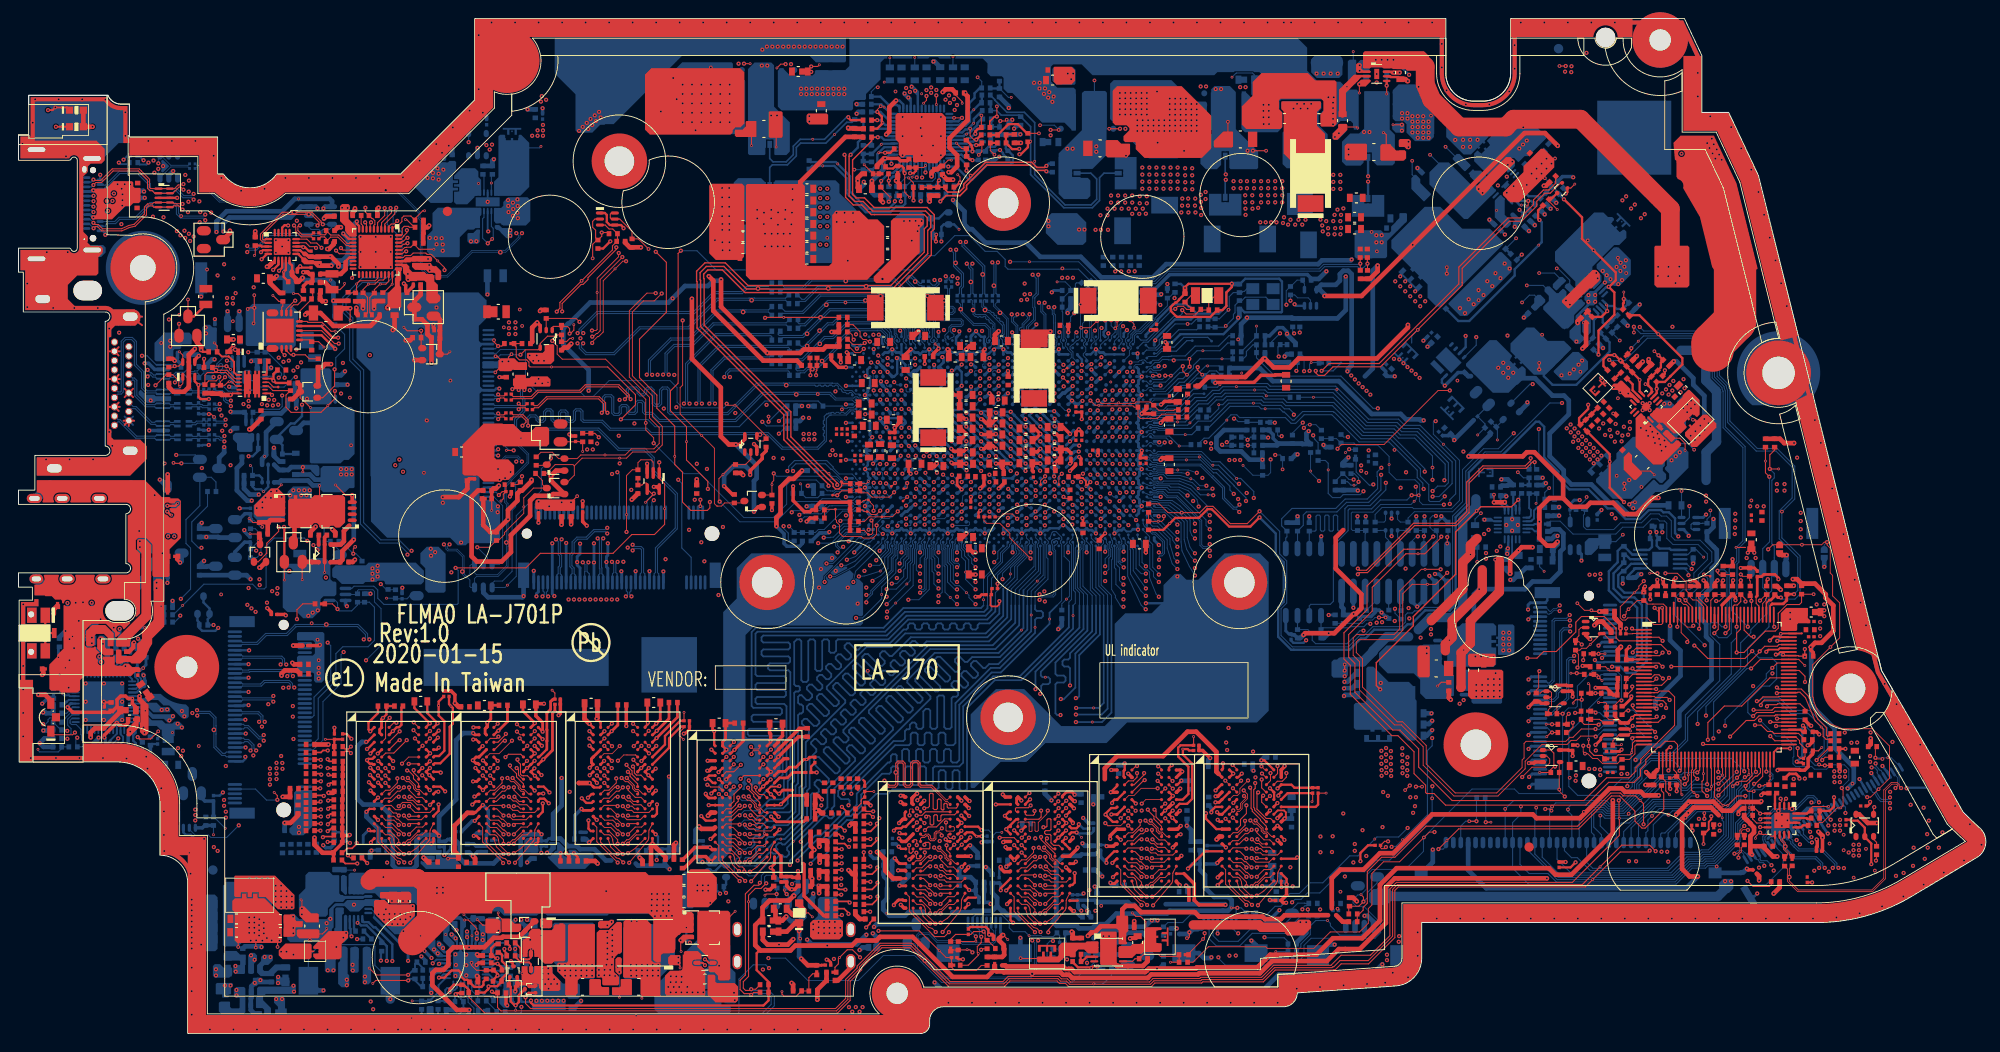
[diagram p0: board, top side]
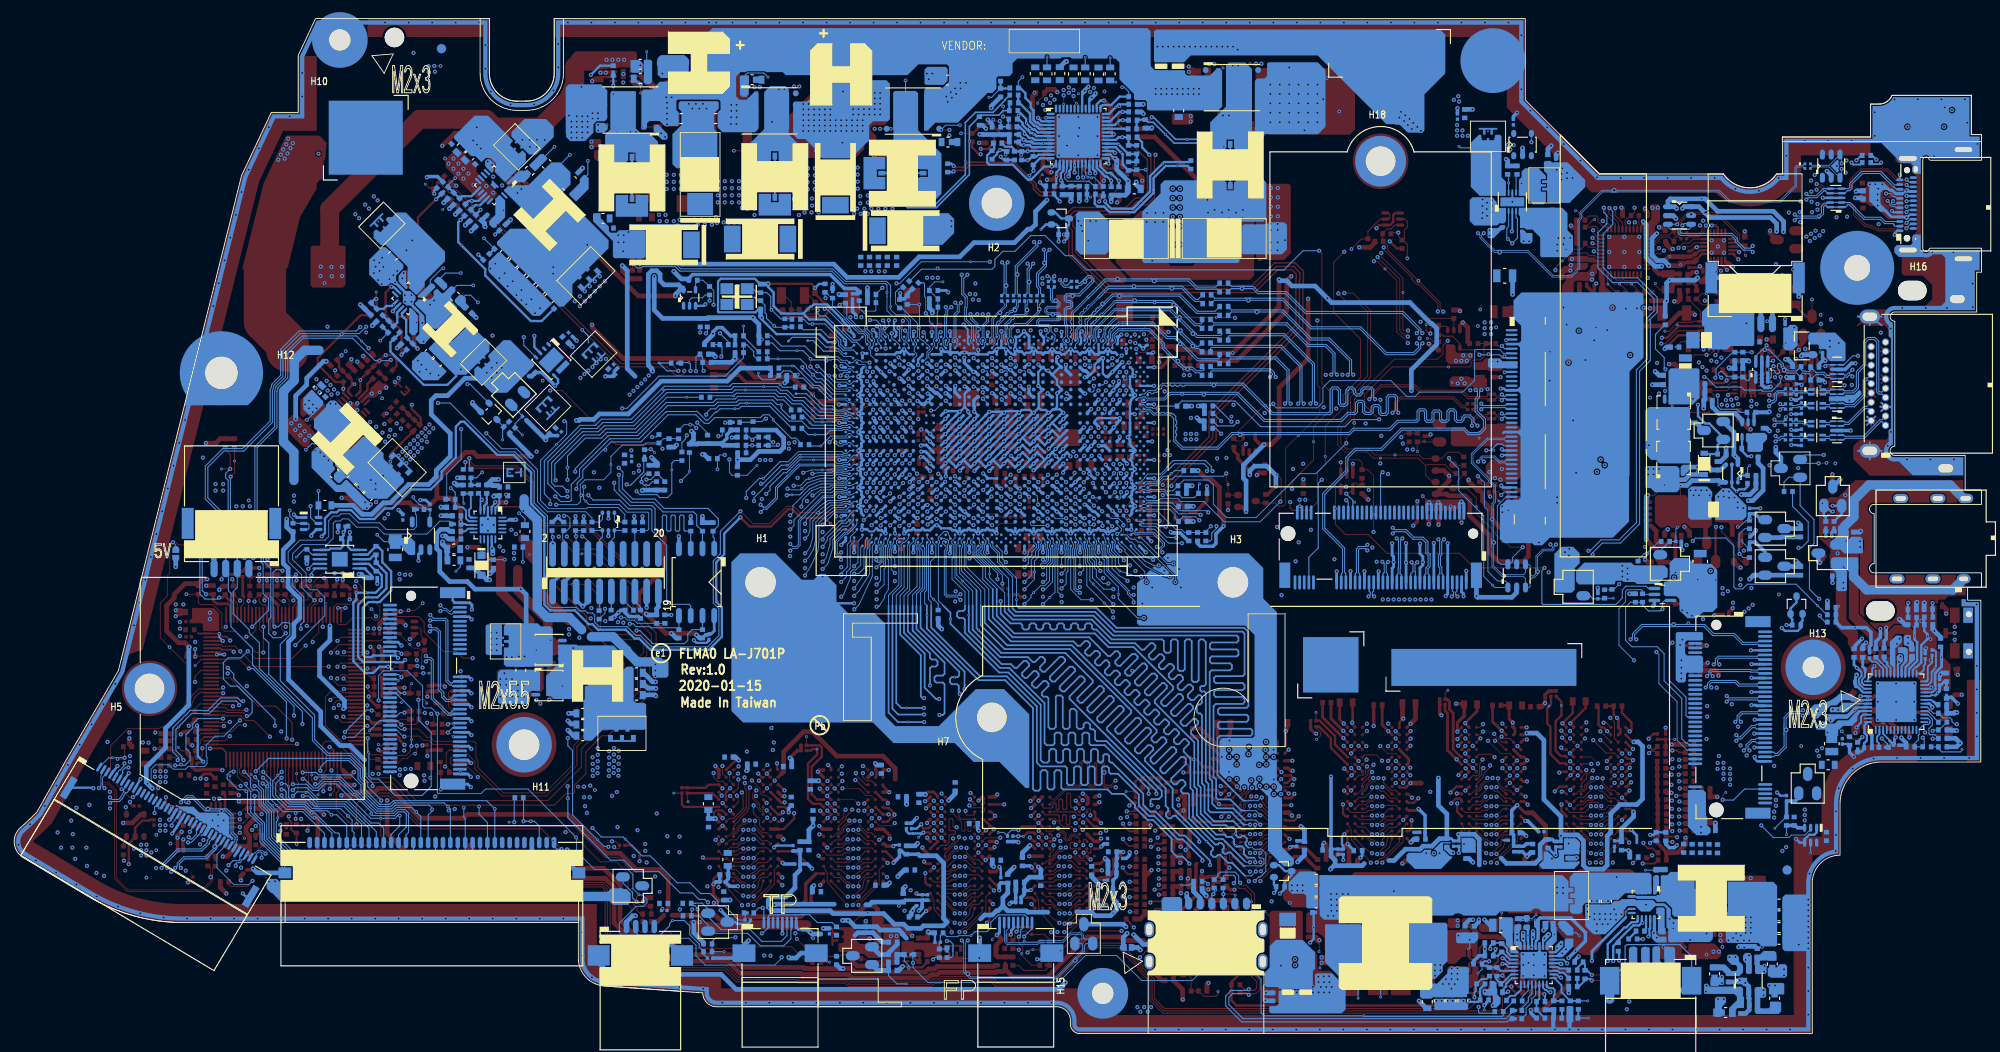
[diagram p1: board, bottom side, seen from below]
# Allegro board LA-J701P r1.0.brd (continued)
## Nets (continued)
GND: C1.2 C3.2 C4.2 C7.2 C68.2 C69.2 C70.1 C71.2 C72.2 C73.2 C74.2 C75.2 C76.2 C77.2 C78.2 C79.2 C80.2 C84.2 C204.2 C229.2 C230.2 C231.2 C232.2 C233.2 C234.2 C235.2 C236.2 C237.2 C238.2 C239.2 C240.2 C241.2 C242.2 C243.2 C249.2 C255.2 C256.2 C257.2 C258.1 C259.2 C260.2 C261.2 C265.2 C266.2 C267.1 C268.2 C269.2 C316.2 C317.1 C318.1 CA1.2 CA2.2 CA3.2 CA4.2 CA5.2 CA12.2 CA13.2 CA15.1 CA21.2 CA22.2 CA28.2 CA30.2 CA31.2 CA32.2 CA33.2 CA50.2 CA51.2 CA52.2 CC17.1 CC18.1 CC19.1 CC20.1 CC22.2 CC23.1 CC24.1 CC26.2 CC27.2 CC28.2 CC29.1 CC30.2 CC31.2 CC32.2 CC33.2 CC35.2 CC36.2 CC37.2 CC38.2 CC39.2 CC40.2 CC43.2 CC44.2 CC45.2 CC46.2 CC47.2 CC48.2 CC49.2 CC50.2 CC51.2 CC52.2 CC53.2 CC54.2 CC55.2 CC56.2 CC57.2 CC58.2 CC59.2 CC60.2 CC61.2 CC62.2 CC63.2 CC64.2 CC65.2 CC66.2 CC67.2 CC68.2 CC69.2 CC70.2 CC71.2 CC72.2 CC73.2 CC74.2 CC75.2 CC76.2 CC77.2 CC78.2 CC79.2 CC80.2 CC81.2 CC82.2 CC105.2 CC114.2 CC115.2 CC116.2 CC117.2 CC118.2 CC119.2 CD1.2 CD2.2 CD4.1 CD5.1 CD6.1 CD7.1 CD8.2 CD9.2 CD10.2 CD11.2 CD12.2 CD13.2 CD14.2 CD15.2 CD16.2 CD17.2 CD18.2 CD19.2 CD20.2 CD21.2 CD22.2 CD23.2 CD24.2 CD25.2 CD26.2 CD27.2 CD28.2 CD29.2 CD30.2 CD31.2 CD32.2 CD42.2 CD43.2 CD44.2 CD45.2 CD46.2 CD47.2 CD48.2 CD49.2 CD50.2 CD51.2 CD52.2 CD53.2 CD55.1 CD56.1 CD57.1 CD58.1 CD59.2 CD60.2 CD61.2 CD62.2 CD63.2 CD64.2 CD65.2 CD66.2 CD67.2 CD68.2 CD69.2 CD70.2 CD71.2 CD72.2 CD73.2 CD74.2 CD75.2 CD76.2 CD77.2 CD78.2 CD79.2 CD80.2 CD81.2 CD82.2 CD83.2 CD84.2 CD85.2 CD95.2 CD96.2 CD97.2 CD98.2 CD99.2 CD100.2 CD101.2 CD102.2 CD103.2 CD104.2 CD105.2 CD106.2 CD107.2 CD108.2 CD109.2 CD110.2 CD111.2 CD112.2 CD113.2 CD114.2 CF1.1 CF2.2 CF3.2 CF4.2 CF5.2 CF6.2 CF7.2 CF8.2 CF9.2 CF10.2 CF11.2 CF12.2 CF13.2 CFP1.2 CFP2.2 CFP3.2 CFP4.2 CH5.2 CH6.2 CH11.2 CH12.2 CH13.2 CH14.2 CHDT1.2 CHDT2.2 CHDT3.2 CKBL1.2 CKBL2.1 CKBL3.2 CLRP1.2 CSD1.2 CSD2.2 CSD3.2 CSD4.2 CSD5.2 CSD6.2 CSD7.2 CSD8.2 CSD10.2 CSD12.2 CT34.2 CT37.2 CT38.2 CT46.2 CT47.2 CT48.2 CT50.2 CT51.2 CT52.2 CT53.2 CT54.1 CT55.2 CT56.1 CT57.2 CT58.2 CT59.2 CT68.2 CT69.2 CT70.2 CT72.2 CT73.2 CT74.2 CT75.1 CT76.2 CT77.2 CT78.2 CTP1.2 CTP2.2 CTP3.2 CTP4.2 CTP5.2 CTP7.2 CTS5.2 CUS1.2 CUS2.2 CUS3.2 CUS4.2 CWL1.2 CWL2.2 CWL9.2 CWL61.2 D6.2 D33.1 DA2.2 DA3.1 DA4.1 DFP1.1 DH1.3 DH2.3 DH3.3 DT1.2 DT6.1 DT7.3 DT7.8 DT8.3 DT8.8 DT15.2 DT16.2 DTP1.1 H1.1(TP-1) H2.1(TP-1) H3.1(TP-1) H5.1(TP-1) H7.1(TP-1) H10.1(TP-1) H11.1(TP-1) H12.1(TP-1) H13.1(TP-1) H15.1(TP-1) H16.1(TP-1) H18.1(TP-1) JBATT1.7 JBATT1.8 JBATT1.9 JBATT1.10 JBATT1.11 JBATT1.12 JDCIN1.1 JDCIN1.2 JDCIN1.5 JDCIN1.6 JEDP1.4 JEDP1.14 JEDP1.23 JEDP1.27 JEDP1.28 JEDP1.38 JEDP1.39 JEDP1.40 JEDP1.41 JEDP1.42 JEDP1.43 JEDP1.44 JEDP1.45 JFAN2.4 JFAN2.5 JFAN2.6 JFP1.4 JFP1.9 JFP1.10 JHDMI1.2 JHDMI1.5 JHDMI1.8 JHDMI1.11 JHDMI1.17 JHDMI1.20 JHDMI1.21 JHDMI1.22 JHDMI1.23 JHDT1.3 JHDT1.5 JHDT1.7 JHDT1.17 JIO1.4 JIO1.7 JIO1.10 JIO1.28 JIO1.41 JIO1.42 JKB2.35 JKB2.36 JKBL1.1 JKBL1.5 JKBL1.6 JP1.2 JP2.2 JSPK1.5 JSPK1.6 JSSD1.1 JSSD1.3 JSSD1.9 JSSD1.15 JSSD1.21 JSSD1.27 JSSD1.33 JSSD1.39 JSSD1.45 JSSD1.51 JSSD1.57 JSSD1.63 JSSD1.65 JSSD1.67 JSSD1.68 JSSD1.69 JSSD2.1 JSSD2.3 JSSD2.9 JSSD2.15 JSSD2.21 JSSD2.27 JSSD2.33 JSSD2.39 JSSD2.45 JSSD2.51 JSSD2.57 JSSD2.63 JSSD2.65 JSSD2.67 JSSD2.68 JSSD2.69 JTP1.5 JTP1.9 JTP1.10 JUSBC2.1 JUSBC2.2 JUSBC2.3 JUSBC2.4 JUSBC2.5 JUSBC2.6 JUSBC2.A1 JUSBC2.A12 JUSBC2.B1 JUSBC2.B12 JWLAN1.1 JWLAN1.7 JWLAN1.18 JWLAN1.25 JWLAN1.31 JWLAN1.37 JWLAN1.43 JWLAN1.49 JWLAN1.55 JWLAN1.61 JWLAN1.67 JWLAN1.68 JWLAN1.69 L2.1 PC10.2 PC11.2 PC251.1 PC253.2 PC255.2 PC256.2 PC257.2 PC302.2 PC303.2 PC304.2 PC305.2 PC306.2 PC307.2 PC308.2 PC309.2 PC310.2 PC311.2 PC312.2 PC502.2 PC503.2 PC504.2 PC505.2 PC506.2 PC507.2 PC508.2 PC509.2 PC510.2 PC511.2 PC512.2 PC513.2 PC514.2 PC515.2 PC516.2 PC517.2 PC518.2 PC520.2 PC521.2 PC522.2 PC601.2 PC603.2 PC604.2 PC605.2 PC606.2 PC607.2 PC608.2 PC609.2 PC610.2 PC611.2 PC612.2 PC614.2 PC615.2 PC622.2 PC623.2 PC715.2 PC716.2 PC718.2 PC724.2 PC726.2 PC802.1 PC803.2 PC804.2 PC809.2 PC810.2 PC811.2 PC812.2 PC813.1 PC814.2 PC815.2 PC816.2 PC817.2 PC818.2 PC819.2 PC820.2 PC821.2 PC822.2 PC826.2 PC827.2 PC828.2 PC831.2 PC832.2 PC834.2 PC838.2 PC839.2 PC840.2 PC843.2 PC844.2 PC845.1 PC847.2 PC848.2 PC849.2 PC851.2 PC852.2 PC853.2 PC854.2 PC855.2 PC1807.2 PC1808.2 PC9001.2 PC9002.2 PC9003.2 PC9004.2 PC9005.2 PC9006.2 PC9007.2 PC9008.2 PC9009.2 PC9010.2 PC9011.2 PC9012.2 PC9013.2 PC9014.2 PC9015.2 PC9016.2 PC9017.2 PC9018.2 PC9019.2 PC9020.2 PC9021.2 PC9029.2 PC9030.2 PC9031.2 PC9032.2 PC9033.2 PC9034.2 PC9035.2 PC9036.2 PC9037.2 PC9038.2 PC9039.2 PC9040.2 PC9041.2 PC9042.2 PC9043.2 PC9044.2 PC9045.2 PC9046.2 PC9047.2 PC9048.2 PC9049.2 PC9050.2 PC9051.2 PC9052.2 PC9053.2 PC9056.2 PC9057.2 PC9058.2 PC9059.2 PC9060.2 PC9061.2 PC9062.2 PC9063.2 PC9064.2 PC9065.2 PC9066.2 PC9067.2 PC9068.2 PC9069.2 PC9070.2 PC9071.2 PC9081.2 PC9082.2 PC9094.2 PC9095.2 PC9096.2 PC9097.2 PC9098.2 PC9099.2 PC9100.2 PC9102.2 PC9103.2 PC9104.2 PC9105.2 PC9106.2 PC9107.2 PC9108.2 PC9109.2 PC9110.2 PC9111.2 PC9112.2 PC9115.2 PC9116.2 PC9117.2 PC9118.2 PC9119.2 PCB1.2 PCB2.2 PCB3.2 PCB4.2 PCB5.2 PCB6.2 PCB8.2 PCB9.2 PCB10.2 PCB12.2 PCB13.2 PCB14.2 PCB15.2 PCB16.2 PCB17.2 PCB18.2 PCB20.2 PCB21.2 PCB22.2 PCB24.2 PCB25.2 PCB26.2 PCB27.2 PCB28.2 PCB29.2 PCB30.2 PCB31.2 PCB32.2 PCB33.2 PCB34.2 PCB35.2 PCD1.2 PCD2.2 PCD3.2 PCD4.2 PCD6.2 PCM1.2 PCM2.2 PCM3.2 PCM4.2 PCM5.2 PCM6.2 PCM7.2 PCM8.2 PCM9.2 PCM10.1 PCM11.2 PCM12.2 PCM13.2 PCM15.2 PCM16.2 PCM17.2 PCM18.2 PCM19.2 PDM1.2 PQ801.3 PQ801.4 PQ801.5 PQ802.3 PQ802.4 PQ802.5 PQ804.3 PQ804.4 PQ804.5 PQ805.3 PQ805.4 PQ805.5 PQB1.3 PQB1.4 PQB1.5 PQB2.3 PQB2.4 PQB2.5 PQB3.3 PQB4.3 PQD3.1 PQD3.4 PQM2.1 PQM2.2 PQM2.3 PQS2.3 PR9.2 PR254.2 PR506.2 PR511.2 PR512.2 PR605.2 PR607.2 PR609.2 PR621.1 PR720.2 PR801.1 PR827.2 PR829.2 PR834.1 PR836.1 PR858.1 PR1809.2 PR1811.2 PR1816.1 PR1817.1 PRB7.2 PRB17.2 PRB20.2 PRB22.2 PRB24.2 PRB28.2 PRB33.2 PRD3.2 PRD4.2 PRD5.2 PRD7.2 PRD8.2 PRD9.2 PRM9.2 PRM14.1 PRS4.2 PRS5.2 PRS6.2 PU251.11 PU301.6 PU301.14 PU301.17 PU501.7 PU501.8 PU501.18 PU501.21 PU601.7 PU601.8 PU601.18 PU601.21 PU801.53 PU802.6 PU802.9 PU1802.6 PU1802.14 PU1802.17 PUB1.27 PUB1.33 PUM1.1 PUM1.3 PUM1.14 PUM1.21 Q146.3 Q202.1 Q202.4 QA4.1 QA4.4 QC2.1 QC2.4 QH1.4 QT1.3 QT2.3 QT4.3 R7.1 R8.2 R59.2 R68.1 R69.1 R70.1 R4006.1 RA26.1 RA28.1 RA30.2 RA31.1 RA32.1 RC6.2 RC8.2 RC9.2 RC10.2 RC16.2 RC18.2 RC30.1 RC50.1 RC53.1 RC54.1 RC65.2 RC66.2 RC70.1 RC71.1 RC72.2 RC83.1 RC115.1 RC119.2 RC120.2 RC123.2 RC561.2 RC569.1 RC601.1 RC615.2 RD31.1 RD33.2 RD34.2 RD35.1 RD36.1 RD37.1 RD38.2 RD39.2 RD40.1 RD41.1 RD47.1 RD48.1 RD49.1 RD50.1 RD51.1 RD52.2 RD53.2 RD54.2 RD55.2 RD70.1 RFP5.2 RH16.2 RHDT7.1 RHDT8.1 RHDT9.1 RKBL5.1 RSD3.2 RSD7.2 RT23.2 RT24.2 RT25.2 RT28.2 RT29.2 RT30.2 RT38.2 RT41.2 RT58.1 RT59.1 RT60.2 RT63.2 RT66.1 RT86.2 RT89.2 RT91.2 RT92.2 RTS8.2 RUS6.2 RUS7.2 RUS8.2 RWL12.1 RWL17.2 SW1.1 SW1.2 SW1.5 U2.3 U5.2 U7.14 U7.17 U9.2 U10.11 U10.15 U19.5 U20.2 UA1.49 UC1.A3 UC1.A5 UC1.A7 UC1.A10 UC1.A12 UC1.A14 UC1.A16 UC1.A19 UC1.A21 UC1.A23 UC1.A26 UC1.A30 UC1.AA5 UC1.AA13 UC1.AA15 UC1.AA17 UC1.AA19 UC1.AA23 UC1.AA26 UC1.AA28 UC1.AA32 UC1.AB2 UC1.AB4 UC1.AB14 UC1.AB16 UC1.AB18 UC1.AB20 UC1.AC5 UC1.AC8 UC1.AC11 UC1.AC13 UC1.AC15 UC1.AC17 UC1.AC19 UC1.AC22 UC1.AC25 UC1.AD1 UC1.AD5 UC1.AD14 UC1.AD16 UC1.AD18 UC1.AD20 UC1.AE5 UC1.AE11 UC1.AE13 UC1.AE15 UC1.AE17 UC1.AE19 UC1.AF1 UC1.AF3 UC1.AF5 UC1.AF14 UC1.AF16 UC1.AF18 UC1.AF20 UC1.AG5 UC1.AG8 UC1.AG11 UC1.AG13 UC1.AG15 UC1.AG17 UC1.AG19 UC1.AH14 UC1.AH16 UC1.AH18 UC1.AH20 UC1.AJ1 UC1.AJ3 UC1.AJ5 UC1.AJ13 UC1.AJ15 UC1.AJ17 UC1.AJ19 UC1.AK5 UC1.AK8 UC1.AK11 UC1.AK14 UC1.AK16 UC1.AK18 UC1.AK20 UC1.AL1 UC1.AL5 UC1.AL7 UC1.AL10 UC1.AL16 UC1.AM5 UC1.AM8 UC1.AM11 UC1.AM15 UC1.AM20 UC1.AN1 UC1.AN5 UC1.AN7 UC1.AN10 UC1.AN22 UC1.AN23 UC1.AN26 UC1.AP5 UC1.AP8 UC1.AP13 UC1.AP15 UC1.AP18 UC1.AP20 UC1.AP25 UC1.AR1 UC1.AR5 UC1.AR7 UC1.AR12 UC1.AR14 UC1.AR16 UC1.AR19 UC1.AR21 UC1.AR26 UC1.AR28 UC1.AT23 UC1.AU5 UC1.AU8 UC1.AU11 UC1.AU13 UC1.AU15 UC1.AU18 UC1.AU20 UC1.AU22 UC1.AU25 UC1.AU28 UC1.AV1 UC1.AV5 UC1.AV7 UC1.AV10 UC1.AV12 UC1.AV14 UC1.AV16 UC1.AV19 UC1.AV21 UC1.AV23 UC1.AV26 UC1.AV28 UC1.AV32 UC1.AW5 UC1.AW28 UC1.AY6 UC1.AY7 UC1.AY8 UC1.AY10 UC1.AY11 UC1.AY12 UC1.AY13 UC1.AY14 UC1.AY15 UC1.AY16 UC1.AY18 UC1.AY19 UC1.AY20 UC1.AY21 UC1.AY22 UC1.AY23 UC1.AY25 UC1.AY26 UC1.AY27 UC1.BB1 UC1.BB32 UC1.BD3 UC1.BD7 UC1.BD10 UC1.BD12 UC1.BD14 UC1.BD16 UC1.BD19 UC1.BD21 UC1.BD23 UC1.BD26 UC1.BD30 UC1.C3 UC1.C10 UC1.C32 UC1.E7 UC1.E8 UC1.E10 UC1.E11 UC1.E12 UC1.E13 UC1.E14 UC1.E15 UC1.E16 UC1.E18 UC1.E19 UC1.E20 UC1.E21 UC1.E22 UC1.E23 UC1.E25 UC1.E26 UC1.E27 UC1.F5 UC1.F19 UC1.F21 UC1.F23 UC1.F28 UC1.G1 UC1.G3 UC1.G5 UC1.G16 UC1.G26 UC1.G28 UC1.G32 UC1.H5 UC1.H13 UC1.H18 UC1.H20 UC1.H22 UC1.H25 UC1.H28 UC1.J19 UC1.K1 UC1.K3 UC1.K5 UC1.K16 UC1.K21 UC1.K26 UC1.K28 UC1.K32 UC1.L5 UC1.L13 UC1.L15 UC1.L18 UC1.L20 UC1.L25 UC1.L28 UC1.M1 UC1.M3 UC1.M5 UC1.M21 UC1.M23 UC1.M26 UC1.M28 UC1.M32 UC1.N5 UC1.N8 UC1.N11 UC1.N13 UC1.N15 UC1.N17 UC1.N22 UC1.N25 UC1.N28 UC1.P1 UC1.P5 UC1.P14 UC1.P16 UC1.P18 UC1.P20 UC1.P23 UC1.P26 UC1.P28 UC1.P32 UC1.R5 UC1.R11 UC1.R13 UC1.R15 UC1.R17 UC1.R19 UC1.R22 UC1.R25 UC1.R28 UC1.T1 UC1.T3 UC1.T5 UC1.T14 UC1.T16 UC1.T18 UC1.T20 UC1.T23 UC1.T26 UC1.T28 UC1.T32 UC1.U13 UC1.U15 UC1.U17 UC1.U19 UC1.V2 UC1.V4 UC1.V5 UC1.V8 UC1.V11 UC1.V14 UC1.V16 UC1.V18 UC1.V20 UC1.V22 UC1.V25 UC1.V28 UC1.W5 UC1.W13 UC1.W15 UC1.W17 UC1.W19 UC1.W23 UC1.W26 UC1.W28 UC1.W32 UC1.Y1 UC1.Y3 UC1.Y5 UC1.Y11 UC1.Y14 UC1.Y16 UC1.Y18 UC1.Y20 UC1.Y22 UC1.Y25 UC1.Y28 UC2.4 UC6.3 UC7.3 UC8.3 UC22.3 UC23.3 UD1.A2 UD1.A8 UD1.B2 UD1.C9 UD1.D2 UD1.D8 UD1.E1 UD1.E3 UD1.E8 UD1.F1 UD1.G8 UD1.H1 UD1.H9 UD1.K1 UD1.K9 UD1.N1 UD1.N9 UD1.T1 UD2.A2 UD2.A8 UD2.B2 UD2.C9 UD2.D2 UD2.D8 UD2.E1 UD2.E3 UD2.E8 UD2.F1 UD2.G8 UD2.H1 UD2.H9 UD2.K1 UD2.K9 UD2.N1 UD2.N9 UD2.T1 UD3.A2 UD3.A8 UD3.B2 UD3.C9 UD3.D2 UD3.D8 UD3.E1 UD3.E3 UD3.E8 UD3.F1 UD3.G8 UD3.H1 UD3.H9 UD3.K1 UD3.K9 UD3.N1 UD3.N9 UD3.T1 UD4.A2 UD4.A8 UD4.B2 UD4.C9 UD4.D2 UD4.D8 UD4.E1 UD4.E3 UD4.E8 UD4.F1 UD4.G8 UD4.H1 UD4.H9 UD4.K1 UD4.K9 UD4.N1 UD4.N9 UD4.T1 UD5.A2 UD5.A8 UD5.B2 UD5.C9 UD5.D2 UD5.D8 UD5.E1 UD5.E3 UD5.E8 UD5.F1 UD5.G8 UD5.H1 UD5.H9 UD5.K1 UD5.K9 UD5.N1 UD5.N9 UD5.T1 UD6.A2 UD6.A8 UD6.B2 UD6.C9 UD6.D2 UD6.D8 UD6.E1 UD6.E3 UD6.E8 UD6.F1 UD6.G8 UD6.H1 UD6.H9 UD6.K1 UD6.K9 UD6.N1 UD6.N9 UD6.T1 UD7.A2 UD7.A8 UD7.B2 UD7.C9 UD7.D2 UD7.D8 UD7.E1 UD7.E3 UD7.E8 UD7.F1 UD7.G8 UD7.H1 UD7.H9 UD7.K1 UD7.K9 UD7.N1 UD7.N9 UD7.T1 UD8.A2 UD8.A8 UD8.B2 UD8.C9 UD8.D2 UD8.D8 UD8.E1 UD8.E3 UD8.E8 UD8.F1 UD8.G8 UD8.H1 UD8.H9 UD8.K1 UD8.K9 UD8.N1 UD8.N9 UD8.T1 UEC1.11 UEC1.24 UEC1.35 UEC1.94 UEC1.113 UH1.2 USD1.3 USD2.3 UT1.41 UT2.8 UT2.13 UT2.18 UT2.21 UT4.1 UT4.5 UT4.14 UT6.4 UT6.6 UT6.8 UWL1.2 UWL22.3
GNDA: CA6.2 CA7.1 CA8.1 CA9.1 CA10.1 CA14.1 CA16.2 CA17.2 CA18.1 CA19.1 CA20.2 CA24.2 CA35.1 JP3.5 RA17.1 RA18.1 RA24.2 RA26.2 RA28.2 RA31.2 RA32.2 UA1.22 UA1.37
PVCC_CPU: PC815.1 PR811.1 PU801.50
VBUS_DSCHG: QT1.2 RT59.2 UT1.8 UT4.11 UT6.7
VCC_5V: PC508.1 PU501.16 PU501.17
VCC_CPU: PC814.1 PR812.1 PR835.2 PR837.2 PR859.1 PR1818.1 PR1819.1 PU801.28
VDD_DDR: PCM5.1 PRM5.1 PRM6.2 PUM1.11
VDDA: PCB16.1 PRB6.1 PRB23.1 PRB25.1 PRB27.1 PUB1.7
VDDIO_AUDIO: CC68.1 CC69.1 RC604.2 RC605.1 UC1.AP9
VDDIO_MEM_S3_SENSE_H: PRM13.2 T15.1(TP-1) UC1.J21
VDDIO_MEM_S3_SENSE_L: PRM14.2 RC595.2 T2412.1(TP-1)
VIN_CHG: PCB1.1 PCB2.1 PDB1.2 PQB1.2 PRB1.4
VIN_MUX: PCB3.1 PCB4.1 PCB5.1 PCB6.1 PDD1.1 PQD5.4 PQD12.1 PQD12.2 PQD12.3 PQS4.4 PQS12.1 PQS12.2 PQS12.3 PRB1.1
VSS_SENSE_A: RC594.1 RC595.1 UC1.J22
VSS_SENSE_B: RC597.1 UC1.AJ12
32K_X1: CC30.1 RC86.2 UC1.AY1 YC2.1
32K_X2: CC31.1 RC86.1 UC1.AY4 YC2.2
48M_X1: RC76.2 UC1.BB3
48M_X1_R: CC28.1 RC75.1 RC76.1 YC1.1
48M_X2: RC74.2 UC1.BA5
48M_X2_R: CC27.1 RC74.1 RC75.2 YC1.3
+APU_CORE: CF12.1 PC802.2 PC9001.1 PC9002.1 PC9003.1 PC9004.1 PC9005.1 PC9006.1 PC9007.1 PC9008.1 PC9009.1 PC9010.1 PC9021.1 PC9029.1 PC9030.1 PC9031.1 PC9032.1 PC9033.1 PC9034.1 PC9035.1 PC9036.1 PC9037.1 PC9038.1 PC9046.1 PC9047.1 PC9048.1 PC9049.1 PC9050.1 PC9051.1 PC9052.1 PC9056.1 PC9057.1 PC9058.1 PC9059.1 PC9060.1 PC9061.1 PC9062.1 PC9063.1 PC9081.1 PC9094.1 PC9095.1 PC9096.1 PC9097.1 PC9098.1 PC9105.1 PC9106.1 PC9107.1 PC9108.1 PC9109.1 PC9110.1 PC9111.1 PC9112.1 PC9115.1 PC9117.1 PC9118.1 PL804.4 PL805.4 PL806.4 PR802.2 UC1.AA7 UC1.AA10 UC1.AA14 UC1.AA16 UC1.AA18 UC1.AB13 UC1.AB15 UC1.AB17 UC1.AB19 UC1.AC14 UC1.AC16 UC1.AC18 UC1.AD7 UC1.AD10 UC1.AD13 UC1.AD15 UC1.AD17 UC1.AD19 UC1.AE8 UC1.AE14 UC1.AE16 UC1.AE18 UC1.AF7 UC1.AF10 UC1.AF13 UC1.AF15 UC1.AF17 UC1.AF19 UC1.AG14 UC1.AG16 UC1.AG18 UC1.AH13 UC1.AH15 UC1.AH17 UC1.AH19 UC1.AJ7 UC1.AJ10 UC1.AJ14 UC1.AJ16 UC1.AJ18 UC1.AK13 UC1.AK15 UC1.AK17 UC1.AK19 UC1.G7 UC1.G10 UC1.G12 UC1.G14 UC1.H8 UC1.H11 UC1.H15 UC1.K6 UC1.K12 UC1.K14 UC1.L8 UC1.M7 UC1.M10 UC1.N14 UC1.P7 UC1.P10 UC1.P13 UC1.P15 UC1.R8 UC1.R14 UC1.R16 UC1.T7 UC1.T10 UC1.T13 UC1.T15 UC1.T17 UC1.U14 UC1.U16 UC1.V13 UC1.V15 UC1.V17 UC1.W7 UC1.W10 UC1.W14 UC1.W16 UC1.Y8 UC1.Y13 UC1.Y15 UC1.Y17
+APU_CORE_SOC: CF11.1 PC838.1 PC9011.1 PC9012.1 PC9013.1 PC9014.1 PC9015.1 PC9016.1 PC9017.1 PC9018.1 PC9019.1 PC9020.1 PC9039.1 PC9040.1 PC9041.1 PC9042.1 PC9043.1 PC9044.1 PC9045.1 PC9053.1 PC9064.1 PC9065.1 PC9066.1 PC9067.1 PC9068.1 PC9069.1 PC9070.1 PC9071.1 PC9082.1 PC9099.1 PC9100.1 PC9116.1 PL803.4 PR833.1 UC1.N16 UC1.N18 UC1.N20 UC1.P17 UC1.P19 UC1.R18 UC1.R20 UC1.T19 UC1.U18 UC1.U20 UC1.V19 UC1.W18 UC1.W20 UC1.Y19
+CHGRTC: PD2.2 PR8.1 PR9.1
+EC_VCCA: C67.1 L1.2 PR13.1 UEC1.67
+FLT1: RT39.1 UT2.9
+IOVDD_CODEC: CA21.1 CA28.1 RA34.2 UA1.18
+LCDVDD: R2.1 U5.1
+LCDVDD_CONN: C3.1 JEDP1.8 JEDP1.9 R2.2
+LDO_3V3_5457V: CT47.1 CT48.1 CT58.1 RT22.1 RT26.2 RT39.2 RT72.2 RT73.2 RT74.2 RT85.1 UT1.33 UT2.10
+LEDVDD: C7.1 JEDP1.1 JEDP1.2 R9.2
+RTC_APU: CC105.1 CLRP1.1 RC106.2 RC107.1 UC1.AJ11
+RTCBATT: CC82.1 PD2.1 PR10.1 RC626.2
+RTCBATT_APU: CC81.1 RC107.2 RC626.1
+RTCBATT_R: JBATT1.6 PR10.2
+USBC0_VBUS: CT54.2 CT55.1 CT56.2 CT57.1 CT69.1 CT75.2 DT6.2 DT6.3 DT15.1 JUSBC2.A4 JUSBC2.A9 JUSBC2.B4 JUSBC2.B9 PFS1.1 R4021.2 RT40.1 RT69.1 UT4.8 UT6.13
AC_IN_TYPE: PRB33.1 PRB34.2 PUB1.15 UEC1.87
AC_OFF: PQD3.5 PRD8.1 UEC1.21
AC_PRESENT: UC1.BA8 UEC1.18
ACN: PCB7.2 PCB9.1 PRB3.2 PUB1.2
ACP: PCB7.1 PCB8.1 PRB2.2 PUB1.3
ADDR_CFG: RT22.2 RT23.1 UT1.26
ADP_I: PCB25.1 PRB20.1 PUB1.8 UEC1.65
ADPIN: JDCIN1.3 JDCIN1.4 PCD1.1 PFD1.1
APU_ALERT#: RC31.2 UC1.C22
APU_BT_OFF#: JWLAN1.46 UC1.AM2
APU_CORE_SEN_H: PC801.2 PC807.1 PR802.1 PR805.1 PU801.11 T14.1(TP-1) UC1.K22
APU_CORESOC_SEN_H: PC830.2 PC833.1 PR832.2 PR833.2 PU801.32 T13.1(TP-1) UC1.J23
APU_DBREQ#: CHDT2.1 JHDT1.16 RHDT5.1 UC1.AT2
APU_DP1_CTRL_CLK: CH12.1 QH2.4 RH24.2 UC1.J20
APU_DP1_CTRL_DAT: CH11.1 QH2.1 RH23.2 UC1.K20
APU_DP1_HPD: QH1.1 RH13.2 UC1.L21
APU_DP1_N0: CH10.1 UC1.H23
APU_DP1_N1: CH8.1 UC1.G22
APU_DP1_N2: CH4.1 UC1.H21
APU_DP1_N3: CH2.1 UC1.G20
APU_DP1_P0: CH9.1 UC1.G23
APU_DP1_P1: CH7.1 UC1.F22
APU_DP1_P2: CH3.1 UC1.G21
APU_DP1_P3: CH1.1 UC1.F20
APU_FCH_PWRGD_R: RC55.2 RC64.2 UC1.AW2 UC7.4
APU_FP_RST_R: RFP10.1 UC1.AW11
APU_PCIE0_RST#: RC34.2 UC1.AP6
APU_PCIE1_RST#: RC35.2 UC1.AT13
APU_PCIE_RST#: JIO1.25 RC73.2 RSD8.2 RSD9.2 RWL18.2 UC8.4 USD1.2 USD2.2 UWL22.2
APU_PCIE_RST#_R: CC20.2 RC34.1 RC35.1 RC72.1 RC73.1 UC8.1 UC8.2
APU_PCIE_WAKE#: RC48.2 UC1.AW12
APU_PWRGD: CC18.2 PU801.19 RC25.2 RC30.2 RHDT11.2 U20.3 UC1.AW4
APU_PWRGD_BUF: JHDT1.10 RHDT11.1 U20.4
APU_RST#: CC19.2 RC24.2 RC111.1 RC603.2 RHDT10.2 U20.1 UC1.AW3 UC22.4
APU_RST#_BUF: JHDT1.12 RHDT10.1 U20.6
APU_RST#_EC: RC111.2 UC22.2 UEC1.127
APU_RST#_R: RC603.1 UT1.34
APU_SPI_CLK: RC84.2 RC97.1 UC1.BC10
APU_SPI_CLK_R: RC59.1 RC65.1 RC84.1 UC2.6
APU_SPI_CS1#: RC95.1 UC1.BD11 UC2.1
APU_SPI_HOLD#: RC96.1 UC1.BC8 UC2.7
APU_SPI_MISO: RC93.1 UC1.BA10 UC2.2
APU_SPI_MOSI: RC92.1 UC1.BB8 UC2.5
APU_SPI_WP#: RC94.1 UC1.BA9 UC2.3
APU_SVC: PC854.1 PU801.20 UC1.D25
APU_SVD: PC855.1 PU801.21 UC1.C25
APU_SVT: PR815.2 PU801.22
APU_SVT_R: PC853.1 PR815.1 UC1.A25
APU_TCK: JHDT1.2 RHDT2.1 UC1.AR2
APU_TDI: CHDT1.1 JHDT1.6 RHDT4.1 UC1.AP3
APU_TDO: JHDT1.8 UC1.AU1
APU_TEST4: T1.1(TP-1) UC1.BB6
APU_TEST5: T2.1(TP-1) UC1.BD5
APU_TEST14: RC11.1 T4.1(TP-1) UC1.G25
APU_TEST15: RC12.1 T5.1(TP-1) UC1.K25
APU_TEST16: RC13.1 T6.1(TP-1) UC1.F25
APU_TEST17: RC14.1 T7.1(TP-1) UC1.F26
APU_TEST31: RC15.1 RC16.1 T8.1(TP-1) UC1.H26
APU_TEST41: T9.1(TP-1) UC1.AK9
APU_TEST470: T10.1(TP-1) UC1.AK21
APU_TEST471: T11.1(TP-1) UC1.AG21
APU_TMS: JHDT1.4 RHDT3.1 UC1.AU3
APU_TRST#: CHDT3.1 RHDT1.1 RHDT6.1 UC1.AR4
APU_TRST#_R: JHDT1.9 RHDT6.2
APU_VDDP_S5_SEN_H: PQ601.3 T12.1(TP-1) UC1.AK7
APU_VDDP_S5_SEN_L: PR621.2 RC597.2 T2413.1(TP-1)
APU_VSS_SEN_L: PC801.1 PC833.2 PR801.2 PU801.14 RC594.2 T16.1(TP-1)
APU_WL_OFF#: JWLAN1.48 UC1.AL4
AUX_RESET#: RC601.2 UC1.AP7 USD1.1 USD2.1
BATGONE: PRB22.1 PRB23.2 PUB1.18
BATT+: PC11.1 PCB35.1 PL3.2 PL4.2 PRB9.4
BATT_CHG_LED#: RS3.1 UEC1.90
BATT_CHG_LED#_R2: LED2.1 RS3.2
BATT_LOW_LED#: RS4.1 UEC1.93
BATT_LOW_LED#_R2: LED3.1 RS4.2
BEEP#: RA27.1 UEC1.23
BGATE: PQB13.4 PUB1.21
BKOFF#: R5.1 U2.1 UEC1.105
BST1_CHG: PRB4.2 PUB1.30
BST1_CHG_R: PCB11.2 PRB4.1
BST1_CPU: PR839.1 PU801.46
BST1_CPU_R: PC841.1 PR839.2
BST1_NB: PR804.1 PU801.42
BST1_NB1_R: PC805.1 PR804.2
BST2_CHG: PRB11.2 PUB1.25
BST2_CHG_R: PCB19.2 PRB11.1
BST2_CPU: PR820.1 PU801.2
BST2_CPU_R: PC824.1 PR820.2
BST3_CPU: PR860.1 PU802.4
BST3_CPU_R: PC846.1 PR860.2
BST_1.8V: PR713.1 PU1802.1
BST_1.8V_R: PC717.1 PR713.2
BST_3V: PR301.1 PU301.1
BST_3V_R: PC301.1 PR301.2
BST_5V: PR501.1 PU501.1
BST_5V_R: PC501.1 PR501.2
BST_DDR: PRM11.2 PUM1.18
BST_DDR_R: PCM14.1 PRM11.1
BST_VDDP: PR603.1 PU601.1
CAM_EN#: R201.1 R4007.2 UEC1.71
CAM_EN#_R: C204.1 Q201.2 R201.2
CAPS_LED#: R265.2 UEC1.91
CAPS_LED#_R: C229.1 JKB2.2 R265.1
CHR_USB20_N1: RUS10.1 U7.11
CHR_USB20_N1_R: JIO1.2 RUS10.2
CHR_USB20_P1: RUS9.1 U7.10
CHR_USB20_P1_R: JIO1.3 RUS9.2
CLK_PCIE_SD: JIO1.31 UC1.AF2
CLK_PCIE_SD#: JIO1.32 UC1.AF4
CLK_PCIE_SSD1: JSSD1.55 UC1.AH2
CLK_PCIE_SSD1#: JSSD1.53 UC1.AH4
CLK_PCIE_SSD2: JSSD2.55 UC1.AJ2
CLK_PCIE_SSD2#: JSSD2.53 UC1.AJ4
CLK_PCIE_WLAN: JWLAN1.39 UC1.AF8
CLK_PCIE_WLAN#: JWLAN1.41 UC1.AF9
CLKREQ_SD#: JIO1.33 RC91.1 UC1.AT14
CLKREQ_SSD1#: JSSD1.52 RC89.1 UC1.AN11
CLKREQ_SSD2#: JSSD2.52 RC574.1 UC1.AN13
CLKREQ_WLAN#: RC90.1 RWL2.1 UC1.AN15
CLKREQ_WLAN#_R: JWLAN1.45 RWL2.2
CLKRUN#: UC1.BD13 UEC1.38
CMPIN_25710: PCB12.1 PRB5.2 PRB7.1 PUB1.14
COMP_CPU: PC808.2 PR806.2 PU801.13
COMPA_CPU: PC829.1 PR831.1 PU801.30
CS_DDR: PRM5.2 PUM1.13
DDR_A_ACT#: RD23.2 UC1.AD22 UD1.L3 UD2.L3 UD3.L3 UD4.L3
DDR_A_ALERT#: RD1.2 UC1.AE24 UD1.P9 UD2.P9 UD3.P9 UD4.P9
DDR_A_BA0: RD24.2 UC1.AL22 UD1.N2 UD2.N2 UD3.N2 UD4.N2
DDR_A_BA1: RD25.2 UC1.AK27 UD1.N8 UD2.N8 UD3.N8 UD4.N8
DDR_A_BG0: RD26.2 UC1.AE27 UD1.M2 UD2.M2 UD3.M2 UD4.M2
DDR_A_BG1: RD30.2 UC1.AE26
DDR_A_BG1_R: RD27.2 RD30.1 RD31.2 UD1.M9 UD2.M9 UD3.M9 UD4.M9
DDR_A_CAS#: RD18.2 UC1.AL27 UD1.M8 UD2.M8 UD3.M8 UD4.M8
DDR_A_CKE0: RD22.2 UC1.AD24 UD1.K2 UD2.K2 UD3.K2 UD4.K2
DDR_A_CLK0: RD28.2 UC1.AJ25 UD1.K7 UD2.K7 UD3.K7 UD4.K7
DDR_A_CLK0#: RD29.2 UC1.AJ24 UD1.K8 UD2.K8 UD3.K8 UD4.K8
DDR_A_CS0#: RD21.2 UC1.AL25 UD1.L7 UD2.L7 UD3.L7 UD4.L7
DDR_A_DM0: UC1.L27 UD1.E7
DDR_A_DM1: UC1.N23 UD1.E2
DDR_A_DM2: UC1.R27 UD2.E7
DDR_A_DM3: UC1.Y24 UD2.E2
DDR_A_DM4: UC1.AP27 UD3.E7
DDR_A_DM5: UC1.AW23 UD3.E2
DDR_A_DM6: UC1.AT21 UD4.E7
DDR_A_DM7: UC1.AV18 UD4.E2
DDR_A_DQ0: UC1.K27 UD1.J3
DDR_A_DQ1: UC1.H27 UD1.G2
DDR_A_DQ2: UC1.M27 UD1.J7
DDR_A_DQ3: UC1.N27 UD1.H8
DDR_A_DQ4: UC1.L26 UD1.H3
DDR_A_DQ5: UC1.G27 UD1.H2
DDR_A_DQ6: UC1.N26 UD1.H7
DDR_A_DQ7: UC1.N24 UD1.F7
DDR_A_DQ8: UC1.N21 UD1.C2
DDR_A_DQ9: UC1.L24 UD1.C3
DDR_A_DQ10: UC1.T21 UD1.D7
DDR_A_DQ11: UC1.R23 UD1.B8
DDR_A_DQ12: UC1.M22 UD1.A3
DDR_A_DQ13: UC1.T22 UD1.D3
DDR_A_DQ14: UC1.R21 UD1.C7
DDR_A_DQ15: UC1.L23 UD1.C8
DDR_A_DQ16: UC1.P24 UD2.G2
DDR_A_DQ17: UC1.P27 UD2.J3
DDR_A_DQ18: UC1.T25 UD2.J7
DDR_A_DQ19: UC1.T27 UD2.F7
DDR_A_DQ20: UC1.P25 UD2.H2
DDR_A_DQ21: UC1.R26 UD2.H3
DDR_A_DQ22: UC1.V27 UD2.H7
DDR_A_DQ23: UC1.V23 UD2.H8
DDR_A_DQ24: UC1.W22 UD2.C2
DDR_A_DQ25: UC1.V21 UD2.A3
DDR_A_DQ26: UC1.AA24 UD2.C7
DDR_A_DQ27: UC1.AC23 UD2.D7
DDR_A_DQ28: UC1.Y23 UD2.D3
DDR_A_DQ29: UC1.AC24 UD2.C8
DDR_A_DQ30: UC1.W21 UD2.C3
DDR_A_DQ31: UC1.AA22 UD2.B8
DDR_A_DQ32: UC1.AP26 UD3.G2
DDR_A_DQ33: UC1.AN27 UD3.H3
DDR_A_DQ34: UC1.AR27 UD3.J7
DDR_A_DQ35: UC1.AU26 UD3.H8
DDR_A_DQ36: UC1.AN24 UD3.J3
DDR_A_DQ37: UC1.AR25 UD3.H7
DDR_A_DQ38: UC1.AN25 UD3.H2
DDR_A_DQ39: UC1.AU27 UD3.F7
DDR_A_DQ40: UC1.AV27 UD3.C2
DDR_A_DQ41: UC1.AW26 UD3.D3
DDR_A_DQ42: UC1.AV20 UD3.B8
DDR_A_DQ43: UC1.AW20 UD3.C8
DDR_A_DQ44: UC1.AV25 UD3.A3
DDR_A_DQ45: UC1.AW25 UD3.C3
DDR_A_DQ46: UC1.AW21 UD3.D7
DDR_A_DQ47: UC1.AU21 UD3.C7
DDR_A_DQ48: UC1.AR22 UD4.G2
DDR_A_DQ49: UC1.AT22 UD4.H3
DDR_A_DQ50: UC1.AN18 UD4.H8
DDR_A_DQ51: UC1.AN19 UD4.F7
DDR_A_DQ52: UC1.AP21 UD4.J3
DDR_A_DQ53: UC1.AN20 UD4.H2
DDR_A_DQ54: UC1.AP19 UD4.J7
DDR_A_DQ55: UC1.AU23 UD4.H7
DDR_A_DQ56: UC1.AU19 UD4.A3
DDR_A_DQ57: UC1.AW19 UD4.C2
DDR_A_DQ58: UC1.AW16 UD4.C8
DDR_A_DQ59: UC1.AU16 UD4.D7
DDR_A_DQ60: UC1.AW18 UD4.C3
DDR_A_DQ61: UC1.AT19 UD4.D3
DDR_A_DQ62: UC1.AT16 UD4.B8
DDR_A_DQ63: UC1.AP16 UD4.C7
DDR_A_DQS0: UC1.M25 UD1.G3
DDR_A_DQS0#: UC1.M24 UD1.F3
DDR_A_DQS1: UC1.P22 UD1.B7
DDR_A_DQS1#: UC1.P21 UD1.A7
DDR_A_DQS2: UC1.T24 UD2.G3
DDR_A_DQS2#: UC1.R24 UD2.F3
DDR_A_DQS3: UC1.AA21 UD2.B7
DDR_A_DQS3#: UC1.Y21 UD2.A7
DDR_A_DQS4: UC1.AP23 UD3.G3
DDR_A_DQS4#: UC1.AP24 UD3.F3
DDR_A_DQS5: UC1.AW22 UD3.B7
DDR_A_DQS5#: UC1.AV22 UD3.A7
DDR_A_DQS6: UC1.AT20 UD4.G3
DDR_A_DQS6#: UC1.AR20 UD4.F3
DDR_A_DQS7: UC1.AR18 UD4.B7
DDR_A_DQS7#: UC1.AT18 UD4.A7
DDR_A_EVENT#: RC2.2 UC1.AK23
DDR_A_MA0: RD3.2 UC1.AK26 UD1.P3 UD2.P3 UD3.P3 UD4.P3
DDR_A_MA1: RD4.2 UC1.AG24 UD1.P7 UD2.P7 UD3.P7 UD4.P7
DDR_A_MA2: RD5.2 UC1.AG23 UD1.R3 UD2.R3 UD3.R3 UD4.R3
DDR_A_MA3: RD6.2 UC1.AG26 UD1.N7 UD2.N7 UD3.N7 UD4.N7
DDR_A_MA4: RD7.2 UC1.AG27 UD1.N3 UD2.N3 UD3.N3 UD4.N3
DDR_A_MA5: RD8.2 UC1.AF21 UD1.P8 UD2.P8 UD3.P8 UD4.P8
DDR_A_MA6: RD9.2 UC1.AF22 UD1.P2 UD2.P2 UD3.P2 UD4.P2
DDR_A_MA7: RD10.2 UC1.AF25 UD1.R8 UD2.R8 UD3.R8 UD4.R8
DDR_A_MA8: RD11.2 UC1.AF24 UD1.R2 UD2.R2 UD3.R2 UD4.R2
DDR_A_MA9: RD12.2 UC1.AE21 UD1.R7 UD2.R7 UD3.R7 UD4.R7
DDR_A_MA10: RD13.2 UC1.AL21 UD1.M3 UD2.M3 UD3.M3 UD4.M3
DDR_A_MA11: RD14.2 UC1.AF27 UD1.T2 UD2.T2 UD3.T2 UD4.T2
DDR_A_MA12: RD15.2 UC1.AE23 UD1.M7 UD2.M7 UD3.M7 UD4.M7
DDR_A_MA13: RD16.2 UC1.AM23 UD1.T8 UD2.T8 UD3.T8 UD4.T8
DDR_A_ODT0: RD20.2 UC1.AM24 UD1.K3 UD2.K3 UD3.K3 UD4.K3
DDR_A_PAR: RD2.2 UC1.AK24 UD1.T3 UD2.T3 UD3.T3 UD4.T3
DDR_A_RAS#: RD19.2 UC1.AL24 UD1.L8 UD2.L8 UD3.L8 UD4.L8
DDR_A_RST#: UC1.AD27 UD1.P1 UD2.P1 UD3.P1 UD4.P1
DDR_A_WE#: RD17.2 UC1.AM21 UD1.L2 UD2.L2 UD3.L2 UD4.L2
DDR_B_ACT#: RD77.2 UC1.AD30 UD5.L3 UD6.L3 UD7.L3 UD8.L3
DDR_B_ALERT#: RD42.2 UC1.AE30 UD5.P9 UD6.P9 UD7.P9 UD8.P9
DDR_B_BA0: RD78.2 UC1.AN31 UD5.N2 UD6.N2 UD7.N2 UD8.N2
DDR_B_BA1: RD79.2 UC1.AM32 UD5.N8 UD6.N8 UD7.N8 UD8.N8
DDR_B_BG0: RD80.2 UC1.AD29 UD5.M2 UD6.M2 UD7.M2 UD8.M2
DDR_B_BG1: RD82.2 UC1.AD31
DDR_B_BG1_R: RD70.2 RD81.2 RD82.1 UD5.M9 UD6.M9 UD7.M9 UD8.M9
DDR_B_CAS#: RD72.2 UC1.AP29 UD5.M8 UD6.M8 UD7.M8 UD8.M8
DDR_B_CKE0: RD76.2 UC1.AC31 UD5.K2 UD6.K2 UD7.K2 UD8.K2
DDR_B_CLK0: RD44.2 UC1.AJ31 UD5.K7 UD6.K7 UD7.K7 UD8.K7
DDR_B_CLK0#: RD45.2 UC1.AK30 UD5.K8 UD6.K8 UD7.K8 UD8.K8
DDR_B_CS0#: RD75.2 UC1.AN30 UD5.L7 UD6.L7 UD7.L7 UD8.L7
DDR_B_DM0: UC1.C30 UD5.E7
DDR_B_DM1: UC1.H32 UD5.E2
DDR_B_DM2: UC1.M29 UD6.E7
DDR_B_DM3: UC1.T29 UD6.E2
DDR_B_DM4: UC1.AU30 UD7.E7
DDR_B_DM5: UC1.BD28 UD7.E2
DDR_B_DM6: UC1.BB23 UD8.E7
DDR_B_DM7: UC1.BD20 UD8.E2
DDR_B_DQ0: UC1.C27 UD5.G2
DDR_B_DQ1: UC1.E32 UD5.F7
DDR_B_DQ2: UC1.D27 UD5.H3
DDR_B_DQ3: UC1.F31 UD5.H7
DDR_B_DQ4: UC1.F30 UD5.H2
DDR_B_DQ5: UC1.F29 UD5.H8
DDR_B_DQ6: UC1.B27 UD5.J3
DDR_B_DQ7: UC1.A28 UD5.J7
DDR_B_DQ8: UC1.H31 UD5.A3
DDR_B_DQ9: UC1.K30 UD5.B8
DDR_B_DQ10: UC1.H30 UD5.C3
DDR_B_DQ11: UC1.K29 UD5.C7
DDR_B_DQ12: UC1.H29 UD5.C2
DDR_B_DQ13: UC1.K31 UD5.C8
DDR_B_DQ14: UC1.G30 UD5.D3
DDR_B_DQ15: UC1.L30 UD5.D7
DDR_B_DQ16: UC1.N32 UD6.G2
DDR_B_DQ17: UC1.N29 UD6.F7
DDR_B_DQ18: UC1.L29 UD6.H3
DDR_B_DQ19: UC1.P30 UD6.H7
DDR_B_DQ20: UC1.L32 UD6.H2
DDR_B_DQ21: UC1.N31 UD6.H8
DDR_B_DQ22: UC1.L31 UD6.J3
DDR_B_DQ23: UC1.M30 UD6.J7
DDR_B_DQ24: UC1.P29 UD6.A3
DDR_B_DQ25: UC1.U31 UD6.B8
DDR_B_DQ26: UC1.P31 UD6.C3
DDR_B_DQ27: UC1.R32 UD6.C7
DDR_B_DQ28: UC1.R30 UD6.C2
DDR_B_DQ29: UC1.V30 UD6.C8
DDR_B_DQ30: UC1.U29 UD6.D3
DDR_B_DQ31: UC1.V32 UD6.D7
DDR_B_DQ32: UC1.AT31 UD7.G2
DDR_B_DQ33: UC1.AV30 UD7.F7
DDR_B_DQ34: UC1.AR30 UD7.H3
DDR_B_DQ35: UC1.AT29 UD7.H7
DDR_B_DQ36: UC1.AW29 UD7.H2
DDR_B_DQ37: UC1.AW31 UD7.H8
DDR_B_DQ38: UC1.AW30 UD7.J3
DDR_B_DQ39: UC1.AU32 UD7.J7
DDR_B_DQ40: UC1.BA28 UD7.A3
DDR_B_DQ41: UC1.BC27 UD7.B8
DDR_B_DQ42: UC1.BB30 UD7.C3
DDR_B_DQ43: UC1.BB26 UD7.C7
DDR_B_DQ44: UC1.AY29 UD7.C2
DDR_B_DQ45: UC1.BC25 UD7.C8
DDR_B_DQ46: UC1.AY32 UD7.D3
DDR_B_DQ47: UC1.BA25 UD7.D7
DDR_B_DQ48: UC1.BA24 UD8.G2
DDR_B_DQ49: UC1.BD22 UD8.F7
DDR_B_DQ50: UC1.BD25 UD8.H3
DDR_B_DQ51: UC1.BC22 UD8.H7
DDR_B_DQ52: UC1.BB25 UD8.H2
DDR_B_DQ53: UC1.BA22 UD8.H8
DDR_B_DQ54: UC1.BC24 UD8.J3
DDR_B_DQ55: UC1.BB22 UD8.J7
DDR_B_DQ56: UC1.BB21 UD8.A3
DDR_B_DQ57: UC1.BC21 UD8.B8
DDR_B_DQ58: UC1.BA18 UD8.C3
DDR_B_DQ59: UC1.BB19 UD8.C7
DDR_B_DQ60: UC1.BA21 UD8.C2
DDR_B_DQ61: UC1.BC18 UD8.C8
DDR_B_DQ62: UC1.BB18 UD8.D3
DDR_B_DQ63: UC1.BB20 UD8.D7
DDR_B_DQS0: UC1.E29 UD5.G3
DDR_B_DQS0#: UC1.D28 UD5.F3
DDR_B_DQS1: UC1.J31 UD5.B7
DDR_B_DQS1#: UC1.J29 UD5.A7
DDR_B_DQS2: UC1.N30 UD6.G3
DDR_B_DQS2#: UC1.M31 UD6.F3
DDR_B_DQS3: UC1.T30 UD6.B7
DDR_B_DQS3#: UC1.T31 UD6.A7
DDR_B_DQS4: UC1.AU29 UD7.G3
DDR_B_DQS4#: UC1.AU31 UD7.F3
DDR_B_DQS5: UC1.BA27 UD7.B7
DDR_B_DQS5#: UC1.BB27 UD7.A7
DDR_B_DQS6: UC1.BC23 UD8.G3
DDR_B_DQS6#: UC1.BA23 UD8.F3
DDR_B_DQS7: UC1.BC20 UD8.B7
DDR_B_DQS7#: UC1.BA20 UD8.A7
DDR_B_EVENT#: RC1.2 UC1.AL30
DDR_B_MA0: RD56.2 UC1.AM29 UD5.P3 UD6.P3 UD7.P3 UD8.P3
DDR_B_MA1: RD57.2 UC1.AH31 UD5.P7 UD6.P7 UD7.P7 UD8.P7
DDR_B_MA2: RD58.2 UC1.AJ30 UD5.R3 UD6.R3 UD7.R3 UD8.R3
DDR_B_MA3: RD59.2 UC1.AH29 UD5.N7 UD6.N7 UD7.N7 UD8.N7
DDR_B_MA4: RD60.2 UC1.AG32 UD5.N3 UD6.N3 UD7.N3 UD8.N3
DDR_B_MA5: RD61.2 UC1.AG30 UD5.P8 UD6.P8 UD7.P8 UD8.P8
DDR_B_MA6: RD62.2 UC1.AG31 UD5.P2 UD6.P2 UD7.P2 UD8.P2
DDR_B_MA7: RD63.2 UC1.AF30 UD5.R8 UD6.R8 UD7.R8 UD8.R8
DDR_B_MA8: RD64.2 UC1.AG29 UD5.R2 UD6.R2 UD7.R2 UD8.R2
DDR_B_MA9: RD65.2 UC1.AF29 UD5.R7 UD6.R7 UD7.R7 UD8.R7
DDR_B_MA10: RD66.2 UC1.AM30 UD5.M3 UD6.M3 UD7.M3 UD8.M3
DDR_B_MA11: RD67.2 UC1.AF31 UD5.T2 UD6.T2 UD7.T2 UD8.T2
DDR_B_MA12: RD68.2 UC1.AE32 UD5.M7 UD6.M7 UD7.M7 UD8.M7
DDR_B_MA13: RD69.2 UC1.AP30 UD5.T8 UD6.T8 UD7.T8 UD8.T8
DDR_B_ODT0: RD74.2 UC1.AP32 UD5.K3 UD6.K3 UD7.K3 UD8.K3
DDR_B_PAR: RD43.2 UC1.AM31 UD5.T3 UD6.T3 UD7.T3 UD8.T3
DDR_B_RAS#: RD73.2 UC1.AN29 UD5.L8 UD6.L8 UD7.L8 UD8.L8
DDR_B_RST#: UC1.AC32 UD5.P1 UD6.P1 UD7.P1 UD8.P1
DDR_B_WE#: RD71.2 UC1.AP31 UD5.L2 UD6.L2 UD7.L2 UD8.L2
DEVSLP0: JSSD2.38 RC620.1 UC1.AK10
DEVSLP1: JSSD1.38 RC621.1 UC1.BC6
DISPOFF#: JEDP1.7 R5.2 R7.2 U2.4
DMIC_CLK0_APU: Q206.3 R4024.1 RC606.2 UC1.AG6
DMIC_DAT0_APU: Q207.3 R4025.1 RC607.2 UC1.AG7
DP_STEREOSYNC: RC17.1 RC18.1 UC1.B23
DVDT_1113: CT78.1 UT6.10
EC_CLEAR_CMOS#: RC106.1 UEC1.15
EC_FAN_PWM1: CF4.1 JFAN2.3 UEC1.26
EC_FAN_SPEED1: CF3.1 JFAN2.2 R64.1 UEC1.28
EC_FP_RST_R: RFP9.2 UEC1.74
EC_LOW_BATT#: RC611.2 UC1.AV6 UEC1.128
EC_MUTE#: R56.1 RA8.1 UEC1.89
EC_ON: PR509.1 UEC1.112
EC_PCIE_WAKE#: R57.1 RC617.1 RWL14.2 UEC1.108
EC_PD_INT: R4023.1 UEC1.76 UT1.5
EC_RSMRST#: C261.1 CC23.2 RC36.2 UC1.AR8 UEC1.100
EC_RST#: C70.2 R60.1 UEC1.37
EC_RX: RWL7.2 UEC1.31
EC_RX_R: JWLAN1.32 RWL7.1
EC_SCI#: UC1.AP4 UEC1.20
EC_SMB_CK1: C318.2 PR12.2 PRB12.1 R63.2 UEC1.77 UT1.3
EC_SMB_CK2: R273.2 UC1.B22 UEC1.79 UTS1.10
EC_SMB_DA1: C317.2 PR11.2 PRB10.1 R62.2 UEC1.78 UT1.4
EC_SMB_DA2: R274.2 UC1.D22 UEC1.80 UTS1.9
EC_SMCA: JBATT1.3 PR12.1
EC_SMDA: JBATT1.4 PR11.1
EC_THERMTRIP#: RC21.1 UEC1.36
EC_TX: RWL6.2 UEC1.30
EC_TX_R: JWLAN1.30 RWL6.1 RWL12.2
ECAGND: C67.2 L2.2 PH1.2 UEC1.69
EDP_AUXN: C8.1 UC1.B12
EDP_AUXN_C: C8.2 JEDP1.20
EDP_AUXP: C9.1 UC1.D12
EDP_AUXP_C: C9.2 JEDP1.19
EDP_HPD: R6.1 R8.1 RC10.1 UC1.C12
EDP_HPD_R: JEDP1.5 R6.2
EDP_TXN0: C11.1 UC1.B11
EDP_TXN0_C: C11.2 JEDP1.17
EDP_TXN1: C12.1 UC1.A11
EDP_TXN1_C: C12.2 JEDP1.15
EDP_TXP0: C10.1 UC1.D11
EDP_TXP0_C: C10.2 JEDP1.18
EDP_TXP1: C13.1 UC1.C11
EDP_TXP1_C: C13.2 JEDP1.16
EN_0.675VSP: PCM2.1 PRM4.2 PUM1.7
EN_1.8V: PC9102.1 PR1807.2 PR1811.1 PU1802.9
EN_5VALW: PR508.1 UEC1.64
EN_DDR: PCM13.1 PRM3.2 PUM1.8
ENBKL: QC1.1 R4006.2 RC5.1 U2.2 UEC1.97
ENBKL_R: QC1.3 RC6.1 UC1.A22
ENLDO_3V5V: PC520.1 PR504.2 PR506.1 PU301.8 PU501.11
ENVDD: RC8.1 U5.4 UC1.D23
ESPI_ALERT#: RC616.2 UC1.BC11
EXT_MIC_RING2: RA11.1 RA13.2 UA1.30
EXT_MIC_SLEEVE: RA10.1 RA14.2 UA1.31
FB_1.8V: PR716.2 PR1808.1 PR1809.1 PU1802.11
FB_CPU: PC807.2 PC808.1 PR805.2 PR806.1 PU801.12
FB_DDR: PRM2.1 PRM9.1 PUM1.6
FB_VDDP: PR606.1 PR609.1 PR611.2 PU601.14
FBA_CPU: PC829.2 PC830.1 PR831.2 PR832.1 PU801.31
FN_LED#: R266.1 UEC1.1
FN_LED#_R: JKB2.32 R266.2
FP_DELINK: CFP4.1 JFP1.5 RFP4.1 RFP8.2 RFP12.2
FP_GPIO_AL0: CFP3.1 RFP3.1 RFP6.1 UEC1.73
FP_GPIO_AL0_R: JFP1.6 RFP6.2
FP_GPIO_SCL: RFP11.1 RFP12.1 UEC1.83
FP_GPIO_SCL_R: JFP1.8 RFP11.2
FP_LED#: JIO1.16 UEC1.85
FP_RST: CFP2.1 JFP1.7 RFP5.1 RFP9.1 RFP10.2
GPIO_RESERVE: RC614.1 RC615.1 UC1.BB12
H_PROCHOT#: C232.1 CC17.2 R4002.2 RC28.2 RC602.1 UC1.B25
HDA_BIT_CLK: RC54.2 RC67.2 UC1.AN6
HDA_BIT_CLK_R: CA31.1 RA4.1 RC67.1 UA1.14
HDA_RST#: RC50.2 UC1.AM6
HDA_SDIN0: CA33.1 RA2.1 RC53.2 UC1.AL6
HDA_SDIN0_R: RA2.2 UA1.16
HDA_SDOUT: RC68.2 RC71.2 UC1.AK6
HDA_SDOUT_R: CA32.1 RC68.1 UA1.17
HDA_SPKR: RA29.1 UC1.AR11
HDA_SYNC: RC69.2 RC70.2 UC1.AN8
HDA_SYNC_R: CA30.1 RC69.1 UA1.15
HDMI_CLKN: CH2.2 LH1.1 RH9.1
HDMI_CLKP: CH1.2 LH1.4 RH8.1
HDMI_CTRL_CLK: CH14.1 DH1.1 DH1.9 JHDMI1.15 QH2.3 RH25.2
HDMI_CTRL_DAT: CH13.1 DH1.2 DH1.8 JHDMI1.16 QH2.6 RH26.2
HDMI_HPD: DH1.4 DH1.7 JHDMI1.19 QH1.6 RH16.1
HDMI_L_CLKN: DH3.2 DH3.8 JHDMI1.12 LH1.2
HDMI_L_CLKP: DH3.1 DH3.9 JHDMI1.10 LH1.3
HDMI_L_TX_N0: DH3.5 DH3.6 JHDMI1.9 LH2.2
HDMI_L_TX_N1: DH2.1 DH2.9 JHDMI1.6 LH3.2
HDMI_L_TX_N2: DH2.4 DH2.7 JHDMI1.3 LH4.2
HDMI_L_TX_P0: DH3.4 DH3.7 JHDMI1.7 LH2.3
HDMI_L_TX_P1: DH2.2 DH2.8 JHDMI1.4 LH3.3
HDMI_L_TX_P2: DH2.5 DH2.6 JHDMI1.1 LH4.3
HDMI_TX_N0: CH4.2 LH2.1 RH11.1
HDMI_TX_N1: CH8.2 LH3.1 RH7.1
HDMI_TX_N2: CH10.2 LH4.1 RH5.1
HDMI_TX_P0: CH3.2 LH2.4 RH10.1
HDMI_TX_P1: CH7.2 LH3.4 RH6.1
HDMI_TX_P2: CH9.2 LH4.4 RH4.1
HG1_CHG: PQB1.1 PUB1.31
HG2_CHG: PQB2.1 PUB1.24
HGNDA: CA17.1 DA3.3 JP3.2 RA13.1 RA24.1
HGNDB: CA16.1 CA35.2 DA3.2 JP3.1 RA14.1
HIZ_CHG: PQB3.1 PRB24.1 PRB25.2 PRB30.2 PUB1.6
HP_OUTL: RA15.1 RA17.2 UA1.27
HP_OUTR: RA16.1 RA18.2 UA1.26
HPOUT_L: CA18.2 RA15.2 RA22.1
HPOUT_L1: DA4.2 JP3.4 RA22.2
HPOUT_R: CA19.2 RA16.2 RA23.1
HPOUT_R1: DA4.3 JP3.3 RA23.2
I2C_0_SCL: CTP2.1 DTP1.3 JTP1.7 RC56.2 RC585.2 RC624.2
I2C_0_SCL_R: RC585.1 UC1.AP14
I2C_0_SDA: CTP3.1 DTP1.2 JTP1.6 RC57.2 RC586.2 RC625.2
I2C_0_SDA_R: RC586.1 UC1.AN14
IBIAS_CPU: PR827.1 PU801.29
IDEAL_1: PDD1.2 PQD4.2 PQS3.2 PRD9.1
ILMT_1.8V: PR719.2 PR720.1 PU1802.10
ILMT_VDDP: PR604.2 PR605.1 PU601.13
IMON_1113: CT77.1 RT91.1 UT6.9
IMON_CPU: PR816.2 PU801.15
IMONA_CPU: PR818.2 PU801.17
INVTPWM: JEDP1.6 RC4.1 UC6.4
INVTPWM_R: RC9.1 UC1.C23 UC6.2
ISEN1N_CPU: PR842.1 PU801.7
ISEN1N_CPU_R: PC842.2 PC844.1 PL805.3 PR842.2
ISEN1P_CPU: PC842.1 PR841.2 PU801.8
ISEN1P_CPU_R: PL805.2 PR841.1
ISEN2N_CPU: PR830.1 PU801.6
ISEN2N_CPU_R: PC825.2 PC832.1 PL804.3 PR830.2
ISEN2P_CPU: PC825.1 PR826.2 PU801.5
ISEN2P_CPU_R: PL804.2 PR826.1
ISEN3N_CPU: PR843.2 PR857.1
ISEN3N_CPU_IC: PR843.1 PR844.1 PU801.10
ISEN3N_CPU_R: PC850.2 PC851.1 PL806.3 PR857.2
ISEN3P_CPU: PC850.1 PR845.2 PR856.2
ISEN3P_CPU_IC: PR845.1 PR846.1 PU801.9
ISEN3P_CPU_R: PL806.2 PR856.1
ISENA1N_CPU: PR810.1 PU801.35
ISENA1N_CPU-1: PC806.2 PC812.1 PL803.3 PR810.2
ISENA1P_CPU: PC806.1 PR809.2 PU801.36
ISENA1P_CPU_R: PL803.2 PR809.1
KB_BL_PWM: RKBL1.2 RKBL2.1 UEC1.25
KB_RST#: C256.1 RC85.2 UC1.AT15 UEC1.2
KBL_ID: RKBL3.1 RKBL4.2 UC1.AW8
KBL_ID_R: JKBL1.2 RKBL4.1 RKBL5.2
KSI0: JKB2.15 UEC1.55
KSI1: JKB2.26 UEC1.56
KSI2: JKB2.19 UEC1.57
KSI3: JKB2.18 UEC1.58
KSI4: JKB2.22 UEC1.59
KSI5: JKB2.21 UEC1.60
KSI6: JKB2.24 UEC1.61
KSI7: JKB2.25 UEC1.62
KSO0: JKB2.20 UEC1.39
KSO1: JKB2.16 UEC1.40
KSO2: JKB2.14 UEC1.41
KSO3: JKB2.9 UEC1.42
KSO4: JKB2.13 UEC1.43
KSO5: JKB2.17 UEC1.44
KSO6: JKB2.10 UEC1.45
KSO7: JKB2.12 UEC1.46
KSO8: JKB2.11 UEC1.47
KSO9: JKB2.23 UEC1.48
KSO10: JKB2.4 UEC1.49
KSO11: JKB2.5 UEC1.50
KSO12: JKB2.8 UEC1.51
KSO13: JKB2.7 UEC1.52
KSO14: JKB2.6 UEC1.53
KSO15: JKB2.3 UEC1.54
LDO2: CA14.2 UA1.21
LDO3: CA15.2 UA1.19
LDO_1.8V: PC724.1 PU1802.13
LDO_VDDP: PC612.1 PR604.1 PU601.16 PU601.17
LG1_CHG: PQB1.6 PUB1.29
LG1_CPU: PQ804.6 PU801.49
LG1_NB: PQ801.6 PU801.45
LG2_CHG: PQB2.6 PUB1.26
LG2_CPU: PQ802.6 PU801.51
LG3_CPU: PQ805.6 PU802.7
LG_DDR: PQM2.4 PUM1.15
LID_SW#: C267.2 JIO1.1 R55.1 R4026.1 UEC1.115
LOC_PWR_MON: RT37.2 RT38.1 UT1.28
LPC_AD0: RC77.1 UEC1.10
LPC_AD0_R: RC77.2 UC1.BA16
LPC_AD1: RC78.1 UEC1.8
LPC_AD1_R: RC78.2 UC1.BA15
LPC_AD2: RC79.1 UEC1.7
LPC_AD2_R: RC79.2 UC1.BC13
LPC_AD3: RC80.1 UEC1.5
LPC_AD3_R: RC80.2 UC1.BB14
LPC_CLK0: RC81.2 UC1.BB15
LPC_CLK0_EC: R58.1 RC81.1 UEC1.12
LPC_FRAME#: UC1.BA13 UEC1.4
LPC_RST#: RC82.2 UC1.BC12
LPC_RST#_R: C259.1 CC29.2 RC82.1 RC83.2 UEC1.13
LPCPD#: T17.1(TP-1) UC1.BB13
LX1_CHG: PCB11.1 PLB1.1 PQB1.7 PRB14.1 PUB1.32
LX1_CPU: PC841.2 PL805.1 PQ804.7 PR840.1 PU801.48
LX1_NB: PC805.2 PL803.1 PQ801.7 PR808.1 PU801.44
LX2_CHG: PCB19.1 PLB1.2 PQB2.7 PRB15.1 PUB1.23
LX2_CPU: PC824.2 PL804.1 PQ802.7 PR824.1 PU801.52
LX3_CPU: PC846.2 PL806.1 PQ805.7 PR855.1 PU802.2
LX_1.8V: PC717.2 PL1802.1 PR1810.1 PU1802.5 PU1802.15 PU1802.16
LX_3V: PC301.2 PL301.1 PL301.2 PR302.1 PU301.5 PU301.15 PU301.16
LX_5V: PC501.2 PL501.1 PL501.2 PR502.1 PU501.6 PU501.19 PU501.20
LX_DDR: PCM14.2 PLM1.3 PLM1.4 PQM1.1 PQM1.2 PQM1.3 PQM2.5 PRM1.1 PUM1.16
LX_VDDP: PC602.2 PL602.1 PR602.1 PU601.6 PU601.19 PU601.20
M_BATA: JBATT1.1 JBATT1.2 PF2.1
M_VMB: PC10.1 PF2.2 PL3.1 PL4.1
MIC_LED#: R267.1 UEC1.34
MIC_LED#_R: JKB2.34 R267.2
MODEL_ID0: RC112.1 RC115.2 UC1.AV15
MODEL_ID1: RC568.1 RC569.2 UC1.AU14
NOVO#: D33.3 R65.2 SW1.3 SW1.4 UEC1.68
OBRAM_ID0: RC120.1 RC121.2 UC1.AP2
OBRAM_ID1: RC119.1 RC122.2 UC1.AN3
OBRAM_ID2: RC123.1 RC124.2 UC1.AN12
OBRAM_ID3: RC560.2 RC561.1 UC1.AP12
ON/OFF#: C265.1 JIO1.11 JP1.1 JP2.1 R66.2 UEC1.114
PBTN_OUT#: RC47.2 UC1.AT12 UEC1.122
PC_BEEP: CA25.2 UA1.34
PCIE_ARX_DTX_N0: JSSD1.5 UC1.F11
PCIE_ARX_DTX_N1: JSSD1.17 UC1.H10
PCIE_ARX_DTX_N2: JSSD1.29 UC1.F8
PCIE_ARX_DTX_N3: JSSD1.43 UC1.F7
PCIE_ARX_DTX_N5: JIO1.30 UC1.L6
PCIE_ARX_DTX_N7: JWLAN1.35 UC1.H7
PCIE_ARX_DTX_N8: JSSD2.43 UC1.L10
PCIE_ARX_DTX_N9: JSSD2.29 UC1.J11
PCIE_ARX_DTX_N10: JSSD2.17 UC1.H12
PCIE_ARX_DTX_N11: JSSD2.5 UC1.K13
PCIE_ARX_DTX_P0: JSSD1.7 UC1.G11
PCIE_ARX_DTX_P1: JSSD1.19 UC1.J10
PCIE_ARX_DTX_P2: JSSD1.31 UC1.G8
PCIE_ARX_DTX_P3: JSSD1.41 UC1.G6
PCIE_ARX_DTX_P5: JIO1.29 UC1.L7
PCIE_ARX_DTX_P7: JWLAN1.33 UC1.H6
PCIE_ARX_DTX_P8: JSSD2.41 UC1.L9
PCIE_ARX_DTX_P9: JSSD2.31 UC1.K11
PCIE_ARX_DTX_P10: JSSD2.19 UC1.J12
PCIE_ARX_DTX_P11: JSSD2.7 UC1.J13
PCIE_ATX_C_DRX_N0: CC2.2 JSSD1.11
PCIE_ATX_C_DRX_N1: CC4.2 JSSD1.23
PCIE_ATX_C_DRX_N2: CC6.2 JSSD1.35
PCIE_ATX_C_DRX_N3: CC8.2 JSSD1.47
PCIE_ATX_C_DRX_N5: CC12.2 JIO1.27
PCIE_ATX_C_DRX_N7: CC10.2 JWLAN1.29
PCIE_ATX_C_DRX_N8: CC110.2 JSSD2.47
PCIE_ATX_C_DRX_N9: CC107.2 JSSD2.35
PCIE_ATX_C_DRX_N10: CC112.2 JSSD2.23
PCIE_ATX_C_DRX_N11: CC111.2 JSSD2.11
PCIE_ATX_C_DRX_P0: CC1.2 JSSD1.13
PCIE_ATX_C_DRX_P1: CC3.2 JSSD1.25
PCIE_ATX_C_DRX_P2: CC5.2 JSSD1.37
PCIE_ATX_C_DRX_P3: CC7.2 JSSD1.49
PCIE_ATX_C_DRX_P5: CC11.2 JIO1.26
PCIE_ATX_C_DRX_P7: CC9.2 JWLAN1.27
PCIE_ATX_C_DRX_P8: CC109.2 JSSD2.49
PCIE_ATX_C_DRX_P9: CC106.2 JSSD2.37
PCIE_ATX_C_DRX_P10: CC113.2 JSSD2.25
PCIE_ATX_C_DRX_P11: CC108.2 JSSD2.13
PCIE_ATX_DRX_N0: CC2.1 UC1.L1
PCIE_ATX_DRX_N1: CC4.1 UC1.L2
PCIE_ATX_DRX_N2: CC6.1 UC1.M2
PCIE_ATX_DRX_N3: CC8.1 UC1.N1
PCIE_ATX_DRX_N5: CC12.1 UC1.R3
PCIE_ATX_DRX_N7: CC10.1 UC1.N4
PCIE_ATX_DRX_N8: CC110.1 UC1.K4
PCIE_ATX_DRX_N9: CC107.1 UC1.J2
PCIE_ATX_DRX_N10: CC112.1 UC1.H1
PCIE_ATX_DRX_N11: CC111.1 UC1.H2
PCIE_ATX_DRX_P0: CC1.1 UC1.L3
PCIE_ATX_DRX_P1: CC3.1 UC1.L4
PCIE_ATX_DRX_P2: CC5.1 UC1.M4
PCIE_ATX_DRX_P3: CC7.1 UC1.N3
PCIE_ATX_DRX_P5: CC11.1 UC1.R1
PCIE_ATX_DRX_P7: CC9.1 UC1.N2
PCIE_ATX_DRX_P8: CC109.1 UC1.K2
PCIE_ATX_DRX_P9: CC106.1 UC1.J4
PCIE_ATX_DRX_P10: CC113.1 UC1.H3
PCIE_ATX_DRX_P11: CC108.1 UC1.H4
PCIE_DET1: JSSD1.61 RC45.2 UC1.BA6
PCIE_DET2: JSSD2.61 RC593.2 UC1.BB7
PCIE_WAKE#_SOC: RC617.2 UC1.AE6
PCIE_WAKE#_WL: JWLAN1.47 RWL14.1
PD_GPIO10: RT72.1 UT1.1
PD_GPIO11: RT73.1 UT1.40
PD_GPIO15: RT74.1 UT1.36
PD_PWR_EN: CT73.1 QT4.2 UEC1.66
PDB: RA8.2 UA1.2
PLT_RST_SSD1#: JSSD1.50 RSD3.1 RSD8.1 RSD16.1 USD1.4
PLT_RST_SSD2#: JSSD2.50 RSD7.1 RSD9.1 RSD16.2 USD2.4
PLUG_IN: JP3.6 RA33.2
PLUG_IN_R: RA33.1 RT75.2 UA1.48
PM_SLP_S3#: RC598.1 RFP8.1 UC23.4 UEC1.6
PM_SLP_S3#_R: RC598.2 UC1.AT11 UC23.1
PM_SLP_S5#: PR251.1 UC1.AV11 UEC1.123
PTM_EN#: PQB4.2 PRB30.1 PRB31.2 UEC1.107
PWM3_CPU: PR847.1 PU802.5
PWM3_CPU_IC: PR847.2 PU801.3
PWR_LED#: JIO1.21 RS5.1 UEC1.92
PWR_LED#_R: D33.2 LED4.1 RS5.2
PWR_SW_DVDT: CT70.1 UT4.9
PWR_SW_FRS: RT58.2 RT89.1 UT1.7 UT4.10 UT6.3
PWR_SW_ILIM: RT67.1 UT4.3 UT6.11
PWR_SW_ILIM_R: QT2.1 RT66.2 RT67.2
REGN: PCB18.1 PRB6.2 PRB16.1 PRB34.1 PUB1.28
REMOTE1+: CTS1.1 CTS3.1 QTS1.1 QTS1.2 UTS1.2
REMOTE2+: CTS2.1 CTS4.1 QTS2.1 QTS2.2 UTS1.4
REMOTE3+: CTS6.1 CTS7.1 QTS3.1 QTS3.2 UTS1.5
REMOTE3-: CTS6.2 CTS7.2 QTS3.3 RTS8.1 UTS1.6
REMOTE-: CTS1.2 CTS2.2 CTS3.2 CTS4.2 QTS1.3 QTS2.3 UTS1.3
RTC_CLK: RC87.1 UC1.AW10
RTC_CLK_R: RC87.2 RWL8.2
S0A3_GPIO: RC610.2 UC1.AW13 UC23.2
S0I3_EC#: QA4.2 R4010.1 RA51.1 RA57.1 RTP16.1 RWL15.1 UEC1.119
S0I3_EC#_1V8VDD: CA52.1 QA3.2 RA57.2
S0I3_EC#_3VDD: CA50.1 QA1.2 RA51.2
S0I3_EC#_5VDDA: QA4.3 RA55.1 RA61.1
S0I3_EC#_5VDDA_R: CA51.1 QA2.2 RA55.2
S0I3_EC#_5VEN2: QA4.5 QA4.6 RA54.1
S0I3_TP_EN#: RTP5.2 RTP6.1 RTP16.2
S0I3_WLAN_EN#: CWL9.1 RWL15.2 UWL1.4
SCL_CHG: PRB12.2 PUB1.13
SDA_CHG: PRB10.2 PUB1.12
SELF HEALING: T24.1(TP-1) UEC1.117
SERIRQ: UC1.BC15 UEC1.3
SET1_CPU: PR835.1 PR1813.2 PU801.25
SET2_CPU: PR836.2 PR837.1 PU801.26
SMU_ZVDDP: RC22.1 UC1.P3
SNB_APU: PC826.1 PR824.2
SNB_APU2: PC843.1 PR840.2
SNB_APU3: PC849.1 PR855.2
SNB_APU_NB: PC811.1 PR808.2
SNB_VDDP: PC603.1 PR602.2
SNUB_1.8V: PC9103.1 PR1810.2
SNUB_CHG1: PCB20.1 PRB14.2
SNUB_CHG2: PCB21.1 PRB15.2
SOC_DMIC_CLK0: D6.1 Q206.1 R358.1 R4014.2 R4024.2
SOC_DMIC_CLK0_R: C249.1 JEDP1.36 R358.2
SOC_DMIC_DAT0: D6.6 JEDP1.37 Q207.1 R4015.2 R4025.2
SPK_L1-: RA5.1 UA1.43
SPK_L1-_CONN: CA3.1 DA2.1 JSPK1.1 RA5.2
SPK_L2+: RA6.1 UA1.42
SPK_L2+_CONN: CA2.1 DA2.3 JSPK1.2 RA6.2
SPK_R1-: RA1.1 UA1.44
SPK_R1-_CONN: CA5.1 DA2.6 JSPK1.3 RA1.2
SPK_R2+: RA3.1 UA1.45
SPK_R2+_CONN: CA4.1 DA2.4 JSPK1.4 RA3.2
SRN: PRB19.2 PUB1.19
SRP: PRB18.2 PUB1.20
SSD1_PWR_EN#: R4011.1 RS4030.2 RSD12.1 UEC1.120
SSD1_PWR_EN#_R: CSD10.1 Q208.2 RSD12.2
SSD2_PWR_EN#: R4012.1 RS4031.2 RSD13.1 UEC1.126
SSD2_PWR_EN#_R: CSD12.1 Q209.2 RSD13.2
SUSCLK_R: JWLAN1.42 RWL8.1
SUSP#: PRM4.1 R68.2 U10.3 U10.5 UEC1.116
SYS_PWRGD_EC: C260.1 RC64.1 UC7.2 UEC1.32
SYS_RESET#: CC24.2 RC60.1 RC66.1 UC1.AL2
SYSON: C266.1 PR256.1 PRM3.1 R69.2 UEC1.95
TCP_IMON: T2403.1(TP-1) UT4.4
THERMTRIP#: RC21.2 RC29.2 UC1.AN9
TON_DDR: PRM10.2 PUM1.9
TONSET_CPU: PR807.1 PU801.4
TP_DISABLE#: CTP7.1 RTP3.1 UEC1.70
TP_DISABLE#_R: JTP1.1 RTP3.2
TP_INT#: CTP5.1 JTP1.2 RTP2.2 UC1.AU4 UEC1.88
TS_DISABLE#: JEDP1.26 UEC1.75
TYPEC_PWR_ILIM#: QT2.2 R4022.1 RT85.2 UEC1.106
TYPEC_VIN: PQS3.1 PQS11.5 PQS12.5
UART_0_ARXD_DTXD: RWL4.2 UC1.BA17
UART_0_ARXD_R_DTXD: JWLAN1.22 RWL4.1
UART_0_ATXD_DRXD: RWL5.2 UC1.BC16
UART_0_ATXD_R_DRXD: JWLAN1.24 RWL5.1
UG1_CPU: PR838.1 PU801.47
UG1_CPU_R: PQ804.1 PR838.2
UG1_NB: PR803.1 PU801.43
UG1_NB_R: PQ801.1 PR803.2
UG2_CPU: PR817.1 PU801.1
UG2_CPU_R: PQ802.1 PR817.2
UG3_CPU: PR853.1 PU802.3
UG3_CPU_R: PQ805.1 PR853.2
UG_DDR: PQM1.4 PUM1.17
USB3_ARX_DTX_N1: JIO1.8 UC1.AD9
USB3_ARX_DTX_N2: JIO1.38 UC1.AD11
USB3_ARX_DTX_P1: JIO1.9 UC1.AD8
USB3_ARX_DTX_P2: JIO1.37 UC1.AD12
USB3_ATX_DRX_N1: JIO1.5 UC1.AE3
USB3_ATX_DRX_N2: JIO1.35 UC1.AD4
USB3_ATX_DRX_P1: JIO1.6 UC1.AE1
USB3_ATX_DRX_P2: JIO1.34 UC1.AD2
USB20_N0: LT1.1 UC1.AC7
USB20_N0_R: DT1.4 JUSBC2.A7 JUSBC2.B7 LT1.2
USB20_N1: U7.2 UC1.AA9
USB20_N2: JEDP1.30 UC1.Y9
USB20_N3: D6.3 JEDP1.24 UC1.Y6
USB20_N5: RUS12.1 UC1.AA12
USB20_N5_R: JIO1.39 RUS12.2
USB20_N6: DFP1.2 JFP1.2 UC1.W9
USB20_N7: JWLAN1.5 UC1.W12
USB20_P0: LT1.4 UC1.AC6
USB20_P0_R: DT1.3 JUSBC2.A6 JUSBC2.B6 LT1.3
USB20_P1: U7.3 UC1.AA8
USB20_P2: JEDP1.29 UC1.Y10
USB20_P3: D6.4 JEDP1.25 UC1.Y7
USB20_P5: RUS11.1 UC1.AA11
USB20_P5_R: JIO1.40 RUS11.2
USB20_P6: DFP1.3 JFP1.3 UC1.W8
USB20_P7: JWLAN1.3 UC1.W11
USB_CHG_CTL1: U7.6 UEC1.14
USB_CHG_CTL2: RUS4.2 U7.7
USB_CHG_CTL3: U7.8 UEC1.16
USB_CHG_EN: RUS8.1 U7.5 UEC1.17
USB_CHG_ILIM_SEL: RUS2.2 U7.4
USB_CHG_STATUS#: RUS1.2 U7.9 UEC1.19
USB_EN#: R54.1 U9.4 UEC1.72
USB_OC0#: RC98.2 RUS3.2 UC1.AE9
USB_OC0#_R: RUS3.1 U7.13
USB_OC1#: RC99.2 RUS13.1 UC1.AE10
USBC0_ARX_C_DTX_N1: CT44.2 DT7.4 DT7.7 JUSBC2.B10
USBC0_ARX_C_DTX_N2: CT49.2 DT8.4 DT8.7 JUSBC2.A10
USBC0_ARX_C_DTX_P1: CT43.2 DT7.5 DT7.6 JUSBC2.B11
USBC0_ARX_C_DTX_P2: CT45.2 DT8.5 DT8.6 JUSBC2.A11
USBC0_ARX_DTX_N1: CT44.1 UC1.AA4
USBC0_ARX_DTX_N2: CT49.1 UC1.AC3
USBC0_ARX_DTX_P1: CT43.1 UC1.AA2
USBC0_ARX_DTX_P2: CT45.1 UC1.AC1
USBC0_ATX_C_DRX_N1: C251.2 DT8.2 DT8.9 JUSBC2.A3
USBC0_ATX_C_DRX_N2: C253.2 DT7.2 DT7.9 JUSBC2.B3
USBC0_ATX_C_DRX_P1: C250.2 DT8.1 DT8.10 JUSBC2.A2
USBC0_ATX_C_DRX_P2: C252.2 DT7.1 DT7.10 JUSBC2.B2
USBC0_ATX_DRX_N1: C251.1 UC1.AA3
USBC0_ATX_DRX_N2: C253.1 UC1.AC4
USBC0_ATX_DRX_P1: C250.1 UC1.AA1
USBC0_ATX_DRX_P2: C252.1 UC1.AC2
USBC0_AUXN: CT36.1 UC1.M19
USBC0_AUXP: CT35.1 UC1.L19
USBC0_C_AUXN: CT36.2 RT26.1 UT1.13
USBC0_C_AUXP: CT35.2 RT25.1 UT1.14
USBC0_CC1: CT37.1 UT1.10 UT2.12
USBC0_CC1_CONN: DT16.6 JUSBC2.A5 UT2.4 UT2.7
USBC0_CC2: CT38.1 UT1.12 UT2.11
USBC0_CC2_CONN: DT16.1 JUSBC2.B5 UT2.5 UT2.6
USBC0_CHG_EN: PQS2.2 RT63.1 UT1.6
USBC0_PD_HPD: QC2.2 RC628.1 RT29.1 UT1.2
USBC0_PD_HPD_3VEN: QC2.5 QC2.6 RC62.2
USBC0_PD_HPD_R: QC2.3 RC63.2 RC628.2 UC1.M20
USBC0_PWR_SW_EN: RT60.1 RT86.1 UT1.35 UT4.12 UT6.2
USBC0_SBU1: UT1.16 UT2.15
USBC0_SBU1_CONN: DT16.4 JUSBC2.A8 UT2.1
USBC0_SBU2: UT1.15 UT2.14
USBC0_SBU2_CONN: DT16.3 JUSBC2.B8 UT2.2
USBC_I2C_SCL: RC608.2 RC618.2 UC1.AL9 UT1.38
USBC_I2C_SDA: RC609.2 RC619.2 UC1.AL8 UT1.37
VBCAP: RT27.1 RT28.1 UT1.17
VCIN0_PH1: PH1.1 PR13.2 UEC1.109
VCIN1_AC_IN: C255.1 PRB16.2 PRB17.1 PUB1.4 R59.1 UEC1.110
VCIN1_BATT_TEMP: C257.1 PR15.2 UEC1.63
VCOUT0_MAIN_PWR_ON: PR510.1 UEC1.104
VCOUT1_PROCHOT#: PR871.1 PRB13.1 R4002.1 UEC1.103
VLIM_1113: RT92.1 UT6.12
VMON: RT40.2 RT41.1 UT1.29
VR_ALERT#: RC602.2 UT1.39
VR_ON: PC831.1 PR623.2 PR829.1 PU801.37 UEC1.121
VREF_CPU: PC827.1 PC828.1 PC852.1 PH801.2 PH802.2 PR823.1 PR825.1 PR858.2 PR859.2 PU801.16
VSYS: PRB32.1 PUB1.22
VTTREF_DDR: PCM17.1 PUM1.4
WL_AUX_RST#: R4020.1 UEC1.29 UWL22.1
WL_RST#: RWL9.1 RWL17.1 RWL18.1 UWL22.4
WL_RST#_R: JWLAN1.44 RWL9.2
N15548662: CD3.2 CD4.2 RD28.1 RD29.1
N16048190: RD36.2 UD2.F9
N16049074: RD35.2 UD1.F9
N16073528: RD41.2 UD4.F9
N16074384: RD40.2 UD3.F9
N17006388: RD33.1 UD1.E9
N17008855: RD34.1 UD2.E9
N17009545: RD38.1 UD3.E9
N17010231: RD39.1 UD4.E9
N19393161: JBATT1.5 PR14.1 PR15.1
N27078948: PQS3.3 PQS4.1
N27353874: PQD4.3 PQD5.1
N27353888: PCD5.2 PQD11.4 PRD1.2 PRD2.1
N27353896: PQD5.2 PQD5.5 PRD4.1
N27353908: PQD5.6 PRD3.1
N27353922: PQD5.3 PQD12.4 PRD5.1
N27354104: PQD3.6 PRD2.2
N27403760: PCD6.1 PQD3.2 PQD3.3 PRD6.2 PRD7.1
N27479461: PCM10.2 PDM1.1 PRM8.2 PUM1.12
N27480057: PCM11.1 PRM1.2
N27490318: PCB22.1 PCB23.1 PRB9.2 PRB18.1
N27490324: PCB23.2 PCB24.1 PRB9.3 PRB19.1
N27490344: PCB33.1 PQB3.2 PQB4.1 PRB29.2
N27490379: PCB29.1 PRB21.1 PUB1.17
N27490385: PCB28.1 PRB21.2
N27490452: PRB27.2 PRB28.1 PUB1.5
N27490578: PRB1.2 PRB2.1
N27490582: PRB1.3 PRB3.1
N27490635: PCB15.1 PRB8.2 PUB1.1
N27490661: PCB31.1 PRB26.1 PUB1.16
N27490673: PDB1.1 PRB8.1
N27490690: PCB30.1 PRB26.2
N27490706: PRB13.2 PUB1.11
N27490755: PCB32.1 PUB1.9
N27906658: JHDT1.11 RHDT7.2
N27906903: JHDT1.13 RHDT8.2
N27907005: JHDT1.15 RHDT9.2
N28818999: CC33.1 RC97.2
N29844725: PCS1.2 PQS11.4 PRS1.2 PRS2.1
N29844737: PQS4.2 PQS4.5 PRS5.1
N29844751: PQS4.6 PRS4.1
N29844777: PQS4.3 PQS12.4 PRS6.1
N29873767: PQS2.1 PRS2.2
N31043585: CA11.1 UA1.24
N31043589: CA11.2 UA1.23
N31043653: CA10.2 UA1.25
N31044849: CA8.2 UA1.39
N31046441: CA7.2 UA1.38
N31049061: CA9.2 UA1.32
N31049415: RA11.2 UA1.28
N31049464: RA10.2 UA1.29
N31053534: RA9.1 UA1.33
N31139311: CA1.1 RA4.2
N31622588: C268.1 R58.2
N34251283: CA25.1 RA27.2 RA29.2 RA30.1
N35328155: RUS6.1 U7.15
N35328157: RUS7.1 U7.16
N36734976: RTS7.2 UTS1.7
N39287841: RUS13.2 U9.3
N42640404: CT52.1 CT53.1 R4021.1 UT1.31
N42664977: RT30.1 UT1.30
N42673166: CT34.1 RT27.2
N42673554: RT24.1 UT1.9
N42773810: PC614.1 PR601.2 PR607.1 PU601.11
N42773848: PR606.2 PR610.2 PR622.1
N42773858: PQ601.2 PR623.1
N42773860: PQ601.1 PR622.2
N42774290: PC602.1 PR603.2
N42797203: PRM2.2 PRM12.1 PRM13.1
N42800393: PR871.2 PU801.27
N43014642: CT59.1 UT2.3
N43474151: CT72.1 QT3.2 QT4.1 RT70.2
N43483631: QT1.1 RT69.2
N44399175: CD54.2 CD55.2 RD44.1 RD45.1
N44399199: RD49.2 UD6.F9
N44399302: RD48.2 UD5.F9
N44399416: RD51.2 UD8.F9
N44399501: RD50.2 UD7.F9
N44399645: RD52.1 UD5.E9
N44399648: RD53.1 UD6.E9
N44399650: RD54.1 UD7.E9
N44399652: RD55.1 UD8.E9
N44553852: Q202.6 R75.2
N44762708: CT71.1 UT4.6
N44786728: T2414.1(TP-1) UC1.AK12
N44865206: CTP4.1 QTP1.2 RTP6.2
N45286880: PC719.2 PR716.1
N45361715: PC613.2 PR611.1
N45414865: CT76.1 UT6.5
N45426925: PR834.2 PR1813.1
N45427212: PC9119.1 PR807.2 PR1814.2
N45427762: PC813.2 PR1815.2 PU801.18
N45430627: PR1816.2 PR1819.2 PU801.24
N45430802: PR1817.2 PR1818.2 PU801.23
N45669999: PR819.1 PU801.40
N45670005: PH801.1 PR821.1
N45670038: PR828.1 PU801.39
N45670148: PH802.1 PR822.2
N45670259: PR816.1 PR821.2 PR825.2
N45670267: PR818.1 PR822.1 PR823.2
N45890946: RWL19.1 UWL1.1
N46092148: RC627.1 UC1.AN21
N46346846: QH1.3 RH4.2 RH5.2 RH6.2 RH7.2 RH8.2 RH9.2 RH10.2 RH11.2
N111027203: CKBL3.1 QKBL1.2 RKBL2.2
N115820979: C75.1 U10.12
N115820982: C76.1 U10.10

Pads without a net: D6 5; DT1 1 5 6; DT16 5; FD1 1; FD2 1; FD3 1; FD4 1; JEDP1 3 10 11 12 13 21 22; JHDMI1 13 14; JHDT1 14 18 20; JKB2 27 28 29 30 33; JSSD1 6 8 10 20 22 24 26 28 30 32 34 36 40 42 44 46 48 54 56 58 59 60; JSSD2 6 8 10 20 22 24 26 28 30 32 34 36 40 42 44 46 48 54 56 58 59 60; JTP1 3 4; JWLAN1 6 8 9 10 11 12 13 14 15 16 17 19 20 21 23 26 28 34 36 38 40 50 51 52 53 54 56 57 58 59 60 62 63 65; LED4 3; PU251 5; PU301 12; PU501 10; PU601 9 10 12; PU801 38; PU1802 8; PUB1 10; PUM1 10; U5 3; UA1 1 4 5 6 7 8 9 10 11 12 13 35 36 47; UC1 A8 A13 A15 A18 A20 AA6 AA20 AA25 AA27 AA29 AA30 AA31 AB29 AB31 AC9 AC10 AC12 AC26 AC27 AC29 AC30 AD3 AD6 AD25 AE7 AE12 AF6 AF11 AF12 AG1 AG2 AG3 AG4 AG9 AG10 AG12 AJ6 AJ8 AJ9 AJ21 AJ22 AJ27 AJ29 AK1 AK3 AK32 AL3 AL13 AL14 AL15 AL29 AL31 AM1 AM3 AM4 AM7 AM9 AM10 AM13 AM14 AM26 AM27 AN2 AN4 AN16 AP1 AP10 AR3 AR6 AR13 AR15 AR29 AR31 AT4 AT10 AU2 AU6 AU7 AU10 AU12 AV3 AV8 AV13 AW7 AW14 AW15 B6 B8 B9 B10 B13 B15 B16 B17 B18 B20 B21 B24 BA11 BA12 BB10 BB11 BB16 BC9 BC17 BD8 BD15 BD18 C1 C6 C7 C8 C13 C14 C15 C16 C18 C19 C20 C21 C26 D5 D6 D8 D9 D10 D13 D15 D16 D17 D18 D20 D21 D24 E1 E4 E6 F2 F3 F4 F10 F12 F13 F14 F15 F16 F18 G13 G15 G18 G19 H14 H16 H19 J14 J15 J16 J18 K7 K8 K15 K18 K19 L12 L14 L16 M6 M8 M9 M11 M12 M13 M14 N6 N7 N9 N10 N12 N19 P2 P4 P6 P8 P9 P11 P12 R6 R7 R9 R10 R12 T2 T4 T6 T8 T9 T11 T12 U2 U4 V1 V3 V6 V7 V9 V10 V12 V24 V26 V29 V31 W1 W2 W3 W4 W6 W24 W25 W27 W29 W30 W31 Y12 Y26 Y27 Y30 Y32; UC6 1; UC7 1; UC22 1; UD1 T7; UD2 T7; UD3 T7; UD4 T7; UD5 T7; UD6 T7; UD7 T7; UD8 T7; UEC1 27 81 82 84 86 102 118; UT1 18 19 20 21 22 23 24 25 27; UT2 16 17 19 20; UT4 2 13; UT6 14; UTS1 8 11; UWL1 3; YC1 2 4

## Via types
v1: diameter 0.406, hole 0.203, TOP to BOTTOM, 252 vias
v2: diameter 0.457, hole 0.203, TOP to BOTTOM, 4643 vias
v3: diameter 0.305, hole 0.152, TOP to BOTTOM, 353 vias
v4: diameter 0.508, hole 0.254, TOP to BOTTOM, 50 vias

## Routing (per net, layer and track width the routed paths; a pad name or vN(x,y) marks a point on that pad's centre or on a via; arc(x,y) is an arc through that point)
0.75VS_PWR_EN: length 71.8
  TOP w0.117: v2(174.49,76.38) v1(174.49,75.76)
  TOP w0.178: 189.35,46.36 189.2,46.21 UEC1.98
  TOP w0.305: v2(191.79,47.48) R70.2 191,46.82 190.62,46.44 189.42,46.44 189.35,46.36
  IN1 w0.102: v2(174.49,76.38) 174.13,76.03 171.57,76.03 167.3,80.29 161.74,80.29 157.46,76.01 v2(157.46,75.27)
  BOTTOM w0.117: v2(157.46,75.27) 157.46,74.4 U19.4 ; v2(174.49,76.38) 175.23,75.65 181.61,75.65 183.48,73.78 183.48,71.02 184.45,70.05 184.5,69.78 184.61,69.5 184.61,66.04 187.71,62.95 189.84,62.95 191.58,61.21 191.58,57.88 190.19,56.48 190.19,53.46 192.19,51.45 192.19,47.88 v2(191.79,47.48)
1.8VALW_PG: length 23.1
  TOP w0.254: v2(166.93,90.16) 168.89,88.21 168.89,85.9 v1(170.13,84.65) 172.52,82.26 172.52,81.4 171.83,80.71 v2(171.76,80.71) 172.38,80.09 172.38,77.68 170.67,75.96 v2(170.67,73.37)
  BOTTOM w0.254: PU1802.7 171.48,80.66 171.53,80.66 171.55,80.68 171.72,80.68 v2(171.76,80.71) ; v2(166.93,90.16) 166.27,90.82 PR601.1 ; PR1812.2 v2(170.67,73.37)
1.8VALW_PWR_EN#: length 4.4
  BOTTOM w0.117: v1(182.75,56.53) 182.75,55.95 182.39,55.59 R74.2 181.88,55.15 181.85,55.12 Q202.2 180.78,55.12 180.66,55.01 180.66,54.59 180.78,54.47 Q202.3
1.8VS_PWR_EN#: length 65.1
  TOP w0.178: 189.12,46.84 188.8,46.52 UEC1.99
  TOP w0.305: 189.12,46.84 189.27,46.84 189.72,47.29 R67.2 190.03,47.12 190.36,47.12 v2(190.36,47.12)
  IN1 w0.102: v2(163.55,70.19) 163.74,70.38 168.25,70.38 173.32,75.44 174.21,75.44 v2(175.12,76.36)
  BOTTOM w0.117: v2(190.36,47.12) 190.54,46.94 191.88,46.94 192.45,47.51 192.45,51.59 190.47,53.57 190.47,56.37 191.86,57.76 191.86,61.32 189.96,63.23 187.82,63.23 184.85,66.2 184.85,69.54 184.73,69.85 184.67,70.17 183.72,71.12 183.72,73.88 183.72,73.88 183.72,73.93 181.73,75.93 175.56,75.93 v2(175.12,76.36) ; v2(163.55,70.19) 163.27,70.19 Q146.2
1.8VS_PWR_EN_GATE: length 3.4
  BOTTOM w0.117: R2752.1 160.36,66.29 Q146.1 ; R2752.1 159.74,65.43 v3(159.74,64.15) ; R2752.1 R185.1
1.8VS_PWR_EN_R_GATE: length 4.4
  BOTTOM w0.117: v3(157.62,64.69) R185.2 158.4,65.89 C316.1 157.59,66.73 Q5.2
2.5V_EN: length 8.3
  TOP w0.117: PU251.6 120.32,7.8 120.61,8.08 PC255.1 121.07,8.08 121.55,8.56 123.12,8.56 123.34,8.34 125.19,8.34 125.34,8.49 PR251.2 125.37,8.49 PR256.2 v3(124.43,7.7)
2.5V_FB: length 2.5
  TOP w0.254: PR252.2 114.72,8.51 114.72,7.83 PR254.1 114.88,7.78 115.4,8.3 PU251.4
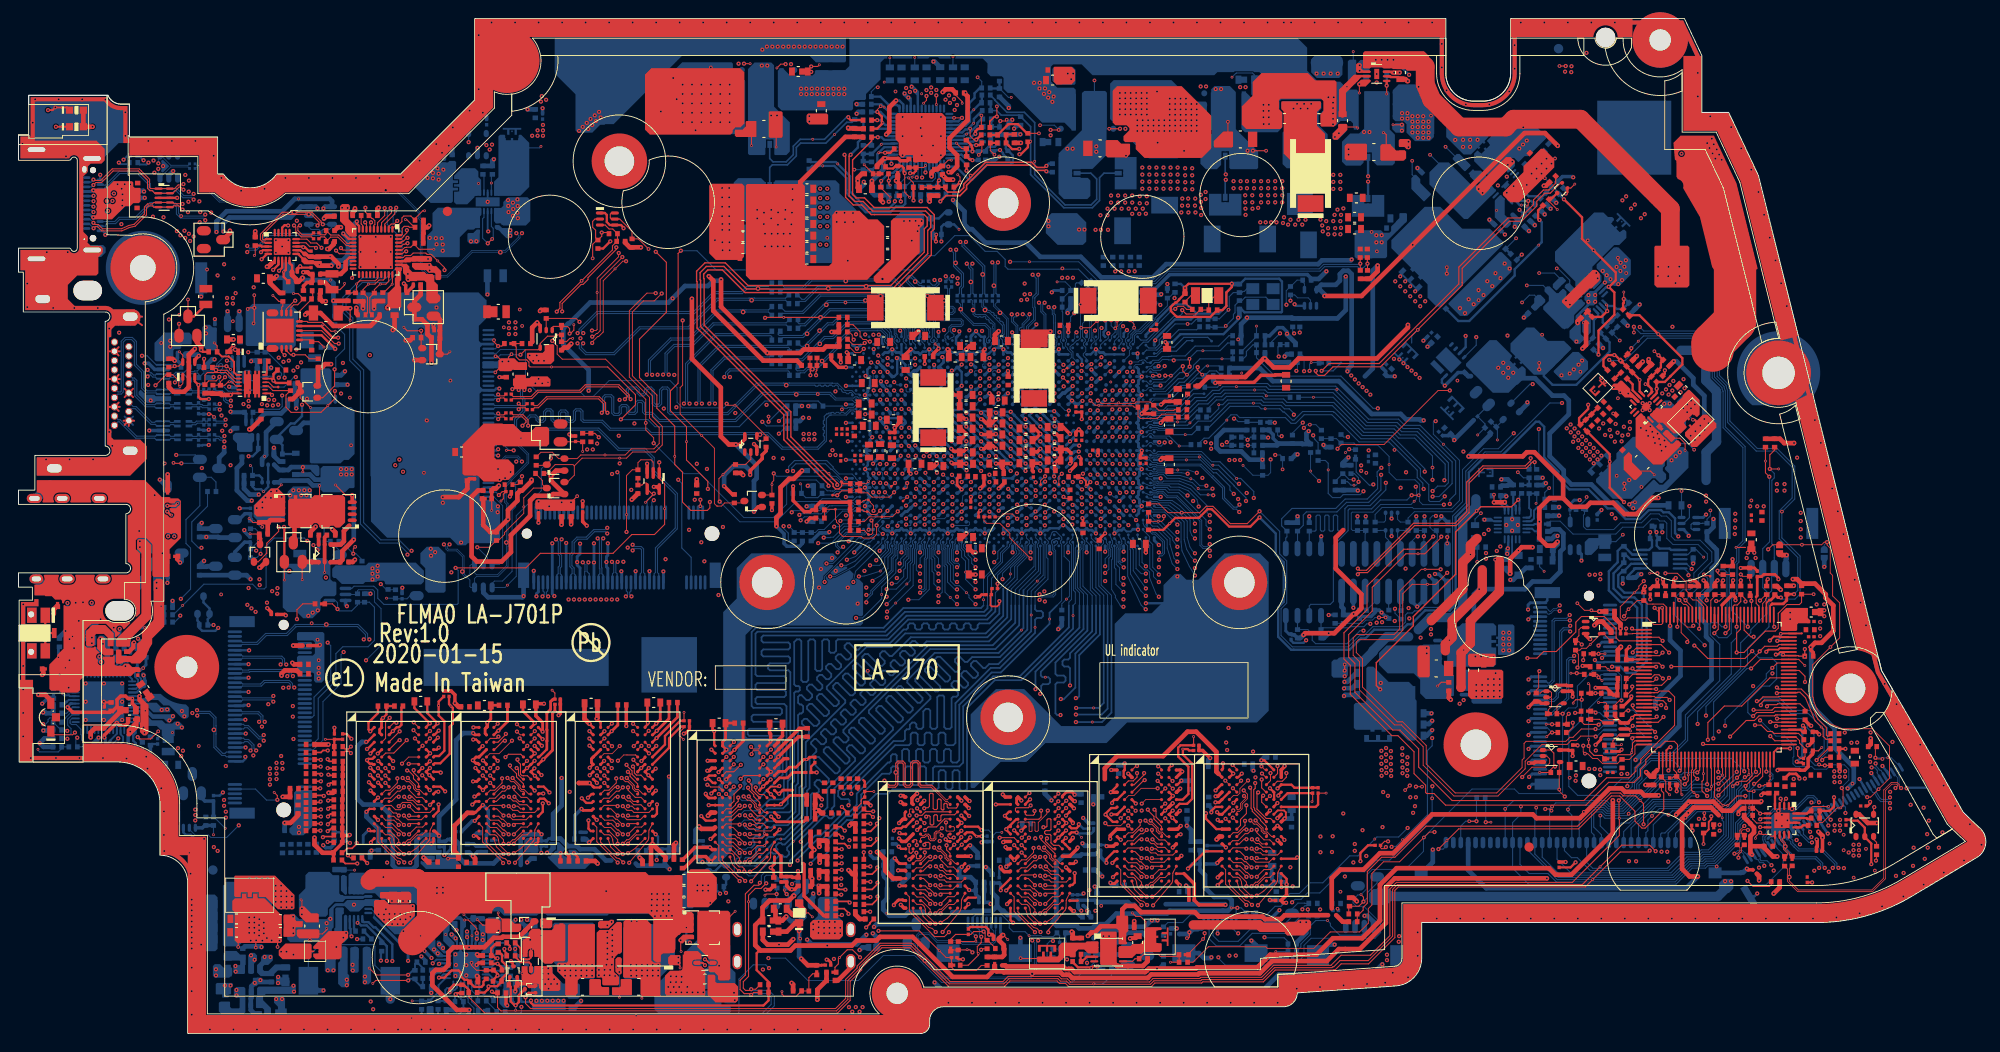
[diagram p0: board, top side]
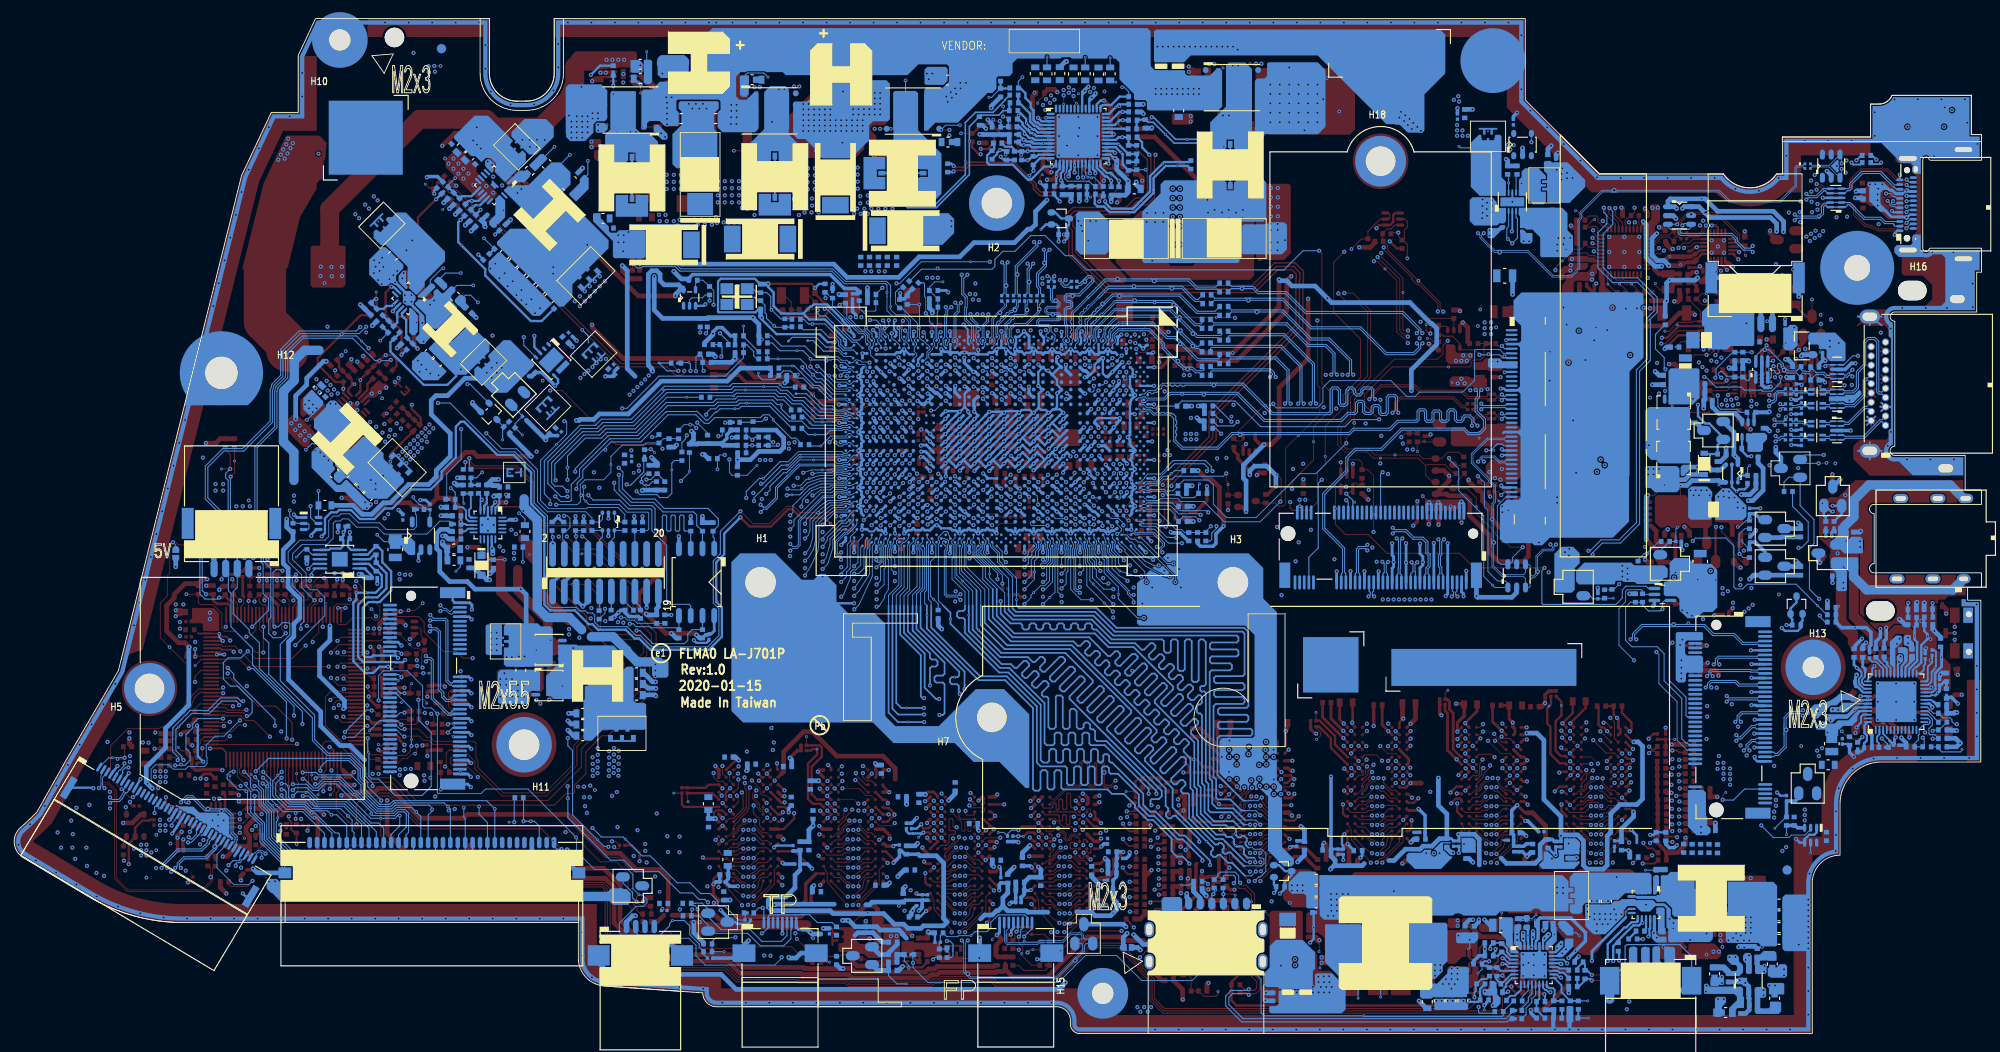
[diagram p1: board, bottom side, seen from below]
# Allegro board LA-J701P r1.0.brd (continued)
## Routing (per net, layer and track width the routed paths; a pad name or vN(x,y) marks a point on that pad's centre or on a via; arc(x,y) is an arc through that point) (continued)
2.5V_VIN: length 2.7
  TOP w0.117: v3(120.31,13.04) 120.69,12.65 121.2,12.65 121.77,12.08 121.77,11.19
3V/5VALW_PG: length 264.2
  TOP w0.117: UEC1.101 188,46.19 187.7,46.49 187.7,47.2
  TOP w0.254: PR1807.1 175.08,77.63 v1(177.12,75.59) 179.72,72.99 179.72,72.32 178.45,71.05 178.45,71.04 177.83,70.42 176.93,70.42 176.93,69.7 v2(176.95,69.68) 176.95,69.2 PU301.7
  TOP w0.305: v2(190.1,49.09) 190.1,49.23 189.72,49.61 188.51,49.61 188.28,49.38 C258.2 187.81,47.31 187.7,47.2
  IN2 w0.127: v2(180.48,57) 185.74,57 189.6,53.14 189.6,51.11 190.26,50.45 190.26,49.25 v2(190.1,49.09) 190.1,48.84 189.61,48.35 189.61,46.04 190.57,45.08 190.57,43.83 191.46,42.93 193.36,42.93 194.01,42.28 194.01,41.59 193.46,41.04 192.19,41.04 191.2,40.05 190.86,39.71 190.86,36.32 191.2,35.98 191.2,32.67 190.3,31.77 190.3,28.75 190.43,28.63 190.43,27.92 189.92,27.42 189.92,24.63 189.31,24.02 189.31,22.3 187.92,20.91 182.14,20.91 178.76,17.53 172.96,17.53 169.97,20.53 164.65,20.53 162.39,18.27 151.73,18.27 148.5,15.04 148.5,13.33 145.26,10.09 141.29,10.09 140.45,9.25 138.68,9.25 137.62,8.2 136.65,8.2 135.58,7.13 133.57,7.13 132.21,5.77 114.52,5.77 114.1,6.19 114.1,6.56 112.89,7.78 111.47,7.78 111.47,7.77 110.91,7.77 110.84,7.7 108.63,7.7 107.69,6.76 100.99,6.76 100.33,7.43 98.08,7.43 96.91,8.59 92.93,8.59 89.49,5.15 88.75,5.15 86.56,2.96 75.11,2.96 75.06,3.02 54.85,3.02 54.11,3.76 51.9,3.76 51.76,3.9 50.75,3.9 49.55,5.11 45.25,5.11 42.51,7.85 v2(42.08,7.85)
  IN3 w0.127: v2(180.48,57) 180.48,58.8 183.47,61.79 183.47,68.52 180.46,71.53 178.81,71.53 v2(176.95,69.68)
  BOTTOM w0.117: PU501.9 38.1,13.47 38.42,13.15 38.42,12.54
  BOTTOM w0.127: v2(180.48,57) 180.48,55.76 179.85,55.12 Q202.5
  BOTTOM w0.305: v2(42.08,7.85) 42.08,8.88 38.42,12.54
3V_FB: length 2.5
  TOP w0.254: PU301.10 174.35,69.53 174.35,70.17 PC313.1
3V_FB_1: length 1
  TOP w0.254: PR304.1 173.05,71.43 PC313.2
3V_SN: length 2.4
  TOP w0.117: v3(176.68,60.39) 176.28,60.79 174.42,60.79
5V_3V_EN: length 256.2
  TOP w0.254: PR509.2 171.2,72.13 171.2,72.87 171.66,73.32 v2(172.37,73.32) 172.47,73.32 PR510.2 173.69,72.1 PR512.1 173.69,72.09 PC522.1 175.11,70.67 v1(175.11,70.63) 175.11,69.4 PU301.9
  IN2 w0.152: v2(172.37,73.32) 172.37,73.96 173.9,75.49 178.6,75.49 181.65,72.45 181.65,70.9 192.17,60.38 192.17,59.16 194.57,56.76 194.57,51.71 197.65,48.62 197.65,42.69 193.65,38.69 192.94,38.69 192.47,38.23 192.47,37.75 193.84,36.38 193.84,35.68 195.6,33.93 195.6,32.12 193.23,29.75 193.23,28.69 194.24,27.68 194.24,26.23 192.57,24.56 192.57,22.77 189.86,20.05 189.81,20.05 189.08,19.32 186.78,19.32 185.76,18.31 181.82,18.31 179.37,15.85 171.11,15.85 169.43,17.53 164.42,17.53 162.4,15.51 151.26,15.51 150.27,14.52 150.27,13.04 145.01,7.78 139.09,7.78 138.18,6.86 137.2,6.86 136.13,5.8 134.12,5.8 132.76,4.44 113.75,4.44 111.99,6.2 109.43,6.2 108.66,5.43 99.65,5.43 99.13,5.95 97.59,5.95 96.38,7.16 93.47,7.16 90.01,3.69 89.17,3.69 86.94,1.45 48.82,1.45 48.02,2.25 39.98,2.25 39.14,3.09 v2(39.14,7.88)
  BOTTOM w0.254: PR503.1 39.14,8.81 v2(39.14,7.88)
5V_EN: length 260.4
  TOP w0.254: PR507.2 169.9,66.95 PC521.1 169.32,66.34 PR511.1 169.27,66.34 PR508.2 168.57,65.92 168.57,66.52 169.55,67.49 v2(169.55,67.95)
  IN2 w0.152: v2(169.55,67.95) 169.55,69.31 169.69,69.45 169.69,70.74 170.68,71.73 171.85,71.73 173.19,73.08 173.19,73.82 174.23,74.86 178.34,74.86 181.02,72.18 181.02,70.63 191.53,60.12 191.53,58.9 193.46,56.97 193.46,51.2 197.02,47.64 197.02,43.06 193.28,39.32 192.67,39.32 191.81,38.46 191.81,37.52 193.1,36.23 193.1,35.18 194.3,33.98 194.3,32.86 194.05,32.61 194.05,31.32 192.7,29.98 192.7,28.47 193.44,27.73 193.44,27.34 191.94,25.84 191.94,22.89 190.62,21.57 190.43,21.57 188.82,19.96 182.57,19.96 182.46,19.84 182.44,19.84 179.09,16.49 171.9,16.49 171.59,16.79 171.59,16.8 169.14,19.26 164.89,19.26 162.01,16.38 151.21,16.38 149.47,14.64 149.47,13 144.79,8.31 138.87,8.31 137.96,7.4 136.98,7.4 135.91,6.33 133.9,6.33 132.54,4.97 114.11,4.97 113.56,5.52 113.15,5.94 113.15,6.17 112.48,6.84 109,6.84 108.12,5.96 99.87,5.96 99.27,6.56 97.74,6.56 96.6,7.69 93.25,7.69 89.78,4.22 88.95,4.22 86.74,2.01 50.38,2.01 49.36,3.03 43.32,3.03 39.78,6.57 v2(39.78,7.85)
  BOTTOM w0.254: v2(39.78,7.85) 39.78,9.44 39.41,9.81 PR503.2 39.23,10.06 37.62,11.68 36.99,11.68 36.69,11.98 PU501.12
5V_FB: length 1.4
  BOTTOM w0.254: PU501.13 36.24,11.3 36.4,11.13 PC519.1
5V_FB_1: length 1.2
  BOTTOM w0.254: PC519.2 37.32,11.02 PR505.1
5V_SN: length 1.9
  TOP w0.117: v3(33.3,11.35) 33.3,11.22 32.83,10.76 PR502.2
+0.6V_DDRA_VREFCA: length 82.5
  TOP w0.254: UD1.M1 95.24,16.76 ; v2(126.32,17.82) 128.18,19.69 UD4.M1 ; v2(117.52,18.45) 117.52,18.85 118.34,19.68 UD3.M1 ; UD2.M1 106.1,15.71 v2(106.1,15.49)
  TOP w0.508: 95.24,16.76 94.47,16.76 93.64,17.58 93.64,18.78 92.8,19.61 v2(92.73,19.61)
  BOTTOM w0.254: 100.83,13.01 100.83,13.09 100.85,13.11
  BOTTOM w0.381: 93.81,15.72 CD36.1 93.44,16.93 CD2.1 RD37.2 93.44,18.84 CD6.2 93.41,18.99 RD32.1 92.75,19.64 v2(92.73,19.61) ; CD7.2 126.81,18.32 v2(126.32,17.82) ; CD7.2 CD8.1 127.7,19.73 CD40.1 ; CD7.2 127.61,17.67 ; v2(117.52,18.45) 116.88,19.08 CD38.1 116.72,19.79 116.3,19.37 CD9.1 114.84,19.37 ; v2(106.1,15.49) 106.1,16.1 CD34.1 CD1.1
  BOTTOM w0.508: 105.71,13.77 105.71,14.66 105.17,15.19 CD1.1 ; 105.71,13.77 106.21,13.26 106.39,13.26 106.85,12.81 107.69,12.81 108.12,12.38 ; 105.71,13.77 105.2,13.26 103.18,13.26 103.03,13.11 100.85,13.11 ; 93.81,15.72 93.81,14.57 93.41,14.18 93.41,13.39 v3(93.8,13.01) 94.07,12.73 95.75,12.73 96.16,13.14 97.68,13.14 97.7,13.16 ; 127.61,17.67 128.16,17.12 128.16,15.75 129.15,14.76 130.68,14.76 131.04,14.4 131.04,13.72 131,13.69 131,13.64 130.63,13.26 130.11,13.26 130.1,13.27 124.36,13.27 124.04,12.96 118.58,12.96 117.44,11.82 116.42,11.82 115.97,11.36 114.57,11.36 114.29,11.64 112.13,11.64 111.73,12.04 112.11,12.43 112.11,18.42 112.89,19.21 114.67,19.21 114.84,19.37
+0.6V_DDRB_VREFCA: length 90.7
  TOP w0.127: RD46.1 46.45,18.94 v1(46.4,18.89)
  TOP w0.254: v2(37.58,23.96) 37.9,24.28 UD5.M1
  TOP w0.305: v2(60.81,24.28) 60.98,24.11 61.91,24.11 UD7.M1 ; 49.13,23.85 49.17,23.89 49.36,23.89 UD6.M1 v2(50.15,24.69)
  TOP w0.508: UD8.M1 75.09,22.12 73.77,22.12 v2(73.51,22.37) ; 49.13,23.85 48.49,23.85 47.1,22.46 47.1,19.7 47.52,19.28 RD46.1
  IN2 w0.508: 50.15,18.55 51.27,18.55 52.06,17.76 53.79,17.76 54.32,18.29 54.32,22.36 55.03,23.07 58.54,23.07 59.75,24.28 v2(60.81,24.28) 60.82,24.27 60.82,22.76 63.36,20.22 63.36,18.17 63.74,17.79 66.74,17.79 68.52,19.56 71.03,19.56 73.51,22.04 v2(73.51,22.37) ; 50.15,18.55 50.03,18.42 43.45,18.42 42.87,17.84 39.28,17.84 38.83,18.29 38.83,21.98 37.76,23.04 37.76,23.78 v2(37.58,23.96) ; 50.15,18.55 v2(50.15,24.69)
  BOTTOM w0.305: CD91.1 38.97,20.82 CD59.1
  BOTTOM w0.381: CD93.1 73.22,20.82 CD62.1 ; RD47.2 48.51,20.51 49.16,20.51 49.43,20.24 CD58.2 CD57.2 CD94.1 50.54,21.49 CD61.1 50.74,24.1 v2(50.15,24.69) ; v2(60.81,24.28) 60.1,23.57 CD92.1 60.1,21.05 CD60.1
  BOTTOM w0.508: CD62.1 73.13,21.99 v2(73.51,22.37) ; v2(37.58,23.96) 37.58,23.42 38.89,22.12 CD59.1
+0.6VS: length 126.5
  TOP w0.127: v2(143.25,39.22) v1(143.25,39.88)
  TOP w0.254: 90.67,26.35 90.63,26.38 CD39.2
  TOP w0.305: RD61.1 RD62.1
  TOP w0.381: v2(35.78,21.47) 35.7,21.39 35.02,21.39 ; RD61.1 RD65.1 35.02,21.39 ; 35.02,21.39 35.02,20.71 RD64.1 34.97,20.55 34.03,19.61 RD69.1 RD67.1 ; RD71.1 RD77.1 RD75.1 35.02,27.89 RD81.1 CD84.1 35.02,26.16 35.02,25.3 RD66.1 RD59.1 RD60.1 RD62.1
  TOP w0.508: RD25.1 RD26.1 ; RD25.1 RD8.1 RD7.1 ; RD25.1 90.08,17.23 v2(89.65,17.66) ; RD12.1 RD4.1 86.58,17.51 CD30.1 v2(86.48,16.79) ; RD2.1 RD11.1 ; RD24.1 RD13.1 86.62,19.12 CD31.1 v2(86.54,18.46) ; RD69.1 32.83,19.54 31.97,20.4 v2(31.97,21.16) ; v2(89.75,22.48) 89.94,22.67 RD20.1 RD22.1 ; RD6.1 RD15.1 87.23,20.85 CD28.1 86.48,20.25 86.5,20.22 v2(86.5,20.17) ; v2(86.48,15.17) CD29.1 RD16.1 RD9.1 ; RD5.1 90.39,12.86 90.87,12.38 RD14.1
  IN1 w0.254: v2(89.75,22.48) 89.53,22.71 88.05,22.71 ; v2(89.65,17.66) 89.25,17.25 89.14,17.25 89.12,17.23 88.31,17.23 88.23,17.15
  IN1 w0.381: v2(89.75,20.88) 89.68,20.88 89.3,20.5 88.21,20.5
  IN2 w0.762: v2(35.78,21.47) 35.4,21.47 34.66,20.73 34.66,19.03 36.87,16.82 43.12,16.82 43.66,17.36 49.85,17.36 50.21,17 67.12,17 68.01,17.89 69.05,17.89 69.22,18.05 69.23,18.05 69.95,18.78 71.47,18.78 73.24,17 75.75,17 78.6,14.15 84.07,14.15 84.5,14.58 84.5,15.27 85.18,15.96 86.27,15.96 86.35,16.03
  BOTTOM w0.254: CD81.1 RD43.1 35.42,21.47 v2(35.78,21.47)
  BOTTOM w1.016: 151.2,43.64 152.52,44.96 154.93,44.96 156,46.03 156,55.49 157.42,56.92 157.42,57.79 ; 150.16,42.88 147.81,42.88 146.32,41.39 146.32,41.28 145.2,40.16 142.89,40.16
  vias: v2(86.71,24.65) v2(143.25,38.61)
+0.6VSP: length 3.1
  TOP w0.117: v2(159.38,57.41) v1(159.38,58.23)
  TOP w0.508: v2(160.54,57.43) 160.52,57.41 v2(159.38,57.41)
  BOTTOM w0.203: v2(160.54,57.43) 160.62,57.36 160.62,57.23 160.93,56.92 PUM1.2
+0.75VALW: length 3.2
  BOTTOM w0.3: UC1.AM12 114.48,68 114.84,68.37 v2(114.92,68.37) ; v2(113.83,69.16) 113.73,69.16 UC1.AL11 ; v2(113.8,68.4) 113.8,68.37 113.42,68 UC1.AL12
  BOTTOM w0.381: UC1.AM12 114.21,68 113.81,68.4 v2(113.8,68.4) 113.77,68.4 UC1.AL11
  vias: v1(131.74,75.01) v2(148.71,81.3) v2(149.25,81.83) v2(149.25,80.76) v2(149.79,81.3) v2(149.79,80.22) v2(150.33,80.76) v2(150.33,79.68) v2(150.87,80.22) v2(150.87,79.14) v2(151.4,79.68) v2(151.4,78.6) v2(151.94,79.14)
+0.75VALW_0.75VS: length 1.7
  BOTTOM w0.127: 150.48,74.63 150.48,75.38 v1(151.14,76.05)
+0.75VALWP: length 0.7
  TOP w0.127: v2(154.28,82.12) v1(154.28,82.82)
+0.75VS: length 2.9
  TOP w0.305: RC22.2 v2(97.88,72.37)
  BOTTOM w0.254: v2(96.97,64.5) 97.37,64.1 UC1.M16
  BOTTOM w0.35: UC1.M18 96.87,63.51 v2(96.87,63.56) ; UC1.M15 97.37,65.1 v2(96.96,65.51)
  vias: v2(87.66,62.52) v2(87.92,63.05) v2(88.25,62.52) v2(95.37,64.5) v2(96.17,64.5) v2(128.21,63.91) v2(128.82,63.78) v2(128.82,63.2) v2(130.79,61.98) v2(131.37,61.98) v2(131.96,61.98) v2(148.57,72.91) v2(149.15,72.85) v2(149.6,72.45) v2(150.03,72.03) v2(150.47,71.65) v2(150.92,71.27) v2(151.34,70.86) v3(87.74,64.03)
+1.2V: length 242.8
  TOP w0.254: UD5.G1 38.15,28.56 v2(37.99,28.72) ; UD6.J1 49.79,26.68 v2(50.17,26.31) 50.54,26.68 UD6.J2 ; UD7.D9 68.49,30.68 v2(68.89,31.08) ; v2(73.75,23.49) 74.23,23.01 75.09,23.01 75.16,23.08 UD8.L1 ; UD5.G9 45.52,28.28 v2(45.61,28.2) ; CC46.1 38.83,34.63 37.81,33.61 37.81,32.85 v2(38,32.66) 38.42,33.08 UD5.A1 ; CD3.1 91.41,27.23 91.25,27.39 ; v2(37.64,30.75) 37.7,30.75 UD5.C1 ; UD7.C1 62.06,31.48 v2(61.66,31.88) ; UD5.A9 v2(45.27,33.52) 44.16,34.63 CC37.1 ; UD5.L1 38.43,25.09 v2(38.83,25.49) ; v2(49.35,28.69) 49.74,28.3 UD6.G1 ; v2(46.09,26.17) 45.57,26.68 UD5.J9 ; UD6.D1 v2(50.13,31.07) ; v2(74.83,25.94) 75.18,26.28 UD8.G1 ; UD5.D9 45.18,30.68 v2(45.4,30.9) ; v2(57.35,26.05) 56.73,26.68 UD6.J9 ; UD8.B9 82.08,30.71 82.09,30.71 ; UD6.T9 56.15,20.73 v2(55.9,20.48) ; UD7.B9 68.51,32.28 v2(68.94,32.71) ; UD6.C1 49.72,31.48 49.43,31.77 v2(49.11,31.77) ; v2(63.25,29.46) 62.89,29.09 62.88,29.09 UD7.F2 ; v2(129.3,26.27) 129.92,26.89 UD4.C1 ; UD5.T9 44.83,20.77 v2(44.59,20.53) ; UD4.D9 136.08,25.78 v2(136.08,25.71) ; UD1.C1 95.72,23.85 95.72,23.27 UD1.D1 ; v2(101.84,21.91) 101.49,21.56 UD1.F8 ; v2(100.14,20.99) 100.35,20.78 100.61,20.78 UD1.G7 ; v2(45.39,32.73) 44.94,32.28 UD5.B9 ; v2(61.68,27.07) 62.06,26.68 UD7.J1 62.17,26.59 62.78,26.59 UD7.J2 ; UD8.A1 75.15,31.19 v2(75.15,32.69) ; UD4.J1 129.39,22.09 128.26,23.22 v2(128.26,23.81) ; v2(56.49,27.93) 56.15,28.28 UD6.G9 ; UD6.J8 55.35,26.66 v2(55.75,26.26) ; v2(49.13,33.08) UD6.A1 ; v2(82.36,24.79) 82.25,24.68 UD8.J9 UD8.J8 ; UD5.G7 43.23,28.31 v2(43.61,28.69) ; UD2.D1 106.91,23.16 v2(106.54,23.53) 106.98,23.96 UD2.C1 ; UD6.D9 56.15,30.69 v2(55.75,31.08) ; v2(44.45,24.71) 44.82,25.08 UD5.L9 ; v2(60.84,25.42) 61.33,24.92 61.92,24.92 62.07,25.08 UD7.L1 ; UD4.T9 136.4,15.86 v2(136.43,15.83) ; UD6.B3 51.79,32.72 v2(51.83,32.72) ; UD7.A1 62.06,33.08 v2(61.66,33.48) ; UD8.F2 76.05,27.1 v2(75.65,27.5) ; v2(109.26,25.3) 108.75,24.79 UD2.B3 ; v2(44.44,29.43) 44.09,29.08 UD5.F8 ; UD8.J2 UD8.J1 v2(74.55,24.68) ; v2(81.29,23.44) 81.65,23.08 UD8.L9 ; v2(82.16,25.91) 82.05,25.91 81.68,26.28 UD8.G9 ; UD5.F2 38.95,29.36 v2(38.86,29.45) ; v2(113.15,21.94) 112.76,21.56 UD2.F8 112.36,21.17 v2(112.33,21.17) 111.95,20.79 UD2.G7 ; UD3.C1 118.67,26.76 v2(117.98,26.08) ; v2(55.74,29.47) 55.36,29.08 UD6.F8 54.96,28.69 v2(54.93,28.69) 54.55,28.31 UD6.G7 ; UD7.T9 v2(68.48,20.48) ; UD5.B3 40.03,32.28 v2(40.43,32.68) 40.85,33.1 41.11,33.1 41.36,33.36 41.36,35.23 CD68.1 ; v2(61.57,23.03) 61.57,22.13 61.82,21.88 UD7.R1 ; UD3.R1 118.6,17.28 v2(118.22,16.9) ; UD8.B3 76.95,30.28 v2(77.33,30.66) ; UD3.G7 123.47,23.71 v2(123.85,24.09) 124.23,24.48 UD3.F8 ; UD7.G9 v2(68.83,28.63) ; CD63.1 60.39,19.08 v2(59.99,19.49) ; UD7.G1 62.06,28.28 v2(61.7,27.92) ; v2(57.28,24.88) 56.78,25.38 56.33,25.38 56.15,25.2 UD6.L9 ; UD4.A1 129.99,28.54 130.1,28.64 v2(130.1,29.2) ; v2(81.24,27.46) 80.86,27.08 UD8.F8 80.82,27.08 v2(80.43,26.69) 80.05,26.31 UD8.G7 ; UD5.R1 37.98,21.88 v2(37.84,22.01) ; v2(68.89,33.5) 68.48,33.08 UD7.A9 ; RD42.1 v2(37.66,18.42) ; UD7.J8 v2(68.1,26.26) 68.48,26.63 UD7.J9 ; v2(132.13,28.09) 131.74,27.69 UD4.B3 ; v2(61.68,31.11) 62.08,30.71 UD7.D1 ; v2(56.61,32.63) 56.16,33.08 UD6.A9 ; UD7.G7 66.88,28.31 v2(67.26,28.69) 67.64,29.08 UD7.F8 ; CD67.1 v2(58.54,19.49) ; v2(44.42,26.31) 44.05,26.68 UD5.J8 ; v2(118.05,23.68) UD3.G1 UD3.F2 ; CD54.1 35.44,32.38 v2(35.96,31.86) ; UD6.B9 v2(56.61,31.81) ; v2(102.62,13.99) 102.62,13.94 UD1.T9 ; v2(102.8,21.19) 102.37,20.76 UD1.G9 ; UD6.F2 50.54,29.14 v2(50.17,29.51) ; UD6.L1 49.36,25.08 v2(49.02,24.74) ; 82.05,29.08 UD8.D9 ; UD2.F2 v2(107.55,21.96) ; v2(101.84,23.55) UD1.D9 ; v2(38.01,30.26) UD5.D1 ; UD4.F8 135.6,24.52 v2(135.98,24.91) ; v2(38.84,27.11) 39.23,26.72 UD5.J2 ; UD7.B3 v2(64.07,32.67) ; UD7.L9 v2(68.13,24.73) ; UD4.F2 UD4.G1
  TOP w0.305: UD5.J1 38.33,26.68 v2(37.85,27.15) ; CD66.1 78.27,31.6 v2(77.33,30.66) ; v2(130.42,20.11) 130.04,20.49 UD4.L1 ; v2(82.16,25.91) 82.56,26.31 83.61,26.31 ; CD69.1 81.58,17.59 v2(81.25,17.93) 81.65,18.33 UD8.T9 ; 56.41,33.8 56.61,33.6 v2(56.61,32.63) ; v2(68.94,32.71) 70.26,34.03 CD70.1 ; CC35.1 74.97,32.86 v2(75.15,32.69) ; v2(129.47,23.92) 129.7,23.69 UD4.G1 ; v2(51.83,32.72) 52.82,33.71 CD71.1 ; UD1.R1 95.81,14.38 95.58,14.38 95.52,14.45 95.08,14.45 95.01,14.38 94.98,14.38 94.55,13.95 v2(94.55,13.87) ; v2(68.89,33.5) 69.32,33.93 CC40.1 ; v2(64.07,32.67) 64.74,33.34 CD80.1 ; CD74.1 84.81,22.88 81.85,22.88 UD8.L9 ; CD72.1 83.3,25.74 v2(82.36,24.79) ; v2(135.17,24.1) 135.17,24.07 UD4.G7
  TOP w0.33: UD4.J8 135.96,22.46 v2(135.99,22.46) 136.03,22.46 UD4.J9
  TOP w0.356: UD3.A9 125.53,28.48 v2(125.7,28.31) UD3.B9 ; v2(118.02,28.48) UD3.A1
  TOP w0.381: UD1.L1 95.76,17.63 v2(95.01,17.63) ; v2(74.4,28.4) 74.62,28.4 74.9,28.68 UD8.D1 ; UD4.J2 UD4.J1 ; UD4.D1 129.54,25.63 v2(129.3,25.63) ; v2(56.76,35.64) 55.96,35.64 CC52.1 55.88,34.33 56.41,33.8 ; UD3.G9 125.07,23.7 v2(125.44,24.08) ; UD2.L1 107.08,17.49 106.47,17.49 106.15,17.81 106.15,17.87 106.08,17.94 v2(106.08,18.01) ; UD3.T9 125.07,16.4 v2(125.44,16.03) ; UD3.J2 UD3.J1 118.61,22.08 117.92,21.39 v2(117.92,21.04) ; UD2.J1 107.15,19.16 v2(107.57,18.74) 107.95,19.12 UD2.J2 ; v2(117.53,20.25) 118.28,20.25 118.5,20.48 UD3.L1 ; CC39.1 82.53,32.17 82.08,31.72 82.08,31.51 UD8.A9 ; 82.09,30.71 84.37,32.99 CD64.1 ; UD1.D1 95.53,23.16 v2(95.11,22.74) ; UD1.F2 UD1.G1 95.41,20.76 v2(95.1,21.07) ; UD3.D9 125.09,26.08 v2(125.49,26.47) ; UD2.J8 UD2.J9 114.35,19.96 114.35,20.05 114.4,20.1 v2(114.4,20.1) ; 84.75,18.37 84.85,18.27 84.85,14.87 86.99,12.73 RD1.1 ; UD2.G9 113.88,21.09 v2(113.88,21.16) ; UD1.J2 96.29,18.81 v2(96.23,18.81) ; v2(124.68,20.1) 125.06,20.48 UD3.L9 ; v2(95.28,25.71) 95.57,25.71 95.72,25.56 UD1.A1 ; v2(102.73,25.13) 102.67,25.13 UD1.A9 ; v2(114.01,13.24) 113.87,13.24 UD2.T9 ; v2(113.89,22.74) 113.89,22.82 UD2.D9 ; v2(106.31,25.84) 106.59,25.56 UD2.A1 ; v2(114.01,24.34) 113.59,24.76 UD2.B9 ; v2(114.11,25.1) 114.01,25.1 UD2.A9 ; UD4.L9 136.39,20.49 v2(136,20.89) ; 82.05,29.08 82.67,29.7 83.1,29.7 ; v2(117.98,26.08) UD3.D1 ; UD4.G9 v2(135.98,23.27) ; UD2.L9 v2(113.14,17.96) ; CD78.1 71.75,18.79 73.07,20.12 v2(74.69,20.12) 74.92,19.88 UD8.R1 ; v2(124.67,24.88) 124.67,24.88 UD3.F8 ; UD3.B3 120.27,27.68 v2(119.87,28.08) ; v2(125.54,22.43) 125.18,22.08 UD3.J9 UD3.J8 ; v2(102.6,17.97) 102.6,17.92 UD1.L9 ; v2(106.78,13.98) UD2.R1 ; v2(136.76,28.91) 136.76,28.85 UD4.A9 UD4.B9 ; v2(106.36,20.68) 106.39,20.71 106.47,20.71 106.47,20.76 UD2.G1 ; UD4.R1 129.96,17.29 v2(129.53,16.86) ; UD1.J8 UD1.J9 v2(102.85,19.16) ; UD1.B9 102.26,24.76 v2(102.65,24.36) ; v2(74.43,29.48) UD8.C1 ; v2(97.84,25.16) UD1.B3
  TOP w0.508: CD76.1 69.88,19.08 v2(68.48,20.48) 68.33,20.33 CD77.1 ; CC36.1 61.14,34 v2(61.66,33.48) ; CD72.1 85.13,25.72 CD73.1 ; 60.52,27.08 60.53,27.07 v2(61.68,27.07)
  IN3 w0.381: v2(74.43,29.48) 74.97,29.48 75.48,29.99 75.48,30.75 76.05,31.32 76.66,31.32 v2(77.33,30.66)
  BOTTOM w0.254: CC49.1 44.67,20.45 v2(44.59,20.53) ; UC1.AJ28 UC1.AK28 112.37,54.6 112.71,54.93 v2(112.84,54.93) 113.04,54.93 UC1.AL28 ; UC1.AC21 UC1.AD21 107.37,60.07 v2(107.84,60.53) ; 39.67,19.64 39.65,19.66 CD91.2 ; v2(74.69,20.12) 74.57,20.24 CD93.2 ; v2(130.42,20.11) 130.21,20.31 CD40.2 ; v2(106.08,18.01) 105.93,17.86 CD34.2 ; v2(117.53,20.25) 117.41,20.38 CD38.2 ; CD14.1 114.64,12.6 v2(114.01,13.24) ; 94.83,16.54 94.81,16.57 CD36.2 ; CD94.2 51.64,20.88 ; CC50.1 55.69,20.27 v2(55.9,20.48)
  BOTTOM w0.3: v2(112.87,56.4) 112.48,56.8 UC1.AK25 ; v2(106.87,55.73) 107.11,55.73 UC1.AD26 ; UC1.AJ32 111.37,51.97 v2(111.45,51.9) ; UC1.AP28 v2(116.37,54.05) 116.31,54.05 115.96,54.4 115.57,54.4 UC1.AN28 115.18,54.4 114.57,54.4 UC1.AM28 114.18,54.4 113.57,54.4 UC1.AL28 ; UC1.AG20 v2(110.35,60.83) ; v2(108.37,54.05) 108.44,54.05 108.79,54.4 109.18,54.4 UC1.AF28 109.57,54.4 109.95,54.4 110.3,54.05 v2(110.37,54.05) ; v2(108.37,54.05) UC1.AE28 ; v2(108.37,54.05) 108.31,54.05 107.96,54.4 107.57,54.4 UC1.AD28 107.18,54.4 106.78,54.4 106.43,54.05 v2(106.37,54.05) UC1.AC28 ; UC1.AF23 108.97,58.81 v2(108.86,58.81) ; v2(110.37,54.05) UC1.AG28 ; v2(110.37,54.05) 110.45,54.05 110.8,54.4 111.18,54.4 UC1.AJ28 ; UC1.AL23 112.97,58.81 v2(112.82,58.81) ; v2(109.32,52) 109.32,52.65 UC1.AF32 ; v2(113.87,55.7) 113.67,55.7 UC1.AL26 ; v2(115.37,52) UC1.AN32 ; v2(110.89,59.64) 110.81,59.57 110.74,59.57 UC1.AG22 ; v2(117.37,52.08) UC1.AR32 ; UC1.AM25 114.04,57.13 v2(113.86,57.13) ; v2(108.77,60.8) UC1.AE20 ; v2(110.87,55.73) 111.1,55.73 UC1.AJ26 ; v2(107.37,52) UC1.AD32 ; UC1.AE25 107.94,56.37 v2(107.86,56.37) ; UC1.AJ23 111.77,58.8 v2(111.87,58.8) ; v2(111.94,59.63) UC1.AK22 ; v2(108.84,59.66) UC1.AE22 ; UC1.AC20 v2(107.18,60.8) ; v2(106.9,58.86) 107.36,58.4 UC1.AD23 ; v2(113.37,52) UC1.AL32 ; v2(114.87,58.8) 114.77,58.8 UC1.AM22 ; v2(109.85,56.42) 109.99,56.42 UC1.AG25
  BOTTOM w0.305: UC1.AF26 109.43,56 v2(109.85,56.42) ; CC51.1 67.81,19.81 v2(68.48,20.48) ; v2(111.87,60.22) 111.87,60.91 UC1.AJ20 ; 37.23,20.6 37.23,21.4 v2(37.84,22.01)
  BOTTOM w0.381: CD92.2 61.33,21.75 ; v2(102.6,17.97) 102.74,18.12 CD17.1
  BOTTOM w0.508: v2(112.31,43.71) 112.69,44.09 RC1.1
  vias: v1(91.74,39.2) v2(59.41,46.91) v2(59.54,26.12) v2(60,46.91) v2(60.58,46.91) v2(61.17,46.91) v2(61.75,46.91) v2(62.34,46.91) v2(62.92,46.91) v2(63.5,46.91) v2(64.09,46.91) v2(64.67,46.91) v2(147.21,30.55) v2(147.21,29.85) v2(147.21,29.15) v2(147.23,28.47) v2(147.23,27.86) v2(147.72,30.85) v2(147.72,30.16) v2(147.72,29.46) v2(147.74,28.77) v2(147.74,28.16) v2(148.24,30.52) v2(148.24,29.82) v2(148.24,29.13) v2(148.26,28.44) v2(148.26,27.83) v2(149.47,30.83) v2(149.47,30.13) v2(149.47,29.43) v2(149.5,28.75) v2(149.5,28.14) v2(150.03,29.85) v2(150,29.14) v2(150,28.45) v2(150,27.84)
+1.2VP: length 55.3
  TOP w0.152: v2(161.99,57.69) 161.99,57.66 161.26,56.93 157.95,56.93 v1(157.51,56.48) 155.24,54.21 155.24,49.64 150.66,45.06 150.66,44.07 146.66,40.07 146.66,37.61 v2(147.08,37.19)
  IN1 w0.508: v2(147.15,37.89) 147.15,41.72 147.84,42.42 148.99,42.42 151.71,45.14 151.71,46.37 151.45,46.63 151.45,49.54 155.36,53.45 155.36,54.49 156.4,55.53 v2(158.35,55.53)
  BOTTOM w0.152: PRM12.2 162.13,58.15 162.13,57.83 v2(161.99,57.69)
  BOTTOM w0.203: v2(161.99,57.69) 162.13,57.55 PUM1.5
+1.8V_AUDIO: length 43.4
  IN1 w0.508: v2(19.79,55.19) 18.52,53.91 18.52,43.83 15.41,40.72 15.41,36.93 14.06,35.59 14.06,34.06 14.33,33.79 14.33,31.97 13.78,31.43 12.11,31.43 10.62,32.91 6.84,32.91 6.43,33.32 4.9,33.32 2.58,35.64 v2(2.56,35.64)
  BOTTOM w0.381: RA25.1 3.25,36.34 v2(2.56,35.64)
  BOTTOM w0.508: v2(19.79,55.19) 19.54,54.93 RA60.1 19.55,54.56 QA3.1
+1.8VALW: length 421.3
  TOP w0.508: Q206.2 58.07,60.84 v2(57.51,60.28) 57.51,59.75 Q207.2 57.75,58.3 57.57,58.12 55.79,58.12 55.26,57.59 55.26,55.94 53.19,53.87 53.19,52.02 52.18,51.01 49.51,51.01 48.94,51.58 48.94,58.01 49.62,58.69 R360.1 ; RC604.1 127.54,69.98 128.5,70.95 132.5,70.95 134.48,72.93 v2(134.64,72.93) 135.58,71.99 137.3,71.99 138.27,72.95 146.73,72.95 150.08,76.31 v2(150.08,76.59) ; RC606.1 RC607.1 87.23,74.25 86.91,73.93 RC619.1 RC618.1 84.83,73.93 84.45,73.55 v1(80.88,73.55) 75.89,78.54 v2(75.89,81.49) ; RA34.1 11.16,34.94 9.19,32.97 8.23,32.97 7.79,32.53 v2(7.79,32.01) ; 143.09,54.41 142.28,53.6 142.28,50.25 145.05,47.48 145.05,45.95 144.44,45.34 v2(144.21,45.34) 142.13,43.26 v2(141.52,43.26) 138.98,43.26 v2(138.8,43.08)
  IN1 w0.508: v2(159.83,71.95) 157.96,73.82 155.71,73.82 152.94,76.59 v2(150.08,76.59) 148.85,76.59 144.65,80.79 143.79,80.79 143.47,80.79 142.01,82.25 141.88,82.38 v2(141.27,82.38) 141.27,83.01 138.73,85.54 126.67,85.54 126.03,84.9 105.69,84.9 103.34,82.56 99.15,82.56 98.09,81.49 v2(75.89,81.49) ; v2(37.95,73.32) 38.37,73.74 47.21,73.74 53.25,79.79 60.94,79.79 61.49,79.24 70.44,79.24 v2(70.65,79.46)
  IN2 w0.508: 20.3,53.66 v2(20.29,53.66) ; 20.3,53.66 20.43,53.79 20.43,57.95 19.07,59.31 19.07,61.55 19.57,62.06 22.78,62.06 24.1,63.38 25.32,63.38 29.12,67.18 29.12,68.15 33.15,72.18 33.15,72.81 33.66,73.32 v2(37.95,73.32) ; 20.3,53.66 20.28,53.64 19.5,53.64 18.39,52.54 18.39,43.15 21.63,39.91 21.63,36.11 20.62,35.09 20.62,33.55 19.53,32.47 16.14,32.47 14.29,34.32 12.54,34.32 10.96,32.75 8.2,32.75 7.79,32.34 v2(7.79,32.01)
  IN3 w0.508: v2(61.59,69.47) 61.59,69.04 60.95,68.41 60.95,63.72 v2(57.51,60.28) ; v2(148.31,53.75) 148.05,53.49 148.05,49.99 149.37,48.67 152.49,48.67 153,49.18 v2(153,49.66)
  BOTTOM w0.3: UC1.AL19 113.57,62.4 UC1.AM18
  BOTTOM w0.305: RHDT4.2 v2(151.87,55.9) ; U20.5 v2(148.31,53.75) ; UC1.AM18 114.07,62.9 v2(114.52,62.9) ; v2(153.69,55.91) 153.69,55.71 153.25,55.28 RHDT3.2 ; CC32.1 137.23,43.17 136.88,43.52 UC2.8 ; RHDT5.2 v2(144.63,55.9)
  BOTTOM w0.381: v2(153.69,55.91) 154.32,55.28 RHDT2.2 ; JHDT1.1 154.35,48.72 153.43,49.64 153.03,49.64 v2(153,49.66) ; 139.63,81.55 139.63,81.62 139.22,82.02 124.34,82.02 122.85,80.54 121.61,80.54 121.23,80.16 RC25.1 121.39,79.95 CC22.1 ; CC32.1 137.53,43.1 137.77,43.1 137.78,43.08 137.81,43.08 RC96.2 ; RC94.2 v2(139.42,55.9)
  BOTTOM w0.508: 161.81,70.36 162.27,70.82 163.81,70.82 165.69,68.94 166.95,68.94 167.45,68.43 167.45,66.91 165.4,64.85 165.4,62.39 166.91,60.87 166.91,60.17 167.73,59.34 169.89,59.34 171.87,57.36 172.63,57.36 173.88,56.11 174.93,56.11 175.89,57.08 R75.1 ; JHDT1.19 142.92,46.11 143.11,45.92 RHDT1.2 144.11,45.24 v2(144.21,45.34) ; RC24.1 139.63,81.55 140.44,81.55 v2(141.27,82.38) ; RC36.1 135.03,72.54 v2(134.64,72.93) RC59.2 ; v2(75.89,81.49) 75.76,81.36 75.04,81.36 74.48,80.79 71.99,80.79 v2(70.65,79.46) 70.2,79 61.74,79 59.45,76.71 59.35,76.71 58.84,76.21 58.84,74.47 61.59,71.72 v2(61.59,69.47) ; RA60.2 v2(20.29,53.66) 21.57,53.66 21.63,53.6 QA3.3 ; RC92.2 141,42.74 v2(141.52,43.26) ; RC95.2 RC93.2 v2(138.15,55.9) ; RC96.2 138.46,42.74 v2(138.8,43.08)
  vias: v2(160.37,72.49) v2(160.37,71.41) v2(160.91,71.95) v2(160.91,70.87) v2(161.45,71.41)
+1.8VALW_1.8VS:
  vias: v1(155.43,70.57)
+1.8VALWP: length 12.6
  TOP w0.127: v2(164.25,71.77) v1(164.25,72.47)
  BOTTOM w0.254: PR1808.2 170.88,75.68 PC719.1 171.86,74.7 171.86,73.7 168.27,70.11 165.7,70.11 164.76,71.05 164.76,71.39 164.82,71.46
+1.8VDD_CODEC: length 4.2
  BOTTOM w0.203: UA1.20 5.55,36.46 5.46,36.55 4.97,36.55
  BOTTOM w0.305: RA25.2 CA6.1 4.01,38.04 4.38,37.67 CA24.1 4.52,37 v3(4.74,36.78) 4.97,36.55
+1.8VS: length 153.6
  TOP w0.381: RC14.2 RC12.2 89.82,55.62 89.9,55.7 89.9,56.24 89.82,56.33 RC11.2 RC13.2 86.6,57.42 86.13,56.95 RC15.2 85.69,56.6 85.49,56.39 84.88,56.39 83.67,57.6 v2(83.67,59.14) ; QC1.2 79.87,56.9 79.44,56.47 v2(79.44,56.39) ; v2(77.49,63.66) 77.89,63.66 78.45,64.21 UC6.5 ; C1.1 113.68,61.71 v2(113.57,61.6) ; v2(114.57,62.31) 114.76,62.12 CC74.1
  TOP w0.508: v2(77.49,63.66) 76.74,63.66 75.86,64.53 75.86,69.8 72.74,72.93 v2(72.74,79.41) ; RC122.1 RC121.1 145.98,81.56 146.81,82.4 v2(146.81,82.99) ; PR1815.1 99.8,92.79 100.31,92.28 v2(100.94,92.28)
  IN1 w0.508: v2(79.44,56.39) 82.19,59.14 v2(83.67,59.14) ; v2(100.94,92.28) v2(100.94,90.08)
  IN2 w0.508: v2(100.94,90.08) 100.08,89.22 92.74,89.22 89.65,86.14 85.72,86.14 84.04,84.46 80.25,84.46 76.11,80.32 73.65,80.32 v2(72.74,79.41) ; v2(144,83.65) 144.36,84.01 145.8,84.01 v2(146.81,82.99)
  BOTTOM w0.3: UC1.AL20 v2(113.57,61.6) UC1.AM19 114.29,62.31 v2(114.57,62.31)
  BOTTOM w0.381: RC17.2 83.66,59.12 v2(83.67,59.14)
  BOTTOM w0.508: v2(100.94,90.08) 102.18,88.84 102.18,87.44 102.69,86.93 103,86.93 104.45,85.48 108.83,85.48 110.37,83.94 114.74,83.94 116.95,81.73 122.54,81.73 123.97,83.15 140.39,83.15 140.8,83.56 143.91,83.56 v2(144,83.65) ; v2(146.81,82.99) 146.28,82.47 146.28,71.87 145.43,71.02 ; v2(77.49,63.66) 79.73,61.42 79.73,60.01 79.44,59.72 v2(79.44,56.39)
  vias: v2(143.96,71.12) v2(144.35,70.69) v2(144.76,70.26) v2(145.19,69.86) v2(145.61,69.46) v2(146.02,69.05) v3(142.41,69.61)
+2.5V: length 224.1
  TOP w0.254: v2(61.66,32.68) 62.06,32.28 UD7.B1 ; UD2.B1 v2(105.57,24.76) ; 114.39,14.36 UD2.R9 ; v2(37.55,31.51) 37.66,31.51 UD5.B1 ; 82.36,19.17 UD8.R9 ; UD7.R9 v2(68.83,21.53) ; UD8.B1 74.85,30.68 v2(74.84,30.68) ; v2(136.97,16.13) 136.97,16.71 UD4.R9 ; 103.42,14.69 102.57,14.69 UD1.R9 ; UD3.R9 125.9,17.28 ; UD6.R9 v2(56.49,21.53)
  TOP w0.305: v2(49.11,32.47) 49.29,32.28 UD6.B1 ; UD5.R9 44.96,21.88 45.43,21.42 v2(45.43,21.37) ; 129.62,28.06 UD4.B1
  TOP w0.381: v2(136.97,16.13) 136.97,14.98 CD48.1 136.63,14.13 v2(136.92,14.13) ; UD1.B1 95.61,24.76 95.37,25 v2(95.27,25) ; 82.36,19.17 CD104.1 CD105.1 83.52,16.96 83.61,16.87 CD106.1 84.22,17.53 v2(84.19,17.56) ; v2(130.37,13.9) 127.51,13.9 CD49.1 127,16.17 125.9,17.28
  TOP w0.508: 117.34,27.49 117.34,28.66 118.66,29.98 123.63,29.98 126.27,32.62 127.21,32.62 129.39,30.43 129.39,28.29 129.62,28.06
  IN1 w0.508: v2(70.32,17.76) 71.44,16.64 76.37,16.64 77.42,15.59 78.92,15.59 79.57,14.94 80.94,14.94 81.3,15.3 81.3,15.74 83.11,17.56 v2(84.19,17.56) 85.03,16.72 85.03,14.05 86.25,12.83 87.44,12.83 88.05,13.44 88.05,15.25 v2(88.87,16.06)
  IN2 w0.381: v2(70.26,27.77) 73.17,30.68 v2(74.84,30.68)
  IN2 w0.508: v2(88.87,16.06) 88.94,16.13 89.12,16.13 90.39,17.41 90.39,21.09 91.05,21.75 92.95,21.75 95.27,24.06 v2(95.27,25) 95.38,25 95.86,25.47 95.86,25.54 96.61,26.29 96.82,26.5 97.31,26.5 98.7,25.1 100.98,25.1 101.61,25.74 104.59,25.74 v2(105.57,24.76) ; v2(58.66,27.62) 58.66,29.69 61.66,32.68 v2(61.66,32.68) ; v2(130.37,13.9) 130.37,13.09 131.4,12.06 132.32,12.06 132.36,12.02 135.76,12.02 136.92,13.18 v2(136.92,14.13)
  BOTTOM w0.254: v2(68.83,21.53) 69.08,21.28 69.08,20.43 68.94,20.29 CD101.1
  BOTTOM w0.305: v2(56.49,21.53) 56.46,21.49 CD99.1 CD100.1 57.27,21.06 CD98.1 ; CD103.1 70.16,19.93 CD102.1 CD101.1
  BOTTOM w0.381: CD96.1 46.36,20.97 46.14,20.76 CD95.1 CD97.1 v2(45.43,21.37) ; v2(114.8,13.26) 114.74,13.33 114.69,13.33 114.51,13.51 114.51,13.56 114.43,13.63 CD52.1 114.43,14.38 CD46.1 ; v2(104.99,14) 104.82,14.18 104.35,14.18 CD43.1 CD42.1 104.32,15.44 CD44.1 ; CD46.1 116.27,14.41 CD47.1 ; CD46.1 CD45.1 ; CD103.1 v2(70.26,27.77) ; v2(136.97,16.13) 136.72,16.39 CD51.1 136.29,16.4 CD53.1
  BOTTOM w0.508: CD96.1 47.1,20.97 47.67,20.4 47.67,18.93 48.21,18.38 51.31,18.38 51.88,18.95 ; 69.82,18.14 69.94,18.14 v2(70.32,17.76) ; 69.82,18.14 69.82,18.71 70.26,19.16 CD103.1 ; 69.82,18.14 66.89,18.14 66.67,18.37 ; 64.02,18.7 63.44,18.7 62.22,19.92 60.65,19.92 60.32,20.25 59.35,20.25 58.54,21.06 CD98.1 57.75,23.73 58.66,24.64 v2(58.66,27.62) ; 54.25,18.22 54.25,21.01 54.76,21.53 v2(56.49,21.53) ; CD47.1 119.83,14.2 120.11,13.92 120.51,13.92 ; v2(37.55,31.51) 37.09,31.51 36.62,31.04 36.62,25.35 37.23,24.74 39.06,24.74 40.05,23.75 40.05,21.72 40.43,21.34 40.43,18.19 40.85,17.77 42.6,17.77 42.99,18.17 42.99,20.83 43.63,21.47 45.32,21.47 v2(45.43,21.37) 45.43,23.46 47.27,25.3 47.27,31.7 48.03,32.47 v2(49.11,32.47) ; CD50.1 CD44.1 ; 123.92,13.98 130.29,13.98 v2(130.37,13.9)
  vias: v1(116.95,13.8)
+2.5VP: length 2.9
  TOP w0.117: PJ252.1 108.29,8.1 v1(108.25,8.15)
+3V_AUDIO: length 35.7
  IN2 w0.508: v2(20.04,51.08) 19.03,50.07 19.03,43.41 22.27,40.18 22.27,35.85 21.25,34.83 21.25,33.29 19.79,31.83 15.88,31.83 14.02,33.69 12.8,33.69 12.07,32.95 v2(12.07,32.63)
  BOTTOM w0.381: RT75.1 11.84,32.25 11.92,32.33 11.92,32.4 12.11,32.59 12.11,32.63 v2(12.07,32.63)
  BOTTOM w0.508: QA1.1 20.36,50.5 20.31,50.45 RA58.1 19.54,50.57 v2(20.04,51.08)
+3V_CMOS:
  vias: v2(51.8,61.01) v2(51.96,59.85) v2(52.56,60.03) v2(53.15,60.69) v3(54.27,64.34)
+3V_DMIC: length 4.4
  TOP w0.127: v3(51.11,56.54) R359.2
  TOP w0.381: R359.2 R360.2
  TOP w0.508: v2(51.88,59.21) 51.58,58.91 51.32,58.91 R360.2
  BOTTOM w0.254: v2(51.88,59.21) 51.68,59.01 JEDP1.35
+3V_FP: length 6.7
  TOP w0.127: v3(106.86,10.15) 106.37,10.64 v2(106.35,10.64)
  TOP w0.508: v2(106.35,10.64) 106.28,10.64 105.9,10.25 CFP1.1 105.9,10.08 106.43,9.54 RFP4.2 106.47,9.15 106.47,8.49 106.25,8.27 RFP2.2 RFP3.2
  BOTTOM w0.305: v2(106.35,10.64) 106.07,10.92 JFP1.1
+3V_SD_R: length 2.3
  TOP w0.381: CF7.1 194.86,19.77 v2(194.86,21.16)
  TOP w0.508: v2(194.86,21.16) 194.86,21.35 v2(194.42,21.8)
  vias: v1(167.55,27.64) v2(168.23,27.89) v2(168.19,27.31) v2(200,29.99) v2(200,29.36)
+3VALW: length 297.7
  TOP w0.356: v2(167.87,29.99) CC114.1 167.47,30.59 167.41,30.64 UC23.5 ; UC8.5 167.41,36.99 167.42,37 CC26.1 167.87,36.87 v2(167.87,36.4)
  TOP w0.381: R4012.2 175.56,48.14 175.68,48.27 v2(175.68,48.32) ; v2(193.59,41.76) 193.59,41.45 193.86,41.18 R56.2 ; CF8.1 v2(167.11,18.53) ; R57.2 v2(186.03,48.98) ; v2(28.87,45.19) 28.77,45.29 CF9.1 ; v2(179.01,49.23) 178.79,49.01 R4011.2 R4010.2 ; CF10.1 v2(60.94,57.53) ; v2(182.01,48.98) 182.35,48.63 R55.2
  TOP w0.508: v2(168.93,74.03) 169.32,74.42 PR719.1 ; RC55.1 172.03,43.56 171.07,44.52 UC7.5 170.62,44.52 v2(170.22,44.13) ; R359.1 50.19,54.96 50.96,54.2 R4015.1 51.63,54.34 v1(52.87,55.58) 52.87,56.57 53.89,57.59 53.89,58.36 R4014.1 54.38,58.68 55.41,59.71 55.41,59.83 v2(55.42,59.83) ; v2(191.66,49.1) 192.12,49.1 192.6,48.62 R4022.2 192.83,48.62 194.05,48.62 195.22,47.45 195.22,47.07 196.03,46.26 196.03,43.5 194.75,42.23 194.05,42.23 v2(193.59,41.76) ; RC608.1 84.59,72.23 84.09,72.73 80.43,72.73 75.05,78.11 75.05,81.36 v2(74.57,81.84) ; v2(190.35,47.96) 189.96,48.35 R67.1
  TOP w1.016: 126.89,11.74 134,11.74 134.27,11.47 137.37,11.47
  IN1 w0.508: v2(195.43,21.61) 195.81,21.23 197.78,21.23 198.42,21.86 198.42,25.66 v2(197.58,26.5) ; v2(160.84,75.43) 160.06,74.66 155.77,74.66 153.2,77.22 149.12,77.22 144.91,81.43 143.75,81.43 v2(143.37,81.81) 139,86.17 126.4,86.17 125.77,85.54 105.43,85.54 103.97,84.08 99.72,84.08 97.77,82.12 74.84,82.12 v2(74.57,81.84) ; v2(186.03,48.98) 187.19,48.98 188.71,50.5 190.26,50.5 v2(191.66,49.1) ; v2(31.86,52.79) 31.35,52.28 29.7,52.28 29.18,52.8 25.42,52.8 24.91,52.29 24.91,49.25 v2(25.06,49.1)
  IN2 w0.508: v2(55.42,59.83) 55.41,59.83 v2(55.41,59.84) ; v2(55.41,59.84) 56.98,61.4 59.7,61.4 v2(61.42,63.12) ; v2(191.66,49.1) 191.61,49.1 190.47,47.96 v2(190.35,47.96) ; v2(123.42,79.9) 122.91,79.9 122.14,79.13 113.16,79.13 112.18,80.11 v2(111.61,80.11)
  IN3 w0.457: v2(132.7,77.37) 131.77,78.3
  IN3 w0.508: 131.77,78.3 126.45,78.3 125.84,78.91 125.84,79.58 125.26,80.16 123.68,80.16 v2(123.42,79.9)
  BOTTOM w0.254: v2(168.93,74.03) PR1812.1 170.05,75.15 PC726.1 170.16,75.29 170.16,77.11 170.62,77.56 170.62,77.82 PU1802.12
  BOTTOM w0.3: UC1.AM16 v2(113.57,64) UC1.AL17
  BOTTOM w0.305: v2(111.61,80.11) 111.81,80.31 RC60.2 ; JIO1.22 194.99,22.24 v2(195.43,21.61)
  BOTTOM w0.381: 136.13,63.76 136.08,63.76 135.53,64.32 135.53,64.72 135.09,65.16 RC48.1
  BOTTOM w0.508: v2(84.75,66.55) 84.4,66.2 RC620.2 RC45.1 ; RC593.1 132.05,75.41 RC621.2 132.06,76.66 132.63,77.23 132.63,77.3 v2(132.7,77.37) 137.55,77.37 RC98.1 RC99.1 142.46,77.28 143.37,78.19 v2(143.37,81.81) ; RC611.1 123.37,79.85 v2(123.42,79.9) ; v2(197.58,26.5) 197.59,26.5 198.24,27.15 198.24,28.78 196.16,30.87 196.16,32.97 193.64,35.49 193.64,41.71 v2(193.59,41.76) ; 116.12,10.29 116.55,10.72 116.55,10.8 116.93,11.18 118.96,11.18 119.32,11.54 121.66,11.54 122.34,12.22 v2(122.42,12.22) v2(123.03,12.22) ; v2(139.09,12.03) 139.09,10.87 138.04,9.82 RKBL3.2 ; 161.4,88.48 PC615.1 161.67,87.53 161.67,87.24 v2(161.62,87.19) ; v2(139.36,65.11) 139.12,64.87 139.12,64.15 RC610.1 138.67,63.71 138.62,63.76 RC47.1 136.13,63.76 135.94,63.57 RC625.1 ; RC624.1 RC48.1 ; RTP8.2 117.12,9.64 118.06,8.7 RTP5.1 119.02,8.54 QTP1.3 ; RA58.2 QA1.3 24.63,49.54 v2(25.06,49.1)
  vias: v1(86.34,69.11) v1(164.57,75.52) v2(38.23,50.27) v2(38.23,49.69) v2(38.23,49.08) v2(38.79,50.55) v2(38.79,49.97) v2(38.79,49.38) v2(52.87,90.07) v2(52.9,89.44) v2(52.92,88.78) v2(53.41,89.79) v2(53.43,89.11) v2(53.41,88.37) v2(53.89,90.15) v2(53.92,89.44) v2(53.89,88.7) v2(53.94,88.12) v2(62.03,63.12) v2(62.5,63.76) v2(138.46,12.03) v2(167.23,65.41) v2(167.65,65.82) v2(167.67,64.97) v2(167.92,63.95) v2(168.07,64.53) v2(168.08,65.39) v2(168.49,64.95) v2(168.49,64.12) v2(168.49,63.29) v2(168.9,64.53) v2(168.9,63.7) v2(168.9,62.87) v2(169.32,64.12) v2(169.32,63.29) v2(169.32,62.46) v2(169.73,63.7) v2(169.73,62.87) v2(169.73,62.04) v2(170.15,63.29) v2(170.15,62.46) v2(170.15,61.63) v2(170.37,30.59) v2(170.56,62.87) v2(170.56,62.04) v2(170.98,62.46) v2(172.1,56.14) v2(172.49,55.68)
+3VALW_3VS: length 2.1
  BOTTOM w0.117: v3(56.44,95.88) 56.27,95.72 54.37,95.72
+3VALW_EC: length 67.1
  TOP w0.127: L1.1 194.42,30.55 v3(194.78,30.92)
  TOP w0.203: UEC1.33 177.2,28.66 177,28.46 ; v2(176.93,35.11) 176.8,35.23 UEC1.22 ; UEC1.9 174.35,40.43 ; UEC1.125 v2(178.4,44.05)
  TOP w0.305: C233.1 v2(176.25,46.92) ; R60.2 v2(179.11,26.18)
  TOP w0.356: 174.35,40.43 174.32,40.4 C69.1 173.66,41.43 174.01,41.78 v2(174.01,41.79)
  TOP w0.381: L1.1 193.79,30.52 193.79,30.21 193.31,29.72 193.31,28.84 192.93,28.46 192.43,28.46 192.37,28.53 190.08,28.53 v2(190.01,28.45) ; R3999.2 177.66,48.6 177.66,49.03 v2(177.61,49.08)
  TOP w0.508: 177,28.46 176.64,28.1 C68.1 176.28,27.78 v2(175.81,28.25)
  IN1 w0.381: v2(190.01,28.45) 189.75,28.45 188.03,30.18 184.62,30.18 184.31,29.86 181.08,29.86 177.74,33.2 175.81,33.2
  IN1 w0.508: v2(179.11,26.18) 179.11,26.95 178.71,27.36 177.09,27.36 176.2,28.25 v2(175.81,28.25) 175.81,33.99 v2(176.93,35.11) 176.93,35.15 175.48,36.6 175.48,40.95 174.64,41.79 v2(174.01,41.79)
  IN3 w0.508: v2(176.25,46.92) 176.25,47.19 177.54,48.47
  BOTTOM w0.508: v2(176.93,35.11) 176.83,35.21 176.83,35.96 179.52,38.65 179.52,41.38 178.4,42.5 v2(178.4,44.05)
  vias: v2(191.37,45.48) v2(191.37,44.79)
+3VALWP: length 29
  TOP w0.117: v2(173.46,59.43) v1(173.46,58.82)
  TOP w0.254: v2(173.88,69.17) 174.2,68.85 174.39,68.85 PU301.11
  IN1 w0.178: v2(172.32,69.82) 172.18,69.68 172.17,69.68 169.18,66.68 169.18,64.9 171.67,62.41 171.67,61.22 v2(173.46,59.43)
  IN1 w0.508: v2(173.88,69.17) 173.84,69.21 172.37,69.21 169.65,66.49 169.65,65.1 172.14,62.61 172.14,61.66 v2(173.98,59.82)
  vias: v1(172.63,60.28) v1(175.3,59.07)
+3VDD_CODEC: length 7
  TOP w0.381: v2(9.27,31.99) 9.27,32.25 v3(10.63,33.6) 10.63,33.58 10.88,33.33 11.57,33.33 11.84,33.6 RA21.2
  BOTTOM w0.203: 9.93,31.65 9.93,31.7 10.62,32.4 UA1.3
  BOTTOM w0.305: v2(9.27,31.99) 9.39,31.87 9.39,31.27 CA22.1 9.5,31.22 9.93,31.65
+3VL: length 245.3
  TOP w0.203: 184,46.29 UEC1.111
  TOP w0.254: v2(177.83,71.68) 177.82,71.66 177.82,71.3 PR303.1 ; 80.09,9.04 79.73,8.68 79.73,6.85 81.02,5.57 R63.1 R62.1 81.02,3.57 80.47,3.03 55.66,3.03 55.35,3.33 v2(55.35,3.56)
  TOP w0.305: v2(184.13,48.98) 184.01,48.86 184.01,48.47 R66.1
  TOP w0.381: R65.1 193.77,31.55 193.77,31.5 193.41,31.15 v2(193.26,31.15) ; v2(185.46,46.82) 185.46,47.12 C234.1 184,46.29 ; R4023.2 192.98,33.84 193.56,33.25 v2(193.64,33.25)
  TOP w0.508: RUS4.1 186.4,23.34 186.65,23.08 186.69,23.08 187.07,22.7 187.07,22.66 187.46,22.27 187.46,21.73 187.07,21.34 187.07,20.21 ; 105.44,6.93 104.63,6.11 100.9,6.11 96.57,10.44 93.06,10.44 92.66,10.05 90.55,10.05 90.01,9.5 v1(87.35,9.5) 83.91,9.5 83.38,8.97 80.15,8.97 79.58,9.54 79.58,11.7 80.09,12.21 PR8.2 80.37,13.61 81.13,14.37 83.21,14.37 83.72,14.88 83.75,14.88 v2(83.76,14.89) ; 105.44,6.93 RFP2.1 ; 105.44,6.93 105.65,6.71 106.34,6.71 106.44,6.61 112.56,6.61 112.82,6.34 113.2,6.34 113.48,6.34 113.82,6 121.98,6 122.36,6.38 127.41,6.38 127.54,6.51 134.09,6.51 135.41,7.83 141.32,7.83 142.61,9.12 143.33,9.12 144.87,9.12 147.69,11.95 147.69,15.81 148.66,16.77 149.02,16.77 v2(165.09,16.77) ; v2(200.07,31.9) 200.07,31.27 R4026.2 ; 187.07,20.21 187.1,20.24 RUS1.1 188.56,20.08 189.51,19.13 v2(189.97,19.13) ; 187.07,20.21 187.07,19.49 v3(187.24,19.32)
  IN1 w0.254: v2(194.22,46.37) 194.11,46.49 ; v2(195.05,45.74) 194.62,45.74 193.89,45.01 193.89,42.8 194.43,42.27 194.43,41.23 193.49,40.29 193.49,34.5 194.5,33.48 194.5,33.12 193.26,31.88 v2(193.26,31.15) 195.55,31.15 196.4,30.29 198.27,30.29 199.88,31.9 v2(200.07,31.9)
  IN2 w0.254: v2(193.26,31.15) 193.26,32.83 193.64,33.22 v2(193.64,33.25)
  IN2 w0.508: v2(165.09,16.77) 168.98,16.77 170.65,15.09 180.74,15.09 182.81,17.16 188.45,17.16 188.64,16.97 189.84,16.97 190.35,17.48 190.35,18.75 v2(189.97,19.13)
  IN3 w0.508: v2(193.26,31.15) 193.26,31.02 192.29,30.05 191.76,30.05 191.14,29.43 191.14,26.82 191.81,26.14 191.81,22.94 191.68,22.81 191.68,22.78 190.73,21.82 190.69,21.82 189.97,21.1 v2(189.97,19.13)
  BOTTOM w0.254: v2(55.35,3.56) 55.21,3.42 54.39,3.42 54.18,3.62 PRB29.1 54.16,4.82 PRB31.1
  BOTTOM w0.305: JIO1.36 188.7,19.2
  BOTTOM w0.508: PR14.2 84.19,15.37 83.76,14.94 v2(83.76,14.89)
  BOTTOM w1.016: 182.29,59.77 182.29,62.82 183.42,63.95 183.42,69.3 183.36,69.45 183.35,69.47 182.25,70.57 182.25,72.73 181.14,73.84 179.57,73.84
  vias: v2(170.97,70.86) v2(171.38,70.43) v2(182.27,58.13) v2(182.29,57.49) v2(195.05,46.37) v2(195.05,45.1)
+3VLP:
  vias: v1(172.76,68.66)
+3VS: length 390.4
  TOP w0.305: R64.2 173.36,35.37 174.21,36.23 v2(174.21,36.43)
  TOP w0.381: RC5.2 77.12,58.26 v2(76.22,59.16) ; v2(79.04,60.38) 79.04,60.84 80.33,62.13 80.33,62.54 80.75,62.96 RC4.2
  TOP w0.508: RC63.1 65.52,85.48 66.03,84.97 RC62.1 v2(67.22,84.97) ; v2(19.04,74) 18.39,73.35 QH1.5 QH1.2 18.39,69.87 17.89,69.36 16.74,69.36 16.23,69.87 RH13.1 ; v2(189.59,15.13) 190.24,15.78 RC91.2 ; v2(81.87,54.83) 81.87,55.75 82.31,56.19 82.31,59.03 83.23,59.95 83.73,59.95 v2(84.62,60.84) ; v2(141.08,79.71) 145.08,79.71 v1(150.6,85.23) 162.68,97.31 164.89,97.31 v2(166.26,95.94) ; v2(172.21,25.2) 172.21,21.63 167.74,17.16 166.03,17.16 165.33,17.86 148.85,17.86 147.06,16.07 147.06,12.21 145.14,10.29 141.98,10.29 140.2,8.51 135.2,8.51 133.82,7.14 127.28,7.14 127.15,7.02 v2(122.98,7.02) 122.1,7.02 121.87,6.79 121.84,6.79 121.69,6.64 114.08,6.64 113.74,6.98 113.46,6.98 113.09,6.98 112.82,7.24 106.7,7.24 106.59,7.36 106.25,7.36
  IN1 w0.508: v2(19.8,61.12) 19.8,62.49 18.99,63.3 18.99,68.42 20.48,69.91 v2(22.75,69.91) ; v2(172.21,25.2) 172.21,25.75 172.28,25.81 ; 172.28,25.81 172.39,25.93 175.24,25.93 176.07,25.1 181.02,25.1 181.19,24.92 184.01,24.92 184.32,25.23 184.32,28.15 185.12,28.95 186.67,28.95 187.04,28.58 187.04,28.02 187.47,27.59 188.08,27.59 188.29,27.37 188.29,27.37 188.41,27.26 191.49,27.26 v2(191.75,27.51) ; 172.28,25.81 172.28,28.11 173.85,29.69 173.85,29.88 175.17,31.2 175.17,35.77 174.51,36.43 v2(174.21,36.43) ; v2(84.62,60.84) 84.06,61.4 80.05,61.4 v2(79.04,60.38)
  IN2 w0.508: v2(202.42,31.51) 206.39,27.54 206.39,23.91 205.02,22.53 205.02,22.21 197.89,15.08 190.52,15.08 190.47,15.13 v2(189.59,15.13) ; v2(19.04,74) 18.77,73.73 18.77,72.11 20.98,69.91 v2(22.75,69.91) 25.23,69.91 v2(27.28,71.96) ; v2(67.22,84.97) 65.88,86.31 63.61,86.31 62.65,85.36 59.94,85.36 ; v2(84.62,67.82) 84.55,67.82 83.99,67.26 83.99,62.64 84.62,62.01 v2(84.62,60.84)
  IN3 w0.508: v2(151.78,66.26) 151.67,66.38 149.7,66.38 144.38,71.69 144.24,71.69 144.21,71.73 143.7,71.73 143.67,71.69 143.66,71.69 v2(143.54,71.57) ; v2(174.21,36.43) 174.45,36.43 174.95,36.94 174.95,39.71 174.59,40.07 173.82,40.07 170.93,42.96 170.53,42.96 169.52,43.96 169.52,45.38 170.86,46.72 170.86,47.99 172.51,49.64 v2(175.28,49.64) 176.71,51.07 180.61,51.07 180.88,50.81 v2(180.89,50.81) ; v2(76.22,59.16) 74.97,60.41 74.11,60.41 73.94,60.58 73.88,60.58 73.87,60.58 71.59,60.58 70.96,61.22 70.96,61.88 69.88,62.96 66.68,62.96 65.5,64.14 65.5,65.11 65.19,65.41 64.41,65.41 63.69,64.7 63.69,63.25 61.38,60.94
  BOTTOM w0.254: UTS1.1 174.66,50.26 173.87,49.47 CTS5.1
  BOTTOM w0.3: UC1.AM17 113.57,63.2 UC1.AL18
  BOTTOM w0.305: UC1.AM17 114.5,63.6 v2(114.57,63.53)
  BOTTOM w0.381: RC616.1 130.72,71.81 130.72,71.23 RC614.2 ; RC28.1 84.67,52.96 84.37,52.66 83,52.66 82.69,52.96 82.69,54.01 v2(81.87,54.83) ; v2(22.75,69.91) 22.97,69.91 23.06,69.81 23.42,69.81 23.73,70.12 QH2.2 QH2.5 ; RC56.1 134.65,64.46 134.7,64.41 v2(134.98,64.41)
  BOTTOM w0.508: v2(76.22,59.16) 76.22,60.33 77.21,61.32 78.53,61.32 79.04,60.81 v2(79.04,60.38) ; PR828.2 90.55,100.43 v2(90.53,100.45) ; RTS7.1 v2(180.89,50.81) ; v2(143.65,62.26) 143.04,61.65 RC568.2 RC112.2 ; RC616.1 134.07,71.91 135.48,70.51 142.62,70.51 146.16,66.96 149.29,66.96 149.88,66.38 151.36,66.38 151.47,66.26 v2(151.78,66.26) ; v2(27.28,71.96) 27.23,71.91 26.7,71.91 RH23.1 26.64,72.71 RH24.1 ; v2(141.08,79.71) 141.08,79.88 140.57,80.39 UC22.5 140.73,80.92 142.28,80.92 142.73,81.37 142.73,82.07 143.1,82.44 143.63,82.44 144,82.07 144,72.23 143.62,71.85 143.62,71.65 v2(143.54,71.57) ; CTS5.1 174.44,49.26 174.46,49.28 174.67,49.28 175.02,49.64 v2(175.28,49.64) ; RC90.2 134.36,61.27 134.36,62.01 v2(134.37,62.02) ; RC29.1 130.21,65.22 129.39,64.4 129.39,63.33 129.81,62.91 132.08,62.91 132.97,62.02 v2(134.37,62.02) ; RC57.1 134.36,62.03 v2(134.37,62.02) ; v2(84.62,60.84) RC31.1 ; RC85.1 137.52,62.13 137.98,62.59 v2(138.15,62.59) ; RTP7.1 123.26,7.02 v2(122.98,7.02) ; RC89.2 RC574.2 v2(84.62,67.82)
  vias: v1(43.79,60.6) v1(148.63,63.07) v2(40.69,61.42) v2(41.14,62.03) v2(41.53,60.71) v2(55.21,73.28) v2(55.48,97.03) v2(55.59,72.7) v2(55.97,73.28) v2(56.07,97.61) v2(56.07,97.03) v2(56.18,72.7) v2(56.65,98.19) v2(56.65,97.61) v2(56.65,97.03) v2(56.76,72.7) v2(145.84,63.02) v2(197.98,31.43) v2(198.61,31.45)
+3VS_SSD1: length 1.3
  TOP w0.381: CSD2.1 32.49,41.93 v2(32.55,41.99)
  vias: v1(31.66,44.34) v1(32.3,42.56) v1(32.43,40.34) v2(30.29,22.33) v2(30.29,21.7) v2(31.3,45.14) v2(31.78,45.48) v2(32.33,45.74) v2(32.43,39.53) v2(32.43,38.94) v2(32.43,38.36)
+3VS_SSD2: length 9.7
  TOP w0.127: v2(59.68,57.41) v1(60.35,58.08) ; v2(73.65,57.69) v1(73.65,56.99)
  TOP w0.381: USD2.5 68.96,59.09 v2(68.62,59.09)
  BOTTOM w0.305: JSSD2.2 55.91,57.22 v2(56.18,57.49) 56.41,57.26 JSSD2.4 ; JSSD2.16 59.41,57.13 v2(59.68,57.41) 59.91,57.18 JSSD2.18 ; JSSD2.14 58.91,57.17 v2(58.66,57.41) 58.41,57.15 JSSD2.12
  vias: v1(57.32,56.98) v2(27.4,47.81) v2(27.97,48.14) v2(27.94,47.53) v2(44.53,52.38) v2(44.56,51.64) v2(45,52.02) v2(73.04,57.69)
+3VS_TP: length 8.5
  TOP w0.127: v1(126.22,10.31) 126.34,10.31 126.47,10.43 v2(126.47,10.94)
  BOTTOM w0.305: 127.38,11.26 127.81,11.26 128.03,11.48 JTP1.8
  BOTTOM w0.508: 121.68,10.6 121.38,10.9 119.75,10.9 118.72,9.87 RTP8.1 ; 125.39,10.75 125.39,10.76 126.29,10.76 v2(126.47,10.94) 126.53,10.94 126.86,11.26 127.38,11.26
+3VS_WLAN: length 5.4
  TOP w0.102: v1(168.38,46.5) 169.14,45.74 v1(169.9,45.74)
  TOP w0.127: v2(170.76,45.62) 170.02,45.62 v1(169.9,45.74)
  TOP w0.305: UWL22.5 171.22,32.26 170.92,31.96 170.92,31.77 v2(170.35,31.2)
  TOP w0.508: v2(170.76,45.62) 170.77,45.61 CWL1.1
  vias: v2(169.65,28.59) v2(169.7,49.58) v2(170.25,28.59) v2(170.28,49.58) v2(170.87,49.68) v2(170.86,49.09) v2(170.83,28.53) v2(170.86,27.93)
+5V_AUDIO: length 22.9
  IN1 w1.016: 24.3,9.67 23.59,10.38 23.59,20.73 21.34,22.98 21.34,25.04 16.87,29.51
  vias: v2(17.22,30.84) v2(17.57,29.99) v2(17.76,30.56) v2(25.11,8.45) v2(25.49,7.97) v3(16.62,32.53)
+5V_DISPLAY: length 10.7
  IN2 w0.508: v2(16.39,74.23) 16.41,74.25 17.38,74.25 18.14,75.01 20.36,75.01 21.17,74.2 v2(21.17,72.87) 21.09,72.78 21.09,70.97 v2(21.06,70.95)
  BOTTOM w0.508: v2(21.06,70.95) 21,70.88 RH25.1 ; v2(21.17,72.87) 20.91,72.87 20.4,72.36 RH26.1
  vias: v1(15.41,74.63) v2(16.39,74.87)
+5V_IN_PWR: length 5.9
  TOP w0.254: v2(42.05,82.09) 41.68,82.47 41.68,82.83 41.45,83.06 41.42,83.06 41.4,83.07 UT1.32
  TOP w0.508: RT37.1 36.49,77.83 v2(36.49,78.44)
  IN1 w0.508: v2(36.49,78.44) 36.49,79.48 36.03,79.94 v2(36.03,81.67)
  vias: v2(34.96,89.24) v2(35.55,89.23) v2(42.07,81.47)
+5VALW: length 454.7
  TOP w0.381: CF6.1 187.76,17.27
  TOP w0.457: R54.2 196.71,28.91 v2(196.71,28.34)
  TOP w0.508: v2(44.61,72.51) RT70.1 44.56,75.2 44.17,75.58 44.17,76.6 43.58,77.2 42.75,77.2 QT3.1 42.75,79.16 43.44,79.85 RT35.1 ; 166.84,57.87 165.37,57.87 164.28,56.77 v1(164.28,55.33) 164.28,53.55 165.1,52.73 165.82,52.73 v2(166.23,53.14) ; 166.84,57.87 166.84,59.72 163.74,62.82 162.92,62.82 162.47,62.38 v2(156.63,62.38) ; 166.84,57.87 167.78,56.93 169.36,56.93 169.79,57.36 172.25,57.36 173.47,56.14 174.77,56.14 176.52,57.89 v2(177.13,57.89) ; v2(100.47,93.09) 100.75,93.09 101.39,93.72 101.39,94.92 100.57,95.74 100.57,96.76 102.52,98.71 102.52,101.29 PR811.2 ; U9.5 198.81,23.69 199.75,22.75 v2(200.73,22.75) ; RKBL1.1 143.03,12.08 142.33,12.78 ; 119.54,12.2 119.23,12.51 119.23,13.42 119.61,13.8 120.56,13.8 121.25,13.11 127.07,13.11 127.55,12.63 134.37,12.63 134.64,12.36 136.35,12.36 136.77,12.78 141.44,12.78 ; 141.85,13.52 141.85,16.79 142.78,17.72 145.29,17.72 147.06,19.49 148.49,19.49 152.68,23.68 163.57,23.68 163.97,23.27 168.65,23.27 171.87,26.49 173.16,26.49 173.52,26.12 175.24,26.12 175.63,25.74 v2(177.16,25.74) ; v2(188.01,16.55) 188.01,17.02 187.76,17.27 ; 118.81,11.59 116.91,11.59 116.25,10.93 115.89,10.93 v2(115.51,10.55) ; v2(188.24,25.1) 188.17,25.02 185.96,25.02 185.02,24.08 184.06,24.08 183.09,25.05 180.45,25.05 v2(179.05,23.65)
  IN1 w0.508: v2(177.16,25.74) 176.49,26.4 176.49,26.98 175.99,27.49 175.56,27.49 175.17,27.87 175.17,29.07 v2(174.67,29.57) ; v2(45.83,85.27) 45.9,85.27 47.01,86.39 49.83,86.39 50.18,86.04 51.15,86.04 52.62,84.56 61.85,84.56 63.53,86.24 78.38,86.24 78.86,85.76 83.73,85.76 84.29,86.31 89.87,86.31 91.3,87.75 v2(91.3,92.04) ; v2(183.07,55.61) 182.59,55.12 180.2,55.12 177.44,57.89 v2(177.13,57.89)
  IN2 w0.508: 112.08,11.82 112.1,11.82 113.52,10.39 115.36,10.39 v2(115.51,10.55) ; 109.21,11.71 108.45,10.95 107.94,10.95 106.82,9.84 103.21,9.84 103.06,9.99 99.11,9.99 97.48,11.63 93.22,11.63 92.57,12.27 91.33,12.27 90.82,11.77 90.82,11.16 91.3,10.67 v2(91.58,10.67) ; v2(85.18,10.14) 84.5,9.45 76.88,9.45 69.97,16.36 68.47,16.36 67.76,15.65 47.44,15.65 46.12,14.33 44.75,14.33 43.6,15.47 36.29,15.47 32.48,19.28 25.54,19.28 24.93,18.67 v2(24.93,16.79)
  IN3 w0.508: 98.58,4.46 96.03,7.02 93.8,7.02 90.44,3.66 v2(90.44,2.85) ; v2(177.16,25.74) 177.16,25.12 178.63,23.65 v2(179.05,23.65) ; v2(156.32,75.39) 156.32,74.44 161.33,69.42 163.24,69.42 165.59,67.07 167.49,67.07 172.38,62.18 174.16,62.18 177.13,59.21 v2(177.13,57.89) ; v2(100.47,93.09) 100.04,92.66 100.04,92.1 100.03,92.09 100.03,91.94 99.12,91.04 92.31,91.04 v2(91.3,92.04)
  BOTTOM w0.254: U19.3 155.69,73.56 156.32,74.19 v2(156.32,75.39)
  BOTTOM w0.508: v2(98.95,5.52) 99.69,4.78 134.53,4.78 136.14,6.39 146.23,6.39 v2(147.31,7.47) ; v2(156.63,62.38) 158.98,64.72 R2752.2 ; PRM8.1 165.75,51.19 165.75,52.34 PRM6.1 166.23,52.88 v2(166.23,53.14) ; PR812.2 91.3,91.75 v2(91.3,92.04) ; v2(91.58,10.67) 90.54,9.63 85.69,9.63 v2(85.18,10.14) ; v2(183.07,55.61) 183.07,54.74 182.57,54.23 R74.1 182.39,53.32 183.13,52.58 183.44,52.27 183.44,50.8 182.91,50.27 182.91,48.24 181.65,46.98 181.65,44.91 182.29,44.27 182.29,42.9 182.87,42.32 182.87,38.26 179.39,34.78 179.39,33.23 177.28,31.12 176.22,31.12 174.67,29.58 v2(174.67,29.57)
  vias: v1(142.47,13.48) v1(198.1,27.01) v2(19.09,24.2) v2(19.09,23.61) v2(19.09,23.03) v2(25.72,16.79) v2(26.29,68.03) v2(26.31,16.79) v2(26.46,68.66) v2(26.86,67.89) v2(26.89,16.79) v2(27.03,68.5) v2(27.47,67.88) v2(27.61,68.47) v2(27.78,15.98) v2(27.78,15.4) v2(27.78,14.81) v2(27.78,14.23) v2(28.05,67.96) v2(28.11,73.04) v2(28.36,15.98) v2(28.36,15.4) v2(28.36,14.81) v2(28.36,14.23) v2(28.36,13.64) v2(28.62,72.6) v2(28.95,15.4) v2(28.95,14.81) v2(28.95,14.23) v2(28.95,13.64) v2(29.19,72.73) v2(29.53,14.81) v2(29.53,14.23) v2(29.53,13.64) v2(29.7,71.65) v2(30.14,72.03) v2(30.52,72.54) v2(44.42,85.98) v2(45.08,85.96) v2(45.15,85.3) v2(45.71,85.96) v2(45.83,84.6) v2(89.7,2.85) v2(90.06,2.36) v2(90.85,2.36) v2(91.18,2.85) v2(147.82,8.51) v2(147.82,7.93) v2(149.13,10.52) v2(149.09,9.91) v2(196.13,28.34) v2(196.13,27.75) v2(196.15,27.17) v2(196.71,27.75) v2(196.74,27.17) v2(197.3,28.34) v2(197.3,27.75)
+5VALW_5VS:
  vias: v3(49.69,91.88)
+5VALW_USB1:
  vias: v1(198.23,16.85) v1(199.56,19.96) v1(200.51,17.61) v2(192.07,20.91) v2(192.42,20.45) v2(197.69,19.56) v2(198.21,20.4) v2(198.21,19.82) v2(198.21,19.23) v2(198.8,20.4) v2(198.8,19.82) v2(198.8,19.23)
+5VALW_USB2:
  vias: v1(195.62,20.53) v1(197.15,21.48) v1(197.15,19.81) v2(196.17,22.51) v2(196.17,21.93) v2(196.75,23.09) v2(196.75,22.51) v2(196.75,21.93)
+5VALWP: length 23
  TOP w0.117: 23.73,9.99 v1(23.73,9.35)
  TOP w0.127: v1(27.98,9.35) 27.98,9.84 v2(28.18,10.04) ; v2(25.66,10.06) 25.63,10.03 v1(25.63,9.29)
  IN3 w0.254: v2(36.57,10.2) 35.56,9.2 34.64,9.2 33.84,10 31.82,10 31.49,9.67 28.77,9.67 28.41,10.04 v2(28.18,10.04)
  IN3 w0.508: v2(28.21,10.65) 28.52,10.65 28.99,10.18 31.28,10.18 31.61,10.51 34.05,10.51 34.81,9.75 35.33,9.75 35.97,10.38 v2(35.97,10.5)
  BOTTOM w0.254: PU501.14 35.79,11.39 35.87,11.31 35.87,10.6 v2(35.97,10.5) ; PR505.2 37.19,10.2 v2(36.57,10.2)
  vias: v2(24.92,12.55) v2(24.92,11.99) v2(24.92,11.43) v2(24.92,10.87) v2(25.08,10.04) v2(25.47,12.55) v2(25.47,11.99) v2(25.47,11.43) v2(25.47,10.87) v2(26.01,12.35) v2(25.99,11.71) v2(25.99,11.15) v2(25.99,10.59) v2(26.34,10.03) v2(26.5,11.99) v2(26.5,11.38) v2(26.5,10.82) v2(26.83,10.32) v2(27.34,10.06)
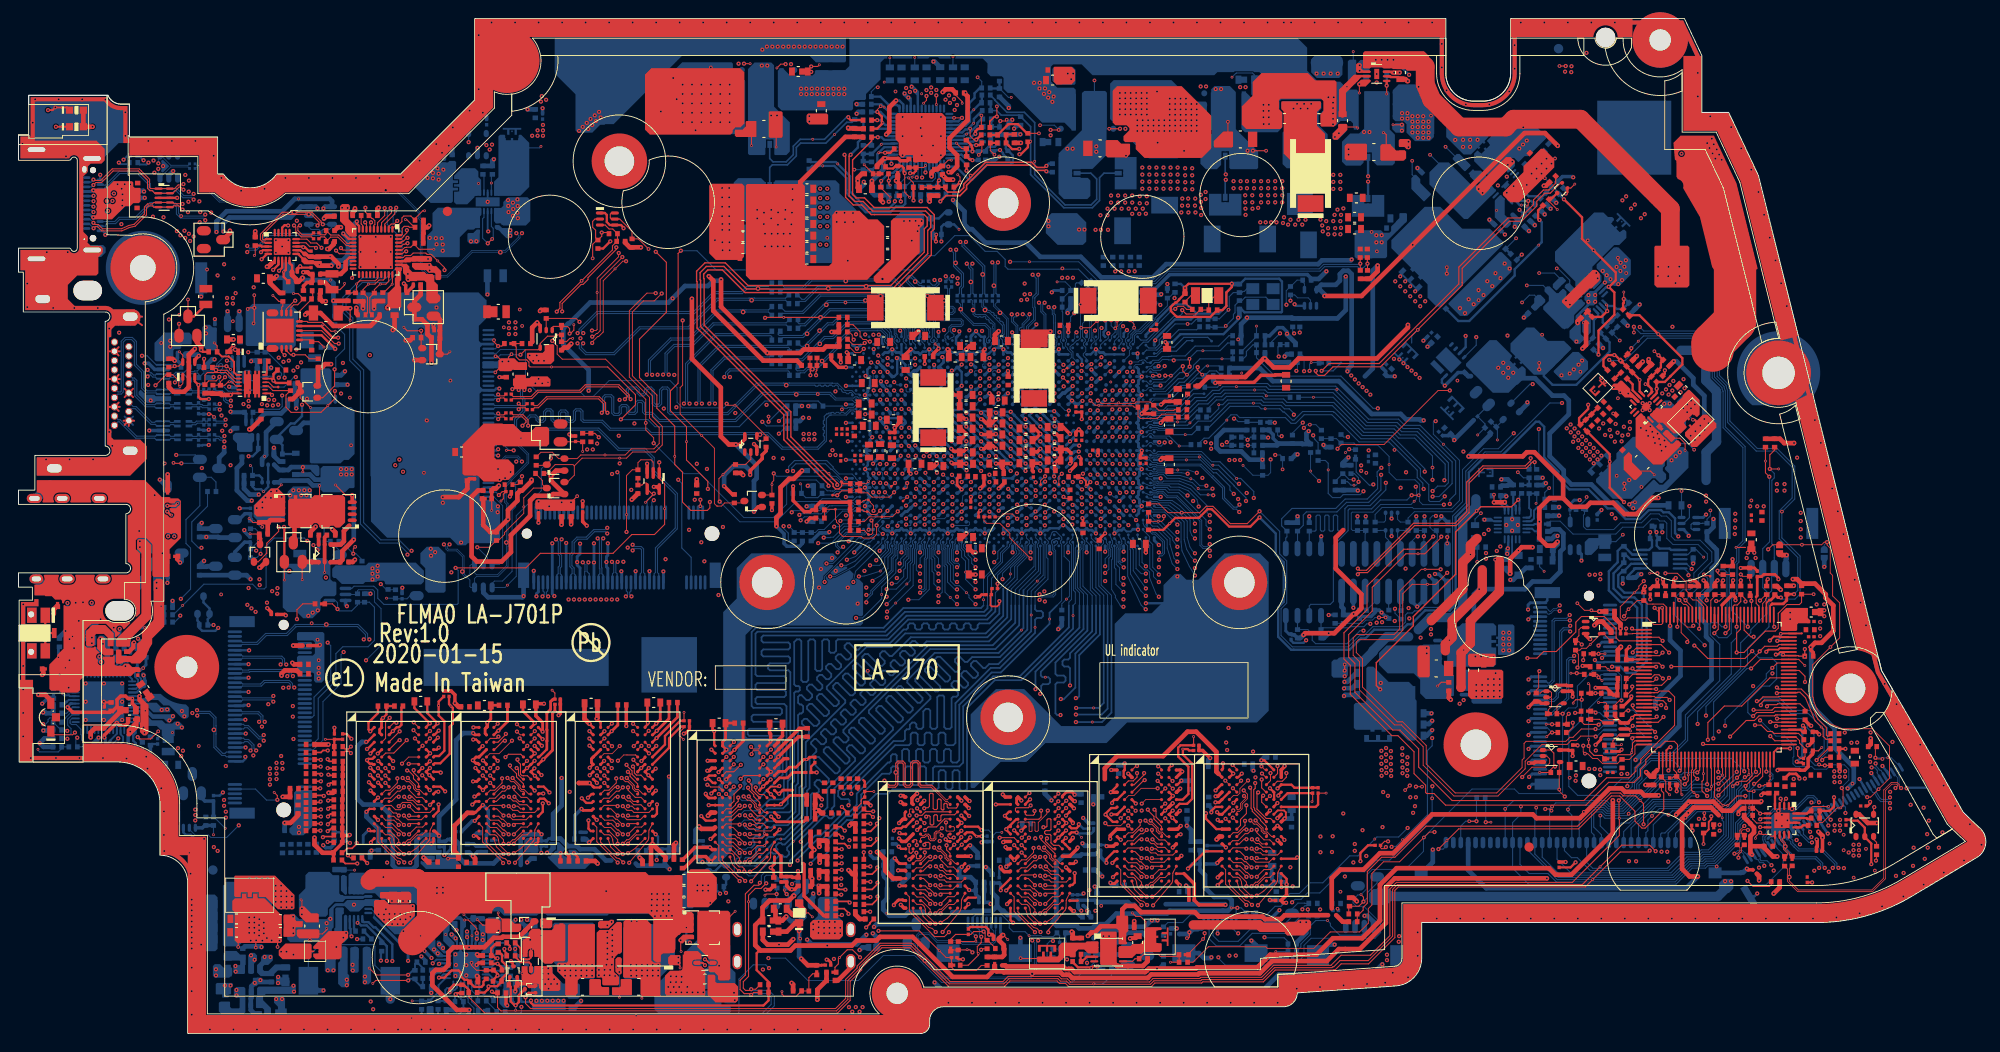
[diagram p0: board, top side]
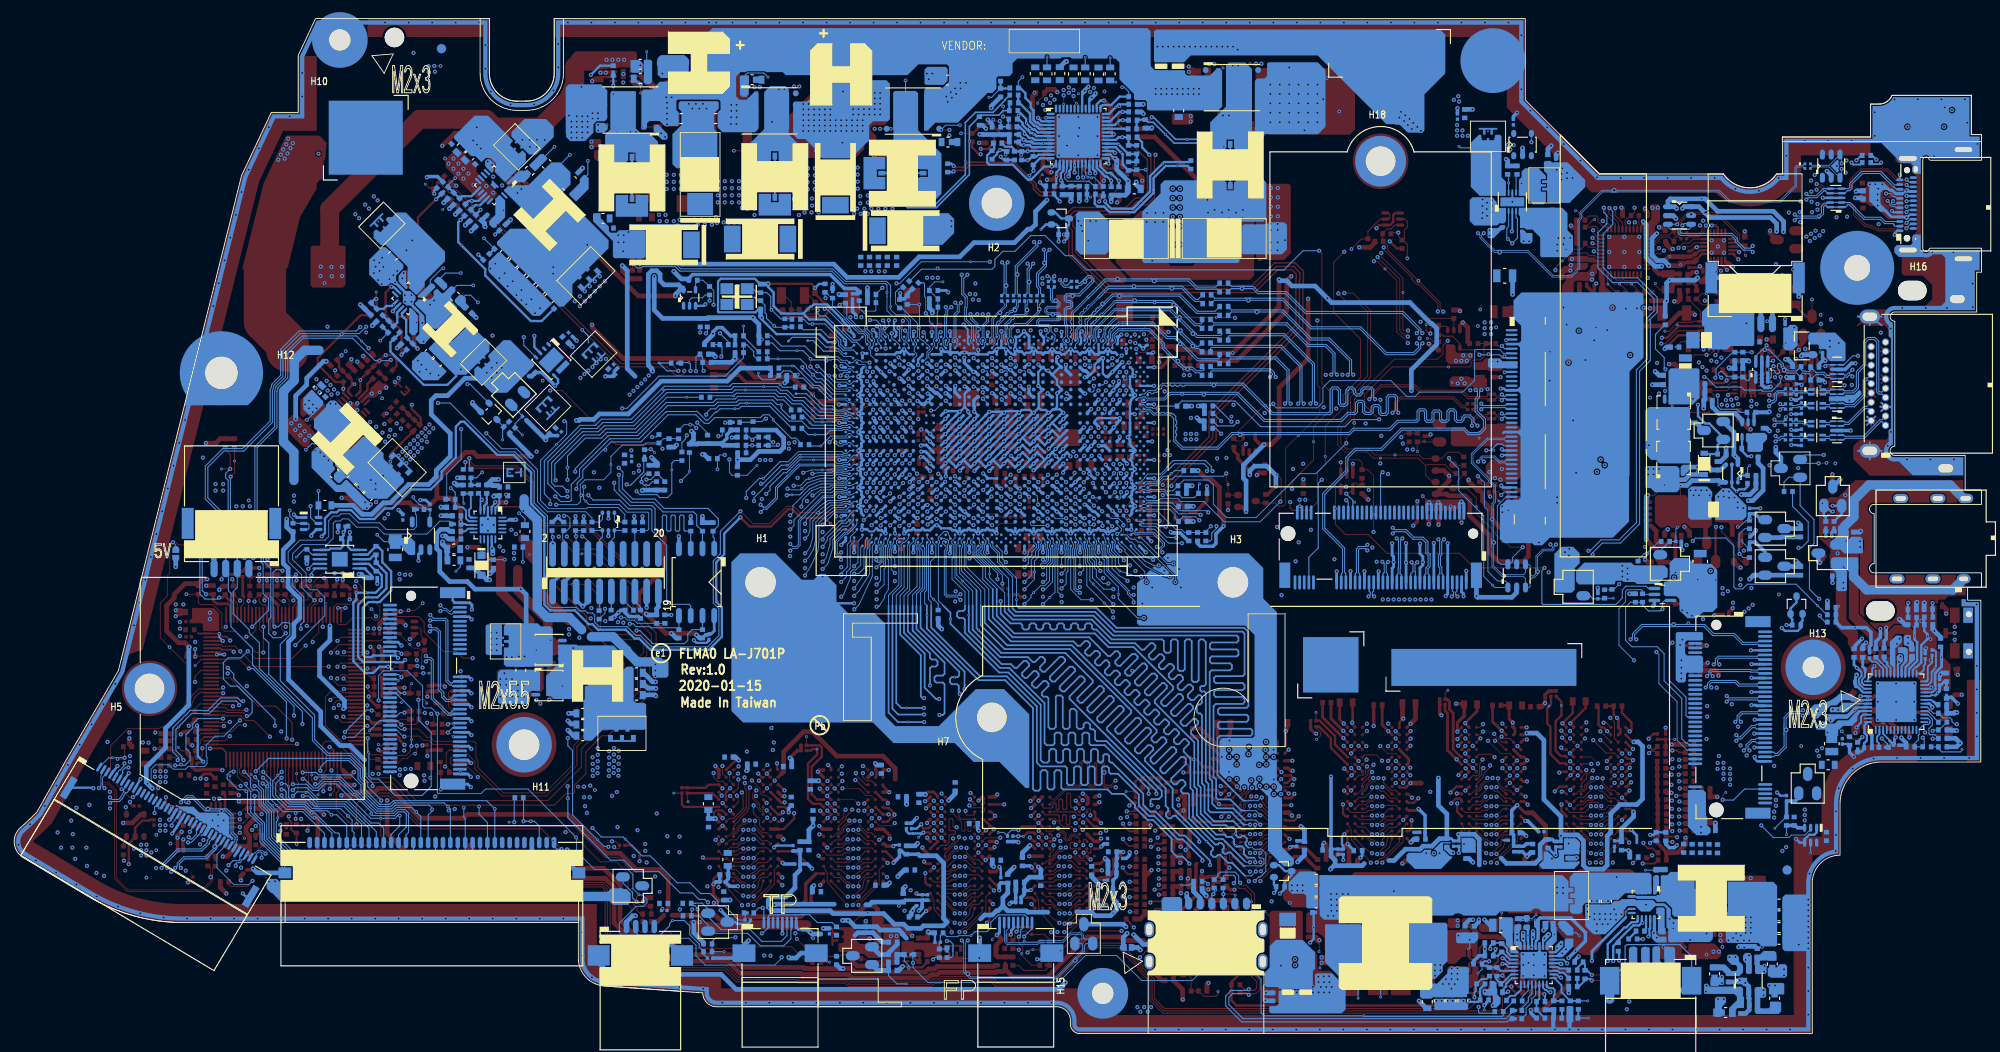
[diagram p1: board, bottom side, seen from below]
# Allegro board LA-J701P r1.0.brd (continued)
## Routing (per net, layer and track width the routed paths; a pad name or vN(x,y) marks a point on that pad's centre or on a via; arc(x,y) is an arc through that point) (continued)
+5VDDA_CODEC: length 8.4
  IN1 w0.381: v2(10.93,43.73) 10.93,42.66 13.47,40.12 13.47,40.1 13.48,40.09 13.48,38.77 13.5,38.74 v2(13.5,38.71)
  BOTTOM w0.381: RA9.2 11.41,42.34 10.93,42.83 v2(10.93,43.73)
+5VL: length 398.7
  TOP w0.508: LED4.2 3.49,36 2.88,36.61 v2(2.14,36.61) ; v2(7.99,98) LED3.2 LED2.2
  IN1 w0.508: v2(178.65,76.38) 177.41,77.63 173.57,77.63 170.09,81.11 161.92,81.11 158.05,77.24 154.15,77.24 153.53,77.86 149.38,77.86 145.17,82.06 144.08,82.06 139.33,86.81 126.14,86.81 125.52,86.19 104.12,86.19 102.76,87.55 102.76,91.09 104.92,93.25 104.92,96.63 103.63,97.92 101.79,97.92 99.99,99.73 94.61,99.73 93.08,101.25 90.14,101.25 89.48,100.59 79.85,100.59 75.84,96.58 72.14,96.58 61.17,85.6 52.75,85.6 51.66,86.69 v2(50.73,86.69) ; 14.7,30.71 14.96,30.98 14.96,34.05 14.7,34.32 14.7,35.32 15.21,35.83 19.47,35.83 21.4,37.76 21.4,40.44 19.15,42.69 19.15,53.65 20.49,54.99 20.49,56.01 17.26,59.24 17.26,60.76 15.48,62.54 15.48,72.37 17.06,73.94 17.06,75.65 16.25,76.46 v2(16.25,77.17) ; v2(192.12,62.24) 192.12,59.67 193.49,58.3 193.49,51.04 196.94,47.59 196.94,41.34 194.63,39.03 194.63,35.46 195.89,34.21 195.89,33.69 197.04,32.53 v2(197.27,32.53) ; 14.58,30.79 4.56,30.79 3.37,31.98 2.12,31.98 1.62,32.49 1.62,36.09 v2(2.14,36.61)
  IN1 w1.016: 14.7,30.13 14.7,30.06 20.2,24.56 20.2,22.5 21.58,21.12
  IN2 w0.508: 23.87,88.85 23.87,86.59 19.29,82.02 19.29,80.85 17.8,79.35 17.8,78.72 v2(16.25,77.17) ; 23.87,88.85 24.64,89.63 27.67,89.63 28.92,90.88 45.59,90.88 48.96,87.51 49.92,87.51 v2(50.73,86.69) ; 23.87,88.85 23.09,89.63 22.47,89.63 21.2,90.9 20.29,90.9 19.78,91.41 19.78,92.49 16.91,95.35 10.64,95.35 v2(7.99,98) ; v2(195.75,23.11) 195.75,23.47 198.19,25.91 198.19,26.79 197.91,27.07 197.91,28.61 196.47,30.04 196.47,31.81 197.2,32.53 v2(197.27,32.53) ; v2(192.12,62.24) 183.02,71.33 183.02,72.95 179.59,76.38 v2(178.65,76.38)
  IN2 w1.016: 28.44,7.09 25.05,7.09 21.17,10.97 21.17,18.92
  BOTTOM w0.203: v2(50.73,86.69) 50.68,86.75 U10.4
  BOTTOM w0.305: JIO1.20 195.59,23.19 195.62,23.14 v2(195.75,23.11)
  vias: v1(29.7,8.53) v2(21.1,20.15) v2(21.51,19.73) v2(28.36,8.84) v2(28.95,8.84)
+5VLP:
  vias: v1(34.33,9.35) v2(35.08,10.36) v2(35.39,10.86)
+5VS: length 281.6
  TOP w0.508: v2(93.73,97.17) 94.06,97.5 94.06,100.11 v2(94.78,100.83)
  TOP w2.032: 151.62,104.84 151.95,104.51 151.95,102.63 152.64,100.95 155.62,97.97 160.65,97.97 161.48,98.81 168.72,98.81 178.43,89.11 178.43,84.46
  IN1 w0.508: v2(146.61,105.24) 146.61,104.67 145.36,103.41 144.19,103.41 143.2,104.4 105.68,104.4 104.36,103.08 104.36,98.09 105.41,97.03 107.69,97.03 107.84,97.19 v2(108.21,97.19) ; v2(200.05,32.54) 198.18,32.54 197.51,31.86 196.41,31.86 195.25,33.01 195.25,33.41 195.25,33.85 194,35.11 194,39.29 196.31,41.6 196.31,47.33 194.58,49.05 193.69,49.05 192.45,50.3 192.45,51.85 190.76,53.54 v2(190.76,58.68) v2(189.93,58.68)
  IN2 w0.508: v2(108.21,97.19) 107.84,97.19 107.64,96.98 105.52,96.98 103.98,95.45 103.98,93.96 103.74,93.72 102.8,93.72 102.21,94.31 95.11,94.31 94.61,94.82 94.61,95.53 93.73,96.41 v2(93.73,97.17) ; v2(184.98,16.45) 185.9,15.53 186.11,15.74 188.87,15.74 189.02,15.89 190.61,15.89 190.78,15.72 196.68,15.72 205.17,24.21 205.17,27.86 200.49,32.54 v2(200.05,32.54)
  IN2 w1.016: 47.79,91.75 47.72,91.67 47.72,90.23 49.52,88.42 50.84,88.42 51.96,87.31 51.96,84.28 50.11,82.43 49.9,82.43 47.12,79.65 44.71,79.65 43.56,78.5 41.71,78.5 40.12,80.09 27.54,80.09 26.11,81.51 23.1,81.51 20.11,78.52 20.11,77.49
  BOTTOM w0.254: PU801.33 93.92,96.99 v2(93.73,97.17) 93.94,97.39 PU801.34 ; v2(94.78,100.83) 95.15,100.83 95.57,100.42 PU801.41
  BOTTOM w0.508: PR844.2 PR846.2 105.03,97.16 107.81,97.16 107.84,97.19 v2(108.21,97.19)
  BOTTOM w1.016: 184.32,15.58 183.56,14.81 148.16,14.81 147.79,15.18 146.94,15.18 QKBL1.3
  vias: v1(178.98,81.11) v1(183.43,18.05) v1(190.48,56.41) v2(20.22,76.31) v2(20.25,75.67) v2(44.18,92.47) v2(44.77,93.01) v2(44.77,92.43) v2(45.26,93.51) v2(45.38,92.92) v2(45.38,92.28) v2(45.89,93.36) v2(147.25,105.24) v2(147.88,105.24) v2(148.52,105.24) v2(177.11,82.86) v2(177.08,81.87) v2(178.22,82.86) v2(178.2,81.84) v2(179.39,82.89) v2(179.42,81.87) v2(184.34,16.46) v2(189.93,59.38) v2(190.76,59.38)
+5VS_FAN: length 1
  TOP w0.127: 186.54,52.53 v3(185.53,52.53)
  vias: v2(186.67,51.39) v2(186.8,51.96) v2(187.49,51.96) v2(187.64,51.39)
+5VS_KB: length 41.4
  TOP w0.508: v2(181.4,16.97) 180.51,16.97 179.7,17.79 179.7,23.18 v1(180.36,23.85) 180.93,24.42 182.82,24.42 183.65,23.59
  BOTTOM w0.508: JKB2.31 156.59,17.66 158.54,15.7 180.13,15.7 v2(181.4,16.97)
  vias: v2(183.75,22.56) v2(183.75,21.93)
+5VS_KBL:
  vias: v1(142.79,15.32)
+5VS_PVDD: length 3
  BOTTOM w0.203: UA1.46 12.81,34.46 13.01,34.25 13.01,33.62 13.2,33.43 13.2,33.38 v2(13.5,33.08) ; UA1.41 v2(13.07,36.46)
  vias: v2(13.61,32.49) v3(13.69,34.88)
+12.6V_BATT+: length 1.7
  TOP w0.117: 75.98,12.62 76.82,12.62 v3(77.41,13.21)
+12.6VB: length 35.4
  TOP w0.508: PR504.1 v2(178.8,72.66)
  TOP w1.905: 43.48,16.46 43.12,16.82 38.24,16.82 37.89,16.46
  TOP w3.175: 42.58,10.04 44.22,11.68
  TOP w4.572: 182.99,73.81 182.99,74.57 185.41,76.99 185.41,82.81 183.34,91.15 183.32,91.23
  BOTTOM w0.508: v2(178.8,72.66) 179.08,72.66 180.9,70.83 180.9,70.11 182.1,68.92 v2(182.1,66.41)
  vias: v1(36.62,11.96) v1(46.65,70.57) v1(63.48,15.39) v2(45.2,15.75) v2(45.2,15.17) v2(45.84,15.78) v2(45.84,15.2) v2(60.54,97.55) v2(60.95,97.99) v2(61.38,98.42) v2(61.54,97.76) v2(61.79,98.85) v2(61.97,98.19) v2(62.25,99.23) v2(62.37,98.62) v2(62.7,99.61) v2(62.88,99) v2(68.41,15.08) v2(68.41,14.47) v2(68.38,13.86) v2(68.38,13.26) v2(68.75,12.68) v2(68.96,13.86) v2(68.96,13.25) v2(68.99,15.08) v2(68.99,14.47) v2(69.37,12.7) v2(69.65,15.08) v2(69.65,14.47) v2(69.62,13.86) v2(69.62,13.25) v2(69.98,12.7) v2(70.26,15.08) v2(70.26,14.47) v2(70.23,13.86) v2(70.23,13.25) v2(70.59,12.72) v2(80.34,106.33) v2(80.84,106.66) v2(81.42,106.66) v2(82.01,106.66) v2(82.59,106.66) v2(83.18,106.66) v2(83.76,106.66) v2(84.34,106.66) v2(84.93,106.66) v2(85.51,106.66) v2(86.1,106.66) v2(86.68,106.66) v2(87.27,106.66) v2(87.85,106.66) v2(88.43,106.66) v2(89.02,106.66) v2(155.18,96.58) v2(156.04,96.59) v2(156.04,95.83) v2(156.8,96.59) v2(156.8,95.83) v2(157.6,96.59) v2(160.38,43.31) v2(160.38,42.68) v2(160.38,42.04) v2(160.38,41.41) v2(161.01,43.31) v2(161.01,42.68) v2(161.01,42.04) v2(161.01,41.41) v2(173.24,90.05) v2(173.65,90.48) v2(174.18,89.16) v2(174.59,89.59) v2(175.25,88.12) v2(175.66,88.55) v2(179.63,95.09) v2(180.62,64.61) v2(181.13,65.09) v2(181.08,64.15) v2(181.66,65.7) v2(181.59,64.64) v2(182.12,65.25) v2(182.4,96.23) v2(182.55,65.96) v2(182.65,95.7) v2(182.91,96.72) v2(182.99,95.12) v2(183.11,96.11) v2(183.29,94.56) v2(183.44,95.55) v2(183.7,94.99) v2(183.98,94.43)
+12.6VB_1.8V:
  vias: v1(169.51,85.72)
+12.6VB_3V: length 1.1
  BOTTOM w0.127: v2(180.24,67.16) 180.24,66.96 v1(180.87,66.33)
  vias: v2(179.83,67.57) v2(180.24,67.99) v2(180.66,68.4) v2(180.66,67.57) v2(181.07,67.99)
+12.6VB_5V:
  vias: v1(39.41,16.91) v2(40.34,14.32) v2(40.95,14.32) v2(41.53,14.32) v2(42.12,14.32)
+12.6VB_CPU:
  vias: v2(84.52,102.11) v2(84.52,101.53) v2(85.11,102.11) v2(85.11,101.53) v2(85.69,102.11) v2(85.69,101.53) v2(86.27,102.11) v2(86.27,101.53) v2(86.86,102.11) v2(86.86,101.53) v2(87.44,102.11) v2(87.44,101.53) v2(88.03,102.11) v2(88.03,101.53) v2(88.61,102.11) v2(88.61,101.53) v2(89.2,102.11) v2(89.2,101.53) v2(109.69,102.75) v2(110.3,102.75) v2(110.28,102.14) v2(110.76,101.55) v2(110.87,102.15) v2(111.22,101.15) v2(111.33,101.75) v2(111.67,100.69) v2(111.81,101.26) v2(134.47,100.37) v2(134.47,99.71) v2(134.47,99.03) v2(134.5,98.29) v2(135.06,100.37) v2(135.06,99.71) v2(135.06,99.03) v2(135.08,98.29) v2(141.48,101.19) v2(142.07,101.19) v2(141.99,100.6) v2(141.99,100.02) v2(141.99,99.43) v2(141.99,98.85) v2(141.99,98.27) v3(93.51,102.82)
+12.6VB_DDR: length 20.2
  BOTTOM w0.508: 157.2,43.83 157.2,47.45 v1(157.78,48.02) 162.73,48.02 163.55,48.85 165.46,48.85 166.54,49.93 166.54,52.09 166.87,52.42 166.87,54.04 166.43,54.48 165.67,54.48 165.46,54.27 PRM10.1
  vias: v2(157.37,40.75) v2(157.98,40.75) v2(158.74,40.67) v2(159.33,40.67)
+12.6VB_VDDP:
  vias: v1(162.54,97.94) v2(162.11,95.65) v2(162.51,96.08) v2(162.92,96.51)
+19V_ADPIN:
  vias: v3(32.87,76.6)
+19V_VIN: length 130.4
  TOP w0.508: v2(48.68,2.55) 47.36,2.55 44.7,5.2 44.7,6.52 45.06,6.88 45.9,6.88 46.43,7.41 46.43,8.78 46.97,9.31 v1(48.67,9.31) 50.31,9.31 51.34,10.34 52.21,10.34 52.32,10.46 54.08,10.46 54.21,10.58 54.21,10.58 54.69,11.06 54.69,11.07 54.74,11.12 54.74,11.14 PDB1.3
  IN1 w0.508: v2(48.68,2.55) 48.09,3.14 42.55,3.14 42.03,2.62 v2(38.31,2.62)
  IN2 w0.254: 21.76,22.05 22.01,21.8 22.01,12.27 25.44,8.84 26.71,8.84 27.28,9.42 32.24,9.42 34.97,12.15 36.62,12.15 37.63,11.13 37.63,7.32 36.74,6.43 36.74,3.57 37.7,2.62 v2(38.31,2.62)
  IN2 w0.508: 21.76,22.05 20.79,23.03 20.79,31.05 22.36,32.63 22.36,34.35 23.47,35.46 23.47,48.92 25.51,50.96 26.25,50.96 26.76,51.47 26.76,53.06 25,54.82 25,57.4 v2(25.19,57.59) 25.19,59.29 31.35,65.45 31.35,68.41 v2(31.16,68.6)
  BOTTOM w0.381: PRB5.1 48.14,1.67 48.68,2.22 v2(48.68,2.55)
  BOTTOM w0.508: PRD6.1 24.13,61.64 23.59,61.09 23.59,58.7 24.71,57.59 v2(25.19,57.59)
+19V_VIN_P1: length 2.4
  BOTTOM w0.508: PQD4.1 30.81,66 32.05,66
  vias: v1(35.92,63.58)
+20V_TBT_VBUS_L: length 0.9
  TOP w0.127: v3(28.39,59.3) 27.89,58.8 v2(27.89,58.64)
  vias: v2(25.73,56.79) v2(26.35,57.43) v2(26.34,56.84) v2(26.68,57.93) v2(27.27,57.89) v2(27.28,58.57) v2(27.83,58.03) v2(28.43,58)
+VCC_IO2: length 1.3
  TOP w0.203: UEC1.124 178.8,46.56 178.79,46.56
GND: length 2241.4
  TOP w0.127: v2(167.12,104.56) v1(166.45,104.56) ; v2(173.05,83.3) 172.76,83.6 v1(172.76,83.84) ; v2(174,57.18) 174.23,57.42 v1(174.6,57.42)
  TOP w0.203: JHDMI1.11 10.94,70.73 ; JHDMI1.11 10.82,71.19 ; JHDMI1.11 9.79,70.73 ; JHDMI1.11 10.82,70.27 ; UD4.G8 136.02,24.11 136.69,24.11 136.9,23.91 136.9,23.37 v2(136.76,23.23) ; JHDMI1.17 10.82,74.19 ; JHDMI1.17 10.94,73.73 ; JHDMI1.17 9.79,73.73 ; JHDMI1.17 10.82,73.27 ; 9.79,67.73 JHDMI1.5 ; JHDMI1.5 10.82,68.19 ; JHDMI1.5 10.94,67.73 ; JHDMI1.5 10.82,67.27 ; JHDMI1.2 12.49,66.23 ; JHDMI1.2 11.92,65.66 ; JHDMI1.2 11.34,66.23 ; JHDMI1.2 11.46,65.77 ; v2(22.9,69.02) 22.97,69.02 23.13,69.18 UT4.14 ; v2(27.54,70.57) 27.32,70.78 UT4.5 ; v2(189.17,42.47) 189.6,42.91 190.16,42.91 190.23,42.83 UEC1.94 ; v2(178.44,30.95) 178.33,30.95 178,30.62 UEC1.35 ; UD8.G8 81.25,26.68 82.04,26.68 82.1,26.75 v2(82.18,26.75) ; v2(176.89,39.63) 176.88,39.63 UEC1.11 ; v2(27.38,69.01) 27.21,69.18 UT4.1 ; JHDMI1.8 12.37,68.77 ; JHDMI1.8 11.46,68.77 ; JHDMI1.8 12.37,69.69 ; JHDMI1.8 11.46,69.69 ; v2(174.3,34.12) 174.3,34.13 174.6,34.43 UEC1.24 ; UEC1.113 183.2,43.98 v2(183.18,43.96) ; 13.35,76.55 JHDMI1.22 13.35,77.48
  TOP w0.254: RD41.1 RD39.2 137.82,26.56 137.49,26.89 UD4.C9 v2(135.99,26.49) ; UD7.B2 62.9,32.28 v2(63.29,32.67) ; v2(102.78,20.34) 102.62,20.34 UD1.H9 ; CD68.2 CC46.2 39.74,34.48 v2(39.37,34.1) ; v2(180.83,21.93) 180.83,22.05 180.72,22.15 C229.2 ; v2(102.68,23.51) UD1.C9 ; v2(197.34,30.77) C318.1 C317.1 ; QC2.1 63.34,88.68 63.54,88.47 63.54,87.71 63.87,87.38 QC2.4 65.08,87.38 65.35,87.11 v2(65.35,87.03) ; v2(49.28,22.98) 49.74,23.44 UD6.N1 ; CA28.2 9.3,35.78 ; 9.3,35.78 v2(9.22,35.86) ; 9.3,35.78 9.31,35.77 9.31,35.35 CA21.2 ; CC30.2 125.35,79.32 125.35,79.28 125.07,79 124.95,79 124.46,78.51 124.46,78.1 125.11,77.45 128.74,77.45 CC31.2 130.04,78.19 130.47,78.62 130.47,80.09 131.06,80.68 v2(131.06,81.03) 131.06,81.03 126.38,81.03 126,80.65 v2(126,80.57) ; UD4.B2 130.81,27.69 v2(131.21,28.09) 130.81,28.49 UD4.A2 ; UD3.K9 125.31,21.52 125.31,21.53 v2(125.53,21.53) ; UD8.D8 80.87,28.68 v2(81.27,28.28) 80.87,27.88 UD8.E8 ; UT6.6 32.74,75.46 v2(34.2,74) ; v2(56.68,25.94) 56.2,25.94 UD6.K9 ; UD6.N9 56.63,23.96 v2(56.63,24.86) ; v2(17.14,90.32) DT7.8 DT7.3 ; UD1.E3 97.08,22 v2(97.07,22) ; v2(68.1,30.28) 67.7,30.68 UD7.D8 ; v2(107.43,11.97) 107.15,12.25 UD2.T1 ; UD1.D8 101.47,23.16 v2(101.86,22.76) 101.46,22.36 UD1.E8 ; v2(95.16,21.67) 95.28,21.56 UD1.F1 ; UD4.F1 129.28,24.49 128.85,24.06 v2(128.85,23.91) ; UD2.E3 108.75,22.36 v2(108.32,21.92) ; v2(37.97,27.94) UD5.H1 ; UD3.D2 UD3.E1 118.38,25.28 118.12,25.02 v2(118.12,24.91) ; UD6.D8 55.36,30.68 v2(55.77,30.27) 55.38,29.88 UD6.E8 ; v2(49.18,21.35) 49.47,21.35 UD6.T1 ; UD7.A2 62.87,33.08 62.87,33.61 v2(62.46,34.03) ; v2(144.95,18.62) 144.95,19.51 145.77,20.34 CTP5.2 ; UD4.N9 137.98,18.89 v2(138.12,19.03) ; CT70.2 19.92,73.68 v2(19.73,73.87) ; UD5.E8 44.05,29.88 v2(44.46,30.29) 44.06,30.68 UD5.D8 ; UD8.A8 81.24,31.47 v2(81.24,31.65) ; UD8.F1 75,27.08 74.58,27.5 v2(74.23,27.5) 74.61,27.88 UD8.E1 ; UD4.E3 v2(131.22,24.92) ; UD5.N9 44.83,23.51 45.38,24.05 v2(45.38,24.76) ; v2(38.81,30.26) UD5.D2 ; UD7.F1 62.06,29.08 v2(61.7,28.72) ; UD8.C9 v2(82.06,29.89) ; v2(63.92,85.62) 63.15,84.84 RT29.2 ; CD48.2 135.22,14.38 v2(135.17,14.43) ; PC845.1 149.05,103.37 148.23,103.37 148.15,103.45 PU802.6 ; UD7.N9 68.69,23.48 68.96,23.75 68.96,24.75 v2(68.96,24.76) ; UD3.H1 118.19,22.88 v2(117.42,23.65) 117.42,23.75 118.02,24.36 118.55,24.36 UD3.F1 ; CC37.2 42.76,35.18 v2(44.42,33.52) 44.03,33.13 UD5.A8 ; v2(124.69,25.68) 124.29,26.08 UD3.D8 ; v2(101.83,21.23) 101.83,21.16 UD1.G8 ; UD2.D2 107.78,23.16 107.15,22.53 UD2.E1 106.97,22.36 v2(106.69,22.08) 106.69,22.02 UD2.F1 ; v2(47.22,4.25) 47.34,4.36 PRB33.2 ; v2(76.44,27.47) 76.85,27.88 76.85,27.88 UD8.E3 ; UD7.A8 67.68,33.14 67.98,33.44 v2(67.98,33.6) ; UD5.C9 44.83,31.51 v2(45.3,31.98) ; UD4.K9 136.74,20.95 v2(136.74,20.92) ; UD3.A8 124.27,28.7 v2(124.57,29.01) ; v2(82.21,22.04) 82.21,22.04 UD8.N9 ; UD2.K1 107.02,18.23 106.89,18.23 v2(106.7,18.03) ; v2(94.56,21.93) 94.81,22.18 95.36,22.18 95.53,22.36 UD1.E1 UD1.D2 ; UD7.C9 68.48,31.48 v2(68.92,31.93) ; v2(28.14,82.44) 28.48,82.77 UT2.8 ; v2(200,25.04) 200,24.85 199.75,24.59 CUS4.2 ; CF5.2 v2(193.74,16.32) ; UD5.E1 38.23,29.69 37.78,29.69 v2(37.64,29.55) 37.64,29.46 37.94,29.16 38.18,29.16 38.26,29.08 UD5.F1 ; v2(119.49,29.18) 119.49,28.5 UD3.A2 119.37,28.38 119.37,27.77 UD3.B2 ; UD7.T1 61.66,20.66 v2(61.63,20.66) ; UD5.K9 45.08,26.13 v2(45.34,26.13) ; RD31.1 103.7,56.32 v2(103.87,56.5) ; UD5.T1 38.07,20.72 38.07,20.65 v2(38.06,20.64) ; v2(67.28,29.45) 67.68,29.84 UD7.E8 ; SW1.5 v2(2.9,43.28) ; v2(106.68,15.46) 107.15,15.92 UD2.N1 ; v2(168.19,18.5) 167.64,17.95 CF8.2 ; v2(125.61,27.32) 125.17,26.88 UD3.C9 ; v2(104.85,10.69) 104.75,10.78 104.75,11.26 104.5,11.51 102.81,11.51 CFP4.2 ; v2(44.44,28.69) UD5.G8 v2(44.39,27.92) UD5.H9 ; UD2.N9 113.65,16.05 113.83,16.05 114.08,16.31 v2(114.08,17.33) ; v2(20.04,72.92) 20.03,72.9 RT58.1 ; v2(135.18,26.51) UD4.D8 135.63,26.06 135.63,25.32 UD4.E8 ; UT6.8 32.69,76.46 33.95,75.2 v2(34.52,75.2) ; v2(129.53,23.09) 129.74,22.89 UD4.H1 ; v2(196.1,25.53) 196.1,24.54 195.63,24.06 RUS7.2 RUS6.2 ; v2(30.42,82.92) 30.56,82.78 CT38.2 ; UD6.E3 v2(51.76,29.46) ; UD8.D2 76.05,28.68 75.79,28.42 v2(75.62,28.25) ; v2(120.68,24.86) 120.27,25.28 UD3.E3 ; UD2.C9 v2(113.14,23.55) ; UD3.N1 118.6,18.88 v2(118.16,18.43) ; PR254.2 113.86,7.75 113.88,7.73 113.88,7.7 114.44,7.15 115.95,7.15 116.06,7.25 v2(116.54,7.25) ; SW1.2 v2(2.89,42.56) ; v2(29.12,87.33) 29.1,87.35 28.73,87.35 28.48,87.1 UT2.18 ; v2(62.47,27.08) 62.47,27.12 62.27,27.32 62.12,27.48 UD7.H1 ; CF13.2 197.81,23.11 197.91,23.01 198.67,23.01 199.43,22.25 U9.2 199.43,21.23 200.13,20.53 v2(200.13,18.31) ; UD5.E3 v2(40.47,29.44) ; C261.2 188.83,48.98 v2(188.95,49.1) ; v2(61.51,25.48) 61.91,25.88 62.08,25.88 UD7.K1 ; DT15.2 22.73,73.89 v2(23.22,74.38) ; v2(86.21,28.21) RD51.1 85.61,28.86 86.02,29.27 RD55.2 ; UD8.A2 76.07,31.08 v2(76.47,30.68) 76.07,30.28 UD8.B2 ; v2(68.08,28.69) 67.68,28.28 UD7.G8 67.68,28.28 v2(68.04,27.91) 68.48,27.48 UD7.H9 ; RT66.1 27.79,70.31 v2(27.54,70.57) 27.54,71.28 CT74.2 ; UD6.H9 v2(55.78,27.85) UD6.G8 55.35,28.28 v2(55.72,28.66) ; CT37.2 31.36,84.56 30.94,84.98 v2(30.76,84.98) 30.69,85.06 UT2.13 ; U7.14 191.33,22.78 v2(191.08,23.03) ; v2(113.13,21.14) UD2.G8 112.75,20.76 113.08,20.43 UD2.H9 ; UD8.H9 81.65,25.48 v2(81.27,25.86) 80.85,26.28 UD8.G8 ; v2(95.08,20.2) 95.32,19.96 UD1.H1 ; UD3.H9 125.07,22.88 v2(124.63,23.31) 124.27,23.68 UD3.G8 124.27,23.68 v2(124.67,24.09) ; UD2.D8 112.77,23.16 v2(113.18,22.75) 112.78,22.36 UD2.E8 ; v2(101.88,18) UD1.K9 ; CFP3.2 101.55,8.02 v2(102.02,8.02) ; UD4.A8 134.56,29.53 v2(134.25,29.53) ; v2(49.24,25.61) 49.37,25.61 49.64,25.88 UD6.K1 ; v2(74.79,18.56) 75.25,19.03 UD8.T1 ; v2(129.53,16.02) UD4.T1 ; SW1.1 v2(2.89,43.95) ; v2(64.09,29.46) 63.68,29.88 UD7.E3 ; UD4.D2 UD4.E1 ; UD1.N9 v2(102.68,15.51)
  TOP w0.305: v2(67.98,33.6) 67.92,33.65 CC40.2 ; v2(38.83,23.08) UD5.N1 ; v2(173.16,30.68) 172.96,30.49 C269.2 ; C256.2 v2(173.04,43.77) ; v2(114.08,25.82) 113.8,26.1 113.19,26.1 112.75,25.66 UD2.A8 ; UD2.A2 107.81,25.42 107.81,24.9 UD2.B2 ; v2(121.32,63) 121.32,62.67 121.16,62.5 CC71.2 CC72.2 ; UD6.B2 50.4,32.42 50.4,32.94 UD6.A2 ; v2(62.46,23.08) 62.08,23.47 UD7.N1 ; v2(95.16,15.98) 95.18,15.96 UD1.N1 ; UD8.N1 74.8,21.03 v2(74.74,21.03) ; v2(101.87,58.8) 101.39,59.29 101.39,60 PC9069.2 ; v2(102.87,58) 102.86,57.99 CC44.2 ; v2(185.21,48.99) 185.14,48.93 C234.2 ; v2(68.84,26.25) 68.72,26.13 68.72,26.13 UD7.K9 ; RWL17.2 172.46,34.23 173.13,33.56 UWL22.3 173.78,33.56 174.3,34.08 v2(174.3,34.12) ; v2(49.1,27.25) 49.51,27.25 UD6.H1 ; v2(82.11,23.42) UD8.K9 ; v2(114.21,18.57) 114,18.36 UD2.K9 ; RD70.1 104.03,47.43 103.8,47.2 ; CC52.2 54.49,34.84 v2(55.78,33.55) 55.78,33.51 UD6.A8 ; UD8.H1 75.22,25.45 74.57,25.45 74.23,25.78 v2(74.23,25.91) ; UD1.K1 95.23,18.36 95.22,18.37 95.15,18.37 94.85,18.67 94.85,18.74 v2(94.66,18.93) ; v2(68.92,31.93) 71.17,34.18 CD70.2 ; v2(124.69,25.68) 124.29,25.28 UD3.E8 ; PC9017.2 96.14,60.72 v2(96.37,60.5) ; UD3.T1 118.39,16.2 118.03,16.2 v2(117.95,16.29) ; UD3.K1 119.01,20.93 v2(119.07,20.93) ; UD3.N9 125.28,18.88 v2(125.61,19.21) ; v2(178.41,26.43) 178.35,26.5 C70.1 ; CD55.1 v2(34.12,33.05) ; CC66.2 CC67.2 v2(114.85,66.4) ; v2(38.02,26.26) 38.4,25.88 UD5.K1 ; CC45.2 114.98,55.64 v2(114.91,55.71) ; v2(39.37,34.1) 39.21,33.95 39.21,33.1 UD5.A2 39.01,32.86 39.01,32.5 UD5.B2 ; CD66.2 CC35.2 76.37,31.83 76.05,31.51 UD8.A2 ; v2(56.53,31.1) UD6.C9 ; v2(129.29,24.98) 129.69,24.98 UD4.E1 ; C258.1 187.81,50.02 187.51,50.32 C232.2 ; CC47.2 116.73,53.42 v2(117.36,54.06) ; CC82.2 87.74,7.68 87.43,7.98 v2(87.29,7.98) ; UD6.F1 49.62,29.2 49.4,29.2 v2(49.07,29.53) 49.42,29.88 UD6.E1 UD6.D2 ; CUS3.2 190.81,27.6 191.27,28.06 192,28.06 192.37,27.69 v2(192.37,27.55) ; v2(50.63,33.61) 51.01,33.99 CC38.2 51.04,35.48 CD71.2 ; UD7.F1 61.89,29.27 61.89,29.69 UD7.E1 UD7.D2 ; v2(71.86,32.4) 71.99,32.4 72.47,32.89 RD50.1 RD54.2
  TOP w0.356: CC26.2 167.26,37.58 167.2,37.65 166.13,37.65 v2(165.97,37.48) ; CC114.2 168.37,31.17 v2(168.41,31.13) ; v2(163.11,35.26) 163.73,35.88 RC72.2 164.27,35.88 164.46,35.69 UC8.3
  TOP w0.381: v2(104.85,10.69) 104.86,10.7 104.91,10.7 104.91,10.7 105.15,10.7 105.31,10.54 CFP1.2 ; v2(108.33,25.18) UD2.A2 ; PC9005.2 109.71,64.13 v2(110.37,64.8) 109.79,65.39 PC9006.2 ; RD38.2 RD40.1 127.91,30.59 v2(128.72,29.77) ; v2(103.97,66.4) 104.11,66.4 104.57,65.94 PC9029.2 ; v2(85.13,55.34) 85.5,55.71 RC16.2 ; v2(102.37,66.4) 102.2,66.4 102.03,66.57 PC9048.2 ; v2(105.57,66.4) 105.11,65.94 PC9029.2 ; C265.2 183.24,48.7 v2(183.52,48.98) ; v2(74.79,18.56) 74.23,19.12 73.14,19.12 71.9,17.87 CD78.2 ; UD4.N1 129.94,18.89 v2(129.49,18.44) ; v2(129.26,70.31) 129.33,70.38 133.46,70.38 134.21,71.14 135.71,71.14 135.77,71.19 CC73.2 ; PC9009.2 104.22,73.79 v2(104.37,73.95) ; v2(113.57,60.8) 114.18,61.4 CC74.2 ; v2(122.3,76.02) 122.35,76.07 CC65.2 ; CC68.2 125.16,68.32 CC69.2 123.79,68.32 123.45,67.98 v2(123.41,67.98) ; CD104.2 CD105.2 82.97,15.96 83.35,15.58 v2(83.53,15.58) 83.84,15.58 CD106.2 ; v2(52.78,3.05) 52.66,3.17 PRB20.2 ; C268.2 169.68,39.73 v2(168.95,39.73) ; v2(123.88,74.72) 124.06,74.54 CC64.2 ; C257.2 188.46,25.98 v2(188.24,25.76) ; PC9109.2 101.71,64.13 v2(102.37,64.8) 101.82,65.35 PC9047.2 ; v2(185.78,23.7) 185.78,23.96 186.16,24.34 RUS8.2 ; C231.2 48.68,59.95 C230.2 ; v2(111.93,63.2) 111.99,63.14 PC9033.2 ; PC9029.2 104.89,67.12 PC9030.2 ; CD4.1 91.72,24.96 v2(92.04,24.64) ; v2(59.5,64.75) 59.68,64.57 C204.2 ; PC9004.2 110.05,62.88 v2(110.37,63.2) ; v2(50.63,33.61) 50.63,33.17 UD6.A2 ; C255.2 R59.2 v2(185.14,51.26) ; C233.2 176.55,48.35 C84.2 v2(177.02,49.04) ; v2(116.57,62.5) 116.61,62.54 CC79.2 ; U2.3 56.35,76.51 v2(56.02,76.84) ; CSD6.2 v2(56.16,55.21) ; v2(59.15,19.49) 59.45,19.18 CD67.2 ; PC9108.2 95.83,73.4 v2(96.37,73.95) ; QH1.4 19.04,72.8 v2(19.47,73.23) ; v2(49.48,7.41) 49.71,7.64 PRB28.2 ; CF12.2 87.79,72.8 88.59,72 v2(89.37,72) ; PQB3.3 53.87,5.26 PCB33.2 ; v2(58.33,34.4) 58.53,34.59 RD49.1 RD53.2 ; PC9033.2 113.27,63.14 C1.2 ; PC9033.2 112.59,61.96 PC9105.2 112.23,61.93 v2(111.92,61.61) 111.92,60.94 PC9056.2 ; v2(53.65,4.54) 53.65,4.55 53.69,4.59 53.69,5.07 PCB33.2 ; v2(102.37,61.6) 102.35,61.57 PC9018.2 100.9,61.57 v2(100.78,61.7) ; UC6.3 79.75,63.4 v2(79.44,63.71) ; v2(105.57,64.8) 105.52,64.74 PC9002.2 104.03,64.74 v2(103.97,64.8) ; v2(194.22,20.97) 194.29,20.91 194.29,20.21 194.21,20.13 CF7.2 ; v2(186.03,50.31) 186.05,50.32 C232.2 ; v2(126.12,15.98) 126.42,15.69 CD49.2 ; v2(123.37,66) 123.81,66.44 CC75.2 ; v2(30.42,82.92) 30.12,82.62 CT58.2 ; v2(85.97,19.84) 85.63,19.5 CD31.2 ; v2(169.77,42.62) 169.69,42.62 169.28,43.04 UC7.3 ; CF6.2 186.82,17.69 v2(186.69,17.81) ; v2(163.15,29.23) 163.69,29.23 163.81,29.34 UC23.3 ; v2(67.9,61.58) 67.91,61.57 USD2.3 ; v2(86.78,25.3) 86.35,25.74 CD72.2 ; v2(95.3,13.91) 95.65,13.56 UD1.T1 ; v2(61.38,54.88) 60.94,55.33 CF10.2 ; v2(100.75,63.2) 101.03,62.92 101.57,62.92 PC9019.2 101.79,62.92 102.1,62.92 v2(102.37,63.2) ; v2(100.87,69.2) 101.06,69.01 PC9050.2 PC9049.2 ; UD1.B2 96.5,24.89 96.5,25.43 UD1.A2 97,25.93 v2(97.07,25.93) ; RD52.2 RD48.1 46.74,37.01 47.14,36.61 v2(47.14,35.71) ; PC9068.2 104.28,59.31 v2(103.87,58.9) ; PC9013.2 v2(105.58,61.6) ; PC9013.2 v2(107.17,61.6) ; PC9013.2 106.25,61.08 106.42,60.91 PC9064.2 ; R68.1 C267.1 181.46,48.57 181.08,48.95 v2(180.56,48.95) ; v2(17.45,50.89) 17.09,51.26 RA31.1 ; CC77.2 114.85,64.98 v2(114.53,65.3) 114.21,64.98 CC76.2 ; CD80.2 v2(65.65,33.23) ; UD2.H1 106.81,19.96 v2(106.62,20.15) ; UD4.H9 136.41,22.89 v2(136.76,23.23) ; L2.1 194.22,32.61 v2(194.5,32.33) ; v2(89.46,73.62) 89.61,73.47 PC9008.2 ; v2(104.87,69.2) 105.13,68.94 PC9031.2 ; v2(26.87,45.98) 27.31,45.54 CF9.2 ; PC9057.2 106.9,71.58 v2(106.87,71.6) ; v2(113.39,75.79) 113.4,75.81 PC9058.2 ; PCB33.2 54,5.38 54.91,5.38 55.2,5.09 55.74,5.09 PQB4.3 ; v2(44.81,76.62) 44.81,76.31 44.9,76.22 CT72.2 ; RC561.2 121.34,66.99 v2(121.32,67) 121.83,67.51 RC123.2 ; v2(103.97,63.2) 104.31,63.2 104.64,63.53 PC9001.2 105.24,63.53 v2(105.57,63.2) ; CD69.2 81.18,15.55 v2(80.69,15.55) ; v2(170.35,37.37) 171.5,37.37 171.89,36.99 RWL12.1 172.09,36.77 172.27,36.59 CC29.1 RC83.1 172.7,37.88 172.75,37.93 C259.2 ; CC43.2 109.51,60.84 PC9110.2 110.34,61.63 v2(110.37,61.6) ; v2(51.95,70.93) C3.2 ; CC39.2 81.13,32.47 81.24,32.36 v2(81.24,31.65) ; v2(53.07,58.03) 53.07,58.13 53.23,58.29 C249.2 ; PC9052.2 95.19,66.05 v2(94.63,65.49) 94.66,65.46 CC57.2 CC55.2 ; CD64.2 84.24,32.07 v2(82.06,29.89) ; UD1.A8 101.46,25.56 v2(101.85,25.16) ; v2(113.57,64.8) 112.82,65.55 PC9035.2 ; v2(41.62,81.06) 41.82,80.85 41.82,80.23 CT52.2 42.65,80.78 CT51.2 ; 103.8,47.2 v2(103.37,47.2) ; v2(105.87,58.9) 106.49,59.52 PC9070.2 ; CT34.2 31.16,81.17 30.78,80.79 CT78.2 ; v2(81.39,56.57) RC6.2 ; PC9034.2 112.12,64.79 v2(111.92,64.79)
  TOP w0.457: v2(16.87,72.71) 16.65,72.93 RH16.2 ; CC117.2 102.67,49.6 v2(103.37,49.6) ; v2(30.76,82.27) 31.24,82.27 31.45,82.06 RT28.2 31.76,81.27 CT34.2 ; v2(120.06,10.27) 120.16,10.27 120.21,10.32 120.68,10.32 PC253.2 ; v2(86.17,24.11) 86.05,23.98 CD74.2 ; v2(121.77,52) 121.77,52 CC116.2 ; PC9046.2 102.74,74.31 v2(102.37,73.95) ; CC118.2 103.1,52 v2(103.37,52) ; v2(85.97,19.84) 85.56,20.25 CD28.2
  TOP w0.508: v2(100.37,73.95) 100.49,73.84 PC9106.2 ; v2(126,80.57) CC30.2 ; v2(27.88,81.86) 27.63,81.62 CT75.1 27.16,81.11 28.22,80.04 RT92.2 ; PRS6.2 36.08,50.96 v2(36.34,51.21) ; PC256.2 PC257.2 113.87,10.9 v2(113.77,11) ; C68.2 v2(175.75,26.87) ; RT23.2 RT38.2 v2(37.21,78.38) ; v2(168.42,76.8) 168.42,76.99 PR720.2 ; CD79.2 44.22,18.53 v2(43.76,19) ; v2(49.09,19.16) 49.32,18.93 CD75.2 ; v2(73.26,59.9) CSD8.2 ; CD84.2 33.95,26.01 v2(33.49,26.01) ; PQS2.3 26.11,50.35 v2(26.02,50.35) ; RT30.2 38.48,79.16 RT41.2 38.41,79.09 v2(38.41,78.35) ; v2(98.4,89.93) 98.42,89.95 PC852.2 99.29,90.56 PR858.1 ; v2(33.19,79.14) 32.82,79.14 CT77.2 32.57,79.96 32.63,80.03 RT91.2 ; CD113.2 CD28.2 ; v2(56.33,78.08) 56.44,78.2 R4006.1 ; PC831.2 90.35,97.79 PC838.2 89.68,97.82 v2(89.61,97.88) ; RT59.1 20.95,69.21 RT86.2 21.8,69.16 RT60.2 21.94,69.02 v2(22.9,69.02) ; CD63.2 62.27,18.65 v2(62.55,18.37) ; v2(154.7,36.07) 154.5,36.28 PCM11.2 ; PR834.1 91.1,92.92 90.66,92.47 v2(90.66,92.16) 90.66,91.41 PC814.2 ; RT24.2 36.1,88.75 36.34,89 v2(36.34,89.18) ; CT53.2 40.62,76.22 v2(40.43,76.03) ; CD83.2 CD85.2 v2(28.54,25.58) ; v2(129.42,20.97) 129.73,21.29 UD4.K1 ; PU251.11 117.75,8.18 118.64,7.3 118.77,7.3 118.77,7.29 119.83,7.29 119.83,7.3 121.45,7.3 121.96,7.8 PC255.2 ; v2(33,88.09) 33.21,88.31 34.09,88.31 CT46.2 ; v2(33.35,84.79) 33.53,84.79 34.04,85.3 34.04,85.49 RT25.2 ; CD76.2 70.79,20.39 v2(71.01,20.6) ; R7.1 58.93,74.14 59.29,74.14 v2(59.71,74.55) ; C231.2 48.48,58.88 47.57,57.97 v2(45.84,57.97) ; v2(74.47,23.54) 74.81,23.88 UD8.K1 ; PC845.1 149.81,103.14 150.02,102.94 v2(150.07,102.94) ; CD29.2 85.72,16.05 v2(85.72,16.74) 85.56,16.9 CD30.2 ; v2(176.09,72.88) 176.09,72.6 PR506.2 176.36,72.29 PC520.2 ; CSD2.2 v2(29.67,41.93) ; RA28.1 2.68,38.89 v2(2.56,38.77) ; CC119.2 101.98,53.65 v2(102.37,54.05) ; RA26.1 3.81,45.85 v2(3.81,45.37) ; v2(49.53,6.22) 49.62,6.13 PRB22.2 ; 174.34,72.75 174.44,72.85 174.44,72.85 v2(174.81,73.22) ; CD32.2 86.71,23.83 86.43,24.11 v2(86.17,24.11) 86.05,24.24 CD73.2 86.06,24.81 CD72.2 ; v2(67.1,19) 67.42,18.69 CD77.2 ; v2(56.02,76.84) 55.49,76.31 55.49,74.76 R8.2 ; CF3.2 CF4.2 190.25,64.28 190.73,63.81 191.77,63.81 v2(191.79,63.82) ; DT6.1 22.84,86.53 v2(22.84,86.76) ; CD82.2 30.19,23.58 29.38,22.76 v2(28.74,22.76) ; PRS5.2 34.22,54.17 v2(33.89,54.5) ; CC70.2 123.56,62.18 v2(123.37,62) ; v2(33.76,72.34) 33.13,72.34 32.79,72.01 RT89.2 32.36,70.1 QT2.3 ; v2(49.53,8.55) 49.66,8.43 PRB17.2 ; v2(164.76,91.62) 165,91.62 PR621.1 ; CT69.2 v2(23.22,75.01) ; CT68.2 25.11,65.33 24.97,65.33 v2(24.93,65.3) ; PR836.1 93.13,90.07 v2(93.37,89.83) ; CC81.2 83.67,5.3 v2(83.51,5.47) ; v2(87.82,75.82) RC601.1 RC70.1 ; v2(66.25,57.7) RSD7.2 ; v2(38.89,89.25) 38.76,89.12 RT63.2 ; QT1.3 19.27,74.71 19.73,74.25 v2(19.73,73.87) ; v2(173.04,43.77) 173.04,44.29 172.58,44.74 172.58,44.76 172.39,44.95 CWL1.2 ; CD114.2 v2(33.47,31.23) ; PC9014.2 98.9,61.32 v2(99.17,61.6) ; PRS4.2 31.52,54.22 v2(32.08,54.78) ; CKBL3.2 144.17,14.67 v2(144.55,14.29) ; C69.2 172.75,41.45 173.07,41.76 173.07,41.79 v2(173.09,41.79) ; v2(84.26,12.85) 83.61,12.85 PR9.2 ; v2(190.99,51.71) 190.48,51.71 190.33,51.86 JP1.2 ; PC9111.2 96.69,75.4 v2(97.2,75.9) ; v2(47.14,35.71) 47.53,35.31 CD65.2 ; CT59.2 v2(25.57,86.7) ; CC105.2 88.51,5.73 89.89,7.11 JBATT1.11 ; CT73.2 42.29,74.92 v2(41.84,74.92) ; PC9112.2 105.48,75.51 v2(105.87,75.91) ; v2(59.69,55.03) CSD7.2 ; CSD3.2 29.75,39.9 v2(29.58,40.06) ; PR1816.1 94.97,92.35 v2(94.8,92.17) 95.15,91.82 PC853.2 ; CSD1.2 30.06,39.22 30,39.22 29.98,39.24 28.76,39.24 28.41,38.89 v2(28.41,38.69) ; PC522.2 174.95,72.12 v2(175.44,72.61) ; v2(108.27,96.26) PC851.2 ; CC36.2 62.54,34.11 v2(62.46,34.03) ; R70.1 v2(191.76,48.39) ; v2(78.27,60.36) 78.05,60.58 RC9.2 ; QT4.3 42.79,72.77 v2(42.78,72.79) ; PC251.1 v2(120.51,12.15) ; RA32.1 v2(16.11,60.42) ; v2(58.65,55) CSD5.2
  GND1 w0.203: JBATT1.10 78.34,7.77 ; JBATT1.10 77.64,8.77 ; JBATT1.10 76.94,7.77 ; JBATT1.10 76.94,8.77 ; JBATT1.10 78.34,6.76 ; JBATT1.10 78.34,8.77 ; JBATT1.10 77.64,6.76 ; JBATT1.10 76.94,6.76 ; JHDMI1.23 3.9,79.38 ; JHDMI1.23 1.33,80.31 ; JHDMI1.23 2.62,80.31 ; JHDMI1.23 1.33,78.45 ; JHDMI1.23 3.9,80.31 ; JHDMI1.23 1.33,79.38 ; JHDMI1.23 2.62,78.45 ; JHDMI1.23 3.9,78.45 ; JHDMI1.21 5.15,61.08 ; JHDMI1.21 2.58,62.01 ; JHDMI1.21 3.87,62.01 ; JHDMI1.21 5.15,62.01 ; JHDMI1.21 2.58,61.08 ; JHDMI1.8 12.37,68.77 ; JHDMI1.8 11.46,69.69 ; JHDMI1.8 11.46,68.77 ; JHDMI1.8 12.37,69.69 ; H7.1 108.38,35.65 ; H7.1 105.41,32.68 ; H7.1 106.9,36.2 ; H7.1 108.93,34.17 ; H7.1 106.9,32.13 ; H7.1 108.38,32.68 ; H7.1 105.41,35.65 ; H7.1 104.86,34.17 ; 10.78,63.91 JHDMI1.20 ; JHDMI1.20 10.78,62.98 ; JHDMI1.20 10.78,62.05 ; JHDMI1.20 13.35,63.91 ; JHDMI1.20 13.35,62.98 ; JHDMI1.20 13.35,62.05 ; JHDMI1.20 12.07,63.91 ; JHDMI1.20 12.07,62.05 ; 17,40.75 H13.1 ; H13.1 19.35,40.75 ; H13.1 19.76,39.58 ; H13.1 18.18,41.17 ; H13.1 17,38.41 ; H13.1 18.18,37.99 ; H13.1 19.35,38.41 ; H13.1 16.59,39.58 ; H12.1 191.71,73 ; H12.1 191.71,69.8 ; H12.1 187.93,71.4 ; H12.1 188.52,73 ; H12.1 190.12,73.58 ; H12.1 188.52,69.8 ; H12.1 190.12,69.22 ; H12.1 192.3,71.4 ; JUSBC2.6 1.95,96.15 ; JUSBC2.6 0.61,94.91 ; JUSBC2.6 0.61,96.15 ; JUSBC2.6 3.28,94.91 ; JUSBC2.6 3.28,96.15 ; JUSBC2.6 0.61,95.53 ; JUSBC2.6 3.28,95.53 ; JUSBC2.6 1.95,94.91 ; JHDMI1.11 10.82,70.27 ; JHDMI1.11 9.91,71.19 ; JHDMI1.11 10.94,70.73 ; JHDMI1.11 9.91,70.27 ; JHDMI1.11 10.82,71.19 ; JHDMI1.11 9.79,70.73 ; JUSBC2.1 3.28,83.11 ; JUSBC2.1 1.95,83.11 ; JUSBC2.1 3.28,83.73 ; JUSBC2.1 3.28,84.35 ; JUSBC2.1 1.95,84.35 ; JUSBC2.1 0.61,84.35 ; JUSBC2.1 0.61,83.11 ; JUSBC2.1 0.61,83.73 ; 9.79,67.73 JHDMI1.5 ; JHDMI1.5 10.82,68.19 ; JHDMI1.5 9.91,68.19 ; JHDMI1.5 9.91,67.27 ; JHDMI1.5 10.94,67.73 ; JHDMI1.5 10.82,67.27 ; H18.1 66.39,92.79 ; H18.1 64.91,96.31 ; H18.1 63.42,92.79 ; H18.1 64.91,92.25 ; H18.1 63.42,95.77 ; H18.1 66.39,95.77 ; H18.1 62.87,94.28 ; H18.1 66.94,94.28 ; JBATT1.11 90.59,7.77 ; JBATT1.11 89.89,8.77 ; JBATT1.11 89.89,6.76 ; JBATT1.11 89.19,7.77 ; JBATT1.11 90.59,6.76 ; JBATT1.11 89.19,8.77 ; JBATT1.11 89.19,6.76 ; JUSBC2.3 9.28,85.3 ; JUSBC2.3 6.61,84.06 ; JUSBC2.3 9.28,84.06 ; JUSBC2.3 9.28,84.68 ; JUSBC2.3 7.95,84.06 ; JHDMI1.2 12.49,66.23 ; JHDMI1.2 12.37,66.69 ; JHDMI1.2 11.92,65.66 ; JHDMI1.2 11.34,66.23 ; JHDMI1.2 11.46,65.77 ; JHDMI1.2 11.46,66.69 ; JHDMI1.2 12.37,65.77 ; H15.1 94.92,5.93 ; H15.1 96.09,5.51 ; H15.1 93.74,5.51 ; H15.1 94.92,2.75 ; H15.1 96.5,4.34 ; H15.1 93.33,4.34 ; H15.1 96.09,3.17 ; H15.1 93.74,3.17 ; 13.43,80.92 H16.1 ; H16.1 13.43,84.58 ; H16.1 11.6,82.75 ; H16.1 14.77,81.41 ; H16.1 15.25,82.75 ; H16.1 12.08,84.09 ; H16.1 14.77,84.09 ; H16.1 12.08,81.41 ; H10.1 178.5,106.21 ; H10.1 176.15,108.55 ; H10.1 175.74,107.38 ; H10.1 178.91,107.38 ; H10.1 178.5,108.55 ; H10.1 177.33,108.97 ; H10.1 176.15,106.21 ; H10.1 177.33,105.79 ; H1.1 131.88,50.84 ; H1.1 133.96,48.76 ; H1.1 131.88,46.68 ; H1.1 130.36,47.24 ; H1.1 133.4,47.24 ; H1.1 129.8,48.76 ; H1.1 133.4,50.28 ; H1.1 130.36,50.28 ; JHDMI1.22 13.35,76.55 ; JHDMI1.22 10.78,78.41 ; JHDMI1.22 12.07,76.55 ; JHDMI1.22 12.07,78.41 ; JHDMI1.22 13.35,77.48 ; JHDMI1.22 10.78,76.55 ; JHDMI1.22 13.35,78.41 ; JHDMI1.22 10.78,77.48 ; 76.94,10.24 JBATT1.9 ; JBATT1.9 76.94,11.24 ; JBATT1.9 77.64,12.24 ; JBATT1.9 78.34,12.24 ; JBATT1.9 78.34,10.24 ; JBATT1.9 76.94,12.24 ; JBATT1.9 77.64,10.24 ; JBATT1.9 78.34,11.24 ; 6.61,95.2 JUSBC2.4 ; JUSBC2.4 9.28,93.96 ; JUSBC2.4 7.95,95.2 ; JUSBC2.4 9.28,95.2 ; JUSBC2.4 9.28,94.58 ; 197.89,35.27 H5.1 ; H5.1 197.89,39.33 ; H5.1 199.92,37.3 ; H5.1 199.37,35.81 ; H5.1 195.85,37.3 ; H5.1 196.4,38.79 ; H5.1 199.37,38.79 ; H5.1 196.4,35.81 ; H11.1 158.95,29.69 ; H11.1 159.51,31.21 ; H11.1 157.43,29.13 ; H11.1 155.9,29.69 ; H11.1 155.34,31.21 ; H11.1 155.9,32.73 ; H11.1 157.43,33.29 ; H11.1 158.95,32.73 ; 80.86,46.68 H3.1 ; H3.1 82.38,50.28 ; H3.1 80.86,50.84 ; H3.1 79.34,50.28 ; H3.1 79.34,47.24 ; H3.1 82.94,48.76 ; H3.1 82.38,47.24 ; H3.1 78.78,48.76 ; H2.1 108.45,89.75 ; H2.1 104.84,88.23 ; H2.1 104.28,89.75 ; H2.1 106.37,91.83 ; H2.1 107.89,88.23 ; H2.1 106.37,87.67 ; H2.1 107.89,91.27 ; H2.1 104.84,91.27 ; JBATT1.12 89.89,12.24 ; JBATT1.12 89.19,11.24 ; JBATT1.12 89.19,10.24 ; JBATT1.12 89.19,12.24 ; JBATT1.12 90.59,12.24 ; JBATT1.12 90.59,10.24 ; JBATT1.12 90.59,11.24 ; JBATT1.12 89.89,10.24 ; 9.91,74.19 JHDMI1.17 ; JHDMI1.17 9.91,73.27 ; JHDMI1.17 10.82,74.19 ; JHDMI1.17 10.94,73.73 ; JHDMI1.17 10.82,73.27 ; JHDMI1.17 9.79,73.73
  VCC w0.203: H16.1 14.77,84.09 ; H16.1 12.08,81.41 ; H16.1 15.25,82.75 ; H16.1 12.08,84.09 ; H16.1 14.77,81.41 ; H16.1 13.43,84.58 ; H16.1 13.43,80.92 ; H16.1 11.6,82.75 ; JHDMI1.11 10.82,71.19 ; JHDMI1.11 9.91,70.27 ; JHDMI1.11 9.79,70.73 ; JHDMI1.11 10.94,70.73 ; JHDMI1.11 9.91,71.19 ; JHDMI1.11 10.82,70.27 ; JUSBC2.6 3.28,96.15 ; JUSBC2.6 3.28,94.91 ; JUSBC2.6 3.28,95.53 ; JUSBC2.6 0.61,94.91 ; JUSBC2.6 1.95,96.15 ; JUSBC2.6 1.95,94.91 ; JUSBC2.6 0.61,95.53 ; JUSBC2.6 0.61,96.15 ; JHDMI1.23 3.9,79.38 ; JHDMI1.23 3.9,80.31 ; JHDMI1.23 2.62,78.45 ; JHDMI1.23 1.33,79.38 ; JHDMI1.23 2.62,80.31 ; JHDMI1.23 1.33,78.45 ; JHDMI1.23 3.9,78.45 ; JHDMI1.23 1.33,80.31 ; JHDMI1.17 10.94,73.73 ; JHDMI1.17 9.91,74.19 ; JHDMI1.17 9.91,73.27 ; JHDMI1.17 9.79,73.73 ; JHDMI1.17 10.82,73.27 ; JHDMI1.17 10.82,74.19 ; JBATT1.12 90.59,11.24 ; JBATT1.12 89.19,11.24 ; JBATT1.12 89.89,12.24 ; JBATT1.12 89.19,12.24 ; JBATT1.12 89.89,10.24 ; JBATT1.12 90.59,10.24 ; JBATT1.12 90.59,12.24 ; 0.61,84.35 JUSBC2.1 ; JUSBC2.1 0.61,83.73 ; JUSBC2.1 3.28,83.11 ; JUSBC2.1 1.95,84.35 ; JUSBC2.1 0.61,83.11 ; JUSBC2.1 1.95,83.11 ; JUSBC2.1 3.28,83.73 ; JUSBC2.1 3.28,84.35 ; 104.86,34.17 H7.1 ; H7.1 108.38,32.68 ; H7.1 105.41,35.65 ; H7.1 105.41,32.68 ; H7.1 108.38,35.65 ; H7.1 106.9,32.13 ; H7.1 106.9,36.2 ; H7.1 108.93,34.17 ; H3.1 80.86,50.84 ; H3.1 79.34,47.24 ; H3.1 80.86,46.68 ; H3.1 82.94,48.76 ; H3.1 79.34,50.28 ; H3.1 82.38,50.28 ; H3.1 78.78,48.76 ; H3.1 82.38,47.24 ; JHDMI1.22 13.35,76.55 ; JHDMI1.22 12.07,78.41 ; JHDMI1.22 12.07,76.55 ; JHDMI1.22 10.78,77.48 ; JHDMI1.22 13.35,77.48 ; JHDMI1.22 10.78,78.41 ; JHDMI1.22 13.35,78.41 ; JHDMI1.22 10.78,76.55 ; JHDMI1.2 12.37,66.69 ; JHDMI1.2 11.46,66.69 ; JHDMI1.2 12.37,65.77 ; JHDMI1.2 12.49,66.23 ; JHDMI1.2 11.92,65.66 ; JHDMI1.2 11.34,66.23 ; JHDMI1.2 11.46,65.77 ; 10.78,62.05 JHDMI1.20 ; JHDMI1.20 12.07,63.91 ; JHDMI1.20 13.35,62.98 ; JHDMI1.20 12.07,62.05 ; JHDMI1.20 13.35,62.05 ; JHDMI1.20 10.78,63.91 ; JHDMI1.20 10.78,62.98 ; JHDMI1.20 13.35,63.91 ; 130.36,47.24 H1.1 ; H1.1 133.4,47.24 ; H1.1 131.88,46.68 ; H1.1 130.36,50.28 ; H1.1 131.88,50.84 ; H1.1 133.96,48.76 ; H1.1 129.8,48.76 ; H1.1 133.4,50.28 ; JUSBC2.2 7.39,86.54 ; JUSBC2.2 6.84,86.54 ; JUSBC2.2 7.12,86.54 ; 7.95,84.06 JUSBC2.3 ; JUSBC2.3 6.61,84.06 ; JUSBC2.3 9.28,85.3 ; JUSBC2.3 9.28,84.06 ; JUSBC2.3 9.28,84.68 ; 2.58,61.08 JHDMI1.21 ; JHDMI1.21 5.15,61.08 ; JHDMI1.21 3.87,62.01 ; JHDMI1.21 5.15,62.01 ; JHDMI1.21 2.58,62.01 ; JHDMI1.8 12.37,69.69 ; JHDMI1.8 11.46,68.77 ; JHDMI1.8 12.37,68.77 ; JHDMI1.8 11.46,69.69 ; JUSBC2.4 7.95,95.2 ; JUSBC2.4 9.28,95.2 ; JUSBC2.4 6.61,95.2 ; JUSBC2.4 9.28,94.58 ; JUSBC2.4 9.28,93.96 ; 9.79,67.73 JHDMI1.5 ; JHDMI1.5 10.82,68.19 ; JHDMI1.5 10.94,67.73 ; JHDMI1.5 10.82,67.27 ; JHDMI1.5 9.91,68.19 ; JHDMI1.5 9.91,67.27 ; 7.12,92.72 JUSBC2.5 ; JUSBC2.5 7.39,92.72 ; JUSBC2.5 6.84,92.72
  IN2 w0.203: 12.07,62.05 JHDMI1.20 ; JHDMI1.20 10.78,63.91 ; JHDMI1.20 13.35,63.91 ; JHDMI1.20 10.78,62.05 ; JHDMI1.20 13.35,62.05 ; JHDMI1.20 12.07,63.91 ; JHDMI1.20 10.78,62.98 ; JHDMI1.20 13.35,62.98 ; 10.78,78.41 JHDMI1.22 ; JHDMI1.22 10.78,77.48 ; JHDMI1.22 13.35,77.48 ; JHDMI1.22 12.07,78.41 ; JHDMI1.22 13.35,76.55 ; JHDMI1.22 10.78,76.55 ; JHDMI1.22 13.35,78.41 ; JHDMI1.22 12.07,76.55
  IN3 w0.254: 75.3,11.41 75.3,7.12 76.55,5.87 v2(76.55,0.43) ; H2.1 109.33,89.75 v2(111.26,87.83) 111.43,87.83 113.5,85.76 118.33,85.76 119.51,86.94 139.88,86.94 140.95,85.87 146.26,85.87 v2(146.66,86.28)
  IN3 w0.508: 75.3,11.41 70.98,15.73 65.32,15.73 64.79,16.26 47.87,16.26 41.16,9.56 41.16,6.33 40.16,5.33 v2(40.16,3.71)
  GND2 w0.203: 155.9,29.69 H11.1 ; H11.1 159.51,31.21 ; H11.1 155.34,31.21 ; H11.1 157.43,33.29 ; H11.1 158.95,32.73 ; H11.1 155.9,32.73 ; H11.1 157.43,29.13 ; H11.1 158.95,29.69 ; 0.61,83.11 JUSBC2.1 ; JUSBC2.1 1.95,84.35 ; JUSBC2.1 3.28,83.11 ; JUSBC2.1 1.95,83.11 ; JUSBC2.1 3.28,83.73 ; JUSBC2.1 3.28,84.35 ; JUSBC2.1 0.61,83.73 ; JUSBC2.1 0.61,84.35 ; H2.1 106.37,91.83 ; H2.1 107.89,91.27 ; H2.1 108.45,89.75 ; H2.1 104.84,91.27 ; H2.1 104.84,88.23 ; H2.1 107.89,88.23 ; H2.1 106.37,87.67 ; H2.1 104.28,89.75 ; JHDMI1.21 3.87,62.01 ; JHDMI1.21 2.58,62.01 ; JHDMI1.21 5.15,62.01 ; JHDMI1.21 2.58,61.08 ; JHDMI1.21 5.15,61.08 ; 9.79,70.73 JHDMI1.11 ; JHDMI1.11 10.82,70.27 ; JHDMI1.11 10.82,71.19 ; JHDMI1.11 9.91,71.19 ; JHDMI1.11 9.91,70.27 ; JHDMI1.11 10.94,70.73 ; H13.1 19.35,38.41 ; H13.1 19.76,39.58 ; H13.1 16.59,39.58 ; H13.1 18.18,37.99 ; H13.1 18.18,41.17 ; H13.1 17,38.41 ; H13.1 19.35,40.75 ; H13.1 17,40.75 ; 11.46,69.69 JHDMI1.8 ; JHDMI1.8 12.37,68.77 ; JHDMI1.8 12.37,69.69 ; JHDMI1.8 11.46,68.77 ; H12.1 191.71,69.8 ; H12.1 188.52,69.8 ; H12.1 188.52,73 ; H12.1 187.93,71.4 ; H12.1 191.71,73 ; H12.1 190.12,69.22 ; H12.1 190.12,73.58 ; H12.1 192.3,71.4 ; JHDMI1.23 3.9,78.45 ; JHDMI1.23 1.33,78.45 ; JHDMI1.23 1.33,79.38 ; JHDMI1.23 2.62,80.31 ; JHDMI1.23 1.33,80.31 ; JHDMI1.23 3.9,80.31 ; JHDMI1.23 3.9,79.38 ; JHDMI1.23 2.62,78.45 ; 130.36,50.28 H1.1 ; H1.1 133.4,47.24 ; H1.1 133.96,48.76 ; H1.1 131.88,46.68 ; H1.1 129.8,48.76 ; H1.1 131.88,50.84 ; H1.1 133.4,50.28 ; H1.1 130.36,47.24 ; JHDMI1.20 13.35,62.05 ; JHDMI1.20 12.07,62.05 ; JHDMI1.20 13.35,62.98 ; JHDMI1.20 10.78,62.05 ; JHDMI1.20 10.78,62.98 ; JHDMI1.20 12.07,63.91 ; JHDMI1.20 10.78,63.91 ; JHDMI1.20 13.35,63.91 ; 9.91,73.27 JHDMI1.17 ; JHDMI1.17 10.82,73.27 ; JHDMI1.17 10.82,74.19 ; JHDMI1.17 9.79,73.73 ; JHDMI1.17 9.91,74.19 ; JHDMI1.17 10.94,73.73 ; JUSBC2.4 9.28,93.96 ; JUSBC2.4 7.95,95.2 ; JUSBC2.4 9.28,95.2 ; JUSBC2.4 9.28,94.58 ; JUSBC2.4 6.61,95.2 ; H15.1 96.09,3.17 ; H15.1 96.09,5.51 ; H15.1 93.33,4.34 ; H15.1 94.92,2.75 ; H15.1 94.92,5.93 ; H15.1 96.5,4.34 ; H15.1 93.74,3.17 ; H15.1 93.74,5.51 ; 0.61,94.91 JUSBC2.6 ; JUSBC2.6 3.28,95.53 ; JUSBC2.6 3.28,96.15 ; JUSBC2.6 0.61,95.53 ; JUSBC2.6 1.95,94.91 ; JUSBC2.6 1.95,96.15 ; JUSBC2.6 3.28,94.91 ; JUSBC2.6 0.61,96.15 ; 195.85,37.3 H5.1 ; H5.1 199.37,38.79 ; H5.1 197.89,35.27 ; H5.1 199.92,37.3 ; H5.1 196.4,38.79 ; H5.1 196.4,35.81 ; H5.1 197.89,39.33 ; H5.1 199.37,35.81 ; 76.94,6.76 JBATT1.10 ; JBATT1.10 78.34,6.76 ; JBATT1.10 76.94,8.77 ; JBATT1.10 77.64,8.77 ; JBATT1.10 77.64,6.76 ; JBATT1.10 76.94,7.77 ; JBATT1.10 78.34,8.77 ; JBATT1.10 78.34,7.77 ; 11.34,66.23 JHDMI1.2 ; JHDMI1.2 11.92,65.66 ; JHDMI1.2 11.46,65.77 ; JHDMI1.2 12.37,65.77 ; JHDMI1.2 11.46,66.69 ; JHDMI1.2 12.49,66.23 ; JHDMI1.2 12.37,66.69 ; H10.1 177.33,108.97 ; H10.1 177.33,105.79 ; H10.1 176.15,106.21 ; H10.1 178.5,108.55 ; H10.1 178.5,106.21 ; H10.1 176.15,108.55 ; H10.1 178.91,107.38 ; H10.1 175.74,107.38 ; H7.1 108.38,32.68 ; H7.1 105.41,35.65 ; H7.1 106.9,36.2 ; H7.1 106.9,32.13 ; H7.1 108.93,34.17 ; H7.1 104.86,34.17 ; H7.1 105.41,32.68 ; H7.1 108.38,35.65 ; 89.19,8.77 JBATT1.11 ; JBATT1.11 90.59,7.77 ; JBATT1.11 89.89,8.77 ; JBATT1.11 89.19,7.77 ; JBATT1.11 89.19,6.76 ; JBATT1.11 90.59,6.76 ; JBATT1.11 89.89,6.76 ; 89.89,10.24 JBATT1.12 ; JBATT1.12 89.89,12.24 ; JBATT1.12 90.59,12.24 ; JBATT1.12 90.59,10.24 ; JBATT1.12 89.19,12.24 ; JBATT1.12 90.59,11.24 ; JBATT1.12 89.19,11.24 ; JBATT1.12 89.19,10.24 ; 76.94,10.24 JBATT1.9 ; JBATT1.9 78.34,11.24 ; JBATT1.9 77.64,10.24 ; JBATT1.9 76.94,12.24 ; JBATT1.9 76.94,11.24 ; JBATT1.9 78.34,10.24 ; JBATT1.9 78.34,12.24 ; JBATT1.9 77.64,12.24 ; 80.86,46.68 H3.1 ; H3.1 78.78,48.76 ; H3.1 82.38,47.24 ; H3.1 82.94,48.76 ; H3.1 79.34,50.28 ; H3.1 80.86,50.84 ; H3.1 82.38,50.28 ; H3.1 79.34,47.24 ; H16.1 14.77,84.09 ; H16.1 13.43,80.92 ; H16.1 12.08,84.09 ; H16.1 15.25,82.75 ; H16.1 14.77,81.41 ; H16.1 12.08,81.41 ; H16.1 11.6,82.75 ; H16.1 13.43,84.58 ; 9.91,67.27 JHDMI1.5 ; JHDMI1.5 10.82,67.27 ; JHDMI1.5 9.79,67.73 ; JHDMI1.5 10.82,68.19 ; JHDMI1.5 9.91,68.19 ; JHDMI1.5 10.94,67.73 ; 12.07,76.55 JHDMI1.22 ; JHDMI1.22 13.35,78.41 ; JHDMI1.22 13.35,77.48 ; JHDMI1.22 10.78,78.41 ; JHDMI1.22 12.07,78.41 ; JHDMI1.22 10.78,77.48 ; JHDMI1.22 13.35,76.55 ; JHDMI1.22 10.78,76.55 ; 159.59,48.62 157.93,50.27 ; H18.1 66.39,95.77 ; H18.1 66.39,92.79 ; H18.1 63.42,95.77 ; H18.1 62.87,94.28 ; H18.1 66.94,94.28 ; H18.1 64.91,96.31 ; H18.1 64.91,92.25 ; H18.1 63.42,92.79 ; JUSBC2.3 9.28,85.3 ; JUSBC2.3 6.61,84.06 ; JUSBC2.3 7.95,84.06 ; JUSBC2.3 9.28,84.68 ; JUSBC2.3 9.28,84.06
  BOTTOM w0.102: v2(105.88,75.91) UC1.AB2
  BOTTOM w0.127: JSPK1.5 31.31,8.34 32.58,9.61 38.32,9.61 38.5,9.43 38.5,7.36 JSPK1.6
  BOTTOM w0.2: UC1.AW28 120.13,54.26 119.68,54.26 119.37,54.57 UC1.AV28
  BOTTOM w0.203: JHDMI1.5 10.82,67.27 ; JHDMI1.5 10.82,68.19 ; JHDMI1.5 10.94,67.73 ; JHDMI1.5 9.79,67.73 ; JHDMI1.22 13.35,77.48 ; JHDMI1.22 12.07,76.55 ; JHDMI1.22 10.78,77.48 ; JHDMI1.22 10.78,76.55 ; 12.07,62.05 JHDMI1.20 ; JHDMI1.20 13.35,62.98 ; JHDMI1.20 12.07,63.91 ; JHDMI1.20 10.78,62.98 ; v2(109.95,76.64) 109.95,76.55 109.5,76.11 109.5,75.43 UC1.AF1 109.5,75.17 109.5,74.63 UC1.AF3 ; v2(47.22,4.25) 47.15,4.17 PCB12.2 ; JHDMI1.2 12.49,66.23 ; JHDMI1.2 12.37,66.69 ; JHDMI1.2 11.46,66.69 ; JHDMI1.2 12.37,65.77 ; v2(95.23,75.96) 95.37,75.82 UC1.K1 ; PUM1.1 160.53,56.79 160.09,57.23 PCM18.2 ; U10.11 v2(50.68,89.88)
  BOTTOM w0.25: UC1.A5 89.59,73.5 v2(89.46,73.62) ; UC1.K5 UC1.K3 ; v2(89.59,64) 89.59,64 UC1.A16 ; v2(103.43,75.91) 103.43,75.84 103.97,75.3 UC1.Y1 104.28,75.21 104.28,74.59 UC1.Y3 ; v2(89.37,70) UC1.A10 ; v2(91.45,61) 91.45,61.14 91.73,61.42 91.73,61.76 UC1.E19 ; v2(91.45,61) 91.45,60.87 91.75,60.56 91.75,60.22 UC1.E21 ; v2(91.45,61) UC1.E20 ; UC1.A19 v2(89.37,62) ; UC1.A14 v2(89.37,66) ; v2(89.36,57.99) 89.36,57.95 89.41,58 UC1.A23 ; UC1.A12 v2(89.37,68) ; UC1.A21 v2(89.37,60) ; UC1.A7 v2(89.37,72)
  BOTTOM w0.254: v2(121.77,46.5) 124.06,46.5 ; v2(131.06,81.03) 131.06,80.68 130.47,80.09 130.47,78.63 129.64,77.81 127.27,77.81 ; v2(123.36,70.03) 123.33,70 UC1.BD10 ; UC1.AB16 UC1.AC17 ; CTP7.2 132.97,12.1 133.23,11.84 134.42,11.84 134.61,12.03 DTP1.1 ; UC1.AB18 UC1.AC19 UC1.AB20 v2(105.57,61.6) ; UC1.AM5 114.37,73.33 114.87,72.84 v2(114.87,72.27) ; PQD3.1 25.87,63.26 PRD7.2 25.9,63 25.29,62.39 v2(24.85,62.39) ; CA52.2 v2(23.89,56.76) ; v2(103.97,64.8) UC1.W15 UC1.V14 ; v2(24.5,29.9) 24.5,29.68 24.23,29.41 JSSD1.57 ; UC1.BD19 v2(123.37,62) ; v2(98.37,73.95) 98.49,73.95 99.04,73.4 UC1.P5 ; v2(98.37,73.95) UC1.N5 ; v2(98.37,73.95) 98.27,73.95 98.02,73.7 97.68,73.7 UC1.M5 ; v2(103.97,63.2) UC1.W17 UC1.V18 ; UC1.A26 v2(89.37,56) ; JEDP1.28 51.76,62.51 v2(51.81,62.46) ; v2(198.86,27.5) 199.45,26.51 JIO1.10 ; UC1.W13 v2(103.97,66.4) ; CFP2.2 113.05,10.84 RFP5.2 ; v2(102.02,8.02) 101.08,8.02 JFP1.9 ; v2(187.81,15.13) 187.5,14.82 JIO1.42 ; UC1.AJ19 111.58,61.95 v2(111.92,61.61) ; UC1.AJ19 UC1.AH18 ; UC1.AJ19 UC1.AH20 ; 127.27,77.81 126.63,77.17 124.91,77.17 122.79,75.05 v2(122.79,74.92) ; 127.27,77.81 126.53,78.54 126.4,78.54 126.15,78.8 124.68,78.8 123.1,77.21 123.09,77.21 123.04,77.16 123.04,77.05 122.3,76.31 v2(122.3,76.02) ; UC1.Y5 104.58,73.4 104.83,73.51 105.25,73.92 v2(105.37,73.92) 105.56,74.1 UC1.AB4 ; JIO1.28 v2(191.08,23.03) ; v2(104.85,10.69) 104.85,10.76 104.82,10.8 104.82,11.13 104.56,11.38 JFP1.4 ; v2(108.37,73.88) UC1.AE5 ; UC1.AE5 108.6,73.4 108.7,73.5 109.27,73.5 UC1.AF5 109.58,73.6 v2(109.86,73.6) ; UC1.AE5 UC1.AD5 ; UC1.E10 UC1.E8 91.57,71 v2(91.49,71.07) 91.68,71.27 91.68,71.76 91.92,72 UC1.E7 ; v2(139.08,42.5) 138.8,42.22 137.71,42.22 137.46,42.47 CC32.2 ; v2(111.45,75.88) 111.37,75.8 UC1.AJ1 ; v2(100.75,63.2) 100.37,63.58 UC1.R17 UC1.P16 ; JUSBC2.A12 8.82,92.8 v2(8.82,92.8) ; UC1.AD18 UC1.AE19 UC1.AD20 v2(107.18,61.6) ; 99.17,64.8 UC1.P16 ; UC1.P16 UC1.R15 ; CA51.2 21.73,25.71 v2(22.08,26.05) ; v2(123.88,74.72) 124.64,74.72 125.5,75.58 130.15,75.58 131.74,77.17 v2(131.74,77.36) ; 51.67,64.89 51.55,65.01 JEDP1.23 ; UC1.AA15 UC1.Y14 ; UC1.G1 93.29,75.21 93.29,74.59 UC1.G3 ; UC1.T18 UC1.U17 ; v2(100.78,61.7) 101.18,61.3 UC1.T20 ; CD102.2 CD101.2 v2(68.94,18.75) ; PR801.1 106.87,94.51 106.34,95.05 106.34,95.17 v2(106.02,95.48) 105.65,95.48 105.63,95.46 105.43,95.46 PC802.1 ; v2(91.46,66.93) 91.52,67 UC1.E13 ; PU1802.6 170.71,80.53 v2(171.35,81.17) ; UC1.AN5 115.83,73.4 v2(116.37,73.95) ; UC1.AJ3 UC1.AJ5 ; UC1.P14 v2(99.17,66.4) ; UC1.AH14 UC1.AJ15 111.58,65.13 v2(111.92,64.79) ; UC1.AF16 UC1.AG17 ; UC1.BD14 v2(123.37,66) ; UC1.AH16 UC1.AJ17 ; UC1.AV5 UC1.AU5 UC1.AR5 ; UC1.E12 UC1.E13 ; UC1.E13 UC1.E14 ; UC1.AR28 117.37,54.07 v2(117.36,54.06) ; UC1.AV1 119.37,75.68 v2(119.73,76.03) ; UC1.P18 v2(99.21,63.16) ; UC1.L15 96.58,65.09 v2(96.21,65.46) ; UC1.AB2 UC1.AB4 ; UC1.AB4 106.22,74.1 v2(106.37,73.95) ; v2(9.38,86.31) 9.38,86.49 9.11,86.75 JUSBC2.A1 ; UC1.M23 97.37,58.45 v2(96.95,58.88) ; CC27.2 132.07,78.3 132.43,77.95 136.4,77.95 136.47,78.02 136.47,81.27 136.17,81.58 132.5,81.58 131.92,80.99 CC28.2 ; UC1.BD23 v2(123.37,58) ; UC1.AN1 115.37,75.78 v2(115.31,75.85) ; JSSD1.27 v2(24.84,36.91) ; v2(154.07,70.01) 153.75,70.33 153.75,70.69 U19.5 ; JSSD1.51 v2(24.52,30.91) ; UC1.AF18 UC1.AG19 UC1.AF20 ; v2(115.04,15.14) 114.9,14.99 CD46.2 CD45.2 ; RTS8.2 177.49,54.25 v2(177.56,54.17) ; v2(51.93,69.7) 51.59,69.7 51.4,69.51 JEDP1.14 ; CC19.1 125.56,81.02 v2(126,80.57) ; UC1.AR1 117.21,75.46 117.21,75.82 117.47,76.08 117.47,76.98 v2(117.37,77.07) ; UC1.W5 103.2,73.58 102.8,73.58 102.43,73.95 v2(102.37,73.95) ; v2(14.28,68.42) 14.46,68.6 DH3.3 ; UC22.3 138.01,78.65 137.84,78.82 v2(137.83,78.82) ; UC1.BD21 v2(123.37,60) ; v2(100.78,66.4) UC1.T14 UC1.U15 ; UC1.Y16 UC1.AA17 ; v2(56.47,19.53) 56.43,19.56 56.43,20.21 CD99.2 CD100.2 ; v2(97.2,75.9) 97.37,75.72 UC1.M1 97.26,75.19 97.26,74.61 UC1.M3 ; v2(17.14,90.32) DT7.8 DT7.3 ; v2(91.82,54.45) 91.82,54.95 UC1.E27 ; v2(108.8,67.21) 108.39,66.8 UC1.AE13 ; UC1.W19 v2(103.97,61.6) ; JIO1.4 v2(201.34,28.91) ; UC1.AJ13 111.58,66.78 v2(111.92,66.44) 112.35,66 UC1.AK14 ; JSSD1.9 v2(24.91,41.41) ; JSSD1.39 v2(24.5,33.91) ; UC1.AD14 UC1.AE15 ; CA13.2 14.38,31.29 CA12.2 ; JWLAN1.1 164.88,46.55 165.14,46.8 JWLAN1.68 ; v2(203.94,26.5) 204.01,26.56 JIO1.41 ; UC1.T16 v2(100.78,64.8) ; UC1.AF14 UC1.AG15 ; v2(98.89,68.56) 98.61,68.56 UC1.N11 98.77,69.19 v2(98.82,69.19) ; QA4.1 17.81,21.74 18.06,21.48 18.61,21.48 19.11,20.98 QA4.4 19.64,20.63 v2(20.04,21.04) ; UC1.P1 v2(99.37,75.84) ; UC1.AA19 UC1.Y20 ; UC1.A10 UC1.C10 ; UC1.AD16 UC1.AE17 ; v2(51.81,63.15) 51.67,63.01 JEDP1.27 ; JIO1.7 v2(200.13,28.15) ; UC1.AC15 UC1.AB14 ; JSSD1.45 v2(24.54,32.41)
  BOTTOM w0.279: v2(123.14,72.13) 123.01,72 UC1.BD7 ; v2(170.67,41.93) 171.04,42.3 JWLAN1.18 ; JWLAN1.7 163.37,45.05 v2(163.08,44.76) ; UC1.T3 101.27,74.6 101.27,75.2 UC1.T1 101.64,75.57 101.64,75.87 v2(101.62,75.88) ; v2(113.39,75.79) 113.39,75.77 113.37,75.75 UC1.AL1
  BOTTOM w0.3: UC1.V22 102.27,59.2 v2(101.87,58.8) 101.48,58.4 UC1.T23 ; v2(114.91,55.71) 115.08,55.71 UC1.AN26 ; UC1.AF16 v2(108.77,64.8) UC1.AE15 ; UC1.Y20 v2(103.97,61.6) ; v2(104.37,54.05) 104.45,54.05 104.8,54.4 105.18,54.4 UC1.AA28 ; v2(104.37,54.05) UC1.Y28 ; v2(104.37,54.05) 104.29,54.05 103.94,54.4 103.57,54.4 UC1.W28 103.17,54.4 102.8,54.4 102.45,54.05 v2(102.37,54.05) ; UC1.G5 93.57,73.6 93.95,73.6 94.3,73.95 v2(94.37,73.95) ; v2(97.87,56.43) 98,56.43 UC1.N25 ; v2(121.32,69) 121.32,68.94 120.97,68.59 120.97,68.2 UC1.AY12 120.97,67.8 120.97,67.42 121.32,67.07 v2(121.32,67) ; v2(121.32,69) 121.32,69.07 120.97,69.42 120.97,69.8 UC1.AY10 120.97,70.2 120.97,70.57 121.32,70.92 v2(121.32,71) ; v2(121.32,69) UC1.AY11 ; UC1.V5 v2(102.37,73.95) 102.3,73.95 101.95,73.6 101.57,73.6 UC1.T5 101.17,73.6 100.81,73.6 100.46,73.95 v2(100.37,73.95) ; UC1.AY18 v2(121.32,63) ; v2(121.32,63) 121.32,62.92 120.97,62.57 120.97,62.2 UC1.AY19 120.97,61.8 120.97,61.43 121.32,61.08 v2(121.32,61) ; v2(121.32,63) 121.32,63.05 120.97,63.4 120.97,63.8 UC1.AY16 120.97,64.2 120.97,64.58 121.32,64.93 v2(121.32,65) ; v2(123.16,55.9) 123.14,55.9 123.04,56 UC1.BD26 ; v2(115.87,70) 115.48,69.6 UC1.AN10 ; UC1.V25 102.27,56.8 v2(101.87,56.4) 101.78,56.4 UC1.T26 ; UC1.AF18 v2(108.77,63.2) UC1.AE17 ; UC1.AY13 v2(121.32,67) ; v2(121.32,67) 121.32,66.93 120.97,66.58 120.97,66.2 UC1.AY14 120.97,65.8 120.97,65.43 121.32,65.08 v2(121.32,65) ; v2(95.29,62.44) 95.29,62.32 UC1.J19 ; UC1.K32 v2(95.37,52) ; v2(121.32,59) 121.32,59.08 120.97,59.43 120.97,59.8 UC1.AY21 121.07,60.3 121.07,60.69 121.32,60.94 v2(121.32,61) ; v2(121.32,59) 121.32,58.93 120.97,58.58 120.97,58.2 UC1.AY23 121.07,57.7 121.07,57.33 121.32,57.08 v2(121.32,57) ; v2(121.32,59) UC1.AY22 ; UC1.BD12 123.39,68 v2(123.41,67.98) ; v2(91.43,59) 91.43,58.94 91.78,58.59 91.78,58.2 UC1.E23 91.78,57.8 91.78,57.42 91.43,57.07 v2(91.43,57) ; v2(91.43,59) UC1.E22 ; v2(91.43,59) 91.43,59.08 91.78,59.43 91.78,59.8 UC1.E21 ; v2(107.18,66.4) UC1.AC13 ; v2(117.88,57.5) UC1.AT23 ; UC1.AY6 v2(120.88,73.5) UC1.AW5 ; v2(98.37,54.05) 98.46,54.05 98.81,54.4 99.17,54.4 UC1.P28 99.57,54.4 99.95,54.4 100.3,54.05 v2(100.37,54.05) ; v2(98.37,54.05) UC1.N28 ; v2(98.37,54.05) 98.32,54.05 97.97,54.4 97.57,54.4 UC1.M28 97.17,54.4 96.8,54.4 96.45,54.05 v2(96.37,54.05) ; v2(102.37,54.05) UC1.V28 ; v2(102.37,54.05) 102.31,54.05 101.96,54.4 101.57,54.4 UC1.T28 101.07,54.3 100.69,54.3 100.44,54.05 v2(100.37,54.05) ; v2(119.03,60.5) 118.97,60.5 118.58,60.9 UC1.AU20 ; v2(115.87,58) 115.48,58.4 UC1.AN23 ; v2(91.43,69) 91.43,69.06 91.75,69.39 91.75,69.59 91.97,69.82 UC1.E10 ; v2(91.43,69) 91.43,68.92 91.8,68.54 91.97,68.13 UC1.E12 ; v2(91.43,69) UC1.E11 ; UC1.L20 96.37,60.8 v2(96.37,60.5) ; UC1.V18 v2(102.37,63.2) UC1.U17 ; UC1.AA5 v2(105.37,73.92) ; UC1.AA23 105.07,58.1 104.97,58.1 v2(104.87,58) ; UC1.G32 93.37,52.53 v2(93.01,52.17) ; v2(121.77,52) UC1.BB32 ; v2(107.18,64.8) UC1.AC15 ; v2(116.96,56.39) 116.78,56.39 UC1.AP25 ; v2(121.32,57) 121.32,56.93 121.01,56.61 121.01,56.23 UC1.AY26 ; v2(121.32,57) UC1.AY25 ; UC1.AU18 118.97,62.6 v2(118.97,62.5) ; v2(91.43,57) 91.43,56.93 91.78,56.58 91.78,56.2 UC1.E26 ; v2(91.43,57) UC1.E25 ; v2(118.98,58.44) 118.58,58.84 UC1.AU22 ; UC1.W23 103.27,58.4 v2(102.87,58) ; UC1.AG13 v2(110.37,66.4) UC1.AH14 ; UC1.AH20 v2(110.37,61.6) UC1.AG19 ; v2(96.37,54.05) 96.29,54.05 95.94,54.4 95.57,54.4 UC1.K28 95.15,54.37 94.77,54.37 94.45,54.05 v2(94.37,54.05) UC1.H28 ; v2(96.37,54.05) UC1.L28 ; v2(96.37,73.95) 96.46,73.95 96.81,73.6 97.17,73.6 UC1.M5 ; v2(96.37,73.95) 96.3,73.95 95.75,73.4 UC1.K5 95.18,73.6 94.8,73.6 94.45,73.95 v2(94.37,73.95) ; v2(96.37,73.95) UC1.L5 ; v2(119.37,52.08) UC1.AV32 ; v2(104.37,73.95) 104.4,73.92 104.4,73.43 UC1.Y5 ; v2(104.37,73.95) 104.29,73.95 104.04,73.7 103.67,73.7 UC1.W5 ; v2(104.37,73.95) UC1.Y3 ; v2(92.37,73.97) UC1.F5 ; v2(111.92,61.61) 112.33,61.2 UC1.AK20 ; v2(121.32,71) UC1.AY8 ; v2(121.32,71) 121.32,71.05 120.97,71.4 120.97,71.8 UC1.AY7 ; v2(103.97,64.8) UC1.Y16 ; UC1.AB16 v2(105.57,64.8) UC1.AA15 ; UC1.AF14 v2(108.77,66.4) UC1.AE13 ; UC1.AA26 104.97,56.4 v2(104.87,56.4) ; UC1.V14 v2(102.37,66.4) 102.28,66.4 101.97,66.7 UC1.U13 ; UC1.F23 92.31,58.37 v2(92.31,58.5) ; UC1.AD1 107.37,75.73 v2(107.33,75.77) ; v2(111.93,63.2) 111.97,63.2 UC1.AK18 ; v2(117.39,61.61) 117.36,61.61 UC1.AR19 ; UC1.L25 96.74,57.17 v2(96.88,57.17) ; v2(105.57,61.6) UC1.AA19 ; UC1.AY15 v2(121.32,65) ; UC1.BB1 121.77,75.5 122.19,75.92 122.2,75.92 v2(122.3,76.02) ; UC1.AP18 116.57,62.6 v2(116.57,62.5) ; v2(116.91,55.63) 116.98,55.71 117.08,55.71 UC1.AR26 ; v2(119.7,61.5) 119.7,61.67 UC1.AV19 ; v2(114.87,69.2) 114.48,68.8 UC1.AM11 ; UC1.N15 99.17,64.8 ; UC1.Y25 104.07,56.5 v2(103.87,56.5) ; UC1.AV21 119.67,59.7 v2(119.67,59.5) ; UC1.AR5 117.18,73.6 116.8,73.6 116.45,73.95 v2(116.37,73.95) UC1.AP5 ; UC1.AR16 116.98,64.1 v2(117.37,64.5) ; v2(93.7,59.45) 93.77,59.45 94.18,59.05 UC1.H22 ; UC1.AC25 106.17,56.8 v2(105.87,56.5) ; UC1.AH18 v2(110.37,63.2) UC1.AG17 ; v2(111.92,64.79) 111.99,64.79 UC1.AK16 ; UC1.C32 v2(90.27,52) ; v2(100.37,54.05) UC1.R28 ; v2(100.78,64.8) UC1.R15 ; UC1.AA17 v2(105.57,63.2) UC1.AB18 ; UC1.BD30 122.67,53.3 v2(123.18,52.8) ; v2(103.87,58.9) 104.07,58.9 UC1.Y22 ; UC1.AV16 119.37,64.07 119.65,64.35 119.65,64.48 v2(119.67,64.5) ; UC1.AH16 v2(110.37,64.8) UC1.AG15 ; UC1.G26 v2(93.86,56.49) UC1.H25 ; UC1.Y14 v2(103.97,66.4) ; v2(107.18,61.6) UC1.AC19 ; UC1.P26 99.78,56.4 v2(99.87,56.4) 100.27,56.8 UC1.R25 ; v2(100.78,61.7) 100.48,62 UC1.R19 ; UC1.U19 v2(102.37,61.6) UC1.V20 ; UC1.BD16 123.12,64 v2(123.22,63.9) ; v2(101.37,52) UC1.T32 ; UC1.AV23 v2(118.92,57.54) ; UC1.AC17 v2(107.18,63.2) ; v2(94.37,73.95) UC1.H5 ; UC1.E19 91.78,62.2 91.78,62.58 91.43,62.93 91.43,63 ; UC1.A3 90.18,74.4 v2(90.56,74.02) 90.95,74.4 UC1.C3 ; UC1.R5 v2(100.37,73.95) ; v2(100.37,73.95) 100.3,73.95 99.94,73.59 99.56,73.59 UC1.P5 ; UC1.N22 98.27,59.2 v2(97.87,59.6) ; UC1.AG5 110.57,73.6 111.18,73.6 UC1.AJ5 111.65,73.68 112.04,73.68 112.33,73.97 v2(112.37,73.97) UC1.AK5 UC1.AL5 ; UC1.AA13 105.18,66.73 105.5,66.4 v2(105.57,66.4) UC1.AB14 ; v2(97.37,52) UC1.M32 ; UC1.N17 v2(99.21,63.16) ; v2(113.57,60.8) UC1.AM20 ; UC1.AP20 116.18,60.9 116.56,60.51 v2(116.56,60.41) 116.67,60.41 116.98,60.1 UC1.AR21 ; UC1.F21 92.65,60 92.35,60.3 v2(92.35,60.53) ; v2(103.97,63.2) UC1.Y18 ; UC1.AL16 v2(113.57,64.8) UC1.AM15 ; UC1.P20 v2(99.17,61.6) ; UC1.AF20 v2(108.77,61.6) UC1.AE19 ; UC1.A30 v2(89.67,53.2) ; v2(105.87,58.9) 106.07,58.9 UC1.AC22 ; v2(91.82,54.45) 92.32,54.45 UC1.F28 ; v2(122.79,74.92) 122.67,74.81 UC1.BD3 ; UC1.U15 v2(102.37,64.8) UC1.V16 ; UC1.N13 v2(99.17,66.4) ; UC1.AU25 v2(118.88,56.5) UC1.AV26 ; UC1.AU28 v2(118.37,54.05) 118.45,54.05 118.8,54.4 119.18,54.4 UC1.AV28 ; v2(96.87,55.7) 97.07,55.7 UC1.M26 ; UC1.AY20 v2(121.32,61) ; UC1.R13 v2(100.78,66.4) ; v2(105.37,52) UC1.AA32 ; UC1.H20 94.59,61.42 v2(94.59,61.49) ; UC1.AW28 120.88,54.5 v2(120.92,54.45) 120.92,54.95 UC1.AY27 ; UC1.E16 91.98,63.67 91.98,63.62 91.43,63.07 91.43,63 ; UC1.F19 92.37,61.7 92.37,61.66 v2(92.3,61.58) ; 91.43,63 UC1.E18 ; v2(103.37,52) UC1.W32 ; UC1.AC5 v2(106.37,73.95) 106.44,73.95 106.79,73.6 107.18,73.6 UC1.AD5 ; UC1.P32 v2(99.37,52)
  BOTTOM w0.305: CHDT3.2 141.53,45.24 v2(141.52,45.23) ; v2(103.43,75.91) 102.98,75.46 102.98,75.46 102.88,75.36 UC1.V2 UC1.V4 102.53,74.1 v2(102.37,73.95) ; CD97.2 CD95.2 v2(46,19.28) 46.05,19.28 CD96.2 ; JSSD1.33 24.28,35.41 24.35,35.49 v2(24.84,35.49) ; v2(97.87,59.6) 97.47,60 UC1.M21 ; v2(65.12,49.95) 65.12,49.9 65.16,49.86 JSSD2.39 ; UC1.W26 v2(103.87,56.5) ; JSSD2.3 56.16,47.74 55.95,47.53 v2(55.95,47.25) ; CC51.2 66.89,19.21 v2(67.1,19) ; UC1.G1 93.2,75.3 92.97,75.53 v2(92.93,75.53) ; JWLAN1.37 163.4,35.55 v2(163.11,35.26) ; v2(180.41,53.78) 180.41,53.9 179.84,54.47 Q202.4 ; v2(38.12,19.77) 38.17,19.82 CD59.2 ; JWLAN1.31 163.4,37.05 v2(163.11,36.76) ; UC1.E14 UC1.E15 91.97,64.69 v2(92.22,64.45) 91.97,64.2 UC1.E16 ; JWLAN1.61 163.5,29.55 163.17,29.23 v2(163.15,29.23) ; v2(57.88,47.27) 57.88,47.3 57.66,47.52 JSSD2.9 v2(57.66,52.98) ; JSSD2.33 63.66,50.28 63.5,50.44 v2(63.5,50.96) 63.5,51.54 63.66,51.69 v2(63.66,52.98) ; JSSD2.27 v2(62.16,50.91) v2(62.16,52.98) ; JTP1.5 v2(129.53,10.81) ; JSSD2.1 v2(55.66,50) ; v2(107.18,66.4) UC1.AD14 ; UC1.G16 93.07,64.3 v2(93.07,64.5) ; v2(163.11,33.75) 163.41,34.05 JWLAN1.43 ; JWLAN1.55 163.41,31.05 v2(163.11,30.75) ; JSSD1.15 v2(24.84,39.91) ; v2(109.86,73.6) 110.17,73.6 UC1.AG5 ; CD44.2 102.74,15.45 v2(102.68,15.51) ; v2(24.84,38.46) 24.8,38.41 JSSD1.21 ; UC1.K26 95.79,56.42 95.99,56.42 UC1.L25 ; JWLAN1.69 163.5,26.95 v2(163.17,26.62) ; v2(163.06,45.83) 163.06,46.32 163.29,46.55 JWLAN1.1 ; JSSD2.57 v2(69.66,49.94) ; v2(163.11,32.25) 163.41,32.55 JWLAN1.49 ; v2(94.37,54.05) 94.31,54.05 94.02,54.34 93.76,54.34 93.39,54.55 UC1.G28 ; CHDT2.2 v2(145.52,55.9) ; UC1.K16 95.78,63.9 v2(96.17,63.5) ; v2(59.16,53.02) JSSD2.15 ; CWL9.2 168.04,57.65 v2(168.63,57.65) ; v2(111.93,63.2) 111.58,63.55 UC1.AJ17 ; v2(96.37,60.5) 95.88,60 UC1.K21 ; UWL1.2 168.56,52.09 168.84,51.81 168.84,51.11 v2(168.82,51.11) ; v2(163.11,38.26) 163.4,38.55 JWLAN1.25 ; v2(107.18,63.2) UC1.AD18 ; JWLAN1.67 163.5,28.05 v2(163.17,27.73) ; CHDT1.2 v2(150.98,55.9) ; v2(71.01,20.6) 71.17,20.44 CD103.2 ; v2(182.29,56.09) 181.97,55.77 Q202.1 ; v2(107.18,64.8) UC1.AD16 ; JSSD2.21 60.66,50.31 60.34,50.63 v2(60.34,50.95) 60.34,51.53 60.66,51.85 v2(60.66,52.94) ; U20.2 v2(148.31,55.65) ; JSSD2.45 v2(66.66,49.97) ; JSSD2.51 v2(68.16,49.97)
  BOTTOM w0.35: UC1.H13 94.18,67.1 v2(93.78,67.5) ; UC1.AC11 106.77,69.2 v2(106.87,69.2) ; UC1.V8 102.48,71.2 v2(102.87,71.6) ; v2(118.97,69.5) 118.97,69.35 118.62,69 UC1.AU11 ; UC1.AP13 116.52,67.34 v2(116.58,67.34) ; UC1.AK8 111.97,71.61 v2(111.88,71.61) ; v2(114.77,70.85) 114.73,70.85 UC1.AM8 ; v2(95.36,63.52) 94.69,63.52 UC1.H18 ; UC1.AR12 116.98,68.1 v2(117.37,68.5) ; UC1.AU13 118.58,67.08 v2(118.95,67.45) ; UC1.R11 100.47,68.8 v2(100.87,69.2) ; UC1.V11 102.47,68.8 102.89,69.21 v2(102.89,69.91) ; UC1.AV7 v2(118.88,71.5) UC1.AU8 ; UC1.Y11 104.48,68.8 v2(104.87,69.2) ; v2(115.89,71.76) 115.89,71.73 115.92,71.71 115.92,71.66 UC1.AP8 ; v2(119.67,70.51) 119.67,70.3 UC1.AV10 ; v2(116.57,65.5) 116.18,65.1 UC1.AP15 ; v2(96.17,63.5) 96.58,63.1 UC1.L18 ; UC1.AC8 106.48,71.2 v2(106.87,71.6) ; v2(113.88,72.42) 113.81,72.42 113.39,72 UC1.AL7 ; UC1.AG11 110.9,69.32 110.9,69.95 v2(110.85,70) ; v2(113.87,69.97) 113.5,69.6 UC1.AL10 ; UC1.AG8 v2(110.85,71.67) ; v2(117.87,72.42) 117.45,72 UC1.AR7 ; UC1.AN7 115.67,72.3 115.85,72.3 v2(115.89,72.34) ; UC1.R22 100.27,59.2 v2(99.87,58.8) 99.48,58.4 UC1.P23 ; v2(117.37,66.5) 116.98,66.1 UC1.AR14 ; v2(108.8,67.21) 108.8,67.77 108.84,67.81 108.84,68.41 108.45,68.8 UC1.AE11 ; v2(96.17,67.5) 96.58,67.1 UC1.L13 ; v2(119.68,68.5) 119.68,68.3 UC1.AV12 ; v2(98.9,72.27) 98.9,71.72 UC1.N8
  BOTTOM w0.356: PRD8.2 24.57,66.98 PQD3.4
  BOTTOM w0.381: 156.21,71.44 155.5,71.44 v2(154.07,70.01) ; CD23.2 137.52,23.23 CD107.2 ; DH2.3 v2(14.13,65.17) ; CD5.1 94.79,20.49 v2(95.08,20.2) ; DTP1.1 135.46,12.59 v2(136.2,13.33) ; C241.2 154.48,64.62 C240.2 ; v2(126.2,22.46) 126.22,22.47 CD110.2 ; CD81.2 34.1,20.46 33.72,20.08 33.18,20.08 v2(32.91,20.35) ; PRB24.2 54.87,7.82 54.28,8.4 PCB8.2 v2(53.65,9.14) PCB9.2 ; UC1.AL10 113,69.22 112.8,69.22 UC1.AK11 ; RC65.2 CC33.2 135.13,75.41 136.02,76.29 136.56,76.29 137.02,75.82 v2(137.02,75.63) ; CH6.2 v2(21.21,77.21) ; CD111.2 108.42,22.03 v2(108.32,21.92) ; CA31.2 8.31,31.16 CA22.2 ; CH5.2 17.17,73.02 v2(16.87,72.71) 17.17,72.71 17.55,72.33 CH13.2 ; 15.6,71.77 14.71,71.77 14.05,72.43 v2(13.62,72.43) ; v2(140.72,53.74) 140.69,53.71 UC2.4 ; RC54.1 116.8,79.38 ; 116.8,79.38 v2(116.8,80.02) ; 116.8,79.38 116.78,79.39 116.35,79.39 RC50.1 116.03,79.93 RC53.1 ; v2(49.28,22.98) 49.01,22.98 CD56.1 ; CD109.2 128.85,24.36 v2(128.85,23.91) ; C237.2 v2(151.75,74.88) ; v2(35.47,46.18) 35.33,46.33 USD1.3 ; JHDT1.17 v2(144.19,46.01) ; RHDT7.1 147.81,45.06 147.67,45.06 v2(147.23,45.5) 146.98,45.75 RHDT8.1 146.52,45.5 146.09,45.06 145.06,45.06 RHDT9.1 ; RD36.1 RD34.2 115.57,22.73 v2(115,23.3) ; JHDT1.5 151.81,46.86 v2(151.08,46.13) 150.54,46.68 JHDT1.7 ; CC22.2 121.95,78.02 121.58,77.65 v2(121.58,77.42) ; v2(49.18,21.35) 49.52,21.7 CD61.2 ; v2(13.79,29.91) 14.25,30.37 CA12.2 ; v2(152.39,49.46) 153.08,48.77 JHDT1.3 ; RD33.2 RD35.1 104.12,20.74 v2(104.03,20.66) ; v2(50.16,99.52) 50.56,99.12 C4.2 ; RKBL5.1 134.22,8.15 JTP1.10 ; C243.2 147.67,71.57 C242.2 147.83,71.02 148.58,71.02 148.58,71.05 148.63,71.05 v2(148.66,71.02) ; CD57.1 CD58.1 49.58,19.65 v2(49.09,19.16) ; v2(129.49,18.44) 129.37,18.32 CD7.1 ; v2(87.57,54.2) 87.48,54.11 87.19,54.11 87.19,54.11 86.76,54.11 86.76,54.11 86.55,54.11 85.68,53.23 CC17.1 ; v2(134.33,15.92) 135.22,15.92 CD51.2 135.37,16.71 CD53.2 135.37,18.06 CD108.2 ; PCB22.2 43.95,7.9 v2(43.52,8.33) ; CD50.2 CD44.2 103.39,15.05 CD42.2 CD43.2 ; CSD12.2 41.43,48.15 v2(41.46,48.18) ; CWL61.2 170.53,56.13 v2(170.98,56.58) ; CTS5.2 v2(173.28,48.62) ; CSD10.2 32.43,52.37 v2(32.3,52.25) ; UC1.AN22 115.42,59.2 v2(115.81,58.81) ; CA50.2 24.98,53.69 24.39,54.28 v2(24.39,54.41) ; CH14.2 17.15,70.63 v2(16.89,70.38) ; CD52.2 115.05,13.82 115.43,13.44 v2(115.43,13.26) ; C74.2 v2(56.61,100.01) ; v2(92.02,19.59) 92.02,19.28 92.37,18.93 CD6.1
  BOTTOM w0.4: UC1.AV14 119.56,66.18 119.56,66.38 v2(119.67,66.5) ; v2(118.97,65.5) 118.58,65.1 UC1.AU15
  BOTTOM w0.457: v2(46.07,0.43) 46.25,0.61 PCB30.2 ; v2(54.3,12.3) 54.3,12.07 PCB1.2 ; v2(8.65,31.98) 8.65,31.92 8.13,31.4 CA31.2 ; v2(53.69,12.3) 53.09,11.7 PCB15.2 ; PC832.2 107.92,98.18 v2(107.53,97.8) ; v2(107.34,98.76) 106.87,98.29 PC844.2 ; v2(54.92,12.29) 55.32,12.29 55.78,11.83 PCB2.2 ; PRD8.2 23.03,67.14 22.97,67.2 v2(22.9,67.2) ; PCB28.2 v2(44.5,0.43) ; DT1.2 16.23,92.76 16.69,93.21 v2(16.7,93.21)
  BOTTOM w0.508: CA15.1 3.76,35.18 3.74,35.16 CA32.2 2.96,34.61 2.87,34.7 v2(2.66,34.7) ; v2(126.2,22.46) 126.66,22 CD18.2 CD8.2 ; 155.08,64.19 155.08,64.39 C240.2 ; 155.08,64.19 v2(155.08,64.14) ; 155.08,64.19 C316.2 ; RC569.1 RC115.1 144.62,58.73 v2(144.67,58.68) ; CA3.2 25.47,2.16 25.09,2.55 CA2.2 25.09,3.79 25.14,3.84 DA2.2 25.14,5.09 v2(25.52,5.47) 25.82,5.77 v2(26.13,5.77) ; C236.2 v2(152.2,74.23) ; v2(90.53,99.41) 90.72,99.6 PR829.2 ; v2(106.97,100.03) 106.97,100.22 PC9119.2 ; v2(164.98,59.48) 164.9,59.48 164.7,59.28 PRM9.2 ; v2(168.28,74.78) 168.29,74.78 168.29,74.79 PC724.2 ; DA4.1 16.01,59.12 v2(15.26,59.86) ; v2(125.61,27.32) 125.63,27.31 CD27.2 ; v2(85.26,59.2) RC8.2 RC18.2 ; v2(131.74,77.36) 131.88,77.5 CC27.2 ; RA30.2 v2(16.64,46.75) ; v2(151.11,93.54) 151.11,93.54 PC603.2 ; v2(160.18,59.89) 160.86,59.89 PCM17.2 160.93,59.29 160.85,59.21 160.23,59.21 PCM19.2 ; v2(173.82,76.5) 173.82,76.51 PR1809.2 ; RSD3.2 v2(38.01,47.53) ; v2(51.35,94.49) 51.18,94.33 C75.2 C76.2 ; PCD6.2 23.22,65.42 v2(22.9,65.11) ; v2(73.88,18.54) 73.13,19.29 CD62.2 ; DA3.1 17.62,51.06 v2(17.45,50.89) ; U5.2 v2(49.57,95.71) ; D33.1 21.67,62.25 22.22,62.79 v2(22.22,63.38) ; PC812.2 89.64,97.86 v2(89.61,97.88) ; PC11.2 77.3,3.52 v2(77.37,3.6) ; JFAN2.4 190.91,51.25 190.99,51.33 v2(190.99,51.71) ; PC854.2 85.8,55.34 v2(85.13,55.34) ; PCM18.2 160.61,58.12 160.67,58.06 v2(160.7,58.06) ; PCM1.2 144.5,38.98 143.53,38 v2(143.22,38) ; CD16.2 135.18,14.42 v2(135.17,14.43) ; v2(148.44,6.56) 148.44,6.7 149.36,7.62 JKBL1.5 ; RFP5.2 113.64,10.88 v2(113.77,11) ; PCM6.2 144.58,36.59 143.3,36.59 v2(143.18,36.48) ; v2(166.09,89.78) 166.09,89.8 165.67,90.23 ; PCM5.2 165.6,53.45 165.93,53.78 v2(166.23,53.78) ; JKBL1.1 146.36,12.06 145.71,12.72 v2(145.39,12.72) ; CD2.2 RD37.1 94.35,18.62 v2(94.66,18.93) ; PRB7.2 46.26,2.56 PCB31.2 46.21,1.71 PCB30.2 ; DFP1.1 92.7,11.81 v2(92.41,11.52) ; v2(152.7,33.8) 152.35,33.45 151.83,33.45 PCM8.2 ; CD25.2 133.32,28.48 v2(133.39,28.4) ; RC615.2 129.05,70.53 v2(129.26,70.31) ; PC815.2 98.96,105.03 98.86,105.03 98.85,105.05 v2(98.83,105.05) ; v2(166.41,56.9) 166.38,56.87 PCM2.2 ; DT16.2 33.81,88.41 33.8,88.4 33.31,88.4 v2(33,88.09) ; v2(175.11,78.78) 174.65,78.32 PR1811.2 174.61,78.28 173.99,77.66 ; v2(44.81,76.62) 44.81,76.03 45.67,75.16 JEDP1.42 ; v2(45.74,95.18) 45.95,94.98 C80.2 ; JFP1.10 v2(108.22,10.34) ; CD14.2 115.61,12.83 115.61,13.09 v2(115.43,13.26) ; CC50.2 55.34,18.9 v2(54.94,18.5) ; v2(61.63,20.66) 61.29,21.01 CD60.2 ; CT56.1 13.48,91.08 v2(13.55,91) ; v2(117.06,16.97) 116.36,17.67 CD19.2 ; v2(38.12,19.77) 37.99,19.63 CC48.2 ; C239.2 156.6,71.05 156.21,71.44 ; v2(25.95,58.25) 25,58.25 24.36,58.88 PRD4.2 PRD3.2 ; PCD2.2 34.01,74.19 v2(34.2,74) ; v2(27.59,63.3) PRD9.2 27.59,62.42 28.19,61.82 PRD5.2 ; v2(102.78,20.34) 103.6,19.53 CD17.2 ; PCD3.2 v2(35.54,70.12) ; v2(19.73,79.64) JDCIN1.5 ; v2(114.08,25.82) 114.13,25.86 CD26.2 ; v2(116.09,24.77) 116.12,24.8 CD11.2 ; v2(85.31,67.81) RC10.2 ; v2(133.18,10.04) 133.68,9.54 JTP1.10 ; CC23.1 137.01,73.42 v2(136.76,73.17) ; CD50.2 102.84,16.9 CD13.2 101.62,17.74 v2(101.88,18) ; v2(23.85,78.06) 23.83,78.04 JDCIN1.2 ; v2(2.68,32.75) 3.19,32.75 3.25,32.81 CA33.2 ; v2(35.26,71.57) 34.83,71.14 PCD4.2 ; v2(117.95,16.29) 118.2,16.03 CD112.2 ; PCB3.2 59.97,2.74 v2(60.76,3.52) ; v2(186.69,17.81) 186.3,17.42 186.1,17.42 186.04,17.36 JKB2.36 ; JDCIN1.1 22.58,78.06 v2(22.58,78.06) ; CD21.2 110.86,25.91 v2(111.57,25.2) ; PCM16.2 v2(152.62,34.6) ; v2(113.33,77.87) 113.33,78.08 113.64,78.4 RC66.2 CC24.1 ; v2(128.72,29.77) 128.51,29.57 CD24.2 ; v2(143.18,37.3) 143.2,37.32 144.03,37.32 144.49,37.78 PCM15.2 ; v2(116.54,7.25) 116.96,6.83 CTP4.2 ; v2(158.88,87.95) 159.4,87.43 PC612.2 ; C7.2 v2(50.65,79.88) ; CA4.2 24.46,9.42 26.17,9.42 v2(26.24,9.34) ; RD47.1 48.68,19.56 v2(49.09,19.16) ; PCM13.2 165.79,55.95 165.8,55.96 v2(166.41,55.96) ; PCB24.2 v2(44.58,4.39) ; CD23.2 136.77,23.22 v2(136.76,23.23) ; v2(114.92,20.55) 115.19,20.29 CD9.2 ; CA30.2 2.8,31.9 2.29,31.39 v2(2.3,31.37) 2.7,30.98 CA1.2 ; JSSD2.68 v2(54.56,47.27) 54.43,47.15 50.71,47.15 50.21,47.66 D6.2 ; v2(19.47,73.23) 19.34,73.36 UH1.2 ; v2(45.84,57.36) 45.86,57.36 45.86,57.36 JEDP1.44 ; JP2.2 v2(195.05,50.44) ; PC726.2 v2(171.15,74.08) ; PR605.2 164.84,88.54 v2(164.85,88.54) ; RC30.1 CC18.1 v2(120.34,80.6) ; CC28.2 131.1,80.99 v2(131.06,81.03) ; v2(106.7,18.03) 106.85,18.18 CD10.2 ; PCM3.2 152.09,32.19 v2(152.7,32.79) ; CLRP1.2 92.7,10.41 v2(92.28,10.83) ; v2(77.28,4.4) 77.26,4.4 77.24,4.39 PC10.2 ; PRM14.1 v2(164.63,60.06) ; v2(104.49,17.99) 105.17,17.3 CD1.2 ; v2(43.76,19) 43.81,18.95 CC49.2 ; CD12.2 134.59,29.88 v2(134.25,29.53) ; JTP1.9 127.52,8.69 128.05,8.16 128.77,8.16 v2(128.85,8.23) ; PR607.2 165.48,89.15 v2(165.48,89.15) ; CH11.2 CH12.2 25.18,72.72 v2(25.12,72.66) ; v2(119.49,29.18) 119.32,29.01 CD20.2 ; v2(27.88,81.86) 28.06,81.67 JDCIN1.6 ; CC20.1 141.19,63.38 v2(140.96,63.61) ; CD15.2 126.28,15.83 v2(126.12,15.98) ; PC9103.2 v2(162.6,77.37) ; v2(44.1,66.26) JEDP1.43 ; v2(161.14,49.03) 161.45,49.03 161.95,49.53 PDM1.2 162.82,50.32 PCM10.1 ; v2(163.78,87.37) 163.77,87.37 163.31,87.82 PR609.2 ; RC71.1 137.94,74.63 137.02,75.54 v2(137.02,75.63) ; Q146.3 162.98,68.06 v2(162.98,68.22) ; PC615.2 163.14,86.73 v2(163.15,86.73) ; CD47.2 116.48,15.65 v2(116.24,15.88) ; CTP1.2 v2(125.11,11.36) ; v2(46.48,95.95) 46.84,95.59 C79.2 ; C73.2 v2(54.98,99.88) ; CD22.2 96.12,16.94 v2(95.16,15.98) ; v2(142.15,9.61) 141.53,9.61 JKBL1.6 ; PC828.2 PC827.2 98.32,90.02 v2(98.4,89.93) ; CT54.1 12.88,90.19 13.01,90.32 v2(13.63,90.32) ; v2(85.13,56.98) PC855.2 ; v2(152.77,19.87) 152.77,18.51 151.61,17.36 JKB2.35 ; JSPK1.5 32.36,4.65 v2(32.93,4.65) ; CD98.2 57.75,20.02 57.27,19.54 v2(57.09,19.54) ; CSD4.2 v2(28.74,22.76)
  BOTTOM w1.016: JSPK1.6 v2(40.16,3.71) ; 119.49,34.18 117.61,32.31 111.08,32.31 108.66,29.89 104.88,29.89
  vias: v1(15.79,61.61) v1(17.38,77.68) v1(17.57,88.35) v1(19.47,31.07) v1(19.73,9.61) v1(21.89,47.45) v1(31.47,10.11) v1(41.57,11.07) v1(69.38,99.65) v1(70.72,103.27) v1(71.1,100.98) v1(73.13,97.62) v1(74.78,104.41) v1(75.23,85.74) v1(87.35,86) v1(88.94,67.46) v1(89.32,79.01) v1(96.49,85.69) v1(97.45,97.87) v1(98.78,95.97) v1(113.71,103.14) v1(122.98,101.81) v1(123.04,96.28) v1(125.9,95.4) v1(145.58,60.6) v1(146.16,86.63) v1(146.73,84.54) v1(151.24,102.32) v1(152.57,99.21) v1(157.71,79.27) v1(159.55,38.94) v1(162.92,91.71) v1(165.97,94.57) v1(168.7,71.52) v1(172.25,67.01) v1(173.02,69.3) v1(173.65,82.19) v1(175.75,70.19) v1(187.18,57.61) v2(0.43,96.15) v2(0.51,46.38) v2(0.5,39.73) v2(0.5,37.19) v2(0.5,34.65) v2(0.5,32.11) v2(0.95,81.05) v2(0.95,78.51) v2(1.32,29.77) v2(1.53,98.44) v2(1.79,100.97) v2(2.97,62.05) v2(3.06,84.45) v2(3.74,78.41) v2(4.04,29.77) v2(4.33,100.97) v2(5.13,94.81) v2(5.32,84.45) v2(5.51,62.05) v2(6.02,78.41) v2(6.58,29.77) v2(6.87,100.97) v2(7.26,37.83) v2(7.26,35.86) v2(7.26,33.89) v2(8.05,62.05) v2(8.56,78.41) v2(9.12,29.77) v2(9.22,37.83) v2(9.22,33.89) v2(9.39,100.95) v2(9.8,76.19) v2(9.8,65.01) v2(10.13,63.51) v2(10.87,75.74) v2(11.11,87.48) v2(11.19,37.83) v2(11.19,35.86) v2(11.19,33.89) v2(11.54,99.56) v2(11.54,97.02) v2(11.66,29.72) v2(13.93,28.63) v2(14.02,96.47) v2(14,70.09) v2(14.52,88.28) v2(14.59,94.35) v2(14.67,93.04) v2(15.42,26.51) v2(15.62,93.75) v2(15.66,88.22) v2(15.71,24) v2(15.71,21.46) v2(15.74,19.72) v2(16.56,96.47) v2(18.01,92.79) v2(18.36,89.9) v2(18.3,88.78) v2(18.41,92.18) v2(18.38,90.99) v2(18.58,17.27) v2(18.77,34.64) v2(18.71,14.47) v2(18.71,13.89) v2(18.71,13.3) v2(18.71,12.72) v2(18.71,12.11) v2(18.71,11.52) v2(18.71,10.94) v2(18.71,10.36) v2(18.71,9.77) v2(18.71,9.19) v2(18.71,7.12) v2(18.71,4.58) v2(18.71,2.04) v2(19.1,96.47) v2(19.54,89.93) v2(19.63,88.78) v2(19.58,87.69) v2(20.67,0.43) v2(20.81,88.73) v2(21.07,94.87) v2(21.5,81.93) v2(21.91,92.47) v2(21.92,66.79) v2(22,65.14) v2(22.2,83.14) v2(22.2,25.24) v2(22.2,24.61) v2(22.39,28.91) v2(22.39,23.97) v2(22.39,23.34) v2(22.9,61.42) v2(23.21,0.43) v2(24.04,91.09) v2(24.72,46.33) v2(25.16,45.95) v2(25.37,30.05) v2(25.61,45.57) v2(25.75,0.43) v2(26.03,31.15) v2(26.29,33.17) v2(26.57,91.29) v2(26.98,35.59) v2(27.8,85.73) v2(27.8,84.38) v2(28.36,29.99) v2(28.29,0.43) v2(28.48,85.06) v2(28.59,37.37) v2(28.83,92.47) v2(29.15,85.73) v2(29.15,84.38) v2(29.63,35.39) v2(29.63,34.24) v2(29.66,12.63) v2(29.7,31.83) v2(29.68,11.41) v2(29.68,10.83) v2(30.06,87.84) v2(30.01,73.93) v2(30.83,0.43) v2(31.37,92.47) v2(33.28,11.93) v2(33.37,0.43) v2(33.68,12.39) v2(33.91,92.47) v2(35.91,0.43) v2(36.24,13.92) v2(36.45,92.47) v2(36.96,86.1) v2(36.96,84.47) v2(36.96,82.85) v2(38.45,0.43) v2(38.59,86.1) v2(38.59,84.47) v2(38.59,82.85) v2(38.89,12.87) v2(38.99,92.47) v2(39.48,12.87) v2(39.48,12.29) v2(39.68,13.43) v2(39.82,18.47) v2(40.06,12.92) v2(40.06,12.34) v2(40.21,86.1) v2(40.21,84.47) v2(40.21,82.85) v2(40.35,11.83) v2(40.64,12.92) v2(40.64,12.34) v2(40.95,11.82) v2(40.99,0.43) v2(41.23,12.92) v2(41.23,12.34) v2(41.53,92.54) v2(41.54,11.82) v2(41.81,12.93) v2(41.81,12.34) v2(42.32,12.62) v2(42.55,13.18) v2(42.58,13.76) v2(43.32,94.34) v2(43.53,0.43) v2(44.36,83.06) v2(44.4,82.46) v2(45.12,96.13) v2(45.15,78.47) v2(46.75,49.84) v2(46.91,97.93) v2(47.2,8.55) v2(47.25,7.41) v2(47.2,6.22) v2(47.3,11.17) v2(47.81,53.07) v2(48.37,8.53) v2(48.37,7.38) v2(48.37,6.29) v2(48.61,0.43) v2(48.73,99.74) v2(48.87,85.62) v2(49.46,85.63) v2(49.71,107.9) v2(49.71,102.06) v2(51.1,109.27) v2(51.15,0.43) v2(51.76,56.34) v2(51.78,56.98) v2(53.11,86.81) v2(53.11,86.23) v2(53.34,69.64) v2(53.64,109.27) v2(53.69,0.43) v2(55.22,69.53) v2(55.95,3.53) v2(56.18,109.27) v2(56.23,0.43) v2(56.54,3.53) v2(57.12,3.54) v2(57.7,3.54) v2(58.29,3.54) v2(58.72,109.27) v2(58.77,0.43) v2(58.87,3.54) v2(60.7,75.14) v2(61.26,109.27) v2(61.31,0.43) v2(62.69,6.88) v2(62.69,6.29) v2(63.27,6.29) v2(63.3,6.88) v2(63.5,7.43) v2(63.61,10.94) v2(63.61,10.36) v2(63.61,9.77) v2(63.61,9.19) v2(63.61,8.6) v2(63.61,8.02) v2(63.8,109.27) v2(63.86,6.29) v2(63.85,0.43) v2(63.91,6.88) v2(64.11,60.47) v2(64.14,11.22) v2(64.14,10.64) v2(64.14,10.05) v2(64.14,9.47) v2(64.14,8.88) v2(64.14,8.27) v2(64.09,7.43) v2(64.44,6.22) v2(64.93,68.48) v2(64.94,61.61) v2(65.33,50.98) v2(65.8,52.52) v2(66.34,109.27) v2(66.39,0.43) v2(68.88,109.27) v2(68.93,0.43) v2(69.03,71.2) v2(69.7,67.54) v2(69.89,51.26) v2(70.83,71.18) v2(71.06,67.68) v2(71.42,109.27) v2(71.47,0.43) v2(71.73,102.56) v2(71.73,101.54) v2(71.73,100.53) v2(71.73,99.51) v2(71.73,98.49) v2(72.43,54.44) v2(72.75,102.56) v2(72.75,101.54) v2(72.75,100.53) v2(72.75,99.51) v2(72.75,98.49) v2(73.33,16.02) v2(73.33,15.44) v2(73.77,102.56) v2(73.77,101.54) v2(73.77,100.53) v2(73.77,99.51) v2(73.77,98.49) v2(73.75,53.09) v2(73.96,109.27) v2(73.91,16.02) v2(73.91,15.44) v2(74.01,0.43) v2(74.08,51.03) v2(74.49,16.02) v2(74.49,15.44) v2(74.78,102.56) v2(74.78,101.54) v2(74.78,100.53) v2(74.78,99.51) v2(74.78,98.49) v2(75.61,47.39) v2(75.8,102.56) v2(75.8,101.54) v2(75.8,100.53) v2(75.8,99.51) v2(75.8,98.49) v2(76,91.38) v2(76,90.37) v2(76,89.35) v2(76,88.33) v2(76.03,87.5) v2(76.01,86.85) v2(76.03,85.51) v2(76.05,84.65) v2(76.09,54.74) v2(76.5,109.27) v2(76.76,91.38) v2(76.76,90.37) v2(76.76,89.35) v2(76.76,88.33) v2(76.78,86.85) v2(76.81,102.56) v2(76.81,101.54) v2(76.81,100.53) v2(76.81,99.51) v2(76.81,98.49) v2(76.79,87.5) v2(76.79,85.51) v2(76.81,84.65) v2(77.42,67.06) v2(79.04,109.27) v2(79.09,0.43) v2(80.8,67.94) v2(81.58,109.27) v2(81.63,0.43) v2(84.12,109.27) v2(84.17,0.43) v2(85.42,99.15) v2(85.42,98.57) v2(85.84,11.82) v2(85.84,11.23) v2(86.47,48.2) v2(86.43,12.06) v2(86.43,11.47) v2(86.4,10.86) v2(86.66,109.27) v2(86.59,91.31) v2(86.59,90.29) v2(86.59,89.27) v2(86.59,88.26) v2(86.59,87.24) v2(86.6,85.27) v2(86.67,50.2) v2(86.71,0.43) v2(87.01,12.06) v2(87.01,11.42) v2(87.01,10.84) v2(87.27,85.25) v2(87.35,91.31) v2(87.35,90.29) v2(87.35,89.27) v2(87.35,88.26) v2(87.35,87.24) v2(87.6,12.06) v2(87.6,11.42) v2(87.6,10.84) v2(87.87,51.4) v2(88.24,69.4) v2(88.27,50) v2(88.18,12.06) v2(88.18,11.42) v2(88.18,10.84) v2(88.76,11.42) v2(88.76,10.84) v2(89.2,109.27) v2(89.25,0.43) v2(89.57,48.2) v2(90.64,46.46) v2(91.37,50) v2(91.46,75.54) v2(91.57,48.2) v2(91.74,109.27) v2(92.34,75.52) v2(92.98,23.27) v2(93.78,47.2) v2(93.79,44.96) v2(94.28,109.27) v2(94.87,49.23) v2(95.5,99.06) v2(95.5,96.99) v2(95.5,94.92) v2(95.65,87.81) v2(96.27,87.83) v2(96.82,109.27) v2(96.9,87.83) v2(97.12,86.72) v2(97.25,87.31) v2(97.37,48.9) v2(97.57,99.06) v2(97.57,96.99) v2(97.57,94.92) v2(97.55,87.81) v2(99.36,109.27) v2(99.37,48.9) v2(99.36,46.63) v2(99.51,20.81) v2(99.64,99.06) v2(99.64,96.99) v2(99.64,94.92) v2(100.45,3.32) v2(101.37,49.6) v2(101.37,47.2) v2(101.9,109.27) v2(102.99,3.32) v2(104.44,109.27) v2(105.53,3.32) v2(106.98,109.27) v2(108.07,3.32) v2(109.52,109.27) v2(109.82,21.09) v2(110.61,3.32) v2(110.81,47.78) v2(110.86,46.69) v2(111.26,87.24) v2(112.06,109.27) v2(113.15,3.32) v2(113.34,103.75) v2(113.92,103.75) v2(114.56,86.89) v2(114.6,109.27) v2(115.14,86.89) v2(115.67,15.49) v2(115.69,3.32) v2(116.32,13.26) v2(117.14,109.27) v2(117.19,10.52) v2(117.37,48.9) v2(117.8,10.52) v2(118.23,3.32) v2(118.47,82.37) v2(118.96,101.66) v2(118.96,101.07) v2(118.96,100.49) v2(118.96,99.9) v2(118.96,99.32) v2(119.1,82.37) v2(119.37,49.23) v2(119.35,46.92) v2(119.55,101.66) v2(119.55,101.07) v2(119.55,100.49) v2(119.55,99.9) v2(119.55,99.32) v2(119.68,109.27) v2(119.93,82.38) v2(120.13,101.66) v2(120.13,101.07) v2(120.13,100.49) v2(120.13,99.9) v2(120.13,99.32) v2(120.56,82.38) v2(120.72,101.66) v2(120.72,101.07) v2(120.72,100.49) v2(120.72,99.9) v2(120.72,99.32) v2(120.77,3.32) v2(120.84,98.71) v2(120.84,98.13) v2(120.84,97.54) v2(121,77.42) v2(121.3,101.66) v2(121.3,101.07) v2(121.3,100.49) v2(121.3,99.9) v2(121.3,99.32) v2(121.32,24.1) v2(121.43,98.71) v2(121.43,98.13) v2(121.43,97.54) v2(121.77,48.9) v2(121.89,101.66) v2(121.89,101.07) v2(121.89,100.49) v2(121.89,99.9) v2(121.89,99.32) v2(122.01,98.71) v2(122.01,98.13) v2(122.01,97.54) v2(122.22,109.27) v2(122.6,98.71) v2(122.6,98.13) v2(122.6,97.54) v2(123.18,50.4) v2(123.18,98.71) v2(123.18,98.13) v2(123.18,97.54) v2(123.31,3.32) v2(123.77,98.71) v2(123.77,98.13) v2(123.77,97.54) v2(124.35,101.05) v2(124.35,100.46) v2(124.35,99.88) v2(124.35,99.29) v2(124.35,98.71) v2(124.35,98.13) v2(124.35,97.54) v2(124.76,109.27) v2(124.93,101.05) v2(124.93,100.46) v2(124.93,99.88) v2(124.93,99.29) v2(124.93,98.71) v2(124.93,98.13) v2(124.93,97.54) v2(125.18,54.2) v2(125.18,51.8) v2(125.18,49.4) v2(125.52,101.05) v2(125.52,100.46) v2(125.52,99.88) v2(125.52,99.29) v2(125.52,98.71) v2(125.52,98.13) v2(125.52,97.54) v2(125.85,3.32) v2(126.1,101.05) v2(126.1,100.46) v2(126.1,99.88) v2(126.1,99.29) v2(126.1,98.71) v2(126.1,98.13) v2(126.1,97.54) v2(126.69,100.46) v2(126.69,99.88) v2(126.69,99.29) v2(126.69,98.71) v2(126.69,98.13) v2(126.69,97.54) v2(126.88,57.55) v2(127.07,54.3) v2(127.07,50.3) v2(127.27,100.46) v2(127.27,99.88) v2(127.27,99.29) v2(127.27,98.71) v2(127.27,98.13) v2(127.27,97.54) v2(127.3,109.27) v2(127.88,60.05) v2(128.39,3.32) v2(128.67,55.3) v2(128.67,53.7) v2(128.69,51.59) v2(129.84,109.27) v2(130.93,3.32) v2(131.74,57.76) v2(132.38,109.27) v2(132.66,58.42) v2(133.35,30.47) v2(133.47,3.32) v2(133.61,27.68) v2(134.13,87.67) v2(134.71,87.67) v2(134.92,109.27) v2(135.3,87.67) v2(135.88,87.67) v2(136.01,3.32) v2(136.68,109.27) v2(137.46,109.27) v2(137.72,99.97) v2(138.07,4.84) v2(138.1,100.48) v2(138.48,99.97) v2(138.87,100.48) v2(139.25,99.97) v2(139.63,100.48) v2(140,109.27) v2(140.21,103.75) v2(140.6,13.41) v2(140.58,5.02) v2(140.97,103.75) v2(141.74,103.75) v2(142.54,109.27) v2(142.5,103.75) v2(143.12,5.2) v2(145.02,61.4) v2(145.02,60.81) v2(145.08,109.27) v2(145.66,5.36) v2(146.66,85.51) v2(146.71,103.7) v2(146.71,102.79) v2(147.25,86.28) v2(147.25,85.51) v2(147.62,109.27) v2(147.62,5.49) v2(149.44,99.47) v2(149.44,98.89) v2(150.03,99.47) v2(150.03,98.89) v2(150.16,109.27) v2(150.14,96.39) v2(150.14,95.8) v2(150.09,6.07) v2(150.56,99.14) v2(150.56,98.56) v2(150.56,97.97) v2(150.56,97.39) v2(151.15,99.14) v2(151.15,98.56) v2(151.15,97.97) v2(151.15,97.39) v2(151.15,96.8) v2(151.13,10.93) v2(151.13,8.39) v2(151.73,99.14) v2(151.73,98.56) v2(151.73,97.97) v2(151.73,97.39) v2(151.73,96.8) v2(152.31,98.56) v2(152.31,97.97) v2(152.31,97.39) v2(152.31,96.8) v2(152.7,109.27) v2(153.19,12.42) v2(153.74,106.95) v2(153.74,104.41) v2(154.25,101.93) v2(155.7,78.39) v2(155.73,12.42) v2(156.24,77.85) v2(156.34,100.42) v2(156.64,79.36) v2(157.18,78.82) v2(157.46,37.67) v2(157.46,37.04) v2(157.46,36.4) v2(157.71,80.35) v2(158.09,37.67) v2(158.09,37.04) v2(158.09,36.4) v2(158.25,79.81) v2(158.27,12.42) v2(158.65,81.31) v2(158.73,38.31) v2(158.73,37.67) v2(158.73,37.04) v2(158.73,36.4) v2(158.88,100.41) v2(159.19,80.77) v2(159.36,38.31) v2(159.36,37.67) v2(159.36,37.04) v2(159.36,36.4) v2(159.54,82.17) v2(159.79,91.66) v2(160,38.31) v2(160,37.67) v2(160,37.04) v2(160,36.4) v2(160.08,81.64) v2(160.53,83.22) v2(160.76,92.6) v2(160.76,90.87) v2(160.71,54.96) v2(160.87,52.43) v2(160.8,51.85) v2(160.81,12.42) v2(161.02,101.81) v2(161.07,82.68) v2(161.33,55.58) v2(161.33,54.34) v2(161.5,91.59) v2(161.61,106.82) v2(161.61,104.28) v2(161.95,54.96) v2(162.27,109.27) v2(163.35,12.42) v2(163.43,92.94) v2(163.97,93.48) v2(163.97,92.4) v2(164.51,94.02) v2(164.51,92.94) v2(164.81,109.27) v2(165.05,94.55) v2(165.05,93.48) v2(165.59,94.02) v2(165.89,12.42) v2(166.67,71.14) v2(167.05,103.95) v2(167.35,109.27) v2(167.55,71.33) v2(167.75,104.54) v2(167.72,103.9) v2(168,71.77) v2(168.43,12.42) v2(168.51,72.28) v2(168.89,72.73) v2(169.37,105.99) v2(169.58,79.81) v2(169.58,79.09) v2(169.89,109.27) v2(170.3,79.81) v2(170.3,79.09) v2(170.73,65.39) v2(170.97,12.42) v2(171.12,82.42) v2(171.17,65.93) v2(171.38,64.69) v2(171.56,81.96) v2(171.96,81.53) v2(171.88,65.23) v2(172.03,64.55) v2(172.43,109.27) v2(172.43,63.96) v2(172.52,65.88) v2(172.62,82.85) v2(172.72,64.94) v2(172.8,80.99) v2(173.03,82.42) v2(173.16,64) v2(173.14,28.06) v2(173.21,81.43) v2(173.24,64.62) v2(173.46,82.87) v2(173.41,65.58) v2(173.51,12.42) v2(173.63,83.57) v2(173.87,64.71) v2(173.78,28.06) v2(174.06,66.1) v2(174.06,65.36) v2(174.41,56.77) v2(175.44,68.12) v2(175.44,67.37) v2(176.05,12.42) v2(176.19,68.12) v2(176.19,67.37) v2(177.55,69.18) v2(177.96,69.61) v2(178.24,69.05) v2(178.34,70.1) v2(178.55,61.96) v2(178.64,69.49) v2(178.59,12.42) v2(178.74,70.53) v2(179.01,62.39) v2(179.44,62.82) v2(179.53,69.31) v2(179.85,70.72) v2(179.96,69.74) v2(181.13,12.42) v2(181.39,103.82) v2(181.39,101.28) v2(182.74,99.12) v2(183.67,12.42) v2(185,97.96) v2(185.44,56.16) v2(185.44,55.45) v2(185.41,54.67) v2(185.39,53.98) v2(186.08,95.66) v2(186.21,12.42) v2(187.05,56.98) v2(187.16,93.37) v2(187.81,56.98) v2(187.94,90.95) v2(188,17.93) v2(188.55,88.48) v2(188.51,56.98) v2(188.75,12.42) v2(189.17,86.02) v2(189.59,17.61) v2(189.78,83.55) v2(189.88,23.03) v2(190.39,81.09) v2(190.48,23.63) v2(190.48,22.43) v2(191,78.62) v2(191.29,12.42) v2(192.51,56.28) v2(192.51,55.39) v2(192.51,54.5) v2(192.51,53.61) v2(192.95,27.55) v2(193.83,12.42) v2(193.97,17.59) v2(194.04,66.3) v2(194.61,44.47) v2(194.61,43.77) v2(194.61,42.94) v2(194.68,63.83) v2(195.29,61.37) v2(195.55,17.48) v2(195.91,58.9) v2(196.37,12.54) v2(196.52,56.44) v2(197.13,53.97) v2(197.17,17.87) v2(197.74,51.51) v2(198.35,49.04) v2(198.87,12.98) v2(198.97,46.58) v2(199.56,44.11) v2(201.29,13.74) v2(201.58,37.79) v2(202.16,26.12) v2(202.15,24.33) v2(202.86,35.6) v2(202.8,17.04) v2(203.62,17.35) v2(203.6,14.81) v2(204.14,33.4) v2(204.38,24.72) v2(204.64,18.12) v2(204.7,20.08) v2(205.42,31.21) v2(205.78,24.4) v2(205.78,16.1) v2(205.91,18.88) v2(206.16,21.54) v2(206.23,20.08) v2(206.35,23) v2(206.7,29.02) v2(207.43,20.08) v2(207.81,21.73) v2(207.94,26.8) v2(207.97,17.4) v2(209.19,24.59) v2(210.15,18.7) v2(210.79,22.61) v2(212.03,20.4)
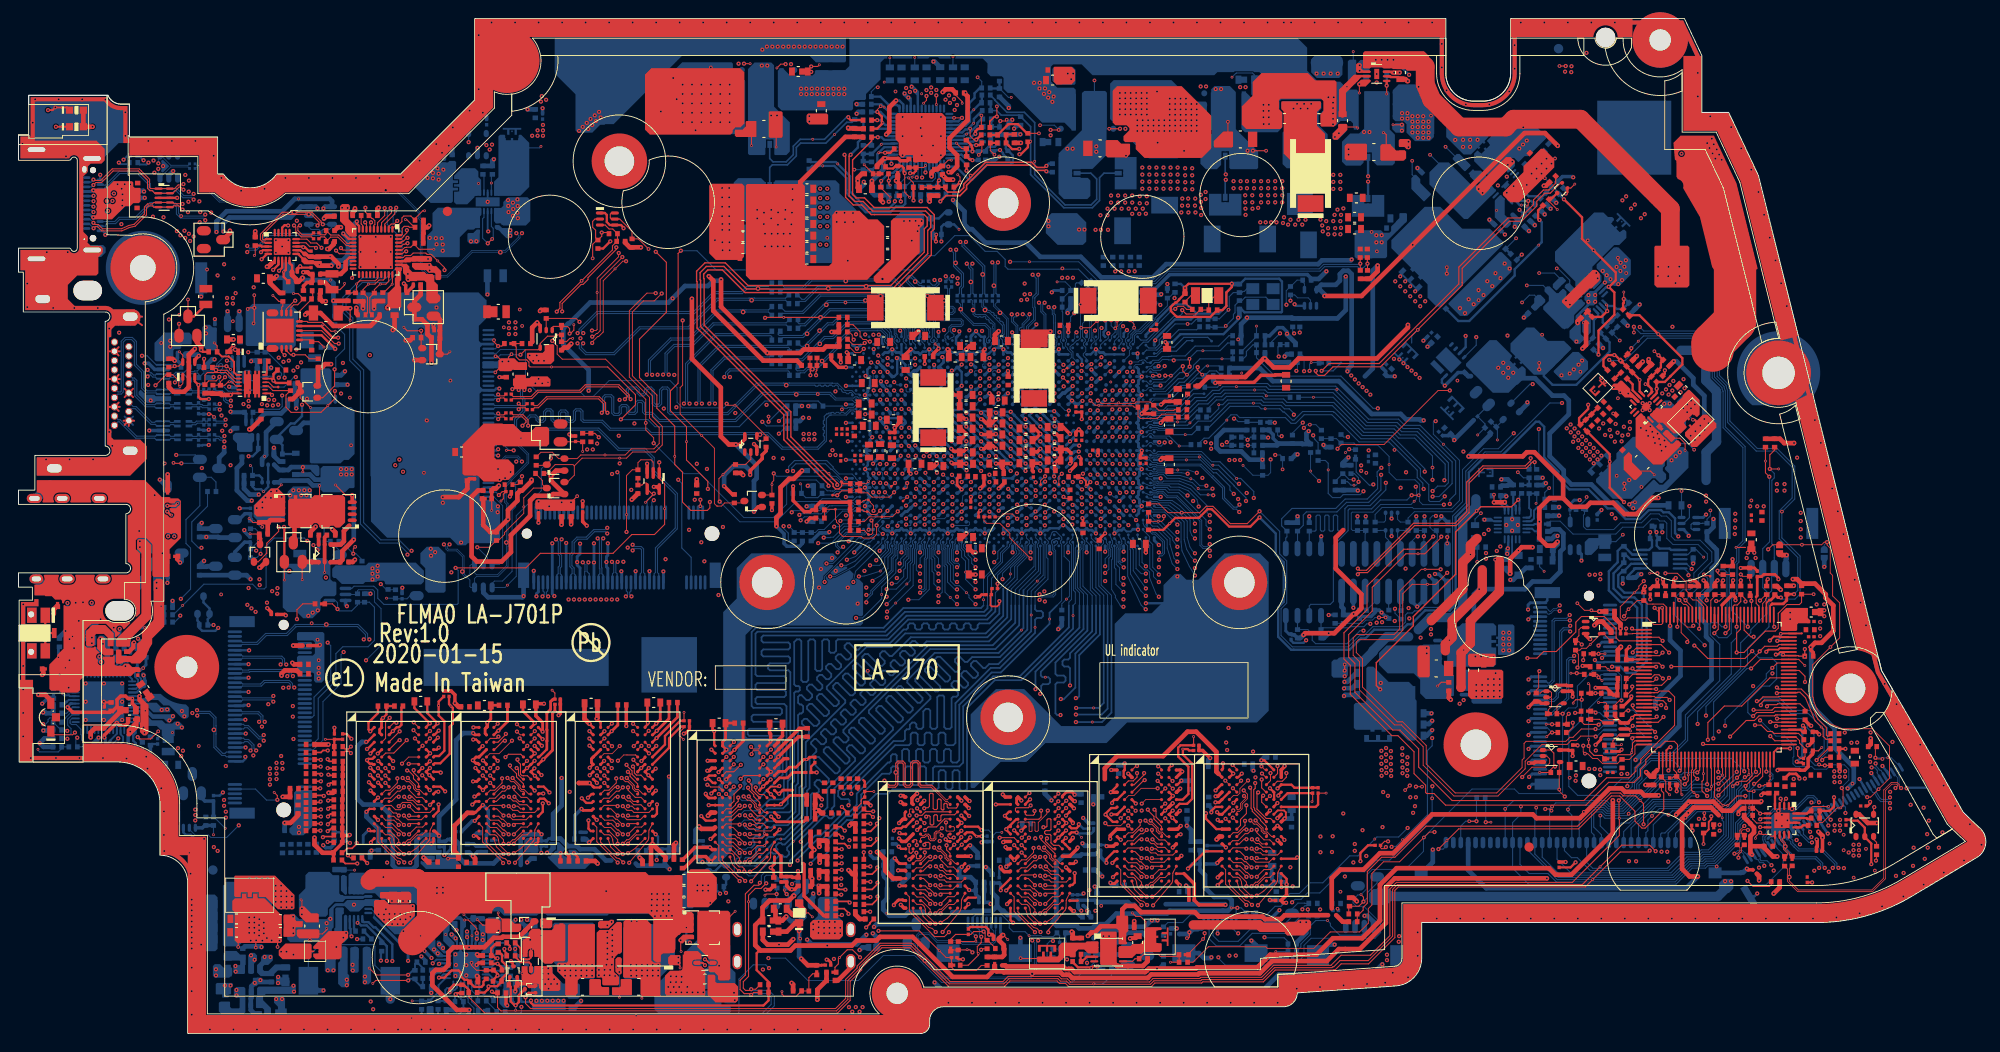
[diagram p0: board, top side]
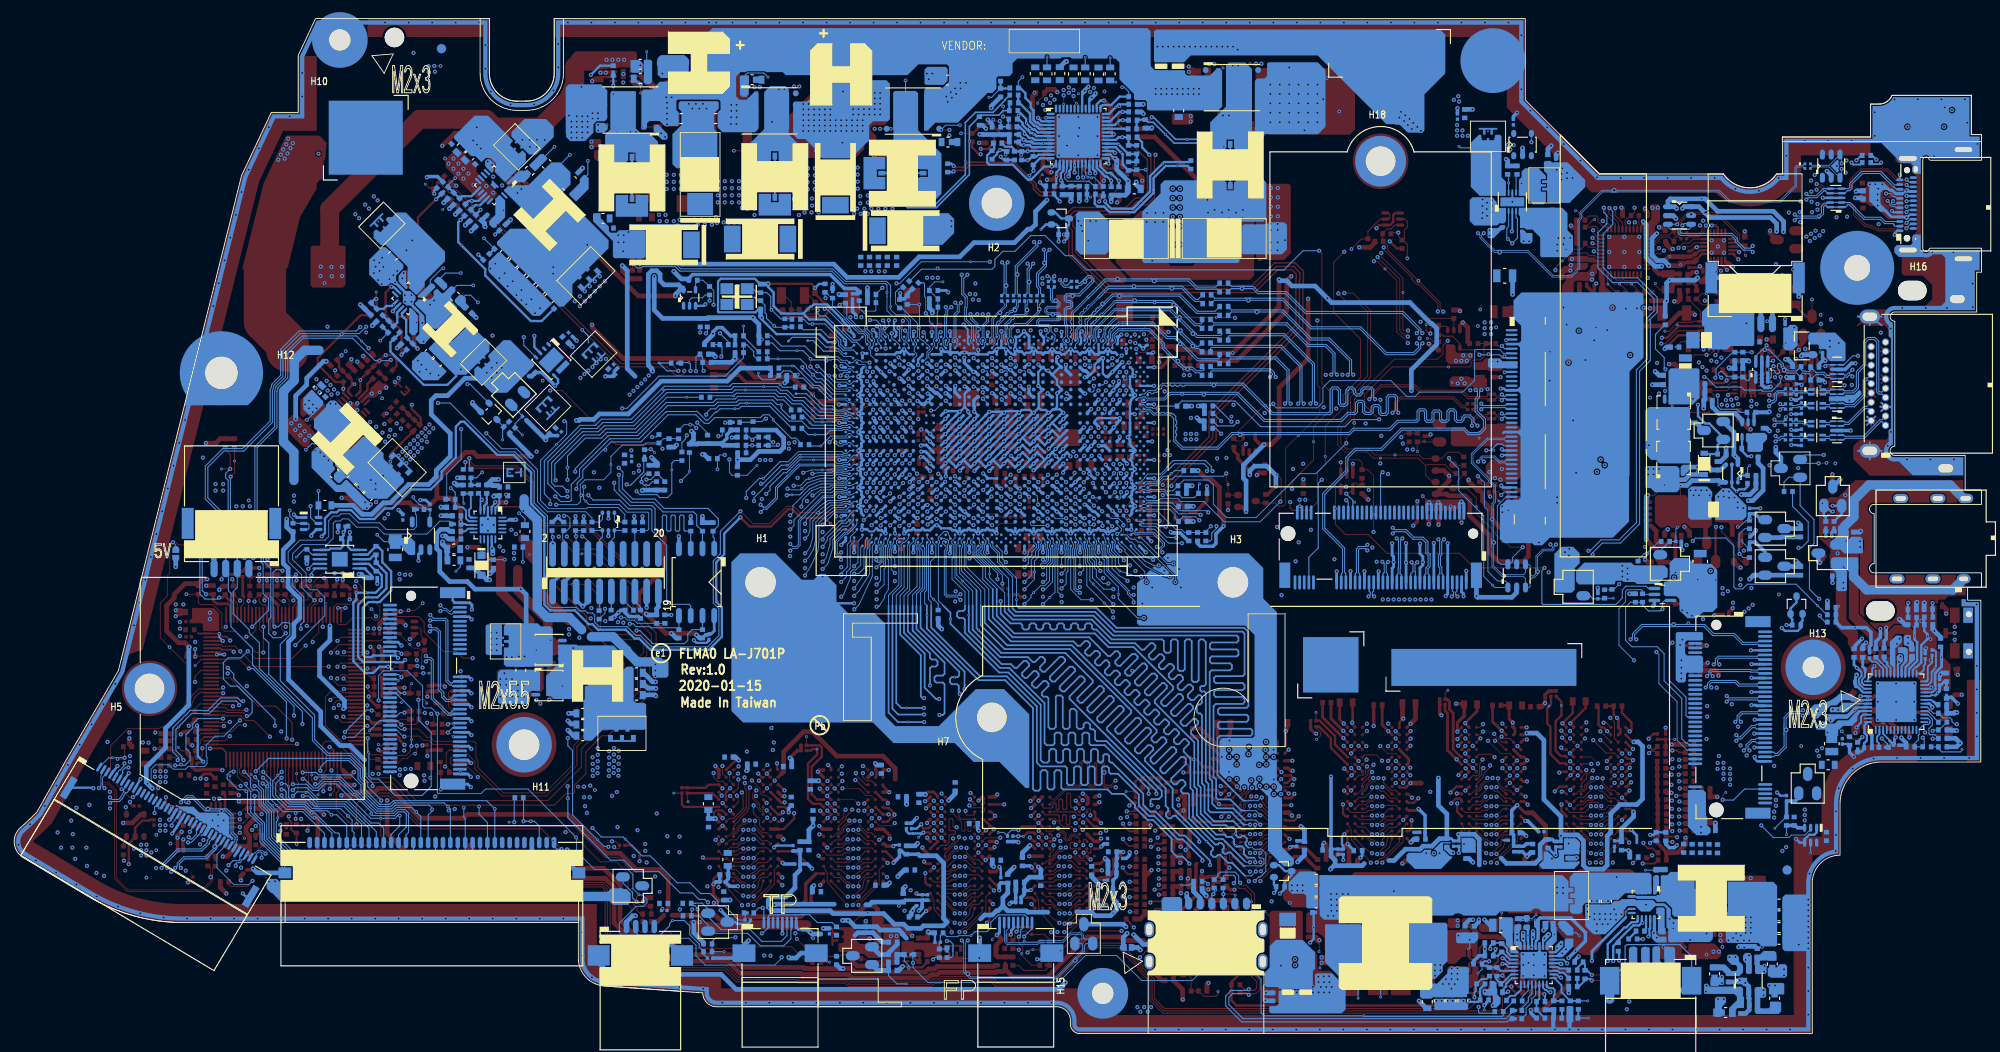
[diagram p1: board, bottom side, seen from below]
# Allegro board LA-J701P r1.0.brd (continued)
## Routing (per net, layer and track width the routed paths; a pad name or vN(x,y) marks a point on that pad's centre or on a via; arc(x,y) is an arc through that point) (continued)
GNDA: length 23.6
  TOP w0.457: v2(12.47,42.26) 12.4,42.18 12.4,41.72 11.94,41.27 CA17.2
  TOP w0.508: v2(14.71,58.18) 15.18,57.71 RA32.2
  VCC w0.203: 4.24,48.46 JP3.5 ; JP3.5 6.25,48.46 ; JP3.5 6.25,49.13 ; JP3.5 5.25,48.46 ; JP3.5 4.24,49.13
  BOTTOM w0.203: v2(11.55,39.71) 11.8,39.45 11.8,38.77 12.27,38.29 UA1.37 ; UA1.22 5.54,37.26 v2(5.41,37.38)
  BOTTOM w0.381: CA35.1 16.11,48.73 v2(16.08,48.7) ; CA10.1 6.07,41.57 v2(6,41.65) ; CA9.1 10.52,42.41 10.29,42.64 v2(10.29,43.86) ; v2(12.47,42.26) 12.83,41.9 CA7.1 ; v2(4.44,38.8) 4.44,38.75 4.52,38.66 CA24.2 ; CA8.1 13.64,41.7 13.64,41.93 v2(12.91,42.66)
  BOTTOM w0.508: v2(13.03,54.31) 13.15,54.2 RA24.2 ; v2(6.18,46.55) 6.2,46.53 CA19.1 ; CA6.2 4.28,38.96 v2(4.44,38.8) ; CA14.1 4.42,42.84 v2(5.08,43.5) 5.26,43.68 RA18.1 ; v2(6.96,46.6) 7.04,46.53 CA18.1 ; RA17.1 8.23,44.16 8.84,44.77 v2(8.87,44.77)
  vias: v1(5.5,42.63) v1(5.5,40.34) v1(6.52,44.6) v2(15.55,51.9)
PVCC_CPU: length 3.1
  TOP w0.117: v3(101.94,100.54) 101.94,100.71 101.24,101.41 PR811.1
  TOP w0.508: PR811.1 100.85,102.05 100.13,102.05 v2(99.83,101.75)
VBUS_DSCHG: length 70.4
  TOP w0.117: QT1.2 v2(17.34,76.7) ; UT1.8 37.59,87.53 v2(37.44,87.67) ; UT4.11 23.45,70.38 22.4,71.44 20.41,71.44 20.13,71.16 RT59.2 20.54,70.53 21.34,70.53 21.7,70.88 v2(21.7,70.97) ; v2(34.59,74.57) 34.14,74.57 32.74,75.96 UT6.7
  IN1 w0.102: v2(25.4,80.65) 33.56,80.65 ; 33.56,80.65 34.46,79.75 34.46,78.76 33.89,78.19 33.89,74.95 34.27,74.57 v2(34.59,74.57) ; 33.56,80.65 35.72,82.81 35.72,86.3 37.09,87.67 v2(37.44,87.67)
  IN2 w0.127: v2(29.95,70.95) 29.95,71.04 31.11,72.2 31.11,73.92 25.4,79.62 v2(25.4,80.65)
  IN3 w0.127: v2(25.4,80.65) 22.19,80.65 18.24,76.7 v2(17.34,76.7)
  BOTTOM w0.117: v2(29.95,70.95) 29.76,70.95 28.68,69.87 25.94,69.87 25.61,69.54 v3(25,69.54) 23.8,69.54 23.68,69.42 22.65,69.42 21.7,70.38 v2(21.7,70.97)
VCC_CPU: length 17.8
  TOP w0.381: v2(93.6,94.58) 95.02,94.58 95.27,94.33 96,94.33 PR1818.1
  TOP w0.508: v2(93.6,94.58) 93.48,94.58 92.74,93.84 PR1819.1 ; v2(92.18,92.14) PC814.1
  IN3 w0.508: v2(94.01,89.91) 94.01,89.81 94.05,89.76 94.05,89.7 94.45,89.3 96.8,89.3 v2(97.46,89.96)
  BOTTOM w0.254: v2(93.6,94.58) 93.68,94.58 94.08,94.99 PU801.28
  BOTTOM w0.508: v2(93.6,94.58) 93.41,94.39 v3(93.41,93.99) 93.41,93.37 v2(92.18,92.14) 92.18,91.31 PR812.1 92.22,90.86 92.47,90.61 PR837.2 PR835.2 94,90.29 94.01,90.29 v2(94.01,89.91) ; PR859.1 97.44,89.98 v2(97.46,89.96)
VDD_DDR: length 5.3
  TOP w0.508: v2(161.1,49.7) 161.13,49.72 161.13,51.31 v3(162.01,52.2) 162.37,52.56 v2(163.54,52.56)
  BOTTOM w0.508: PRM5.1 160.73,50.07 v2(161.1,49.7)
VDDA: length 8.1
  TOP w0.117: v1(48.94,7.64) 48.94,7.37 49.48,6.83 PRB23.1
  TOP w0.254: PRB23.1 51.29,6.83 PRB27.1 51.33,6.85 51.74,6.44 v2(51.74,6.26) 51.26,5.78 PRB6.1
  BOTTOM w0.203: v2(51.74,6.26) 52.31,6.26 PRB25.1 52.42,6.15 52.42,5.88 PCB16.1 51.82,5.38 50.81,6.38 PUB1.7
VDDIO_AUDIO: length 0.7
  BOTTOM w0.381: UC1.AP9 116.77,70.8 v2(116.88,70.8)
  vias: v3(117.98,70.42)
VDDIO_MEM_S3_SENSE_H: length 97.1
  TOP w0.102: v2(94.67,59.5) 94.4,59.23 94.36,59.23 T15.1
  TOP w0.127: v2(163.34,62.18) 163.34,61.93 162.75,61.35 158.18,61.35 156.43,59.6 156.43,56.4 155.18,55.15 150.69,55.15 145.61,50.07 144.85,50.07 v2(144.67,50.25)
  IN1 w0.127: v2(144.67,50.25) 144.49,50.07 143.81,50.07 143.5,50.37 143.5,54.13 137.02,60.61 135.02,60.61 134.59,61.04 134.09,61.04 133.84,61.3 132.52,61.3 132.5,61.27 128.84,61.27 128.62,61.49 126.1,61.49 125.45,60.84 125.45,56.92 122.18,53.65 97.62,53.65 97.41,53.85 97.41,59.8 97.21,60 95.5,60 94.99,59.5 v2(94.67,59.5)
  BOTTOM w0.102: v2(94.67,59.5) 94.97,59.8 UC1.J21
  BOTTOM w0.127: PRM13.2 163.34,61.15 v2(163.34,62.18)
VDDIO_MEM_S3_SENSE_L: length 100.8
  TOP w0.102: RC595.2 88.93,58.66 88.69,58.43
  TOP w0.127: T2412.1 88.42,58.18 v2(88.43,58.17) 88.69,58.43 ; v2(144.67,49.64) 144.85,49.81 145.71,49.81 150.79,54.89 155.29,54.89 156.68,56.29 156.68,59.49 158.28,61.09 162.86,61.09 163.52,61.75 v2(163.77,61.75)
  IN1 w0.127: v2(144.67,49.64) 144.49,49.81 143.7,49.81 143.25,50.27 143.25,54.03 136.92,60.36 134.91,60.36 134.48,60.79 133.98,60.79 133.73,61.04 128.74,61.04 128.53,61.26 126.19,61.26 125.68,60.75 125.68,56.82 122.28,53.42 92.19,53.42 90.91,54.7 90.91,56.56 90.06,57.41 89.2,57.41 v2(88.43,58.17)
  BOTTOM w0.127: PRM14.2 163.77,61.19 v2(163.77,61.75)
VIN_CHG: length 1.1
  BOTTOM w0.117: v2(55.27,10.12) 55.27,9.27 v3(55.41,9.13)
  vias: v2(56.49,10.58)
VIN_MUX: length 12.5
  TOP w0.508: PQS4.4 34.8,52.84 35.14,53.19 35.14,54.31 35.73,54.89
  BOTTOM w0.508: 33.2,59.1 33.06,59.24 31.79,59.24 31.27,59.76 28.36,59.76 28.17,59.57 PQD5.4 ; PDD1.1 31.48,60.41 32.03,59.86 32.79,59.86
  vias: v1(57.26,4.84) v2(27.16,28.64) v2(27.16,28.06) v2(27.16,27.48) v2(27.16,26.89) v2(27.87,29.25) v2(27.87,28.67) v2(27.87,28.09) v2(27.87,27.5) v2(28.49,29.24) v2(28.52,28.61) v2(34.83,61) v2(34.83,60.42) v2(35.41,61) v2(35.41,60.42) v2(36,61) v2(36,60.42) v2(56.59,7.04) v2(56.61,6.46) v2(56.59,5.86) v2(56.89,5.34) v2(57.22,7.04) v2(57.23,6.46) v2(57.24,5.87) v2(57.52,5.35) v2(57.85,5.87) v2(58.18,5.35)
VSS_SENSE_A: length 6.9
  TOP w0.102: v2(94.57,58.5) 94.04,57.97 92.21,57.97 91.74,58.44 90.98,58.44 RC595.1 RC594.1 91.56,59.43 v3(91.8,59.66)
  BOTTOM w0.102: v2(94.57,58.5) 94.97,58.9 UC1.J22
VSS_SENSE_B: length 34.7
  IN1 w0.102: v2(111.87,68.4) 112.46,68.99 112.46,70.19 112.67,70.39 115,70.39 115.18,70.57 115.18,71.07 115.46,71.35 116.09,71.35 116.4,71.66 117.24,71.66 117.57,71.99 118.46,71.99 119.37,72.9 120.35,72.9 120.85,72.4 121.68,72.4 121.91,72.62 123.85,72.62 124.18,72.29 124.18,72.17 125.3,71.05 134.97,71.05 135.97,72.05 139.03,72.05 139.45,71.63 v2(139.45,71.62)
  BOTTOM w0.102: UC1.AJ12 111.48,68 v2(111.87,68.4)
  BOTTOM w0.117: v2(139.45,71.62) 139.45,72.34 v3(139.63,72.52) 140.56,72.52 RC597.1
32K_X1: length 10.6
  TOP w0.117: YC2.1 126.66,79.76 126,79.1 CC30.1 126,79 126.39,78.61 126.44,78.61 RC86.2 126.17,78.26 125.83,78.6 125.23,78.6 v2(124.95,78.31)
  BOTTOM w0.117: v2(124.95,78.31) 124.74,78.31 124.58,78.15 124.57,78.15 122.98,76.57 122.98,76.05 121.86,74.94 121.24,74.94 UC1.AY1
32K_X2: length 12.2
  TOP w0.117: v2(125.7,78.18) 126.12,77.76 127.18,77.76 127.68,78.26 RC86.1 127.78,78.19 CC31.1 128.57,79.05 129.28,79.76 YC2.2
  BOTTOM w0.117: UC1.AY4 121.49,74.72 122,74.72 124.19,76.91 124.21,76.91 124.85,77.55 125.44,77.55 125.7,77.81 v2(125.7,78.18)
48M_X1: length 7.5
  BOTTOM w0.117: RC76.2 127.22,77.2 126.71,76.69 v1(126.28,76.69) 124.93,76.69 123.22,74.97 123.22,74.47 122.84,74.08 122.09,74.08 UC1.BB3
48M_X1_R: length 7
  BOTTOM w0.117: YC1.1 132.69,80.5 132.4,80.2 132.25,80.2 132.21,80.17 132.21,80.17 132.13,80.08 CC28.1 131.22,80.08 130.78,79.64 130.78,78.29 v1(130.7,78.21) 130.69,78.21 129.72,77.25 RC75.1 128.54,77.25 RC76.1
48M_X2: length 7.6
  BOTTOM w0.117: RC74.2 127.26,76.06 125.32,76.06 124.5,75.24 123.87,75.24 123.45,74.82 123.45,74.36 122.95,73.87 121.84,73.87 UC1.BA5
48M_X2_R: length 9.5
  BOTTOM w0.117: YC1.3 134.74,79.58 132.51,79.58 132.47,79.54 132.47,79.54 132.15,79.22 CC27.1 131.76,79.09 131.76,79.06 131.4,78.71 131.4,77.9 131.23,77.73 131.23,77.31 v1(130.4,76.48) 130.26,76.33 RC75.2 128.85,76.33 128.79,76.38 RC74.1
+APU_CORE: length 133.3
  TOP w0.381: v2(88.81,72.54) 88.81,73.12 CF12.1
  IN3 w0.254: v2(120.3,88.59) 118.65,88.59 118,87.94 113.83,87.94 111.3,90.47 111.3,91.6 108.76,94.14 106.57,94.14 v2(105.95,94.76)
  BOTTOM w0.254: UC1.AH13 UC1.AJ14 ; v2(93.78,69.5) 93.78,69.6 UC1.G10 ; UC1.AD17 UC1.AE18 ; UC1.AH17 UC1.AJ18 ; UC1.R14 UC1.P13 99.29,67.08 v2(99.17,67.08) 99.54,67.46 100.12,67.46 ; UC1.R14 100.78,65.6 v2(100.78,65.51) 101.09,65.2 UC1.T15 UC1.U16 UC1.T17 101.18,63.62 v2(100.78,64.01) 100.39,64.4 UC1.R16 ; UC1.R14 UC1.P15 99.58,65.22 v2(99.16,65.63) ; 109.83,67.71 109.83,69.14 UC1.AF10 ; 109.83,67.71 109.45,67.33 v2(109.45,67.2) 109.4,67.15 109.4,67.03 UC1.AF13 UC1.AG14 ; 109.83,67.71 110.34,67.2 v2(110.37,67.2) 110.44,67.26 v2(111.87,67.26) ; UC1.P10 99.37,69.63 99.86,70.12 99.86,70.69 UC1.R8 99.57,72 UC1.P7 ; UC1.W16 UC1.V15 ; UC1.W16 v2(103.97,64) ; UC1.W16 UC1.V17 ; 101.83,67.63 101.59,67.39 101.08,67.39 v2(100.78,67.09) ; 101.83,67.63 v2(102.38,67.09) ; 101.83,67.63 101.83,69.14 UC1.T10 ; v2(94.87,73) 94.91,72.96 94.91,71.33 94.58,71 UC1.H8 ; v2(99.83,69.21) 99.86,69.17 99.86,67.71 100.12,67.46 ; UC1.AF17 UC1.AG18 ; v2(101.87,70) 101.87,71.5 UC1.T7 101.02,71.64 v2(100.82,71.64) ; v2(103.97,65.6) UC1.W14 UC1.V13 ; UC1.AD15 UC1.AE16 ; UC1.AF15 UC1.AG16 ; UC1.AB13 UC1.AC14 ; v2(100.78,67.09) 100.89,67.09 UC1.T13 UC1.U14 ; v2(100.78,67.09) 100.68,67.09 100.31,67.46 100.12,67.46 ; v2(104.88,71.7) 105.01,71.7 105.31,72 UC1.AA7 ; UC1.AA16 UC1.Y15 ; v2(107.18,67.2) 105.69,67.2 v2(105.58,67.09) 105.4,67.26 104.14,67.26 v2(103.97,67.09) 103.66,67.39 102.79,67.39 102.49,67.09 ; UC1.AH15 UC1.AJ16 111.58,64.3 v2(111.92,63.96) ; UC1.L8 96.25,71.2 95.8,71.65 95.8,72.28 UC1.K6 ; v2(93.74,65.51) 93.37,65.88 UC1.G14 ; UC1.AA18 UC1.Y17 ; UC1.K14 95.78,66.21 95.48,66.5 93.08,66.5 v2(93.07,66.5) ; UC1.Y13 UC1.AA14 ; v2(105.95,94.76) 105.6,94.42 PC802.2 PR802.2 ; UC1.AC16 UC1.AB15 ; UC1.AC18 UC1.AB17 ; UC1.AD13 UC1.AE14
  BOTTOM w0.3: v2(111.92,62.38) 112,62.38 UC1.AK19 ; v2(99.16,65.63) 99.16,65.64 98.8,66 UC1.N14 ; v2(107.18,64) UC1.AC16 ; UC1.AB15 v2(105.57,65.6) UC1.AA14 ; UC1.U16 v2(102.37,64) UC1.V17 ; UC1.AK15 111.95,65.63 v2(111.92,65.63) ; UC1.AA16 v2(105.57,64) UC1.AB17 ; UC1.AA18 v2(105.57,62.4) UC1.AB19 ; UC1.AD7 107.57,72 v2(107.87,72.3) ; UC1.AB13 105.69,67.09 v2(105.58,67.09) ; v2(105.87,70) 105.48,69.6 UC1.AA10 ; UC1.AF15 v2(108.77,65.6) UC1.AE14 ; UC1.AC14 v2(107.18,65.6) ; UC1.P7 99.91,72.54 99.91,72.98 v2(99.79,73.11) ; v2(111.87,67.26) 111.91,67.26 UC1.AK13 ; v2(103.87,70) 103.48,69.6 UC1.W10 ; UC1.AE16 v2(108.77,64) UC1.AF17 ; UC1.AG16 v2(110.37,64) UC1.AH17 ; v2(103.97,67.09) 104.09,67.09 UC1.Y13 ; UC1.AA7 105.57,72 v2(105.87,72.3) ; UC1.V13 102.49,67.09 v2(102.38,67.09) ; UC1.T7 101.57,72 v2(101.87,72.3) ; v2(110.37,67.2) UC1.AH13 ; UC1.AK17 112.01,63.96 v2(111.92,63.96) ; UC1.AG18 v2(110.37,62.4) UC1.AH19 ; v2(107.18,62.4) UC1.AC18 ; UC1.W7 103.06,72.32 v2(102.89,72.32) ; UC1.AD10 107.62,69.84 107.88,69.84 v2(107.89,69.86) ; UC1.Y17 v2(103.97,64) ; UC1.T10 101.48,69.6 v2(101.87,70) ; UC1.U14 v2(102.37,65.6) UC1.V15 ; UC1.AH15 v2(110.37,65.6) UC1.AG14 ; UC1.R8 v2(100.82,71.64) ; UC1.AF19 v2(108.77,62.4) UC1.AE18 ; v2(104.88,71.7) UC1.Y8 ; UC1.Y15 v2(103.97,65.6)
  BOTTOM w0.305: v2(107.18,64) UC1.AD17 ; v2(107.18,67.2) UC1.AD13 ; v2(111.92,65.63) 111.58,65.97 UC1.AJ14 ; UC1.AD19 v2(107.18,62.4) ; v2(111.92,62.38) 111.58,62.72 UC1.AJ18 ; v2(107.18,65.6) UC1.AD15
  BOTTOM w0.35: UC1.K12 95.78,68.1 v2(95.37,68.5) ; v2(93.07,68.5) 93.07,68.3 UC1.G12 ; UC1.H15 93.74,65.43 v2(93.74,65.51) ; v2(95.37,65.46) 95.37,65.59 UC1.K14 ; UC1.AJ10 111.48,69.6 v2(111.87,69.99) ; UC1.M10 96.94,69.17 v2(96.82,69.17) ; UC1.AE8 108.67,71.5 v2(108.87,71.5) UC1.AF7 109.87,72.5 v2(109.87,73.03) ; v2(111.87,72.3) 111.67,72.3 UC1.AJ7 ; v2(96.87,70.92) 96.65,70.92 UC1.L8 ; v2(93.07,66.5) 93.07,66.3 UC1.G14 ; v2(109.85,69.93) 109.72,69.93 109.39,69.6 UC1.AF10 ; UC1.G10 93.16,70.22 v2(93.16,70.49) ; v2(92.82,72.56) 92.84,72.54 92.84,72.53 UC1.G7 v2(93.87,71.5) UC1.H8 ; UC1.H11 94.18,69.1 v2(93.78,69.5) ; v2(94.87,73) 95.07,73 UC1.K6 ; UC1.P10 99.77,69.21 v2(99.83,69.21)
  BOTTOM w0.381: UC1.M7 97.01,71.63 96.76,71.63 96.37,71.24 UC1.L8
  vias: v1(112.75,82.7) v2(99.97,76.03) v2(101.06,76.03) v2(101.44,81.63) v2(101.44,81.04) v2(102.71,76) v2(104.08,75.93) v2(108.31,79.27) v2(108.68,81.06) v2(108.68,79.89) v2(108.94,79.33) v2(109.26,79.92) v2(112.73,81.68) v2(113.31,81.68) v2(113.9,81.68) v2(116.34,86.86) v2(116.87,88.44) v2(116.92,86.86) v2(117.63,89.15) v2(117.63,88.44) v2(117.68,86.86) v2(118.01,90.57) v2(118.01,89.81) v2(118.39,89.15) v2(118.77,90.57) v2(118.77,89.81) v2(119.15,89.15) v2(119.54,90.57) v2(119.54,89.81) v2(119.92,89.15) v2(120.3,90.57) v2(120.3,89.81) v2(120.68,89.15) v2(121.06,88.59) v2(121.11,90.49) v2(121.11,89.73) v2(121.39,93.59) v2(121.39,92.83) v2(121.39,92.07) v2(121.39,91.31) v2(121.44,89.15) v2(121.77,88.6) v2(121.87,90.49) v2(121.87,89.73) v2(122.15,93.59) v2(122.15,92.83) v2(122.15,92.07) v2(122.15,91.31) v2(122.91,93.59) v2(122.91,92.83) v2(122.91,92.07) v2(122.91,91.31) v2(123.68,93.59) v2(123.68,92.83) v2(123.68,92.07) v2(123.68,91.31) v2(124.44,93.59) v2(124.44,92.83) v2(124.44,92.07) v2(124.44,91.31) v2(125.2,93.59) v2(125.2,92.83) v2(125.2,92.07) v2(125.2,91.31) v2(125.61,88.74) v2(125.71,90.24) v2(125.68,89.48) v2(126.01,93.52) v2(126.01,92.75) v2(126.03,92) v2(126.03,91.24) v2(126.34,90.24) v2(126.32,89.48) v2(126.37,88.74) v2(126.77,93.52) v2(126.77,92.75) v2(126.79,92) v2(126.79,91.24) v2(127.11,90.24) v2(127.08,89.48) v2(127.13,88.74) v2(127.71,90.65) v2(127.71,89.88) v2(127.74,89.22) v2(127.74,88.46) v2(128.22,90.95) v2(128.22,90.19) v2(131.25,92.12) v2(131.25,91.36) v2(132.01,92.12) v2(132.01,91.36) v2(132.5,90.59) v2(132.5,89.83) v2(132.53,89.15) v2(132.54,88.47) v2(132.69,92.12) v2(132.69,91.36) v2(133.26,90.59) v2(133.26,89.83) v2(133.29,89.15) v2(133.46,92.12) v2(133.46,91.36) v2(133.9,89.24) v2(134.22,92.12) v2(134.22,91.36) v2(134.22,90.59) v2(134.22,89.83) v2(134.98,92.12) v2(134.98,91.36) v2(134.98,90.59) v2(134.98,89.83) v2(135.74,92.12) v2(135.74,91.36) v2(135.74,90.59) v2(135.74,89.83) v2(136.5,92.12) v2(136.5,91.36) v2(136.5,90.59) v2(136.5,89.83) v2(136.58,87.6) v2(136.69,88.22) v2(137.14,87.42) v2(137.39,87.95) v2(137.9,87.42) v2(138.26,87.95) v2(138.66,87.42) v2(139.02,87.95) v2(139.73,92.8) v2(139.73,92.04) v2(139.73,91.28) v2(140.49,92.8) v2(140.49,92.04) v2(140.49,91.28) v2(140.63,87.97) v2(140.82,87.33) v2(140.88,86.7) v2(141.25,92.8) v2(141.25,92.04) v2(141.25,91.28) v2(141.25,87.8) v2(141.46,87.04) v2(141.47,86.38) v2(142.01,92.8) v2(142.01,92.04) v2(142.01,91.28) v2(142.01,87.8) v2(142.15,88.47) v2(142.15,86.38) v2(142.22,87.04) v2(142.47,89.05) v2(142.78,92.8) v2(142.78,92.04) v2(142.78,91.28) v2(142.85,88.47) v2(142.78,87.8) v2(142.85,87.08) v2(142.79,86.38) v2(143.11,89.17)
+APU_CORE_SOC: length 26.6
  TOP w0.508: PC9041.1 84.45,92.03 89.32,96.91 PC838.1 91.19,96.91 PR833.1
  VCC w0.102: 100.73,56.03 101.08,56.03
  BOTTOM w0.254: UC1.P19 99.58,62.01 v2(99.97,62.4) 100.36,62.8 UC1.R18 v2(100.01,63.17) UC1.P17 99.17,64 ; UC1.P19 v2(99.17,62.4) ; UC1.P19 UC1.R20 ; UC1.N18 98.4,62.43 v2(98.4,62.39) ; UC1.U18 UC1.T19 ; UC1.T19 UC1.U20 ; UC1.T19 v2(100.78,62.4) ; v2(99.2,60.61) 99.2,60.74 98.78,61.16 UC1.N20 ; v2(103.97,60.8) UC1.W20 UC1.V19 UC1.W18 v2(103.97,62.4) ; v2(104.83,62.43) 104.4,62 UC1.Y19
  BOTTOM w0.3: UC1.V19 v2(102.37,62.4) UC1.U18 ; v2(103.97,62.4) UC1.Y19 ; v2(102.4,60.86) 102.31,60.86 UC1.U20 ; v2(99.17,62.4) UC1.N18 ; UC1.N16 99.17,64 ; v2(100.78,62.4) UC1.R18
  vias: v1(89.58,83.52) v2(79.78,89.02) v2(79.8,88.09) v2(80.52,88.71) v2(80.51,87.48) v2(80.64,86.44) v2(80.64,85.07) v2(81.31,89.02) v2(81.3,88.09) v2(81.35,86.44) v2(81.35,85.07) v2(82.05,88.74) v2(82.03,87.41) v2(82.01,86.44) v2(82.01,85.07) v2(82.64,86.44) v2(82.64,85.07) v2(82.83,89.02) v2(82.79,88.02) v2(83.33,86.44) v2(83.33,85.07) v2(83.54,88.71) v2(83.48,87.46) v2(83.61,91.27) v2(83.61,90.1) v2(84.8,64.8) v2(84.8,64.22) v2(85.39,66.53) v2(85.39,64.8) v2(85.39,64.22) v2(85.97,64.8) v2(85.97,64.22) v2(88.36,88.7) v2(88.38,87.71) v2(89.22,88.7) v2(89.27,87.69) v2(90.14,88.68) v2(90.19,87.71) v2(97.78,62.4) v2(98.1,62.9)
+CHGRTC: length 7.8
  TOP w0.117: v3(85.74,12.61) 85.32,13.04 v2(84.88,13.04)
  TOP w0.508: v2(82.92,12.63) 82.5,12.21 PR8.1 81.77,13.29 PR9.1 ; v2(84.88,13.04) 84.88,13.34 84.32,13.9 PD2.2
  BOTTOM w0.508: v2(82.92,12.63) 83.41,12.15 84.37,12.15 84.45,12.22 84.5,12.22 84.88,12.6 v2(84.88,13.04)
+EC_VCCA: length 137.1
  TOP w0.102: 124.88,56.29 124.17,56.29 123.22,57.24 PR13.1
  TOP w0.117: v2(192.18,30.84) 192.18,30.02 192.46,29.74 C67.1 192.97,29.91 L1.2 192.97,30.8 192.38,31.39 192.38,31.64 191.99,32.03 UEC1.67 ; v2(134.05,56.44) 132.71,55.11 130.89,55.11 129.02,56.98 128.29,56.98 127.6,56.29 v1(125.64,56.29) 124.88,56.29
  IN1 w0.102: v2(192.18,30.84) 191.89,31.13 191.89,36.05 191.53,36.4 191.53,43.32 189.64,45.22 182.71,45.22 181.22,46.71 181.22,47.08 179.85,48.45 179.85,50.18 177.97,52.06 177.97,54.65 174.74,57.88 172.31,57.88 169.01,61.18 169.01,61.9 167.81,63.1 167.81,63.48 166.7,64.59 166.7,68.13 v2(166.72,68.15)
  BOTTOM w0.117: v2(134.05,56.44) 136.22,54.27 136.22,51.83 136.99,51.07 136.99,46.53 136.38,45.92 136.38,43.01 137.6,41.79 143.65,41.79 144.87,43.01 145.33,43.01 146.3,43.97 149.32,43.97 149.8,44.46 149.8,45.22 150.03,45.45 150.56,45.45 150.79,45.67 151.43,45.67 151.8,46.05 154.47,46.05 154.91,46.49 154.91,55.92 156.33,57.34 156.33,60.77 158.41,62.85 160.12,62.85 165.41,68.15 v2(166.72,68.15)
+FLT1: length 2.6
  TOP w0.254: UT2.9 28.88,82.54 v3(28.65,82.32) 28.64,82.3 28.64,81.78 29.14,81.29 RT39.1
+IOVDD_CODEC: length 11
  TOP w0.381: RA34.2 12.68,35.28 12.3,35.66 v3(12.3,36.21) 11.82,36.21 11.57,36.46 11.03,36.46 10.65,36.08 10.65,35.32 10.19,34.87 CA28.1 9.85,34.71 CA21.1 5.85,34.71 5.38,35.18 5.38,35.18 v2(5.3,35.26)
  BOTTOM w0.203: UA1.18 5.74,35.66
  BOTTOM w0.305: v2(5.3,35.26) 5.3,35.33 5.63,35.66 5.74,35.66
+LCDVDD:
  vias: v2(50.54,96.02) v2(50.89,95.53) v2(51.15,96.07) v2(55.83,70.26) v2(56.18,70.76) v2(56.43,100.72) v2(56.52,101.31) v2(56.57,70.26) v2(56.99,100.91) v3(57.19,70.38)
+LCDVDD_CONN: length 2.5
  TOP w0.127: v2(52.26,72.62) 52.26,72.64 51.71,73.2 v1(51.53,73.2) ; 51.92,71.9 51.5,71.48 v1(51.5,71.46) ; v2(52.92,72.65) 52.92,73.09 v1(53.25,73.42)
+LDO_3V3_5457V: length 47.9
  TOP w0.254: UT2.10 29.28,83.27 29.55,83 29.55,82.33 CT58.1 ; UT1.33 41.83,83.47 41.98,83.62 CT47.1
  TOP w0.508: v2(34.01,79.19) RT22.1 ; v2(44.35,87.32) 44.17,87.14 RT73.2 ; RT26.2 34.5,87.14 v2(34.83,87.14) ; RT73.2 RT72.2 ; RT73.2 43.74,86.48 43.72,86.45 RT74.2 ; v2(30.67,81.67) 30.67,81.67 30.27,81.26 RT39.2 29.99,81.32 29.99,81.53 29.54,81.98 29.54,82.28 29.53,82.29 CT58.1
  IN2 w0.508: v2(44.24,83.71) 44.24,83.77 43.48,84.52 43.48,86.4 44.35,87.28 v2(44.35,87.32) 44.58,87.55 44.58,89.4 43.95,90.04 34.52,90.04 34.14,89.65 34.14,87.83 v2(34.83,87.14) 34.74,87.14 34.17,86.57 31.46,86.57 29.77,84.88 29.77,82.17 30.28,81.67 v2(30.67,81.67)
  BOTTOM w0.508: RT85.1 34.16,79.04 v2(34.01,79.19) 34.01,81.11 v3(33.7,81.43) 30.92,81.43 v2(30.67,81.67)
+LEDVDD:
  vias: v1(52.42,76.32) v1(54.14,78.25) v1(54.4,76.47) v2(52.98,76.87) v2(52.98,76.23) v2(52.98,75.6) v2(53.67,76.87) v2(53.67,76.23) v2(53.67,75.6)
+RTC_APU: length 153.1
  TOP w0.508: v2(86.27,3.66) 86.29,3.68 RC107.1 86.29,4.74 CC105.1 RC106.2
  IN2 w0.381: v2(111.9,69.19) 112.89,68.2 112.89,66.78 113.81,65.87 114.7,65.87 115.08,65.49 115.08,64.09 115.92,63.25 120.82,63.25 121.09,63.52 121.56,63.52 121.86,63.22 121.86,61.57 122.27,61.17 127.53,61.17 129.66,59.04 131.11,59.04
  IN2 w0.508: v2(86.27,3.66) 86.27,7.98 87.32,9.02 v2(90.86,9.02) 91.66,9.02 92.44,9.81 97.57,9.81 98.74,8.63 102.27,8.63 102.92,7.98 107,7.98 107.94,8.92 110.35,8.92 110.41,8.98 112.42,8.98 112.61,9.17 115.55,9.17 116.29,8.44 117.19,8.44 118.06,7.56 121.87,7.56 122.37,8.06 123.49,8.06 123.97,7.57 128.54,7.57 128.55,7.56 129.9,7.56 129.91,7.57 130.98,7.57 131.49,8.08 v2(131.49,8.43) ; 134.51,57.61 134.51,57.56 135.55,56.52 135.55,55.96 140.91,50.6 140.91,44.98 141.27,44.62 142.18,44.62 143.36,43.44 143.36,41.48 144.07,40.77 144.07,34.95 146.82,32.2 148.31,32.2 148.86,31.65 148.86,28.71 148.87,28.69 148.87,28.09 148.89,28.07 148.89,25.79 147.34,24.24 v2(147.34,22.31)
  IN3 w0.508: v2(147.34,22.31) 147.34,21.93 146.5,21.09 146.5,18.73 145.49,17.72 142.12,17.72 138.07,13.67 138.07,13.57 136.2,11.7 131.75,11.7 131.13,11.08 131.13,9.34 131.49,8.98 v2(131.49,8.43)
  BOTTOM w0.381: v2(111.9,69.19) 111.77,69.19 UC1.AJ11
  BOTTOM w0.508: v2(90.86,9.02) 91.14,9.3 CLRP1.1
+RTCBATT: length 10.7
  TOP w0.127: v2(84.32,11.08) 84.32,10.36 v1(84.43,10.24)
  TOP w0.305: RC626.2 86.73,7.37 86.76,7.4 CC82.1
  TOP w0.508: v2(84.32,11.08) PD2.1 83.93,11.97 82.98,11.01 PR10.1 ; RC626.2 85.26,7.37 v2(84.55,8.08)
  BOTTOM w0.508: v2(84.55,8.08) 84.32,8.31 v2(84.32,11.08)
+RTCBATT_APU: length 6
  TOP w0.117: v3(82.46,4.53) 82.46,4.26 82.71,4.02 84,4.02 CC81.1 85.36,4.6 RC107.2 85.37,6.04 85.79,6.46 RC626.1
+RTCBATT_R: length 12
  TOP w0.508: v2(83.68,10.19) 83.1,9.61 v1(82.15,9.61) 80.91,9.61 80.4,10.11 PR10.2
  IN3 w0.508: v2(83.68,10.19) 84.29,10.19 84.93,10.83 84.93,11.44 85.18,11.69 85.18,12.12 85.84,12.78 v2(85.84,15.12)
  BOTTOM w0.508: JBATT1.6 85.64,14.51 85.84,14.71 v2(85.84,15.12)
+USBC0_VBUS: length 10.2
  TOP w0.508: v2(30.97,77.68) 31.16,77.87 R4021.2 32.62,77.87 34.01,76.47 38.01,76.47 39,77.46 RT40.1
  BOTTOM w0.254: JUSBC2.B9 7.72,88.51 8.02,88.2 v2(8.09,88.2)
  vias: v1(20.36,82.57) v1(23.16,76.98) v1(23.22,81.62) v2(8.1,91.12) v2(10.7,91.79) v2(11.14,91.31) v2(11.23,90.7) v2(11.23,90.06) v2(11.2,89.48) v2(11.47,91.79) v2(12.06,91.78) v2(17.11,86.72) v2(17.49,86.26) v2(17.93,86.77) v2(18.01,85.98) v2(18.41,86.43) v2(18.53,85.65) v2(18.91,86.14) v2(22.53,79.5) v2(22.52,78.89) v2(23.16,79.49) v2(23.16,78.89) v2(23.45,80.02) v2(24.3,68.03) v2(24.86,68.37) v2(24.86,67.77) v2(29.35,58.17) v2(29.68,58.7) v2(30.28,58.71) v2(30.52,58.17) v2(30.87,58.71) v2(31.11,58.17) v2(31.45,58.71)
AC_IN_TYPE: length 177
  TOP w0.117: v2(189.44,39.52) 189.96,40.03 UEC1.87 ; v2(176.19,19.77) 176.04,19.61 173.02,19.61 v3(170.03,16.62) 169.24,15.84 149.04,15.84 148.67,15.47 148.67,10.36 145.83,7.52 142.87,7.52 142.22,6.88 142.09,6.88 142.08,6.86 135.75,6.86 134.47,5.58 127.92,5.58 127.8,5.45 122.75,5.45 122.37,5.08 113.44,5.08 113.1,5.42 112.44,5.42 112.17,5.68 107.09,5.68 106.52,5.11 100.45,5.11 96.29,9.27 93.26,9.27 91.08,7.09 91.08,6.88 89.83,5.63 89.83,3.58 88.44,2.19 50.38,2.19 48.63,3.94 PRB34.2
  TOP w0.254: v2(46.56,4.46) 46.56,4.82 47.02,5.28 PRB33.1 48.09,5.28 48.63,4.73 PRB34.2
  IN2 w0.127: v2(184.34,33.26) 183.26,33.26 178.76,28.76 178.76,28.05 177.77,27.06 177.77,26.32 178.1,25.99 178.1,25.38 177.44,24.72 177.44,21.77 177.31,21.65 177.31,21.65 176.19,20.53 v2(176.19,19.77)
  BOTTOM w0.117: v2(184.34,33.26) 184.34,33.93 188.79,38.38 188.79,38.87 v2(189.44,39.52)
  BOTTOM w0.203: v2(46.56,4.46) 46.74,4.46 46.97,4.69 47.09,4.69 47.37,4.96 PUB1.15
AC_OFF: length 209.4
  TOP w0.117: UEC1.21 176.86,35.63 176.98,35.51 177.41,35.51 v2(177.44,35.49) ; v2(177.03,49.74) v3(176.19,49.74)
  IN2 w0.127: v2(28.48,68.95) 28.48,69.12 28.61,69.25 29.59,69.25 32.12,71.78 32.12,73.4 34.5,75.77 40.07,75.77 41.6,74.25 47.41,74.25 49.67,71.99 52.38,71.99 53.17,71.2 58.22,71.2 59.89,72.87 62.61,72.87 63.6,73.86 73.53,73.86 81.6,81.93 97.65,81.93 98.96,80.62 107.04,80.62 109.11,82.7 116.5,82.7 118.3,80.89 118.3,80.43 118.55,80.18 120.53,80.18 122.91,82.57 136.4,82.57 138.41,80.56 139.06,80.56 140.73,78.89 144.58,78.89 149.16,74.31 150.15,74.31 153.29,71.18 155.57,71.18 157.79,68.95 157.79,67.8 161.54,64.04 163.8,64.04 170.5,57.34 170.5,55.45 175.38,50.58 176.19,50.58 v2(177.03,49.74)
  IN3 w0.127: v2(177.03,49.74) 176.39,49.1 176.39,48.32 173.84,45.76 173.14,45.76 172,44.62 172,43.46 172.81,42.65 173.75,42.65 174.4,42 177.06,42 177.24,41.82 177.31,41.76 178.29,41.76 178.71,41.34 178.71,40.97 179.14,40.54 179.14,38.31 177.44,36.61 v2(177.44,35.49)
  BOTTOM w0.117: PQD3.5 25.22,67.03 PRD8.1 26.08,67.14 26.4,67.46 28.18,67.46 28.48,67.76 v2(28.48,68.95)
AC_PRESENT: length 118
  TOP w0.117: UEC1.18 176.64,36.83 176.64,36.84 176.72,36.84 176.72,36.84 177.05,36.84 177.23,37.01 178.25,37.01 178.88,36.38 178.88,33.3 175.23,29.65 175.23,29.26 174.7,28.74 174.7,28.36 173.99,27.65 171.55,27.65 169.09,25.18 154.85,25.18 151.24,28.79 151.24,30.76 149.21,32.8 148.44,32.8 144.35,36.88 144.35,39.99 143.68,40.67 143.68,43.11 146.22,45.66 146.22,48.23 146.38,48.38 146.39,48.38 149.86,51.85 v3(151.17,51.85) 151.91,51.85 153.69,53.62 v2(153.69,53.7)
  IN2 w0.102: v2(123.8,72.13) 124.59,72.13 124.92,71.8 124.92,71.59 128.02,68.49 139.42,68.49 142.42,65.49 142.42,64.2 143.2,63.43 143.2,61.78 144.99,59.99 146.49,59.99 147.62,58.86 147.62,58.43 150.09,55.95 150.09,55.53 150.16,55.47 150.16,53.87 151.17,52.85 153.2,52.85 153.69,53.33 v2(153.69,53.7)
  BOTTOM w0.102: v2(123.8,72.13) 123.35,71.67 122.56,71.67 122.38,71.85 122.18,71.85 121.83,71.5 UC1.BA8
ACN: length 4.7
  TOP w0.203: PRB3.2 53.06,9.47 v2(53.06,9.14)
  BOTTOM w0.203: PUB1.2 50.84,8.38 51.27,8.81 51.27,9.18 PCB7.2 51.88,9.8 PRB3.2 53.06,9.47 v2(53.06,9.14)
ACP: length 4.5
  TOP w0.203: PRB2.2 52.73,8.65 52.48,8.91 v2(52.48,9.14)
  BOTTOM w0.203: v2(52.48,9.14) 52.48,8.93 52.73,8.68 PRB2.2 52.24,8.4 PCB7.1 51.76,8.82 50.92,7.98 PUB1.3
ADDR_CFG: length 4.8
  TOP w0.117: UT1.26 38.79,81.61 38.52,81.35 36.86,81.35 v3(36.52,81) 36.52,80.17 RT23.1 35.65,80.05 RT22.2
ADP_I: length 169.5
  TOP w0.117: v2(176.84,19.71) 176.19,20.35 173.17,20.35 v3(170.83,18.02) 168.9,16.09 148.94,16.09 148.42,15.57 148.42,10.51 145.79,7.88 142.74,7.88 142.08,7.22 141.98,7.22 141.88,7.12 135.66,7.12 134.37,5.82 127.82,5.82 127.69,5.7 122.64,5.7 122.27,5.32 113.54,5.32 113.2,5.66 112.54,5.66 112.27,5.93 106.99,5.93 106.43,5.36 100.54,5.36 96.39,9.52 93.16,9.52 90.84,7.19 90.84,6.98 89.59,5.73 89.59,3.68 88.35,2.44 52.11,2.44 51.74,2.81 PRB20.1 ; v2(181.96,31.3) 182.02,31.23 UEC1.65
  TOP w0.254: v2(51.13,4.53) 51.27,4.39 PRB20.1
  IN2 w0.127: v2(176.84,19.71) 178.02,20.89 178.02,24.26 179.67,25.91 179.67,26.52 179.51,26.69 179.51,27.84 180.1,28.44 180.1,29.44 v2(181.96,31.3)
  BOTTOM w0.203: PUB1.8 50.75,5.98 51.38,5.35 51.38,5.05 51.74,4.69 PCB25.1 51.67,4.39 51.27,4.39 v2(51.13,4.53)
ADPIN: length 3.8
  TOP w0.117: v1(24.76,78.3) 24.88,78.43 v2(25.47,78.43) ; v2(25.47,78.43) v1(25.47,79.8) ; v2(25.47,78.43) 25.47,76.83 v1(25.39,76.75)
APU_ALERT#: length 5.5
  BOTTOM w0.102: RC31.2 87.18,60.84 87.48,60.53 v3(87.54,60.53) 87.86,60.22 88.35,60.22 89.15,59.42 90.13,59.42 90.41,59.14 90.74,59.14 UC1.C22
APU_BT_OFF#: length 116.6
  TOP w0.102: v2(170.34,32.91) 170.33,32.91 168.81,32.91 167.91,32.01 167.57,32.01 167.14,31.58 162.85,31.58 162.63,31.36 162.63,29.78 162.41,29.56 162.41,28.75 159.66,26 155.19,26 152.06,29.13 152.06,31.13 149.5,33.69 148.94,33.69 145.17,37.45 145.17,40.5 144.5,41.17 144.5,42.31 144.76,42.56 148.49,42.56 149.52,43.59 149.52,47.53 150.54,48.54 v3(152.19,48.54) 153.08,48.54 v2(154.32,49.79)
  IN2 w0.102: v2(154.32,49.79) 154.19,49.92 154.19,52.3 154.74,52.84 154.75,52.84 155.39,53.48 155.39,53.97 154.9,54.46 154.42,54.46 154.34,54.55 152.35,54.55 151.63,55.28 151.63,55.56 151.46,55.73 151.46,55.99 151.15,56.3 151.01,56.3 148.67,58.64 148.67,62.9 140.5,71.07 130.26,71.07 129.79,71.55 129.6,71.55 128.06,73.08 126.28,73.08 125.36,74 123.75,74 123.55,73.8 122.4,73.8 122.01,74.18 119.86,74.18 119.68,74 119.43,74 v2(119.35,73.92)
  IN3 w0.102: v2(119.35,73.92) 118.12,75.14 114.98,75.14 114.33,75.78 v2(114.28,75.78)
  BOTTOM w0.089: UC1.AM2 114.09,75.11 114.09,75.58 114.23,75.72 114.23,75.73 v2(114.28,75.78)
  BOTTOM w0.102: JWLAN1.46 171.21,33.3 170.76,32.85 170.4,32.85 v2(170.34,32.91)
APU_CORE_SEN_H: length 110.4
  TOP w0.102: T14.1 95.91,58.88 95.99,58.96 v2(95.99,59.49)
  TOP w0.152: v2(89.22,94.98) 89.34,94.86 89.34,90.37 90.16,89.55 91.07,89.55 92.11,88.51 92.44,88.51 97.82,88.51 98.16,88.18 98.16,87.28 97.83,86.96 97.83,84.45 94.22,80.84 78.79,80.84 76.35,83.29 74.14,83.29 73.24,82.39 73.24,81.3 73.3,81.25 73.3,76.24 82.67,66.87 82.67,64.17 87.49,59.34 v2(87.49,59.19)
  TOP w0.254: v2(103.04,95.33) 103.04,95.69 102.96,95.77 102.96,95.96 102.86,96.06 102.86,96.07 PC807.1
  IN1 w0.102: v2(95.99,59.49) 95.99,58.74 95.87,58.62 95.34,58.62 94.76,58.04 92.07,58.04 91.51,58.6 90.92,58.6 90.26,59.26 89,59.26 88.59,59.67 88.23,59.67 87.94,59.38 87.74,59.38
  IN1 w0.127: 87.74,59.38 87.54,59.19 v2(87.49,59.19)
  IN1 w0.178: v2(103.04,95.33) 102.94,95.33 100,98.27 92.66,98.27 91.01,96.61 90.86,96.61 v2(89.22,94.98)
  BOTTOM w0.102: UC1.K22 95.78,59.28 v2(95.99,59.49)
  BOTTOM w0.254: PU801.11 102.98,95.39 v2(103.04,95.33) PR805.1 PR802.1 104.51,95.38 104.51,95.59 104.77,95.84 105.45,95.84 PC801.2
APU_CORESOC_SEN_H: length 92.7
  TOP w0.102: v2(95.99,57.99) T13.1
  TOP w0.152: v2(88.43,59.29) 88.43,59.48 83.43,64.48 83.43,67.19 74.06,76.56 74.06,81.56 74.01,81.61 74.01,82.08 74.46,82.52 76.03,82.52 78.48,80.08 94.53,80.08 98.59,84.14 98.59,86.64 98.92,86.96 98.92,88.49 98.14,89.27 92.42,89.27 91.39,90.31 90.48,90.31 90.1,90.69 90.1,94.42 92.14,96.46 PR833.2 92.15,96.87 v2(92.82,96.87)
  IN1 w0.102: v2(88.43,59.29) 88.69,59.29 88.91,59.06 90.18,59.06 90.84,58.4 91.42,58.4 91.98,57.84 94.84,57.84 95.42,58.42 95.88,58.42 95.99,58.31 v2(95.99,57.99)
  BOTTOM w0.102: v2(95.99,57.99) 95.9,57.9 UC1.J23
  BOTTOM w0.254: PC833.1 92.13,96.87 ; 92.13,96.87 92.13,96.87 PC830.2 92.12,95.99 PR832.2 ; 92.13,96.87 v2(92.82,96.87) 93.22,96.87 93.5,96.59 PU801.32
APU_DBREQ#: length 61
  IN3 w0.102: v2(118.02,77.09) 118.02,76.88 119.49,75.42 122.67,75.42 122.75,75.34 124.37,75.34 124.74,74.97 126.16,74.97 126.35,74.78 129.45,74.78 129.89,74.34 135.06,74.34 135.48,73.92 136.96,73.92 137.21,73.67 140.89,73.67 141.98,72.58 141.98,70.67 151.32,61.32 151.32,59.49 v2(150.93,59.1)
  BOTTOM w0.102: v2(118.02,77.09) 118.02,76.48 118.46,76.05 118.46,75.8 118.08,75.42 118.08,75.1 UC1.AT2 ; v2(150.93,59.1) 151.02,59.01 151.02,58.02 150.99,57.99 150.99,57.76 v3(150.75,57.53) 150.41,57.18 147.13,57.18 146.3,56.35 144.06,56.35 143.96,56.24 143.96,54.51 144.11,54.36 RHDT5.1 CHDT2.1 145.52,54.06 145.46,53.99 JHDT1.16
APU_DP1_CTRL_CLK: length 90.4
  IN1 w0.102: v2(81.56,62.21) 81.77,62.41 81.77,62.69 82.07,63 85.46,63 87.4,61.05 90.43,61.05 91.13,60.36 91.82,60.36 92.05,60.13 94.3,60.13 v2(94.67,60.5)
  IN3 w0.127: v2(28.74,70.88) 28.42,71.21 28.42,71.39 28.73,71.7 29.07,71.7 34.42,77.04 37.73,77.04 37.73,77.04 49.83,77.04 51.82,79.04 60.6,79.04 67.05,72.59 67.05,70.78 68.71,69.12 69.16,69.12 70.28,68.01 70.28,67.55 73.61,64.22 80.39,64.22 81.86,62.75 81.86,62.51 v2(81.56,62.21) ; v2(22.51,72.72) 23.89,72.72 v2(24.81,73.63)
  BOTTOM w0.11: v2(94.67,60.5) 94.97,60.8 UC1.J20
  BOTTOM w0.117: v2(22.51,72.72) 22.59,72.64 QH2.4 ; v2(28.74,70.88) 28.68,70.95 28.68,71.83 26.88,73.63 RH24.2 26.63,73.63 CH12.1 v2(24.81,73.63)
APU_DP1_CTRL_DAT: length 90.4
  IN1 w0.102: v2(95.48,60.5) 95.06,60.09 94.55,60.09 94.36,59.9 91.99,59.9 91.74,60.15 91.04,60.15 90.34,60.85 87.74,60.85 87.72,60.86 87.33,60.86 85.38,62.81 82.15,62.81 82.03,62.68 82.03,62.54 82.13,62.44 82.27,62.44 v2(82.56,62.15)
  IN3 w0.127: v2(28.11,70.88) 28.2,70.97 28.2,71.48 28.64,71.92 28.98,71.92 34.32,77.27 37.63,77.27 37.63,77.27 49.73,77.27 51.73,79.27 60.69,79.27 67.27,72.69 67.27,70.88 68.8,69.35 69.26,69.35 70.5,68.11 70.5,67.65 73.71,64.44 80.49,64.44 82.08,62.84 82.08,62.11 82.21,61.98 82.39,61.98 v2(82.56,62.15)
  BOTTOM w0.102: UC1.K20 95.78,60.8 v2(95.48,60.5)
  BOTTOM w0.117: v2(28.11,70.88) 28.13,70.88 28.42,71.17 28.42,71.34 28.2,71.55 28.03,71.55 27.52,71.04 27.06,71.04 26.96,70.94 RH23.2 CH11.1 25.74,70.94 25.36,70.56 25.21,70.56 25.09,70.68 25.09,71.54 24.96,71.67 24.53,71.67 24.38,71.51 QH2.1
APU_DP1_HPD: length 108.3
  TOP w0.102: 17.63,70.12 17.74,70.23 QH1.1
  TOP w0.117: v2(14.8,70.06) 15.95,71.21 RH13.2 16.64,71.21 17.31,70.55 17.31,70.04 v3(17.43,69.92) 17.63,70.12
  IN1 w0.102: v2(74.36,61.02) 75.51,59.87 84.4,59.87 84.62,59.64 86.27,59.64 87.37,58.55 89.37,58.55 90.54,57.38 95.6,57.38 95.7,57.49 96.23,57.49 96.41,57.66 96.41,59.19 96.8,59.58 v2(96.97,59.58)
  IN3 w0.117: v2(74.36,61.02) 74.35,61.02 72.86,61.02 66.85,67.04 64.91,67.04 63.14,68.81 63.14,69.88 61.79,71.23 59.84,71.23 56.19,74.88 42.71,74.88 34.01,66.19 29.29,66.19 26.53,63.43 23.46,63.43 22.93,62.9 17.28,62.9 14.74,65.44 14.74,70 v2(14.8,70.06)
  BOTTOM w0.102: v2(96.97,59.58) 96.97,59.61 UC1.L21
APU_DP1_N0: length 97.5
  IN3 w0.127: v2(93.59,58.5) 93.55,58.5 92.92,59.12 92.21,59.12 91.7,59.63 90.7,59.63 90.67,59.59 89.17,59.59 88.8,59.96 87.05,59.96 83.2,63.81 82.3,63.81 80.96,65.15 77.49,65.15 75.91,66.73 75.91,68.45 72.94,71.43 72.33,71.43 70.51,73.25 67.64,73.25 60.83,80.06 51.6,80.06 49.46,77.93 37.36,77.93 37.36,77.92 33.62,77.92 32.05,76.35 30.07,76.35 26.33,72.6 26.33,70.69 27.19,69.83 28.81,69.83 28.93,69.71 28.93,67.77 25.54,64.38 22.44,64.38 v2(22.24,64.57)
  BOTTOM w0.102: v2(93.59,58.5) 94.09,58 UC1.H23
  BOTTOM w0.117: v2(22.24,64.57) 22.02,64.35 21.86,64.35 21.67,64.54 21.34,64.54 CH10.1
APU_DP1_N1: length 92
  IN3 w0.127: v2(93.07,59.52) 92.83,59.76 92.83,59.85 92.53,60.14 92.15,60.14 91.85,60.44 90.78,60.44 90.5,60.72 87.62,60.72 83.59,64.75 83.59,64.86 83.21,65.24 83.1,65.24 82.91,65.43 82.91,66.49 82.36,67.04 78.62,67.04 73.47,72.19 72.64,72.19 70.06,74.77 67.37,74.77 60.84,81.3 48.81,81.3 46.62,79.11 34.56,79.11 34.13,78.68 33.31,78.68 31.73,77.11 29.76,77.11 25.57,72.92 25.57,67.46 24.27,66.16 22.56,66.16 v2(22.37,66.35)
  BOTTOM w0.102: v2(93.07,59.52) 93.37,59.21 UC1.G22
  BOTTOM w0.117: CH8.1 21.34,66.18 22.2,66.18 v2(22.37,66.35)
APU_DP1_N2: length 96.8
  IN3 w0.127: v2(22.94,68.4) 23.01,68.33 23.26,68.33 23.39,68.46 23.39,70.65 22.58,71.46 22.08,71.46 21.63,71.9 21.63,75.05 23.58,77.01 26.58,77.01 27.56,77.98 30.19,77.98 33.03,80.83 34.76,80.83 35.71,79.87 46.05,79.87 48.49,82.31 60.9,82.31 67.69,75.52 70.38,75.52 72.95,72.95 77.56,72.95 83.76,66.75 83.76,66.11 84.16,65.71 85.99,65.71 86.03,65.71 86.03,65.71 86.43,65.71 89.38,62.77 89.77,62.77 90.92,61.62 91.19,61.62 91.19,61.62 91.52,61.62 91.71,61.62 91.94,61.39 92.17,61.15 92.97,61.15 93.56,60.56 v2(93.7,60.56)
  BOTTOM w0.102: UC1.H21 94.18,60.03 93.7,60.5 v2(93.7,60.56)
  BOTTOM w0.117: v2(22.94,68.4) 22.52,68.4 22.38,68.54 22.38,69.13 22.04,69.47 21.36,69.47 CH4.1
APU_DP1_N3: length 97.4
  IN3 w0.127: v2(21.73,68.04) 21.91,67.86 22.03,67.86 22.19,68.03 22.19,68.74 20.2,70.73 20.2,72.48 20.46,72.74 20.46,75.15 23.21,77.9 23.21,78.34 24.84,79.98 29.59,79.98 31.32,81.71 35.21,81.71 36.3,80.63 45.73,80.63 48.18,83.07 61.21,83.07 68,76.28 70.69,76.28 73.27,73.71 78,73.71 84.47,67.24 86.16,67.24 87.91,65.49 87.91,65.47 88.91,64.47 88.91,64.11 89.6,63.43 90.04,63.43 91,62.47 91.61,62.47 91.78,62.64 93.25,62.64 93.72,62.18 93.72,61.6 v2(93.77,61.55)
  BOTTOM w0.102: UC1.G20 93.77,61.39 v2(93.77,61.55)
  BOTTOM w0.117: v2(21.73,68.04) 21.57,67.88 21.34,67.88 CH2.1
APU_DP1_P0: length 97.4
  IN3 w0.127: v2(92.94,58.5) 92.99,58.55 92.99,58.73 92.83,58.9 92.11,58.9 91.61,59.4 90.8,59.4 90.76,59.37 89.08,59.37 88.71,59.74 86.96,59.74 83.11,63.58 82.21,63.58 80.86,64.93 77.4,64.93 75.69,66.64 75.69,68.36 72.84,71.2 72.23,71.2 70.41,73.02 67.55,73.02 60.73,79.84 51.69,79.84 49.56,77.7 37.46,77.7 37.45,77.7 33.72,77.7 32.14,76.12 30.17,76.12 26.55,72.51 26.55,70.79 27.28,70.06 28.9,70.06 29.16,69.8 29.16,67.68 25.63,64.15 22.4,64.15 v2(22.24,63.99)
  BOTTOM w0.089: UC1.G23 93.37,57.83 93.29,57.74 93.12,57.74 93.03,57.83 93.03,58.41 v2(92.94,58.5)
  BOTTOM w0.117: CH9.1 21.34,64.32 21.58,64.32 21.77,64.13 22.1,64.13 v2(22.24,63.99)
APU_DP1_P1: length 92
  IN3 w0.127: v2(92.37,59.52) 92.47,59.52 92.6,59.64 92.6,59.75 92.44,59.91 92.06,59.91 91.76,60.21 90.68,60.21 90.4,60.5 87.53,60.5 83.37,64.66 83.37,64.77 83.12,65.02 83.01,65.02 82.69,65.34 82.69,66.39 82.27,66.81 78.53,66.81 73.37,71.96 72.55,71.96 69.97,74.54 67.28,74.54 60.74,81.07 48.9,81.07 46.72,78.89 34.65,78.89 34.22,78.46 33.4,78.46 31.82,76.88 29.85,76.88 25.79,72.82 25.79,67.36 24.36,65.93 22.56,65.93 v2(22.37,65.74)
  BOTTOM w0.102: UC1.F22 92.6,58.92 92.46,58.92 92.24,59.14 92.24,59.39 v2(92.37,59.52)
  BOTTOM w0.117: CH7.1 21.34,65.96 22.15,65.96 v2(22.37,65.74)
APU_DP1_P2: length 96.7
  IN3 w0.127: v2(22.94,67.8) 23.24,68.11 23.35,68.11 23.61,68.36 23.61,70.75 22.68,71.68 22.17,71.68 21.86,71.99 21.86,74.96 23.68,76.78 26.68,76.78 27.66,77.76 30.28,77.76 33.13,80.6 34.66,80.6 35.62,79.64 46.14,79.64 48.59,82.09 60.8,82.09 67.59,75.3 70.28,75.3 72.86,72.72 77.47,72.72 83.53,66.65 83.53,66.02 84.06,65.49 86.34,65.49 89.28,62.54 89.68,62.54 90.83,61.39 91.29,61.39 91.29,61.39 91.61,61.39 91.84,61.16 92.08,60.93 92.83,60.93 92.95,60.8 92.95,60.57 92.94,60.56 v2(92.94,60.53)
  BOTTOM w0.089: UC1.G21 93.35,60.03 93.35,60.4 93.34,60.41 93.34,60.58 93.23,60.69 93.12,60.69
  BOTTOM w0.117: v2(92.94,60.53) 92.94,60.57 93.06,60.69 93.12,60.69 ; CH3.1 21.32,69.25 21.94,69.25 22.16,69.04 22.16,68.44 22.43,68.18 22.57,68.18 v2(22.94,67.8)
APU_DP1_P3: length 97.5
  IN3 w0.127: v2(21.73,67.43) 21.94,67.64 22.12,67.64 22.42,67.93 22.42,68.83 20.43,70.82 20.43,72.38 20.69,72.65 20.69,75.06 23.44,77.81 23.44,78.25 24.94,79.75 29.68,79.75 31.42,81.49 35.12,81.49 36.2,80.4 45.83,80.4 48.27,82.85 61.12,82.85 67.91,76.06 70.6,76.06 73.18,73.48 77.91,73.48 84.38,67.01 86.07,67.01 87.69,65.4 87.69,65.38 88.69,64.38 88.69,64.02 89.5,63.2 89.95,63.2 90.9,62.25 91.71,62.25 91.87,62.41 93.16,62.41 93.49,62.08 93.49,61.83 93.21,61.55 v2(93.07,61.55)
  BOTTOM w0.11: v2(93.07,61.55) 92.78,61.55 92.67,61.44 UC1.F20
  BOTTOM w0.117: CH1.1 21.35,67.65 21.51,67.65 v2(21.73,67.43)
APU_FCH_PWRGD_R: length 81.9
  TOP w0.102: RC55.2 172,42.42 171.2,43.22 UC7.4 170.94,43.22 v3(169.77,42.05) 169.36,41.64 168.85,41.64 168.65,41.43 RC64.2 168.19,41.29 168.49,40.99 168.49,39.65 v2(168.39,39.55)
  IN3 w0.102: v2(122.18,77.41) 123.05,77.41 123.17,77.3 123.17,77.3 123.48,76.99 125.06,76.99 125.43,76.62 126.85,76.62 127.04,76.43 130.14,76.43 130.58,75.99 136.01,75.99 136.32,76.3 140.43,76.3 141.38,75.34 141.95,75.34 147.94,69.36 148.36,69.36 150.21,67.52 151.75,67.52 152.67,66.6 152.67,65.76 154.3,64.14 154.47,64.14 154.96,63.66 157.17,63.66 160.76,60.06 161.15,60.06 164.95,56.26 164.95,55.34 165.46,54.83 165.46,47.43 165.21,47.18 165.21,41.69 167.35,39.55 v2(168.39,39.55)
  BOTTOM w0.102: UC1.AW2 120.16,75.18 120.16,75.57 120.62,76.03 121,76.03 122.18,77.2 v2(122.18,77.41)
APU_FP_RST_R: length 124.4
  IN2 w0.102: 124.22,67.98 124.2,67.98 123.32,68.85 122.05,68.85 121.4,69.5 v2(120.37,69.5)
  IN2 w0.127: v2(152.7,31.93) 151.85,31.93 149.63,34.14 147.67,34.14 146.41,35.4 146.41,42.56 147.11,43.26 149.37,43.26 150.74,44.63 150.74,45.09 150.63,45.2 150.63,46.48 148.82,48.29 148.82,51.99 147.96,52.85 147.94,52.85 145.1,55.69 145.1,56.92 145.1,56.93 143.09,58.94 143.09,60.31 141.42,61.98 141.42,62.06 141.41,62.07 141.41,65.12 139.18,67.35 127.78,67.35 127.36,67.77 127.35,67.77 127.16,67.96 124.24,67.96 124.22,67.98
  IN3 w0.127: v2(113.25,8.01) 113.58,8.01 113.66,8.08 114.3,8.08 114.93,8.72 118.51,8.72 118.87,8.35 128.14,8.35 128.67,7.82 131.55,7.82 133.66,9.93 133.66,10.39 134.19,10.93 140.48,10.93 147.87,18.32 147.87,19.73 v2(148.32,20.17)
  BOTTOM w0.089: UC1.AW11 120.07,69.2 v2(120.37,69.5)
  BOTTOM w0.117: RFP10.1 113.05,8.21 v2(113.25,8.01) ; v2(148.32,20.17) 148.37,20.22 148.78,20.22 v3(149.5,20.93) 152.19,23.63 152.19,30.59 152.7,31.1 v2(152.7,31.93)
APU_PCIE0_RST#: length 31.7
  IN3 w0.102: v2(116.97,73.09) 117.81,73.09 118.91,71.99 122.57,71.99 122.95,71.61 130.43,71.61 131.83,71.17 132.6,71.07 133.54,71.07 134.64,69.98 136.13,69.98 141.64,64.47 v2(143.6,64.47)
  BOTTOM w0.102: v2(143.6,64.47) 143.12,64.47 RC34.2 ; v2(116.97,73.09) 116.57,72.7 UC1.AP6
APU_PCIE1_RST#: length 25.9
  IN2 w0.102: v2(118.15,67.45) 118.16,67.45 118.67,67.96 121.31,67.96 122.7,66.58 126.59,66.58 127.81,65.36 132.9,65.36 133.45,64.81 135.61,64.81 136.27,64.15 136.61,64.15 136.61,64.15 137.54,64.15 v2(138.84,65.45)
  BOTTOM w0.102: v2(138.84,65.45) 139.2,65.8 v1(139.49,65.8) 140.14,65.8 RC35.2 ; UC1.AT13 117.77,67.07 v2(118.15,67.45)
APU_PCIE_RST#: length 301.7
  TOP w0.102: RWL18.2 172.46,35.53 172.93,36 v2(173.14,36) ; v2(166.79,34.56) RC73.2 166.17,35.4 166.46,35.69 UC8.4 ; USD2.2 68.56,61.77 68.32,62.01 67.22,62.01 66.91,61.69 RSD9.2 66.3,60.93 65.68,60.3 v3(65.68,56.09) v2(65.68,54.21) ; v2(174.36,33.25) 174.36,33.23 174.04,32.91 UWL22.2
  IN1 w0.102: v2(65.68,54.21) 65.51,54.21 63.76,52.46 57.37,52.46 45.25,40.34 v2(37.54,40.34) ; v2(193.52,21.8) 193.53,21.8 193.53,22.05 192.97,22.61 192.97,25.24 193.53,25.8 193.53,27.67 193.03,28.17 190.69,28.17 190.39,27.87 188.66,27.87 186.96,29.57 184.88,29.57 184.55,29.24 177.64,29.24 176.88,30 v2(176.88,32.01)
  IN2 w0.102: v2(174.36,33.25) 174.36,33.23 174.31,33.18 173.42,33.18 173.14,33.46 v2(173.14,36) ; v2(129.61,8.23) 129.61,8.36 129.25,8.72 127.53,8.72 126.99,8.18 124.22,8.18 123.74,8.67 122.12,8.67 121.62,8.17 118.72,8.17 117.85,9.05 117.32,9.05 116.54,9.05 115.81,9.78 112.36,9.78 112.17,9.59 110.16,9.59 110.1,9.53 107.69,9.53 106.75,8.59 103.86,8.59 103.23,9.23 102.94,9.23 102.92,9.24 99,9.24 97.4,10.84 93.34,10.84 92.92,10.42 92.19,10.42 91.68,9.91 86.38,9.91 85.49,10.8 84.8,10.8 84.65,10.65 82.87,10.65 82.29,10.06 77.13,10.06 70.21,16.98 68.2,16.98 67.48,16.26 49.88,16.26 49.52,16.62 43.98,16.62 43.45,16.08 36.54,16.08 32.17,20.45 31.87,20.45 31.56,20.76 31.56,21.34 32.02,21.8 32.02,30.97 33.57,32.52 33.57,36.07 34.56,37.06 34.56,37.36 v2(37.54,40.34)
  BOTTOM w0.102: v2(173.14,36) 173.14,38.66 172.6,39.2 170.03,39.2 168.38,37.55 168.38,35.37 168.19,35.18 167.41,35.18 v2(166.79,34.56) 166.79,26.03 166.69,25.93 162.08,25.93 161.59,26.42 157,26.42 151.76,21.18 151.76,19.68 149.81,17.73 146.23,17.73 145.66,17.17 145.66,15.67 144.97,14.98 144.66,14.98 144.15,14.46 144.15,14.12 144.53,13.75 145.32,13.75 147.13,11.93 147.13,10.9 146.52,10.29 139.61,10.29 138.85,9.53 138.85,8.41 137.84,7.4 130.34,7.4 129.61,8.13 v2(129.61,8.23) ; v2(176.88,32.01) 175.76,32.01 174.51,33.25 v2(174.36,33.25) ; JIO1.25 v2(193.52,21.8) ; v2(37.54,40.34) 39.16,41.96 39.16,45.93 38.45,46.64 38.45,47.78 38.27,47.96 36.72,47.96 36.62,47.86 RSD8.2 36.54,47.45 USD1.2
APU_PCIE_RST#_R: length 54.8
  TOP w0.102: v2(164.28,39.17) 164.2,39.09 164.2,37.37 163.94,37.1 RC72.1 164.39,36.8 164.59,36.99 UC8.1 165.44,36.99 165.59,36.85 165.59,36.44 165.48,36.34 ; RC73.1 165.26,34.99 165.59,35.32 165.59,36.24 165.48,36.34 ; 165.48,36.34 UC8.2
  IN3 w0.102: v2(164.28,39.17) 164.53,39.42 164.53,41.07 164.35,41.25 164.35,52.98 164.19,53.14 164.19,54.82 164.09,54.92 164.09,55.02 161.59,57.52 161.59,58.32 160.96,58.95 155.59,58.95 153.97,57.32 v2(153.97,57.16)
  BOTTOM w0.102: v2(153.97,57.16) 151.68,57.16 151.32,57.51 151.32,57.86 151.35,57.88 151.35,59.34 150.85,59.84 148.84,59.84 148.05,60.64 v3(148.05,61.49) 148.05,62.36 146.83,63.58 144.49,63.58 144.25,63.82 RC34.1 142.83,63.82 142.36,64.29 CC20.2 RC35.1
APU_PCIE_WAKE#: length 19.4
  IN2 w0.102: v2(136.44,64.56) 135.78,65.22 133.61,65.22 133.07,65.77 127.98,65.77 126.76,66.99 122.6,66.99 121.36,68.22 120.68,68.22 v2(120.4,68.5)
  BOTTOM w0.102: v2(120.4,68.5) 120.37,68.5 120.07,68.2 UC1.AW12 ; RC48.2 136.01,64.66 136.11,64.56 v2(136.44,64.56)
APU_PWRGD: length 112.5
  IN1 w0.102: v2(117.2,81.07) 118.25,81.07 v2(118.72,80.6)
  IN2 w0.102: v2(161.51,64.88) 161.51,65.18 158.41,68.28 158.41,69.41 156.23,71.6 154.28,71.6 153.44,72.44 152.7,72.44 150.4,74.73 149.33,74.73 144.76,79.31 140.91,79.31 137.23,82.99 122.74,82.99 122.64,82.89 121.9,82.89 119.61,80.6 v2(118.72,80.6)
  IN3 w0.102: v2(107.1,83.41) 107.1,83.9 102.42,88.59 102.42,91.87 101.11,93.18 101.11,93.77 100.69,94.19 98.7,94.19 97.95,93.44 97.95,93.08 v2(97.97,93.06)
  BOTTOM w0.089: 120.9,78.08 119.51,78.08 119.42,78.17 RC30.2 119.42,79.65 ; 121.23,78.4 121.01,78.19
  BOTTOM w0.102: v2(107.1,83.41) v3(109.2,83.41) 114.52,83.41 116.86,81.07 v2(117.2,81.07) ; U20.3 148.96,55.57 149.25,55.28 RHDT11.2 150.09,55.71 150.78,56.39 154.9,56.39 155.97,57.47 155.97,60.94 158.23,63.2 159.83,63.2 v2(161.51,64.88) ; RC25.2 121.23,78.4 ; 119.42,79.65 CC18.2 119.42,79.9 v2(118.72,80.6) ; 121.01,78.19 120.44,77.62 120.44,76.21 119.84,75.61 119.84,75.3 119.56,75.02 119.56,74.77 119.71,74.62 119.71,74.31 119.88,74.15 UC1.AW4
  BOTTOM w0.254: v2(97.97,93.06) PU801.19
APU_PWRGD_BUF: length 3.8
  BOTTOM w0.117: JHDT1.10 149.27,53.36 148.96,53.66 U20.4 149.65,54.38 149.66,54.36 RHDT11.1
APU_RST#: length 71.5
  IN2 w0.102: v2(124.87,79.48) 125.57,79.48 126.43,78.62 131.88,78.62 132.47,78.02 136.53,78.02 136.96,78.45 v2(136.96,78.76) 137.18,78.76 138.88,77.06 143.28,77.06 148.24,72.1 148.24,72.1 148.66,71.68 149.18,71.68 153.08,67.78 v2(153.08,66.19)
  BOTTOM w0.089: 124.22,79.48 RC603.2
  BOTTOM w0.102: 124.22,79.48 124.85,80.1 CC19.2 124.92,79.53 v2(124.87,79.48) ; v2(153.08,66.19) 152.92,66.19 152.82,66.08 152.82,64.77 v3(153.91,63.69) 155.64,61.96 155.64,57.6 154.76,56.72 150.69,56.72 150.56,56.85 147.29,56.85 146.54,56.1 RHDT10.2 147.5,55.28 147.66,55.44 U20.1 ; v2(136.96,78.76) 136.93,78.78 136.93,80.28 RC111.1 137.42,80.74 138.1,81.43 RC24.2 138.71,81.22 138.9,81.03 UC22.4 ; UC1.AW3 120.55,74.68 120.55,75.41 120.79,75.65 121.24,75.65 122.76,77.17 122.76,77.31 124.1,78.65 RC603.2
APU_RST#_BUF: length 3.8
  BOTTOM w0.117: JHDT1.12 148,53.29 147.66,53.63 U20.6 147.11,54.38 147.09,54.36 RHDT10.1
APU_RST#_EC: length 67
  TOP w0.102: UEC1.127 177.6,44.34 177.46,44.2 176.65,44.2 175.93,44.92 173.83,44.92 173.59,44.68 173.25,44.68 173.02,44.92 173.02,46.12 v3(174.53,47.63) 175.02,48.13 175.02,48.34 175.56,48.87 v2(175.56,48.9)
  IN2 w0.102: v2(137.39,79.2) 137.41,79.22 138,79.22 139.71,77.51 143.4,77.51 148.4,72.51 148.41,72.51 148.83,72.09 149.39,72.09 151.61,69.87 152.04,69.87 156.72,65.18 158.87,65.18 160.83,63.22 163.46,63.22 168.22,58.46 168.22,57.37 169.49,56.1 169.49,55.28 174.77,49.99 174.77,49.21 175.07,48.9 v2(175.56,48.9)
  BOTTOM w0.102: UC22.2 139.55,79.27 139.31,79.51 138.17,79.51 137.85,79.82 RC111.2 137.39,79.35 137.4,79.35 137.4,79.21 v2(137.39,79.2)
APU_RST#_R: length 113.9
  TOP w0.117: UT1.34 41.55,83.87 41.76,84.08 42.36,84.08 42.63,84.35 44,84.35 44.13,84.21 44.57,84.21 v3(45.28,83.5) 46.02,82.77 v2(46.02,82.5)
  IN1 w0.102: v2(124.1,81.01) 123.93,81.17 118.73,81.17 118.38,81.52 116.22,81.52 115.72,81.02 113.01,81.02 112.93,81.1 112.56,81.1 112.32,81.34 110.45,81.34 110.24,81.13 109.43,81.13 109.29,81.26 109.09,81.46 108.3,81.46 105.64,78.81 61.31,78.81 60.76,79.35 53.43,79.35 45.25,71.18 37.96,71.18 37.13,72.01 37.13,73.99 45.64,82.5 v2(46.02,82.5)
  BOTTOM w0.117: v2(124.1,81.01) RC603.1
APU_SPI_CLK: length 11.3
  BOTTOM w0.089: 124.22,69.72 123.9,69.4 122.38,69.4 UC1.BC10
  BOTTOM w0.117: 124.22,69.72 125.27,70.77 125.78,70.77 126.91,71.91 126.91,72.22 127.61,72.92 v3(130,72.92) RC84.2 RC97.1
APU_SPI_CLK_R: length 52.9
  TOP w0.117: v2(150.49,58.17) v1(151.25,58.17)
  IN1 w0.102: v2(150.49,58.17) 150.49,63.84 146.83,67.49 v2(146.83,67.57)
  BOTTOM w0.117: v2(146.83,67.57) 146.32,67.57 142.84,71.05 135.7,71.05 133.72,73.03 RC59.1 RC65.1 133.72,74.43 133.34,74.43 132.63,73.72 132.63,73.26 132.29,72.92 RC84.1 ; 139.42,45.16 139.42,46.22 139.59,46.39 141.7,46.39 142.03,46.72 142.03,52.76 143.62,54.35 143.62,56.56 143.75,56.7 146.14,56.7 147.11,57.66 149.98,57.66 v2(150.49,58.17)
APU_SPI_CS1#: length 52.1
  TOP w0.117: v2(127.37,72.01) 127.37,71.7 v1(127.87,71.2)
  IN2 w0.117: v2(127.37,72.01) 127.37,71.3 128.84,69.83 139.98,69.83 146.51,63.3 146.51,62.83 146.64,62.71 147.04,62.71 147.18,62.57 147.18,62.32 147.07,62.2 146.45,62.2 146.31,62.06 146.31,61.85 146.43,61.74 147.07,61.74 147.18,61.62 147.18,61.17 v2(147.21,61.14)
  BOTTOM w0.089: 124.11,69.12 124.22,69.23
  BOTTOM w0.102: UC1.BD11 122.79,69.12 124.11,69.12
  BOTTOM w0.117: v2(127.37,72.01) 127.34,71.98 127.34,71.81 125.91,70.39 125.38,70.39 124.22,69.23 ; UC2.1 136.88,53.55 137.01,53.68 RC95.1 136.44,54.87 136.44,55.63 137.56,56.75 142.28,56.75 143.3,57.76 145.69,57.76 146.8,58.88 146.8,60.15 146.75,60.2 146.75,60.69 v2(147.21,61.14)
APU_SPI_HOLD#: length 62.4
  TOP w0.102: v2(123.23,71.1) v1(122.53,71.1)
  IN1 w0.102: v2(123.23,71.1) 124.65,69.68 125.56,69.68 126.25,68.98 139.5,68.98 142.04,66.44 145.89,66.44 148.42,63.91 148.42,58.44 149.01,57.84 149.01,49.02 148.77,48.78 148.77,47.66 145.28,44.16 v2(145.28,43.54)
  BOTTOM w0.102: UC1.BC8 122.31,71.47 122.86,71.47
  BOTTOM w0.117: UC2.7 RC96.1 139.27,43.66 139.74,43.19 139.74,42.5 140.11,42.13 143.5,42.13 144.91,43.54 v2(145.28,43.54) ; 122.86,71.47 v2(123.23,71.1)
APU_SPI_MISO: length 53
  TOP w0.117: v1(126.48,72.92) 126.48,72.09 v2(126.5,72.08)
  IN2 w0.117: v2(147.18,60.38) 145.69,61.88 145.69,62.33 145.57,62.45 144.32,62.45 144.2,62.57 144.2,62.79 144.32,62.91 145.24,62.91 145.36,63.03 145.36,63.23 145.22,63.38 144.32,63.38 144.2,63.49 144.2,63.7 144.32,63.82 144.84,63.82 144.95,63.93 144.95,64.17 144.84,64.29 144.34,64.29 144.2,64.43 144.2,65.02 139.81,69.41 128.63,69.41 126.49,71.55 126.49,72.07 v2(126.5,72.08)
  BOTTOM w0.089: 124.22,70.21 123.66,69.65 122.57,69.65 122.39,69.83 122.11,69.83 121.78,69.5 UC1.BA10
  BOTTOM w0.117: v2(147.18,60.38) 147.13,60.33 147.16,60.3 147.16,58.73 145.84,57.41 143.45,57.41 142.41,56.37 139.11,56.37 138.78,56.04 138.78,54.92 RC93.1 UC2.2 ; v2(126.5,72.08) 126.46,72.08 125.81,71.43 125.44,71.43 124.22,70.21
APU_SPI_MOSI: length 61.4
  TOP w0.102: v2(123.87,71.1) v1(124.48,71.1)
  IN1 w0.102: v2(146.02,44.28) 146.37,43.92 148.69,43.92 149.18,44.41 149.18,48.61 149.42,48.85 149.42,58.01 148.82,58.61 148.82,64.08 146.06,66.85 142.45,66.85 139.91,69.39 126.42,69.39 125.72,70.08 124.89,70.08 124.78,70.19 124.78,70.19 v2(123.87,71.1)
  BOTTOM w0.089: 123.55,70.68 123.87,71
  BOTTOM w0.102: UC1.BB8 122.21,71 122.53,70.68 123.55,70.68
  BOTTOM w0.117: UC2.5 RC92.1 140.88,43.85 143.7,43.85 143.83,43.97 145.33,43.97 145.63,44.28 v2(146.02,44.28) ; 123.87,71 v2(123.87,71.1)
APU_SPI_WP#: length 59.4
  TOP w0.117: v2(125.77,72.12) 125.77,71.59 126.15,71.2 v1(126.22,71.2)
  IN2 w0.117: v2(147.69,59.52) 147.83,59.66 147.83,62.58 140.16,70.25 129.92,70.25 129.45,70.73 129.26,70.73 128.97,71.01 127.52,72.46 126.25,72.46 125.9,72.12 v2(125.77,72.12)
  BOTTOM w0.089: 123.91,70.4 124.22,70.72
  BOTTOM w0.102: UC1.BA9 121.83,70.5 122.15,70.17 122.41,70.17 122.63,70.4 123.91,70.4
  BOTTOM w0.117: v2(125.77,72.12) 125.63,72.12 124.22,70.72 ; v2(147.69,59.52) 147.69,58.76 145.99,57.05 143.6,57.05 143.27,56.73 143.27,54.56 143.01,54.3 142.61,54.3 142.49,54.41 142.49,55.91 142.38,56.02 142.14,56.02 142.03,55.91 142.03,54.41 141.91,54.3 141.68,54.3 141.56,54.41 141.56,55.91 141.44,56.02 141.21,56.02 141.09,55.91 141.09,54.41 140.97,54.3 140.74,54.3 140.62,54.41 140.62,55.91 140.51,56.02 140.27,56.02 140.16,55.91 140.16,54.41 140.04,54.3 RC94.1 139.42,52.41
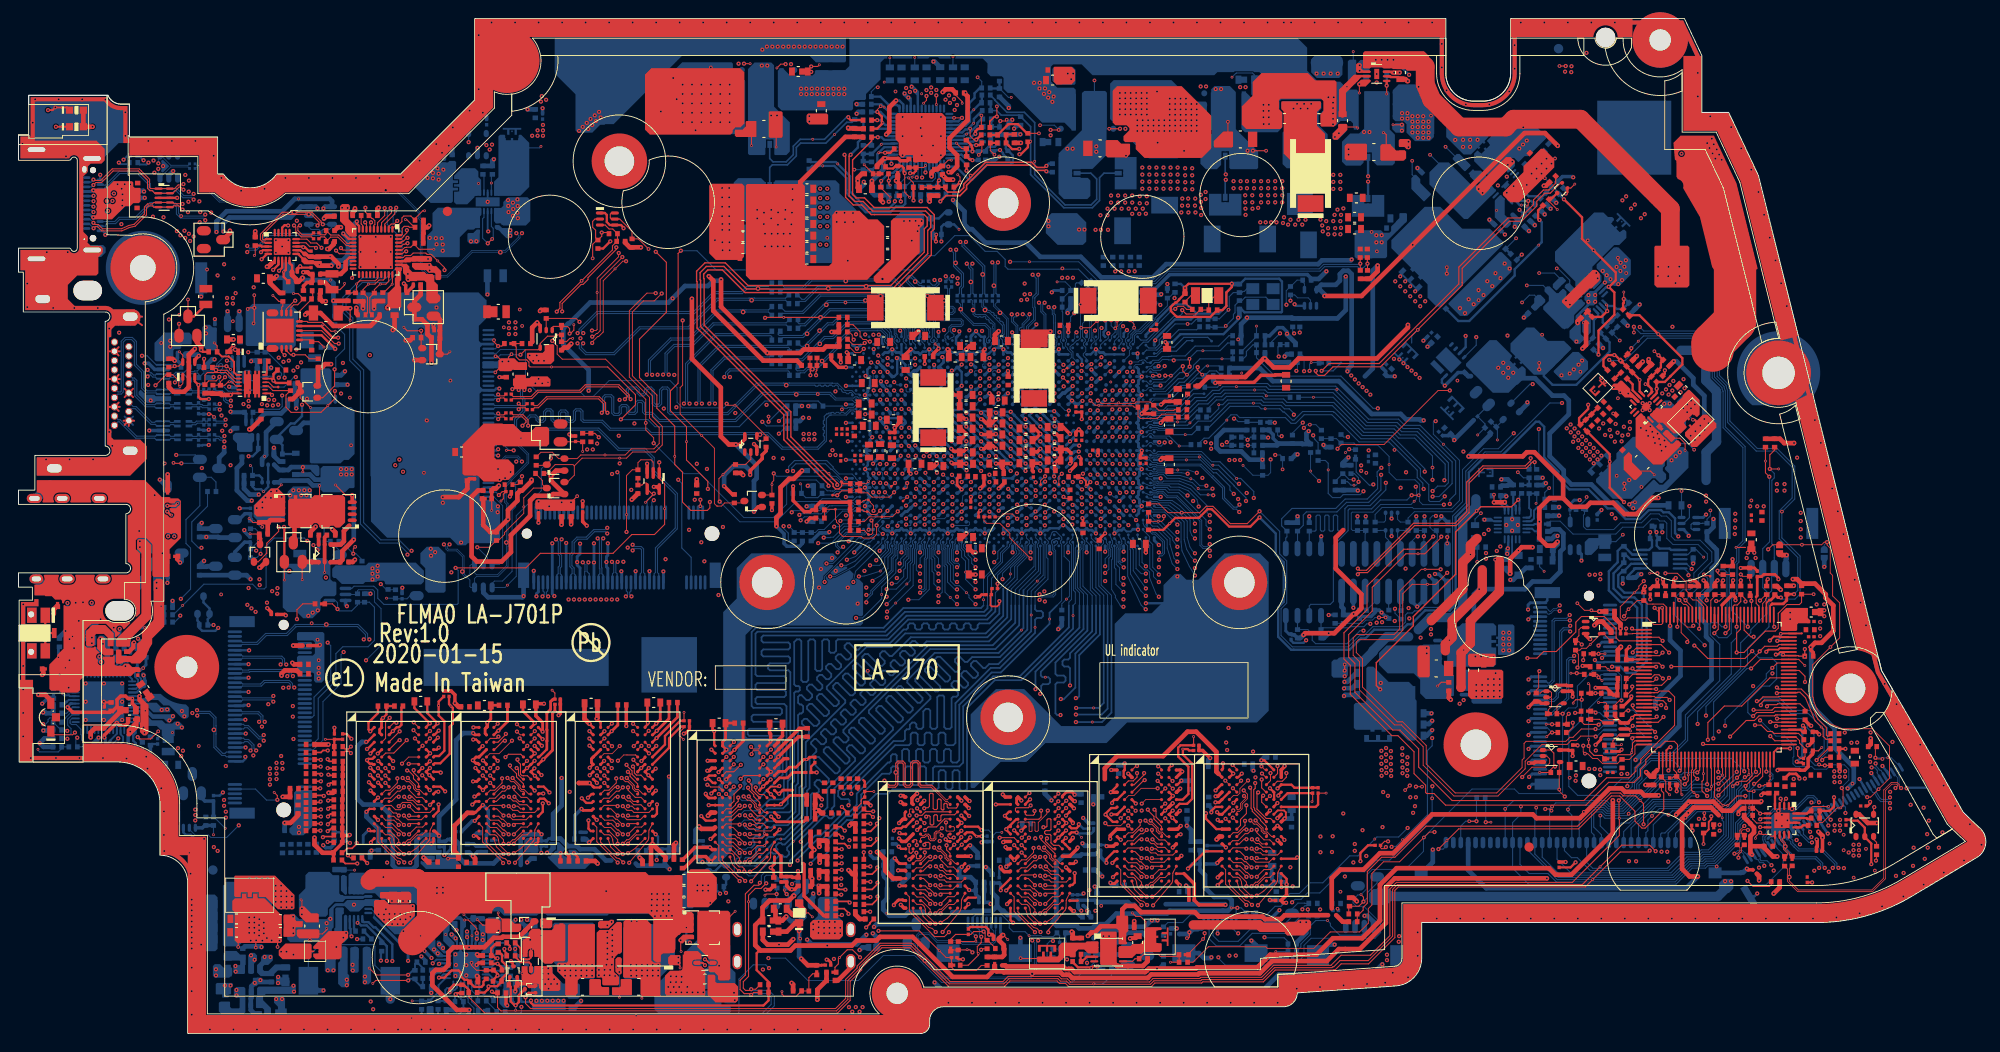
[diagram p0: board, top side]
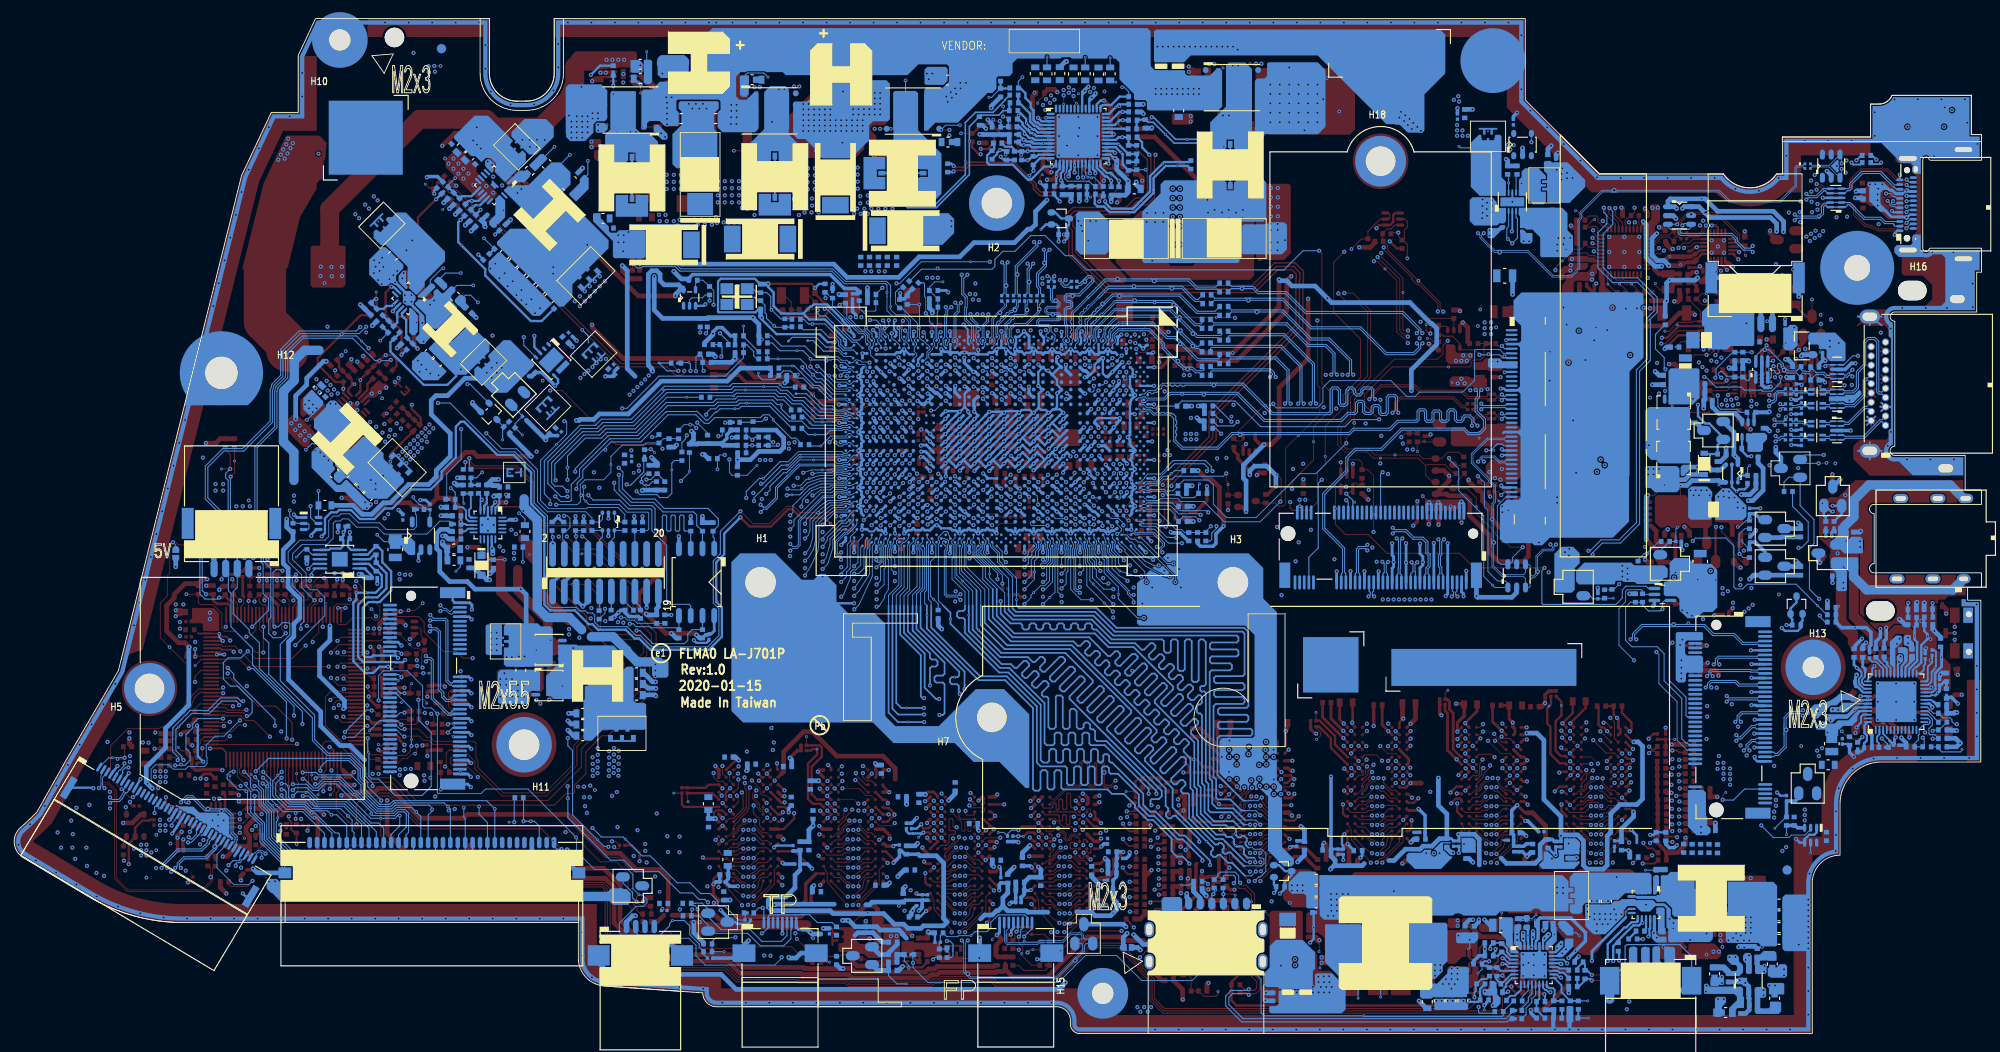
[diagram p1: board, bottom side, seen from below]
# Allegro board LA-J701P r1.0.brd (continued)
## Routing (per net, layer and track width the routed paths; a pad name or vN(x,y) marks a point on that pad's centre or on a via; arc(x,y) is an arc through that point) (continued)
APU_SVC: length 89.1
  TOP w0.102: v2(61.97,74.63) 61.97,74.73 62.55,75.32 62.65,75.32 63.16,75.82 63.16,81.36 v3(64.43,82.63) 65.27,83.47 v2(65.62,83.47)
  IN1 w0.102: v2(65.62,83.47) 65.7,83.55 65.92,83.55 66.53,82.94 72.99,82.94 73.19,82.73 89.69,82.73 96.27,89.31 96.27,91.18 v2(97.6,92.52)
  IN3 w0.102: v2(84.48,55.47) 83.52,55.47 82.9,56.09 82.9,56.4 80.96,58.34 78.39,58.34 74.15,62.58 73.11,62.58 72.93,62.58 65.41,70.1 65.41,70.44 65.41,71.36 62.14,74.63 v2(61.97,74.63)
  BOTTOM w0.102: v2(97.6,92.52) 97.57,92.56 PU801.20 ; UC1.D25 90.94,56.5 90.59,56.85 90.36,56.85 90.17,56.66 87.68,56.66 87.11,56.09 87.11,55.73 PC854.1 86.24,55.85 84.89,55.85 84.51,55.47 v2(84.48,55.47)
APU_SVD: length 87
  TOP w0.102: v2(65.22,83.92) 65.22,83.89 62.83,81.5 62.83,75.96 62.52,75.65 62.41,75.65 62.08,75.32 v2(61.97,75.32)
  IN1 w0.102: v2(65.22,83.92) 65.26,83.95 66.09,83.95 66.7,83.34 73.17,83.34 73.37,83.14 89.53,83.14 95.86,89.48 95.86,91.36 97.02,92.51 v2(97.02,92.53)
  IN3 w0.102: v2(83.52,56.33) 83.52,56.36 81.13,58.74 78.59,58.74 74.35,62.98 73.1,62.98 65.81,70.27 65.81,71.53 62.03,75.32 v2(61.97,75.32)
  BOTTOM w0.102: v2(97.02,92.53) 97.17,92.67 PU801.21 ; v2(83.52,56.33) 83.7,56.51 86.57,56.51 86.73,56.67 PC855.1 87.06,56.98 87.44,57.36 90.15,57.36 90.34,57.17 90.59,57.17 90.76,57 UC1.C25
APU_SVT: length 3.6
  BOTTOM w0.102: PR815.2 95.87,92.55 v3(96.53,92.55) 96.53,92.57 96.77,92.81 PU801.22
APU_SVT_R: length 82.7
  TOP w0.102: v2(95.3,89.92) 95.29,89.94 95.29,90.41 PC853.1 ; v2(61.94,75.98) 62.38,75.98 62.5,76.1 v3(62.5,80.09) 62.5,81.64 64.82,83.95 64.82,84.31 64.84,84.33 v2(64.84,84.36)
  IN1 w0.102: v2(64.84,84.36) 66.26,84.36 66.87,83.75 73.34,83.75 73.54,83.55 89.36,83.55 95.3,89.49 v2(95.3,89.92)
  IN3 w0.102: v2(61.94,75.98) 66.22,71.7 66.22,70.44 73.27,63.39 74.55,63.39 78.79,59.15 81.3,59.15 84.34,56.11 v2(84.34,56.05)
  BOTTOM w0.102: UC1.A25 90.03,57.04 87.88,57.04 87.87,57.03 87.58,57.03 86.72,56.16 86.39,56.16 86.37,56.18 84.47,56.18 v2(84.34,56.05) ; v2(95.3,89.92) 95.3,89.96 94.86,90.4 PR815.1
APU_TCK: length 56.9
  TOP w0.102: v2(154.32,53.65) v1(154.32,52.95)
  IN3 w0.102: v2(154.32,53.65) 153.6,52.93 151.11,52.93 150.74,53.29 150.74,55.35 150.08,56.01 150.08,59.42 150.51,59.85 150.51,60.97 148.9,62.58 148.9,62.59 141.43,70.06 138.76,70.06 136.85,71.97 136.17,71.97 134.62,73.52 129.57,73.52 129.12,73.97 126.02,73.97 125.83,74.16 122.9,74.16 122.87,74.14 122.46,74.14 122.3,74.29 121.58,75.01 119.32,75.01 117.87,76.46 117.19,76.46 v2(116.98,76.26)
  BOTTOM w0.102: UC1.AR2 116.88,76.15 v2(116.98,76.26) ; RHDT2.1 154.41,53.74 v2(154.32,53.65) 154.35,53.62 JHDT1.2
APU_TDI: length 58.7
  TOP w0.102: v2(116.51,77.03) 115.76,76.28 v1(114.79,76.28)
  IN3 w0.102: v2(116.51,77.03) 116.82,77.03 117.19,76.66 117.96,76.66 119.41,75.21 121.67,75.21 122.44,74.45 123.02,74.45 123.68,75.1 124.04,75.1 124.57,74.56 125.99,74.56 126.18,74.38 129.28,74.38 129.72,73.93 134.78,73.93 136.24,72.47 141.14,72.47 141.33,72.28 141.33,70.73 150.92,61.14 150.92,59.67 150.51,59.26 150.51,58.93 150.89,58.55 150.89,57.74 151.43,57.21 151.43,54.74 151.81,54.36 v2(151.81,53.74)
  BOTTOM w0.089: v2(116.51,77.03) 116.6,76.93 116.6,76.13 116.68,76.05 116.68,75.19 116.37,74.89 UC1.AP3
  BOTTOM w0.102: JHDT1.6 v2(151.81,53.74) 151.87,53.8 RHDT4.1 CHDT1.1
APU_TDO: length 55.9
  TOP w0.102: v1(118.47,76.22) 118.66,76.41 v2(118.66,77.07)
  IN3 w0.102: v2(118.66,77.07) 118.66,76.54 119.57,75.62 122.47,75.62 122.6,75.75 124.54,75.75 124.91,75.38 126.33,75.38 126.52,75.19 129.62,75.19 130.06,74.75 135.23,74.75 135.65,74.33 137.13,74.33 137.38,74.07 141.06,74.07 142.38,72.75 142.38,70.84 152.31,60.91 152.31,60.02 152.31,56.1 152.31,53.62 152.02,53.33 151.36,53.33 151.15,53.55 v2(151.15,53.73)
  BOTTOM w0.102: v2(118.66,77.07) 118.46,76.87 118.46,76.38 118.66,76.18 118.66,75.58 UC1.AU1 ; JHDT1.8 150.54,53.24 151.02,53.73 v2(151.15,53.73)
APU_TEST4: length 5.7
  BOTTOM w0.089: 124.22,73.74 124.17,73.74
  BOTTOM w0.102: 124.17,73.74 123.46,73.74 122.89,73.17 122.04,73.17 UC1.BB6
  BOTTOM w0.127: T1.1 126.2,74.88 125.06,73.74 124.22,73.74
APU_TEST5: length 7.1
  BOTTOM w0.102: UC1.BD5 122.94,73.5 123.46,74.02
  BOTTOM w0.127: T2.1 128.46,75.24 125.87,75.24 124.82,74.18 123.9,74.18 123.74,74.02 123.46,74.02
APU_TEST14: length 3.3
  TOP w0.102: v2(93.07,56.5) 92.66,56.09 92.12,56.09 91.8,56.41 T4.1 91.34,56.41 91.15,56.6 RC11.1
  BOTTOM w0.102: UC1.G25 93.37,56.8 v2(93.07,56.5)
APU_TEST15: length 5.3
  TOP w0.102: v2(94.97,56.43) 94.4,55.86 93.59,55.86 93.56,55.83 T5.1 91.86,55.83 91.35,55.33 RC12.1
  BOTTOM w0.102: UC1.K25 95.34,56.8 v2(94.97,56.43)
APU_TEST16: length 3.2
  TOP w0.102: RC13.1 91.09,57.42 91.28,57.61 91.43,57.61 91.49,57.68 T6.1 92.01,57.46 92.01,57.38 92.35,57.04 v2(92.35,56.49)
  BOTTOM w0.102: v2(92.35,56.49) 92.67,56.81 UC1.F25
APU_TEST17: length 4
  TOP w0.102: v2(92.13,55.45) 92.27,55.31 92.27,54.08 92.12,53.93 T7.1 91.35,54.37 RC14.1
  BOTTOM w0.102: UC1.F26 92.67,55.91 92.22,55.45 v2(92.13,55.45)
APU_TEST31: length 12.5
  TOP w0.102: v2(92.69,54.92) 92.69,53.94 92.29,53.55 91.23,53.55 91.05,53.73 89.04,53.73 88.69,54.08 88.69,54.95 88.35,55.28 88.35,55.47 88.24,55.58 T8.1 87.11,56.66 RC15.1 RC16.1
  BOTTOM w0.102: UC1.H26 94.03,55.65 93.21,55.65 92.69,55.14 v2(92.69,54.92)
APU_TEST41: length 1.4
  TOP w0.102: T9.1 113.25,70.46 v2(112.82,70.9)
  BOTTOM w0.102: UC1.AK9 112.48,70.4 112.82,70.74 v2(112.82,70.9)
APU_TEST470: length 2
  TOP w0.102: T10.1 112.37,60.18 v2(112.69,60.5)
  BOTTOM w0.102: UC1.AK21 112.37,60.28 112.59,60.5 v2(112.69,60.5)
APU_TEST471: length 1.7
  TOP w0.102: v2(110.89,60.23) 110.4,59.75 T11.1
  BOTTOM w0.089: UC1.AG21 110.66,60 v2(110.89,60.23)
APU_TMS: length 56
  TOP w0.102: v2(120.06,77.11) 120.5,76.66 v1(120.5,76.28)
  IN3 w0.102: v2(153.1,55.94) 153.05,55.99 153.05,56.27 153.48,56.7 153.48,60.31 142.79,71.01 142.79,72.92 142.66,73.04 141.23,74.48 137.55,74.48 137.29,74.73 135.82,74.73 135.4,75.15 130.23,75.15 129.79,75.59 126.69,75.59 126.5,75.78 125.08,75.78 124.71,76.15 123.13,76.15 122.82,76.46 120.7,76.46 v2(120.06,77.11)
  BOTTOM w0.102: v2(120.06,77.11) 119.41,77.11 118.86,76.56 118.86,75.32 118.37,74.83 UC1.AU3 ; JHDT1.4 153.08,53.24 153.25,53.42 153.25,54.01 153.14,54.12 RHDT3.1 152.8,54.36 152.47,54.69 152.47,55.68 152.75,55.96 153.08,55.96 v2(153.1,55.94)
APU_TRST#: length 64.1
  TOP w0.102: v2(146.96,44.96) v1(147.67,44.96)
  IN1 w0.102: v2(148.68,45.9) 148.5,45.9 147.56,44.96 v2(146.96,44.96)
  IN3 w0.102: 124.22,73.32 122.7,73.32 121.42,74.61 119.15,74.61 118.09,75.67 v2(117.72,75.67)
  IN3 w0.117: 124.22,73.32 125.48,73.32 125.67,73.13 128.77,73.13 129.22,72.68 133.38,72.68 134.92,71.14 136.5,71.14 138.42,69.22 139.67,69.22 142.1,66.78 143.07,66.78 146.65,63.2 146.65,61.73 146.75,61.63 146.75,60.2 147.18,59.77 147.18,56.01 147.01,55.83 147.01,54.77 146.65,54.41 146.65,45.27 v2(146.96,44.96)
  BOTTOM w0.102: v2(146.96,44.96) 146.52,44.96 146.24,44.68 145.53,44.68 145.18,44.33 RHDT1.1 CHDT3.1 ; RHDT6.1 148.68,45.42 v2(148.68,45.9) ; UC1.AR4 116.88,74.42 117.39,74.94 117.49,74.94 117.72,75.16 v2(117.72,75.67)
APU_TRST#_R: length 2.1
  BOTTOM w0.102: RHDT6.2 149.32,46.13 149.27,46.18 JHDT1.9
APU_VDDP_S5_SEN_H: length 70.1
  TOP w0.102: T12.1 113.17,71.91 v2(112.87,71.61)
  TOP w0.127: PQ601.3 166.57,91.94 165.44,90.81 164.86,90.81 164,89.95 164,89.44 162.35,87.79 161.03,87.79 155.93,82.69 155.93,81.17 155.95,81.16 155.95,80.88 147.35,72.28 147.34,72.28 147.12,72.05 141.99,72.05 141.06,71.13 140.41,71.13 140.12,71.41 v2(140.12,71.62)
  IN1 w0.102: 124.22,72.59 124.17,72.59 123.93,72.83 121.81,72.83 121.58,72.6 120.94,72.6 120.43,73.1 119.28,73.1 118.98,72.8 117.67,72.8 117.47,72.6 117.47,72.19 117.14,71.86 116.73,71.86 116.37,72.22 116.37,72.65 116.25,72.78 115.59,72.78 115.31,72.5 115.31,71.51 115.03,71.23 114.6,71.23 114.57,71.2 113.27,71.2 v2(112.87,71.61)
  IN1 w0.127: 124.22,72.59 124.26,72.55 124.4,72.55 125.48,71.47 134.79,71.47 135.8,72.47 139.74,72.47 140.12,72.09 v2(140.12,71.62)
  BOTTOM w0.102: UC1.AK7 112.48,72 v2(112.87,71.61)
APU_VDDP_S5_SEN_L: length 39.6
  TOP w0.127: v2(140.76,71.62) 141.55,72.41 146.97,72.41 155.58,81.02 155.58,82.84 160.88,88.14 162.2,88.14 163.64,89.59 163.64,90.09 164.71,91.17 165.29,91.17 166.04,91.91 166.04,92.66
  BOTTOM w0.127: RC597.2 141.55,72.47 T2413.1 142,71.62 v2(140.76,71.62)
APU_VSS_SEN_L: length 106.8
  TOP w0.152: v2(89.88,94.98) 89.72,94.81 89.72,90.53 90.32,89.93 91.23,89.93 92.27,88.89 97.98,88.89 98.54,88.33 98.54,87.12 98.21,86.8 98.21,84.3 94.38,80.46 78.64,80.46 76.19,82.91 74.3,82.91 73.63,82.23 73.63,81.45 73.68,81.4 73.68,76.4 83.05,67.03 83.05,64.33 87.99,59.38 87.99,59.12 88.25,58.86 88.61,58.86 88.91,59.15 88.91,59.62
  TOP w0.178: RC594.2 89.1,59.43 T16.1
  IN1 w0.178: v2(100.43,93.7) 100.43,97.1 99.79,97.74 92.88,97.74 90.11,94.98 v2(89.88,94.98)
  BOTTOM w0.254: PC833.2 90.67,96.33 90.67,95.76 v2(89.88,94.98) ; PC801.1 106.65,96.12 106.65,95.64 PR801.2 106.9,95.41 107.41,94.9 107.41,94.13 107.18,93.91 104.64,93.91 103.02,92.29 102.66,92.29 101.25,93.7 v2(100.43,93.7) 100.22,93.7 99.97,93.95 PU801.14
APU_WL_OFF#: length 118.4
  TOP w0.102: v2(153.61,50.17) v3(151.93,50.17) 151.53,50.17 149.19,47.83 149.19,43.73 148.6,43.13 144.54,43.13 144.17,42.76 144.17,40.87 144.84,40.2 144.84,37.14 148.62,33.36 149.37,33.36 151.73,30.99 151.73,29 155.06,25.67 159.8,25.67 162.74,28.61 162.74,29.42 164.57,31.25 167.28,31.25 167.71,31.68 168.29,31.68 168.76,32.15 170.3,32.15 v2(170.36,32.09)
  IN2 w0.102: v2(118.38,74.03) 118.88,73.53 120.1,73.53 120.55,73.98 121.82,73.98 122.2,73.59 125.19,73.59 126.11,72.68 127.89,72.68 129.43,71.14 129.62,71.14 130.09,70.67 140.33,70.67 148.25,62.75 148.25,58.48 150.57,56.15 150.57,55.73 150.81,55.49 150.81,55.18 151.85,54.14 154.16,54.14 154.25,54.06 154.72,54.06 154.98,53.8 154.98,53.64 154.58,53.24 154.56,53.24 153.78,52.47 153.78,50.34 v2(153.61,50.17)
  IN3 w0.102: v2(118.38,74.03) 117.29,74.03 116.63,74.69 113.54,74.69 v2(112.43,75.8)
  BOTTOM w0.089: UC1.AL4 112.75,74.22 112.75,74.57 112.56,74.76 112.56,75.01 112.66,75.11 112.66,75.61 112.52,75.75 112.48,75.75 v2(112.43,75.8)
  BOTTOM w0.102: v2(170.36,32.09) 170.47,32.09 171.17,32.8 JWLAN1.48
AUX_RESET#: length 107.3
  TOP w0.102: v2(90.21,74.99) 90.06,75.14 90.06,75.49 89.73,75.82 RC601.2
  TOP w0.117: v2(69.21,61.73) USD2.1 69.21,60 69.79,59.42 v3(69.79,56.72) 69.79,55.02 68.7,53.93 66.25,53.93 64.21,51.9 56.37,51.9 54.79,50.32 v2(47.21,50.32)
  IN2 w0.102: v2(90.21,74.99) 88.84,74.99 88.75,74.89
  IN2 w0.127: v2(69.21,61.73) 69.21,61.86 72.67,65.32 77.44,65.32 86.49,74.38 88.23,74.38 88.75,74.89 ; v2(90.21,74.99) 90.44,74.99 90.86,75.41 90.86,75.84 90.99,75.96 93.69,75.96 94.84,77.11 106.07,77.11 106.96,76.22 107.48,76.22 108.18,75.52 109.55,75.52 111.74,73.34 115.76,73.34 116.8,72.3 v2(116.88,72.3)
  BOTTOM w0.102: v2(116.88,72.3) 116.57,72 UC1.AP7
  BOTTOM w0.117: v2(47.21,50.32) 47.49,50.04 47.49,46.49 47.37,46.37 39.48,46.37 38.8,47.05 38.8,47.94 38.42,48.32 38.37,48.32 38.34,48.34 36.24,48.34 36,48.1 USD1.1
BATGONE: length 8
  TOP w0.254: PRB23.2 50.22,5.61 50.22,5.25 50.01,5.03 49.24,5.03 PRB22.1 48.47,5.81 48.16,5.81 47.79,6.18 47.79,6.56 47.54,6.81 46.78,6.81 46,6.04 v2(45.42,6.04)
  BOTTOM w0.203: v2(45.42,6.04) 45.52,6.04 45.87,6.38 PUB1.18
BATT+:
  vias: v1(72.24,5.03) v2(70.18,5.03) v2(70.46,6.19) v2(70.44,5.56) v2(70.44,4.45) v2(70.78,5.03) v2(71.05,6.16) v2(71.02,5.56) v2(71.02,4.45) v2(71.36,5.03) v2(71.63,6.14) v2(71.61,5.56) v2(71.61,4.45) v2(72.22,4.45) v2(72.8,4.45) v2(73.38,4.45) v2(73.97,4.45)
BATT_CHG_LED#: length 214.5
  TOP w0.203: UEC1.90 190.3,41.23 190.03,40.96 v2(189.82,40.96)
  IN1 w0.203: v2(189.82,40.96) 190.64,41.78 190.64,42.73 189.93,43.44 189.37,43.44 188.4,44.42 182.99,44.42 182.72,44.15 182.72,44.14 181.87,43.29 180.76,43.29 180.38,43.67 180.38,43.99 177.99,46.38 177.99,47.05 176.55,48.49 176.55,50.04 170.96,55.63 170.96,55.66 169.54,57.08 169.54,58.02 167.28,60.28 167.28,60.92 166.08,62.11 166.08,62.77 158.39,70.46 156.25,70.46 153.89,72.83 152.8,72.83 150.2,75.42 148.55,75.42 144.22,79.75 143.88,79.75 143.04,79.75 141.51,81.28 140.85,81.28 137.88,84.24 131.19,84.24 130.26,83.32 123.7,83.32 123.42,83.6 117.9,83.6 117.51,83.2 108.31,83.2 105.38,80.27 105.08,80.27 74.27,80.27 72.57,81.97 52.75,81.97 50.61,84.1 45.62,84.1 43.76,85.97 43.76,88.13 40.66,91.23 28.59,91.23 27.16,89.79 22.38,89.79 16.87,95.31 14.09,95.31 13.5,94.72 v2(13.5,94.38)
  BOTTOM w0.203: v1(190.61,40.96) v2(189.82,40.96) ; v2(13.5,94.38) 12.98,94.9 RS3.1
BATT_CHG_LED#_R2: length 15.3
  TOP w0.203: LED2.1 5.21,100.09 v1(3.98,100.09) 3.68,99.8 v2(3.19,99.8)
  IN1 w0.203: v2(11.34,94.44) 10.61,95.18 10.61,97.18 10.39,97.4 10.39,97.83 8.65,99.57 7.34,99.57 7.22,99.46 4.95,99.46 4.61,99.8 v2(3.19,99.8)
  BOTTOM w0.203: RS3.2 11.8,94.9 v2(11.34,94.44)
BATT_LOW_LED#: length 211.2
  TOP w0.203: v2(189.97,42.44) 191.22,42.44 UEC1.93
  IN1 w0.203: v2(14.03,94.13) 14.03,94.6 14.3,94.87 16.68,94.87 22.19,89.36 27.3,89.36 28.76,90.82 40.49,90.82 43.35,87.97 43.35,85.8 45.45,83.7 50.44,83.7 52.58,81.56 72.4,81.56 74.11,79.85 105.53,79.85 108.48,82.8 117.67,82.8 118.07,83.19 123.25,83.19 123.53,82.91 130.43,82.91 131.36,83.84 137.71,83.84 140.68,80.87 141.34,80.87 142.87,79.34 144.05,79.34 148.38,75.01 150.02,75.01 152.61,72.42 153.71,72.42 156.07,70.06 158.21,70.06 165.68,62.59 165.68,61.94 166.87,60.75 166.87,60.1 169.13,57.84 169.13,56.89 176.14,49.87 176.14,48.33 177.59,46.88 177.59,46.21 179.98,43.82 179.98,43.49 180.71,42.75 184.61,42.75 184.81,42.95 186.3,42.95 186.87,42.39 187.89,42.39 188.43,42.93 189.47,42.93 v2(189.97,42.44)
  BOTTOM w0.203: v1(190.35,43.2) 190.35,42.82 v2(189.97,42.44) ; RS4.1 13.08,93.92 13.83,93.92 v2(14.03,94.13)
BATT_LOW_LED#_R2: length 13.2
  TOP w0.203: LED3.1 v2(4.04,98)
  IN1 w0.203: v2(4.04,98) 4.76,98.72 7.49,98.72 7.63,98.86 8.35,98.86 10.2,97.01 10.2,94.82 10.84,94.19 v2(10.84,94.13)
  BOTTOM w0.203: v2(10.84,94.13) 11,93.96 11.8,93.96 RS4.2
BEEP#: length 230.7
  TOP w0.117: v2(174.36,35.46) 174.36,35.21 174.74,34.83 UEC1.23
  IN2 w0.102: v2(149.29,58.98) 149.08,59.19 149.08,63.06 141.16,70.98 141.16,71.79 140.91,72.04 137.61,72.04 137.09,71.52 134.08,71.52 133.39,72.22 129.57,72.22 128.3,73.49 126.45,73.49 125.53,74.41 124.1,74.41 123.9,74.2 122.28,74.2 122.07,74.41 117.61,74.41 116.75,73.55 111.83,73.55 109.64,75.74 108.27,75.74 107.57,76.43 107.05,76.43 106.12,77.36 94.78,77.36 93.74,76.32 87.37,76.32 76.99,65.93 v2(66.53,65.93)
  IN3 w0.102: v2(174.36,35.46) 174.21,35.31 173.14,35.31 172.51,35.98 171.97,35.98 171.59,36.36 169.7,36.36 169.08,36.98 165.89,36.98 163.72,39.15 163.72,39.82 164.13,40.22 164.13,40.9 163.95,41.08 163.95,52.73 163.68,52.99 163.68,54.85 161.18,57.35 161.18,58.15 160.83,58.5 156.56,58.5 154.83,56.77 154.83,53.47 153.88,52.52 150.59,52.52 150.33,52.78 150.33,54.68 149.55,55.47 149.55,58.73 v2(149.29,58.98)
  IN3 w0.127: v2(17.47,45.17) 18.95,46.65 18.95,61.16 20.11,62.32 23.17,62.32 23.7,62.85 26.41,62.85 29.3,65.74 34.13,65.74 41.82,73.44 52.49,73.44 53.2,74.15 56.33,74.15 60.27,70.21 62.14,70.21 62.74,69.61 62.74,68.73 64.63,66.83 64.63,66.07 64.77,65.93 v2(66.53,65.93)
  BOTTOM w0.127: RA27.1 16.88,44.47 17.47,45.06 v2(17.47,45.17)
BGATE: length 36.4
  TOP w0.117: v2(71.53,10.08) 71.53,8.91 v3(71.57,8.86)
  IN3 w0.508: v2(71.53,10.08) 71.53,9.79 72.71,8.61 72.71,7.32 72.2,6.81 70.29,6.81 70.29,6.8 70.21,6.8 69.7,6.29 69.7,5.99 69.19,5.48 69.19,4.22 68.59,3.62 61.95,3.62 61.4,4.18 55.49,4.18 54.11,5.57 51.32,5.57 51.02,5.87 50.3,5.87 50,5.57 46.8,5.57 45.43,6.94 v2(45.43,7.52)
BKOFF#: length 159.2
  TOP w0.117: v2(187.42,42.88) 187.11,42.88 186.4,43.6 UEC1.105 ; v3(59.98,76.61) 59.98,76.01 59.61,75.65 v2(59.53,75.65) 59.53,76.18 59.28,76.42 R5.1 57.77,76.42 57.65,76.3 U2.1
  IN2 w0.127: v2(59.53,75.65) 60.06,76.18 61.09,76.18 61.37,76.46 74.06,76.46 80.88,83.28 101.78,83.28 102.59,84.09 137.92,84.09 141.1,80.9 145.55,80.9 149.66,76.79 149.66,76.41 149.91,76.17 152.31,76.17 154.52,73.97 156.41,73.97 159.71,70.67 159.71,70.06 163.63,66.13 164.47,66.13 165.04,65.56 165.04,64.6 172.41,57.23 172.41,56.85 174.06,55.2 174.06,53.96 176.02,52 177.32,52 179.9,49.42 179.9,48.68 181.23,47.35 183.43,47.35 183.99,46.79 183.99,45.4 184.83,44.56 184.83,43.9 185.84,42.88 v2(187.42,42.88)
BST1_CHG:
  vias: v3(48.98,10.57)
BST1_CHG_R: length 1.2
  BOTTOM w0.117: PRB4.1 48.54,12.41 v3(48.11,12.85)
BST1_CPU:
  vias: v3(97.55,101.57)
BST1_CPU_R: length 1.1
  BOTTOM w0.117: PR839.2 v3(96.81,105.49)
BST1_NB:
  vias: v1(94.73,101.81)
BST1_NB1_R: length 1
  BOTTOM w0.117: PR804.2 v3(94.12,105.45)
BST2_CHG:
  vias: v3(46.15,10.69)
BST2_CHG_R: length 1.1
  BOTTOM w0.117: PCB19.2 43.77,10.89 v3(43.43,10.55)
BST2_CPU:
  vias: v1(102.29,101.69)
BST2_CPU_R: length 1.1
  BOTTOM w0.117: PC824.1 v3(100.94,105.56)
BST3_CPU: length 1.9
  TOP w0.117: v2(144.83,102.61) v3(144.83,101.65)
  BOTTOM w0.254: v2(144.83,102.61) 144.97,102.75 145.12,102.75 PR860.1
BST3_CPU_R: length 1.4
  BOTTOM w0.117: PC846.1 v3(144.17,106.12)
BST_1.8V: length 2.7
  BOTTOM w0.117: v1(166.16,82.7) 166.28,82.7 167.55,81.43 167.55,80.82 PR713.1
BST_1.8V_R: length 2.9
  BOTTOM w0.117: 166.77,81.33 165.92,82.19 v1(164.25,82.19)
BST_3V_R: length 2.5
  TOP w0.117: PC301.1 179.46,64.34 180.02,63.77 v3(180.02,63.02)
BST_5V_R: length 1.2
  BOTTOM w0.117: PR501.2 v3(36.3,17.66)
BST_DDR: length 1.6
  BOTTOM w0.117: PRM11.2 157.33,55.6 v1(157.96,56.24)
BST_DDR_R: length 1.6
  BOTTOM w0.117: PCM14.1 v1(157.56,50.97)
CAM_EN#: length 204.9
  TOP w0.117: v2(189.21,33.67) 189.46,33.67 189.5,33.63 UEC1.71 ; R201.1 R4007.2 62.26,64.86 v2(62.68,64.45) ; v2(150.28,26.8) 149.79,26.31 v1(149.77,26.31)
  IN1 w0.102: v2(90.47,75.57) 90.87,75.16 92.12,75.16 92.15,75.14 92.19,75.14 92.8,74.53 94.4,74.53 94.81,74.12 95.32,74.12 95.98,73.46 98.44,73.46 101.01,70.9 101.01,70.33 102.77,68.56 103.28,68.56 103.69,68.15 104.76,68.15 105.25,67.67 107.03,67.67 107.05,67.7 108.19,67.7 108.44,67.95 113.88,67.95 114.34,68.41 114.34,69.44 115.38,70.48 115.38,70.99 115.54,71.15 116.37,71.15 116.55,71.33 117.14,71.33 117.52,70.95 117.52,70.41 117.77,70.16 118.61,70.16 119.32,70.87 119.32,71.79 119.45,71.91 121.12,71.91 122.24,70.8 122.24,70.39 123.36,69.27 125.24,69.27 125.57,68.94 125.72,68.94 126.09,68.57 139.34,68.57 141.88,66.03 145.72,66.03 148.01,63.75 148.01,60.42 147.29,59.7 147.29,46.79 144.87,44.37 144.87,43.37 145.98,42.27 145.98,35.45 150.89,30.54 150.89,27.59 150.28,26.98 v2(150.28,26.8)
  IN2 w0.102: 90.4,75.57 v2(90.47,75.57)
  IN2 w0.127: 90.4,75.57 89.07,75.57 88.31,74.81 86.57,74.81 77.36,65.6 71.76,65.6 69.54,63.38 63.75,63.38 v2(62.68,64.45)
  IN3 w0.127: v2(189.21,33.67) 189.14,33.74 188.63,33.74 184.09,29.2 184.09,23.7 181.73,21.34 179.95,21.34 177.07,24.22 174.61,24.22 174.17,23.78 170.09,23.78 167.68,21.37 162.96,21.37 161.66,20.07 156.1,20.07 153.33,22.84 149.88,22.84 149.19,23.53 149.19,25.94 149.32,26.07 149.32,26.24 149.88,26.8 v2(150.28,26.8)
CAM_EN#_R: length 3.5
  TOP w0.117: Q201.2 60.14,63.95 C204.1 60.52,63.99 60.56,63.95 R201.2 v3(60.94,62.91)
CAPS_LED#: length 26.3
  TOP w0.203: UEC1.91 190.23,41.63 190.08,41.48 189.02,41.48 v2(188.79,41.25) ; v1(182.01,20.48) R265.2 182.03,21.65 182.16,21.65 182.58,22.06 182.58,22.87 182.85,23.14 v2(182.85,23.47)
  IN3 w0.203: v2(182.85,23.47) 183.05,23.68 183.05,28.73 186.91,32.59 186.91,36.3 188.13,37.52 188.13,40.59 v2(188.79,41.25)
CAPS_LED#_R: length 0.6
  TOP w0.203: v2(182.1,23.2) v1(182.1,23.82)
  vias: v2(181.51,23.2)
CHR_USB20_N1: length 3
  TOP w0.089: RUS10.1 191.28,19.33 191.28,19.51 190.85,19.94 190.85,19.98 190.85,19.99 v4(190.85,20.21) 190.85,20.61 190.54,20.91 190.54,21.04 190.73,21.22 U7.11
CHR_USB20_N1_R: length 27.1
  TOP w0.089: RUS10.2 191.28,17.81 v4(191.28,16.91) 191.28,16.49 192.26,15.51 200.19,15.51 201.47,16.79 201.47,26.32 202.28,27.12 202.93,27.12 203.14,26.92 203.14,26.74 v2(203.35,26.53)
  BOTTOM w0.089: JIO1.2 203.14,27.83 203.14,26.74 v2(203.35,26.53)
CHR_USB20_P1: length 3
  TOP w0.089: RUS9.1 191.1,19.33 191.1,19.44 190.66,19.88 190.66,20.54 190.36,20.84 190.36,20.97 190.23,21.1 U7.10
CHR_USB20_P1_R: length 27
  TOP w0.089: RUS9.2 191.1,17.76 191.1,17.24 191.06,17.21 191.06,16.61 191.1,16.57 191.1,16.42 192.18,15.33 200.27,15.33 201.65,16.72 201.65,26.24 202.35,26.94 202.86,26.94 202.95,26.85 202.95,26.74 v2(202.74,26.53)
  BOTTOM w0.089: v2(202.74,26.53) 202.95,26.74 202.95,27.67 202.86,27.77 JIO1.3
CLK_PCIE_SD: length 157
  IN3 w0.127: v2(195.1,17.9) 194.96,18.04 194.96,18.35 195.2,18.59 199.06,18.59 199.47,18.99 199.47,24.56 198.92,25.1 198.92,26.84 197.94,27.82 197.94,28.82 196.05,30.72 196.05,33.05 193.62,35.49 193.62,38.99 196.76,42.14 196.76,47.45 189.91,54.31 186.49,54.31 185.6,53.42 181.91,53.42 180.46,54.87 178.07,54.87 177.51,55.43 174.48,55.43 173.12,56.78 172.12,56.78 162.17,66.73 161.07,66.73 158.91,68.89 157.63,68.89 155.97,70.55 155.97,71.66 150.22,77.41 148.71,77.41 144.76,81.36 143.11,81.36 142.66,81.81 141.14,81.81 138.41,84.54 120.97,84.54 119.45,83.01 110.08,83.01 109.72,82.65 109.72,82.19 v2(109.54,82.01)
  BOTTOM w0.089: 109.55,79.49 109.55,78.48 109.64,78.39
  BOTTOM w0.102: 109.64,78.39 109.64,77.19 108.88,76.42 UC1.AF2
  BOTTOM w0.117: v2(195.1,17.9) 194.89,18.12 194.89,18.41 194.19,19.1 191.84,19.1 190.9,20.04 190.83,20.14 190.69,20.38 190.74,20.57 JIO1.31 ; 109.55,79.49 109.55,79.62 109.93,79.99 109.93,81.62 v2(109.54,82.01)
CLK_PCIE_SD#: length 157
  IN3 w0.127: v2(110.15,82.01) 109.95,82.21 109.95,82.56 110.18,82.79 119.54,82.79 121.07,84.31 138.31,84.31 141.04,81.58 142.57,81.58 143.02,81.13 144.67,81.13 148.61,77.19 150.13,77.19 155.74,71.57 155.74,70.46 157.53,68.66 158.81,68.66 160.97,66.5 162.08,66.5 172.02,56.56 173.03,56.56 174.38,55.2 177.42,55.2 177.98,54.64 180.36,54.64 181.81,53.2 185.69,53.2 186.58,54.08 189.82,54.08 196.54,47.36 196.54,42.23 193.39,39.08 193.39,35.4 195.82,32.96 195.82,30.62 197.72,28.73 197.72,27.73 198.7,26.75 198.7,25.01 199.24,24.47 199.24,19.08 198.97,18.81 195.11,18.81 194.73,18.44 194.73,18.13 v2(194.49,17.9)
  BOTTOM w0.102: 109.78,79.43 109.78,78.52 109.83,78.47 109.83,77.11 109.08,76.35 109.08,75.13 109.2,75.01 109.2,74.76 108.88,74.43 UC1.AF4
  BOTTOM w0.117: v2(110.15,82.01) 110.15,79.9 109.78,79.53 109.78,79.43 ; v2(194.49,17.9) 194.66,18.07 194.66,18.31 194.1,18.88 191.75,18.88 190.73,19.9 190.64,20.02 190.49,20.28 190.45,20.34 190.26,20.39 JIO1.32
CLK_PCIE_SSD1: length 138.2
  IN1 w0.102: v2(19.31,34.36) 19.49,34.54 20.42,34.54 22.41,36.52 22.41,40.86 20.15,43.11 20.15,49.53 24.43,53.8 34.04,53.8 41.84,61.6 41.84,66.5 53.84,78.5 60.48,78.5 60.98,78.01 105.23,78.01 106.13,77.11 109.53,77.11 110.62,78.2 110.62,78.77 v2(110.84,78.99)
  BOTTOM w0.102: UC1.AH2 110.88,74.73 110.93,74.67 111.09,74.67 111.19,74.77 111.19,75.01 110.98,75.23 110.98,77.74 110.63,78.08 110.63,78.78 v2(110.84,78.99)
  BOTTOM w0.117: JSSD1.55 22.44,29.91 22.31,30.05 21.96,30.05 21.1,30.91 v4(21.1,32.82) 21.1,34.08 20.59,34.59 19.54,34.59 v2(19.31,34.36)
CLK_PCIE_SSD1#: length 138.2
  IN1 w0.102: v2(19.28,34.94) 19.5,34.73 20.35,34.73 22.22,36.6 22.22,40.78 19.96,43.03 19.96,49.61 24.35,53.99 33.96,53.99 41.65,61.68 41.65,66.58 53.76,78.69 60.56,78.69 61.06,78.2 105.31,78.2 106.21,77.3 109.43,77.3 110.43,78.29 110.43,78.78 v2(110.23,78.99)
  BOTTOM w0.102: v2(110.23,78.99) 110.43,78.78 110.43,78 110.77,77.66 110.77,75.23 110.57,75.03 110.57,74.77 110.67,74.68 110.67,74.31 UC1.AH4
  BOTTOM w0.117: JSSD1.53 22.44,30.41 22.31,30.28 22.06,30.28 21.33,31.01 21.33,32.36 21.34,32.38 21.34,33.25 21.33,33.26 21.33,34.17 20.68,34.82 19.41,34.82 v2(19.28,34.94)
CLK_PCIE_SSD2: length 105.3
  IN1 w0.102: v2(111.27,78.5) 111.43,78.34 111.43,78.2 110.4,77.17 110.4,76.56 110.11,76.26 109.79,76.26 109.38,76.66 105.12,76.66 105.11,76.65 104.83,76.65 104.37,77.11 96.43,77.11 96.05,77.49 87,77.49 86.14,76.62 64.65,76.62 56.86,68.84 54.78,68.84 54.43,69.19 54.43,69.34 v2(54.64,69.55)
  BOTTOM w0.089: 111.6,74.73 111.66,74.67 111.66,74.42 111.7,74.38 111.83,74.38 111.9,74.45 111.9,74.88 UC1.AJ2
  BOTTOM w0.102: v2(111.27,78.5) 111.34,78.5 111.66,78.19 111.66,77.74 111.79,77.61 111.79,76.79 111.81,76.76 111.81,75.3 111.5,74.99 111.5,74.83 111.6,74.73
  BOTTOM w0.117: v2(54.64,69.55) 54.44,69.36 54.44,68.84 54.7,68.59 54.7,67.21 53.8,66.31 53.8,65.44 54.18,65.05 54.26,65.05 54.36,64.95 55.35,64.95 55.83,65.43 62.68,65.43 64.86,63.25 67.67,63.25 68.67,62.25 68.67,60.84 70.35,59.16 70.37,59.16 71.16,58.37 71.16,54.54 69.02,52.4 69.02,49.82 69.16,49.68 JSSD2.55
CLK_PCIE_SSD2#: length 105.3
  IN1 w0.102: v2(54.03,69.55) 54.24,69.34 54.24,69.11 54.7,68.65 56.94,68.65 64.73,76.43 86.21,76.43 87.08,77.3 95.97,77.3 96.36,76.92 104.29,76.92 104.75,76.46 109.3,76.46 109.71,76.05 110.19,76.05 110.61,76.47 110.61,77.09 111.63,78.11 111.63,78.26 v2(111.88,78.5)
  BOTTOM w0.102: v2(111.88,78.5) 111.85,78.48 111.85,77.82 111.99,77.68 111.99,76.85 112,76.84 112,75.25 112.17,75.09 112.17,74.74 112.08,74.66 112.08,74.31 UC1.AJ4
  BOTTOM w0.117: JSSD2.53 68.66,49.68 68.79,49.82 68.79,52.49 70.94,54.63 70.94,58.26 68.45,60.75 68.45,62.15 67.57,63.03 64.77,63.03 62.59,65.21 55.92,65.21 55.44,64.72 54.27,64.72 54.16,64.83 54.09,64.83 53.58,65.34 53.58,66.41 54.47,67.3 54.47,68.49 54.22,68.75 54.22,69.36 v2(54.03,69.55)
CLK_PCIE_WLAN: length 99.6
  IN3 w0.102: v2(109.87,71.6) 110.13,71.34 110.64,71.34 110.69,71.29 111.03,71.29 111.27,71.53 111.27,75 110.77,75.5 110.77,75.73 110.76,75.74 110.76,75.84
  IN3 w0.127: 110.76,75.84 110.76,76.38 111.27,76.89 112.72,76.89 113.04,77.21 114.41,77.21 115.15,77.95 118.98,77.95 119.45,78.41 123.01,78.41 123.16,78.26 124.3,78.26 124.72,77.84 125.41,77.84 125.78,77.47 130.3,77.47 130.93,76.84 134.17,76.84 134.47,77.15 141.6,77.15 148.54,70.2 149.04,70.2 150.87,68.37 152.1,68.37 155.57,64.9 157.73,64.9 165.8,56.83 165.8,55.96 167.03,54.73 167.03,52.72 166.31,52 166.31,46.7 166.05,46.44 166.05,42.05 167.46,40.65 167.87,40.65 v2(168.03,40.81)
  BOTTOM w0.102: v2(109.87,71.6) 109.48,71.2 UC1.AF8
  BOTTOM w0.117: JWLAN1.39 164.99,35.05 165.42,34.61 165.56,34.61 167.23,36.28 167.23,40.37 167.5,40.64 167.86,40.64 v2(168.03,40.81)
CLK_PCIE_WLAN#: length 99.6
  IN3 w0.102: 110.99,75.84 110.99,75.82 110.98,75.81 110.98,75.58 111.47,75.09 111.47,71.45 111.11,71.09 110.61,71.09 110.56,71.14 110.09,71.14 109.87,70.93 v2(109.87,70.8)
  IN3 w0.127: v2(168.03,40.21) 167.83,40.42 167.36,40.42 165.83,41.95 165.83,46.54 166.08,46.79 166.08,52.09 166.81,52.82 166.81,54.64 165.58,55.87 165.58,56.74 157.64,64.68 155.47,64.68 152.01,68.14 150.78,68.14 148.94,69.98 148.44,69.98 141.5,76.92 134.56,76.92 134.26,76.61 130.84,76.61 130.2,77.24 125.68,77.24 125.31,77.61 124.63,77.61 124.21,78.03 123.06,78.03 122.91,78.19 119.54,78.19 119.07,77.72 115.25,77.72 114.51,76.98 113.14,76.98 112.82,76.66 111.37,76.66 110.99,76.28 110.99,75.84
  BOTTOM w0.102: UC1.AF9 109.48,70.4 v2(109.87,70.8)
  BOTTOM w0.117: JWLAN1.41 165.17,34.55 165.19,34.53 165.19,34.53 165.33,34.39 165.65,34.39 167.45,36.19 167.45,40.28 167.59,40.42 167.83,40.42 v2(168.03,40.21)
CLKREQ_SD#: length 122.4
  TOP w0.102: RC91.1 189.32,16.07 189.14,15.89 187.35,15.89 v2(186.76,16.49)
  IN2 w0.102: v2(118.18,66.5) 118.67,66.01 120.03,66.01 120.34,65.7 121.95,65.7 122.38,65.27 123.8,65.27 124.1,65.56 126.17,65.56 127.41,64.32 130.8,64.32 131.44,63.68 132.04,63.68 132.59,63.14 136,63.14 136.87,62.26 136.87,60.43 145.84,51.47 145.84,47.17 146.47,46.54 146.47,44.86 146.7,44.63 v2(146.7,44.4)
  IN3 w0.102: v2(146.7,44.4) 146.7,44.12 146.07,43.49 146.07,27.03 146.42,26.68 147.82,26.68 148.56,25.94 148.56,23.29 149.01,22.83 149.01,21.73 148.85,21.57 148.85,21.2 151.6,18.45 162.35,18.45 163.62,19.72 168.34,19.72 170.31,21.68 177.32,21.68 180.09,18.92 183.77,18.92 186.2,16.49 v2(186.76,16.49)
  BOTTOM w0.102: v2(118.18,66.5) 117.77,66.1 UC1.AT14 ; JIO1.33 189.96,20.03 190,19.97 190.61,19.36 190.61,17.93 188.76,16.08 187.16,16.08 v2(186.76,16.49)
CLKREQ_SSD1#: length 113
  IN1 w0.102: v2(82.13,66.2) 82.49,65.84 86.55,65.84 87.37,65.03 89.81,65.03 90.39,64.45 91.2,64.45 91.79,65.03 93.97,65.03 94.2,65.26 94.2,65.79 94.33,65.92 95.27,65.92 95.75,66.4 96.49,66.4 98.26,68.18 99.27,68.18 99.45,68.36 103.19,68.36 103.6,67.95 104.68,67.95 105.16,67.47 105.91,67.47 106.59,66.78 107.56,66.78 108.53,67.75 114.85,67.75 115.38,68.28 115.38,68.76 v2(115.82,69.2)
  IN2 w0.102: v2(35.12,41.23) 37.28,43.39 39.87,43.39 45.63,49.16 45.63,50.24 49.09,53.69 52.46,53.69 55.63,56.85 56.18,56.85 57.9,58.57 64.76,58.57 66.19,57.14 66.6,57.14 66.62,57.16 70.84,57.16 73.18,59.49 73.43,59.49 74.04,60.1 74.51,60.1 75.86,61.45 78.92,61.45 81.3,63.83 81.3,64.9 82.08,65.69 82.08,66.15 v2(82.13,66.2)
  BOTTOM w0.102: v2(115.82,69.2) 115.42,68.8 UC1.AN11 ; RC89.1 82.95,67.01 v2(82.13,66.2) ; v2(35.12,41.23) 34.84,40.95 34.84,37.83 32.88,35.87 32.88,31.7 31.84,30.66 JSSD1.52
CLKREQ_SSD2#: length 61
  TOP w0.117: v2(81.02,66.12) v1(81.02,66.68)
  IN1 w0.102: v2(81.02,66.12) 81.22,66.12 82.11,65.23 86.25,65.23 87.06,64.42 89.7,64.42 90.08,64.04 94.07,64.04 94.97,64.94 95.58,64.94 95.77,65.13 95.77,65.74 96.05,66.02 96.39,66.02 98.35,67.98 99.35,67.98 99.53,68.16 103.11,68.16 103.52,67.75 104.59,67.75 105.19,67.15 105.19,66.24 105.42,66.02 107.33,66.02 107.61,66.02 108.4,66.81 111.73,66.81 111.75,66.83 113.83,66.83 114.18,67.18 115.57,67.18 v2(115.76,67.37)
  IN2 w0.127: v2(68.62,57.64) 69.29,58.31 69.29,58.59 73.45,62.74 77.59,62.74 80.97,66.12 v2(81.02,66.12)
  BOTTOM w0.102: v2(115.76,67.37) 115.72,67.37 115.37,67.02 UC1.AN13
  BOTTOM w0.117: JSSD2.52 68.41,57.42 v2(68.62,57.64) ; RC574.1 82.72,67.82 v2(81.02,66.12)
CLKREQ_WLAN#: length 91.4
  TOP w0.102: v2(167.45,34.55) 167.19,34.28 RWL2.1
  IN2 w0.102: v2(167.45,34.55) 166.07,33.17 166.07,32.01 164.17,30.12 162.54,30.12 159.58,27.16 155.31,27.16 149.31,33.16 148.94,33.52 147.37,33.52 146.03,34.86 146.03,34.9 145.79,35.14 145.79,42.46 144.82,43.42 144.82,46.16 143.04,47.94 143.04,52.09 142.47,52.66 140.76,52.66 140.06,53.36 140.06,54.5 139.71,54.85 138.57,54.85 137.75,55.67 137.75,57.22 135.25,59.72 v2(135.25,62.04)
  IN2 w0.127: v2(115.67,65.5) 115.67,64.18 116.12,63.73 120.72,63.73 120.96,63.98 122.74,63.98 123.08,64.32 125.21,64.32 127.17,62.36 128.83,62.36 129.94,61.26 134.46,61.26 v2(135.25,62.04)
  BOTTOM w0.102: v2(115.67,65.5) 115.37,65.2 UC1.AN15 ; v3(132.27,61.4) 133.34,60.33 RC90.1 134.97,60.33 135.25,60.61 v2(135.25,62.04)
CLKREQ_WLAN#_R: length 2.6
  TOP w0.102: v3(165.01,33.42) v2(165.65,33.42) RWL2.2
  BOTTOM w0.102: v2(165.65,33.42) 165.52,33.55 JWLAN1.45
CLKRUN#: length 116.1
  TOP w0.117: v2(152.81,53.71) 151.44,52.34 150.06,52.34 149.65,52.34 146.19,48.88 146.17,48.88 145.66,48.37 145.66,45.8 143.17,43.31 143.17,40.47 143.86,39.79 143.86,36.68 148.34,32.19 149,32.19 150.74,30.45 150.74,28.09 151.99,26.84 151.99,26.05 152.11,25.93 152.89,25.93 154.15,24.68 169.29,24.68 171.76,27.15 174.5,27.15 175.2,27.85 175.2,28.53 175.77,29.1 175.77,29.61 177.1,30.94 177.22,30.94 177.86,31.58 178.86,31.58 179.2,31.24 UEC1.38
  IN1 w0.102: v2(152.81,53.71) 152.67,53.85 152.67,57.43 152.75,57.51 v2(152.75,58.03)
  BOTTOM w0.089: UC1.BD13 122.7,66.97 123.87,66.97 124.04,67.14 124.22,67.14
  BOTTOM w0.117: v2(152.75,58.03) 153.45,58.03 154.85,59.44 154.85,61.78 151.25,65.38 149.57,65.38 148.92,66.04 145.7,66.04 142.12,69.61 135.06,69.61 134.77,69.9 v3(131.55,69.9) 130.06,69.9 129.67,69.51 128.97,69.51 128.2,68.74 127.07,68.74 125.47,67.14 124.22,67.14
CMPIN_25710: length 4.2
  BOTTOM w0.203: PUB1.14 47.77,3.74 PCB12.1 PRB7.1 47.17,1.67 PRB5.2
COMP_CPU: length 4.2
  TOP w0.254: v2(102.4,93.25) PC808.2
  BOTTOM w0.117: v1(102.84,92.72) 102.4,93.16 v2(102.4,93.25)
  BOTTOM w0.254: v2(102.4,93.25) 102.43,93.27 PR806.2 PC808.2 101.7,94.59 PU801.13
COMPA_CPU: length 6
  BOTTOM w0.117: v1(90.29,93.36) PR831.1
  BOTTOM w0.254: PU801.30 93.52,95.79 92.76,95.04 92.76,93.92 PC829.1 91.32,93.29 PR831.1
CS_DDR: length 3.9
  BOTTOM w0.117: v1(159.5,51.21) PRM5.2
  BOTTOM w0.203: PRM5.2 161.13,51.21 161.33,51.41 PUM1.13
DDR_A_ACT#: length 138
  TOP w0.107: v2(109.79,18.06) 109.52,18.06 109.02,17.56 UD2.L3 ; v2(132.64,21) 132.37,21 131.86,20.49 UD4.L3 ; v2(98.48,18.06) 98.21,18.06 97.7,17.56 UD1.L3 ; v2(121.31,20.98) 121.04,20.98 120.53,20.48 UD3.L3
  TOP w0.188: RD23.2 88.83,22.34 v2(89.25,21.93)
  IN1 w0.102: v2(89.25,21.93) 89.68,21.49 90.69,21.49 91.79,20.4 92.97,20.4 93.64,19.73 93.64,18.58 94.2,18.01 95.39,18.01 95.56,17.85 97.92,17.85 98.14,18.06 v2(98.48,18.06) 98.93,17.61 100.22,17.61 100.32,17.71 100.32,18.15 100.42,18.25 100.63,18.25 100.73,18.15 100.73,16.99 100.83,16.89 101.06,16.89 101.16,16.99 101.16,17.17 101.26,17.27 101.41,17.27 101.51,17.17 101.51,16.99 101.61,16.89 101.79,16.89 101.9,16.99 101.9,17.15 102,17.25 108.45,17.25 109.1,17.9 109.63,17.9 v2(109.79,18.06) 110.22,17.63 111.34,17.63 111.45,17.73 111.45,18.29 111.55,18.39 111.78,18.39 111.88,18.29 111.88,17.96 111.98,17.86 112.18,17.86 112.28,17.96 112.28,18.29 112.39,18.39 112.84,18.39 113.43,18.98 114.95,18.98 116.63,20.66 118.69,20.66 118.79,20.55 119.52,20.55 120.01,21.04 121.25,21.04 v2(121.31,20.98) 121.69,20.6 122.71,20.6 123.09,20.97 123.34,20.97 123.44,20.87 123.44,20.68 123.54,20.58 123.75,20.58 123.85,20.68 123.85,20.87 123.95,20.97 125.02,20.97 125.45,20.54 128.2,20.54 128.3,20.64 128.3,21.16 128.41,21.27 128.61,21.27 128.71,21.16 128.71,20.64 128.81,20.54 129.7,20.54 130.15,21 130.49,21 130.59,21.1 130.59,21.27 130.69,21.37 130.9,21.37 131,21.27 131,21.1 131.1,21 v2(132.64,21)
  IN1 w0.16: v2(132.64,21) 133.18,20.45 139.64,20.45 139.87,20.68 142.15,20.68 143.02,21.54 144.73,21.54 145.16,21.11 145.66,21.11 146.09,21.54 146.09,24.11 140.23,29.98 132.11,29.98 131.95,30.14 131.95,30.68 131.77,30.87 131.47,30.87 131.31,30.71 131.31,30.14 131.15,29.98 130.22,29.98 129.94,30.26 129.94,30.94 v2(130.45,31.45)
  IN2 w0.102: v2(107.83,58.75) 108.18,58.4 108.98,58.4 109.26,58.12 109.26,57.64 110.28,56.62 110.28,54.72 110.76,54.24 110.76,53.58 111.17,53.17 111.47,53.17 114.88,49.76 115.41,49.76 116.96,48.21
  IN2 w0.198: v2(130.45,31.45) 129.88,31.45 129.69,31.65 129.69,32.62 118.07,44.24 118.07,45.13 117.61,45.58 117.61,47.56 116.96,48.21
  BOTTOM w0.102: UC1.AD22 v2(107.83,58.75)
DDR_A_ALERT#: length 147.4
  TOP w0.107: UD4.P9 136.05,17.44 136.01,17.32 135.99,16.57 135.98,16.45 135.91,16.28 135.82,16.17 v2(133.88,13.86) ; v2(111.23,10.94) 111.23,11.17 111.29,11.23 111.36,11.31 113.06,13.34 113.13,13.52 113.15,13.64 113.17,14.39 113.21,14.51 UD2.P9 ; v2(122.55,13.85) 124.49,16.16 124.58,16.26 124.65,16.44 124.67,16.56 124.69,17.31 124.72,17.43 UD3.P9 ; v2(99.82,10.97) 101.66,13.16 101.71,13.25 101.82,13.52 101.83,13.64 101.85,14.39 101.89,14.51 UD1.P9
  TOP w0.117: v2(88.94,12.81) 88.87,12.73 RD1.2
  IN1 w0.102: v2(88.94,12.81) 89.48,12.27 90.26,12.27 90.49,12.04 93,12.04 93.81,11.23 97.88,11.23 98.06,11.41 99.38,11.41 v2(99.82,10.97) 99.82,11.34 100.22,11.74 101.57,11.74 101.67,11.64 101.67,11.21 101.78,11.11 101.98,11.11 102.08,11.21 102.08,11.64 102.18,11.74 102.4,11.74 102.48,11.66 102.48,11.18 102.55,11.11 102.76,11.11 102.86,11.2 102.86,11.59 103.01,11.74 106.54,11.74 106.75,11.54 109.31,11.54 109.39,11.46 110.71,11.46 v2(111.23,10.94) 111.61,11.32 111.61,11.5 113.78,13.67 116.82,13.67 116.93,13.57 116.93,13.34 117.03,13.24 117.23,13.24 117.33,13.34 117.33,13.57 117.43,13.67 117.64,13.67 117.74,13.57 117.74,13.34 117.84,13.24 118.04,13.24 118.15,13.34 118.15,13.57 118.25,13.67 119.68,13.67 120.34,14.33 122.07,14.33 v2(122.55,13.85) 123.03,14.33 125.96,14.33 126.06,14.43 126.06,14.71 126.16,14.81 126.36,14.81 126.47,14.71 126.47,14.43 126.57,14.33 126.77,14.33 126.87,14.43 126.87,14.71 126.97,14.81 127.18,14.81 127.28,14.71 127.28,14.43 127.38,14.33 127.58,14.33 127.68,14.43 127.68,14.71 127.79,14.81 127.99,14.81 128.09,14.71 128.09,14.43 128.19,14.33 128.4,14.33 128.5,14.43 128.5,14.56 128.6,14.66 128.8,14.66 128.9,14.56 128.9,14.43 129.01,14.33 133.41,14.33 v2(133.88,13.86)
  IN2 w0.089: 131.29,17.29 134.21,17.29 135.14,16.36 135.14,15.13 v2(133.88,13.86)
  IN2 w0.102: v2(107.86,57.16) 107.43,56.72 107.43,53.85 107.94,53.35 107.94,53.29
  IN2 w0.127: 107.94,53.29 107.94,52.76 108.12,52.58 108.12,50.68 108.56,50.24 111.6,50.24 113.62,48.21 113.62,46.45 114.6,45.47 114.6,44.07 115.08,43.58 115.08,42.62 119.75,37.95 119.75,29.82 120.26,29.32 120.26,15.09 121.05,14.31 122.72,14.31 122.77,14.25 124.02,14.25 125.01,15.25 125.01,16.29 125.14,16.41 125.85,16.41 128.27,18.83 129.76,18.83 131.29,17.29
  BOTTOM w0.102: v2(107.86,57.16) 108.31,57.6 UC1.AE24
DDR_A_BA0: length 142.3
  TOP w0.107: v2(132.64,17.95) 132.12,18.46 131.22,18.46 UD4.N2 ; v2(121.31,17.94) 120.79,18.45 119.89,18.45 UD3.N2 ; v2(109.79,15.02) 109.28,15.53 108.38,15.53 UD2.N2 ; UD1.N2 97.06,15.53 97.96,15.53 v2(98.48,15.02)
  TOP w0.188: RD24.2 88.83,18.31 v2(88.92,18.39)
  IN1 w0.091: v2(109.79,15.02) 110.17,14.64 111.49,14.64
  IN1 w0.102: v2(88.92,18.39) 89.48,18.39 90.67,17.2 90.67,16.9 91.98,15.59 93.7,15.59 94.99,14.31 96.64,14.31 97.35,15.02 v2(98.48,15.02) 98.88,14.62 99.86,14.62 99.95,14.71 107.53,14.71 107.63,14.81 107.63,15.22 107.73,15.32 107.93,15.32 108.04,15.22 108.04,14.81 108.14,14.71 108.34,14.71 108.44,14.81 108.44,15.22 108.54,15.32 108.75,15.32 108.85,15.22 108.85,14.81 108.95,14.71 109.16,14.71 109.26,14.81 109.26,15.19 109.36,15.3 109.69,15.3 109.79,15.19 v2(109.79,15.02) ; 111.49,14.64 112.25,15.4 114.26,15.4 116.32,17.46 118.85,17.46 118.95,17.35 118.95,16.79 119.05,16.69 119.25,16.69 119.35,16.79 119.35,17.35 119.46,17.46 120.83,17.46 v2(121.31,17.94) 121.69,17.55 125.12,17.55 125.26,17.4 126.6,17.4 127.14,17.95 129.97,17.95 130.07,18.05 130.07,18.47 130.18,18.57 130.38,18.57 130.48,18.47 130.48,18.05 130.58,17.95 130.79,17.95 130.89,18.05 130.89,18.42 130.99,18.52 131.19,18.52 131.29,18.42 131.29,18.05 131.4,17.95 131.57,17.95 131.66,18.04 131.66,18.32 131.77,18.42 131.94,18.42 132.05,18.32 132.05,18.08 132.17,17.95 v2(132.64,17.95) 133.03,17.56 133.98,17.56 134.79,18.37
  IN1 w0.16: 134.79,18.37 134.95,18.53 138.16,18.53 138.32,18.37 138.32,18.02 138.48,17.86 138.8,17.86 138.96,18.02 138.96,18.37 139.12,18.53 139.44,18.53 139.6,18.37 139.6,18.02 139.76,17.86 140.08,17.86 140.24,18.02 140.24,18.37 140.4,18.53 140.72,18.53 140.88,18.37 140.88,18.02 141.04,17.86 141.36,17.86 141.52,18.02 141.52,18.37 141.68,18.53 142.72,18.53 143.93,19.74 v2(144.34,19.74)
  IN2 w0.102: 129.12,54.59 129.12,54.67 128.88,54.91 128.26,54.91 128.16,55.01 128.16,55.43 127.47,56.11 126.94,56.11 125.72,57.33 122.09,57.33 121.89,57.54 121.25,57.54 120.83,57.12 117.64,57.12 117.15,57.61 115.61,57.61 115.42,57.8 115.42,57.99 115.1,58.31 114.16,58.31 v2(112.87,59.6)
  IN2 w0.198: 129.12,54.59 131.3,52.42 133.02,52.42 135.58,49.87 135.58,44.43 140.17,39.83 140.17,34.65 144.15,30.68 144.15,27.25 144.24,27.15 144.24,23.28 143.72,22.75 143.72,20.27 144.25,19.74 v2(144.34,19.74)
  BOTTOM w0.102: UC1.AL22 112.97,59.6 v2(112.87,59.6)
DDR_A_BA1: length 140.8
  TOP w0.107: v2(99.03,16.03) 99.48,15.58 100.92,15.58 101.29,15.96 UD1.N8 ; UD4.N8 135.45,18.89 135.08,18.52 133.64,18.52 v2(133.19,18.96) ; v2(121.87,18.95) 122.32,18.5 123.75,18.5 124.12,18.88 UD3.N8 ; UD2.N8 112.61,15.96 112.23,15.58 110.8,15.58 v2(110.35,16.03)
  TOP w0.188: v2(92.75,17.94) 92.75,17.77 92.21,17.23 RD25.2
  IN2 w0.102: 124.53,51.91 124.53,52.38 123.94,52.96 123.94,53.47 123.49,53.93 122.04,53.93 121.58,53.47 119.12,53.47 118.84,53.19 116.07,53.19 114.98,54.29 114.42,54.29 114.34,54.36 113.52,54.36 113.25,54.63 113.25,55.46 113.11,55.6 v2(112.87,55.6)
  IN2 w0.198: v2(140.63,19.59) 140.63,15.62 140.41,15.4 139.23,15.4 139.03,15.6 139.03,15.88 139.23,16.07 139.77,16.07 139.97,16.27 139.97,19.84 140.17,20.03 140.48,20.03 140.68,20.24 140.68,20.46 140.48,20.66 140.02,20.66 139.82,20.85 139.82,23.14 140.22,23.55 140.22,29.59 136.77,33.04 136.49,33.04 136.04,32.59 135.76,32.59 135.56,32.78 135.56,33.06 135.99,33.49 135.99,33.8 135.72,34.08 135.41,34.08 134.92,33.59 134.64,33.59 134.45,33.79 134.45,34.36 135.22,35.13 135.22,36.88 124.91,47.19 124.91,48.06 124.53,48.44 124.53,51.91
  IN3 w0.102: v2(99.03,16.03) 99.03,16.29 98.91,16.41 96.71,16.41 96.43,16.13 95.72,16.13 95.47,16.39 94.3,16.39 v2(92.75,17.94)
  IN3 w0.127: v2(133.19,18.96) 132.8,18.57 132.49,18.57 131.99,19.07 129.04,19.07 128.31,18.34 124.97,18.34 124.84,18.22 124.84,17.76 124.72,17.63 124.46,17.63 124.34,17.76 124.34,18.22 124.21,18.34 123.96,18.34 123.83,18.22 123.83,17.76 123.7,17.63 123.45,17.63 123.32,17.76 123.32,18.22 123.19,18.34 122.47,18.34 v2(121.87,18.95) 121.46,18.55 120.89,18.55 120.49,18.14 118.91,18.14 117.24,16.46 116.08,16.46 115.95,16.59 115.95,16.97 115.8,17.12 115.57,17.12 115.45,17 115.45,16.59 115.32,16.46 114.88,16.46 113.88,15.47 110.91,15.47 v2(110.35,16.03) 109.97,15.65 109.95,15.65 109.95,15.65 109.63,15.65 109.63,15.65 109.31,15.65 109.01,15.96 102.11,15.96 101.98,15.83 101.98,15.36 101.86,15.23 101.6,15.23 101.48,15.36 101.48,15.83 101.35,15.96 101.1,15.96 100.97,15.83 100.97,15.36 100.84,15.23 100.59,15.23 100.46,15.36 100.46,15.83 100.33,15.96 100.12,15.96 99.72,15.56 99.51,15.56 v2(99.03,16.03)
  IN3 w0.16: v2(133.19,18.96) 133.19,18.9 133.52,18.57 135.32,18.57 135.58,18.83 137.3,18.83 138.06,19.59 v2(140.63,19.59)
  BOTTOM w0.102: UC1.AK27 112.67,55.6 v2(112.87,55.6)
DDR_A_BG0: length 135.6
  TOP w0.107: UD1.M2 97.01,17.13 98.39,17.13 v2(98.48,17.05) ; UD4.M2 131.17,20.07 132.55,20.07 v2(132.64,19.98) ; v2(121.31,19.97) 121.22,20.05 119.84,20.05 UD3.M2 ; UD2.M2 108.33,17.13 109.71,17.13 v2(109.79,17.05)
  TOP w0.188: RD26.2 v2(92.02,18.05)
  IN1 w0.102: v2(132.64,19.98) 132.31,19.65 125.16,19.65 125.06,19.55 125.06,19.16 124.98,19.08 124.73,19.08 124.65,19.16 124.65,19.46 124.59,19.52 124.4,19.52 124.3,19.42 124.3,19.07 124.2,18.97 123.99,18.97 123.89,19.07 123.89,19.42 123.79,19.52 123.59,19.52 123.49,19.42 123.49,19.07 123.38,18.97 123.18,18.97 123.08,19.07 123.08,19.42 122.98,19.52 121.75,19.52 v2(121.31,19.97) 120.83,19.49 116.86,19.49 113.78,16.41 112.34,16.41 112.23,16.52 112.23,16.87 112.13,16.97 111.93,16.97 111.83,16.87 111.83,16.52 111.73,16.41 110.43,16.41 v2(109.79,17.05) 109.54,16.79 107.86,16.79 107.76,16.69 107.76,16.31 107.66,16.21 107.46,16.21 107.36,16.31 107.36,16.69 107.26,16.79 107.05,16.79 106.95,16.69 106.95,16.31 106.85,16.21 106.65,16.21 106.54,16.31 106.54,16.69 106.44,16.79 106.24,16.79 106.14,16.69 106.14,16.31 106.04,16.21 100.02,16.21 99.82,16.41 99,16.41 98.48,16.94 v2(98.48,17.05) 98.03,17.05 97.35,16.36 94.71,16.36 94.02,17.05 93.69,17.05 93.39,17.35 92.55,17.35 92.02,17.89 v2(92.02,18.05)
  IN2 w0.102: 109.26,53.27 109.26,55.33 v2(108.88,55.71)
  IN2 w0.198: 109.26,53.27 111.06,51.47 112,51.47 115.26,48.21 115.26,47.78 116.1,46.94 116.1,44.58 116.51,44.17 116.51,43.28 121.23,38.56 121.23,38.03 121.42,37.84 122.32,37.84 122.52,37.64 122.52,37.24 122.32,37.04 121.42,37.04 121.23,36.84 121.23,36.45 121.42,36.25 123.16,36.25 123.36,36.05 123.36,35.7 123.16,35.5 121.42,35.5 121.23,35.3 121.23,34.86 121.54,34.55 123.14,34.55 123.33,34.35 123.33,34.07 123.14,33.87 121.42,33.87 121.23,33.67 121.23,33.39 121.42,33.2 123.16,33.2 123.36,33 123.36,32.6 123.16,32.4 121.42,32.4 121.23,32.21 121.23,31.85 121.42,31.65 123.04,31.65 123.24,31.46 123.24,31.18 122.98,30.92 121.91,30.92 121.68,30.68 121.68,30.4 121.88,30.21 126.23,30.21 126.64,29.8 126.64,26.35 127.25,25.74 127.25,22.38 127.07,22.2 126.6,22.2 126.43,22.04 126.43,21.76 126.57,21.62 128.14,21.62 128.34,21.42 128.34,21.16 128.18,21.01 125.14,21.01 124.93,20.81 124.93,20.52 125.13,20.33 127.66,20.33 127.79,20.45 128.73,20.45 128.85,20.33 129.68,20.33 130.01,20.66 130.55,20.66 131.22,19.98 v2(132.64,19.98)
  BOTTOM w0.102: v2(108.88,55.71) 108.78,55.71 UC1.AE27
DDR_A_BG1: length 3.4
  TOP w0.102: RD30.2 106.02,55.83 106.34,56.15 107.34,56.15 v2(107.86,55.63)
  BOTTOM w0.102: v2(107.86,55.63) 108.01,55.63 UC1.AE26
DDR_A_BG1_R: length 145.2
  TOP w0.102: RD30.1 RD31.2 104.28,55.42 104.56,55.14 106,55.14 107.08,54.06 107.08,53.57 v2(109.31,51.34)
  TOP w0.107: UD1.M9 101.85,16.37 100.23,16.37 100,16.6 99.46,16.6 v2(99.05,17.01) ; UD4.M9 136.01,19.3 134.39,19.3 134.16,19.53 133.65,19.53 v2(133.19,19.98) ; UD2.M9 113.17,16.37 111.54,16.37 111.32,16.6 110.8,16.6 v2(110.35,17.05) ; UD3.M9 124.68,19.29 123.06,19.29 122.84,19.52 122.32,19.52 v2(121.87,19.97)
  TOP w0.188: RD27.2 v2(91.3,19.59)
  IN1 w0.102: v2(133.19,19.98) 132.61,20.57 130.15,20.57 129.73,20.15 125.34,20.15 124.8,20.68 124.35,20.68 124.17,20.5 124.17,19.87 124.1,19.79 123.82,19.79 123.74,19.87 123.74,20.27 123.66,20.35 123.44,20.35 123.34,20.25 123.34,19.85 123.24,19.75 123.04,19.75 122.94,19.85 122.94,20.25 122.83,20.35 122.26,20.35 121.88,19.97 v2(121.87,19.97) 121.35,20.48 121.12,20.48 120.49,19.84 118.54,19.84 118.44,19.94 118.44,20.25 118.34,20.35 118.14,20.35 118.03,20.25 118.03,19.94 117.93,19.84 116.26,19.84 114.41,17.99 113.91,17.99 113.14,17.23 111.66,17.23 111.07,16.64 110.76,16.64 v2(110.35,17.05) 109.87,17.53 109.31,17.53 108.8,17.02 105.73,17.02 105.63,16.92 105.63,16.77 105.53,16.67 105.32,16.67 105.22,16.77 105.22,16.92 105.12,17.02 104.89,17.02 104.79,16.92 104.79,16.74 104.69,16.64 104.49,16.64 104.38,16.74 104.38,16.92 104.28,17.02 104.08,17.02 103.98,16.92 103.98,16.74 103.88,16.64 103.67,16.64 103.57,16.74 103.57,16.92 103.47,17.02 103.27,17.02 103.17,16.92 103.17,16.74 103.06,16.64 102.86,16.64 102.76,16.74 102.76,16.92 102.66,17.02 102.45,17.02 102.35,16.92 102.35,16.74 102.25,16.64 99.42,16.64 v2(99.05,17.01) 99.05,17.05 98.64,17.46 95.55,17.46 95.32,17.23 94.43,17.23 93.18,18.47 92.42,18.47 v2(91.3,19.59)
  IN2 w0.198: v2(133.19,19.98) 133.19,19.82 132.9,19.53 130.05,19.53 129.63,19.94 126.25,19.94 126.08,19.77 126.08,18.82 125.76,18.5 125.76,17.51 125.56,17.31 125.28,17.31 125.14,17.46 125.14,19.17 124.94,19.37 124.66,19.37 124.48,19.19 124.48,17.55 124.28,17.35 123.71,17.35 123.51,17.55 123.51,22.51 123.76,22.76 124.68,22.76 125.34,23.42 126.64,23.42 126.83,23.62 126.83,24.02 126.69,24.16 126,24.16 125.8,24.36 125.8,24.72 125.97,24.9 126.56,24.9 126.74,25.08 126.74,25.28 126.54,25.48 125.4,25.48 125.24,25.64 125.24,25.88 125.4,26.04 125.97,26.04 126.2,26.27 126.2,29.42 126.01,29.62 125.23,29.62 125.04,29.42 125.04,28.07 124.86,27.89 123.84,27.89 123.71,28.02 123.71,29.44 123.54,29.62 121.68,29.62 120.72,30.58 120.72,38.35 116.05,43.02 116.05,43.98 115.6,44.44 115.6,46.63 114.59,47.64 114.59,48.37 111.85,51.11 109.54,51.11 v2(109.31,51.34)
DDR_A_CAS#: length 143.2
  TOP w0.107: v2(110.38,18.06) 110.84,17.6 111.14,17.6 111.54,17.2 112.31,17.2 UD2.M8 ; UD1.M8 101,17.2 100.22,17.2 99.82,17.6 99.56,17.6 v2(99.09,18.07) ; v2(121.9,20.98) 122.35,20.52 122.65,20.52 123.06,20.12 123.83,20.12 UD3.M8 ; UD4.M8 135.16,20.13 134.39,20.13 133.98,20.53 133.68,20.53 v2(133.22,20.99)
  TOP w0.188: RD18.2 v2(92.02,21.02)
  IN2 w0.102: v2(113.83,55.01) 114.41,55.01 114.67,54.74 115.13,54.74 116.25,53.62 118.56,53.62 118.89,53.95 121.28,53.95 121.73,54.41 124.4,54.41 124.65,54.16 124.65,53.32 124.96,53.02 125.39,53.02 126.23,52.18 126.23,48.83
  IN2 w0.198: 126.23,48.83 126.23,47.29 130.43,43.09 130.71,43.09 131.31,43.7 131.69,43.7 131.97,43.42 131.97,43.14 131.32,42.49 131.32,42.21 131.6,41.93 131.88,41.93 132.53,42.57 132.81,42.57 133.09,42.29 133.09,42.01 132.44,41.36 132.44,41.08 136.52,37.01 136.52,34.72 141.31,29.92 141.31,23.11 141.29,23.09 141.29,15.82 141.44,15.67 141.73,15.67 141.88,15.81 v2(141.88,19.61)
  IN3 w0.102: v2(99.09,18.07) 98.63,17.61 98.23,17.61 97.63,17 96.22,17 95.18,18.04 94.75,18.04 93.61,19.18 93.61,19.51 92.79,20.33 92.6,20.33 92.02,20.91 v2(92.02,21.02)
  IN3 w0.127: v2(133.22,20.99) 132.83,21.39 130.39,21.39 129.54,20.54 129.11,20.54 128.22,21.43 127.59,21.43 127.46,21.3 127.46,20.67 127.33,20.54 126.86,20.54 126.74,20.67 126.74,21.24 126.61,21.37 126.31,21.37 126.18,21.24 126.18,20.67 126.05,20.54 122.34,20.54 v2(121.9,20.98) 121.49,20.58 120.96,20.58 119.87,19.49 117.74,19.49 117.61,19.36 117.61,19.33 117.48,19.21 117.23,19.21 117.1,19.33 117.1,19.36 116.97,19.49 116.72,19.49 116.59,19.36 116.59,19.11 116.47,18.98 116.21,18.98 116.08,19.11 116.08,19.36 115.96,19.49 115.7,19.49 115.58,19.36 115.58,19.11 115.45,18.98 112.74,18.98 111.35,17.59 110.85,17.59 v2(110.38,18.06) 109.98,17.66 109.28,17.66 109.18,17.56 105.67,17.56 105.54,17.68 105.54,17.89 105.42,18.01 105.16,18.01 105.03,17.89 105.03,17.71 104.91,17.58 104.11,17.58 103.98,17.71 103.98,17.86 103.85,17.99 103.62,17.99 103.5,17.86 103.5,17.46 103.34,17.3 100.92,17.3 100.79,17.43 100.79,17.95 100.66,18.08 100.41,18.08 100.28,17.95 100.28,17.43 100.16,17.3 99.94,17.3 99.79,17.46 99.7,17.46 v2(99.09,18.07)
  IN3 w0.16: v2(141.88,19.61) 142.49,19.61 142.75,19.88 142.75,20.07 142.58,20.24 137.78,20.24 137.24,19.7 135.21,19.7 134.41,20.5 133.67,20.5 133.22,20.95 v2(133.22,20.99)
  BOTTOM w0.102: UC1.AL27 113.54,55.3 v2(113.83,55.01)
DDR_A_CKE0: length 137.5
  TOP w0.107: v2(109.64,20.05) 109.64,19.56 108.85,18.77 108.36,18.77 UD2.K2 ; UD3.K2 119.88,21.69 120.37,21.69 121.15,22.48 v2(121.15,22.97) ; UD4.K2 131.21,21.7 131.7,21.7 132.48,22.49 v2(132.48,22.99) ; UD1.K2 96.95,18.67 97.44,18.67 97.9,19.13 v2(97.9,19.58)
  TOP w0.188: RD22.2 92.04,21.85 92.73,22.54 v2(92.73,22.67)
  IN1 w0.091: v2(97.9,19.58) 98.03,19.72 99.86,19.72
  IN1 w0.102: v2(92.73,22.67) 92.74,22.66 94.33,22.66 94.71,22.28 95.24,22.28 95.66,21.86 95.66,21.71 96.61,20.76 96.61,20.12 96.79,19.94 97.22,19.94 97.59,19.58 v2(97.9,19.58) ; 99.86,19.72 105.74,19.72 105.85,19.61 105.85,19.41 105.95,19.31 106.15,19.31 106.25,19.41 106.25,19.61 106.35,19.72 106.56,19.72 106.66,19.61 106.66,19.08 106.76,18.98 106.96,18.98 107.06,19.08 107.06,19.61 107.17,19.72 107.4,19.72 107.91,19.21 108.01,19.11 108.69,19.11 v2(109.64,20.05) 109.64,20.19 110.02,20.58 111.31,20.58 111.41,20.48 111.41,20.22 111.51,20.12 111.72,20.12 111.82,20.22 111.82,20.48 111.92,20.58 114.27,20.58 116.53,22.84 116.86,22.84 117.14,23.12 117.67,23.12 117.95,22.84 118.58,22.84 119.35,22.08 120.26,22.08 v2(121.15,22.97) 121.52,22.61 122.57,22.61 122.77,22.81 124.77,22.81 125.01,23.04 126.74,23.04 126.84,22.94 126.84,22.48 126.95,22.38 127.12,22.38 127.25,22.51 127.25,22.94 127.35,23.04 127.55,23.04 127.66,22.94 127.66,22.48 127.76,22.38 127.94,22.38 128.06,22.51 128.06,22.94 128.16,23.04 129,23.04 129.57,22.47 131.97,22.47 v2(132.48,22.99)
  IN1 w0.16: v2(130.7,33.03) 141.46,33.03 141.69,32.79 141.69,32.46 141.48,32.25 128.76,32.25 128.28,31.78 128.28,28.71 132.07,24.92 132.07,23.4 v2(132.48,22.99)
  IN2 w0.102: v2(106.94,58.03) 107.28,58.37 107.28,58.76 107.79,59.26 109.01,59.26 109.24,59.03 109.24,58.45 109.46,58.22 109.46,57.79 110.48,56.77 110.48,55.53 110.68,55.33 111.07,55.33 111.29,55.1 111.29,54.01 112,53.29 112.12,53.29
  IN2 w0.198: 112.12,53.29 112.64,53.29 112.98,52.95 113.46,52.95 114.29,52.12 114.29,51.49 115.21,50.58 115.97,50.58 117.21,49.33 117.59,49.33 118.61,48.31 118.61,46.03 119.35,45.3 119.35,44.94 121.87,42.42 121.9,42.42 127.03,37.29 127.03,36.69 v2(130.7,33.03)
  BOTTOM w0.102: v2(106.94,58.03) UC1.AD24
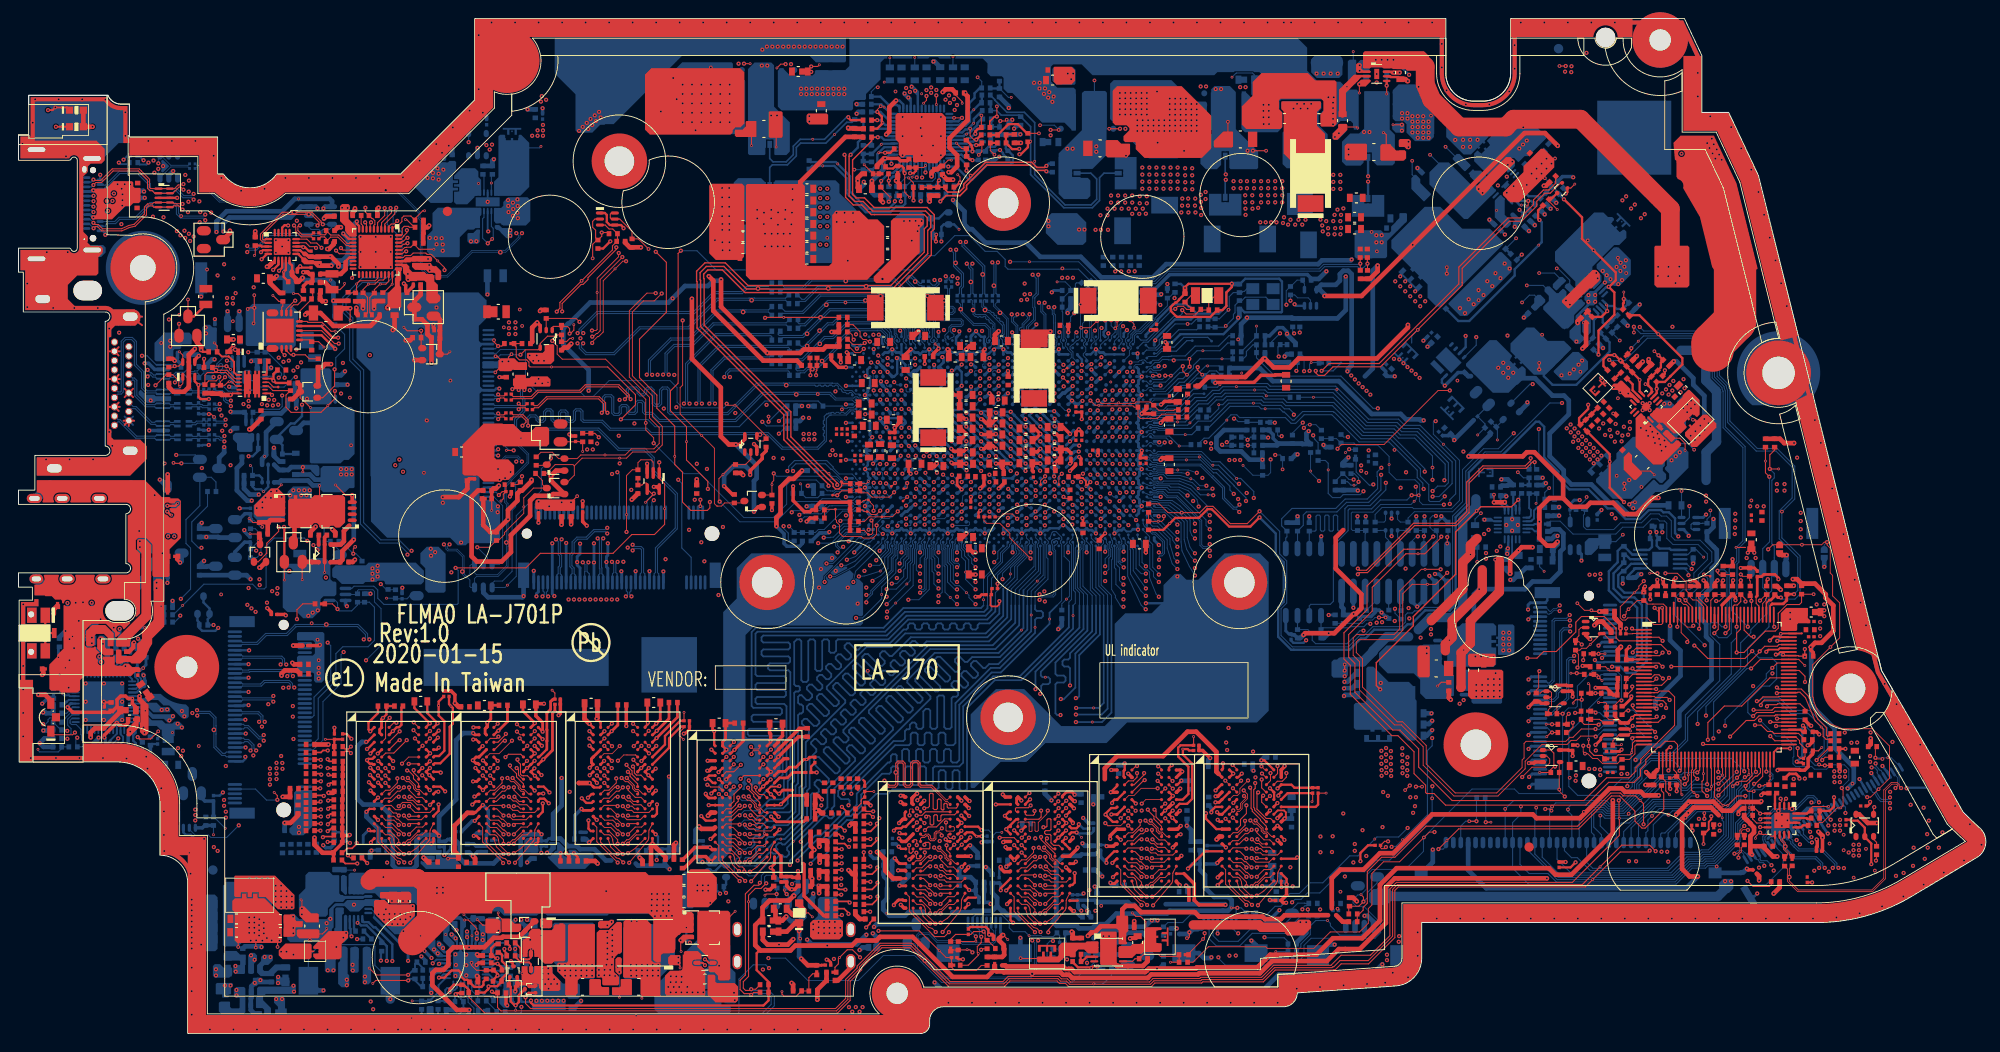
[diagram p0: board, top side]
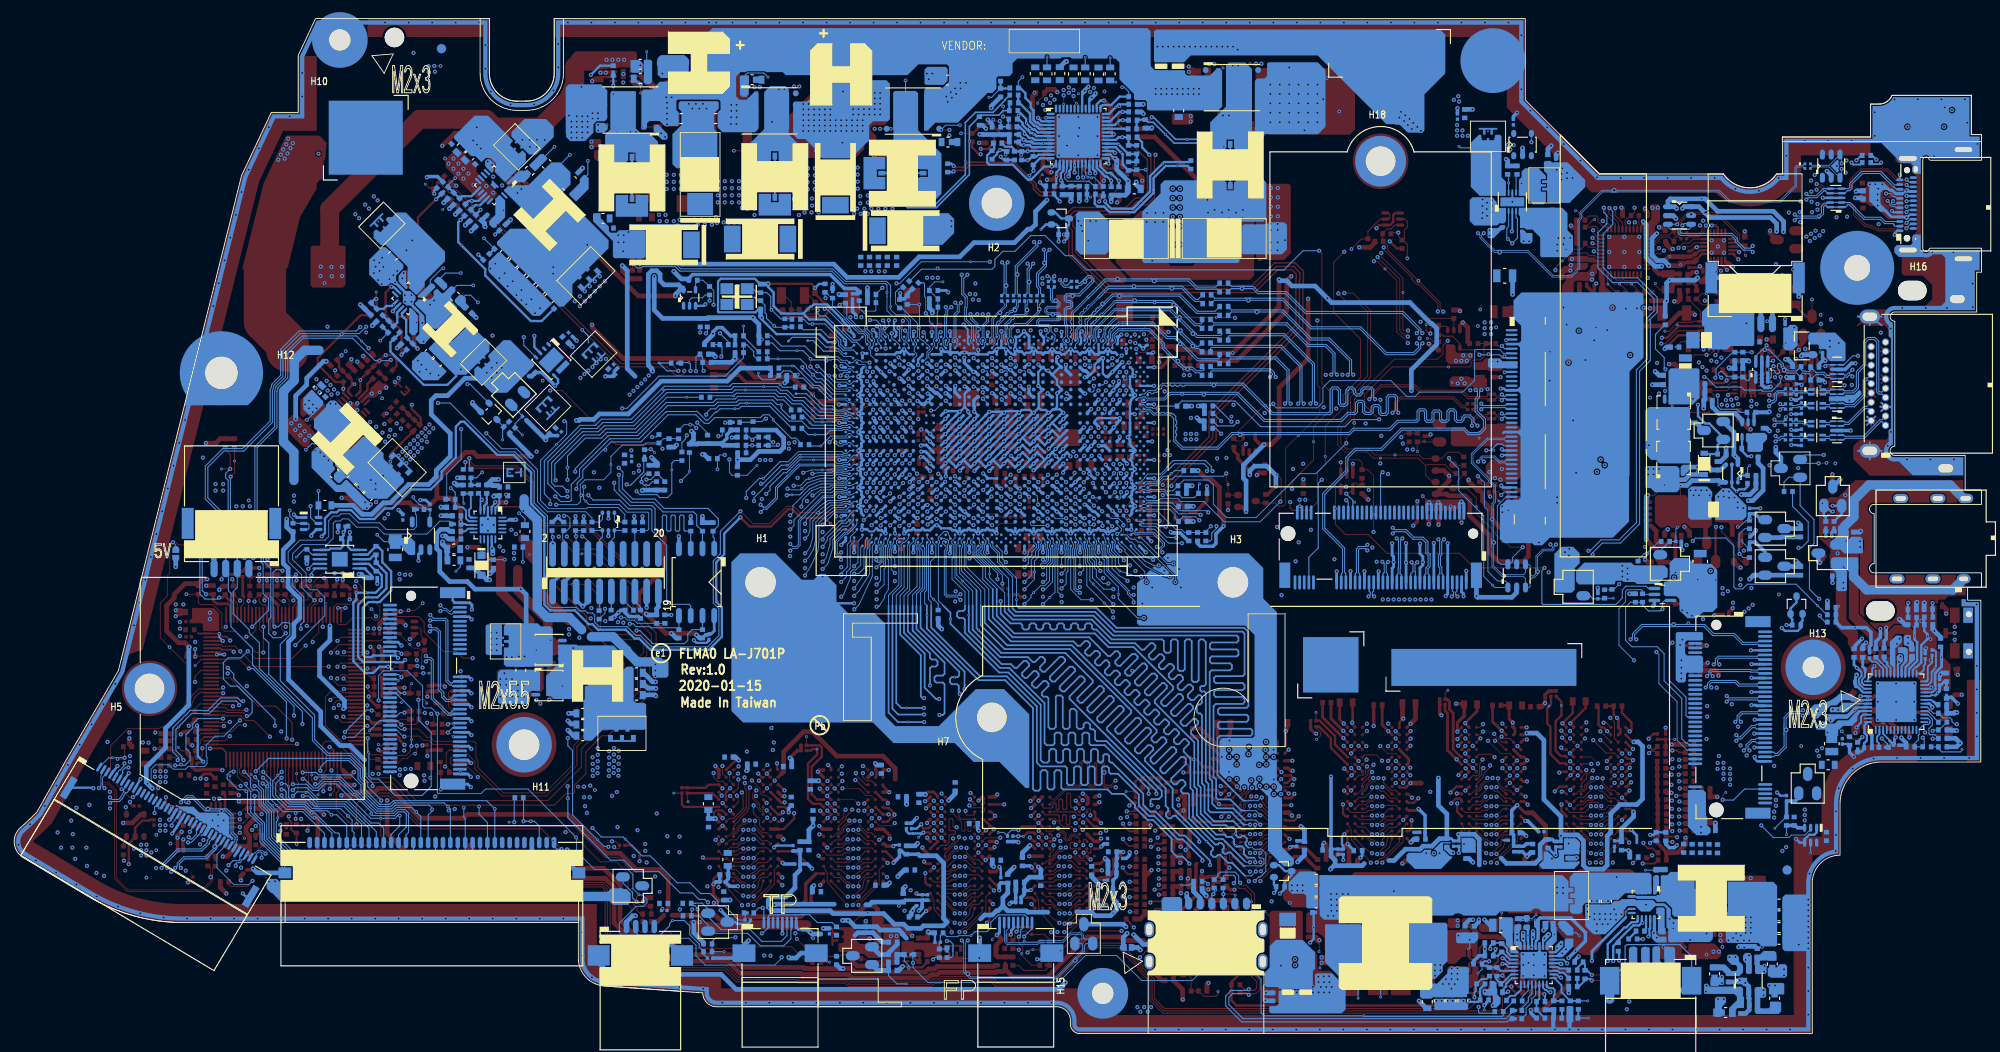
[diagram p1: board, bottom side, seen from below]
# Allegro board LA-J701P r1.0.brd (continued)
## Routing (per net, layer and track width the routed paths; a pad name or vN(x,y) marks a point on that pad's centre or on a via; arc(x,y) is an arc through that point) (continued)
DDR_A_CLK0: length 143
  TOP w0.102: v2(98.9,20.1) 99.31,19.69 99.59,19.69 100.07,19.21 100.07,18.95 100.37,18.65 100.62,18.65 100.72,18.55 100.72,18.44 UD1.K7 ; UD2.K7 112.04,18.44 112.04,18.55 111.94,18.65 111.68,18.65 111.39,18.95 111.39,19.21 110.91,19.69 110.62,19.69 v2(110.22,20.1) ; UD4.K7 134.88,21.38 134.88,21.49 134.78,21.59 134.53,21.59 134.23,21.88 134.23,22.15 133.75,22.63 133.47,22.63 v2(133.06,23.03) ; v2(121.73,23.02) 122.14,22.61 122.43,22.61 122.91,22.13 122.91,21.87 123.2,21.57 123.45,21.57 123.55,21.47 123.55,21.36 UD3.K7
  TOP w0.147: RD28.2 91.55,23.73 91.96,23.73 v2(92.29,23.4)
  IN1 w0.122: v2(92.29,23.4) 92.6,23.7 94.71,23.7 96.31,22.11 96.31,21.86 96.92,21.24 98.22,21.24 99.07,20.39 99.07,20.26 v2(98.9,20.1)
  IN2 w0.102: v2(110.89,56.33) 110.76,56.46 110.76,56.62 110.91,56.77 111.17,56.77 111.27,56.68 111.27,56 111.55,55.72 111.55,54.18 112.08,53.65 112.66,53.65 113.11,53.2 113.69,53.2 113.86,53.03 113.86,52.99 113.88,52.97
  IN2 w0.165: v2(133.06,23.03) 133.06,23.09 133.37,23.4 133.37,24.95 133.68,25.26 134.35,25.26 134.66,24.95 134.66,22.41 135.45,21.62 135.45,20.33 135.63,20.15 136.99,20.15 137.3,20.47 137.3,21.25 137.14,21.42 136.77,21.42 136.45,21.73 136.45,22.21 136.8,22.56 137.11,22.56 137.28,22.72 137.28,23.45 136.69,24.03 136.69,24.88 137.61,25.79 137.61,26.09 137.44,26.26 136.8,26.26 136.49,26.57 136.49,27.02 136.8,27.33 137.4,27.33 137.66,27.59 137.66,28.68 136.31,30.03 134.16,30.03 133.85,30.34 133.85,30.86 130.49,34.22 130.49,35.25 130.83,35.59 130.83,35.96 130.66,36.12 130.43,36.12 129.75,35.44 129.3,35.44 128.92,35.83 128.92,36.27 129.62,36.97 129.62,37.2 129.38,37.44 129.15,37.44 128.55,36.83 128.11,36.83 127.72,37.22 127.72,37.66 128.32,38.26 128.32,38.5 128.09,38.73 127.86,38.73 127.43,38.31 126.99,38.31 126.61,38.69 126.61,39.13 127.03,39.56 127.03,39.79 126.79,40.02 126.56,40.02 126.14,39.6 125.69,39.6 125.31,39.98 125.31,40.43 125.74,40.85 125.74,41.08 125.5,41.32 125.27,41.32 124.84,40.9 124.4,40.9 124.02,41.28 124.02,41.72 124.44,42.15 124.44,42.38 124.21,42.61 123.97,42.61 123.55,42.19 123.11,42.19 122.72,42.57 122.72,43.02 123.15,43.44 123.15,43.67 122.91,43.91 122.68,43.91 122.26,43.48 121.81,43.48 120.06,45.24 120.06,49.38 119.75,49.69 118.83,49.69 118.71,49.81 118.69,49.81 117.57,50.93 115.36,50.93 114.66,51.63 114.66,52.47 114.25,52.89 113.97,52.89 113.88,52.97
  IN3 w0.119: v2(133.06,23.03) 133.14,23.03 133.26,23.15 133.26,23.36 133.14,23.48 132.33,23.48 131.29,22.44 129.29,22.44 128.59,23.14 127.07,23.14 126.83,23.39 126.83,23.53 126.71,23.65 126.36,23.65 126.23,23.53 126.23,23.18 125.99,22.94 125.41,22.94 124.85,22.38 122.15,22.38 121.91,22.62 121.91,22.84 v2(121.73,23.02) 121.73,23.36 121.65,23.45 120.99,23.45 120.67,23.12 120.67,22.38 120.02,21.73 115.34,21.73 113.68,20.07 112.26,20.07 111.65,19.46 110.81,19.46 110.41,19.85 110.41,19.88 110.22,20.08 v2(110.22,20.1) 110.33,20.21 110.33,20.38 110.21,20.5 109.46,20.5 109.07,20.11 109.07,19.36 108.65,18.94 107.98,18.94 107.38,19.54 105.56,19.54 105.32,19.78 105.32,19.9 105.2,20.02 104.84,20.02 104.72,19.9 104.72,19.78 104.48,19.54 102.7,19.54 102.62,19.46 99.38,19.46 99.14,19.7 99.14,19.86 v2(98.9,20.1)
  BOTTOM w0.158: v2(110.89,56.33) 110.91,56.33 UC1.AJ25
DDR_A_CLK0#: length 142.9
  TOP w0.102: v2(110.78,20.1) 111.58,19.29 111.58,19.03 111.76,18.85 112.03,18.85 112.51,18.36 UD2.K8 ; UD1.K8 101.2,18.36 100.71,18.85 100.45,18.85 100.26,19.03 100.26,19.29 v2(99.46,20.1) ; UD3.K8 124.03,21.28 123.54,21.77 123.28,21.77 123.1,21.95 123.1,22.21 v2(122.29,23.02) ; v2(133.62,23.03) 134.42,22.23 134.42,21.96 134.61,21.78 134.87,21.78 135.36,21.29 UD4.K8
  TOP w0.147: v2(92.32,24.01) 91.57,24.01 RD29.2
  IN1 w0.122: v2(92.32,24.01) 92.41,23.91 94.8,23.91 96.52,22.2 96.52,21.94 97.01,21.45 98.31,21.45 99.28,20.48 99.28,20.28 v2(99.46,20.1)
  IN2 w0.102: v2(110.86,57.16) 111.04,56.98 111.26,56.98 111.47,56.76 111.47,56.09 111.75,55.81 111.75,54.27 112.17,53.85 112.74,53.85 113.19,53.41 113.77,53.41 114.01,53.17 114.04,53.17 114.06,53.15
  IN2 w0.165: 114.06,53.15 114.36,53.15 114.93,52.58 114.93,51.75 115.47,51.2 117.68,51.2 118.88,50 118.89,50 118.9,50 118.94,49.95 119.86,49.95 120.32,49.49 120.32,48.98 120.31,48.96 120.31,45.34 121.92,43.74 122.15,43.74 122.57,44.16 123.02,44.16 123.4,43.78 123.4,43.33 122.98,42.91 122.98,42.68 123.21,42.44 123.44,42.44 123.87,42.87 124.31,42.87 124.7,42.48 124.7,42.04 124.27,41.62 124.27,41.38 124.51,41.15 124.74,41.15 125.16,41.57 125.61,41.57 125.99,41.19 125.99,40.75 125.57,40.32 125.57,40.09 125.8,39.86 126.03,39.86 126.46,40.28 126.9,40.28 127.28,39.9 127.28,39.45 126.86,39.03 126.86,38.79 127.09,38.56 127.33,38.56 127.75,38.98 128.19,38.98 128.58,38.6 128.58,38.16 127.98,37.56 127.98,37.32 128.21,37.09 128.44,37.09 129.05,37.69 129.49,37.69 129.87,37.31 129.87,36.86 129.17,36.16 129.17,35.93 129.41,35.7 129.64,35.7 130.32,36.38 130.77,36.38 131.08,36.06 131.08,35.48 130.74,35.14 130.74,34.33 134.1,30.97 134.1,30.45 134.27,30.28 136.42,30.28 137.91,28.79 137.91,27.49 137.5,27.08 136.91,27.08 136.74,26.91 136.74,26.68 136.91,26.51 137.55,26.51 137.86,26.2 137.86,25.68 136.95,24.77 136.95,24.14 137.53,23.55 137.53,22.62 137.22,22.3 136.91,22.3 136.71,22.11 136.71,21.84 136.87,21.67 137.24,21.67 137.56,21.36 137.56,20.36 137.09,19.9 135.52,19.9 135.2,20.22 135.2,21.52 134.41,22.31 134.41,24.85 134.24,25.01 133.79,25.01 133.62,24.85 v2(133.62,23.03)
  IN3 w0.119: v2(133.62,23.03) 133.47,23.18 133.47,23.45 133.23,23.69 132.24,23.69 131.2,22.65 129.38,22.65 128.68,23.35 127.16,23.35 127.04,23.47 127.04,23.62 126.8,23.86 126.27,23.86 126.03,23.62 126.03,23.27 125.91,23.15 125.32,23.15 124.76,22.59 122.23,22.59 122.11,22.71 122.11,22.84 v2(122.29,23.02) 122.12,23.19 122.12,23.28 121.73,23.66 120.91,23.66 120.46,23.21 120.46,22.46 119.94,21.94 115.26,21.94 113.59,20.28 112.18,20.28 111.56,19.67 110.89,19.67 110.78,19.78 v2(110.78,20.1) 110.77,20.1 110.54,20.33 110.54,20.47 110.3,20.71 109.38,20.71 108.86,20.2 108.86,19.45 108.56,19.15 108.07,19.15 107.47,19.75 105.64,19.75 105.53,19.87 105.53,19.99 105.28,20.23 104.75,20.23 104.51,19.99 104.51,19.87 104.39,19.75 102.61,19.75 102.53,19.67 99.47,19.67 99.35,19.79 99.35,19.94 99.34,19.96 99.34,19.97 v2(99.46,20.1)
  BOTTOM w0.158: UC1.AJ24 110.93,57.16 v2(110.86,57.16)
DDR_A_CS0#: length 139.9
  TOP w0.107: v2(133.81,20.99) 134.32,20.49 UD4.L7 ; v2(122.49,20.98) 122.99,20.48 UD3.L7 ; UD2.L7 111.47,17.56 v2(110.97,18.06) ; v2(99.68,18.1) 100.23,17.56 UD1.L7
  TOP w0.188: v2(88.99,21.16) 88.62,21.54 RD21.2
  IN2 w0.102: v2(113.87,56.4) 113.87,56.36 114.26,55.98 114.26,55.51 114.81,54.96 115.22,54.96 115.74,54.44 118.53,54.44 118.79,54.18 120.08,54.18 120.74,54.84 124.45,54.84 124.7,54.59 125.49,54.59 125.75,54.34 125.75,53.02 126.53,52.23 126.53,49.03 126.74,48.83
  IN2 w0.198: v2(141.95,21.32) 141.95,23.02 141.97,23.04 141.97,29.97 137.35,34.59 137.35,37.27 137.16,37.47 136.8,37.47 136.52,37.75 136.52,38.03 137.23,38.74 137.23,39.02 136.95,39.3 136.67,39.3 135.96,38.59 135.68,38.59 135.42,38.84 135.42,39.12 136.06,39.76 136.06,40.04 135.78,40.32 135.5,40.32 134.86,39.68 134.58,39.68 134.3,39.97 134.3,40.25 134.93,40.88 134.93,41.16 134.65,41.44 134.37,41.44 133.74,40.81 133.46,40.81 133.18,41.09 133.18,41.37 133.81,42 133.81,42.28 131.86,44.23 130,44.23 126.74,47.5 126.74,48.83
  IN3 w0.102: v2(99.68,18.1) 99.35,18.44 98.33,18.44 98.07,18.18 98.07,17.71 97.57,17.21 96.59,17.21 95.23,18.57 95.23,18.94 94.72,19.45 94.25,19.45 93.26,20.44 93.26,21.24 92.95,21.56 90.4,21.56 90.29,21.44 89.53,21.44 89.25,21.16 v2(88.99,21.16)
  IN3 w0.127: v2(133.81,20.99) 133.34,21.47 133.16,21.47 132.99,21.65 128.74,21.65 128.62,21.77 128.62,22.2 128.45,22.37 128.1,22.37 127.98,22.26 127.98,21.8 127.89,21.71 127.61,21.71 127.5,21.82 127.5,22.29 127.42,22.37 127.14,22.37 127.04,22.27 127.04,21.8 126.89,21.65 126.23,21.65 125.38,20.8 122.67,20.8 v2(122.49,20.98) 122.09,21.38 121.11,21.38 119.55,19.82 118.9,19.82 118.77,19.94 118.77,20.17 118.64,20.3 118.39,20.3 118.26,20.17 118.26,19.94 118.13,19.82 116.51,19.82 116.38,19.94 116.38,20.2 116.25,20.33 116,20.33 115.87,20.2 115.87,19.94 115.75,19.82 115.33,19.82 114.82,19.31 112.22,19.31 v2(110.97,18.06) 110.56,18.47 109.64,18.47 109.2,18.03 107.42,18.03 107,18.45 106.66,18.45 106.53,18.57 106.53,18.75 106.41,18.88 106.15,18.88 106.03,18.75 106.03,18.57 105.9,18.45 105.62,18.45 105.49,18.57 105.49,18.76 105.37,18.89 105.11,18.89 104.99,18.76 104.99,18.57 104.86,18.45 103.57,18.45 103.21,18.08 103.21,17.68 103.08,17.56 101.54,17.56 101.41,17.68 101.41,18.17 101.29,18.29 99.87,18.29 v2(99.68,18.1)
  IN3 w0.16: v2(133.81,20.99) 134.58,20.99 135.12,20.45 136.87,20.45 137.13,20.71 143.26,20.71 143.42,20.87 143.42,22.65 143.26,22.81 143,22.81 142.89,22.7 142.89,21.48 142.73,21.32 v2(141.95,21.32)
  BOTTOM w0.102: UC1.AL25 113.48,56.8 v2(113.87,56.4)
DDR_A_DM0: length 54.7
  TOP w0.089: v2(100.18,22.81) 100.18,21.97 100.27,21.87 101.01,21.87 101.08,21.95 101.08,22.28 101.01,22.36 UD1.E7
  IN3 w0.102: 92.27,46.26 92.57,46.56 92.57,46.69 92.4,46.87 92.4,47.05 92.65,47.3 92.65,48.24 94.03,49.62 94.03,51.99 95.48,53.43 95.48,54.37 95.62,54.51 95.62,54.87 95.75,55 v2(95.87,55)
  IN3 w0.127: 92.27,46.26 92.24,46.23 92.24,44.97 93.26,43.95 93.26,34.55 93.13,34.42 92.96,34.42 92.83,34.55 92.83,40.81 92.7,40.94 92.52,40.94 92.4,40.81 92.4,34.32 100.14,26.57 100.14,22.85 v2(100.18,22.81)
  BOTTOM w0.102: v2(95.87,55) 95.98,54.89 96.31,54.89 96.37,54.96 UC1.L27
DDR_A_DM1: length 63.4
  TOP w0.089: 97.04,22.77 v2(97.04,22.81)
  TOP w0.117: UD1.E2 97.04,22.77
  IN3 w0.102: 87.21,47.78 87.24,47.81 87.24,48.16 87.17,48.23 86.99,48.23 86.62,48.6 86.3,48.6 86.22,48.67 86.22,48.87 86.35,49 86.61,49 86.72,49.1 86.72,49.25 86.5,49.46 86.5,49.61 86.7,49.81 86.84,49.81 87.11,49.55 87.25,49.55 87.4,49.69 87.4,49.83 87.12,50.11 87.12,50.25 87.26,50.4 87.41,50.4 87.68,50.12 87.83,50.12 87.97,50.27 87.97,50.41 87.77,50.61 87.77,50.75 88.13,51.11 88.28,51.11 88.47,50.91 88.62,50.91 88.76,51.06 88.76,51.2 88.59,51.38 88.59,51.54 88.72,51.68 88.86,51.68 89.05,51.49 89.19,51.49 89.34,51.63 89.34,51.78 89.13,51.99 89.13,52.13 89.26,52.26 89.43,52.26 89.62,52.06 89.77,52.06 89.91,52.21 89.91,52.35 89.79,52.47 89.79,52.62 90.33,53.16 90.33,53.3 89.75,53.88 89.75,54.02 89.9,54.17 90.05,54.17 90.71,53.51 90.85,53.51 90.97,53.62 90.97,53.81 90.35,54.42 90.35,54.6 90.48,54.73 90.62,54.73 90.92,54.43 91.07,54.43 91.21,54.57 91.21,54.72 90.91,55.01 90.91,55.16 91.84,56.09 94.15,56.09 94.39,56.33 94.39,56.8 94.62,57.03 95.28,57.03 95.74,57.49 96.08,57.49 96.43,57.84 96.43,58.25 96.56,58.38 97.1,58.38 97.39,58.66 97.39,58.95 97.64,59.2 98.47,59.2 v2(98.87,58.8)
  IN3 w0.127: v2(97.04,22.81) 97.44,23.21 97.44,23.72 97.21,23.95 96.32,23.95 95.96,24.3 95.3,24.3 94.85,24.75 94.85,25.89 94.25,26.49 94.25,27.62 93.86,28.01 93.04,28.01 86.1,34.96 86.1,45.52 86.52,45.95 87.01,45.95 87.14,46.07 87.14,46.25 87.01,46.38 86.63,46.38 86.5,46.51 86.5,46.69 86.63,46.82 86.95,46.82 87.07,46.94 87.07,47.12 86.95,47.25 86.63,47.25 86.5,47.38 86.5,47.6 86.63,47.73 87.16,47.73 87.21,47.78
  BOTTOM w0.108: UC1.N23 98.78,58.8 v2(98.87,58.8)
DDR_A_DM2: length 54.6
  TOP w0.089: v2(112.36,22.77) 111.95,22.36 UD2.E7
  IN3 w0.102: 102.94,46.26 102.94,52.53 102.85,52.62 102.85,54.11 102.28,54.69 102.28,57.45 102.18,57.55 101.77,57.55 101.67,57.65 101.67,58.09 101.56,58.2 101.39,58.2 101.29,58.1 101.29,55.75 101.19,55.64 v2(100.88,55.64)
  IN3 w0.127: 102.94,46.26 102.94,46.13 104.03,45.04 104.03,44.54 104.16,44.42 104.36,44.42 104.49,44.29 104.49,44.03 104.36,43.91 104.16,43.91 104.03,43.78 104.03,43.53 104.16,43.4 104.36,43.4 104.49,43.27 104.49,43.02 104.36,42.89 104.16,42.89 104.03,42.76 104.03,42.51 104.16,42.38 104.36,42.38 104.49,42.26 104.49,42 104.36,41.88 104.16,41.88 104.03,41.75 104.03,41.49 104.16,41.37 104.36,41.37 104.49,41.24 104.49,40.99 104.36,40.86 104.16,40.86 104.03,40.73 104.03,40.48 104.16,40.35 104.36,40.35 104.49,40.22 104.49,40.04 104.36,39.92 104.16,39.92 104.03,39.79 104.03,39.65 104.2,39.48 104.69,39.48 104.79,39.38 104.79,36.05 104.94,35.9 105.12,35.9 105.22,36 105.22,36.47 105.35,36.59 107.9,36.59 109.32,35.17 109.32,33.16 107.92,31.75 107.92,31.57 108.37,31.12 108.37,25.67 108.75,25.29 108.75,24.14 109.31,23.58 111.17,23.58 111.78,22.96 111.78,22.42 111.87,22.33 112.46,22.33 112.59,22.46 112.59,22.64 112.46,22.77 v2(112.36,22.77)
  BOTTOM w0.102: UC1.R27 100.72,55.64 v2(100.88,55.64)
DDR_A_DM3: length 55.3
  TOP w0.089: UD2.E2 107.95,22.76 108.04,22.85 109.07,22.85 109.16,22.76 109.16,21.9 109.24,21.82 109.41,21.82 109.48,21.89 109.48,22.76 109.57,22.85 109.73,22.85 109.8,22.79 109.8,21.94 109.88,21.85 110.06,21.85 110.15,21.94 110.15,22.81 111.08,23.74 111.08,23.99 v2(111.18,24.09)
  IN3 w0.102: v2(103.87,57.2) 103.49,57.2 103.32,57.03 103.32,56.29 103.42,56.19 103.65,56.19 103.99,55.84 103.99,53.75 104.1,53.65 105.01,53.65 105.11,53.55 105.11,53.37 105.01,53.27 104.36,53.27 104.28,53.19 104.28,52.99 104.38,52.89 105.55,52.89 105.63,52.81 105.63,52.58 105.55,52.51 104.92,52.51 104.82,52.41 104.82,47.58 105.54,46.86 ; 105.54,46.33 105.61,46.26
  IN3 w0.127: 105.61,46.26 106.39,45.48 106.39,40.8 107.64,39.55 109.06,39.55 109.35,39.27 109.53,39.27 109.82,39.55 110.01,39.55 110.19,39.37 110.19,39.19 109.9,38.9 109.9,38.72 110.07,38.55 110.25,38.55 110.59,38.89 110.77,38.89 110.95,38.7 110.95,38.52 110.61,38.19 110.61,38.01 110.75,37.87 110.93,37.87 111.25,38.19 111.43,38.19 111.61,38.01 111.61,37.83 111.33,37.55 111.33,37.29 112,36.61 112,30.58 111,29.57 111,24.92 111.12,24.8 111.83,24.8 111.92,24.71 111.92,24.49 111.79,24.36 111.31,24.36 111.18,24.24 v2(111.18,24.09) ; 105.54,46.86 105.54,46.33
  BOTTOM w0.102: UC1.Y24 104.27,57.6 v2(103.87,57.2)
DDR_A_DM4: length 54.6
  TOP w0.089: UD3.E7 121.76,25.28 v2(121.33,24.85)
  IN3 w0.102: v2(116.88,54.84) 116.98,54.74 116.98,53.75 116.75,53.52 116.46,53.52 116.36,53.42 116.36,52.84 116.26,52.74 116.05,52.74 115.95,52.84 115.95,53.46 115.81,53.6 115.64,53.6 115.46,53.42 115.46,52.84 115.26,52.63 115.1,52.63 114.72,53.02 113.99,53.02 113.86,52.89 113.86,52.33 113.99,52.2 114.37,52.2 114.47,52.1 114.47,51.57 114.7,51.34 115.76,51.34 115.92,51.49 116.17,51.49 116.25,51.41 116.25,50.88 116.12,50.75 114.9,50.75 114.84,50.69 114.84,50.51 115.05,50.3 116.02,50.3 116.22,50.09 116.22,49.87 116.04,49.69 115.38,49.69 115.21,49.51 115.21,49.26 115.31,49.15 116.2,49.15 116.3,49.05 116.3,48.77 116.09,48.57 115.51,48.57 115.43,48.49 115.43,48.19 115.56,48.06 115.92,48.06 115.99,47.99 115.99,47.55 115.92,47.48 115.41,47.48 115.28,47.35 115.28,47.17 115.46,47 115.74,47 115.86,46.87 115.86,46.37
  IN3 w0.127: 115.86,46.37 117.77,44.46 117.77,44.28 117.93,44.12 117.93,43.94 117.68,43.69 117.68,43.58 117.93,43.33 118.04,43.33 118.29,43.58 118.47,43.58 118.65,43.4 118.65,43.22 118.4,42.97 118.4,42.86 118.65,42.61 118.76,42.61 119.01,42.86 119.19,42.86 119.37,42.68 119.37,42.5 119.12,42.25 119.12,42.14 119.37,41.89 119.48,41.89 119.72,42.14 119.9,42.14 120.07,41.97 120.07,31.58 118.1,29.61 118.1,29.02 118.47,28.66 118.47,28.33 118.1,27.96 118.1,27.34 118.47,26.97 118.47,26.38 118.79,26.07 119.07,26.07 119.24,25.89 119.24,25.61 119.55,25.3 119.83,25.3 120.13,25.61 120.53,25.61 120.72,25.42 121.06,25.42 121.33,25.15 v2(121.33,24.85)
  BOTTOM w0.102: v2(116.88,54.84) 116.83,54.84 UC1.AP27
DDR_A_DM5: length 54.9
  TOP w0.089: UD3.E2 119.47,25.28 119.93,25.74 120.5,25.74 121.26,26.5 v2(123.04,26.5)
  IN3 w0.102: 123.61,46.77 123.61,47.02 123.7,47.11 123.7,47.43 123.6,47.53 123.41,47.53 123.33,47.6 123.33,47.88 123.41,47.96 123.61,47.96 123.7,48.05 123.7,48.33 123.61,48.42 123.02,48.42 122.94,48.49 122.65,48.49 122.52,48.62 122.52,48.77 122.77,49.03 122.77,49.89 122.88,49.99 123.59,49.99 123.71,50.12 123.71,50.68 123.59,50.81 122.9,50.81 122.77,50.93 122.77,51.49 122.9,51.62 123.56,51.62 123.69,51.75 123.69,52.25 123.54,52.41 122.85,52.41 122.77,52.48 122.77,52.96 122.99,53.18 123.75,53.18 123.82,53.24 123.82,53.93 123.74,54.01 123.37,54.01 123.1,54.27 123.1,54.49 123.18,54.56 123.71,54.56 123.82,54.67 123.82,54.84 123.69,54.97 122.06,54.97 121.96,55.07 121.96,56.62 121.81,56.77 121.64,56.77 121.48,56.62 121.48,56.24 121.38,56.14 120.97,56.14 120.89,56.22 120.89,56.77 120.47,57.19 v2(120.47,57.5)
  IN3 w0.127: v2(123.04,26.5) 122.9,26.5 122.55,26.85 122.55,29.09 124.4,30.94 126.09,30.94 127.04,31.89 127.04,32.8 129.51,35.27 129.51,35.8 129.63,35.92 130.1,35.92 130.45,36.27 130.45,38 130.09,38.36 129.8,38.36 129.67,38.23 129.46,38.23 129.3,38.39 129.3,38.58 129.43,38.7 129.43,38.99 128.95,39.47 128.95,40.18 123.61,45.52 123.61,46.77
  BOTTOM w0.102: UC1.AW23 120.07,57.8 120.37,57.5 v2(120.47,57.5)
DDR_A_DM6: length 99
  TOP w0.089: v2(135.18,25.67) UD4.E7
  IN3 w0.102: v2(118.18,59.5) 118.18,59.79 118.6,60.22 118.6,60.56 118.25,60.9 117.94,60.9 117.64,61.21 115.57,61.21 115.36,61.42
  IN3 w0.127: 115.36,61.42 115.36,61.99 115.03,62.32 115.03,63.73 114.67,64.09 114.67,64.67 114.93,64.93 114.93,65.77 115.26,66.1 115.26,66.78 115.41,66.93 116.98,66.93 117.08,67.04 117.08,67.38 117.18,67.48 117.38,67.48 117.48,67.38 117.48,67.04 117.58,66.93 120.62,66.93 121.2,67.52 122.28,67.52 122.38,67.62 122.38,68 122.48,68.1 122.69,68.1 122.79,68 122.79,67.62 122.89,67.52 123.43,67.52 123.51,67.59 125.47,67.59 126.77,66.3 128.91,66.3 129.09,66.47 129.09,66.6 129.21,66.73 129.47,66.73 129.59,66.6 129.59,66.47 129.74,66.32 129.95,66.32 130.1,66.47 130.1,67.12 130.25,67.26 130.46,67.26 130.61,67.12 130.61,66.13 130.84,65.91 131.79,65.91 132.17,65.52 132.17,63.15 132.63,62.69 133.01,62.69 133.34,63.02 133.82,63.02 133.95,62.9 133.95,62.5 133.82,62.37 133.52,62.37 133.34,62.2 133.34,61.64 133.51,61.47 134.16,61.47 134.48,61.15 134.48,60.97 134.57,60.88 134.88,60.88 135.03,61.03 135.03,61.35 135.18,61.5 135.39,61.5 135.54,61.35 135.54,61.03 135.69,60.88 135.9,60.88 136.05,61.03 136.05,62.06 136.18,62.18 136.38,62.18 136.56,62.01 136.56,61.03 136.71,60.88 136.93,60.88 137.05,60.99 137.05,61.19 137.19,61.33 137.56,61.33 137.68,61.2 137.68,60.76 137.81,60.64 138.07,60.64 138.55,61.12 138.8,61.12 138.96,60.95 138.96,60.69 138.47,60.2 138.47,60 138.67,59.8 138.85,59.8 139.4,60.34 139.58,60.34 139.89,60.03 139.89,59.65 140.28,59.26 140.65,59.26 141,58.92 141,58.04 140.87,57.91 140.53,57.91 140.4,57.79 140.4,57.53 140.53,57.41 140.87,57.41 141,57.28 141,56.85 140.85,56.7 140.53,56.7 140.41,56.57 140.41,56.32 140.53,56.19 140.85,56.19 141,56.04 141,54.37 140.85,54.22 140.4,54.22 140.25,54.07 140.25,53.67 140.1,53.52 139.89,53.52 139.74,53.67 139.74,54.07 139.6,54.22 139.02,54.22 138.88,54.08 138.88,53.88 139.72,53.04 139.72,51.88 139.92,51.68 139.92,51.41 139.72,51.21 139.72,50.09 139.92,49.88 139.92,49.62 139.72,49.41 139.72,48.29 139.97,48.04 139.97,47.87 139.72,47.62 139.72,43.9 139.94,43.67 139.94,42.17 140.95,41.17 140.95,29.14 137.46,25.65 136.67,25.65 136.33,25.3 135.37,25.3 135.18,25.5 v2(135.18,25.67)
  BOTTOM w0.108: UC1.AT21 118.18,59.6 v2(118.18,59.5)
DDR_A_DM7: length 54.7
  TOP w0.089: v2(132.81,27.35) 131.93,26.47 131.93,25.99 131.68,25.74 131.24,25.74 UD4.E2
  IN3 w0.102: v2(119.67,62.5) 120.08,62.91 120.76,62.91 121.1,62.58 122.16,62.58 122.42,62.31 122.82,62.31 122.94,62.19 122.94,61.79 123.29,61.45 123.79,61.45 123.89,61.55 123.89,61.96 123.99,62.06 124.68,62.06 124.81,61.93 124.81,61.65 124.9,61.55 125.09,61.55 125.19,61.65 125.19,61.83 125.26,61.9 125.39,61.9 126,61.3 126,61.09 125.64,60.74 125.64,60.61 126.25,60 126.25,58.98 126.33,58.91 126.61,58.91 128.74,56.78 128.74,56.64 128.29,56.2 128.29,50.52 128.44,50.38
  IN3 w0.127: v2(132.81,27.35) 132.52,27.64 132.52,28.42 136.25,32.15 136.25,39.15 133.5,41.9 133.5,45.16 133.11,45.55 130.55,45.55 128.85,47.25 128.85,49.97 128.44,50.38
  BOTTOM w0.102: UC1.AV18 119.37,62.8 v2(119.67,62.5)
DDR_A_DQ0: length 54.5
  TOP w0.127: UD1.J3 97.43,19.01 97.32,18.9 97.08,18.9 96.99,18.99 v2(96.99,19.54)
  IN3 w0.102: v2(94.94,54.87) 94.94,54.54 94.84,54.44 94.15,54.44 93.96,54.25 93.96,53.33 93.58,52.95 93.58,50.11 92.77,49.31 91.81,49.31 91.15,48.65 91.15,46.26
  IN3 w0.127: 91.15,46.26 91.15,46.06 91.41,45.8 91.41,44.23 91.63,44 91.63,34 99.19,26.45 99.19,22.81 98.95,22.57 98.95,21.52 98.31,20.88 97.68,20.88 97.43,20.63 97.43,19.28 97.55,19.16 97.86,19.16 97.95,19.07 97.95,18.84 97.83,18.73 97.55,18.73 97.43,18.6 97.43,17.51 97.32,17.41 97.02,17.41 96.89,17.54 96.89,17.84 96.79,17.94 96.25,17.94 96.12,18.07 96.12,18.25 96.21,18.34 96.79,18.34 96.92,18.47 96.92,18.9 96.63,19.19 95.56,19.19 95.44,19.32 95.44,19.91 95.55,20.02 95.72,20.02 96,19.74 96.78,19.74 v2(96.99,19.54)
  BOTTOM w0.127: v2(94.94,54.87) 94.96,54.9 94.96,55.24 95.05,55.33 95.35,55.33 UC1.K27
DDR_A_DQ1: length 54.6
  TOP w0.117: v2(97.03,20.36) 97.03,20.87 96.94,20.96 96.75,20.96 96.63,20.84 UD1.G2
  IN3 w0.102: v2(93.89,54.82) 93.75,54.68 93.75,53.5 92.61,52.35 92.61,51.79 92.7,51.69 93.13,51.69 93.26,51.57 93.26,51.36 93.11,51.21 93.11,51.01 93.34,50.78 93.34,50.17 93.21,50.04 93.03,50.04 92.93,50.14 92.93,50.65 92.83,50.75 92.6,50.75 92.5,50.65 92.5,50.04 92.7,49.84 92.7,49.61 92.6,49.51 92.27,49.51 92.19,49.59 92.19,50.14 92.14,50.2 91.94,50.2 91.84,50.09 91.84,49.79 90.95,48.9 90.95,48.47 90.85,48.37 90.13,48.37 90.03,48.27 90.03,48.12 90.13,48.02 90.85,48.02 90.95,47.92 90.95,47.47 90.85,47.37 90.7,47.37 90.47,47.6 89.45,47.6 89.35,47.5 89.35,47.35 89.45,47.25 90.34,47.25 90.41,47.18 90.41,46.82 90.31,46.72 89.45,46.72 89.34,46.61 89.34,46.42 89.45,46.31 90.16,46.31 90.21,46.26
  IN3 w0.127: v2(97.03,20.36) 97.03,20.62 97.53,21.11 98.16,21.11 98.62,21.57 98.62,22.78 98.81,22.97 98.81,26.29 91.25,33.85 91.25,43.84 91.02,44.07 91.02,45.29 90.85,45.47 90.21,45.47 90.14,45.4 89.57,45.4 89.48,45.48 89.48,45.7 89.61,45.83 90.19,45.83 90.3,45.94 90.3,46.17 90.21,46.26
  BOTTOM w0.102: v2(93.89,54.82) 93.89,54.82 UC1.H27
DDR_A_DQ2: length 54.5
  TOP w0.117: UD1.J7 100.62,19.18 100.62,19.47 100.24,19.85 v2(100.24,20.34)
  IN3 w0.102: v2(96.87,55) 96.82,54.94 96.82,53.8 95.76,52.74 95.76,51.69 95.65,51.59 95.04,51.59 94.96,51.52 94.96,51.29 95.06,51.19 95.65,51.19 95.76,51.08 95.76,50.69 95.55,50.48 95.55,50.32 95.76,50.11 95.76,49.94 95.52,49.71 95.52,49.56 95.76,49.33 95.76,49.09 95.65,48.99 95.18,48.99 95.08,48.89 95.08,48.7 95.19,48.58 95.65,48.58 95.76,48.48 95.76,48.29 95.65,48.19 94.44,48.19 94.31,48.05 94.31,47.91 94.41,47.81 95.24,47.81 95.34,47.71 95.34,47.53 95.24,47.43 94.3,47.43 94.2,47.33 94.2,47.15 94.3,47.05 94.81,47.05 94.91,46.95 94.91,46.79 94.8,46.69 94.23,46.69 94.15,46.62 94.15,46.44 94.29,46.31 94.44,46.31 94.49,46.26
  IN3 w0.127: 94.49,46.26 94.54,46.21 94.54,45.1 94.97,44.67 95.3,44.67 95.6,44.37 95.6,34.63 95.47,34.5 95.22,34.5 95.09,34.63 95.09,36.8 94.94,36.95 94.68,36.95 94.56,36.84 94.56,34.28 101.65,27.19 101.65,25.74 101.39,25.48 101.39,22.31 100.56,21.48 100.56,20.66 v2(100.24,20.34)
  BOTTOM w0.102: v2(96.87,55) 97.17,55.3 UC1.M27
DDR_A_DQ3: length 54.6
  TOP w0.117: UD1.H8 v2(101.89,20.41)
  IN3 w0.102: v2(97.87,55) 97.87,54.85 97.43,54.4 97.43,53.49 96.37,52.43 96.37,47.69 95.72,47.05 95.72,46.26
  IN3 w0.127: 95.72,46.26 95.72,45.87 96.8,44.79 97.48,44.79 97.61,44.66 97.61,34.44 97.52,34.35 97.32,34.35 97.2,34.47 97.2,38.01 97.07,38.13 96.87,38.13 96.74,38 96.74,34.43 103.48,27.69 103.48,25.67 103.62,25.53 103.62,23.34 103.5,23.21 103.45,23.21 103.32,23.09 103.32,22.83 103.45,22.71 103.5,22.71 103.62,22.58 103.62,22.33 103.5,22.2 102.84,22.2 102.71,22.07 102.71,21.82 102.84,21.69 103.5,21.69 103.62,21.56 103.62,20.13 103.5,20.01 103.28,20.01 103.19,20.1 103.19,20.66 103.06,20.78 102.53,20.78 102.35,20.6 102.35,20.07 102.24,19.96 101.99,19.96 101.87,20.07 101.87,20.39 v2(101.89,20.41)
  BOTTOM w0.102: v2(97.87,55) 98.17,55.3 UC1.N27
DDR_A_DQ4: length 54.6
  TOP w0.127: UD1.H3 98.35,19.96 98.44,20.05 98.44,20.53 98.32,20.66 97.96,20.66 97.85,20.55 v2(97.85,20.4)
  IN3 w0.102: v2(95.86,55.64) 95.41,55.2 95.41,54.62 95.23,54.44 95.23,54.31 95.09,54.17 95.09,54.02 95.27,53.84 95.27,53.7 95.12,53.56 94.98,53.56 94.8,53.74 94.65,53.74 94.51,53.59 94.51,53.45 94.78,53.18 94.78,53.04 94.64,52.89 94.49,52.89 94.22,53.16 94.08,53.16 93.97,53.06 93.97,52.91 94.25,52.63 94.25,52.49 93.83,52.07 93.83,49.73 93.69,49.58 93.54,49.58 93.51,49.61 93.36,49.61 93.22,49.47 93.22,49.33 93.25,49.29 93.25,49.15 93.11,49.01 92.97,49.01 92.93,49.04 92.79,49.04 92.65,48.9 92.65,48.75 92.68,48.72 92.68,48.57 92.48,48.38 92.34,48.38 92.19,48.52 92.04,48.52 91.95,48.43 91.95,48.28 92.14,48.09 92.14,47.81 92.24,47.71 92.29,47.71 92.4,47.6 92.4,47.4 92.29,47.3 92.24,47.3 92.14,47.2 92.14,46.51 91.94,46.31 91.89,46.31
  IN3 w0.127: 91.89,46.31 91.86,46.28 91.86,44.33 92.22,43.97 92.42,43.97 92.88,43.51 92.88,41.45 92.75,41.32 92.57,41.32 92.45,41.45 92.45,43.31 92.26,43.5 92.12,43.5 92.02,43.4 92.02,34.16 99.57,26.6 99.57,26.37 99.86,26.09 99.86,25.91 99.57,25.62 99.57,25.48 99.86,25.2 99.86,25.02 99.53,24.69 99.53,24.51 99.86,24.18 99.86,24 99.51,23.65 99.51,23.47 99.8,23.18 99.8,22.81 99.25,22.27 99.25,21.47 98.47,20.68 98.47,20.07 98.34,19.94 98,19.94 97.85,20.1 v2(97.85,20.4)
  BOTTOM w0.102: v2(95.86,55.64) 95.86,55.69 96.17,56 UC1.L26
DDR_A_DQ5: length 54.6
  TOP w0.127: UD1.H2 96.63,19.69 96.43,19.49 96.3,19.49 96.2,19.58 v2(96.2,20.35)
  IN3 w0.102: 89.07,46.26 89.07,48.23 89.43,48.59 89.43,48.74 89.28,48.89 89.28,49.03 89.42,49.17 89.56,49.17 89.72,49.02 89.86,49.02 90.03,49.2 90.03,49.34 89.9,49.48 89.9,49.63 90.04,49.77 90.18,49.77 90.32,49.63 90.47,49.63 90.61,49.77 90.61,49.92 90.47,50.06 90.47,50.2 90.61,50.34 90.76,50.34 90.9,50.2 91.04,50.2 91.18,50.35 91.18,50.49 91.05,50.63 91.05,50.78 91.19,50.92 91.33,50.92 91.47,50.78 91.62,50.78 91.76,50.92 91.76,51.07 91.62,51.21 91.62,51.35 91.76,51.49 91.91,51.49 92.05,51.35 92.19,51.35 92.4,51.57 92.4,52.44 93.36,53.39 v2(93.36,53.99)
  IN3 w0.127: 89.07,46.26 89.07,45.32 90,44.39 90,41.79 90.13,41.66 90.31,41.66 90.44,41.79 90.44,43.62 90.57,43.74 90.75,43.74 90.87,43.62 90.87,33.69 97.86,26.7 97.86,26.03 97.92,25.96 98.34,25.96 98.47,25.84 98.47,23.07 98.35,22.95 98.35,21.68 98.01,21.34 96.92,21.34 96.82,21.24 96.82,20.87 96.71,20.77 96.49,20.77 96.4,20.86 96.4,21.14 96.27,21.27 96.16,21.27 96.05,21.37 96.05,21.57 95.88,21.75 95.7,21.75 95.61,21.66 95.61,20.89 95.7,20.81 95.93,20.81 96.2,20.53 v2(96.2,20.35)
  BOTTOM w0.102: UC1.G27 93.37,55.06 92.9,54.59 92.9,54.34 93.25,53.99 v2(93.36,53.99)
DDR_A_DQ6: length 54.4
  TOP w0.117: v2(101.07,20.4) 101.07,20.39 UD1.H7
  IN3 w0.102: v2(97.87,55.62) 97.48,55.22 97.48,54.73 97.22,54.48 97.22,53.57 96.16,52.51 96.16,47.78 95.34,46.95 95.34,46.26
  IN3 w0.127: v2(101.07,20.4) 101.51,20.85 102.09,20.85 102.34,21.1 102.34,22.12 102.61,22.38 102.61,22.69 103.23,23.31 103.23,25.23 103.1,25.35 103.1,27.53 96.36,34.27 96.36,43.92 96.49,44.05 96.67,44.05 96.79,43.93 96.79,38.64 96.92,38.51 97.1,38.51 97.22,38.64 97.22,44.28 97.1,44.4 96.54,44.4 96.35,44.59 96.35,44.69 95.34,45.71 95.34,46.26
  BOTTOM w0.102: v2(97.87,55.62) 97.87,55.65 98.23,56 UC1.N26
DDR_A_DQ7: length 54.5
  TOP w0.127: UD1.F7 100.49,21.56 100.4,21.47 100.4,21.29 100.59,21.09 100.93,21.09 v2(101.02,21.17)
  IN3 w0.102: 94.96,46.26 95.14,46.44 95.14,47.04 95.96,47.86 95.96,52.6 97.02,53.65 97.02,54.56 97.26,54.8 97.26,55.92 97.36,56.02 98.08,56.02 98.26,56.21 98.26,56.88 98.37,56.98 98.37,57.83 98.47,57.93 v2(98.85,57.93)
  IN3 w0.127: v2(101.02,21.17) 101.29,21.17 101.41,21.3 101.41,22.03 101.69,22.31 102.02,22.31 102.26,22.55 102.26,24.14 102.14,24.26 101.72,24.26 101.62,24.36 101.62,24.57 101.72,24.67 102.14,24.67 102.26,24.8 102.26,25.48 102.39,25.61 102.61,25.61 102.75,25.75 102.75,25.93 102.66,26.01 102.13,26.01 102.03,26.12 102.03,26.3 102.15,26.43 102.58,26.43 102.72,26.57 102.72,27.06 102.67,27.11 102.49,27.11 102.31,26.94 102.15,26.94 102.03,27.07 102.03,27.24 102.35,27.56 102.35,27.74 102.2,27.89 102.02,27.89 101.84,27.72 101.66,27.72 101.5,27.88 101.5,28.06 101.67,28.22 101.67,28.4 101.49,28.58 101.31,28.58 101.14,28.42 100.96,28.42 100.75,28.63 100.75,28.81 100.9,28.97 100.9,29.15 100.72,29.33 100.54,29.33 100.39,29.17 100.21,29.17 100.03,29.35 100.03,29.53 100.18,29.68 100.18,29.86 100,30.04 99.82,30.04 99.67,29.89 99.49,29.89 99.31,30.07 99.31,30.25 99.46,30.4 99.46,30.58 99.28,30.76 99.1,30.76 98.95,30.61 98.77,30.61 98.59,30.79 98.59,30.97 98.74,31.12 98.74,31.3 98.56,31.48 98.38,31.48 98.23,31.33 98.05,31.33 97.87,31.51 97.87,31.69 98.02,31.84 98.02,32.02 97.84,32.2 97.66,32.2 97.51,32.05 97.33,32.05 97.15,32.23 97.15,32.41 97.3,32.56 97.3,32.74 97.13,32.92 96.95,32.92 96.79,32.77 96.61,32.77 96.43,32.95 96.43,33.13 96.59,33.28 96.59,33.46 96.41,33.64 96.23,33.64 96.07,33.49 95.89,33.49 95.49,33.89 95.49,34.07 95.56,34.13 95.88,34.13 95.98,34.23 95.98,44.53 94.96,45.55 94.96,46.26
  BOTTOM w0.102: v2(98.85,57.93) 98.7,57.93 UC1.N24
DDR_A_DQ8: length 63.2
  TOP w0.089: v2(96.25,23.57) 96.24,23.58 96.24,24.2 96.31,24.26 96.56,24.26 96.63,24.19 UD1.C2
  IN3 w0.102: 86.02,52.03 86.5,51.54 86.63,51.54 86.78,51.69 86.78,51.84 86.49,52.13 86.49,52.27 86.64,52.41 86.78,52.41 87.07,52.12 87.21,52.12 87.36,52.27 87.36,52.41 87.07,52.7 87.07,52.84 87.21,52.99 87.36,52.99 87.64,52.7 87.79,52.7 87.93,52.84 87.93,52.99 87.64,53.28 87.64,53.42 87.79,53.56 87.93,53.56 88.22,53.27 88.36,53.27 88.48,53.4 88.48,53.6 88.26,53.83 88.26,54.01 88.38,54.13 88.52,54.13 88.82,53.83 88.96,53.83 89.11,53.98 89.11,54.16 88.83,54.44 88.83,54.58 88.98,54.73 89.12,54.73 89.2,54.65 89.34,54.65 89.47,54.78 89.47,54.95 89.41,55.01 89.41,55.16 89.55,55.3 89.7,55.3 89.7,55.29 89.85,55.29 91.04,56.49 91.04,57.16 91.28,57.4 93.89,57.4 94.32,57.82 94.77,57.82 95.18,58.23 95.18,58.86 95.32,59 95.32,59.85 95.42,59.95 95.85,59.95 95.95,60.05 95.95,60.64 96.19,60.88 96.19,61.26 96.31,61.37 96.5,61.37 96.6,61.27 96.6,61.09 96.7,60.99 96.91,60.99 97.01,61.09 97.01,61.27 97.11,61.37 97.35,61.37 97.45,61.27 97.45,60.7 97.55,60.6 v2(97.96,60.6)
  IN3 w0.127: 86.02,52.03 85.86,52.03 85.65,51.82 85.65,51.66 85.92,51.39 85.92,51.16 85.79,51.03 85.6,51.03 85.32,51.31 85.14,51.31 85,51.17 85,50.8 85.12,50.68 85.12,50.44 85,50.32 85,33.92 93.06,25.86 94.34,25.86 94.47,25.74 94.47,25.49 94.38,25.4 93.99,25.4 93.87,25.28 93.87,25.05 94,24.92 94.34,24.92 94.47,24.8 94.47,24.45 95,23.92 95.71,23.92 96.06,23.57 v2(96.25,23.57)
  BOTTOM w0.102: v2(97.96,60.6) 97.96,60.42 UC1.N21
DDR_A_DQ9: length 63
  TOP w0.117: UD1.C3 v2(97.06,24.33)
  IN3 w0.102: 90.72,53.09 91.41,53.78 91.41,55.37 91.93,55.89 94.26,55.89 94.59,56.22 94.59,56.71 94.71,56.83 95.63,56.83 v2(95.86,57.05)
  IN3 w0.127: v2(97.06,24.33) 96.29,24.33 95.76,24.86 95.76,25.96 95.67,26.05 95.67,26.73 95.45,26.95 95.22,26.95 95.14,26.88 95.14,26.59 95,26.45 94.83,26.45 94.63,26.65 94.63,27.77 94.01,28.39 93.2,28.39 86.54,35.05 86.54,45.23 86.67,45.36 87,45.36 87.1,45.26 87.1,37.28 87.22,37.16 87.4,37.16 87.53,37.28 87.53,48.27 87.54,48.29 87.54,48.66 90.72,51.83 90.72,53.09
  BOTTOM w0.102: UC1.L24 96.37,57.57 v2(95.86,57.05)
DDR_A_DQ10: length 64.3
  TOP w0.117: v2(97.91,21.98) 98.26,22.33 99.16,22.33 100.03,23.2 100.6,23.2 UD1.D7
  IN3 w0.102: v2(100.83,60.38) 100.78,60.38 100.05,61.11 99.77,61.59 99.47,61.89 99.25,61.98 96.17,61.98 95.39,61.66 94.83,61.09 94.44,61.09 94.09,60.74 94.09,58.94 93.98,58.84 93.98,58.35 93.64,58.01 90.22,58.01 89.64,57.42
  IN3 w0.127: v2(97.91,21.98) 97.84,21.91 97.15,21.62 96.99,21.62 95.31,22.32 94.93,22.32 94.72,22.53 94.72,22.58 83.86,33.44 83.86,51.56 83.92,51.7 89.64,57.42
  BOTTOM w0.102: v2(100.83,60.38) 101.21,60 UC1.T21
DDR_A_DQ11: length 65
  TOP w0.117: v2(97.83,24.34) 97.9,24.4 98.24,24.4 98.39,24.55 98.39,25.84 98.51,25.96 98.7,25.96 98.8,25.86 98.8,24.32 98.91,24.2 99.14,24.2 99.25,24.31 99.25,25.22 99.37,25.34 99.54,25.34 99.65,25.22 99.65,24.28 99.77,24.16 99.88,24.16 99.96,24.24 99.96,24.79 100.05,24.88 100.21,24.88 100.32,24.77 100.32,24.48 100.43,24.36 101.28,24.36 101.44,24.52 UD1.B8
  IN3 w0.102: 88.67,48.07 88.67,48.77 91.55,51.66 91.55,51.8 91.41,51.95 91.41,52.1 91.54,52.23 91.68,52.23 91.91,52.01 92.05,52.01 92.17,52.13 92.17,52.27 91.67,52.78 91.67,52.97 91.78,53.08 91.92,53.08 92.27,52.73 92.41,52.73 92.54,52.86 92.54,53.01 92.21,53.34 92.21,53.49 92.33,53.61 92.47,53.61 92.81,53.27 92.95,53.27 93.08,53.4 93.08,53.55 92.77,53.86 92.77,54.08 93.29,54.59 93.29,55.1 93.46,55.28 94.94,55.28 95.69,56.03 96.05,56.03 96.58,56.56 96.84,56.56 97.26,56.98 97.26,57.55 97.45,57.74 97.45,58.15 97.72,58.42 99.13,58.42 99.23,58.32 99.23,57.49 99.33,57.38 99.51,57.38 99.61,57.49 99.61,58.32 99.71,58.42 99.88,58.42 99.96,58.34 99.96,57.64 100.03,57.57 100.23,57.57 100.3,57.63 100.3,58.37 100.4,58.48 100.89,58.48 100.99,58.37 100.99,58.12 v2(100.87,58)
  IN3 w0.127: v2(97.83,24.34) 98.25,24.76 98.25,25.51 98.12,25.63 97.58,25.63 97.45,25.76 97.45,26.57 90.49,33.53 90.49,41.08 90.29,41.28 89.75,41.28 89.62,41.41 89.62,44.23 88.67,45.18 88.67,48.07
  BOTTOM w0.102: UC1.R23 100.78,58 v2(100.87,58)
DDR_A_DQ12: length 63.3
  TOP w0.117: UD1.A3 v2(97.09,25.21)
  IN3 w0.102: 88.29,46.26 88.29,47.99 88.37,48.07 88.37,48.76 91.2,51.59 91.2,52.79 93.07,54.66 93.07,55.34 93.21,55.48 94.85,55.48 95.6,56.23 95.97,56.23 96.47,56.74 96.47,57.31 96.78,57.61 97.04,57.61 97.2,57.77 97.2,58.18 v2(97.83,58.82)
  IN3 w0.127: v2(97.09,25.21) 96.69,25.61 96.69,26.79 88.38,35.11 88.38,37.48 88.5,37.61 88.68,37.61 88.81,37.48 88.81,35.03 88.94,34.91 89.12,34.91 89.24,35.03 89.24,37.48 89.37,37.61 89.55,37.61 89.68,37.48 89.68,34.37 89.8,34.24 89.98,34.24 90.11,34.37 90.11,40.77 89.98,40.9 89.8,40.9 89.68,40.77 89.68,38.31 89.58,38.21 89.39,38.21 89.24,38.35 89.24,44.07 88.29,45.02 88.29,46.26
  BOTTOM w0.102: UC1.M22 97.76,58.82 v2(97.83,58.82)
DDR_A_DQ13: length 62.9
  TOP w0.117: UD1.D3 97.85,22.74 v2(97.86,22.74)
  IN3 w0.102: v2(100.88,59.59) 100.88,58.76 100.8,58.68 100.5,58.68 100.4,58.78 100.4,60.43 99.64,61.19 98.8,61.19 98.72,61.12 98.52,61.12 98.44,61.19 98.19,61.19 97.6,61.78 96.21,61.78 95.51,61.49 94.91,60.89 94.53,60.89 94.29,60.65 94.29,58.86 94.19,58.76 94.19,58.26 93.72,57.8 90.55,57.8 90.48,57.73
  IN3 w0.127: 90.48,57.73 84.24,51.49 84.24,33.6 94.68,23.16 95.41,23.16 96.16,22.41 97.53,22.41 v2(97.86,22.74)
  BOTTOM w0.102: UC1.T22 101.27,59.2 v2(100.88,59.59)
DDR_A_DQ14: length 63.1
  TOP w0.117: UD1.C7 97.96,23.96 97.58,23.58 97.02,23.58 v2(97.01,23.57)
  IN3 w0.102: 86.01,52.62 86.53,52.62 89.76,55.84 89.76,56.08 89.86,56.18 90,56.18 90.16,56.01 90.26,56.01 90.38,56.13 90.38,56.27 89.93,56.73 89.93,56.87 90.05,57 90.2,57 90.52,56.67 90.67,56.67 90.81,56.81 90.81,56.96 90.48,57.28 90.48,57.43 90.61,57.55 90.75,57.55 90.88,57.43 91.02,57.43 91.2,57.6 93.81,57.6 94.27,58.06 94.72,58.06 94.97,58.31 94.97,58.95 95.08,59.05 95.08,60.76 95.55,61.23 95.55,61.24 95.62,61.31 96.25,61.57 97.52,61.57 98.21,60.88 98.86,60.88 98.97,60.99 99.48,60.99 99.87,60.6 v2(99.87,60.4)
  IN3 w0.127: v2(97.01,23.57) 97,23.57 96.43,23.01 96.09,23.01 95.55,23.54 94.84,23.54 84.62,33.76 84.62,51.33 85.91,52.62 86.01,52.62
  BOTTOM w0.102: UC1.R21 v2(99.87,60.4)
DDR_A_DQ15: length 63.7
  TOP w0.117: v2(98.04,23.43) 98.18,23.57 98.35,23.57 98.47,23.45 98.47,22.65 98.58,22.54 98.75,22.54 98.87,22.65 98.87,23.52 98.98,23.64 99.17,23.64 99.26,23.55 99.26,23.07 99.34,22.98 99.53,22.98 99.64,23.09 99.64,23.52 99.75,23.64 101.12,23.64 UD1.C8
  IN3 w0.102: v2(96.82,57.99) 96.82,57.94 96.27,57.39 96.27,56.82 95.88,56.43 95.52,56.43 94.77,55.68 92.9,55.68 92.24,55.02 92.24,54.25 90.97,52.98 90.97,51.67 88.61,49.31
  IN3 w0.127: 88.61,49.31 88.05,48.75 88.05,48.24 87.91,48.1 87.91,44.29 88.04,44.17 88.59,44.17 88.86,43.89 88.86,38.29 88.74,38.17 88.56,38.17 88.43,38.29 88.43,43.69 88.3,43.82 88.12,43.82 87.99,43.7 87.99,34.95 96.14,26.8 96.14,25.96 96.43,25.67 96.43,25.16 96.82,24.78 97.2,24.78 97.45,24.53 97.45,24.02 v2(98.04,23.43)
  BOTTOM w0.102: v2(96.82,57.99) 96.78,57.99 UC1.L23
DDR_A_DQ16: length 54.6
  TOP w0.117: UD2.G2 107.95,20.76 107.54,21.16 v2(105.98,21.16)
  IN3 w0.102: v2(98.87,57.2) 98.47,56.79 98.47,56.12 98.28,55.93 98.28,54.55 98.11,54.39 97.73,54.39 97.63,54.28 97.63,54.13 97.7,54.06 97.91,54.06 97.98,53.98 97.98,53.8 97.93,53.75 97.7,53.75 97.63,53.68 97.63,53.4 96.57,52.34 96.57,47.43 96.54,47.4 96.54,46.26
  IN3 w0.127: 96.54,46.26 96.54,45.85 97.15,45.23 97.57,45.23 98.32,44.48 98.44,44.48 98.9,44.03 98.9,40.87 98.77,40.74 98.59,40.74 98.47,40.87 98.47,43.87 98.34,44 98.11,44 97.99,43.87 97.99,33.72 103.86,27.84 103.86,22.96 104.44,22.39 104.44,20.88 104.73,20.58 105.4,20.58 105.7,20.28 105.88,20.28 105.98,20.37 v2(105.98,21.16)
  BOTTOM w0.102: v2(98.87,57.2) 98.97,57.2 UC1.P24
DDR_A_DQ17: length 54.4
  TOP w0.102: v2(108.35,19.56) 108.58,19.33 108.58,19.33 UD2.J3
  IN3 w0.102: 98.16,47.43 98.09,47.51 97.95,47.51 97.85,47.61 97.85,47.75 97.91,47.81 98.09,47.81 98.16,47.88 98.16,48.01 98.06,48.11 97.93,48.11 97.83,48.21 97.83,48.41 97.93,48.51 98.09,48.51 98.19,48.61 98.19,48.82 98.09,48.92 97.98,48.92 97.88,49.02 97.88,49.22 97.98,49.33 98.16,49.33 98.26,49.43 98.26,49.63 98.16,49.73 97.83,49.73 97.73,49.83 97.73,50.04 97.83,50.14 98.06,50.14 98.16,50.24 98.16,50.44 98.06,50.55 97.85,50.55 97.75,50.65 97.75,50.79 97.85,50.89 98.06,50.89 98.16,50.99 98.16,51.14 98.06,51.24 97.08,51.24 96.98,51.34 96.98,51.49 97.08,51.59 98.06,51.59 98.16,51.69 98.16,52.08 97.7,52.54 97.7,52.68 97.82,52.8 97.97,52.8 98.42,52.35 98.56,52.35 98.67,52.46 98.67,52.64 98.3,53.01 98.3,53.15 98.41,53.26 98.55,53.26 98.82,52.99 98.94,52.99 99.05,53.1 99.05,53.24 98.87,53.42 98.87,53.54 99.09,53.76 99.09,54.53 99.22,54.65 99.22,54.89 99.11,55 v2(98.87,55)
  IN3 w0.127: v2(108.35,19.56) 108.08,19.56 107.95,19.68 107.95,20.57 107.29,21.23 107.13,21.23 106.65,21.7 106.29,21.7 105.53,22.46 105.21,22.46 104.65,23.02 104.65,28.13 98.77,34.02 98.77,38.03 98.9,38.16 99.08,38.16 99.2,38.03 99.2,37.19 99.33,37.06 99.53,37.06 99.66,37.19 99.66,44.34 98.67,45.33 98.67,45.74 98.41,46 97.6,46 97.48,46.12 97.48,46.38 97.6,46.5 97.81,46.5 97.93,46.63 97.93,46.74 97.83,46.84 97.68,46.84 97.6,46.92 97.6,47.05 97.75,47.2 98.03,47.2 98.16,47.32 98.16,47.43
  BOTTOM w0.102: v2(98.87,55) 99.17,55.3 UC1.P27
DDR_A_DQ18: length 54.6
  TOP w0.117: v2(110.45,21.24) 110.45,20.95 111.95,19.45 UD2.J7
  IN3 w0.102: 100.61,46.49 100.61,46.65 100.4,46.87 100.4,52.51 99.99,52.91 99.99,54.25 100.19,54.45 100.19,55.53 100.88,56.21 v2(100.88,56.41)
  IN3 w0.127: v2(110.45,21.24) 110.31,21.24 110.18,21.37 110.18,21.9 110.05,22.03 109.8,22.03 109.67,21.9 109.67,21.62 109.59,21.54 109.36,21.54 109.26,21.65 109.26,22.33 107.86,23.73 106.98,23.73 106.85,23.86 106.85,24.06 106.98,24.19 107.25,24.19 107.38,24.31 107.38,24.52 107.25,24.64 106.95,24.64 106.85,24.74 106.85,26.29 106.72,26.42 106.67,26.42 106.54,26.54 106.54,26.8 106.67,26.92 106.72,26.92 106.85,27.05 106.85,27.31 106.72,27.43 106.67,27.43 106.54,27.56 106.54,27.81 106.67,27.94 106.72,27.94 106.85,28.07 106.85,28.62 103.24,32.23 103.24,32.46 103.11,32.59 102.88,32.59 102.71,32.76 102.71,33 102.87,33.16 103.18,33.16 103.27,33.25 103.27,38.25 102.51,39.01 102.51,42.42 102.38,42.55 102.12,42.55 102,42.42 102,39.13 101.87,39 101.67,39 101.54,39.13 101.54,45.12 100.61,46.05 100.61,46.49
  BOTTOM w0.102: UC1.T25 100.98,56.41 v2(100.88,56.41)
DDR_A_DQ19: length 54.4
  TOP w0.117: UD2.F7 v2(112.33,21.94)
  IN3 w0.102: v2(101.87,55.65) 101.87,54.01 102.13,53.76 102.13,53.29 102.23,53.19 102.54,53.19 102.65,53.09 102.65,52.94 102.57,52.86 102.2,52.86 102.13,52.79 102.13,52.63 102.23,52.53 102.58,52.53 102.73,52.38 102.73,48.31 102.63,48.21 102.12,48.21 102.02,48.1 102.02,47.9 102.12,47.8 102.63,47.8 102.73,47.7 102.73,47.49 102.63,47.39 102.12,47.39 102.02,47.29 102.02,47.15 102.12,47.05 102.63,47.05 102.73,46.94 102.73,46.77 102.66,46.69 102.1,46.69 102,46.59 102,46.46 102.1,46.36 102.43,46.36 102.53,46.26
  IN3 w0.127: 102.53,46.26 102.56,46.23 102.56,45.97 103.65,44.88 103.65,39.48 104.41,38.72 104.41,32.68 104.6,32.49 104.78,32.49 104.86,32.57 105.04,32.57 105.22,32.39 105.22,32.21 105.14,32.13 105.14,31.95 105.32,31.77 105.5,31.77 105.67,31.94 105.9,31.94 106.06,31.79 106.06,31.61 105.86,31.41 105.86,31.23 106.04,31.05 106.22,31.05 106.89,31.72 107.07,31.72 107.23,31.55 107.23,31.34 106.58,30.69 106.58,30.51 106.75,30.33 106.93,30.33 107.68,31.09 107.86,31.09 107.99,30.96 107.99,30.67 107.3,29.97 107.3,29.79 107.42,29.66 107.55,29.66 107.76,29.88 107.86,29.88 107.99,29.75 107.99,25.63 108,25.62 107.86,25.48 107.86,25.04 108.44,24.47 108.44,24.15 109.34,23.25 110.94,23.25 111.47,22.71 111.47,21.26 111.48,21.25 111.48,20.92 111.47,20.91 111.47,20.45 111.6,20.33 111.78,20.33 111.91,20.45 111.91,21.76 112.08,21.94 v2(112.33,21.94)
  BOTTOM w0.102: UC1.T27 101.52,55.3 v2(101.87,55.65)
DDR_A_DQ20: length 54.4
  TOP w0.117: UD2.H2 107.77,20.14 v2(107.55,20.36)
  IN3 w0.102: v2(98.87,56.48) 99.17,56.48 99.32,56.33 99.32,56.18 99.23,56.09 98.72,56.09 98.48,55.85 98.48,54.68 98.77,54.39 98.77,53.85 98.42,53.5 98.01,53.5 96.77,52.26 96.77,50.66 96.97,50.46 96.97,50.25 96.77,50.06 96.77,49.85 96.97,49.65 96.97,49.44 96.77,49.25 96.77,49.04 96.97,48.84 96.97,48.63 96.77,48.43 96.77,48.22 96.97,48.03 96.97,47.82 96.77,47.62 96.77,47.41 96.97,47.21 96.97,47 96.77,46.81 96.77,46.68 96.84,46.61 97.02,46.61 97.1,46.54 97.1,46.36
  IN3 w0.127: v2(107.55,20.36) 107.55,20.67 107.39,20.82 107.21,20.82 107.13,20.73 107.13,20.5 107.06,20.43 106.88,20.43 106.77,20.53 106.77,21.28 106.56,21.48 106.2,21.48 105.63,22.06 105.32,22.06 105.15,21.88 105.15,21.6 105.58,21.16 105.58,20.92 105.45,20.8 104.9,20.8 104.77,20.92 104.77,22.59 104.27,23.09 104.27,27.98 98.39,33.86 98.39,40.24 98.52,40.36 98.7,40.36 98.82,40.24 98.82,38.66 98.95,38.54 99.15,38.54 99.28,38.66 99.28,44.18 97.85,45.62 97.38,45.62 97.1,45.9 97.1,46.36
  BOTTOM w0.102: UC1.P25 99.3,56.8 98.98,56.48 v2(98.87,56.48)
DDR_A_DQ21: length 55.2
  TOP w0.117: UD2.H3 108.57,20.13 v2(108.35,20.36)
  IN3 w0.102: 99,46.26 98.97,46.29 98.97,46.64 98.87,46.74 98.67,46.74 98.59,46.67 98.59,46.46 98.49,46.36 98.29,46.36 98.19,46.46 98.19,46.77 98.6,47.18 98.86,47.18 98.97,47.3 98.97,47.47 98.86,47.59 98.59,47.59 98.47,47.71 98.47,47.88 98.59,48 98.86,48 98.97,48.11 98.97,48.28 98.86,48.4 98.59,48.4 98.47,48.52 98.47,48.71 98.57,48.81 98.87,48.81 98.97,48.91 98.97,49.11 98.87,49.22 98.57,49.22 98.47,49.32 98.47,49.56 98.57,49.66 98.85,49.66 98.95,49.76 98.95,49.97 98.85,50.07 98.49,50.07 98.39,50.17 98.39,50.37 98.49,50.47 98.85,50.47 98.95,50.58 98.95,50.78 98.85,50.88 98.57,50.88 98.47,50.98 98.47,51.19 98.57,51.29 98.85,51.29 98.95,51.39 98.95,51.59 98.85,51.69 98.57,51.69 98.47,51.8 98.47,51.97 99.29,52.8 99.29,54.44 99.42,54.57 99.42,55.39 99.11,55.7 v2(98.87,55.7)
  IN3 w0.127: 99,46.26 99.05,46.21 99.05,45.49 100.04,44.5 100.04,34.35 99.95,34.26 99.7,34.26 99.61,34.35 99.61,36.56 99.48,36.68 99.28,36.68 99.15,36.56 99.15,34.2 105.03,28.31 105.03,23.13 105.35,22.81 105.65,22.81 106.01,22.46 106.96,22.46 107.09,22.33 107.09,21.57 107.22,21.44 107.79,21.44 107.89,21.34 107.89,20.94 108.35,20.48 v2(108.35,20.36)
  BOTTOM w0.102: v2(98.87,55.7) 98.93,55.64 100.02,55.64 UC1.R26
DDR_A_DQ22: length 54.7
  TOP w0.117: UD2.H7 111.74,19.96 110.93,20.77 110.93,20.93 v2(111.09,21.09)
  IN3 w0.102: 100.99,46.26 100.99,46.78 100.77,47 100.75,47 100.65,47.1 100.65,47.31 100.75,47.41 100.77,47.41 100.87,47.51 100.87,47.71 100.77,47.81 100.75,47.81 100.65,47.92 100.65,48.12 100.75,48.22 100.77,48.22 100.87,48.32 100.87,48.52 100.77,48.63 100.75,48.63 100.65,48.73 100.65,48.93 100.75,49.03 100.77,49.03 100.87,49.13 100.87,49.34 100.77,49.44 100.75,49.44 100.65,49.54 100.65,49.74 100.75,49.85 100.77,49.85 100.87,49.95 100.87,50.15 100.77,50.25 100.75,50.25 100.65,50.35 100.65,50.56 100.75,50.66 100.77,50.66 100.87,50.76 100.87,50.96 100.77,51.06 100.75,51.06 100.65,51.17 100.65,51.37 100.75,51.47 100.77,51.47 100.87,51.57 100.87,51.78 100.77,51.88 100.75,51.88 100.65,51.98 100.65,52.3 100.75,52.41 101.49,52.41 101.59,52.51 101.59,52.71 101.49,52.81 100.4,52.81 100.29,52.92 100.29,53.07 100.39,53.17 101.62,53.17 101.72,53.27 101.72,53.41 101.62,53.51 100.82,53.51 100.72,53.62 100.72,53.76 100.82,53.86 101.36,53.86 101.46,53.96 101.46,54.11 101.36,54.21 100.8,54.21 100.7,54.31 100.7,54.44 100.75,54.49 101.35,54.49 101.45,54.59 101.45,54.8 101.35,54.9 v2(100.87,54.9)
  IN3 w0.127: v2(111.09,21.09) 111.12,21.12 111.12,21.7 110.94,21.87 110.52,21.87 110.09,22.31 109.59,22.31 107.93,23.96 107.93,24.28 107.23,24.99 107.23,28.78 103.65,32.36 103.65,38.41 102.89,39.17 102.89,44.57 102.76,44.69 102.53,44.69 102.4,44.57 102.4,43.01 102.33,42.93 102.05,42.93 101.92,43.06 101.92,45.28 100.99,46.21 100.99,46.26
  BOTTOM w0.089: 102.27,54.9 102.61,54.9 102.73,55.02 102.73,55.22 102.66,55.3 UC1.V27
  BOTTOM w0.102: v2(100.87,54.9) 102.27,54.9
DDR_A_DQ23: length 55.3
  TOP w0.117: UD2.H8 112.37,20.34 111.95,20.34 111.95,20.34 111.8,20.34 111.62,20.51 111.52,20.61 111.52,21.42 111.42,21.52 110.97,21.52 110.84,21.65 110.84,21.82 110.94,21.93 111.4,21.93 111.52,22.04 111.52,23.12 111.44,23.21 111.21,23.21 111.09,23.09 111.09,22.41 110.97,22.29 v2(110.7,22.29)
  IN3 w0.102: v2(101.9,57.17) 101.6,57.17 101.49,57.07 101.49,55.3 101.67,55.12 101.67,53.93 101.92,53.68 101.92,52.84 101.79,52.71 101.79,52.36 101.9,52.26 102.4,52.26 102.51,52.16 102.51,51.95 102.4,51.85 101.9,51.85 101.79,51.75 101.79,51.55 101.9,51.44 102.4,51.44 102.51,51.34 102.51,51.14 102.36,51 101.9,51 101.79,50.89 101.79,50.73 101.9,50.63 102.4,50.63 102.51,50.53 102.51,50.33 102.4,50.23 101.9,50.23 101.79,50.12 101.79,49.92 101.9,49.82 102.4,49.82 102.51,49.72 102.51,49.51 102.4,49.41 101.9,49.41 101.79,49.31 101.79,49.11 101.9,49.01 102.4,49.01 102.51,48.9 102.51,48.7 102.4,48.6 101.9,48.6 101.79,48.5 101.79,46.26
  IN3 w0.127: v2(110.7,22.29) 110.78,22.21 111.05,22.21 111.17,22.34 111.17,22.66 110.91,22.92 110.71,22.92 110.48,22.69 110.3,22.69 110.07,22.92 109.92,22.92 109.69,22.69 109.51,22.69 108.15,24.05 108.15,24.37 107.55,24.97 107.55,25.93 107.61,25.99 107.61,28.94 104.03,32.52 104.03,38.56 103.27,39.33 103.27,44.72 101.79,46.2 101.79,46.26
  BOTTOM w0.102: UC1.V23 102,58.1 v2(101.9,57.17)
DDR_A_DQ24: length 54.7
  TOP w0.117: UD2.C2 107.8,23.96 107.69,24.07 107.69,24.32 107.77,24.4 109.08,24.4 v2(109.33,24.64)
  IN3 w0.102: 104.28,46.26 104.12,46.42 104.12,47.9 103.96,48.06 103.96,52.4 103.26,53.1 103.26,54.28 102.68,54.86 102.68,57.65 102.3,58.03 102.3,59.11 102.4,59.21 102.77,59.21 102.87,59.11 v2(102.87,58.8)
  IN3 w0.127: 104.28,46.26 104.37,46.17 104.37,45.84 105.25,44.96 105.25,39.99 105.55,39.69 105.55,37.52 105.72,37.35 105.98,37.35 106.11,37.48 106.11,38.92 106.23,39.05 106.49,39.05 106.62,38.92 106.62,37.48 106.74,37.35 107,37.35 107.12,37.48 107.12,38.16 107.25,38.28 107.5,38.28 107.63,38.16 107.63,37.48 107.76,37.35 108.22,37.35 110.08,35.49 110.08,32.03 109.96,31.91 109.21,31.91 109.08,31.78 109.08,31.56 109.21,31.43 109.81,31.43 109.96,31.28 109.96,31.05 109.83,30.92 109.26,30.92 109.13,30.79 109.13,30.54 109.26,30.41 109.63,30.41 109.76,30.28 109.76,30.03 109.63,29.91 109.26,29.91 109.13,29.78 109.13,29.52 109.26,29.4 109.63,29.4 109.76,29.27 109.76,29.02 109.63,28.89 109.26,28.89 109.13,28.76 109.13,28.51 109.26,28.38 109.62,28.38 109.74,28.25 109.74,28 109.62,27.87 109.26,27.87 109.13,27.75 109.13,27.49 109.26,27.37 109.62,27.37 109.74,27.24 109.74,26.98 109.62,26.86 109.26,26.86 109.13,26.73 109.13,26.57 109.26,26.45 109.63,26.45 109.76,26.32 109.76,24.71 109.63,24.58 109.39,24.58 v2(109.33,24.64)
  BOTTOM w0.102: v2(102.87,58.8) 103.27,59.2 UC1.W22
DDR_A_DQ25: length 54.5
  TOP w0.117: v2(109.2,25.99) 109.18,25.99 108.75,25.56 UD2.A3
  IN3 w0.102: v2(101.87,59.6) 101.87,59.93 101.95,60 102.38,60 102.48,60.1 102.48,60.28 102.38,60.38 101.74,60.38 101.64,60.48 101.64,60.94 101.74,61.04 101.87,61.04 101.97,61.14 101.97,61.34 101.87,61.45 101.74,61.45 101.64,61.55 101.64,61.75 101.74,61.85 101.87,61.85 101.97,61.95 101.97,62.16 101.87,62.26 101.74,62.26 101.64,62.36 101.64,62.56 101.74,62.67 101.87,62.67 101.97,62.77 101.97,62.97 101.87,63.07 101.74,63.07 101.64,63.17 101.64,63.32 101.74,63.42 101.9,63.42 102,63.52 102,63.72 101.9,63.82 101.74,63.82 101.64,63.93 101.64,64.65 101.54,64.75 101.39,64.75 101.26,64.62 101.26,58.79 102.48,57.57 102.48,54.77 103.05,54.2 103.05,53.02 103.76,52.32 103.76,47.9 103.9,47.76
  IN3 w0.127: v2(109.2,25.99) 108.84,25.99 108.75,26.08 108.75,31.28 108.49,31.54 108.49,31.78 109.7,33 109.7,35.33 108.06,36.97 105.3,36.97 105.17,37.1 105.17,39.53 104.87,39.84 104.87,44.76 103.9,45.73 103.9,47.76
  BOTTOM w0.102: v2(101.87,59.6) 102.27,60 UC1.V21
DDR_A_DQ26: length 54.5
  TOP w0.117: UD2.C7 v2(112.35,24.36)
  IN3 w0.102: v2(104.87,57.2) 105.15,57.2 105.26,57.1 105.26,54.34 106.54,53.05 106.54,51.69 106.65,51.59 107.53,51.59 107.64,51.49 107.64,51.29 107.53,51.19 106.65,51.19 106.54,51.08 106.54,50.88 106.65,50.78 107.9,50.78 108.01,50.67 108.01,50.53 107.91,50.42 106.59,50.42 106.47,50.3 106.47,50.14 106.57,50.04 108.12,50.04 108.25,49.92 108.25,49.74 108.14,49.64 106.75,49.64 106.65,49.54 106.65,49.33 106.75,49.23 107.81,49.23 107.94,49.1 107.94,48.29 106.96,47.31 106.96,47.16 107.07,47.05 107.21,47.05 107.74,47.58 107.89,47.58 108.01,47.46 108.01,47.32 107.56,46.86 107.56,46.64 107.94,46.26
  IN3 w0.127: v2(112.35,24.36) 112.75,24.76 112.75,26.62 113.83,27.7 113.83,31.28 114.99,32.44 114.99,32.58 114.72,32.85 114.72,33.03 115.03,33.33 115.03,33.52 114.8,33.75 114.8,34.05 115,34.26 115,36.95 114.93,37.02 114.17,37.02 114.04,37.15 114.04,37.33 114.24,37.53 114.88,37.53 115,37.66 115,37.93 114.88,38.05 114.29,38.05 113.66,38.69 113.66,38.98 111.51,41.13 108.4,41.13 107.94,41.58 107.94,46.26
  BOTTOM w0.102: v2(104.87,57.2) 105.27,57.6 UC1.AA24
DDR_A_DQ27: length 54.4
  TOP w0.117: v2(112.36,23.53) 112.32,23.53 111.95,23.16 UD2.D7
  IN3 w0.102: 109.1,46.54 109.1,50.49 108.55,51.03 108.55,53.19 107.94,53.8 107.94,54.34 108.37,54.77 108.37,57.64 108.17,57.84 107.51,57.84 107.28,57.61 106.26,57.61 v2(105.87,58)
  IN3 w0.127: v2(112.36,23.53) 112.16,23.32 111.73,23.32 111.52,23.53 111.52,23.83 111.65,23.96 113.8,23.96 113.91,23.84 113.91,23.22 114.04,23.09 114.32,23.09 114.39,23.17 114.39,24.01 114.85,24.47 114.85,26.24 115.04,26.43 115.04,30.82 117.1,32.88 117.1,39.08 113.58,42.6 113.58,43.64 112.59,44.63 110.25,44.63 110.16,44.73 110.16,45.12 110.03,45.24 109.78,45.24 109.65,45.12 109.65,44.23 109.78,44.1 110.07,44.1 110.2,43.97 110.2,43.79 110.07,43.67 109.21,43.67 109.1,43.78 109.1,46.54
  BOTTOM w0.102: UC1.AC23 106.27,58.4 v2(105.87,58)
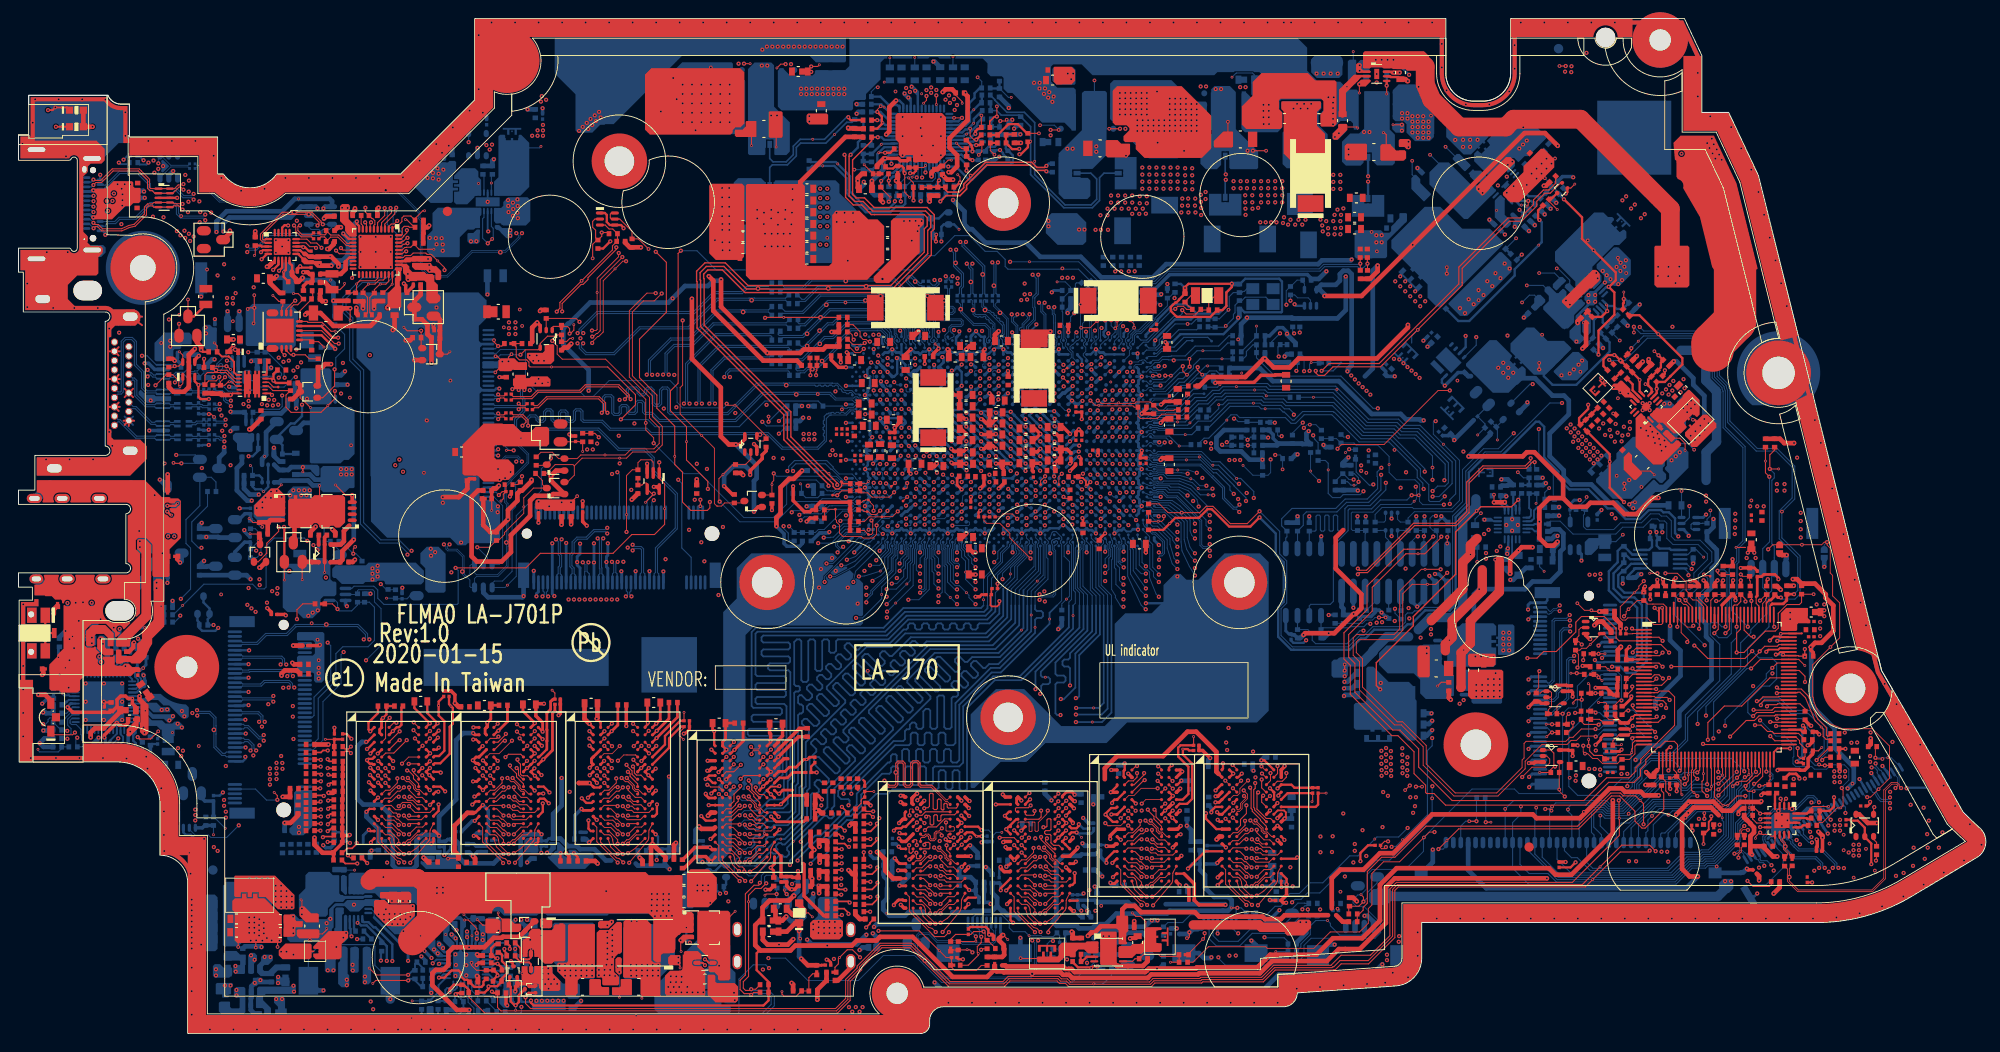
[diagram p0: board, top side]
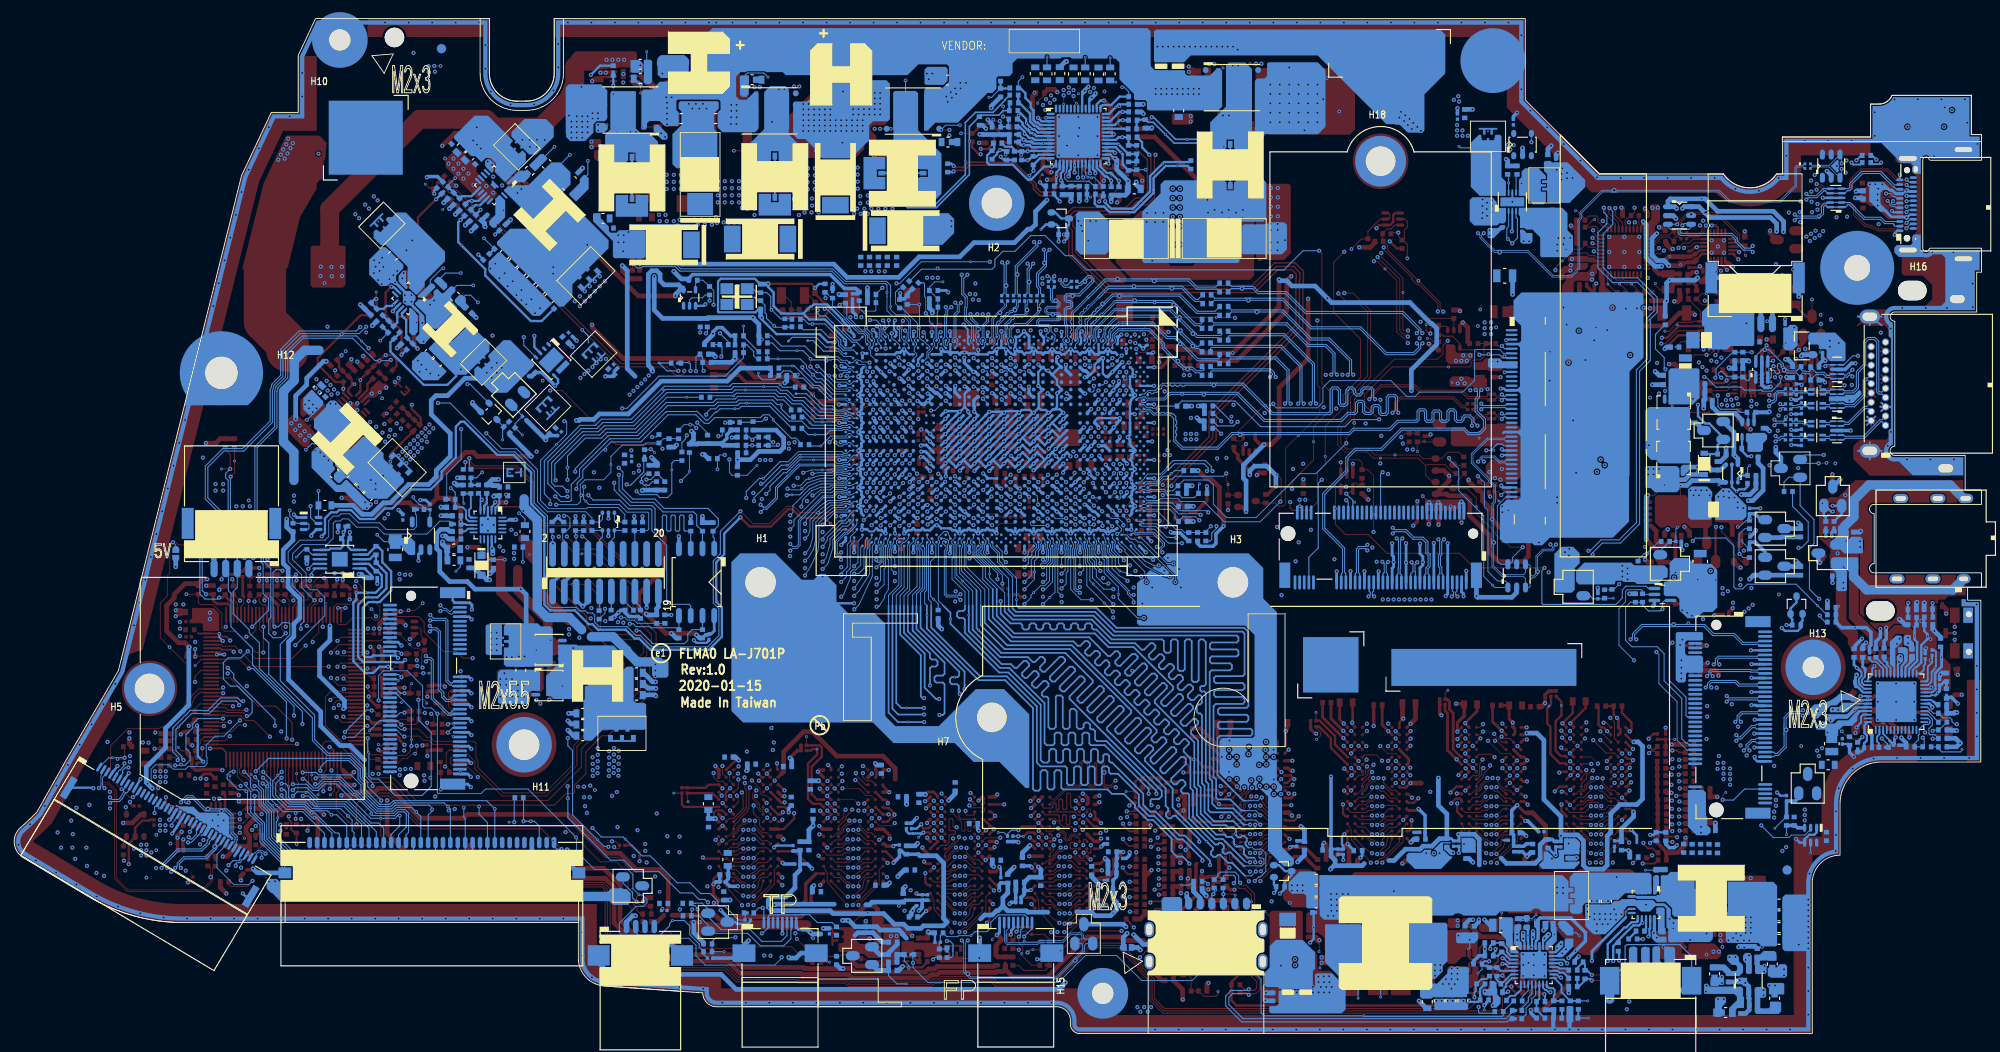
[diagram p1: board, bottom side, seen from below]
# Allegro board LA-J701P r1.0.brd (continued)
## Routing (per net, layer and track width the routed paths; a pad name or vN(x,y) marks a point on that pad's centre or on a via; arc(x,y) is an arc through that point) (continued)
DDR_A_DQ28: length 54.7
  TOP w0.117: UD2.D3 110.21,23.16 110.46,23.4 v2(110.46,24.08)
  IN3 w0.102: v2(103.87,58) 103.7,58 103.11,57.41 103.11,56.07 103.22,55.96 103.58,55.96 103.69,55.86 103.69,55.66 103.58,55.56 103.22,55.56 103.11,55.46 103.11,55.3 103.22,55.2 103.68,55.2 103.76,55.12 103.76,55.01 103.56,54.8 103.56,54.63 103.79,54.4 103.79,53.14 104.37,52.57 104.37,52.15 104.47,52.05 104.49,52.05 104.59,51.95 104.59,51.74 104.49,51.64 104.47,51.64 104.37,51.54 104.37,51.34 104.47,51.24 104.49,51.24 104.59,51.13 104.59,50.93 104.49,50.83 104.47,50.83 104.37,50.73 104.37,50.53 104.47,50.42 104.49,50.42 104.59,50.32 104.59,50.12 104.49,50.02 104.47,50.02 104.37,49.92 104.37,49.71 104.47,49.61 104.49,49.61 104.59,49.51 104.59,49.31 104.49,49.2 104.47,49.2 104.37,49.1 104.37,48.95 104.59,48.72 104.59,48.59 104.37,48.37 104.37,48.22 104.61,47.98 104.61,47.47 105.15,46.93 105.15,46.26
  IN3 w0.127: 105.15,46.26 105.15,46.16 106.01,45.29 106.01,40.31 106.52,39.81 106.84,39.81 107.48,39.17 108.6,39.17 108.73,39.05 108.73,38.81 108.4,38.49 108.4,38.31 108.58,38.13 108.76,38.13 109.27,38.63 109.45,38.63 109.67,38.41 109.67,38.18 110.1,37.75 110.33,37.75 111.34,36.74 111.34,36.56 111.22,36.43 111.1,36.43 110.89,36.22 110.89,36.06 110.97,35.98 111.5,35.98 111.62,35.85 111.62,35.6 111.5,35.47 110.97,35.47 110.85,35.35 110.85,35.09 110.97,34.97 111.5,34.97 111.62,34.84 111.62,34.58 111.5,34.46 110.97,34.46 110.85,34.33 110.85,34.08 110.97,33.95 111.5,33.95 111.62,33.82 111.62,33.57 111.5,33.44 110.97,33.44 110.85,33.31 110.85,33.06 110.97,32.93 111.5,32.93 111.62,32.81 111.62,32.55 111.5,32.43 110.97,32.43 110.85,32.3 110.85,32.04 110.97,31.92 111.5,31.92 111.62,31.79 111.62,31.54 111.5,31.41 110.97,31.41 110.85,31.28 110.85,31.09 110.99,30.95 111.46,30.95 111.55,30.86 111.55,30.66 111.42,30.54 110.65,30.54 110.52,30.41 110.52,29.77 110.61,29.68 110.61,29.18 110.52,29.1 110.52,28.75 110.61,28.66 110.61,28.17 110.52,28.08 110.52,27.74 110.61,27.65 110.61,27.15 110.52,27.06 110.52,26.72 110.61,26.63 110.61,26.14 110.52,26.05 110.52,25.7 110.68,25.54 110.68,25.2 110.52,25.03 110.52,24.15 v2(110.46,24.08)
  BOTTOM w0.102: v2(103.87,58) 103.73,58.14 103.73,58.43 103.84,58.53 104.25,58.53 UC1.Y23
DDR_A_DQ29: length 54.4
  TOP w0.117: UD2.C8 112.75,23.96 v2(113.16,24.37)
  IN3 w0.102: v2(105.87,57.2) 105.98,57.31 107,57.31 107.3,57.01 107.3,53.7 108.3,52.7 108.3,50.96 108.71,50.54 108.71,46.26
  IN3 w0.127: 108.71,46.26 108.71,42.12 108.84,41.99 109.06,41.99 109.19,42.12 109.19,43.13 109.31,43.26 109.54,43.26 109.67,43.14 109.67,42.1 109.78,41.99 110.04,41.99 110.17,42.12 110.17,43.16 110.27,43.26 110.56,43.26 110.68,43.39 110.68,44.13 110.81,44.25 111.75,44.25 111.88,44.13 111.88,43.26 111.78,43.16 111.52,43.16 111.45,43.08 111.45,42.86 111.57,42.73 112.31,42.73 112.44,42.86 112.44,43.11 112.51,43.19 112.64,43.19 112.87,43.41 113.05,43.41 113.17,43.29 113.17,43.11 113.07,43 113.07,42.47 112.94,42.35 112.54,42.35 112.41,42.22 112.41,41.97 112.54,41.84 112.92,41.84 116.72,38.04 116.72,33.04 114.61,30.93 114.61,26.85 114.48,26.73 113.96,26.73 113.83,26.6 113.83,26.33 113.92,26.24 114.37,26.24 114.54,26.07 114.54,24.92 114.34,24.72 113.29,24.72 113.16,24.59 v2(113.16,24.37)
  BOTTOM w0.102: v2(105.87,57.2) 106.27,57.6 UC1.AC24
DDR_A_DQ30: length 54.5
  TOP w0.117: UD2.C3 108.75,23.71 108.87,23.59 109.63,23.59 109.74,23.71 v2(109.74,24.06)
  IN3 w0.102: 104.77,46.26 104.77,46.8 104.41,47.16 104.41,47.89 104.16,48.14 104.16,52.48 103.46,53.19 103.46,54.37 102.91,54.92 102.91,57.5 103.37,57.95 103.37,59.79 103.47,59.9 103.8,59.9 103.9,60 103.9,60.2 103.8,60.3 103.47,60.3 103.37,60.4 103.37,64.68 103.27,64.78 103.12,64.78 103.02,64.68 103.02,64.11 102.87,63.96 102.87,63.74 103.06,63.55 103.06,63.34 102.87,63.15 102.87,62.93 103.06,62.74 103.06,62.52 102.87,62.33 102.87,62.12 103.06,61.93 103.06,61.71 102.87,61.52 102.87,61.3 103.06,61.11 103.06,60.9 102.87,60.71 102.87,60.44 103.04,60.28 103.04,59.76 v2(102.87,59.6)
  IN3 w0.127: 104.77,46.26 104.77,46 105.63,45.13 105.63,40.15 106,39.78 106,39.53 106.11,39.43 106.69,39.43 107.32,38.79 107.89,38.79 108.01,38.66 108.01,38.1 110.47,35.64 110.47,31.01 110.14,30.69 110.14,24.3 109.9,24.06 v2(109.74,24.06)
  BOTTOM w0.102: UC1.W21 103.27,60 v2(102.87,59.6)
DDR_A_DQ31: length 54.4
  TOP w0.117: v2(113.18,25.16) 112.77,24.76 UD2.B8
  IN3 w0.102: v2(104.87,58.8) 105.36,58.8 105.46,58.7 105.46,56.06 105.59,55.94 106.39,55.94 106.49,55.83 106.49,55.61 106.39,55.5 105.58,55.5 105.48,55.4 105.48,54.46 105.58,54.36 106.01,54.36 106.11,54.46 106.11,55 106.21,55.1 106.39,55.1 106.49,55 106.49,54.67 107,54.16 107,53.33 107.94,52.39 107.94,51.03 108.51,50.46 108.51,49.5 108.32,49.31 108.32,46.26
  IN3 w0.127: 108.32,46.26 108.32,41.79 108.5,41.61 110.5,41.61 110.61,41.71 110.61,41.84 110.73,41.97 111.03,41.97 111.12,41.88 111.12,41.74 111.24,41.61 111.65,41.61 112.02,41.24 112.2,41.24 112.4,41.45 112.56,41.45 112.7,41.32 112.7,41.14 112.49,40.92 112.49,40.77 112.64,40.62 112.82,40.62 113.08,40.89 113.26,40.89 113.44,40.71 113.44,40.53 113.31,40.39 113.31,40.16 113.49,39.98 113.67,39.98 113.8,40.11 113.98,40.11 114.16,39.93 114.16,39.76 114.03,39.62 114.03,39.44 114.21,39.26 114.39,39.26 114.52,39.4 114.7,39.4 114.88,39.22 114.88,39.04 114.75,38.9 114.75,38.72 115.66,37.81 115.66,37.07 115.54,36.94 115.51,36.94 115.38,36.82 115.38,36.56 115.51,36.44 116.2,36.44 116.32,36.31 116.32,36.05 116.2,35.93 115.51,35.93 115.38,35.8 115.38,35.55 115.51,35.42 116.2,35.42 116.32,35.29 116.32,35.04 116.2,34.91 115.51,34.91 115.38,34.78 115.38,34.56 115.54,34.4 116.2,34.4 116.32,34.28 116.32,34.02 116.2,33.9 115.79,33.9 115.66,33.77 115.66,33.51 115.92,33.26 115.92,32.78 114.23,31.09 114.23,27.55 113.18,26.5 v2(113.18,25.16)
  BOTTOM w0.102: v2(104.87,58.8) 105.27,59.2 UC1.AA22
DDR_A_DQ32: length 54.6
  TOP w0.089: UD3.G2 v2(119.05,23.26)
  IN3 w0.102: v2(115.87,56.39) 115.87,55.61 115.4,55.15 114.9,55.15 113.99,54.23 113.17,54.23 112.92,53.98 111.13,53.98 110.33,53.18 110.33,52.93 110.53,52.73 111.37,52.73 111.47,52.63 111.47,52.43 111.37,52.32 110.38,52.32 110.28,52.22 110.28,52.02 110.38,51.92 110.94,51.92 111.04,51.82 111.04,51.61 110.94,51.51 110.38,51.51 110.28,51.41 110.28,50.94 110.38,50.84 111.12,50.84 111.22,50.74 111.22,50.53 111.12,50.43 110.15,50.43 110.05,50.33 110.05,50.12 110.15,50.02 111.27,50.02 111.37,49.92 111.37,49.71 111.27,49.61 110.18,49.61 110.07,49.51 110.07,48.93 110.2,48.8 110.63,48.8 111.51,47.92 111.51,47.78 111,47.28 111,47.13 111.15,46.99 111.29,46.99 111.8,47.49 111.94,47.49 112.16,47.27 112.16,47.05 112,46.89 112,46.67 112.16,46.51
  IN3 w0.127: 112.16,46.51 112.56,46.11 112.56,45.9 112.69,45.78 113.25,45.78 115.28,43.74 115.28,42.75 118.24,39.79 118.24,32.41 116.18,30.35 116.18,25.38 116.7,24.85 116.7,24.26 116.88,24.08 118.18,24.08 119,23.26 v2(119.05,23.26)
  BOTTOM w0.102: UC1.AP26 115.98,56.39 v2(115.87,56.39)
DDR_A_DQ33: length 54.4
  TOP w0.117: UD3.H3 v2(119.86,23.28)
  IN3 w0.102: v2(115.85,54.92) 115.06,54.92 114.15,54.02 113.31,54.02 112.77,53.47 112.03,53.47 111.73,53.78 111.22,53.78 110.79,53.35 110.79,53.21 110.96,53.04 112.67,53.04 112.81,52.9 112.81,52.75 112.51,52.46 112.02,52.46 111.92,52.35 111.92,52.21 112.08,52.05 112.46,52.05 112.56,51.95 112.56,51.77 112.44,51.64 111.93,51.64 111.83,51.54 111.83,51.44 111.7,51.31 111.37,51.31 111.27,51.21 111.27,51.04 111.37,50.93 112.31,50.93 112.44,50.81 112.44,50.63 112.34,50.53 111.55,50.53 111.45,50.42 111.45,50.16 111.6,50.02 112.23,50.02 112.46,49.79 112.46,49.64 112.36,49.54 111.57,49.54 111.34,49.31 110.86,49.31 110.76,49.2 110.76,49.01 110.97,48.8 111.6,48.8 111.9,49.1 112.16,49.1 112.26,49 112.26,48.91 111.74,48.39 111.74,48.25 111.88,48.11 112.03,48.11 112.27,48.34 112.41,48.34 112.61,48.14 112.61,47.81 112.49,47.68 112.49,47.4 112.59,47.3 112.59,46.59 112.92,46.26
  IN3 w0.127: 112.92,46.26 113.02,46.16 113.63,46.16 115.79,44 115.79,43.01 118.62,40.17 118.62,32.25 116.69,30.32 116.69,25.4 117.21,24.88 117.21,24.53 117.34,24.4 118.98,24.4 119.86,23.52 v2(119.86,23.28)
  BOTTOM w0.102: UC1.AN27 115.47,55.3 v2(115.85,54.92)
DDR_A_DQ34: length 54.7
  TOP w0.117: v2(121.98,24.2) 121.98,24.13 122.65,23.46 122.65,23.2 123.47,22.37 UD3.J7
  IN3 w0.102: 116.27,46.64 116.27,46.87 116.39,46.98 117.34,46.98 117.44,47.08 117.44,47.29 117.34,47.39 116.59,47.39 116.32,47.66 116.32,47.76 116.45,47.88 117.59,47.88 117.67,47.96 117.67,48.09 117.47,48.29 116.63,48.29 116.53,48.39 116.53,48.85 116.63,48.95 116.92,48.95 117.03,49.07 117.03,49.26 116.93,49.36 116.63,49.36 116.53,49.46 116.53,49.76 116.61,49.85 116.93,49.85 117.03,49.95 117.03,50.15 116.93,50.25 116.61,50.25 116.5,50.35 116.5,50.56 116.61,50.66 116.99,50.66 117.1,50.76 117.1,50.96 116.99,51.06 116.61,51.06 116.5,51.17 116.5,51.37 116.61,51.47 117.04,51.47 117.17,51.59 117.17,51.75 117.03,51.88 115.87,51.88 115.61,51.62 114.88,51.62 114.8,51.69 114.8,52.28 114.9,52.38 116.19,52.38 116.26,52.46 117.64,52.46 117.79,52.6 117.79,52.95 117.69,53.06 117.08,53.06 116.98,53.16 116.98,53.41 117.08,53.51 117.69,53.51 117.79,53.62 117.79,54.84 v2(117.88,54.92)
  IN3 w0.127: v2(121.98,24.2) 121.83,24.2 121.71,24.33 121.71,25.15 121.48,25.38 121.48,25.86 121.35,25.99 120.18,25.99 119.96,25.76 119.75,25.76 119.62,25.89 119.62,26.24 119.47,26.4 118.96,26.4 118.79,26.57 118.79,27.18 118.43,27.54 118.43,27.87 118.79,28.22 118.79,28.88 118.51,29.16 118.51,29.42 120.5,31.42 120.5,42.08 119.6,42.98 119.6,43.15 119.01,43.74 118.84,43.74 118.28,44.3 118.28,44.63 117.29,45.62 117.29,45.9 117.39,46 117.39,46.31 117.24,46.46 116.45,46.46 116.27,46.64
  BOTTOM w0.102: UC1.AR27 117.5,55.3 v2(117.88,54.92)
DDR_A_DQ35: length 54.3
  TOP w0.117: v2(123.87,23.26) 123.89,23.26 UD3.H8
  IN3 w0.102: 118.8,46.38 118.94,46.51 119.5,46.51 119.76,46.77 119.76,52.45 119.15,53.06 118.86,53.06 118.79,52.99 118.79,52.51 118.74,52.46 118.48,52.46 118.35,52.58 118.35,53.42 118.46,53.52 118.69,53.52 118.79,53.62 118.79,54.31 118.49,54.6 118.49,55.31 v2(118.89,55.71)
  IN3 w0.127: v2(123.87,23.26) 123.5,23.26 123.33,23.42 123.33,25 123.14,25.19 122.76,25.19 122.14,25.81 122.14,26.43 121.92,26.65 120.59,26.65 119.42,27.82 119.42,28.53 119.99,29.1 119.99,29.83 121.4,31.24 121.4,32.76 121.56,32.91 122.32,32.91 122.39,32.99 122.39,33.33 122.3,33.42 121.56,33.42 121.4,33.57 121.4,34.21 121.53,34.33 122.28,34.33 122.47,34.52 122.47,34.85 122.33,35 121.53,35 121.4,35.12 121.4,35.9 121.5,36 122.32,36 122.42,36.1 122.42,36.4 122.32,36.5 121.5,36.5 121.4,36.61 121.4,37.44 121.53,37.57 122.27,37.57 122.39,37.7 122.39,37.98 122.29,38.08 121.53,38.08 121.4,38.21 121.4,38.46 121.53,38.59 122.27,38.59 122.39,38.71 122.39,38.94 122.24,39.1 121.53,39.1 121.4,39.22 121.4,39.48 121.53,39.6 122.06,39.6 122.14,39.68 122.14,39.91 121.94,40.11 121.73,40.11 121.48,40.37 121.48,40.49 121.61,40.62 122.37,40.62 122.47,40.72 122.47,40.98 122.32,41.13 121.43,41.13 121.33,41.23 121.33,41.48 121.48,41.64 121.85,41.64 121.98,41.76 121.98,42.02 121.85,42.14 121.73,42.14 119.14,44.73 119.14,45.1 118.8,45.43 118.8,46.38
  BOTTOM w0.102: UC1.AU26 118.67,55.71 v2(118.89,55.71)
DDR_A_DQ36: length 54.4
  TOP w0.117: UD3.J3 v2(119.86,22.48)
  IN3 w0.102: v2(115.87,57.2) 115.47,56.8 114.51,56.8 114.34,56.96 114.34,57.78 114.11,58.01 113.52,58.01 113.26,57.75 113.26,56.15 113.12,56.01 112.47,56.01 112.14,55.68 112.14,55.42 111.27,54.54 109.36,54.54 109.11,54.29 109.11,52.75 109.71,52.16 109.71,51.02 109.48,50.79 109.48,46.26
  IN3 w0.127: v2(119.86,22.48) 118.79,22.48 118.41,22.87 118.06,22.87 117.5,22.31 115.94,22.31 115.38,22.87 115.38,23.46 115.1,23.73 115.1,24.16 115.29,24.35 115.29,25.93 115.42,26.05 115.42,30.66 117.48,32.73 117.48,39.24 113.99,42.73 113.99,43.78 112.75,45.01 111.05,45.01 110.4,45.66 109.84,45.66 109.48,46.03 109.48,46.26
  BOTTOM w0.102: UC1.AN24 115.48,57.6 v2(115.87,57.2)
DDR_A_DQ37: length 54.7
  TOP w0.117: UD3.H7 123.39,22.88 122.87,23.39 122.87,24.03 v2(122.7,24.2)
  IN3 w0.102: v2(117.88,56.4) 117.99,56.4 118.28,56.11 118.28,54.76 117.99,54.47 117.99,52.33 118.1,52.22 118.92,52.22 118.99,52.15 118.99,51.95 118.87,51.82 117.74,51.82 117.61,51.69 117.61,51.44 117.69,51.36 118.87,51.36 118.99,51.24 118.99,51.04 118.91,50.95 118.1,50.95 117.99,50.85 117.99,50.68 118.13,50.55 118.92,50.55 118.99,50.47 118.99,50.27 118.87,50.14 117.89,50.14 117.79,50.04 117.79,49.84 117.89,49.74 118.91,49.74 119.03,49.61 119.03,49.41 118.96,49.33 118.1,49.33 117.99,49.23 117.99,49.16 118.23,48.92 118.85,48.92 118.98,48.8 118.98,48.59 118.9,48.52 118.1,48.52 117.99,48.41 117.99,48.3 118.18,48.11 118.88,48.11 118.98,48.01 118.98,47.81 118.88,47.7 117.94,47.7 117.84,47.6 117.84,47.4 117.94,47.3 118.87,47.3 118.97,47.19 118.97,46.97 118.89,46.89 118.02,46.89 117.9,46.77 117.9,46.67
  IN3 w0.127: v2(122.7,24.2) 122.93,24.42 122.93,24.67 121.86,25.74 121.86,26.09 121.68,26.27 120.16,26.27 120.06,26.37 120.06,26.7 119.82,26.94 119.64,26.94 119.46,26.76 119.31,26.76 119.17,26.9 119.17,28.96 119.08,29.05 119.08,29.46 120.95,31.32 120.95,42.35 118.76,44.53 118.76,44.94 118.25,45.45 118,45.45 117.9,45.55 117.9,45.83 118.02,45.96 118.3,45.96 118.42,46.08 118.42,46.37 118.32,46.47 118.02,46.47 117.9,46.59 117.9,46.67
  BOTTOM w0.102: UC1.AR25 117.47,56.8 v2(117.88,56.4)
DDR_A_DQ38: length 54.7
  TOP w0.089: UD3.H2 119.05,22.46 118,22.46
  TOP w0.117: v2(117.39,22.74) 117.67,22.46 118,22.46
  IN3 w0.102: 109.86,46.63 109.8,46.69 109.8,47.94 109.88,48.02 110.51,48.02 110.61,48.12 110.61,48.32 110.51,48.42 109.92,48.42 109.77,48.57 109.77,50.73 109.97,50.93 109.97,52.26 109.41,52.82 109.41,54.13 109.52,54.23 109.74,54.23 109.85,54.13 109.85,53.4 109.97,53.27 110.13,53.27 111.07,54.21 112.69,54.21 112.94,54.46 113.83,54.46 114.37,55 114.37,56.27 114.47,56.37 v2(114.9,56.37)
  IN3 w0.127: v2(117.39,22.74) 116.96,23.17 116.63,23.17 116.4,22.94 115.92,22.94 115.71,23.14 115.71,23.52 115.43,23.8 115.43,24.02 115.68,24.26 115.68,25.42 115.8,25.54 115.8,30.51 117.86,32.57 117.86,39.4 114.9,42.36 114.9,42.6 114.77,42.73 114.57,42.73 114.44,42.86 114.44,43.11 114.57,43.24 114.77,43.24 114.9,43.36 114.9,43.54 114.71,43.73 114.46,43.73 114.37,43.82 114.37,44.07 113.05,45.4 112.22,45.4 112.09,45.52 112.09,46.05 111.88,46.26 111.67,46.26 111.58,46.17 111.58,45.52 111.46,45.4 111.21,45.4 111.04,45.56 111.04,46.08 110.86,46.26 110.61,46.26 110.39,46.04 110,46.04 109.86,46.18 109.86,46.63
  BOTTOM w0.089: v2(114.9,56.37) 115.32,56.8 UC1.AN25
DDR_A_DQ39: length 54.5
  TOP w0.117: v2(123.87,24.85) 123.84,24.85 UD3.F7
  IN3 w0.102: v2(118.91,54.89) 119.17,54.64 119.17,53.42 119.96,52.63 119.96,50.14 120.18,49.92 120.18,46.72 119.9,46.44 119.9,46.27 119.9,46.26
  IN3 w0.127: 119.9,46.26 119.9,45.79 119.77,45.67 119.65,45.67 119.52,45.54 119.52,45.28 119.65,45.16 119.77,45.16 119.9,45.03 119.9,44.64 121.8,42.74 121.82,42.74 122.36,42.21 122.36,41.65 122.59,41.41 123.74,41.41 123.84,41.31 123.84,41 123.74,40.9 122.98,40.9 122.85,40.78 122.85,40.49 122.98,40.36 123.69,40.36 123.94,40.11 123.94,39.98 123.82,39.85 122.72,39.85 122.55,39.68 122.55,39.45 122.65,39.34 123.84,39.34 123.97,39.22 123.97,38.96 123.84,38.84 122.93,38.84 122.77,38.68 122.77,38.43 122.87,38.33 123.72,38.33 123.94,38.11 123.94,37.95 123.82,37.82 122.93,37.82 122.77,37.67 122.77,37.41 122.87,37.31 123.84,37.31 123.97,37.18 123.97,36.93 123.84,36.8 123.33,36.8 123.21,36.68 123.21,36.45 123.36,36.3 123.54,36.3 123.66,36.17 123.66,35.86 123.59,35.79 122.65,35.79 122.52,35.66 122.52,35.41 122.65,35.28 123.84,35.28 123.97,35.15 123.97,34.93 123.81,34.77 122.98,34.77 122.85,34.64 122.85,34.37 122.95,34.26 123.52,34.26 123.77,34.02 123.77,33.74 123.69,33.66 122.88,33.66 122.77,33.55 122.77,32.83 122.47,32.53 122.47,32.29 122.39,32.21 121.94,32.21 121.78,32.06 121.78,31.08 120.37,29.67 120.37,28.99 120.05,28.67 120.05,28.49 120.41,28.14 120.41,27.13 120.59,26.95 122.01,26.95 122.39,26.57 122.39,25.89 122.8,25.48 123.43,25.48 123.79,25.84 124.17,25.84 124.3,25.7 124.3,25.01 124.15,24.85 v2(123.87,24.85)
  BOTTOM w0.102: UC1.AU27 118.6,55.3 118.91,54.99 v2(118.91,54.89)
DDR_A_DQ40: length 54.6
  TOP w0.117: UD3.C2 119.47,26.88 119.89,27.3 120.42,27.3 120.82,27.7 v2(120.82,28.15)
  IN3 w0.102: v2(119.88,54.95) 119.88,53.76 120.52,53.12 120.52,50.38 120.87,50.03 120.87,47.55 121.53,46.89 121.96,46.89 122.3,46.55 122.3,46.26
  IN3 w0.127: 122.3,46.26 122.3,45.63 122.04,45.36 122.04,45.05 122.3,44.78 122.3,44.25 123.13,43.42 123.13,42.76 123.71,42.17 124.37,42.17 125.34,41.21 125.34,40.83 125.94,40.23 126.09,40.23 126.38,40.52 126.58,40.52 126.99,40.1 126.99,39.85 126.87,39.72 125.92,39.72 125.8,39.6 125.8,39.34 125.93,39.21 127.45,39.21 127.55,39.11 127.55,38.99 127.26,38.71 126.03,38.71 125.9,38.58 125.9,38.33 126.03,38.2 127.41,38.2 127.51,38.1 127.51,37.81 127.39,37.69 125.93,37.69 125.82,37.58 125.82,37.28 125.92,37.18 127.43,37.18 127.56,37.06 127.56,36.79 127.44,36.67 125.93,36.67 125.75,36.49 125.75,36.28 125.86,36.17 127.33,36.17 127.56,35.94 127.56,35.76 127.46,35.66 125.9,35.66 125.74,35.51 125.74,35.25 125.85,35.15 126.88,35.15 126.98,35.05 126.98,34.9 126.73,34.64 126.03,34.64 125.9,34.52 125.9,33.67 125.72,33.5 125.23,33.5 125.11,33.38 125.11,33.13 125.25,32.99 125.72,32.99 125.9,32.81 125.9,32.37 125.72,32.19 123.97,32.19 123.23,31.45 122.71,31.45 122.55,31.28 122.55,30.76 121.2,29.42 121.2,28.31 121.04,28.15 v2(120.82,28.15)
  BOTTOM w0.102: UC1.AV27 119.53,55.3 v2(119.88,54.95)
DDR_A_DQ41: length 54.6
  TOP w0.117: UD3.D3 121.58,27.39 v2(121.64,27.39)
  IN3 w0.102: v2(120.72,55.49) 120.51,55.28 120.51,54.18 120.63,54.07 121.2,54.07 121.31,54.17 121.31,55.63 121.41,55.73 121.61,55.73 121.71,55.63 121.71,54.15 121.83,54.03 122.11,54.03 122.22,54.13 122.22,54.62 122.34,54.74 122.57,54.74 122.65,54.67 122.65,54.16 122.75,54.06 123.03,54.06 123.1,53.98 123.1,53.68 122.57,53.14 122.29,53.14 122.16,53.01 122.16,52.8 122.26,52.7 122.44,52.7 122.55,52.6 122.55,52.39 122.44,52.29 122.26,52.29 122.16,52.19 122.16,51.99 122.26,51.89 122.44,51.89 122.55,51.78 122.55,51.58 122.44,51.48 122.03,51.48 121.9,51.35 121.9,51.15 121.98,51.07 122.44,51.07 122.55,50.97 122.55,50.77 122.44,50.67 122.26,50.67 122.16,50.57 122.16,50.36 122.26,50.26 122.44,50.26 122.55,50.16 122.55,49.96 122.44,49.85 122.26,49.85 122.16,49.75 122.16,49.55 122.26,49.45 122.44,49.45 122.55,49.35 122.55,49.14 122.44,49.04 122.26,49.04 122.16,48.94 122.16,48.2 122.28,48.07 122.43,48.07 122.63,48.27 122.77,48.27 123.13,47.91 123.13,47.69 122.71,47.28 122.71,47.09 123.23,46.57 123.23,46.26
  IN3 w0.127: 123.23,46.26 123.23,45.19 128.57,39.85 128.57,38.86 128.92,38.51 128.92,37.95 129.03,37.85 129.92,37.85 130.07,37.7 130.07,37.44 129.94,37.31 129.35,37.31 129.22,37.19 129.22,36.93 129.35,36.81 129.94,36.81 130.07,36.68 130.07,36.43 129.94,36.3 129.17,36.3 129.05,36.18 129.05,35.95 129.03,35.93 129.03,35.69 129.13,35.6 129.13,35.43 128.94,35.24 128.77,35.24 128.6,35.41 128.4,35.41 128.22,35.23 128.22,35.07 128.41,34.88 128.41,34.71 128.22,34.52 128.05,34.52 127.95,34.61 127.77,34.61 127.59,34.43 127.59,34.25 127.69,34.16 127.69,33.99 127.5,33.8 127.25,33.8 127.16,33.89 126.98,33.89 126.66,33.57 126.66,33.41 126.83,33.24 126.83,33.13 126.66,32.96 126.66,32.05 125.93,31.32 124.18,31.32 122.15,29.29 122.15,27.6 121.94,27.39 v2(121.64,27.39)
  BOTTOM w0.102: v2(120.72,55.49) 120.71,55.49 120.2,56 UC1.AW26
DDR_A_DQ42: length 54.4
  TOP w0.117: UD3.B8 v2(124.66,27.29)
  IN3 w0.102: v2(119.8,60.53) 119.8,60.37 120.09,60.09 121.29,60.09 122.14,59.24 123.99,59.24 124.32,58.91 124.32,57.04 125.9,55.46 125.9,53.09 126.03,52.96 126.03,48.83
  IN3 w0.127: v2(124.66,27.29) 125.09,26.85 125.65,26.85 125.88,26.62 125.88,25.79 125.42,25.33 125.42,24.95 125.66,24.71 128.17,24.71 128.57,25.1 128.57,27.84 129.14,28.42 129.14,30.25 129.9,31.01 129.9,31.68 130.22,32 132.13,32 133.88,33.75 133.88,37.84 131.22,40.51 131.22,41.14 126.03,46.33 126.03,48.83
  BOTTOM w0.102: v2(119.8,60.53) 119.64,60.53 119.37,60.8 UC1.AV20
DDR_A_DQ43: length 54.4
  TOP w0.117: UD3.C8 v2(124.68,26.46)
  IN3 w0.102: 126.41,48.98 126.36,49.03 126.36,55.4 124.68,57.08 124.68,59.26 124.35,59.59 122.27,59.59 121.36,60.5 v2(120.53,60.5)
  IN3 w0.127: 126.41,48.98 126.41,46.67 131.6,41.47 131.6,40.86 134.27,38.2 134.27,33.59 132.29,31.62 131.26,31.62 131.09,31.45 131.09,30.29 130.9,30.09 130.32,30.09 130.08,30.33 129.81,30.33 129.61,30.13 129.61,28.28 128.91,27.58 128.91,24.81 128.34,24.24 127.6,24.24 127.38,24.46 125.3,24.46 125.07,24.68 125.07,26.07 v2(124.68,26.46)
  BOTTOM w0.102: v2(120.53,60.5) 120.53,60.55 UC1.AW20
DDR_A_DQ44: length 54.4
  TOP w0.117: UD3.A3 120.7,28.91 v2(120.82,28.91)
  IN3 w0.102: v2(119.67,56.5) 119.42,56.25 119.42,53.65 120.31,52.76 120.31,50.29 120.54,50.07 120.54,46.61 120.62,46.53 121.26,46.53 121.36,46.43 121.36,46.26
  IN3 w0.127: 121.36,46.26 121.36,46.23 121.26,46.13 120.62,46.13 120.54,46.05 120.54,45.69 120.67,45.56 120.92,45.56 121.15,45.34 121.15,45.13 121.07,45.06 120.67,45.06 120.54,44.93 120.54,44.54 120.89,44.19 121.06,44.19 121.63,44.76 121.79,44.76 121.92,44.62 121.92,44.33 121.42,43.83 121.42,43.65 121.82,43.26 122,43.26 122.28,43.55 122.46,43.55 122.64,43.37 122.64,43.19 122.37,42.91 122.37,42.73 122.74,42.36 122.74,42.02 122.96,41.79 124.17,41.79 124.35,41.61 124.35,41.38 124.48,41.26 124.75,41.26 124.96,41.05 124.96,40.87 124.83,40.75 124.48,40.75 124.35,40.62 124.35,40.37 124.48,40.24 125.39,40.24 125.52,40.11 125.52,39.86 125.39,39.73 124.48,39.73 124.35,39.6 124.35,39.35 124.48,39.22 125.38,39.22 125.52,39.08 125.52,38.83 125.4,38.72 124.48,38.72 124.35,38.59 124.35,38.33 124.48,38.21 125.38,38.21 125.52,38.07 125.52,37.81 125.4,37.7 124.48,37.7 124.35,37.57 124.35,37.32 124.48,37.19 125.38,37.19 125.52,37.05 125.52,36.8 125.4,36.68 124.26,36.68 124.13,36.56 124.13,36.3 124.26,36.18 125.16,36.18 125.31,36.02 125.31,35.84 125.21,35.74 124.48,35.74 124.35,35.62 124.35,35.11 124.48,34.98 125.42,34.98 125.52,34.88 125.52,34.63 125.37,34.47 124.27,34.47 124.15,34.35 124.15,33.51 124.25,33.41 124.55,33.41 124.73,33.23 124.73,32.98 124.61,32.85 123.92,32.85 123.52,33.26 123.34,33.26 123.16,33.08 123.16,32.9 123.56,32.5 123.56,32.32 123.08,31.83 122.27,31.83 122.16,31.73 122.16,30.92 120.82,29.57 v2(120.82,28.91)
  BOTTOM w0.102: v2(119.67,56.5) 119.37,56.8 UC1.AV25
DDR_A_DQ45: length 54.5
  TOP w0.117: UD3.C3 120.5,26.88 121.58,27.96 v2(121.58,28.15)
  IN3 w0.102: 122.75,46.26 122.85,46.36 122.85,46.49 122.29,47.05 122.29,47.58 122.16,47.71 121.5,47.71 121.35,47.86 121.35,50.32 121.25,50.42 120.87,50.42 120.77,50.52 120.77,50.72 120.87,50.82 121.52,50.82 121.62,50.93 121.62,51.13 121.52,51.23 120.95,51.23 120.87,51.31 120.87,51.51 121,51.64 121.3,51.64 121.4,51.74 121.4,51.94 121.3,52.04 120.87,52.04 120.77,52.14 120.77,52.35 120.87,52.45 121.78,52.45 121.89,52.55 121.89,52.76 121.78,52.86 120.89,52.86 120.79,52.96 120.79,53.24 120.87,53.32 122.16,53.32 122.29,53.45 122.29,53.7 122.16,53.83 120.49,53.83 120.31,54.01 120.31,56.34 v2(120.47,56.5)
  IN3 w0.127: 122.75,46.26 122.69,46.2 122.69,45.66 122.85,45.5 122.85,44.94 122.69,44.78 122.69,44.49 122.83,44.35 123.08,44.35 123.21,44.48 123.4,44.48 123.97,43.92 123.97,43.61 123.51,43.15 123.51,42.92 123.7,42.73 123.81,42.73 124.34,43.26 124.62,43.26 125.21,42.67 125.21,42.45 125.01,42.25 125.01,42.08 125.19,41.9 125.38,41.9 125.6,42.12 125.77,42.12 126.05,41.83 126.05,41.67 125.77,41.39 125.77,41.21 125.95,41.03 126.13,41.03 126.38,41.28 126.6,41.28 127.45,40.44 127.45,39.77 127.53,39.68 128.07,39.68 128.19,39.55 128.19,39.35 127.94,39.1 127.94,38.53 128.07,38.4 128.41,38.4 128.54,38.27 128.54,38.02 128.41,37.89 128.07,37.89 127.94,37.76 127.94,37.51 128.07,37.38 128.67,37.38 128.84,37.22 128.84,36.96 128.75,36.88 128.06,36.88 127.94,36.75 127.94,36.49 128.06,36.37 128.54,36.37 128.67,36.24 128.67,36.05 128.48,35.86 128.07,35.86 127.94,35.73 127.94,35.49 127.73,35.28 127.46,35.28 127.36,35.17 127.36,34.74 126.88,34.26 126.4,34.26 126.28,34.14 126.28,32.21 125.88,31.81 124.13,31.81 121.82,29.5 121.82,28.39 v2(121.58,28.15)
  BOTTOM w0.102: v2(120.47,56.5) 120.37,56.5 120.07,56.8 UC1.AW25
DDR_A_DQ46: length 54.4
  TOP w0.117: UD3.D7 v2(123.87,26.49)
  IN3 w0.102: 125.64,48.83 125.64,55.14 125.14,55.64 125.14,55.94 124.1,56.98 124.1,58.7 123.92,58.88 122.11,58.88 121.5,59.5 v2(120.37,59.5)
  IN3 w0.127: v2(123.87,26.49) 123.61,26.75 123.61,27.01 124.31,27.71 126.01,27.71 126.38,27.34 126.38,25.18 126.56,25 128.06,25 128.22,25.16 128.22,26.05 128.27,26.1 128.27,28.03 128.77,28.53 128.77,28.86 128.3,29.33 128.3,29.95 129.52,31.17 129.52,31.84 130.06,32.38 131.97,32.38 133.5,33.91 133.5,37.54 130.84,40.2 130.84,40.84 125.64,46.03 125.64,48.83
  BOTTOM w0.102: v2(120.37,59.5) 120.07,59.8 UC1.AW21
DDR_A_DQ47: length 54.4
  TOP w0.117: UD3.C7 v2(123.05,27.3)
  IN3 w0.102: 124.79,48.83 124.79,55.85 123.76,56.89 123.76,58.31 123.61,58.45 121.28,58.45 120.78,58.95 119.53,58.95 v2(118.97,59.5)
  IN3 w0.127: 124.79,48.83 124.79,48.6 125.26,48.13 125.26,45.82 130.46,40.63 130.46,39.98 133.12,37.31 133.12,34.07 132.03,32.97 131.52,32.97 130.93,33.57 130.47,33.57 128.95,32.05 128.95,31.13 127.92,30.11 127.92,25.67 127.7,25.46 126.97,25.46 126.81,25.61 126.81,27.41 126.3,27.92 125.06,27.92 124.91,28.07 124.27,28.07 123.49,27.3 v2(123.05,27.3)
  BOTTOM w0.102: UC1.AU21 118.58,59.9 v2(118.97,59.5)
DDR_A_DQ48: length 98.3
  TOP w0.117: UD4.G2 v2(131.21,24.11)
  IN3 w0.102: 124.2,70.41 120.83,70.41 120.51,70.1 118.68,70.1 118.56,70.22 118.56,70.73 118.44,70.85 118.28,70.85 118.16,70.73 118.16,70.26 118.05,70.16 117.85,70.16 117.75,70.26 117.75,70.73 117.63,70.85 117.46,70.85 117.34,70.73 117.34,70.29 117.24,70.19 116.75,70.19 116.55,70.39 115.31,70.39 114.27,69.35 114.27,68.13 113.88,67.74 113.33,67.74 112.9,67.31 112.68,66.78 112.68,61.59 112.94,61.33 113.25,60.58 113.68,60.15 113.96,60.15 114.34,59.77 114.34,59.39 114.53,59.2 116.18,59.2 v2(116.48,59.5)
  IN3 w0.127: 124.2,70.41 128.5,70.41 129.23,69.69 129.68,69.69 130.02,70.03 130.38,70.03 135.35,67.97 137.03,66.3 137.34,65.53 138.11,64.77 138.35,64.77 143.26,59.86 143.26,44.85 143.64,44.47 143.64,34.84 143.14,34.34 143.14,28.11 138.42,23.38 137.14,22.85 136.53,22.85 136.5,22.88 134.67,22.88 133.34,24.21 131.32,24.21 v2(131.21,24.11)
  BOTTOM w0.102: UC1.AR22 v2(116.48,59.5)
DDR_A_DQ49: length 99.6
  TOP w0.117: v2(131.16,23.33) UD4.H3
  IN3 w0.102: 124.03,70.72 121.64,70.72 121.4,70.62 121.08,70.62 119.88,71.12 117.28,71.12 117.08,71.2 115.85,71.2 115.62,71.11 114.17,69.66 113.96,69.58 113.77,69.58 113.66,69.53 113.5,69.38 112.47,66.97 112.47,61.67 112.31,60.8 112.31,60.34 112.53,60.11 112.77,60.11 113.11,59.9 113.45,59.56 113.45,59.48 114.3,58.64 114.81,58.41 115.84,58.41 116.25,58.55 v2(117.32,59.45)
  IN3 w0.127: 124.03,70.72 124.19,70.78 129.56,70.78 135.57,68.3 137.35,66.51 137.67,65.75 138.15,65.26 138.61,65.07 143.65,60.03 143.65,45.04 144.02,44.67 144.02,34.69 143.52,34.19 143.52,27.95 138.64,23.07 137.14,22.27 136.97,22.19 136.39,22.07 135.86,22.07 134.52,22.7 133.33,23.89 132.99,24 132.25,24 v2(131.16,23.33)
  BOTTOM w0.102: v2(117.32,59.45) UC1.AT22
DDR_A_DQ50: length 98.7
  TOP w0.117: UD4.H8 135.25,23.24 134.78,23.24 133.77,24.25 133.77,25.93 v2(133.9,26.05)
  IN3 w0.102: 124.22,66.45 124.07,66.45 123.79,66.73 121.88,66.73 121.57,66.42 121.19,66.42 121.09,66.31 121.09,65.92 120.99,65.82 120.78,65.82 120.68,65.92 120.68,66.31 120.58,66.42 120.42,66.42 119.91,65.91 116.31,65.91 116.18,65.78 116.18,65.24 115.59,64.64 115.59,62.67 v2(115.75,62.5)
  IN3 w0.127: 124.22,66.45 124.27,66.45 124.54,66.72 125.24,66.72 125.39,66.57 125.39,66.44 125.52,66.31 125.64,66.31 126.55,65.41 126.77,65.41 126.9,65.28 126.9,65.09 127.03,64.96 127.24,64.96 127.51,65.23 127.96,65.23 128.13,65.06 128.31,65.06 128.76,65.5 128.96,65.5 129.15,65.31 129.15,65.18 128.5,64.53 128.5,64.35 128.63,64.22 128.81,64.22 129.7,65.11 129.7,65.4 129.83,65.52 130.05,65.52 130.29,65.28 130.29,64.51 129.96,64.18 129.45,64.18 129.25,63.98 129.25,63.48 129.92,62.82 129.92,62.07 130.55,61.44 131.98,61.44 132.15,61.27 132.15,60.53 132.83,59.85 133.31,59.85 133.52,60.05 133.85,60.05 134.03,59.87 134.36,59.87 134.53,60.05 134.85,60.05 134.98,59.92 134.98,59.33 135.18,59.13 135.36,59.13 135.49,59.25 135.49,59.92 135.61,60.05 137.11,60.05 138.13,59.03 139.43,59.03 139.62,58.84 139.62,58.6 139.49,58.48 138.06,58.48 137.89,58.31 137.89,58.1 138.02,57.97 139.49,57.97 139.62,57.84 139.62,57.59 139.49,57.46 137.04,57.46 136.84,57.26 136.84,57.09 136.94,56.99 138.86,56.99 138.94,56.92 138.94,56.74 138.65,56.44 137.4,56.44 137.33,56.37 137.33,55.95 137.84,55.44 137.84,55.24 137.2,54.6 136.63,54.6 136.08,54.06 136.08,53.28 136.76,52.6 136.94,52.6 137.07,52.74 137.24,52.74 137.43,52.55 137.43,52.38 137.3,52.24 137.3,52.06 137.48,51.88 137.66,51.88 137.87,52.09 138.07,52.09 138.25,51.91 138.25,51.76 138.02,51.52 138.02,51.35 138.2,51.17 138.38,51.17 138.57,51.36 138.77,51.36 138.95,51.18 138.95,50.81 138.85,50.7 138.42,50.7 138.29,50.58 138.29,50.22 138.42,50.09 138.83,50.09 138.95,49.97 138.95,44.4 138.75,44.2 138.56,44.2 138.24,43.88 138.24,42.7 139.97,40.98 139.97,29.24 137.48,26.75 136.57,26.75 136.31,27.01 135.04,27.01 134.09,26.05 v2(133.9,26.05)
  BOTTOM w0.102: UC1.AN18 115.37,62.88 v2(115.75,62.5)
DDR_A_DQ51: length 98.7
  TOP w0.117: UD4.F7 134.28,25 134.28,25.55 v2(134.44,25.7)
  IN3 w0.102: 124.22,66.93 124.05,66.93 123.95,67.04 123.95,67.19 123.84,67.29 123.64,67.29 123.54,67.19 123.54,67.04 123.44,66.93 123.23,66.93 123.13,67.04 123.13,67.19 123.03,67.29 122.83,67.29 122.73,67.19 122.73,67.04 122.63,66.93 122.42,66.93 122.32,67.04 122.32,67.19 122.22,67.29 122.02,67.29 121.91,67.19 121.91,66.99 121.86,66.93 121.8,66.93 121.48,66.62 120.17,66.62 120.06,66.5 120.06,66.34 119.82,66.11 115.73,66.11 115.29,65.68 115.29,62.38 115.77,61.89 v2(115.77,61.6)
  IN3 w0.127: 124.22,66.93 124.24,66.93 124.48,67.18 125.33,67.18 126.57,65.93 130.18,65.93 130.58,65.52 131.63,65.52 131.79,65.36 131.79,65.17 131.64,65.02 130.8,65.02 130.67,64.89 130.67,64.64 130.8,64.51 131.64,64.51 131.79,64.36 131.79,64.15 131.64,64 131.24,64 131.09,63.85 131.09,63.64 131.24,63.49 131.64,63.49 131.79,63.34 131.79,63.12 131.69,63.02 130.4,63.02 130.3,62.92 130.3,62.68 130.45,62.53 132.22,62.53 132.44,62.31 132.83,62.31 132.96,62.18 132.96,61.52 132.83,61.39 132.66,61.39 132.53,61.27 132.53,60.68 132.86,60.36 133.29,60.36 133.49,60.56 133.49,60.99 133.59,61.09 133.9,61.09 134,60.99 134,60.56 134.13,60.43 137.48,60.43 138.49,59.42 139.58,59.42 140,59 140,58.93 140.12,58.81 140.48,58.81 140.61,58.68 140.61,58.42 140.48,58.3 140.12,58.3 140,58.17 140,56.55 139.89,56.44 139.19,56.44 138.7,55.96 138.7,55.14 138.83,55.01 140,55.01 140.12,55.14 140.12,55.62 140.21,55.71 140.49,55.71 140.62,55.58 140.62,54.7 140.52,54.6 137.74,54.6 136.63,53.49 136.63,53.27 136.79,53.11 136.99,53.11 137.99,54.11 138.24,54.11 138.41,53.94 138.41,53.71 137.73,53.03 137.73,52.79 137.96,52.56 138.14,52.56 138.69,53.1 138.87,53.1 139.15,52.82 139.15,52.64 138.63,52.12 138.63,51.92 138.78,51.77 139.18,51.77 139.34,51.62 139.34,44.25 139.05,43.96 139.05,43.71 139.51,43.25 139.51,41.99 140.4,41.1 140.4,29.13 137.38,26.1 134.84,26.1 v2(134.44,25.7)
  BOTTOM w0.102: UC1.AN19 115.77,61.6 v2(115.77,61.6)
DDR_A_DQ52: length 98.8
  TOP w0.117: UD4.J3 131.99,22.49 131.99,23.13 132.63,23.77 v2(132.63,24.66)
  IN3 w0.102: v2(115.77,60.4) 115.49,60.11 114.47,60.11 113.96,60.63 113.96,61.04 113.8,61.21 113.35,61.21 112.88,61.68 112.88,66.18 114.47,67.77 114.47,68.53 114.75,68.81 115.21,68.81 115.41,69.02 115.41,69.45 115.54,69.58 116.3,69.58 116.6,69.88 120.84,69.88 121.1,69.63 123.61,69.63
  IN3 w0.127: v2(132.63,24.66) 133.25,24.66 134.48,23.42 135.53,23.42 135.8,23.7 138.2,23.7 142.76,28.27 142.76,39.51 142.91,39.66 143.1,39.66 143.25,39.8 143.25,40.01 143.1,40.16 142.91,40.16 142.76,40.31 142.76,40.52 142.91,40.67 143.1,40.67 143.25,40.82 143.25,41.03 143.1,41.18 142.91,41.18 142.76,41.33 142.76,41.54 142.91,41.69 143.1,41.69 143.25,41.84 143.25,42.05 143.1,42.2 142.91,42.2 142.76,42.34 142.76,42.52 143.15,42.91 143.15,44.4 142.88,44.67 142.88,59.7 138.19,64.39 137.93,64.39 136.61,65.7 136.41,65.7 136.07,65.36 135.58,65.36 134.49,66.45 134.49,66.68 135.16,67.35 135.16,67.54 134.99,67.71 134.8,67.71 134.08,66.99 133.9,66.99 133.73,67.15 133.73,67.36 134.16,67.78 134.16,67.96 134,68.12 133.77,68.12 133.58,67.92 133.37,67.92 133.2,68.09 133.2,68.37 133.06,68.51 130.36,69.63 130.16,69.63 129.79,69.26 129.15,69.26 128.43,69.98 123.97,69.98 123.61,69.63
  BOTTOM w0.108: v2(115.77,60.4) UC1.AP21
DDR_A_DQ53: length 98.7
  TOP w0.117: UD4.H2 130.7,22.89 v2(130.38,23.21)
  IN3 w0.102: v2(114.97,60.5) 114.38,60.5 114.16,60.71 114.16,61.56 113.14,62.59 113.14,65.85 115.4,68.12 115.4,68.6 115.61,68.81 116.08,68.81 117.03,68.81 117.22,69 120.78,69 121.17,68.62 121.6,68.62 122.23,69.25 123.89,69.25
  IN3 w0.127: 123.89,69.25 124.12,69.47 127.35,69.47 127.58,69.24 127.58,67.98 127.71,67.85 127.99,67.85 128.09,67.95 128.09,69.09 128.24,69.25 128.49,69.25 128.95,68.79 131.28,68.79 132.44,68.31 133.35,67.39 133.35,66.87 134.33,65.89 134.33,65.59 134.97,64.95 136.74,64.95 137.6,64.1 137.6,63.45 137.72,63.33 138.5,63.33 142.5,59.33 142.5,47.23 142.37,47.1 142.19,47.1 142.06,46.97 142.06,46.72 142.19,46.59 142.37,46.59 142.5,46.46 142.5,46.21 142.37,46.08 141.69,46.08 141.56,45.96 141.56,45.77 141.76,45.58 142.36,45.58 142.48,45.45 142.48,44.93 142.38,44.82 141.62,44.82 141.47,44.67 141.47,44.42 141.57,44.32 142.6,44.32 142.76,44.15 142.76,43.93 142.62,43.78 142.18,43.78 142.05,43.65 142.05,43.4 142.18,43.28 142.62,43.28 142.71,43.19 142.71,43.01 142.32,42.62 142.32,28.36 138.04,24.08 137.14,24.08 137.01,23.96 135.68,23.96 135.42,23.7 134.53,23.7 133.07,25.16 132.31,25.16 131.68,24.53 130.85,24.53 130.38,24.06 v2(130.38,23.21)
  BOTTOM w0.108: v2(114.97,60.5) 115.37,60.9 UC1.AN20
DDR_A_DQ54: length 99.3
  TOP w0.117: UD4.J7 134.8,22.39 134.16,23.02 134.16,23.13 133.26,24.02 133.26,24.21 133.14,24.34 133.14,26.47 v2(133.04,26.57)
  IN3 w0.102: v2(116.57,61.6) 116.4,61.6 116.18,61.82 116.18,62.86 116.28,62.96 116.55,62.96 116.65,63.06 116.65,63.43 116.55,63.54 116.04,63.54 115.92,63.66 115.92,64.68 116.35,65.12 117.13,65.12 117.23,65.22 117.23,65.6 117.33,65.7 117.54,65.7 117.64,65.6 117.64,65.22 117.74,65.12 119.96,65.12 120.06,65.22 120.06,65.77 120.28,65.99 120.39,65.99 120.47,65.92 120.47,65.22 120.53,65.16 120.65,65.16 120.83,65.34 120.83,65.5 120.92,65.58 121.22,65.58 121.32,65.69
  IN3 w0.127: v2(133.04,26.57) 133.34,26.27 133.56,26.27 133.74,26.45 133.79,26.45 133.9,26.56 134.27,26.56 134.94,27.23 136.41,27.23 136.43,27.22 137.41,27.22 139.58,29.39 139.58,29.46 139.59,29.47 139.59,40.8 137.86,42.52 137.86,43.57 137.61,43.82 137.04,43.82 136.91,43.95 136.91,44.18 137.02,44.29 138.11,44.29 138.57,44.75 138.57,45.48 138.45,45.61 137.94,45.61 137.77,45.77 137.77,45.95 137.94,46.12 138.45,46.12 138.57,46.25 138.57,46.51 138.45,46.63 137.85,46.63 137.75,46.74 137.75,47.04 137.86,47.14 138.45,47.14 138.57,47.27 138.57,47.52 138.45,47.65 137.88,47.65 137.75,47.77 137.75,48.03 137.88,48.16 138.45,48.16 138.57,48.28 138.57,48.54 138.45,48.67 137.9,48.67 137.75,48.82 137.75,49.07 137.85,49.17 138.45,49.17 138.57,49.3 138.57,49.61 138.47,49.71 137.86,49.71 137.75,49.82 137.75,50.22 137.91,50.38 137.91,50.91 135.24,53.58 135.24,53.76 136.25,54.76 136.25,54.99 136.34,55.09 137.12,55.09 137.27,55.24 137.27,55.42 137.1,55.59 136.57,55.59 136.47,55.7 136.47,56.01 136.55,56.1 136.84,56.1 136.95,56.21 136.95,56.48 136.82,56.61 136.37,56.61 136.25,56.74 136.25,57.2 137.74,58.7 137.74,58.88 137.62,59.01 137.44,59.01 136.3,57.86 136.01,57.86 135.83,58.04 135.83,58.22 136.83,59.22 136.83,59.4 136.65,59.58 136.47,59.58 135.34,58.45 135.16,58.45 134.14,59.47 132.55,59.47 131.77,60.25 131.77,60.93 131.64,61.05 130.36,61.05 127.67,63.75 127.67,63.93 128.17,64.43 128.17,64.61 127.98,64.79 127.61,64.79 127.21,64.39 127.03,64.39 125.73,65.69 125.23,65.69 125.1,65.82 125.1,66.31 124.95,66.46 124.7,66.46 124.57,66.34 124.57,65.83 124.45,65.7 124.03,65.7 123.9,65.83 123.9,66.27 123.73,66.44 123.12,66.44 122.95,66.27 122.95,65.83 122.83,65.7 122.67,65.7 122.56,65.81 122.56,66.38 122.43,66.5 122.24,66.5 122.11,66.38 122.11,65.67 122.03,65.59 121.83,65.59 121.73,65.69 121.73,66.1 121.63,66.2 121.42,66.2 121.32,66.1 121.32,65.69
  BOTTOM w0.102: v2(116.57,61.6) 116.18,62 UC1.AP19
DDR_A_DQ55: length 99
  TOP w0.117: UD4.H7 134.59,23.1 134.58,23.1 133.52,24.16 133.52,24.34 133.42,24.43 133.42,26.34 133.58,26.5 v2(133.58,27.07)
  IN3 w0.102: v2(117.9,58.37) 118.41,58.37 118.57,58.54 118.57,59.81 118.72,59.96 119.1,59.96 119.42,60.28 119.42,60.65 119.17,60.9 118.54,60.9 118.34,61.11 118.03,61.11 117.77,61.36 117.77,61.93 117.64,62.06 117.07,62.06 116.97,62.16 116.97,63.49 116.12,64.34 116.12,64.6 116.44,64.92 120.7,64.92 121.17,65.38 121.79,65.38 121.89,65.28 121.89,65.03 121.99,64.93 122.19,64.93 122.29,65.03 122.29,65.28 122.4,65.38 122.6,65.38 122.7,65.28 122.7,65.03 122.8,64.93 123.01,64.93 123.11,65.03 123.11,65.28 123.21,65.38 123.41,65.38 123.51,65.28 123.51,65.03 123.62,64.93 123.82,64.93 123.92,65.03 123.92,65.18 124.13,65.4
  IN3 w0.127: v2(133.58,27.07) 133.85,26.8 134.18,26.8 134.84,27.46 135.91,27.46 136.29,27.84 136.47,27.84 136.67,27.64 137.2,27.64 139.2,29.63 139.2,30.7 139.21,30.71 139.21,40.52 137.48,42.25 137.48,43.25 137.29,43.44 136.66,43.44 136.53,43.56 136.53,44.56 136.63,44.67 137.84,44.67 138.04,44.87 138.04,45.03 137.82,45.25 137.4,45.25 137.27,45.37 137.27,51.02 133.85,54.44 133.73,54.44 132.3,55.87 132.3,56.87 132.43,57 133.42,57 133.51,56.91 133.51,56.53 133.44,56.46 133.03,56.46 132.91,56.34 132.91,56.16 134.37,54.69 135.64,54.69 135.87,54.92 135.87,55.14 135.72,55.29 134.73,55.29 134.59,55.44 134.59,55.65 134.73,55.8 135.94,55.8 136.08,55.95 136.08,56.16 135.94,56.3 134.79,56.3 134.64,56.45 134.64,56.66 134.79,56.81 135.72,56.81 135.87,56.96 135.87,57.2 135.22,57.85 135.01,57.85 134.16,57 133.95,57 133.8,57.15 133.8,57.36 134.65,58.21 134.65,58.42 134.46,58.61 134.27,58.61 133.95,58.29 133.79,58.29 133.61,58.47 133.61,58.67 133.83,58.89 133.83,58.99 133.74,59.09 132.56,59.09 132.05,58.58 131.79,58.58 131.1,59.26 131.1,59.77 131,59.87 131,60.05 131.27,60.31 131.27,60.52 131.14,60.65 130.96,60.65 130.68,60.37 130.5,60.37 125.48,65.4 124.13,65.4
  BOTTOM w0.102: UC1.AU23 118.27,58 v2(117.9,58.37)
DDR_A_DQ56: length 54.5
  TOP w0.117: UD4.A3 131.59,28.57 v2(131.14,29.02)
  IN3 w0.102: v2(118.97,61.56) 119.31,61.9 120.65,61.9 120.76,61.79 122.02,61.79 122.38,61.44 122.38,61.3 121.95,60.87 121.95,60.73 122.09,60.58 122.24,60.58 122.56,60.9 122.91,60.9 123.13,60.69 123.77,60.69 124.04,60.41 124.17,60.41 124.5,60.74 124.65,60.74 125.29,60.1 125.29,57.99 127.54,55.75 127.54,53.24 127.37,53.07 127.02,53.07 126.91,52.97 126.91,52.77 127.02,52.67 127.37,52.67 127.51,52.53 127.51,49.24
  IN3 w0.127: 127.51,49.24 127.4,49.13 127.4,46.89 130.32,43.97 130.4,43.97 130.49,44.06 130.77,44.06 130.9,43.93 130.9,43.75 130.81,43.66 130.81,43.48 130.99,43.3 131.17,43.3 132.02,44.15 132.25,44.15 132.36,44.04 132.36,43.78 131.53,42.95 131.53,42.77 131.71,42.59 131.89,42.59 132.13,42.83 132.27,42.83 132.36,42.74 132.36,41.42 135.03,38.76 135.03,33.28 134.79,33.04 134.79,32.86 134.97,32.67 134.97,32.49 134.79,32.31 134.61,32.31 134.43,32.5 134.25,32.5 134.07,32.32 134.07,32.14 134.25,31.96 134.25,31.78 134.07,31.6 133.89,31.6 133.71,31.78 133.53,31.78 132.6,30.85 131.98,30.85 131.85,30.73 131.85,30.49 131.98,30.36 132.22,30.36 132.35,30.24 132.35,29.98 132.22,29.85 131.98,29.85 131.85,29.73 131.85,29.7 131.85,29.15 131.73,29.02 v2(131.14,29.02)
  BOTTOM w0.102: v2(118.97,61.56) 118.58,61.96 UC1.AU19
DDR_A_DQ57: length 54.5
  TOP w0.089: UD4.C2 v2(130.35,27.33)
  IN3 w0.127: v2(130.35,27.33) 130.35,24.86 130.14,24.64 129.91,24.64 129.68,24.87 129.68,27.74 130.52,28.58 130.52,29.55 130.69,29.71 131.06,29.71 131.47,30.13 131.47,31.11 131.6,31.23 132.44,31.23 134.65,33.44 134.65,38.5 131.98,41.17 131.98,41.77 126.94,46.81 126.94,48.95 126.68,49.21 126.68,55.45 126.86,55.64 126.86,55.94 126.64,56.16 126.48,56.16 126.32,56 126.14,56 125.96,56.18 125.96,56.36 126.12,56.53 126.12,56.73 125.95,56.9 125.77,56.9 125.62,56.75 125.44,56.75 125.26,56.93 125.26,57.11 125.41,57.26 125.41,57.44 125.04,57.82 125.04,59.87 124.59,60.32 124.41,60.32 124.32,60.23 124.32,60.05 124.2,59.92 123.94,59.92 123.81,60.05 123.81,60.27 123.69,60.39 123.21,60.39 122.74,59.92 122.37,59.92 121.72,60.57 121.72,61.31 121.53,61.5 v2(120.37,61.5)
  BOTTOM w0.102: v2(120.37,61.5) 120.07,61.8 UC1.AW19
DDR_A_DQ58: length 54.8
  TOP w0.117: v2(136.95,28.15) 136.95,27.7 136.5,27.26 135.96,27.26 UD4.C8
  IN3 w0.102: v2(120.37,64.5) 120.45,64.57 121.49,64.57 121.59,64.67 123.99,64.67 124.22,64.9
  IN3 w0.127: v2(136.95,28.15) 137.17,28.15 138.02,29 138.02,29.18 137.75,29.45 137.75,29.63 137.94,29.82 138.1,29.82 138.38,29.54 138.56,29.54 138.8,29.78 138.8,30.87 138.83,30.89 138.83,40.36 137.1,42.09 137.1,42.75 136.92,42.93 136.34,42.93 136.15,43.12 136.15,44.95 136.25,45.05 136.76,45.05 136.89,45.18 136.89,45.43 136.76,45.56 136.3,45.56 136.15,45.71 136.15,45.85 136.36,46.06 136.76,46.06 136.89,46.19 136.89,50.86 133.74,54.01 133.62,54.01 131.17,56.46 131.17,57.62 130.72,58.07 130.72,59.62 125.27,65.07 124.39,65.07 124.22,64.9
  BOTTOM w0.102: v2(120.37,64.5) 120.07,64.2 UC1.AW16
DDR_A_DQ59: length 54.7
  TOP w0.117: v2(134.28,27.45) 134.28,26.55 134.74,26.09 UD4.D7
  IN3 w0.102: 124.22,64.45 121.76,64.45 121.64,64.33 120.81,64.33 120.58,64.1 119.53,64.1 v2(118.97,64.5)
  IN3 w0.127: v2(134.28,27.45) 134.56,27.73 135.64,27.73 136.44,28.53 136.93,28.53 137.14,28.74 137.14,29.76 138.43,31.06 138.43,40.2 135.77,42.86 135.77,46.01 136.51,46.75 136.51,50.7 133.59,53.62 133.46,53.62 130.79,56.28 130.79,57.46 130.34,57.91 130.34,59.46 125.35,64.45 124.22,64.45
  BOTTOM w0.102: v2(118.97,64.5) 118.68,64.2 118.58,64.1 UC1.AU16
DDR_A_DQ60: length 54.4
  TOP w0.089: UD4.C3 131.63,26.89 v2(132.06,27.32)
  IN3 w0.102: 128.25,49.01 128.25,49.19 128.2,49.24 128.15,49.24 128.06,49.33 128.06,49.58 128.16,49.68 128.36,49.68 128.46,49.78 128.46,49.98 128.36,50.08 128.16,50.08 128.06,50.19 128.06,56.18 127.96,56.29 127.8,56.29 127.7,56.39 127.7,56.59 127.8,56.69 128.02,56.69 128.12,56.79 128.12,57.04 127.71,57.46 127.45,57.46 127.33,57.58 127.33,57.83 126.48,58.68 125.87,58.68 125.77,58.78 125.77,59.14 125.87,59.24 125.97,59.24 126.05,59.31 126.05,59.64 125.95,59.75 125.85,59.75 125.75,59.85 125.75,60.22 125.27,60.69 125.27,60.84 125.63,61.19 125.63,61.34 125.48,61.48 125.34,61.48 124.99,61.12 124.84,61.12 124.61,61.36 124.61,61.75 124.5,61.85 124.3,61.85 124.2,61.75 124.2,61.36 124.08,61.24 123.21,61.24 122.1,62.35 120.52,62.35 v2(120.37,62.5)
  IN3 w0.127: 128.25,49.01 128.25,47.16 130.42,44.99 132.97,44.99 133.12,44.84 133.12,41.74 135.79,39.07 135.79,32.23 133.61,30.05 133.29,30.05 133.11,29.88 133.11,29.56 132,28.44 131.95,28.44 131.7,28.19 131.7,27.93 131.44,27.67 131.44,26.85 131.71,26.57 131.97,26.57 132.25,26.85 132.25,27.13 v2(132.06,27.32)
  BOTTOM w0.102: UC1.AW18 120.07,62.8 v2(120.37,62.5)
DDR_A_DQ61: length 54.4
  TOP w0.117: v2(131.18,26.51) UD4.D3
  IN3 w0.102: 127.8,48.98 127.8,55.96 125.54,58.22 125.54,60.14 124.64,61.04 123.12,61.04 122.06,62.1 118.71,62.1 v2(118.18,61.56)
  IN3 w0.127: v2(131.18,26.51) 131.61,26.07 131.61,25.91 131.49,25.79 130.7,25.79 130.57,25.92 130.57,26.75 131.03,27.21 131.03,27.41 130.6,27.84 130.6,28.2 130.93,28.53 131.55,28.53 132.73,29.71 132.73,30.44 133.18,30.89 133.91,30.89 135.41,32.39 135.41,38.91 132.74,41.58 132.74,44.45 132.65,44.53 130.3,44.53 127.8,47.03 127.8,48.98
  BOTTOM w0.102: v2(118.18,61.56) 117.77,61.96 UC1.AT19
DDR_A_DQ62: length 54.5
  TOP w0.117: UD4.B8 136,28.09 v2(136,28.91)
  IN3 w0.102: v2(118.18,64.5) 118.8,63.87 120.64,63.87 120.89,64.13 122.29,64.13 122.92,63.5 124.07,63.5
  IN3 w0.127: 124.07,63.5 124.22,63.35 125.87,63.35 129.96,59.27 129.96,57.75 130.41,57.3 130.41,54.93 130.56,54.78 130.74,54.78 131.01,55.05 131.18,55.05 131.35,54.88 131.35,54.67 131.1,54.42 131.1,54.24 131.28,54.06 131.46,54.06 131.86,54.47 132.04,54.47 132.22,54.29 132.22,54.11 131.82,53.7 131.82,53.52 132.1,53.23 133.43,53.23 136.13,50.54 136.13,46.9 135.39,46.16 135.39,42.68 138.05,40.01 138.05,31.22 136,29.16 v2(136,28.91)
  BOTTOM w0.102: v2(118.18,64.5) 117.77,64.1 UC1.AT16
DDR_A_DQ63: length 54.5
  TOP w0.117: v2(135.23,28.15) 135.23,27.33 UD4.C7
  IN3 w0.102: v2(116.57,64.5) 116.57,64.37 117.42,63.53 120.7,63.53 121.02,63.85 121.95,63.85 122.1,63.7 122.32,63.7 122.82,63.2 123.68,63.2 123.86,63.02 125.61,63.02 129.05,59.57
  IN3 w0.127: v2(135.23,28.15) 135.23,28.21 135.55,28.53 135.55,29.25 137.67,31.38 137.67,39.85 135,42.52 135,46.32 135.74,47.06 135.74,50.36 133.25,52.85 131.65,52.85 130.03,54.47 130.03,57.06 129.57,57.52 129.57,59.06 129.05,59.57
  BOTTOM w0.102: UC1.AP16 116.18,64.1 v2(116.57,64.5)
DDR_A_DQS0: length 54.7
  TOP w0.102: UD1.G3 97.43,21.07 97.54,21.18 97.87,21.18 98.05,21.36 98.21,21.36 98.31,21.25 98.31,21.05 98.53,20.83 98.9,20.83 99.1,21.03 99.1,21.58 99.2,21.68 99.62,21.68 99.72,21.58 v2(99.72,21.4)
  IN3 w0.102: v2(97.9,57.27) 97.87,57.27 97.72,57.12 97.72,56.86 97.01,56.15 96.75,56.15 96.46,55.86 96.46,54.72 95.95,54.21 95.95,53.29 94.44,51.78 94.44,51.61 94.73,51.31 94.73,50.6 94.44,50.31 94.44,49.41 93.12,48.09 93.12,47.87 93.36,47.63 93.36,47.21 92.98,46.83 92.98,46.63 93.12,46.49 93.12,46.3 93.13,46.29 93.13,46.26
  IN3 w0.135: 93.13,46.26 93.13,45.01 93.75,44.39 93.93,44.21 94.77,44.21 95.06,43.92 95.06,43.16 94.8,42.89 94.21,42.89 93.98,42.66 93.98,42.43 94.12,42.3 94.9,42.3 95.16,42.03 95.16,41.44 94.9,41.18 94.19,41.18 93.92,40.91 93.92,40.56 94.05,40.42 94.87,40.42 95.13,40.16 95.13,39.72 94.79,39.39 94.05,39.39 93.92,39.25 93.92,38.85 94.05,38.71 94.9,38.71 95.16,38.45 95.16,37.91 94.9,37.64 94.1,37.64 93.92,37.46 93.92,34.02 101.01,26.93 101.01,22.37 100.34,21.7 100.02,21.7 v2(99.72,21.4)
  BOTTOM w0.102: UC1.M25 97.84,57.27 v2(97.9,57.27)
DDR_A_DQS0#: length 54.7
  TOP w0.102: UD1.F3 97.63,21.37 97.79,21.37 97.97,21.55 98.29,21.55 98.5,21.33 98.5,21.13 98.61,21.02 98.82,21.02 98.91,21.11 98.91,21.66 99.12,21.87 99.43,21.87 v2(99.74,22.18)
  IN3 w0.102: 92.91,46.26 92.91,46.29 92.92,46.3 92.92,46.4 92.78,46.54 92.78,46.91 93.16,47.29 93.16,47.55 92.92,47.78 92.92,48.18 94.24,49.5 94.24,50.39 94.53,50.69 94.53,51.23 94.24,51.52 94.24,51.86 95.75,53.37 95.75,54.29 96.26,54.8 96.26,55.94 96.67,56.36 96.92,56.36 97.51,56.95 97.51,57.49 97.9,57.87 v2(97.9,57.99)
  IN3 w0.135: 92.91,46.26 92.91,44.92 93.84,43.99 94.68,43.99 94.84,43.83 94.84,43.25 94.71,43.12 94.12,43.12 93.76,42.76 93.76,42.34 94.03,42.08 94.8,42.08 94.94,41.94 94.94,41.54 94.8,41.4 94.09,41.4 93.7,41.01 93.7,40.47 93.96,40.2 94.77,40.2 94.91,40.07 94.91,39.82 94.7,39.61 93.96,39.61 93.7,39.34 93.7,38.75 93.96,38.49 94.8,38.49 94.94,38.35 94.94,38 94.8,37.86 94.01,37.86 93.7,37.55 93.7,33.92 100.78,26.84 100.78,22.46 100.24,21.93 99.99,21.93 v2(99.74,22.18)
  BOTTOM w0.102: v2(97.9,57.99) 97.5,57.6 UC1.M24
DDR_A_DQS1: length 65.1
  TOP w0.089: UD1.B7 100.31,25.08 100.14,25.08 98.97,26.25 98.95,26.25 98.93,26.26
  TOP w0.119: 98.93,26.26 98.57,26.62 97.42,26.62 97.17,26.87 97.17,29.15 97.06,29.27 96.7,29.27 96.58,29.15 96.58,26.87 96.34,26.62 95.81,26.62 95.56,26.87 95.56,29.12 95.44,29.24 95.09,29.24 94.97,29.12 94.97,28.64 95,28.61 95,27.75 94.97,27.73 94.97,26.87 94.73,26.62 93.96,26.62 93.83,26.75 93.66,26.75 v2(93.51,26.6)
  IN3 w0.102: v2(99.87,59.6) 99.26,60.22 96.72,60.22 96.38,59.88 96.38,59.12 96.07,58.8 95.72,58.8 95.39,58.48 95.39,58.13 94.76,57.5 94.45,57.5 94.06,57.12 92.1,57.12 89.31,54.33 89.31,53.7 86.04,50.43 86.01,50.43
  IN3 w0.135: 86.01,50.43 85.86,50.27 85.86,50.27 85.44,49.85 85.44,34.4 93.23,26.6 v2(93.51,26.6)
  BOTTOM w0.102: UC1.P22 99.78,59.6 v2(99.87,59.6)
DDR_A_DQS1#: length 65
  TOP w0.089: UD1.A7 100.34,25.26 100.21,25.26 99.1,26.37 99.1,26.4 99.08,26.41
  TOP w0.119: 99.08,26.41 98.66,26.83 97.5,26.83 97.38,26.95 97.38,29.23 97.14,29.47 96.61,29.47 96.37,29.23 96.37,26.95 96.25,26.83 95.89,26.83 95.77,26.95 95.77,29.21 95.53,29.45 95,29.45 94.76,29.21 v4(94.76,28.22) 94.76,26.95 94.64,26.83 94.04,26.83 v2(93.54,27.34)
  IN3 w0.102: v2(98.87,59.6) 98.87,59.52 98.98,59.42 99.38,59.42 99.48,59.52 99.48,59.7 99.17,60.01 96.8,60.01 96.59,59.8 96.59,59.03 96.15,58.6 95.81,58.6 95.6,58.39 95.6,58.04 94.85,57.3 94.53,57.3 94.15,56.91 92.18,56.91 89.51,54.25 89.51,53.61 86.01,50.11
  IN3 w0.135: v2(93.54,27.34) 93.54,27.26 93.33,27.05 93.1,27.05 85.66,34.49 85.66,49.76 86.01,50.11
  BOTTOM w0.102: v2(98.87,59.6) 99.27,60 UC1.P21
DDR_A_DQS2: length 53.7
  TOP w0.102: UD2.G3 v2(109.15,21.16)
  IN3 w0.102: v2(100.87,57.2) 100.5,56.82 100.5,56.12 99.89,55.51 99.89,54.46 99.74,54.31 99.74,52.85 100.19,52.39 100.19,47.68 100,47.49 100,46.58 100.02,46.56 100.02,46.38 99.98,46.34 99.98,46.31 99.97,46.3
  IN3 w0.135: v2(109.15,21.16) 109.01,21.3 109.01,22.18 108.17,23.01 106.36,23.01 106.03,23.34 106.03,24.02 106.54,24.53 106.54,24.9 105.9,25.54 105.9,28.67 100.91,33.66 100.91,37.28 101.04,37.42 101.43,37.42 101.57,37.28 101.57,33.85 101.83,33.59 102.36,33.59 102.63,33.85 102.63,37.98 102.25,38.36 101.04,38.36 100.91,38.49 100.91,44.86 99.91,45.85 99.91,46.23 99.97,46.29 99.97,46.3
  BOTTOM w0.102: UC1.T24 101.27,57.6 v2(100.87,57.2)
DDR_A_DQS2#: length 53.8
  TOP w0.102: UD2.F3 108.37,21.18 v2(108.37,21.16)
  IN3 w0.102: 99.8,46.47 99.8,47.57 99.99,47.77 99.99,52.31 99.53,52.77 99.53,54.39 99.69,54.55 99.69,55.59 100.3,56.2 100.3,56.8 v2(99.88,57.22)
  IN3 w0.135: 99.8,46.47 99.76,46.43 99.76,46.41 99.69,46.34 99.69,45.76 100.68,44.76 100.68,38.4 100.95,38.14 102.16,38.14 102.4,37.89 102.4,33.95 102.27,33.81 101.92,33.81 101.79,33.95 101.79,37.38 101.52,37.64 100.95,37.64 100.68,37.38 100.68,33.57 105.67,28.58 105.67,25.45 106.32,24.81 106.32,24.62 105.81,24.11 105.81,23.25 106.26,22.79 108.08,22.79 108.78,22.09 108.78,21.58 v2(108.37,21.16)
  BOTTOM w0.102: UC1.R24 100.26,57.6 v2(99.88,57.22)
DDR_A_DQS3: length 53.5
  TOP w0.102: UD2.B7 111.98,24.76 v2(112.31,25.1)
  IN3 w0.102: v2(104.87,60.4) 104.78,60.4 104.29,59.91 104.29,56.07 104.8,55.56 104.8,54.16 105.99,52.98 105.99,50.42 105.89,50.32 105.27,50.32 105.05,50.1 105.05,49.76 105.48,49.32 105.48,49.19 105.05,48.76 105.05,47.83 105.35,47.52 105.7,47.52 106.86,48.68 107.01,48.68 107.26,48.44 107.26,48.29 106.34,47.37 106.34,47.07 107.03,46.38 107.03,46.26
  IN3 w0.135: v2(112.31,25.1) 112.22,25.1 111.64,25.68 111.64,27.63 111.91,27.89 112.76,27.89 112.97,28.11 112.97,28.34 112.84,28.47 111.9,28.47 111.64,28.74 111.64,29.31 111.9,29.57 112.54,29.57 112.67,29.71 112.67,31.93 112.94,32.19 113.53,32.19 113.66,32.33 113.66,32.6 113.53,32.73 112.94,32.73 112.67,33 112.67,33.49 112.94,33.76 113.14,33.76 113.27,33.89 113.27,36.49 112.28,37.48 112.28,38.2 112.66,38.57 112.66,38.76 112.46,38.96 112.27,38.96 112.13,38.81 111.75,38.81 111.34,39.21 111.34,39.59 111.48,39.72 111.48,39.91 111.29,40.11 111.1,40.11 110.96,39.97 110.59,39.97 110.36,40.19 108.09,40.19 107.03,41.25 107.03,46.26
  BOTTOM w0.102: UC1.AA21 105.32,60 104.92,60.4 v2(104.87,60.4)
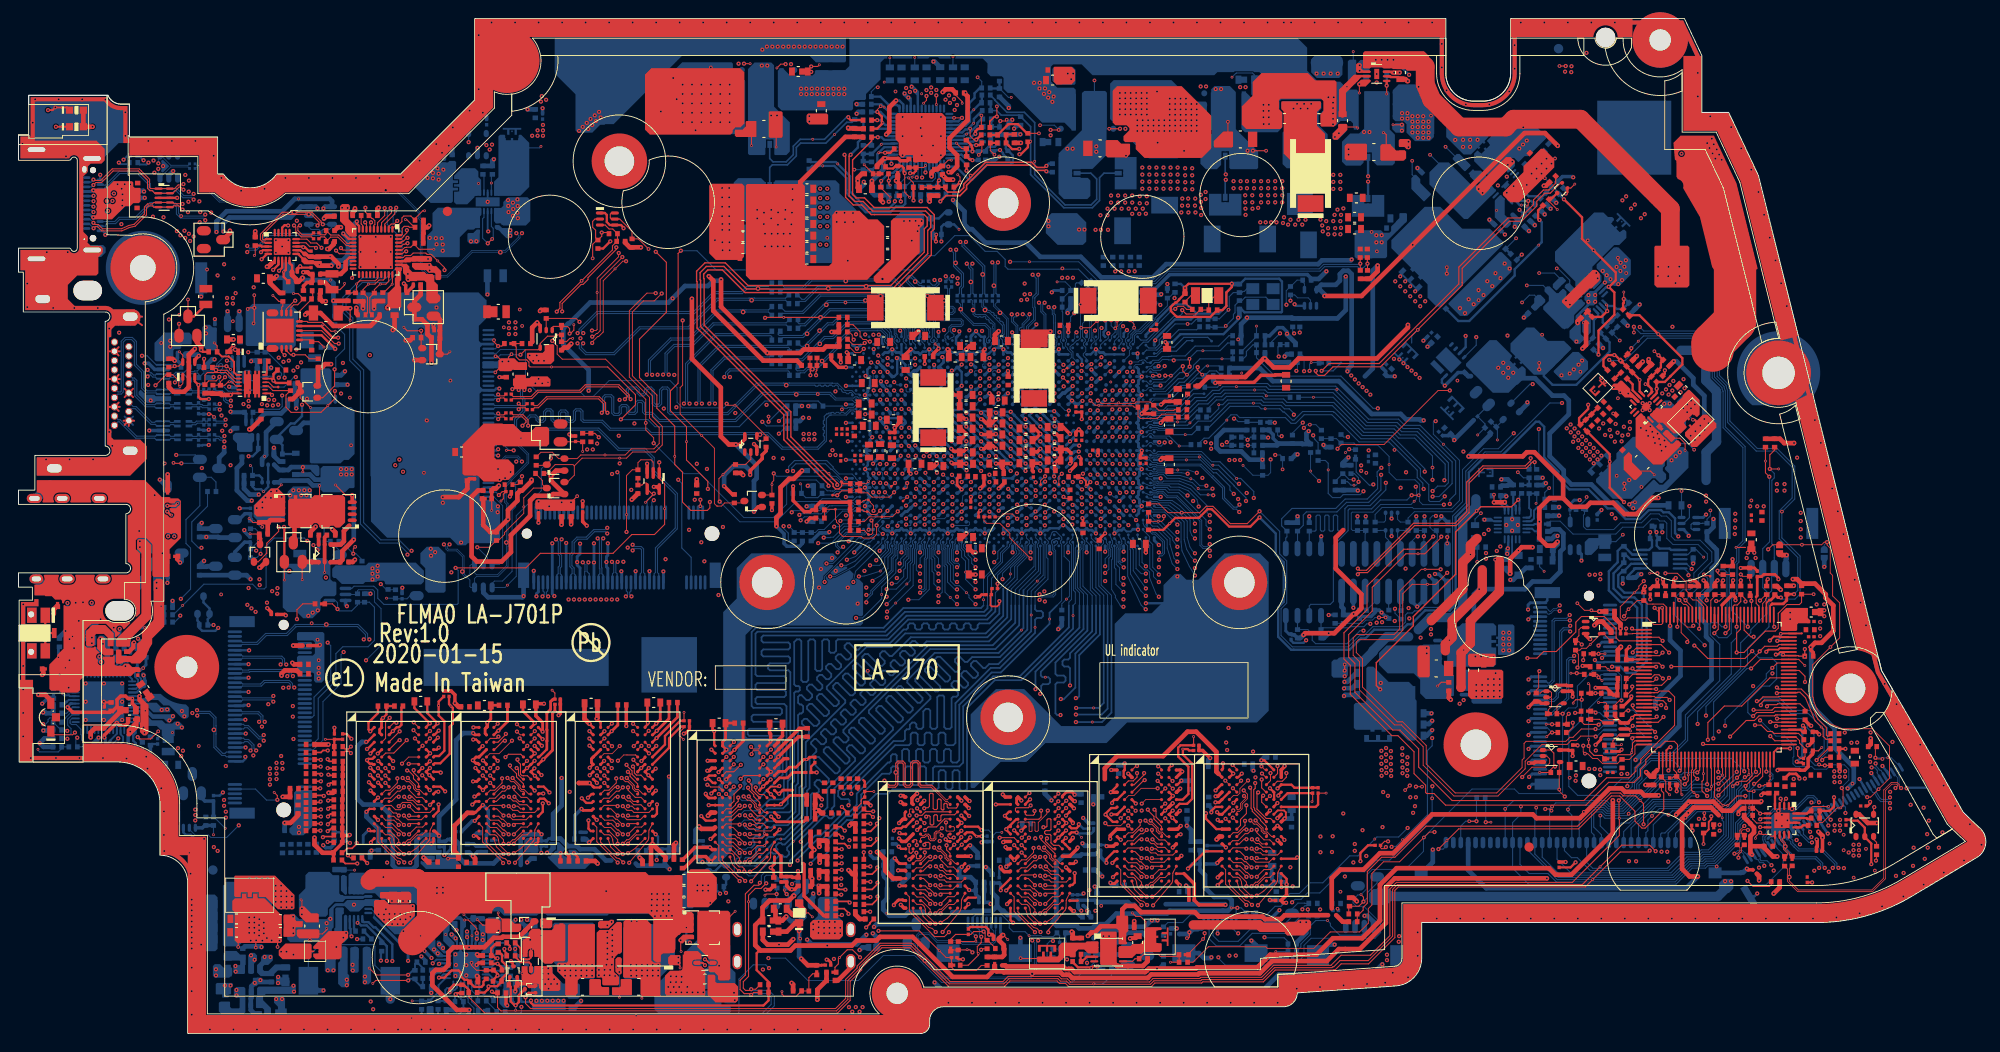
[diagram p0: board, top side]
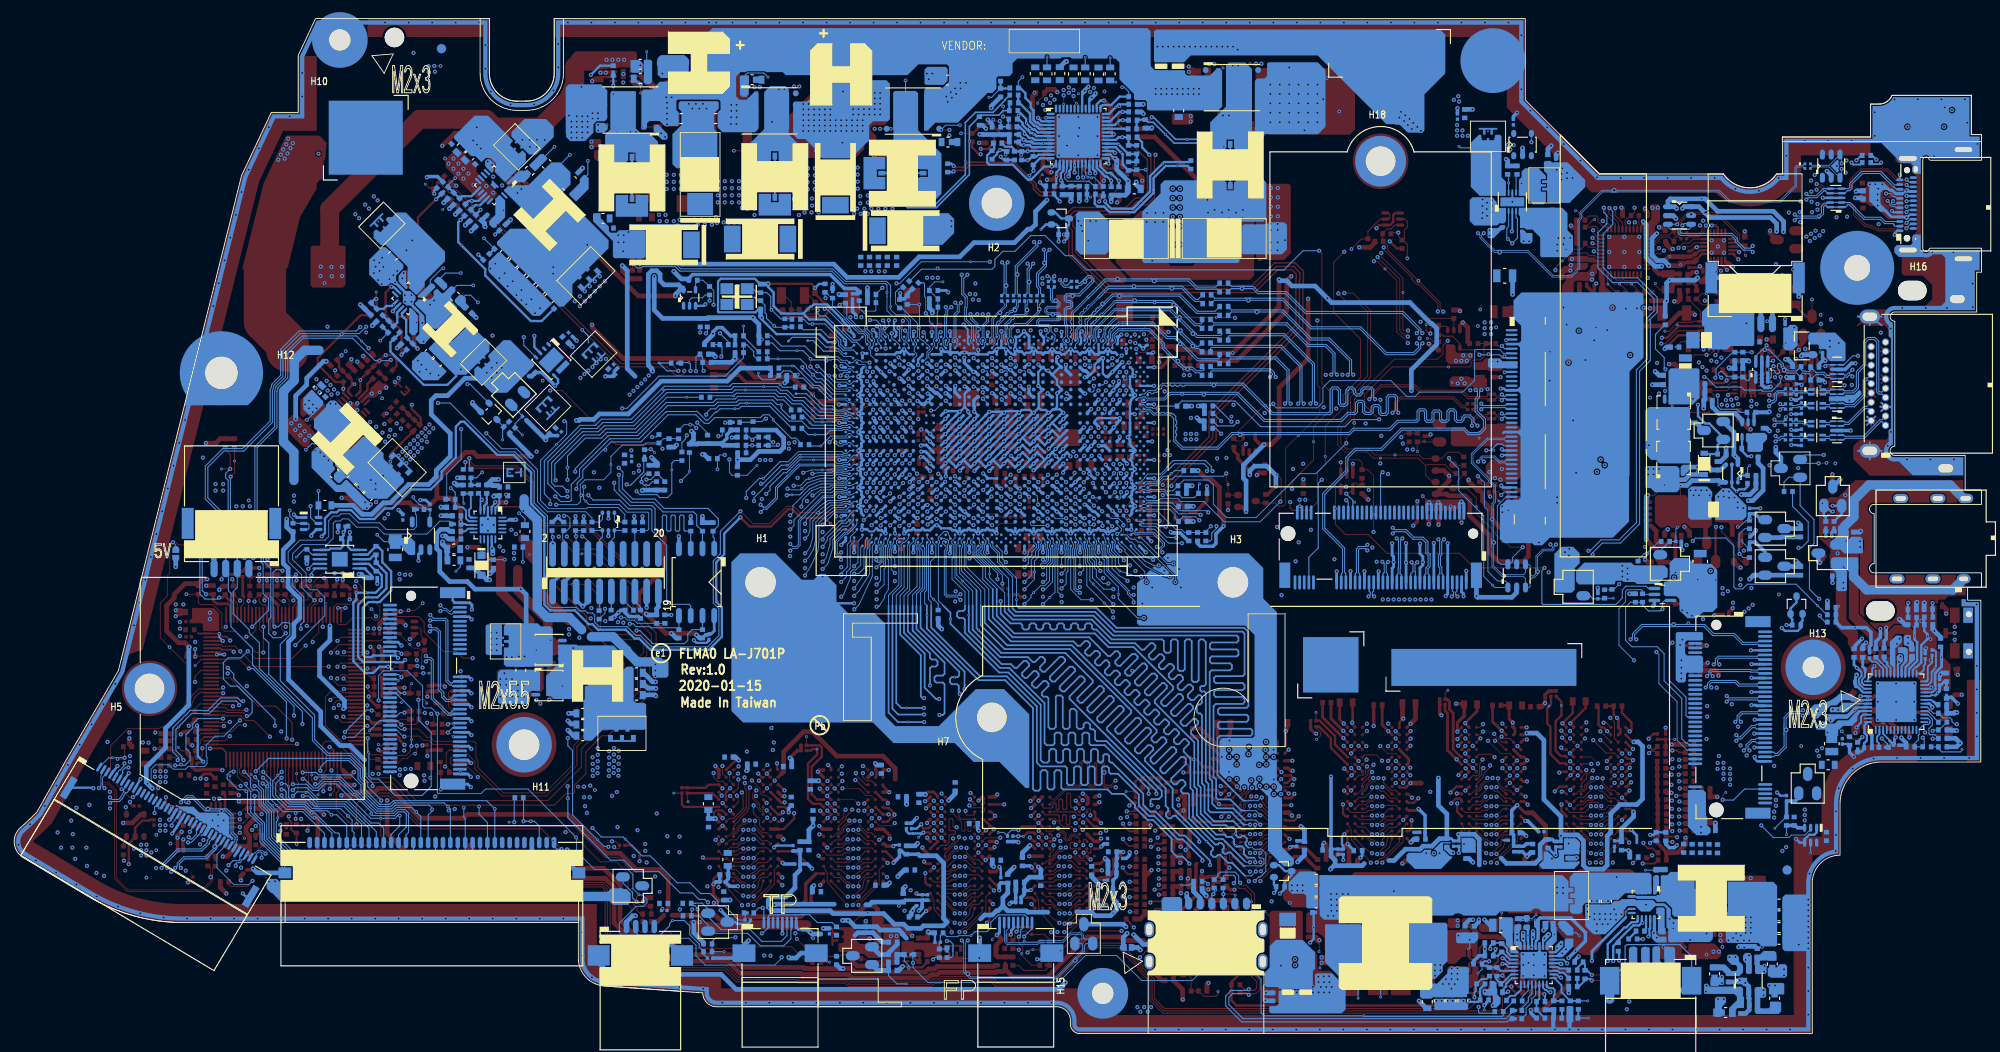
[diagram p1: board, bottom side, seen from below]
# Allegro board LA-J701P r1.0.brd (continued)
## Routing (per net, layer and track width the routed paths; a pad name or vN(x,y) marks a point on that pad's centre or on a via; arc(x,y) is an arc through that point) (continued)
DDR_A_DQS3#: length 53.6
  TOP w0.102: UD2.A7 v2(112.33,25.93)
  IN3 w0.102: 107.26,46.26 107.26,46.44 106.54,47.16 106.54,47.29 107.46,48.21 107.46,48.52 107.09,48.89 106.78,48.89 105.62,47.73 105.43,47.73 105.25,47.91 105.25,48.67 105.68,49.1 105.68,49.41 105.25,49.84 105.25,50.02 105.35,50.12 105.98,50.12 106.19,50.33 106.19,53.06 105.01,54.24 105.01,55.64 104.49,56.16 104.49,59.82 104.67,60 104.87,60 105,59.86 105,59.73 v2(104.87,59.6)
  IN3 w0.135: v2(112.33,25.93) 112.34,25.93 112.39,25.89 112.39,25.66 112.28,25.56 112.08,25.56 111.87,25.77 111.87,27.54 112,27.67 112.85,27.67 113.19,28.01 113.19,28.43 112.93,28.7 111.99,28.7 111.86,28.83 111.86,29.21 111.99,29.35 112.63,29.35 112.89,29.61 112.89,31.84 113.03,31.97 113.62,31.97 113.88,32.24 113.88,32.69 113.62,32.96 113.03,32.96 112.89,33.09 112.89,33.4 113.03,33.53 113.23,33.53 113.5,33.8 113.5,36.59 112.51,37.58 112.51,38.11 112.88,38.48 112.88,38.86 112.56,39.18 112.18,39.18 112.03,39.03 111.84,39.03 111.57,39.31 111.57,39.5 111.7,39.63 111.7,40.01 111.38,40.33 111.01,40.33 110.87,40.19 110.68,40.19 110.46,40.42 108.18,40.42 107.26,41.34 107.26,46.26
  BOTTOM w0.102: v2(104.87,59.6) 104.77,59.6 UC1.Y21
DDR_A_DQS4: length 53.4
  TOP w0.089: UD3.G3 120.26,23.68 v2(119.86,24.08)
  IN3 w0.102: 114.74,46.26 114.74,46.28 114.51,46.51 113.29,46.51 113.05,46.76 113.05,47.44 113.3,47.69 114.67,47.69 114.77,47.79 114.77,48.1 114.68,48.2 113,48.2 112.67,48.54 112.67,48.9 113.01,49.25 114.54,49.25 114.65,49.35 114.65,49.55 114.45,49.75 113.01,49.75 112.79,49.97 112.79,50.45 113.01,50.67 113.99,50.67 114.24,50.92 114.24,51.05 114.12,51.18 113.01,51.18 112.79,51.4 112.79,52.24 113.15,52.6 113.15,53.18 113.52,53.55 114.74,53.55 115.58,54.39 115.88,54.39 116.26,54.76 116.26,57.53 116.44,57.71 116.59,57.71 v2(116.88,58)
  IN3 w0.135: 114.74,46.26 116.73,44.27 116.73,43.31 119.26,40.78 119.26,31.99 117.17,29.89 117.17,25.83 117.61,25.39 118.44,25.39 119.27,24.56 120.02,24.56 120.14,24.44 120.14,24.35 v2(119.86,24.08)
  BOTTOM w0.102: v2(116.88,58) 116.48,58.4 UC1.AP23
DDR_A_DQS4#: length 53.3
  TOP w0.089: UD3.F3 120.27,24.48 v2(120.66,24.08)
  IN3 w0.102: v2(116.88,57.2) 116.88,57.44 116.81,57.51 116.53,57.51 116.46,57.44 116.46,54.68 115.97,54.18 115.66,54.18 114.82,53.35 113.61,53.35 113.35,53.09 113.35,52.52 112.99,52.16 112.99,51.48 113.1,51.38 114.2,51.38 114.44,51.14 114.44,50.83 114.08,50.47 113.1,50.47 112.99,50.36 112.99,50.06 113.1,49.96 114.53,49.96 114.85,49.64 114.85,49.26 114.63,49.04 113.1,49.04 112.87,48.82 112.87,48.62 113.09,48.4 114.77,48.4 114.98,48.19 114.98,47.71 114.76,47.49 113.38,47.49 113.25,47.35 113.25,46.84 113.38,46.72 114.59,46.72 114.9,46.41 114.91,46.41
  IN3 w0.135: 114.91,46.41 116.95,44.36 116.95,43.4 119.49,40.87 119.49,31.9 117.39,29.8 117.39,25.93 117.71,25.61 118.53,25.61 119.36,24.78 120.11,24.78 120.36,24.53 120.36,24.19 120.47,24.08 v2(120.66,24.08)
  BOTTOM w0.102: v2(116.88,57.2) 116.48,57.6 UC1.AP24
DDR_A_DQS5: length 53.2
  TOP w0.102: v2(123.1,28.08) 123.46,27.79 UD3.B7
  IN3 w0.102: v2(120.37,58.5) 120.25,58.5 120.15,58.4 120.15,58.17 120.22,58.1 122.27,58.1 122.48,57.89 122.48,57.53 122.58,57.43 122.94,57.43 123.16,57.22 123.16,56.73 122.94,56.52 122.58,56.52 122.48,56.42 122.48,55.7 122.67,55.52 123.9,55.52 124.28,55.15 124.28,48.17
  IN3 w0.135: v2(123.1,28.08) 123.28,28.26 123.9,28.26 124.19,28.55 124.19,29.51 124.42,29.74 125.18,29.74 125.31,29.61 125.31,28.96 125.58,28.69 125.99,28.69 126.43,28.25 126.99,28.25 127.28,28.54 127.28,29.74 126.81,30.21 126.81,30.73 127.11,31.03 127.65,31.03 127.91,31.29 127.91,32.45 128.32,32.86 128.86,32.86 129.46,33.47 129.46,34.01 130.01,34.55 130.2,34.55 130.54,34.21 131.19,34.21 131.56,33.84 131.99,33.84 132.48,34.33 132.48,35.31 132.27,35.51 131.59,35.51 131.47,35.64 131.47,36.13 131.6,36.26 132.24,36.26 132.48,36.51 132.48,37.04 132.14,37.38 131.45,37.38 131.32,37.52 131.32,38.21 129.82,39.71 129.82,40.37 124.47,45.71 124.47,47.97 124.28,48.17
  BOTTOM w0.102: UC1.AW22 120.07,58.8 v2(120.37,58.5)
DDR_A_DQS5#: length 53.2
  TOP w0.102: v2(123.1,28.88) 123.46,28.59 UD3.A7
  IN3 w0.102: 124.12,48.01 124.11,48.02 124.11,48.05 124.07,48.09 124.07,48.26 124.07,48.26 124.07,55.06 123.82,55.31 122.58,55.31 122.28,55.62 122.28,56.5 122.5,56.72 122.86,56.72 122.95,56.81 122.95,57.13 122.86,57.23 122.5,57.23 122.28,57.45 122.28,57.8 122.19,57.9 120.14,57.9 119.95,58.08 119.95,58.4 119.85,58.5 v2(119.67,58.5)
  IN3 w0.135: v2(123.1,28.88) 123.1,28.58 123.21,28.48 123.8,28.48 123.97,28.64 123.97,29.61 124.33,29.96 125.27,29.96 125.54,29.7 125.54,29.05 125.67,28.92 126.08,28.92 126.52,28.47 126.9,28.47 127.06,28.63 127.06,29.65 126.58,30.12 126.58,30.82 127.02,31.25 127.56,31.25 127.68,31.38 127.68,32.54 128.23,33.09 128.77,33.09 129.24,33.56 129.24,34.1 129.91,34.77 130.29,34.77 130.63,34.43 131.28,34.43 131.66,34.06 131.9,34.06 132.26,34.43 132.26,35.21 132.18,35.29 131.5,35.29 131.24,35.54 131.24,36.22 131.51,36.49 132.14,36.49 132.26,36.6 132.26,36.95 132.05,37.16 131.36,37.16 131.09,37.43 131.09,38.12 129.59,39.62 129.59,40.27 124.25,45.61 124.25,47.88 124.12,48.01
  BOTTOM w0.102: UC1.AV22 119.37,58.8 v2(119.67,58.5)
DDR_A_DQS6: length 98.7
  TOP w0.089: UD4.G3 131.59,23.91 131.68,24 131.88,24 132.17,24.29 132.17,24.8 132.76,25.38 132.76,25.86 v2(132.34,26.27)
  IN3 w0.102: 124.28,68.4 124.26,68.4 124.25,68.41 122.2,68.41 121.66,67.87 117.69,67.87 117.57,67.75 115.61,67.75 114.1,66.24 114.1,65.09 114.29,64.9 114.29,63.83 113.96,63.5 113.96,62.34 114.37,61.93 114.5,61.93 115.43,61 117.55,61 117.77,60.78 117.77,60.59 117.96,60.41 v2(118.19,60.41)
  IN3 w0.135: v2(132.34,26.27) 132.53,26.09 132.85,26.09 134.17,24.77 134.46,24.77 134.69,25 135.21,25 135.7,24.5 136.14,24.5 136.64,25.01 137.72,25.01 141.52,28.8 141.52,41.84 140.52,42.84 140.52,44.63 140.36,44.79 140.36,45.59 140.69,45.92 140.69,46.27 140.36,46.6 140.36,47.35 140.62,47.62 141.49,47.62 141.63,47.75 141.63,48.16 141.49,48.29 140.62,48.29 140.36,48.56 140.36,49.15 140.62,49.41 141.49,49.41 141.63,49.55 141.63,49.95 141.49,50.09 140.62,50.09 140.36,50.35 140.36,50.94 140.62,51.21 141.49,51.21 141.64,51.35 141.64,51.74 141.49,51.88 140.89,51.88 140.36,52.42 140.36,52.87 140.62,53.14 141.48,53.14 141.64,53.29 141.64,59.18 138.85,61.97 137.53,61.97 136.73,62.77 136.73,63.3 136.53,63.51 134.24,63.51 133.42,64.33 133.42,65.59 133.06,65.95 132.65,65.95 131.97,66.62 131.97,66.98 131.03,67.92 129.09,67.92 129,67.84 128.99,67.84 128.88,67.73 128.88,67.08 128.53,66.73 127.24,66.73 126.67,67.3 126.67,67.93 126.37,68.23 124.72,68.23 124.55,68.4 124.28,68.4
  BOTTOM w0.102: UC1.AT20 117.77,60.9 118.15,60.53 118.15,60.45 v2(118.19,60.41)
DDR_A_DQS6#: length 98.7
  TOP w0.089: v2(132.38,25.67) 132.49,25.67 132.58,25.58 132.58,25.46 131.99,24.87 131.99,24.36 131.81,24.18 131.68,24.18 131.59,24.27 UD4.F3
  IN3 w0.102: v2(117.39,60.41) 117.45,60.41 117.57,60.53 117.57,60.7 117.47,60.8 115.34,60.8 114.42,61.73 114.28,61.73 113.76,62.25 113.76,63.58 114.09,63.91 114.09,64.82 113.9,65.01 113.9,66.33 115.52,67.95 117.48,67.95 117.61,68.08 121.58,68.08 122.11,68.61 124.25,68.61 124.26,68.62 124.28,68.62
  IN3 w0.135: v2(132.38,25.67) 132.57,25.86 132.76,25.86 134.08,24.54 134.55,24.54 134.78,24.78 135.12,24.78 135.61,24.28 136.23,24.28 136.73,24.78 137.82,24.78 141.74,28.71 141.74,41.93 140.74,42.93 140.74,44.72 140.58,44.89 140.58,45.5 140.91,45.83 140.91,46.36 140.58,46.69 140.58,47.26 140.71,47.4 141.58,47.4 141.85,47.66 141.85,48.25 141.58,48.52 140.71,48.52 140.58,48.65 140.58,49.06 140.71,49.19 141.58,49.19 141.85,49.46 141.85,50.04 141.58,50.31 140.71,50.31 140.58,50.44 140.58,50.85 140.71,50.98 141.58,50.98 141.86,51.26 141.86,51.83 141.58,52.1 140.98,52.1 140.58,52.51 140.58,52.78 140.71,52.91 141.57,52.91 141.86,53.2 141.86,59.28 138.94,62.19 137.62,62.19 136.96,62.86 136.96,63.39 136.62,63.73 134.34,63.73 133.64,64.43 133.64,65.68 133.15,66.17 132.74,66.17 132.2,66.72 132.2,67.07 131.12,68.15 128.98,68.15 128.91,68.07 128.89,68.07 128.64,67.83 128.64,67.18 128.43,66.97 127.34,66.97 126.91,67.4 126.91,68.03 126.47,68.47 124.81,68.47 124.66,68.62 124.28,68.62
  BOTTOM w0.102: UC1.AR20 116.98,60.9 117.35,60.53 117.35,60.45 v2(117.39,60.41)
DDR_A_DQS7: length 53.4
  TOP w0.102: v2(134.32,28.1) 134.72,27.69 UD4.B7
  IN3 w0.102: v2(117.37,62.5) 117.55,62.68 117.55,63.02 117.86,63.33 120.82,63.33 121.13,63.63 121.63,63.63 122.11,63.15 122.43,63.15 122.74,62.83 123.51,62.83 123.75,62.59 125.47,62.59 126.89,61.17 126.89,59.37 128.95,57.31 128.96,57.31 129.07,57.2
  IN3 w0.135: v2(134.32,28.1) 134.45,28.26 134.69,28.26 135.01,28.59 135.01,29.7 137.03,31.72 137.03,39.59 134.37,42.25 134.37,46.62 135.09,47.35 135.09,50.11 132.98,52.22 130.04,52.22 129.39,52.86 129.39,56.88 129.07,57.2
  BOTTOM w0.102: v2(117.37,62.5) 116.98,62.9 UC1.AR18
DDR_A_DQS7#: length 53.3
  TOP w0.102: UD4.A7 134.64,28.49 v2(134.26,28.87)
  IN3 w0.102: v2(118.18,62.5) 117.96,62.29 117.85,62.29 117.76,62.38 117.76,62.93 117.95,63.12 120.91,63.12 121.21,63.43 121.54,63.43 122.03,62.95 122.34,62.95 122.66,62.63 123.42,62.63 123.66,62.39 125.38,62.39 126.69,61.08 126.69,59.28 128.94,57.03 128.94,57.01
  IN3 w0.135: v2(134.26,28.87) 134.28,28.55 134.37,28.48 134.59,28.48 134.79,28.68 134.79,29.79 136.81,31.81 136.81,39.49 134.14,42.16 134.14,46.72 134.87,47.44 134.87,50.01 132.89,51.99 129.94,51.99 129.17,52.77 129.17,56.79 128.94,57.01
  BOTTOM w0.102: UC1.AT18 117.77,62.9 v2(118.18,62.5)
DDR_A_EVENT#: length 1.4
  TOP w0.102: v2(112.87,58) 113.03,57.84 RC2.2
  BOTTOM w0.102: UC1.AK23 112.48,58.4 v2(112.87,58)
DDR_A_MA0: length 136.5
  TOP w0.107: v2(121.87,16.92) 121.39,17.4 121.28,17.4 120.6,18.08 UD3.P3 ; UD2.P3 109.09,15.16 109.77,14.48 109.87,14.48 v2(110.35,14) ; UD4.P3 131.93,18.09 132.61,17.41 132.72,17.41 v2(133.19,16.93) ; v2(99.03,14) 98.56,14.48 98.45,14.48 97.77,15.16 UD1.P3
  TOP w0.188: RD3.2 v2(92.02,14.75)
  IN1 w0.102: 134.79,17.56 134.56,17.33 133.59,17.33 v2(133.19,16.93) 132.73,17.4 128.97,17.4 128.87,17.3 128.87,16.87 128.77,16.77 128.59,16.77 128.49,16.87 128.49,17.43 128.39,17.53 128.19,17.53 128.09,17.43 128.09,16.9 127.96,16.77 127.76,16.77 127.65,16.87 127.65,17.3 127.55,17.4 127.3,17.4 127.19,17.3 127.19,17.1 127.14,17.05 123.08,17.05 122.82,17.3 122.25,17.3 v2(121.87,16.92) 121.41,17.38 121.15,17.38 119.62,15.85 116.91,15.85 116.83,15.93 116.83,16.62 116.68,16.77 116.04,16.77 114.39,15.12 112.41,15.12 111.65,14.36 111.34,14.36 111.29,14.41 110.76,14.41 v2(110.35,14) 110.35,14.13 110.02,14.46 109.59,14.46 109.52,14.38 103.8,14.38 103.68,14.25 103.68,13.92 103.57,13.82 103.3,13.82 103.2,13.92 103.2,14.28 103.1,14.38 102.27,14.38 102.17,14.28 102.17,14.1 102.07,14 101.86,14 101.76,14.1 101.76,14.28 101.66,14.38 101.46,14.38 101.36,14.28 101.36,14.1 101.25,14 101.05,14 100.95,14.1 100.95,14.28 100.85,14.38 100.64,14.38 100.54,14.28 100.54,14.1 100.44,14 100.24,14 100.14,14.1 100.14,14.28 100.03,14.38 99.42,14.38 v2(99.03,14) 98.6,14.43 97.68,14.43 96.54,13.29 94.5,13.29 93.64,14.15 92.61,14.15 v2(92.02,14.75)
  IN1 w0.16: 134.79,17.56 135.19,17.97 v2(137.38,17.97)
  IN2 w0.102: v2(111.87,56.42) 112,56.28 112,54.36 112.28,54.08 112.87,54.08 113.24,53.71 113.95,53.71 114.23,53.44 114.66,53.44 114.8,53.29
  IN2 w0.198: 114.8,53.29 115.89,52.2 116.7,52.2 116.88,52.02 116.88,51.77 117.01,51.64 120.49,51.64 120.69,51.44 120.69,51.11 121.05,50.75 121.05,45.7 121.58,45.17 122.91,45.17 123.04,45.04 123.04,44.8 123.18,44.66 123.39,44.66 124.02,45.29 124.3,45.29 124.58,45.01 124.58,44.73 124.15,44.29 124.15,44.01 124.43,43.73 124.71,43.73 125.15,44.17 125.42,44.17 125.71,43.89 125.71,43.61 125.27,43.17 125.27,42.89 125.55,42.61 125.83,42.61 126.27,43.05 126.55,43.05 126.83,42.77 126.83,42.49 126.39,42.05 126.39,41.77 126.67,41.49 126.95,41.49 127.39,41.92 127.67,41.92 127.95,41.64 127.95,41.36 127.51,40.93 127.51,40.65 131.77,36.38 131.77,34.28 135.03,31.02 136.54,31.02 138.62,28.94 138.62,25.02 138.25,24.65 138.25,20.13 137.29,19.17 135.33,19.17 135.04,18.88 135.04,17.81 135.28,17.57 135.56,17.57 135.68,17.68 135.68,18.46 135.83,18.61 136.11,18.61 136.31,18.41 136.31,17.79 136.47,17.64 136.68,17.64 136.87,17.83 136.87,18.47 136.98,18.58 138.05,18.58 138.19,18.43 138.19,18.1 138.05,17.96 137.84,17.96 137.84,17.97 v2(137.38,17.97)
  BOTTOM w0.102: UC1.AK26 112.28,56 v2(111.87,56.42)
DDR_A_MA1: length 138.3
  TOP w0.107: v2(110.91,15.02) 111.05,15.16 UD2.P7 ; UD1.P7 99.73,15.16 v2(99.59,15.02) ; v2(133.75,17.95) 133.89,18.09 UD4.P7 ; v2(122.42,17.94) 122.57,18.08 UD3.P7
  TOP w0.188: RD4.2 88.43,17.68 v2(88.92,17.68)
  IN2 w0.102: v2(110.89,58.02) 112.26,56.65 112.26,54.46 112.44,54.29 113,54.29 113.36,53.92 114.18,53.92 114.38,53.71 114.84,53.71 115.26,53.29
  IN2 w0.198: 115.26,53.29 115.92,52.63 121.05,52.63 121.28,52.41 121.28,51.85 121.63,51.49 121.92,51.49 122.36,51.06 122.36,47.77 122.52,47.6 122.52,46.25 122.72,46.06 123.21,46.06 123.41,46.25 123.41,46.59 123.54,46.72 123.84,46.72 124.02,46.54 124.02,46.21 124.17,46.06 124.62,46.06 128.92,41.76 128.92,41.48 128.3,40.86 128.3,40.58 128.58,40.3 128.86,40.3 129.48,40.92 129.76,40.92 130.04,40.64 130.04,40.36 129.42,39.74 129.42,39.46 129.7,39.18 129.98,39.18 130.6,39.8 130.88,39.8 131.1,39.57 131.1,39.29 130.49,38.67 130.49,38.39 130.77,38.11 131.05,38.11 131.66,38.73 131.95,38.73 132.26,38.42 132.26,38.14 131.63,37.51 131.63,37.23 132.01,36.86 132.29,36.86 132.84,37.41 133.12,37.41 133.32,37.21 133.32,36.77 132.27,35.72 132.27,35.4 132.47,35.2 132.75,35.2 133.23,35.68 133.51,35.68 133.71,35.49 133.71,35.04 132.85,34.19 132.85,33.91 135.24,31.52 136.87,31.52 139.16,29.23 139.16,23.88 138.75,23.47 138.75,17.33 138.09,16.67 137.68,16.67 137.48,16.87 137.48,16.97 137.32,17.14 136.91,17.14 136.71,16.94 136.71,16.56 136.51,16.36 136.12,16.36 135.92,16.56 135.92,16.94 135.72,17.14 135.11,17.14 134.3,17.95 v2(133.75,17.95)
  IN3 w0.102: v2(99.59,15.02) 99.59,15.03 99.1,15.52 94.45,15.52 93.01,16.97 89.5,16.97 88.92,17.56 v2(88.92,17.68)
  IN3 w0.127: v2(133.75,17.95) 133.36,18.34 130.36,18.34 130.03,18.01 127.65,18.01 127.11,17.47 127.11,17.28 126.98,17.15 125.9,17.15 125.78,17.28 125.78,17.99 125.65,18.12 125.39,18.12 125.27,17.99 125.27,17.28 125.14,17.15 123.21,17.15 v2(122.42,17.94) 122.03,18.33 121.14,18.33 120.91,18.1 120.91,18.1 117.5,14.69 117.21,14.69 117.08,14.81 117.08,15.27 116.96,15.4 116.34,15.4 116.22,15.27 116.22,14.81 116.09,14.69 114.77,14.69 114.42,15.04 110.94,15.04 v2(110.91,15.02) 110.91,15.02 110.53,15.4 108.18,15.4 107.9,15.68 107.65,15.68 107.52,15.55 107.52,15.14 107.4,15.02 104.99,15.02 104.86,15.14 104.86,15.58 104.73,15.7 104.48,15.7 104.35,15.58 104.35,15.14 104.23,15.02 103.97,15.02 103.85,15.14 103.85,15.58 103.72,15.7 103.46,15.7 103.34,15.58 103.34,15.14 103.21,15.02 v2(99.59,15.02)
  BOTTOM w0.102: UC1.AG24 110.47,57.6 v2(110.89,58.02)
DDR_A_MA2: length 135.2
  TOP w0.107: v2(121.31,15.9) 121.31,16.34 120.38,17.28 UD3.R3 ; v2(109.79,12.98) 109.79,13.42 108.86,14.36 UD2.R3 ; v2(98.48,12.98) 98.48,13.42 97.54,14.36 UD1.R3 ; UD4.R3 131.7,17.29 132.64,16.36 v2(132.64,15.92)
  TOP w0.188: RD5.2 v2(91.99,13.16)
  IN1 w0.102: v2(91.99,13.16) 93.23,13.16 94.17,12.22 97.22,12.22 97.98,12.98 v2(98.48,12.98) 98.86,13.37 99.86,13.37 99.94,13.44 101.72,13.44 101.97,13.19 107.78,13.19 107.88,13.29 107.88,13.75 107.98,13.85 108.18,13.85 108.28,13.75 108.28,13.14 108.39,13.04 108.59,13.04 108.69,13.14 108.69,13.75 108.79,13.85 109,13.85 109.1,13.75 109.1,13.06 109.2,12.96 109.77,12.96 v2(109.79,12.98) 110.17,13.37 111.27,13.37 111.32,13.42 111.95,13.42 112.87,14.33 117.79,14.33 117.89,14.43 117.89,15.09 117.99,15.19 118.22,15.19 118.32,15.09 118.32,14.58 118.42,14.48 118.63,14.48 118.73,14.58 118.73,15.09 118.83,15.19 120.6,15.19 v2(121.31,15.9) 121.71,15.5 127.5,15.5 127.6,15.6 127.6,16.13 127.7,16.23 127.9,16.23 128.01,16.13 128.01,15.6 128.11,15.5 128.31,15.5 128.41,15.6 128.41,16.13 128.51,16.23 128.72,16.23 128.82,16.13 128.82,15.6 128.92,15.5 129.71,15.5 130.13,15.92 130.61,15.92 130.71,16.02 130.71,16.03 130.81,16.13 131.01,16.13 131.11,16.03 131.11,16.02 131.22,15.92 v2(132.64,15.92)
  IN1 w0.16: v2(137.63,15.91) 140.99,15.91 141.15,15.75 141.15,15.49 141.04,15.37 133.11,15.37 132.64,15.85 v2(132.64,15.92)
  IN2 w0.102: v2(110.86,58.83) 111.4,58.3 111.4,57.92 112.46,56.85 112.46,54.65 112.59,54.53 113.06,54.53 113.47,54.12 114.3,54.12 114.38,54.03 114.9,54.03 115.99,52.94 118.99,52.94 119.24,53.19 121.73,53.19 122.04,53.5 123.04,53.5 123.64,52.9 123.64,52.81 123.66,52.79
  IN2 w0.198: v2(137.63,15.91) 137.73,15.8 138.01,15.8 139.31,17.1 139.31,23.37 139.67,23.73 139.67,29.43 137.07,32.02 135.44,32.02 133.71,33.76 133.71,34.33 134.45,35.07 134.45,36.94 123.89,47.5 123.89,52.56 123.66,52.79
  BOTTOM w0.102: UC1.AG23 110.81,58.83 v2(110.86,58.83)
DDR_A_MA3: length 137.5
  TOP w0.107: v2(133.75,18.96) 133.83,18.89 UD4.N7 ; v2(99.59,16.03) 99.67,15.96 100.63,15.96 UD1.N7 ; UD3.N7 122.5,18.88 v2(122.42,18.95) ; v2(110.91,16.03) 110.98,15.96 111.95,15.96 UD2.N7
  TOP w0.188: RD6.2 v2(88.92,19.93)
  IN1 w0.16: v2(130.55,30.64) 131.36,31.45 134,31.45 134.16,31.29 134.16,30.77 134.34,30.59 134.64,30.59 134.8,30.75 134.8,31.29 134.96,31.45 135.28,31.45 135.44,31.29 135.44,30.77 135.62,30.59 135.92,30.59 136.08,30.75 136.08,31.29 136.24,31.45 136.56,31.45 136.72,31.29 136.72,30.77 136.9,30.59 137.2,30.59 137.36,30.75 137.36,31.29 137.52,31.45 137.84,31.45 138,31.29 138,30.77 138.18,30.59 138.48,30.59 138.64,30.75 138.64,31.29 138.8,31.45 139.41,31.45 146.56,24.31 146.56,21.27 145.93,20.65 144.96,20.65 144.53,21.08 143.21,21.08 142.35,20.22 140.09,20.22 139.86,19.99 134.77,19.99 v2(133.75,18.96)
  IN2 w0.102: v2(109.87,55.75) 109.99,55.63 109.99,53.83 110.94,52.89 111.47,52.89 114.79,49.56 115.13,49.56 115.36,49.33
  IN2 w0.198: v2(130.55,30.64) 130.42,30.51 129.43,30.51 129.18,30.76 129.18,32.41 117.58,44.01 117.58,44.9 117.11,45.37 117.11,47.36 116.27,48.19 116.27,48.42 115.36,49.33
  IN3 w0.102: v2(88.92,19.93) 89.19,19.93 90.49,18.62 92.85,18.62 94.67,16.79 95.58,16.79 95.76,16.62 99.01,16.62 v2(99.59,16.03)
  IN3 w0.127: v2(133.75,18.96) 133.75,18.96 133.37,19.35 132.73,19.35 132.37,19.7 128.02,19.7 127.89,19.58 127.89,19.18 127.77,19.06 127.51,19.06 127.38,19.18 127.38,19.58 127.26,19.7 127,19.7 126.88,19.58 126.88,19 126.75,18.88 126.5,18.88 126.37,19 126.37,19.58 126.24,19.7 125.45,19.7 124.63,18.88 122.5,18.88 v2(122.42,18.95) 121.81,19.56 121.02,19.56 119.98,18.52 118.81,18.52 117.69,17.4 115.13,17.4 113.76,16.03 112.44,16.03 112.32,16.16 112.32,16.59 112.19,16.72 111.93,16.72 111.81,16.59 111.81,16.16 111.68,16.03 v2(110.91,16.03) 110.91,16.24 110.63,16.52 109.19,16.52 108.96,16.29 105.52,16.29 105.4,16.41 105.4,16.88 105.27,17.01 105.02,17.01 104.89,16.88 104.89,16.41 104.76,16.29 104.51,16.29 104.38,16.41 104.38,16.88 104.25,17.01 104,17.01 103.87,16.88 103.87,16.41 103.75,16.29 99.85,16.29 v2(99.59,16.03)
  BOTTOM w0.102: UC1.AG26 110.12,56 v2(109.87,55.75)
DDR_A_MA4: length 136.2
  TOP w0.107: UD1.N3 97.95,15.96 98.27,15.63 98.42,15.63 v2(99.03,15.02) ; v2(133.19,17.95) 132.58,18.57 132.43,18.57 132.11,18.89 UD4.N3 ; UD2.N3 109.26,15.96 109.59,15.63 109.73,15.63 v2(110.35,15.02) ; v2(121.87,17.94) 121.25,18.55 121.1,18.55 120.78,18.88 UD3.N3
  TOP w0.188: v2(92.78,16.29) 92.78,16.15 92.21,15.58 RD7.2
  IN1 w0.091: v2(121.87,17.94) 122.25,18.32 122.85,18.32
  IN1 w0.102: v2(92.78,16.29) 93.01,16.05 93.67,16.05 94.91,14.81 96.33,14.81 96.99,15.47 98.58,15.47 v2(99.03,15.02) 99.42,15.4 100.47,15.4 100.83,15.03 103.95,15.03 104.05,15.13 104.05,15.63 104.15,15.73 104.36,15.73 104.46,15.63 104.46,15.13 104.56,15.03 104.76,15.03 104.86,15.13 104.86,15.63 104.96,15.73 105.17,15.73 105.27,15.63 105.27,15.13 105.37,15.03 106.91,15.03 107.48,15.6 109.77,15.6 v2(110.35,15.02) 110.74,15.4 111.68,15.4 111.98,15.7 114.03,15.7 116.12,17.79 118.81,17.79 118.91,17.89 118.91,18.27 119.01,18.37 119.22,18.37 119.32,18.27 119.32,17.89 119.42,17.79 119.65,17.79 119.75,17.89 119.75,18.24 119.91,18.4 121.4,18.4 v2(121.87,17.94) ; 122.85,18.32 123.22,18.32 123.32,18.22 123.32,17.96 123.43,17.86 123.63,17.86 123.73,17.96 123.73,18.22 123.83,18.32 124.04,18.32 124.14,18.22 124.14,17.99 124.24,17.89 124.44,17.89 124.54,17.99 124.54,18.22 124.64,18.32 124.85,18.32 124.95,18.22 124.95,17.99 125.05,17.89 125.25,17.89 125.36,17.99 125.36,18.22 125.46,18.32 128.52,18.32 129.11,18.92 131.96,18.92 132.45,18.42 132.73,18.42 v2(133.19,17.95)
  IN2 w0.102: 113,52.43 112.57,52.43 111.6,53.4 111.29,53.4 111.01,53.68 111.01,54.77 v2(110.86,54.92)
  IN2 w0.198: v2(133.19,17.95) 133.19,18.22 133.39,18.42 134.05,18.42 134.43,18.8 134.43,21.21 134.15,21.49 132.4,21.49 131.82,22.07 130.59,22.07 130.39,22.27 130.39,22.64 130.62,22.87 131.62,22.87 131.84,23.09 131.84,25.35 131.64,25.56 130.93,25.56 130.73,25.36 130.73,23.82 130.54,23.62 130.14,23.62 129.94,23.82 129.94,24.26 129.79,24.41 128.59,24.41 128.39,24.61 128.39,25.81 128.74,26.17 128.74,27.13 129.4,27.78 129.68,27.78 129.87,27.59 129.87,26.61 130.06,26.42 130.51,26.42 130.85,26.77 130.85,27.86 129.35,29.36 129.35,29.78 129.55,29.98 130.04,29.98 130.58,29.44 131.07,29.44 131.28,29.64 131.28,30.53 131.48,30.73 131.87,30.73 132.07,30.53 132.07,28.68 132.27,28.48 132.88,28.48 133.57,29.17 133.57,29.57 132.9,30.24 132.9,30.84 131.55,32.19 130.39,32.19 130.19,32.39 130.19,32.73 130.12,32.89 126.21,36.8 126.21,37.4 125.79,37.82 125.19,37.82 124.78,38.23 124.78,38.83 124.06,39.55 123.46,39.55 123.05,39.96 123.05,40.55 122.71,40.9 122.11,40.9 121.58,41.43 121.58,41.97 120.99,42.56 120.46,42.56 119.9,43.12 119.9,43.68 119.44,44.13 118.88,44.13 118.57,44.44 118.57,45.37 118.11,45.83 118.11,47.97 117.61,48.47 117.49,48.47 117.49,48.47 117.2,48.47 116.31,49.36 116.31,49.68 115.89,50.09 115.03,50.09 113.91,51.21 113.91,52.08 113.56,52.43 113,52.43
  BOTTOM w0.102: v2(110.86,54.92) 110.75,54.92 UC1.AG27
DDR_A_MA5: length 144.6
  TOP w0.107: UD4.P8 135.22,17.71 134.53,17.71 133.75,16.94 v2(133.75,16.93) ; UD3.P8 123.89,17.7 123.2,17.7 122.42,16.93 v2(122.42,16.92) ; v2(99.59,14) 99.59,14.01 100.37,14.78 101.06,14.78 UD1.P8 ; v2(110.91,14) 110.91,14.01 111.68,14.78 112.38,14.78 UD2.P8
  TOP w0.188: RD8.2 v2(92.02,16.4)
  IN1 w0.16: v2(133.75,16.93) 134.84,16.93 135.29,17.38 142.23,17.38 143.98,19.13 145.52,19.13 v2(145.58,19.19)
  IN2 w0.102: v2(109.87,59.57) 109.87,59.77 110.84,60.74 112.16,60.74 112.34,60.91 112.84,60.91 113.35,60.41 113.91,60.41 114.62,61.12 117.86,61.12 117.98,61 120.63,61 122.24,59.39 127.09,59.39 128.74,57.74
  IN2 w0.198: 128.74,57.74 129.61,57.74 132.18,55.17 134.46,55.17 138.09,51.55 138.09,46.6 140.94,43.75 140.94,43 142.54,41.41 142.54,35.24 146.24,31.53 146.24,31.43 146.25,31.42 146.25,19.86 v2(145.58,19.19)
  IN3 w0.102: v2(92.02,16.4) 92.02,16.21 92.52,15.7 93.62,15.7 94.3,15.02 97.17,15.02 97.65,14.53 99.2,14.53 99.59,14.14 v2(99.59,14)
  IN3 w0.127: v2(133.75,16.93) 133.28,17.4 131.49,17.4 131.28,17.61 130.83,17.61 130.7,17.48 130.7,17.12 130.6,17.02 130.34,17.02 130.22,17.15 130.22,17.48 130.09,17.61 128.87,17.61 128.57,17.3 128.57,16.87 128.44,16.74 128.22,16.74 128.09,16.87 128.09,17.33 127.96,17.46 127.71,17.46 127.58,17.33 127.58,16.87 127.46,16.74 122.6,16.74 v2(122.42,16.92) 122.02,17.32 120.95,17.32 117.96,14.33 113.21,14.33 113.09,14.46 113.09,14.56 112.96,14.69 112.71,14.69 112.58,14.56 112.58,14.33 112.45,14.2 112.2,14.2 112.07,14.33 112.07,14.56 111.94,14.69 111.69,14.69 111.56,14.56 111.56,14.13 111.44,14 v2(110.91,14) 110.47,14.44 105.63,14.44 105.45,14.26 105.45,13.75 105.33,13.62 104.54,13.62 104.41,13.75 104.41,14.31 104.29,14.44 104.03,14.44 103.9,14.31 103.9,13.75 103.78,13.62 103.52,13.62 103.4,13.75 103.4,14.31 103.27,14.44 100.03,14.44 v2(99.59,14)
  BOTTOM w0.102: UC1.AF21 109.81,59.57 v2(109.87,59.57)
DDR_A_MA6: length 146
  TOP w0.107: UD3.P2 119.88,17.66 120.56,17.66 v2(121.31,16.92) ; UD2.P2 108.36,14.74 109.05,14.74 v2(109.79,14) ; v2(132.64,16.93) 131.89,17.68 131.21,17.68 UD4.P2 ; v2(98.48,14) 97.73,14.74 97.05,14.74 UD1.P2
  TOP w0.188: RD9.2 88.34,15 v2(88.87,15)
  IN1 w0.102: v2(88.87,15) 89.61,15 89.81,15.19 90.31,15.19 91.76,13.75 92.29,13.75 92.41,13.63 93.48,13.63 94.3,12.81 96.84,12.81 98.03,14 v2(98.48,14) 98.88,13.59 99.76,13.59 99.94,13.77 101.75,13.77 102.11,13.42 104.03,13.42 104.13,13.52 104.13,14.05 104.23,14.15 104.43,14.15 104.54,14.05 104.54,13.52 104.64,13.42 105.32,13.42 105.43,13.52 105.43,14.03 105.53,14.13 105.73,14.13 105.83,14.03 105.83,13.67 105.93,13.57 107.17,13.57 107.66,14.05 107.76,14.15 109.64,14.15 v2(109.79,14) 110.2,13.59 111.09,13.59 111.37,13.87 111.85,13.87 112.69,14.71 116.57,14.71 116.67,14.81 116.67,15.4 116.77,15.5 116.97,15.5 117.07,15.4 117.07,15.09 117.17,14.99 117.38,14.99 117.48,15.09 117.48,15.4 117.58,15.5 119.89,15.5 v2(121.31,16.92) 121.77,16.46 122.86,16.46 122.96,16.36 122.96,15.91 123.07,15.8 123.27,15.8 123.37,15.91 123.37,16.36 123.47,16.46 123.68,16.46 123.78,16.36 123.78,15.91 123.88,15.8 124.08,15.8 124.18,15.91 124.18,16.36 124.28,16.46 126.65,16.46 126.75,16.36 126.75,16.21 126.85,16.11 127.05,16.11 127.16,16.21 127.16,16.36 127.26,16.46 132.16,16.46 v2(132.64,16.93)
  IN1 w0.16: v2(132.64,16.93) 132.64,16.84 133.11,16.36 134.95,16.36 135.44,16.85 142.35,16.85 143.99,18.48 v2(144.19,18.48)
  IN2 w0.102: v2(109.87,58.7) 110.4,59.24 112.23,59.24 112.39,59.39 112.39,59.7 112.67,59.98 121.22,59.98 122.14,59.06 126.69,59.06 128.39,57.36 129.01,57.36 129.04,57.33 129.09,57.33
  IN2 w0.198: v2(144.19,18.48) 144.51,18.81 144.51,19.05 145.75,20.28 145.75,21.71 145.76,21.72 145.76,22.23 145.75,22.25 145.75,31.18 145.74,31.19 145.74,31.22 145.69,31.27 145.69,31.3 145.63,31.35 145.63,31.4 142.08,34.95 142.08,40.94 140.15,42.88 140.15,43.83 137.58,46.4 137.58,50.96 133.82,54.72 131.99,54.72 129.38,57.33 129.09,57.33
  BOTTOM w0.108: v2(109.87,58.7) UC1.AF22
DDR_A_MA7: length 140.8
  TOP w0.107: v2(122.42,15.9) 122.42,15.98 123.31,16.86 123.85,16.86 UD3.R8 ; v2(110.91,12.98) 110.91,13.06 111.8,13.94 112.34,13.94 UD2.R8 ; v2(133.75,15.92) 133.75,15.99 134.64,16.88 135.18,16.88 UD4.R8 ; v2(99.59,12.98) 99.59,13.06 100.48,13.94 101.02,13.94 UD1.R8
  TOP w0.188: v2(92.78,14.79) 92.78,14.52 92.21,13.95 RD10.2
  IN2 w0.089: 131.84,16.34 132.12,16.34 132.15,16.31 133.36,16.31 v2(133.75,15.92)
  IN2 w0.102: v2(108.83,57.16) 108.53,57.16 108.04,57.64 107.61,57.64 106.82,56.85 106.82,56.24 106.26,55.67 106.26,54.73 106.77,54.21 106.77,53.27 106.87,53.17
  IN2 w0.198: 131.84,16.34 130.72,16.34 129.7,17.37 129.42,17.37 128.35,16.3 128.35,16.02 128.64,15.73 128.64,15.4 128.08,14.84 127.8,14.84 127.39,15.24 127.11,15.24 126.83,14.96 126.83,14.68 127.24,14.28 127.24,13.99 126.96,13.71 126.68,13.71 126.27,14.12 125.99,14.12 125.71,13.84 125.71,13.56 126.12,13.15 126.12,12.87 125.84,12.59 125.56,12.59 125.15,13 124.87,13 124.63,12.76 124.63,12.32 124.37,12.07 123.77,12.07 123.62,12.22 123.62,12.55 123.26,12.91 122.02,12.91 121.82,12.71 121.82,12.09 121.63,11.89 121.23,11.89 121.03,12.09 121.03,12.38 120.6,12.81 119.14,12.81 118.94,13.01 118.94,15.37 118.64,15.67 118.64,22.26 118.51,22.4 118.51,23.93 117.57,24.87 117.57,31.48 118.43,32.34 118.43,37.43 113.78,42.08 113.78,43.04 113.27,43.54 113.27,44.84 112.31,45.8 112.31,48.01 111.2,49.12 108.68,49.12 106.87,50.93 106.87,53.17
  IN3 w0.102: v2(99.59,12.98) 99.59,13.26 99.23,13.62 97.45,13.62 96.55,14.52 93.05,14.52 v2(92.78,14.79)
  IN3 w0.127: v2(99.59,12.98) 99.97,13.37 100.23,13.37 100.36,13.49 100.36,13.9 100.49,14.03 100.74,14.03 100.87,13.9 100.87,13.49 101,13.37 101.25,13.37 101.38,13.49 101.38,13.9 101.5,14.03 101.76,14.03 101.88,13.9 101.88,13.49 102.14,13.24 107.07,13.24 107.58,13.75 109.36,13.75 109.51,13.59 110.3,13.59 v2(110.91,12.98) 111.9,13.98 112.23,13.98 112.36,13.85 112.36,13.39 112.48,13.26 112.74,13.26 112.86,13.39 112.86,13.85 112.99,13.98 118.2,13.98 120.53,16.3 122.02,16.3 v2(122.42,15.9) 122.97,16.45 123.19,16.45 123.32,16.32 123.32,15.83 123.44,15.7 123.7,15.7 123.82,15.83 123.82,16.32 123.95,16.45 124.2,16.45 124.33,16.32 124.33,15.83 124.46,15.7 124.71,15.7 124.84,15.83 124.84,16.32 124.97,16.45 130.25,16.45 130.32,16.52 133.15,16.52 v2(133.75,15.92)
  BOTTOM w0.102: UC1.AF25 109.16,56.8 108.83,57.13 v2(108.83,57.16)
DDR_A_MA8: length 149.6
  TOP w0.107: UD1.R2 97.03,13.96 97.53,13.96 97.67,13.9 97.81,13.76 97.94,13.44 97.94,13.32 98.04,12.88 99.03,11.88 v2(99.03,11.87) ; v2(110.35,11.87) 109.36,12.86 109.26,13.32 109.26,13.44 109.13,13.76 108.98,13.9 108.85,13.96 108.35,13.96 UD2.R2 ; UD3.R2 119.86,16.88 120.36,16.88 120.5,16.82 120.64,16.68 120.77,16.36 120.77,16.24 120.87,15.78 v2(121.87,14.79) ; UD4.R2 131.19,16.89 131.69,16.89 131.83,16.83 131.97,16.69 132.1,16.38 132.1,16.26 132.2,15.8 v2(133.19,14.8)
  TOP w0.188: v2(89.78,14.15) 89.65,14.28 RD11.2
  IN1 w0.102: v2(89.78,14.15) 91.35,12.58 93.08,12.58 93.97,11.69 97.55,11.69 98.21,12.35 98.55,12.35 v2(99.03,11.87) 99.03,11.98 99.45,12.39 105.59,12.39 105.69,12.49 105.69,12.71 105.8,12.81 106,12.81 106.1,12.71 106.1,12.49 106.2,12.39 106.41,12.39 106.51,12.49 106.51,12.86 106.61,12.96 106.81,12.96 106.91,12.86 106.91,12.49 107.02,12.39 107.22,12.39 107.32,12.49 107.32,12.86 107.42,12.96 107.63,12.96 107.73,12.86 107.73,12.49 107.83,12.39 109.88,12.39 110.35,11.92 v2(110.35,11.87) 110.5,12.02 110.5,12.12 110.75,12.37 111.6,12.37 113.17,13.95 118.94,13.95 119.07,14.08 119.07,14.86 119.14,14.94 119.37,14.94 119.47,14.84 119.47,14.58 119.57,14.48 119.78,14.48 119.88,14.58 119.88,14.84 119.98,14.94 120.72,14.94 120.97,15.19 121.53,15.19 121.87,14.86 v2(121.87,14.79) 122.27,15.19 123.4,15.19 123.5,15.09 123.5,14.69 123.61,14.58 123.81,14.58 123.91,14.69 123.91,15.04 124.01,15.14 124.19,15.14 124.32,15.02 124.32,14.69 124.42,14.58 124.62,14.58 124.72,14.69 124.72,15.04 124.82,15.14 125,15.14 125.13,15.02 125.13,14.69 125.23,14.58 125.43,14.58 125.54,14.69 125.54,14.94 125.64,15.04 129.81,15.04 130.15,15.39 132.67,15.39 133.19,14.86 v2(133.19,14.8)
  IN2 w0.102: 105.82,53.53 105.82,53.56 105.76,53.62 105.76,55.81 106.29,56.34 106.29,59.19 106.82,59.72 107.13,59.72 107.46,60.05 109.06,60.05 109.44,59.67 109.44,58.55 109.87,58.12 v2(109.87,58.1)
  IN2 w0.198: 105.82,53.53 105.82,50.74 108.35,48.21 110.99,48.21 111.29,47.91 111.29,44.48 111.61,44.16 111.61,43.76 112.77,42.6 112.77,41.67 116.91,37.53 116.91,32.95 116.51,32.55 116.51,24.4 116.27,24.16 116.27,16.87 116.9,16.24 116.9,15.62 116.6,15.32 116.6,14.35 116.9,14.05 116.9,13.22 119.12,11 120.34,11 120.5,10.84 125.29,10.84 125.96,11.51 126.34,11.51 127.45,12.62 127.74,12.62 127.86,12.5 128.13,12.5 128.42,12.79 128.42,13.06 128.3,13.18 128.3,13.45 129.72,14.86 131.64,14.86 132.02,15.25 132.93,15.25 133.19,14.99 v2(133.19,14.8)
  BOTTOM w0.102: UC1.AF24 v2(109.87,58.1)
DDR_A_MA9: length 142.2
  TOP w0.107: UD4.R7 134.77,17.29 133.83,16.36 133.63,16.36 v2(133.19,15.92) ; UD3.R7 123.44,17.28 122.51,16.34 122.31,16.34 v2(121.87,15.9) ; UD2.R7 111.92,14.36 110.99,13.42 110.79,13.42 v2(110.35,12.98) ; v2(99.03,12.98) 99.47,13.42 99.67,13.42 100.61,14.36 UD1.R7
  TOP w0.188: v2(88.87,16.74) 88.3,16.74 RD12.2
  IN2 w0.089: 131.59,15.52 132.8,15.52 v2(133.19,15.92)
  IN2 w0.102: v2(107.86,59.67) 107.59,59.39 106.8,59.39 106.52,59.11 106.52,56.24 105.96,55.68 105.96,53.93 106.34,53.55 106.34,53.29
  IN2 w0.198: 106.34,53.29 106.34,50.75 108.47,48.62 111.12,48.62 111.8,47.94 111.8,45.02 112.77,44.05 112.77,43.34 113.27,42.83 113.27,41.87 117.67,37.48 117.67,32.64 116.96,31.94 116.96,24.19 116.78,24.01 116.78,22.29 116.97,22.1 117.3,22.1 117.49,21.91 117.49,21.5 117.3,21.31 116.97,21.31 116.78,21.12 116.78,20.02 116.97,19.83 117.17,19.83 117.36,19.63 117.36,19.23 117.17,19.03 116.97,19.03 116.78,18.84 116.78,18.27 117.54,17.51 117.54,16.39 117.44,16.29 117.44,15.37 117.64,15.17 118.18,15.17 118.38,14.97 118.38,14.58 118.18,14.38 117.64,14.38 117.44,14.18 117.44,13.78 117.64,13.59 118.18,13.59 118.38,13.39 118.38,12.53 119.37,11.54 120.72,11.54 120.91,11.34 124.41,11.34 125.14,12.07 126.16,12.07 129.46,15.37 129.98,15.37 130.32,15.7 130.8,15.7 131.13,15.37 131.43,15.37 131.59,15.52
  IN3 w0.102: v2(88.87,16.74) 88.99,16.62 89.96,16.62 91.15,15.42 91.15,14.76 91.74,14.18 92.94,14.18 93.73,13.39 98.8,13.39 99.03,13.15 v2(99.03,12.98)
  IN3 w0.127: v2(133.19,15.92) 132.81,16.3 132.46,16.3 132.28,16.11 130.48,16.11 129.95,15.58 128.28,15.58 128.16,15.7 128.16,16.08 128.03,16.21 127.78,16.21 127.65,16.08 127.65,15.57 127.52,15.44 127.27,15.44 127.14,15.57 127.14,16.08 127.01,16.21 126.76,16.21 126.63,16.08 126.63,15.57 126.51,15.44 122.33,15.44 v2(121.87,15.9) 121.46,15.5 120.23,15.5 117.3,12.57 114.84,12.57 114.65,12.38 114.08,12.38 113.96,12.51 113.96,12.73 113.83,12.86 113.57,12.86 113.45,12.73 113.45,12.51 113.32,12.38 113.07,12.38 112.94,12.51 112.94,12.73 112.81,12.86 112.56,12.86 112.43,12.73 112.43,12.51 112.3,12.38 110.95,12.38 v2(110.35,12.98) 109.97,13.37 107.69,13.37 107.22,12.9 103.82,12.9 103.69,12.77 103.69,12.48 103.56,12.35 103.31,12.35 103.18,12.48 103.18,12.77 103.05,12.9 102.83,12.9 102.7,12.77 102.7,12.48 102.58,12.35 102.32,12.35 102.2,12.48 102.2,12.77 102.07,12.9 101.81,12.9 101.69,12.77 101.69,12.48 101.56,12.35 101.31,12.35 101.18,12.48 101.18,12.77 101.05,12.9 100.8,12.9 100.44,12.53 99.49,12.53 v2(99.03,12.98)
  BOTTOM w0.102: UC1.AE21 108.04,59.67 v2(107.86,59.67)
DDR_A_MA10: length 137.6
  TOP w0.107: UD2.M3 109.07,16.76 v2(109.79,16.03) ; v2(98.48,16.03) 97.75,16.76 UD1.M3 ; v2(132.64,18.96) 131.91,19.69 UD4.M3 ; UD3.M3 120.58,19.68 v2(121.31,18.95)
  TOP w0.188: RD13.2 88.88,19.12 v2(88.89,19.11)
  IN1 w0.091: v2(109.79,16.03) 110.17,15.65 111.35,15.65
  IN1 w0.102: v2(109.79,16.03) 109.72,15.96 103.74,15.96 103.64,15.85 103.64,15.55 103.54,15.45 103.33,15.45 103.23,15.55 103.23,15.85 103.13,15.96 102.25,15.96 102.15,15.85 102.15,15.46 102.05,15.36 101.84,15.36 101.74,15.46 101.74,15.85 101.64,15.96 101.44,15.96 101.33,15.85 101.33,15.46 101.23,15.36 101.03,15.36 100.93,15.46 100.93,15.85 100.83,15.96 100.3,15.96 99.97,15.63 98.88,15.63 v2(98.48,16.03) 96.66,16.03 95.98,15.35 95.06,15.35 93.89,16.52 93.56,16.52 93.19,16.89 92.36,16.89 90.14,19.11 v2(88.89,19.11) ; 111.35,15.65 111.79,16.09 113.89,16.09 117.03,19.23 119.07,19.23 119.17,19.13 119.17,18.74 119.27,18.64 119.48,18.64 119.58,18.74 119.58,19.13 119.68,19.23 121.03,19.23 v2(121.31,18.95) 121.71,18.55 122.75,18.55 122.94,18.74 125.91,18.74 126.42,19.25 126.65,19.25 126.75,19.15 126.75,18.65 126.86,18.55 127.06,18.55 127.16,18.65 127.16,19.15 127.26,19.25 127.46,19.25 127.57,19.15 127.57,18.65 127.67,18.55 127.87,18.55 127.97,18.65 127.97,19.15 128.07,19.25 132.35,19.25 v2(132.64,18.96) 133.03,18.57 134.13,18.57
  IN1 w0.16: 134.13,18.57 134.55,19 137.3,19 137.79,19.49 139.67,19.49 140.16,19 142.53,19 144.01,20.48 v2(144.34,20.48)
  IN2 w0.102: 125.89,57.62 123.22,57.62 122.84,57.99 117.45,57.99 117.03,58.41 115.57,58.41 115.36,58.63 115.36,58.88 115.04,59.2 114.27,59.2 v2(113.87,59.6)
  IN2 w0.127: 125.89,57.62 127.02,56.49 128.94,56.49 129.26,56.17 129.26,55.8
  IN2 w0.198: v2(144.34,20.48) 144.34,22.61 144.69,22.97 144.69,30.87 140.68,34.88 140.68,40.04 138.05,42.66 138.05,43.17 138.51,43.63 138.51,43.91 138.32,44.1 138.04,44.1 137.57,43.63 137.29,43.63 137.09,43.83 137.09,44.09 137.62,44.62 137.62,44.9 137.42,45.1 137.14,45.1 136.67,44.63 136.39,44.63 136.11,44.91 136.11,45.19 136.58,45.66 136.58,45.94 136.31,46.21 136.31,50.07 133.33,53.05 132.01,53.05 129.26,55.8
  BOTTOM w0.102: UC1.AL21 113.48,60 v2(113.87,59.6)
DDR_A_MA11: length 144.9
  TOP w0.107: UD4.T2 130.79,16.09 132.49,14.4 132.84,14.3 v2(133.24,13.9) ; UD2.T2 107.95,13.16 109.65,11.46 109.99,11.36 v2(110.39,10.97) ; UD3.T2 119.47,16.08 121.16,14.38 121.51,14.28 v2(121.91,13.89) ; v2(99.07,10.97) 98.68,11.36 98.33,11.46 96.63,13.16 UD1.T2
  TOP w0.188: RD14.2 91.96,11.96 91.96,11.87 v2(91.56,11.46)
  IN2 w0.198: v2(108.88,54.95) 108.83,54.89 108.83,51.08 109.26,50.65 111.83,50.65 114.09,48.39 114.09,46.64 115.08,45.65 115.08,44.25 115.55,43.77 115.55,42.81 120.27,38.09 120.27,30.3 122.37,28.2 122.37,26.68 122.17,26.48 120.89,26.48 120.69,26.28 120.69,25.89 120.89,25.69 121.65,25.69 121.89,25.46 121.89,24.9 122.08,24.71 122.36,24.71 122.52,24.87 122.52,25.87 122.7,26.05 122.95,26.05 123.13,25.87 123.13,15.07 123.33,14.86 123.8,14.86 123.99,15.06 123.99,16.72 124.22,16.95 126.03,16.95 128.49,19.41 129.63,19.41 130.22,18.83 130.73,18.83 130.88,18.68 130.88,18.16 131.08,17.96 131.4,17.96 131.54,18.1 131.54,18.7 131.66,18.83 131.97,18.83 132.17,18.63 132.17,17.73 132.37,17.53 134.31,17.53 135.6,16.24 135.6,15.53 135.75,15.37 136.05,15.37 136.19,15.23 136.19,14.94 135.99,14.74 135.73,14.74 135.6,14.61 135.6,14.2 134.64,13.24 133.59,13.24 133.24,13.6 v2(133.24,13.9)
  IN3 w0.102: v2(99.07,10.97) 98.57,10.97 97.66,11.88 93.45,11.88 93.4,11.93 92.03,11.93 v2(91.56,11.46)
  IN3 w0.127: v2(133.24,13.9) 132.29,12.96 129.78,12.96 129.4,13.35 125.15,13.35 125.02,13.47 125.02,13.85 124.89,13.98 124.64,13.98 124.51,13.85 124.51,13.47 124.38,13.35 124.13,13.35 124,13.47 124,13.9 123.88,14.03 123.62,14.03 123.49,13.9 123.49,13.47 123.37,13.35 122.45,13.35 v2(121.91,13.89) 120.97,12.96 120.64,12.96 120.01,12.32 120.01,11.99 119.78,11.77 119.42,11.77 118.63,10.98 114.48,10.98 113.92,10.42 113.92,10.04 113.79,9.91 113.54,9.91 113.41,10.04 113.41,10.42 113.29,10.55 110.81,10.55 v2(110.39,10.97) 109.95,11.41 109.32,11.41 109.19,11.28 109.19,10.75 109.06,10.62 108.81,10.62 108.68,10.75 108.68,11.28 108.55,11.41 107.89,11.41 107.61,11.13 105.93,11.13 105.81,11 105.81,10.86 105.68,10.74 105.43,10.74 105.3,10.86 105.3,11.03 105.2,11.13 104.67,11.13 104.4,11.4 103.25,11.4 102.4,10.55 99.5,10.55 v2(99.07,10.97)
  BOTTOM w0.102: v2(108.88,54.95) 109.02,54.95 UC1.AF27
DDR_A_MA12: length 138.5
  TOP w0.107: v2(110.91,17.05) 111.34,17.05 111.63,16.76 111.95,16.76 UD2.M7 ; UD1.M7 100.63,16.76 100.32,16.76 100.02,17.05 v2(99.62,17.05) ; UD3.M7 123.47,19.68 123.15,19.68 122.86,19.97 v2(122.42,19.97) ; v2(133.75,19.98) 134.19,19.98 134.48,19.69 UD4.M7
  TOP w0.188: v2(89.7,20.17) 89.58,20.17 89.22,20.53 88.46,20.53 RD15.2
  IN2 w0.102: v2(108.83,57.99) 108.83,57.74 109.46,57.1 109.46,55.53 109.64,55.35 109.64,53.8 110.94,52.51 111.47,52.51 111.98,52
  IN2 w0.198: v2(133.75,19.98) 133.75,20.1 133.45,20.4 132.42,20.4 132.22,20.6 132.22,21.27 132.02,21.47 131.68,21.47 131.49,21.27 131.49,20.95 131.24,20.71 130.96,20.71 130.7,20.97 130.7,21.27 130.5,21.47 128.7,21.47 127.75,22.41 127.75,25.99 127.14,26.6 127.14,27.01 127.34,27.2 127.9,27.2 128.1,27.4 128.1,27.8 127.9,28 127.66,28 127.46,28.19 127.46,28.5 127.61,28.66 128.76,28.66 128.9,28.8 128.9,29.18 128.72,29.36 127.64,29.36 127.49,29.51 127.49,29.88 127.66,30.05 128.13,30.05 128.37,30.29 128.37,30.57 128.17,30.76 124.12,30.76 123.88,31.01 123.88,31.29 124.21,31.61 128.48,31.61 128.68,31.81 128.68,32.2 128.47,32.41 124.06,32.41 123.86,32.6 123.86,33 124.06,33.2 126.89,33.2 127.08,33.4 127.08,33.79 126.89,33.99 124.06,33.99 123.86,34.19 123.86,34.59 124.06,34.78 125.3,34.78 125.5,34.98 125.5,35.38 125.3,35.58 124.06,35.58 123.86,35.77 123.86,36.26 123.02,37.1 123.02,37.86 117.13,43.75 117.13,44.64 116.6,45.17 116.6,47.15 115.76,47.99 115.76,48.21 111.98,52
  IN3 w0.102: v2(99.62,17.05) 99.62,17.06 99.27,17.42 98.31,17.42 97.7,16.81 96.02,16.81 95.62,17.2 94.84,17.2 92.99,19.06 90.82,19.06 v2(89.7,20.17)
  IN3 w0.127: v2(133.75,19.98) 133.26,20.48 132.6,20.48 131.99,21.09 130.7,21.09 129.76,20.15 125.39,20.15 124.83,19.59 124.11,19.59 123.99,19.72 123.99,20.2 123.86,20.32 123.61,20.32 123.48,20.2 123.48,19.72 123.35,19.59 123.08,19.59 122.95,19.72 122.95,20.15 122.83,20.27 122.55,20.27 122.42,20.15 v2(122.42,19.97) 122.04,20.36 121.14,20.36 120.91,20.13 120.91,20.13 119.71,18.93 117.46,18.93 116.39,17.86 115.54,17.86 115.42,17.99 115.42,18.5 115.29,18.62 115.04,18.62 114.91,18.5 114.91,17.99 114.78,17.86 113.73,17.86 112.92,17.05 v2(110.91,17.05) 110.91,17.18 110.66,17.43 109.45,17.43 109.3,17.28 103.83,17.28 103.6,17.05 102.91,17.05 102.79,16.92 102.79,16.63 102.66,16.5 102.41,16.5 102.28,16.63 102.28,16.92 102.15,17.05 101.9,17.05 101.77,16.92 101.77,16.63 101.64,16.5 101.39,16.5 101.26,16.63 101.26,16.92 101.14,17.05 100.88,17.05 100.75,16.92 100.75,16.63 100.63,16.5 100.37,16.5 100.25,16.63 100.25,16.92 100.12,17.05 v2(99.62,17.05)
  BOTTOM w0.102: v2(108.83,57.99) 108.42,58.4 UC1.AE23
DDR_A_MA13: length 143.4
  TOP w0.107: v2(122.45,14.79) 122.82,15.03 UD3.T8 ; UD2.T8 112.75,13.56 111.66,12.46 111,12.03 v2(110.91,11.97) ; v2(133.75,14.9) 133.84,14.96 134.5,15.4 UD4.T8 ; UD1.T8 100.34,12.46 99.68,12.03 v2(99.59,11.97)
  TOP w0.188: RD16.2 88.55,15.6 88.61,15.6 88.64,15.58 89.29,15.58 v2(89.32,15.55)
  IN1 w0.16: v2(133.75,14.9) 137.97,14.9 138.13,14.74 138.13,14.16 138.29,14 138.61,14 138.77,14.16 138.77,14.74 138.93,14.9 139.25,14.9 139.41,14.74 139.41,14.14 139.57,13.98 139.89,13.98 140.05,14.14 140.05,14.74 140.21,14.9 140.56,14.9 140.72,14.74 140.72,14.19 140.88,14.03 141.2,14.03 141.36,14.19 141.36,14.74 143.27,16.65 v2(143.27,16.97)
  IN2 w0.102: v2(114.85,57.93) 115.36,57.42 115.36,57.1 115.66,56.8 117.34,56.8 117.45,56.91 120.6,56.91 121.1,56.42 122.01,56.42 122.22,56.62 125.31,56.62 126.2,55.73 127.32,55.73 127.65,55.4 127.65,53.74 128.08,53.31 128.83,53.31 129.06,53.08 129.06,52.61 129.23,52.44
  IN2 w0.198: 129.23,52.44 129.33,52.33 129.33,50.45 128.63,49.75 128.63,47.74 130.63,45.74 132.21,45.74 132.22,45.75 133.16,45.75 139.4,39.52 139.4,34.69 143.7,30.39 143.7,23.54 143.22,23.06 143.22,17.48 143.27,17.43 v2(143.27,16.97)
  IN3 w0.102: v2(89.32,15.55) 89.78,15.55 91.63,13.7 92.8,13.7 93.61,12.88 97.53,12.88 98.03,12.38 99.18,12.38 99.59,11.97 v2(99.59,11.97)
  IN3 w0.127: v2(133.75,14.9) 133.24,15.41 132.08,15.41 131.68,15.81 131.19,15.81 130.47,15.09 126,15.09 125.88,14.96 125.88,14.74 125.75,14.61 125.5,14.61 125.37,14.74 125.37,14.96 125.24,15.09 124.99,15.09 124.86,14.96 124.86,14.74 124.73,14.61 124.48,14.61 124.35,14.74 124.35,14.96 124.23,15.09 123.97,15.09 123.85,14.96 123.85,14.74 123.72,14.61 123.46,14.61 123.34,14.74 123.34,14.96 123.21,15.09 122.75,15.09 v2(122.45,14.79) 121.96,15.28 120.72,15.28 120.33,14.89 120.33,14.71 120.48,14.56 120.48,14.38 120.3,14.2 120.12,14.2 119.92,14.4 119.74,14.4 119.56,14.22 119.56,14.04 119.76,13.84 119.76,13.66 119.58,13.48 119.41,13.48 119.34,13.54 119.16,13.54 117.97,12.35 115.33,12.35 114.95,11.97 v2(110.91,11.97) 110.48,12.39 109.49,12.39 109.24,12.64 108.5,12.64 108.37,12.77 108.37,12.98 108.25,13.11 107.99,13.11 107.87,12.98 107.87,12.77 107.74,12.64 106.29,12.64 106.16,12.52 106.16,12.2 106.04,12.08 105.81,12.08 105.69,12.2 105.69,12.53 105.56,12.65 105.3,12.65 105.18,12.53 105.18,12.2 105.05,12.08 104.8,12.08 104.67,12.2 104.67,12.53 104.54,12.65 104.29,12.65 104.16,12.53 104.16,12.2 104.03,12.08 99.7,12.08 v2(99.59,11.97)
  BOTTOM w0.102: v2(114.85,57.93) 114.38,58.4 UC1.AM23
DDR_A_ODT0: length 134
  TOP w0.107: v2(132.64,22.04) 132.34,22.04 UD4.K3 ; UD1.K3 98.18,19.11 v2(98.48,19.11) ; UD3.K3 121.02,22.03 v2(121.31,22.03) ; v2(109.79,19.11) 109.5,19.11 UD2.K3
  TOP w0.188: RD20.2 v2(92.02,22.67)
  IN1 w0.102: v2(92.02,22.67) 92.02,22.56 92.47,22.1 93.36,22.1 94.78,20.68 95.29,20.68 96.87,19.11 v2(98.48,19.11) 98.83,19.46 101.9,19.46 102.63,18.73 103.6,18.73 103.71,18.83 103.71,19.21 103.81,19.31 104.01,19.31 104.11,19.21 104.11,18.83 104.21,18.73 104.42,18.73 104.52,18.83 104.52,19.23 104.62,19.33 104.82,19.33 104.92,19.23 104.92,18.83 105.03,18.73 106.65,18.73 107.05,18.32 108.45,18.32 109.24,19.11 v2(109.79,19.11) 110.32,19.64 112.2,19.64 112.31,19.74 112.31,20.05 112.41,20.15 112.61,20.15 112.71,20.05 112.71,19.74 112.81,19.64 113.04,19.64 113.14,19.74 113.14,20.05 113.25,20.15 113.45,20.15 113.55,20.05 113.55,19.74 113.65,19.64 114.64,19.64 116.74,21.75 121.03,21.75 v2(121.31,22.03) 121.66,22.38 122.72,22.38 123.1,22 123.42,22 123.53,22.1 123.53,22.48 123.63,22.58 123.83,22.58 123.93,22.48 123.93,21.75 124.03,21.64 124.24,21.64 124.34,21.75 124.34,22.48 124.44,22.58 124.64,22.58 124.74,22.48 124.74,22.1 124.85,22 132.6,22 v2(132.64,22.04) 132.64,22.36 132.92,22.65 133.91,22.65 134.08,22.81
  IN1 w0.16: v2(143.09,23.78) 143.07,23.75 142.65,23.75 142.49,23.91 142.49,25.02 142.33,25.18 142.01,25.18 141.85,25.02 141.85,23.91 141.69,23.75 141.37,23.75 141.21,23.91 141.21,25.02 141.05,25.18 140.73,25.18 140.57,25.02 140.57,23.91 140.41,23.75 140.09,23.75 139.93,23.91 139.93,25.02 139.77,25.18 139.45,25.18 139.29,25.02 139.29,23.91 139.13,23.75 138.81,23.75 138.65,23.91 138.65,25.02 138.49,25.18 138.17,25.18 138.01,25.02 138.01,23.91 137.85,23.75 137.53,23.75 137.37,23.91 137.37,25.02 137.21,25.18 136.89,25.18 136.73,25.02 136.73,23.91 136.57,23.75 135.73,23.75 135.4,23.42 134.69,23.42 134.08,22.81
  IN2 w0.102: 128.07,48.83 128.07,49.1 127.93,49.23 127.93,52.41 127.42,52.91 126.97,52.91 126.48,53.4 126.48,55.05 125.19,56.34 122.55,56.34 122.22,56.01 119.37,56.01 119.27,56.11 118.56,56.11 118.46,56.01 115.57,56.01 115.29,56.29 115.29,56.79 114.88,57.2 v2(114.87,57.2)
  IN2 w0.198: 128.07,48.83 128.07,47.59 130.42,45.24 132.46,45.24 134.64,43.06 134.71,43.06 138.65,39.12 138.65,34.72 142.95,30.41 142.95,23.92 v2(143.09,23.78)
  BOTTOM w0.102: v2(114.87,57.2) 114.48,57.6 UC1.AM24
DDR_A_PAR: length 140.7
  TOP w0.107: v2(98.48,11.89) 97.72,12.64 UD1.T3 ; v2(109.79,11.89) 109.04,12.64 UD2.T3 ; v2(121.31,14.81) 120.56,15.56 UD3.T3 ; v2(132.64,14.82) 131.88,15.57 131.59,16.49 UD4.T3
  TOP w0.188: RD2.2 89.18,13.49 89.65,13.02 v2(89.65,12.93)
  IN2 w0.102: 127.61,48.83 127.61,52.19 127.3,52.51 126.85,52.51 126.05,53.31 126.05,54.92 125.31,55.66 124.37,55.66 123.82,55.1 120.36,55.1 120.13,55.33 117.34,55.33 117.26,55.25 116.73,55.25 116.65,55.33 115.23,55.33 115.18,55.28 114.8,55.28 114.48,55.6 114.48,57.12 113.99,57.61 112.37,57.61 v2(111.93,58.06)
  IN2 w0.198: v2(132.64,14.82) 132.19,14.37 132.19,13.67 133.12,12.74 134.85,12.74 137.01,14.89 141.85,14.89 142.59,15.63 142.59,22.84 142.5,22.92 142.5,30.15 137.86,34.79 137.86,39.1 132.22,44.73 130.21,44.73 127.61,47.33 127.61,48.83
  IN3 w0.102: v2(98.48,11.89) 98.11,11.89 97.63,12.38 95.95,12.38 95.95,12.38 93.4,12.38 93.15,12.63 91.1,12.63 90.45,13.28 90,13.28 v2(89.65,12.93)
  IN3 w0.127: v2(132.64,14.82) 132.18,14.37 130.03,14.37 129.9,14.24 129.9,13.98 129.78,13.85 129.52,13.85 129.39,13.98 129.39,14.24 129.27,14.37 128.97,14.37 128.84,14.5 128.84,14.53 128.72,14.66 128.46,14.66 128.34,14.53 128.34,14.5 128.21,14.37 127.95,14.37 127.83,14.5 127.83,14.75 127.7,14.87 127.45,14.87 127.32,14.75 127.32,14.5 127.19,14.37 126.94,14.37 126.81,14.5 126.81,14.75 126.68,14.87 126.43,14.87 126.3,14.75 126.3,14.56 126.13,14.38 121.73,14.38 v2(121.31,14.81) 119.56,13.06 119.19,13.06 117.87,11.74 115.54,11.74 115.2,11.4 114.28,11.4 114.15,11.53 114.15,11.63 114.03,11.75 113.77,11.75 113.64,11.63 113.64,11.53 113.52,11.4 113.26,11.4 113.14,11.53 113.14,11.63 113.01,11.75 112.76,11.75 112.63,11.63 112.63,11.53 112.5,11.4 112.25,11.4 112.12,11.53 112.12,11.63 111.99,11.75 111.74,11.75 111.61,11.63 111.61,11.53 111.49,11.4 110.28,11.4 v2(109.79,11.89) 109.71,11.97 107.97,11.97 107.49,11.49 107.13,11.49 106.78,11.83 102.63,11.83 102.53,11.73 102.53,11.23 102.44,11.13 102.21,11.13 102.11,11.24 102.11,11.7 101.98,11.83 101.8,11.83 101.67,11.7 101.67,11.16 101.55,11.03 101.29,11.03 101.17,11.16 101.17,11.7 101.04,11.83 100.13,11.83 99.76,11.46 98.99,11.46 98.78,11.54 98.48,11.85 v2(98.48,11.89)
  BOTTOM w0.102: UC1.AK24 112.37,57.61 v2(111.93,58.06)
DDR_A_RAS#: length 141.8
  TOP w0.107: v2(133.75,22.01) 133.75,21.72 134.54,20.93 135.16,20.93 UD4.L8 ; UD2.L8 112.31,18 111.7,18 110.91,18.78 v2(110.91,19.08) ; v2(99.59,19.08) 99.59,18.78 100.38,18 101,18 UD1.L8 ; UD3.L8 123.83,20.92 123.21,20.92 122.42,21.7 v2(122.42,22)
  TOP w0.188: RD19.2 92.1,20.26 92.73,20.88 v2(92.73,21.02)
  IN1 w0.102: v2(133.75,22.01) 133.34,21.6 127.96,21.6 127.86,21.49 127.86,21.04 127.76,20.93 127.55,20.93 127.45,21.04 127.45,21.49 127.35,21.6 127.15,21.6 127.04,21.49 127.04,21.04 126.94,20.93 126.74,20.93 126.64,21.04 126.64,21.49 126.54,21.6 126.31,21.6 125.84,21.12 125.36,21.12 125.13,21.36 123.07,21.36 v2(122.42,22) 121.92,21.49 116.98,21.49 114.75,19.26 112.88,19.26 112.77,19.16 112.77,18.9 112.67,18.79 112.47,18.79 112.37,18.9 112.37,19.16 112.27,19.26 112.02,19.26 111.92,19.16 111.92,18.83 111.82,18.73 111.61,18.73 111.51,18.83 111.51,19.16 111.41,19.26 111.09,19.26 v2(110.91,19.08) 110.3,18.47 109.06,18.47 108.19,17.61 105.66,17.61 105.55,17.71 105.55,18.04 105.45,18.14 105.25,18.14 105.15,18.04 105.15,17.68 105.05,17.58 103.65,17.58 103.55,17.68 103.55,17.99 103.45,18.09 103.24,18.09 103.14,17.99 103.14,17.68 103.04,17.58 101.72,17.58 100.22,19.08 v2(99.59,19.08) 98.98,18.47 98.18,18.47 97.82,18.1 95.91,18.1 95.54,18.48 94.47,18.48 94.12,18.83 94.12,19.9 93,21.02 v2(92.73,21.02)
  IN1 w0.16: v2(133.75,22.01) 134.22,22.01 134.72,21.51 137.04,21.51 137.2,21.67 137.2,22.39 137.36,22.55 137.63,22.55 137.76,22.42 137.76,21.31 137.9,21.17 138.28,21.17 138.4,21.28 138.4,22.61 138.54,22.75 138.9,22.75 139.06,22.59 139.06,21.35 139.22,21.19 139.58,21.19 139.74,21.35 139.74,22.59 139.9,22.75 144.38,22.75 144.54,22.59 144.54,22.21 144.35,22.03 140.81,22.03 140.63,21.85 v2(140.63,21.29)
  IN2 w0.102: v2(112.87,57.2) 113.45,56.62 113.45,54.72 113.59,54.58 114.51,54.58 114.57,54.51 115.05,54.51 116.17,53.4 118.74,53.4 119.07,53.73 121.45,53.73 121.89,54.16 124.17,54.16 124.4,53.93 124.4,52.81 125.01,52.2 125.44,52.2 125.82,51.82 125.82,48.93 125.72,48.83
  IN2 w0.198: 125.72,48.83 125.44,48.55 125.44,47.37 135.98,36.83 135.98,34.54 140.72,29.8 140.72,23.26 140.63,23.17 v2(140.63,21.29)
  BOTTOM w0.102: v2(112.87,57.2) 112.97,57.2 UC1.AL24
DDR_A_RST#: length 130.3
  TOP w0.107: v2(132.64,13.88) 130.39,16.13 130.39,17.7 UD4.P1 ; UD3.P1 119.06,17.68 119.06,16.12 v2(121.31,13.87) ; UD1.P1 96.23,14.76 96.23,13.2 98.72,10.71 ; 100.25,10.71 v2(100.5,10.95) ; v2(109.79,10.95) 107.54,13.2 107.54,14.76 UD2.P1
  TOP w0.117: 100.25,10.71 100.02,10.47 98.96,10.47 98.72,10.71
  IN1 w0.102: v2(132.64,13.88) 132.64,13.23 132.39,12.98 128.36,12.98 128.11,13.24 121.94,13.24 v2(121.31,13.87) 120.17,12.73 118.69,12.73 118.28,12.32 113.83,12.32 112,10.5 110.25,10.5 v2(109.79,10.95) 109.79,10.6 109.69,10.5 108.95,10.5 108.38,9.93 108.05,9.93 108.02,9.96 101.49,9.96 v2(100.5,10.95)
  IN2 w0.102: 107.41,53.29 107.41,53.37 107.15,53.62 107.15,54.67 v2(106.87,54.94)
  IN2 w0.127: 107.41,53.29 107.41,52.58 107.79,52.2 107.79,50.68 108.6,49.87 111.12,49.87 112.78,48.2 112.78,45.99 113.76,45.02 113.76,43.72 114.25,43.23 114.25,42.27 118.91,37.6 118.91,30.94 118.33,30.36 118.33,29.04 118.61,28.76 118.61,25.76 119.46,24.91 119.46,13.76 119.8,13.42 124.45,13.42 128.88,17.85 130.1,17.85 131.09,16.86 132.13,16.86 132.48,16.52 134.43,16.52 134.81,16.13 134.81,15.32 133.82,14.33 132.86,14.33 132.64,14.11 v2(132.64,13.88)
  BOTTOM w0.102: UC1.AD27 107.02,54.94 v2(106.87,54.94)
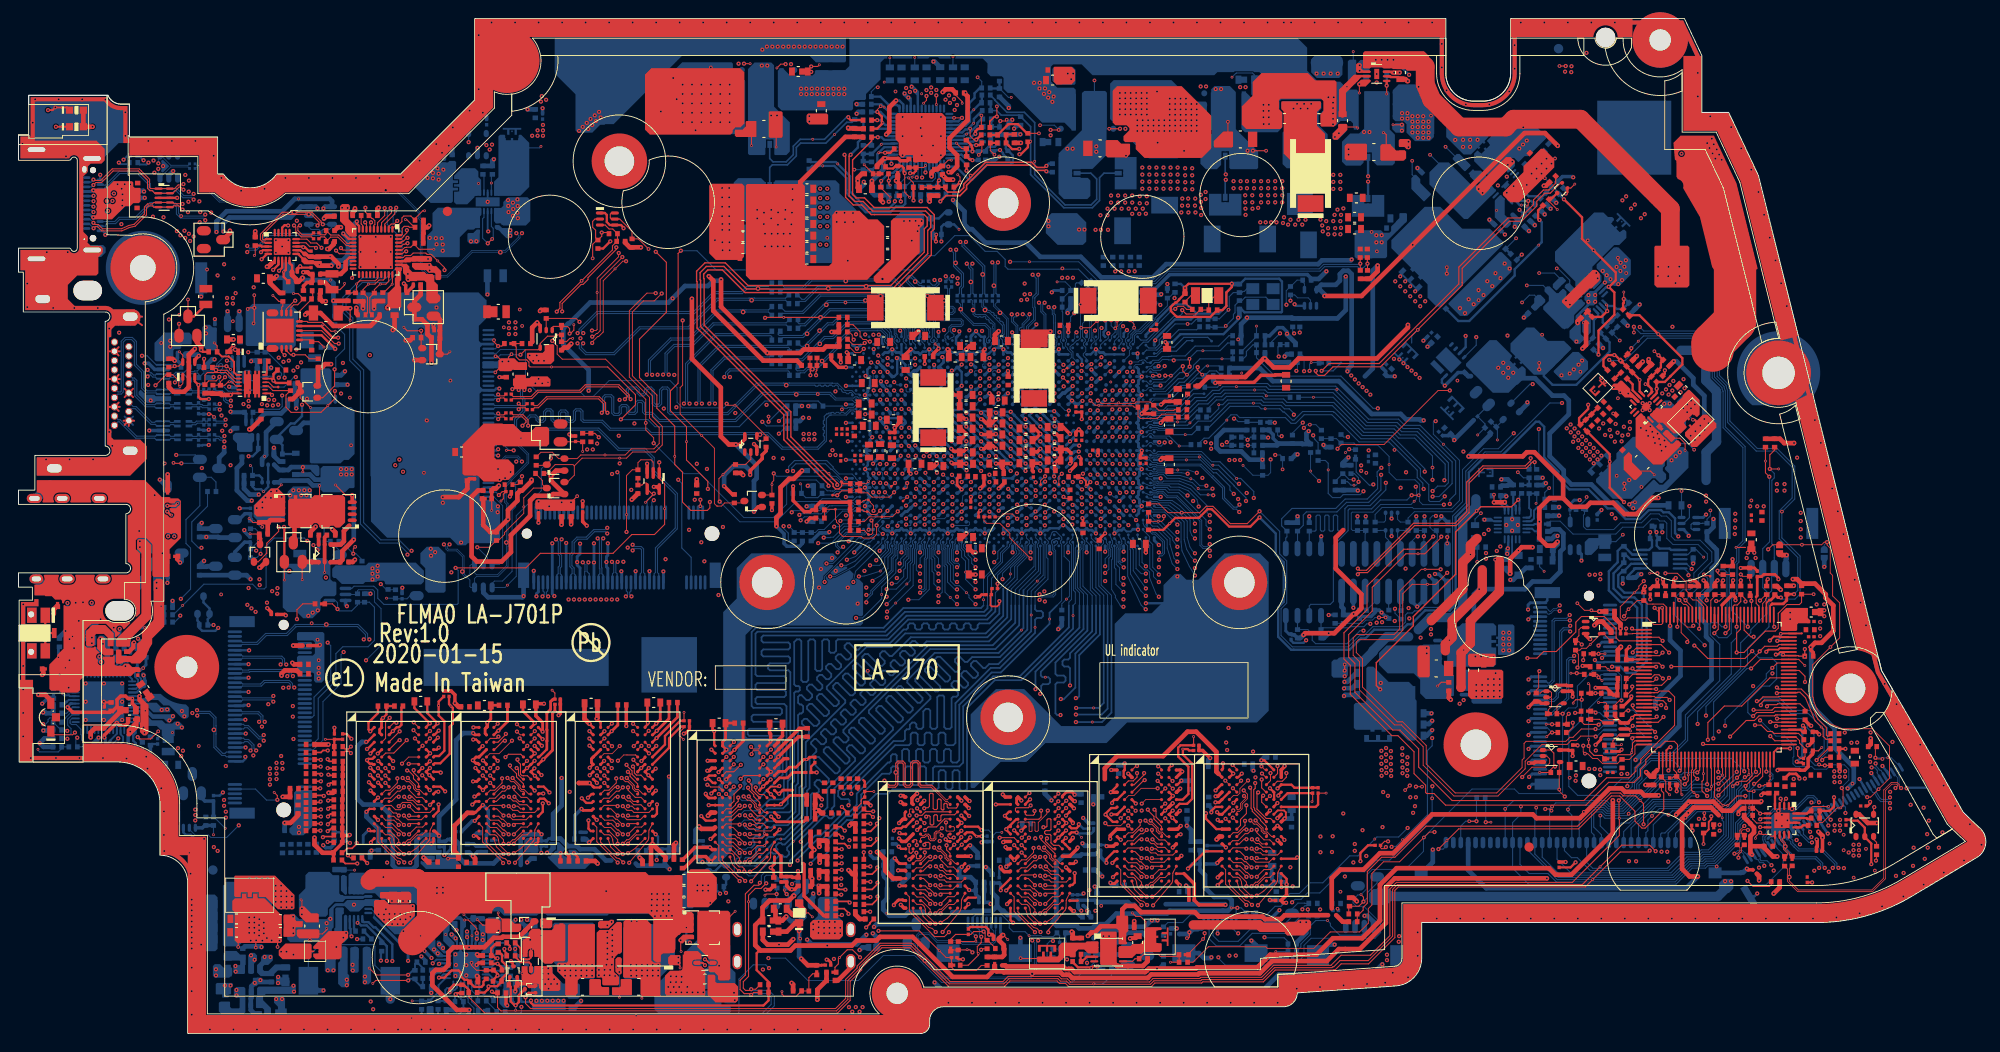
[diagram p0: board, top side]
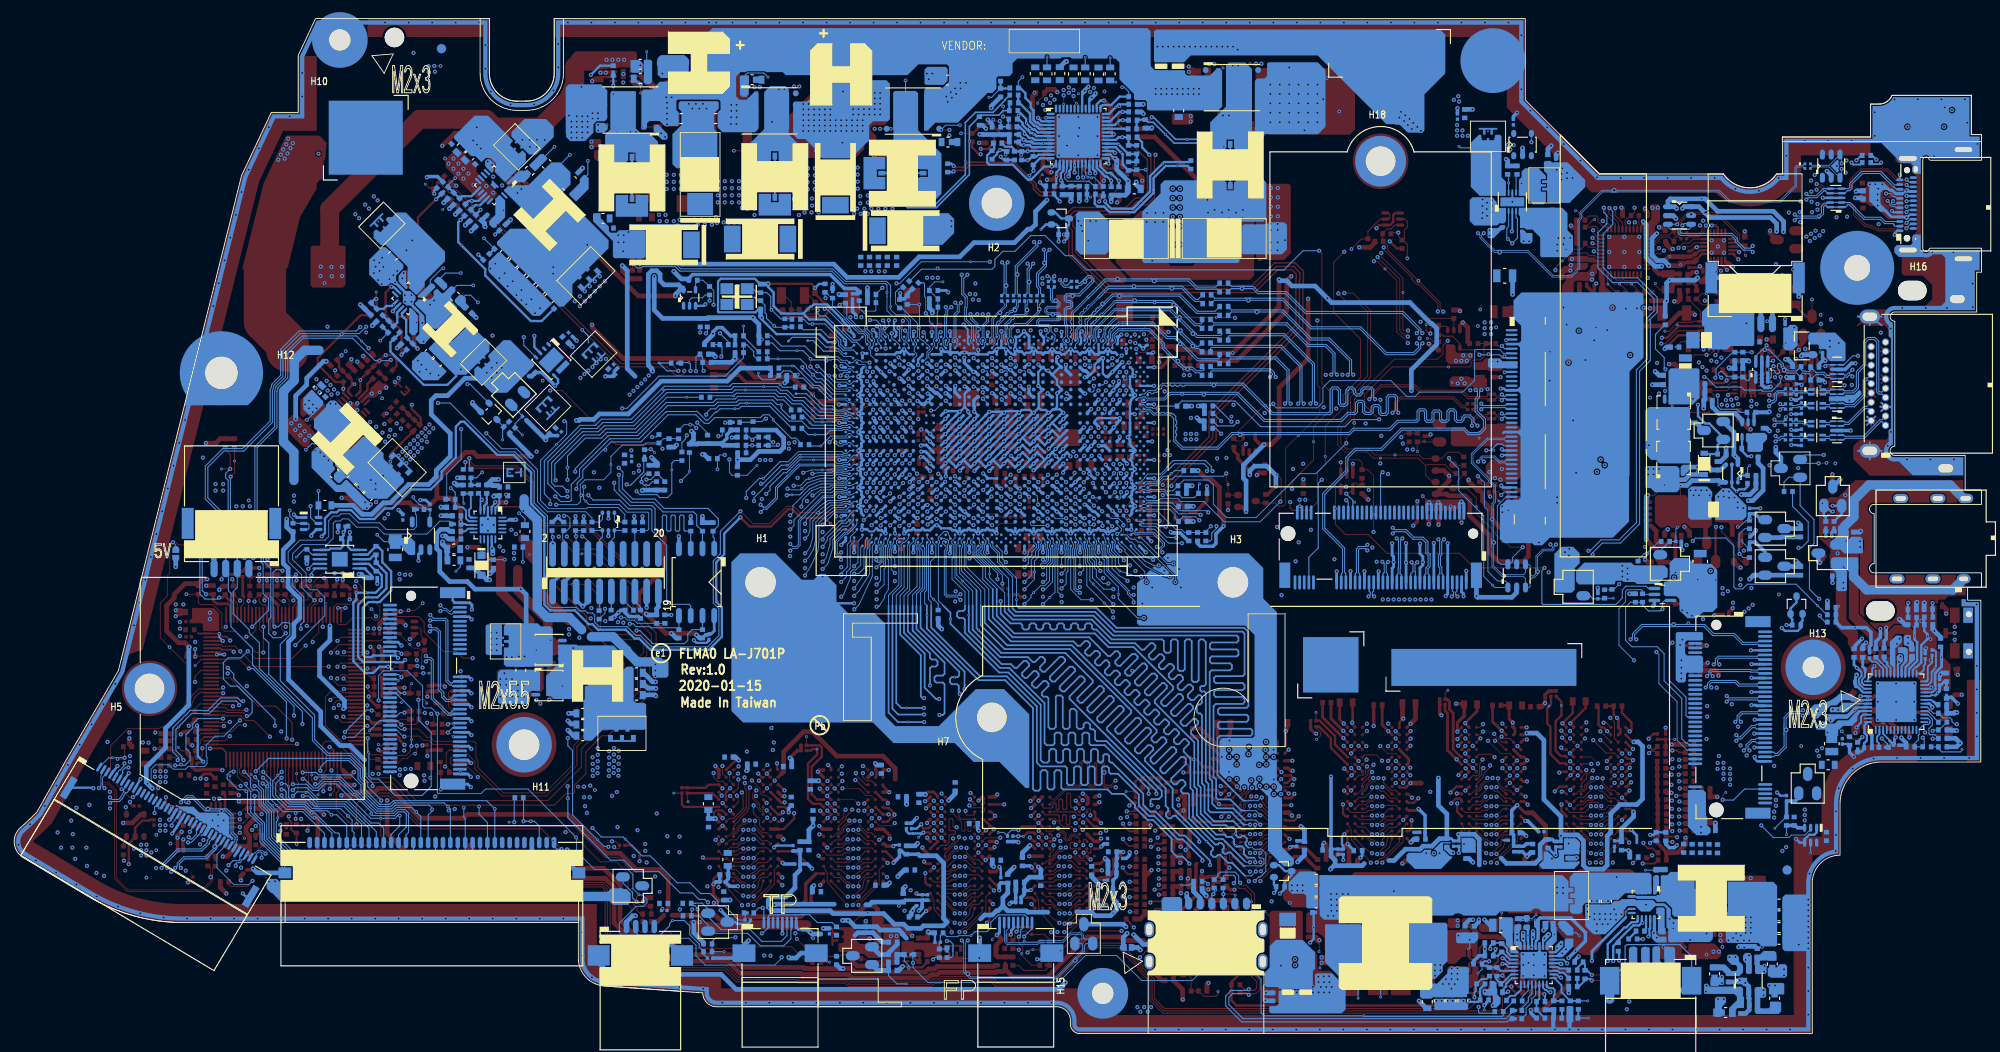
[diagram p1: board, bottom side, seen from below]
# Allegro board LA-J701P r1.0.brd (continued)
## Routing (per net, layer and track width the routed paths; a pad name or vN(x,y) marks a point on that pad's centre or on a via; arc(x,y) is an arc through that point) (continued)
DDR_A_WE#: length 145.2
  TOP w0.107: UD1.L2 96.98,17.91 97.57,17.91 98.34,18.67 98.62,18.67 v2(99.03,19.08) ; UD2.L2 108.3,17.91 108.89,17.91 109.65,18.67 109.94,18.67 v2(110.35,19.08) ; UD4.L2 131.14,20.84 131.73,20.84 132.5,21.6 132.78,21.6 v2(133.19,22.01) ; v2(121.87,22) 121.45,21.59 121.17,21.59 120.41,20.83 119.82,20.83 UD3.L2
  TOP w0.188: RD17.2 89.53,23.91 v2(88.94,24.49)
  IN1 w0.102: v2(88.94,24.49) 88.94,24.34 90.01,23.27 90.62,23.27 92.25,21.64 93.04,21.64 95.65,19.04 95.65,18.74 96.02,18.37 97.7,18.37 98.06,18.73 98.68,18.73 v2(99.03,19.08) ; 134.2,22.39 133.38,22.39 133.19,22.21 v2(133.19,22.01)
  IN1 w0.16: v2(145.18,21.98) 145.23,22.03 145.23,23.01 145.02,23.22 144.66,23.22 144.5,23.38 144.5,24.79 144.34,24.95 144.02,24.95 143.86,24.79 143.86,23.38 143.7,23.22 137.38,23.22 136.13,21.98 135.42,21.98 135.01,22.39 134.2,22.39
  IN2 w0.102: v2(114.77,59.6) 115.08,59.6 115.48,59.2 116.18,59.2 116.36,59.03 120.55,59.03 121.02,58.55 126.79,58.55 128.34,57 129.1,57 129.61,56.49
  IN2 w0.198: v2(145.18,21.98) 145.18,22.43 145.19,22.44 145.19,22.83 145.2,22.84 145.2,24.72 145.29,24.81 145.29,31 141.34,34.96 141.34,40.47 139.7,42.11 139.7,43.57 137.08,46.19 137.08,50.42 133.68,53.82 131.96,53.82 129.61,56.16 129.61,56.49
  IN3 w0.127: v2(133.19,22.01) 133.19,22.1 132.85,22.45 132.43,22.45 131.96,21.98 129.15,21.98 128.54,22.59 126.87,22.59 126.22,21.94 124.95,21.94 124.86,21.85 124.86,21.54 124.73,21.42 124.48,21.42 124.35,21.54 124.35,21.86 124.22,21.99 123.97,21.99 123.84,21.86 123.84,21.52 123.72,21.39 123.51,21.39 123.38,21.52 123.38,21.85 123.26,21.98 123,21.98 122.88,21.85 122.88,21.72 122.75,21.6 122.27,21.6 v2(121.87,22) 121.49,21.62 120.97,21.62 120.65,21.3 120.31,21.3 119.49,20.48 118.91,20.48 118.76,20.63 117.62,20.63 117.52,20.73 117.52,20.93 117.39,21.06 117.1,21.06 117.01,20.97 117.01,20.73 116.91,20.63 116.65,20.63 116.52,20.76 116.52,20.93 116.39,21.06 116.14,21.06 116.01,20.93 116.01,20.76 115.88,20.63 115.61,20.63 114.7,19.72 112.21,19.72 111.14,18.65 110.78,18.65 v2(110.35,19.08) 110,18.73 109.36,18.73 108.88,18.24 107.51,18.24 106.65,19.11 104.69,19.11 104.56,18.98 104.56,18.93 104.43,18.8 104.18,18.8 104.05,18.93 104.05,18.98 103.92,19.11 103.67,19.11 103.54,18.98 103.54,18.76 103.42,18.63 102.03,18.63 101.9,18.76 101.9,19 101.77,19.13 101.52,19.13 101.39,19 101.39,18.76 101.26,18.63 101.01,18.63 100.88,18.76 100.88,19 100.76,19.13 100.5,19.13 100.38,19 100.38,18.76 100.25,18.63 99.48,18.63 v2(99.03,19.08)
  BOTTOM w0.102: UC1.AM21 v2(114.77,59.6)
DDR_B_ACT#: length 130.9
  TOP w0.107: UD6.L3 51.61,25.08 52.12,25.59 v2(52.39,25.59) ; UD5.L3 40.3,25.08 40.8,25.59 v2(41.07,25.59) ; v2(77.89,23.59) 77.63,23.59 77.12,23.08 UD8.L3 ; v2(64.72,25.59) 64.45,25.59 63.94,25.08 UD7.L3
  TOP w0.188: RD77.2 33.55,28.66 33.53,28.68 v2(33.39,28.68)
  IN1 w0.102: v2(33.39,28.68) 33.42,28.66 33.68,28.66 35.42,26.91 36.1,26.91 37.41,25.6 38.01,25.6 38.5,25.1 39.27,25.1 39.75,25.59 v2(41.07,25.59)
  IN3 w0.099: v2(64.72,25.59) 64.72,25.57 65.18,25.2 66.72,25.2 ; 42.48,25.96 42.41,25.96 42.41,25.96 41.5,25.96 41.5,25.96 41.44,25.96 v2(41.07,25.59)
  IN3 w0.127: 66.72,25.2 70.43,25.2 73.59,23.1 74.92,23.1 76.13,23.59 v2(77.89,23.59) ; 42.48,25.96 43.03,25.41 46.97,25.41 47.09,25.28 47.09,25.15 47.22,25.02 47.48,25.02 47.6,25.15 47.6,25.44 47.73,25.57 47.98,25.57 48.11,25.44 48.11,24.74 48.24,24.62 48.49,24.62 48.62,24.74 48.62,25.28 48.75,25.41 48.89,25.41 49.13,25.16 51.52,25.16 51.95,25.59 v2(52.39,25.59) 52.81,25.16 53.78,25.16 53.96,25.35 53.96,25.91 54.09,26.04 54.34,26.04 54.47,25.91 54.47,25.53 54.66,25.34 57.89,25.34 58.21,25.02 61.64,25.02 62.2,25.59 v2(64.72,25.59)
  BOTTOM w0.102: 104.66,46.26 104.66,49.33 106.28,50.95 106.28,51.86 107.04,52.63 107.04,52.81 107.23,53 107.23,53.29 107.37,53.44 UC1.AD30 ; v2(77.89,23.59) 78.39,24.08 79.54,24.08
  BOTTOM w0.188: 79.54,24.08 79.92,24.08 81.13,25.29 82.49,25.29 82.67,25.48 82.67,27.44 82.95,27.72 82.95,35.37 82.71,35.62 79.79,35.62 79.6,35.8 79.6,36.18 79.79,36.37 82.71,36.37 82.9,36.56 82.9,36.93 82.71,37.12 79.79,37.12 79.6,37.31 79.6,37.68 79.79,37.87 82.71,37.87 82.9,38.06 82.9,38.44 82.71,38.62 79.79,38.62 79.6,38.81 79.6,43.22 79.82,43.43 93.61,43.43 95.75,45.57 104.29,45.57 104.66,45.95 104.66,46.26
DDR_B_ALERT#: length 135.5
  TOP w0.107: v2(65.96,18.45) 67.9,20.76 67.99,20.87 68.06,21.04 68.08,21.16 68.1,21.91 68.13,22.03 UD7.P9 ; v2(53.63,18.45) 55.57,20.76 55.66,20.87 55.73,21.04 55.74,21.16 55.76,21.91 55.8,22.03 UD6.P9 ; v2(79.14,16.45) 81.08,18.76 81.16,18.87 81.24,19.04 ; UD5.P9 44.49,22.03 44.45,21.91 44.43,21.16 44.41,21.04 44.34,20.87 44.25,20.76 v2(42.31,18.45)
  TOP w0.117: UD8.P9 81.31,20.03 81.26,19.86 81.24,19.04 ; v2(35.58,19.26) 35.86,18.98 RD42.2
  IN2 w0.089: v2(79.14,16.45) 78.7,16.02 77.64,16.02 75.23,18.43 75.23,26.5 74.92,26.8 74.92,29.11 75.43,29.62 75.43,31.73 75.47,31.77
  IN2 w0.102: 105.91,46.26 105.99,46.33 106.14,46.33 106.45,46.65 106.45,48.94 v2(106.29,49.1)
  IN2 w0.127: 75.47,31.77 77.21,33.51 86.53,33.51 88.45,35.43 96.92,35.43 105.83,44.34 105.83,46.18 105.91,46.26
  IN3 w0.127: v2(35.58,19.26) 36.15,19.26 36.47,18.94 41.83,18.94 v2(42.31,18.45) 44.22,18.45 44.34,18.58 44.34,19.18 44.47,19.31 44.73,19.31 44.85,19.18 44.85,18.58 44.98,18.45 45.34,18.45 45.47,18.58 45.47,18.75 45.6,18.88 45.85,18.88 45.98,18.75 45.98,18.58 46.11,18.45 46.36,18.45 46.61,18.7 49.6,18.7 50.26,19.36 51.63,19.36 52.06,18.93 53.15,18.93 v2(53.63,18.45) 54.13,18.95 55.77,18.95 56.12,18.6 62.18,18.6 62.31,18.73 62.31,19.23 62.43,19.36 62.69,19.36 62.81,19.23 62.81,18.73 62.94,18.6 63.54,18.6 63.88,18.94 65.47,18.94 v2(65.96,18.45) 66.27,18.14 69.49,18.14 69.61,18.27 70.6,18.27 70.73,18.14 72.91,18.14 73.51,17.54 76.74,17.54 77.21,17.07 78.52,17.07 v2(79.14,16.45)
  BOTTOM w0.102: v2(106.29,49.1) 106.29,49.74 108.3,51.75 108.3,52.33 108.07,52.55 108.07,52.85 108.25,53.02 108.25,53.37 UC1.AE30
DDR_B_BA0: length 129.1
  TOP w0.107: UD6.N2 50.97,23.05 51.87,23.05 v2(52.39,22.54) ; v2(41.07,22.54) 40.55,23.05 39.65,23.05 UD5.N2 ; v2(77.89,20.54) 77.38,21.05 76.48,21.05 UD8.N2 ; UD7.N2 63.3,23.05 64.2,23.05 v2(64.72,22.54)
  TOP w0.188: v2(32.63,25.08) 32.53,24.97 RD78.2
  IN2 w0.089: 79.89,19.79 79.76,19.92 78.51,19.92 v2(77.89,20.54)
  IN2 w0.198: 79.89,19.79 82.74,19.79 82.83,19.87 84.46,19.87 85.08,20.49 85.08,21.49 86.21,22.62 86.97,22.62 88.32,23.97 88.32,24.76 88.89,25.33 90.2,25.33 94.21,29.34 106.42,29.34 106.64,29.12 109.22,29.12 112.55,32.45 112.55,32.86 112.35,33.05 111.99,33.05 111.79,33.25 111.79,33.65 111.99,33.85 112.35,33.85 112.55,34.04 v2(112.55,34.42)
  IN3 w0.091: 66.08,22.15 65.1,22.15 v2(64.72,22.54) ; v2(41.07,22.54) 41.48,22.13 42.58,22.13
  IN3 w0.099: v2(52.39,22.54) 52.74,22.18 52.77,22.18 52.79,22.16 53.79,22.16 53.95,22.32
  IN3 w0.127: 42.58,22.13 42.67,22.22 45.74,22.22 45.86,22.34 45.86,22.62 45.99,22.75 46.24,22.75 46.37,22.62 46.37,22.34 46.5,22.22 46.75,22.22 46.88,22.34 46.88,22.69 47.01,22.81 47.26,22.81 47.39,22.69 47.39,22.34 47.51,22.22 47.77,22.22 47.89,22.34 47.89,22.69 48.02,22.81 48.28,22.81 48.4,22.69 48.4,22.34 48.53,22.22 49.66,22.22 49.98,22.54 v2(52.39,22.54) ; v2(64.72,22.54) 63.77,22.54 63.64,22.4 63.64,21.93 63.51,21.8 63.26,21.8 63.13,21.93 63.13,22.19 63,22.32 62.75,22.32 62.62,22.19 62.62,21.95 62.49,21.82 62.24,21.82 62.11,21.95 62.11,22.19 61.99,22.32 53.95,22.32 ; v2(32.63,25.08) 32.73,24.97 32.93,24.97 33.14,24.77 34.2,24.77 35.14,23.83 36.98,23.83 37.42,23.39 38.12,23.39 38.31,23.58 39.03,23.58 40.07,22.54 v2(41.07,22.54) ; v2(77.89,20.54) 72.58,20.54 70.72,22.41 66.34,22.41 66.08,22.15
  BOTTOM w0.102: 115.46,46.26 115.46,47.42 114.67,48.2 114.67,52.22 114.88,52.42 UC1.AN31
  BOTTOM w0.188: v2(112.55,34.42) 112.19,34.42 112,34.61 112,37.74 112.19,37.93 112.91,37.93 113.1,38.12 113.1,38.5 112.91,38.68 112.19,38.68 112,38.87 112,40.09 115.46,43.54 115.46,46.26
DDR_B_BA1: length 131.1
  TOP w0.107: UD7.N8 67.53,23.48 67.16,23.11 65.73,23.11 v2(65.28,23.55) ; UD5.N8 43.89,23.48 43.51,23.11 42.08,23.11 v2(41.63,23.55) ; UD8.N8 80.71,21.48 80.34,21.11 78.9,21.11 v2(78.45,21.55) ; v2(52.94,23.55) 53.39,23.11 54.83,23.11 55.2,23.48 UD6.N8
  TOP w0.188: v2(32.97,25.67) 32.91,25.74 RD79.2
  IN1 w0.102: v2(41.63,23.55) 42.1,23.08 46.1,23.08 46.2,22.98 46.2,22.62 46.3,22.52 46.5,22.52 46.61,22.62 46.61,23.12 46.71,23.22 46.91,23.22 47.01,23.12 47.01,22.62 47.11,22.52 51.13,22.52 51.6,22.99 51.6,23.33 52.21,23.94 52.79,23.94 52.94,23.79 v2(52.94,23.55) 53.42,23.08 53.52,23.08 54.13,22.47 54.34,22.47 54.44,22.57 54.44,22.85 54.54,22.95 54.74,22.95 54.84,22.85 54.84,22.57 54.95,22.47 60.57,22.47 60.89,22.16 63.02,22.16 64.04,23.18 64.9,23.18 v2(65.28,23.55) 65.67,23.16 70.52,23.16 72.14,21.54 75.86,21.54 77.27,21.94 78.07,21.94 v2(78.45,21.55)
  IN2 w0.089: 82.91,21.93 82.68,21.93 82.44,21.68 79.81,21.68 79.54,21.95 78.85,21.95 v2(78.45,21.55)
  IN2 w0.198: 82.91,21.93 83.35,21.93 85.21,23.78 85.21,24.51 86.65,25.95 87.38,25.95 91.4,29.97 100.75,29.97 100.95,30.17 100.95,30.44 101.15,30.64 101.57,30.64 101.77,30.44 101.77,30.04 101.97,29.85 102.37,29.85 102.56,30.04 102.56,30.34 102.76,30.54 103.16,30.54 103.36,30.34 103.36,30.04 103.55,29.85 103.95,29.85 104.15,30.04 104.15,30.44 104.35,30.64 104.74,30.64 104.94,30.44 104.94,30.04 105.14,29.85 105.54,29.85 105.73,30.04 105.73,30.44 105.93,30.64 106.33,30.64 106.53,30.44 106.53,30.04 106.72,29.85 107.12,29.85 107.32,30.04 107.32,30.44 107.52,30.64 107.91,30.64 108.11,30.44 108.11,30.17 108.31,29.97 108.61,29.97 108.83,30.19 109.38,30.19 110.21,31.03 110.21,31.58 111.18,32.54 111.18,35.63 110.99,35.82 110.99,36.94 110.58,37.34 109.98,37.34 v2(109.85,37.22)
  IN3 w0.089: 40.76,23.93 41.25,23.93 v2(41.63,23.55)
  IN3 w0.127: 40.76,23.93 38.34,23.93 37.75,24.53 36.45,24.53 36.13,24.85 35.19,24.85 34.43,25.61 33.04,25.61 v2(32.97,25.67)
  BOTTOM w0.102: UC1.AM32 114.15,52.48 114.15,48.09 114.6,47.64 114.6,46.26
  BOTTOM w0.188: v2(109.85,37.22) 109.85,37.67 109.85,37.67 109.85,39.11 114.6,43.86 114.6,46.26
DDR_B_BG0: length 135.5
  TOP w0.107: UD8.M2 76.43,22.66 77.81,22.66 v2(77.89,22.57) ; v2(64.72,24.57) 64.63,24.66 63.25,24.66 UD7.M2 ; UD6.M2 50.92,24.66 52.3,24.66 v2(52.39,24.57) ; v2(41.63,24.57) 41.24,24.19 40.73,24.19 40.26,24.66 39.61,24.66 UD5.M2
  TOP w0.188: RD80.2 v2(32.66,27.26)
  IN1 w0.102: v2(32.66,27.26) 33.67,27.26 34.15,26.78 34.15,26.47 34.61,26.01 35.62,26.01 37.04,24.59 37.87,24.59 38.48,23.98 39.18,23.98 39.39,24.19 41.24,24.19 v2(41.63,24.57)
  IN3 w0.099: 42.38,23.98 42.22,23.98 v2(41.63,24.57) ; v2(52.39,24.57) 53,23.96 53.88,23.96 53.95,23.89
  IN3 w0.127: 42.38,23.98 42.47,23.98 42.6,24.11 42.6,24.62 42.73,24.75 42.98,24.75 43.11,24.62 43.11,24.11 43.23,23.98 43.49,23.98 43.62,24.11 43.62,24.54 43.72,24.64 43.96,24.64 44.12,24.48 44.12,24.11 44.25,23.98 44.5,23.98 44.63,24.11 44.63,24.31 44.76,24.44 45.01,24.44 45.14,24.31 45.14,24.11 45.27,23.98 50.36,23.98 50.95,24.57 v2(52.39,24.57) ; 53.95,23.89 54.05,23.79 57.95,23.79 58.08,23.92 58.08,24.1 58.2,24.22 58.46,24.22 58.58,24.1 58.58,23.92 58.71,23.79 58.97,23.79 59.09,23.92 59.09,24.1 59.22,24.22 59.47,24.22 59.6,24.1 59.6,23.92 59.73,23.79 61.04,23.79 61.19,23.94 61.39,23.94 62.02,24.57 v2(64.72,24.57) 65.24,24.05 70.02,24.05 73.37,21.98 73.7,21.98 73.77,22.05 76.67,22.05 v2(77.89,22.57)
  BOTTOM w0.102: 105.1,46.26 105.1,49.18 107.81,51.9 107.81,52.14 107.67,52.28 107.67,52.82 107.55,52.95 107.55,53.23 107.88,53.56 UC1.AD29 ; 79.54,23.07 78.39,23.07 v2(77.89,22.57)
  BOTTOM w0.188: 105.1,46.26 105.1,45.79 104.46,45.16 95.93,45.16 93.78,43.01 80.45,43.01 80.26,42.82 80.26,42.45 80.45,42.26 83.16,42.26 83.35,42.07 83.35,41.7 83.16,41.51 80.45,41.51 80.26,41.32 80.26,40.95 80.45,40.76 83.16,40.76 83.35,40.57 83.35,40.19 83.16,40.01 81.16,40.01 80.97,39.82 80.97,39.44 81.16,39.25 83.16,39.25 83.37,39.04 83.37,27.55 83.09,27.27 83.09,24.84 82.59,24.34 80.81,24.34 79.54,23.07
DDR_B_BG1: length 6.1
  TOP w0.188: RD82.2 105.74,48.61 v2(105.76,48.62)
  BOTTOM w0.102: v2(105.76,48.62) 105.76,49.54 108.08,51.86 108.08,52.21 107.87,52.42 UC1.AD31
DDR_B_BG1_R: length 132.7
  TOP w0.089: v2(42.19,24.57) 42.19,24.53 42.6,24.12
  TOP w0.107: UD6.M9 55.76,23.89 54.14,23.89 53.91,24.12 53.4,24.12 v2(52.94,24.57) ; UD7.M9 68.09,23.89 66.47,23.89 66.25,24.12 65.73,24.12 v2(65.28,24.57) ; 42.6,24.12 42.82,23.89 44.44,23.89 UD5.M9 ; UD8.M9 81.27,21.89 79.65,21.89 79.42,22.12 78.9,22.12 v2(78.45,22.57)
  TOP w0.188: RD81.2 33.7,27.08 v2(33.49,26.88) ; RD82.1 105.08,48.01 RD70.2 104.98,47.33 104.98,46.3 105.11,46.16 105.71,46.16 105.95,46.4 v2(105.95,46.73)
  IN1 w0.102: v2(42.19,24.57) 42.18,24.57 41.57,23.96 39.56,23.96 39.34,23.73 38.4,23.73 37.79,24.34 36.92,24.34 36.21,25.05 36.03,25.05 35.37,25.71 34.38,25.71 33.9,26.19 33.9,26.47 v2(33.49,26.88)
  IN3 w0.091: v2(65.28,24.57) 65.66,24.96 66.32,24.96 ; 54.02,24.18 53.33,24.18 v2(52.94,24.57)
  IN3 w0.127: v2(52.94,24.57) 52.55,24.96 51.68,24.96 51.59,24.87 50.89,24.87 50.32,24.3 48.14,24.3 47.69,24.74 47.48,24.74 47.36,24.62 47.36,24.39 47.23,24.26 46.98,24.26 46.85,24.39 46.85,25.02 46.72,25.15 46.47,25.15 46.34,25.02 46.34,24.39 46.21,24.26 45.96,24.26 45.83,24.39 45.83,25.02 45.71,25.15 42.77,25.15 v2(42.19,24.57) ; 66.32,24.96 66.98,24.3 70.91,24.3 73.5,22.78 75.19,22.78 75.73,22.97 78.06,22.97 v2(78.45,22.57) ; v2(65.28,24.57) 65.27,24.57 64.85,24.99 61.96,24.99 61.67,24.69 58.06,24.69 57.55,24.18 56.08,24.18 55.95,24.31 55.95,24.8 55.83,24.92 55.57,24.92 55.45,24.8 55.45,24.31 55.32,24.18 54.02,24.18
  BOTTOM w0.102: v2(78.45,22.57) 78.45,22.26 78.63,22.08 79.54,22.08
  BOTTOM w0.188: 79.54,22.08 79.92,22.08 80.79,22.94 82.9,22.94 83.92,23.96 83.92,26.76 84.2,27.04 84.2,34.4 84.39,34.59 84.57,34.59 84.75,34.78 84.75,35.37 84.57,35.56 84.4,35.56 84.21,35.75 84.21,36.39 84.37,36.56 84.59,36.56 85.11,36.04 85.4,36.04 85.73,36.37 85.73,36.63 85.16,37.2 85.16,37.44 85.42,37.71 85.71,37.71 86.32,37.1 86.58,37.1 86.83,37.35 86.83,37.66 86.26,38.23 86.26,38.5 86.52,38.76 86.79,38.76 87.26,38.29 87.52,38.29 87.79,38.56 87.79,38.87 87.23,39.43 87.23,39.67 87.49,39.94 87.79,39.94 88.35,39.38 88.61,39.38 88.85,39.62 88.85,39.89 88.27,40.47 88.27,40.71 88.54,40.98 88.83,40.98 89.39,40.42 89.65,40.42 89.93,40.7 89.93,40.96 89.23,41.66 89.23,41.92 89.49,42.18 89.75,42.18 90.45,41.48 90.72,41.48 91.41,42.18 94.13,42.18 95.61,43.66 95.9,43.66 96.08,43.85 96.08,44.13 96.27,44.32 96.65,44.32 96.83,44.13 96.83,43.85 97.02,43.66 97.4,43.66 97.59,43.85 97.59,44.13 97.77,44.32 98.15,44.32 98.34,44.13 98.34,43.85 98.53,43.66 98.9,43.66 99.09,43.85 99.09,44.13 99.28,44.32 99.65,44.32 99.84,44.13 99.84,43.85 100.03,43.66 100.41,43.66 100.59,43.85 100.59,44.13 100.78,44.32 101.16,44.32 101.35,44.13 101.35,43.85 101.53,43.66 101.91,43.66 102.1,43.85 102.1,44.13 102.29,44.32 102.66,44.32 102.85,44.13 102.85,43.85 103.04,43.66 103.41,43.66 103.6,43.85 103.6,44.13 103.79,44.32 104.89,44.32 105.95,45.38 v2(105.95,46.73)
DDR_B_CAS#: length 133.5
  TOP w0.107: v2(78.48,23.58) 78.94,23.12 79.24,23.12 79.64,22.72 80.41,22.72 UD8.M8 ; UD5.M8 43.59,24.72 43.07,24.72 42.59,25.2 42.04,25.2 v2(41.66,25.58) ; v2(52.97,25.58) 53.43,25.12 53.73,25.12 54.14,24.72 54.91,24.72 UD6.M8 ; v2(65.31,25.58) 65.76,25.12 66.06,25.12 66.47,24.72 67.24,24.72 UD7.M8
  TOP w0.188: v2(32.71,27.97) 32.59,28.09 RD72.2
  IN1 w0.102: v2(32.71,27.97) 33.19,27.49 33.96,27.49 35.01,26.43 35.92,26.43 37.25,25.1 37.84,25.1 38.66,24.28 39.08,24.28 40,25.2 41.28,25.2 v2(41.66,25.58) 42.07,25.18 43.37,25.18 44.25,24.3 45.96,24.3 46.06,24.4 46.06,24.62 46.17,24.72 46.37,24.72 46.47,24.62 46.47,24.4 46.57,24.3 46.78,24.3 46.88,24.4 46.88,24.62 46.98,24.72 47.18,24.72 47.28,24.62 47.28,24.4 47.39,24.3 47.59,24.3 47.69,24.4 47.69,24.63 47.79,24.73 48,24.73 48.1,24.63 48.1,24.4 48.2,24.3 51.19,24.3 52.1,25.21 52.6,25.21 v2(52.97,25.58) 53.45,25.11 55.18,25.11 56.21,24.09 59.67,24.09 60.3,24.72 61.34,24.72 61.44,24.62 61.44,24.38 61.54,24.28 61.75,24.28 61.85,24.38 61.85,24.62 61.95,24.72 63.69,24.72 64.18,25.21 64.93,25.21 v2(65.31,25.58) 65.75,25.14 65.92,25.14 66.73,24.33 70.75,24.33 73.05,23.07 77.13,23.07 77.26,23.2 77.99,23.2 78.46,23.49 v2(78.48,23.58)
  IN2 w0.089: v2(78.48,23.58) 79.05,23.02 82.57,23.02 82.91,23.36
  IN2 w0.198: 82.91,23.36 84.06,24.52 84.06,24.79 86.23,26.96 86.97,26.96 90.99,30.98 99.51,30.98 106.38,37.85 110.79,37.85 111.49,37.15 111.49,36.4 113.42,34.47 v2(114.21,34.47)
  BOTTOM w0.102: UC1.AP29 115.88,53.54 116.31,53.1 116.44,53.1 116.69,52.85 116.69,48.36 117.64,47.42 117.64,46.26
  BOTTOM w0.188: 117.64,46.26 117.64,35.1 117.01,34.47 v2(114.21,34.47)
DDR_B_CKE0: length 135.6
  TOP w0.107: UD7.K2 63.29,26.29 63.78,26.29 64.57,27.08 v2(64.57,27.58) ; UD8.K2 76.46,24.29 ; UD5.K2 39.64,26.29 40.13,26.29 40.92,27.08 v2(40.92,27.58) ; UD6.K2 50.96,26.29 51.45,26.29 52.23,27.08 v2(52.23,27.58)
  TOP w0.117: v2(77.74,25.51) 77.74,25.1 77.45,24.81 77.45,24.72 77.02,24.29 76.46,24.29
  TOP w0.188: v2(33.4,30.59) 32.88,30.59 32.67,30.37 RD76.2
  IN1 w0.102: v2(40.92,27.58) 40.83,27.49 38.34,27.49 38.28,27.55 37.68,27.55 36.53,28.7 35.75,28.7 34.5,29.95 34.5,30.36 34.28,30.59 v2(33.4,30.59)
  IN3 w0.091: 53.76,27.22 52.59,27.22 v2(52.23,27.58)
  IN3 w0.099: v2(40.92,27.58) 41.26,27.23 42.33,27.23 42.38,27.28 ; v2(64.57,27.58) 64.91,27.23 65.85,27.23 65.88,27.26 66.06,27.26
  IN3 w0.127: v2(52.23,27.58) 51.33,26.67 50.57,26.67 50.31,26.93 49.57,26.93 49.27,26.62 48.43,26.62 48.26,26.79 48.26,27.3 48.14,27.42 47.85,27.42 47.73,27.3 47.73,26.73 47.6,26.6 47.35,26.6 47.22,26.73 47.22,27.3 47.09,27.42 42.52,27.42 42.38,27.28 ; 53.76,27.22 59.95,27.22 60.08,27.09 60.08,26.75 60.21,26.62 60.46,26.62 60.59,26.75 60.59,27.09 60.71,27.22 60.91,27.22 61.14,26.99 61.14,26.81 61.36,26.6 63.59,26.6 v2(64.57,27.58) ; v2(77.74,25.51) 77.69,25.46 74.12,25.46 72.32,27.26 66.06,27.26
  BOTTOM w0.102: UC1.AC31 106.79,53.01 106.79,52.66 106.07,51.95 106.07,51.05 104.24,49.21 v3(104.24,46.88) 104.24,46.26 ; v2(77.74,25.51) 77.81,25.51 78.15,25.16 79.54,25.16
  BOTTOM w0.188: 79.54,25.16 79.73,25.16 82.54,27.97 82.54,31.9 82.27,32.17 78.92,32.17 78.76,32.34 78.76,32.75 78.94,32.94 82.3,32.94 82.49,33.12 82.49,33.5 82.3,33.69 79.38,33.69 79.19,33.88 79.19,34.26 79.38,34.45 82.28,34.45 82.46,34.64 82.46,35.01 82.28,35.2 79.38,35.2 79.19,35.39 79.19,43.39 79.65,43.85 93.44,43.85 95.58,45.99 103.96,45.99 104.24,46.26
DDR_B_CLK0: length 132.4
  TOP w0.102: UD5.K7 43.32,25.97 43.32,26.08 43.22,26.18 42.96,26.18 42.67,26.47 42.67,26.74 42.19,27.22 41.9,27.22 v2(41.5,27.62) ; UD8.K7 80.14,23.97 80.14,24.08 80.04,24.18 79.78,24.18 79.49,24.47 79.49,24.74 79.01,25.22 78.72,25.22 v2(78.32,25.62) ; UD7.K7 66.96,25.97 66.96,26.08 66.86,26.18 66.61,26.18 66.32,26.47 66.32,26.74 65.84,27.22 65.55,27.22 v2(65.14,27.62) ; UD6.K7 54.63,25.97 54.63,26.08 54.53,26.18 54.28,26.18 53.98,26.47 53.98,26.74 53.5,27.22 53.22,27.22 v2(52.81,27.62)
  TOP w0.147: RD44.2 35.29,30.51 35.7,30.51 v2(35.9,30.31)
  IN1 w0.102: 36.39,30.64 36.4,30.64 36.41,30.65 36.47,30.65 36.59,30.77 36.59,30.78 37.02,31.22 37.02,31.66 37.24,31.88 37.86,31.88 39.7,30.04 40.39,30.04 40.84,29.59 40.84,28.76 41.7,27.9 41.7,27.72 41.6,27.62 v2(41.5,27.62)
  IN1 w0.122: v2(41.5,27.62) 41.69,27.43 41.69,27.25 41.95,26.99 46.41,26.99 46.52,26.88 46.52,26.88 46.76,26.64 47.56,26.64 47.92,27 48.39,27 48.75,26.64 49.44,26.64 49.56,26.76 50.37,26.76 50.69,26.45 51.58,26.45 51.85,26.72 51.85,27.73 52.17,28.05 52.89,28.05 52.98,27.96 52.98,27.78 v2(52.81,27.62) 53.45,26.98 60.66,26.98 61.16,26.48 63.63,26.48 64.01,26.86 64.01,27.56 64.47,28.01 65.01,28.01 65.17,27.86 65.17,27.64 v2(65.14,27.62) 65.77,26.99 67.91,26.99 73.82,25.29 76.52,25.29 76.64,25.32 76.72,25.37 77.71,25.96 78.23,25.96 78.35,25.84 78.35,25.65 v2(78.32,25.62) ; 36.39,30.64 36,30.64 35.9,30.54 v2(35.9,30.31)
  IN2 w0.089: 82.84,28.21 82.83,28.21 82.82,28.21 82.8,28.22 82.8,28.22 82.75,28.17 82.75,28.17 79.58,25 78.65,25 78.45,25.2 78.45,25.49 v2(78.32,25.62)
  IN2 w0.165: 82.84,28.21 82.95,28.32 82.95,31.63 83.08,31.76 83.76,31.76 83.92,31.6 83.92,30.55 84.23,30.23 84.94,30.23 85.25,30.55 85.25,31.6 85.42,31.76 87.42,31.76 89.34,33.68 97.65,33.68 106.44,42.47 110.81,42.47 111.13,42.79 111.13,43.49 110.81,43.81 107.98,43.81 107.79,44 107.79,44.48 107.95,44.65 110.16,44.65 110.47,44.96 110.47,45.41 109.55,46.32 108.81,46.32 108.48,46 108.25,46 108,46.24 108,46.81 108.69,47.49 109.02,47.49 109.42,47.1 110.06,47.1 v2(110.29,46.87)
  BOTTOM w0.102: UC1.AJ31 112.02,53.24 112.13,53.24 112.23,53.14 112.23,52.99 112.02,52.77 111.94,52.77 111.86,52.69 111.86,52.35 112.03,52.19 112.03,47.44 111.78,47.19 110.61,47.19 v2(110.29,46.87)
DDR_B_CLK0#: length 132.2
  TOP w0.102: v2(65.7,27.62) 66.51,26.82 66.51,26.55 66.69,26.37 66.95,26.37 67.44,25.88 UD7.K8 ; v2(42.06,27.62) 42.86,26.82 42.86,26.55 43.04,26.37 43.31,26.37 43.79,25.88 UD5.K8 ; v2(78.88,25.62) 79.68,24.82 79.68,24.55 79.86,24.37 80.13,24.37 80.62,23.88 UD8.K8 ; UD6.K8 55.11,25.88 54.62,26.37 54.36,26.37 54.17,26.55 54.17,26.82 v2(53.37,27.62)
  TOP w0.147: RD45.2 35.28,30.75 35.64,30.75 v2(35.9,31.01)
  IN1 w0.102: v2(42.06,27.62) 41.89,27.78 41.89,27.97 41.03,28.83 41.03,29.67 40.47,30.23 39.78,30.23 37.94,32.07 37.16,32.07 36.83,31.74 36.83,31.3 36.39,30.85
  IN1 w0.122: v2(78.88,25.62) 78.32,26.17 77.66,26.17 76.56,25.52 76.49,25.5 73.85,25.5 67.94,27.2 65.86,27.2 65.66,27.4 65.66,27.58 v2(65.7,27.62) 65.1,28.23 64.38,28.23 63.8,27.65 63.8,26.94 63.55,26.69 61.25,26.69 60.75,27.19 53.54,27.19 53.35,27.38 53.35,27.6 v2(53.37,27.62) 53.19,27.8 53.19,28.05 52.98,28.26 52.08,28.26 51.64,27.82 51.64,26.81 51.49,26.66 50.77,26.66 50.46,26.98 49.48,26.98 49.35,26.85 48.84,26.85 48.48,27.21 47.84,27.21 47.48,26.85 46.85,26.85 46.73,26.97 46.5,27.2 42.03,27.2 41.9,27.34 41.9,27.46 v2(42.06,27.62) ; 36.39,30.85 36.06,30.85 v2(35.9,31.01)
  IN2 w0.089: v2(78.88,25.62) 78.84,25.62 78.63,25.41 78.63,25.28 78.73,25.18 79.5,25.18 82.62,28.3 82.62,28.36
  IN2 w0.165: 82.62,28.36 82.69,28.43 82.69,31.73 82.97,32.02 83.86,32.02 84.17,31.7 84.17,30.65 84.34,30.49 84.83,30.49 85,30.65 85,31.7 85.31,32.02 87.32,32.02 89.24,33.93 97.54,33.93 106.34,42.73 110.71,42.73 110.87,42.89 110.87,43.39 110.71,43.55 107.87,43.55 107.53,43.89 107.53,44.59 107.85,44.9 110.05,44.9 110.22,45.07 110.22,45.3 109.45,46.07 108.91,46.07 108.58,45.74 108.14,45.74 107.75,46.13 107.75,46.26 107.74,46.27 107.74,46.92 108.58,47.76 109.13,47.76 109.53,47.36 110.17,47.36 110.17,47.36 v2(110.29,47.48)
  BOTTOM w0.102: v2(110.29,47.48) 110.39,47.38 111.7,47.38 111.84,47.52 111.84,52.11 111.67,52.28 111.67,52.8 111.57,53.03 111.57,53.16 111.62,53.28 111.7,53.35 112.02,53.5 UC1.AK30
DDR_B_CS0#: length 126.4
  TOP w0.107: v2(65.9,25.58) 66.4,25.08 UD7.L7 ; UD5.L7 43.01,25.08 42.51,25.58 v2(42.25,25.58) ; v2(53.56,25.58) 54.07,25.08 UD6.L7
  TOP w0.117: v2(79.07,23.58) 79.22,23.58 79.72,23.08 UD8.L7
  TOP w0.188: v2(33.47,27.97) 33.59,27.97 33.67,27.89 RD75.2
  IN1 w0.102: v2(79.07,23.58) 79.07,23.77 78.86,23.98 72.29,23.98 71.07,25.19 66.29,25.19 v2(65.9,25.58) 65.51,25.96 64.41,25.96 63.48,25.04 59.92,25.04 59.34,24.45 58.72,24.45 58.62,24.55 58.62,24.73 58.52,24.83 58.31,24.83 58.21,24.73 58.21,24.55 58.11,24.45 56.3,24.45 55.17,25.59 53.57,25.59 v2(53.56,25.58) 53.18,25.96 52.21,25.96 51.41,25.16 51.07,25.16 50.97,25.27 50.97,25.53 50.87,25.63 50.66,25.63 50.56,25.53 50.56,25.27 50.46,25.16 50.26,25.16 50.16,25.27 50.16,25.53 50.05,25.63 49.85,25.63 49.75,25.53 49.75,25.27 49.65,25.16 46.81,25.16 46.71,25.27 46.71,25.37 46.61,25.47 46.4,25.47 46.3,25.37 46.3,25.27 46.2,25.16 46,25.16 45.89,25.27 45.89,25.35 45.79,25.46 45.59,25.46 45.49,25.35 45.49,25.27 45.39,25.16 44.02,25.16 43.6,25.58 v2(42.25,25.58)
  IN2 w0.089: 82.91,24.07 82.72,23.88 80.84,23.88 80.54,23.58 v2(79.07,23.58)
  IN2 w0.198: v2(112.59,36.15) 112.59,36.18 111.99,36.77 111.99,39.36 111.57,39.78 110.77,39.78 110.64,39.65 110.64,38.63 110.44,38.44 110.05,38.44 109.85,38.63 109.85,39.81 109.65,40.01 109.25,40.01 109.06,39.81 109.06,38.63 108.86,38.44 108.46,38.44 108.26,38.63 108.26,39.81 108.06,40.01 107.83,40.01 99.3,31.48 90.78,31.48 86.76,27.46 86.02,27.46 83.51,24.95 83.51,24.67 82.91,24.07
  IN3 w0.127: v2(33.47,27.97) 33.58,28.09 35.52,28.09 37.77,25.84 38.42,25.84 38.63,26.05 39.27,26.05 39.46,25.86 40.09,25.86 40.8,25.15 41.82,25.15 v2(42.25,25.58)
  BOTTOM w0.102: 116.39,46.26 116.39,47.31 115.77,47.92 115.77,52.78 115.37,53.18 UC1.AN30
  BOTTOM w0.188: v2(112.59,36.15) 112.61,36.12 112.9,36.12 114.16,37.38 114.16,41.06 116.39,43.3 116.39,46.26
DDR_B_DM0: length 83.7
  TOP w0.089: UD5.E7 42.14,29.88 v2(41.43,29.16)
  IN2 w0.089: v2(41.43,29.16) 41.43,29.29 40.91,29.81 40.78,29.81
  IN2 w0.127: 40.78,29.81 38.69,31.9 38.69,32.5 37.68,33.52 37.68,35.49 51.5,49.31 52.22,49.31 52.34,49.44 52.34,49.92 52.47,50.04 52.72,50.04 52.85,49.92 52.85,49.44 52.98,49.31 53.23,49.31 53.36,49.44 53.36,49.92 53.49,50.04 53.74,50.04 53.87,49.92 53.87,49.44 53.99,49.31 54.25,49.31 54.37,49.44 54.37,49.92 54.5,50.04 54.76,50.04 54.88,49.92 54.88,49.44 55.01,49.31 56.18,49.31 57.25,50.38 57.56,50.38 57.69,50.51 57.69,50.91 57.81,51.03 58.07,51.03 58.19,50.91 58.19,50.51 58.32,50.38 58.57,50.38 58.7,50.51 58.7,50.91 58.83,51.03 59.08,51.03 59.21,50.91 59.21,50.51 59.34,50.38 62.42,50.38 62.58,50.53 62.58,50.93 62.7,51.06 62.96,51.06 63.08,50.93 63.08,50.53 63.24,50.38 65.57,50.38 65.95,50.77 72.66,50.77 72.79,50.64 72.79,49.46 72.91,49.33 73.17,49.33 73.3,49.46 73.3,50.64 73.42,50.77 73.68,50.77 73.8,50.64 73.8,50.24 73.93,50.11 74.16,50.11 74.31,50.26 74.31,50.64 74.44,50.77 74.79,50.77 78.11,54.09 83.45,54.09 85.32,52.22 85.32,52.22 86.21,51.33 86.75,51.33 v2(87.27,50.8)
  BOTTOM w0.102: UC1.C30 90.77,53.6 87.97,50.8 v2(87.27,50.8)
DDR_B_DM1: length 69.4
  TOP w0.117: UD5.E2 39.23,29.88 39.66,30.31 40.54,30.31 v2(41.93,31.7)
  IN2 w0.102: v2(92.24,48.91) 90.88,48.91 89.74,47.77 89.19,47.77 88.52,47.1
  IN2 w0.127: 88.52,47.1 87.74,46.32 83.26,46.32 82.29,45.34 78.8,45.34 78.67,45.47 78.67,45.78 78.55,45.9 78.29,45.9 78.17,45.78 78.17,45.47 78.04,45.34 77.79,45.34 77.66,45.47 77.66,45.78 77.53,45.9 77.28,45.9 77.15,45.78 77.15,45.47 77.02,45.34 52.1,45.34 42.12,35.36 42.12,31.9 v2(41.93,31.7)
  BOTTOM w0.102: v2(92.24,48.91) 92.27,49.01 93.16,49.5 93.91,50.26 93.91,51.47 94.37,51.93 UC1.H32
DDR_B_DM2: length 72
  TOP w0.117: UD6.E7 54.25,30.18 52.92,30.18 v2(52.6,29.86)
  IN2 w0.102: v2(97.39,50.5) 97.48,50.41 97.95,50.41 98.05,50.31 98.05,47.24 97.66,46.84 97.66,46.26
  IN2 w0.127: v2(52.6,29.86) 52.03,30.43 51.33,30.43 49.87,31.9 49.87,33.48 49.74,33.61 49.74,34.24 55.67,40.17 84.43,40.17 85.32,41.06 93.92,41.06 97.01,44.15 97.01,44.33 96.78,44.57 96.78,44.75 96.96,44.93 97.14,44.93 97.37,44.69 97.55,44.69 97.66,44.8 97.66,45.26 97.53,45.39 97.4,45.39 97.27,45.52 97.27,45.77 97.4,45.9 97.53,45.9 97.66,46.02 97.66,46.26
  BOTTOM w0.102: v2(97.39,50.5) 97.39,51.37 97.78,51.76 97.78,52.23 97.67,52.33 97.67,52.82 97.51,52.99 97.51,53.16 97.87,53.52 UC1.M29
DDR_B_DM3: length 68.7
  TOP w0.089: UD6.E2 50.91,30.24 51.9,30.24 v2(53.3,31.64)
  IN2 w0.102: 101.91,46.51 101.91,48.27 v2(101.37,48.8)
  IN2 w0.127: v2(53.3,31.64) 53.3,33.67 56.47,36.85 72.03,36.85 72.15,36.98 72.15,37.34 72.28,37.47 85.5,37.47 86.42,38.39 95.25,38.39 101.91,45.06 101.91,46.51
  BOTTOM w0.102: UC1.T29 100.88,53.54 100.57,53.24 100.57,53.02 100.67,52.77 100.67,52.62 100.57,52.4 100.57,51 100.97,50.6 100.97,49.06 101.23,48.8 v2(101.37,48.8)
DDR_B_DM4: length 88.8
  TOP w0.089: v2(64.75,29.48) 65.37,30.1 65.72,30.1
  TOP w0.117: UD7.E7 66.65,30.1 65.72,30.1
  IN1 w0.102: v2(119.35,48.52) 118.99,48.52 117.99,47.52 113,47.52 112.87,47.64 112.87,48.27 112.74,48.39 112.51,48.39 112.41,48.29 112.41,47.58 112.31,47.48 112.1,47.48 112,47.58 112,48.29 111.9,48.39 109.24,48.39 109.14,48.29 109.14,47.27 109.03,47.17 108.83,47.17 108.73,47.27 108.73,48.29 108.63,48.39 108.45,48.39 108.32,48.27 108.32,47.3 108.19,47.17 105.83,47.17 105.2,46.54 105.2,46.4 105.56,46.03 105.56,45.89 105.42,45.74 105.28,45.74 104.94,46.08 104.79,46.08 104.65,45.94 104.65,45.8 104.99,45.46 104.99,45.31 104.84,45.17 104.7,45.17 104.34,45.53 104.19,45.53 103.9,45.24 97.56,45.24 95.31,43 90.84,43 90.15,43 89.61,43.54 87.43,43.54 87.04,43.93 70.89,43.93 60.67,33.71 60.67,30.9 61.13,30.44 61.95,30.44 62.55,29.84 64.39,29.84 v2(64.75,29.48)
  BOTTOM w0.102: v2(119.35,48.52) 118.92,48.95 118.92,50.34 118.74,50.52 118.57,50.69 118.57,52.47 118.67,52.57 118.67,52.82 118.56,52.94 118.56,53.32 UC1.AU30
DDR_B_DM5: length 81.2
  TOP w0.089: UD7.E2 63.24,30.24 64.11,30.24 v2(64.94,31.07)
  IN1 w0.102: v2(64.94,31.07) 65.76,31.9 66.08,31.9 66.43,32.24 68.27,32.24 68.49,32.47 68.49,34.57 73.42,39.5 88.33,39.5 88.81,39.02 97.08,39.02 99.46,41.4 107.22,41.4 107.52,41.71 114.59,41.71 115.23,42.35 122.67,42.35 125.63,45.31 125.63,49 125.63,49.12 125.63,49.74 v2(125.18,50.2)
  BOTTOM w0.102: UC1.BD28 122.93,54.5 124.07,53.35 124.07,52.47 124.62,50.76 v2(125.18,50.2)
DDR_B_DM6: length 96.8
  TOP w0.117: UD8.E7 78.36,27.88 v2(78.01,27.53)
  IN1 w0.102: v2(78.01,27.53) 77.64,27.89 76.56,27.89 74.34,30.12 74.34,32.46 74.97,33.1 76.22,33.1 79.12,35.99 83.36,35.99 83.63,35.72 102.57,35.72 105.05,38.2 109.16,38.2 109.42,38.46 114.53,38.46 114.63,38.36 114.63,37.8 114.73,37.7 114.93,37.7 115.03,37.8 115.03,38.36 115.14,38.46 115.34,38.46 115.44,38.36 115.44,37.8 115.54,37.7 122.42,37.7 126.86,39.54 127.41,40.09 127.41,40.09 134.53,47.21 134.85,48.22 134.85,49.35 134.4,50.44 132.66,52.18 131.08,52.18 129.18,54.08 128.09,54.08 v2(127.07,55.1)
  BOTTOM w0.102: UC1.BB23 122,57.87 122.36,57.87 122.53,57.7 123.12,57.7 123.22,57.6 124.61,57.6 125.48,57 126.88,55.6 v2(127.07,55.1)
DDR_B_DM7: length 97.3
  TOP w0.117: v2(78.02,29.04) 77.27,28.29 76.46,28.29 UD8.E2
  IN1 w0.102: v2(127.27,60.6) 128.17,60.6 128.44,60.33 131.73,60.33 134.55,59.42 136.91,57.05 137.6,55.38 139.51,50.47 139.51,47.06 138.46,44.52 129.39,35.45 114.11,29.12 107.19,27.74 94.74,27.74 94.49,28 93.23,28 92.98,27.74 81.97,27.74 81.25,27.89 78.89,28.86 v2(78.02,29.04)
  BOTTOM w0.102: v2(127.27,60.6) 126.36,60.91 v3(125.22,60.91) 124.28,60.91 124.19,61 UC1.BD20
DDR_B_DQ0: length 84
  TOP w0.117: UD5.G2 v2(38.83,28.68)
  IN2 w0.127: v2(38.83,28.68) 38.41,29.1 37.49,29.1 36.66,29.93 36.66,31.77 35.9,32.53 35.9,35.87 51.49,51.46 55.22,51.46 57.84,54.08 62.21,54.08 63.32,55.2 63.92,55.2 64.14,54.98 66.2,54.98 66.32,54.86 66.32,54.18 66.45,54.06 66.7,54.06 66.83,54.18 66.83,54.86 66.96,54.98 67.21,54.98 67.34,54.86 67.34,54.18 67.47,54.06 67.72,54.06 67.85,54.18 67.85,54.86 67.97,54.98 68.23,54.98 68.35,54.86 68.35,54.18 68.48,54.06 68.74,54.06 68.86,54.18 68.86,54.86 68.99,54.98 69.24,54.98 69.37,54.86 69.37,54.18 69.5,54.06 69.75,54.06 69.88,54.18 69.88,54.86 70.01,54.98 73.45,54.98 74.23,55.76 77.43,55.76 79.49,57.82 85.66,57.82 86.21,57.26 86.21,54.36 v2(86.97,53.6)
  BOTTOM w0.102: UC1.C27 90.7,54.82 89.19,54.82 88.02,53.64 87.74,53.64
  BOTTOM w0.117: 87.74,53.64 87.7,53.6 v2(86.97,53.6)
DDR_B_DQ1: length 83.8
  TOP w0.117: v2(42.15,29.14) 43.17,29.14 UD5.F7
  IN2 w0.089: 41.54,29.81 42.15,29.2 v2(42.15,29.14)
  IN2 w0.102: v2(88.87,50.6) 87.83,50.6 87.52,50.28 87.23,50.28 86.63,50.88 86.02,50.88 86.01,50.89
  IN2 w0.127: 86.01,50.89 83.22,53.68 78.27,53.68 73.54,48.95 72.41,48.95 72.28,49.08 72.28,50.26 72.15,50.39 71.9,50.39 71.77,50.26 71.77,49.08 71.65,48.95 71.39,48.95 71.26,49.08 71.26,50.26 71.14,50.39 70.88,50.39 70.76,50.26 70.76,49.08 70.63,48.95 70.38,48.95 70.25,49.08 70.25,50.26 70.12,50.39 69.37,50.39 69.18,50.19 69.18,49.06 69.05,48.93 68.24,48.93 68.11,49.06 68.11,49.28 68.24,49.41 68.52,49.41 68.67,49.56 68.67,50.26 68.55,50.39 66.17,50.39 65.29,49.51 64.84,49.51 64.35,50 57.41,50 56.34,48.93 51.79,48.93 38.06,35.2 38.06,33.67 39.08,32.66 39.08,32.15 40.85,30.37 40.98,30.37 41.54,29.81
  BOTTOM w0.102: v2(88.87,50.6) 89.43,50.6 90.38,51.06 91.88,52.56 UC1.E32
DDR_B_DQ2: length 84.1
  TOP w0.117: UD5.H3 v2(39.63,27.88)
  IN2 w0.089: 37.7,27.55 38.21,27.55 38.25,27.51 39.26,27.51 v2(39.63,27.88)
  IN2 w0.127: v2(88.1,54.77) 88.1,56.49 86.01,58.58 82.59,58.58 82.46,58.7 82.46,59.14 82.33,59.26 82.08,59.26 81.95,59.14 81.95,58.7 81.83,58.58 81.57,58.58 81.44,58.7 81.44,59.14 81.32,59.26 81.06,59.26 80.94,59.14 80.94,58.7 80.81,58.58 79.17,58.58 77.11,56.52 73.91,56.52 73.14,55.75 64.45,55.75 64.17,56.03 63.07,56.03 62.52,55.47 58.15,55.47 54.91,52.23 51.17,52.23 35.14,36.19 35.14,31.85 34.85,31.56 34.85,29.03 36.33,27.55 37.7,27.55
  BOTTOM w0.102: UC1.D27 91.14,55.36 90.81,55.36 90.75,55.3 90.53,55.09 89.08,55.09 88.77,54.77 v2(88.1,54.77)
DDR_B_DQ3: length 84.1
  TOP w0.117: UD5.H7 43.23,27.65 42.69,28.2 v2(42.69,28.47)
  IN2 w0.127: v2(87.67,49.4) 86.82,49.4 82.92,53.3 78.43,53.3 73.68,48.55 67.79,48.55 67.66,48.68 67.66,49.43 67.54,49.56 67.28,49.56 67.16,49.43 67.16,48.68 67.03,48.55 66.77,48.55 66.65,48.68 66.65,49.43 66.52,49.56 66.27,49.56 66.14,49.43 66.14,48.68 66.01,48.55 65.76,48.55 65.63,48.68 65.63,49 65.5,49.13 65.25,49.13 65.12,49 65.12,48.68 65,48.55 64.77,48.55 64.64,48.68 64.64,49.17 64.51,49.3 64.26,49.3 64.13,49.17 64.13,48.68 64.01,48.55 63.75,48.55 63.63,48.68 63.63,49.47 63.48,49.62 63.24,49.62 63.12,49.49 63.12,48.68 62.99,48.55 62.7,48.55 62.58,48.68 62.58,49.46 62.45,49.59 62.17,49.59 62.04,49.46 62.04,49.15 61.92,49.03 61.66,49.03 61.54,49.15 61.54,49.49 61.41,49.62 57.57,49.62 56.5,48.55 52.08,48.55 38.44,34.91 38.44,33.83 39.52,32.75 39.52,32.15 40.92,30.75 41.17,30.75 42.69,29.24 v2(42.69,28.47)
  BOTTOM w0.102: UC1.F31 90.29,50.52 88.21,49.4 v2(87.67,49.4)
DDR_B_DQ4: length 84.4
  TOP w0.117: UD5.H2 v2(38.83,27.88)
  IN2 w0.089: 37.36,28.34 38.37,28.34 v2(38.83,27.88)
  IN2 w0.102: 87.27,53.9 87.49,53.68 88.56,53.68 89.47,52.76 v2(89.47,51.2)
  IN2 w0.127: 87.27,53.9 86.85,54.32 86.85,57.16 85.82,58.2 79.33,58.2 77.27,56.14 74.07,56.14 73.3,55.36 64.3,55.36 64.08,55.58 63.17,55.58 62.05,54.46 57.69,54.46 55.07,51.84 51.33,51.84 35.52,36.03 35.52,31.69 35.23,31.4 35.23,29.19 36.08,28.34 37.36,28.34
  BOTTOM w0.102: v2(89.47,51.2) 90.41,51.55 91.45,52.59 91.45,52.78 91.78,53.1 91.98,53.1 UC1.F30
DDR_B_DQ5: length 83.9
  TOP w0.117: UD5.H8 v2(43.61,27.9)
  IN2 w0.127: v2(43.61,27.9) 43.23,28.28 43.23,30.53 42.69,31.07 41.14,31.07 39.9,32.31 39.9,32.91 38.82,33.99 38.82,34.76 52.23,48.17 57.44,48.17 57.57,48.29 57.57,49.03 57.69,49.15 57.95,49.15 58.08,49.03 58.08,48.29 58.2,48.17 58.46,48.17 58.58,48.29 58.58,49.1 58.71,49.23 58.96,49.23 59.09,49.1 59.09,48.29 59.22,48.17 59.47,48.17 59.6,48.29 59.6,49.1 59.73,49.23 59.98,49.23 60.11,49.1 60.11,48.29 60.23,48.17 60.49,48.17 60.62,48.29 60.62,49.1 60.74,49.23 61,49.23 61.12,49.1 61.12,48.29 61.25,48.17 61.48,48.17 61.61,48.29 61.61,48.52 61.74,48.65 61.97,48.65 62.09,48.52 62.09,48.29 62.22,48.17 73.84,48.17 78.59,52.92 82.76,52.92 86.88,48.8 v2(87.08,48.8)
  BOTTOM w0.102: UC1.F29 92.34,53.9 91.86,53.42 91.42,53.42 91.1,53.1 90.78,53.1 87.08,49.4 v2(87.08,48.8)
DDR_B_DQ6: length 83.8
  TOP w0.117: UD5.J3 40.03,26.68 v2(39.63,27.08)
  IN2 w0.089: v2(39.63,27.08) 39.27,26.73 38.19,26.73
  IN2 w0.127: v2(88.78,55.4) 88.78,56.35 85.44,59.68 80.68,59.68 80.55,59.56 80.55,59.09 80.43,58.96 80.17,58.96 80.04,59.09 80.04,59.56 79.92,59.68 79.59,59.68 79.47,59.56 79.47,59.09 79.34,58.96 79.01,58.96 76.96,56.9 73.76,56.9 72.98,56.13 64.61,56.13 64.33,56.41 62.92,56.41 62.36,55.85 57.99,55.85 54.75,52.61 51.01,52.61 34.76,36.35 34.76,32.01 34.47,31.72 34.47,28.87 36.61,26.73 38.19,26.73
  BOTTOM w0.102: v2(88.78,55.4) 88.87,55.5 UC1.B27
DDR_B_DQ7: length 83.7
  TOP w0.117: UD5.J7 43.21,26.7 43.21,27 42.66,27.54 42.66,27.86 42.1,28.43 v2(41.98,28.43)
  IN2 w0.089: v2(41.98,28.43) 41.85,28.3 39.49,28.3 39.2,28.59 39.2,28.97 39.27,29.04 39.27,29.61 39.01,29.86 37.87,29.86 37.81,29.93 37.74,29.93 37.68,29.99
  IN2 w0.127: 37.68,29.99 37.04,30.63 37.04,32.02 36.47,32.59 36.47,35.91 51.65,51.08 55.38,51.08 56.63,52.33 63.94,52.33 64.23,52.62 64.23,53.23 64.35,53.36 64.63,53.36 64.76,53.23 64.76,52.52 64.89,52.39 65.22,52.39 65.35,52.52 65.35,53.52 65.48,53.66 72.67,53.66 74.39,55.38 77.59,55.38 79.65,57.43 85.44,57.43 85.77,57.1 85.77,54.06 86.37,53.45 v2(86.37,53)
  BOTTOM w0.102: 88.02,53.2 87.81,53 87.74,53
  BOTTOM w0.108: UC1.A28 89.31,54.5 88.02,53.2
  BOTTOM w0.117: 87.74,53 v2(86.37,53)
DDR_B_DQ8: length 69.3
  TOP w0.117: v2(40.81,33.59) 40.53,33.58 UD5.A3
  IN2 w0.102: 86.3,47.82 87.28,47.82 90.06,50.6 v2(91.97,50.6)
  IN2 w0.127: v2(40.81,33.59) 40.81,35.67 51.63,46.49 67,46.49 67.13,46.61 67.13,47.07 67.26,47.2 67.51,47.2 67.64,47.07 67.64,46.61 67.76,46.49 73.45,46.49 79.09,52.13 82.33,52.13 85.32,49.13 85.32,48.8 86.3,47.82
  BOTTOM w0.102: v2(91.97,50.6) 93.01,50.6 93.21,50.8 93.21,51.42 93.43,51.64 93.97,52.18 93.97,52.32 93.87,52.42 UC1.H31
DDR_B_DQ9: length 69.9
  TOP w0.117: UD5.B8 44.03,32.28 v2(44.44,32.69)
  IN2 w0.127: v2(44.44,32.69) 44.85,33.11 44.85,33.93 44.52,34.27 44.52,35.51 46.73,37.72 46.98,37.72 47.42,37.28 47.6,37.28 47.79,37.46 47.79,37.64 47.28,38.15 47.28,38.33 47.46,38.51 47.64,38.51 48.15,38 48.32,38 48.5,38.18 48.5,38.36 48,38.87 48,39.05 48.18,39.23 48.36,39.23 48.86,38.72 49.04,38.72 49.22,38.9 49.22,39.08 48.72,39.59 48.72,39.77 48.9,39.95 49.08,39.95 49.58,39.44 49.76,39.44 54.18,43.86 82.81,43.86 83.76,44.81 90.37,44.81 v2(90.47,44.91)
  BOTTOM w0.102: UC1.K30 95.37,53.18 95.07,52.88 95.07,52.3 94.97,52.2 94.97,51.38 94.76,51.17 94.76,49.79 93.24,48.26 v3(93.24,47.45) 93.24,46.98
  BOTTOM w0.117: v2(90.47,44.91) 91.16,44.91 93.24,46.98
DDR_B_DQ10: length 70
  TOP w0.117: UD5.C3 40.03,31.51 v2(41.17,32.66)
  IN2 w0.102: 86.01,47.6 87.7,47.6 89.49,49.4 v2(90.78,49.4)
  IN2 w0.127: v2(41.17,32.66) 41.36,32.85 41.36,35.68 51.79,46.1 73.61,46.1 79.25,51.74 82.17,51.74 84.88,49.04 84.88,48.7 85.98,47.6 86.01,47.6
  BOTTOM w0.102: UC1.H30 94.26,53.39 94.26,53.01 94.07,52.82 94.07,52.5 94.17,52.4 94.17,52.03 93.56,51.42 93.56,50.46 v3(93.08,49.98) 91.4,49.45 v2(90.78,49.4)
DDR_B_DQ11: length 69
  TOP w0.117: UD5.C7 v2(42.82,31.89)
  IN2 w0.102: v2(95.17,50.8) 94.77,50.8 92.28,48.32 92.28,46.51 92.04,46.26
  IN2 w0.127: 92.04,46.26 91.23,45.46 90.24,45.46 89.97,45.19 83.61,45.19 82.65,44.24 53.95,44.24 50.56,40.85 50.38,40.85 49.91,41.32 49.73,41.32 49.55,41.14 49.55,40.96 50.02,40.49 50.02,40.31 49.84,40.13 49.66,40.13 49.19,40.6 49.01,40.6 44.09,35.68 44.09,33.93 43.78,33.61 43.78,32.41 43.26,31.89 v2(42.82,31.89)
  BOTTOM w0.102: UC1.K29 95.87,53.52 95.57,53.22 95.57,52.92 95.67,52.82 95.67,52.33 95.78,52.23 95.78,51.78 95.26,51.27 95.26,50.89 v2(95.17,50.8)
DDR_B_DQ12: length 70.2
  TOP w0.117: v2(40.09,34.12) 39.65,33.67 39.65,31.9 39.23,31.48 UD5.C2
  IN2 w0.102: v2(92.65,51.15) 90.29,51.15 87.48,48.34 86.99,48.34 86.66,48.67 86.32,48.67 86.01,48.98
  IN2 w0.127: v2(40.09,34.12) 40.22,34.24 40.22,35.61 52.39,47.79 74.21,47.79 78.93,52.51 82.49,52.51 86.01,48.98
  BOTTOM w0.102: v2(92.65,51.15) 92.65,51.21 93.67,52.23 93.67,52.82 93.57,52.92 93.57,53.22 93.88,53.52 UC1.H29
DDR_B_DQ13: length 69.2
  TOP w0.117: v2(44.44,31.89) 44.03,31.48 UD5.C8
  IN2 w0.102: 92.69,46.36 92.69,47.11 92.79,47.21 92.79,48.23 94.56,50 v2(95.17,50)
  IN2 w0.127: v2(44.44,31.89) 44.86,31.48 45.69,31.48 45.93,31.72 45.93,34 45.81,34.13 45.2,34.13 45.07,34.26 45.07,34.51 45.2,34.64 45.81,34.64 45.93,34.76 45.93,35.02 45.81,35.15 45.2,35.15 45.07,35.27 45.07,35.53 45.2,35.65 45.81,35.65 45.93,35.78 45.93,36.17 46.65,36.89 47.75,36.89 54.34,43.48 82.97,43.48 83.92,44.43 89.11,44.43 89.17,44.37 90.69,44.37 92.69,46.36
  BOTTOM w0.102: v2(95.17,50) 95.17,50.13 95.61,50.57 95.61,51.22 95.97,51.58 95.97,52.32 95.87,52.42 UC1.K31
DDR_B_DQ14: length 69.4
  TOP w0.117: v2(41.17,31.7) 41.05,31.7 UD5.D3
  IN2 w0.102: 86.01,46.7 87.37,46.7 89.48,48.8 v2(90.17,48.8)
  IN2 w0.127: v2(41.17,31.7) 41.74,32.28 41.74,35.52 51.95,45.72 74.41,45.72 74.54,45.85 74.54,46.36 74.67,46.49 74.97,46.49 75.09,46.36 75.09,45.88 75.24,45.73 75.5,45.73 75.63,45.85 75.63,46.79 75.75,46.92 76.01,46.92 76.13,46.79 76.13,45.85 76.26,45.73 76.51,45.73 76.64,45.85 76.64,46.16 76.77,46.28 79.12,46.28 79.68,45.72 82.13,45.72 83.11,46.7 86.01,46.7
  BOTTOM w0.102: v2(90.17,48.8) 90.41,49.96 92.52,52.07 92.52,52.3 93.24,53.03 93.24,53.37 UC1.G30
DDR_B_DQ15: length 69.2
  TOP w0.117: v2(43.65,31.1) 43.23,30.68 UD5.D7
  IN2 w0.102: 93.25,46.38 93.25,48.05 93.82,48.62 v2(94.32,48.62)
  IN2 w0.127: v2(43.65,31.1) 44.44,31.1 45.1,30.43 45.86,30.43 46.31,30.89 46.31,36.01 46.81,36.51 47.9,36.51 54.5,43.1 83.13,43.1 83.99,43.96 90.82,43.96 93.25,46.38
  BOTTOM w0.102: v2(94.32,48.62) 94.87,48.62 95.61,49.37 95.61,50.12 95.81,50.32 95.81,51.02 96.17,51.38 96.17,52.4 96.07,52.5 96.07,52.82 96.37,53.12 UC1.L30
DDR_B_DQ16: length 71.8
  TOP w0.117: v2(50.14,28.68) 50.54,28.28 UD6.G2
  IN2 w0.127: v2(50.14,28.68) 49.74,28.28 48.95,28.28 47.84,29.39 47.84,29.65 47.97,29.77 48.5,29.77 48.63,29.9 48.63,30.15 48.5,30.28 47.97,30.28 47.84,30.41 47.84,34.28 55.13,41.57 83.88,41.57 84.75,42.44 91.46,42.44 92.72,43.7 94.2,43.7 95.13,44.63 95.13,46.75 95.25,46.88 v2(96.12,46.88)
  BOTTOM w0.102: UC1.N32 98.37,48 97.26,46.88 v2(96.12,46.88)
DDR_B_DQ17: length 71.9
  TOP w0.117: v2(54.92,29.46) 54.55,29.08 UD6.F7
  IN2 w0.127: v2(99.37,48.1) 98.98,47.71 98.98,46.88 98.82,46.72 98.82,46.22 98.95,46.09 99.46,46.09 99.58,45.97 99.58,45.71 99.46,45.58 98.95,45.58 98.82,45.46 98.82,45.2 98.95,45.08 99.26,45.08 99.39,44.95 99.39,44.7 99.26,44.57 98.95,44.57 98.82,44.44 98.82,44.19 94.55,39.92 85.79,39.92 84.9,39.03 56.31,39.03 51.36,34.08 51.36,31.93 52.06,31.23 52.51,31.23 52.86,30.88 54.23,30.88 54.92,30.19 v2(54.92,29.46)
  BOTTOM w0.102: UC1.N29 98.88,53.52 98.57,53.22 98.57,52.92 98.67,52.82 98.67,52.5 98.57,52.4 98.57,51.33 98.67,51.23 98.67,49.96 98.87,49.76 98.87,48.6 v2(99.37,48.1)
DDR_B_DQ18: length 73
  TOP w0.117: UD6.H3 51.17,27.66 51.17,27.66 v2(50.94,27.88)
  IN2 w0.127: v2(50.94,27.88) 50.87,27.88 50.38,27.39 49.87,27.39 49.62,27.64 48.56,27.64 47.08,29.12 47.08,34.6 54.81,42.33 83.57,42.33 84.43,43.2 91.14,43.2 92.41,44.46 93.89,44.46 94.36,44.94 94.36,45.82 93.79,46.4 v2(93.78,46.4)
  BOTTOM w0.102: UC1.L29 96.87,53.52 96.57,53.22 96.57,52.92 96.67,52.82 96.67,52.5 96.57,52.4 96.57,50.98 96.32,50.72 96.32,48.94 v3(95.96,48.58) v2(93.78,46.4)
DDR_B_DQ19: length 71.5
  TOP w0.117: UD6.H7 54.47,27.48 54.01,27.94 54.01,28.49 v2(53.81,28.68)
  IN2 w0.127: v2(99.37,50.5) 99.16,50.28 98.42,50.28 98.29,50.16 98.29,47.08 98.04,46.83 98.04,44.48 94.24,40.68 85.47,40.68 84.59,39.79 55.83,39.79 50.19,34.15 50.19,32.02 51.41,30.8 52.33,30.8 53.36,29.76 53.36,29.48 53.81,29.03 v2(53.81,28.68)
  BOTTOM w0.102: v2(99.37,50.5) 99.37,51.35 98.97,51.75 98.97,52.23 99.07,52.33 99.07,52.88 99.22,53.02 99.22,53.35 UC1.P30
DDR_B_DQ20: length 71.9
  TOP w0.117: v2(50.14,27.88) 50.36,27.66 UD6.H2
  IN2 w0.102: v2(93.78,48.03) 94.62,48.03 94.75,47.9 94.75,47.47 94.55,47.27 94.3,47.27 94.2,47.17 94.2,46.98 94.3,46.87 94.64,46.87 94.75,46.77 94.75,46.26
  IN2 w0.127: 94.75,46.26 94.75,44.78 94.04,44.08 92.56,44.08 91.3,42.82 84.59,42.82 83.72,41.95 54.97,41.95 47.46,34.44 47.46,29.23 48.73,27.96 50.07,27.96 v2(50.14,27.88)
  BOTTOM w0.102: UC1.L32 96.37,51.13 96.02,50.77 96.02,49.24 94.8,48.03 v2(93.78,48.03)
DDR_B_DQ21: length 71.5
  TOP w0.117: v2(53.89,29.61) 53.89,29.43 54.22,29.1 54.22,28.03 54.39,27.86 54.54,27.86 54.54,27.86 54.96,27.86 UD6.H8
  IN2 w0.127: v2(53.89,29.61) 54.1,29.81 54.1,30.43 53.97,30.56 52.87,30.56 52.42,31.01 51.74,31.01 51.02,31.73 51.02,34.44 55.99,39.41 84.74,39.41 85.63,40.3 94.4,40.3 98.42,44.32 98.42,46.77 98.64,47 98.64,49.22 98.77,49.34 99.25,49.34 99.37,49.47 v2(99.37,49.7)
  BOTTOM w0.102: UC1.N31 98.88,52.42 98.78,52.32 98.78,51.54 98.97,51.34 98.97,50.1 v2(99.37,49.7)
DDR_B_DQ22: length 72.8
  TOP w0.102: v2(50.94,27.08) 51.17,26.85 51.17,26.85 UD6.J3
  IN2 w0.127: v2(93.82,45.6) 93.77,45.55 92.95,45.55 90.98,43.58 84.27,43.58 83.41,42.72 54.65,42.72 48.06,36.12 46.97,36.12 46.7,35.85 46.7,28.72 48.6,26.82 49.68,26.82 49.95,27.08 v2(50.94,27.08)
  BOTTOM w0.102: 94.48,46.26 v3(94.75,46.53) 96.63,48.41 96.63,50.64 96.78,50.78 96.78,52.32 96.87,52.42 UC1.L31
  BOTTOM w0.117: 94.48,46.26 93.82,45.6 v2(93.82,45.6)
DDR_B_DQ23: length 72.4
  TOP w0.117: v2(53.08,28.97) 53.08,28.79 53.79,28.08 53.79,27.73 54.55,26.98 UD6.J7
  IN2 w0.089: 52.89,28.97 v2(53.08,28.97)
  IN2 w0.102: 97.27,46.34 97.27,46.9 97.77,47.39 97.77,49.31 v2(97.37,49.7)
  IN2 w0.127: 97.27,46.34 96.39,45.45 96.39,44.07 93.76,41.44 85.16,41.44 84.27,40.55 55.51,40.55 49.3,34.34 49.3,33.61 49.55,33.36 49.55,30.94 49.87,30.63 50.51,30.63 51.08,30.05 51.84,30.05 52.09,29.8 52.09,29.77 52.89,28.97
  BOTTOM w0.102: v2(97.37,49.7) 96.97,50.1 96.97,52.23 97.07,52.33 97.07,52.88 97.26,53.07 97.26,53.39 UC1.M30
DDR_B_DQ24: length 69.1
  TOP w0.117: UD6.A3 51.34,33.08 v2(51.76,33.5)
  IN2 w0.127: v2(99.37,47.3) 100.02,46.66 100.02,44.78 94.77,39.54 85.95,39.54 85.06,38.65 62.78,38.65 62.65,38.52 62.65,38.16 62.53,38.03 62.27,38.03 62.15,38.16 62.15,38.52 62.02,38.65 61.75,38.65 61.62,38.52 61.62,38.18 61.5,38.05 61.24,38.05 61.12,38.18 61.12,38.52 60.99,38.65 60.73,38.65 60.61,38.52 60.61,38.18 60.48,38.05 60.23,38.05 60.1,38.18 60.1,38.52 59.97,38.65 59.72,38.65 59.59,38.52 59.59,38.18 59.46,38.05 59.21,38.05 59.08,38.18 59.08,38.52 58.96,38.65 58.7,38.65 58.58,38.52 58.58,38.18 58.45,38.05 58.19,38.05 58.07,38.18 58.07,38.52 57.94,38.65 57.69,38.65 57.56,38.52 57.56,38.18 57.43,38.05 57.18,38.05 57.05,38.18 57.05,38.52 56.92,38.65 56.61,38.65 56.48,38.52 56.48,38.16 56.35,38.03 55.88,38.03 51.76,33.91 v2(51.76,33.5)
  BOTTOM w0.102: UC1.P29 99.88,53.56 99.57,53.26 99.57,53 99.67,52.82 99.67,52.33 99.78,52.23 99.78,47.7 v2(99.37,47.3)
DDR_B_DQ25: length 68.8
  TOP w0.117: v2(55.77,32.68) 55.37,32.28 UD6.B8
  IN2 w0.127: v2(103.37,48.8) 103.57,48.8 104.52,47.85 104.52,44.76 96.39,36.62 87.95,36.62 87.72,36.39 87.54,36.39 87.36,36.57 87.18,36.57 87,36.39 87,36.21 87.18,36.03 87.18,35.85 87,35.67 86.82,35.67 86.64,35.85 86.46,35.85 86.28,35.67 86.28,35.49 86.46,35.31 86.46,35.13 86.22,34.89 85.68,34.89 85.55,35.01 85.55,35.49 85.42,35.62 85.13,35.62 85.01,35.49 85.01,35.01 84.88,34.89 84.62,34.89 84.5,35.01 84.5,35.49 84.37,35.62 84.12,35.62 83.99,35.49 83.99,35.01 83.86,34.89 83.61,34.89 83.48,35.01 83.48,35.49 83.35,35.62 83.1,35.62 82.97,35.49 82.97,35.01 82.85,34.89 58.2,34.89 55.99,32.68 v2(55.77,32.68)
  BOTTOM w0.102: v2(103.37,48.8) 102.64,49.54 102.64,51.19 102.19,51.64 102.19,52.12 101.87,52.44 UC1.U31
DDR_B_DQ26: length 69.6
  TOP w0.117: v2(52.64,32.38) 52.64,32.33 51.79,31.48 UD6.C3
  IN2 w0.102: v2(101.37,46.4) 101.29,46.31
  IN2 w0.127: v2(52.64,32.38) 52.78,32.52 52.78,33.69 56.35,37.26 59.71,37.26 59.71,37.26 66.49,37.26 66.61,37.39 66.61,37.72 66.74,37.85 66.99,37.85 67.12,37.72 67.12,37.39 67.25,37.26 67.5,37.26 67.63,37.39 67.63,37.72 67.76,37.85 68.01,37.85 68.14,37.72 68.14,37.39 68.26,37.26 68.52,37.26 68.64,37.39 68.64,37.72 68.77,37.85 69.03,37.85 69.15,37.72 69.15,37.39 69.28,37.26 69.53,37.26 69.66,37.39 69.66,37.72 69.79,37.85 70.04,37.85 70.17,37.72 70.17,37.39 70.3,37.26 70.55,37.26 70.68,37.39 70.68,37.72 70.8,37.85 71.06,37.85 71.18,37.72 71.18,37.39 71.31,37.26 71.57,37.26 71.69,37.39 71.69,37.72 71.82,37.85 85.34,37.85 86.26,38.78 95.09,38.78 101.29,44.97 101.29,46.31
  BOTTOM w0.102: UC1.P31 99.87,52.42 99.97,52.32 99.97,50.54 100.07,50.44 100.07,47.7 v3(100.64,47.13) v2(101.37,46.4)
DDR_B_DQ27: length 69.4
  TOP w0.117: UD6.C7 v2(54.13,31.9)
  IN2 w0.127: v2(103.37,46.4) 103.37,44.69 96.07,37.38 86.81,37.38 85.86,36.43 82.27,36.43 82.14,36.3 82.14,35.78 82.01,35.65 81.76,35.65 81.63,35.78 81.63,36.3 81.5,36.43 81.25,36.43 81.12,36.3 81.12,35.78 81,35.65 80.74,35.65 80.61,35.78 80.61,36.3 80.49,36.43 80.23,36.43 80.11,36.3 80.11,35.78 79.98,35.65 79.73,35.65 79.6,35.78 79.6,36.3 79.47,36.43 79.22,36.43 79.09,36.3 79.09,35.78 78.96,35.65 57.71,35.65 57.27,35.21 56.3,35.21 54.95,33.86 54.95,32.72 v2(54.13,31.9)
  BOTTOM w0.102: v2(103.37,46.4) 102.67,47.11 102.67,47.37 v3(102.39,47.64) 101.64,48.4 101.17,48.4 100.67,48.9 100.67,50.59 100.37,50.89 UC1.R32
DDR_B_DQ28: length 69.1
  TOP w0.117: v2(51.84,32.09) 51.65,31.9 50.96,31.9 UD6.C2
  IN2 w0.127: v2(51.84,32.09) 51.84,32.19 52.35,32.7 52.35,33.8 56.19,37.64 59.27,37.64 59.27,37.65 62.98,37.65 63.11,37.77 63.11,38.13 63.23,38.26 63.49,38.26 63.61,38.13 63.61,37.77 63.74,37.65 64,37.65 64.12,37.77 64.12,38.13 64.25,38.26 64.5,38.26 64.63,38.13 64.63,37.77 64.76,37.65 65.01,37.65 65.14,37.77 65.14,38.13 65.27,38.26 65.52,38.26 65.65,38.13 65.65,37.77 65.77,37.65 66.03,37.65 66.15,37.77 66.15,38.13 66.28,38.26 85.21,38.26 86.11,39.16 94.93,39.16 100.4,44.62 100.4,47.02 v2(101.37,48)
  BOTTOM w0.102: UC1.R30 100.26,53.39 100.26,53.01 100.07,52.82 100.07,52.5 100.17,52.4 100.17,50.7 100.34,50.53 100.34,48.8 101.14,48 v2(101.37,48)
DDR_B_DQ29: length 68.9
  TOP w0.117: v2(55.75,31.89) 55.35,31.48 UD6.C8
  IN2 w0.127: v2(55.75,31.89) 56.08,32.21 56.74,32.21 57.53,33.01 57.71,33.01 58.05,32.67 58.23,32.67 58.4,32.83 58.4,33.01 57.72,33.69 57.72,33.87 57.9,34.05 58.08,34.05 58.81,33.32 58.99,33.32 59.18,33.52 59.18,33.7 58.79,34.09 58.79,34.27 59.03,34.51 86.38,34.51 88.11,36.24 96.54,36.24 104.93,44.63 104.93,49.34 103.88,50.4 v2(103.37,50.4)
  BOTTOM w0.102: v2(103.37,50.4) 102.96,50.81 102.96,51.33 102.57,51.71 102.57,52.06 102.07,52.56 102.07,52.82 102.37,53.12 UC1.V30
DDR_B_DQ30: length 69.9
  TOP w0.117: v2(52.54,31.64) 52.37,31.64 51.41,30.68 UD6.D3
  IN2 w0.127: v2(52.54,31.64) 52.98,31.2 54.25,31.2 55.33,32.28 55.33,33.67 56.09,34.43 57.15,34.43 57.99,35.27 82.19,35.27 82.94,36.02 85.99,36.02 86.97,37 96.23,37 104.02,44.79 104.02,47.36 v2(103.37,48)
  BOTTOM w0.102: UC1.U29 101.88,53.52 101.57,53.22 101.57,52.92 101.67,52.82 101.67,52.33 101.87,52.13 101.87,51.48 102.29,51.07 v3(102.29,49.87) 102.29,49.08 v2(103.37,48)
DDR_B_DQ31: length 68.7
  TOP w0.117: UD6.D7 54.55,30.68 v2(54.95,31.09)
  IN2 w0.089: v2(54.95,31.09) 55.35,30.69 56.84,30.69
  IN2 w0.127: 56.84,30.69 58.36,32.21 58.54,32.21 58.74,32.01 58.92,32.01 59.1,32.19 59.1,32.37 58.9,32.57 58.9,32.75 59.08,32.93 59.26,32.93 59.51,32.68 59.69,32.68 59.87,32.86 59.87,33.04 59.62,33.29 59.62,33.47 60.21,34.07 61.69,34.07 62.27,33.48 62.58,33.48 63.22,34.13 86.53,34.13 88.27,35.86 96.7,35.86 105.36,44.52 105.36,49.57 103.74,51.2 v2(103.37,51.2)
  BOTTOM w0.102: UC1.V32 102.96,52.11 102.96,51.77 103.37,51.36 v2(103.37,51.2)
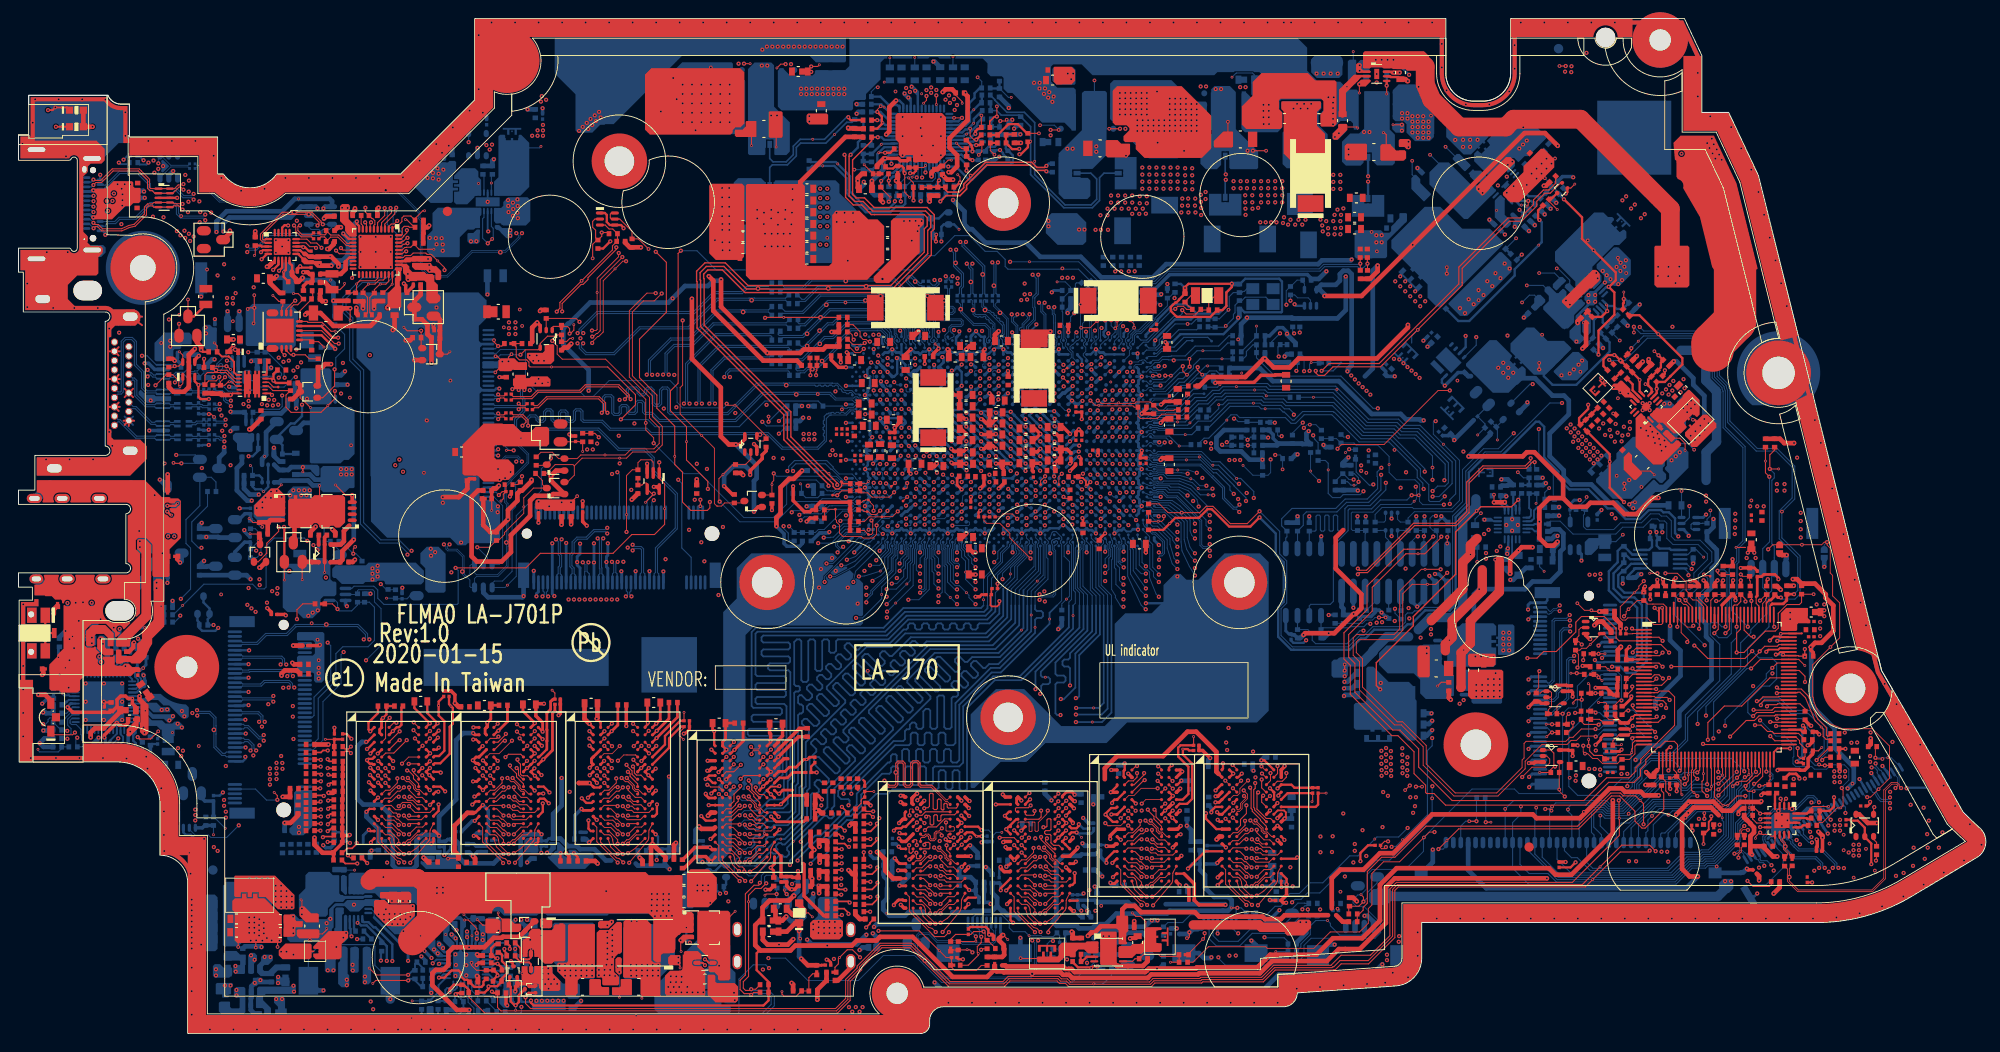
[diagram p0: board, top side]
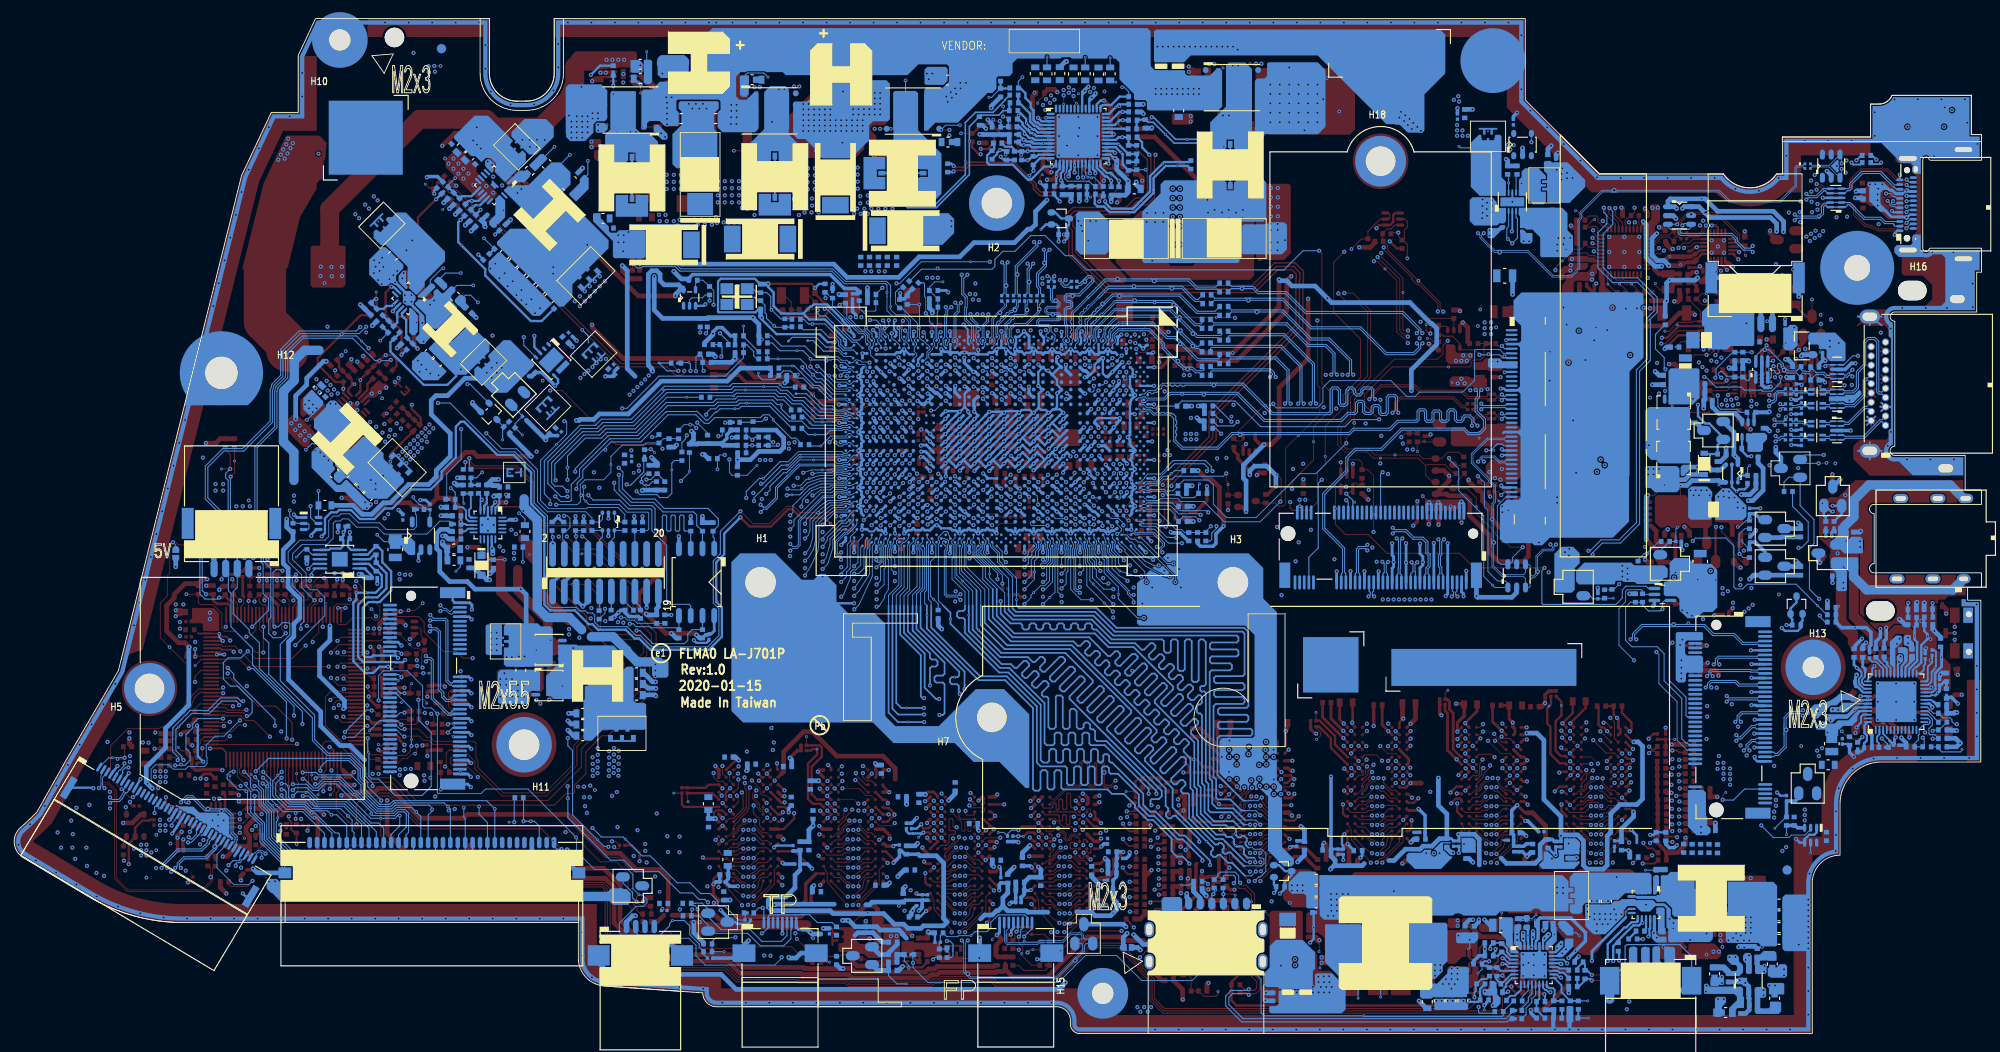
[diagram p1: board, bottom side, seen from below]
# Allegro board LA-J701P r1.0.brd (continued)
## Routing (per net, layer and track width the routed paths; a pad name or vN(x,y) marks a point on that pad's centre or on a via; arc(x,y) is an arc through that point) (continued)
DDR_B_DQ32: length 87.6
  TOP w0.117: UD7.G2 v2(62.47,28.68)
  IN1 w0.102: v2(62.47,28.68) 62.47,28.9 61.89,29.48 60.75,29.48 59.67,30.57 59.67,34.04 70.5,44.87 86.39,44.87 86.49,44.98 86.49,45.37 86.59,45.47 86.79,45.47 86.89,45.37 86.89,44.98 87,44.87 87.2,44.87 87.3,44.98 87.3,45.34 87.43,45.47 87.63,45.47 87.76,45.34 87.76,44.63 87.86,44.53 88.06,44.53 88.16,44.63 88.16,45.37 88.27,45.47 88.42,45.47 88.55,45.34 88.55,44.63 88.65,44.53 88.85,44.53 88.95,44.63 88.95,45.37 89.05,45.47 89.23,45.47 89.33,45.37 89.33,44.6 89.42,44.51 89.63,44.51 89.7,44.58 89.7,45.45 89.75,45.5 90.85,45.5 91,45.34 91,44.38 91.13,44.25 91.35,44.25 91.46,44.35 91.46,45.47 91.56,45.57 91.76,45.57 91.86,45.47 91.86,44.35 91.96,44.25 92.17,44.25 92.27,44.35 92.27,44.84 92.37,44.94 92.57,44.94 92.67,44.84 92.67,44.35 92.78,44.25 94.59,44.25 96.57,46.23 99.51,46.23 100.88,47.6 104.4,47.6 104.94,48.15 104.94,48.57 106.73,50.36 116.79,50.36 v2(117.37,49.78)
  BOTTOM w0.102: v2(117.37,49.78) 117.77,50.18 117.77,51.37 117.97,51.57 117.97,52.32 117.88,52.42 UC1.AT31
DDR_B_DQ33: length 87.9
  TOP w0.117: v2(66.42,29.59) 66.42,29.54 UD7.F7
  IN1 w0.102: v2(121.76,45.85) 121.01,45.1 119.18,45.1 118.74,45.55 107.01,45.55 105.41,43.94 98.15,43.94 95.98,41.78 89.61,41.78 89.31,42.08 80.38,42.08 80.28,42.18 80.28,42.6 80.18,42.7 79.97,42.7 79.87,42.6 79.87,42.18 79.77,42.08 79.57,42.08 79.46,42.18 79.46,42.6 79.36,42.7 79.16,42.7 79.06,42.6 79.06,42.18 78.96,42.08 78.75,42.08 78.65,42.18 78.65,42.6 78.55,42.7 78.35,42.7 78.24,42.6 78.24,42.18 78.14,42.08 77.94,42.08 77.84,42.18 77.84,42.6 77.74,42.7 77.53,42.7 77.43,42.6 77.43,42.18 77.33,42.08 77.13,42.08 77.03,42.18 77.03,42.6 76.92,42.7 76.72,42.7 76.62,42.6 76.62,42.18 76.52,42.08 76.31,42.08 76.21,42.18 76.21,42.6 76.11,42.7 75.91,42.7 75.81,42.6 75.81,42.18 75.7,42.08 75.5,42.08 75.4,42.18 75.4,42.6 75.3,42.7 71.43,42.7 63.22,34.5 63.22,33.67 62.72,33.17 62.72,31.07 63.11,30.68 65.59,30.68 66.42,29.85 v2(66.42,29.59)
  BOTTOM w0.102: UC1.AV30 119.54,53.34 119.54,52.98 119.81,52.71 119.81,49.43 121.25,46.32 121.31,46.26
  BOTTOM w0.117: v2(121.76,45.85) 121.72,45.85 121.31,46.26
DDR_B_DQ34: length 88
  TOP w0.117: UD7.H3 v2(63.27,27.88)
  IN1 w0.102: v2(117.37,50.5) 117.26,50.61 106.57,50.61 104.37,48.42 102.38,48.42 102.3,48.49 101.62,48.49 101.54,48.42 101.21,48.42 101.13,48.49 98.4,48.49 97.78,47.87 97.78,47.48 97.55,47.25 97.16,47.25 94.46,44.56 93.39,44.56 92.07,45.88 89.78,45.88 89.68,45.98 89.68,47.45 89.58,47.55 89.37,47.55 89.27,47.45 89.27,45.93 89.17,45.83 88.97,45.83 88.87,45.93 88.87,47.48 88.77,47.58 88.56,47.58 88.46,47.48 88.46,45.93 88.36,45.83 88.16,45.83 88.05,45.93 88.05,47.02 87.95,47.12 87.75,47.12 87.65,47.02 87.65,45.9 87.55,45.8 86.49,45.8 85.87,45.18 70.31,45.18 59.35,34.22 59.35,30.43 60.62,29.16 61.83,29.16 62.08,28.91 62.08,28.47 62.27,28.28 62.88,28.28 v2(63.27,27.88)
  BOTTOM w0.102: UC1.AR30 117.5,53.37 117.5,53.05 117.67,52.88 117.67,52.33 117.77,52.23 117.77,51.71 117.37,51.3 v2(117.37,50.5)
DDR_B_DQ35: length 88.7
  TOP w0.117: UD7.H7 66.8,27.48 66.27,28.01 66.27,28.38 65.68,28.97 v2(65.68,29.04)
  IN1 w0.102: v2(119.35,46.12) 119.22,46.25 118.75,46.25 118.65,46.35 118.65,46.87 118.55,46.97 118.34,46.97 118.24,46.87 118.24,46.35 118.14,46.25 117.94,46.25 117.84,46.35 117.84,46.87 117.74,46.97 117.53,46.97 117.43,46.87 117.43,46.35 117.33,46.25 117.13,46.25 117.02,46.35 117.02,46.87 116.92,46.97 116.72,46.97 116.62,46.87 116.62,46.35 116.52,46.25 116.31,46.25 116.21,46.35 116.21,46.87 116.11,46.97 115.91,46.97 115.8,46.87 115.8,46.35 115.7,46.25 106.81,46.25 105.12,44.55 97.74,44.55 95.57,42.39 89.9,42.39 89.53,42.75 86.96,42.75 86.84,42.88 86.84,43.19 86.71,43.32 86.53,43.32 86.43,43.22 86.43,42.8 86.33,42.7 86.12,42.7 86.02,42.8 86.02,43.22 85.92,43.32 85.72,43.32 85.61,43.22 85.61,42.8 85.51,42.7 85.31,42.7 85.21,42.8 85.21,43.22 85.11,43.32 71.15,43.32 61.95,34.13 61.95,33.8 62.14,33.61 62.14,30.94 62.79,30.29 64.82,30.29 65.47,29.65 65.47,29.24 v2(65.68,29.04)
  BOTTOM w0.102: UC1.AT29 118.11,53.29 118.18,53.22 118.18,52.92 118.07,52.82 118.07,52.56 118.18,52.46 118.18,51.3 118.07,51.2 118.07,47.99 118.5,47.3 118.47,47.14 119.01,46.26
  BOTTOM w0.117: 119.01,46.26 119.06,46.19 v2(119.35,46.12)
DDR_B_DQ36: length 88.9
  TOP w0.117: UD7.H2 v2(62.47,27.88)
  IN1 w0.102: v2(62.47,27.88) 62.35,27.88 61.89,28.34 61.01,28.34 59.05,30.31 59.05,34.34 70.19,45.48 85.74,45.48 92.86,52.61 119.38,52.61 120.18,51.81 120.18,49.69 v2(121.77,48.1)
  BOTTOM w0.102: v2(121.77,48.1) 120.41,50.03 120.41,52.32 120.29,52.43 120.29,53.14 119.88,53.56 UC1.AW29
DDR_B_DQ37: length 88
  TOP w0.117: v2(66.37,28.86) 66.37,28.8 66.52,28.65 66.52,28.16 66.75,27.92 67.23,27.92 UD7.H8
  IN1 w0.102: v2(66.37,28.86) 65.98,29.25 65.98,29.57 65.07,30.49 62.92,30.49 62.4,31.01 62.4,33.36 62.91,33.86 62.91,34.61 71.3,43.01 80.54,43.01 80.64,42.91 80.64,42.48 80.74,42.38 81,42.38 81.1,42.48 81.1,42.91 81.2,43.01 81.41,43.01 81.51,42.91 81.51,42.48 81.61,42.38 81.81,42.38 81.92,42.48 81.92,42.91 82.02,43.01 82.22,43.01 82.32,42.91 82.32,42.48 82.42,42.38 82.63,42.38 82.73,42.48 82.73,42.91 82.83,43.01 83.03,43.01 83.13,42.91 83.13,42.48 83.24,42.38 83.44,42.38 83.54,42.48 83.54,42.91 83.64,43.01 83.85,43.01 83.95,42.91 83.95,42.48 84.05,42.38 84.25,42.38 84.35,42.48 84.35,42.91 84.46,43.01 84.66,43.01 84.76,42.91 84.76,42.48 84.86,42.38 89.43,42.38 89.73,42.08 95.7,42.08 97.86,44.25 105.28,44.25 106.98,45.94 118.77,45.94 119.13,45.59 120.06,45.59 v2(121.77,47.3)
  BOTTOM w0.102: UC1.AW31 120.07,52.91 120.07,52.3 120.11,52.25 120.11,49.67 121.24,47.83 v2(121.77,47.3)
DDR_B_DQ38: length 87.8
  TOP w0.117: UD7.J3 v2(63.27,27.08)
  IN1 w0.102: v2(121.77,49.7) 120.39,51.09 120.39,51.89 119.46,52.81 92.64,52.81 85.61,45.79 70.06,45.79 58.74,34.47 58.74,30.03 61.31,27.46 62.89,27.46 v2(63.27,27.08)
  BOTTOM w0.102: v2(121.77,49.7) 121.27,49.7 120.71,50.26 120.71,52.38 120.54,52.54 120.54,53.33 UC1.AW30
DDR_B_DQ39: length 88.2
  TOP w0.117: UD7.J7 66.88,26.98 66.06,27.8 66.06,28.07 65.85,28.28 v2(65.83,28.28)
  IN1 w0.102: v2(65.83,28.28) 65.17,28.94 65.17,29.63 64.74,30.07 62.65,30.07 62,30.72 61.29,30.72 60.97,31.03 60.97,33.58 71.02,43.63 86.92,43.63 87.31,43.24 89.48,43.24 90.02,42.69 95.45,42.69 97.61,44.85 104.99,44.85 106.7,46.56 109.36,46.56 109.49,46.69 109.49,47.83 109.82,48.16 111.42,48.16 111.65,47.94 111.65,46.68 111.75,46.58 111.95,46.58 112.06,46.68 112.06,47.07 112.16,47.17 112.36,47.17 112.46,47.07 112.46,46.68 112.56,46.58 112.77,46.58 112.87,46.68 112.87,47.07 112.97,47.17 113.17,47.17 113.27,47.07 113.27,46.68 113.38,46.58 113.58,46.58 113.68,46.68 113.68,47.07 113.78,47.17 113.99,47.17 114.09,47.07 114.09,46.68 114.19,46.58 114.39,46.58 114.49,46.68 114.49,47.07 114.6,47.17 114.8,47.17 114.9,47.07 114.9,46.68 115,46.58 115.21,46.58 115.31,46.68 115.31,47.07 115.41,47.17 118.28,47.17 118.83,47.72 v2(119.35,47.72)
  BOTTOM w0.102: UC1.AU32 118.37,50.35 118.53,50.19 118.53,48.54 v2(119.35,47.72)
DDR_B_DQ40: length 80.5
  TOP w0.117: UD7.A3 63.68,33.08 v2(64.09,33.5)
  IN1 w0.102: v2(64.09,33.5) 64.09,34.43 68.71,39.05 68.86,39.05 69.23,38.68 69.37,38.68 69.52,38.82 69.52,38.97 69.15,39.34 69.15,39.49 69.29,39.63 69.43,39.63 69.81,39.26 69.95,39.26 70.09,39.4 70.09,39.54 69.72,39.92 69.72,40.06 69.86,40.2 70.01,40.2 70.38,39.83 70.52,39.83 70.67,39.97 70.67,40.12 70.3,40.49 70.3,40.64 70.44,40.78 70.58,40.78 70.96,40.41 71.1,40.41 71.24,40.55 71.24,40.69 70.87,41.07 70.87,41.21 71.04,41.38 71.16,41.38 71.53,41.01 71.78,41.01 72.19,41.42 89.03,41.42 89.44,41.02 96.25,41.02 98.51,43.28 105.85,43.28 107.42,44.85 118.5,44.85 118.92,44.43 121.69,44.43 122.77,45.51 122.77,49.19 v2(123.18,49.6)
  BOTTOM w0.102: UC1.BA28 121.47,54.4 122.18,53.7 122.18,53.19 122.51,52.86 122.51,50.38 123.18,49.73 v2(123.18,49.6)
DDR_B_DQ41: length 80.3
  TOP w0.117: UD7.B8 v2(68.07,32.7)
  IN1 w0.102: v2(68.07,32.7) 67.54,33.23 67.54,34.05 73.3,39.8 88.45,39.8 88.93,39.32 96.95,39.32 99.33,41.71 107.09,41.71 107.4,42.01 111.88,42.01 111.99,42.11 111.99,42.55 112.09,42.65 112.29,42.65 112.39,42.55 112.39,42.11 112.49,42.01 112.7,42.01 112.8,42.11 112.8,42.55 112.9,42.65 113.1,42.65 113.2,42.55 113.2,42.11 113.31,42.01 113.51,42.01 113.61,42.11 113.61,42.55 113.71,42.65 113.92,42.65 114.02,42.55 114.02,42.11 114.12,42.01 114.32,42.01 114.42,42.11 114.42,42.55 114.53,42.65 122.54,42.65 124.91,45.02 124.91,49.03 124.51,49.42 124.51,52.14 124.98,52.6 v2(125.18,52.6)
  BOTTOM w0.102: v2(125.18,52.6) 124.67,53.33 124.67,53.62 123.14,55.15 122.63,55.15 UC1.BC27
DDR_B_DQ42: length 80.7
  TOP w0.117: v2(64.11,31.05) UD7.C3
  IN1 w0.102: v2(123.18,48.8) 123.2,48.8 123.72,48.28 123.72,45.6 121.94,43.82 118.67,43.82 118.25,44.24 107.86,44.24 106.27,42.65 98.74,42.65 96.45,40.36 89.23,40.36 88.78,40.81 72.44,40.81 67.52,35.89 67.38,35.89 67.04,36.23 66.9,36.23 66.75,36.08 66.75,35.94 67.09,35.6 67.09,35.46 66.95,35.31 66.8,35.31 66.47,35.65 66.32,35.65 66.18,35.51 66.18,35.37 66.52,35.03 66.52,34.88 66.37,34.74 66.23,34.74 65.89,35.08 65.75,35.08 65.6,34.93 65.6,34.79 65.94,34.45 65.94,34.31 65.77,34.14 65.63,34.14 65.44,34.32 65.3,34.32 65.15,34.18 65.15,34.04 65.34,33.85 65.34,33.71 64.91,33.28 64.91,31.86 v2(64.11,31.05)
  BOTTOM w0.102: UC1.BB30 121.77,53.16 122.2,52.73 122.2,50.27 122.59,49.88 122.59,49.38 v2(123.18,48.8)
DDR_B_DQ43: length 80.5
  TOP w0.117: UD7.C7 v2(66.46,31.06)
  IN1 w0.102: v2(66.46,31.06) 67.23,31.83 68.24,31.83 68.71,32.3 69.22,32.3 69.64,32.72 69.64,35.28 73.55,39.19 88.2,39.19 88.7,38.7 97.19,38.7 99.59,41.1 107.43,41.1 107.73,41.4 114.72,41.4 115.36,42.04 122.79,42.04 123.97,43.22 125.96,45.21 125.96,50.21 v2(125.18,51)
  BOTTOM w0.102: UC1.BB26 121.88,55.44 122.48,54.84 123.02,54.84 124.37,53.48 124.37,52.88 124.82,51.35 v2(125.18,51)
DDR_B_DQ44: length 79.9
  TOP w0.117: v2(63.29,31.89) 62.88,31.48 UD7.C2
  IN1 w0.102: v2(63.29,31.89) 63.67,32.28 63.67,34.44 70.95,41.72 71.9,41.72 72.02,41.85 72.02,42.02 72.12,42.12 72.32,42.12 72.45,41.99 72.45,41.85 72.57,41.72 72.75,41.72 72.86,41.82 72.86,42.25 72.96,42.35 73.16,42.35 73.26,42.25 73.26,41.82 73.36,41.72 73.57,41.72 73.67,41.82 73.67,42.25 73.77,42.35 73.97,42.35 74.08,42.25 74.08,41.82 74.18,41.72 74.38,41.72 74.48,41.82 74.48,42.25 74.58,42.35 74.79,42.35 74.89,42.25 74.89,41.82 74.99,41.72 89.16,41.72 89.49,41.39 96.19,41.39 98.38,43.58 105.58,43.58 107.17,45.17 118.62,45.17 119.03,44.75 121.58,44.75 122.31,45.48 122.31,50.37 122.18,50.5 v2(121.77,50.5)
  BOTTOM w0.102: UC1.AY29 120.88,53.68 121.36,53.19 121.36,50.92 v2(121.77,50.5)
DDR_B_DQ45: length 81.2
  TOP w0.117: UD7.C8 v2(68.09,31.07)
  IN1 w0.102: v2(125.18,55) 126.6,53.58 126.6,49.32 126.63,49.28 126.63,45.02 123.04,41.43 115.61,41.43 114.97,40.79 108.09,40.79 107.78,40.49 99.84,40.49 97.41,38.06 88.47,38.06 87.95,38.58 74.76,38.58 70.4,34.22 70.4,31.9 69.13,30.63 68.53,30.63 v2(68.09,31.07)
  BOTTOM w0.102: v2(125.18,55) 123.82,56.36 122.42,56.36 UC1.BC25
DDR_B_DQ46: length 80.7
  TOP w0.117: v2(63.27,31.08) UD7.D3
  IN1 w0.102: v2(123.18,47.2) 123.22,47.15 123.22,46.45 123.22,46.45 123.22,45.53 121.82,44.13 118.79,44.13 118.38,44.54 107.62,44.54 106.05,42.98 98.64,42.98 96.35,40.69 89.33,40.69 88.91,41.11 72.31,41.11 69.38,38.17 69.23,38.17 68.87,38.54 68.72,38.54 68.58,38.39 68.58,38.25 68.94,37.89 68.94,37.74 68.8,37.6 68.66,37.6 68.29,37.96 68.15,37.96 68.01,37.82 68.01,37.68 68.37,37.31 68.37,37.17 68.23,37.02 68.08,37.02 67.72,37.39 67.57,37.39 67.43,37.24 67.43,37.1 67.79,36.74 67.79,36.59 67.65,36.45 67.51,36.45 67.14,36.81 67,36.81 64.56,34.37 64.56,31.93 64.28,31.65 64.08,31.65 63.5,31.08 v2(63.27,31.08)
  BOTTOM w0.102: UC1.AY32 121.06,52.52 121.06,50.63 121.59,50.1 121.94,50.1 122.18,49.87 122.18,49.25 122.88,47.49 v2(123.18,47.2)
DDR_B_DQ47: length 81
  TOP w0.117: UD7.D7 v2(67.28,31.09)
  IN1 w0.102: v2(67.28,31.09) 67.71,31.51 69.03,31.51 70.02,32.5 70.02,34.6 74.31,38.89 88.07,38.89 88.58,38.38 97.3,38.38 99.71,40.79 107.56,40.79 107.87,41.1 114.84,41.1 115.48,41.74 122.92,41.74 126.32,45.14 126.32,52.26 v2(125.18,53.4)
  BOTTOM w0.102: v2(125.18,53.4) 125.18,53.56 123.26,55.48 122.75,55.48 122.32,55.91 122.32,56.01 121.83,56.5 UC1.BA25
DDR_B_DQ48: length 97.1
  TOP w0.117: v2(74.4,26.88) 74.53,26.88 74.76,26.64 75.69,26.64 75.91,26.42 UD8.G2
  IN1 w0.102: v2(74.4,26.88) 74.15,26.88 73.02,28.01 73.02,33.84 73.29,34.11 73.29,34.26 73.04,34.51 73.04,34.65 73.18,34.79 73.33,34.79 73.58,34.54 73.72,34.54 73.9,34.73 73.9,34.91 73.27,35.54 73.27,35.72 73.41,35.87 73.56,35.87 74.23,35.19 74.37,35.19 74.52,35.34 74.52,35.48 73.84,36.15 73.84,36.3 73.99,36.44 74.13,36.44 74.8,35.77 74.95,35.77 75.09,35.91 75.09,36.06 74.42,36.73 74.42,36.87 74.56,37.02 74.71,37.02 75.38,36.34 75.52,36.34 75.67,36.49 75.67,36.63 74.99,37.3 74.99,37.45 75.13,37.59 75.31,37.59 75.95,36.95 76.13,36.95 76.79,37.62 87.55,37.62 88.07,37.09 91.04,37.09 97.5,37.09 97.81,37.09 98.52,37.8 102.89,37.8 104.56,39.47 108.26,39.47 108.62,39.83 118.57,39.83 118.68,39.73 118.68,39.07 118.78,38.97 118.98,38.97 119.08,39.07 119.08,39.4 119.18,39.5 119.39,39.5 119.49,39.4 119.49,39.07 119.59,38.97 121.95,38.97 127.8,44.83 127.8,51.17 v2(127.07,51.9)
  BOTTOM w0.102: v2(127.07,51.9) 126.78,52.19 126.52,52.61 126.24,53.61 126.24,55.38 125.36,56.26 124.24,57.1 123.03,57.1 122.83,57.3 122.51,57.3 122.38,57.17 122.15,57.17 121.82,57.5 UC1.BA24
DDR_B_DQ49: length 96.6
  TOP w0.117: v2(80.46,27.49) 80.46,27.49 UD8.F7
  IN1 w0.102: v2(126.27,58.15) 128.03,58.15 129.81,56.37 129.81,56.14 132.17,53.78 132.79,53.78 135.49,51.08 136.07,49.59 136.07,47.73 135.57,46.52 127.46,38.41 122.8,36.48 115.26,36.48 114.49,35.72 112.92,35.72 108.76,31.56 107.1,31.23 105.27,31.23 102,34.5 82.96,34.5 82.69,34.77 79.62,34.77 76.08,31.22 76.08,29.71 77.12,28.67 78.77,28.67 79.95,27.49 v2(80.46,27.49)
  BOTTOM w0.102: UC1.BD22 124.08,59 124.33,58.75 125.38,58.75 126.2,58.14 v2(126.27,58.15)
DDR_B_DQ50: length 96.6
  TOP w0.117: UD8.H3 76.84,25.48 v2(76.43,25.89)
  IN1 w0.102: v2(76.43,25.89) 76.22,25.89 75.8,26.31 75.35,26.31 75.16,26.5 73.96,26.5 72.71,27.74 72.71,35.6 75.04,37.92 87.67,37.92 88.2,37.4 90.91,37.4 97.69,37.4 98.39,38.11 101.81,38.11 101.91,38.21 101.91,39.71 102.01,39.81 102.19,39.81 102.32,39.68 102.32,38.21 102.42,38.11 102.61,38.11 102.76,38.26 102.76,39.65 102.88,39.77 103.11,39.77 103.22,39.67 103.22,39.05 103.32,38.94 103.59,38.94 103.69,39.05 103.69,39.67 103.79,39.77 108.06,39.77 108.42,40.13 119.77,40.13 119.87,40.03 119.87,39.38 119.98,39.27 120.18,39.27 120.28,39.38 120.28,40.03 120.38,40.13 120.58,40.13 120.69,40.03 120.69,39.38 120.79,39.27 120.99,39.27 121.09,39.38 121.09,40.03 121.19,40.13 121.4,40.13 121.5,40.03 121.5,39.38 121.6,39.27 121.8,39.27 121.91,39.38 121.91,40.03 122.01,40.13 122.68,40.13 127.49,44.94 127.49,50.69 v2(127.07,51.1)
  BOTTOM w0.102: UC1.BD25 122.82,56.85 124.02,56.85 125.33,55.86 125.91,55.28 125.91,53.38 126.18,52.34 126.66,51.51 v2(127.07,51.1)
DDR_B_DQ51: length 97.1
  TOP w0.117: UD8.H7 79.84,25.69 79.84,25.69 79.21,26.32 79.21,26.87 78.88,27.2 v2(78.88,27.36)
  IN1 w0.102: v2(128.67,56.01) 129.06,56.01 129.23,55.83 129.25,55.83 131.92,53.17 132.54,53.17 134.92,50.79 135.46,49.47 135.46,47.85 135.05,46.87 127.16,38.97 122.61,37.09 112.18,37.09 112.08,37.19 112.08,37.67 111.98,37.78 111.77,37.78 111.67,37.67 111.67,37.19 111.57,37.09 111.4,37.09 111.27,37.22 111.27,37.6 111.12,37.75 109.57,37.75 109.41,37.59 105.3,37.59 102.82,35.11 83.21,35.11 82.94,35.38 79.37,35.38 75.47,31.47 75.47,29.69 76.88,28.28 78.34,28.28 78.88,27.73 v2(78.88,27.36)
  BOTTOM w0.102: v2(128.67,56.01) 128.39,56.3 128.39,57.05 126.57,58.86 125.32,59.4 123.06,59.4 122.96,59.5 UC1.BC22
DDR_B_DQ52: length 97.2
  TOP w0.117: v2(75.65,25.88) 76.05,25.48 UD8.H2
  IN1 w0.102: v2(75.65,25.88) 75.46,25.88 75.03,26.31 73.64,26.31 72.41,27.54 72.41,35.72 74.91,38.23 87.8,38.23 88.32,37.7 90.78,37.7 97.56,37.7 98.27,38.41 100.58,38.41 100.68,38.51 100.68,39.1 100.78,39.2 100.98,39.2 101.09,39.1 101.09,38.51 101.19,38.41 101.39,38.41 101.49,38.51 101.49,40.03 101.59,40.13 107.96,40.13 108.27,40.44 115.51,40.44 115.61,40.54 115.61,40.93 115.76,41.08 115.96,41.08 116.06,40.98 116.06,40.54 116.16,40.44 116.36,40.44 116.46,40.54 116.46,40.98 116.56,41.08 116.77,41.08 116.87,40.98 116.87,40.54 116.97,40.44 117.17,40.44 117.28,40.54 117.28,40.98 117.38,41.08 117.58,41.08 117.68,40.98 117.68,40.54 117.78,40.44 117.99,40.44 118.09,40.54 118.09,40.98 118.19,41.08 118.39,41.08 118.5,40.98 118.5,40.54 118.6,40.44 118.8,40.44 118.9,40.54 118.9,40.98 119,41.08 119.21,41.08 119.31,40.98 119.31,40.54 119.41,40.44 119.61,40.44 119.71,40.54 119.71,40.98 119.82,41.08 120.09,41.08 120.19,40.98 120.19,40.57 120.29,40.47 120.49,40.47 120.59,40.57 120.59,40.98 120.69,41.08 120.91,41.08 121.01,40.98 121.01,40.54 121.12,40.44 121.32,40.44 121.42,40.54 121.42,40.98 121.52,41.08 121.71,41.08 121.81,40.98 121.81,40.54 121.91,40.44 122.12,40.44 122.22,40.54 122.22,40.98 122.32,41.08 123.19,41.08 127.07,44.96 v2(127.07,49.5)
  BOTTOM w0.102: UC1.BB25 121.96,56.91 122.3,56.91 122.62,56.6 123.85,56.6 125.34,55.42 125.57,55.18 125.57,53.12 125.67,52.16 126.46,50.51 v2(127.07,49.5)
DDR_B_DQ53: length 97.5
  TOP w0.117: UD8.H8 80.5,25.83 80.04,25.83 79.62,26.25 v2(79.62,26.59)
  IN1 w0.102: v2(127.47,56.95) 128.57,56.95 132.05,53.47 132.66,53.47 135.18,50.96 135.77,49.53 135.77,47.79 135.31,46.69 127.33,38.71 122.67,36.78 111.37,36.78 110.71,36.12 109.75,36.12 108.79,37.09 105.24,37.09 102.95,34.8 83.08,34.8 82.81,35.07 79.5,35.07 75.77,31.35 75.77,29.7 77,28.47 78.53,28.47 79.62,27.37 v2(79.62,26.59)
  BOTTOM w0.102: v2(127.47,56.95) 127.29,57.72 126.35,58.66 125.36,59.05 124.46,59.05 124.31,59.2 122.97,59.2 122.77,59.3 122.61,59.3 122.35,59.2 122.21,59.2 UC1.BA22
DDR_B_DQ54: length 96.6
  TOP w0.117: UD8.J3 77.28,25.11 77.28,25.86 77.96,26.53 v2(77.96,26.75)
  IN1 w0.089: 76.23,26.32 77.41,26.32 77.84,26.75 v2(77.96,26.75)
  IN1 w0.102: v2(127.07,53.5) 128.12,52.45 128.12,44.71 122.07,38.66 118.4,38.66 118.3,38.77 118.3,39.42 118.2,39.52 108.89,39.52 108.53,39.17 104.69,39.17 102.99,37.47 102.56,37.47 102.45,37.37 102.45,36.94 102.35,36.84 102.15,36.84 102.05,36.94 102.05,37.37 101.95,37.47 101.75,37.47 101.65,37.37 101.65,36.89 101.54,36.79 101.34,36.79 101.24,36.89 101.24,37.37 101.14,37.47 100.93,37.47 100.83,37.37 100.83,36.89 100.73,36.79 100.53,36.79 100.43,36.89 100.43,37.37 100.32,37.47 100.12,37.47 100.02,37.37 100.02,36.89 99.92,36.79 99.71,36.79 99.61,36.89 99.61,37.37 99.51,37.47 99.31,37.47 99.21,37.37 99.21,36.89 99.11,36.79 98.9,36.79 98.8,36.89 98.8,37.24 98.7,37.35 98.5,37.35 98.39,37.24 98.39,36.89 98.29,36.78 91.16,36.78 89.37,36.78 87.95,36.78 87.42,37.31 76.92,37.31 73.32,33.71 73.32,28.34 73.7,27.96 74.34,27.96 74.72,27.58 74.72,27.26 75.42,26.56 75.99,26.56 76.23,26.32
  BOTTOM w0.102: v2(127.07,53.5) 126.74,53.84 126.55,54.32 126.55,55.49 125.39,56.65 124.44,57.36 123.13,57.36 122.99,57.5 UC1.BC24
DDR_B_DQ55: length 96.9
  TOP w0.117: v2(78.8,26.57) 78.8,26.42 79.42,25.8 79.42,25.61 80.05,24.98 UD8.J7
  IN1 w0.089: 75.28,31.72 75.28,29.56
  IN1 w0.102: 75.28,29.56 76.75,28.09 78.08,28.09 78.46,27.7 78.46,26.91 v2(78.8,26.57) ; v2(128.67,54.5) 130.16,54.5 131.79,52.86 132.41,52.86 134.66,50.62 135.16,49.41 135.16,47.92 135.16,47.92 134.79,47.04 127.03,39.28 122.48,37.39 114.38,37.39 114.28,37.5 114.28,38.05 114.17,38.16 109.55,38.16 109.29,37.89 105.18,37.89 102.7,35.41 83.51,35.41 83.23,35.68 79.24,35.68 75.28,31.72
  BOTTOM w0.102: UC1.BB22 121.98,58.9 122.36,58.9 122.55,58.7 122.88,58.7 122.97,58.8 123.85,58.8 124.2,58.45 125.34,58.45 128.27,55.51 128.27,54.9 v2(128.67,54.5)
DDR_B_DQ56: length 96.6
  TOP w0.117: UD8.A3 76.85,31.08 v2(77.28,31.51)
  IN1 w0.102: v2(129.05,58.17) 129.05,57.76 130.12,56.69 130.12,56.34 132.32,54.13 132.99,54.13 135.8,51.27 136.43,49.66 136.43,47.66 135.88,46.32 127.66,38.11 113,32.04 107.13,30.87 105.12,30.87 103.91,32.09 94.01,32.09 93.9,32.19 93.9,32.49 93.8,32.59 93.6,32.59 93.5,32.49 93.5,32.19 93.4,32.09 93.19,32.09 93.09,32.19 93.09,32.49 92.99,32.59 92.79,32.59 92.69,32.49 92.69,32.19 92.58,32.09 92.42,32.09 92.32,32.19 92.32,32.52 92.22,32.62 92.02,32.62 91.92,32.52 91.92,32.19 91.81,32.09 91.61,32.09 91.51,32.19 91.51,32.52 91.41,32.62 91.2,32.62 91.1,32.52 91.1,32.19 91,32.09 90.8,32.09 90.7,32.19 90.7,32.52 90.59,32.62 90.39,32.62 90.29,32.52 90.29,32.19 90.19,32.09 90.01,32.09 89.91,32.19 89.91,32.52 89.81,32.62 89.6,32.62 89.5,32.52 89.5,32.19 89.4,32.09 89.2,32.09 89.1,32.19 89.1,32.52 89,32.62 88.79,32.62 88.69,32.52 88.69,32.19 88.59,32.09 88.39,32.09 88.28,32.19 88.28,32.52 88.18,32.62 87.98,32.62 87.88,32.52 87.88,32.19 87.78,32.09 87.57,32.09 87.47,32.19 87.47,32.52 87.37,32.62 84.33,32.62 82.54,34.41 79.97,34.41 77.28,31.72 v2(77.28,31.51)
  BOTTOM w0.102: UC1.BB21 121.94,59.94 122.3,59.94 122.54,59.7 123.04,59.7 123.14,59.6 123.58,59.6 123.68,59.71 125.4,59.71 126.68,59.2 127.51,58.37
  BOTTOM w0.117: 127.51,58.37 127.66,58.22 v3(128.5,58.22) 128.77,58.22 128.82,58.17 v2(129.05,58.17)
DDR_B_DQ57: length 96.3
  TOP w0.117: v2(81.27,30.68) 80.87,30.28 UD8.B8
  IN1 w0.089: 82.85,29.37 82.85,30.1 82.64,30.31 81.65,30.31 81.28,30.68 v2(81.27,30.68)
  IN1 w0.102: v2(128.31,59.2) 128.65,59.54 130.37,59.54 131.11,58.8 133.04,58.8 133.89,58.58 134.28,58.36 135.99,56.65 136.81,54.68 136.82,54.68 138.59,50.18 138.59,47.22 137.71,45.1 128.81,36.2 113.84,30 107.1,28.66 103.7,28.66 103.65,28.71 103.65,29.13 103.55,29.23 103.3,29.23 103.2,29.13 103.2,28.78 103.08,28.66 102.92,28.66 102.8,28.78 102.8,29.11 102.68,29.23 102.51,29.23 102.39,29.11 102.39,28.78 102.27,28.66 102.1,28.66 101.98,28.78 101.98,29.11 101.86,29.23 101.7,29.23 101.58,29.11 101.58,28.78 101.46,28.66 101.29,28.66 101.17,28.78 101.17,29.11 101.05,29.23 100.88,29.23 100.76,29.11 100.76,28.78 100.65,28.66 100.48,28.66 100.36,28.78 100.36,29.11 100.24,29.23 83.82,29.23 83.7,29.35 83.7,30.06 83.58,30.18 83.41,30.18 83.29,30.06 83.29,29.35 83.17,29.23 82.98,29.23 82.85,29.37
  BOTTOM w0.102: v2(128.31,59.2) 127.6,59.2 126.94,59.86 v3(126.63,59.95) 125.49,60.31 124.1,60.31 123.8,60.6 123.06,60.6 122.96,60.5 UC1.BC21
DDR_B_DQ58: length 97.6
  TOP w0.117: v2(77.26,29.89) 77.26,29.89 UD8.C3
  IN1 w0.089: 80.18,31.64 80.05,31.77
  IN1 w0.102: v2(132.59,57.55) 133.19,57.55 133.31,57.42 133.31,55.61 136.18,52.75 136.82,52.06 137.67,50 137.67,47.41 136.93,45.62 128.3,36.98 113.57,30.88 107.13,29.6 104.53,29.6 103.98,30.16 89.01,30.16 88.89,30.27 88.89,30.65 88.77,30.76 88.6,30.76 88.48,30.65 88.48,30.27 88.36,30.16 88.19,30.16 88.07,30.27 88.07,30.65 87.96,30.76 84.42,30.76 82.79,32.4 80.36,32.4 80.05,32.09 80.05,31.77 ; v2(77.26,29.89) 77.48,29.67 79.24,29.67 80.18,30.61 80.18,31.64
  BOTTOM w0.102: UC1.BA18 121.85,62.5 122.15,62.2 122.45,62.2 122.55,62.3 123.04,62.3 123.14,62.4 123.57,62.4 123.66,62.31 v3(127.55,62.31) 127.68,62.31 129.01,60.98 129.07,60.98
  BOTTOM w0.117: v2(132.59,57.55) 132.59,57.89 131.29,59.19 131.29,59.23 129.54,60.98 129.07,60.98
DDR_B_DQ59: length 97.4
  TOP w0.117: v2(80.46,29.89) 80.46,29.89 UD8.C7
  IN1 w0.102: v2(80.46,29.89) 80.75,30.18 80.75,30.97 80.9,31.12 83.2,31.12 84,30.32 84,29.72 84.2,29.53 84.42,29.53 84.54,29.65 84.54,30.04 84.66,30.16 84.83,30.16 84.95,30.04 84.95,29.65 85.07,29.53 85.24,29.53 85.36,29.65 85.36,30.04 85.47,30.16 85.64,30.16 85.76,30.04 85.76,29.65 85.88,29.53 86.05,29.53 86.17,29.65 86.17,30.04 86.29,30.16 86.46,30.16 86.57,30.04 86.57,29.65 86.69,29.53 86.86,29.53 86.98,29.65 86.98,30.04 87.1,30.16 87.27,30.16 87.39,30.04 87.39,29.65 87.51,29.53 103.74,29.53 104.3,28.96 107.07,28.96 113.75,30.29 128.64,36.46 137.45,45.27 138.28,47.28 138.28,50.12 136.56,54.51 135.74,56.48 134.12,58.09 133.71,58.26 133.15,58.26 132.88,57.99 132.35,57.99 132.02,58.32 v2(131.27,58.32)
  BOTTOM w0.102: UC1.BB19 122.2,62 122.5,61.7 122.99,61.7 123.06,61.63 123.63,61.63 124,61.99 v3(126.15,61.99) 127.68,61.99 129.07,60.61
  BOTTOM w0.117: v2(131.27,58.32) 130.85,58.74 130.85,59.15 129.4,60.6 129.07,60.6 129.07,60.61
DDR_B_DQ60: length 97.2
  TOP w0.117: v2(76.46,29.9) 76.05,29.48 UD8.C2
  IN1 w0.102: v2(76.46,29.9) 76.85,30.28 77.92,30.28 78.05,30.41 78.05,31.99 80.17,34.11 82.41,34.11 84.77,31.76 84.97,31.76 85.07,31.86 85.07,32.21 85.17,32.31 85.37,32.31 85.47,32.21 85.47,31.86 85.58,31.76 85.78,31.76 85.88,31.86 85.88,32.21 85.98,32.31 86.19,32.31 86.29,32.21 86.29,31.86 86.39,31.76 86.59,31.76 86.69,31.86 86.69,32.21 86.79,32.31 87,32.31 87.1,32.21 87.1,31.86 87.2,31.76 103.81,31.76 104.99,30.57 107.16,30.57 113.09,31.75 127.83,37.85 136.13,46.15 136.73,47.59 136.73,49.81 136.02,51.53 133.12,54.44 132.45,54.44 130.42,56.47 130.42,58.76 130.3,58.88 v2(128.97,58.88)
  BOTTOM w0.102: UC1.BA21 121.85,60.5 122.15,60.2 122.45,60.2 122.55,60.3 123.04,60.3 123.14,60.4 123.66,60.4 124.06,60.01 125.37,60.01 126.8,59.53 v3(127.42,58.91) 127.57,58.76 128.85,58.76 128.96,58.87
  BOTTOM w0.117: v2(128.97,58.88) 128.96,58.87
DDR_B_DQ61: length 97.3
  TOP w0.117: v2(81.27,29.9) 80.85,29.48 UD8.C8
  IN1 w0.102: v2(81.27,29.9) 81.64,29.52 82.3,29.52 82.9,28.92 94.77,28.92 94.86,28.83 94.86,28.49 94.99,28.35 95.22,28.35 95.34,28.47 95.34,28.8 95.46,28.92 95.63,28.92 95.75,28.8 95.75,28.47 95.87,28.35 96.03,28.35 96.15,28.47 96.15,28.8 96.27,28.92 96.44,28.92 96.56,28.8 96.56,28.47 96.68,28.35 96.85,28.35 96.97,28.47 96.97,28.8 97.08,28.92 97.25,28.92 97.37,28.8 97.37,28.47 97.49,28.35 97.66,28.35 97.78,28.47 97.78,28.8 97.9,28.92 98.07,28.92 98.18,28.8 98.18,28.47 98.3,28.35 98.53,28.35 98.65,28.47 98.65,28.8 98.77,28.92 98.94,28.92 99.06,28.8 99.06,28.47 99.18,28.35 99.41,28.35 99.53,28.47 99.53,28.8 99.64,28.92 99.81,28.92 99.93,28.8 99.93,28.47 100.05,28.35 107.13,28.35 113.92,29.71 128.99,35.95 137.97,44.93 138.89,47.16 138.89,50.37 136.28,56.82 134.48,58.62 133.91,58.95 132.75,59.27 132.61,59.41 v2(131.84,59.41)
  BOTTOM w0.102: 129.07,61.42 v3(129.01,61.42) 128.88,61.42 127.7,62.6 127.43,62.6 127.42,62.6 123.06,62.6 122.96,62.5 UC1.BC18
  BOTTOM w0.117: 129.07,61.42 129.62,61.42 131.64,59.41 v2(131.84,59.41)
DDR_B_DQ62: length 97.7
  TOP w0.117: v2(77.26,29.09) 77.26,29.09 UD8.D3
  IN1 w0.102: v2(133.43,57.88) 133.81,57.88 133.87,57.82 133.9,57.82 135.03,56.69 135.03,54.32 136.62,52.73 137.07,52.26 137.98,50.06 137.98,47.34 137.19,45.45 128.47,36.72 113.66,30.59 107.04,29.27 104.43,29.27 103.86,29.84 87.88,29.84 87.75,29.97 87.75,30.34 87.63,30.46 84.3,30.46 82.66,32.09 80.64,32.09 80.43,31.88 80.43,30.43 79.42,29.42 77.98,29.42 77.31,29.14 v2(77.26,29.09)
  BOTTOM w0.102: 129.07,61.79 128.89,61.79 127.79,62.9 123.07,62.9 122.88,62.7 122.55,62.7 122.25,63 UC1.BB18
  BOTTOM w0.117: v2(133.43,57.88) 133.43,58.58 132.02,59.99 v3(131.58,59.99) 129.78,61.79 129.07,61.79
DDR_B_DQ63: length 96.5
  TOP w0.117: UD8.D7 80.46,29.09 v2(80.46,29.09)
  IN1 w0.102: v2(80.46,29.09) 81.38,29.09 81.38,29.1 81.52,29.1 82,28.62 89.45,28.62 89.57,28.5 89.57,28.17 89.69,28.05 89.86,28.05 89.98,28.17 89.98,28.5 90.1,28.62 90.33,28.62 90.45,28.5 90.45,28.17 90.56,28.05 90.73,28.05 90.85,28.17 90.85,28.5 90.97,28.62 91.14,28.62 91.26,28.5 91.26,28.17 91.38,28.05 91.55,28.05 91.66,28.17 91.66,28.5 91.78,28.62 91.95,28.62 92.07,28.5 92.07,28.17 92.19,28.05 92.36,28.05 92.48,28.17 92.48,28.5 92.6,28.62 94.3,28.62 94.87,28.05 107.16,28.05 114.01,29.41 129.18,35.69 138.22,44.74 139.21,47.12 139.2,50.43 136.55,56.98 134.59,58.94 134.1,59.23 131.95,59.9 128.67,59.9 128.12,59.67 127.8,59.67 126.65,60.15 v2(126.28,60.51)
  BOTTOM w0.102: v2(126.28,60.51) 125.61,60.61 124.23,60.61 124.03,60.8 122.97,60.8 122.88,60.7 122.55,60.7 122.4,60.85 122.02,60.85 UC1.BB20
DDR_B_DQS0: length 83.9
  TOP w0.102: UD5.G3 v2(39.63,28.68)
  IN2 w0.089: v2(39.63,28.68) 39.95,29.01 39.95,29.11 39.7,29.36 39.7,29.95 39.68,29.98 39.68,30
  IN2 w0.135: 39.68,30 36.98,32.7 36.98,35.87 51.78,50.67 56.02,50.67 57.09,51.75 66.04,51.75 66.13,51.66 67.32,51.66 67.54,51.88 67.54,52.95 67.8,53.22 68.39,53.22 68.66,52.95 68.66,51.88 68.79,51.75 69.19,51.75 69.33,51.88 69.33,52.95 69.59,53.22 70.18,53.22 70.45,52.95 70.45,51.88 70.58,51.75 70.99,51.75 71.12,51.88 71.12,52.95 71.39,53.22 71.98,53.22 72.24,52.95 72.24,51.88 72.38,51.75 74.69,51.75 78.65,55.71 83.44,55.71 85.13,54.02 85.13,53.49 86.1,52.51 87.06,52.51 87.41,52.87 88.36,52.87 88.63,52.6 v2(89.08,52.6)
  BOTTOM w0.102: v2(89.08,52.6) 88.92,52.44 88.78,52.44 88.43,52.79 88.43,52.94 89.47,53.98 91.02,53.98 91.1,53.89 91.41,53.89 91.58,54.06 91.72,54.06 UC1.E29
DDR_B_DQS0#: length 83.7
  TOP w0.102: UD5.F3 40.07,29.08 v2(40.46,28.69)
  IN2 w0.089: 39.9,30 39.9,29.98 39.88,29.95 39.88,29.43 40.13,29.18 40.13,29.02 v2(40.46,28.69)
  IN2 w0.135: 39.9,30 39.9,30.09 37.2,32.79 37.2,35.78 51.88,50.45 56.11,50.45 57.19,51.52 65.95,51.52 66.03,51.44 67.41,51.44 67.76,51.79 67.76,52.86 67.89,52.99 68.3,52.99 68.43,52.86 68.43,51.79 68.7,51.52 69.29,51.52 69.55,51.79 69.55,52.86 69.69,52.99 70.09,52.99 70.22,52.86 70.22,51.79 70.49,51.52 71.08,51.52 71.35,51.79 71.35,52.86 71.48,52.99 71.88,52.99 72.02,52.86 72.02,51.79 72.28,51.52 74.78,51.52 78.75,55.48 83.35,55.48 84.91,53.92 84.91,53.37 86,52.28 87.16,52.28 87.51,52.63 88.27,52.63 88.47,52.42 v2(88.47,52)
  BOTTOM w0.102: v2(88.47,52) 88.63,52.16 88.63,52.32 88.24,52.71 88.24,53.02 89.39,54.17 91.09,54.17 91.18,54.09 91.33,54.09 91.44,54.19 91.44,54.33 UC1.D28
DDR_B_DQS1: length 69.3
  TOP w0.102: v2(42.66,32.78) 43.17,32.28 UD5.B7
  IN2 w0.135: v2(91.57,46.6) 91.31,46.87 89.83,46.87 89.49,46.53 89.49,45.94 89.12,45.58 83.45,45.58 82.49,44.62 53.7,44.62 53.39,44.31 53.02,44.31 52.6,44.73 52.42,44.73 52.15,44.47 52.15,44.28 52.6,43.84 52.6,43.47 52.18,43.05 51.8,43.05 51.36,43.49 51.17,43.49 50.89,43.2 50.89,43.01 51.33,42.57 51.33,42.2 50.91,41.78 50.53,41.78 50.09,42.22 49.9,42.22 43.39,35.71 43.39,35.42 42.83,34.86 42.83,34.59 43.39,34.02 43.39,33.36 43.13,33.1 42.8,33.1 42.66,32.96 v2(42.66,32.78)
  BOTTOM w0.102: v2(91.57,46.6) 91.57,46.83 92.25,47.51 92.25,47.78 94.46,49.99 94.46,51.34 94.78,51.65 94.78,52.32 94.87,52.42 UC1.J31
DDR_B_DQS1#: length 69.5
  TOP w0.102: UD5.A7 42.69,33.62 v2(42.69,33.63)
  IN2 w0.135: v2(91.57,47.4) 91.28,47.1 89.73,47.1 89.25,46.62 89.25,46.02 89.03,45.8 83.35,45.8 82.4,44.85 53.61,44.85 53.29,44.53 53.11,44.53 52.69,44.96 52.32,44.96 51.93,44.57 51.93,44.19 52.37,43.75 52.37,43.56 52.09,43.27 51.9,43.27 51.45,43.71 51.08,43.71 50.66,43.3 50.66,42.92 51.1,42.48 51.1,42.29 50.82,42 50.63,42 50.19,42.44 49.81,42.44 43.17,35.8 43.17,35.51 42.6,34.95 42.6,34.5 43.17,33.93 43.17,33.45 43.04,33.32 42.82,33.32 42.69,33.45 v2(42.69,33.63)
  BOTTOM w0.102: UC1.J29 94.57,53.18 94.57,52.92 94.68,52.81 94.68,52.5 94.58,52.4 94.58,51.73 94.27,51.42 94.27,50.07 92.06,47.86 92.06,47.59 91.87,47.4 v2(91.57,47.4)
DDR_B_DQS2: length 71.6
  TOP w0.089: UD6.G3 51.34,28.28 v2(51.75,28.68)
  IN2 w0.102: v2(97.39,47.64) 97.18,47.85 96.99,47.85 96.88,47.74 96.88,46.65 96.52,46.29 96.52,46.28 96.5,46.26
  IN2 w0.135: 96.5,46.26 95.9,45.66 95.9,45.4 95.9,44.76 95.9,44.12 94.53,42.75 94.25,42.75 94.12,42.63 94.12,42.36 93.86,42.1 93.37,42.1 93.11,42.36 93.11,42.66 92.98,42.79 92.7,42.79 92.56,42.65 92.56,42.19 92.19,41.83 85,41.83 84.11,40.94 55.35,40.94 48.63,34.22 48.63,31.1 49.39,30.34 50.34,30.34 51.46,29.23 51.46,28.97 v2(51.75,28.68)
  BOTTOM w0.102: v2(97.39,47.64) 97.5,47.76 97.78,47.76 98.03,48.01 98.03,51.26 98.17,51.4 98.17,52.4 98.07,52.5 98.07,52.78 UC1.N30
DDR_B_DQS2#: length 71.4
  TOP w0.089: UD6.F3 v2(50.94,28.68)
  IN2 w0.102: v2(97.39,48.25) 97.18,48.05 96.9,48.05 96.68,47.82 96.68,46.74 96.37,46.44 96.36,46.44 96.34,46.42
  IN2 w0.135: 96.34,46.42 95.67,45.75 95.67,45.08 95.67,44.76 95.67,44.21 94.43,42.98 94.15,42.98 93.89,42.72 93.89,42.45 93.77,42.32 93.46,42.32 93.33,42.45 93.33,42.75 93.07,43.01 92.6,43.01 92.34,42.74 92.34,42.29 92.1,42.05 84.91,42.05 84.02,41.16 55.26,41.16 48.41,34.31 48.41,31.01 49.3,30.12 50.25,30.12 51.23,29.14 51.23,28.81 51.11,28.68 v2(50.94,28.68)
  BOTTOM w0.102: UC1.M31 97.87,52.55 97.87,52.42 97.97,52.32 97.97,51.47 97.84,51.34 97.84,48.09 97.72,47.96 97.57,47.96 97.39,48.15 v2(97.39,48.25)
DDR_B_DQS3: length 68.7
  TOP w0.102: v2(53.84,32.63) 54.19,32.28 UD6.B7
  IN2 w0.102: 102.68,46.26 102.66,46.28 102.66,46.35 102.66,46.35 102.66,50.65 102.2,51.11 101.46,51.11 v2(101.37,51.2)
  IN2 w0.135: v2(53.84,32.63) 54.13,32.92 54.13,33.04 54.48,33.38 54.48,33.96 56.64,36.12 72.87,36.12 73.14,36.39 73.14,36.71 73.27,36.84 73.68,36.84 73.81,36.71 73.81,36.39 74.08,36.12 74.66,36.12 74.93,36.39 74.93,36.71 75.06,36.84 75.47,36.84 75.6,36.71 75.6,36.39 75.87,36.12 76.46,36.12 76.72,36.39 76.72,36.71 76.86,36.84 77.26,36.84 77.4,36.71 77.4,36.39 77.66,36.12 78.25,36.12 78.52,36.39 78.52,36.71 78.65,36.84 85.73,36.84 86.66,37.77 95.7,37.77 102.68,44.75 102.68,46.26
  BOTTOM w0.102: UC1.T30 101.32,53.5 101.17,53.36 101.17,52.93 101.07,52.82 101.07,52.34 100.97,52.24 100.97,51.21 101.12,51.06 101.23,51.06 101.31,51.14 v2(101.37,51.2)
DDR_B_DQS3#: length 68.5
  TOP w0.102: UD6.A7 54.19,33.08 v2(53.84,33.43)
  IN2 w0.102: 102.46,46.26 102.46,50.57 102.12,50.91 101.78,50.91 101.72,50.86 101.55,50.86 101.37,50.68 v2(101.37,50.4)
  IN2 w0.135: 102.46,46.26 102.46,44.85 95.6,37.99 86.56,37.99 85.64,37.06 78.56,37.06 78.29,36.8 78.29,36.48 78.16,36.35 77.75,36.35 77.62,36.48 77.62,36.8 77.35,37.06 76.77,37.06 76.5,36.8 76.5,36.48 76.37,36.35 75.96,36.35 75.83,36.48 75.83,36.8 75.56,37.06 74.97,37.06 74.71,36.8 74.71,36.48 74.57,36.35 74.17,36.35 74.03,36.48 74.03,36.8 73.77,37.06 73.18,37.06 72.91,36.8 72.91,36.48 72.78,36.35 56.54,36.35 54.25,34.05 54.25,33.48 54.12,33.34 53.93,33.34 v2(53.84,33.43)
  BOTTOM w0.102: UC1.T31 100.88,52.42 100.78,52.32 100.78,51.13 101.07,50.83 101.49,50.83 101.64,50.68 101.64,50.53 101.51,50.4 v2(101.37,50.4)
DDR_B_DQS4: length 88
  TOP w0.102: UD7.G3 v2(63.27,28.68)
  IN1 w0.122: v2(63.27,28.68) 63.14,28.68 62.4,29.42 62.27,29.42 61.85,29.84 60.91,29.84 60.09,30.66 60.09,33.94 70.66,44.51 87.28,44.51 87.67,44.13 89.9,44.13 90.45,43.57 94.86,43.57 95.53,44.24 95.54,44.24 97.16,45.86 103.67,45.86 105.59,47.78 107.42,47.78 107.54,47.9 107.54,49.51 107.79,49.76 108.26,49.76 108.51,49.51 108.51,49.19 108.63,49.07 109,49.07 109.12,49.19 109.12,49.51 109.37,49.76 109.98,49.76 110.23,49.51 110.23,49.3 110.35,49.17 110.72,49.17 110.84,49.3 110.84,49.54 111.09,49.79 111.65,49.79 111.9,49.54 111.9,49.3 112.02,49.17 112.39,49.17 112.51,49.3 112.51,49.56 112.76,49.81 113.31,49.81 113.56,49.56 113.56,48.41 113.69,48.29 114.05,48.29 114.17,48.41 114.17,49.59 114.42,49.84 114.98,49.84 115.23,49.59 115.23,48.43 115.35,48.31 117.53,48.31 117.92,48.7 117.92,50.76 118.24,51.08 119.26,51.08 v2(119.37,51.2)
  BOTTOM w0.102: v2(119.37,51.2) 119.37,51.04 119.26,50.92 119.08,50.92 118.97,51.03 118.97,51.05 118.96,51.06 118.96,52.28 119.08,52.39 119.08,52.85 119.18,52.95 119.18,53.18 UC1.AU29
DDR_B_DQS4#: length 87.8
  TOP w0.102: UD7.F3 v2(64.07,28.68)
  IN1 w0.122: v2(64.07,28.68) 63.7,29.06 63.06,29.06 62.49,29.63 62.36,29.63 61.93,30.05 61,30.05 60.3,30.75 60.3,33.86 70.74,44.3 87.19,44.3 87.58,43.91 89.81,43.91 90.37,43.36 94.95,43.36 95.62,44.03 95.63,44.03 97.24,45.65 103.78,45.65 105.69,47.56 107.51,47.56 107.76,47.81 107.76,49.42 107.88,49.54 108.17,49.54 108.29,49.42 108.29,49.1 108.54,48.85 109.1,48.85 109.35,49.1 109.35,49.42 109.47,49.54 109.89,49.54 110.01,49.42 110.01,49.2 110.26,48.95 110.81,48.95 111.06,49.2 111.06,49.45 111.18,49.57 111.55,49.57 111.67,49.45 111.67,49.2 111.93,48.95 112.48,48.95 112.73,49.2 112.73,49.47 112.85,49.59 113.22,49.59 113.34,49.47 113.34,48.31 113.59,48.06 114.14,48.06 114.4,48.31 114.4,49.5 114.52,49.62 114.88,49.62 115,49.5 115,48.34 115.25,48.09 117.62,48.09 118.14,48.61 118.14,50.67 118.33,50.86 119.13,50.86 119.37,50.61 v2(119.37,50.38)
  BOTTOM w0.102: UC1.AU31 118.88,52.46 118.77,52.36 118.77,50.98 118.78,50.97 118.78,50.95 119,50.73 119.02,50.73 v2(119.37,50.38)
DDR_B_DQS5: length 80.3
  TOP w0.102: v2(66.39,32.68) UD7.B7
  IN1 w0.122: v2(66.39,32.68) 66.53,32.82 66.88,32.82 67.13,33.07 67.13,34.16 73.17,40.19 88.58,40.19 89.08,39.69 96.8,39.69 99.18,42.07 106.72,42.07 107.73,43.08 108.29,43.08 108.41,42.96 108.41,42.69 108.65,42.45 109.19,42.45 109.44,42.69 109.44,43.46 109.57,43.59 109.92,43.59 110.05,43.46 110.05,42.69 110.3,42.45 110.84,42.45 111.08,42.69 111.08,42.96 111.2,43.08 122.23,43.08 124.5,45.35 124.5,48.64 123.98,49.17 123.98,51.59 123.72,51.85 123.3,51.85 123.18,51.97 v2(123.18,52)
  BOTTOM w0.102: v2(123.18,52) 123.33,51.85 123.49,51.85 123.6,51.96 123.6,53.12 122.73,53.98 122.46,53.98 121.67,54.77 121.67,54.77 121.59,54.85 121.47,55.13 UC1.BA27
DDR_B_DQS5#: length 80.2
  TOP w0.102: UD7.A7 v2(66.39,33.48)
  IN1 w0.122: v2(123.2,51.2) 123.14,51.26 123.14,51.49 123.28,51.62 123.63,51.62 123.75,51.5 123.75,49.08 124.29,48.54 124.29,45.43 122.15,43.29 111.12,43.29 110.87,43.04 110.87,42.78 110.75,42.66 110.38,42.66 110.26,42.78 110.26,43.55 110.01,43.8 109.48,43.8 109.23,43.55 109.23,42.78 109.11,42.66 108.74,42.66 108.62,42.78 108.62,43.04 108.37,43.29 107.64,43.29 106.64,42.28 99.09,42.28 96.71,39.9 89.17,39.9 88.67,40.4 73.08,40.4 66.92,34.24 66.92,33.16 66.8,33.03 66.52,33.03 66.39,33.17 v2(66.39,33.48)
  BOTTOM w0.102: UC1.BB27 121.88,54.83 122.54,54.17 122.81,54.17 123.79,53.2 123.79,51.88 123.53,51.62 123.27,51.62 123.2,51.55 123.2,51.2 v2(123.2,51.2)
DDR_B_DQS6: length 97.1
  TOP w0.119: UD8.G3 76.86,26.28 v2(77.26,26.68)
  IN1 w0.122: v2(128.67,52.9) 128.7,52.9 128.93,52.67 129.14,52.67 129.42,52.39 129.42,50.87 129.33,50.64 128.78,49.81 128.78,44.55 122.31,38.08 117.87,38.08 117.62,38.33 117.62,38.82 117.5,38.95 117.13,38.95 117.01,38.82 117.01,38.33 116.77,38.08 116.22,38.08 115.98,38.33 115.98,38.82 115.86,38.95 109.39,38.95 109.01,38.56 104.9,38.56 102.54,36.2 87.71,36.2 87.2,36.72 86.39,36.72 86.26,36.6 86.26,36.6 86.02,36.35 85.48,36.35 85.23,36.6 85.23,36.6 85.11,36.72 84.74,36.72 84.62,36.6 84.62,36.6 84.38,36.35 83.84,36.35 83.59,36.6 83.59,36.6 83.47,36.72 83.1,36.72 82.79,36.4 82.15,36.4 81.83,36.72 81.46,36.72 81.2,36.45 80.45,36.45 80.19,36.72 79.28,36.72 78.78,36.23 78.43,36.23 77.94,36.72 77.76,36.72 77.47,36.44 77.47,36.26 77.94,35.79 77.94,35.44 77.56,35.06 77.21,35.06 76.52,35.76 76.31,35.76 76.07,35.52 76.07,35.34 76.78,34.63 76.78,34.28 76.4,33.9 76.05,33.9 75.38,34.57 75.2,34.57 73.96,33.33 73.96,29.23 74.13,29.06 74.7,29.06 75.23,28.53 75.23,27.37 75.51,27.08 76.85,27.08 v2(77.26,26.68)
  BOTTOM w0.102: UC1.BC23 122.43,58.5 122.44,58.5 122.96,58.5 123.05,58.6 123.63,58.6 124.13,58.1 125.16,58.1 127.8,55.45 127.8,52.83 128.01,52.62 128.4,52.62 v2(128.67,52.9)
DDR_B_DQS6#: length 97.1
  TOP w0.119: UD8.F3 76.85,27.08 v2(76.45,26.68)
  IN1 w0.122: v2(128.67,52.19) 128.95,52.46 129.05,52.46 129.21,52.3 129.21,50.91 129.14,50.74 128.57,49.88 128.57,44.64 122.22,38.29 117.95,38.29 117.83,38.41 117.83,38.91 117.59,39.16 117.05,39.16 116.8,38.91 116.8,38.41 116.68,38.29 116.31,38.29 116.19,38.41 116.19,38.91 115.94,39.16 109.3,39.16 108.92,38.77 104.81,38.77 102.45,36.42 87.8,36.42 87.28,36.93 86.3,36.93 86.05,36.69 85.93,36.56 85.56,36.56 85.44,36.69 85.2,36.93 84.66,36.93 84.41,36.69 84.29,36.56 83.92,36.56 83.8,36.69 83.56,36.93 83.02,36.93 82.7,36.61 82.23,36.61 81.92,36.93 81.38,36.93 81.11,36.67 80.54,36.67 80.28,36.93 79.19,36.93 78.69,36.44 78.51,36.44 78.02,36.93 77.67,36.93 77.26,36.52 77.26,36.17 77.73,35.7 77.73,35.53 77.47,35.27 77.3,35.27 76.6,35.97 76.22,35.97 75.85,35.6 75.85,35.26 76.57,34.54 76.57,34.37 76.31,34.11 76.14,34.11 75.46,34.78 75.11,34.78 73.74,33.42 73.74,29.14 74.04,28.85 74.61,28.85 75.01,28.44 75.01,27.28 75.42,26.87 76.26,26.87 v2(76.45,26.68)
  BOTTOM w0.102: UC1.BA23 122.2,58.2 122.42,58.2 122.53,58.31 123.04,58.31 123.13,58.41 123.55,58.41 124.05,57.91 125.08,57.91 127.61,55.37 127.61,52.75 127.93,52.43 128.43,52.43 v2(128.67,52.19)
DDR_B_DQS7: length 97.7
  TOP w0.089: UD8.B7 80.05,30.41 79.9,30.56 79.37,30.56 79.18,30.38 v2(79.18,30.2)
  IN1 w0.122: v2(79.18,30.2) 79.44,30.5 79.64,30.52 79.88,30.76 79.88,31.41 79.69,31.61 79.69,32.29 80.16,32.76 82.94,32.76 84.57,31.13 90.14,31.13 90.26,31.01 90.26,30.81 90.51,30.56 91.05,30.56 91.3,30.81 91.3,31.01 91.42,31.13 91.78,31.13 91.91,31.01 91.91,30.81 92.15,30.56 92.69,30.56 92.94,30.81 92.94,31.01 93.06,31.13 93.42,31.13 93.55,31.01 93.55,30.81 93.79,30.56 94.33,30.56 94.58,30.81 94.58,31.01 94.7,31.13 95.07,31.13 95.19,31.01 95.19,30.81 95.43,30.56 95.97,30.56 96.22,30.81 96.22,31.01 96.34,31.13 96.75,31.13 96.87,31.01 96.87,30.78 97.12,30.54 97.66,30.54 97.9,30.78 97.9,31.01 98.02,31.13 103.52,31.13 104.68,29.96 107.1,29.96 113.34,31.21 128.13,37.33 136.62,45.83 137.31,47.48 137.31,49.93 136.51,51.86 133.35,55.02 132.7,55.02 132.32,55.41 132.32,55.57 132.9,56.16 132.9,56.46 132.92,56.47 132.92,56.48 132.92,56.48 132.92,56.65 132.65,56.91 132.13,56.91 v2(131.88,57.16)
  BOTTOM w0.102: UC1.BC20 122.29,61.49 122.89,61.49 122.97,61.41 123.81,61.41 123.94,61.54 127.73,61.54 129.02,60.25 129.04,60.25 129.07,60.23
  BOTTOM w0.119: v2(131.88,57.16) 131.65,56.93 131.64,56.93 131.6,56.88 131.29,56.88 130.27,57.91 130.27,59.03 129.07,60.23
DDR_B_DQS7#: length 98.1
  TOP w0.089: UD8.A7 80.05,30.87 79.93,30.74 79.36,30.74 v2(79.13,30.97)
  IN1 w0.122: v2(79.13,30.97) 79.38,30.72 79.55,30.72 79.67,30.84 79.67,31.32 79.48,31.52 79.48,32.37 80.08,32.97 83.03,32.97 84.66,31.34 90.23,31.34 90.48,31.1 90.48,30.89 90.6,30.77 90.96,30.77 91.09,30.89 91.09,31.1 91.33,31.34 91.87,31.34 92.12,31.1 92.12,30.89 92.24,30.77 92.6,30.77 92.73,30.89 92.73,31.1 92.97,31.34 93.51,31.34 93.76,31.1 93.76,30.89 93.88,30.77 94.25,30.77 94.37,30.89 94.37,31.1 94.61,31.34 95.15,31.34 95.4,31.1 95.4,30.89 95.52,30.77 95.89,30.77 96.01,30.89 96.01,31.1 96.25,31.34 96.84,31.34 97.08,31.1 97.08,30.87 97.2,30.75 97.57,30.75 97.69,30.87 97.69,31.1 97.94,31.34 103.6,31.34 104.77,30.18 107.07,30.18 113.28,31.41 128.01,37.51 136.44,45.94 137.1,47.52 137.1,49.89 136.33,51.74 133.26,54.81 132.61,54.81 132.11,55.32 132.11,55.65 132.69,56.24 132.69,56.56 132.56,56.69 132.18,56.69 v2(131.86,56.36)
  BOTTOM w0.102: UC1.BA20 121.82,61.5 122.15,61.17 122.4,61.17 122.53,61.3 122.82,61.3 122.89,61.22 123.89,61.22 124.01,61.35 127.66,61.35 128.9,60.1 128.9,60.1 128.92,60.08
  BOTTOM w0.119: v2(131.86,56.36) 131.55,56.67 131.21,56.67 130.06,57.82 130.06,58.94 128.92,60.08
DDR_B_EVENT#: length 8.5
  BOTTOM w0.102: UC1.AL30 113.26,53.39 113.26,53.04 112.94,52.72 112.94,51.58 113.52,51.01 113.52,47.26 v3(113.2,46.94) 112.69,46.44 112.69,46.26
  BOTTOM w0.117: RC1.2 112.69,46.26
DDR_B_MA0: length 133.4
  TOP w0.107: v2(65.28,21.52) 64.8,22 64.69,22 64.01,22.68 UD7.P3 ; v2(52.94,21.52) 52.47,22 52.36,22 51.68,22.68 UD6.P3 ; UD5.P3 40.37,22.68 41.04,22 41.15,22 v2(41.63,21.52) ; v2(78.45,19.52) 77.97,20 77.87,20 77.19,20.68 UD8.P3
  TOP w0.188: RD56.2 v2(32.66,23.45)
  IN2 w0.198: v2(84.15,18.69) 84.03,18.81 79.54,18.81 79.35,19 78.78,19 78.45,19.33 v2(78.45,19.52)
  IN3 w0.091: v2(52.94,21.52) 53.33,21.91
  IN3 w0.099: 53.33,21.91 54.04,21.91 ; 42.77,21.84 42.41,21.84 42.35,21.9 42.03,21.9 41.96,21.84 41.94,21.84 v2(41.63,21.52) ; 66.7,21.91 65.66,21.91 v2(65.28,21.52)
  IN3 w0.127: 42.77,21.84 49.79,21.84 50.04,22.09 50.27,22.09 50.39,21.97 50.39,21.47 50.52,21.34 50.77,21.34 50.9,21.47 50.9,21.97 51.03,22.09 51.28,22.09 51.41,21.97 51.41,21.49 51.54,21.37 51.79,21.37 51.92,21.49 51.92,21.97 52.04,22.09 52.37,22.09 v2(52.94,21.52) ; v2(78.45,19.52) 78.06,19.92 76.27,19.92 75.58,19.69 73.36,19.69 69.35,22.03 66.82,22.03 66.7,21.91 ; 54.04,21.91 54.06,21.92 56.75,21.92 57.18,21.5 59.81,21.5 59.98,21.67 59.98,21.82 60.11,21.95 60.36,21.95 60.49,21.82 60.49,21.62 60.62,21.5 60.87,21.5 61,21.62 61,21.82 61.13,21.95 61.38,21.95 61.51,21.82 61.51,21.62 61.63,21.5 63.77,21.5 64.19,21.92 64.88,21.92 v2(65.28,21.52) ; v2(41.63,21.52) 41.1,22.05 39.2,22.05 38.31,22.94 37.49,22.94 37.11,23.32 34.76,23.32 34.2,23.88 33.09,23.88 v2(32.66,23.45)
  BOTTOM w0.102: UC1.AM29 113.88,53.54 113.52,53.18 113.52,53.02 113.74,52.79 113.74,46.92 113.45,46.63 113.45,46.26
  BOTTOM w0.188: 113.45,46.26 113.45,43.9 108.16,38.6 105.28,38.6 102.04,35.36 102.04,29.28 101.63,28.87 98.97,28.87 98.78,28.68 98.78,27.04 98.59,26.85 98.22,26.85 98.03,27.04 98.03,28.68 97.84,28.87 97.47,28.87 97.28,28.68 97.28,27.04 97.09,26.85 96.71,26.85 96.53,27.04 96.53,28.68 96.34,28.87 95.96,28.87 95.77,28.68 95.77,27.04 95.59,26.85 95.21,26.85 95.02,27.04 95.02,28.68 94.83,28.87 94.44,28.87 94.25,28.68 94.25,28.26 94.06,28.07 93.28,28.07 91.02,25.82 91.02,24.61 89.91,23.5 89.33,23.5 86.81,20.98 86.26,20.98 84.15,18.87 v2(84.15,18.69)
DDR_B_MA1: length 130
  TOP w0.107: UD5.P7 42.33,22.68 v2(42.19,22.54) ; v2(65.84,22.54) 65.98,22.68 UD7.P7 ; UD8.P7 79.15,20.68 v2(79.01,20.54) ; UD6.P7 53.64,22.68 v2(53.5,22.54)
  TOP w0.188: RD57.2 v2(32.66,24.21)
  IN1 w0.102: v2(79.01,20.54) 79.01,20.54 78.62,20.92 77.23,20.92 75.94,20.54 72.51,20.54 70.51,22.54 v2(65.84,22.54) 65.44,22.93 64.55,22.93 64.32,22.7 63.29,21.67 60.8,21.67 60.44,22.03 54.81,22.03 54.71,21.92 54.71,21.6 54.61,21.49 54.41,21.49 54.31,21.6 54.31,21.92 54.2,22.03 54.02,22.03 v2(53.5,22.54) 53.1,22.94 52.23,22.94 52.22,22.93 51.91,22.93 51.22,22.24 45.88,22.24 45.78,22.34 45.78,22.66 45.68,22.76 45.48,22.76 45.37,22.66 45.37,22.34 45.27,22.24 45.07,22.24 44.97,22.34 44.97,22.66 44.87,22.76 44.66,22.76 44.56,22.66 44.56,22.34 44.46,22.24 44.26,22.24 44.15,22.34 44.15,22.66 44.05,22.76 43.85,22.76 43.75,22.66 43.75,22.45 43.58,22.28 42.45,22.28 v2(42.19,22.54) 41.78,22.94 40.47,22.94 40.16,22.62 38.69,22.62 38.38,22.94 36.47,22.94 35.96,23.45 34.82,23.45 34.41,23.86 33.02,23.86 v2(32.66,24.21)
  IN2 w0.089: v2(79.01,20.54) 79.01,20.67 79.14,20.8 79.67,20.8
  IN2 w0.198: 79.67,20.8 82.53,20.8 82.62,20.88 83.74,20.88 85.98,23.12 86.77,23.12 87.82,24.18 87.82,24.97 88.76,25.91 v2(89.12,25.91)
  BOTTOM w0.091: UC1.AH31 110.88,49.29
  BOTTOM w0.102: 110.88,49.29 109.39,47.81 109.39,46.26
  BOTTOM w0.188: 109.39,46.26 v3(109.39,45.23) 109.39,43.48 105.84,39.93 104.84,39.93 104.42,39.51 104.2,39.51 103.46,40.25 103.17,40.25 102.89,39.97 102.89,39.72 103.63,38.98 103.63,38.71 103.36,38.45 103.09,38.45 102.38,39.16 102.11,39.16 101.85,38.89 101.85,38.63 102.56,37.91 102.56,37.65 102.3,37.38 102.03,37.38 101.31,38.1 101.05,38.1 100.78,37.83 100.78,37.56 101.5,36.85 101.5,36.58 101.32,36.4 100.95,36.4 100.79,36.24 100.79,33.11 100.61,32.93 100.18,32.93 99.99,33.12 99.99,36.4 99.86,36.53 99.43,36.53 99.24,36.34 99.24,33.12 99.05,32.93 98.67,32.93 98.49,33.12 98.49,34.9 98.3,35.08 98,35.08 97.73,34.82 97.73,33.12 97.55,32.93 97.17,32.93 96.98,33.12 96.98,33.42 96.8,33.61 96.52,33.61 96.28,33.36 96.28,32.97 96.18,32.87 95.94,32.87 95.75,32.68 95.75,31.79 95.56,31.6 94.52,31.6 89.12,26.2 v2(89.12,25.91)
DDR_B_MA2: length 132.2
  TOP w0.107: v2(52.39,20.51) 52.39,20.95 51.45,21.88 UD6.R3 ; v2(41.07,20.51) 41.07,20.95 40.14,21.88 UD5.R3 ; UD8.R3 76.96,19.88 77.89,18.95 v2(77.89,18.51) ; UD7.R3 63.79,21.88 64.72,20.95 v2(64.72,20.51)
  TOP w0.188: RD58.2 v2(32.66,22.69)
  IN2 w0.089: v2(77.89,18.51) 78.31,18.09 79.34,18.09 79.59,18.34 81.61,18.34
  IN2 w0.198: 81.61,18.34 81.88,18.34 82.01,18.21 v2(83.33,18.21)
  IN3 w0.091: 42.54,20.88 41.45,20.88 v2(41.07,20.51)
  IN3 w0.127: 42.54,20.88 42.91,20.88 43.74,20.06 49.54,20.06 49.67,20.19 49.67,20.59 49.79,20.72 50.05,20.72 50.17,20.59 50.17,20.19 50.3,20.06 50.55,20.06 50.68,20.19 50.68,20.59 50.81,20.72 51.06,20.72 51.19,20.59 51.19,20.19 51.32,20.06 51.57,20.06 52.01,20.51 v2(52.39,20.51) 52.88,20.02 57.42,20.02 57.54,20.14 57.54,20.68 57.67,20.81 57.92,20.81 58.05,20.68 58.05,20.14 58.18,20.02 61.79,20.02 62.28,20.51 v2(64.72,20.51) 65.19,20.03 70.36,20.03 71.39,19 76.55,19 77.04,18.51 v2(77.89,18.51) ; v2(41.07,20.51) 40.03,21.54 37.3,21.54 36.6,22.24 34.88,22.24 34.11,23.02 32.99,23.02 v2(32.66,22.69)
  BOTTOM w0.102: 112.16,46.26 112.67,46.78 112.67,52.87 112.56,52.98 112.56,53.24 112.69,53.37 112.69,53.56 112.65,53.66 112.06,54.25 111.79,54.25 111.7,54.21 111.64,54.15 UC1.AJ30
  BOTTOM w0.188: v2(83.33,18.21) 83.33,18.68 86.04,21.39 86.63,21.39 89.22,23.98 89.81,23.98 90.54,24.72 90.54,25.92 93.91,29.29 94.07,29.29 94.22,29.44 94.22,29.99 94.41,30.18 94.73,30.18 94.86,30.05 94.86,29.47 95.05,29.29 95.25,29.29 95.44,29.47 95.44,30.55 95.63,30.74 96.01,30.74 96.19,30.55 96.19,29.47 96.38,29.29 96.76,29.29 96.95,29.47 96.95,30.55 97.13,30.74 97.51,30.74 97.7,30.55 97.7,29.47 97.89,29.29 98.26,29.29 98.45,29.47 98.45,30.55 98.64,30.74 99.01,30.74 99.2,30.55 99.2,29.47 99.39,29.29 99.77,29.29 99.95,29.47 99.95,30.55 100.14,30.74 100.52,30.74 100.71,30.55 100.71,29.47 100.89,29.29 101.36,29.29 101.62,29.55 101.62,35.53 105.11,39.02 106.11,39.02 111.37,44.28 v3(111.37,44.79) 111.37,45.47 112.16,46.26
DDR_B_MA3: length 133.1
  TOP w0.107: v2(53.5,23.55) 53.58,23.48 UD6.N7 ; v2(42.19,23.55) 42.26,23.48 UD5.N7 ; v2(65.84,23.55) 65.91,23.48 UD7.N7 ; UD8.N7 79.09,21.48 v2(79.01,21.55)
  TOP w0.188: v2(33.44,24.29) 33.64,24.49 RD59.2
  IN1 w0.102: v2(42.19,23.55) 47.27,23.55 47.37,23.45 47.37,22.95 47.47,22.85 47.67,22.85 47.77,22.95 47.77,23.45 47.88,23.55 48.08,23.55 48.18,23.45 48.18,22.97 48.28,22.87 48.49,22.87 48.59,22.97 48.59,23.45 48.69,23.55 51.41,23.55 52.04,24.19 52.97,24.19 53.28,23.88 53.28,23.78 v2(53.5,23.55) 53.68,23.38 54.1,23.38 54.2,23.48 54.2,23.78 54.3,23.88 54.5,23.88 54.6,23.78 54.6,23.48 54.7,23.38 55.66,23.38 55.95,23.09 60.66,23.09 61.14,22.61 62.89,22.61 64.24,23.95 64.55,23.95 64.56,23.96 65.43,23.96 v2(65.84,23.55) 65.93,23.65 70.54,23.65 72.27,21.93 75.38,21.93 76.94,22.18 78.38,22.18 v2(79.01,21.55)
  IN2 w0.089: 82.91,21.39 82.56,21.39 82.34,21.16 79.4,21.16 v2(79.01,21.55)
  IN2 w0.198: v2(89.96,25.91) 92.54,28.5 92.54,28.79 91.86,29.47 91.61,29.47 87.32,25.18 87.32,24.39 86.55,23.63 85.77,23.63 83.53,21.39 82.91,21.39
  IN3 w0.089: v2(42.19,23.55) 41.77,23.97 41.77,23.98 41.57,24.19 40.76,24.19
  IN3 w0.127: v2(33.44,24.29) 33.24,24.29 32.91,24.62 32.26,24.62 32.09,24.78 32.09,25.86 32.29,26.07 32.73,26.07 33.11,26.45 34.3,26.45 34.73,26.01 35.67,26.01 36.84,24.85 37.89,24.85 38.55,24.19 40.76,24.19
  BOTTOM w0.091: 110.87,53.55 111.23,53.19 111.23,53.01 111.07,52.84 111.07,51.43
  BOTTOM w0.102: 109.81,46.26 109.81,47.72 111.2,49.11 111.2,51.29 111.07,51.43 ; UC1.AH29 110.87,53.55
  BOTTOM w0.188: v2(89.96,25.91) 89.96,26.42 94.69,31.16 96.18,31.16 96.37,31.34 96.37,32.33 96.56,32.52 96.93,32.52 97.12,32.33 97.12,31.34 97.31,31.16 97.68,31.16 97.87,31.34 97.87,32.33 98.06,32.52 98.44,32.52 98.62,32.33 98.62,31.34 98.81,31.16 99.19,31.16 99.38,31.34 99.38,32.33 99.56,32.52 99.94,32.52 100.13,32.33 100.13,31.34 100.32,31.16 100.97,31.16 101.2,31.39 101.2,35.7 105.01,39.51 106.01,39.51 109.81,43.31 v3(109.81,43.9) 109.81,44.72 109.99,44.91 110.47,44.91 110.66,45.1 110.66,45.47 110.47,45.66 109.99,45.66 109.81,45.85 109.81,46.26
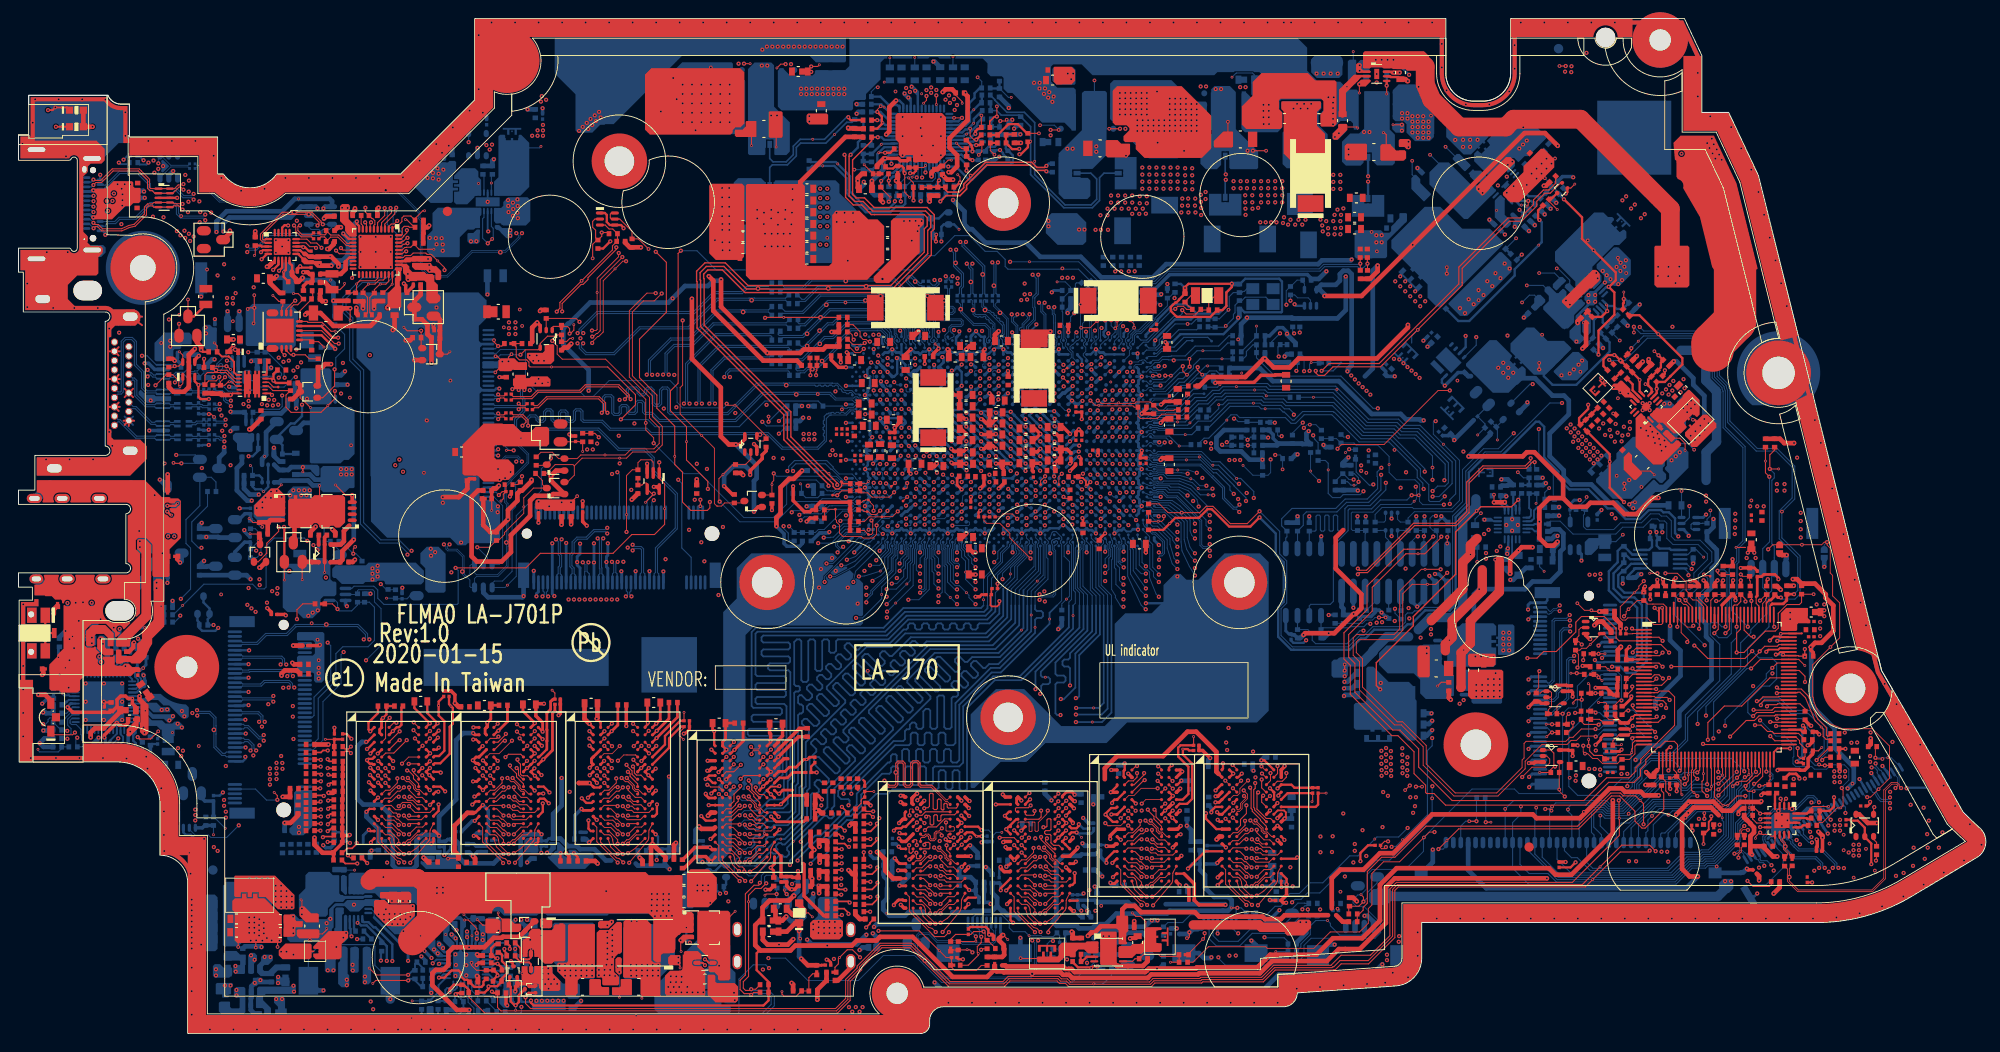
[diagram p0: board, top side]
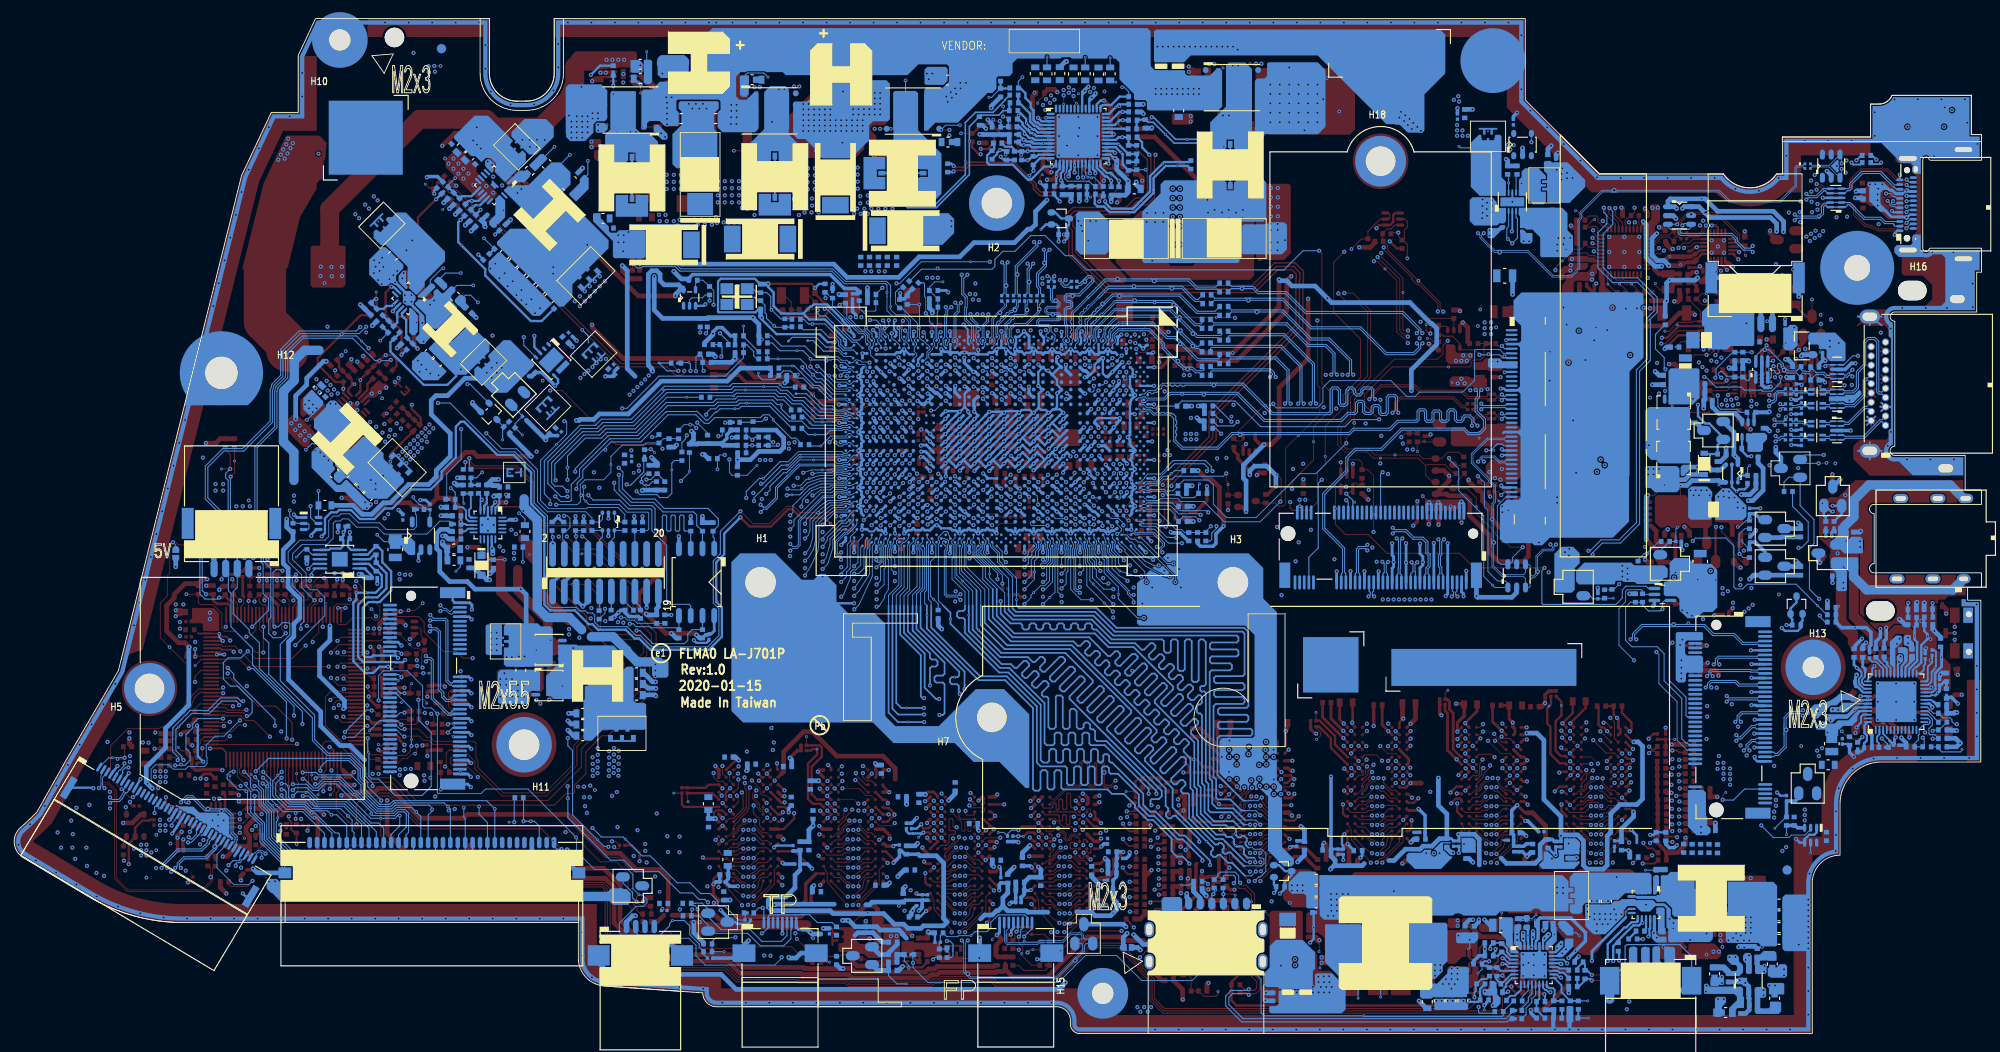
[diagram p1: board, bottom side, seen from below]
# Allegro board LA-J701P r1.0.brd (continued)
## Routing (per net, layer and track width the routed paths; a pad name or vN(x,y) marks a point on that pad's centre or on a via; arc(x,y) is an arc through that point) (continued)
DDR_B_MA4: length 132.4
  TOP w0.107: UD8.N3 77.37,21.48 77.69,21.16 77.83,21.16 v2(78.45,20.54) ; v2(65.28,22.54) 64.66,23.16 64.51,23.16 64.19,23.48 UD7.N3 ; UD6.N3 51.86,23.48 52.18,23.16 52.33,23.16 v2(52.94,22.54) ; UD5.N3 40.54,23.48 40.87,23.16 41.01,23.16 v2(41.63,22.54)
  TOP w0.188: v2(33.42,23.45) 33.7,23.73 RD60.2
  IN1 w0.102: v2(41.63,22.54) 41.08,21.99 38.6,21.99 38.03,22.56 36.92,22.56 36.66,22.3 35.14,22.3 34,23.45 v2(33.42,23.45)
  IN2 w0.089: v2(78.45,20.54) 78.45,20.48 78.78,20.15 82.49,20.15 82.72,20.38 82.91,20.38
  IN2 w0.198: 82.91,20.38 84.14,20.38 v2(84.5,20.73)
  IN3 w0.099: 53.97,22.79 53.81,22.95 53.37,22.95 53.34,22.92 53.32,22.92 v2(52.94,22.54) ; 42.56,22.91 42.35,22.91 42.35,22.92 42.03,22.92 42.03,22.92 42.01,22.92 v2(41.63,22.54) ; 66.31,22.92 65.75,22.92 65.56,22.82 v2(65.28,22.54)
  IN3 w0.127: v2(52.94,22.54) 52.51,22.97 49.93,22.97 49.49,22.54 49.14,22.54 48.48,23.2 45.6,23.2 45.47,23.07 45.47,22.66 45.35,22.54 45.09,22.54 44.96,22.66 44.96,23.07 44.84,23.2 44.58,23.2 44.46,23.07 44.46,22.69 44.33,22.56 44.08,22.56 43.95,22.69 43.95,23.07 43.82,23.2 43.25,23.2 42.97,22.91 42.56,22.91 ; 53.97,22.79 54.13,22.62 59.07,22.62 59.2,22.75 59.2,22.94 59.32,23.07 59.58,23.07 59.7,22.94 59.7,22.75 59.83,22.62 60.09,22.62 60.21,22.75 60.21,22.97 60.34,23.09 60.59,23.09 60.72,22.97 60.72,22.75 60.85,22.62 62.95,22.62 63.32,23 64.81,23 v2(65.28,22.54) ; v2(78.45,20.54) 78.07,20.92 76.04,21.42 74.39,21.42 73.52,21.27 72.28,21.27 70.62,22.92 66.31,22.92
  BOTTOM w0.102: UC1.AG32 110.37,49.73 108.55,47.91
  BOTTOM w0.188: 108.55,47.91 108.55,43.82 v3(108.33,43.6) 105.86,41.13 98.96,41.13 96,38.18 96,37.92 97.65,36.28 97.65,36.01 97.38,35.75 97.11,35.75 95.31,37.55 95.07,37.55 94.8,37.28 94.8,37 96.58,35.22 96.58,34.95 96.32,34.68 96.05,34.68 94.26,36.47 94,36.47 93.74,36.22 93.74,35.93 95.52,34.15 95.52,33.89 95.25,33.62 94.99,33.62 93.21,35.4 92.92,35.4 92.66,35.13 92.66,34.89 94.45,33.09 94.45,32.82 88.12,26.49 88.12,24.6 87.84,24.32 87.84,24.05 88.1,23.79 88.1,23.52 87.83,23.26 87.57,23.26 87.3,23.52 87.04,23.52 84.5,20.98 v2(84.5,20.73)
DDR_B_MA5: length 132.4
  TOP w0.107: v2(65.84,21.52) 65.84,21.53 66.61,22.31 67.3,22.31 UD7.P8 ; v2(79.01,19.52) 79.01,19.53 79.78,20.31 80.48,20.31 UD8.P8 ; v2(53.5,21.52) 53.5,21.53 54.28,22.31 54.97,22.31 UD6.P8 ; UD5.P8 43.66,22.31 42.96,22.31 42.19,21.53 v2(42.19,21.52)
  TOP w0.188: v2(33.4,21.87) 33.56,22.03 33.66,22.03 33.83,22.2 RD61.2
  IN1 w0.102: v2(79.01,19.52) 78.63,19.91 76.08,19.91 75.91,19.74 72.61,19.74 71.26,21.09 66.27,21.09 v2(65.84,21.52) 65.31,22.05 64.28,22.05 63.38,21.15 55.53,21.15 55.43,21.25 55.43,21.62 55.32,21.72 55.12,21.72 55.02,21.62 55.02,21.15 54.91,21.04 53.99,21.04 v2(53.5,21.52) 53.06,21.96 48.01,21.96 47.91,21.86 47.91,21.52 47.81,21.42 47.6,21.42 47.5,21.52 47.5,21.86 47.4,21.96 47.2,21.96 47.1,21.86 47.1,21.54 46.99,21.44 46.79,21.44 46.69,21.54 46.69,21.86 46.59,21.96 46.38,21.96 46.28,21.86 46.28,21.54 46.18,21.44 45.98,21.44 45.88,21.54 45.88,21.86 45.78,21.96 42.63,21.96 v2(42.19,21.52) 41.75,21.09 34.84,21.09 34.38,21.54 33.73,21.54 v2(33.4,21.87)
  IN2 w0.089: v2(79.01,19.52) 79.42,19.52 79.62,19.32
  IN2 w0.198: 79.62,19.32 84.62,19.32 89.65,24.35 v2(89.65,24.67)
  BOTTOM w0.091: UC1.AG30 110.53,53.34 110.53,52.99 110.68,52.84 110.68,49.54
  BOTTOM w0.102: 110.68,49.54 v3(110.04,48.89) 108.97,47.82 108.97,46.26
  BOTTOM w0.188: 108.97,46.26 108.97,43.65 106,40.68 103.01,40.68 102.49,40.16 102.23,40.16 101.69,40.7 101.42,40.7 101.15,40.44 101.15,40.17 101.69,39.63 101.69,39.37 101.43,39.1 101.16,39.1 99.55,40.71 99.25,40.71 98.99,40.45 98.99,40.21 100.63,38.57 100.63,38.3 100.36,38.04 100.1,38.04 98.49,39.64 98.18,39.64 97.91,39.37 97.91,39.16 99.57,37.51 99.57,37.24 99.3,36.97 99.03,36.97 97.41,38.6 97.14,38.6 96.87,38.34 96.87,38.07 98.5,36.44 98.5,36.18 88.54,26.21 88.54,25.66 88.87,25.33 89.63,25.33 89.76,25.2 89.76,24.78 v2(89.65,24.67)
DDR_B_MA6: length 132.9
  TOP w0.107: UD8.P2 76.46,20.27 77.15,20.27 v2(77.89,19.52) ; UD6.P2 50.96,22.27 51.64,22.27 v2(52.39,21.52) ; UD5.P2 39.64,22.27 40.33,22.27 v2(41.07,21.52) ; UD7.P2 63.29,22.27 63.97,22.27 v2(64.72,21.52)
  TOP w0.188: v2(33.42,22.61) 33.77,22.97 RD62.2
  IN1 w0.102: v2(41.07,21.52) 41.02,21.57 36.89,21.57 36.62,21.84 34.72,21.84 33.87,22.69 33.49,22.69 v2(33.42,22.61)
  IN3 w0.091: v2(41.07,21.52) 41.45,21.14 42.66,21.14
  IN3 w0.127: v2(77.89,19.52) 77.73,19.36 71.59,19.36 69.93,21.02 65.22,21.02 v2(64.72,21.52) 64.31,21.12 60.31,21.12 60.18,20.99 60.18,20.76 60.05,20.63 59.8,20.63 59.67,20.76 59.67,20.99 59.55,21.12 59.29,21.12 59.17,20.99 59.17,20.71 59.04,20.58 58.78,20.58 58.66,20.71 58.66,20.99 58.53,21.12 52.79,21.12 v2(52.39,21.52) 51.9,21.04 49.55,21.04 49.26,20.74 47.91,20.74 47.78,20.87 47.78,21.3 47.66,21.43 47.4,21.43 47.28,21.3 47.28,20.87 47.15,20.74 46.89,20.74 46.77,20.87 46.77,21.3 46.64,21.43 46.39,21.43 46.26,21.3 46.26,20.87 46.13,20.74 45.32,20.74 44.92,21.14 42.66,21.14
  BOTTOM w0.091: UC1.AG31 109.88,50.17
  BOTTOM w0.102: 109.88,50.17 107.66,47.96 107.66,46.26 ; 79.54,18.12 77.74,18.12 77.51,18.35 77.51,18.85 77.61,18.95 77.94,18.95 78.04,19.06 78.04,19.37 v2(77.89,19.52)
  BOTTOM w0.188: 79.54,18.12 79.67,18.12 81.13,19.57 81.39,19.57 81.52,19.44 81.78,19.44 81.98,19.63 81.98,19.9 81.84,20.04 81.84,20.31 82.1,20.57 82.37,20.57 82.51,20.43 82.77,20.43 85.59,23.25 85.59,25.81 85.73,25.96 86.26,25.96 86.45,26.14 86.45,26.41 85.99,26.86 85.99,27.13 86.26,27.39 86.52,27.39 86.98,26.94 87.24,26.94 87.52,27.21 87.52,27.54 85.94,29.11 85.94,29.65 86.18,29.88 86.44,29.88 88.21,28.12 88.43,28.12 88.69,28.39 88.69,28.7 86.98,30.41 86.98,30.68 87.24,30.95 87.51,30.95 89.27,29.18 89.48,29.18 89.75,29.45 89.75,29.77 88.04,31.48 88.04,31.74 88.31,32.01 88.57,32.01 89.12,31.46 89.38,31.46 89.65,31.73 89.65,31.99 89.1,32.54 89.1,32.81 98.26,41.96 105.23,41.96 107.66,44.39 107.66,46.26
DDR_B_MA7: length 136.3
  TOP w0.107: UD8.R8 80.44,19.47 79.91,19.47 79.01,18.57 v2(79.01,18.51) ; v2(42.19,20.51) 42.19,20.58 43.08,21.47 43.62,21.47 UD5.R8 ; UD6.R8 54.93,21.47 54.39,21.47 53.5,20.58 v2(53.5,20.51) ; UD7.R8 67.26,21.47 66.72,21.47 65.84,20.58 v2(65.84,20.51)
  TOP w0.188: RD63.2 v2(32.61,21.93)
  IN1 w0.102: v2(42.19,20.51) 42.65,20.97 43.31,20.97 43.41,21.07 43.41,21.51 43.51,21.61 43.71,21.61 43.81,21.51 43.81,21.07 43.92,20.97 44.12,20.97 44.22,21.07 44.22,21.49 44.32,21.6 44.52,21.6 44.63,21.49 44.63,21.07 44.73,20.97 45.24,20.97 45.55,20.66 49.32,20.66 49.8,21.14 52.87,21.14 v2(53.5,20.51) 53.94,20.07 54.86,20.07 54.96,20.18 54.96,20.33 55.07,20.43 55.27,20.43 55.37,20.33 55.37,20.18 55.47,20.07 56.03,20.07 56.61,20.66 59.91,20.66 60.68,19.88 61.85,19.88 62.87,20.91 65.43,20.91 v2(65.84,20.51) 66.69,20.51 67.13,20.07 70.96,20.07 71.77,19.26 77.21,19.26 77.33,19.13 78.63,19.13 79.01,18.75 v2(79.01,18.51)
  IN3 w0.091: 40.61,20.07 41.75,20.07 v2(42.19,20.51)
  IN3 w0.127: 40.61,20.07 40.1,20.07 39.01,21.16 36.92,21.16 36.21,21.87 35.47,21.87 35.06,21.47 33.21,21.47 32.76,21.93 v2(32.61,21.93)
  BOTTOM w0.091: 109.59,50.4 109.69,50.5 109.69,52.85 109.52,53.03 109.52,53.36
  BOTTOM w0.102: 109.59,50.4 107.23,48.04 107.23,46.26 ; UC1.AF30 109.52,53.36 ; v2(79.01,18.51) 79.43,18.51 79.54,18.62
  BOTTOM w0.188: 107.23,46.26 107.23,44.79 104.82,42.38 98.09,42.38 97.61,41.9 97.35,41.9 96.84,42.41 96.55,42.41 96.28,42.14 96.28,41.91 96.81,41.37 96.81,41.11 96.55,40.84 96.28,40.84 95.78,41.34 95.49,41.34 95.22,41.08 95.22,40.84 95.75,40.31 95.75,40.04 95.48,39.78 95.22,39.78 94.66,40.34 94.48,40.34 94.2,40.06 94.2,39.73 94.69,39.25 94.69,38.98 94.42,38.71 94.16,38.71 93.65,39.22 93.37,39.22 93.07,38.93 93.07,38.74 93.62,38.18 93.62,37.92 93.36,37.65 93.09,37.65 92.53,38.21 92.35,38.21 92,37.86 92,37.68 92.56,37.12 92.56,36.85 92.29,36.59 92.03,36.59 91.47,37.15 91.29,37.15 90.94,36.79 90.94,36.61 91.5,36.05 91.5,35.79 91.23,35.52 90.96,35.52 90.4,36.08 90.22,36.08 89.87,35.73 89.87,35.55 90.43,34.99 90.43,34.72 90.17,34.46 89.9,34.46 89.34,35.02 89.16,35.02 88.81,34.67 88.81,34.49 89.37,33.93 89.37,33.66 89.1,33.39 88.84,33.39 88.28,33.95 88.1,33.95 87.75,33.6 87.75,33.42 88.3,32.86 88.3,32.6 88.04,32.33 87.77,32.33 87.21,32.89 87.03,32.89 86.68,32.54 86.68,32.36 87.24,31.8 87.24,31.53 86.97,31.27 86.71,31.27 86.15,31.83 85.97,31.83 85.62,31.47 85.62,31.29 86.18,30.74 86.18,30.47 85.45,29.74 85.45,26.52 85.17,26.24 85.17,23.42 82.76,21.01 v3(82.34,21.01) 81.93,21.01 79.54,18.62
DDR_B_MA8: length 138.3
  TOP w0.107: UD5.R2 39.63,21.48 40.12,21.48 40.26,21.42 40.41,21.28 40.54,20.97 40.54,20.85 40.63,20.39 v2(41.63,19.39) ; v2(78.39,17.52) 78.39,17.81 78.2,18 77.84,18 77.46,18.39 77.36,18.85 77.36,18.97 77.23,19.28 77.08,19.42 76.95,19.48 76.45,19.48 UD8.R2 ; UD6.R2 50.94,21.48 51.44,21.48 51.58,21.42 51.72,21.28 51.85,20.97 51.85,20.85 51.95,20.39 v2(52.94,19.39) ; v2(65.28,19.39) 65.1,19.57 65.1,19.57 64.88,19.79 64.86,19.79 64.29,20.37 64.18,20.85 64.18,20.97 64.05,21.28 63.91,21.42 63.77,21.48 63.27,21.48 UD7.R2
  TOP w0.188: RD64.2 34,20.71 v2(33.39,20.71)
  IN1 w0.102: v2(33.39,20.71) 34.4,19.7 36.35,19.7 36.73,19.32 39.01,19.32 39.58,19.89 41.13,19.89 v2(41.63,19.39)
  IN3 w0.091: 53.65,19.07 53.74,19.16
  IN3 w0.099: v2(52.94,19.39) 53.02,19.39 53.24,19.17 53.25,19.17 53.35,19.07 53.65,19.07 ; 42.55,19.1 42.06,19.1 42.05,19.11 42.03,19.11 41.75,19.39 v2(41.63,19.39)
  IN3 w0.102: 66.14,19.11 65.99,19.11 65.99,19.11 65.68,19.11 65.68,19.11 65.61,19.11 65.56,19.16 65.56,19.16 65.33,19.39 v2(65.28,19.39)
  IN3 w0.127: 42.55,19.1 43.13,19.68 46.98,19.68 47.1,19.55 47.1,19.08 47.23,18.95 47.49,18.95 47.61,19.08 47.61,19.55 47.74,19.68 47.99,19.68 48.12,19.55 48.12,19.17 48.25,19.04 48.5,19.04 48.63,19.17 48.63,19.55 48.76,19.68 51.9,19.68 52.08,19.87 52.54,19.87 52.94,19.47 v2(52.94,19.39) ; v2(78.39,17.52) 78.39,17.54 77.91,18.01 73.65,18.01 73.14,18.52 71.11,18.52 70.23,19.4 66.43,19.4 66.14,19.11 ; v2(65.28,19.39) 65.28,19.43 64.9,19.81 64.47,19.81 64.46,19.79 63.95,19.79 63.87,19.87 63.87,19.92 63.75,20.05 63.49,20.05 63.37,19.92 63.37,19.77 63.24,19.64 62.98,19.64 62.86,19.77 62.86,19.92 62.73,20.05 62.48,20.05 62.35,19.92 62.35,19.77 62.22,19.64 61.38,19.64 60.8,19.06 56.3,19.06 55.95,19.41 53.99,19.41 53.74,19.16
  BOTTOM w0.091: UC1.AG29 109.88,53.57 110.21,53.23 110.21,53.03 110.07,52.89 110.07,52.56 110.18,52.46
  BOTTOM w0.102: 108.09,46.26 108.09,47.91 110.18,49.99 110.18,52.46 ; 79.54,17.04 78.87,17.04 v2(78.39,17.52)
  BOTTOM w0.188: 108.09,46.26 108.09,44.13 105.52,41.55 98.48,41.55 91.85,34.92 91.85,34.65 93.56,32.94 93.56,32.67 93.3,32.4 93.03,32.4 91.32,34.12 91.05,34.12 90.79,33.85 90.79,33.59 92.5,31.87 92.5,31.61 92.24,31.34 91.97,31.34 90.25,33.06 89.99,33.06 89.72,32.79 89.72,32.52 91.44,30.81 91.44,30.54 91.17,30.28 90.91,30.28 90.03,31.15 89.74,31.15 89.47,30.89 89.47,30.65 90.37,29.74 90.37,29.48 87.38,26.48 87.38,24.44 v3(83.68,20.75) 83.03,20.1 83.03,19.83 83.23,19.63 83.23,19.36 82.96,19.1 82.7,19.1 82.49,19.3 82.23,19.3 81.38,18.45 80.95,18.45 79.54,17.04
DDR_B_MA9: length 134.3
  TOP w0.107: v2(41.63,20.51) 42.07,20.95 42.27,20.95 43.2,21.88 UD5.R7 ; UD7.R7 66.85,21.88 65.92,20.95 65.72,20.95 v2(65.28,20.51) ; UD6.R7 54.52,21.88 53.58,20.95 53.38,20.95 v2(52.94,20.51) ; v2(78.45,18.51) 78.89,18.95 79.09,18.95 80.02,19.88 UD8.R7
  TOP w0.188: v2(32.88,21.21) 32.96,21.29 33.91,21.29 RD65.2
  IN1 w0.102: v2(32.88,21.21) 33.01,21.09 33.95,21.09 34.95,20.08 37.49,20.08 37.62,20.21 38.36,20.21 38.47,20.1 41.22,20.1 v2(41.63,20.51) 42.18,19.96 42.5,19.96 42.7,20.15 45.11,20.15 45.24,20.27 49.94,20.27 50.04,20.38 50.04,20.78 50.15,20.88 50.35,20.88 50.45,20.78 50.45,20.38 50.55,20.27 50.76,20.27 50.86,20.38 50.86,20.78 50.96,20.88 51.16,20.88 51.26,20.78 51.26,20.38 51.37,20.27 51.58,20.27 52.2,20.89 52.64,20.89 52.94,20.58 v2(52.94,20.51) 53.37,20.08 53.54,20.08 53.8,19.83 56.24,19.83 56.68,20.27 59.8,20.27 60.67,19.4 61.88,19.4 62.6,20.13 63.29,20.13 63.39,20.23 63.39,20.39 63.49,20.49 63.7,20.49 63.8,20.39 63.8,20.23 63.9,20.13 64.9,20.13 v2(65.28,20.51) 65.76,20.02 66.34,20.02 66.59,19.77 70.86,19.77 71.69,18.93 75.68,18.93 75.72,18.89 78.24,18.89 78.45,18.67 v2(78.45,18.51)
  BOTTOM w0.102: 106.8,48.01 107.88,49.09 107.88,50.44 108.93,51.49 108.93,52.71 109.19,52.96 109.19,53.24 108.88,53.55 UC1.AF29 ; v2(78.45,18.51) 78.45,18.9 78.55,19
  BOTTOM w0.188: 106.8,48.01 106.8,44.98 104.64,42.82 96.38,42.82 94.36,40.8 94.09,40.8 93.58,41.31 93.32,41.31 93.05,41.04 93.05,40.78 93.56,40.27 93.56,40 93.29,39.74 93.03,39.74 91.76,41.01 91.42,41.01 91.15,40.74 91.15,40.55 92.49,39.21 92.49,38.94 92.23,38.67 91.96,38.67 90.64,39.99 90.4,39.99 90.14,39.73 90.14,39.44 91.43,38.14 91.43,37.88 91.16,37.61 90.9,37.61 89.61,38.9 89.31,38.9 89.05,38.64 89.05,38.4 90.37,37.08 90.37,36.81 90.1,36.55 89.84,36.55 88.49,37.9 88.31,37.9 88,37.59 88,37.32 89.3,36.02 89.3,35.75 85.04,31.48 85.04,26.7 84.76,26.42 84.76,23.59 82.66,21.49 81.78,21.49 81.54,21.25 81.27,21.25 81.27,21.26 81.01,21.26 80.74,20.99 80.74,20.72 80.74,20.72 80.74,20.46 v3(80.58,20.3) 80.48,20.19 80.21,20.19 80.18,20.22 79.92,20.22 79.65,19.95 79.65,19.69 79.68,19.66 79.68,19.39 79.29,19 78.55,19
DDR_B_MA10: length 124.8
  TOP w0.107: v2(41.07,23.55) 40.79,23.83 40.48,23.83 UD5.M3 ; UD8.M3 77.17,22.28 v2(77.89,21.55) ; v2(52.39,23.55) 51.66,24.28 UD6.M3 ; UD7.M3 63.99,24.28 v2(64.72,23.55)
  TOP w0.188: RD66.2 33.52,25.25 v2(33.44,25.18)
  IN1 w0.102: v2(41.07,23.55) 40.99,23.47 38.34,23.47 38.19,23.32 36.66,23.32 36.15,23.83 35.33,23.83 34.19,24.97 33.65,24.97 v2(33.44,25.18)
  IN2 w0.089: 82.91,22.48 81.02,22.48 80.71,22.18 78.52,22.18 v2(77.89,21.55)
  IN2 w0.198: v2(110.35,36.71) 110.29,36.64 110.29,32.61 108.85,31.16 104.57,31.16 104.23,31.5 104.23,32.7 104.01,32.92 103.6,32.92 103.44,32.77 103.44,31.27 103.21,31.04 102.82,31.04 102.65,31.2 102.65,32.42 102.45,32.62 102.06,32.62 101.86,32.42 101.86,31.47 101.68,31.3 100.54,31.3 99.72,30.48 91.19,30.48 87.17,26.46 86.44,26.46 84.57,24.59 84.57,23.85 83.2,22.48 82.91,22.48
  IN3 w0.091: v2(64.72,23.55) 65.1,23.17 66.06,23.17 66.2,23.31 66.34,23.31 ; 41.46,23.17 v2(41.07,23.55) ; 54.02,23.17 52.77,23.17 v2(52.39,23.55)
  IN3 w0.099: 42.61,23.17 41.46,23.17
  IN3 w0.127: v2(52.39,23.55) 52.39,23.81 52.16,24.03 51.81,24.03 51.69,23.92 51.69,23.37 51.57,23.25 51.31,23.25 51.18,23.37 51.18,23.86 51.06,23.98 50.8,23.98 50.68,23.86 50.68,23.37 50.55,23.25 50.3,23.25 50.17,23.37 50.17,23.53 50.04,23.65 43.09,23.65 42.61,23.17 ; 66.34,23.31 70.73,23.31 72.39,21.65 73.83,21.65 73.88,21.7 77.33,21.7 v2(77.89,21.55) ; 54.02,23.17 54.27,23.42 61.26,23.42 61.45,23.61 62.1,23.61 62.23,23.74 62.23,23.98 62.35,24.11 62.61,24.11 62.73,23.98 62.73,23.74 62.86,23.61 63.12,23.61 63.24,23.74 63.24,24 63.37,24.12 63.62,24.12 63.75,24 63.75,23.74 63.94,23.55 v2(64.72,23.55)
  BOTTOM w0.102: UC1.AM30 114.37,53.12 114.67,52.82 114.67,52.5 114.37,52.2 114.37,48.18 115.04,47.52 115.04,46.26
  BOTTOM w0.188: v2(110.35,36.71) 110.47,36.82 110.47,37.57 110.66,37.75 111.23,37.75 111.42,37.94 111.42,38.32 111.23,38.51 v3(110.91,38.51) 110.61,38.51 110.42,38.69 110.42,39.1 115.04,43.72 115.04,46.26
DDR_B_MA11: length 136.1
  TOP w0.107: v2(41.67,18.49) 41.27,18.89 40.92,18.99 39.23,20.68 UD5.T2 ; UD7.T2 62.88,20.68 64.57,18.99 64.92,18.89 v2(65.32,18.49) ; UD8.T2 76.05,18.68 77.75,16.99 78.1,16.89 v2(78.49,16.49) ; UD6.T2 50.54,20.68 52.24,18.99 52.59,18.89 v2(52.99,18.49)
  TOP w0.188: RD67.2 34.94,18.73 35.3,18.37 v2(36.59,18.37)
  IN1 w0.102: v2(36.59,18.37) 36.92,18.04 41.22,18.04 v2(41.67,18.49) 42.15,18.01 50.53,18.01 50.63,18.12 50.63,18.43 50.73,18.53 50.94,18.53 51.04,18.43 51.04,18.12 51.14,18.01 51.34,18.01 51.45,18.12 51.45,18.8 51.55,18.9 51.75,18.9 51.85,18.8 51.85,18.12 51.95,18.01 52.68,18.01 52.99,18.32 v2(52.99,18.49) 53.49,17.99 63.65,17.99 63.75,18.09 63.75,18.72 63.85,18.82 64.06,18.82 64.16,18.72 64.16,18.09 64.26,17.99 64.81,17.99 v2(65.32,18.49) 65.87,17.94 69.26,17.94 69.61,18.29 70.63,18.29 71.85,17.07 78.2,17.07 78.49,16.78 v2(78.49,16.49)
  BOTTOM w0.102: 79.18,20.08 78.76,20.08 78.59,19.92 77.75,19.92 77.31,19.48 77.31,17.52 77.92,16.91 78.07,16.91 v2(78.49,16.49) ; UC1.AF31 108.73,52.95 108.73,51.62 107.6,50.49 107.6,49.3 106.37,48.06
  BOTTOM w0.188: 79.18,20.08 79.5,20.41 79.5,20.67 79.36,20.82 79.36,21.08 79.62,21.35 79.89,21.35 80.03,21.2 80.3,21.2 80.56,21.47 v3(80.56,21.61) 80.56,21.74 80.52,21.78 80.52,22.04 80.79,22.31 81.06,22.31 81.09,22.27 81.36,22.27 81.6,22.51 83.08,22.51 84.34,23.77 84.34,26.59 84.62,26.87 84.62,31.66 85.37,32.41 85.37,32.72 84.62,33.48 84.62,33.74 84.89,34.01 85.15,34.01 85.9,33.26 86.22,33.26 86.5,33.54 86.5,33.76 85.17,35.1 85.17,35.35 85.44,35.62 85.71,35.62 87.01,34.33 87.27,34.33 87.54,34.59 87.54,34.86 86.24,36.16 86.24,36.42 86.51,36.69 86.77,36.69 88.07,35.39 88.34,35.39 88.6,35.66 88.6,35.92 87.31,37.22 87.31,37.49 91.58,41.76 94.3,41.76 95.78,43.24 104.47,43.24 106.37,45.14 106.37,48.06
DDR_B_MA12: length 132.6
  TOP w0.107: UD6.M7 54.23,24.28 53.94,24.57 v2(53.5,24.57) ; UD7.M7 66.56,24.28 66.27,24.57 v2(65.84,24.57) ; v2(41.07,24.57) 41.47,24.97 42.36,24.97 43.05,24.28 UD5.M7 ; v2(79.01,22.57) 79.44,22.57 79.73,22.28 UD8.M7
  TOP w0.188: RD68.2 v2(32.59,26.5)
  IN1 w0.102: v2(79.01,22.57) 78.63,22.95 77.53,22.95 77.33,22.75 71.96,22.75 70.7,24.02 66.39,24.02 v2(65.84,24.57) 65.45,24.96 64.37,24.96 62.96,23.55 62.6,23.55 62.5,23.66 62.5,23.91 62.4,24.01 62.2,24.01 62.1,23.91 62.1,23.66 61.99,23.55 56.1,23.55 55.08,24.57 v2(53.5,24.57) 53.11,24.96 52.22,24.96 51.99,24.73 51.2,23.94 43.83,23.94 43.73,24.05 43.73,24.11 43.63,24.21 43.43,24.21 43.33,24.11 43.33,24.05 43.22,23.94 42.85,23.94 42.64,24.16 42.64,24.64 42.33,24.95 41.45,24.95 v2(41.07,24.57)
  IN3 w0.127: v2(32.59,26.5) 32.59,26.58 33.39,27.39 33.93,27.39 34.33,26.98 35.67,26.98 37.27,25.38 38.27,25.38 38.55,25.1 39.71,25.1 40.24,24.57 v2(41.07,24.57)
  BOTTOM w0.102: 105.51,46.26 105.51,47.64 107.14,49.27 v3(107.14,49.67) 107.14,50.32 108.53,51.7 108.53,52.55 UC1.AE32 ; 79.54,22.57 v2(79.01,22.57)
  BOTTOM w0.188: 105.51,46.26 105.51,45.61 104.64,44.74 96.1,44.74 93.96,42.6 88.5,42.6 88.32,42.41 88.32,41.37 88.1,41.15 87.73,41.15 87.56,41.32 87.56,42.41 87.38,42.6 87,42.6 86.81,42.41 86.81,39.38 86.62,39.19 86.25,39.19 86.06,39.38 86.06,42.41 85.87,42.6 85.5,42.6 85.31,42.41 85.31,38.19 85.12,38 84.74,38 84.56,38.18 84.56,42.41 84.37,42.6 84.08,42.6 83.79,42.31 83.79,37.73 83.97,37.55 84.27,37.55 84.39,37.42 84.39,37.11 84.24,36.96 83.94,36.96 83.79,36.81 83.79,27.26 83.51,26.98 83.51,24.14 83.28,23.91 81.04,23.91 79.72,22.59 79.72,22.57 79.54,22.57
DDR_B_MA13: length 128
  TOP w0.107: v2(65.84,19.49) 65.93,19.55 66.58,19.99 UD7.T8 ; UD5.T8 42.94,19.99 42.28,19.55 v2(42.19,19.49) ; v2(53.5,19.49) 53.59,19.55 54.25,19.99 UD6.T8 ; UD8.T8 80.85,19.08 79.76,17.99 79.1,17.55 v2(79.01,17.49)
  TOP w0.188: RD69.2 35.04,19.54 35.52,20.02 36.04,20.02 36.52,20.5 v2(36.52,20.59)
  IN1 w0.102: v2(79.01,17.49) 79.01,17.79 78.83,17.96 72.23,17.96 70.7,19.49 v2(65.84,19.49) 65.45,19.88 62.75,19.88 61.82,18.95 58.2,18.95 58.1,19.05 58.1,19.51 57.99,19.61 57.79,19.61 57.69,19.51 57.69,19.05 57.59,18.95 56.43,18.95 55.89,19.49 v2(53.5,19.49) 53.08,19.92 48.4,19.92 48.3,19.82 48.3,19.27 48.2,19.17 48,19.17 47.89,19.27 47.89,19.82 47.79,19.92 47.59,19.92 47.49,19.82 47.49,19.27 47.39,19.17 47.18,19.17 47.08,19.27 47.08,19.82 46.98,19.92 45.45,19.92 45.36,19.83 42.84,19.83 42.5,19.49 v2(42.19,19.49)
  IN2 w0.198: v2(79.01,17.49) 79.84,17.49 79.86,17.47 83.45,17.47 84.06,18.09 84.39,18.09 85.23,18.93 86.12,18.93 87.72,20.53 87.72,21.28 92.27,25.83 93.43,25.83 96.44,28.84 106.21,28.84 106.43,28.62 109.43,28.62 113.05,32.25 113.05,33.29 113.43,33.66 v2(114.21,33.66)
  IN3 w0.091: 40.68,19.82 41.86,19.82 v2(42.19,19.49)
  IN3 w0.127: 40.68,19.82 39.28,19.82 38.88,20.22 36.89,20.22 v2(36.52,20.59)
  BOTTOM w0.102: UC1.AP30 116.93,53.5 117.2,53.23 117.2,52.98 116.95,52.72 116.95,48.47 118.06,47.36 118.06,46.26
  BOTTOM w0.188: v2(114.21,33.66) v3(115.99,33.66) 117.03,33.66 118.06,34.68 118.06,46.26
DDR_B_ODT0: length 127.5
  TOP w0.107: v2(52.39,26.63) 52.09,26.63 UD6.K3 ; UD5.K3 40.78,26.63 v2(41.07,26.63) ; v2(64.72,26.63) 64.43,26.63 UD7.K3
  TOP w0.117: UD8.K3 77.05,23.88 77.8,24.63 v2(77.89,24.63)
  TOP w0.188: v2(32.66,29.57) 32.62,29.61 RD74.2
  IN1 w0.102: v2(32.66,29.57) 32.66,29.6 33.19,30.13 33.67,30.13 35.65,28.15 36.41,28.15 37.42,27.13 37.42,26.94 37.68,26.69 41.01,26.69 v2(41.07,26.63)
  IN2 w0.089: v2(77.89,24.63) 78.56,23.96 80.59,23.96 80.86,24.24 82.36,24.24 82.91,24.78
  IN2 w0.198: v2(114.24,35.18) 114.18,35.25 114.18,35.4 112.5,37.08 112.5,39.8 111.52,40.78 107.89,40.78 99.09,31.99 90.57,31.99 88.01,29.42 86.78,29.42 83.81,26.46 83.81,25.96 82.97,25.12 82.97,24.85 82.91,24.78
  IN3 w0.099: 42.56,27.06 42.51,27.01 41.16,27.01 41.07,26.91 v2(41.07,26.63) ; 66.36,27.01 65.09,27.01 v2(64.72,26.63) ; 53.84,26.94 53.83,26.93 53.69,26.93 53.62,27 52.76,27 v2(52.39,26.63)
  IN3 w0.127: 42.56,27.06 44.54,27.06 44.69,26.9 44.69,26.68 44.81,26.56 45.11,26.56 45.23,26.69 45.23,26.95 45.36,27.08 45.61,27.08 45.74,26.95 45.74,26.69 45.87,26.56 46.12,26.56 46.25,26.69 46.25,26.95 46.38,27.08 46.63,27.08 46.76,26.95 46.76,26.46 46.88,26.33 49.53,26.33 49.99,25.87 51.08,25.87 51.84,26.63 v2(52.39,26.63) ; v2(64.72,26.63) 64.42,26.33 60,26.33 59.39,26.94 59.07,26.94 58.94,26.82 58.94,26.26 58.82,26.13 58.56,26.13 58.44,26.26 58.44,26.82 58.31,26.94 53.84,26.94 ; 66.36,27.01 71.92,27.01 73.86,25.07 76.55,25.07 v2(77.89,24.63)
  BOTTOM w0.102: 117.22,46.26 117.22,47.37 116.37,48.21 UC1.AP32
  BOTTOM w0.188: v2(114.24,35.18) v3(116.12,35.18) 116.68,35.18 117.22,35.73 117.22,46.26
DDR_B_PAR: length 128.9
  TOP w0.107: UD5.T3 40.03,21.08 40.32,20.16 v2(41.07,19.41) ; UD7.T3 63.68,21.08 63.97,20.16 v2(64.72,19.41) ; v2(77.83,17.54) 77.11,18.26 76.85,19.08 UD8.T3 ; v2(52.39,19.41) 51.63,20.16 51.34,21.08 UD6.T3
  IN1 w0.102: v2(41.07,19.41) 41.08,19.41 41.51,18.98 42.31,18.98 42.87,18.42 49.24,18.42 49.37,18.55 49.37,18.88 49.47,18.98 49.67,18.98 49.78,18.88 49.78,18.55 49.9,18.42 50.11,18.42 50.18,18.5 50.18,19.31 50.28,19.41 50.49,19.41 50.59,19.31 50.59,19.03 50.69,18.93 50.89,18.93 51,19.03 51,19.31 51.1,19.41 v2(52.39,19.41) 52.86,18.94 55.08,18.94 55.59,18.42 61.73,18.42 62.67,19.36 62.87,19.36 62.97,19.26 62.97,18.83 63.07,18.73 63.27,18.73 63.38,18.83 63.38,19.26 63.53,19.41 v2(64.72,19.41) 64.72,19.17 64.95,18.94 66.3,18.94 66.46,18.78 66.46,18.5 66.62,18.34 69.16,18.34 69.49,18.67 70.86,18.67 71.99,17.54 v2(77.83,17.54)
  IN2 w0.089: v2(77.83,17.54) 78.5,16.87 79.42,16.87
  IN2 w0.198: 79.42,16.87 83.51,16.87 83.89,16.49 84.37,16.49 85.56,17.68 v2(85.56,18.34)
  IN3 w0.127: v2(35.8,20.59) 35.8,20.43 36.9,19.33 40.99,19.33 v2(41.07,19.41)
  BOTTOM w0.102: 113.91,46.26 114.15,46.5 114.15,47.71 113.95,47.91 113.95,53.03 UC1.AM31
  BOTTOM w0.117: RD43.2 35.2,20.78 35.61,20.78 v2(35.8,20.59)
  BOTTOM w0.188: 113.91,46.26 v3(113.91,45.17) 113.91,43.77 108.33,38.18 105.46,38.18 102.45,35.18 102.45,26.44 102.27,26.25 101.83,26.25 101.65,26.44 101.65,28.27 101.46,28.45 101.08,28.45 100.89,28.27 100.89,26.56 100.71,26.38 100.33,26.38 100.14,26.56 100.14,28.27 99.95,28.45 99.58,28.45 99.39,28.27 99.39,26.56 99.2,26.38 94.4,26.38 93.92,25.9 92.63,25.9 91.44,24.7 91.44,24.44 90.07,23.07 89.49,23.07 87.47,21.05 87.47,19.69 86.9,19.12 86.27,19.12 85.56,18.41 v2(85.56,18.34)
DDR_B_RAS#: length 131.4
  TOP w0.107: UD5.L8 43.59,25.52 42.98,25.52 42.19,26.31 v2(42.19,26.6) ; UD6.L8 54.91,25.52 54.29,25.52 53.5,26.31 v2(53.5,26.6) ; UD7.L8 67.24,25.52 66.62,25.52 65.84,26.31 v2(65.84,26.6) ; UD8.L8 80.41,23.52
  TOP w0.117: v2(79.01,24.6) 79.01,24.3 79.79,23.52 80.41,23.52
  TOP w0.188: RD73.2 v2(32.64,28.85)
  IN2 w0.089: v2(79.01,24.6) 80.37,24.6 81.12,25.35 81.42,25.35 81.68,25.61 81.68,26.12 81.88,26.32 82.58,26.32 82.91,26.65 82.91,27.2
  IN2 w0.198: 82.91,27.2 86.45,30.74 87.9,30.74 90.15,32.99 97.93,32.99 106.73,41.78 111.94,41.78 115.23,38.49 115.23,37.83 115.1,37.7 113.66,37.7 v2(113.58,37.62)
  IN3 w0.099: v2(42.19,26.6) 41.82,26.24 41.8,26.24 41.79,26.22 40.83,26.22
  IN3 w0.127: v2(79.01,24.6) 79.01,24.6 78.57,24.16 74.34,24.16 70.15,26.65 66.56,26.65 66.52,26.69 65.92,26.69 v2(65.84,26.6) 65.83,26.6 65.25,26.02 60.22,26.02 59.92,25.72 58.24,25.72 57.31,26.65 55.51,26.65 55.36,26.5 55.36,26.12 55.23,25.99 54.98,25.99 54.85,26.12 54.85,26.5 54.7,26.65 53.55,26.65 v2(53.5,26.6) 52.93,26.03 51.8,26.03 51.29,25.52 49.91,25.52 49.41,26.02 47.01,26.02 46.65,25.66 44.11,25.66 43.98,25.79 43.98,26.32 43.86,26.45 43.6,26.45 43.48,26.32 43.48,25.79 43.35,25.66 43.14,25.66 42.9,25.89 42.9,26.38 42.68,26.6 v2(42.19,26.6) ; 40.83,26.22 40.58,26.47 39.46,26.47 39.25,26.69 37.7,26.69 35.22,29.16 32.95,29.16 v2(32.64,28.85)
  BOTTOM w0.102: UC1.AN29 114.87,53.52 115.18,53.22 115.18,52.92 115.07,52.82 115.07,52.33 114.97,52.23 114.97,48.34 115.97,47.35 115.97,46.26
  BOTTOM w0.188: 115.97,46.26 115.97,43.47 113.58,41.08 113.58,40.6 113.39,40.41 112.95,40.41 112.77,40.23 112.77,39.85 112.95,39.66 113.39,39.66 113.58,39.48 v2(113.58,37.62)
DDR_B_RST#: length 122.7
  TOP w0.107: UD5.P1 38.82,22.29 38.82,20.72 v2(41.07,18.47) ; UD7.P1 62.47,22.29 62.47,20.72 v2(64.72,18.47) ; UD6.P1 50.14,22.29 50.14,20.7 52.34,18.49 v2(52.34,18.42) ; UD8.P1 75.65,20.29 75.65,18.72 v2(77.89,16.47)
  IN2 w0.089: v2(77.89,16.47) 77.69,16.47 76.04,18.13 76.04,26.12 75.1,27.06 75.1,28.94 75.76,29.6 75.76,30.76 76.76,31.77
  IN2 w0.102: 106.8,46.26 106.8,47.48 107.08,47.76 107.08,48.95 105.39,50.64 v2(105.39,50.95)
  IN2 w0.127: 76.76,31.77 77.66,32.67 87.03,32.67 88.95,34.59 97.27,34.59 106.69,44.01 106.69,45.94 106.8,46.06 106.8,46.26
  IN3 w0.127: v2(41.07,18.47) 41.96,17.58 51.5,17.58 v2(52.34,18.42) 52.85,17.91 52.95,17.91 53.15,17.71 63.95,17.71 v2(64.72,18.47) 65.89,17.3 72.1,17.3 72.76,16.64 75.81,16.64 76.29,16.16 77.58,16.16 v2(77.89,16.47)
  BOTTOM w0.108: UC1.AC32 105.78,52.11 105.78,51.34 v2(105.39,50.95)
DDR_B_WE#: length 130.9
  TOP w0.107: UD6.L2 50.89,25.43 51.48,25.43 52.25,26.19 52.53,26.19 v2(52.94,26.6) ; v2(65.28,26.6) 64.86,26.19 64.58,26.19 63.82,25.43 63.23,25.43 UD7.L2 ; UD8.L2 76.4,23.43 76.99,23.43 77.75,24.19 78.04,24.19 v2(78.45,24.6) ; v2(41.63,26.6) 41.22,26.19 40.93,26.19 40.17,25.43 39.58,25.43 UD5.L2
  TOP w0.188: v2(33.39,29.65) 33.39,29.58 33.55,29.42 RD71.2
  IN1 w0.102: v2(78.45,24.6) 78.09,24.24 73.18,24.24 70.94,25.65 66.65,25.65 66.14,26.16 65.72,26.16 v2(65.28,26.6) 64.9,26.23 64.56,26.23 64.55,26.23 64.06,26.23 63.69,25.86 60.68,25.86 60.34,25.52 58.82,25.52 58.72,25.62 58.72,25.99 58.62,26.09 58.41,26.09 58.31,25.99 58.31,25.62 58.21,25.52 55.87,25.52 55.16,26.23 53.31,26.23 v2(52.94,26.6) 52.57,26.23 51.97,26.23 51.64,25.9 49.56,25.9 49.39,26.07 48.98,26.07 48.87,25.95 48.87,25.56 48.77,25.46 48.56,25.46 48.46,25.56 48.46,25.95 48.36,26.05 48.16,26.05 48.06,25.95 48.06,25.56 47.95,25.46 47.75,25.46 47.65,25.56 47.65,26 47.59,26.07 47.36,26.07 47.03,25.74 44.09,25.74 43.65,26.18 42.05,26.18 v2(41.63,26.6) 41.13,26.1 39.57,26.1 39.37,25.9 38.25,25.9 38.21,25.86 37.81,25.86 36.19,27.48 35.55,27.48 33.39,29.64 v2(33.39,29.65)
  IN2 w0.089: v2(78.45,24.6) 78.84,24.21 80.59,24.21 81.75,25.38 82.46,25.38 82.91,25.82
  IN2 w0.198: v2(114.21,36.25) 114.15,36.31 114.04,36.31 113,37.36 113,40.01 111.73,41.28 107.68,41.28 98.88,32.49 90.36,32.49 88.11,30.24 86.66,30.24 83.31,26.88 83.31,26.22 82.91,25.82
  BOTTOM w0.102: 116.81,46.26 116.81,47.34 115.99,48.15 115.99,52.85 115.88,52.97 UC1.AP31
  BOTTOM w0.188: v2(114.21,36.25) 114.38,36.25 114.57,36.44 114.57,40.89 116.81,43.12 116.81,46.26
DEVSLP0: length 66.9
  IN2 w0.102: 87.74,70.5 88.73,71.49 89.86,71.49 91.79,73.42 92.43,73.42 93.07,74.06 93.07,74.42 95.05,76.41 104.53,76.41 109.72,71.22 110.2,71.22 110.75,70.67 112.08,70.67 112.8,69.94 v2(112.89,69.94)
  IN2 w0.127: 87.74,70.5 84.34,70.5 80.34,66.51 v2(80.34,66.11) 78.32,64.09 74.16,64.09 69.79,59.72 65.62,59.72 v2(64.68,60.66)
  BOTTOM w0.089: v2(112.89,69.94) 112.55,69.6 UC1.AK10
  BOTTOM w0.117: RC620.1 83.02,66.2 82.49,65.66 80.79,65.66 v2(80.34,66.11) ; v2(64.68,60.66) 64.91,60.44 JSSD2.38
DEVSLP1: length 129.8
  IN2 w0.127: v2(120.11,72.52) 120.02,72.52 119.97,72.57 118.91,72.57 118.35,72.01 117.64,72.01 116.96,71.33 115.73,71.33 115.52,71.13 115.52,70.8 115.12,70.39 112.77,70.39 112.05,71.11 110.72,71.11 110.34,71.49 110.34,71.84 109.77,72.41 108.88,72.41 107.93,73.36 107.93,73.93 106.28,75.58 106.28,76.22 105.83,76.66 95,76.66 93.14,74.8 92.6,74.8 91.93,74.12 91.93,73.87 91.1,73.04 86.52,73.04 78.17,64.7 73.94,64.7 69.37,60.13 66.16,60.13 65.17,61.12 63.29,61.12 63.12,60.95 58.85,60.95 52.21,54.31 48.2,54.31 47.12,53.23 47.12,52.6 45.01,50.5 45.01,49.51 40.28,44.78 37.06,44.78 34.52,42.25 v2(33.39,42.25)
  BOTTOM w0.089: v2(120.11,72.52) 120.17,72.57 120.95,72.57 121.1,72.73 121.28,72.73 121.35,72.8 121.61,72.8 121.68,72.73 121.69,72.73 121.91,72.5 UC1.BC6
  BOTTOM w0.102: 124.22,73.16 123.55,73.16 123.16,72.76 122.54,72.76 UC1.BC6
  BOTTOM w0.117: 124.22,73.16 124.25,73.18 124.48,73.18 124.53,73.23 126.03,73.23 127.09,74.3 129.63,74.3 130.75,75.42 RC621.1 ; JSSD1.38 31.71,34.17 31.92,34.37 31.92,36.35 33.72,38.16 33.72,41.92 v2(33.39,42.25)
DISPOFF#: length 11.3
  TOP w0.117: v3(59.86,75.12) 59.55,75.12 59.19,74.77 R7.2 R5.2 58.21,75.51 58.07,75.37 57.14,75.37 56.35,74.58 U2.4 56.12,73.89 54.75,73.89 v2(54.22,73.36)
  BOTTOM w0.117: JEDP1.7 51.71,73.01 52.05,73.35 54.21,73.35 v2(54.22,73.36)
DMIC_CLK0_APU: length 91.3
  TOP w0.102: v2(91.41,74.63) 91.25,74.48 90.11,74.48 RC606.2 ; R4024.1 55.93,62.32 56.43,62.82 57.66,62.82 58.34,62.14 Q206.3 60.34,62.14 60.73,62.53 v3(63.35,62.53) 65.53,62.53 66.19,63.19 68.63,63.19 69.21,63.76 69.21,65.48 68.16,66.52 68.16,68.76 65.98,70.94 65.98,78.12 67.88,80.02 v2(68.82,80.02)
  IN3 w0.102: v2(110.87,73.05) 110.76,73.05 110.46,73.35 110.46,73.88 108.96,75.37 103.54,75.37 102.78,74.61 102.78,73.8 102.3,73.32 102.3,71.95 101.28,70.92 97.72,70.92 97.34,70.54 96.67,70.54 96.03,71.18 94.26,71.18 94.15,71.08 92.92,71.08 92.28,70.44 91.48,70.44 91.1,70.82 91.1,71.27 91.45,71.61 91.45,72.63 91.68,72.87 91.68,74.35 v2(91.41,74.63) 91.37,74.6 90.32,74.6 90.11,74.39 89.12,74.39 88.92,74.59 87.67,74.59 84,78.26 75.43,78.26 73.12,80.57 69.38,80.57 v2(68.82,80.02)
  BOTTOM w0.102: UC1.AG6 110.52,72.7 v2(110.87,73.05)
DMIC_DAT0_APU: length 93.3
  TOP w0.102: v2(69.47,79.98) 68.67,79.18 67.5,79.18 66.31,77.98 66.31,71.07 68.49,68.9 68.49,66.66 69.54,65.61 69.54,63.61 68.77,62.84 66.34,62.84 65.68,62.18 v3(64.94,62.18) 60.87,62.18 60.04,61.35 ; RC607.2 89.7,74.25 90.36,73.59 90.9,73.59 v2(91.3,74) ; 60.04,61.35 60.04,60.34 59.29,59.6 Q207.3 ; 60.04,61.35 59.9,61.49 57.96,61.49 57.01,60.53 R4025.1
  IN3 w0.102: v2(69.47,79.98) 69.49,79.99 73.13,79.99 75.26,77.86 83.84,77.86 87.5,74.19 90.2,74.19 90.4,74.4 90.9,74.4 v2(91.3,74) 91.08,73.77 91.08,71.68 90.66,71.27 90.66,70.5 91.16,70 92.12,70 93,70.87 94.91,70.87 95.4,70.38 96.55,70.38 96.59,70.34 97.43,70.34 97.81,70.72 101.36,70.72 102.51,71.86 102.51,73.23 102.99,73.72 102.99,74.53 103.63,75.17 108.85,75.17 110.26,73.76 110.26,73.26 110.43,73.09 110.43,72.7 v2(110.86,72.27)
  BOTTOM w0.102: v2(110.86,72.27) 110.79,72.27 110.52,72 UC1.AG7
DP_STEREOSYNC: length 7.6
  BOTTOM w0.102: 88.13,58.43 88.31,58.6 89.75,58.6 89.86,58.49 90.47,58.49 UC1.B23
  BOTTOM w0.117: v3(84.46,59.41) 84.57,59.29 RC17.1 85.04,57.91 86.33,57.91 RC18.1 86.95,58.22 87.92,58.22 88.13,58.43
DVDT_1113: length 3.6
  TOP w0.117: v3(29.7,79.96) 30.2,79.96 30.78,79.39 CT78.1 30.15,78.76 29.72,78.76 29.43,78.46 UT6.10
EC_CLEAR_CMOS#: length 114.4
  TOP w0.117: RC106.1 88.19,7.16 88.56,7.52 88.56,8.09 v3(88.68,8.21) 89.52,9.05 90.08,9.05 v2(90.9,8.23) ; UEC1.15 176.6,38.03 v2(176.93,38.36)
  IN2 w0.127: v2(90.9,8.23) 91.5,8.23 91.96,8.7 92.62,9.35 97.23,9.35 98.39,8.19 101.07,8.19 101.73,7.52 107.31,7.52 108.25,8.46 110.52,8.46 110.6,8.54 111.15,8.54 111.15,8.54 112.61,8.54 112.8,8.73 113.87,8.73 114.47,8.13 114.47,7.66 115.59,6.53 131.55,6.53 132.9,7.89 135.27,7.89 136.33,8.96 137.31,8.96 138.53,10.18 140.3,10.18 140.97,10.85 144.69,10.85 147.71,13.87 147.71,15.37 151.37,19.03 153.69,19.03 155.95,21.29 162.41,21.29 162.68,21.56 166.96,21.56 171.76,26.36 171.76,27.93 172.43,28.61 174.55,28.61 175.96,30.02 175.96,37.39 v2(176.93,38.36)
EC_FAN_PWM1: length 40.8
  TOP w0.117: CF4.1 189.69,63.06 189.17,62.54 v2(189.17,61.02) v3(190.12,61.02) ; v2(177.69,34.21) 177.11,33.63 UEC1.26
  IN2 w0.127: v2(182.27,34.36) 182.11,34.52 178,34.52 v2(177.69,34.21)
  BOTTOM w0.117: v2(189.17,61.02) 189.65,60.53 189.65,60.05 189.39,59.79 189.39,52.92 189.65,52.66 189.65,51.4 189.66,51.39 JFAN2.3 189.37,49.97 189.37,47.85 189.08,47.57 189.08,43.96 186.76,41.63 186.76,39.84 182.27,35.36 v2(182.27,34.36)
EC_FAN_SPEED1: length 44.7
  TOP w0.117: CF3.1 v3(188.7,61.87) 188.7,60.6 v2(189.12,60.18) ; v2(176.77,32.59) 176.53,32.83 UEC1.28 ; R64.1 173.65,34.9 v2(173.88,34.9)
  IN2 w0.127: v2(181.37,33.45) 181.17,33.45 180.31,32.59 v2(176.77,32.59)
  BOTTOM w0.117: v2(189.12,60.18) 189.14,60.15 189.14,53.14 188.41,52.4 JFAN2.2 188.41,48.19 188.84,47.76 188.84,45.37 187.11,43.64 187.11,43.31 186.02,42.22 186.02,39.45 181.37,34.8 v2(181.37,33.45) ; v2(173.88,34.9) 173.93,34.96 174.41,34.96 v2(176.77,32.59)
EC_FP_RST_R: length 115.5
  TOP w0.117: v2(187.27,41.32) 186.48,40.53 182.48,40.53 181.08,41.93 v2(181.02,41.93) ; v2(187.37,34.31) 187.75,34.69 189.59,34.69 189.73,34.83 UEC1.74
  IN1 w0.102: v2(111.74,10) 113.65,10 115.29,11.64 124.18,11.64 124.82,12.27 136.31,12.27 137.39,13.35 137.39,14 v2(137.57,14.18)
  IN3 w0.127: v2(181.02,41.93) 181.72,41.23 181.72,36.85 180.76,35.9 180.76,34.56 180.47,34.27 180.47,33.64 177.33,30.5 173.59,30.5 173.17,30.08 170.29,30.08 169.95,30.42 164.18,30.42 163.6,29.85 160.98,29.85 158.86,27.74 153.36,27.74 152.81,27.18 152.81,26.82 v2(152.72,26.73)
  BOTTOM w0.117: v2(111.74,10) 111.43,10 111.1,9.67 111.1,8.4 111.29,8.21 RFP9.2 ; v2(187.37,34.31) 187.18,34.31 186.8,34.69 186.8,35.96 188.38,37.55 189.14,37.55 189.91,38.31 189.91,40.09 189.4,40.59 188,40.59 v2(187.27,41.32) ; v2(137.57,14.18) 137.89,14.5 138.54,14.5 139.23,15.19 140.57,15.19 142.85,17.48 145.41,17.48 146.66,18.74 148.11,18.74 152.7,23.32 v1(152.7,25.42) 152.7,26.7 v2(152.72,26.73)
EC_LOW_BATT#: length 80.5
  TOP w0.102: v2(176.72,46) 177.2,45.53 UEC1.128
  IN2 w0.102: v2(123.33,78.75) 125.68,78.75 126.21,78.21 130.31,78.21 131.57,76.95 136.13,76.95 136.44,76.65 143.08,76.65 148.19,71.55 148.19,70.92 148.76,70.35 149.34,70.35 152.67,67.02 152.67,66.02 154.14,64.55 158.55,64.55 160.29,62.81 163.29,62.81 167.81,58.29 167.81,56.9 168.84,55.87 168.84,55.34 174.35,49.83 174.35,48.17 176.51,46 v2(176.72,46)
  BOTTOM w0.089: v2(123.33,78.75) 123.14,78.94 RC611.2
  BOTTOM w0.102: UC1.AV6 119.99,73.32 119.99,73.81 120.18,74 120.18,74.22 120.02,74.39 120.02,74.59 120.35,74.92 120.35,75.49 120.7,75.84 121.14,75.84 122.56,77.25 122.56,78.78 RC611.2 ; v1(177.52,46) v2(176.72,46)
EC_MUTE#: length 250.2
  TOP w0.127: UEC1.89 192.27,40.83 192.32,40.79 R56.1 192.94,41.53 v2(192.95,41.55)
  IN1 w0.127: v2(25.67,52.19) 25.76,52.28 27.79,52.28 29.25,50.82 v2(29.25,49.99)
  IN2 w0.102: 92.75,77.88 94.17,77.88
  IN2 w0.127: v2(25.67,52.19) 25.67,51.86 22.95,49.14 22.95,35.8 21.77,34.61 21.77,33.07 19.96,31.26 15.6,31.26 15.24,31.62 11.62,31.62 11.35,31.89 v2(10.77,31.89) ; v2(29.25,49.99) 29.66,50.4 36.57,50.4 45.33,59.16 46.9,59.16 47.4,58.67 50.08,58.67 52.71,61.3 54.65,61.3 59.15,65.8 63,65.8 64.92,67.72 66.41,67.72 67.91,69.22 77.21,69.22 85.87,77.88 92.75,77.88 ; v2(192.95,41.55) 191.98,41.55 190.35,39.92 190.35,36.11 190.69,35.77 190.69,32.96 189.24,31.51 188.56,31.51 178.4,41.67 177.19,41.67 175.45,43.41 175.45,44.06 171.66,47.85 171.66,49.68 167.13,54.21 166.52,54.21 166.01,54.72 166.01,54.99 164.25,56.74 164.25,57.77 161.22,60.8 155.61,60.8 149.77,66.64 149.77,67.12 146.63,70.27 146.63,70.9 142.65,74.87 135.78,74.87 135.27,75.38 130.92,75.38 129.66,76.63 127.05,76.63 126.55,77.14 123.08,77.14 122.34,77.87 115.61,77.87 114.6,76.85 113.83,76.85 113.33,76.35 110.85,76.35 110.09,77.11 107.29,77.11 106.39,78.01 94.3,78.01 94.17,77.88
  BOTTOM w0.127: v2(10.77,31.89) 10.16,31.29 RA8.1 ; v2(192.95,41.55) v1(192.95,40.72)
EC_ON: length 50.2
  TOP w0.117: UEC1.112 183.6,43.68 v2(183.18,43.26) ; PR509.1 v2(171.82,72.8)
  BOTTOM w0.117: v2(183.18,43.26) 183.66,42.78 184.55,42.78 185,43.24 185,44.76 184.79,44.98 184.79,50.25 185.59,51.05 185.59,52.57 186.26,53.24 186.26,63.34 184.12,65.47 184.12,69.4 184.03,69.64 184,69.81 182.95,70.86 182.95,73.5 181.3,75.15 175.95,75.15 173.52,72.73 v1(173.04,72.73) 171.9,72.73 v2(171.82,72.8)
EC_PCIE_WAKE#: length 106.5
  TOP w0.117: v2(186.54,46.69) 186.54,46.93 R57.1 186.03,46.69 185.65,46.31 185.33,46.31 185.2,46.17 UEC1.108 ; RWL14.2 167.31,32.53 167.91,33.13 167.91,33.56 v2(167.88,33.58)
  IN2 w0.127: v2(146.35,59.34) 146.4,59.34 147.11,58.63 147.11,58.22 149.32,56.01 149.32,54.26 149.36,54.22 149.36,53.93 150.56,52.72 150.56,49.64 151.37,48.82 154.12,48.82 154.83,49.54 154.83,52.08 155.9,53.14 160.76,53.14 161.56,52.34 161.56,39.22 161.71,39.07 162.54,39.07 164.06,40.59 166.6,40.59 167.39,39.81 167.39,36 168.62,34.76 168.62,34.32 v2(167.88,33.58)
  IN3 w0.127: v2(186.54,46.69) 186.17,46.32 181.54,46.32 180.6,47.26 179.18,47.26 177.42,45.51 173.25,45.51 172.61,44.87 172.61,43.29 172.99,42.91 176.51,42.91 177.41,42.01 178.4,42.01 178.96,41.45 178.96,41.08 179.49,40.55 179.49,38.3 178.77,37.58 178.77,35.77 178.39,35.39 178.39,34.32 177.75,33.69 175.58,33.69 174.72,32.82 173.16,32.82 173.15,32.83 172.07,34 171.81,34.27 170.35,34.27 169.66,33.58 v2(167.88,33.58)
  BOTTOM w0.117: v2(146.35,59.34) 146.27,59.26 145.91,59.26 144.49,60.69 144.49,62.11 RC617.1
EC_PD_INT: length 191
  TOP w0.117: v2(188.87,35.36) 188.87,35.43 188.98,35.54 189.92,35.54 190.02,35.63 UEC1.76 192.43,35.63 192.98,35.08 R4023.1 ; v2(39.55,89.21) 39.55,88.4 38.79,87.63 UT1.5
  IN1 w0.102: v2(39.55,89.21) 40.23,88.54 42.02,88.54 42.82,87.74 42.82,86.28 42.99,86.1 42.99,85.66 45.31,83.34 49.69,83.34 51.87,81.16 72.23,81.16 73.94,79.44 105.63,79.44 108.63,82.44 117.82,82.44 118.22,82.83 123.1,82.83 123.38,82.56 130.58,82.56 131.51,83.48 137.56,83.48 140.53,80.52 141.19,80.52 142.72,78.99 143.9,78.99 148.28,74.61 149.71,74.61 153.31,71.02 154.17,71.02 160.99,64.19 163.49,64.19 165.27,62.41 165.27,61.56 166.42,60.4 166.42,59.4 167.88,57.94 167.88,57.56 174.82,50.62 174.82,45.95 177.47,43.29 178.2,43.29 180.36,41.13 184.9,41.13 185.41,41.64 185.77,41.64 186.1,41.31 186.1,36.91 188,35.01 188.51,35.01 v2(188.87,35.36)
EC_RSMRST#: length 150.3
  TOP w0.102: UEC1.100 188.4,46.48 188.7,46.78 188.7,46.94 188.83,47.07 C261.1 188.75,47.44 v2(188.1,46.79) ; v2(150.94,26.68) v1(151.6,26.68)
  IN1 w0.102: v2(138.03,71.62) 138.03,71.47 136.43,69.87 126.62,69.87 125.92,70.57 125.09,70.57 124.15,71.51 122.6,71.51 121.99,72.12 118.88,72.12 118.32,71.56 v2(117.95,71.56) ; v2(138.86,71.58) 138.86,71.13 142.65,67.34 146.25,67.34 149.46,64.13 149.46,59.86 149.9,59.42 149.9,51.49 150.62,50.77 150.62,48.76 149.66,47.8 149.66,44.21 148.83,43.39 147.44,43.39 146.46,42.41 146.46,35.69 151.37,30.78 151.37,27.11 v2(150.94,26.68)
  IN3 w0.102: v2(150.94,26.68) 150.89,26.68 149.7,25.48 149.7,24.08 150.44,23.35 153.53,23.35 156.3,20.58 161.46,20.58 162.75,21.87 167.48,21.87 169.88,24.28 173.97,24.28 176.24,26.55 177.59,26.55 178.48,25.66 180.53,25.66 181.78,26.9 181.78,27.97 186.55,32.74 186.55,43.08 187.33,43.86 187.33,44.2 188.4,45.27 188.4,46.5 v2(188.1,46.79)
  BOTTOM w0.102: v2(138.03,71.62) 138.03,71.65 138.14,71.76 RC36.2 138.14,73.14 CC23.2 138.55,73.42 138.86,73.11 v2(138.86,71.58) ; UC1.AR8 117.73,71.56 v2(117.95,71.56)
EC_RST#: length 5
  TOP w0.117: R60.1 178.81,27.78 178.64,27.62 C70.2 ; R60.1 179.11,28.18 178.8,28.49 UEC1.37 ; R60.1 179.58,27.32 179.58,25.91 v3(179.68,25.8)
EC_RX: length 4.6
  TOP w0.117: RWL7.2 172.81,30.13 174.06,30.13 174.26,30.32 v3(174.26,30.37) 174.26,30.74 174.34,30.82 174.34,31.37 174.6,31.63 UEC1.31
EC_RX_R: length 10.4
  TOP w0.117: v3(169.6,31.77) v2(169.6,31.07) 169.71,30.96 169.71,30.51 170.17,30.05 171.06,30.05 RWL7.1
  BOTTOM w0.117: v2(169.6,31.07) 169.6,35.11 171.29,36.8 JWLAN1.32
EC_SCI#: length 110.5
  TOP w0.117: v2(177.96,35.18) 177.96,35.65 177.64,35.97 176.88,35.97 176.81,36.03 UEC1.20
  IN3 w0.102: 124.01,73.74 122.56,73.74 121.5,74.81 119.24,74.81 117.87,76.18 117.54,76.18 117.11,75.75 116.5,75.75 v2(116.27,75.98)
  IN3 w0.117: 124.01,73.74 125.65,73.74 125.84,73.55 128.94,73.55 129.39,73.1 133.55,73.1 135.09,71.56 136.68,71.56 138.6,69.64 139.84,69.64 142.28,67.2 143.24,67.2 147.07,63.38 147.07,62.03 147.74,61.36 147.74,60.18 148.15,59.77 148.15,58.91 147.74,58.5 147.74,55.28 148.94,54.08 148.94,50.48 149.62,49.79 150.41,49.79 151.2,50.58 154.6,50.58 156.71,52.69 156.71,55.84 157.02,56.15 158.54,56.15 158.86,55.83 158.86,55.26 161.7,52.42 161.7,46.9 161.3,46.5 161.3,44.18 161.8,43.67 161.8,41.26 161.16,40.62 161.16,37.84 162.75,36.25 163.94,36.25 166.18,34.02 168.39,34.02 168.64,34.27 169.74,34.27 169.93,34.46 169.93,34.86 170.18,35.1 170.52,35.1 170.89,34.73 171.97,34.73 172.44,34.22 173,33.67 174.96,33.67 175.4,34.11 176.03,34.11 176.32,34.4 176.32,34.42 176.57,34.68 177.21,34.68 177.71,35.18 v2(177.96,35.18)
  BOTTOM w0.089: v2(116.27,75.98) 116.05,75.76 116.05,75.21 116.2,75.07 116.2,74.76 115.88,74.44
  BOTTOM w0.102: UC1.AP4 115.88,74.44
EC_SMB_CK1: length 360.4
  TOP w0.117: R63.2 80.1,5.26 79.62,4.79 v2(79.14,4.79) 79.01,4.65 78.53,4.65 78.29,4.9 78.29,5.6 78.86,6.17 v3(78.86,14.24) 78.86,14.95 79.59,15.68 80.21,15.68 v2(80.76,16.24) ; v2(188.2,35.49) 188.2,35.67 188.57,36.03 UEC1.77 ; UT1.3 39.59,87.33 39.56,87.36 39.56,87.48 40.63,88.56 40.63,89.09 v2(40.8,89.25) ; v2(194.22,29.55) 195.44,30.77 C318.2
  IN3 w0.127: v2(194.22,29.55) 194.33,29.44 194.33,27.9 198.19,24.04 198.19,21.56 196.71,20.08 195.13,20.08 189.61,14.56 149.95,14.56 143.09,7.69 135.03,7.69 132.6,5.25 101.49,5.25 99.99,6.75 98.29,6.75 96.81,8.22 92.94,8.22 88.61,3.89 87.92,3.89 86.85,2.82 82.11,2.82 80.31,4.63 79.29,4.63 v2(79.14,4.79) 78.98,4.63 78.32,4.63 78.2,4.76 78.2,5.59 76.19,7.6 76.19,11.71 71.31,16.59 65.83,16.59 65.35,17.07 36.54,17.07 33.72,19.89 29.3,19.89 27.04,22.15 27.04,25 29.81,27.77 29.81,30.49 31.33,32.01 31.33,39.61 32.22,40.49 33.67,40.49 36.72,43.54 39.3,43.54 42.76,47.01 42.76,51.67 42.45,51.98 v2(42.45,52.17)
  BOTTOM w0.117: v2(79.14,4.79) 79.27,4.65 81.04,4.65 81.64,4.05 81.64,3.28 81.64,2.99 79.91,1.26 51.24,1.26 50.91,1.59 PRB12.1 ; v2(40.8,89.25) 40.8,88.77 40.47,88.44 40.47,87.52 41.43,86.56 41.43,82.75 39.86,81.17 37.14,81.17 35.87,79.9 35.85,79.9 35.38,79.43 35.38,78.08 36.11,77.34 36.11,72.88 37.28,71.72 37.28,55.22 39.14,53.35 41.1,53.35 42.28,52.17 v2(42.45,52.17) ; v2(194.22,29.55) 194.23,29.55 194.39,29.71 194.39,29.95 195.04,30.59 195.04,32.87 193.34,34.57 191.43,34.57 190.08,35.92 188.52,35.92 188.2,35.61 v2(188.2,35.49) ; v2(80.76,16.24) 80.59,16.41 80.59,16.92 80.76,17.1 81.81,17.1 81.92,16.98 PR12.2
EC_SMB_CK2: length 248.5
  TOP w0.117: v2(189.93,36.78) 189.98,36.83 UEC1.79 192.14,36.83 192.2,36.89 192.42,36.89 193.03,36.28 194.06,33.8 v3(194.73,33.13) 194.93,32.92 194.93,32.11 195.25,31.79 195.59,31.79 R273.2
  IN2 w0.127: v2(189.93,36.78) 189.42,37.29 189.42,37.56 188.42,38.57 188.42,39.93 188.93,40.44 189.9,40.44 190.39,40.93 190.39,42.78 190.06,43.11 189.2,43.11 188.81,43.49 188.81,44.07 188.41,44.48 186.07,44.48 184.62,45.93 184.62,47.1 183.56,48.16 181.68,48.16 181.12,48.72 181.12,49.08 180.66,49.54 v2(180.38,49.54)
  IN3 w0.127: v2(83.66,60.79) 83.54,60.66 83.54,60.16 83.66,60.03 84.11,60.03 84.78,59.37 84.78,58.96 86.39,57.35 86.39,55.29 84.71,53.61 83.67,53.61 83.35,53.93 81.26,53.93 80.81,54.37 78.65,54.37 77.08,52.8 77.08,46.3 82.54,40.84 82.54,33.73 83.63,32.64 83.63,19.49 82.9,18.75 82.9,16.77 81.47,15.35 81.47,12.96 82.34,12.1 82.34,7.98 84.09,6.23 88.01,6.23 88.56,6.77 88.56,9.24 89.55,10.22 97.36,10.22 99.28,8.31 100.45,8.31 102.06,6.7 112.1,6.7 112.2,6.6 132.01,6.6 134.47,9.06 142.5,9.06 149.56,16.12 168.2,16.12 171.92,19.84 174.59,19.84 179.02,15.42 186.28,15.42 187.18,16.32 187.18,19.82 188.66,21.31 188.66,27.56 189.22,28.12 189.22,30.95 191.01,32.74 191.01,36.37 190.53,36.86 190,36.86 v2(189.93,36.78)
  BOTTOM w0.102: UC1.B22 90.36,59.62 89.22,59.62 87.85,60.98 87.75,60.98 87.74,61
  BOTTOM w0.117: v2(83.66,60.79) 83.53,60.92 83.53,61.14 83.96,61.57 87.16,61.57 87.74,61 ; UTS1.10 179.93,50.26 180.38,49.81 v2(180.38,49.54)
EC_SMB_DA1: length 362.6
  TOP w0.117: UT1.4 39.19,87.31 39.21,87.34 39.21,87.63 40.29,88.7 40.29,89.11 v2(40.19,89.21) ; C317.2 195.15,29.86 v2(194.83,29.55) ; UEC1.78 190.13,36.43 190.08,36.38 188.43,36.38 187.97,35.92 v2(187.77,35.92) ; R62.2 80.08,4.44 79.4,4.44 v2(79.14,4.18) 79.01,4.31 78.39,4.31 77.94,4.75 77.94,5.75 78.51,6.31 78.51,15.09 79.45,16.03 79.96,16.03 80.08,16.14 v2(80.08,16.29)
  IN3 w0.127: v2(194.83,29.55) 194.68,29.4 194.68,28.05 198.54,24.19 198.54,21.42 196.85,19.73 195.28,19.73 189.76,14.2 150.1,14.2 143.23,7.33 135.18,7.33 132.74,4.89 101.34,4.89 99.84,6.39 98.14,6.39 96.67,7.87 93.08,7.87 88.75,3.54 88.07,3.54 87,2.47 81.96,2.47 80.16,4.27 79.23,4.27 v2(79.14,4.18) 79.04,4.27 78.18,4.27 77.84,4.61 77.84,5.45 75.84,7.45 75.84,11.56 71.16,16.24 65.68,16.24 65.2,16.72 36.39,16.72 33.57,19.54 29.16,19.54 26.69,22.01 26.69,25.15 29.45,27.91 29.45,30.64 30.98,32.16 30.98,39.76 32.07,40.85 33.52,40.85 36.57,43.9 39.15,43.9 42.41,47.16 42.41,51.52 42.17,51.76 v2(42.02,51.76)
  BOTTOM w0.117: v2(187.77,35.92) 188.03,35.92 188.37,36.27 190.23,36.27 191.57,34.92 193.48,34.92 195.38,33.02 195.38,30.45 194.74,29.81 194.74,29.64 v2(194.83,29.55) ; v2(79.14,4.18) 79.27,4.31 80.9,4.31 81.3,3.91 81.3,3.14 79.76,1.6 51.38,1.6 50.56,2.42 PRB10.1 ; v2(80.08,16.29) 80.23,16.29 80.24,16.3 80.24,17.06 80.62,17.44 82.25,17.44 82.47,17.23 82.47,17.03 82.85,16.64 PR11.2 ; v2(42.02,51.76) 42.02,51.95 40.96,53.01 39,53.01 36.93,55.07 36.93,71.57 35.77,72.74 35.77,77.19 35.03,77.93 35.03,79.57 37.13,81.67 39.74,81.67 40.87,82.8 40.87,86.4 39.83,87.44 39.83,88.85 v2(40.19,89.21)
EC_SMB_DA2: length 251.9
  TOP w0.117: R274.2 195.74,32.31 195.56,32.14 195.39,32.14 195.28,32.25 195.28,33.07 194.35,33.99 193.32,36.48 192.56,37.23 UEC1.80 190.09,37.23 v2(189.93,37.39)
  IN2 w0.127: v2(189.93,37.39) 189.78,37.55 189.78,37.71 188.78,38.71 188.78,39.78 189.08,40.09 190.05,40.09 190.74,40.78 190.74,42.93 190.21,43.46 189.34,43.46 189.17,43.64 189.17,44.22 188.56,44.84 186.22,44.84 184.98,46.08 184.98,47.24 183.7,48.52 181.82,48.52 181.47,48.87 181.47,49.23 180.89,49.81 180.89,50.06 v2(180.73,50.21)
  IN3 w0.127: v2(189.93,37.39) 190.11,37.21 190.67,37.21 191.37,36.52 191.37,32.59 189.58,30.8 189.58,27.98 189.02,27.42 189.02,21.16 187.53,19.68 187.53,16.17 186.42,15.06 178.87,15.06 174.45,19.49 172.06,19.49 168.34,15.77 149.71,15.77 142.65,8.7 134.62,8.7 132.16,6.24 112.06,6.24 111.95,6.34 101.92,6.34 100.3,7.96 99.13,7.96 97.22,9.87 89.69,9.87 88.92,9.09 88.92,6.63 88.16,5.87 83.94,5.87 81.98,7.83 81.98,11.95 81.12,12.81 81.12,15.5 82.54,16.92 82.54,18.9 83.28,19.63 83.28,32.49 82.19,33.58 82.19,40.7 76.72,46.16 76.72,52.95 78.51,54.73 80.96,54.73 81.41,54.29 83.5,54.29 83.82,53.97 84.56,53.97 86.03,55.44 86.03,57.2 84.42,58.81 84.42,59.22 83.96,59.68 83.52,59.68 83.18,60.01 83.18,60.66 v2(83.05,60.79)
  BOTTOM w0.102: UC1.D22 90.93,59.5 90.4,60.03 90.4,60.1 90.04,60.47 88.65,60.47 88,61.13 88,61.23 87.98,61.24
  BOTTOM w0.117: 87.98,61.24 87.3,61.92 83.82,61.92 83.19,61.29 83.19,60.92 v2(83.05,60.79) ; v2(180.73,50.21) 180.18,50.76 UTS1.9
EC_SMCA: length 3
  TOP w0.117: v2(81.89,15.07) 80.75,15.07 v3(80.62,14.94)
  BOTTOM w0.117: JBATT1.3 v2(81.89,15.07) 81.89,15.57 81.92,15.6 PR12.1
EC_SMDA: length 2.3
  TOP w0.117: v3(82.72,15.51) 82.72,15.32 v2(82.97,15.07)
  BOTTOM w0.117: JBATT1.4 83.14,14.9 v2(82.97,15.07) 82.88,15.16 PR11.1
EC_THERMTRIP#: length 88.9
  TOP w0.102: UEC1.36 178.4,28.6 v2(178.22,28.43)
  IN1 w0.102: v2(135.7,66.02) 136.55,66.02 139.44,63.12 141.25,63.12 142.14,64.01 143.87,64.01 144.21,64.01 145.86,62.36 145.86,59.24 146.37,58.73 146.37,48.94 143.78,46.34 143.78,42.08 145.34,40.52 145.34,29.13 147.29,27.18 148.15,27.18 148.81,26.52 148.81,26.3 149.63,25.48 150.28,25.48 v2(150.33,25.53)
  IN3 w0.102: v2(150.33,25.53) 150.87,25 153.81,25 156.87,21.94 160.91,21.94 162.2,23.22 166.92,23.22 169.31,25.61 171.24,25.61 173.27,27.64 174.53,27.64 175.55,28.66 176.55,28.66 177.33,27.87 177.66,27.87 v2(178.22,28.43)
  BOTTOM w0.102: RC21.1 135.09,66.02 v2(135.7,66.02)
EC_TX: length 25.2
  TOP w0.117: 168.8,36.07 168.2,36.07 167.94,35.8 v3(167.94,35.71) ; 168.8,36.07 v2(168.85,36.07) ; 168.8,36.07 168.81,36.09 RWL6.2 ; v2(174.31,31.91) 174.31,31.92 174.43,32.03 UEC1.30
  BOTTOM w0.117: v2(168.85,36.07) 168.8,36.02 168.8,33.86 167.46,32.52 167.46,26.7 168.42,25.74 171.36,25.74 173.12,27.5 173.89,27.5 174.19,27.8 174.19,30.29 174.31,30.41 v2(174.31,31.91)
EC_TX_R: length 4.1
  TOP w0.117: v3(169.57,37.81) 169.73,37.66 RWL6.1 169.74,36.78 v2(170.34,36.78) 170.96,36.78 RWL12.2
  BOTTOM w0.117: JWLAN1.30 171.29,37.3 170.77,36.78 v2(170.34,36.78)
ECAGND: length 137.4
  TOP w0.254: v2(192.08,29.38) 192.17,29.29 192.66,29.29 C67.2 ; v2(192.75,33.28) 192.97,33.06 192.97,32.63 L2.2 192.9,32.56 192.74,32.56 192.46,32.83 UEC1.69 ; PH1.2 123.66,54.44 v3(124.36,55.13) 124.96,55.73 127.5,55.73 128.43,56.67 128.89,56.67 130.77,54.79 133.06,54.79 v2(134.05,55.78)
  IN1 w0.254: v2(179.29,53.73) 179.29,52.25 180.13,51.41 181.09,51.41 181.52,50.98 181.52,46.84 182.84,45.52 189.76,45.52 191.84,43.45 191.84,36.63 192.29,36.17 192.29,33.71 192.73,33.28 v2(192.75,33.28)
  BOTTOM w0.254: v2(192.08,29.38) 192.68,29.98 192.68,33.13 192.75,33.2 v2(192.75,33.28) ; v2(134.05,55.78) 135.8,54.03 135.8,51.8 136.67,50.93 136.67,46.65 136.06,46.05 136.06,42.88 137.47,41.48 137.72,41.48 143.78,41.48 144.99,42.69 145.48,42.69 146.43,43.64 149.44,43.64 150.03,44.23 150.44,44.23 151.93,45.73 154.6,45.73 154.61,45.74 155.24,46.36 155.24,55.81 156.66,57.23 156.66,60.64 158.56,62.54 160.32,62.54 163.9,66.12 164.25,66.12 164.8,65.58 164.8,62.26 166.34,60.73 166.34,59.97 167.5,58.81 169.59,58.81 171.64,56.75 172.46,56.75 173.6,55.61 175.14,55.61 176.1,56.57 177.42,56.57 177.66,56.33 178.27,56.33 178.93,55.67 178.93,54.08 v2(179.29,53.73)
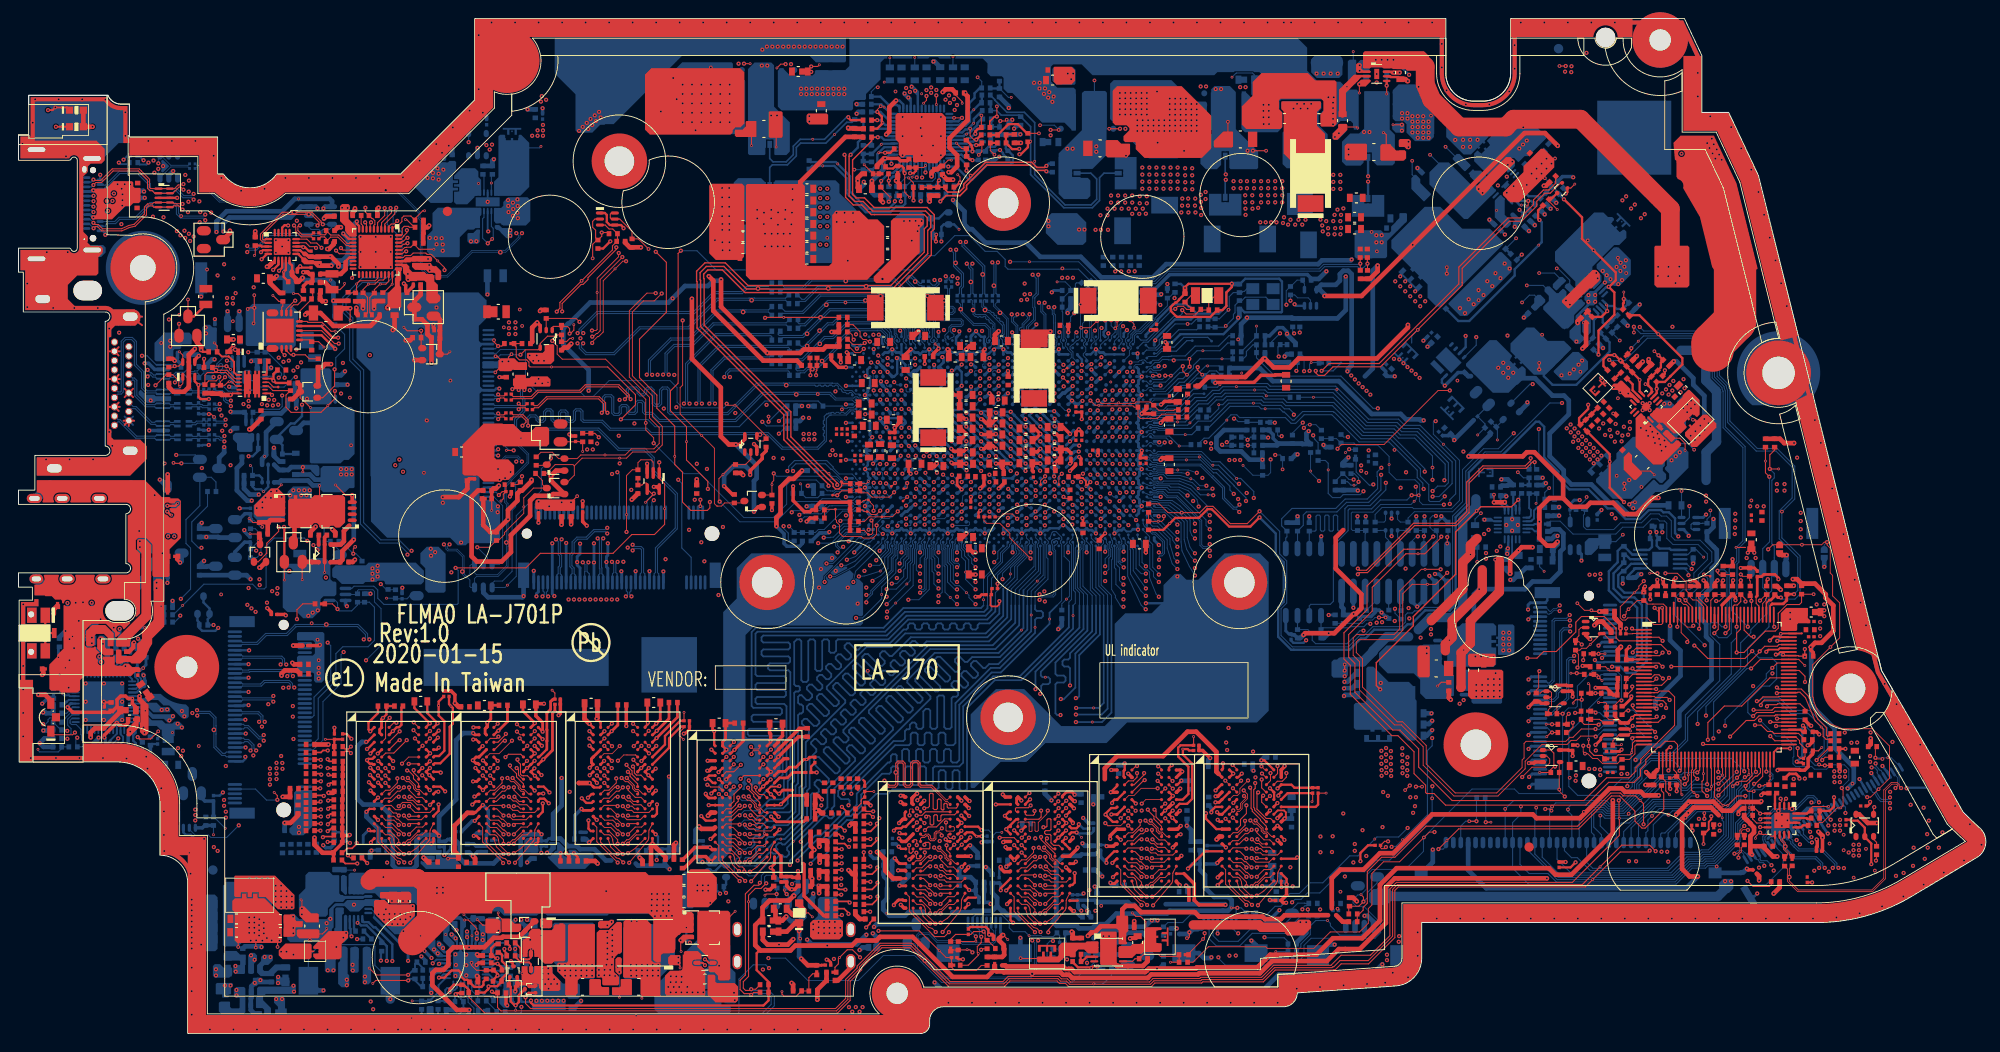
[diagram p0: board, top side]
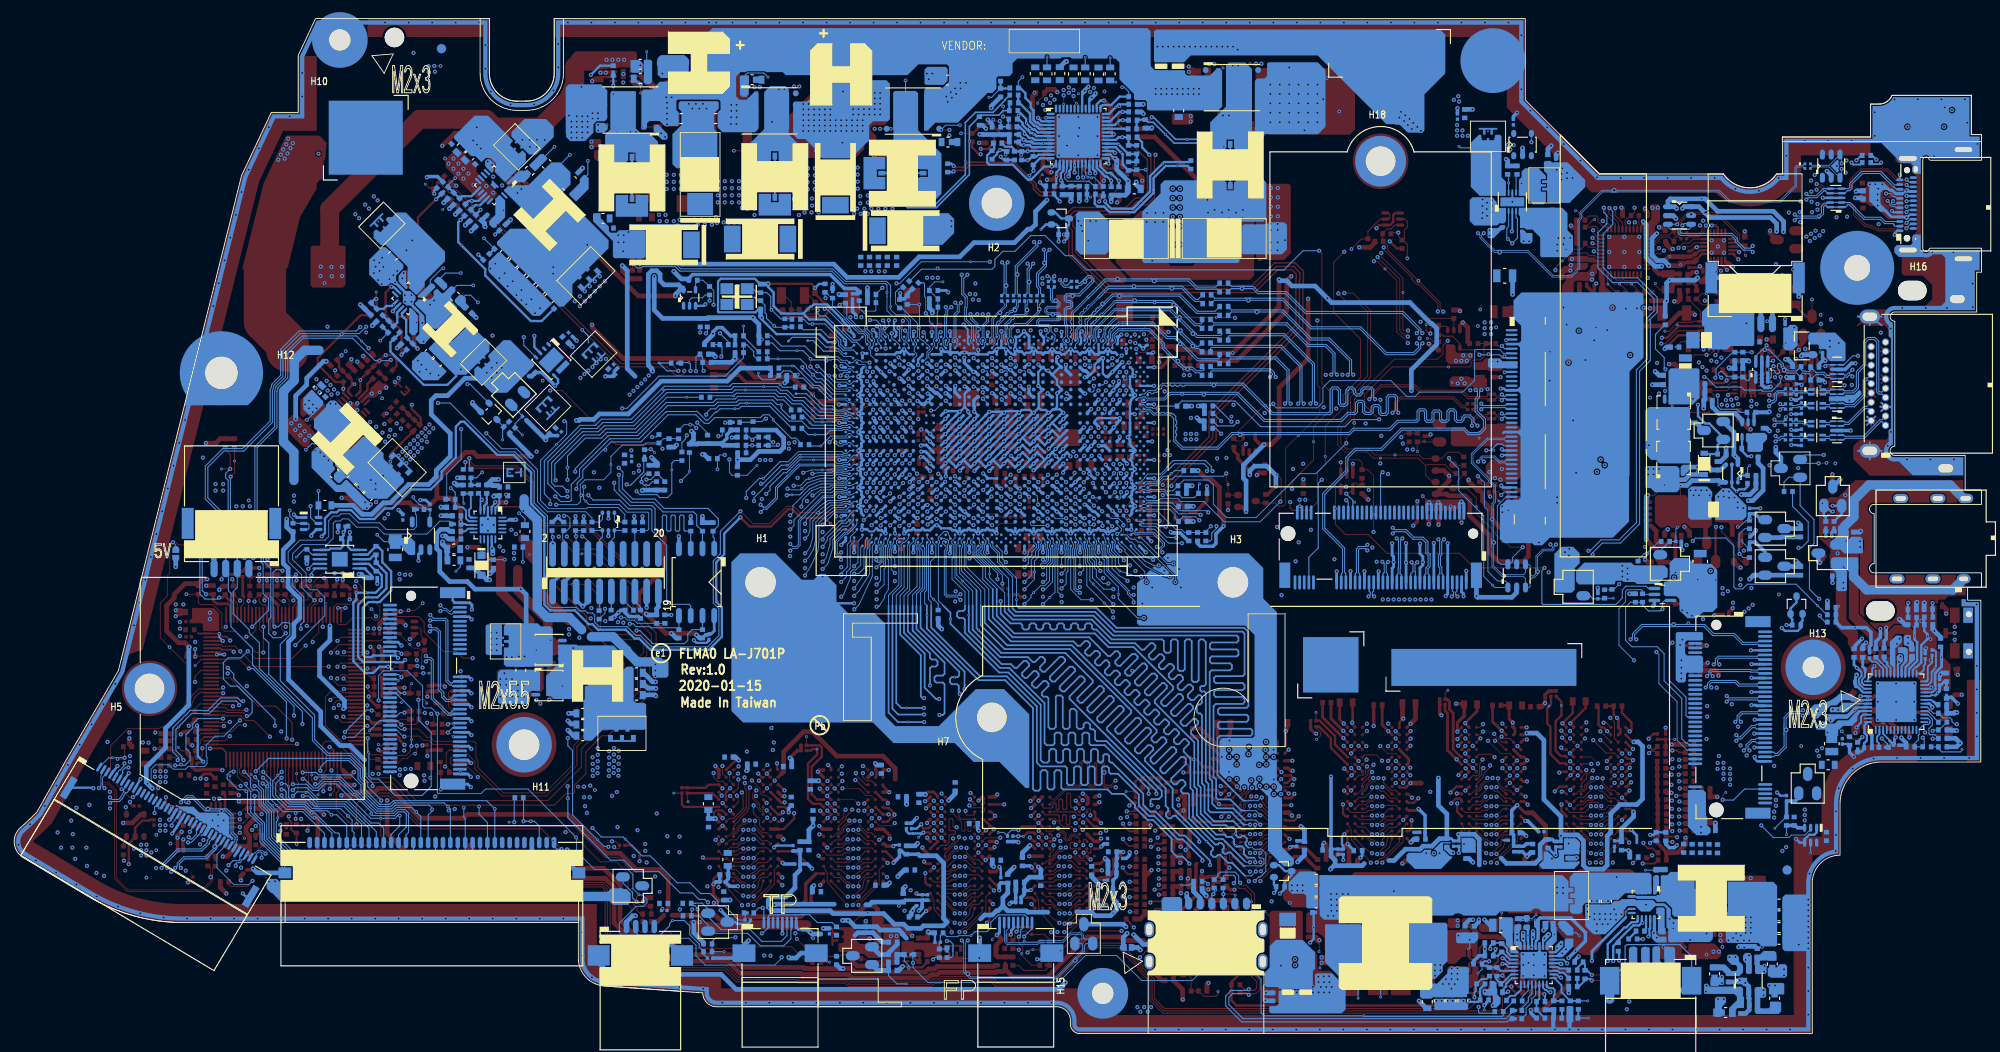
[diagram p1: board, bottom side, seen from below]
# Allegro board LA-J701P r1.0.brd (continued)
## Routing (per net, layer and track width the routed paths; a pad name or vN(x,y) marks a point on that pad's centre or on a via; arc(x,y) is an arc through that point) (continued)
EDP_AUXN: length 50.5
  TOP w0.117: C8.1 53.43,66.64 54.41,66.64 54.82,66.24 54.82,66.07 v2(54.43,65.69)
  BOTTOM w0.102: 87.74,67.06 87.76,67.06 87.77,67.05 87.86,67.14 88,67.14 88.1,67.04 88.26,67.04 88.36,67.14 88.56,67.14 88.66,67.04 88.77,67.04 88.88,67.14 89.09,67.14 89.2,67.04 89.36,67.04 89.8,67.48 90.46,67.48 UC1.B12
  BOTTOM w0.117: v2(54.43,65.69) 54.83,66.08 54.83,66.45 55.23,66.85 55.88,66.85 56.12,66.61 56.12,66.4 56.24,66.28 56.59,66.28 56.71,66.4 56.71,67.22 57.01,67.51 57.49,67.51 57.74,67.27 57.74,66.4 57.86,66.28 58.21,66.28 58.32,66.4 58.32,67.14 58.57,67.39 59.11,67.39 59.35,67.14 59.35,66.4 59.47,66.28 59.82,66.28 59.94,66.4 59.94,67.27 60.19,67.51 60.72,67.51 60.97,67.27 60.97,66.4 61.09,66.28 63.08,66.28 63.94,65.42 67.87,65.42 68.34,64.95 79.81,64.95 79.82,64.97 80.38,64.97 80.39,64.95 80.98,64.95 82.56,63.37 83.47,63.37 84.88,63.37 86.28,63.37 87.04,64.13 87.04,64.52 86.94,64.62 86.94,64.8 87.04,64.9 87.04,65.16 86.91,65.28 86.91,65.49 87.04,65.61 87.04,65.79 86.94,65.89 86.94,66.2 87.04,66.3 87.04,66.71 87.3,66.97 87.44,66.97 87.53,67.06 87.74,67.06
EDP_AUXN_C: length 2.2
  TOP w0.117: v2(51.81,66.4) 52.04,66.63 52.45,66.63 C8.2
  BOTTOM w0.117: JEDP1.20 51.28,66.51 51.42,66.65 51.57,66.65 v2(51.81,66.4)
EDP_AUXP: length 50.5
  TOP w0.117: C9.1 53.43,66.87 54.5,66.87 55.04,66.33 55.04,65.69 v2(55.04,65.69)
  BOTTOM w0.102: UC1.D12 90.93,67.5 90.62,67.2 90.33,67.2 90.23,67.29 89.88,67.29 89.44,66.85 87.77,66.85 87.76,66.84 87.74,66.84
  BOTTOM w0.117: 87.74,66.84 87.62,66.84 87.26,66.47 87.26,64.03 86.38,63.15 84.88,63.15 84.17,63.15 82.46,63.15 80.88,64.73 v4(80.09,64.73) 68.25,64.73 67.78,65.2 63.84,65.2 62.99,66.06 60.99,66.06 60.75,66.3 60.75,67.17 60.63,67.29 60.28,67.29 60.16,67.17 60.16,66.3 59.91,66.06 59.38,66.06 59.13,66.3 59.13,67.05 59.01,67.16 58.66,67.16 58.55,67.05 58.55,66.3 58.3,66.06 57.76,66.06 57.51,66.3 57.51,67.17 57.4,67.29 57.1,67.29 56.93,67.12 56.93,66.3 56.68,66.06 56.15,66.06 55.9,66.3 55.9,66.51 55.78,66.63 55.32,66.63 55.05,66.36 55.05,65.7 v2(55.04,65.69)
EDP_AUXP_C: length 2.2
  TOP w0.117: v2(51.81,67.01) 51.97,66.86 52.43,66.86 C9.2
  BOTTOM w0.117: v2(51.81,67.01) 51.67,66.87 51.46,66.87 51.32,67.01 JEDP1.19
EDP_HPD: length 48.5
  TOP w0.117: v2(65.07,66.38) 66.64,67.95 66.64,69.04 63.64,72.04 v3(57.57,72.04) 55.25,72.04 55.13,72.16 55.13,72.56 54.89,72.8 54.09,72.8 53.76,73.13 53.76,74.2 R6.1 R8.1
  BOTTOM w0.102: UC1.C12 90.51,68 90.19,67.67 89.6,67.67 89.5,67.57 89.22,67.57 88.98,67.81
  BOTTOM w0.117: v2(65.07,66.38) 65.09,66.35 67.99,66.35 68.75,65.59 77.85,65.59 80.62,68.36 86.38,68.36 86.9,67.84 RC10.1 88.98,67.81
EDP_HPD_R: length 2.8
  TOP w0.117: R6.2 52.21,74.3 v2(51.81,74.3) 51.36,74.74 v1(51.36,74.94)
  BOTTOM w0.117: JEDP1.5 51.52,74.01 v2(51.81,74.3)
EDP_TXN0: length 46.7
  TOP w0.117: C11.1 55.72,67.86 56.06,67.86 57.02,68.81 62.75,68.81 63.41,68.15 63.41,67.29 v2(63.62,67.09)
  BOTTOM w0.102: UC1.B11 90.64,68.5 90.72,68.42 90.72,68.28 90.64,68.2 90.31,68.2 90.05,68.47 88.21,68.47 87.77,68.92 87.75,68.92 87.74,68.94
  BOTTOM w0.117: v2(63.62,67.09) 63.6,67.09 63.31,67.38 63.31,68.7 63.42,68.81 63.96,68.81 64.08,68.7 64.08,67.04 64.32,66.8 64.86,66.8 65.11,67.04 65.11,67.63 65.23,67.75 65.59,67.75 65.71,67.63 65.71,67.16 65.95,66.91 66.58,66.91 66.85,67.18 66.85,68.09 66.96,68.21 67.26,68.21 67.4,68.07 67.4,67.16 67.65,66.91 68.38,66.91 69.15,66.14 77.49,66.14 80.43,69.07 v4(84.01,69.07) 87.6,69.07 87.74,68.94
EDP_TXN0_C: length 4.5
  TOP w0.117: v2(54.03,68.08) 54.03,68.07 54.26,67.85 54.72,67.85 C11.2
  BOTTOM w0.117: JEDP1.17 51.29,68.01 51.43,67.87 53.83,67.87 v2(54.03,68.08)
EDP_TXN1: length 49
  TOP w0.117: v2(66.12,68.56) 65.98,68.69 65.98,69 64.87,70.11 61.21,70.11 60.62,69.53 56.05,69.53 55.36,68.83 53.44,68.83 53.23,69.04 C12.1
  BOTTOM w0.102: 87.74,70.07 87.74,70.08 87.82,70.08 87.94,69.96 88.13,69.96 88.25,70.08 88.4,70.08 88.55,69.92 88.55,69.74 88.63,69.66 88.82,69.66 88.92,69.56 88.92,69.45 89.07,69.3 89.32,69.3 89.48,69.14 89.65,69.14 89.79,69.28 89.94,69.28 90.08,69.15 UC1.A11
  BOTTOM w0.117: v2(66.12,68.56) 66.08,68.56 65.87,68.77 65.87,69.54 65.99,69.65 66.65,69.65 66.82,69.48 66.82,69.21 67.12,68.91 67.55,68.91 67.85,69.21 67.85,69.48 68.02,69.65 68.26,69.65 68.43,69.48 68.43,68.06 68.71,67.79 69.22,67.79 69.47,68.04 69.47,69.48 69.64,69.65 70.01,69.65 70.13,69.54 70.13,67.13 70.37,66.88 76.65,66.88 79.84,70.07 v4(82.93,70.07) 86.02,70.07 86.13,69.96 86.33,69.96 86.44,70.07 86.6,70.07 86.72,69.96 86.94,69.96 87.05,70.07 87.19,70.07 87.3,69.96 87.47,69.96 87.58,70.07 87.74,70.07
EDP_TXN1_C: length 2.2
  TOP w0.117: C12.2 52.45,68.92 51.96,68.92 v2(51.81,69.06)
  BOTTOM w0.117: JEDP1.15 51.31,69.01 51.45,68.86 51.61,68.86 v2(51.81,69.06)
EDP_TXP0: length 46.8
  TOP w0.117: v2(63.01,67.09) 63.19,67.27 63.19,68.06 62.66,68.59 57.11,68.59 56.16,67.64 55.72,67.64 C10.1
  BOTTOM w0.102: UC1.D11 91.09,68.69 90.72,68.69 90.6,68.8 90.35,68.8 90.22,68.67 88.3,68.67 87.91,69.06 87.91,69.08 87.89,69.09
  BOTTOM w0.117: v2(63.01,67.09) 63.08,67.17 63.08,68.79 63.33,69.04 64.05,69.04 64.3,68.79 64.3,67.14 64.42,67.02 64.77,67.02 64.89,67.14 64.89,67.72 65.14,67.97 65.68,67.97 65.93,67.72 65.93,67.25 66.05,67.13 66.49,67.13 66.62,67.27 66.62,68.19 66.87,68.43 67.35,68.43 67.63,68.16 67.63,67.25 67.74,67.13 68.47,67.13 69.24,66.36 77.4,66.36 80.33,69.3 83.73,69.3 83.74,69.31 84.31,69.31 84.32,69.3 87.69,69.3 87.89,69.09
EDP_TXP0_C: length 4.5
  TOP w0.117: C10.2 54.74,67.63 54.19,67.63 v2(54.03,67.47)
  BOTTOM w0.117: v2(54.03,67.47) 53.85,67.65 51.45,67.65 51.32,67.51 JEDP1.18
EDP_TXP1: length 49
  TOP w0.117: v2(65.51,68.56) 65.76,68.81 65.76,68.91 64.78,69.89 61.3,69.89 60.71,69.3 56.14,69.3 55.45,68.61 53.37,68.61 C13.1
  BOTTOM w0.102: 87.89,70.29 87.91,70.28 88.47,70.28 89.26,69.49 90.02,69.49 90.4,69.11 90.77,69.11 UC1.C11
  BOTTOM w0.117: v2(65.51,68.56) 65.65,68.7 65.65,69.63 65.9,69.88 66.74,69.88 67.04,69.57 67.04,69.3 67.21,69.13 67.46,69.13 67.63,69.3 67.63,69.57 67.93,69.88 68.36,69.88 68.66,69.57 68.66,68.16 68.8,68.01 69.13,68.01 69.24,68.13 69.24,69.57 69.54,69.88 70.1,69.88 70.35,69.63 70.35,67.22 70.47,67.11 76.56,67.11 79.74,70.29 82.64,70.29 82.65,70.31 83.26,70.31 83.27,70.29 87.89,70.29
EDP_TXP1_C: length 2.2
  TOP w0.117: C13.2 52.42,68.69 52.05,68.69 v2(51.81,68.46)
  BOTTOM w0.117: JEDP1.16 51.33,68.51 51.46,68.64 51.62,68.64 v2(51.81,68.46)
EN_0.675VSP: length 5.4
  BOTTOM w0.117: PRM4.2 164.86,58.48 v1(165.34,58.95)
  BOTTOM w0.203: PUM1.7 163.36,55.36 163.43,55.43 163.47,55.43 163.69,55.66 163.69,56.52 164.05,56.87 PCM2.1 164.86,56.88 PRM4.2
EN_1.8V: length 5.8
  TOP w0.117: v2(173.4,79.39) v3(173.4,80.13)
  TOP w0.254: v2(173.4,79.39) 173.4,78.98 173.32,78.91 173.32,78.29 PR1807.2
  BOTTOM w0.254: PU1802.9 171.71,78.63 172.29,78.63 172.61,78.31 PC9102.1 173.34,78.35 PR1811.1 173.53,79.39 v2(173.4,79.39)
EN_5VALW: length 50.5
  TOP w0.203: v2(191.35,30.8) 191.34,30.82 190,30.82 189.6,30.41 UEC1.64
  TOP w0.254: v2(173.42,57.43) 171.87,58.98 v1(171.87,61.8) 171.87,62.62 169.36,65.13 PR508.1
  IN1 w0.305: v2(191.35,30.8) 191.35,35.72 191.2,35.87 191.2,43.19 189.5,44.89 182.58,44.89 180.89,46.57 180.89,46.94 179.52,48.32 179.52,50.04 177.82,51.75 177.43,51.75 174.79,54.38 174.79,55.58 173.42,56.95 v2(173.42,57.43)
EN_DDR: length 2.3
  BOTTOM w0.203: PUM1.8 163.65,54.96 163.76,55.06 PRM3.2 PCM13.1
ENBKL: length 186.7
  TOP w0.102: QC1.1 78.2,57.35 RC5.1 76.28,57.35 75.93,57 75.53,57 75.43,57 75.17,57.27 75.17,63.26 v3(73.79,64.63) 71.47,66.96 71.47,69.8 71.74,70.07 v2(71.74,77.07) ; v2(60.6,76.92) 60.23,77.28 R4006.2 U2.2
  TOP w0.117: v2(189.65,43.95) 189.6,44 UEC1.97
  IN2 w0.102: v2(189.65,43.95) 189.7,44 189.7,45.24 189.11,45.84 189.11,48.55 189.36,48.8 189.36,50.12 189.11,50.37 189.11,51.55 187.98,52.68 176.09,52.68 174.59,54.18 174.59,55.66 173.02,57.23 173.02,57.32 165.98,64.36 165.98,65.32 164.55,66.76 163.71,66.76 160.3,70.16 160.3,70.81 156.58,74.53 154.94,74.53 152.48,76.99 150.16,76.99 145.75,81.4 141.35,81.4 138.09,84.66 102.45,84.66 101.57,83.77 80.56,83.77 73.85,77.07 v2(71.74,77.07) 60.75,77.07 v2(60.6,76.92)
ENBKL_R: length 12.6
  TOP w0.102: v2(81.58,60.53) 81.58,59.76 81.39,59.57 v3(81.39,59.33) RC6.1 80.31,58.2 QC1.3
  BOTTOM w0.089: 89.11,59.2 89.07,59.2 88.36,59.91 87.74,59.91
  BOTTOM w0.102: v2(81.58,60.53) 81.88,60.23 87.09,60.23 87.4,59.91 87.74,59.91 ; UC1.A22 89.97,59 89.77,59.2 89.11,59.2
ENLDO_3V5V: length 244.6
  TOP w0.117: v2(177.14,73.3) v1(176.7,73.74)
  TOP w0.254: v2(177.14,73.3) PR504.2 177.65,72.76 177.4,72.52 177.4,72 PR506.1 176.41,71.01 PC520.1 176.04,70.68 176.04,70.03 176.39,69.68 176.39,69.28 PU301.8
  IN2 w0.152: v2(177.14,73.3) 179.07,73.3 180.64,71.73 180.64,70.48 184.42,66.69 184.42,62.67 190.67,56.42 190.67,54.08 192.27,52.48 192.27,51.21 196.02,47.47 196.02,42.6 193.19,39.77 192.26,39.77 191.43,38.94 191.43,37.36 191.77,37.02 191.77,32.43 190.87,31.53 190.87,28.99 191,28.86 191,27.69 190.61,27.29 190.61,26.66 191.56,25.71 191.56,22.9 190.61,21.95 190.27,21.95 188.66,20.34 182.38,20.34 178.91,16.87 172.51,16.87 169.49,19.89 164.99,19.89 162.72,17.62 151.9,17.62 149.08,14.8 149.08,13 144.67,8.59 138.75,8.59 137.84,7.68 136.86,7.68 135.8,6.61 133.79,6.61 132.43,5.25 114.3,5.25 113.53,6.03 113.53,6.33 112.65,7.2 111.7,7.2 111.7,7.2 111.15,7.2 111.06,7.12 108.88,7.12 108,6.24 100.75,6.24 100.09,6.91 97.86,6.91 96.7,8.07 93.15,8.07 89.58,4.5 88.84,4.5 86.72,2.39 51.27,2.39 49.89,3.76 44.38,3.76 42.75,5.39 42.75,6.68 42.29,7.14 41.6,7.14 40.91,7.83 v2(40.38,7.83)
  BOTTOM w0.254: v2(40.38,7.83) 40.38,9.65 38.56,11.47 38.37,11.47 37.8,12.03 37.32,12.03 37.14,12.22 PU501.11
ENVDD: length 102.2
  TOP w0.102: v2(57.65,74.86) 58.18,74.33 58.18,73.44 58.74,72.88 63.41,72.88 67.75,68.54 v1(67.75,65.99) 67.75,65.24 68.61,64.38 v2(68.61,63.8)
  IN2 w0.102: v2(57.65,74.86) 60.34,77.55 71.09,77.55 72.1,78.57 72.1,84.64 70.04,86.7 68.22,86.7 57.98,96.93 57.98,98.1 57.06,99.01 51.3,99.01 v2(48.62,96.34)
  BOTTOM w0.102: v2(68.61,63.8) 71.9,60.51 73.6,60.51 78.35,55.76 81.52,55.76 82.97,57.21 82.97,59.29 83.51,59.82 86.17,59.82 RC8.1 86.8,59.2 87.35,58.65 87.69,58.65 87.71,58.63 87.91,58.63 87.91,58.63 88.06,58.63 88.23,58.79 89.83,58.79 89.86,58.76 89.88,58.76 89.94,58.7 90.2,58.7 90.33,58.82 90.59,58.82 90.91,58.5 UC1.D23 ; U5.4 v2(48.62,96.34)
ESPI_ALERT#: length 9.2
  BOTTOM w0.089: UC1.BC11 122.44,68.66 124.14,68.66 124.22,68.75
  BOTTOM w0.117: 124.22,68.75 125.52,70.04 126.12,70.04 128.23,72.15 v3(128.44,72.15) 129.67,72.15 RC616.2
EXT_MIC_RING2:
  vias: v2(7.93,42.79) v2(7.93,42.18) v2(8.74,40.73) v2(8.92,40.15)
EXT_MIC_SLEEVE:
  vias: v2(8.84,42.66) v2(9.12,42.11)
FB_1.8V: length 4
  BOTTOM w0.254: PR1809.1 172.1,77.02 PR716.2 172.06,76.97 PR1808.1 171.12,76.83 171.12,77.95 PU1802.11
FB_CPU: length 6.4
  TOP w0.117: PC807.2 101.9,95.64 v3(101.31,96.23)
  TOP w0.254: PC807.2 102.38,94.82 PC808.1 102.73,94.47 102.96,94.47 v2(103.04,94.39)
  BOTTOM w0.254: PR805.2 103.62,94.37 103.06,94.37 v2(103.04,94.39) 102.96,94.39 102.56,94.8 PR806.1 102.05,94.8 101.86,94.99 PU801.12
FB_DDR: length 5
  BOTTOM w0.117: PRM9.1 164,57.37 v3(163.92,57.29)
  BOTTOM w0.203: PUM1.6 163.16,55.76 163.36,55.96 163.36,56.6 163.17,56.79 PRM2.1 PRM9.1
FB_VDDP: length 10.5
  IN3 w0.254: v2(162.13,89.02) 161.06,87.95 161.06,85.39 162.27,84.18 v2(162.37,84.18)
  BOTTOM w0.254: PU601.14 162.16,89.53 v3(162.33,89.53) 162.68,89.53 PR606.1 PR609.1 162.61,88.52 162.13,89 v2(162.13,89.02) ; v2(162.37,84.18) 161.83,83.64 PR611.2
FBA_CPU: length 5.5
  BOTTOM w0.254: PC829.2 91.32,94.2 PR831.2 PR832.1 91.26,95.07 PC830.1 92.16,95.07 v3(93.19,96.1) 93.26,96.17 94.57,96.17 PU801.31
FN_LED#: length 54.6
  TOP w0.117: UEC1.1 174.42,43.63 v2(174.29,43.77) ; v2(158.49,22.84) v3(159.05,22.84)
  IN3 w0.127: v2(174.29,43.77) 175.35,44.84 181.35,44.84 182.08,44.1 182.08,43.76 183.54,42.31 183.54,36.22 181.85,34.53 181.85,33.09 178.25,29.48 175.19,29.48 174.79,29.09 167.5,29.09 167.32,29.27 164.8,29.27 164.51,28.97 164.51,26.62 160.72,22.84 v2(158.49,22.84)
  BOTTOM w0.117: R266.1 158.49,25.42 v2(158.49,22.84)
FN_LED#_R: length 7
  TOP w0.117: v2(157.49,22.94) v1(156.7,22.94)
  BOTTOM w0.117: JKB2.32 155.79,22.41 156.32,22.94 v2(157.49,22.94) 157.49,25.46 R266.2
FP_DELINK: length 7.6
  TOP w0.117: RFP12.2 100.69,10.18 101.22,10.71 CFP4.1 102.87,10.71 103.18,11.02 v2(104.25,11.02) 104.41,10.86 104.41,10.3 RFP8.2 104.67,10.08 105.52,9.23 RFP4.1
  BOTTOM w0.117: JFP1.5 104.07,11.13 104.18,11.02 v2(104.25,11.02)
FP_GPIO_AL0: length 131.9
  TOP w0.102: CFP3.1 100.78,7.41 RFP6.1 ; RFP3.1 104,7.36 ; v3(99.46,8.94) 100.19,8.21 100.77,8.21
  TOP w0.117: v2(184.88,32.09) 186.62,33.83 187.51,33.83 188.01,34.33 189.69,34.33 189.7,34.34 189.7,34.34 189.78,34.42 189.94,34.42 189.95,34.43 UEC1.73 ; RFP6.1 100.8,7.14 101.13,6.81 103.46,6.81 104,7.36 ; v3(99.46,8.94) 97.31,11.09 v2(92.89,11.09) ; 100.77,8.21 CFP3.1
  IN2 w0.102: v2(184.88,32.09) 184.88,31.32 183.12,29.57 183.12,25.82 182.57,25.26 182.14,25.26 180.41,23.54 180.41,20.62 178.36,18.57 v2(178.2,18.57)
  IN3 w0.102: v2(92.89,11.09) 92.99,10.99 97.3,10.99 98.81,9.48 99.98,9.48 102.27,7.19 112.42,7.19 112.53,7.09 115.52,7.09 116.1,7.66 124.49,7.66 124.76,7.4 127.92,7.4 128.22,7.09 131.8,7.09 134.27,9.56 140.47,9.56 144.03,13.12 145.87,13.12 149.46,16.72 163.24,16.72 163.74,17.21 168.59,17.21 171.71,20.34 174.8,20.34 176.56,18.57 v2(178.2,18.57)
FP_GPIO_AL0_R: length 6.3
  TOP w0.117: v2(103.99,10.46) 103.99,9.82 103.56,9.4 103.56,8.75 v3(103.67,8.64) 103.67,8.46 102.59,7.38 RFP6.2
  BOTTOM w0.117: v2(103.99,10.46) 103.79,10.66 103.79,11.19 103.56,11.42 JFP1.6
FP_GPIO_SCL: length 111
  TOP w0.117: RFP12.1 RFP11.1 101.53,9.04 102.44,9.04 v3(102.47,9.06) 102.49,9.04 102.77,9.04 v2(103.04,8.77) ; UEC1.83 189.17,38.43 186.12,35.39 184.26,35.39 182.48,33.61 v2(182.48,31.74)
  IN2 w0.127: v2(177.47,19.65) 177.47,19.98 178.27,20.78 178.27,24.16 180.56,26.44 180.56,29.07 182.48,30.98 v2(182.48,31.74)
  IN3 w0.127: v2(177.47,19.65) 177.47,20.16 176.88,20.76 171.54,20.76 168.6,17.82 163.76,17.82 163.07,17.14 148.57,17.14 146.99,15.56 146.99,15.37 145.16,13.54 143.45,13.54 139.88,9.97 134.09,9.97 131.68,7.56 128.57,7.56 128.05,8.08 114.66,8.08 114.08,7.51 112.7,7.51 112.6,7.61 104.19,7.61 v2(103.04,8.77)
FP_GPIO_SCL_R: length 4.3
  TOP w0.117: v2(103.41,10.49) v3(103.41,9.98) 103.36,9.94 RFP11.2
  BOTTOM w0.117: v2(103.41,10.49) 102.56,11.33 JFP1.8
FP_LED#: length 21.7
  TOP w0.117: UEC1.85 192.35,39.23 192.97,38.61 v2(192.97,37.99)
  IN2 w0.127: v2(192.97,37.99) 193.05,37.99 197.72,33.32 197.72,32.28 196.92,31.48 196.92,30.22 198.35,28.79 198.35,27.25 198.63,26.97 198.63,25.13 v2(197.34,23.83)
  BOTTOM w0.117: v2(197.34,23.83) 197.34,24.47 JIO1.16
FP_RST: length 14
  BOTTOM w0.102: 111.64,10.47 110.59,10.47 110.48,10.57 109.95,10.57 109.95,10.57 109.63,10.57 109.63,10.57 109.17,10.57
  BOTTOM w0.117: RFP9.1 RFP10.2 112.56,9.76 CFP2.1 112.46,10.58 RFP5.1 111.76,10.47 111.64,10.47 ; JFP1.7 103.07,12.53 103.36,12.82 106.21,12.82 107.02,12.01 107.02,11.42 107.43,11 108.73,11 v3(109.16,10.57) 109.17,10.57
GPIO_RESERVE: length 12.6
  BOTTOM w0.089: UC1.BB12 121.99,68 122.2,68.21 122.39,68.21 122.66,68.48 124.22,68.48
  BOTTOM w0.117: 124.22,68.48 124.43,68.48 125.73,69.78 126.23,69.78 127.28,70.83 127.89,70.83 128.13,71.07 RC615.1 128.64,71.61 129.4,71.61 129.89,71.13 RC614.1 129.91,71.11 130.36,70.66 131.71,70.66 132.12,71.08 v3(132.12,71.38)
H_PROCHOT#: length 175.4
  TOP w0.102: v2(186.03,49.61) 186.24,49.41 C232.1 186.99,48.98 187.05,48.91 R4002.2
  IN1 w0.102: v2(83.24,54.82) 86.2,54.82 87.9,56.52 90.06,56.52 90.44,56.14 90.44,54.77 92.02,53.19 122.83,53.19 125.89,56.26 125.89,60.66 126.28,61.04 128.44,61.04 128.74,60.74 131.79,60.74 132.22,60.6 132.43,60.6 134.59,59.85 136.36,59.85 142.03,54.18 142.03,41.64 143.84,39.82 143.84,28.47 148.46,23.85 v2(150.64,23.85)
  IN3 w0.102: v2(186.03,49.61) 187.62,48.02 187.62,46.41 187.77,46.26 187.77,45.57 186.05,43.85 186.05,33.86 184.31,32.12 184.31,31.77 180.71,28.17 179.82,28.17 178.68,27.03 176.74,27.03 176.47,27.3 175.59,27.3 173.05,24.76 169.68,24.76 167.28,22.36 162.52,22.36 161.26,21.1 156.49,21.1 153.74,23.85 v2(150.64,23.85)
  BOTTOM w0.102: UC1.B25 90.37,56.5 90.33,56.46 89.01,56.46 87.02,54.48 86.61,54.48 86.4,54.48 86.07,54.15 CC17.2 RC28.2 RC602.1 83.79,54.27 v2(83.24,54.82)
HDA_BIT_CLK: length 10.2
  BOTTOM w0.089: RC54.2 116.91,78.48 116.92,78.48 117.31,78.87 117.31,79.65
  BOTTOM w0.102: UC1.AN6 115.37,72.9 115.01,73.26 115.01,73.45 115.28,73.72 115.28,74.15 115.04,74.39 115.04,74.62 115.24,74.82 115.24,75 114.94,75.3 114.94,76.75 116.6,78.42 RC54.2
  BOTTOM w0.117: 117.31,79.65 117.31,80.11 116.95,80.47 116.66,80.47 RC67.2
HDA_BIT_CLK_R: length 171.9
  TOP w0.117: v2(71.54,84.6) 71.25,84.3 71.25,70.28 70.42,69.45 70.42,67.31 72.15,65.58 v3(72.15,63.96) 72.15,61.98 74.46,59.68 74.46,58.87 v2(74.46,58.86)
  IN3 w0.117: v2(6.34,31.97) 6.84,32.47 10.41,32.47 11.61,33.66 11.61,33.84 12.03,34.26 12.03,34.8 15.03,37.8 15.03,41.33 18.08,44.38 18.36,44.38 24.12,50.14 25.6,50.14 26.01,49.73 26.34,49.73 27.46,48.61 28.57,48.61 29.06,48.11 39.4,48.11 40.35,49.07 40.35,53.93 43.36,56.94 49.28,56.94 50.12,57.78 52.39,57.78 52.94,57.23 54.07,57.23 55.54,58.7 63.77,58.7 64.23,59.16 64.63,59.16 66.18,60.71 69.28,60.71 69.92,60.08 69.92,59.9 70.88,58.93 74.39,58.93 v2(74.46,58.86)
  BOTTOM w0.117: v2(71.54,84.6) 73.28,84.6 75.35,82.53 96.69,82.53 98.23,84.07 98.96,84.07 101.13,86.24 102.71,86.24 104.41,84.54 105.7,84.54 106.57,83.66 106.57,82.91 106.87,82.61 114.49,82.61 115.72,81.38 115.76,81.38 RC67.1 ; v2(6.34,31.97) 6.19,31.82 6.19,31.14 RA4.1 CA31.1 7.22,31.34 6.82,31.73 6.82,32.23 6.74,32.31 6.74,32.88 6.22,33.4 5.72,33.4 5.57,33.55 5.57,33.66 5.57,33.66 5.57,33.85 5.77,34.06 UA1.14
HDA_RST#: length 8.4
  BOTTOM w0.102: UC1.AM6 114.22,72.7 113.9,73.02 113.9,73.66 113.58,73.98 113.58,74.22 113.83,74.47 113.9,74.47 114.33,74.9 114.43,74.9 114.71,75.18 114.71,77.5 114.72,77.51 v1(114.72,78.8) RC50.2
HDA_SDIN0: length 146.6
  IN2 w0.102: v2(114.04,77.86) 113.64,78.25 113.01,78.25 112.82,78.06 110.53,78.06 109.74,78.85 108.14,78.85 107.57,79.42 98.46,79.42 98.23,79.65
  IN2 w0.117: v2(26.03,49.09) 28.74,51.81 32.61,51.81 35.76,54.96 38.09,54.96 48.34,65.21 52.74,65.21 52.84,65.31 53.25,65.31 53.56,65.61 53.56,66.22 55.82,68.48 56.75,68.48 58.31,70.05 60.24,70.05 62.03,71.83 63.9,71.83 64.9,72.82 72.3,72.82 72.58,72.54 74.85,72.54 82.54,80.22 97.65,80.22 98.23,79.65
  IN3 w0.117: v2(5.26,32.71) 5.73,32.24 5.73,31.66 5.94,31.45 11.01,31.45 11.27,31.7 11.27,32.44 12.23,33.4 12.23,33.58 12.65,34 12.65,34.54 15.65,37.54 15.65,40.79 24.38,49.52 25.31,49.52 25.73,49.09 v2(26.03,49.09)
  BOTTOM w0.089: 113.14,76.47 113.03,76.37 113.03,75.18 113.2,75.01 113.2,74.76 113.07,74.63 113.07,74.31 113.33,74.06 113.33,73.93 113.71,73.55 113.71,73.36 113.72,73.35 113.72,73.05 113.37,72.71 UC1.AL6 ; 114.16,79.65 114.04,79.52 v2(114.04,77.86)
  BOTTOM w0.108: 114.04,77.83 113.64,77.44 113.64,76.98 113.14,76.47
  BOTTOM w0.117: RC53.2 114.28,81.13 114.16,81.02 114.16,79.65 ; RA2.1 4.58,32.81 CA33.1 5.16,32.81 v2(5.26,32.71) ; 114.04,77.83 v2(114.04,77.86)
HDA_SDIN0_R: length 2.1
  BOTTOM w0.117: RA2.2 5.06,34.05 5.06,34.1 5.81,34.86 UA1.16
HDA_SDOUT: length 27.9
  IN1 w0.102: v2(136.12,73.17) 135.53,73.17 134.89,72.52 133.52,72.52 133.49,72.55 125.67,72.55 125.01,73.21 121.89,73.21 121.48,72.8 121.02,72.8 120.52,73.31 118.96,73.31 118.66,73 117.58,73 117.28,72.7 116.81,72.7 116.53,72.98 115.3,72.98 114.97,72.65 114.71,72.65 114.07,72.01 113.12,72.01 v2(112.87,72.27)
  BOTTOM w0.102: UC1.AK6 112.44,72.7 v2(112.87,72.27)
  BOTTOM w0.117: v2(136.12,73.17) 136.04,73.25 136.04,74.21 RC68.2 RC71.2
HDA_SDOUT_R: length 169
  IN2 w0.102: 124.63,77.74 124.01,78.36 123.18,78.36 123.05,78.49 118.9,78.49 118.81,78.4 115.41,78.4 114.28,77.27 110.74,77.27 109.57,78.45 107.97,78.45 107.4,79.01 93.03,79.01
  IN2 w0.117: 124.63,77.74 127.34,77.74 127.49,77.59 130.06,77.59 131.32,76.34 135.88,76.34 136.26,75.95 v2(136.26,75.67) ; v2(24.85,48.15) 24.97,48.02 26.27,48.02 28.97,50.73 36.44,50.73 45.32,59.61 46.28,59.61 48.4,61.73 52.34,61.73 52.8,62.18 52.8,62.92 53.53,63.65 55.65,63.65 58.75,66.76 59.57,66.76 61.24,68.43 62.84,68.43 64.6,70.18 76.79,70.18 85.6,78.99 93.01,78.99 93.03,79.01
  IN3 w0.117: v2(24.85,48.15) 22.96,46.25 22.96,43.44 21.19,41.67 21.19,38.72 21.19,38.37 19.48,36.67 15.97,36.67 13.5,34.19 13.5,33.65 13.09,33.25 13.09,32.4 13.28,32.21 13.28,32.2 13.33,32.16 13.33,31.81 12.13,30.61 5.48,30.61 v2(2.66,33.43)
  BOTTOM w0.117: v2(136.26,75.67) 135.37,74.78 RC68.1 ; UA1.17 5.85,35.26 5.21,34.61 CA32.1 4.15,34.11 3.39,34.11 3.19,33.91 3.19,33.71 2.87,33.39 2.7,33.39 v2(2.66,33.43)
HDA_SPKR: length 208.6
  TOP w0.102: v2(142.47,63.2) 142.47,63.23 142.9,63.66 147.5,63.66 153.34,69.5 v2(154.6,69.5)
  IN1 w0.102: v2(142.47,63.2) 141.58,62.31 139.11,62.31 138.41,63.01 137.73,63.01 136.75,63.99 135.97,63.99 135.39,64.57 135.39,64.58 135.15,64.81 135.14,64.81 134.32,65.64 130.96,65.64 130.34,66.25 124.02,66.25 123.65,66.62 120.98,66.62 120.64,66.96 117.97,66.96 117.64,67.29 117.64,67.8 117.77,67.92 117.77,69.11 v2(117.39,69.49)
  IN2 w0.102: v2(154.6,69.5) 154,69.5 150.34,73.16 150.33,73.16 149.6,73.89 148.17,73.89 143.73,78.33 143.73,78.33 143.59,78.47 140.32,78.47 138.65,80.14 138.23,80.14 136.51,81.87 136.42,81.96 125.77,81.96 125.68,81.87 123.3,81.87 121.01,79.58 117.96,79.58 116.82,80.73 109.52,80.73 109.26,80.47 107.99,80.47 107.56,80.04 ; 98.72,80.04 97.74,81.02 82.46,81.02 74.72,73.28 73.02,73.28 72.86,73.44 64.64,73.44 63.65,72.45 61.77,72.45 60.08,70.76 58.15,70.76 56.5,69.1 53.19,69.1 52.09,68 50.17,68 47.95,65.78 47.95,65.69 37.84,55.57 33.51,55.57 v2(31.18,53.24)
  IN2 w0.117: 107.56,80.04 98.72,80.04
  BOTTOM w0.102: UC1.AR11 117.39,69.41 v2(117.39,69.49)
  BOTTOM w0.117: RA29.1 16.72,45.26 v3(17.73,46.27) 20.02,48.56 25.29,48.56 25.79,48.05 26.55,48.05 26.74,48.25 26.74,52.69 27.6,53.55 30.88,53.55 v2(31.18,53.24)
HDA_SYNC: length 31.6
  TOP w0.102: v2(91.96,74.78) 91.79,74.78 91.56,75.01 91.23,75.01 90.9,75.34 90.9,75.85 90.21,76.54
  TOP w0.117: 90.21,76.54 90.14,76.61 RC70.2 RC69.2
  IN2 w0.102: 109.74,74.88 107.28,74.88 106.53,75.63 106.53,76.27 105.92,76.88 94.91,76.88 93.05,75.01 92.19,75.01 v2(91.96,74.78)
  IN2 w0.127: 109.74,74.88 111.52,73.11 113.76,73.11 114.28,72.58 114.28,72.21 114.51,71.98 114.51,71.73 114.63,71.61 v2(114.82,71.61)
  BOTTOM w0.102: UC1.AN8 114.99,71.58 114.85,71.58 v2(114.82,71.61)
HDA_SYNC_R: length 113.5
  TOP w0.117: v2(80.64,77.35) 80.69,77.4 v3(82.66,77.4) RC69.1
  IN2 w0.117: v2(26.05,48.47) 26.05,48.51 28.92,51.38 33.15,51.38 36.31,54.53 38.27,54.53 48.11,64.38 52.5,64.38 53.02,64.89 54.87,64.89 55.77,65.79 55.77,66.79 58.6,69.62 60.42,69.62 62.2,71.41 64.08,71.41 64.99,72.32 71.83,72.32 72.36,71.8 75.09,71.8 v2(80.64,77.35)
  IN3 w0.117: v2(5.27,31.86) 5.24,31.83 5.24,31.56 5.77,31.03 11.25,31.03 12.11,31.88 12.11,31.91 12.65,32.45 12.65,33.41 13.07,33.83 13.07,34.37 15.79,37.09 19.31,37.09 20.77,38.55 20.77,41.85 22.54,43.61 22.54,46.66 24.49,48.61 25.1,48.61 25.24,48.47 v2(26.05,48.47)
  BOTTOM w0.117: v2(5.27,31.86) 4.69,31.86 CA30.1 5.05,32.29 5.54,32.29 5.68,32.42 5.68,32.95 5.31,33.32 5.31,33.98 5.79,34.46 UA1.15
HDMI_CLKN: length 2.5
  BOTTOM w0.117: CH2.2 20.41,67.86 19.96,67.86 19.84,67.98 19.64,67.98 RH9.1 19.24,67.96 18.83,67.96 18.69,68.1 LH1.1
HDMI_CLKP: length 2.5
  BOTTOM w0.117: LH1.4 18.61,67.6 18.75,67.74 19.29,67.74 RH8.1 19.62,67.75 19.75,67.75 19.86,67.64 20.43,67.64 CH1.2
HDMI_CTRL_CLK: length 24.9
  IN3 w0.127: v2(13.94,71.01) 14.05,71.12 14.62,71.12 15.12,71.62 15.12,74.11 13.98,75.25 11.54,75.25 10.95,74.66 10.95,73.42 10.75,73.21 10.75,73.11 JHDMI1.15
  BOTTOM w0.117: QH2.3 22.99,70.82 22.82,70.82 22.7,70.94 22.7,71.57 22.59,71.69 22.41,71.69 22.31,71.59 22.31,71.46 22.15,71.3 21.93,71.3 21.82,71.41 21.82,71.66 22.04,71.88 22.04,72.3 21.92,72.41 21.78,72.41 21.64,72.27 21.64,72.02 v4(21.32,71.7) 21.01,71.38 19.98,71.38 RH25.2 19.49,71.24 19.34,71.38 19.1,71.38 19.03,71.31 18.59,71.31 18.47,71.19 CH14.1 17.86,71.24 17.09,71.24 16.74,70.9 16.37,70.9 16.25,70.77 DH1.9 DH1.1 14.97,70.77 14.8,70.94 14.51,70.94 14.27,71.18 14.1,71.18 v2(13.94,71.01)
HDMI_CTRL_DAT: length 24.9
  IN3 w0.127: v2(13.94,71.72) 13.94,71.64 14.23,71.35 14.52,71.35 14.89,71.71 14.89,74.02 13.88,75.02 11.64,75.02 11.18,74.57 11.18,73.32 10.98,73.12 10.98,72.94 11.1,72.81 11.5,72.81 JHDMI1.16
  BOTTOM w0.117: QH2.6 24.38,73.22 23.69,73.91 v4(23.41,73.91) 22.96,73.91 21.42,72.37 21.42,72.13 20.9,71.61 19.96,71.61 RH26.2 19.49,71.77 19.32,71.6 19.01,71.6 18.93,71.53 18.64,71.53 18.47,71.7 CH13.1 17.91,71.47 16.99,71.47 16.65,71.12 16.43,71.12 16.28,71.27 DH1.8 DH1.2 14.9,71.27 14.79,71.17 14.6,71.17 14.36,71.4 14.26,71.4 v2(13.94,71.72)
HDMI_HPD: length 12.1
  TOP w0.117: RH16.1 16.75,72.01 v2(16.87,72.13) 17.3,72.13 QH1.6 17.74,73.31 v3(17.38,73.68)
  IN2 w0.117: v2(13.34,73.25) 13.34,73.25 13.34,74.81 12.68,75.46 11.17,75.46 10.44,74.73 JHDMI1.19
  BOTTOM w0.117: v2(13.34,73.25) 13.9,73.25 14.87,72.27 DH1.4 DH1.7 16.72,72.27 v2(16.87,72.13)
HDMI_L_CLKN: length 7.7
  BOTTOM w0.117: JHDMI1.12 12.3,70.84 12.53,70.84 12.78,70.59 12.78,68.99 13.81,67.96 14.74,67.96 14.87,68.1 DH3.2 DH3.8 16.28,68.1 16.42,67.96 16.76,67.96 16.9,68.1 LH1.2
HDMI_L_CLKP: length 7.7
  BOTTOM w0.117: LH1.3 16.9,67.6 16.77,67.74 16.45,67.74 16.31,67.6 DH3.9 DH3.1 14.85,67.6 14.71,67.74 13.71,67.74 12.56,68.9 12.56,70.5 12.44,70.62 12.3,70.62 JHDMI1.10
HDMI_L_TX_N0: length 17.5
  BOTTOM w0.117: JHDMI1.9 10.76,69.34 11.01,69.34 11.09,69.42 11.09,74.82 11.5,75.23 12.3,75.23 12.73,74.79 12.73,72.33 13.52,71.54 13.52,69.84 13.9,69.45 14.84,69.45 14.98,69.6 DH3.5 DH3.6 16.29,69.6 16.43,69.46 16.74,69.46 16.88,69.6 LH2.2
HDMI_L_TX_N1: length 6.3
  BOTTOM w0.117: LH3.2 16.87,66.16 16.74,66.03 16.41,66.03 16.28,66.17 DH2.1 DH2.9 14.82,66.17 14.71,66.06 14.41,66.06 12.71,67.75 12.39,67.75 JHDMI1.6
HDMI_L_TX_N2: length 7.9
  BOTTOM w0.117: LH4.2 16.92,64.67 16.79,64.54 16.43,64.54 16.3,64.67 DH2.4 DH2.7 14.92,64.67 14.81,64.56 12.75,64.56 10.98,66.34 10.76,66.34 JHDMI1.3
HDMI_L_TX_P0: length 17.5
  BOTTOM w0.117: JHDMI1.7 10.74,69.11 11.09,69.11 11.32,69.33 11.32,74.73 11.59,75 12.2,75 12.51,74.7 12.51,72.24 13.29,71.45 13.29,69.75 13.81,69.23 14.88,69.23 15.01,69.1 DH3.4 DH3.7 16.32,69.1 16.45,69.24 16.78,69.24 16.92,69.1 LH2.3
HDMI_L_TX_P1: length 6.3
  BOTTOM w0.117: LH3.3 16.89,65.66 16.74,65.81 16.43,65.81 16.29,65.67 DH2.2 DH2.8 14.95,65.67 14.78,65.83 14.31,65.83 12.62,67.53 12.22,67.53 JHDMI1.4
HDMI_L_TX_P2: length 7.9
  BOTTOM w0.117: JHDMI1.1 10.75,66.11 10.88,66.11 12.66,64.34 14.71,64.34 14.87,64.17 DH2.6 DH2.5 16.33,64.17 16.48,64.32 16.81,64.32 16.95,64.17 LH4.3
HDMI_TX_N0: length 2.5
  BOTTOM w0.117: LH2.1 18.65,69.6 18.79,69.46 19.85,69.46 RH11.1 20.16,69.46 20.31,69.46 20.51,69.66 CH4.2
HDMI_TX_N1: length 2.5
  BOTTOM w0.117: LH3.1 18.68,66.16 18.82,66.02 19.05,66.02 19.22,66.19 19.84,66.19 RH7.1 20.2,66.18 20.42,66.18 CH8.2
HDMI_TX_N2: length 2.5
  BOTTOM w0.117: CH10.2 20.42,64.54 19.63,64.54 RH5.1 19.25,64.53 18.84,64.53 18.7,64.67 LH4.1
HDMI_TX_P0: length 2.5
  BOTTOM w0.117: CH3.2 20.53,69.11 20.39,69.24 20.21,69.24 RH10.1 19.8,69.24 18.76,69.24 18.63,69.1 LH2.4
HDMI_TX_P1: length 2.5
  BOTTOM w0.117: CH7.2 20.42,65.96 20.2,65.96 RH6.1 19.84,65.96 19.31,65.96 19.14,65.79 18.76,65.79 18.63,65.66 LH3.4
HDMI_TX_P2: length 2.4
  BOTTOM w0.117: LH4.4 18.65,64.17 18.79,64.31 19.28,64.31 RH4.1 19.63,64.32 20.42,64.32 CH9.2
HG1_CHG: length 8.7
  TOP w0.117: v2(49.5,10.85) 49.5,11.35 48.58,12.27 v3(48.19,12.27)
  IN3 w0.635: 55.96,11.55 55.87,11.46 52.82,11.46 52.47,11.82 50,11.82 49.72,11.54
  vias: v2(49.5,10.25) v2(56.57,12.21) v2(56.57,11.63)
HG2_CHG: length 32.1
  TOP w0.117: v2(71.28,7.64) 71.28,7.49 71.46,7.31 v3(71.46,7.09)
  IN2 w0.762: 69.64,8.34 68.49,9.48 68.49,11.77 67.52,12.74 67.52,14.01 66.79,14.74 48.12,14.74 45.52,12.13 45.52,10.56 45.52,10.55
  vias: v2(45.43,9.64) v2(45.85,9.23) v2(71.28,8.22)
HGNDA: length 16.7
  BOTTOM w1.016: 14.88,54.74 13.78,55.84 13.78,57.66 12.17,59.28 3.38,59.28 1.94,57.83 JP3.2
  vias: v2(13.11,53.21) v2(13.11,52.57)
HGNDB: length 14.3
  BOTTOM w1.016: 13.82,50.69 13.82,49.37 12.4,47.95 3.11,47.95 JP3.1
  vias: v2(14.91,48.74) v2(14.91,48.13) v3(15.41,46.18)
HIZ_CHG: length 6.6
  TOP w0.254: v2(53.19,7.82) 53.37,7.64 53.37,7.36 PQB3.1
  BOTTOM w0.117: PRB24.1 53.95,6.94 v3(54.4,6.5)
  BOTTOM w0.203: PUB1.6 51.96,6.78 52.3,7.13 PRB25.2 PRB30.2 53.29,7.13 53.5,7.33 53.78,7.33 PRB24.1 53.95,7.55 53.69,7.82 v2(53.19,7.82)
HP_OUTL: length 6.6
  BOTTOM w0.203: UA1.27 7.82,39.4
  BOTTOM w0.254: RA15.1 RA17.2 7.23,43.95 v3(7.23,42.96) 7.23,42.57 6.95,42.29 6.95,40.27 7.82,39.4
HP_OUTR: length 7
  BOTTOM w0.203: UA1.26 7.42,39.3 7.13,39.59 7.01,39.59
  BOTTOM w0.254: 7.01,39.59 6.51,40.1 6.51,41.96 5.83,42.64 v3(5.83,42.92) 5.83,43.16 6.18,43.5 RA18.2 RA16.1
HPOUT_L: length 15.8
  IN3 w0.254: v2(7.9,46.55) 8.69,47.34 12.68,47.34 14.46,49.12 14.46,51.75 15.73,53.03 16.28,53.03 16.82,53.57 v2(16.82,53.74)
  BOTTOM w0.254: RA22.1 v2(16.82,53.74) ; RA15.2 7.95,45 CA18.2 7.95,46.5 v2(7.9,46.55)
HPOUT_L1: length 12.8
  TOP w0.254: v2(16.05,56.42) 16.44,56.03 v3(16.55,56.03)
  IN1 w0.254: v2(16.05,56.42) 14.71,56.42 12.34,58.79 9,58.79 8.73,58.52 JP3.4
  BOTTOM w0.254: RA22.2 16.82,55.81 17.03,56.02 DA4.2 16.86,57.03 16.25,56.42 v2(16.05,56.42)
HPOUT_R: length 17.7
  IN3 w0.254: v2(16.16,53.74) 16.03,53.61 15.58,53.61 13.92,51.95 13.92,49.4 12.37,47.85 6.61,47.85 v2(5.29,46.53)
  BOTTOM w0.254: RA16.2 5.29,45.03 CA19.2 v2(5.29,46.53) ; RA23.1 16.21,54.15 16.21,53.79 v2(16.16,53.74)
HPOUT_R1: length 17.2
  TOP w0.254: v2(16.08,57.03) 16.93,57.03 v3(17.19,57.3)
  IN1 w0.254: JP3.3 6.18,59.3 12.57,59.3 14.84,57.03 v2(16.08,57.03)
  BOTTOM w0.254: v2(16.08,57.03) DA4.3 15.1,56.17 RA23.2
I2C_0_SCL: length 84.9
  IN1 w0.102: v2(147.92,25.68) 147.92,26.19 147.56,26.55 147.01,26.55 144.71,28.85 144.71,40.22 142.97,41.95 142.97,46.65 145.71,49.39 145.71,53.81 136.4,63.12 134.98,63.12 133.94,64.17 v2(132.76,64.17)
  IN3 w0.127: v2(147.92,25.68) 147.92,24.9 147.39,24.36 147.39,23.57 148.39,22.57 148.39,21.99 147.2,20.8 147.2,18.44 144.51,15.75 141.61,15.75 v2(139.27,13.41)
  BOTTOM w0.117: JTP1.7 128.53,11.27 128.6,11.19 128.6,10.25 129.37,9.48 131.92,9.48 133.26,10.83 137.3,10.83 DTP1.3 137.54,11.71 138.55,12.72 CTP2.1 139.35,13.33 v2(139.27,13.41) ; RC585.2 132.46,64.46 v2(132.76,64.17) 132.81,64.17 133.1,64.46 RC56.2 133.44,64.47 RC624.2
I2C_0_SCL_R: length 17.1
  IN1 w0.102: v2(130.51,63.91) 130.52,63.92 130.52,64.06 129.2,65.39 122.69,65.39 122.49,65.58 120.3,65.58 119.83,65.12 117.96,65.12 v2(116.57,66.5)
  BOTTOM w0.102: UC1.AP14 116.18,66.1 v2(116.57,66.5)
  BOTTOM w0.117: RC585.1 131.17,64.43 130.65,63.91 v2(130.51,63.91)
I2C_0_SDA: length 84.3
  IN1 w0.102: v2(132.79,63.57) 133.63,63.57 134.79,62.41 134.79,61.8 135.07,61.52 137.56,61.52 145.46,53.62 145.46,49.46 142.69,46.69 142.69,41.89 144.48,40.1 144.48,28.75 146.93,26.29 147.21,26.29 v2(147.41,26.1)
  IN3 w0.127: v2(138.68,13.42) 141.69,16.43 144.83,16.43 146.94,18.54 146.94,20.9 148.14,22.1 148.14,22.47 147.13,23.47 147.13,25.82 v2(147.41,26.1)
  BOTTOM w0.117: RC586.2 v2(132.79,63.57) RC625.2 133.44,63.56 RC57.2 ; v2(138.68,13.42) 138.74,13.48 138.74,13.58 138.97,13.81 139.12,13.81 CTP3.1 138.93,14.06 138.91,14.09 138.19,14.09 137.54,13.44 DTP1.2 137.54,12.62 136.15,11.22 133,11.22 131.74,9.96 129.65,9.96 129.03,10.58 JTP1.6
I2C_0_SDA_R: length 18.1
  IN1 w0.102: v2(130,63.63) 130,64.26 129.1,65.16 122.43,65.16 122.21,65.38 120.38,65.38 119.92,64.92 117.76,64.92 116.77,65.91 116.36,65.91 116.18,66.08 116.18,66.09 v2(115.77,66.5)
  BOTTOM w0.102: v2(115.77,66.5) 115.37,66.1 UC1.AN14
  BOTTOM w0.117: RC586.1 131.1,63.5 130.12,63.5 130,63.61 v2(130,63.63)
IBIAS_CPU: length 2.9
  TOP w0.117: v2(93.6,95.19) v3(92.92,95.19)
  TOP w0.254: v2(93.6,95.19) 94.18,95.19 PR827.1
  BOTTOM w0.254: PU801.29 93.8,95.39 v2(93.6,95.19)
IDEAL_1: length 44.3
  TOP w0.117: PQS3.2 v3(28.72,49.01)
  TOP w0.254: PQS3.2 28.72,54.72 v2(28.68,54.76)
  IN2 w0.254: v2(28.68,54.76) 29.39,54.76 32.17,57.54 36.57,57.54 37.41,58.37 37.41,69.17 35.9,70.67 32.41,70.67 30.62,68.89 v2(30.62,67.96)
  BOTTOM w0.254: PDD1.2 29.87,62.63 PRD9.1 28.5,63.59 PQD4.2 27.89,64.42 29.41,65.93 29.82,65.93 30.62,66.73 v2(30.62,67.96)
ILMT_1.8V: length 4.2
  TOP w0.117: v3(171.52,78.75) 171.61,78.66 v2(171.61,78.07)
  TOP w0.254: v2(171.61,78.07) 170.99,77.45 PR719.2 169.96,77.45 PR720.1
  BOTTOM w0.254: PU1802.10 171.61,78.1 v2(171.61,78.07)
ILMT_VDDP: length 8.7
  TOP w0.117: v2(163.07,89.98) 163.07,89.55 v3(162.94,89.42)
  IN3 w0.254: v2(160.56,86.35) 160.56,88.13 162.41,89.98 v2(163.07,89.98)
  BOTTOM w0.254: PU601.13 162.35,89.98 v2(163.07,89.98) 163.4,89.98 PR605.1 ; PR604.2 160.11,86.8 v2(160.56,86.35)
IMON_1113: length 8.2
  TOP w0.117: v3(34.2,75.9) 33.76,75.9 32.8,76.86 31.27,76.86 31.16,76.96 UT6.9 30.35,78.05 31.65,79.35 CT77.1 31.78,79.52 31.78,79.96 31.72,80.03 RT91.1
IMON_CPU: length 2.7
  BOTTOM w0.254: PR816.2 99.93,91.82 v3(99.93,92.62) 99.93,93.05 99.57,93.41 99.57,93.66 99.57,94.01 PU801.15
IMONA_CPU: length 5.4
  BOTTOM w0.117: PR818.2 95.83,91.54 96.41,92.12 98.73,92.12 99.03,92.43 99.03,92.93 98.83,93.13 98.83,93.42 98.77,93.49 PU801.17
INVTPWM: length 40.6
  TOP w0.102: UC6.4 79.75,64.21 79.92,64.04 80.5,64.04 RC4.1 80.75,64.61 77.46,67.9 v3(77.38,67.9) 76.66,67.9 v2(76.5,68.06)
  BOTTOM w0.102: v2(76.5,68.06) 76.5,67.92 76.19,67.62 71.73,67.62 71.14,68.22 71.14,69.8 70.37,70.57 63.8,70.57 62.09,68.86 61.15,68.86 60.69,69.33 56.03,69.33 54.75,70.6 54.75,73.82 54.65,73.92 52.04,73.92 51.63,73.51 JEDP1.6
INVTPWM_R: length 24.9
  TOP w0.102: UC6.2 79.1,62.07 78.51,61.48 77.46,61.48 RC9.1 77.18,61.5 v3(76.09,60.41) 75.65,59.97 75.65,57.57 v2(75.73,57.49)
  BOTTOM w0.102: UC1.C23 90.54,58 90.14,57.61 88.88,57.61 88.68,57.8 86.81,57.8 86.5,57.5 84,57.5 81.8,55.3 77.92,55.3 v2(75.73,57.49)
ISEN1N_CPU: length 4.5
  BOTTOM w0.254: PR842.1 104,98.84 103.57,98.4 103.57,98.19 102.71,97.33 102.53,97.33 v3(102.41,97.21) 102.3,97.21 102.1,97.01 102.07,97.01 102.05,96.99 PU801.7
ISEN1N_CPU_R: length 43.4
  TOP w0.117: v2(106.05,98.62) 106.6,98.62 v1(106.74,98.76)
  IN1 w0.178: v2(130.41,92.27) 130.25,92.42 129.53,92.42 129.35,92.25 129.35,88.22 128.74,87.61 112.56,87.61 109.57,90.61 109.57,98.04 108.41,99.21 106.43,99.21 106.05,98.82 v2(106.05,98.62)
  BOTTOM w0.178: v2(130.41,92.27) 130.34,92.21 PL805.3 ; PR842.2 105.07,98.72 105.12,98.67 PC842.2 105.76,98 105.78,97.97 PC844.1 105.96,98.47 106.05,98.56 v2(106.05,98.62)
ISEN1P_CPU: length 6.8
  TOP w0.117: v1(104,99.22) PR841.2
  TOP w0.254: PR841.2 103.85,97.77 103.61,97.77 103.35,97.52 v2(103.35,97.24)
  BOTTOM w0.254: PU801.8 102.28,96.59 102.4,96.7 102.42,96.7 102.49,96.78 102.84,96.78 103.29,97.24 v2(103.35,97.24) 103.35,97.43 103.92,98 PC842.1
ISEN1P_CPU_R: length 43.2
  TOP w0.117: v2(105.68,99.1) v1(105.68,100.2)
  TOP w0.178: v2(105.68,99.1) 105.67,99.09 105.42,99.09 104.92,98.59 PR841.1
  IN1 w0.178: v2(130.41,92.86) 130.28,92.73 129.4,92.73 129.05,92.37 129.05,88.35 128.66,87.95 112.65,87.95 109.87,90.73 109.87,98.17 108.53,99.51 106.3,99.51 105.89,99.1 v2(105.68,99.1)
  BOTTOM w0.178: v2(130.41,92.86) 130.34,92.92 PL805.2
ISEN2N_CPU: length 4.8
  BOTTOM w0.254: PR830.1 103.19,98.84 103.19,98.41 v3(103.17,98.38) 102.49,97.71 102.26,97.71 101.94,97.39 PU801.6
ISEN2N_CPU_R: length 25
  BOTTOM w0.178: PR830.2 105.66,99.75 106.15,99.26 108.08,99.26 PC832.1 109.33,98.01 v3(109.33,96.42) 109.33,92.84 112.91,89.25 115.99,89.25 116.77,90.03 116.77,92.5 117.25,92.98 PL804.3
  BOTTOM w0.254: PR830.2 105.01,100.52 PC825.2
ISEN2P_CPU: length 6
  BOTTOM w0.254: PR826.2 104.05,100.61 PC825.1 103.93,100.59 v3(103.18,99.84) 102.77,99.43 102.77,98.56 102.29,98.09 102.11,98.09 101.9,97.88 101.89,97.88 101.8,97.79 PU801.5
ISEN2P_CPU_R: length 24.6
  BOTTOM w0.178: PR826.1 104.97,101.42 105.45,100.93 105.45,100.88 106.77,99.56 108.65,99.56 109.76,98.45 v3(109.76,94.26) 109.76,92.83 113.04,89.55 115.86,89.55 116.46,90.16 116.46,92.35 115.83,92.98 PL804.2
ISEN3N_CPU: length 2.2
  TOP w0.117: v1(105.41,94.98) 104.97,95.43 PR843.2
  TOP w0.254: PR857.1 104.98,96.26 PR843.2
ISEN3N_CPU_IC: length 5.9
  TOP w0.117: v1(103.72,94.96) 104.05,95.29 PR843.1
  TOP w0.254: PR843.1 103.83,96.02 v2(103.45,96.02)
  BOTTOM w0.254: PU801.10 102.58,95.79 102.81,96.02 103.39,96.02 v2(103.45,96.02) 103.75,96.02 PR844.1
ISEN3N_CPU_R: length 58.4
  TOP w0.254: PC851.1 106.73,97.17 PC850.2 106.65,97.1 PR857.2 106.96,95.95 106.96,95.95 107.33,95.59 108.07,95.59 v2(108.09,95.61)
  IN3 w0.178: v2(145.77,92.07) 145.63,92.21 145.58,92.21 145.56,92.23 144.92,92.23 141.49,88.8 134.53,88.8 133.39,87.66 119.75,87.66 118.2,86.11 113.69,86.11 109.72,90.09 109.72,91.01 107.88,92.84 106.04,92.84 104.7,94.18 104.7,94.91 104.7,94.91 104.7,95.52 105.53,96.35 106.75,96.35 107.61,95.49 107.97,95.49 v2(108.09,95.61)
  BOTTOM w0.254: 145.77,90.25 v2(145.77,92.07)
ISEN3P_CPU: length 6.2
  TOP w0.117: v1(110.22,97.29) PR856.2
  TOP w0.254: PR856.2 108.93,97.29 107.94,98.28 106.92,98.28 PC850.1 PR845.2
ISEN3P_CPU_IC: length 6.3
  TOP w0.117: v2(103.45,96.6) 103.21,96.6 102.79,97.02 v1(102.79,97.8)
  TOP w0.254: v2(103.45,96.6) 103.48,96.6 PR845.1
  BOTTOM w0.254: PR846.1 104.01,97.17 103.6,96.76 103.6,96.75 v2(103.45,96.6) 103.34,96.5 103.24,96.5 103.14,96.4 102.65,96.4 102.58,96.32 102.56,96.32 102.42,96.19 PU801.9
ISEN3P_CPU_R: length 55.7
  TOP w0.254: v2(108.12,95.03) 108.27,95.03 109.03,95.79 PR856.1
  IN3 w0.178: v2(108.12,95.03) 108.04,95.1 107.46,95.1 106.59,95.97 105.69,95.97 105.08,95.36 105.08,94.34 106.2,93.22 108.04,93.22 110.1,91.17 110.1,90.25 113.93,86.42 118.08,86.42 119.62,87.97 133.26,87.97 134.41,89.11 141.37,89.11 144.81,92.55 145.67,92.55 v2(145.77,92.65)
  BOTTOM w0.254: v2(145.77,92.65) PL806.2
ISENA1N_CPU: length 2.4
  BOTTOM w0.254: PU801.35 92.2,97.79 PR810.1
ISENA1N_CPU-1: length 15.7
  BOTTOM w0.178: PC812.1 90.03,98.48 89.46,98.48 v3(88.13,97.16) 87.21,96.23 84.48,96.23 84.01,95.76 84.01,94.85 83.05,93.88 81.42,93.88 81.14,93.6 PL803.3
  BOTTOM w0.254: PC812.1 91.16,98.77 PC806.2 91.26,98.66 PR810.2
ISENA1P_CPU: length 3.3
  TOP w0.254: PR809.2 v2(92.75,98.71)
  BOTTOM w0.254: PU801.36 93.64,98.19 93.59,98.21 v3(93.36,98.44) 93.08,98.71 v2(92.75,98.71) PC806.1
ISENA1P_CPU_R: length 14.5
  TOP w0.254: PR809.1 89.89,98.71 89.64,98.97 89.64,99.04 v2(89.63,99.04)
  BOTTOM w0.178: PL803.2 81.14,94.57 81.51,94.21 82.91,94.21 83.69,94.98 83.69,95.9 84.44,96.65 v3(85.79,96.65) 87.06,96.65 89.45,99.04 v2(89.63,99.04)
KB_BL_PWM: length 56.2
  TOP w0.117: v2(175.53,22.61) 175.53,24.82 v3(175.17,25.19) 174.67,25.68 173.34,25.68 173.04,25.99 171.99,25.99 168.41,22.41 152.04,22.41 148.67,19.05 147.24,19.05 145.69,17.5 145.69,14.08 145.25,13.64 145.25,13.33 144.83,12.92 RKBL2.1 RKBL1.2 ; v2(176.95,34.24) 176.74,34.03 UEC1.25
  IN2 w0.127: v2(175.53,22.61) 175,23.14 175,28.42 176.22,29.63 176.22,33.51 v2(176.95,34.24)
KB_RST#: length 110.3
  TOP w0.102: UEC1.2 174.35,43.23 174.31,43.2 C256.1 173.63,43.74 v2(173.65,43.77)
  IN2 w0.102: v2(118.18,65.5) 118.18,65.13 118.29,65.02 120.68,65.02 121.14,65.47 121.39,65.47 121.8,65.07 124.11,65.07 124.24,64.94 125.66,64.94 127.78,62.82 129.33,62.82 129.75,62.4 132.31,62.4 132.44,62.53 v2(135.74,62.53) 136.26,62.01 136.26,60.18 145.2,51.24 145.2,46.74 145.58,46.36 145.58,44.13 145.84,43.87 147.02,43.87 147.34,44.19 147.34,44.4 v2(147.29,44.46)
  IN3 w0.102: v2(147.29,44.46) 147.84,45.01 149.47,45.01 149.9,45.45 150.56,45.45 150.74,45.27 152.45,45.27 153.84,43.88 153.84,35.51 154.9,34.45 160.51,34.45 161.9,33.06 161.9,32.36 162.41,31.85 167.06,31.85 167.71,32.5 172.02,32.5 172.54,31.98 173.67,31.98 174.14,31.5 176.94,31.5 179.23,33.79 179.23,34.94 179.71,35.42 179.71,37.34 180.33,37.95 180.33,40.9 179.8,41.43 179.8,41.79 178.27,43.33 174.1,43.33 v2(173.65,43.77)
  BOTTOM w0.102: v2(135.74,62.53) 136.29,62.53 136.54,62.27 RC85.2 v1(136.54,60.97) ; UC1.AT15 117.77,65.1 v2(118.18,65.5)
KBL_ID: length 105.4
  IN1 w0.102: v2(134.59,10.39) 134.97,10.77 136.53,10.77 137.2,11.45 138.37,11.45 139.71,11.45 139.82,11.45 143.98,15.61 143.98,16.64 146.88,19.54 146.88,20.39 148.74,22.26 149.37,22.26 149.73,22.62 150.4,22.62 151.79,24.01 151.79,25.45 151.07,26.17 149.9,26.17 149.8,26.27 149.8,26.98 149.9,27.08 149.95,27.08 150.66,27.79 150.66,30.43 145.75,35.35 145.75,35.36 145.75,42.17 144.64,43.28 144.64,44.47 147.06,46.88 147.06,59.8 146.78,60.08 146.78,64.1 145.08,65.8 141.78,65.8 139.24,68.34 125.59,68.34 124.89,69.04 122.42,69.04 120.31,71.15 120.2,71.15 119.98,71.37 119.88,71.37 v2(119.75,71.51)
  BOTTOM w0.102: UC1.AW8 120.07,71.18 v2(119.75,71.51)
  BOTTOM w0.117: v2(134.59,10.39) 134.64,10.34 136.72,10.34 137.13,9.94 RKBL3.1 RKBL4.2 v3(135.81,8.84)
KBL_ID_R: length 11.9
  BOTTOM w0.117: RKBL5.2 138.04,8.57 RKBL4.1 138.04,8.87 138.51,9.34 138.51,9.67 139.53,10.69 139.53,11.62 140.12,12.21 v3(141.39,12.21) 141.71,11.89 141.71,11.64 142.72,10.63 145.05,10.63 145.36,10.94 JKBL1.2
KSI0: length 27.7
  TOP w0.117: v2(185.63,27.64) 186,28.01 UEC1.55
  BOTTOM w0.117: JKB2.15 169.39,18.51 170.04,17.85 178.08,17.85 179.81,19.58 181.51,19.58 181.78,19.85 182.55,19.85 184.19,21.49 184.19,22.88 184.03,23.04 v3(184.03,23.32) 184.03,23.99 185.08,25.04 185.08,27.1 v2(185.63,27.64)
KSI1: length 34.9
  TOP w0.117: UEC1.56 186.4,28.36 v2(186.41,28.34)
  BOTTOM w0.117: JKB2.26 v1(160.59,24.28) 161.47,25.16 171.53,25.16 171.93,24.77 173.01,24.77 174.55,26.3 174.55,27.06 175.11,27.62 175.11,28.6 176.25,29.74 185.02,29.74 v2(186.41,28.34)
KSI2: length 32
  TOP w0.117: UEC1.57 186.8,28.65 186.91,28.54 v3(186.91,28) 186.62,27.7 v2(186.48,27.7)
  BOTTOM w0.117: v2(186.48,27.7) 186.1,27.32 186.1,26.86 185.57,26.33 185.57,24.83 184.71,23.98 184.71,21.23 182.85,19.36 181.98,19.36 181.71,19.09 180.21,19.09 178.48,17.36 167.67,17.36 166.19,18.84 JKB2.19
KSI3: length 31.3
  TOP w0.117: UEC1.58 187.2,28.19 187.25,28.14 187.25,27.84 186.67,27.26 185.89,27.26 v2(185.65,27.02) 185.45,27.02 v1(185.16,26.73)
  BOTTOM w0.117: v2(185.65,27.02) 185.32,26.69 185.32,24.94 184.45,24.06 184.45,21.37 182.68,19.61 181.88,19.61 181.61,19.33 179.96,19.33 178.23,17.6 169.78,17.6 168.38,19 167.75,19 166.99,19.76 JKB2.18
KSI4: length 39.2
  TOP w0.117: v2(187.67,28.28) 187.72,28.28 187.6,28.4 UEC1.59
  BOTTOM w0.117: v1(163.94,24.4) 163.94,23.39 163.79,23.24 JKB2.22 163.79,19.4 166.31,16.87 178.74,16.87 180.47,18.6 181.91,18.6 182.18,18.87 183.06,18.87 185.22,21.04 185.22,23.8 186.06,24.63 186.06,26.07 186.31,26.32 186.71,26.32 186.99,26.6 186.99,27.67 187.6,28.28 v2(187.67,28.28)
KSI5: length 35.8
  TOP w0.117: v1(187.43,26.18) 186.79,26.18 186.54,26.43 v2(186.54,26.75) 187.61,27.82 187.79,27.82 188.15,28.18 188.15,28.61 188,28.76 UEC1.60
  BOTTOM w0.117: JKB2.21 164.59,19.05 166.52,17.12 178.64,17.12 180.37,18.85 181.81,18.85 182.08,19.12 182.96,19.12 184.98,21.14 184.98,23.9 185.81,24.73 185.81,26.23 186.34,26.75 v2(186.54,26.75)
KSI6: length 38.5
  TOP w0.117: UEC1.61 188.4,27.78 187.6,26.98 v2(187.47,26.98)
  BOTTOM w0.117: v2(187.47,26.98) 187.49,26.96 187.49,26.75 186.94,26.2 v3(186.94,24.4) 186.94,23.89 185.71,22.65 185.71,20.83 183.26,18.39 182.38,18.39 182.11,18.12 180.67,18.12 178.94,16.39 166.11,16.39 165.21,17.29 163.17,17.29 162.19,18.28 JKB2.24
KSI7: length 45.5
  TOP w0.117: UEC1.62 v2(188.8,28.3)
  BOTTOM w0.117: v1(162.28,24.53) 162.28,23.7 161.38,22.8 JKB2.25 161.38,17.87 163.11,16.14 179.04,16.14 180.77,17.87 182.21,17.87 182.48,18.14 183.36,18.14 185.95,20.73 185.95,22.55 187.3,23.9 187.3,26.08 187.57,26.35 188.31,26.35 189.5,27.54 189.5,27.98 189.18,28.3 v2(188.8,28.3)
KSO0: length 23.1
  TOP w0.117: v2(179.43,28.4) 179.6,28.57 UEC1.39
  BOTTOM w0.117: JKB2.20 165.38,24.26 v1(165.65,24.52) 166.05,24.92 171.43,24.92 171.82,24.52 173.12,24.52 174.79,26.2 174.79,26.95 175.36,27.52 175.36,28.5 176.35,29.49 178.72,29.49 179.43,28.78 v2(179.43,28.4)
KSO1: length 18.4
  TOP w0.117: v2(179.94,27.58) 180,27.64 UEC1.40
  BOTTOM w0.117: JKB2.16 168.59,23.46 v1(169.08,23.96) 169.55,24.43 171.23,24.43 171.62,24.04 173.32,24.04 175.49,26.21 175.71,26.21 177.22,27.71 179.8,27.71 v2(179.94,27.58)
KSO2: length 18.3
  TOP w0.117: UEC1.41 180.4,27.99 v3(180.36,27.96) 180.36,27.32 v2(179.99,26.94)
  BOTTOM w0.117: JKB2.14 170.19,21.45 169.9,21.73 169.9,23.83 170.26,24.19 171.12,24.19 171.52,23.79 173.42,23.79 175.59,25.96 175.81,25.96 177.32,27.47 179.17,27.47 179.7,26.94 v2(179.99,26.94)
KSO3: length 14.4
  TOP w0.117: v2(181.33,25.67) v3(180.97,26.03) 180.7,26.3 180.7,28.44 180.8,28.53 UEC1.42
  BOTTOM w0.117: v2(181.33,25.67) 180.69,25.67 179.82,24.8 176.78,24.8 174.19,22.21 JKB2.9
KSO4: length 19.6
  TOP w0.117: v2(181.33,27.51) 180.95,27.9 180.95,28.37 181.2,28.63 UEC1.43
  BOTTOM w0.117: v2(181.33,27.51) 181.15,27.51 180.16,26.53 179.77,26.53 179.07,27.23 177.42,27.23 175.91,25.72 175.69,25.72 173.92,23.95 v1(173.92,23.75) 173.72,23.55 171.42,23.55 171.02,23.94 170.36,23.94 170.15,23.73 170.15,22.32 170.99,21.48 JKB2.13
KSO5: length 21.7
  TOP w0.117: v2(181.33,28.21) 181.6,28.48 UEC1.44
  BOTTOM w0.117: JKB2.17 167.79,23.6 167.36,24.02 v1(167.36,24.21) 167.36,24.37 167.67,24.68 171.33,24.68 171.72,24.28 173.22,24.28 175.05,26.11 175.05,26.86 176.14,27.96 179.62,27.96 179.87,28.21 v2(181.33,28.21)
KSO6: length 16.4
  TOP w0.117: UEC1.45 v3(182,28.09) 182,27.42 181.84,27.26 181.84,26.23 v2(182.4,25.67)
  BOTTOM w0.117: v2(182.4,25.67) 181.95,26.12 180.79,26.12 179.72,25.05 176.61,25.05 173.39,21.82 JKB2.10
KSO7: length 19.8
  TOP w0.117: v2(182.4,26.94) UEC1.46
  BOTTOM w0.117: JKB2.12 171.79,21.51 170.86,22.43 v1(170.86,23.56) 170.88,23.58 171.05,23.58 171.36,23.26 173.98,23.26 177.71,26.98 178.94,26.98 179.66,26.27 180.25,26.27 180.92,26.94 v2(182.4,26.94)
KSO8: length 17
  TOP w0.117: UEC1.47 182.8,28.72 182.86,28.66 v3(182.86,26.69) 182.86,26.43 182.73,26.3 v2(182.4,26.3)
  BOTTOM w0.117: v2(182.4,26.3) 182.14,26.56 180.89,26.56 179.62,25.29 176.51,25.29 173.97,22.75 173.14,22.75 172.59,22.19 JKB2.11
KSO9: length 39.7
  TOP w0.117: UEC1.48 183.2,25.57 184.11,24.66 v3(184.64,24.66) 185.65,25.67 v2(186.53,25.67)
  BOTTOM w0.117: JKB2.23 162.99,19.85 166.21,16.63 178.84,16.63 180.57,18.36 182.01,18.36 182.28,18.63 183.16,18.63 185.47,20.94 185.47,22.76 186.53,23.82 186.53,24.52 186.53,24.52 186.53,24.8 186.53,24.81 v2(186.53,25.67)
KSO10: length 13.4
  TOP w0.117: v2(183.6,28.28) UEC1.49
  BOTTOM w0.117: v2(183.6,28.28) 184.57,27.3 184.57,25.7 183.09,24.22 181.23,24.22 180.34,23.32 v1(180.06,23.32) 179.84,23.32 178.19,21.67 JKB2.4
KSO11: length 13.9
  TOP w0.117: UEC1.50 184,28.72 184.06,28.66 184.06,27.96 v3(184.04,27.93) 183.75,27.64 v2(183.62,27.64)
  BOTTOM w0.117: v2(183.62,27.64) 184.26,27.01 184.26,25.78 182.99,24.52 181.19,24.52 180.5,23.83 180,23.83 177.84,21.67 177.5,21.67 177.39,21.55 JKB2.5
KSO12: length 16.1
  TOP w0.117: v2(183.62,27.01) 184.4,27.78 UEC1.51
  BOTTOM w0.117: JKB2.8 174.99,22.66 176.88,24.56 180.05,24.56 v3(180.36,24.87) 180.75,25.26 182.59,25.26 182.86,25.53 182.86,26.69 183.18,27.01 v2(183.62,27.01)
KSO13: length 15.6
  TOP w0.117: v2(183.62,26.37) 184.8,27.55 UEC1.52
  BOTTOM w0.117: JKB2.7 175.79,21.71 176,21.93 176,23.07 v1(176.44,23.51) 177.25,24.32 180.3,24.32 180.99,25.01 182.69,25.01 183.11,25.44 183.11,26.12 183.37,26.37 v2(183.62,26.37)
KSO14: length 14.9
  TOP w0.117: v2(183.62,25.74) 185.2,27.31 UEC1.53
  BOTTOM w0.117: v2(183.62,25.74) 183.62,25.6 182.79,24.77 181.09,24.77 180.4,24.07 178.65,24.07 v1(178.22,23.64) 177.65,23.64 176.59,22.57 JKB2.6
KSO15: length 13
  TOP w0.117: UEC1.54 185.6,28.28 v2(185.6,28.28)
  BOTTOM w0.117: v2(185.6,28.28) 184.83,27.5 184.83,25.35 v3(184.13,24.66) 183.45,23.98 181.33,23.98 178.99,21.63 JKB2.3
LDO2: length 6.3
  BOTTOM w0.203: UA1.21 5.33,36.86 5.24,36.95 4.98,37.2 4.98,37.2 4.96,37.23 4.96,37.64 5.01,37.69
  BOTTOM w0.305: 5.01,37.69 5.01,38.95 4.31,39.65 v3(4.31,40.66) 4.31,41.68 CA14.2
LDO3: length 1.7
  BOTTOM w0.203: UA1.19 5.43,36.06 5.22,35.85 5.15,35.85
  BOTTOM w0.305: 5.15,35.85 4.83,35.53 CA15.2
LDO_1.8V:
  vias: v3(169.04,76.82)
LDO_VDDP:
  vias: v3(159.65,88.97)
LG1_CHG: length 15.4
  IN3 w0.762: 62.56,11.98 59.49,11.98 58.42,13.05 49.86,13.05 48.26,11.45
  vias: v2(48.45,11.01) v2(48.45,10.42) v2(63.61,11.68) v2(64.06,12.06)
LG1_CPU: length 29.1
  TOP w0.117: v2(99.14,101.39) v3(99.14,100.41)
  IN3 w1.016: 126.77,103.29 124.78,105.29 102.35,105.29 100.31,103.24
  vias: v2(99.14,101.97) v2(127.69,102.35) v2(128.27,102.35)
LG1_NB: length 22.5
  TOP w0.117: v2(78.36,104.82) v3(79.03,104.82)
  IN3 w1.016: 78.87,105.61 78.87,106.88 79.99,107.99 93.02,107.99 96.55,104.46 96.55,103.55
  vias: v2(77.78,104.82) v2(96.47,102.33) v2(96.85,101.88)
LG2_CHG: length 28.1
  IN3 w0.762: 46.51,10.65 46.51,11.47 49,13.96 63.81,13.96 65.1,12.68 65.1,8.27
  BOTTOM w0.117: v2(64.9,6.65) v3(64.9,3.93)
  vias: v2(46.78,10.7) v2(47.21,10.29) v2(64.72,7.21)
LG2_CPU: length 22.7
  TOP w0.117: v2(118.98,97.78) v1(117.82,97.78)
  IN3 w1.016: 101.04,102.18 102.68,103.82 111.55,103.82 112.69,102.67 117.44,102.67 118.1,102.01 118.1,98.96
  vias: v2(100.13,100.93) v2(100.51,101.39) v2(119.56,97.78)
LG3_CPU: length 5.9
  TOP w0.117: v2(149.43,98.21) v3(148.47,98.21)
  IN3 w0.762: 148.68,103.15 148.68,98.33 148.77,98.24
  vias: v2(148.59,103.85) v2(149.18,103.85) v2(149.43,97.58)
LG_DDR: length 15.5
  TOP w1.016: 159.96,51.14 159.96,47.73 156.82,44.6 156.82,42.16 v3(156.11,41.44) 155.82,41.15 155.82,37.42 155.79,37.39
  vias: v2(155.67,35.64) v2(156.1,36.04) v2(159.68,52.15) v2(160.06,52.63)
LID_SW#: length 44.1
  TOP w0.102: v1(201.34,29.67) 200.7,29.67 v2(200.57,29.8) 200.57,30.87 R4026.1 ; UEC1.115 182.4,46.15 181.46,47.08 C267.2 R55.1 v2(182.35,46.82)
  IN1 w0.102: v2(200.57,29.8) 200.57,30.24 200.32,30.5 199.24,30.5 198.55,29.8 196,29.8 195.14,30.66 192.9,30.66 192.7,30.87 192.7,32.29 193.21,32.8 193.21,33.48 192.85,33.84 192.85,37.27 192.32,37.8 192.32,45.37 191.68,46 183.16,46 v2(182.35,46.82)
  BOTTOM w0.102: JIO1.1 202.29,29.8 v3(201.91,29.8) v2(200.57,29.8)
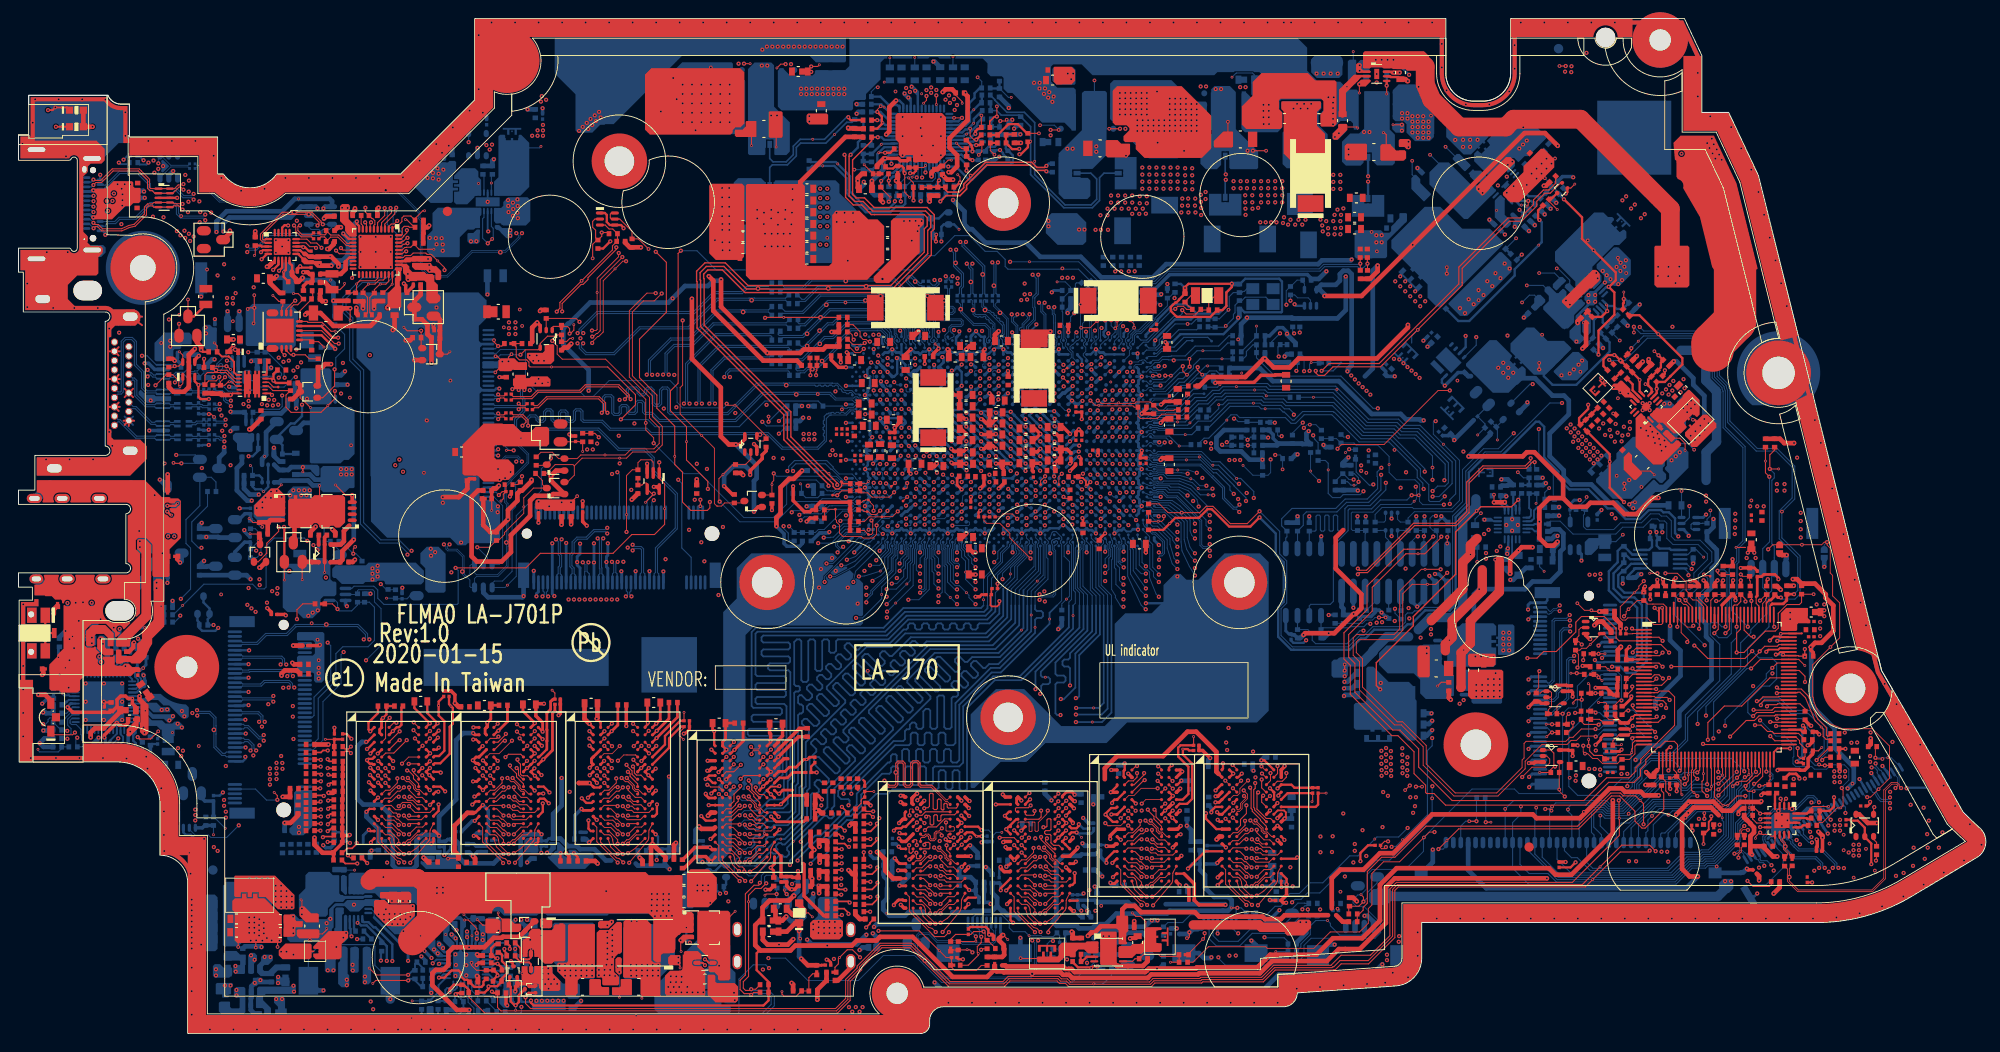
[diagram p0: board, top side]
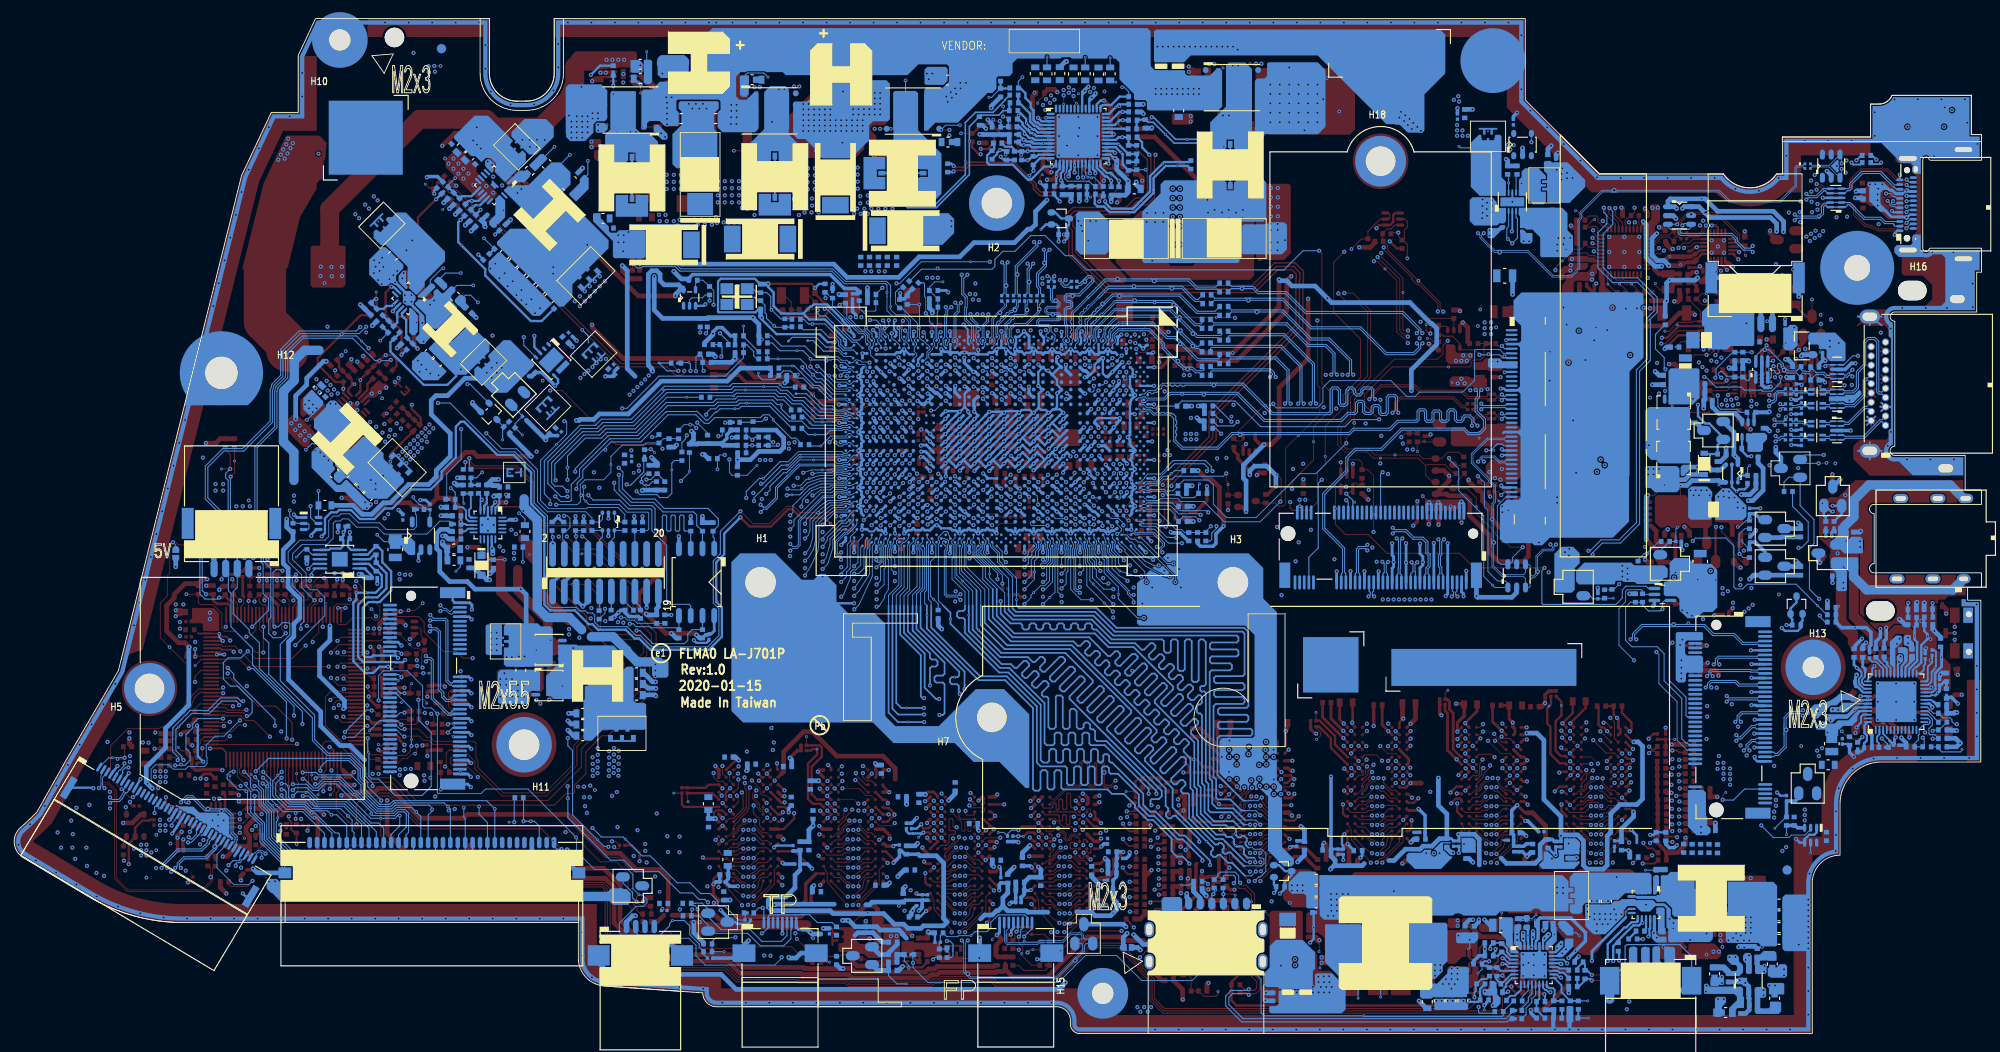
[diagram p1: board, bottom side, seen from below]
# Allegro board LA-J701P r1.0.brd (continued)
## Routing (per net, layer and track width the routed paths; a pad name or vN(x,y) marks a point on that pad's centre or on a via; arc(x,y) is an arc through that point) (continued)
LOC_PWR_MON: length 6.3
  TOP w0.117: UT1.28 39.59,81.61 39.41,81.43 38.95,81.43 38.51,80.99 v3(37.8,80.99) 37.21,80.41 RT38.1 37.7,79.57 37.7,77.9 RT37.2
LPC_AD0: length 70.5
  TOP w0.117: UEC1.10 177.2,40.03 v2(177.59,39.64)
  IN2 w0.117: v2(177.59,39.64) 177.14,39.2 176.65,39.2 175.48,40.37 175.48,40.96 174.12,42.32 172.69,42.32 170.44,44.57 169.37,44.57 169.37,44.57 169.02,44.57 164.47,49.12 164.47,51.57 164.38,51.65 164.38,51.66 164.07,51.97 164.07,52.91 164.01,52.97 164.01,54.11 161.33,56.79 160.6,56.79 160.06,57.33 160.06,57.76 159.73,58.1 155.16,58.1 154.72,58.53 153.49,58.53 152.75,59.28 152.2,59.28 v2(151.78,58.85)
  BOTTOM w0.117: RC77.1 127.56,63.85 128.06,64.34 128.57,64.34 v3(130.52,66.3) 130.52,66.42 130.96,66.87 131.59,66.87 131.89,66.57 132.33,66.57 132.34,66.57 133.05,66.57 133.06,66.57 136.84,66.57 137.46,65.94 137.95,65.94 138.88,66.87 141.86,66.87 144.8,63.94 148.02,63.94 151.08,60.88 151.08,60.08 151.69,59.48 151.69,58.94 v2(151.78,58.85)
LPC_AD0_R: length 5.9
  BOTTOM w0.102: UC1.BA16 121.84,64.5 122.18,64.84 122.38,64.84 122.65,64.57 124.3,64.57
  BOTTOM w0.117: 124.3,64.57 v3(125.37,63.5) 126.5,63.5 RC77.2
LPC_AD1: length 67.5
  TOP w0.117: UEC1.8 177.26,40.83 v2(177.59,41.17)
  IN2 w0.117: v2(177.59,41.17) 177.14,40.72 176.61,40.72 176.39,40.93 176.39,41.41 174.64,43.17 173.04,43.17 171.36,44.84 171.36,46.49 170.5,47.35 170.5,47.65 169.81,48.34 168.89,48.34 164.91,52.32 164.91,54.19 164.85,54.24 164.85,54.51 163.1,56.26 163.1,57.17 161.45,58.82 161.22,59.05 155.45,59.05 155.12,59.38 153.84,59.38 152.49,60.72 v2(151.9,60.72)
  BOTTOM w0.117: v2(151.9,60.72) 151.9,61.05 148.32,64.63 145.15,64.63 141.92,67.86 136.88,67.86 136.51,68.23 134.49,68.23 134.25,68.47 130.58,68.47 130.08,67.96 v3(129.65,67.96) 129.65,67.53 128.74,66.63 RC78.1
LPC_AD1_R: length 6.6
  BOTTOM w0.102: 124.22,65.74 123.69,65.74 123.55,65.6 123.22,65.6 123.12,65.7 122.53,65.7 122.41,65.83 122.15,65.83 121.82,65.5 UC1.BA15
  BOTTOM w0.117: 124.22,65.74 126.28,65.74 v3(126.53,65.99) 127.17,66.63 RC78.2
LPC_AD2: length 55.4
  TOP w0.117: UEC1.7 176.88,41.23 v2(176.89,41.23)
  IN2 w0.117: v2(176.89,41.23) 176.89,41.51 175.12,43.28 175.12,43.72 174.24,44.61 172.97,44.61 171.8,45.78 171.8,46.67 170.93,47.54 170.93,47.82 169.98,48.76 169.06,48.76 165.33,52.49 165.33,54.36 165.27,54.42 165.27,54.68 163.52,56.44 163.52,57.34 161.87,58.99 161.65,59.21 161.39,59.47 155.62,59.47 155.3,59.8 v2(154.02,59.8)
  BOTTOM w0.117: v2(154.02,59.8) 154.1,59.88 154.1,61.54 150.95,64.69 149.25,64.69 148.6,65.34 145.41,65.34 142,68.76 v3(139.87,68.76) RC79.1
LPC_AD2_R: length 16.5
  BOTTOM w0.102: UC1.BC13 122.29,66.49 122.9,66.49 122.98,66.58 123.79,66.58 123.92,66.45 124.22,66.45
  BOTTOM w0.117: 124.22,66.45 125.87,66.45 127.47,68.05 128.48,68.05 129.26,68.82 129.95,68.82 130.34,69.21 134.49,69.21 v3(134.78,68.92) 137.2,68.92 RC79.2
LPC_AD3: length 70.6
  TOP w0.117: UEC1.5 177.42,42.03 v2(178.29,41.17)
  IN2 w0.117: v2(152.73,59.84) 152.79,59.84 153.67,58.95 154.95,58.95 155.27,58.63 160.87,58.63 161.4,58.11 161.4,57.37 164.43,54.34 164.43,54.07 164.49,54.01 164.49,52.14 164.89,51.74 164.89,49.29 169.19,44.99 170.62,44.99 172.86,42.74 174.46,42.74 175.94,41.27 175.94,40.79 176.43,40.3 177.42,40.3 v2(178.29,41.17)
  BOTTOM w0.117: RC80.1 128.58,67.65 129.4,68.47 130.1,68.47 130.48,68.86 134.35,68.86 134.63,68.58 136.65,68.58 137.02,68.2 142.07,68.2 145.3,64.97 148.46,64.97 149.09,64.35 150.81,64.35 152.73,62.42 v1(152.73,61.17) v2(152.73,59.84)
LPC_AD3_R: length 6.6
  BOTTOM w0.102: 124.05,66.09 123.9,66.09 123.61,66.37 123.07,66.37 122.99,66.3 122.52,66.3 122.36,66.13 122.01,66.13 UC1.BB14
  BOTTOM w0.117: RC80.2 127.32,67.39 126.03,66.1 v3(125.2,66.1) 124.07,66.1 124.06,66.09 124.05,66.09
LPC_CLK0: length 6.2
  BOTTOM w0.102: UC1.BB15 122.02,65.14 122.36,65.14 122.51,65.3 122.95,65.3 123.05,65.2 123.78,65.2 123.8,65.17 124.34,65.17
  BOTTOM w0.117: 124.34,65.17 124.78,64.72 v3(126.03,64.72) 126.74,64.72 RC81.2
LPC_CLK0_EC: length 74.6
  TOP w0.117: R58.1 174.27,39.39 v2(174.34,39.45) 174.55,39.23 UEC1.12
  IN3 w0.117: v2(154.06,58.06) 155.36,59.36 161.13,59.36 163.27,57.22 163.27,56.99 164.54,55.73 164.54,55.08 165.05,54.57 165.05,47.79 164.79,47.54 164.79,41.39 165.36,40.83 165.36,40.09 166.31,39.13 167.05,39.13 167.68,38.5 168.97,38.5 169.52,39.06 171.5,39.06 171.87,38.69 173.57,38.69 v2(174.34,39.45)
  BOTTOM w0.117: v2(154.06,58.06) 153.49,57.49 152.47,57.49 152.33,57.63 152.33,59.32 151.43,60.23 151.43,61.02 148.17,64.28 145.01,64.28 142.15,67.14 142.08,67.14 142,67.22 138.7,67.22 137.77,66.29 137.6,66.29 136.73,67.17 136.59,67.17 136.24,67.52 v3(134.66,67.52) 134.23,67.52 133.96,67.78 130.87,67.78 128.5,65.41 RC81.1
LPC_FRAME#: length 84
  TOP w0.117: v2(162.98,40.57) 164.02,40.57 164.74,41.28 166.1,41.28 168.22,43.4 168.22,44.46 168.82,45.06 171.29,45.06 172.53,43.82 172.57,43.79 172.57,42.76 172.89,42.43 UEC1.4
  IN2 w0.117: v2(152.75,58.63) 152.8,58.63 153.55,57.88 153.55,56.98 153.79,56.74 154.94,56.74 155.74,55.94 159.06,55.94 159.17,55.83 159.17,55.39 162.64,51.92 162.64,46.42 162.16,45.93 162.16,44.51 162.64,44.02 162.64,43.45 162.98,43.11 v2(162.98,40.57)
  BOTTOM w0.102: 124.22,66.8 124.21,66.78 122.9,66.78 122.81,66.69 122.53,66.69 122.41,66.82 122.15,66.82 121.83,66.5 UC1.BA13
  BOTTOM w0.117: v2(152.75,58.63) 153.28,59.16 154.09,59.16 154.45,59.52 154.45,61.69 154.33,61.8 154.33,61.81 151.1,65.04 149.41,65.04 148.76,65.69 145.56,65.69 141.98,69.27 134.92,69.27 134.63,69.56 133.53,69.56 v3(133.52,69.55) 130.2,69.55 129.81,69.16 129.11,69.16 128.34,68.39 127.31,68.39 125.71,66.8 124.22,66.8
LPC_RST#: length 6
  BOTTOM w0.102: 123.87,67.59 123.66,67.39 123.03,67.39 122.93,67.49 122.28,67.49 UC1.BC12
  BOTTOM w0.117: RC82.2 127.12,69.86 v3(126.17,68.91) 125.11,67.85 124.12,67.85 123.87,67.59
LPC_RST#_R: length 73.3
  TOP w0.117: UEC1.13 174.37,38.83 173.9,38.37 C259.1 173.66,38 173.61,37.95 RC83.2 CC29.2 173.74,36.59 174.31,37.17 v2(174.31,37.5)
  IN2 w0.117: v2(154.6,57.23) 155.05,57.23 155.91,56.37 159.91,56.37 162.73,53.55 162.73,52.79 163.24,52.28 163.24,46.94 167.28,42.91 168.9,42.91 169.03,43.04 169.95,43.04 170.65,42.34 170.84,42.34 170.94,42.34 172.55,40.73 172.57,40.73 173.19,40.11 173.19,39.05 174.31,37.93 v2(174.31,37.5)
  BOTTOM w0.117: v2(154.6,57.23) 154.6,57.69 155.24,58.32 155.24,61.88 151.39,65.73 149.74,65.73 149.06,66.4 145.82,66.4 142.27,69.96 135.21,69.96 134.92,70.25 129.9,70.25 v3(129.77,70.12) 129.51,69.86 RC82.1
LPCPD#: length 7.2
  BOTTOM w0.102: UC1.BB13 122.03,67 122.15,67.12 122.33,67.12 122.4,67.2 122.4,67.2 122.51,67.3 122.85,67.3 122.96,67.19 123.76,67.19 124.05,67.47 124.07,67.47
  BOTTOM w0.117: T17.1 126.91,69.14 125.26,67.49 124.1,67.49 124.07,67.47 124.07,67.47
LX1_CHG: length 8
  IN3 w0.635: 58.14,8.02 56.26,8.02 54,10.28 51.11,10.28
  vias: v2(50.16,10.71) v2(50.15,10.1) v2(58.45,7.41) v2(58.45,6.83) v2(59.03,7.41) v2(59.03,6.83) v2(59.03,6.24) v2(59.62,7.41) v2(59.62,6.83) v2(59.62,6.24) v2(60.2,7.41) v2(60.2,6.83) v2(60.2,6.24) v2(60.79,7.41) v2(60.79,6.83) v2(60.79,6.24) v2(61.37,7.41) v2(61.37,6.83) v2(61.37,6.24) v2(61.95,7.41) v2(61.95,6.83) v2(61.95,6.24)
LX1_CPU: length 34.7
  TOP w0.117: v2(133.34,95.41) v1(134.76,95.41)
  IN3 w1.016: 129.39,103.12 125.8,106.71 101.72,106.71 99.08,104.07 99.08,103.69
  vias: v2(98.58,102.25) v2(98.58,101.67) v2(129.31,102.08) v2(129.9,102.08) v2(132.76,95.41)
LX1_NB: length 17
  TOP w0.117: PR808.1 v3(81.84,95.82)
  IN3 w1.016: 95.23,103.19 92.65,105.77 81.8,105.77 81.44,105.4
  vias: v2(80.29,104.62) v2(80.88,104.62) v2(81.3,99.22) v2(81.93,99.22) v2(95.88,102.19) v2(96.28,101.76)
LX2_CHG: length 28.7
  IN3 w0.762: 66.54,13.31 66.09,13.31 63.91,15.5 48.33,15.5 44.58,11.75 44.58,9.94
  BOTTOM w0.117: v2(67.34,6.24) v3(67.34,3.82)
  vias: v2(44.88,9.08) v2(45.28,8.66) v2(66.15,7.41) v2(66.15,6.83) v2(66.17,6.24) v2(66.21,12.16) v2(66.73,7.41) v2(66.73,6.83) v2(66.75,6.24) v2(66.79,12.16) v2(67.34,7.41) v2(67.34,6.83) v2(67.92,7.41) v2(67.92,6.83) v2(67.92,6.24) v2(68.51,7.41) v2(68.51,6.83) v2(68.51,6.24) v2(69.09,7.41) v2(69.09,6.83) v2(69.09,6.24)
LX2_CPU: length 17.5
  IN3 w1.016: 102.37,101.69 102.94,102.27 108.78,102.27 113.57,97.48 113.57,96.69
  BOTTOM w0.117: PQ802.7 v1(116.22,103.01)
  vias: v2(100.61,100.58) v2(101.04,100.98) v2(113.29,95.62) v2(113.87,95.62) v2(116.41,95.88) v2(116.41,95.29)
LX3_CPU: length 6.2
  IN3 w0.762: 145.77,103.95 145.77,102.05 145,101.28 145,98.1
  vias: v2(143.67,95.57) v2(143.67,94.99) v2(144.86,104.64) v2(144.86,104.06) v2(145.34,97.43) v2(145.93,97.43)
LX_1.8V: length 2.8
  BOTTOM w0.117: v1(162.92,80.85) 164.68,80.85 165.38,80.16 PR1810.1
  vias: v2(167.15,79.23) v2(167.58,78.77) v2(170.42,82.2) v2(170.58,81.62)
LX_3V: length 2.5
  BOTTOM w0.117: v1(181,63.1) 180.35,63.75 178.73,63.75
  vias: v2(175.24,65.45) v2(175.72,65.85) v2(175.82,65.17) v2(176.03,64.58) v2(176.27,65.61) v2(176.47,65.03) v2(176.61,64.43) v2(176.76,63.82) v2(177.04,64.84) v2(177.21,64.27) v2(177.35,63.65) v2(177.47,62.98) v2(177.77,68.05) v2(177.79,64.09) v2(177.92,63.43) v2(178.35,68.08)
LX_5V: length 1
  TOP w0.117: v2(30.61,13.51) 30.61,14.35 v3(30.52,14.44)
  vias: v2(30.61,12.87)
LX_DDR: length 10.4
  TOP w1.016: 158.11,50.12 158.11,47.86 154.85,44.61 154.85,42.8 v3(154.56,42.51) 154.12,42.07 154.12,41.36
  vias: v2(152.11,41.66) v2(152.11,41.08) v2(158.51,51.92) v2(158.51,51.31)
LX_VDDP: length 1.5
  BOTTOM w0.117: v1(152.47,94.97) 153.5,93.94 153.5,93.94
  vias: v2(157.72,91.27) v2(158.14,90.85) v2(160.87,93.88) v2(161.36,94.24)
M_BATA:
  vias: v1(74.72,14.12)
M_VMB:
  vias: v1(75.67,7.32)
MIC_LED#: length 4.2
  TOP w0.117: v3(178.35,25.8) 177.93,26.22 177.93,27.25 R267.1 177.6,27.85 UEC1.34
MIC_LED#_R: length 33.7
  TOP w0.117: R267.2 177.46,26.24 177.71,25.99 177.71,24.2 175.7,22.2 175.36,22.2 174.6,22.95 174.6,24.02 172.95,25.67 172.06,25.67 168.51,22.12 155.56,22.12 v3(154.29,20.85) v2(153.37,19.93)
  BOTTOM w0.117: JKB2.34 154.19,20.24 153.87,19.93 v2(153.37,19.93)
MODEL_ID0: length 32.1
  IN1 w0.102: v2(119.67,65.5) 120.09,65.92 122.92,65.92 123.22,65.62 130.08,65.62 130.7,65 133.42,65 135.07,63.35 136.49,63.35 139.72,60.13 142.99,60.13 143.75,59.37 144.49,59.37 v2(144.75,59.62)
  BOTTOM w0.102: v2(119.67,65.5) 119.37,65.2 UC1.AV15
  BOTTOM w0.117: RC115.2 143.55,59.64 143.93,59.26 v3(144.25,59.26) 144.47,59.26 144.75,59.54 v2(144.75,59.62) 144.75,60.05 144.29,60.51 RC112.1
MODEL_ID1: length 31.5
  IN1 w0.102: v2(118.97,66.5) 119.36,66.12 122.95,66.12 123.22,66.39 123.6,66.39 124.14,65.85 130.17,65.85 130.79,65.23 133.52,65.23 135.17,63.58 136.59,63.58 139.81,60.36 143.73,60.36 v2(144.21,59.87)
  BOTTOM w0.102: UC1.AU14 118.58,66.1 v2(118.97,66.5)
  BOTTOM w0.117: v2(144.21,59.87) 143.73,59.87 143.09,60.51 RC568.1 142.23,59.7 RC569.2
NOVO#: length 284.4
  TOP w0.117: v1(16.74,61.68) 16.79,61.63 v2(17.59,61.63) ; R65.2 192.85,31.86 192.28,32.43 UEC1.68 189.63,32.43 189.42,32.64 188.92,32.64 188.23,33.33 v2(187.57,33.33)
  IN2 w0.127: SW1.3 SW1.4 2.05,40.57 2.05,37.73 2.66,37.12 2.66,36.99 5.32,34.32 10.19,34.32 11.13,35.26 12.87,35.26 15.22,37.61 15.22,40.5 16.8,42.08 16.8,46.03 17.12,46.35 17.12,47.82 17.87,48.58 17.87,52.65 19.09,53.87 19.09,57.53 17.59,59.03 v2(17.59,61.63) ; v2(187.57,33.33) 187.6,33.36 188.23,33.36 189.28,34.41 189.28,35.99 188.13,37.15 188.13,37.76 187.57,38.32 187.57,39.63 186.94,40.25 184.74,40.25 182.21,42.78 182.21,45.29 179.7,47.81 179.24,47.81 178.35,48.7 178.35,49.89 177.11,51.14 175.63,51.14 171.64,55.12 171.64,56.63 163.73,64.55 163.45,64.55 158.92,69.08 158.92,69.64 156.47,72.09 154.55,72.09 153.56,73.08 152.75,73.08 150.52,75.32 149.68,75.32 144.85,80.14 141.15,80.14 137.71,83.58 109.26,83.58 107.17,81.49 102.59,81.49 101.57,82.52 81.47,82.52 73.32,74.36 63.39,74.36 62.39,73.37 59.68,73.37 58.01,71.71 54.46,71.71 53.1,73.07 52.12,73.07 51.54,72.5 49.88,72.5 47.01,75.37 42.79,75.37 41.39,76.76 39.78,76.76 39.36,76.35 33.21,76.35 31.61,74.74 31.61,71.99 29.38,69.75 26.94,69.75 25.87,68.69 25.87,67.42 25.16,66.71 22.75,66.71 22.48,66.97 22.48,68.56 22.28,68.76 21.31,68.76 21.19,68.64 21.19,63.48 20.51,62.81 17.31,62.81 v2(17.03,62.53)
  BOTTOM w0.117: v2(17.03,62.53) 19.1,62.53 D33.3 19.17,61.63 v2(17.59,61.63)
OBRAM_ID0: length 37.6
  TOP w0.117: RC120.1 145.7,83.22 v2(145.71,83.2) RC121.2
  BOTTOM w0.089: 118.23,79.65 118.23,78.14 117.58,77.49 116.41,77.49 115.88,76.95 UC1.AP2
  BOTTOM w0.117: v2(145.71,83.2) 145.27,82.76 144.76,82.76 144.64,82.88 141.08,82.88 140.6,82.4 124.18,82.4 122.83,81.04 118.37,81.04 118.23,80.9 v3(118.23,80.09) 118.23,79.65
OBRAM_ID1: length 37.4
  TOP w0.117: RC119.1 144.92,83.22 v2(144.94,83.2) RC122.2
  BOTTOM w0.089: UC1.AN3 115.37,74.65 115.59,74.86 115.59,75.06 115.7,75.17 115.7,77.13 116.25,77.68 117.26,77.68 117.83,78.25 v3(117.83,78.57) 117.83,79.65
  BOTTOM w0.117: 117.83,79.65 117.83,80.85 118.27,81.29 122.73,81.29 124.08,82.64 140.5,82.64 140.98,83.12 144.86,83.12 v2(144.94,83.2)
OBRAM_ID2: length 11.8
  TOP w0.102: 124.88,66.93 123.49,66.93 123.03,66.48 121.17,66.48 120.92,66.73 RC123.1 120.51,67.7 120.38,67.83 116.75,67.83 v3(116.68,67.9) 116.29,67.9 v2(115.78,68.41)
  TOP w0.117: RC124.2 124.98,66.93 124.88,66.93
  BOTTOM w0.089: UC1.AN12 v2(115.78,68.41)
OBRAM_ID3: length 9.9
  TOP w0.102: v2(116.58,68.41) 116.65,68.41 116.96,68.1 118.77,68.1 v3(118.83,68.17) 118.9,68.1 120.56,68.1 120.72,68.26 122.23,68.26 122.6,67.9 RC561.1 123.18,67.34 124.77,67.34 124.85,67.42 124.88,67.42
  TOP w0.117: 124.88,67.42 RC560.2
  BOTTOM w0.102: UC1.AP12 116.58,68.4 v2(116.58,68.41)
ON/OFF#: length 59.1
  TOP w0.102: UEC1.114 182.8,46.82 183.24,47.26 C265.1 R66.2 184.13,47.14 183.73,46.74 v2(183.38,46.74) ; v2(188.99,52.33) 189.49,52.82 JP1.1 v1(192.64,52.82) 194.77,52.82 195.05,53.1 v2(195.35,53.1) 195.35,52.8 195.7,52.46 195.7,49.76 195.95,49.51 195.95,47.3 196.71,46.54 196.71,42.76 v1(195.72,41.77) 193.79,39.84 193.79,36.39 193.84,36.34 193.95,35.79 194.26,35.06 194.68,34.42 195.59,33.52 196.96,32.95 200.22,32.95 202.1,31.07 202.1,27.59 v1(200.92,26.41) 200.05,25.55 v2(199.69,25.55)
  IN3 w0.102: v2(188.99,52.33) 188.99,51.31 187.95,50.27 186.76,50.27 186.25,50.78 185.69,50.78 184.65,49.74 184.65,48.01 v2(183.38,46.74)
  BOTTOM w0.102: JP2.1 195.05,52.8 v2(195.35,53.1) ; v2(199.69,25.55) 199.53,25.56 JIO1.11
PBTN_OUT#: length 110.5
  TOP w0.102: UEC1.122 179.6,43.32 180.36,42.56 180.36,42.41 v2(180.25,42.31)
  IN2 w0.102: v2(138.72,66.02) 138.25,65.55 136.96,65.55 135.96,66.55 132.17,66.55 131.87,66.86 127.57,66.86 126.96,67.47 123.61,67.47 123.55,67.4 122.47,67.4 121.45,68.42 121.16,68.42 120.7,68.88 119.41,68.88 119.03,68.5 v2(118.18,68.5)
  IN2 w0.117: v2(150.23,44.86) 150.16,44.86 149.27,45.75 149.27,46.44 147.84,47.86 147.84,51.31 141.25,57.9 141.25,60.83 139.84,62.24 139.84,64.04 140.26,64.45 140.26,64.85 139.09,66.02 v2(138.72,66.02)
  IN3 w0.102: v2(150.23,44.86) 150.46,44.86 150.54,44.79 152.25,44.79 153.36,43.68 153.36,31.07 156.19,28.23 158.66,28.23 160.77,30.35 163.34,30.35 163.91,30.92 167.34,30.92 168.02,31.6 172.04,31.6 172.15,31.49 173.47,31.49 173.94,31.02 177.14,31.02 179.71,33.59 179.71,34.74 180.2,35.22 180.2,37.14 180.81,37.75 180.81,41.1 180.41,41.49 180.41,42.15 v2(180.25,42.31)
  BOTTOM w0.102: UC1.AT12 117.77,68.1 v2(118.18,68.5) ; v2(138.72,66.02) 138.72,66.01 137.61,64.9 RC47.2
PC_BEEP: length 2.5
  BOTTOM w0.203: CA25.2 12.09,40.45 11.83,40.19 11.4,40.19 10.62,39.41 UA1.34
PCIE_ARX_DTX_N0: length 89
  IN1 w0.102: v2(92.37,69.5) 92.5,69.5 92.64,69.64 92.64,69.84 92.53,69.94 90.48,69.94 89.92,70.5 88.71,70.5 87.64,71.57 86.04,71.57 85.39,72.22 68.07,72.22 63.63,67.79 63.07,67.79 60.9,65.61 60.9,62.84 59.24,61.17 59.24,58.92 56.2,55.89 55.31,55.89 42.43,43.01 37.81,43.01 37.7,42.89 37.7,42.8 v2(37.9,42.59)
  BOTTOM w0.102: UC1.F11 92.48,69 92.37,69.1 v2(92.37,69.5)
  BOTTOM w0.117: JSSD1.5 24.03,42.41 24.17,42.28 25.73,42.28 26.69,43.24 28.93,43.24 29.91,44.21 v4(33.25,44.21) 36.69,44.21 37.7,43.2 37.7,42.79 v2(37.9,42.59)
PCIE_ARX_DTX_N1: length 91.7
  IN1 w0.102: v2(93.78,70.43) 93.85,70.35 94,70.35 94.1,70.45 94.1,70.8 94,70.9 92.78,70.9 92.37,70.49 90.89,70.49 90.06,71.33 89.1,71.33 87.99,72.44 86.44,72.44 85.86,73.02 67.14,73.02 60.1,65.98 60.1,63.9 58.3,62.1 58.3,59.41 57.02,58.13 55.98,58.13 41.65,43.81 36.6,43.81 32.74,39.95 30.33,39.95 29.44,39.05 29.44,38.83 v2(29.64,38.63)
  BOTTOM w0.089: UC1.H10 94.13,69.96 93.84,69.96 93.78,70.03 v2(93.78,70.43)
  BOTTOM w0.117: v2(29.64,38.63) 29.45,38.82 29.45,39.1 29.2,39.34 24.92,39.34 24.85,39.28 24.19,39.28 24.06,39.41 JSSD1.17
PCIE_ARX_DTX_N2: length 93.2
  IN1 w0.102: v2(92.37,71.5) 92.4,71.5 92.64,71.73 92.64,71.81 92.53,71.91 91.89,71.91 91.64,72.17 90.25,72.17 89.85,72.56 89.45,72.56 88.76,73.25 86.91,73.25 86.33,73.82 66.79,73.82 56.32,63.35 56.32,61.31 53.89,58.88 53.89,57.19 51.06,54.36 50.26,54.36 48.78,52.89 48.78,52.56 41.72,45.5 37.15,45.5 34.32,42.66 31.92,42.66 30.28,41.03 28.35,41.03 27.04,39.72 27.04,36.37 27.14,36.27 27.31,36.27 v2(27.52,36.48)
  BOTTOM w0.089: UC1.F8 92.67,70.69 92.6,70.62 92.42,70.62 92.32,70.72 92.32,71.44 v2(92.37,71.5)
  BOTTOM w0.117: v2(27.52,36.48) 27.32,36.28 24.15,36.28 24.01,36.41 JSSD1.29
PCIE_ARX_DTX_N3: length 99.8
  IN1 w0.102: v2(26.49,31.65) 26.7,31.86 26.99,31.86 27.46,32.32 27.46,34.53 26.24,35.75 26.24,40.05 29.66,43.46 33.98,43.46 36.82,46.31 41.39,46.31 47.39,52.3 47.39,53.24 48.56,54.41 48.56,57.5 51.4,60.34 52.2,60.34 52.95,61.09 54.73,61.09 55.31,61.68 55.31,63.48 61.12,69.28 61.12,70.05 65.71,74.64 87.11,74.64 87.53,74.22 89.49,74.22 89.91,73.81 89.91,73.71 90.71,72.9 92.35,72.9 92.43,72.83 92.43,72.62 92.32,72.52 v2(92.1,72.52)
  BOTTOM w0.102: v2(92.1,72.52) 92.22,72.52 92.67,72.07 UC1.F7
  BOTTOM w0.117: JSSD1.43 24.3,32.91 24.43,33.05 24.74,33.05 25.96,31.84 26.3,31.84 v2(26.49,31.65)
PCIE_ARX_DTX_N5: length 183.3
  IN3 w0.127: v2(195.97,17.9) 196.17,17.7 196.17,17.45 196.43,17.19 200.48,17.19 201.48,18.2 201.48,26.16 199.56,28.09 199.56,32.14 198.16,33.53 197.17,33.53 194.68,36.02 194.68,38.55 198.2,42.07 198.2,46.36 197.75,48.15 196.05,49.86 196.05,50.93 194.15,52.84 194.15,55.65 192.67,57.13 189.58,57.13 188.74,57.97 185.68,57.97 184.55,56.84 184.55,55.57 183.52,54.54 182.63,54.54 181.01,56.16 179.09,56.16 178.4,56.85 176.42,56.85 174.75,58.52 172.53,58.52 171.23,59.82 170.68,59.82 165.83,64.67 165.83,64.95 163.92,66.86 163.55,66.86 162.61,67.79 161.51,67.79 146.76,82.54 143.84,82.54 142.36,84.02 140.96,84.02 139.32,85.65 120.11,85.65 118.53,84.08 109.27,84.08 107.16,81.97 102.73,81.97 101.79,82.91 99.33,82.91 95.74,79.32 95.74,75.51 97.25,73.99 97.25,73.1 97.13,72.97 v2(96.85,72.97)
  BOTTOM w0.102: UC1.L6 96.65,72.97 v2(96.85,72.97)
  BOTTOM w0.117: JIO1.30 191.04,21.16 191.13,21.02 191.43,20.72 191.43,20.52 191.8,20.14 191.81,20.14 192.23,19.73 194.77,19.73 196.19,18.31 196.19,18.12 v2(195.97,17.9)
PCIE_ARX_DTX_N7: length 115.7
  IN3 w0.102: 102.29,75.84 102.29,75.81 102.28,75.8 102.28,75.31 101.69,74.72 101.69,73.81 99.41,71.53 96.35,71.53 95.47,72.42 94.63,72.42 94.46,72.59 94.01,72.59 93.87,72.45 v2(93.87,72.3)
  IN3 w0.127: v2(167.6,43.45) 167.41,43.65 167.1,43.65 166.69,44.06 166.69,45.28 166.95,45.54 166.95,51.61 168.27,52.93 168.27,55.71 165.6,58.38 165.16,58.38 157.93,65.62 155.75,65.62 152.36,69 151.27,69 148.67,71.61 148.57,71.61 142.4,77.78 140.08,77.78 136.41,81.45 123.77,81.45 121.36,79.05 119.18,79.05 118.72,78.58 112.97,78.58 111.94,77.55 110.23,77.55 109.68,77.01 102.56,77.01 102.29,76.74 102.29,75.84
  BOTTOM w0.102: v2(93.87,72.3) 94.17,72 UC1.H7
  BOTTOM w0.117: JWLAN1.35 165.17,36.05 165.19,36.03 165.19,36.03 165.33,35.89 165.87,35.89 166.32,36.34 166.32,36.79 166.69,37.15 166.69,43.36 166.95,43.62 167.44,43.62 v2(167.6,43.45)
PCIE_ARX_DTX_N8: length 55.1
  IN1 w0.102: v2(95.87,70) 95.87,70.3 96.02,70.44 96.22,70.44 97.22,69.43 97.22,68.85 96.61,68.24 96.61,67.32 96.26,66.96 95.65,66.96 95.07,66.38 93.55,66.38 92.78,65.62 88.3,65.62 86.53,67.39 79.67,67.39 77.87,65.59 76.03,65.59 71.7,61.26 71.7,50.09 68.34,46.74 66.12,46.74 65.99,46.87 65.99,47.02 v2(66.21,47.24)
  BOTTOM w0.102: v2(95.87,70) 95.87,69.45 95.98,69.35 96.27,69.35 96.37,69.45 UC1.L10
  BOTTOM w0.117: v2(66.21,47.24) 66.02,47.43 66.02,47.69 66.16,47.83 JSSD2.43
PCIE_ARX_DTX_N9: length 51.1
  IN1 w0.102: v2(94.57,69.5) 94.77,69.5 94.87,69.4 94.87,69.25 94.73,69.11 92.53,69.11 91.89,68.47 90.78,68.47 90.34,68.92 89.66,68.92 88.06,70.51 78.37,70.51 77.45,69.59 70.89,69.59 69.03,67.73 69.03,66.72 65.52,63.22 65.52,60.35 64.79,59.61 64.79,57.53 62.77,55.51 62.77,53.72 v2(62.55,53.51)
  BOTTOM w0.102: UC1.J11 94.97,69.1 v2(94.57,69.5)
  BOTTOM w0.117: v2(62.55,53.51) 62.75,53.32 62.75,50.27 62.79,50.22 62.79,49.7 62.66,49.56 JSSD2.29
PCIE_ARX_DTX_N10: length 52.7
  IN1 w0.102: v2(63.59,54.65) 63.81,54.44 64.25,54.44 65.59,55.77 65.59,59.28 66.32,60.02 66.32,62.89 70.4,66.96 70.4,67.97 71.22,68.79 78.15,68.79 78.93,69.57 87.2,69.57 89.32,67.46 89.82,67.46 90.01,67.65 92.1,67.65 92.54,68.09 94.01,68.09 94.14,68.23 94.14,68.4 94.04,68.5 v2(93.8,68.5)
  BOTTOM w0.102: UC1.H12 94.18,68.13 v2(93.8,68.5)
  BOTTOM w0.117: JSSD2.17 59.66,49.56 59.79,49.7 59.79,50.22 59.55,50.46 59.55,51.77 59.8,52.01 59.8,53.13 60.31,53.65 61.32,53.65 62.13,54.46 63.4,54.46 v2(63.59,54.65)
PCIE_ARX_DTX_N11: length 60.2
  IN1 w0.102: v2(56.6,47.24) 56.81,47.03 56.81,46.55 57.06,46.3 58.17,46.3 58.87,47 58.87,47.76 59.38,48.27 69,48.27 70.86,50.12 70.86,61.44 75.87,66.45 77.76,66.45 79.84,68.52 86.48,68.52 88.58,66.43 90.76,66.43 91.09,66.1 91.93,66.1 92.84,67 93.24,67 93.56,66.68 95.01,66.68 95.29,66.96 95.29,67.42 v2(95.37,67.5)
  BOTTOM w0.102: UC1.K13 95.78,67.1 v2(95.37,67.5)
  BOTTOM w0.117: JSSD2.5 56.66,47.83 56.79,47.69 56.79,47.43 v2(56.6,47.24)
PCIE_ARX_DTX_P0: length 89
  IN1 w0.102: v2(37.29,42.59) 37.51,42.81 37.51,42.97 37.73,43.2 42.36,43.2 55.23,56.08 56.12,56.08 59.05,59 59.05,61.25 60.71,62.91 60.71,65.69 62.99,67.98 63.55,67.98 67.99,72.41 85.47,72.41 86.12,71.76 87.72,71.76 88.79,70.69 90,70.69 90.56,70.13 92.61,70.13 92.83,69.92 92.83,69.75 v2(93.07,69.5)
  BOTTOM w0.102: UC1.G11 93.37,69.2 v2(93.07,69.5)
  BOTTOM w0.117: JSSD1.7 24.02,41.91 24.16,42.05 25.82,42.05 26.78,43.01 29.03,43.01 30,43.99 32.94,43.99 32.95,43.97 33.55,43.97 33.57,43.99 36.6,43.99 37.48,43.11 37.48,42.78 v2(37.29,42.59)
PCIE_ARX_DTX_P1: length 91.7
  IN1 w0.102: v2(94.58,70.4) 94.29,70.7 94.29,70.87 94.08,71.09 92.7,71.09 92.29,70.68 90.97,70.68 90.14,71.52 89.18,71.52 88.07,72.63 86.52,72.63 85.94,73.21 67.06,73.21 59.91,66.06 59.91,63.98 58.11,62.18 58.11,59.49 56.94,58.32 55.9,58.32 41.57,44 36.53,44 32.67,40.14 30.25,40.14 29.25,39.13 29.25,38.84 v2(29.03,38.63)
  BOTTOM w0.102: v2(94.58,70.4) 94.89,70.1 UC1.J10
  BOTTOM w0.117: JSSD1.19 24.07,38.91 24.2,39.05 24.95,39.05 25.02,39.12 29.11,39.12 29.23,39 29.23,38.82 v2(29.03,38.63)
PCIE_ARX_DTX_P2: length 93.2
  IN1 w0.102: v2(93.07,71.5) 92.83,71.75 92.83,71.89 92.61,72.1 91.97,72.1 91.72,72.36 90.33,72.36 89.93,72.75 89.53,72.75 88.84,73.44 86.99,73.44 86.41,74.01 66.71,74.01 56.12,63.43 56.12,61.39 53.7,58.96 53.7,57.27 50.98,54.55 50.18,54.55 48.59,52.97 48.59,52.64 41.64,45.69 37.07,45.69 34.24,42.86 31.84,42.86 30.2,41.22 28.27,41.22 26.85,39.8 26.85,36.29 27.06,36.08 27.32,36.08 v2(27.52,35.87)
  BOTTOM w0.102: UC1.G8 93.37,71.2 v2(93.07,71.5)
  BOTTOM w0.117: v2(27.52,35.87) 27.34,36.05 24.2,36.05 24.06,35.91 JSSD1.31
PCIE_ARX_DTX_P3: length 99.8
  IN1 w0.102: v2(26.49,32.26) 26.7,32.05 26.91,32.05 27.27,32.4 27.27,34.45 26.05,35.67 26.05,40.13 29.58,43.66 33.9,43.66 36.74,46.5 41.31,46.5 47.2,52.38 47.2,53.32 48.37,54.49 48.37,57.57 51.32,60.53 52.12,60.53 52.87,61.28 54.65,61.28 55.12,61.76 55.12,63.56 60.93,69.36 60.93,70.12 65.63,74.83 87.19,74.83 87.61,74.41 89.57,74.41 90.1,73.89 90.1,73.79 90.79,73.09 92.43,73.09 92.56,72.97 92.64,72.97 92.87,73.2 v2(92.87,73.27)
  BOTTOM w0.102: UC1.G6 93.37,72.76 v2(92.87,73.27)
  BOTTOM w0.117: JSSD1.41 24.3,33.41 24.43,33.28 24.84,33.28 26.05,32.06 26.29,32.06 v2(26.49,32.26)
PCIE_ARX_DTX_P5: length 183.3
  IN3 w0.127: v2(196.58,17.9) 196.39,17.71 196.39,17.54 196.52,17.42 200.38,17.42 201.26,18.29 201.26,26.07 199.33,27.99 199.33,32.04 198.07,33.31 197.07,33.31 194.45,35.93 194.45,38.64 197.97,42.16 197.97,46.33 197.55,48.04 195.83,49.76 195.83,50.84 193.92,52.74 193.92,55.55 192.57,56.9 189.49,56.9 188.64,57.74 185.77,57.74 184.77,56.75 184.77,55.48 183.61,54.31 182.54,54.31 180.91,55.94 178.99,55.94 178.31,56.62 176.33,56.62 174.65,58.3 172.43,58.3 171.14,59.59 170.59,59.59 165.6,64.58 165.6,64.86 163.83,66.63 163.45,66.63 162.52,67.57 161.42,67.57 146.67,82.31 143.74,82.31 142.27,83.79 140.86,83.79 139.22,85.43 120.2,85.43 118.63,83.85 109.37,83.85 107.26,81.74 102.63,81.74 101.69,82.68 99.42,82.68 95.96,79.22 95.96,75.6 97.48,74.09 97.48,73 96.85,72.38 v2(96.85,72.27)
  BOTTOM w0.089: UC1.L7 96.17,72 96.1,72.06 96.1,72.26 96.19,72.34 96.78,72.34 v2(96.85,72.27)
  BOTTOM w0.117: JIO1.29 191.4,21.41 191.4,21.13 191.65,20.88 191.65,20.61 191.89,20.37 191.91,20.37 192.33,19.95 194.87,19.95 196.42,18.4 196.42,18.06 v2(196.58,17.9)
PCIE_ARX_DTX_P7: length 115.8
  IN3 w0.102: v2(93.87,73) 94.09,72.79 94.55,72.79 94.72,72.62 95.55,72.62 96.43,71.73 99.33,71.73 101.49,73.89 101.49,74.81 102.07,75.39 102.07,75.8 102.06,75.81 102.06,75.84
  IN3 w0.127: 102.06,75.84 102.06,76.83 102.47,77.23 109.59,77.23 110.13,77.78 111.85,77.78 112.88,78.81 118.62,78.81 119.09,79.27 121.27,79.27 123.68,81.68 136.5,81.68 140.18,78.01 142.49,78.01 148.66,71.83 148.76,71.83 151.37,69.23 152.46,69.23 155.84,65.84 158.02,65.84 165.26,58.6 165.69,58.6 168.49,55.8 168.49,52.83 167.17,51.51 167.17,45.45 166.92,45.19 166.92,44.15 167.2,43.87 167.41,43.87 v2(167.6,44.06)
  BOTTOM w0.102: v2(93.87,73) 94.17,72.7 UC1.H6
  BOTTOM w0.117: v2(167.6,44.06) 167.39,43.85 166.86,43.85 166.47,43.46 166.47,37.25 166.1,36.88 166.1,36.43 165.78,36.11 165.42,36.11 165.29,36.25 165.28,36.25 164.98,36.55 JWLAN1.33
PCIE_ARX_DTX_P8: length 55.2
  IN1 w0.102: v2(65.6,47.24) 65.8,47.04 65.8,46.8 66.04,46.55 68.42,46.55 71.89,50.02 71.89,61.18 76.1,65.4 77.95,65.4 79.75,67.2 86.45,67.2 88.22,65.43 92.86,65.43 93.63,66.19 95.15,66.19 95.73,66.77 96.34,66.77 96.8,67.24 96.8,68.16 97.41,68.77 97.41,69.51 96.29,70.63 95.98,70.63 95.87,70.73 v2(95.87,70.8)
  BOTTOM w0.102: UC1.L9 96.27,70.4 v2(95.87,70.8)
  BOTTOM w0.117: JSSD2.41 65.66,47.83 65.79,47.69 65.79,47.43 v2(65.6,47.24)
PCIE_ARX_DTX_P9: length 51.1
  IN1 w0.102: v2(95.37,69.5) 95.17,69.5 95.06,69.4 95.06,69.18 94.81,68.92 92.61,68.92 91.97,68.28 90.7,68.28 90.26,68.73 89.58,68.73 87.98,70.32 78.45,70.32 77.53,69.4 70.97,69.4 69.22,67.65 69.22,66.65 65.71,63.14 65.71,60.27 64.98,59.53 64.98,57.45 62.96,55.43 62.96,53.72 v2(63.16,53.51)
  BOTTOM w0.102: v2(95.37,69.5) 95.78,69.1 UC1.K11
  BOTTOM w0.117: v2(63.16,53.51) 62.97,53.32 62.97,50.36 63.02,50.31 63.02,49.68 63.16,49.54 JSSD2.31
PCIE_ARX_DTX_P10: length 52.7
  IN1 w0.102: v2(94.62,68.52) 94.42,68.52 94.33,68.43 94.33,68.15 94.08,67.9 92.62,67.9 92.18,67.46 90.08,67.46 89.89,67.26 89.24,67.26 87.12,69.38 79.01,69.38 78.23,68.6 71.3,68.6 70.59,67.89 70.59,66.89 66.51,62.81 66.51,59.94 65.78,59.2 65.78,55.69 64.33,54.25 63.8,54.25 v2(63.59,54.04)
  BOTTOM w0.102: v2(94.62,68.52) 94.65,68.52 94.97,68.2 UC1.J12
  BOTTOM w0.117: JSSD2.19 60.16,49.54 60.02,49.68 60.02,50.31 59.78,50.55 59.78,51.68 60.02,51.92 60.02,53.04 60.4,53.42 61.41,53.42 62.22,54.23 63.4,54.23 v2(63.59,54.04)
PCIE_ARX_DTX_P11: length 60.1
  IN1 w0.102: v2(57.21,47.24) 57,47.03 57,46.63 57.14,46.49 58.09,46.49 58.68,47.07 58.68,47.84 59.3,48.46 68.92,48.46 70.67,50.2 70.67,61.51 75.79,66.64 77.68,66.64 79.76,68.71 86.56,68.71 88.66,66.62 90.84,66.62 91.17,66.29 91.86,66.29 92.76,67.19 93.32,67.19 93.64,66.87 94.93,66.87 95.1,67.04 95.1,67.23 94.83,67.5 v2(94.67,67.5)
  BOTTOM w0.102: UC1.J13 94.88,66.9 94.73,66.9 94.58,67.05 94.58,67.41 v2(94.67,67.5)
  BOTTOM w0.117: v2(57.21,47.24) 57.02,47.43 57.02,47.69 57.16,47.83 JSSD2.7
PCIE_ATX_C_DRX_N0: length 88.1
  IN1 w0.102: v2(69.62,71.21) 69.85,70.99 69.85,70.81 67.42,68.38 67.42,67.95 65.09,65.63 64.63,65.63 63.91,64.91 63.91,63.37 63.91,63.21 63.91,62.65 62.46,61.2 62.46,58.25 60.36,56.15 58.56,56.15 57.74,55.33 57.74,54.41 44.66,41.34 37.01,41.34 34.73,39.06 34.73,38.62 32.23,36.12 29.2,36.12 27.96,37.37 27.96,39.06 28.12,39.22 28.47,39.22 28.72,39.47 28.72,39.68 v2(28.92,39.88)
  BOTTOM w0.117: JSSD1.11 24.08,40.91 24.22,40.78 28.45,40.78 28.74,40.48 28.74,40.07 v2(28.92,39.88) ; v2(69.62,71.21) 69.83,71.42 69.83,73.52 70.79,74.48 72.69,74.48 75.02,76.81 82.91,76.81 CC2.2
PCIE_ATX_C_DRX_N1: length 82.3
  IN1 w0.102: v2(67.86,71.2) 68.06,71 68.06,70.32 66.58,68.84 66.58,68.44 65.32,67.18 65.02,67.18 63.11,65.26 63.11,63.62 60.15,60.66 60.15,57.08 60.02,56.95 58.33,56.95 58.23,56.95 56.94,55.66 56.94,54.8 44.27,42.14 36.62,42.14 33.46,38.97 33.46,38.49 31.89,36.92 29.7,36.92 29.59,37.03 29.59,37.2 v2(29.79,37.39)
  BOTTOM w0.117: CC4.2 81.01,78.2 78.58,78.2 78.56,78.22 77.99,78.22 77.98,78.2 75.43,78.2 72.4,75.17 70.42,75.17 68.04,72.79 68.04,71.38 67.86,71.2 v2(67.86,71.2) ; JSSD1.23 24.08,37.91 24.22,37.78 26.14,37.78 26.52,38.16 29.26,38.16 29.6,37.82 29.6,37.58 v2(29.79,37.39)
PCIE_ATX_C_DRX_N2: length 91.2
  IN1 w0.102: v2(60.99,74.59) 60.78,74.38 60.78,73.91 58.79,71.91 50.78,71.91 47.15,68.28 47.15,64.9 44.5,62.26 44.5,60.61 36.19,52.29 35.18,52.29 27.3,44.4 27.3,42.23 25.44,40.38 25.44,35.3 26.39,34.36 26.39,33.9 v2(26.59,33.69)
  BOTTOM w0.117: JSSD1.35 24.01,34.91 24.15,34.78 25.95,34.78 26.4,34.33 26.4,33.88 v2(26.59,33.69) ; v2(60.99,74.59) 60.8,74.4 60.8,74.15 61.36,73.59 64.27,73.59 67.06,76.38 72.34,76.38 75.43,79.47 78.9,79.47 78.93,79.49 79.49,79.49 79.51,79.47 82.85,79.47 CC6.2
PCIE_ATX_C_DRX_N3: length 93
  IN1 w0.102: v2(25.67,30.59) 25.45,30.8 25.45,31.29 25.24,31.5 25.24,34.07 24.43,34.88 24.43,42.69 35.97,54.23 37,54.23 43.46,60.7 43.46,62.81 45.43,64.78 45.43,68.67 51.61,74.85 55.5,74.85 56.81,76.15 60.44,76.15 60.54,76.05 60.54,75.85 v2(60.39,75.7)
  BOTTOM w0.117: CC8.2 81.01,80.74 80.19,80.74 80.17,80.76 79.61,80.76 79.59,80.74 78.65,80.74 78.09,80.19 75.08,80.19 72.93,78.03 62.46,78.03 60.54,76.12 60.54,75.85 v2(60.39,75.7) ; JSSD1.47 24.3,31.91 24.44,31.78 24.85,31.78 25.44,31.19 25.44,30.82 v2(25.67,30.59)
PCIE_ATX_C_DRX_N5: length 147.6
  IN3 w0.127: v2(193.72,20.65) 193.72,20.66 193.09,20.66 192.86,20.89 192.86,26.21 193.49,26.84 193.49,29.77 194.38,30.66 194.38,31.48 193.32,32.55 192.5,32.55 192.08,32.96 192.08,39.28 195.47,42.67 195.47,46.85 192.28,50.04 191.23,50.04 190.19,51.08 190.19,51.81 189.05,52.94 187.06,52.94 186.23,52.1 174.45,52.1 169.36,57.19 169.36,57.72 161.78,65.3 160.68,65.3 158.4,67.57 157.12,67.57 153.95,70.75 153.55,70.75 144.23,80.07 142.58,80.07 142.13,80.52 140.6,80.52 137.87,83.25 122.45,83.25 120.69,81.49 116.69,81.49 116.11,80.91 109.44,80.91 108.84,80.31 100.72,80.31 100.27,80.76 100.27,81.73 v2(100.16,81.84)
  BOTTOM w0.117: CC12.2 100.3,81.41 100.3,81.71 v2(100.16,81.84) ; v2(193.72,20.65) 193.38,20.65 192.62,21.41 192.61,21.43 192.55,21.44 JIO1.27
PCIE_ATX_C_DRX_N7: length 110.1
  IN3 w0.127: v2(99.55,81.44) 99.43,81.32 99.43,79.63 100.5,78.57 108.81,78.57 109.93,79.68 112.78,79.68 112.97,79.49 118.06,79.49 118.5,79.94 120.54,79.94 123.01,82.41 137.52,82.41 139.23,80.7 139.23,79.71 139.72,79.23 143.88,79.23 156.4,66.71 158.08,66.71 163.85,60.94 164.91,60.94 167.29,58.57 167.29,58.07 169.26,56.1 169.26,52.13 168.31,51.19 168.31,45.74 168.57,45.48 168.57,44.98 168.24,44.65 v2(167.57,44.65)
  BOTTOM w0.117: v2(99.55,81.44) 99.43,81.32 99.43,81 99.08,80.65 98.31,80.65 CC10.2 ; JWLAN1.29 165.15,37.55 165.25,37.66 165.45,37.66 165.87,38.09 165.87,44.53 165.99,44.65 v2(167.57,44.65)
PCIE_ATX_C_DRX_N8: length 38.9
  IN1 w0.102: v2(66.34,52.21) 66.53,52.41 66.73,52.41 66.95,52.62 66.95,59.24 67.31,59.61 67.31,62.48 67.73,62.9 68.72,62.9 72.24,66.41 72.24,67.83 v2(72.48,68.08)
  BOTTOM w0.117: v2(66.34,52.21) 66.53,52.41 67.18,52.41 67.29,52.29 67.29,49.82 67.16,49.68 JSSD2.47 ; v2(72.48,68.08) 72.27,68.29 72.27,72.31 75.38,75.42 81.26,75.42 81.37,75.3 CC110.2
PCIE_ATX_C_DRX_N9: length 40
  IN1 w0.102: v2(73.2,68.08) 73.41,67.87 73.41,66.72 69.02,62.33 68.96,62.33 68.61,61.97 68.61,60.43 67.92,59.75 67.92,52.54 67.06,51.67 64.52,51.67 64.31,51.46 64.31,51.18 v2(64.1,50.97)
  BOTTOM w0.117: CC107.2 83.02,74.38 75.61,74.38 73.4,72.17 73.4,68.27 v2(73.2,68.08) ; JSSD2.35 64.16,49.68 64.29,49.82 64.29,50.78 v2(64.1,50.97)
PCIE_ATX_C_DRX_N10: length 42.1
  IN1 w0.102: v2(60.95,50.93) 61.1,51.08 61.1,51.41 61.33,51.64 62.69,51.64 62.96,51.38 62.96,50.71 63.11,50.55 65.61,50.55 65.75,50.69 68.15,50.69 69.8,52.34 69.8,61.91 74.83,66.93 74.83,67.87 v2(74.62,68.08)
  BOTTOM w0.117: v2(60.95,50.93) 61.19,50.69 61.19,49.95 61.16,49.92 JSSD2.23 ; v2(74.62,68.08) 74.79,68.25 74.79,71.72 76.2,73.13 81.11,73.13 CC112.2
PCIE_ATX_C_DRX_N11: length 41.8
  IN1 w0.102: v2(58.05,53.41) 58.27,53.63 58.27,53.81 58.78,54.31 59.92,54.31 63.26,57.66 63.26,60.87 64.72,62.33 64.72,63.55 66.09,64.92 68.23,67.06 68.23,68.06 70.56,70.39 76.24,70.39 76.39,70.54 76.39,70.79 v2(76.24,70.95)
  BOTTOM w0.117: v2(58.05,53.41) 58.3,53.16 58.3,51.74 58.44,51.6 58.44,50.55 58.29,50.41 58.29,49.7 58.16,49.56 JSSD2.11 ; v2(76.24,70.95) 76.37,71.08 76.37,71.42 76.78,71.83 83.02,71.83 CC111.2
PCIE_ATX_C_DRX_P0: length 87.9
  IN1 w0.102: v2(28.31,39.88) 28.53,39.67 28.53,39.55 28.39,39.41 28.04,39.41 27.77,39.13 27.77,37.29 29.12,35.93 32.31,35.93 34.92,38.54 34.92,38.98 37.09,41.15 44.74,41.15 57.93,54.34 57.93,55.25 58.64,55.96 60.44,55.96 62.65,58.17 62.65,61.12 64.1,62.57 64.1,63.21 64.1,63.37 64.1,64.83 64.71,65.44 65.17,65.44 67.61,67.87 67.61,68.3 70.04,70.73 70.04,71.01 v2(70.23,71.21)
  BOTTOM w0.117: v2(28.31,39.88) 28.52,40.09 28.52,40.39 28.35,40.55 24.18,40.55 24.04,40.41 JSSD1.13 ; v2(70.23,71.21) 70.06,71.39 70.06,73.42 70.88,74.25 72.78,74.25 75.11,76.58 82.91,76.58 CC1.2
PCIE_ATX_C_DRX_P1: length 82.2
  IN1 w0.102: v2(68.44,71.19) 68.46,71.19 68.25,70.98 68.25,70.25 66.77,68.76 66.77,68.36 65.4,66.99 65.1,66.99 63.3,65.19 63.3,63.54 60.34,60.58 60.34,57 60.1,56.76 58.31,56.76 57.13,55.58 57.13,54.73 44.35,41.95 36.7,41.95 33.65,38.89 33.65,38.41 31.97,36.73 29.62,36.73 29.4,36.95 29.4,37.17 v2(29.18,37.39)
  BOTTOM w0.117: CC3.2 81.01,77.98 v4(78.27,77.98) 75.53,77.98 72.5,74.95 70.51,74.95 68.27,72.7 68.27,71.38 68.44,71.2 v2(68.44,71.19) ; v2(29.18,37.39) 29.37,37.59 29.37,37.73 29.17,37.93 26.62,37.93 26.23,37.55 24.18,37.55 24.04,37.41 JSSD1.25
PCIE_ATX_C_DRX_P2: length 91.1
  IN1 w0.102: v2(60.38,74.59) 60.59,74.38 60.59,73.99 58.71,72.1 50.7,72.1 46.96,68.36 46.96,64.98 44.31,62.34 44.31,60.69 36.11,52.48 35.1,52.48 27.11,44.48 27.11,42.31 25.25,40.46 25.25,35.22 26.19,34.28 26.19,33.9 v2(25.99,33.69)
  BOTTOM w0.117: JSSD1.37 24.04,34.41 24.18,34.55 25.86,34.55 26.18,34.23 26.18,33.88 v2(25.99,33.69) ; v2(60.38,74.59) 60.57,74.4 60.57,74.06 61.26,73.37 64.36,73.37 67.15,76.15 72.43,76.15 75.53,79.25 v4(79.19,79.25) 82.85,79.25 CC5.2
PCIE_ATX_C_DRX_P3: length 92.9
  IN1 w0.102: v2(61,75.7) 60.73,75.96 60.73,76.13 60.52,76.35 56.73,76.35 55.42,75.04 51.53,75.04 45.24,68.75 45.24,64.85 43.27,62.89 43.27,60.78 36.92,54.42 35.89,54.42 24.24,42.77 24.24,34.8 25.05,33.99 25.05,31.42 25.26,31.21 25.26,30.79 v2(25.06,30.59)
  BOTTOM w0.117: v2(61,75.7) 60.77,75.93 60.77,76.02 62.56,77.81 73.02,77.81 75.17,79.96 78.18,79.96 78.74,80.52 v4(79.87,80.52) 81.01,80.52 CC7.2 ; v2(25.06,30.59) 25.21,30.74 25.21,31.09 24.76,31.55 24.43,31.55 24.3,31.41 JSSD1.49
PCIE_ATX_C_DRX_P5: length 147.6
  IN3 w0.127: v2(100.89,81.84) 100.77,81.84 100.5,81.57 100.5,80.86 100.82,80.54 108.75,80.54 109.35,81.13 116.02,81.13 116.6,81.71 120.6,81.71 122.36,83.47 137.96,83.47 140.7,80.74 142.22,80.74 142.67,80.29 144.32,80.29 153.64,70.97 154.04,70.97 157.22,67.8 158.49,67.8 160.77,65.52 161.87,65.52 169.59,57.81 169.59,57.28 174.54,52.33 186.13,52.33 186.97,53.17 189.14,53.17 190.41,51.9 190.41,51.18 191.32,50.27 192.37,50.27 195.7,46.94 195.7,42.58 192.31,39.18 192.31,33.05 192.59,32.77 193.41,32.77 194.61,31.57 194.61,30.56 193.71,29.67 193.71,26.75 193.08,26.12 193.08,20.99 193.19,20.88 193.37,20.88 193.46,20.98 v2(193.66,21.23)
  BOTTOM w0.117: CC11.2 100.71,81.27 100.52,81.46 100.52,81.64 100.72,81.84 v2(100.89,81.84) ; JIO1.26 192.8,21.96 192.8,21.55 193.34,21.01 193.5,21.01 193.66,21.17 v2(193.66,21.23)
PCIE_ATX_C_DRX_P7: length 110
  IN3 w0.127: v2(98.94,81.44) 99.21,81.17 99.21,79.54 100.4,78.34 108.91,78.34 110.02,79.46 112.69,79.46 112.88,79.27 118.15,79.27 118.6,79.71 120.63,79.71 123.1,82.18 137.43,82.18 139.01,80.61 139.01,79.62 139.62,79 143.79,79 156.31,66.48 157.99,66.48 163.75,60.71 164.82,60.71 167.06,58.47 167.06,57.98 169.03,56.01 169.03,52.23 168.09,51.29 168.09,45.65 168.34,45.39 168.34,45.07 168.15,44.87 167.93,44.87 167.8,45.01 167.8,45.1 167.67,45.23 v2(167.56,45.23)
  BOTTOM w0.117: v2(98.94,81.44) 98.97,81.44 99.21,81.2 99.21,81.09 98.99,80.87 98.72,80.87 98.3,81.29 CC9.2 ; JWLAN1.27 165.02,38.05 165.19,37.88 165.35,37.88 165.65,38.18 165.65,44.62 165.9,44.87 167.2,44.87 167.56,45.22 v2(167.56,45.23)
PCIE_ATX_C_DRX_P8: length 39
  IN1 w0.102: v2(71.88,68.08) 72.05,67.9 72.05,66.49 68.65,63.09 67.65,63.09 67.12,62.56 67.12,59.69 66.75,59.32 66.75,52.7 66.65,52.6 66.56,52.6 v2(66.34,52.82)
  BOTTOM w0.117: CC109.2 81.11,75.64 75.29,75.64 72.05,72.41 72.05,68.25 v2(71.88,68.08) ; v2(66.34,52.82) 66.53,52.63 67.27,52.63 67.52,52.38 67.52,49.82 67.66,49.68 JSSD2.49
PCIE_ATX_C_DRX_P9: length 39.9
  IN1 w0.102: v2(73.81,68.08) 73.6,67.87 73.6,66.64 69.1,62.14 69.04,62.14 68.8,61.9 68.8,60.36 68.11,59.67 68.11,52.46 67.14,51.48 64.6,51.48 64.5,51.38 64.5,51.18 v2(64.71,50.97)
  BOTTOM w0.117: v2(64.71,50.97) 64.52,50.78 64.52,49.82 64.66,49.68 JSSD2.37 ; CC106.2 83.28,74.04 83.16,74.15 75.7,74.15 73.62,72.07 73.62,68.27 v2(73.81,68.08)
PCIE_ATX_C_DRX_P10: length 42.1
  IN1 w0.102: v2(61.56,50.93) 61.29,51.19 61.29,51.34 61.41,51.45 62.61,51.45 62.77,51.3 62.77,50.63 63.03,50.36 65.69,50.36 65.83,50.5 68.23,50.5 69.99,52.26 69.99,61.83 75.02,66.85 75.02,67.87 v2(75.23,68.08)
  BOTTOM w0.117: v2(61.56,50.93) 61.41,50.78 61.41,49.92 61.66,49.68 JSSD2.25 ; v2(75.23,68.08) 75.02,68.29 75.02,71.63 76.29,72.9 81.12,72.9 81.37,72.65 CC113.2
PCIE_ATX_C_DRX_P11: length 41.8
  IN1 w0.102: v2(76.85,70.95) 76.58,70.68 76.58,70.46 76.32,70.2 70.64,70.2 68.42,67.98 68.42,66.98 66.17,64.73 64.91,63.47 64.91,62.25 63.45,60.79 63.45,57.58 59.99,54.12 58.86,54.12 58.46,53.73 58.46,53.61 v2(58.66,53.41)
  BOTTOM w0.117: JSSD2.13 58.66,49.54 58.52,49.68 58.52,50.32 58.66,50.46 58.66,51.69 58.53,51.83 58.53,53.27 v2(58.66,53.41) ; CC108.2 83.28,71.49 83.16,71.61 76.87,71.61 76.59,71.33 76.59,71.2 v2(76.85,70.95)
PCIE_ATX_DRX_N0: length 16.2
  BOTTOM w0.102: UC1.L1 96.29,75.38 96.29,76.5 96.21,76.59 96.21,76.69 96.1,76.79 96.03,76.79 95.95,76.87 95.95,76.94 95.83,77.07 95.72,77.07 95.62,77.17 95.62,77.3 95.52,77.4 95.39,77.4 95.23,77.56 95.23,77.72 95.09,77.86 94.94,77.86 93.58,79.22 92.79,79.22 92.78,79.23 92.75,79.23
  BOTTOM w0.117: CC2.1 84.19,76.83 84.31,76.71 84.89,76.71 86.9,78.72 86.9,78.74 87.29,79.13 87.31,79.13 87.4,79.23 v4(91.48,79.23) 92.75,79.23
PCIE_ATX_DRX_N1: length 19.4
  BOTTOM w0.102: 96.16,77.65 96.18,77.63 96.33,77.63 96.44,77.52 96.44,77.36 96.55,77.25 96.71,77.25 96.84,77.12 96.84,76.74 96.75,76.65 96.75,76.51 96.87,76.4 96.87,76.26 96.75,76.14 96.75,75.69 96.93,75.51 96.93,75.15 96.88,75.1 UC1.L2
  BOTTOM w0.117: 96.16,77.65 96.05,77.75 96.05,77.88 95.88,78.06 95.75,78.06 95.66,78.15 95.66,78.3 95.52,78.44 95.37,78.44 v4(94.94,78.86) 93.88,79.92 93.41,79.92 93.4,79.94 92.85,79.94 92.84,79.92 86.55,79.92 84.68,78.05 82.8,78.05 CC4.1
PCIE_ATX_DRX_N2: length 18.8
  BOTTOM w0.089: 97.37,76.55 97.37,76.66 97.5,76.79 97.5,76.92 97.37,77.04 97.37,77.12 97.5,77.25 97.5,77.35 97.37,77.48 97.37,77.83 97.2,78.01 97.07,78.01 97.01,78.07 97.01,78.25 96.89,78.36 96.72,78.36 96.63,78.46 96.63,78.6 96.49,78.75 96.34,78.75 95.48,79.6 95.48,79.63 95.47,79.65
  BOTTOM w0.102: UC1.M2 97.88,75.08 97.88,75.09 97.88,75.51 97.88,75.51 97.88,76.04 97.37,76.55
  BOTTOM w0.117: 95.47,79.65 94.36,80.76 v4(91.56,80.76) 87.75,80.76 87.74,80.77 87.19,80.77 87.18,80.76 86.31,80.76 84.9,79.35 84.62,79.35 CC6.1
PCIE_ATX_DRX_N3: length 21.2
  BOTTOM w0.102: 96.59,79.65 96.61,79.63 96.61,79.6 96.64,79.57 96.64,79.57 98.28,77.93 98.28,77.7 98.4,77.58 98.4,77.44 98.28,77.31 98.28,77.15 98.43,76.99 98.43,76.85 98.28,76.7 98.28,76.54 98.41,76.4 98.41,76.25 98.3,76.14 98.3,75.98 98.42,75.86 98.42,75.72 98.3,75.61 98.3,75.37 UC1.N1
  BOTTOM w0.117: 96.59,79.65 95.67,80.57 94.68,81.55 v4(93.32,81.55) 89.67,81.55 89.66,81.56 89.65,81.56 89.05,81.56 89.04,81.55 85.58,81.55 84.69,80.67 82.72,80.67 CC8.1
PCIE_ATX_DRX_N5: length 13.1
  BOTTOM w0.102: UC1.R3 100.17,74.71 100.17,75.03 100.07,75.13 100.07,75.47 100.5,75.9 100.5,76.34 100.76,76.6 101.76,76.6 101.84,76.69 101.84,76.95 101.76,77.04 99.68,77.04 99.46,77.25 99.46,77.71 99.65,77.89 100.8,77.89 100.97,78.06 100.97,78.29 100.85,78.4 99.76,78.4 99.53,78.63 99.53,79 99.75,79.22 v4(100,79.22) 100.26,79.22 100.37,79.33 100.37,79.51 100.36,79.52 100.36,79.54
  BOTTOM w0.117: CC12.1 100.36,80.48 100.36,79.54
PCIE_ATX_DRX_N7: length 12.9
  BOTTOM w0.102: UC1.N4 98.88,74.47 99.23,74.82 99.23,75.01 98.91,75.33 98.91,76.47 99.05,76.61 99.05,77.5
  BOTTOM w0.117: 99.05,77.5 99.08,77.53 99.08,78.3 98.83,78.54 98.48,78.54 98.37,78.66 98.37,78.89 98.49,79.02 98.84,79.02 99.08,79.26 99.08,79.71 98.84,79.94 98.48,79.94 98.47,79.96 97.91,79.96 97.89,79.94 97.5,79.94 96.1,81.34 96.1,81.51 96.26,81.67 96.46,81.67 v4(96.85,81.27) 97.28,80.84 97.54,80.84 CC10.1
PCIE_ATX_DRX_N8: length 17.7
  BOTTOM w0.102: UC1.K4 95.88,74.47 95.57,74.78 95.57,75.06 95.68,75.17 95.68,76.03 95.6,76.11 95.6,76.12 95.38,76.33 95.38,76.33 93.59,78.12 92.79,78.12 92.78,78.11 92.75,78.11
  BOTTOM w0.117: CC110.1 82.56,75.22 84.77,75.22 v4(85.18,75.63) 86.57,77.02 86.58,77.02 87.01,77.44 87.01,77.46 87.66,78.11 92.75,78.11
PCIE_ATX_DRX_N9: length 14.8
  BOTTOM w0.102: UC1.J2 94.88,74.78 94.92,74.73 95.09,74.73 95.19,74.83 95.19,75.01 94.91,75.29 94.91,75.52 94.78,75.65 94.78,76.22 93.37,77.63 92.79,77.63 92.78,77.64 92.75,77.64
  BOTTOM w0.117: CC107.1 84.56,74.27 84.81,74.27 85.28,74.74 85.3,74.74 v4(86.53,75.96) 87.37,76.81 87.91,76.81 88.74,77.64 92.75,77.64
PCIE_ATX_DRX_N10: length 15.2
  BOTTOM w0.102: UC1.H1 94.26,75.41 94.26,75.84 94.15,75.95 94.15,76.07 94,76.23 93.87,76.23 93.79,76.31 93.79,76.46 93.67,76.59 93.51,76.59 93.19,76.91 92.79,76.91 92.78,76.92 92.75,76.92
  BOTTOM w0.117: 92.75,76.92 89.51,76.92 87.93,75.34 87.03,75.34 86.59,74.9 86.56,74.9 86.16,74.49 86.16,74.46 84.62,72.93 82.4,72.93 82.29,73.05 CC112.1
PCIE_ATX_DRX_N11: length 13.4
  BOTTOM w0.102: UC1.H2 93.88,74.91 93.88,75.53 93.25,76.17 92.79,76.17 92.78,76.18 92.75,76.18
  BOTTOM w0.117: CC111.1 84.17,72.09 83.99,71.92 83.99,71.75 84.11,71.63 84.81,71.63 85.19,72.01 85.47,72.01 85.49,72.03 86.03,72.03 86.04,72.01 86.14,72.01 v4(86.8,72.67) 88.27,74.15 88.27,74.6 89.84,76.18 92.75,76.18
PCIE_ATX_DRX_P0: length 16.2
  BOTTOM w0.102: 92.75,79 92.78,79 92.79,79.01 93.51,79.01 96.1,76.42 96.1,75.45 96.07,75.4 96.07,75.17 96.24,75 96.24,74.63 UC1.L3
  BOTTOM w0.117: 92.75,79 91.76,79 91.74,78.98 91.2,78.98 91.19,79 87.5,79 v4(87.26,78.76) 84.98,76.49 84.46,76.49 CC1.1
PCIE_ATX_DRX_P1: length 19.4
  BOTTOM w0.102: 96.01,77.5 96.03,77.49 96.04,77.49 96.08,77.45 96.08,77.45 96.56,76.97 96.56,75.69 96.55,75.68 96.55,75.63 96.74,75.44 96.74,75.23 96.56,75.06 96.56,74.76 96.88,74.44 UC1.L4
  BOTTOM w0.117: CC3.1 82.5,77.83 84.78,77.83 86.64,79.7 v4(93.12,79.7) 93.82,79.7 96.01,77.5
PCIE_ATX_DRX_P2: length 18.9
  BOTTOM w0.089: 97.24,76.42 97.23,76.43 97.23,76.44 97.19,76.47 97.19,76.63 97.2,76.63 97.2,77.63 95.36,79.47 95.33,79.47 95.31,79.49
  BOTTOM w0.102: 97.24,76.42 97.69,75.96 97.69,75.59 97.69,75.58 97.69,75.17 97.58,75.06 97.58,74.76 97.88,74.46 UC1.M4
  BOTTOM w0.117: 95.31,79.49 94.26,80.54 91.87,80.54 91.85,80.52 91.3,80.52 91.28,80.54 v4(87.47,80.54) 86.4,80.54 84.99,79.13 84.37,79.13 CC5.1
PCIE_ATX_DRX_P3: length 21.2
  BOTTOM w0.102: 96.43,79.49 96.45,79.47 96.46,79.47 98.09,77.85 98.09,76.31 98.1,76.3 98.1,75.45 98.07,75.43 98.07,75.17 98.1,75.15 98.1,75.13 98.21,75.01 98.21,74.66 UC1.N3
  BOTTOM w0.117: 96.43,79.49 94.59,81.33 93.61,81.33 93.59,81.31 93.05,81.31 93.04,81.33 v4(89.35,81.33) 85.67,81.33 84.79,80.45 82.58,80.45 CC7.1
PCIE_ATX_DRX_P5: length 13.1
  BOTTOM w0.102: UC1.R1 100.37,75.14 100.46,75.05 100.6,75.05 100.75,75.2 100.88,75.2 101.05,75.37 101.05,75.53 100.87,75.71 100.82,75.71 100.69,75.84 100.69,76.26 100.84,76.41 101.83,76.41 102.04,76.61 102.04,77.03 101.83,77.23 99.75,77.23 99.65,77.33 99.65,77.63 99.73,77.7 v4(100.31,77.7) 100.88,77.7 101.16,77.98 101.16,78.37 100.93,78.59 99.84,78.59 99.72,78.71 99.72,78.92 99.83,79.02 100.34,79.02 100.56,79.25 100.56,79.53 100.57,79.54
  BOTTOM w0.117: 100.57,79.54 100.57,79.63 100.57,80.46 CC11.1
PCIE_ATX_DRX_P7: length 13
  BOTTOM w0.102: 98.87,77.6 98.85,77.58 98.85,77.42 98.85,77.41 98.85,76.7 98.71,76.56 98.71,75.2 98.52,75.01 98.52,74.81 98.64,74.68 98.79,74.68 98.88,74.77 UC1.N2
  BOTTOM w0.117: 98.87,77.6 98.87,78.21 98.74,78.34 98.4,78.34 98.16,78.57 98.16,78.98 98.41,79.23 98.75,79.23 98.87,79.34 98.87,79.6 98.75,79.72 v4(98.18,79.72) 97.4,79.72 95.88,81.25 95.88,81.61 96.16,81.89 96.55,81.89 96.72,81.73 96.79,81.65 96.81,81.65 97.23,81.23 97.23,81.21 97.38,81.07 97.49,81.07 CC9.1
PCIE_ATX_DRX_P8: length 17.7
  BOTTOM w0.102: 92.75,78.34 92.78,78.34 92.79,78.33 93.65,78.33 95.46,76.52 95.46,76.52 95.79,76.2 95.79,76.19 95.87,76.11 95.87,74.9 UC1.K2
  BOTTOM w0.117: CC109.1 82.24,75.9 82.06,75.73 82.06,75.56 82.18,75.44 84.68,75.44 84.82,75.58 84.82,75.62 85.3,76.1 85.33,76.1 v4(86.63,77.4) 87.57,78.34 92.75,78.34
PCIE_ATX_DRX_P9: length 14.8
  BOTTOM w0.102: UC1.J4 94.88,74.43 94.56,74.74 94.56,75.04 94.71,75.19 94.71,75.45 94.59,75.57 94.59,76.12 93.29,77.42 92.79,77.42 92.78,77.41 92.75,77.41
  BOTTOM w0.117: CC106.1 84.56,74.04 84.92,74.04 v4(85.18,74.3) 86.41,75.53 86.44,75.53 86.97,76.06 86.97,76.09 87.47,76.59 88,76.59 88.83,77.41 92.75,77.41
PCIE_ATX_DRX_P10: length 15.3
  BOTTOM w0.102: UC1.H3 94.28,74.6 94.28,74.99 94.08,75.18 94.08,75.32 94.07,75.33 94.07,75.74 93.65,76.17 93.11,76.7 92.79,76.7 92.78,76.69 92.75,76.69
  BOTTOM w0.117: CC113.1 82.58,72.71 84.72,72.71 v4(86.55,74.54) 87.12,75.11 88.03,75.11 89.61,76.69 92.75,76.69
PCIE_ATX_DRX_P11: length 13.5
  BOTTOM w0.102: 92.75,75.95 92.78,75.95 92.79,75.96 93.16,75.96 93.68,75.45 93.68,75.15 93.55,75.02 93.55,74.77 93.88,74.45 UC1.H4
  BOTTOM w0.117: 92.75,75.95 89.93,75.95 88.49,74.51 88.49,74.05 87.16,72.72 87.16,72.7 86.71,72.25 86.68,72.25 86.23,71.79 v4(85.76,71.79) 85.28,71.79 84.9,71.41 84.46,71.41 CC108.1
PCIE_DET1: length 142.5
  TOP w0.117: v3(27.62,26.06) 27.96,25.72 v2(27.96,25.25)
  IN2 w0.102: v2(120.36,71.53) 119.93,71.1 119.4,71.1 118.34,70.05 116.46,70.05 116.03,69.62 115.43,69.62 115.31,69.5 115.31,68.21 114.94,67.85 113.71,67.85 113.35,68.2 113.35,68.41 112.18,69.58 110.87,69.58 109.52,68.22 107.67,68.22 107.42,68.47 107.42,69.8 106.34,70.88 106.34,72.73 105.77,73.3 105.77,74.41 105.23,74.95 94.59,74.95 93.46,73.82 93.46,72.2 93.17,71.9 90.91,71.9 89.96,70.95 89.07,70.95 87.86,69.74 87.74,69.74
  IN2 w0.127: 87.74,69.74 85.07,69.74 83.4,68.08 83.4,65.05 83.2,64.85 82.16,64.85 v2(82.13,64.83) 82.01,64.7 82.01,63.66 79.16,60.81 76.11,60.81 74.77,59.48 74.29,59.48 73.68,58.87 73.43,58.87 71.09,56.52 65.93,56.52 64.5,57.95 58.31,57.95 56.59,56.23 55.88,56.23 52.72,53.07 49.34,53.07 46.26,49.98 46.26,48.9 38.54,41.18 36.03,41.18 34.97,40.11 31.82,40.11 31.28,39.58 31.28,32.67 29.4,30.79 29.4,27.46 27.96,26.01 v2(27.96,25.25)
  BOTTOM w0.089: UC1.BA6 121.27,72.29 120.66,72.29 120.49,72.12 120.49,71.66 v2(120.36,71.53)
  BOTTOM w0.117: RC45.2 82.72,65.41 v2(82.13,64.83) ; v2(27.96,25.25) 27.93,25.23 26.79,25.23 25.6,26.41 JSSD1.61
PCIE_DET2: length 90.3
  IN2 w0.102: 124.48,72.6 121.68,72.6 121.17,72.09 119.65,72.09 119.31,71.75 119.31,71.3 118.4,70.39 115.69,70.39 115.1,69.8 114.34,69.8 114.09,69.55 112.67,69.55 112.37,69.84 112.37,70.05 112.05,70.37 111.01,70.37 111.01,70.38 110.69,70.38 110.63,70.31 107.61,70.31 107.29,70.63 107.29,71.33 107.37,71.4 107.37,73.22 107.04,73.55 106.16,73.55 105.97,73.74 105.97,74.49 105.2,75.27 94.59,75.27 93.26,73.93 93.26,72.28 93.1,72.12 90.77,72.12 89.94,71.29 88.97,71.29 87.74,70.06
  IN2 w0.127: v2(71.26,59.85) 72.25,59.85 74.54,62.13 78.72,62.13 80.64,64.05 80.64,65.13 81.45,65.94 81.45,66.81 84.7,70.06 87.74,70.06 ; v2(124.78,72.75) 124.63,72.6 124.48,72.6
  BOTTOM w0.102: 124.22,72.8 124.17,72.85 123.56,72.85 123.24,72.54 122.76,72.54 122.29,72.07 121.94,72.07 UC1.BB7
  BOTTOM w0.117: v2(71.26,59.85) 71.64,59.47 71.64,52.48 72.66,51.47 JSSD2.61 ; 124.22,72.8 124.73,72.8 v2(124.78,72.75) 124.83,72.8 126.31,72.8 127.3,73.79 v3(127.93,73.79) 129.78,73.79 130.62,74.63 RC593.2
PCIE_WAKE#_SOC: length 45.9
  IN2 w0.102: 124.22,73.17 124.15,73.17 124.02,73.04 117.96,73.04 117.34,72.43 117.34,72.09 117.17,71.92 116.49,71.92 116.35,72.07 116.35,72.45 116.07,72.73 115.59,72.73 115.36,72.5 115.36,71.61 115.13,71.38 115.13,71.38 114.98,71.23 114.49,71.23 114.29,71.43 114.29,71.89 114.14,72.04 113.66,72.04 113,72.7 111.07,72.7 111.01,72.65 109.23,72.65 v2(108.87,73)
  IN2 w0.127: 124.22,73.17 125.02,73.17 125.34,72.85 125.34,71.87 128.23,68.98 139.63,68.98 142.92,65.7 142.92,64.41 143.73,63.59 v2(143.73,63.15)
  BOTTOM w0.102: UC1.AE6 108.57,72.7 v2(108.87,73)
  BOTTOM w0.117: RC617.2 143.78,63.1 v2(143.73,63.15) 143.69,63.15 v3(143.33,62.79)
PCIE_WAKE#_WL: length 2.9
  TOP w0.117: RWL14.1 v2(165.65,32.53) 165.52,32.53 v3(165.08,32.09)
  BOTTOM w0.117: v2(165.65,32.53) 165.13,33.05 JWLAN1.47
PD_GPIO10: length 5
  TOP w0.117: v3(43.86,88.92) 43.67,88.92 42.83,88.08 RT72.1 42.38,88.35 41.62,88.35 41.41,88.14 41.41,87.75 40.93,87.27 40.68,87.27 40.39,86.97 UT1.1
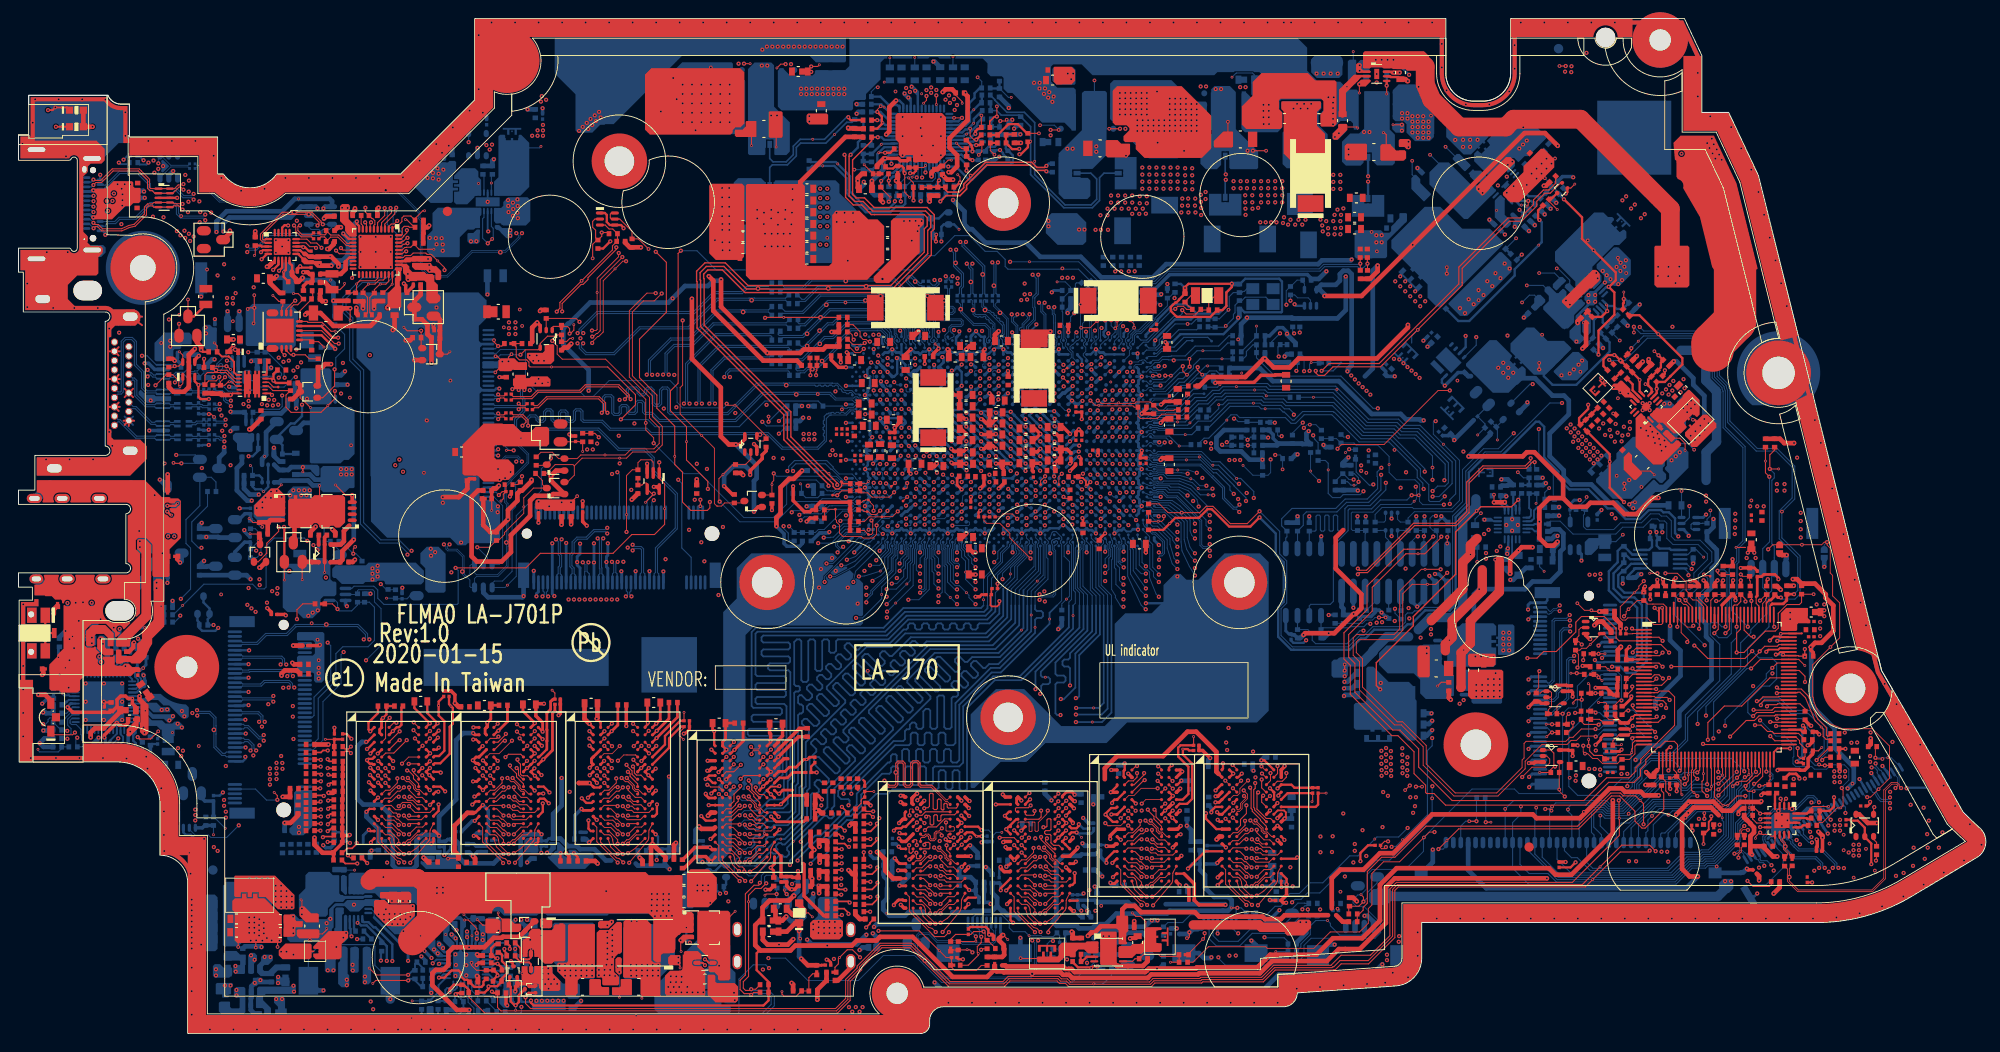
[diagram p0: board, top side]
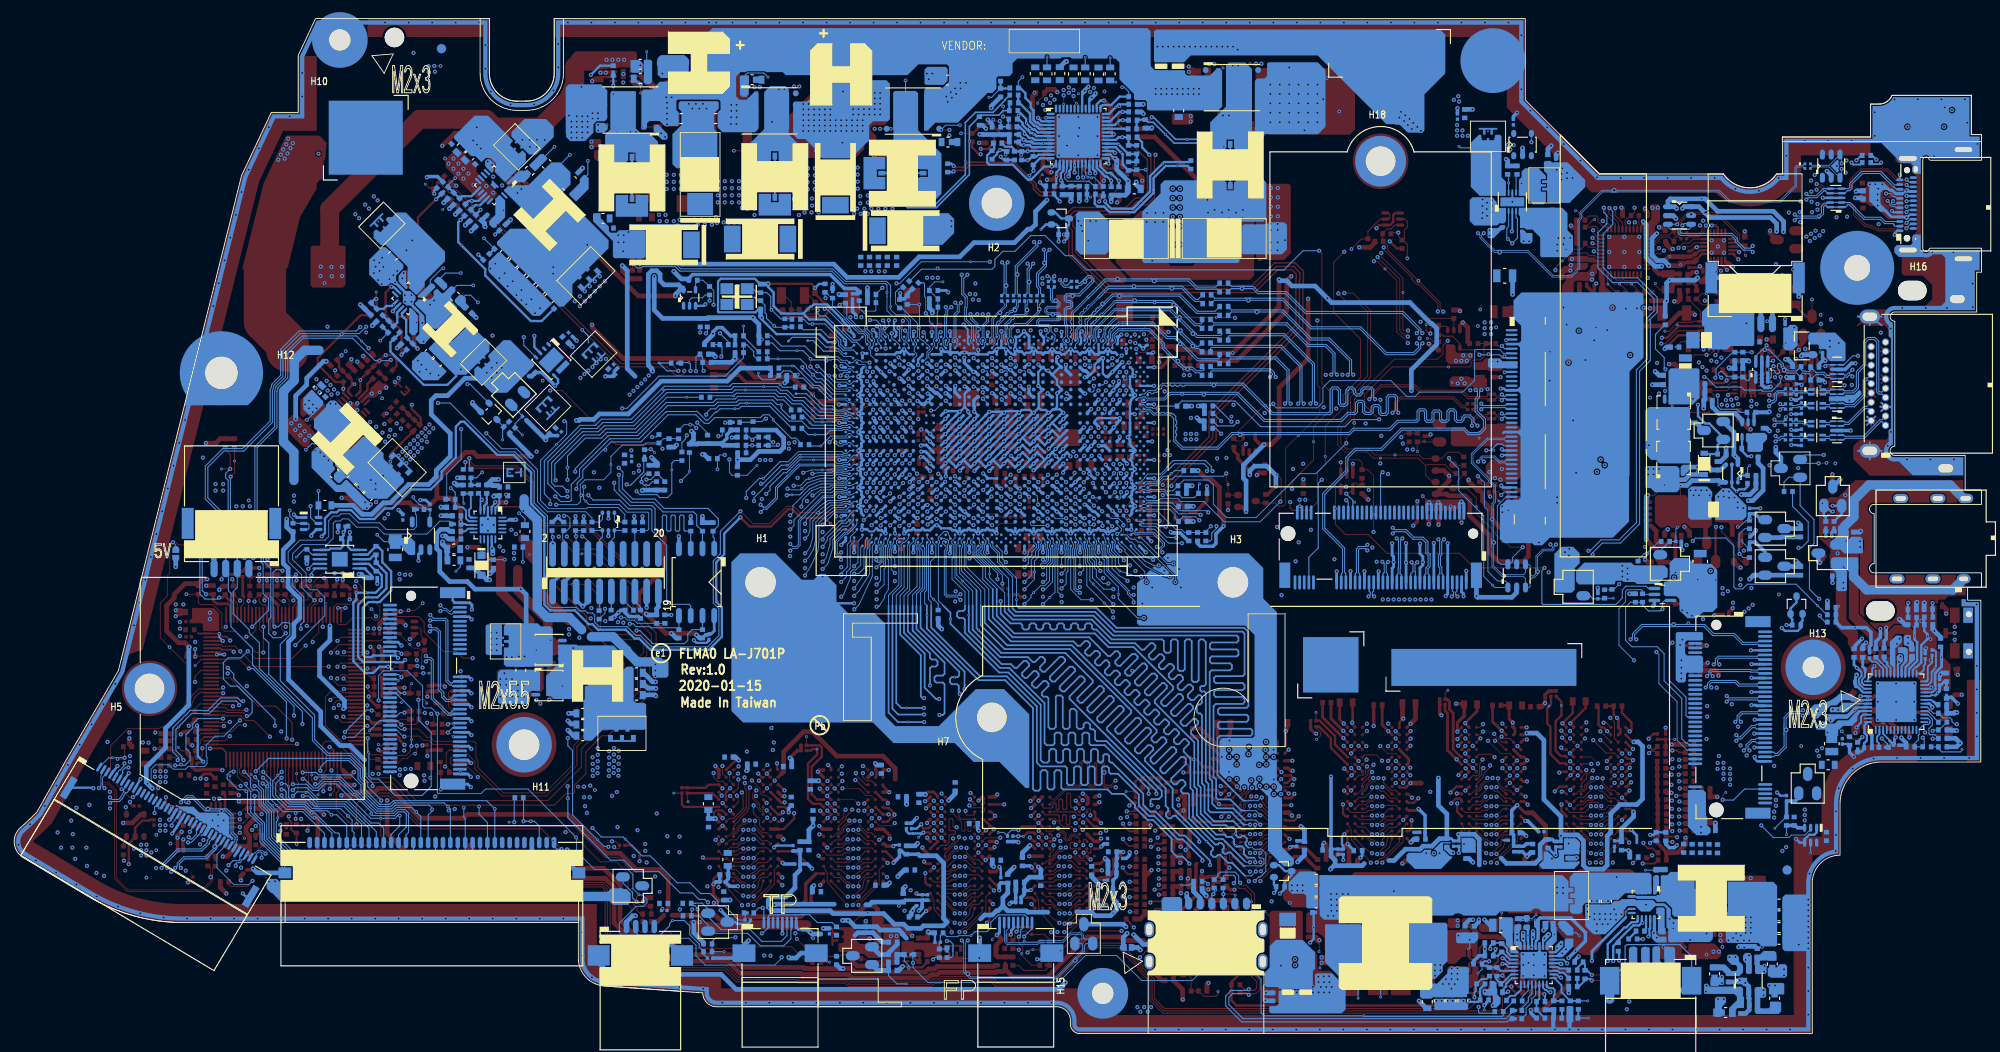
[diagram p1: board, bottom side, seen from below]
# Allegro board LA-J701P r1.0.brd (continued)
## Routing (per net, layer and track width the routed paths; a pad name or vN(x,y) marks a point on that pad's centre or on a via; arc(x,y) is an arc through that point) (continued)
PD_GPIO11: length 3.9
  TOP w0.117: 42.76,87.14 41.93,87.97 v3(41.79,87.97) ; 42.76,87.14 RT73.1 ; 42.76,87.14 42.22,87.14 42.12,87.24 41.65,87.24 41.44,87.03 41.44,86.39 41.33,86.27 UT1.40
PD_GPIO15: length 4.5
  TOP w0.117: v3(44.87,84.76) 43.27,84.76 42.8,85.22 RT74.1 42.37,84.98 41.91,84.98 41.88,84.95 41.7,84.95 41.43,84.67 UT1.36
PD_PWR_EN: length 189.1
  TOP w0.117: UEC1.66 189.72,31.63 v2(189.22,32.14) ; QT4.2 43.49,74.19 CT73.1 v2(43.49,75.95) 41.98,75.95 v3(41.62,76.31)
  IN2 w0.127: v2(189.22,32.14) 189.4,32.14 190.36,33.1 190.36,35.63 188.38,37.61 188.38,37.87 187.91,38.34 187.91,39.64 186.9,40.66 185.05,40.66 182.72,42.99 182.72,45.5 179.65,48.58 179.65,49.31 177.21,51.75 176.14,51.75 176.11,51.72 175.91,51.72 173.8,53.83 173.8,55.07 172.15,56.72 172.15,57.13 164.79,64.49 164.79,64.7 164.79,65.46 164.43,65.82 163.43,65.82 159.45,69.79 159.45,70.56 156.3,73.71 154.29,73.71 152.09,75.91 149.8,75.91 149.41,76.31 149.41,76.59 145.34,80.65 141,80.65 137.81,83.84 108.8,83.84 107.2,82.24 102.66,82.24 101.87,83.03 81.26,83.03 74.13,75.9 64.2,75.9 62.18,73.88 59.46,73.88 57.8,72.22 54.67,72.22 53.25,73.64 49.45,73.64 47.14,75.95 v2(43.49,75.95)
PDB: length 2.1
  BOTTOM w0.203: UA1.2 11.02,32.34 11.29,32.07 11.29,31.56 11.08,31.35 RA8.2
PLT_RST_SSD1#: length 28.3
  TOP w0.117: RSD16.1 33.9,46.44 v2(34.46,45.87)
  BOTTOM w0.117: USD1.4 34.22,46.8 34.46,46.56 v2(34.46,45.87) 34.66,45.67 35.98,45.67 36.62,46.31 RSD8.1 RSD3.1 37.9,46.61 38.45,46.07 38.45,42.49 37.76,41.8 35.03,41.8 34.28,41.05 34.28,38.13 32.38,36.23 32.38,31.86 31.92,31.4 31.78,31.4 31.54,31.17 JSSD1.50
PLT_RST_SSD2#: length 57.9
  TOP w0.117: v2(30.08,44.79) 30.08,45.8 30.71,46.44 RSD16.2 ; RSD9.1 RSD7.1 67.34,59.28 67.55,59.49 67.81,59.49 67.91,59.39 USD2.4 68.4,58.35 v2(68.62,58.35) 68.62,58.3 v3(67.73,57.41)
  IN2 w0.127: v2(66.18,58.76) 67.16,58.76 67.57,58.35 v2(68.62,58.35)
  IN3 w0.127: v2(30.08,44.79) 30.08,46.12 30.8,46.84 39.2,46.84 41.19,48.83 41.19,52.89 43.86,55.56 53.46,55.56 55.86,57.95 64.64,57.95 65.45,58.76 v2(66.18,58.76)
  BOTTOM w0.117: v2(68.62,58.35) 67.91,57.63 JSSD2.50
PLUG_IN: length 22.8
  TOP w0.127: v1(15.09,32.66) 14.27,31.83 13.07,31.83 v2(12.87,32.03)
  IN1 w0.254: JP3.6 9.12,46.33 8.28,45.49 8.28,44.16 12.58,39.87 12.58,33.08 12.87,32.79 v2(12.87,32.03)
  BOTTOM w0.254: RA33.2 13.38,31.53 v2(12.87,32.03)
PLUG_IN_R: length 4.1
  BOTTOM w0.203: UA1.48 12.64,33.29
  BOTTOM w0.254: RA33.1 13.3,30.47 12.93,30.47 12.67,30.73 RT75.2 12.67,31.37 12.39,31.65 12.39,32.23 12.64,32.49 12.64,33.29
PM_SLP_S3#: length 101.1
  TOP w0.102: v2(174.36,41.18) 174.36,41.28 174.72,41.63 UEC1.6 ; UC23.4 166.51,29.33 166.42,29.24 RC598.1 v1(166.42,26.37) 166.42,26.21 v2(167.02,25.61)
  TOP w0.117: v2(103.98,9.05) 104.07,9.05 104.19,9.16 RFP8.1
  IN2 w0.102: v2(174.36,41.18) 174.36,41.1 173.85,40.59 173.85,39.1 175.45,37.5 175.45,30.97 173.59,29.1 172.23,29.1 171.26,28.14 171.26,27.09 169.97,25.8 167.21,25.8 v2(167.02,25.61) 166.18,24.77 164.43,24.77 163.09,23.42 155.67,23.42 152.19,19.94 151.43,19.94 151.4,19.97 150.99,19.97 150.99,19.94 146.8,15.75 146.8,14.3 145.84,13.34 144.47,13.34 142.88,11.75 140.37,11.75 139.69,11.08 138.15,11.08 136.93,9.86 135.96,9.86 134.89,8.79 132.88,8.79 132.35,9.33 131.23,9.33 130.8,8.9 v2(130.8,8.41)
  IN3 w0.102: v2(103.98,9.05) 106.95,9.05 107.42,8.58 114.09,8.58 114.73,9.21 118.71,9.21 118.98,8.95 129.94,8.95 130.47,8.41 v2(130.8,8.41)
PM_SLP_S3#_R: length 100.1
  TOP w0.117: v3(164.32,28.21) RC598.2 165.51,28.52 165.84,28.85 v2(165.97,28.85) 165.84,28.97 165.84,30.31 165.51,30.64 UC23.1
  IN1 w0.102: v2(118.18,69.5) 118.71,68.97 118.71,68.23 119.07,67.87 122.68,67.87 123.8,66.76 130.42,66.76 131.13,66.05 134.93,66.05 136.01,64.97 137.03,64.97 139.28,62.72 141.41,62.72 142.3,63.61 144.04,63.61 145.46,62.19 145.46,59.06 145.96,58.55 145.96,49.1 143.32,46.46 143.32,41.92 144.94,40.31 144.94,28.95 147.11,26.78 147.74,26.78 149.5,25.02 150.44,25.02 v2(150.94,25.53)
  IN3 w0.127: v2(165.97,28.85) 165.65,28.53 165.65,26.94 162.35,23.64 162.02,23.64 160.74,22.36 157.06,22.36 154,25.42 151.06,25.42 v2(150.94,25.53)
  BOTTOM w0.102: UC1.AT11 118.18,69.4 v2(118.18,69.5)
PM_SLP_S5#: length 171.9
  TOP w0.102: PR251.1 v1(127.95,10.21) 128.12,10.38 v2(128.12,10.84) ; UEC1.123 179.2,43.98 v2(179.18,43.96)
  IN1 w0.102: v2(128.12,10.84) 128.62,11.33 132.91,11.33 134.26,9.99 136.65,9.99 137.6,10.94 140,10.94 152.27,23.22 152.27,29.97 152.12,30.12 152.12,35.4 152.52,35.79 152.52,41.92 151.65,42.78 v2(151.45,42.78)
  IN2 w0.102: v2(151.45,42.78) 152.04,43.36 152.04,47.27 149.31,50 149.31,52.2 148.17,53.35 148.15,53.35 146.57,54.92 146.57,56.16 143.81,58.93 143.81,60.3 141.93,62.18 141.93,65.3 139.38,67.85 127.98,67.85 126.09,69.74 124.03,69.74 123.79,69.5 121.69,69.5 121.2,70 120.17,70 v2(119.67,69.5)
  IN3 w0.102: v2(151.45,42.78) 151.97,42.78 152.7,42.06 152.7,35.77 151.43,34.5 151.43,27.51 151.87,27.06 151.87,26.55 152.1,26.32 153.47,26.32 153.58,26.43 159.77,26.43 161.64,28.3 163.01,28.3 164.47,29.76 167.53,29.76 167.7,29.58 173.42,29.58 173.81,29.98 178.04,29.98 180.96,32.9 180.96,33.83 181.29,34.16 181.29,34.67 183.04,36.42 183.04,42.1 181.95,43.2 180.6,43.2 180.03,43.77 179.37,43.77 v2(179.18,43.96)
  BOTTOM w0.102: v2(119.67,69.5) 119.37,69.2 UC1.AV11
PTM_EN#: length 170.3
  TOP w0.117: UEC1.107 185.6,43.98 v2(185.58,43.96) ; v2(172.85,25.19) 172.88,25.16 172.88,23.29 v3(172.91,23.26) 172.91,21.41 167.84,16.33 148.84,16.33 148.13,15.62 148.13,10.57 146.03,8.46 142.87,8.46 141.77,7.37 135.57,7.37 134.27,6.07 127.72,6.07 127.59,5.94 122.54,5.94 122.16,5.56 113.64,5.56 113.3,5.9 112.64,5.9 112.37,6.17 106.89,6.17 106.34,5.62 100.63,5.62 96.49,9.76 93.06,9.76 90.59,7.3 90.59,7.09 89.34,5.84 89.34,3.78 88.26,2.7 55.31,2.7 54.77,3.24 v2(54.77,3.9)
  TOP w0.254: v2(54.77,3.9) 54.77,4.06 55.1,4.39 PQB4.2
  BOTTOM w0.117: v2(172.85,25.19) 172.85,25.22 174.31,26.68 174.31,27.16 174.87,27.72 174.87,28.7 176.2,30.03 178.66,30.03 180.29,31.67 180.29,34.13 185,38.84 185,42.22 185.58,42.8 v2(185.58,43.96)
  BOTTOM w0.203: v2(54.77,3.9) 54.77,4.45 54.64,4.58 54.64,5.25 PRB31.2 54,5.89 53.47,5.89 PRB30.1
PWM3_CPU: length 2.7
  TOP w0.117: v2(147.78,102.44) v3(147.78,101.54)
  TOP w0.254: PU802.5 v2(147.78,102.44)
  BOTTOM w0.254: PR847.1 147.8,102.88 147.78,102.87 v2(147.78,102.44)
PWM3_CPU_IC: length 87.3
  TOP w0.117: v2(101.91,98.96) v1(101.05,98.96)
  IN3 w0.254: v2(101.91,98.96) 101.62,98.67 101.62,93.35 103.01,91.96 103.01,88.75 106.39,85.37 118.49,85.37 119.67,86.56 139.69,86.56 141.33,84.92 150.35,84.92 153.37,87.94 153.37,99.87 151.62,101.62 151.62,102.25 150.85,103.02 150.8,103.02 v2(150.21,103.61)
  BOTTOM w0.254: PU801.3 101.52,98.59 101.88,98.95 101.9,98.95 v2(101.91,98.96) ; PR847.2 149.22,104.6 v2(150.21,103.61)
PWR_LED#: length 273.5
  TOP w0.117: v2(178.53,39.65) 186.49,39.65 188.08,41.25 v2(188.08,41.31) 188.62,41.85 189.97,41.85 190.15,42.03 UEC1.92
  IN1 w0.102: v2(195.49,22.48) 195.19,22.78 195.19,28 193.55,29.65 192.4,29.65 192.26,29.79 190.91,29.79 188.61,32.09 188.61,34.22 189.34,34.94 189.34,35.6 188.13,36.81 187.11,36.81 186.73,37.19 186.73,39.71 188.08,41.05 v2(188.08,41.31)
  IN2 w0.102: 92.75,76.94 93.86,76.94
  IN2 w0.127: v2(33.2,49.28) 33.69,49.77 36.84,49.77 45.47,58.4 46.4,58.4 47.23,57.56 50.52,57.56 51.72,58.76 52.18,58.76 54.08,60.66 54.91,60.66 58.14,63.89 59.58,63.89 60.85,65.16 62.98,65.16 64.13,64.01 65.55,64.01 65.7,64.17 65.7,65.99 66.26,66.55 76.24,66.55 86.63,76.94 92.75,76.94 ; v2(149.88,60.66) 150.32,61.11 150.32,63.29 145.94,67.66 145.9,67.66 142.48,71.08 142.48,72.38 141.87,72.99 137.21,72.99 136.69,72.47 134.48,72.47 133.6,73.35 130.22,73.35 128.84,74.72 126.67,74.72 125.4,75.99 123.17,75.99 122.53,75.35 122.53,75.33 122.08,74.87 110.81,74.87 109.73,75.95 108.36,75.95 107.66,76.65 107.14,76.65 106.21,77.58 94.49,77.58 93.86,76.94
  IN3 w0.127: v2(149.88,60.66) 149.2,60.66 148.78,60.24 148.78,55.13 149.57,54.34 149.57,52.58 150.3,51.84 154.08,51.84 155.45,53.21 155.45,56.36 156.97,57.88 159.67,57.88 159.81,57.74 159.81,57.17 160.98,56 161.54,56 163.06,54.48 163.06,46.42 162.64,46 162.64,44.61 163.33,43.93 163.33,40.82 163.4,40.74 163.4,40.38 163.1,40.07 163.1,38.89 166.07,35.91 167.77,35.91 168.03,35.65 169.84,35.65 169.92,35.73 171.34,35.73 171.71,35.36 172.24,35.36 172.43,35.16 172.64,34.93 172.78,34.79 173.08,34.49 174.07,34.49 174.19,34.6 174.58,34.6 175.01,35.03 175.33,35.03 175.89,35.59 175.89,40.16 176.09,40.37 177.82,40.37 v2(178.53,39.65) ; v2(19.76,52.5) 20.46,52.5 22.19,50.77 26.35,50.77 27.84,49.28 v2(33.2,49.28)
  BOTTOM w0.117: RS5.1 20.41,56.98 18.72,55.29 18.72,53.23 19.44,52.5 v2(19.76,52.5) ; v2(195.49,22.48) 195.51,22.58 JIO1.21
PWR_LED#_R: length 42.2
  TOP w0.117: LED4.1 3.88,32.29 5.85,32.29 v2(6.09,32.53)
  IN2 w0.127: v2(6.09,32.53) 6.91,33.36 9.82,33.36 11.47,35.01 13.38,35.01 15.47,37.1 15.47,40.4 17.05,41.98 17.05,45.92 17.54,46.4 v2(17.54,46.98)
  BOTTOM w0.117: RS5.2 21.33,59.61 20.82,60.11 D33.2 19.59,57.04 18.09,55.54 18.09,52.96 18.58,52.47 18.58,48.02 v2(17.54,46.98)
PWR_SW_DVDT: length 5.2
  TOP w0.117: CT70.1 21.45,74.33 v3(21.15,74.63)
  TOP w0.203: UT4.9 23.56,71.18 23.28,71.46 23.28,72.6 22.71,73.17 22.71,73.17 22.7,73.18 21.96,73.18 CT70.1
PWR_SW_FRS: length 50
  TOP w0.117: RT89.1 31.4,72.93 30.98,73.35 v2(29.7,73.35) 29.39,73.35 28.93,73.81 UT6.3 ; UT4.10 23.4,70.78 22.5,71.68 21.25,71.68 RT58.2 21.08,72.12 v2(22.46,72.12) 22.56,72.12 v3(22.9,71.77) ; v2(38.08,87.67) 37.99,87.58 UT1.7
  IN1 w0.102: v2(22.46,72.12) 22.34,72.12 21.7,72.76 21.7,79.77 23.66,81.74 27.1,81.74 27.85,80.99 33.58,80.99 35.49,82.9 35.49,87.34 36.33,88.18 37.82,88.18 38.08,87.93 v2(38.08,87.67)
  IN2 w0.127: v2(22.46,72.12) 25.66,72.12 27.35,73.81 28.93,73.81 29.39,73.35 v2(29.7,73.35)
PWR_SW_ILIM: length 26.7
  TOP w0.117: v2(29.89,79.2) 29.82,79.2 28.93,78.31 UT6.11 ; 29.35,69.49 29.35,69.46 28.89,69 28.89,67.69 29.44,67.14 32.68,67.14 v3(33.41,67.87) 34.17,68.63 v2(34.17,69.44) ; 29.35,69.49 27.47,69.49 26.98,69.98 UT4.3 ; 29.35,69.49 RT67.1
  IN1 w0.102: v2(29.89,79.2) 32.43,79.2 33.32,78.31 33.32,70.3 v2(34.17,69.44)
PWR_SW_ILIM_R: length 4.6
  TOP w0.117: v3(31.54,67.65) 31,68.18 30.99,68.18 30.8,68.37 30.75,68.37 30.42,68.7 QT2.1
  TOP w0.508: RT66.2 30.42,70.06 QT2.1 29.63,68.57 RT67.2
REGN: length 25.7
  TOP w0.254: PRB16.1 51.97,8.76 52.23,8.5 52.23,7.82 52.76,7.28 52.76,6.49 52.18,5.91 PRB6.2 52.18,5.58 51.71,5.11 50.8,5.11 v2(50.77,5.08) 50.77,4.85 50.65,4.73 50.65,4.72 50.36,4.42 PRB34.1
  IN1 w0.381: v2(50.77,5.08) 49.5,5.08 48.95,5.64 46.68,5.64 45.54,6.78 44.57,6.78 44.14,7.21 44.14,7.76 44.54,8.16 v2(44.61,8.16)
  BOTTOM w0.381: v2(44.61,8.16) v1(43.86,8.91) 42.78,9.99 42.78,10.92 44.35,12.49 47.68,12.49 48.03,12.14 PCB18.1
REMOTE1+: length 148.4
  IN2 w0.254: v2(75.78,15.12) 75.78,14.45 77.92,12.32 81.83,12.32 82.51,11.64 82.53,11.64 82.53,11.64 84.93,11.64 86.1,12.81 88.13,12.81 88.62,12.32 90.28,12.32 91.89,13.92 92.88,13.92 93.64,13.16 97.67,13.16 98.35,12.48 100.44,12.48 101.46,11.47 106.4,11.47 106.99,12.05 106.99,12.15 107.25,12.41 107.34,12.41 108.49,13.56 111.63,13.56 113.57,11.61 115.34,11.61 116.15,10.81 116.15,10.11 116.17,10.09 116.17,10.03 116.72,9.48 117.14,9.48 118.05,9.48 118.92,8.61 121.44,8.61 122.06,9.23 127,9.23 127.54,9.76 132.67,9.76 133.02,9.4 134.89,9.4 135.86,10.37 136.83,10.37 138.01,11.55 139.55,11.55 140.19,12.18 142.57,12.18 144.16,13.77 145.66,13.77 145.96,14.08 145.96,15.63 154.19,23.86 162.91,23.86 164.25,25.2 165.2,25.2 166.86,26.85 166.86,27.28 167.98,28.41 168.41,28.41 169.09,29.09 171.16,29.09 172.41,30.33 172.41,39.17 172.13,39.45 v2(172.13,39.64)
  BOTTOM w0.254: v2(172.13,39.64) 173.03,39.64 173.7,38.97 174.59,38.97 175.86,40.24 175.86,46.58 175.56,46.88 v3(175.56,47.64) 173.46,47.64 172.8,48.3 172.8,49.53 173.24,49.97 CTS3.1 174.19,50.76 UTS1.2 ; v2(75.78,15.12) 75.28,15.63 CTS1.1 75.28,16.35 74.53,17.1 QTS1.1 75.23,17.54 75.88,18.19 QTS1.2
REMOTE2+: length 228.7
  IN1 w0.254: v2(76.67,14.28) 76.5,14.1 72.36,14.1 69.84,16.62 65.36,16.62 64.98,17 35.37,17 33.17,19.2 32.21,19.2 32.2,19.18 31.77,19.18 30.83,20.12 30.83,22.61 30.6,22.84 30.6,28.7 28.69,30.61 27.81,30.61 25.98,28.78 23.71,28.78 23.16,29.33 23,29.49 23,34.06 22.84,34.22 22.84,41.36 21.06,43.13 v2(21.06,44.15)
  IN2 w0.254: v2(76.67,14.28) 78.11,12.85 82.03,12.85 82.72,12.15 84.7,12.15 85.87,13.31 89.12,13.31 89.34,13.54 90.03,13.54 90.79,14.29 90.79,14.38 91.8,15.4 93.06,15.4 93.7,14.75 96.88,14.75 98.14,13.49 100.32,13.49 101.72,12.1 106.14,12.1 108.59,14.55 111.35,14.55 113.69,12.21 115.46,12.21 116.68,10.99 116.68,10.24 116.93,9.99 118.28,9.99 118.99,9.28 121.39,9.28 121.92,9.8 126.86,9.8 127.38,10.32 132.32,10.32 132.88,10.88 136.62,10.88 138.63,12.88 142.46,12.88 153.97,24.4 162.68,24.4 164,25.71 164.99,25.71 166.35,27.06 166.35,27.49 167.77,28.92 168.2,28.92 168.88,29.6 170.95,29.6 171.9,30.54 171.9,38.96 171.62,39.24 171.62,40.02 v2(171.05,40.59)
  BOTTOM w0.254: v2(21.06,44.15) CTS2.1 20.44,44.79 20.63,44.98 QTS2.2 20.63,45.94 19.98,46.59 QTS2.1 ; v2(171.05,40.59) 171.3,40.85 173.73,40.85 173.88,40.7 174.58,40.7 174.84,40.96 174.84,46 174.22,46.63 173.04,46.63 171.78,47.88 171.78,49.95 171.82,49.98 172.34,50.54 172.74,50.93 172.74,52.15 173.24,52.66 CTS4.1 174.32,51.76 UTS1.4
REMOTE3+: length 104.4
  TOP w0.254: v2(99.1,85.6) 99.1,86.32 v1(99.13,86.35)
  IN2 w0.254: v2(176.24,54.18) 176.23,54.17 176.16,54.17 175.66,54.67 175.66,56.92 174.16,58.43 173.74,58.43 172.28,59.89 172.28,62.65 167.6,67.33 165.48,67.33 162.53,70.29 162.53,71.81 157.52,76.81 155.18,76.81 153.94,78.06 150.6,78.06 145.94,82.72 143.86,82.72 143,83.58 140.69,83.58 138.28,86 103.31,86 102.11,87.2 100.14,87.2 99.1,86.17 v2(99.1,85.6)
  BOTTOM w0.254: v2(99.1,85.6) 98.77,85.93 CTS7.1 98.77,87.23 98.56,87.44 QTS3.1 99.41,88.09 100.06,88.74 QTS3.2 ; UTS1.5 176.12,52.26 176.44,52.58 176.44,53.29 CTS6.1 v2(176.24,54.18)
REMOTE3-: length 104.7
  IN2 w0.254: v2(176.93,54.18) 176.93,54.03 176.56,53.66 175.95,53.66 175.15,54.46 175.15,56.71 173.95,57.92 173.53,57.92 171.77,59.68 171.77,62.44 167.39,66.82 165.27,66.82 162.02,70.08 162.02,71.6 157.31,76.31 154.97,76.31 153.73,77.55 150.39,77.55 145.73,82.21 143.65,82.21 142.79,83.08 140.47,83.08 138.32,85.22 103.37,85.22 101.9,86.7 100.35,86.7 99.69,86.04 v2(99.69,85.6)
  BOTTOM w0.254: RTS8.1 176.76,54.64 176.76,54.35 v2(176.93,54.18) 176.93,53.8 177.16,53.57 CTS6.2 176.95,53.29 176.95,52.72 177.26,52.41 178.34,52.41 178.49,52.26 UTS1.6 ; v2(99.69,85.6) CTS7.2 99.69,87.19 99.94,87.44 QTS3.3 101.06,87.44 v3(101.59,86.91)
REMOTE-: length 229.9
  IN1 w0.254: v2(76.42,15.19) 76.42,15.04 75.99,14.61 72.57,14.61 70.05,17.12 65.57,17.12 65.19,17.51 35.58,17.51 33.39,19.69 33.34,19.69 33.29,19.74 31.94,19.74 31.33,20.35 31.33,22.84 31.11,23.07 31.11,28.91 28.9,31.12 27.6,31.12 25.77,29.29 23.92,29.29 23.51,29.7 23.51,34.27 23.35,34.44 23.35,41.57 21.57,43.34 v2(21.57,43.83)
  IN2 w0.254: v2(76.42,15.19) 76.48,15.19 78.32,13.35 84.34,13.35 84.81,13.82 88.55,13.82 91.33,16.6 91.35,16.6 91.91,17.16 93.13,17.16 94.97,15.32 97.21,15.32 98.09,14.44 99.95,14.44 100.17,14.23 100.85,14.23 102.01,13.07 103.04,13.07 103.53,12.58 106,12.58 107.22,13.8 107.22,13.87 108.39,15.04 109.18,15.04 109.61,15.46 111.09,15.46 111.52,15.04 111.58,15.04 113.84,12.78 114.15,12.78 114.47,12.78 115.62,12.78 117.07,11.32 117.71,11.32 119.24,9.78 120.62,9.78 121.14,10.31 126.59,10.31 127.7,11.42 132.06,11.42 132.1,11.38 136.25,11.38 137.84,12.98 137.84,13.54 138.37,14.08 142.92,14.08 145.77,16.93 153.76,24.92 162.47,24.92 163.77,26.22 164.78,26.22 165.84,27.28 165.84,27.7 167.56,29.43 167.99,29.43 168.67,30.1 170.74,30.1 171.39,30.75 171.39,38.75 171.11,39.03 171.11,39.81 170.56,40.37 v2(170.27,40.37)
  BOTTOM w0.254: v2(21.57,43.83) 21.25,43.52 19.84,43.52 19.52,43.83 CTS2.2 19.52,44.43 19.33,44.62 QTS2.3 ; QTS1.3 76.43,16.12 CTS1.2 76.19,15.42 v2(76.42,15.19) ; UTS1.3 174.08,51.26 173.6,51.75 CTS4.2 173.42,50.91 CTS3.2 173.4,50.87 172.85,50.33 172.85,50.3 172.29,49.74 172.29,48.09 173.25,47.14 174.54,47.14 175.35,46.32 175.35,40.69 174.81,40.15 171.29,40.15 171.25,40.11 170.53,40.11 v2(170.27,40.37)
RTC_CLK: length 25.6
  IN1 w0.102: v2(139.84,64.65) 139.84,66.45 138.7,67.59 125.06,67.59 124.01,68.65 122.23,68.65 v2(120.37,70.5)
  BOTTOM w0.102: UC1.AW10 120.07,70.2 v2(120.37,70.5)
  BOTTOM w0.117: v2(139.84,64.65) 140.03,64.2 140.38,63.85 RC87.1
RTC_CLK_R: length 61.8
  TOP w0.117: v2(168.14,34.65) 168.63,34.65 168.79,34.81 RWL8.2
  IN2 w0.117: v2(149.83,50.25) 149.93,50.35 149.93,52.46 148.73,53.66 148.73,54.03 147.39,55.38 147.39,56.49 v2(145.28,58.6)
  IN3 w0.117: v2(168.14,34.65) 167.5,35.28 165.79,35.28 163.35,37.72 163.03,37.72 161.79,38.97 161.79,40.37 162.43,41.01 162.43,43.93 161.92,44.44 161.92,46.24 162.43,46.75 162.43,52.64 160.06,55.01 160.06,55.81 158.92,56.95 156.94,56.95 156.08,56.1 156.08,52.95 154.34,51.21 150.79,51.21 v2(149.83,50.25)
  BOTTOM w0.117: RC87.2 141.16,61.93 141.47,61.63 v3(141.47,60.91) 141.47,58.37 141.93,57.92 142.76,57.92 143.09,58.24 144.92,58.24 v2(145.28,58.6)
S0A3_GPIO: length 87.8
  TOP w0.102: v2(162.42,27.72) 163.49,28.78 164.95,28.78 165.4,29.23 165.4,29.67 165.08,29.99 UC23.2
  IN2 w0.102: v2(148.66,44.58) 147.92,45.32 147.92,46 146.47,47.45 146.47,51.99 140.74,57.72 140.74,59.45 v2(140.48,59.72) 140.28,59.72 136.25,63.75 136.05,63.75 135.84,63.96 133.72,63.96 133.01,64.67 131.31,64.67 131.05,64.93 127.67,64.93 126.42,66.17 124.12,66.17 123.51,65.56 122.55,65.56 121.59,66.52 121.09,66.52 120.18,67.42 v2(119.73,67.42)
  IN3 w0.102: v2(162.42,27.72) 160.54,25.84 151.9,25.84 151.37,26.36 151.37,26.88 150.97,27.28 146.78,27.28 146.68,27.39 146.68,43.24 148.02,44.58 v2(148.66,44.58)
  BOTTOM w0.102: UC1.AW13 120.07,67.03 119.73,67.37 v2(119.73,67.42) ; RC610.2 v3(139.56,60.79) 139.56,60.64 v2(140.48,59.72)
S0I3_EC#: length 313.4
  TOP w0.102: UEC1.119 180.8,46.08 v2(180.06,46.82) 179.68,47.2 R4010.1 ; v1(165.59,24.08) 165.41,24.26 v2(164.91,24.26)
  IN1 w0.102: v2(26.15,51.84) 26.65,51.34 26.65,46.75 v2(26.84,46.56)
  IN2 w0.102: v2(164.91,24.26) 162.8,22.15 156.2,22.15 153.51,19.46 151.21,19.46 147.29,15.53 147.29,14.04 144.52,11.27 140.57,11.27 139.89,10.6 138.35,10.6 137.13,9.38 136.16,9.38 135.09,8.31 132.73,8.31 131.37,6.95 123.72,6.95 123.23,7.45 122.64,7.45 122.14,6.95 117.81,6.95 117.01,7.75 115.6,7.75 115.48,7.63 v2(115.42,7.63)
  IN3 w0.102: v2(180.06,46.82) 181.84,45.04 183.24,45.04 183.96,44.32 183.96,35.62 182.77,34.43 182.77,33.86 182.54,33.63 182.54,33.18 178.42,29.06 175.38,29.06 174.78,28.47 172.63,28.47 170.18,26.01 165.77,26.01 164.91,25.16 v2(164.91,24.26) ; v2(81,8.15) 81,11.26 79.61,12.65 79.61,16.78 79.92,17.1 81.39,17.1 81.83,17.54 81.83,19.26 82.78,20.21 82.78,26.94 82.53,27.2 82.53,32.21 81.39,33.36 81.39,38.94 73.32,47.01 68.49,47.01 67.54,47.96 59.54,47.96 58.4,46.82 53.32,46.82 52.18,47.96 47.41,47.96 42.59,52.79 41.99,52.79 41.61,52.41 41.61,50.04 41.89,49.76 41.89,47.39 38.78,44.28 30.52,44.28 29.44,43.2 27.66,43.2 27.38,43.48 27.38,46.09 26.9,46.56 v2(26.84,46.56) 26.47,46.19 26.47,44.03 23.79,41.36 v2(23.79,22.5)
  BOTTOM w0.102: RWL15.1 169.15,56.14 169.04,56.02 169.04,54.78 169.36,54.46 172.3,54.46 173.04,55.2 175.31,55.2 176.27,56.16 177.21,56.16 177.45,55.92 178.02,55.92 178.53,55.42 178.53,53.71 178.92,53.32 181.63,53.32 182.91,52.05 182.91,51.02 181.45,49.56 181.45,48.2 v2(180.06,46.82) ; RA51.1 25.75,51.44 v2(26.15,51.84) 26.19,51.88 26.19,53.94 25.58,54.55 RA57.1 ; RTP16.1 115.43,7.65 v2(115.42,7.63) 115.42,7.12 113.82,5.52 99.7,5.52 96.79,8.43 93.42,8.43 90.72,5.73 85.26,5.73 82.85,8.15 v2(81,8.15) ; 22.47,21.18 20.79,21.18 20.53,21.44 19.08,21.44 18.46,22.07 QA4.2
  BOTTOM w0.117: 22.47,21.18 v2(23.79,22.5)
S0I3_EC#_1V8VDD: length 4.2
  BOTTOM w0.102: v1(26.33,54.76) 26.14,54.76 25.43,55.47 RA57.2
  BOTTOM w0.381: QA3.2 23.8,55.53 24.45,56.18 CA52.1 RA57.2
S0I3_EC#_3VDD: length 4.7
  BOTTOM w0.102: v3(25.89,53.29) 25.89,53.17 25.07,52.35 RA51.2
  BOTTOM w0.381: QA1.2 23.37,52.05 24.43,53.1 CA50.1 25.06,53.07 RA51.2
S0I3_EC#_5VDDA: length 3.1
  BOTTOM w0.117: RA55.1 v3(21.06,21.48)
  BOTTOM w0.381: RA55.1 RA61.1 20.11,22.48 19.86,22.23 QA4.3
S0I3_EC#_5VDDA_R: length 5.4
  BOTTOM w0.117: RA55.2 21.11,23.4 v3(22.33,22.18)
  BOTTOM w0.381: QA2.2 19.74,25.51 20.12,25.13 CA51.1 RA55.2
S0I3_EC#_5VEN2: length 1.1
  BOTTOM w0.117: QA4.5 v3(18.46,19.53)
S0I3_TP_EN#: length 3.3
  BOTTOM w0.117: RTP16.2 116.35,7.82 115.86,7.34 v1(115.86,7.08)
  BOTTOM w0.508: RTP6.1 RTP5.2 RTP16.2
S0I3_WLAN_EN#: length 3.9
  BOTTOM w0.117: UWL1.4 167.61,56.07 167.58,56.1 CWL9.1 167.62,56.65 RWL15.2 168.24,56.84 168.59,57.19 168.76,57.19 169.38,57.81 v1(169.38,57.98)
SCL_CHG: length 4.3
  BOTTOM w0.117: PRB12.2 49.19,2.06 49.19,2.75 48.57,3.37 48.57,3.75 48.17,4.16 PUB1.13
SDA_CHG: length 3.3
  BOTTOM w0.117: PRB10.2 49.65,2.72 48.95,3.42 48.95,3.9 48.57,4.29 PUB1.12
SELF HEALING: length 9
  TOP w0.117: v2(182.06,49.6) 182.18,49.48 182.67,49.48 T24.1 ; v2(181.53,43.74) 181.6,43.81 UEC1.117
  BOTTOM w0.117: v2(182.06,49.6) 182.47,49.19 182.47,48.42 181.21,47.16 181.21,44.53 181.53,44.21 v2(181.53,43.74)
SERIRQ: length 97.5
  TOP w0.117: v2(177.59,42.44) 177.19,42.83 UEC1.3
  IN2 w0.117: v2(137.76,66.88) 138.01,66.62 139.19,66.62 140.78,65.03 140.78,64.27 140.35,63.84 140.35,62.44 142.66,60.13 142.66,58.76 144.14,57.28 144.14,55.73 148.35,51.52 148.35,48.06 149.77,46.64 149.77,46.28 150.05,46 150.13,46 150.13,45.98 v2(150.16,45.98)
  IN3 w0.117: v2(177.59,42.44) 178.57,42.44 179.39,41.62 179.39,41.25 179.91,40.73 179.91,38.13 179.3,37.51 179.3,35.7 178.82,35.21 178.82,34.15 177.88,33.2 177.23,33.2 177.04,33.01 175.84,33.01 175.22,32.39 172.71,32.39 171.29,33.81 170.49,33.81 169.83,33.15 167.45,33.15 167.28,32.97 162.57,32.97 160.68,34.86 155.07,34.86 154.25,35.68 154.25,44.05 152.61,45.7 150.92,45.7 150.64,45.98 v2(150.16,45.98)
  BOTTOM w0.102: UC1.BC15 123.04,65.5 123.13,65.4 124.01,65.4 124.01,65.4 124.22,65.4
  BOTTOM w0.117: 124.22,65.4 126.64,65.4 127.42,66.19 128.79,66.19 130.73,68.13 v3(133.39,68.13) 134.11,68.13 134.35,67.88 136.37,67.88 136.74,67.51 137.27,67.51 137.76,67.03 v2(137.76,66.88)
SET1_CPU: length 4.6
  TOP w0.117: v3(94.15,91.68) 94,91.83 v2(94,92.17) 93.97,92.2 PR1813.2
  BOTTOM w0.254: PR835.1 v2(94,92.17) 94.46,92.62 94.63,92.62 95.57,93.56 PU801.25
SET2_CPU: length 5.8
  TOP w0.117: v2(93.18,92.14) 93.13,92.1 PR836.2 93.13,91.41 v3(94.15,90.4)
  BOTTOM w0.254: PU801.26 95.17,93.69 94.48,93 94.04,93 v2(93.18,92.14) PR837.1
SMU_ZVDDP: length 2.2
  TOP w0.102: v2(99.37,74.02) 99.37,74.15 v3(99.01,74.52)
  TOP w0.381: RC22.1 98.8,73.44 v2(99.37,74.02)
  BOTTOM w0.305: UC1.P3 v2(99.37,74.02)
SNB_APU:
  vias: v1(119.62,94.87)
SNB_APU2: length 1.9
  TOP w0.117: PR840.2 v1(130.63,98.53)
SNB_APU3: length 2.3
  TOP w0.117: PR855.2 147.74,97.15 147.53,97.36 v3(147.43,97.36)
SNB_APU_NB: length 1.8
  TOP w0.117: PR808.2 v3(79.17,95.98)
SNB_VDDP: length 2.1
  BOTTOM w0.117: v1(150.54,94.32) 150.54,92.82 150.93,92.42 PC603.1
SNUB_1.8V: length 2.6
  BOTTOM w0.117: v1(162.41,79.01) 163.2,79.8 163.75,79.8 164.38,79.17 PR1810.2
SOC_DMIC_CLK0: length 35
  TOP w0.102: R4024.2 56.94,61.41 57.02,61.49 Q206.1 57.51,61.93 v2(57.51,62.18) ; v2(54.38,60.23) 54.38,59.77 R4014.2 53.94,59.33 R358.1
  BOTTOM w0.102: v2(54.38,60.23) 53.7,59.54 53.7,56.93 53.31,56.54 53.31,49.94 52.27,48.9 51.41,48.9 51.16,48.64 D6.1 52.56,48.21 v3(52.81,48.46) 53.76,49.41 53.76,55.96 56.47,58.67 56.47,61.03 57.51,62.07 v2(57.51,62.18)
SOC_DMIC_CLK0_R: length 4.2
  TOP w0.117: v3(52.11,57.55) 52.37,57.8 52.37,58.29 C249.1 ; R358.2 52.65,59.19 C249.1 ; v2(51.88,58.2) 52.25,58.57 C249.1
  BOTTOM w0.117: JEDP1.36 51.57,58.51 v2(51.88,58.2)
SOC_DMIC_DAT0: length 25.2
  TOP w0.102: 56.98,58.95 56.6,59.32 56.6,59.76 55.85,60.51 R4025.2 ; 56.98,58.95 Q207.1 ; 56.98,58.95 55.62,58.95 54.58,57.9 v3(54.58,56.91) 54.58,56.22 52.51,54.15 52.51,53.94 51.84,53.28 R4015.2 51.6,53.28 50.88,52.55 v2(49.55,52.55)
  BOTTOM w0.102: JEDP1.37 51.33,58.01 52.3,57.05 52.3,51.07 51.94,50.71 D6.6 50.96,50.71 50.66,51.01 50.66,51.44 v2(49.55,52.55)
SPK_L1-: length 40.7
  IN3 w1.016: 20.3,35.51 21.16,34.65 21.16,22.97 23.98,20.15 23.98,8.26 25.13,7.1 25.85,7.1 26,7.26 29.95,7.26 31.03,6.18 31.03,4.34 30.01,3.32 29.38,3.32
  vias: v2(15.47,34.97) v2(16.06,35.02) v2(27.83,3.73) v2(28.46,3.73)
SPK_L1-_CONN: length 2.7
  IN1 w1.016: 30.57,5.59 32.73,5.59 33.11,5.97
  vias: v2(29.7,5.16) v2(29.76,4.53) v2(33.4,6.83) v2(34.01,6.83)
SPK_L2+: length 29.3
  IN3 w1.016: 18.65,33.67 20.02,32.3 20.02,22.5 22.84,19.68 22.84,7.92 22.57,7.65 22.57,6.23
  vias: v2(17.64,34.85) v2(17.91,34.28) v2(22.29,5.19) v2(22.9,5.19)
SPK_L2+_CONN: length 11.6
  IN1 w1.016: 34.68,4.79 32.73,2.84 24.71,2.84 24.13,3.41
  vias: v2(23.54,4.7) v2(23.54,4.12) v2(35.46,5.81) v2(35.46,5.23)
SPK_R1-: length 39.6
  IN3 w1.016: 15.54,33.17 15.09,32.72 15.09,29.33 16.97,27.45 16.97,21.26 19.96,18.28 19.96,4.19 21.08,3.07 24.74,3.07 26.84,5.16 27.09,5.16
  vias: v2(16.3,33.84) v2(16.68,34.3) v2(28.05,6.11) v2(28.03,5.45)
SPK_R1-_CONN: length 6.6
  IN1 w1.016: 34.39,7.75 31.38,7.75 31.13,7.5 27.91,7.5 27.89,7.51
  vias: v2(26.58,8.27) v2(27.22,8.26) v2(36.08,7.42) v2(36.11,6.81)
SPK_R2+: length 26.9
  IN3 w1.016: 17,32.47 16.3,31.77 16.3,29.74 18.11,27.92 18.11,21.73 21.1,18.75 21.1,7.87
  vias: v2(17.19,33.48) v2(17.64,33.08) v2(21.33,6.94) v2(21.33,6.28)
SPK_R2+_CONN: length 25.4
  IN1 w1.016: 36.47,4.81 33.35,1.69 21.61,1.69 19.98,3.32 19.98,7.34 20.56,7.92 21.85,7.92 22.46,7.32
  vias: v2(23.44,7.3) v2(23.46,6.69) v2(37.42,6.15) v2(37.42,5.54)
SRN: length 2.1
  BOTTOM w0.203: PRB19.2 44.58,5.99 45.16,6.57 45.59,6.57 45.8,6.78 PUB1.19
SRP: length 1.8
  BOTTOM w0.203: PRB18.2 44.76,7.03 45.58,7.03 45.74,7.18 PUB1.20
SSD1_PWR_EN#: length 181.1
  TOP w0.102: R4011.1 v2(179.39,46.84) 179.86,46.37 180.13,46.37 180.4,46.1 UEC1.120 ; v1(36.36,52.6) 36.16,52.39 v2(36.16,51.85)
  IN2 w0.102: v2(179.39,46.84) 177.87,48.37 176.96,48.37 175.89,49.44 175.89,49.61 175.35,50.14 175.2,50.14 170.22,55.12 170.07,55.28 170.07,57.18 163.62,63.62 161.37,63.62 158.86,66.13 156.79,66.13 150.17,72.76 150.16,72.76 150.07,72.85 150.03,72.85 149.46,73.42 148.06,73.42 143.56,77.92 140.1,77.92 138.28,79.74 137.91,79.74 136.1,81.55 125.94,81.55 123.52,79.14 123.17,79.14 122.72,78.69 115.41,78.69 114.19,77.48 112.7,77.48 112.5,77.68 110.63,77.68 109.66,78.65 108.05,78.65 107.49,79.21 97.72,79.21 97.32,79.61 84.18,79.61 76.19,71.62 75.97,71.62 75.32,70.96 71.86,70.96 71.21,71.62 65.16,71.62 62.59,69.04 60.98,69.04 59.35,67.41 58.53,67.41 55.39,64.27 53.27,64.27 52.76,63.76 49.56,63.76 46.41,60.61 45.22,60.61 38.52,53.92 37.63,53.92 36.16,52.44 v2(36.16,51.85)
  BOTTOM w0.102: RS4030.2 37.1,51.21 36.46,51.85 v2(36.16,51.85) 34.83,53.18 RSD12.1
SSD1_PWR_EN#_R: length 4.1
  BOTTOM w0.117: Q208.2 34.7,52.16 RSD12.2 CSD10.1 33.01,54.52 v3(32.83,54.71)
SSD2_PWR_EN#: length 181.8
  TOP w0.102: v2(173.42,45.09) 173.65,45.32 173.65,45.6 v1(173.91,45.86) 174.84,46.79 R4012.1 175.58,46.79 175.96,46.41 176.54,46.41 176.55,46.41 177.68,46.41 178,46.09 UEC1.126
  IN2 w0.102: v2(64.84,64.6) 64.53,64.91 64.53,66.43 65.29,67.19 66.78,67.19 68.12,68.53 77.31,68.53 86.34,77.56 94.16,77.56 94.26,77.67 94.39,77.79 106.3,77.79 107.23,76.87 107.75,76.87 108.45,76.17 109.82,76.17 110.9,75.09 121.96,75.09 122.5,75.62 122.5,75.68 123.02,76.21 125.49,76.21 126.35,75.35 129.1,75.35 130.47,73.97 134.5,73.97 134.85,73.61 142.13,73.61 143.11,72.64 143.11,71.34 146.16,68.29 146.83,68.29 148.4,66.71 148.4,66.23 150.94,63.69 150.94,61.24 151.04,61.14 152.66,61.14 153.32,60.48 161.09,60.48 163.94,57.64 163.94,56.61 165.69,54.86 165.69,54.59 165.78,54.5 165.78,52.63 169.23,49.18 170.15,49.18 171.34,47.99 171.34,47.71 172.3,46.75 172.3,46.21 v2(173.42,45.09)
  IN3 w0.102: v2(39.13,48.57) 39.6,49.04 39.6,53.88 44.3,58.58 51.32,58.58 51.5,58.76 52.77,58.76 53.21,59.19 63.57,59.19 64.02,59.65 64.43,59.65 65.62,60.85 65.62,62.57 64.84,63.35 v2(64.84,64.6)
  BOTTOM w0.102: RSD13.1 39.96,47.96 RS4031.2 39.7,48 v2(39.13,48.57)
SSD2_PWR_EN#_R: length 3.4
  BOTTOM w0.117: Q209.2 42.29,47.31 41.96,46.98 CSD12.1 40.78,46.98 RSD13.2 v3(39.75,47.05)
SUSCLK_R: length 2.4
  TOP w0.117: v2(170.35,34.69) 170.2,34.84 RWL8.1
  BOTTOM w0.117: JWLAN1.42 171.18,34.3 170.79,34.69 v2(170.35,34.69)
SUSP#: length 170.7
  TOP w0.102: v2(177.89,49.74) 179.19,49.74 180.13,48.8 180.13,47.88 R68.2 180.57,47.14 180.86,46.85 181.3,46.85 182,46.15 UEC1.116 ; v2(50.69,85.4) v1(51.16,85.87)
  IN1 w0.102: v2(50.69,85.4) 53.64,82.45 72.79,82.45 74.62,80.62 105.23,80.62 108.16,83.56 117.36,83.56 117.75,83.95 123.57,83.95 123.85,83.67 130.12,83.67 130.45,84.01 131.04,84.6 138.03,84.6 140.99,81.63 141.65,81.63 141.72,81.56 141.72,81.56 143.18,80.1 144.07,80.1 144.07,80.1 144.36,80.1 148.57,75.9 151.4,75.9 153.6,73.7 154.85,73.7 155.43,73.13 156.71,73.13 164.22,65.62 v2(164.22,65.33) 164.25,65.3 164.25,65.28 166.56,62.97 166.56,62.58 167.76,61.38 167.76,60.49 171.44,56.81 171.44,55.83 177.03,50.25 177.38,50.25 v2(177.89,49.74)
  BOTTOM w0.102: PRM4.1 165.78,60.5 164.22,62.05 v2(164.22,65.33)
  BOTTOM w0.117: U10.5 50.28,88.21 50.13,88.07 50.13,85.96 v2(50.69,85.4) 51.28,85.99 51.28,87.03 51.08,87.23 U10.3
SYS_PWRGD_EC: length 24.7
  TOP w0.102: v2(169.02,31.1) 169.02,30.43 v1(169.21,30.24) 169.5,30.24 170.03,29.72 170.56,29.72 171.11,29.16 172.7,29.16 173.16,29.62 C260.1 174,29.62 174.6,30.23 174.6,31.06 174.78,31.23 UEC1.32 ; UC7.2 168.77,43.87 168.55,43.65 168.55,42.99 168.19,42.63 RC64.1 168.55,42.35 v2(168.85,42.04)
  IN2 w0.102: v2(169.02,31.1) 169.02,32.47 170.86,34.31 170.86,37.54 170.26,38.14 170.26,39.69 169.52,40.43 169.52,41.37 v2(168.85,42.04)
SYS_RESET#: length 7.9
  BOTTOM w0.102: UC1.AL2 112.84,74.93 112.84,76.53 112.79,76.59 112.79,77.96 112.73,78.02 RC66.1 CC24.2 RC60.1 113.64,80.66 113.07,81.23 v3(112.18,81.23)
SYSON: length 144.4
  TOP w0.102: PR256.1 126.86,7.7 128.54,9.38 134.71,9.38 134.89,9.2 139.92,9.2 141.69,10.98 144.86,10.98 145.8,11.92 145.8,13.5 146.18,13.88 146.18,17.3 147.44,18.56 149.18,18.56 v1(151.8,21.19) 152.39,21.77 v2(152.95,21.77)
  TOP w0.203: UEC1.95 192.61,43.23 192.64,43.26
  IN1 w0.102: v2(189.45,38.92) 189.84,39.31 189.84,39.87 189.3,40.42 189.3,41.61 189.09,41.81 186.63,41.81 186.3,42.14 185.19,42.14 185.02,41.97 v2(182.13,41.97)
  IN3 w0.102: v2(192.95,42.32) 192.85,42.32 v2(189.45,38.92) 189.09,38.56 189.09,35.87 190.36,34.6 190.36,33.13 189.96,32.72 189.03,32.72 185.09,28.78 185.09,21.48 183.71,20.1 179.77,20.1 176.65,23.21 175.03,23.21 174.59,22.78 173.42,22.78 170.54,22.78 168.09,20.33 163.36,20.33 162.09,19.06 155.67,19.06 v2(152.95,21.77)
  BOTTOM w0.102: PRM3.1 165.47,55.38 166.51,55.38 167.91,53.98 172.53,53.98 173.27,54.72 175.51,54.72 176.4,55.61 177.05,55.61 177.27,55.39 177.8,55.39 178.05,55.15 178.05,53.51 178.72,52.84 181.43,52.84 182.42,51.85 182.42,51.22 180.97,49.76 180.97,48.4 180.52,47.96 179.77,47.96 178.96,47.15 178.96,45.14 v2(182.13,41.97)
TCP_IMON: length 1.6
  TOP w0.117: T2403.1 27.54,69.87 27.02,70.38 UT4.4
THERMTRIP#: length 21.6
  IN1 w0.102: v2(115.92,70.77) 115.97,70.77 115.98,70.79 116.13,70.79 116.96,69.96 120.63,69.96 120.81,69.77 120.81,68.57 121.2,68.18 122.67,68.18 123.86,66.99 130.76,66.99 v2(131.3,66.45)
  BOTTOM w0.102: UC1.AN9 115.48,70.4 115.79,70.72 115.87,70.72 v2(115.92,70.77)
  BOTTOM w0.117: RC21.2 132.77,66.06 RC29.2 131.74,66.13 131.42,66.45 v2(131.3,66.45)
TON_DDR: length 1.5
  BOTTOM w0.203: PRM10.2 163.78,54.27 163.5,54.56 PUM1.9
TONSET_CPU: length 7.7
  BOTTOM w0.117: PR807.1 104.04,102.9 v1(103.6,103.35)
  BOTTOM w0.254: PR807.1 103.84,102.19 103.27,101.62 103.27,101.12 102.71,100.56 102.71,100.08 102.39,99.76 102.39,98.72 102.14,98.47 101.95,98.47 101.74,98.27 101.74,98.27 101.66,98.19 PU801.4
TP_DISABLE#: length 76.2
  TOP w0.117: v2(189.84,33.23) 189.85,33.23 UEC1.70
  IN3 w0.127: v2(189.84,33.23) 188.84,33.23 184.6,28.99 184.6,21.69 183.73,20.82 179.75,20.82 176.86,23.71 174.82,23.71 174.38,23.27 170.32,23.27 167.88,20.83 163.16,20.83 161.89,19.56 155.87,19.56 153.22,22.21 v2(150.05,22.21)
  BOTTOM w0.117: RTP3.1 133.53,12.3 CTP7.1 134.26,12.27 135.73,13.75 136.37,13.75 136.49,13.86 136.49,14.31 137.32,15.13 138.36,15.13 139.51,16.29 140.88,16.29 143.8,19.2 144.69,19.2 v3(146.5,21.01) 146.73,21.24 149.08,21.24 v2(150.05,22.21)
TP_DISABLE#_R: length 3.5
  TOP w0.089: v2(131.65,13.58) 131.3,13.58
  TOP w0.117: 131.3,13.58 v3(131,13.58)
  BOTTOM w0.117: JTP1.1 131.53,13.46 v2(131.65,13.58) 132.07,13.58 RTP3.2
TP_INT#: length 186.6
  TOP w0.117: v2(187.15,39.45) 187.17,39.45 188.15,40.43 UEC1.88 192.29,40.43 v3(192.95,39.77) ; v2(147.93,20.77) 147.55,20.77 CTP5.1 147.12,20.09 147.23,19.97 147.53,19.97 v2(147.7,20.15)
  IN2 w0.127: v2(178.08,19.64) 179.53,21.09 179.53,23.83 180.81,25.11 180.81,28.96 183.07,31.22 v2(183.07,31.9) ; v2(156.07,62.9) 156.1,62.87 158.96,62.87 159.44,62.39 162.23,62.39 164.11,60.51 164.78,60.51 167.24,58.05 167.24,56.88 168.01,56.1 168.01,55.57 173.9,49.68 173.9,48.02 176.57,45.35 178.49,45.35 181.52,42.32 181.52,41.73 183.8,39.45 v2(187.15,39.45)
  IN3 w0.127: v2(131.74,10.83) 132.1,11.18 140.3,11.18 147.45,18.33 147.45,19.9 v2(147.7,20.15) ; v2(178.08,19.64) 178.08,20.04 177.06,21.06 170.58,21.06 168.61,19.09 163.88,19.09 162.59,17.8 151.37,17.8 148.4,20.77 v2(147.93,20.77) ; v2(156.07,62.9) 155.85,63.12 154.72,63.12 152.25,65.59 152.25,66.42 151.58,67.1 150.03,67.1 148.19,68.94 147.76,68.94 141.79,74.91 137.81,74.91 137.57,75.15 136.17,75.15 135.75,75.57 130.4,75.57 129.96,76.01 126.86,76.01 126.67,76.2 125.25,76.2 124.88,76.57 123.3,76.57 123,76.88 120.88,76.88 120.23,77.53 119.78,77.53 119.31,77.06 v2(119.31,76.45)
  BOTTOM w0.102: v2(119.31,76.45) 119.07,76.21 119.07,75.16 119.23,75 119.23,74.77 119.08,74.62 119.08,74.54 118.88,74.33 UC1.AU4
  BOTTOM w0.117: RTP2.2 124.15,11.99 125.75,11.99 126.58,12.83 129.92,12.83 129.92,12.82 130.81,12.82 130.82,12.83 130.91,12.83 131.03,12.72 JTP1.2 131.03,11.47 131.66,10.83 v2(131.74,10.83) ; v2(183.07,31.9) 183.1,31.92 183.1,35.84 186.71,39.45 v2(187.15,39.45)
TS_DISABLE#: length 170.6
  TOP w0.117: v2(53.48,63.02) v3(52.69,63.02) ; v2(187.42,34.98) 187.45,34.95 189.4,34.95 189.69,35.23 UEC1.75
  IN2 w0.102: 92.75,78.21 93.97,78.21 94.57,78.81 107.32,78.81 108,78.12 109.39,78.12 110.95,76.56 113.24,76.56 113.74,77.07 114.43,77.07 115.56,78.2 118.93,78.2 119.02,78.29 122.56,78.29 123.49,77.35 126.66,77.35 127.05,76.96
  IN2 w0.127: 92.75,78.21 85.72,78.21 77.05,69.55 64.86,69.55 63.07,67.76 61.47,67.76 59.83,66.13 59.02,66.13 55.91,63.02 v2(53.48,63.02) ; 127.05,76.96 129.8,76.96 131.06,75.71 135.41,75.71 135.92,75.2 142.79,75.2 146.96,71.04 146.96,70.41 150.1,67.26 150.1,66.77 155.75,61.13 161.36,61.13 164.58,57.9 164.58,56.88 165.51,55.95 165.66,55.95 167.05,54.56 167.24,54.56 172.04,49.77 172.04,48 175.78,44.26 175.78,43.55 177.31,42.02 178.52,42.02 180.05,40.49 181.01,40.49 186.51,34.98 v2(187.42,34.98)
  BOTTOM w0.117: JEDP1.26 51.58,63.51 51.78,63.71 52.31,63.71 53,63.02 v2(53.48,63.02)
TYPEC_PWR_ILIM#: length 210
  TOP w0.117: QT2.2 32.86,68.71 34.14,70 v2(34.14,71.79) ; v1(193.9,47.48) R4022.1 192.6,46.59 192.37,46.36 191.02,46.36 190.08,45.42 190.08,43.82 189.75,43.49 188.69,43.49 186.38,41.18 v2(185.59,41.18) 185.59,43.27 186,43.68 UEC1.106
  IN1 w0.102: v2(185.59,41.18) 185.31,40.9 180.27,40.9 178.1,43.07 177.38,43.07 174.59,45.85 174.59,50.53 167.66,57.46 167.66,57.84 166.2,59.3 166.2,60.31 165.04,61.46 165.04,62.3 163.48,63.86 160.9,63.86 153.97,70.79 153.21,70.79 149.61,74.38 148.19,74.38 143.81,78.76 142.62,78.76 141.1,80.29 140.44,80.29 137.47,83.25 131.64,83.25 130.71,82.33 123.88,82.33 123.8,82.25 121.01,82.25 120.73,81.97 119.28,81.97 119.27,81.96 118.3,81.96 118.05,82.21 111,82.21 110.15,81.36 109.52,81.36 109.19,81.69 108.2,81.69 105.55,79.04 73.79,79.04 72.08,80.75 51.9,80.75 49.64,83.01 45.83,83.01 35.98,73.17 35.98,71.46 35.47,70.95 34.84,70.95 34.14,71.65 v2(34.14,71.79)
  BOTTOM w0.117: v2(34.14,71.79) 34.27,71.91 34.27,73.04 35.22,74 35.22,75.56 RT85.2
TYPEC_VIN: length 3.4
  TOP w0.117: 32.52,57.86 v3(32.52,59.21)
  TOP w0.508: 29.81,55.03 29.81,53.19 PQS3.1
UART_0_ARXD_DTXD: length 85.6
  TOP w0.117: v2(169.01,40.35) 169.07,40.4 RWL4.2
  IN2 w0.127: v2(169.01,40.35) 169.82,39.54 169.82,34.5 164.18,28.86 164.18,27.64 163.58,27.04 163,27.04 161.62,25.66 155.57,25.66 148.58,32.64 147.01,32.64 144.52,35.13 144.52,40.95 143.81,41.66 143.81,44.02 142.69,45.14 142.31,45.14 142.05,45.4 142.05,46.31 141.77,46.59 141.77,47.01 142.05,47.29 142.05,50.09 136.82,55.33 136.82,56.88 134.34,59.35 133.05,59.35 132.35,60.05 129.43,60.05 127.75,61.73 124.26,61.73 123.8,62.18 v2(123.8,63.88)
  BOTTOM w0.102: UC1.BA17 121.83,63.5 122.2,63.87 122.39,63.87 122.55,63.71 122.85,63.71 123.07,63.49 123.41,63.49
  BOTTOM w0.117: 123.41,63.49 v2(123.8,63.88)
UART_0_ARXD_R_DTXD: length 2.7
  TOP w0.117: v3(171.36,41.04) v2(170.67,41.04) RWL4.1
  BOTTOM w0.117: JWLAN1.22 170.93,41.3 v2(170.67,41.04)
UART_0_ATXD_DRXD: length 83.1
  TOP w0.117: RWL5.2 169,38.94 v2(168.32,38.94) v3(167.68,38.94)
  IN2 w0.127: v2(124.44,63.9) 124.44,63.06 125.52,61.98 128.01,61.98 129.48,60.51 132.46,60.51 133.36,59.61 134.47,59.61 137.07,57 137.07,55.45 142.31,50.22 142.31,46.09 144.19,44.21 144.19,41.66 144.77,41.08 144.77,35.24 147.11,32.9 148.69,32.9 155.67,25.91 161.51,25.91 162.89,27.3 163.43,27.3 163.92,27.79 163.92,28.99 169.56,34.63 169.56,38.54 169.15,38.94 v2(168.32,38.94)
  BOTTOM w0.102: UC1.BC16 122.41,64.36 123.98,64.36
  BOTTOM w0.117: 123.98,64.36 v2(124.44,63.9)
UART_0_ATXD_R_DRXD: length 2.8
  TOP w0.117: RWL5.1 170.55,38.82 170.67,38.7 v2(170.67,38.5) 170.69,38.5 v3(171.04,38.15)
  BOTTOM w0.117: v2(170.67,38.5) 170.97,38.8 JWLAN1.24
UG1_CPU: length 40.3
  TOP w0.117: v3(97.77,100.54) 98.07,100.85 v2(98.07,101.33)
  IN3 w1.016: 97.79,103.12 97.79,105.45 100.52,108.18 127.28,108.18 131.85,103.6
  vias: v2(98.07,101.96) v2(131.96,102.28) v2(132.54,102.28)
UG1_CPU_R: length 3.2
  BOTTOM w0.117: v3(131.08,103.36) 131.48,103.76 131.51,103.76 131.56,103.81 133.3,103.81 133.48,103.62 PR838.2
UG1_NB: length 9.8
  TOP w0.117: v2(85.63,104.51) 86.32,104.51 v3(86.51,104.7)
  IN3 w1.016: 94.69,101.87 93.5,101.87 91.14,104.23 86.82,104.23
  vias: v2(85.63,103.93) v2(95.71,101.59) v2(96.12,101.16)
UG1_NB_R: length 1.1
  TOP w0.117: v3(81.92,104.35) 82.34,104.77 v2(82.86,104.77)
  vias: v2(83.44,104.77)
UG2_CPU: length 10.6
  TOP w0.117: v2(111.48,97.66) v1(112.36,97.66)
  IN3 w1.016: 102.24,100.09 102.61,100.09 103.42,100.89 108.25,100.89 110.63,98.51
  vias: v2(101.12,99.81) v2(101.37,100.35) v2(111.48,97.07)
UG2_CPU_R: length 2.4
  BOTTOM w0.117: v1(110.34,98.17) 111.89,98.17 112.27,97.79 PQ802.1
UG3_CPU: length 4.5
  TOP w0.762: 144.42,103.25 v3(143.5,102.33) 143.01,101.84 143.01,99.39 PR853.1
UG3_CPU_R: length 1.7
  TOP w0.117: v3(144.66,97.86) 144.55,97.98 PR853.2
  vias: v2(142.19,96.89) v2(142.62,97.3)
UG_DDR: length 10.9
  TOP w1.016: 152.59,44.61 156,48.01 156,50.93 v3(156.84,51.77) 156.84,52.79 157.55,53.5
  vias: v2(152.57,43.72) v2(152.57,43.13) v2(158.31,53.98) v2(158.79,54.44)
USB3_ARX_DTX_N1: length 157.1
  IN1 w0.102: v2(107.87,70.83) 107.87,70.92 107.98,71.02 108.19,71.02 108.47,71.31 108.47,71.78 108.84,72.14 110.11,72.14 110.48,72.51 110.48,73.21 110.73,73.46 111.3,73.46 112.31,74.48 114.88,74.48 115.48,75.09 118.04,75.09 118.39,75.44 119.98,75.44 120.16,75.62 121.19,75.62 121.52,75.29 122.55,75.29 122.99,75.72 125.95,75.72 126.68,74.99 133.14,74.99 134.24,76.09 137.17,76.09 137.43,76.35 139.15,76.35 141.14,74.36 142.59,74.36 158.24,58.71 159.97,58.71 159.98,58.69 160.81,58.69 161.27,58.23 161.27,57.38 161.48,57.17 161.56,57.17 163.2,55.53 163.2,54.01 162.91,53.72 162.91,47.31 165.26,44.96 165.26,37.88 164.47,37.09 164.47,28.83 164.49,28.81 164.49,26.77 164.52,26.75 164.52,25.28 169.2,20.59 179.06,20.59 179.59,20.06 186.45,20.06 187.68,18.83 189.39,18.83 190.86,17.35 190.86,16.21 192.66,14.41 198.48,14.41 203.5,19.43 203.5,25.04 203.22,25.31 202.36,25.31 v2(202.15,25.52)
  BOTTOM w0.102: UC1.AD9 107.48,70.4 107.87,70.8 v2(107.87,70.83)
  BOTTOM w0.117: v2(202.15,25.52) 201.92,25.29 201.23,25.29 201.03,25.49 200.66,26.12 200.7,26.31 JIO1.8
USB3_ARX_DTX_N2: length 132.9
  IN1 w0.102: v2(188.57,18.12) 188.67,18.22 188.81,18.22 188.96,18.07 188.96,17.63 188.58,17.25 183.03,17.25 181.04,19.23 168.39,19.23 163.87,23.75 163.87,28.43 163.74,28.55 163.74,45.11 163.48,45.37 162.83,45.37 162.22,45.98 162.22,54.02 162.56,54.36 162.56,55.26 161.64,56.19 161.6,56.19 160.78,57 160.25,57 160.13,57.13 160.13,57.8 159.87,58.06 157.69,58.06 147.4,68.34 146.1,68.34 140.27,74.17 134.75,74.17 133.92,73.35 126,73.35 125.34,74.01 124.03,74.01 123.86,73.84 121.77,73.84 121.33,74.27 120.82,74.27 120.32,74.78 119.1,74.78 118.76,74.45 118.76,73.78 118.4,73.41 117.68,73.41 117.4,73.69 116.7,73.69 116.58,73.56 115.31,73.56 114.8,73.06 112.77,73.06 112.28,72.57 112.28,71.24 111.23,70.18 111.23,69.71 110.89,69.37 109.49,69.37 108.94,68.81 108.3,68.81 108.2,68.92 108.2,69.27 108.1,69.37 107.95,69.37 v2(107.87,69.3)
  BOTTOM w0.102: UC1.AD11 107.54,68.8 107.87,69.14 v2(107.87,69.3)
  BOTTOM w0.117: v2(188.57,18.12) 188.57,18.35 188.45,18.46 188.09,18.46 187.89,18.79 187.72,18.84 187.48,19.24 JIO1.38
USB3_ARX_DTX_P1: length 157.2
  IN1 w0.102: v2(107.87,71.6) 107.82,71.54 107.82,71.3 107.89,71.23 108.1,71.23 108.27,71.4 108.27,71.86 108.75,72.34 110.02,72.34 110.28,72.6 110.28,73.13 110.28,73.3 110.65,73.67 111.21,73.67 112.23,74.68 114.79,74.68 115.4,75.29 117.95,75.29 118.31,75.65 119.9,75.65 120.07,75.82 121.28,75.82 121.61,75.49 122.47,75.49 122.89,75.91 126.03,75.91 126.76,75.18 133.06,75.18 134.16,76.28 137.09,76.28 137.35,76.54 139.23,76.54 141.22,74.55 142.67,74.55 158.32,58.9 160.05,58.9 160.06,58.88 160.89,58.88 161.46,58.31 161.46,57.46 161.56,57.36 161.64,57.36 163.39,55.61 163.39,53.93 163.1,53.64 163.1,47.39 165.45,45.04 165.45,37.8 164.66,37.01 164.66,28.91 164.68,28.89 164.68,26.85 164.71,26.83 164.71,25.35 169.28,20.78 179.14,20.78 179.67,20.25 186.53,20.25 187.76,19.02 189.46,19.02 191.05,17.43 191.05,16.29 192.74,14.6 198.4,14.6 203.31,19.51 203.31,24.96 203.14,25.12 202.36,25.12 v2(202.15,24.91)
  BOTTOM w0.089: UC1.AD8 107.37,71.54 107.45,71.61 107.87,71.61 v2(107.87,71.6)
  BOTTOM w0.117: JIO1.9 200.28,26.06 200.46,26.01 200.86,25.35 201.14,25.07 201.99,25.07 v2(202.15,24.91)
USB3_ARX_DTX_P2: length 132.9
  IN1 w0.102: v2(107.86,68.6) 107.93,68.6 107.94,68.61 109.02,68.61 109.58,69.17 110.98,69.17 111.43,69.63 111.43,70.1 112.49,71.15 112.49,72.49 112.85,72.85 114.88,72.85 115.39,73.36 116.66,73.36 116.79,73.49 117.31,73.49 117.59,73.21 118.48,73.21 118.97,73.69 118.97,74.37 119.18,74.58 120.23,74.58 120.74,74.07 121.25,74.07 121.68,73.64 123.95,73.64 124.13,73.82 125.26,73.82 125.92,73.16 134,73.16 134.83,73.98 140.19,73.98 146.02,68.15 147.32,68.15 157.61,57.87 159.79,57.87 159.93,57.72 159.93,57.05 160.17,56.81 160.7,56.81 161.52,56 161.56,56 162.37,55.18 162.37,54.44 162.03,54.09 162.03,45.9 162.75,45.18 163.4,45.18 163.55,45.03 163.55,28.48 163.68,28.35 163.68,23.68 168.31,19.04 180.97,19.04 182.95,17.06 188.66,17.06 189.15,17.55 189.15,17.99 v2(189.35,18.19)
  BOTTOM w0.102: v2(107.86,68.6) 107.37,68.12 UC1.AD12
  BOTTOM w0.117: v2(189.35,18.19) 189.35,18.19 188.86,18.68 188.21,18.68 188.11,18.86 188.16,19.05 187.96,19.37 187.85,19.48 JIO1.37
USB3_ATX_DRX_N1: length 171.5
  IN1 w0.102: v2(200.6,29.19) 200.6,28.89 200.73,28.75 200.92,28.39 201.72,27.2 201.72,18.78 198.14,15.21 192.99,15.21 191.66,16.54 191.66,18.42 191.24,18.84 191.24,18.84 189.08,21 189.08,23.49 190.43,24.85 191.21,24.85 191.47,25.1 191.47,25.59 190.81,26.26 188.5,26.26 188.41,26.17 187.31,26.17 187.13,25.99 187.13,25.39 186.78,25.04 185.55,25.04 184.43,23.92 180.78,23.92 180.6,24.1 180.55,24.1 170.46,24.1 167.12,27.44 167.12,31.02 169.55,33.44 169.55,41.99 169.17,42.37 169.17,46.29 168.25,47.21 168.25,47.67 166.97,48.95 166.97,54.37 165.6,55.74 165.6,57.54 163.36,59.77 163.36,60.86 162.17,62.06 159.48,62.06 152.05,69.49 151.67,69.49 149.11,72.04 148.26,72.04 143.14,77.16 141.65,77.16 140.12,78.69 139.77,78.69 136.81,81.65 132.39,81.65 131.94,81.21 131.94,79.35 130.71,78.11 126.35,78.11 125.72,78.73 123.96,78.73 123.49,79.2 112.56,79.2 112.26,79.5 110,79.5 109.19,78.68 109.19,77.77 v2(109.21,77.74)
  BOTTOM w0.102: v2(109.21,77.74) 109.17,77.7 109.17,77.18 108.6,76.61 108.6,75.61 108.68,75.53 108.68,75.17 108.54,75.03 108.54,74.66 UC1.AE3
  BOTTOM w0.117: JIO1.5 201.18,28.44 200.99,28.48 200.9,28.65 200.67,28.88 v2(200.6,29.19)
USB3_ATX_DRX_N2: length 140.9
  IN1 w0.102: v2(107.28,77.73) 107.37,77.82 107.37,79.65 107.38,79.66 107.38,79.69 108.21,80.52 110.49,80.52 110.7,80.73 112.07,80.73 112.31,80.49 112.67,80.49 112.75,80.41 115.98,80.41 116.48,80.91 116.78,80.91 117.49,80.19 122.87,80.19 123.17,80.5 124.74,80.5 125.92,81.68 130.93,81.68 131.89,82.64 136.24,82.64 136.32,82.64 137.22,82.64 140.18,79.68 140.54,79.68 142.06,78.15 143.55,78.15 143.77,77.93 143.77,77.93 147.94,73.77 149.31,73.77 160.01,63.06 163.42,63.06 164.43,62.05 164.43,61.21 165.59,60.05 165.59,59.01 167.01,57.59 167.01,57.24 173.98,50.27 173.98,45.42 176.48,42.92 176.48,37.02 176.85,36.64 178.6,36.64 178.95,36.3 178.95,33.48 181.56,30.87 183.89,30.87 184.21,31.18 188.65,31.18 190.86,28.97 193.36,28.97 194.33,28.01 194.33,25.15 v2(194.48,24.99)
  BOTTOM w0.102: v2(107.28,77.73) 107.28,76.91 107.75,76.44 107.75,75.21 107.55,75.01 107.55,74.76 107.67,74.64 107.67,74.31 UC1.AD4
  BOTTOM w0.117: JIO1.35 188.41,20.93 188.41,21.31 188.86,21.75 188.86,23.61 189.53,24.28 189.78,24.28 189.8,24.29 190.4,24.29 190.41,24.28 v4(191.57,24.28) 191.79,24.28 193.22,25.71 193.91,25.71 194.29,25.33 194.29,25.18 v2(194.48,24.99)
USB3_ATX_DRX_P1: length 171.5
  IN1 w0.102: v2(108.47,77.74) 108.67,77.74 108.98,78.06 108.98,78.77 109.9,79.69 111.59,79.69 111.6,79.7 111.72,79.7 111.74,79.69 112.34,79.69 112.64,79.39 123.56,79.39 124.03,78.92 125.8,78.92 126.43,78.3 130.63,78.3 131.75,79.42 131.75,81.29 132.31,81.84 136.89,81.84 139.85,78.88 140.2,78.88 141.73,77.35 143.22,77.35 148.34,72.23 149.19,72.23 151.75,69.68 152.13,69.68 159.56,62.25 162.25,62.25 163.55,60.94 163.55,59.85 165.79,57.62 165.79,55.82 167.16,54.45 167.16,49.03 168.44,47.75 168.44,47.29 169.36,46.37 169.36,42.44 169.74,42.07 169.74,33.37 167.31,30.94 167.31,27.52 170.54,24.29 180.55,24.29 180.68,24.28 180.85,24.11 184.35,24.11 185.47,25.23 186.7,25.23 186.93,25.47 186.93,26.07 187.23,26.36 188.33,26.36 188.42,26.45 190.88,26.45 191.66,25.67 191.66,25.02 191.29,24.66 190.51,24.66 189.27,23.41 189.27,21.08 191.43,18.92 191.85,18.5 191.85,16.62 193.07,15.4 198.06,15.4 201.53,18.86 201.53,27.12 200.75,28.29 200.57,28.63 200.44,28.75 v2(200.16,28.75)
  BOTTOM w0.089: 108.34,75.57 108.26,75.49 108.26,75.39 108.35,75.3 UC1.AE1
  BOTTOM w0.102: 108.34,75.57 108.41,75.65 108.41,75.86 108.31,75.96 108.2,75.96 108.13,76.04 108.13,76.21 108.2,76.28 108.35,76.28 108.41,76.35 108.41,76.69 108.98,77.26 108.98,77.44 108.68,77.74 v2(108.47,77.74)
  BOTTOM w0.117: v2(200.16,28.75) 200.51,28.72 200.72,28.51 200.8,28.37 200.75,28.18 JIO1.6
USB3_ATX_DRX_P2: length 140.9
  IN1 w0.102: v2(193.67,24.97) 193.77,24.86 193.92,24.86 194.07,25.02 194.07,25.15 194.14,25.21 194.14,27.93 193.28,28.78 190.78,28.78 188.57,30.99 184.29,30.99 183.97,30.68 181.48,30.68 178.76,33.4 178.76,36.22 178.52,36.45 176.77,36.45 176.29,36.94 176.29,42.84 173.79,45.34 173.79,50.19 166.82,57.17 166.82,57.51 165.4,58.93 165.4,59.97 164.24,61.13 164.24,61.97 163.34,62.87 159.93,62.87 149.23,73.58 147.86,73.58 143.69,77.74 143.69,77.74 143.47,77.96 141.99,77.96 140.46,79.49 140.1,79.49 137.14,82.45 136.32,82.45 136.24,82.45 131.97,82.45 131,81.49 126,81.49 124.82,80.31 123.25,80.31 122.95,80 117.42,80 116.7,80.72 116.56,80.72 116.06,80.22 112.67,80.22 112.6,80.3 112.23,80.3 111.99,80.54 110.78,80.54 110.57,80.33 108.29,80.33 107.57,79.61 107.57,78.05 v2(107.89,77.73)
  BOTTOM w0.089: 107.88,74.73 107.87,74.73 107.87,74.52 107.94,74.45 107.99,74.45 108.09,74.55 108.09,74.69
  BOTTOM w0.102: 108.09,74.69 108.19,74.8 108.19,75.01 107.94,75.27 107.94,76.52 107.47,76.99 107.47,77.36 107.57,77.46 107.79,77.46 107.89,77.56 v2(107.89,77.73) ; UC1.AD2 107.88,74.73
  BOTTOM w0.117: v2(193.67,24.97) 193.78,24.85 193.95,24.85 194.06,24.97 194.06,25.24 193.82,25.48 193.31,25.48 191.88,24.05 v4(190.1,24.05) 189.62,24.05 189.08,23.51 189.08,21.66 188.64,21.21 188.64,20.97 188.71,20.75 JIO1.34
USB20_N0: length 114.1
  IN3 w0.102: v2(106.87,72.3) 106.72,72.45 106.65,72.45 106.45,72.25 106.45,68.33 106.08,67.96 96.07,67.96 96.01,67.89 90.96,67.89 89.62,69.24 89.08,69.24 87.74,70.58 87.74,71.63 84.07,75.29 83.75,75.29 82.86,76.18 75.07,76.18 72.49,78.76 69.03,78.76 62.07,85.72 54.34,85.72 54,86.06 54,86.28 v2(53.77,86.5)
  BOTTOM w0.089: v2(53.77,86.5) 54,86.28 54,86.06 52.55,84.62 52.38,84.62 52.35,84.65 51.75,84.65 51.71,84.62 48.95,84.62 46.27,81.93 44.37,81.93 43.58,82.72 43.58,87.94 43.36,88.16 43.36,88.78 41,91.15 v4(39.67,91.15) 28.32,91.15 27.22,90.05 21.76,90.05 20.14,91.66 20.14,93.64 19.95,93.83 19.24,93.83 LT1.1
  BOTTOM w0.102: UC1.AC7 106.57,72 v2(106.87,72.3)
USB20_N0_R: length 19.1
  IN1 w0.094: v2(9.55,89.97) 9.73,90.15 9.73,90.28 9.61,90.4 9.21,90.4 8.94,90.14 8.94,89.77 8.74,89.57 8.29,89.57 v2(8.09,89.37)
  IN3 w0.102: v2(15.1,94.05) 14.9,93.84 14.75,93.84 14.45,93.84 14.07,93.46 10.1,93.46 9.19,92.55 9.19,91.06 9.76,90.49 9.76,90.18 v2(9.55,89.97)
  BOTTOM w0.089: LT1.2 18.31,93.83 16.44,93.83 DT1.4 15.1,94.81 v2(15.1,94.05) ; v2(9.55,89.97) 9.72,89.8 9.72,89.68 9.62,89.58 9.36,89.58 9.19,89.75 JUSBC2.A7 ; v2(8.09,89.37) 7.96,89.51 JUSBC2.B7
USB20_N1: length 139.6
  TOP w0.089: v2(190.92,25.37) 190.73,25.18 U7.2
  IN1 w0.094: v2(105.87,70.8) 105.71,70.97 105.5,70.97 105.29,71.17 105.29,73.17 104.76,73.71 104.76,74.35 105.67,75.27 109.76,75.27 110.15,75.65 110.57,75.65 110.89,75.97 110.89,76.11 111.02,76.24 111.02,76.53 112.33,77.83 112.33,77.96 113.12,78.75 122.73,78.75 123.77,77.71 130.88,77.71 131.43,78.26 132.24,78.26 132.48,78.03 136.37,78.03 136.62,78.28 139.96,78.28 141.53,76.71 142.99,76.71 148.09,71.61 148.94,71.61 151.51,69.03 151.9,69.03 159.38,61.55 161.74,61.55 161.84,61.45 161.84,61.42 162.81,60.46 162.81,59.62 165.17,57.26 165.17,55.22 165.8,54.6 165.8,49.24 167.79,47.25 167.79,46.05 168.19,45.65 168.19,43.11 167.28,42.19 167.28,36.25 167.86,35.67 168.32,35.67 168.78,35.2 168.78,33.53 166.64,31.39 166.64,26.95 170.05,23.55 177.89,23.55 178.74,22.69 183.02,22.69 183.85,23.52 184.6,23.52 185.67,24.59 188.67,24.59 189.93,25.85 190.43,25.85 190.74,25.55 190.74,25.47 190.84,25.37 v2(190.92,25.37)
  BOTTOM w0.102: v2(105.87,70.8) 105.48,70.4 UC1.AA9
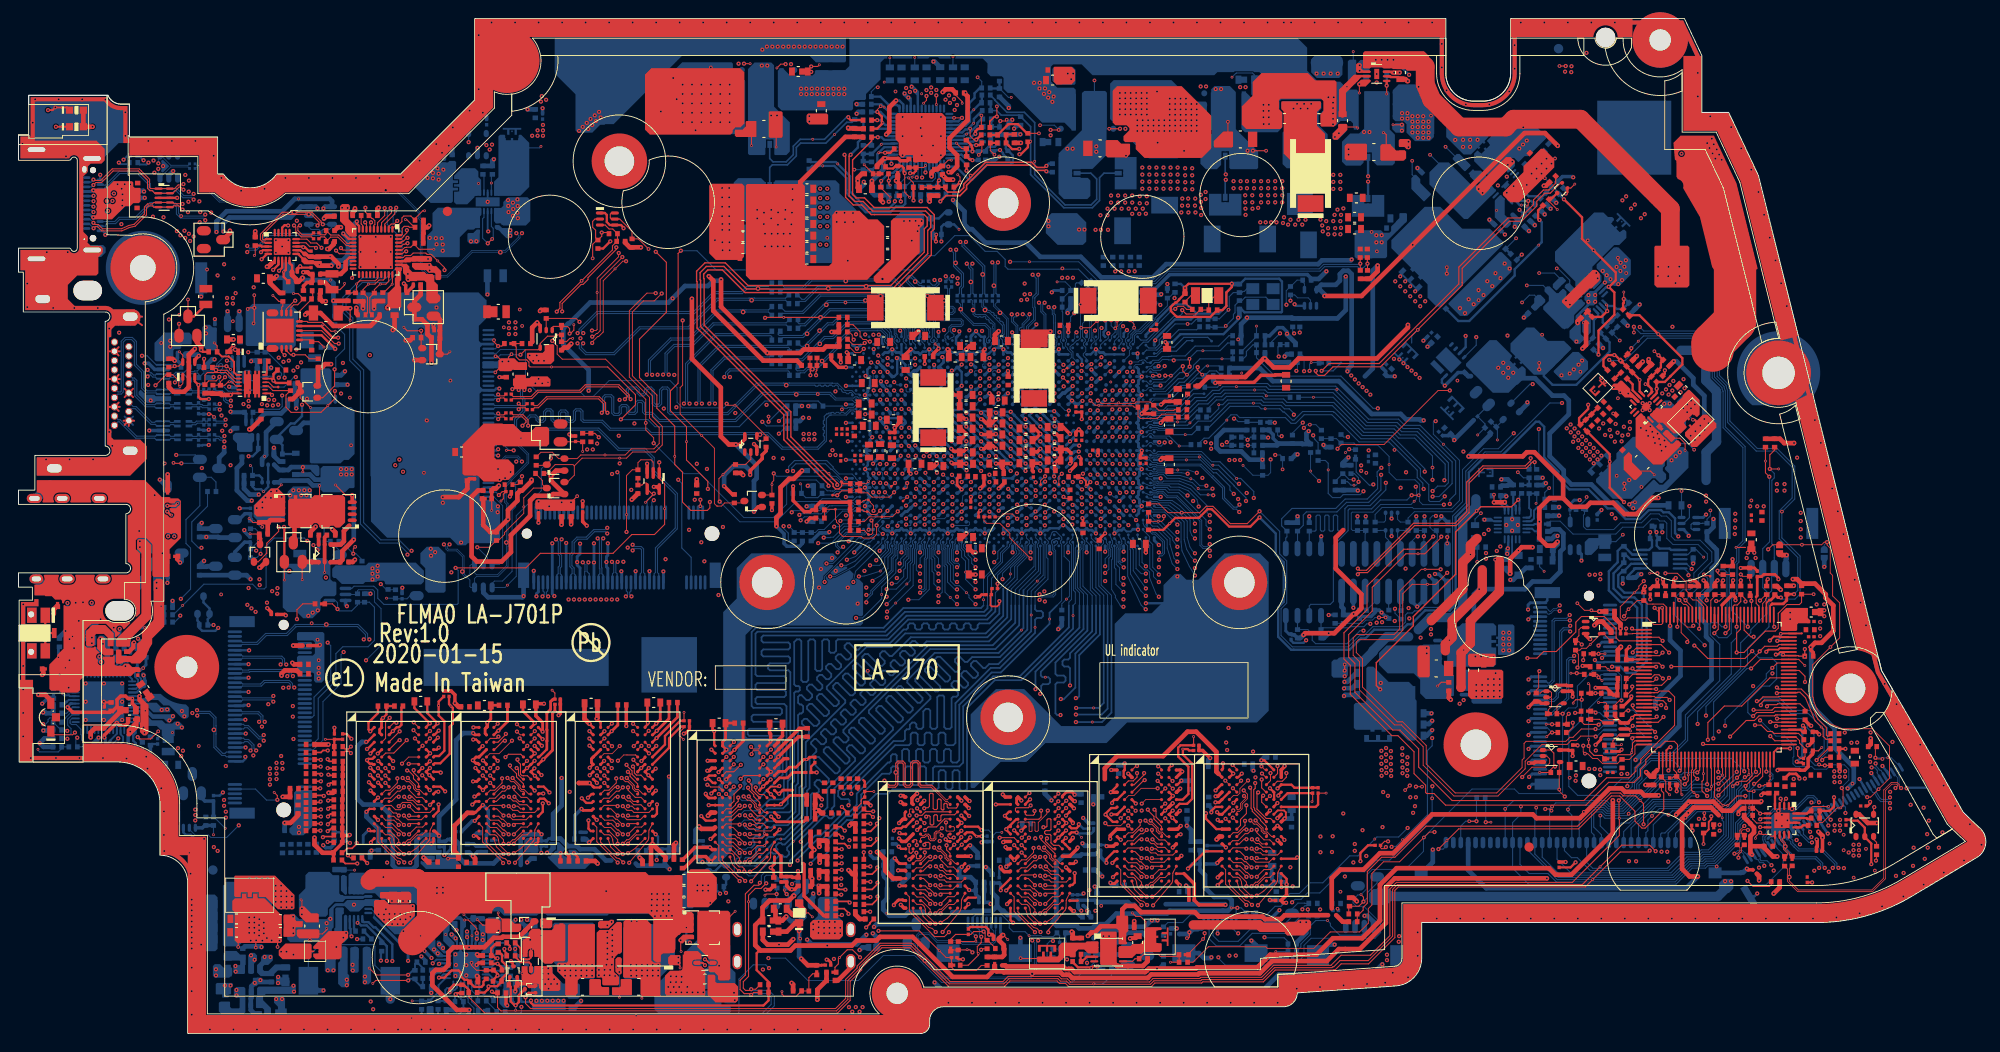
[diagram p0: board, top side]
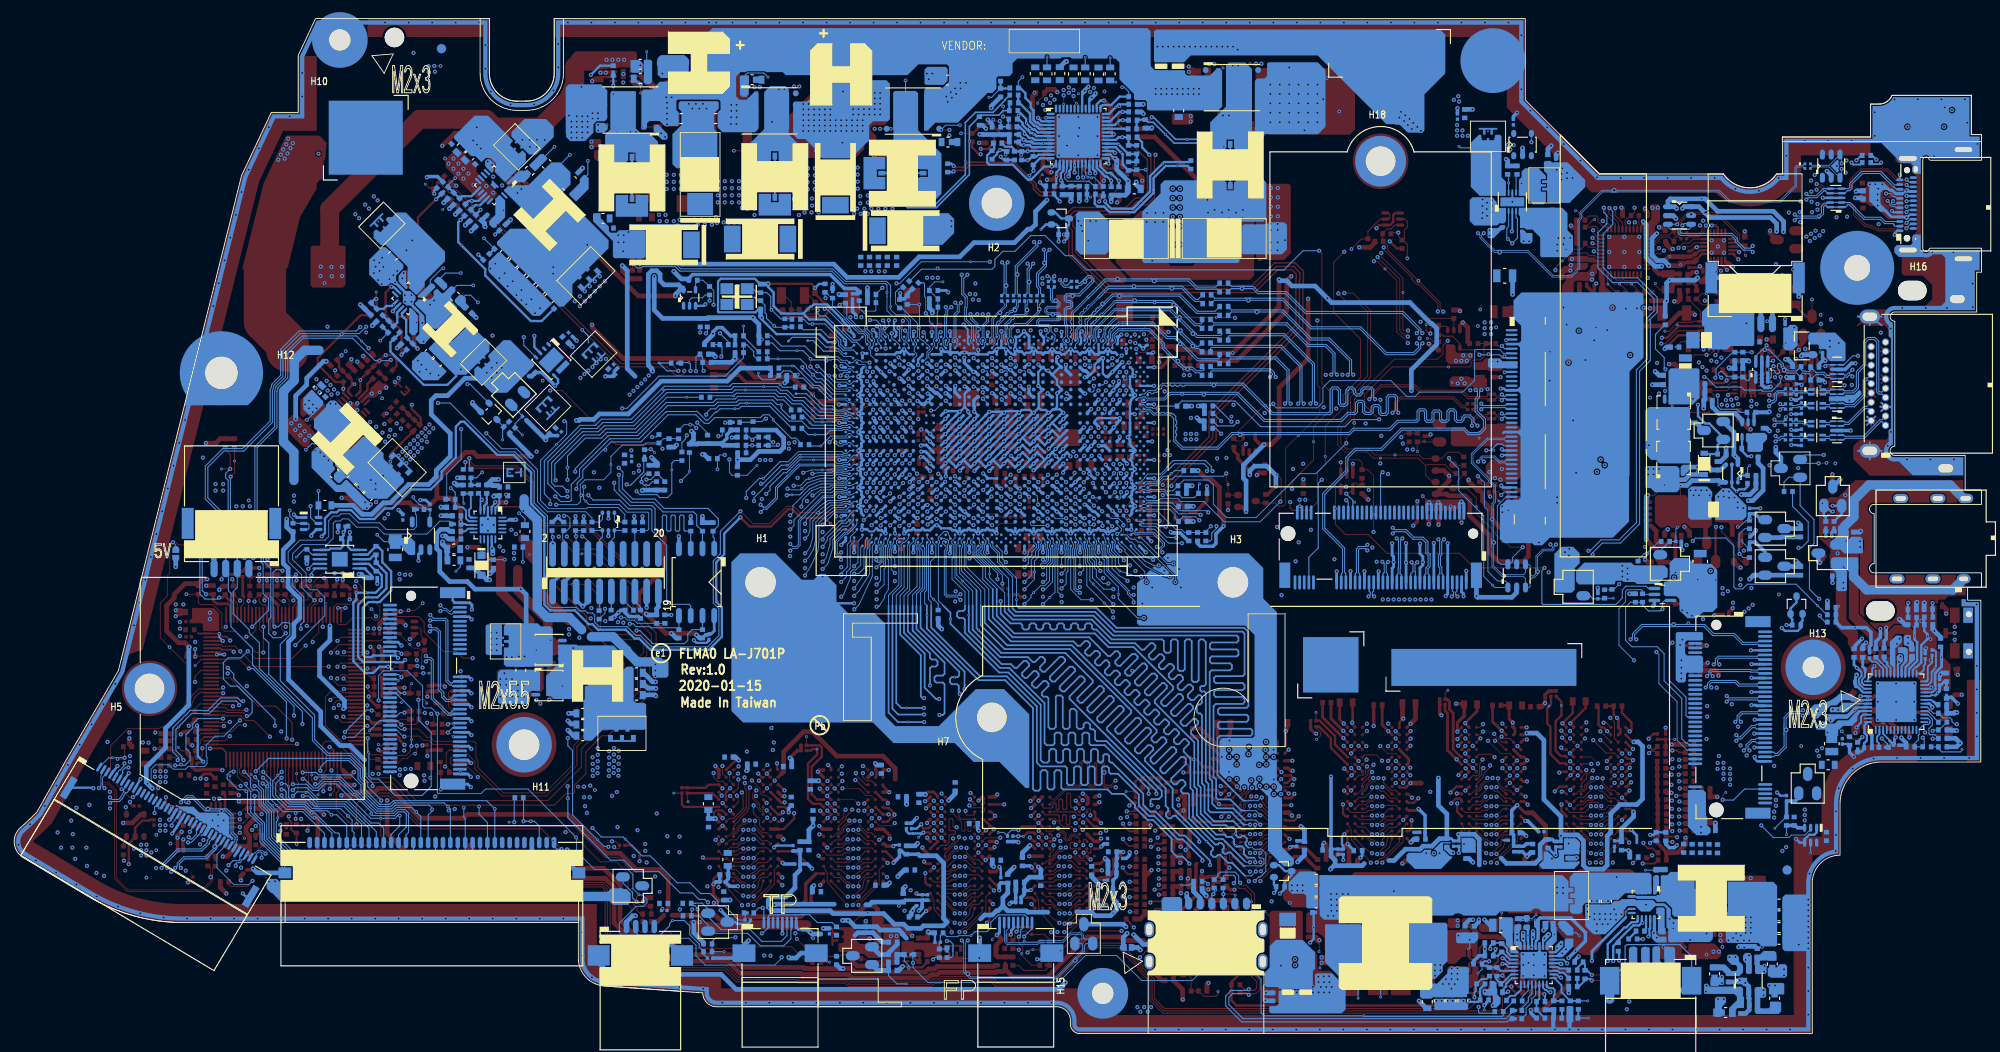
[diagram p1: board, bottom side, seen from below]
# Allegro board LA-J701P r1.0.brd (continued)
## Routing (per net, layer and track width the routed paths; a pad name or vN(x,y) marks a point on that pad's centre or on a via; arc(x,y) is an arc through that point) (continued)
USB20_N2: length 66.9
  IN1 w0.094: v2(104.87,70.8) 104.87,70.6 104.74,70.47 104.6,70.47 104.49,70.58 104.49,72.52 104.05,72.96 102.46,72.96 100.81,74.61 95.75,74.61 94.1,76.26 89.25,76.26 88.23,75.25 87.72,75.25 87.52,75.45 65.39,75.45 55.72,65.78 55.72,65.31 54.04,63.63 54.04,62.09 v2(53.77,61.81)
  BOTTOM w0.089: v2(53.77,61.81) 53.98,62.03 53.98,62.15 53.89,62.24 52.65,62.24 52.09,61.67 51.42,61.67 51.26,61.51 JEDP1.30
  BOTTOM w0.102: UC1.Y9 104.48,70.4 v2(104.87,70.8)
USB20_N3: length 105.1
  IN1 w0.094: v2(104.87,73) 104.85,73 104.38,73.47 103.74,73.47 101.87,75.33 96.75,75.33 96.6,75.48 96.6,75.48 95.22,76.87 87.22,76.87 86.38,76.03 64.9,76.03 55.43,66.56 54.29,66.56 53.58,65.85 53.58,65.26 52.69,64.37 51.95,64.37 47.57,59.98 47.57,54.98 46.19,53.6 46.19,53.1 v2(45.95,52.86)
  BOTTOM w0.089: JEDP1.24 51.36,64.51 51.52,64.35 53.4,64.35 55.11,62.64 55.11,61.65 53.28,59.82 53.28,59.73 52.67,59.12 52.67,57.49 52.88,57.29 52.88,53.44 52.91,53.4 52.91,52.69 52.88,52.65 52.88,50.48 51.8,49.41 49.49,49.41 49.26,49.17 D6.3 48.85,48.21 48.76,48.3 48.76,49.01 48.52,49.25 48.3,49.25 47.94,49.61 v4(47.94,49.93) 47.94,51.53 47.31,52.16 46.36,52.16 46.17,52.36 46.17,52.65 v2(45.95,52.86)
  BOTTOM w0.102: UC1.Y6 104.57,72.7 v2(104.87,73)
USB20_N5: length 136.1
  TOP w0.089: RUS12.1 185.94,21.59 185.94,21.96 v2(186.41,22.43)
  IN1 w0.094: v2(186.41,22.43) 186.75,22.41 187,22.65 187,22.92 186.91,23.01 185.92,23.01 183.76,20.86 179.92,20.86 179.39,21.39 176.64,21.39 176.26,21.77 169.16,21.77 165.32,25.61 165.32,27.08 165.31,27.09 165.31,31.45 166.18,32.31 166.18,33.94 165.95,34.17 165.95,36.53 166.41,36.99 166.41,45.02 166.97,45.58 166.97,46.71 164.96,48.71 164.96,53.73 164.41,54.28 164.41,56.85 161.99,59.26 161.99,60.13 161.76,60.36 159.48,60.36 151.68,68.15 150.46,68.15 142.66,75.95 141.21,75.95 139.64,77.52 136.94,77.52 136.68,77.26 133.75,77.26 133.13,76.64 126.7,76.64 126.44,76.9 123.58,76.9 122.42,78.06 121.45,78.06 121.39,78 115.09,78 114.34,77.24 113.22,77.24 112.01,76.03 112.01,75.63 111.09,74.71 110.35,74.71 110.15,74.5 107.81,74.5 106.43,73.12 106.43,69.22 106.11,68.89 106.11,68.62 106.02,68.53 v2(105.84,68.53)
  BOTTOM w0.102: UC1.AA12 105.84,68.46 v2(105.84,68.53)
USB20_N5_R: length 3.6
  TOP w0.089: v2(185.35,19.44) 185.64,19.44 185.94,19.74 185.94,20.1 RUS12.2
  BOTTOM w0.089: v2(185.35,19.44) 185.68,19.77 186.22,19.77 186.48,19.51 186.52,19.51 JIO1.39
USB20_N6: length 176.2
  IN3 w0.102: v2(103.87,70.8) 103.69,70.99 103.45,70.99 103.27,71.16 103.27,72.87 103.6,73.2 103.6,74.13 104.05,74.58 106.96,74.58 107.46,74.08 107.46,71.36 107.36,71.26 107.36,70.72 107.65,70.43 108.15,70.43 108.46,70.12 108.46,69.6 108.65,69.42 111.06,69.42 111.28,69.64 111.28,70.36 112.28,71.36 112.28,72.67 112.79,73.18 116.25,73.18 116.74,73.68 117.88,73.68 118.41,73.15 120.38,73.15 120.81,72.71 124.07,72.71 124.58,72.2 125,72.2 125.52,72.72 128.6,72.72 129.05,72.27 132.07,72.27 132.66,71.68 133.79,71.68 134.89,70.58 136.38,70.58 140.68,66.27 142.84,66.27 145.05,64.06 145.05,62.72 145.94,61.83 145.94,56.33 146.13,56.14 146.13,55.32 145.49,54.69 145.49,44.86 144.63,44 144.63,34.03 144.53,33.93 144.53,27.38 144.06,26.91 144.06,22.31 145.18,21.19 145.18,19.54 144.66,19.02 143.39,19.02 143.17,18.8 141.55,18.8 137.92,15.17 136.99,15.17 134.19,12.38 124.17,12.38 121.42,9.62 114.56,9.62 114.19,9.25 110.14,9.25 109.76,9.63 109.76,9.8 v2(109.5,10.05)
  BOTTOM w0.089: JFP1.2 105.56,11.13 105.53,11.09 105.53,9.91 105.25,9.63 101.95,9.63 101.72,9.86 99.18,9.86 98.35,10.7 97.31,10.7 97.16,10.55 97.16,10.29 97.25,10.2 97.46,10.2 DFP1.2 97.18,9.73 97.1,9.64 97.1,8.95 97.84,8.2 97.85,8.2 98.22,7.84 98.22,7.82 99.94,6.1 109.15,6.1 v4(109.5,6.45) 109.76,6.71 109.76,9.8 v2(109.5,10.05)
  BOTTOM w0.102: UC1.W9 103.48,70.4 v2(103.87,70.8)
USB20_N7: length 92.9
  IN1 w0.094: v2(166.47,45.66) 166.26,45.88 165.52,45.88 164.1,47.31 164.1,53.17 163.82,53.45 163.82,56.6 161.12,59.3 158.67,59.3 152.8,65.18 152.69,65.18 152.49,65.38 152.49,66.51 151.73,67.27 150.51,67.27 142.42,75.36 140.98,75.36 139.4,76.94 137.18,76.94 136.92,76.68 133.99,76.68 133.31,76 126.51,76 126.19,76.32 122.82,76.32 122.72,76.41 119.93,76.41 118.84,77.5 115.88,77.5 114.88,76.49 114.88,75.5 114.54,75.16 112.12,75.16 111.07,74.11 110.57,74.11 110.44,73.98 109.65,73.98 109.06,73.39 108.72,73.39 108.26,72.92 107.78,72.92 107.46,72.61 107.46,68.84 106.57,67.95 105.25,67.95 104.42,68.78 104.13,68.78 v2(103.88,68.53)
  BOTTOM w0.089: JWLAN1.5 164.98,45.55 165.21,45.32 165.35,45.32 165.44,45.41 165.54,45.41 165.88,45.75 166.38,45.75 v2(166.47,45.66)
  BOTTOM w0.102: v2(103.88,68.53) 103.88,68.45 103.42,68 UC1.W12
USB20_P0: length 114.2
  IN3 w0.102: v2(106.87,73) 106.56,72.68 106.56,72.63 106.26,72.32 106.26,68.4 106,68.15 95.99,68.15 95.93,68.08 91.04,68.08 89.7,69.43 89.15,69.43 87.93,70.66 87.93,71.71 84.15,75.48 83.83,75.48 82.94,76.37 75.15,76.37 72.57,78.95 69.1,78.95 62.14,85.91 54.42,85.91 54.19,86.14 54.19,86.3 v2(54.38,86.5)
  BOTTOM w0.089: v2(54.38,86.5) 54.18,86.29 54.18,85.99 52.62,84.43 v4(52.05,84.43) 49.03,84.43 47.38,82.79 46.34,81.75 44.29,81.75 43.4,82.65 43.4,87.87 43.18,88.08 43.18,88.7 40.92,90.97 40,90.97 39.96,90.93 39.37,90.93 39.33,90.97 28.39,90.97 27.29,89.87 21.69,89.87 19.96,91.59 19.96,93.56 19.87,93.65 19.23,93.65 LT1.4
  BOTTOM w0.102: v2(106.87,73) 106.57,72.7 UC1.AC6
USB20_P0_R: length 19.3
  IN1 w0.094: v2(8.1,89.95) 8.3,89.75 8.67,89.75 8.76,89.84 8.76,90.21 9.13,90.58 9.69,90.58 9.91,90.36 9.91,90.22 v2(10.15,89.98)
  IN3 w0.102: v2(15.1,93.45) 14.89,93.65 14.75,93.65 14.53,93.65 14.15,93.27 10.18,93.27 9.38,92.47 9.38,91.14 9.95,90.57 9.95,90.18 v2(10.15,89.98)
  BOTTOM w0.089: JUSBC2.A6 9.22,89.26 9.36,89.4 9.69,89.4 9.91,89.62 9.91,89.75 v2(10.15,89.98) ; LT1.3 18.31,93.65 16.44,93.65 DT1.3 15.1,92.68 v2(15.1,93.45) ; v2(8.1,89.95) 8.05,90 JUSBC2.B6
USB20_P1: length 139.6
  TOP w0.089: U7.3 190.23,24.85 190.47,25.09 190.47,25.25 v2(190.34,25.38)
  IN1 w0.094: v2(190.34,25.38) 190.35,25.38 190.39,25.42 190.39,25.56 190.28,25.67 190.01,25.67 188.75,24.41 185.75,24.41 184.67,23.33 183.92,23.33 183.1,22.51 178.66,22.51 177.81,23.36 169.97,23.36 166.46,26.88 166.46,31.47 168.6,33.61 168.6,35.13 168.24,35.48 167.78,35.48 167.09,36.18 167.09,42.27 168.01,43.19 168.01,45.57 167.61,45.97 167.61,47.17 165.62,49.16 165.62,54.52 164.99,55.15 164.99,57.18 162.63,59.54 162.63,60.38 161.66,61.35 161.66,61.37 159.3,61.37 151.82,68.85 151.44,68.85 148.86,71.43 148.02,71.43 142.92,76.53 141.45,76.53 139.88,78.1 136.7,78.1 136.44,77.84 132.4,77.84 132.16,78.08 131.51,78.08 130.95,77.52 123.69,77.52 122.65,78.57 113.19,78.57 112.51,77.89 112.51,77.76 111.2,76.45 111.2,76.17 111.07,76.03 111.07,75.89 110.65,75.47 110.22,75.47 109.84,75.08 105.75,75.08 104.94,74.27 104.94,73.78 105.48,73.24 105.48,71.24 105.57,71.15 105.7,71.15 105.75,71.2 105.88,71.2 106,71.32 106,71.47 v2(105.87,71.6)
  BOTTOM w0.089: UC1.AA8 105.35,71.2 105.24,71.31 105.24,71.53 105.35,71.64 105.51,71.64 105.65,71.49 105.77,71.49 v2(105.87,71.6)
USB20_P2: length 66.8
  IN1 w0.094: v2(54.38,61.81) 54.22,61.97 54.22,63.55 55.9,65.23 55.9,65.7 65.46,75.27 87.44,75.27 87.65,75.06 88.31,75.06 89.32,76.08 94.02,76.08 95.67,74.43 100.73,74.43 102.38,72.78 103.97,72.78 104.3,72.44 104.3,70.51 104.53,70.28 104.79,70.28 104.87,70.2 v2(104.87,70)
  BOTTOM w0.089: v2(54.38,61.81) 54.16,62.03 54.16,62.22 53.97,62.42 52.58,62.42 52.01,61.85 51.48,61.85 51.32,62.01 JEDP1.29
  BOTTOM w0.102: UC1.Y10 104.48,69.6 v2(104.87,70)
USB20_P3: length 105.1
  IN1 w0.094: v2(46.56,52.86) 46.37,53.05 46.37,53.52 47.75,54.9 47.75,59.9 52.03,64.19 52.77,64.19 53.76,65.18 53.76,65.78 54.36,66.38 55.5,66.38 64.97,75.85 86.46,75.85 87.29,76.68 95.14,76.68 96.67,75.15 101.8,75.15 103.66,73.28 104.3,73.28 104.49,73.09 104.49,72.84 104.87,72.46 v2(104.87,72.3)
  BOTTOM w0.089: UC1.Y7 104.2,72 104.12,72.08 104.12,72.27 104.21,72.36 104.82,72.36 v2(104.87,72.3) ; v2(46.56,52.86) 46.35,52.65 46.35,52.43 46.43,52.34 47.39,52.34 48.12,51.61 48.12,50.26 48.16,50.22 48.16,49.65 48.37,49.45 48.53,49.45 48.76,49.68 48.76,50.55 48.92,50.71 D6.4 49.26,49.8 49.47,49.59 51.73,49.59 52.7,50.55 v4(52.7,53.07) 52.7,57.21 52.49,57.42 52.49,59.2 53.1,59.8 53.1,59.89 54.93,61.73 54.93,62.57 53.33,64.17 51.53,64.17 51.37,64.01 JEDP1.25
USB20_P5: length 136.1
  TOP w0.089: RUS11.1 186.12,21.59 186.12,21.88 186.27,22.03 186.73,22.03 186.76,22.03 186.8,22 v2(186.81,22)
  IN1 w0.094: v2(186.81,22) 186.82,22.2 187.19,22.57 187.19,22.99 186.99,23.2 185.84,23.2 183.69,21.04 180,21.04 179.47,21.58 176.71,21.58 176.34,21.95 169.24,21.95 165.5,25.68 165.5,27.16 165.5,27.16 165.5,31.37 166.36,32.24 166.36,34.02 166.13,34.24 166.13,36.45 166.59,36.91 166.59,44.95 167.15,45.51 167.15,46.78 165.14,48.79 165.14,53.8 164.59,54.36 164.59,56.93 162.17,59.34 162.17,60.2 161.84,60.54 159.55,60.54 151.76,68.34 150.53,68.34 142.74,76.13 141.29,76.13 139.72,77.7 136.86,77.7 136.61,77.44 133.68,77.44 133.05,76.82 126.77,76.82 126.51,77.08 123.66,77.08 122.5,78.24 121.37,78.24 121.31,78.18 115.02,78.18 114.26,77.42 113.14,77.42 111.83,76.11 111.83,75.7 111.01,74.89 110.28,74.89 110.07,74.69 107.74,74.69 106.25,73.2 106.25,69.29 106.16,69.2 v2(105.87,69.2)
  BOTTOM w0.102: v2(105.87,69.2) 105.87,69.15 105.53,68.8 UC1.AA11
USB20_P5_R: length 3.6
  TOP w0.089: RUS11.2 186.12,20.1 186.12,19.66 185.78,19.32 v2(185.78,19)
  BOTTOM w0.089: v2(185.78,19) 185.75,19.04 185.75,19.5 185.84,19.59 186.13,19.59 186.35,19.37 186.35,19 JIO1.40
USB20_P6: length 176.2
  IN3 w0.102: v2(110.14,10.05) 109.95,9.86 109.95,9.71 110.21,9.44 114.11,9.44 114.48,9.81 121.34,9.81 124.09,12.57 134.12,12.57 136.91,15.36 137.84,15.36 141.47,18.99 143.09,18.99 143.31,19.21 144.58,19.21 144.99,19.62 144.99,21.11 143.87,22.23 143.87,26.99 144.34,27.46 144.34,34.01 144.44,34.11 144.44,44.08 145.3,44.94 145.3,54.77 145.94,55.4 145.94,56.06 145.75,56.25 145.75,61.75 144.86,62.64 144.86,63.99 142.76,66.08 140.6,66.08 136.3,70.39 134.81,70.39 133.71,71.49 132.58,71.49 131.99,72.08 128.97,72.08 128.52,72.53 125.6,72.53 125.08,72.01 124.5,72.01 123.99,72.52 120.73,72.52 120.3,72.96 118.33,72.96 117.8,73.49 116.82,73.49 116.33,72.99 112.87,72.99 112.47,72.6 112.47,71.28 111.47,70.28 111.47,69.56 111.14,69.23 108.57,69.23 108.27,69.52 108.27,70.04 108.07,70.24 107.57,70.24 107.17,70.64 107.17,71.33 107.27,71.44 107.27,74 106.88,74.39 104.13,74.39 103.79,74.05 103.79,73.12 103.46,72.79 103.46,71.24 103.52,71.18 103.78,71.18 103.88,71.28 103.88,71.6 v2(103.87,71.6)
  BOTTOM w0.089: v2(110.14,10.05) 109.94,9.85 109.94,6.62 109.24,5.92 99.86,5.92 v4(97.9,7.89) 96.91,8.87 96.91,9.54 96.72,9.73 DFP1.3 96.47,10.2 96.89,10.2 96.98,10.29 96.98,10.62 97.23,10.88 98.42,10.88 99.26,10.04 101.79,10.04 102.02,9.81 105.17,9.81 105.35,9.98 105.35,11.08 105.07,11.36 JFP1.3 ; UC1.W8 103.26,71.32 103.26,71.54 103.35,71.63 103.85,71.63 v2(103.87,71.6)
USB20_P7: length 92.9
  IN1 w0.094: v2(103.87,69.2) 104.11,68.97 104.49,68.97 105.33,68.13 106.49,68.13 107.28,68.92 107.28,72.68 107.7,73.11 108.18,73.11 108.64,73.57 108.98,73.57 109.58,74.16 110.36,74.16 110.49,74.29 111,74.29 112.05,75.34 114.46,75.34 114.7,75.58 114.7,76.57 115.81,77.68 118.92,77.68 120.01,76.59 122.8,76.59 122.89,76.5 126.27,76.5 126.58,76.19 133.24,76.19 133.92,76.86 136.85,76.86 137.11,77.12 139.48,77.12 141.05,75.54 142.5,75.54 150.59,67.46 151.81,67.46 152.68,66.59 152.68,65.45 152.77,65.36 152.87,65.36 158.75,59.48 161.19,59.48 164,56.67 164,53.52 164.28,53.25 164.28,47.38 165.6,46.06 166.26,46.06 v2(166.47,46.27)
  BOTTOM w0.089: v2(166.47,46.27) 166.14,45.93 165.8,45.93 165.46,45.59 165.44,45.59 165.28,45.75 165.28,45.75 164.98,46.05 JWLAN1.3
  BOTTOM w0.102: UC1.W11 103.48,68.8 v2(103.87,69.2)
USB_CHG_CTL1: length 25.6
  TOP w0.117: UEC1.14 176.37,38.43 176.7,38.77 177.21,38.77 v2(177.61,38.36) ; v2(188.13,23.16) 188.13,23.16 188.25,23.28 U7.6
  IN2 w0.127: v2(188.13,23.16) 188.13,23.17 188.55,23.59 188.55,24.33 189.16,24.94 189.16,27.74 189.25,27.83 189.25,29.98 181.65,37.57 178.4,37.57 v2(177.61,38.36)
USB_CHG_CTL2: length 2.2
  TOP w0.117: U7.7 188.34,22.78 188.3,22.74 187.76,22.74 187.32,23.18 RUS4.2
USB_CHG_CTL3: length 26.9
  TOP w0.117: v2(178.29,38.44) 177.48,37.63 UEC1.16 ; U7.8 188.22,22.28 188.19,22.31 v2(188.13,22.31)
  IN2 w0.127: v2(178.29,38.44) 181.15,38.44 189.5,30.08 189.5,27.7 189.41,27.61 189.41,24.84 188.8,24.23 188.8,22.98 v2(188.13,22.31)
USB_CHG_EN: length 24.6
  TOP w0.117: U7.5 188.21,23.78 188.19,23.77 v2(188.13,23.77) 187.56,24.34 RUS8.1 ; UEC1.17 176.88,37.23 v2(176.89,37.23)
  IN2 w0.127: v2(176.89,37.23) 177.49,36.63 178.71,36.63 179.04,36.3 182.54,36.3 188.36,30.49 188.36,27.89 188.84,27.41 188.84,24.99 188.13,24.27 v2(188.13,23.77)
USB_CHG_ILIM_SEL: length 1.5
  TOP w0.254: RUS2.2 189.73,25.8 U7.4
USB_CHG_STATUS#: length 28.5
  TOP w0.117: 189.73,21.45 189.6,21.33 189.31,21.33 189.12,21.52 188.32,21.52 v2(188.13,21.71) 188.07,21.71 187.62,21.26 v3(187.62,21.1) ; 189.73,21.45 189.73,20.46 189.5,20.24 RUS1.2 ; 189.73,21.45 U7.9 ; v2(178.35,36.05) 178.07,36.33 176.8,36.33 176.69,36.43 UEC1.19
  IN2 w0.127: v2(188.13,21.71) 187.62,22.22 187.62,25.74 188.51,26.62 188.51,27.36 188.1,27.77 188.1,30.36 182.41,36.05 v2(178.35,36.05)
USB_EN#: length 21.5
  TOP w0.117: v2(200.45,24.47) 200.38,24.4 U9.4 ; v1(194.49,29.08) 194.59,28.97 v2(195.11,28.97) R54.1 ; v2(189.94,34.04) 189.97,34.04 189.97,34.03 UEC1.72
  IN1 w0.102: v2(200.45,24.47) 200.45,25.93 199.56,26.82 198.94,26.82 198.42,27.34 198.42,27.96 197.4,28.97 v2(195.11,28.97)
  BOTTOM w0.117: v2(195.11,28.97) 195.1,28.99 194.05,28.99 193.51,29.52 193.51,30.36 193.95,30.79 193.95,32.3 193.21,33.04 193.21,33.46 192.63,34.04 v2(189.94,34.04)
USB_OC0#: length 129.3
  TOP w0.102: RUS3.2 194.55,22.81 194.88,22.81 196.45,24.39 v3(196.84,24.39) 197.08,24.63 197.08,26.28 196.96,26.41 196.96,26.52 v2(196.94,26.53)
  IN1 w0.102: v2(137.79,75.67) 137.79,75.45 137.52,75.19 134.22,75.19 133.41,74.38 126.43,74.38 125.7,75.11 123.71,75.11 123.1,74.5 121.72,74.5 121.03,75.19 118.43,75.19 117.92,74.68 115.69,74.68 114.52,73.51 112.65,73.51 112.32,73.18 111.67,73.18 111.27,72.78 111.27,71.53 110.93,71.19 109.26,71.19 v2(108.87,70.8)
  IN2 w0.102: v2(188.12,33.85) 188.12,34.89 187.3,35.71 187.3,36.66 187.89,37.24 187.89,37.66 187.56,37.99 184.67,37.99 181.35,41.31 180.39,41.31 178.58,43.12 178.11,43.12 172.86,48.37 172.86,50.12 167.22,55.76 167.22,56.3 166.82,56.7 166.82,57.64 166.41,58.04 165.65,58.04 161.74,61.96 156.16,61.96 153.39,64.72 152.27,65.85 152.27,66.36 148.8,69.82 148.71,69.82 147.78,70.75 147.78,71.38 142.92,76.24 138.24,76.24 137.79,75.79 v2(137.79,75.67)
  BOTTOM w0.102: RC98.2 137.63,75.8 137.76,75.67 v2(137.79,75.67) ; v2(188.12,33.85) 189.83,32.14 190.8,32.14 191.76,31.17 191.76,29.93 191.67,29.84 191.67,29.15 191.98,28.85 193.71,28.85 193.99,28.57 195.3,28.57 195.77,29.04 197.23,29.04 197.7,28.56 197.7,27.38 196.96,26.63 196.96,26.54 v2(196.94,26.53) ; v2(108.87,70.8) 108.48,70.4 UC1.AE9
USB_OC0#_R: length 1.4
  TOP w0.254: U7.13 192.55,22.28 192.76,22.5 RUS3.1
USB_OC1#: length 132.5
  TOP w0.102: RUS13.1 200.7,18.75 v2(200.64,18.69)
  IN1 w0.102: v2(187.37,37.55) 188.36,37.55 190.41,35.49 190.41,34.81 190.62,34.61 190.62,30.94 191.16,30.4 192.51,30.4 192.65,30.26 194.91,30.26 195.77,29.4 197.67,29.4 200.92,26.15 200.92,24.21 200.07,23.36 200.07,19.26 v2(200.64,18.69) ; v2(108.87,69.91) 108.88,69.92 108.88,70.01 109.26,70.39 110.43,70.39 111.47,71.43 111.47,72.7 111.75,72.98 112.4,72.98 112.73,73.31 114.62,73.31 115.79,74.48 118,74.48 118.51,74.99 120.95,74.99 121.63,74.3 124.07,74.3 124.45,74.69 125.54,74.69 126.25,73.97 133.65,73.97 134.46,74.78 138.07,74.78 138.4,75.11 v2(138.4,75.76)
  IN2 w0.102: v2(187.37,37.55) 187.33,37.58 184.5,37.58 181.18,40.9 180.22,40.9 178.41,42.72 177.93,42.72 172.46,48.19 172.46,49.94 166.82,55.58 166.82,56.13 166.58,56.37 165.69,56.37 165,57.05 165,58.12 161.57,61.55 155.92,61.55 150.54,66.94 150.54,67.42 147.37,70.58 147.37,71.21 142.82,75.76 v2(138.4,75.76)
  BOTTOM w0.102: UC1.AE10 108.68,69.91 v2(108.87,69.91) ; RC99.2 v2(138.4,75.76)
USBC0_ARX_C_DTX_N1: length 110.2
  TOP w0.117: v2(8.09,87.62) 8.27,87.43 8.61,87.43 9.08,86.97 11.11,86.97 11.9,87.32 12.49,87.46 13.6,88.57 13.6,89.33 13.94,89.67 14.47,89.67 14.62,89.81 DT7.4 DT7.7 16.68,89.81 16.82,89.68 17.7,89.68 v2(17.72,89.65)
  IN3 w0.127: v2(101.28,84.71) 101.11,84.88 101.11,85.1 100.85,85.36 100.29,85.36 99.85,84.91 98.53,84.91 94.47,80.86 79.08,80.86 77.69,82.25 75.12,82.25 68.1,89.27 58.38,89.27 56.05,91.6 55.55,92.1 49.96,92.1 49.25,92.1 47.05,89.91 29.16,89.91 27.65,88.4 23.5,88.4 20.94,89.46 17.91,89.46 v2(17.72,89.65)
  BOTTOM w0.117: v2(101.28,84.71) 101.22,84.65 v4(101.22,83.29) 101.22,83 102.07,82.15 102.07,80.71 101.86,80.5 101.86,79.91 CT44.2 ; JUSBC2.B10 7.7,88 v2(8.09,87.62)
USBC0_ARX_C_DTX_N2: length 111.5
  IN3 w0.127: v2(101.73,85.55) 101.96,85.78 101.96,85.96 101.73,86.19 98.85,86.19 94.16,81.5 79.38,81.5 77.97,82.91 75.36,82.91 68.34,89.93 59.23,89.93 58.95,89.93 56.15,92.74 50.32,92.74 48.98,92.74 46.79,90.54 28.89,90.54 27.39,89.04 23.76,89.04 20.58,90.35 19.13,90.35 v2(18.91,90.14)
  BOTTOM w0.117: CT49.2 104.15,79.97 v4(104.15,82.04) 104.15,82.86 101.91,85.09 101.91,85.37 v2(101.73,85.55) ; JUSBC2.A10 9.17,91.26 9.38,91.47 9.48,91.47 10.39,92.38 10.95,92.94 12.84,92.94 14.01,91.78 14.01,91.34 14.26,91.09 14.49,91.09 14.77,90.82 DT8.4 DT8.7 16.59,90.82 16.87,91.09 17.01,91.09 17.77,90.33 18.72,90.33 v2(18.91,90.14)
USBC0_ARX_C_DTX_P1: length 110.1
  TOP w0.117: v2(8.11,87.03) 8.29,87.21 8.52,87.21 8.98,86.75 11.15,86.75 11.97,87.11 12.6,87.25 13.82,88.47 13.82,89.24 14.03,89.44 14.47,89.44 14.6,89.32 DT7.5 DT7.6 16.63,89.32 16.77,89.45 17.31,89.45 v2(17.72,89.04)
  IN3 w0.127: v2(17.72,89.04) 17.91,89.24 20.89,89.24 23.45,88.18 27.75,88.18 29.25,89.68 47.15,89.68 49.34,91.87 49.87,91.87 55.45,91.87 55.83,91.5 58.28,89.05 68.01,89.05 75.03,82.02 77.6,82.02 78.99,80.64 94.56,80.64 98.62,84.69 99.94,84.69 100.39,85.14 100.76,85.14 100.88,85.01 100.88,84.92 v2(100.67,84.71)
  BOTTOM w0.117: JUSBC2.B11 7.63,87.51 v2(8.11,87.03) ; CT43.2 101.63,80 101.63,80.59 101.85,80.81 101.85,82.06 101,82.91 101,84.38 v2(100.67,84.71)
USBC0_ARX_C_DTX_P2: length 111.5
  IN3 w0.127: v2(102.34,85.55) 102.19,85.71 102.19,86.06 101.83,86.41 98.75,86.41 94.06,81.72 79.48,81.72 78.06,83.14 75.45,83.14 68.43,90.16 59.14,90.16 59.04,90.16 56.24,92.96 50.41,92.96 48.89,92.96 46.7,90.77 28.8,90.77 27.3,89.26 23.81,89.26 20.62,90.58 19.08,90.58 v2(18.91,90.75)
  BOTTOM w0.117: v2(18.91,90.75) 18.72,90.56 17.86,90.56 17.1,91.32 DT8.6 DT8.5 14.35,91.32 14.24,91.43 14.24,91.87 12.94,93.17 10.86,93.17 9.38,91.69 9.22,91.69 9.16,91.75 JUSBC2.A11 ; CT45.2 104.37,79.94 104.37,82.95 102.14,85.18 102.14,85.35 v2(102.34,85.55)
USBC0_ARX_DTX_N1: length 7.3
  BOTTOM w0.102: UC1.AA4 105.07,74.3 105.07,74.63 105.2,74.76 105.2,75.02 105.02,75.2 105.02,76.18 104.46,76.74 103.21,76.74 101.96,77.99 101.96,79.1 CT44.1
USBC0_ARX_DTX_N2: length 6
  BOTTOM w0.102: CT49.1 104.05,79.04 104.05,78.53 v4(104.4,78.19) 104.67,77.92 104.86,77.92 106.28,76.5 106.28,75.66 106.07,75.45 106.07,75.16 106.28,74.95 106.28,74.6 UC1.AC3
USBC0_ARX_DTX_P1: length 7.3
  BOTTOM w0.102: UC1.AA2 104.88,74.7 104.82,74.64 104.65,74.64 104.56,74.73 104.56,75.05 104.82,75.3 104.82,76.09 104.37,76.54 103.14,76.54 103.13,76.55 101.77,77.91 v4(101.77,78.28) 101.77,78.78 CT43.1
USBC0_ARX_DTX_P2: length 5.8
  BOTTOM w0.102: CT45.1 104.42,79.31 104.3,79.31 104.25,79.25 104.25,78.63 104.38,78.5 104.5,78.5 104.6,78.4 104.6,78.28 104.75,78.12 104.93,78.12 105.12,77.93 105.27,77.93 105.37,77.84 105.37,77.68 105.43,77.63 105.58,77.63 105.65,77.55 105.65,77.4 105.73,77.32 105.9,77.32 105.99,77.23 105.99,77.07 106.07,76.98 106.21,76.98 106.37,76.83 106.37,76.68 106.47,76.58 106.47,75.58 106.37,75.49 UC1.AC1
USBC0_ATX_C_DRX_N1: length 108.6
  IN3 w0.127: v2(103.04,83.2) 102.85,83.39 102.85,83.71 102.53,84.03 98.91,84.03 94.88,80 75.42,80 67.04,88.38 58.05,88.38 55.19,91.24 49.6,91.24 47.3,88.93 41.5,88.93 41.31,88.74 29.21,88.74 28.38,87.91 28.38,87.91 28.32,87.85 28.01,87.54 23.08,87.54 21.27,88.29 20.39,88.29 v2(20.17,88.51)
  BOTTOM w0.117: C251.2 103.09,80 103.09,82.62 102.85,82.86 102.85,83.01 v2(103.04,83.2) ; v2(20.17,88.51) 20.01,88.35 17.59,88.35 17.28,88.66 17.28,89.43 16.97,89.74 16.68,89.74 16.61,89.82 DT8.9 DT8.2 14.21,89.82 12.61,88.22 10.85,88.22 10.39,87.76 8.82,87.76 JUSBC2.A3
USBC0_ATX_C_DRX_N2: length 115.4
  TOP w0.117: v2(8.09,91.71) 8.36,91.97 8.97,91.97 10.22,93.22 12.95,93.22 13.11,93.06 13.13,93.04 13.94,92.23 13.94,91.34 14.18,91.09 14.44,91.09 14.72,90.81 DT7.2 DT7.9 16.67,90.81 17.34,91.49 17.52,91.49 v2(17.81,91.2)
  IN3 w0.127: v2(17.81,91.2) 18.05,91.44 20.39,91.44 24.02,89.92 24.11,89.9 27.03,89.9 28.54,91.4 46.43,91.4 48.68,93.64 56.53,93.64 59.32,90.85 68.69,90.85 75.72,83.83 78.43,83.83 79.76,82.5 93.89,82.5 98.86,87.47 102.32,87.47 105.38,84.42 105.38,83.53 v2(105.19,83.34)
  BOTTOM w0.117: v2(8.09,91.71) 7.89,91.51 JUSBC2.B3 ; C253.2 105.36,79.91 v4(105.36,80.82) 105.36,83.18 v2(105.19,83.34)
USBC0_ATX_C_DRX_P1: length 108.5
  IN3 w0.127: v2(102.43,83.2) 102.62,83.4 102.62,83.62 102.44,83.8 99.01,83.8 94.98,79.77 75.33,79.77 66.94,88.16 57.95,88.16 55.1,91.01 49.7,91.01 47.39,88.7 41.6,88.7 41.41,88.51 29.3,88.51 28.61,87.82 28.54,87.75 28.11,87.32 23.04,87.32 21.23,88.07 20.34,88.07 v2(20.17,87.9)
  BOTTOM w0.117: v2(102.43,83.2) 102.62,83.01 102.62,82.77 102.87,82.52 v4(102.87,81.23) 102.87,79.93 C250.2 ; JUSBC2.A2 9.39,87.26 9.45,87.32 9.45,87.46 9.53,87.53 10.48,87.53 10.94,88 12.71,88 14.3,89.59 14.46,89.59 14.73,89.32 DT8.1 DT8.10 16.57,89.32 16.77,89.52 16.88,89.52 17.06,89.34 17.06,88.56 17.5,88.12 19.95,88.12 v2(20.17,87.9)
USBC0_ATX_C_DRX_P2: length 115.5
  TOP w0.117: v2(17.81,91.81) 17.72,91.71 17.25,91.71 16.85,91.32 DT7.10 DT7.1 14.28,91.32 14.16,91.43 14.16,92.33 13.29,93.19 13.27,93.21 13.04,93.45 10.13,93.45 8.88,92.19 8.19,92.19 v2(8.09,92.29)
  IN3 w0.127: v2(105.8,83.34) 105.61,83.53 105.61,84.51 102.42,87.7 98.77,87.7 93.8,82.73 79.85,82.73 78.53,84.05 75.81,84.05 68.79,91.08 59.41,91.08 56.62,93.87 48.58,93.87 46.34,91.63 28.44,91.63 26.94,90.12 24.13,90.12 24.09,90.13 20.43,91.66 17.96,91.66 v2(17.81,91.81)
  BOTTOM w0.117: C252.2 105.58,80 105.58,83.12 v2(105.8,83.34) ; JUSBC2.B2 7.81,92 v2(8.09,92.29)
USBC0_ATX_DRX_N1: length 6.4
  BOTTOM w0.102: C251.1 103.29,79.11 103.29,77.81 103.4,77.7 103.74,77.7 103.89,77.7 104.26,77.7 104.46,77.7 105.46,76.7 105.46,75.62 105.67,75.42 105.67,75.18 105.45,74.96 105.45,74.58 UC1.AA3
USBC0_ATX_DRX_N2: length 5.9
  BOTTOM w0.089: UC1.AC4 106.67,74.3 106.67,74.63 106.54,74.76 106.54,75.04 106.72,75.21 106.72,77.2 v4(106.02,77.9) 105.31,78.61 105.31,79.05 C253.1
USBC0_ATX_DRX_P1: length 6.4
  BOTTOM w0.102: UC1.AA1 105.37,75.44 105.27,75.54 105.27,76.19 105.21,76.26 105.21,76.4 105.27,76.46 105.27,76.62 105.11,76.78 104.98,76.78 104.84,76.92 104.84,77.05 104.75,77.15 104.6,77.15 104.48,77.27 104.48,77.41 104.38,77.51 104.26,77.51 104.18,77.42 103.97,77.42 103.89,77.51 103.79,77.51 103.7,77.41 103.59,77.41 103.5,77.51 103.33,77.51 103.1,77.73 v4(103.1,78.2) 103.1,78.77 103.03,78.85 103.03,79.23 102.92,79.33 102.82,79.33 102.67,79.18 C250.1
USBC0_ATX_DRX_P2: length 5.9
  BOTTOM w0.089: C252.1 105.49,78.82 105.49,78.68 105.89,78.28 105.91,78.28 106.32,77.86 106.32,77.85 106.9,77.27 106.9,75.34 107.17,75.07 107.17,74.73 107.06,74.62 106.95,74.62 106.88,74.7 UC1.AC2
USBC0_AUXN: length 85.1
  TOP w0.117: CT36.1 31.66,86.33 30.64,86.33 30.17,86.79 30.17,87.23 30.29,87.34 v2(30.41,87.34)
  IN3 w0.102: v2(96.92,62.44) 96.28,63.07 93.58,63.07 92.99,63.66 91.23,63.66 89.35,65.54 88.87,65.54 87.91,66.49 87.91,66.51 87.9,66.52
  IN3 w0.127: 87.9,66.52 84.81,69.61 84.81,70.38 80.83,74.36 73.61,74.36 71.03,76.94 68.27,76.94 61.48,83.73 47.9,83.73 45.89,81.71 43.63,81.71 42.55,82.79 41.29,82.79 40.27,81.78 36.9,81.78 36.2,82.48 32.39,82.48 30.18,84.69 30.18,86.83 30.11,86.89 30.11,87.05 v2(30.41,87.34)
  BOTTOM w0.102: v2(96.92,62.44) 96.94,62.44 UC1.M19
USBC0_AUXP: length 85.2
  TOP w0.117: v2(29.76,87.33) 29.95,87.14 29.95,86.7 30.54,86.1 31.66,86.1 CT35.1
  IN3 w0.102: v2(96.12,62.44) 96.3,62.62 96.3,62.77 96.2,62.87 93.49,62.87 92.91,63.45 91.14,63.45 89.26,65.33 88.78,65.33 87.77,66.35 87.75,66.35 87.74,66.36
  IN3 w0.127: 87.74,66.36 84.58,69.52 84.58,70.29 80.73,74.14 73.52,74.14 70.94,76.72 68.18,76.72 61.39,83.51 48,83.51 45.98,81.49 43.54,81.49 42.46,82.57 41.38,82.57 40.36,81.55 36.81,81.55 36.11,82.25 32.3,82.25 29.95,84.6 29.95,86.73 29.89,86.8 29.89,87.2 v2(29.76,87.33)
  BOTTOM w0.102: v2(96.12,62.44) 96.14,62.44 UC1.L19
USBC0_C_AUXN: length 4.8
  TOP w0.117: UT1.13 35.8,85.47 35.72,85.39 35.5,85.39 34.59,86.3 33.71,86.3 RT26.1 33.23,86.44 33.11,86.32 32.66,86.32 CT36.2
USBC0_C_AUXP: length 4.8
  TOP w0.117: CT35.2 32.65,86.1 33.05,86.1 33.23,85.92 RT25.1 33.71,86.07 34.5,86.07 35.41,85.16 35.66,85.16 35.75,85.07 UT1.14
USBC0_CC1: length 11
  TOP w0.254: 30.82,84.25 30.42,84.66 UT2.12 ; UT1.10 36.79,87.27 36.55,87.51 v2(36.55,87.75)
  TOP w0.508: v2(34.56,82.91) 34.56,83.18 33.77,83.97 v3(33.66,83.97) 32.17,83.97
  BOTTOM w0.508: v2(36.55,87.75) 36.22,87.43 36.22,83.86 35.27,82.91 v2(34.56,82.91)
USBC0_CC1_CONN: length 43.6
  TOP w0.254: UT2.4 26.4,84.66 v2(26.19,84.45) ; v2(27.5,82.53) 28.08,83.11 UT2.7
  IN1 w0.508: v2(26.19,84.45) 27.09,85.35 27.09,86.85 29.79,89.55 31.92,89.55 v2(32.3,89.17)
  IN2 w0.508: v2(22.14,86.7) 22.01,86.82 22.01,86.9 21.63,87.28 21.12,87.28 20.74,86.9 20.74,85.6 19.9,84.77 17.95,84.77 16.53,86.19 11.45,86.19 9.68,87.96 v2(9.68,88.91)
  IN3 w0.508: v2(27.5,82.53) 27.5,83.39 27.47,83.42 27.47,83.44 26.59,84.32 26.57,84.32 26.44,84.45 v2(26.19,84.45)
  BOTTOM w0.254: v2(9.68,88.91) 9.52,88.75 JUSBC2.A5
  BOTTOM w0.508: v2(32.3,89.17) 32.11,89.36 DT16.6 30.52,89.36 v3(29.88,88.72) 29.36,88.19 22.79,88.19 22.13,87.53 22.13,86.71 v2(22.14,86.7)
USBC0_CC2: length 8.6
  TOP w0.254: UT1.12 35.66,85.87 v2(35.08,86.45) ; 30.81,83.63 30.19,84.26 UT2.11
  TOP w0.508: v2(33.78,82.99) 32.59,82.99 v3(32.49,83.09)
  BOTTOM w0.508: v2(35.08,86.45) 35.59,85.95 35.59,84.12 35.01,83.54 34.29,83.54 33.78,83.03 v2(33.78,82.99)
USBC0_CC2_CONN: length 52.2
  TOP w0.254: UT2.5 26.84,84.26 v2(26.27,83.69) ; UT2.6 27.37,83.25
  TOP w0.508: 27.37,83.25 27.26,83.14 27.25,83.14 26.98,82.87 v2(26.84,82.87)
  IN1 w0.508: v2(26.27,83.69) 26.01,83.69 25.51,84.19 25.51,84.92 26.39,85.81 26.39,87.1 29.51,90.21 32.49,90.21 32.93,89.77 v2(32.93,89.17)
  IN2 w0.457: 8.83,90.08 8.37,90.54 v2(8.1,90.54)
  IN2 w0.508: 8.83,90.08 8.83,87.84 11.12,85.55 16.25,85.55 17.69,84.1 20.26,84.1 21.38,85.22 v2(21.38,86.63)
  IN3 w0.508: v2(26.84,82.87) 26.84,83.18 26.33,83.69 v2(26.27,83.69)
  BOTTOM w0.254: v2(8.1,90.54) 8.07,90.51 JUSBC2.B5
  BOTTOM w0.508: v2(32.93,89.17) 33.12,89.36 DT16.1 33.87,89.95 33.61,90.21 v3(30.24,90.21) 29.84,90.21 28.5,88.87 22.48,88.87 21.38,87.76 v2(21.38,86.63)
USBC0_CHG_EN: length 59.6
  TOP w0.117: v2(37.47,89.25) 37.47,88.79 RT63.1 38.17,88.09 38.25,88.09 38.49,87.85 38.49,87.45 38.39,87.35 UT1.6 ; PQS2.2 25.88,50.98 26.81,51.91 26.81,52.99 28.1,54.27 v2(28.1,54.72)
  IN1 w0.102: v2(37.47,89.25) 38.07,89.25 38.5,88.82 38.93,88.82 39.5,88.25 41.98,88.25 42.59,87.64 42.59,80.22 39.11,76.74 37.93,76.74 34.97,73.77 34.97,72.55 v2(35.04,72.47)
  IN2 w0.127: v2(35.04,72.47) 37.85,69.66 37.85,58.37 36.69,57.21 32.3,57.21 29.43,54.34 28.48,54.34 v2(28.1,54.72)
USBC0_PD_HPD: length 31.5
  TOP w0.117: v2(40.9,87.83) 40.57,87.49 40.26,87.49 39.99,87.22 UT1.2 ; v1(62.02,83.77) 62.02,85.3 62.47,85.76 RT29.1 ; RT29.1 63,86.16 v2(63,86.57) 63.66,86.57 RC628.1 ; RT29.1 62.34,86.01 62.34,86.82 62.02,87.14 62.02,87.78 62.27,88.03 QC2.2
  IN3 w0.117: v2(40.9,87.83) 43.44,87.83 43.68,88.06 49.02,88.06 49.6,87.48 62.08,87.48 v2(63,86.57)
USBC0_PD_HPD_3VEN: length 6.9
  TOP w0.117: v1(68.05,84.79) 66.96,85.88 RC62.2 66.27,86.7 64.94,88.03 QC2.5 64.05,88.03 63.92,88.16 63.92,88.56 64.04,88.68 QC2.6
USBC0_PD_HPD_R: length 65.4
  TOP w0.117: QC2.3 63.37,87.38 63.8,86.95 64.19,86.95 RC628.2 64.7,85.7 RC63.2 64.61,85.59 64.16,85.14 64.16,84.68 v1(60.82,81.35) 58.48,79.01 58.48,78.38 58.31,78.21 58.31,78.19 v2(58.14,78.02)
  IN1 w0.102: v2(73.27,61.57) 74.08,61.57 76.62,64.11 81.86,64.11 82.16,63.81 85.8,63.81 87.99,61.62 91.62,61.62 92.14,61.09 93.97,61.09 94.17,60.89 96.71,60.89 96.97,60.64 v2(96.97,60.61)
  IN3 w0.127: v2(58.14,78.02) 58.14,76.67 58.21,76.6 58.21,73.65 60.2,71.66 61.94,71.66 63.41,70.19 63.41,68.94 65.05,67.3 66.93,67.3 72.66,61.57 v2(73.27,61.57)
  BOTTOM w0.089: UC1.M20 97.36,61 v2(96.97,60.61)
USBC0_PWR_SW_EN: length 52.6
  TOP w0.117: v2(22.3,70.93) 21.81,70.44 RT60.1 ; RT60.1 21.8,70.07 RT86.1 ; RT60.1 22.27,70.06 22.66,70.44 v3(22.77,70.44) 23.03,70.44 23.49,69.98 UT4.12 ; UT6.2 28.43,73.61 28.68,73.36 28.7,73.36 v2(28.74,73.32) ; v2(41.88,84.54) 41.73,84.54 41.46,84.27 UT1.35
  IN1 w0.102: v2(41.88,84.54) 41.88,84.66 41.13,85.41 41.13,86.04 38.58,88.59 35.01,88.59 33.77,87.35 33.77,84.01 30.98,81.22 27.94,81.22 27.17,82 23.47,82 20.74,79.27 20.74,72.22 21.21,71.75 21.59,71.75 22.3,71.04 v2(22.3,70.93)
  IN2 w0.127: v2(28.74,73.32) 28.51,73.55 27.79,73.55 25.17,70.93 v2(22.3,70.93)
USBC0_SBU1: length 7.7
  TOP w0.117: UT1.16 34.65,84.27 v2(34.3,84.62) ; v2(32.73,84.92) 32.21,85.44 31.57,85.44 31.15,85.86 UT2.15
  IN3 w0.127: v2(32.73,84.92) 32.73,85.31 32.87,85.45 33.86,85.45 34.3,85.01 v2(34.3,84.62)
USBC0_SBU1_CONN: length 41.3
  TOP w0.117: v2(32.3,87.33) 32.46,87.49 32.46,87.69 31.61,88.54 v4(31.35,88.54) 30.08,88.54 30.07,88.52 29.47,88.52 29.45,88.54 28.58,88.54 26.35,86.31 26.35,85.89 26.47,85.77 26.65,85.77 26.74,85.86 UT2.1
  IN3 w0.127: v2(10.3,90.78) 10.72,90.37 10.72,89.65 10.18,89.1 10.18,88.77 10.33,88.61 12.24,88.61 12.58,88.27 13.43,88.27 17.21,84.49 22.88,84.49 23.3,84.9 24.49,84.9 v2(24.71,85.12)
  BOTTOM w0.117: v2(32.3,87.33) 32.08,87.55 31.45,87.55 DT16.4 31.37,87.15 31.61,86.9 32.44,86.9 32.55,86.78 32.55,86.61 32.42,86.48 26.94,86.48 26.37,85.91 26.37,85.65 25.6,84.88 24.95,84.88 v2(24.71,85.12) ; JUSBC2.A8 8.83,90.26 9.13,90.26 9.32,90.44 9.49,90.44 9.83,90.78 v2(10.3,90.78)
USBC0_SBU2: length 7.7
  TOP w0.117: v2(32.13,84.9) 32,85.04 31.46,85.04 31.05,85.46 UT2.14 ; v2(34.83,84.89) 35.05,84.67 UT1.15
  IN3 w0.127: v2(34.83,84.89) 34.83,85.1 34.04,85.88 32.69,85.88 32.3,85.49 32.3,85.07 v2(32.13,84.9)
USBC0_SBU2_CONN: length 41.4
  TOP w0.117: UT2.2 26.62,85.46 26.53,85.55 26.38,85.55 26.13,85.79 26.13,86.4 28.49,88.76 v4(29.77,88.76) 31.03,88.76 31.05,88.77 31.65,88.77 31.66,88.76 31.71,88.76 32.68,87.79 32.68,87.65 v2(32.87,87.46)
  IN3 w0.127: v2(24.71,84.46) 24.49,84.68 23.39,84.68 22.97,84.26 17.12,84.26 13.33,88.04 12.48,88.04 12.14,88.38 9.15,88.38 8.75,88.78 v2(8.1,88.78)
  BOTTOM w0.117: v2(24.71,84.46) 24.9,84.66 25.69,84.66 26.59,85.56 26.59,85.81 27.03,86.25 32.52,86.25 32.78,86.51 32.78,86.79 32.89,86.91 33.59,86.91 33.87,87.18 DT16.3 v2(32.87,87.46) ; JUSBC2.B8 7.88,89 v2(8.1,88.78)
USBC_I2C_SCL: length 94.8
  TOP w0.117: v2(85.54,71.15) 85.54,71.56 85.5,71.6 RC608.2 85.49,72.22 RC618.2 ; UT1.38 41.25,85.47 41.34,85.56 41.42,85.56 41.5,85.64 41.59,85.64 41.94,86 v2(42.02,86)
  IN3 w0.102: v2(113.87,70.8) 113.65,71.03 113.5,71.03 113.4,70.93 113.4,70.65 113.07,70.33 112.74,70.33 112.72,70.31 112.64,70.31 112.49,70.16 112.49,68.13 112.11,67.75 106.7,67.75 106.42,67.47 97.65,67.47 97.07,66.88 92.35,66.88 91.54,66.07 90.5,66.07 89.87,66.71 89.16,66.71 87.86,68.01 87.75,68.01 87.74,68.03
  IN3 w0.127: 87.74,68.03 85.72,70.04 85.72,70.97 v2(85.54,71.15) 85.67,71.28 85.67,71.99 82.46,75.2 74.67,75.2 72.09,77.78 68.62,77.78 61.83,84.57 48.55,84.57 46.68,86.44 43.81,86.44 43.32,85.96 43.32,84.69 42.28,83.65 41.3,83.65 40.83,84.11 40.83,85.54 41.17,85.88 41.51,85.88 41.63,85.99 v2(42.02,86)
  BOTTOM w0.102: v2(113.87,70.8) 113.48,70.4 UC1.AL9
USBC_I2C_SDA: length 93.7
  TOP w0.117: v2(42.02,85.41) 42.02,85.41 41.96,85.36 41.8,85.36 41.73,85.3 41.56,85.3 41.34,85.07 UT1.37 ; RC619.2 86.25,72.22 RC609.2 86.24,71.65 86.15,71.56 v2(86.15,71.15)
  IN3 w0.102: v2(113.87,71.6) 113.51,71.23 113.42,71.23 113.2,71.01 113.2,70.74 112.98,70.52 112.56,70.52 112.28,70.24 112.28,68.21 112.02,67.95 106.61,67.95 106.33,67.67 97.57,67.67 96.98,67.08 92.26,67.08 91.45,66.27 90.59,66.27 89.95,66.91 89.25,66.91 88,68.15 88,68.26 87.99,68.28
  IN3 w0.127: 87.99,68.28 86.07,70.19 86.07,71.07 v2(86.15,71.15) 86.02,71.28 86.02,72.14 82.6,75.56 74.82,75.56 72.24,78.14 68.77,78.14 61.98,84.93 48.7,84.93 46.82,86.8 43.66,86.8 42.97,86.11 42.97,84.84 42.13,84 41.44,84 41.19,84.26 41.19,85.39 41.32,85.52 41.52,85.52 41.63,85.41 v2(42.02,85.41)
  BOTTOM w0.102: v2(113.87,71.6) 113.48,71.2 UC1.AL8
VBCAP: length 4.8
  TOP w0.254: 35.32,83.37 35.46,83.5 35.46,83.59 35.72,83.85 35.81,83.85 35.83,83.87 UT1.17
  TOP w0.508: 35.32,83.37 35.32,82.61 34.82,82.1 RT27.1 32.63,82.1 RT28.1
VCIN0_PH1: length 120.8
  TOP w0.102: v2(123.71,55.91) 123.71,55.58 123.49,55.35 v3(123.1,55.35) PH1.1 122.07,55.35 PR13.2
  TOP w0.117: v2(184.38,43.26) 184.8,43.68 UEC1.109
  IN1 w0.102: v2(123.71,55.91) 125.23,57.43 125.23,60.93 126.01,61.7 128.71,61.7 128.93,61.49 132.23,61.49 132.46,61.71 134.01,61.71 134.26,61.46 134.76,61.46 134.92,61.3 137.25,61.3 145.08,53.47 145.08,49.41 142.43,46.77 142.43,41.81 144.25,40 144.25,28.64 146.83,26.07 146.85,26.07 148.66,24.26 150.21,24.26 150.51,24.57 v2(150.84,24.57)
  IN3 w0.127: v2(184.38,43.26) 184.38,35.44 183.4,34.47 183.4,33.51 183.23,33.33 183.23,32.43 183.52,32.14 183.52,31.57 181.29,29.34 179.47,29.34 178.83,28.71 178.83,28.1 178.18,27.45 176.91,27.45 176.65,27.72 175.35,27.72 174.83,27.2 173.42,27.2 171.4,25.18 169.49,25.18 167.1,22.79 162.36,22.79 161.09,21.52 156.7,21.52 153.65,24.57 v2(150.84,24.57)
VCIN1_AC_IN: length 183.3
  TOP w0.117: UEC1.110 184.4,43.98 v2(184.38,43.96) ; v2(183.52,50.01) 183.52,49.78 183.73,49.56 184.09,49.56 C255.1 R59.1
  TOP w0.254: PRB16.2 51.51,9.67 51.06,9.21 PRB17.1 51.24,8.43 51.53,8.13 v2(51.73,8.13)
  IN2 w0.127: v2(80.41,6.91) 79.77,6.28 78.22,6.28 75.48,3.54 69.9,3.54 68.88,4.56 56.15,4.56 54.45,6.27 53.62,6.27 52.67,7.22 52.67,7.7 52.24,8.13 v2(51.73,8.13) ; v2(173.96,18.62) 174.23,18.9 174.23,26.28 v2(173.78,26.73)
  IN3 w0.127: v2(80.41,6.91) 82.67,4.65 88.65,4.65 92.73,8.73 97.02,8.73 98.5,7.26 100.32,7.26 101.77,5.81 111.6,5.81 111.65,5.76 132.39,5.76 134.82,8.2 142.85,8.2 149.72,15.06 168.75,15.06 172.3,18.62 v2(173.96,18.62)
  BOTTOM w0.117: v2(173.78,26.73) 173.78,27.04 174.54,27.8 174.54,28.72 176.1,30.28 178.55,30.28 180.05,31.77 180.05,34.42 183.76,38.13 183.76,42.05 182.73,43.08 182.73,44.29 182.85,44.4 183.53,44.4 183.98,43.96 v2(184.38,43.96) 184.54,44.12 184.54,49.83 184.26,50.12 183.62,50.12 v2(183.52,50.01)
  BOTTOM w0.203: PUB1.4 51.05,7.58 51.6,8.13 v2(51.73,8.13)
VCIN1_BATT_TEMP: length 134.2
  TOP w0.117: UEC1.63 v3(189.2,27.85) 189.2,27.45 189.08,27.33 C257.1 188.6,26.89 188.48,26.76 v2(188.04,26.76)
  IN2 w0.127: v2(188.04,26.76) 187.57,26.29 186.33,26.29 181.04,21.01 181.04,20.78 178.39,18.13 173.54,18.13 170.5,21.16 163.3,21.16 162.86,20.72 155.76,20.72 153.81,18.78 151.5,18.78 148,15.27 148,13.54 145.05,10.6 141.08,10.6 140.24,9.76 138.47,9.76 137.41,8.7 136.44,8.7 135.37,7.64 135.17,7.64 133.23,7.64 131.87,6.28 115.49,6.28 114.21,7.55 114.21,8.03 113.82,8.43 112.88,8.43 112.74,8.28 111.26,8.28 111.25,8.28 110.7,8.28 110.63,8.21 108.37,8.21 107.43,7.27 101.31,7.27 100.65,7.93 98.29,7.93 97.12,9.1 92.72,9.1 90.11,6.48 89.2,6.48 88.08,7.6 v2(88.08,8.06)
  IN3 w0.127: v2(83.56,16.16) 84.29,15.42 84.29,14.74 83.4,13.85 83.4,13.7 83.38,13.67 83.38,10.52 83.23,10.37 83.23,9.1 83.61,8.72 87.42,8.72 v2(88.08,8.06)
  BOTTOM w0.117: v2(83.56,16.16) 83.84,16.44 PR15.2
VCOUT0_MAIN_PWR_ON: length 44.8
  TOP w0.117: PR510.1 174.21,73.83 v2(174.21,74.07) ; UEC1.104 186.8,43.96 v2(186.8,43.96)
  BOTTOM w0.117: v2(174.21,74.07) v3(174.96,74.83) 175.53,75.39 181.2,75.39 181.4,75.39 183.19,73.6 183.19,70.96 184.22,69.93 184.26,69.71 184.37,69.45 184.37,65.57 186.5,63.44 186.5,53.14 185.83,52.47 185.83,50.95 185.62,50.73 185.62,47.56 185.03,46.97 185.03,45.73 v2(186.8,43.96)
VCOUT1_PROCHOT#: length 176.5
  TOP w0.102: R4002.1 187.05,47.2 187.2,47.05 187.2,46.78 v2(187.18,46.75) 187.2,46.73 UEC1.103
  IN2 w0.102: v2(183.66,32.64) 183.66,30.74 181.93,29.01 181.93,25.63 179.95,23.65 179.95,20.78 178.36,19.2 175.31,19.2 v2(174.73,18.62)
  IN3 w0.102: v2(174.73,18.62) 174.25,19.09 172.01,19.09 168.22,15.31 149.61,15.31 142.75,8.45 134.72,8.45 132.27,6 111.75,6 111.7,6.05 101.87,6.05 100.34,7.57 98.76,7.57 97.25,9.09 92.59,9.09 88.48,4.98 83.15,4.98 v2(81.07,7.07) ; v2(183.66,32.64) 183.66,33.15 183.84,33.33 183.84,33.48 184.9,34.55 184.9,44.3 187.18,46.58 v2(187.18,46.75)
  BOTTOM w0.117: PRB13.1 51.57,2.47 51.57,2.45 PR871.1 51.65,1.96 51.77,1.85 66.65,1.85 v3(66.72,1.92) 77.5,1.92 77.82,2.23 77.82,5.87 79.37,7.42 80.71,7.42 v2(81.07,7.07)
VLIM_1113: length 2.6
  TOP w0.117: v3(27.47,79.77) 28.12,79.13 RT92.1 28.55,78.63 28.43,78.5 UT6.12
VMON: length 5.7
  TOP w0.117: RT40.2 37.95,77.9 37.95,79.55 RT41.1 38.43,80.4 39.03,80.99 v3(39.08,80.99) 39.68,80.99 39.99,81.3 UT1.29
VR_ALERT#: length 74.6
  TOP w0.117: v2(58.72,78.04) 58.72,78.91 60.78,80.96 60.98,80.96 61.51,81.49 61.51,81.69 64.57,84.75 v2(64.57,84.97) ; UT1.39 41.33,85.87 41.6,86.14 41.6,86.2 41.95,86.55 v2(41.95,86.82)
  IN3 w0.127: v2(41.95,86.82) 42.79,86.82 43.78,87.81 48.89,87.81 49.22,87.48 49.25,87.48 49.5,87.23 61.7,87.23 63.97,84.97 v2(64.57,84.97) ; v2(58.72,78.04) 58.72,76.85 58.51,76.63 58.51,73.78 60.13,72.17 61.81,72.17 63.67,70.31 63.67,69.12 65.14,67.65 66.95,67.65 72.58,62.02 74.11,62.02 78.82,57.31 79.65,57.31 81.64,55.31 82.26,55.31 82.64,54.93 v2(82.64,54.83)
  BOTTOM w0.117: RC602.2 83.32,53.23 83.15,53.4 83.15,54.08 82.64,54.59 v2(82.64,54.83)
VR_ON: length 170.7
  TOP w0.102: UEC1.121 180,44.18 180.25,43.92 180.76,43.92 v2(180.9,44.07) ; v1(93.13,100.22) 92.76,99.85 v2(92.76,99.6)
  TOP w0.254: PC831.1 92.75,97.79 93.25,98.29 93.25,99.12 v2(92.76,99.6)
  IN1 w0.381: v2(167.94,92.54) 168.47,92 168.82,92 175.81,85.02 175.81,81.62 180.08,77.35 180.08,75.27 176.83,72.01 171.01,72.01 167.91,68.92 166.54,68.92 166.08,68.46 166.08,64.33 167.19,63.23 167.19,62.84 168.39,61.65 168.39,60.92 174.03,55.28 174.03,54.12 177.22,50.93 177.59,50.93 178.45,50.07 178.45,48.01 178.73,47.73 178.73,46.52 180.9,44.35 v2(180.9,44.07)
  IN2 w0.254: v2(92.76,99.6) 93.25,99.12 93.25,98.14 92.33,97.22 92.33,95.06 94.15,93.25 94.68,93.25 94.98,93.55 99,93.55 99.86,92.68 99.86,92.49 102.68,89.67 102.68,88.32 104.31,86.7 111.4,86.7 112.35,87.65 117.58,87.65 118.29,86.94 138.54,86.94 140.63,84.85 156.87,84.85 159.27,87.26 159.63,87.26 164.87,92.5 167.9,92.5 v2(167.94,92.54)
  BOTTOM w0.254: PR829.1 v2(92.76,99.6) 93.1,99.6 94.12,98.59 PU801.37
  BOTTOM w0.381: v2(167.94,92.54) 167.86,92.61 166.77,92.61 PR623.2
VREF_CPU: length 40.2
  TOP w0.178: PR858.2 99.29,91.47 PC852.1 98.39,91.44 PR823.1 ; PR858.2 99.32,91.48 PR825.1 100.12,91.19 100.37,90.94 101.62,90.94 102.1,91.42 102.1,91.8 104.46,94.16 109.44,94.16 110,93.6 110.81,93.6 110.84,93.63 110.89,93.63 v2(111.03,93.77) ; PR858.2 99.3,92.08 v2(99.43,92.21)
  IN2 w0.254: v2(99.43,92.21) 97.74,90.52 95.22,90.52 94.66,89.96 v2(94.66,89.95)
  BOTTOM w0.254: v2(94.66,89.95) 94.63,89.92 94.63,89.77 94.01,89.15 91.67,89.15 89.82,91 89.82,92.66 v3(88.49,93.99) 88.29,94.18 85.57,94.18 PH802.2 ; v2(111.03,93.77) 111.27,94.01 PH801.2 ; PR859.2 97.46,91.6 PC827.1 PC828.1 99.27,92.05 v2(99.43,92.21) 99.43,92.97 99.19,93.21 99.19,93.5 99.17,93.53 PU801.16
VSYS: length 46.2
  IN3 w0.254: v2(44.74,7.58) 44.74,5.01 46.35,3.41 49.69,3.41 50.92,2.18 54.31,2.18 54.86,2.74 73.35,2.74 74.6,3.99 74.6,5.09 73.22,6.47 73.22,9.12 v2(72.52,9.82)
  BOTTOM w0.203: v2(44.74,7.58) 45.14,7.98 PUB1.22
  BOTTOM w0.254: v2(72.52,9.82) 72.14,10.2 v3(72.14,11.45) PRB32.1
VTTREF_DDR: length 2
  BOTTOM w0.254: PCM17.1 161.46,57.29 161.71,57.03 161.71,57.03 161.73,57.01 PUM1.4
WL_AUX_RST#: length 5.1
  TOP w0.117: v3(173.15,31.24) 173.07,31.16 R4020.1 172.22,31.62 172.85,32.26 UWL22.1 173.85,32.26 174.02,32.43 UEC1.29
WL_RST#: length 6.3
  TOP w0.102: RWL9.1 170.79,33.95 170.92,33.82 170.98,33.82 171.24,33.56 UWL22.4 172.22,33.56 172.32,33.66 172.32,33.85 172.22,33.95 171.78,33.95 171.54,34.19 RWL17.1 RWL18.1 171.54,35.66 171.44,35.77 v3(170.67,35.77)
WL_RST#_R: length 6.3
  TOP w0.117: RWL9.2 168.79,33.75 169.13,33.41 170.65,33.41 v2(170.68,33.38)
  BOTTOM w0.117: v2(170.68,33.38) 171.1,33.8 171.91,33.8 JWLAN1.44 173.04,33.8 v3(174.13,32.71)
N15548662: length 4.1
  TOP w0.117: v3(92.39,26.15) CD3.2 CD4.2 91.32,25.55 91.02,25.25 91.02,24.88 RD29.1 RD28.1
N16048190: length 3.7
  TOP w0.254: UD2.F9 113.73,21.74 114.28,21.74 v2(114.29,21.72)
  BOTTOM w0.117: v3(114.82,21.2) 114.81,21.2 114.39,21.62
  BOTTOM w0.254: v2(114.29,21.72) 114.39,21.62 115.41,21.62 115.41,21.61 115.88,21.61 116.13,21.87 RD36.2
N16049074: length 3.2
  TOP w0.254: UD1.F9 102.42,21.74 103.02,21.74 103.45,21.32 v2(104.05,21.32)
  BOTTOM w0.117: RD35.2 104.61,21.32 v2(104.05,21.32) v3(103.5,21.32)
N16073528: length 6.2
  TOP w0.117: v3(141.25,25.98) RD41.2
  TOP w0.254: RD41.2 140.38,24.74 140.12,24.49 UD4.F9
N16074384: length 9.1
  TOP w0.254: RD40.2 126.44,30.59 126.29,30.74 v3(125.77,30.74) 125.77,30.16 126.76,29.16 126.76,25.36 126.23,24.82 125.41,24.82 UD3.F9
N17006388: length 4.7
  TOP w0.254: v2(104.03,21.98) 103.65,22.36 UD1.E9
  BOTTOM w0.117: v3(106.21,21.74) 105.6,21.74 RD33.1 105.2,21.57 104.79,21.98 v2(104.03,21.98)
N17008855: length 2.6
  TOP w0.254: v2(114.53,22.62) 114.53,22.43 114.28,22.18 113.73,22.18 UD2.E9
  BOTTOM w0.254: RD34.1 115.01,22.14 v2(114.53,22.62)
N17009545: length 9.7
  TOP w0.117: v3(126.93,32.09) RD38.1
  TOP w0.254: RD38.1 125.52,31.15 125.26,30.89 125.26,29.93 126.37,28.82 126.37,25.89 125.76,25.28 UD3.E9
N17010231: length 4.6
  TOP w0.117: v3(139.72,25.05) 139.79,25.13 RD39.1
  TOP w0.254: RD39.1 137.08,25.98 UD4.E9
N19393161: length 4.2
  BOTTOM w0.117: v3(86.41,16.04) 85.55,16.04 85.14,16.44 PR15.1
  BOTTOM w0.508: JBATT1.5 84.39,14.63 85.11,15.35 PR14.1 PR15.1
N27078948: length 3.7
  TOP w0.117: v3(30.65,49.06) PQS3.3
  TOP w0.508: PQS4.1 31.7,50.95 31.66,50.98 PQS3.3
N27353874: length 5.3
  BOTTOM w0.508: PQD5.1 26.31,62.1 v3(26.58,62.38) 26.74,62.53 26.74,64.98 PQD4.3
N27353888: length 8.4
  IN3 w0.508: v2(34.84,69.17) 33,67.33 30.24,67.33 v2(30,67.57)
  BOTTOM w0.508: v2(30,67.57) PRD2.1 29.87,68.55 PRD1.2 29.87,70.2 PCD5.2
  vias: v1(35.79,68.73)
N27353896: length 4.9
  BOTTOM w0.254: PRD4.1 25.27,59.11 25.57,58.82 26.2,58.82 v3(26.46,58.57) 26.96,59.07 PQD5.5 PQD5.2
N27353908: length 2.8
  BOTTOM w0.117: v3(25.04,61.38) 25.27,61.15 PRD3.1
  BOTTOM w0.254: PQD5.6 26.31,60.01 26.01,60.31 PRD3.1
N27353922: length 5.2
  TOP w0.117: v2(30.71,61.21) v3(30.71,60.71)
  BOTTOM w0.508: PQD5.3 28.18,60.9 PRD5.1 29.14,60.9 29.45,61.21 v2(30.71,61.21) 31.64,61.21 31.84,61.01
N27354104: length 4.7
  BOTTOM w0.508: PRD2.2 29.09,67.73 28.38,67.02 26.6,67.02 25.87,66.29 PQD3.6
N27479461: length 1.4
  BOTTOM w0.117: v3(164.79,49.95) 164.3,50.44 PRM8.2
N27480057: length 1.4
  TOP w0.117: PCM11.1 153.67,37.95 v3(153.27,37.55)
N27490318: length 50.9
  TOP w0.117: v2(42.09,6.33) 38.62,6.33 v3(37.89,7.07)
  TOP w0.203: PRB9.2 74.58,7.64 74.2,8.02 v2(74.15,8.02)
  IN3 w0.254: v2(42.09,6.33) 42.16,6.25 42.92,6.25 43.63,5.54 43.63,3.97 45.9,1.69 73.95,1.69 75,2.74 75,5.23 73.6,6.63 73.6,7.52 73.95,7.87 73.99,7.87 v2(74.15,8.02)
  BOTTOM w0.203: v2(42.09,6.33) 42.1,6.33 42.6,6.83 PCB23.1 42.83,7.51 PCB22.1 43.67,7.08 PRB18.1
N27490324: length 50.1
  TOP w0.117: v3(38.27,5.42) 38.59,5.73 v2(42.09,5.73)
  TOP w0.203: PRB9.3 73.89,7.64 v2(74.15,7.38)
  IN3 w0.254: v2(42.09,5.73) 42.18,5.82 42.77,5.82 43.22,5.37 43.22,3.8 45.73,1.29 74.12,1.29 75.4,2.57 75.4,5.4 74.01,6.8 74.01,7.24 v2(74.15,7.38)
  BOTTOM w0.203: v2(42.09,5.73) 42.27,5.91 PCB23.2 42.83,5.73 43.49,5.07 PCB24.1 PRB19.1
N27490344: length 6.9
  TOP w0.254: PQB4.1 54.69,4.77 54.35,4.43 54.32,4.43 54.04,4.14 54.04,3.39 v2(53.7,3.05) 53.59,3.05 53.17,3.47 53.17,5.05 PCB33.1 53.01,5.3 53.01,6.05 PQB3.2
  BOTTOM w0.117: v2(53.7,3.05) v3(53.7,2.53)
  BOTTOM w0.254: PRB29.2 53.49,3.37 53.49,3.25 v2(53.7,3.05)
N27490379: length 5.2
  BOTTOM w0.117: PRB21.1 v3(42.53,3.52)
  BOTTOM w0.203: PUB1.17 46.13,5.98 45.37,5.23 45.37,4.48 PCB29.1 PRB21.1
N27490385: length 2.1
  BOTTOM w0.117: v3(42.46,1.67) PCB28.1
  BOTTOM w0.203: PRB21.2 43.54,2.13 43.59,2.08 PCB28.1
N27490452: length 3.1
  TOP w0.254: PRB27.2 52.23,7.08 51.77,7.54 v2(51.74,7.54) 51.16,7.54 PRB28.1
  BOTTOM w0.203: PUB1.5 51.09,7.18 51.44,7.54 v2(51.74,7.54)
N27490578: length 2.7
  TOP w0.203: PRB2.1 53.65,8.3 54.25,7.69 55.15,7.69 55.35,7.49 PRB1.2
N27490582: length 3.6
  TOP w0.203: PRB3.1 54.21,9.24 54.21,8.2 54.39,8.02 55.15,8.02 55.35,8.22 PRB1.3
N27490635: length 1.6
  TOP w0.117: v3(49.55,12.31) 50.16,11.7 PRB8.2
  vias: v2(51.84,11.12)
N27490661: length 3.3
  BOTTOM w0.203: PUB1.16 46.97,5.15 46.73,4.92 46.31,4.92 46.1,4.71 46.1,4.22 46.21,4.12 PCB31.1 PRB26.1
N27490673: length 1.7
  TOP w0.117: v3(51.82,13.04) 51.82,12.76 52.61,11.97 PRB8.1
N27490690: length 1
  BOTTOM w0.203: PRB26.2 45.32,1.68 PCB30.1
N27490706: length 2.1
  BOTTOM w0.117: PRB13.2 49.61,3.99 48.97,4.63 PUB1.11
N27490755: length 2.7
  BOTTOM w0.203: PCB32.1 51.31,3.66 50.89,4.08 50.4,4.08 49.77,4.71 PUB1.9
N27906658: length 2
  BOTTOM w0.117: JHDT1.11 148,45.79 RHDT7.2
N27906903: length 2.5
  BOTTOM w0.117: JHDT1.13 146.73,46.87 RHDT8.2
N27907005: length 2.2
  BOTTOM w0.117: JHDT1.15 145.46,46.72 144.86,46.12 RHDT9.2
N28818999: length 3.5
  BOTTOM w0.117: RC97.2 133.72,75.33 CC33.1 v3(133.72,76.45)
N29844725: length 5
  TOP w0.117: v3(24.91,55.65) 25.33,55.22 PCS1.2
  TOP w0.508: PRS2.1 26.92,55.2 PRS1.2 ; PRS1.2 26.06,55.25 PCS1.2 ; PRS1.2 27.21,55.49 PQS11.4
N29844737: length 4.1
  TOP w0.117: PQS4.2 v3(33.06,49.82)
  TOP w0.406: PRS5.1 33.06,53.63 PQS4.5 PQS4.2
N29844751: length 1
  TOP w0.406: PQS4.6 32.41,53.84 PRS4.1
N29844777: length 11.9
  TOP w0.117: v3(34.24,59.28) 35.34,58.18 v2(36.04,58.18)
  TOP w0.406: PQS12.4 v2(36.04,58.18)
  TOP w0.508: v2(36.21,53.37) 34.98,52.14 34.98,51.2 PRS6.1 34.73,50.95 PQS4.3
  BOTTOM w0.508: v2(36.21,53.37) 36.21,58.01 v2(36.04,58.18)
N29873767: length 2.1
  TOP w0.117: PRS2.2 25.05,53.98 v3(25.01,54.01)
  TOP w0.508: PQS2.1 26.08,53.48 26,53.56 PRS2.2
N31043585: length 3.3
  BOTTOM w0.203: UA1.24 6,38.06 5.79,38.26 5.79,39.64 5.34,40.1 CA11.1
N31043589: length 4.8
  BOTTOM w0.203: UA1.23 5.77,37.66 5.39,38.04 5.39,39.07 5.06,39.4 v3(5.06,39.53) 4.92,39.66 4.92,41.24 5.12,41.45 CA11.2
N31043653: length 2.2
  BOTTOM w0.203: CA10.2 6.07,39.92 6.24,39.76 6.24,39.3 6.63,38.91 UA1.25
N31044849: length 4.5
  BOTTOM w0.203: 13.21,39.29 12.96,39.03 12.96,38.63 13.24,38.35 13.24,37.81 12.68,37.26 UA1.39
  BOTTOM w0.305: CA8.2 13.77,39.85 13.46,39.54 v1(13.46,39.49) 13.42,39.49 13.21,39.29
N31046441: length 3.7
  BOTTOM w0.203: UA1.38 12.65,37.66 12.9,37.91 12.9,37.91 12.92,37.93 12.92,38.23 12.58,38.58 12.58,39.08
  BOTTOM w0.305: 12.58,39.08 12.58,39.41 12.83,39.67 CA7.2
N31049061: length 2.1
  BOTTOM w0.203: UA1.32 9.82,39.51 10.18,39.87 10.18,40.05
  BOTTOM w0.305: CA9.2 10.52,40.39 10.18,40.05
N31053534: length 2.2
  BOTTOM w0.203: RA9.1 10.22,39.47 UA1.33
N31139311: length 3.8
  BOTTOM w0.117: v3(2.1,30.71) 2.1,30.61 2.28,30.43 4.29,30.43 4.65,30.8 CA1.1 RA4.2
N31622588: length 2.3
  TOP w0.117: R58.2 172.56,39.2 171.85,39.2 171.7,39.35 v3(171.7,39.36) 171.42,39.64 C268.1
N34251283: length 8.1
  BOTTOM w0.381: CA25.1 12.09,41.85 11.94,42 11.94,43.38 12.43,43.86 v3(13.63,43.86) 15.12,43.86 RA27.2 RA29.2 RA30.1
N35328155: length 1.7
  TOP w0.254: U7.15 193.12,23.28 193.2,23.21 193.55,23.21 193.62,23.27 RUS6.1
N35328157: length 4
  TOP w0.117: RUS7.1 193.64,24.36 193.81,24.53 v3(195.53,24.53)
  TOP w0.254: U7.16 193.18,23.78 193.41,24.01 193.59,24.01 RUS7.1
N36734976: length 3.1
  BOTTOM w0.117: v3(182.03,51.48) 181.18,52.33 RTS7.2 180.32,51.76 UTS1.7
N39287841: length 1.2
  TOP w0.117: RUS13.2 200.7,20.66 200.38,20.98 U9.3
N42640404: length 7.7
  TOP w0.117: v2(35.82,78.38) v3(35.82,77.08)
  TOP w0.508: v2(35.82,78.38) 35.09,78.38 34.59,77.87 R4021.1
  IN1 w0.508: v2(35.82,78.38) 35.82,78.08 36.33,77.58 38.99,77.58 39.86,78.44 39.87,78.44 39.87,78.45 v2(39.86,78.45)
N42664977: length 2.4
  TOP w0.117: UT1.30 40.39,81.01 v3(40.36,80.99) 39.45,80.08 RT30.1
N42673166: length 3.4
  TOP w0.117: RT27.2 34.73,80.4 35.22,80.89 v3(35.22,81.07)
  TOP w0.508: RT27.2 33.09,81.17 CT34.1
N42673554: length 1.6
  TOP w0.117: UT1.9 37.19,87.32 37.01,87.5 RT24.1
N42773810: length 5.4
  BOTTOM w0.117: v1(164.87,92.44) 165.63,91.69 PR601.2
  BOTTOM w0.254: PR601.2 165.63,91.48 PC614.1 PR607.1 164.14,90.49 163.11,90.49 PU601.11
N42773848: length 19.9
  TOP w0.254: PR622.1 164.14,88.97 164.14,88.08 v2(164.29,87.92)
  BOTTOM w0.254: 154.18,78.35 155.52,77.01 156.7,77.01 161.61,81.92 161.61,82.61 v3(164.21,85.2) 164.53,85.53 164.53,87.68 v2(164.29,87.92) PR606.2
N42773858: length 2.4
  TOP w0.117: v3(168.1,91.8) 167.67,91.37 PQ601.2
  TOP w0.254: PQ601.2 167.3,90.94 v2(167.14,90.77)
  BOTTOM w0.254: PR623.1 167.14,91.1 v2(167.14,90.77)
N42773860: length 2.6
  TOP w0.117: v3(166.21,89.06) 165.32,89.95 PR622.2
  TOP w0.254: PQ601.1 165.69,90.33 165.5,90.33 PR622.2
N42774290: length 1.9
  BOTTOM w0.117: PC602.1 v1(154.14,95.83)
N42797203: length 3.1
  BOTTOM w0.117: PRM13.1 162.56,60.06 v1(161.95,60.66)
  BOTTOM w0.203: PRM12.1 162.37,59.28 PRM2.2 163.17,60.05 PRM13.1
N42800393: length 202.2
  TOP w0.117: v2(68.84,84.49) 69.98,83.35 69.98,77.96 67.08,75.05 67.08,74.76 67.08,70.88 67.28,70.67 68.95,69 68.95,67.57 70.88,65.64 v3(70.88,62.38) 70.88,61.5 71.72,60.66 71.72,57.43 72.62,56.53 74.4,56.53 74.68,56.81 v2(74.68,57.45)
  IN1 w0.102: v2(54.32,2.88) 54.32,2.8 53.92,2.39 50.23,2.39 47.59,5.03 39.61,5.03 v2(38.04,3.46) ; v2(68.84,84.49) 69.17,84.16 73.52,84.16 73.73,83.95 89.09,83.95 92.78,87.64 92.78,90.38 93.59,91.19 93.59,93.12 94.29,93.82 v2(94.29,94)
  IN3 w0.127: v2(38.04,3.46) 38.12,3.54 38.12,14.03 36.85,15.3 36.1,15.3 32.96,18.43 27.05,18.43 23.23,22.25 23.23,42.12 26.05,44.93 26.05,46.69 26.42,47.07 28.18,47.07 28.67,47.55 36.34,47.55 36.8,47.1 39.09,47.1 40.85,48.86 40.85,53.73 42.94,55.81 53.36,55.81 55.75,58.2 64.39,58.2 66.39,60.2 69.08,60.2 69.41,59.87 69.41,59.69 70.93,58.17 73.96,58.17 v2(74.68,57.45)
  BOTTOM w0.117: v2(54.32,2.88) 54.32,2.31 54.2,2.19 52.74,2.19 PR871.2
  BOTTOM w0.254: v2(94.29,94) 94.26,94.02 94.26,94.46 94.39,94.59 PU801.27
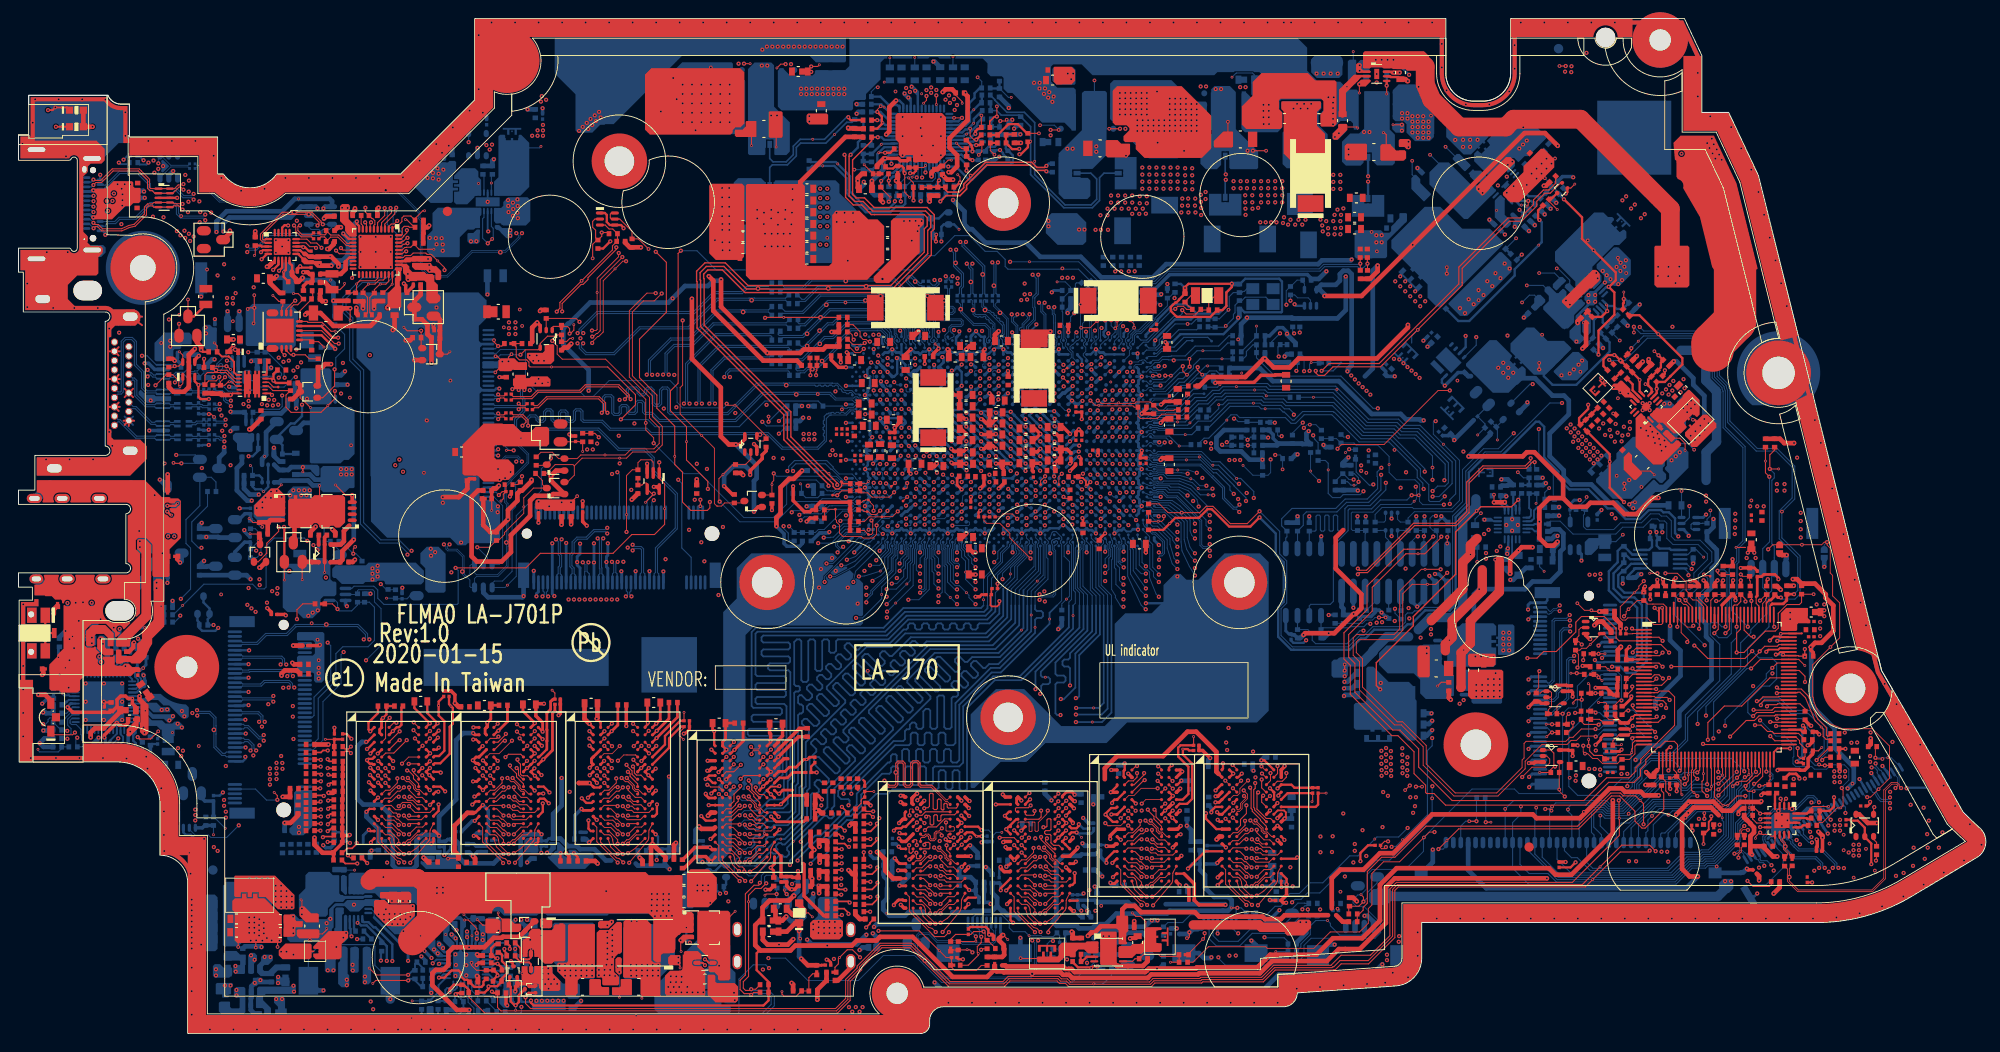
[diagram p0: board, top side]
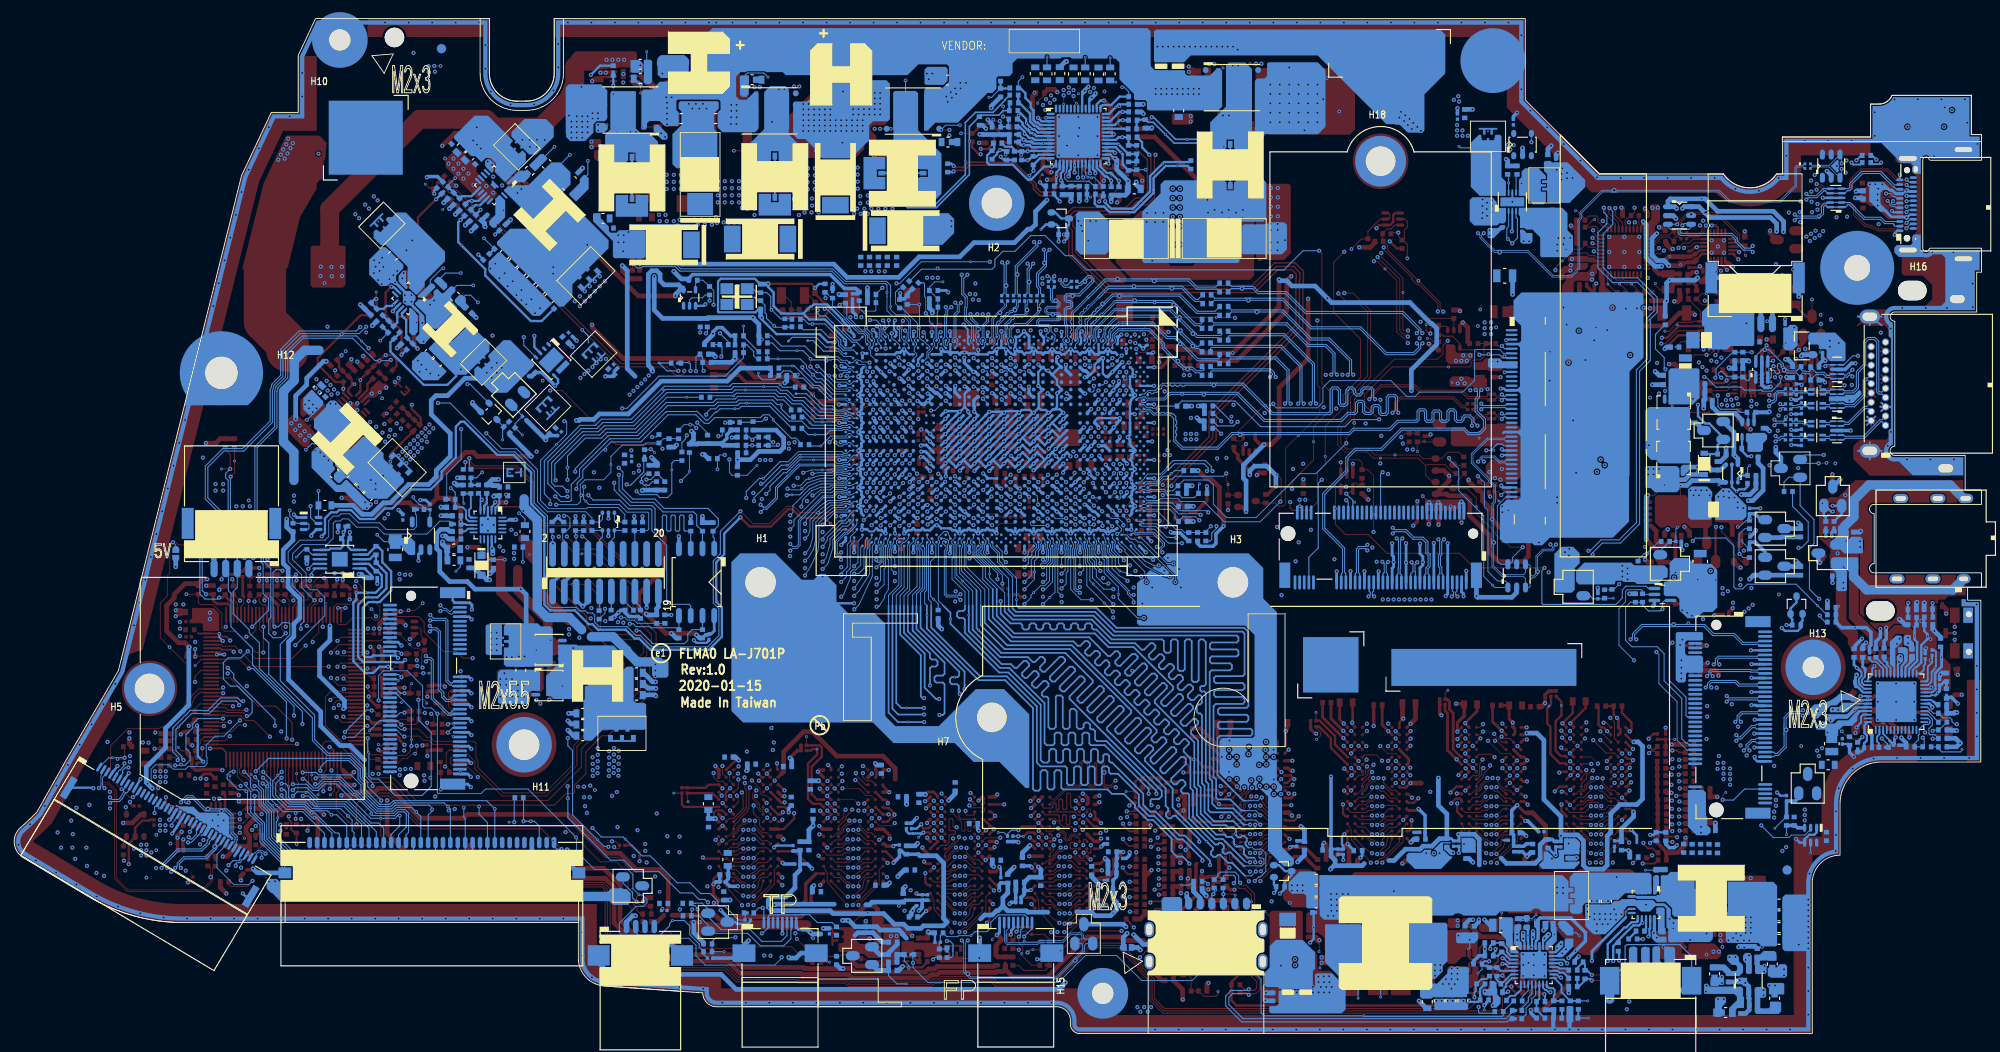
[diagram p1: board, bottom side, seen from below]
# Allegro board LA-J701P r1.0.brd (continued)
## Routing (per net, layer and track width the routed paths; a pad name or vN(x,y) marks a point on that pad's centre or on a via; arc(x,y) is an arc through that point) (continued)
N43014642: length 2.6
  TOP w0.102: CT59.1 25.57,84.77
  TOP w0.117: v3(25.47,84.09) 25.57,84.19 25.57,84.77
  TOP w0.254: UT2.3 26.27,85.06 26.17,85.16 CT59.1
N43474151: length 5.8
  TOP w0.117: QT4.1 46.34,73.42 v3(46.6,73.68)
  TOP w0.508: QT3.2 45.14,77.54 45.52,77.16 45.52,76 CT72.1 45.52,75.93 RT70.2 45.52,74.95 45.51,74.93 QT4.1
N43483631: length 4.3
  TOP w0.117: QT1.1 v1(18.3,79.33)
  TOP w0.254: QT1.1 18.94,77.5 RT69.2
N44399175: length 3.4
  TOP w0.117: v3(33.15,31.79) CD55.2
  TOP w0.254: CD54.2 CD55.2 34.11,31.78 RD45.1 RD44.1
N44399199: length 7.2
  TOP w0.254: 56.45,29.38 UD6.F9
  TOP w0.305: 56.45,29.38 v2(56.69,29.63) 57.67,30.61 57.67,34.6 57.94,34.87 RD49.2
N44399302: length 8.7
  TOP w0.254: RD48.2 46.51,35.6 46.71,35.39 v3(46.71,35.39) 46.9,35.19 46.9,33.48 46.57,33.15 46.57,30.22 45.55,29.2 44.95,29.2 44.85,29.1 UD5.F9
N44399416: length 3.8
  TOP w0.305: UD8.F9 82.2,27.63 83.05,27.63 83.63,28.21 RD51.2
N44399501: length 7.5
  TOP w0.117: v3(71.82,31.79) 71.38,32.22 71.38,32.55 71.89,33.05 RD50.2
  TOP w0.254: RD50.2 71.54,33.17 70.27,31.9 70.27,30.88 UD7.F9
N44399645: length 7.8
  TOP w0.254: UD5.E9 44.94,29.99 45.43,29.99 46,30.56 46,33.75 45.38,34.37 v3(45.38,35.45) 45.38,35.88 RD52.1
N44399648: length 8.3
  TOP w0.117: RD53.1 57.94,36.8 v3(57.64,37.1)
  TOP w0.254: UD6.E9 56.23,29.88 57.06,30.72
  TOP w0.305: 57.06,30.72 57.06,31.6 57.08,31.62 57.08,32.82 57.06,32.84 57.06,34.63 57.47,35.03 57.47,35.87 57.63,36.04 57.67,36.04 57.78,36.14 RD53.1
N44399650: length 6.5
  TOP w0.117: v3(71.89,34.71) RD54.1
  TOP w0.254: RD54.1 71.48,33.8 69.83,32.15 69.83,31.23 UD7.E9
N44399652: length 5.2
  TOP w0.305: RD55.1 85.45,29.86 85.2,29.61 v3(85.13,29.61) 84.81,29.61 83.99,28.78 83.25,28.78 82.79,28.33 82.1,28.33 UD8.E9
N44553852: length 2.9
  BOTTOM w0.117: Q202.6 179.63,56.45 179.63,56.45 R75.2 v1(179.63,58.64)
N44762708: length 1.6
  TOP w0.203: CT71.1 26.83,72.51 26.83,71.39 UT4.6
N44786728: length 1.9
  TOP w0.102: v2(113.45,67.33) 113.39,67.26 T2414.1
  BOTTOM w0.102: UC1.AK12 113.05,67.33 v2(113.45,67.33)
N44865206: length 5.8
  BOTTOM w0.117: CTP4.1 118.06,6.27 117.16,5.37 v3(116.14,5.37)
  BOTTOM w0.508: QTP1.2 119.23,6.83 CTP4.1 RTP6.2
N45286880: length 2.1
  BOTTOM w0.117: v1(172.96,74.9) 172.11,75.74 PC719.2
  BOTTOM w0.254: PC719.2 172.11,75.78 PR716.1
N45361715: length 2.4
  BOTTOM w0.117: PC613.2 160.63,84.81 v1(161.76,85.95)
  BOTTOM w0.254: PR611.1 161.18,84.25 PC613.2
N45414865: length 3
  TOP w0.117: UT6.5 31.47,74.96 CT76.1 32.41,74.77 v3(33,74.19)
N45426925: length 2.1
  TOP w0.117: PR1813.1 PR834.2 v3(91.35,93.89)
N45427212: length 3.5
  BOTTOM w0.117: v3(107.23,101.17) 106.92,101.17 PC9119.1
  BOTTOM w0.254: PR1814.2 PC9119.1 105.01,102.14 PR807.2
N45427762: length 4.6
  TOP w0.117: v3(100.77,94.39) 100.42,94.39 99.8,93.77 PR1815.2
  TOP w0.508: PR1815.2 99.62,93.76 99.28,93.41 PC813.2 98.62,93.06 v2(98.62,92.64)
  BOTTOM w0.254: v2(98.62,92.64) 98.52,92.74 98.52,93.25 98.37,93.4 PU801.18
N45430627: length 6.8
  TOP w0.117: v2(95.72,92.98) 95.72,90.91 v3(96.26,90.38)
  TOP w0.254: PR1819.2 93.84,93.49 94.46,93.49 94.73,93.76 PR1816.2 95.41,93.76 95.61,93.55 95.61,93.12 95.72,93.01 v2(95.72,92.98)
  BOTTOM w0.254: v2(95.72,92.98) 95.72,93.17 95.97,93.42 PU801.24
N45430802: length 4
  TOP w0.117: PR1817.2 97.75,93.59 v3(97.98,93.82)
  TOP w0.254: v2(96.31,92.98) 96.69,92.98 96.94,93.24 PR1817.2 PR1818.2
  BOTTOM w0.254: PU801.23 96.37,93.04 v2(96.31,92.98)
N45669999: length 5.1
  BOTTOM w0.117: v1(92.82,102.27) 92.6,102.27 92.12,101.79 PR819.1
  BOTTOM w0.254: PR819.1 93.1,101.25 94.01,100.35 94.91,100.35 95.17,100.09 PU801.40
N45670005: length 15.4
  TOP w0.178: v2(99.57,89.93) 99.67,90.03 99.69,90.03 99.84,90.18 99.84,90.19 100.2,90.56 101.69,90.56 102.4,91.27 102.4,91.67 104.59,93.86 109.3,93.86 109.88,93.29 110.93,93.29 v2(111.03,93.19)
  BOTTOM w0.254: PR821.1 100.18,90.62 99.57,90.01 v2(99.57,89.93) ; PH801.1 111.12,93.1 v2(111.03,93.19)
N45670038: length 2.9
  BOTTOM w0.254: PR828.1 93.19,100.43 v3(93.5,100.12) 94.24,99.39 PU801.39
N45670148: length 15
  BOTTOM w0.254: PH802.1 85.74,93.77 v3(86.86,93.77) 88.12,93.77 89.44,92.45 89.44,91.16 89.44,90.84 91.51,88.77 94.17,88.77 94.79,89.39 95.49,89.39 95.79,89.68 95.79,90.64 PR822.2
N45670259: length 3.5
  TOP w0.117: v2(101.69,91.99) 101.69,92.58 v3(101.45,92.82)
  TOP w0.254: v2(101.69,91.99) 101.18,91.48 PR825.2
  BOTTOM w0.254: PR821.2 101.07,90.77 PR816.1 101.31,91.6 v2(101.69,91.99)
N45670267: length 4.2
  TOP w0.117: v3(96.13,92.47) 96.66,91.94 PR823.2
  TOP w0.254: PR823.2 96.66,90.05 v2(96.68,90.04)
  BOTTOM w0.254: v2(96.68,90.04) 96.62,90.09 PR822.1 PR818.1
N45890946: length 2.3
  BOTTOM w0.117: RWL19.1 172.54,53.15 v1(173.29,53.91)
N46092148: length 3
  TOP w0.203: v2(115.77,59.6) v3(115.3,59.13) 115.3,59.7 114.95,60.05 114.47,60.05 RC627.1
  BOTTOM w0.3: UC1.AN21 v2(115.77,59.6)
N46346846: length 14.5
  TOP w0.117: v1(21.12,66.63) 20.81,66.95 v2(20.56,66.95)
  TOP w0.254: QH1.3 19.04,70.49 v2(19.43,70.1) 19.43,68.8 19.67,68.57 v2(20.56,68.57)
  IN2 w0.254: v2(20.56,68.57) v2(20.56,66.95) 20.56,65.27 v2(20.55,65.26) v2(20.55,63.61)
  BOTTOM w0.254: v2(20.55,63.61) 19.9,63.61 19.85,63.56 RH4.2 ; RH9.2 RH10.2 20.2,68.45 20.32,68.57 v2(20.56,68.57) ; RH8.2 19.5,66.95 RH7.2 v2(20.56,66.95) ; RH5.2 RH6.2 20.49,65.19 v2(20.55,65.26) ; v2(19.43,70.1) 19.54,70.2 RH11.2
N111027203: length 6.7
  TOP w0.117: v3(145.01,15) 145.28,14.74 v2(145.28,14.25) 144.78,13.76 CKBL3.1 143.69,13.68 RKBL2.2
  BOTTOM w0.117: QKBL1.2 146.75,16.28 145.72,15.24 145.72,14.69 v2(145.28,14.25)
N115820979: length 2
  BOTTOM w0.117: U10.12 v3(51.08,91.92) 51.08,92.75 C75.1
N115820982: length 2
  BOTTOM w0.117: U10.10 50.28,92.75 C76.1

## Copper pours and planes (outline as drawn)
2.5V_VIN on TOP (solid shape): 123.49,11.38 123.49,11.26 123.42,11.18 122.95,11.18 122.9,11.13 122.9,9.81 122.95,9.76 123.43,9.76 123.49,9.71 123.49,8.97 123.31,8.79 121.72,8.79 121.71,8.79 121.51,8.79 121.33,8.6 120.73,8.6 120.29,8.16 118.93,8.16 118.8,8.29 118.8,9.31 118.94,9.45 120.12,9.45 120.35,9.68 121.16,9.68 121.64,10.17 121.64,11.24 121.89,11.49 123.38,11.49
3V_SN on TOP (solid shape): 174.29,62.5 174.29,61.74 175.37,60.66 175.37,60.47 174.73,59.84 174.48,59.84 173.4,60.91 173.4,62.31 173.9,62.82 173.97,62.82
5V_SN on TOP (solid shape): 32.5,11.13 32.5,10.44 32.35,10.29 30.32,10.29 30.06,10.55 30.06,11.18 30.14,11.26 32.38,11.26
+0.6V_DDRA_VREFCA on BOTTOM: 108.02,12.68 111.93,12.68 112.39,12.22 112.39,11.36 112.26,11.23 108.12,11.23 107.84,11.51 107.84,12.5
+0.6V_DDRA_VREFCA on BOTTOM: 97.93,13.67 100.6,13.67 100.96,13.31 100.96,12.81 100.45,12.3 98.01,12.3 97.58,12.73 97.58,13.31
+0.6VS on BOTTOM (solid shape): 143.6,40.26 143.6,38.71 143.35,38.46 142.03,38.46 141.82,38.66 141.82,40.16 142.08,40.42 143.45,40.42
+0.6VS on IN1 (solid shape): 143.49,39.64 143.49,38.37 142.98,38.37 142.41,37.8 142.03,38.18 142.03,40.02 143.11,40.02
+0.6VS on TOP: 88.62,26.9 90.62,26.9 90.87,26.65 90.87,12.96 90.31,12.4 86.99,12.4 86.15,13.24 86.15,23.4 86.71,23.96 86.71,26.43 86.77,26.5 88.22,26.5
+0.6VS on TOP: 31.33,21.82 31.69,21.47 32.35,21.47 32.53,21.29 32.53,20.96 32.4,20.83 31.44,20.83 30.62,21.65 30.62,24.41 29.86,24.41 29.79,24.49 29.79,26.57 30.09,26.88 30.45,26.88 30.62,27.06 30.62,31.46 30.74,31.58 31.27,31.58 31.33,31.51
+0.6VS on BOTTOM: 150.41,44.07 151.25,44.07 151.63,43.69 151.63,43.21 150.69,42.27 149.75,42.27 149.6,42.42 149.6,43.26
+0.6VS on BOTTOM: 28.69,21.7 32.3,21.7 32.68,21.32 32.68,20.25 32.53,20.1 28.03,20.1 27.96,20.17 27.96,20.96
+0.6VS on BOTTOM: 157.32,61.32 157.88,61.32 158.08,61.12 158.08,57.94 157.7,57.56 157.17,57.56 156.86,57.87 156.86,60.86
+0.6VS on IN1: 86.02,12.98 85.36,13.65 85.36,26.6 86.07,27.31 94.58,27.31 94.63,27.26 107.61,27.26 111.04,30.69 119.1,30.69 128.44,40.02 142.28,40.02 142.66,39.64 142.66,38.05 137.2,32.59 128.69,32.59 127.93,31.83 127.93,28.66 129.63,26.95 129.63,25.56 128.49,24.41 107.61,24.41 106.9,23.7 96.13,23.7 95.42,24.41 88.94,24.41 88.28,23.75 88.28,13.57 87.7,12.98
+0.6VS on IN2: 86.3,17.2 87.04,17.2 87.21,17.02 87.21,15.42 86.78,14.99 86.17,14.99 85.92,15.25 85.92,16.82
+0.6VSP on BOTTOM: 159.45,57.94 159.78,57.61 159.78,57.18 160.19,56.77 160.19,55.71 160.14,55.66 159.38,55.66 159.07,55.96 158.64,55.96 158.31,56.29 158.31,60.28 158.36,60.33 158.82,60.33 158.87,60.38 158.87,60.89 158.84,60.91 158.33,60.91 158.31,60.94 158.31,61.19 158.41,61.3 159.38,61.3 159.45,61.22
+0.75VALW on TOP: 113.97,67.52 113.59,67.9 113.59,72.42 113.5,72.52 113.5,73.85 116.75,77.11 124.25,77.11 124.69,76.66 133.24,76.66 134.53,77.96 142.1,77.96 143.29,79.15 145.34,79.15 148.63,82.44 150.01,82.44 152.58,79.87 152.58,78.93 146.22,72.57 133.98,72.57 132.99,71.58 116.78,71.58 116.53,71.33 116.53,67.85 116.2,67.52
+0.75VALW on BOTTOM: 148.47,83.56 149.3,83.56 150.14,82.72 149.8,82.38 149.8,82.28 151.17,80.9 151.53,81.26 151.63,81.26 151.96,80.93 151.96,79.51 155.64,75.82 155.64,74.02 155.17,73.55 155.17,73.36 155.81,72.73 155.81,72.41 154.85,71.46 154.6,71.46 152.76,73.3 152.76,73.42 153.4,74.07 153.4,74.64 147.2,80.84 147.2,82.29
+0.75VALW_0.75VS on BOTTOM: 152.47,73.31 152.51,73.31 153.9,71.91 153.9,71.9 154.09,71.71 154.09,71.58 153.65,71.14 151.95,71.14 150.41,72.67 150.41,72.9 150.64,73.13 150.64,73.28 149.75,74.17 149.67,74.17 149.39,73.89 149.29,73.89 149.06,74.12 149.06,74.43 149.88,75.24 150.54,75.24
+0.75VALWP on BOTTOM (solid shape): 155.93,86.99 158.93,86.99 160.35,85.57 160.35,85.26 153.65,78.55 153.17,78.55 152.2,79.52 152.2,80.97 148.29,84.88 148.29,85.74 151.9,89.35 153.57,89.35
+0.75VS on IN1 (solid shape): outline of 10335 points within 87.42,54.02 132.19,67.97
+0.75VS on IN3 (solid shape): 88.56,62.8 88.56,62.24 88.4,62.09 87.4,62.09 87.18,62.31 87.18,63.13 87.41,63.36 87.99,63.36
+0.75VS on IN3 (solid shape): 97.26,65.61 97.26,63.42 97.07,63.23 96.37,63.23 96.17,63.83 95.98,63.23 95.61,63.23 95.58,63.27 95.59,63.75 95.11,63.74 95.07,63.78 95.07,64.89 95.21,65.03 96.36,65.03 96.57,65.25 96.57,65.57 96.78,65.78 97.09,65.78
+0.75VS on TOP: 97.2,63.96 97.12,63.89 97.12,62.84 96.84,62.57 94.85,62.57 94.67,62.75 91.37,62.75 91.27,62.65 91.27,62.32 91.21,62.26 87.54,62.26 87.35,62.45 87.35,64.6 87.76,65 89.25,65 89.28,64.97 90.86,64.97 91,64.83 96.03,64.83 96.49,65.28 96.49,65.46 96.79,65.77 97.07,65.77 97.2,65.64
+0.75VS on BOTTOM: 97.56,72.7 98.52,72.7 99.46,71.75 99.46,67.89 98.46,66.89 98.46,63.78 97.41,62.74 97.21,62.74 96.57,63.37 96.57,63.39 95.75,64.22 95.23,64.22 95.04,64.41 95.04,64.66 95.16,64.79 96.56,64.79 96.57,64.8 96.57,71.71
+0.75VS on BOTTOM: 147.44,72.34 147.44,73.23 148.23,74.02 148.78,74.02 151.74,71.06 151.74,70.76 151.62,70.63 149.15,70.63
+0.75VS on VCC: 139.08,56.15 133.75,61.49 126.19,61.49 125.25,62.43 125.25,67.93 125.31,67.99 146.01,67.99 146.79,68.77 146.79,72.99 146.87,73.07 151.09,77.31 154.61,77.31 155.95,75.97 155.95,74.51 153.67,72.23 153.67,56.73 153.65,56.7 153.65,56.38 153.42,56.15 149.18,56.15 145.71,59.62 144.67,59.62 143.97,58.92 143.97,56.58 143.54,56.15
+1.2V on BOTTOM (solid shape): 63.75,37.57 43.75,37.57 43.75,41.57 63.75,41.57
+1.2V on BOTTOM (solid shape): 73.29,36.85 67.29,36.85 67.29,42.85 73.29,42.85
+1.2V on BOTTOM (solid shape): 56.15,19.92 56.18,19.92 56.18,19.73 56.17,19.72 56.13,19.65 56.12,19.58 56.11,19.54 54.63,19.54 54.63,20.85 54.92,21.15 56.15,21.15
+1.2V on BOTTOM (solid shape): 45.11,20.76 45.11,20.72 45.12,20.67 45.12,19.85 45.72,19.85 45.72,19.5 45.83,18.97 46.33,19.17 46.34,19.18 46.84,19.68 47.29,19.68 47.29,18.77 47.83,18.23 47.39,17.79 44.01,17.79 43.42,18.37 43.42,18.55 43.49,18.64 43.6,18.62 43.65,18.57 45.09,18.57 45.09,19.34 43.95,19.34 43.76,19.39 43.57,19.34 43.47,19.34 43.42,19.43 43.42,20.07 43.37,20.12 43.37,20.68 43.79,21.09 45.11,21.09
+1.2V on BOTTOM (solid shape): 59.07,19.99 59.1,19.9 59.03,19.82 59.05,19.15 59.43,19.7 59.42,19.81 59.51,19.87 60.16,19.87 60.49,19.54 61.87,19.54 62.12,19.28 62.12,18.7 61.2,17.79 58.39,17.79 57.19,18.98 57.17,19.09 57.26,19.16 57.43,19.16 58.04,19.77 58.17,19.77 58.17,20.53 57.33,20.53 57.33,20.68 58.38,20.68
+1.2V on IN1 (solid shape): 64.94,47.01 64.94,45.55 59.8,45.55 59.8,47.07 59.86,47.14 64.81,47.14
+1.2V on IN1 (solid shape): outline of 650 points within 103.46,54.56 114.56,57.49
+1.2V on TOP: outline of 314 points within 35.77,17.29 150.31,61.07
+1.2V on BOTTOM: outline of 98 points within 90.77,11.94 151.68,32.62
+1.2V on BOTTOM: outline of 370 points within 28.01,17.79 75.99,47.15
+1.2V on IN1: 83.23,26.75 83.23,18.34 82.21,17.33 80.94,17.33 80.18,18.09 80.18,26.75 81.07,27.64 81.42,27.64 81.58,27.49 82.49,27.49
+1.2V on IN1: 64.94,46.12 64.56,46.5 59.41,46.5 58.84,45.93 52.94,45.93 46.08,39.07 38.78,39.07 37.89,38.18 37.89,33.29 42.78,28.4 57.13,28.4 57.7,28.97 57.7,34.94 64.94,42.18
+1.2V on IN3: 109.17,55.11 111.64,55.11 111.97,55.44 111.97,55.72 112.42,56.18 112.96,56.18 113.19,56.41 113.19,59.63 111.87,60.95 106.45,60.95 106.15,60.65 106.15,59.15 106.12,59.12 106.12,58.49 106.61,58.01 108.26,58.01 108.54,57.73 108.54,55.75
+1.2VP on BOTTOM (solid shape): 159.35,55.47 160.16,55.47 160.23,55.4 160.23,55.34 160.15,55.26 159.27,55.26 159.22,55.31 158.18,55.31 158.06,55.43 158.06,55.65 158.16,55.75 159.07,55.75
+1.2VP on BOTTOM (solid shape): 148,38 150.18,38 150.64,37.55 150.64,36.35 151.02,35.97 151.02,31.86 150.82,31.65 150.1,31.65 148.94,32.82 144.44,32.82 144.24,33.03 144.24,35.54 144.44,35.74 145.36,35.74 145.58,35.97 145.58,39.48 145.76,39.65 146.35,39.65
+1.8VALW on BOTTOM (solid shape): 161.31,73.28 161.31,73.13 161.03,72.85 161.03,72.8 161.99,71.84 162.07,71.84 162.35,72.12 162.5,72.12 162.8,71.81 162.8,71.1 160.95,69.25 159.25,69.25 156.35,72.14 156.35,72.4 158.89,74.94 159.66,74.94
+1.8VALW on TOP: 143.41,53.5 141.7,55.21 125.5,55.21 122.6,58.12 115.51,58.12 115.15,58.48 115.15,61.83 114.93,62.06 113.86,62.06 113.66,62.26 113.66,62.64 113.71,62.69 114.31,62.69 114.25,62.76 114.25,63 114.43,63.18 114.92,63.18 115.41,62.69 119.62,62.69 119.97,62.35 120.55,62.35 121,61.91 122.81,61.91 123.08,61.64 123.63,61.64 123.63,61.72 125,61.72 125.44,61.28 150.02,61.28 152.89,64.15 152.89,67.14 158.59,72.85 160.64,72.85 163.17,70.31 163.17,67.13 160.2,64.15 157.84,64.15 155.81,62.13 155.81,56.26 155.02,55.47 150.73,55.47 148.76,53.5 ; 3 cut-outs
+1.8VALW_1.8VS on BOTTOM: 156.17,70.8 156.79,70.19 157.9,70.19 158.08,70.01 158.08,67.98 156.81,66.71 155.46,66.71 155.24,66.93 155.24,67.01 155.59,67.37 155.59,67.42 155.24,67.77 155.18,67.77 154.85,67.44 154.8,67.44 154.7,67.54 154.7,67.59 155.03,67.92 155.03,67.98 154.68,68.33 154.63,68.33 154.3,68 154.22,68 153.69,68.53 153.69,69.02 154.5,69.83 154.5,69.96 155.34,70.8
+1.8VALWP on BOTTOM (solid shape): 165.17,74.86 166.95,74.86 167.73,74.08 167.73,73.98 164.95,71.2 163.68,71.2 161.16,73.72 161.16,74.59 162.88,76.31 163.72,76.31
+1.8VS on TOP: 135.42,68.5 129.66,68.5 128.04,66.88 127.02,66.88 126.48,66.35 125.85,66.35 125.75,66.45 125.75,67.01 125.7,67.06 125.7,67.52 125.87,67.7 125.87,68.33 126.13,68.59 127.4,68.59 129.2,70.39 133.11,70.39 133.47,70.74 143.09,70.74 143.74,71.39 144.91,71.39 146.29,70.01 146.29,68.97 145.83,68.5 135.43,68.5
+1.8VS on BOTTOM: 155.38,66.59 155.38,66.39 154.07,65.08 153.74,65.08 153.38,64.72 153.15,64.72 151.11,66.76 150.09,66.76 149.52,67.33 147.55,67.33 146.73,68.15 145.86,68.15 145.76,68.26 145.71,68.26 145,68.97 145,68.99 143.96,70.03 143.96,70.06 143.68,70.34 143.68,71.27 144.25,71.84 146.35,71.84 147.49,70.69 148.82,70.69 149.01,70.5 152.89,70.5 153.52,69.87 153.52,68.45
+1.8VS on VCC: 112.64,61.4 112.45,61.59 112.45,65.52 114.52,67.59 114.52,68.01 114.85,68.34 115.03,68.34 116.05,69.36 120.73,69.36 123.27,71.9 124.35,71.9 125.37,72.92 145.87,72.92 146.28,72.51 146.28,68.98 145.8,68.5 125.09,68.5 124.74,68.14 124.74,65.78 124.26,65.3 121.39,65.3 121.08,64.99 116.18,64.99 115.1,63.91 115.1,62.11 114.39,61.4 ; 1 cut-out
+2.5V on TOP: 115.48,27.87 118.79,27.87 118.89,27.77 118.89,27.59 117.03,25.74 117.03,21.6 117.24,21.39 117.24,12.02 115.94,10.72 113.12,10.72 112.11,9.71 112.11,9.1 112.06,9.05 107.59,9.05 107,9.63 107,10.62 106.54,11.08 105.93,11.08 103.32,13.7 103.32,22.24 103.42,22.34 103.42,25.23 103.6,25.41 105.43,25.41 105.81,25.02 105.81,15.17 106.32,14.66 106.32,13.06 106.65,12.73 107.26,12.73 109.41,10.57 111.37,10.57 114.19,13.39 114.19,15.85 115.21,16.87 115.21,27.59
+2.5V on BOTTOM: 51.68,19.26 54.42,19.26 54.6,19.08 54.6,18.06 54.37,17.84 51.65,17.84 51.32,18.17 51.32,18.9
+2.5V on BOTTOM: 63.62,19 66.74,19 66.97,18.78 66.97,18.04 66.77,17.84 63.77,17.84 63.47,18.14 63.47,18.85
+2.5V on BOTTOM: 120.51,14.58 123.94,14.58 124.2,14.33 124.2,13.9 123.64,13.34 120.39,13.34 120.13,13.59 120.13,14.2
+2.5VP on TOP (solid shape): 116.67,9.9 116.67,8.84 116.49,8.67 115.51,8.67 115.1,9.07 114.47,9.07 114.2,8.81 114.2,8.31 114.11,8.22 113.63,8.22 113.49,8.36 113.1,8.36 112.41,7.68 110.13,7.68 110.02,7.78 110.02,8.26 110.09,8.33 110.56,8.33 110.56,8.86 110.85,8.86 110.85,8.33 111.36,8.33 111.36,8.86 111.65,8.86 111.65,8.33 112.23,8.33 112.35,8.44 112.35,9.47 112.7,9.82 115.26,9.82 115.4,9.96 116.6,9.96
+3V_AUDIO on TOP (solid shape): 13.03,34.24 13.03,33.68 12.98,33.62 12.98,33.16 12.97,33.15 12.97,33.03 12.06,32.11 11.8,32.11 11.67,32.24 11.67,32.87 12.5,33.7 12.5,34.24 12.56,34.31 12.97,34.31
+3V_CMOS on TOP (solid shape): 52.34,65.87 53.45,65.87 54.2,65.12 54.23,65.12 54.35,65 55.29,65 55.84,65.55 55.84,65.56 57.1,65.56 57.32,65.35 57.32,63.71 57.06,63.45 52.37,63.45 52.23,63.59 51.53,63.59 51.41,63.47 51.41,62.25 51.6,62.06 52.89,62.06 53.54,61.41 53.54,60.43 52.95,59.84 52.3,59.84 52.11,59.64 50.25,59.64 49.6,60.3 48.16,60.3 47.94,60.51 47.94,63.62 50.26,65.93 52.28,65.93
+3V_CMOS on BOTTOM: 50.02,61.11 50.02,59.52 50.14,59.39 52.28,59.39 53.42,60.53 53.42,61.08 53.21,61.3 51.54,61.3 51.41,61.17 50.08,61.17
+3V_SD_R on TOP: 197.91,28.85 197.84,28.91 197.84,29.61 198.29,30.05 198.92,30.05 199.11,30.24 200.07,30.24 200.26,30.05 200.26,29.23 199.88,28.85
+3V_SD_R on TOP: 167.24,29.42 167.87,29.42 167.94,29.36 167.94,28.53 168.44,28.02 168.44,27.13 168.38,27.07 167.24,27.07 167.05,27.26 167.05,29.23
+3V_SD_R on BOTTOM: 193.53,23.7 193.72,23.7 193.78,23.64 194.92,21.8 195.18,21.54 195.18,20.97 195.05,20.85 194.73,20.85 194.61,20.97 193.59,22.37 193.08,23.13 193.08,23.45 193.1,23.47
+3V_SD_R on VCC: 166.92,28.21 168.66,28.21 169.21,27.67 169.21,25.5 171.13,23.58 195.09,23.58 195.17,23.5 195.17,19.24 194.32,18.39 168.12,18.39 167.93,18.57 167.93,24.13 166.92,25.14 166.92,28.21
+3V_SD_R on IN2: 195.89,22.12 196.19,22.12 198.48,24.4 198.48,28.79 197.87,29.4 197.87,30.6 198.49,31.22 201.21,31.22 204.63,27.8 204.63,24.21 198.65,18.22 192.11,18.22 191.18,19.16 191.18,21.16 193.25,23.24 194.77,23.24
+3VALW on TOP (solid shape): 139.63,12.08 139.63,11.4 138.81,10.58 137.04,10.58 136.78,10.84 136.78,11.73 137.14,12.08 138.03,12.08 138.26,12.31 139.4,12.31
+3VALW on BOTTOM (solid shape): 55.28,90.08 55.28,87.81 54.8,87.32 52.35,87.32 52.27,87.4 52.25,87.4 52.09,87.56 51.59,87.56 51.35,87.79 51.35,89.16 51.42,89.23 52.13,89.23 52.37,89.46 52.37,89.87 52.88,90.38 54.98,90.38
+3VALW on BOTTOM (solid shape): 43.79,50.02 43.79,48.83 43.49,48.53 39.69,48.53 39.57,48.65 39.57,48.81 39.44,48.94 38.79,48.94 38.65,48.8 37.46,48.8 37.24,48.58 34.92,48.58 34.28,49.23 34.05,49.23 33.89,49.4 33.89,50.24 34.26,50.61 37.52,50.61 37.81,50.89 42.91,50.89
+3VALW on TOP: 170.03,30.51 170.03,30.82 170.09,30.88 170.78,30.88 170.93,31.03 170.93,31.35 170.98,31.4 171.49,31.4 171.57,31.32 171.57,30.79 171.75,30.61 171.75,30.33 171.69,30.28 170.26,30.28
+3VALW on TOP: 86.45,65.92 87.8,67.26 87.8,72.28 87.48,72.6 86.85,72.6 86.58,72.33 86.58,70.8 86.27,70.49 85.49,70.49 85.21,70.77 85.21,71.79 84.94,72.05 84.94,72.73 84.56,73.11 83.67,73.11 83.4,72.84 83.4,68.38 84.06,67.72 84.06,66.1 84.24,65.92
+3VALW on TOP: 57.64,65.49 57.83,65.3 62.34,65.3 63.03,64.6 63.03,64.28 62.84,64.09 62.59,64.09 62.4,64.28 61.45,64.28 61.38,64.22 61.38,63.58 61.13,63.33 61.13,63.07 61.38,62.82 63.98,62.82 64.48,63.32 64.48,66.15 64.12,66.5 62.91,66.5 62.16,67.25 57.92,67.25 57.64,66.96
+3VALW on TOP: 123.65,9.17 123.65,9.73 123.1,9.73 123.1,9.98 123.65,9.98 123.65,10.53 123.1,10.53 123.1,10.78 123.65,10.78 123.65,11.56 123.54,11.66 122.24,11.66 122.16,11.74 122.16,12.6 122.24,12.68 123.82,12.68 124.2,13.06 124.83,13.06 124.84,13.05 125.53,13.05 125.86,12.72 126.62,12.72 126.99,12.35 126.99,10.27 125.67,8.95 123.87,8.95
+3VALW on TOP: 125.47,64 123.97,64 123.77,64.2 123.12,64.2 122.97,64.05 122.43,64.05 122.42,64.05 115.28,64.05 115.13,63.91 113.86,63.91 113.76,63.8 113.39,63.8 113.33,63.86 113.33,65.66 113.94,66.27 121.7,66.27 122.3,65.67 126.05,65.67 127.11,66.72 128.16,66.72 129.56,68.12 130.86,68.12 130.91,68.07 132.42,68.07 132.47,68.02 144.37,68.02 144.38,68.03 145.96,68.03 146.73,68.79 146.73,70.38 156.19,79.84 164.15,79.84 169.99,74 169.99,71.07 169.08,70.16 169.08,67.82 167.99,66.73 167.99,65.84 169.23,64.6 169.36,64.6 171.3,62.65 171.3,62.12 169.38,60.2 167.71,60.2 163.87,64.04 163.87,70.88 160.63,74.12 158.66,74.12 153.99,69.45 153.15,69.45 147.42,63.72 139.28,63.72 137.92,65.08 132.43,65.08 131.2,63.85 125.62,63.85
+3VALW on BOTTOM: 160.85,90.3 160.95,90.3 161.66,89.59 161.66,88.47 161.48,88.3 161.23,88.3 160.75,88.78 160.75,90.2
+3VALW on BOTTOM: 172.33,62.92 172.33,62.24 172.05,61.96 171.92,61.96 171.67,62.21 171.52,62.21 171.03,61.73 171.03,61.57 171.39,61.22 171.39,61.17 171.14,60.91 171.11,60.91 170.77,61.26 170.56,61.26 170.15,60.84 170.15,60.64 170.45,60.33 170.45,60.28 170.17,60 169.97,60 169.94,60.03 168.9,60.03 165.98,62.95 165.98,64.72 167.71,66.45 168.8,66.45
+3VALW on BOTTOM: 114.41,9.42 114.41,9.92 114.8,10.32 116.75,10.32 116.93,10.14 117.44,10.14 117.52,10.06 117.52,9.53 117.16,9.17 114.65,9.17
+3VALW on BOTTOM: 172.74,55.8 172.74,55.5 172.1,54.86 169.83,54.86 169.64,54.67 169.47,54.67 169.23,54.91 169.23,55.75 169.41,55.92 169.88,55.92 170.09,55.71 171.36,55.71 172.03,56.37 172.16,56.37
+3VALW on VCC: 87.54,4.92 84.49,7.97 37.7,7.97 28.74,16.93 28.74,24.25 27.92,25.08 27.92,49.25 46.59,67.92 46.59,86.89 50.76,86.89 52.24,88.37 52.24,92.03 57.04,92.03 63.58,98.57 152.27,98.57 155.83,95.01 172.47,95.01 180.45,87.03 180.45,60.49 191.11,49.82 191.11,47.93 190.72,47.53 175.88,47.53 175.33,46.97 175.33,43.77 175.96,43.13 190.47,43.13 190.47,33.83 190.48,33.82 190.48,24.09 171.34,24.09 169.71,25.71 169.71,27.89 168.89,28.72 166.54,28.72 166.41,28.59 166.41,24.93 167.44,23.9 167.44,18.38 150.9,18.38 146.64,14.12 146.64,11.19 144.34,8.78 136.65,8.76 132.69,6.11 96.14,6.11 94.96,4.92 ; 1 cut-out
+3VALW_3VS on BOTTOM (solid shape): 52.57,97.06 52.57,96.6 52.62,96.55 53.97,96.55 54.02,96.6 54.02,97.06 54.09,97.13 54.3,97.13 55.17,96.26 55.17,91.5 54.2,90.53 51.44,90.53 51.37,90.6 51.37,92.07 51.84,92.55 51.84,96.96 52.01,97.13 52.49,97.13
+3VALW_EC on TOP (solid shape): 193.27,45.93 193.27,44.91 193.53,44.66 193.53,44.4 193.46,44.34 192.26,44.34 192.13,44.21 192.13,43.64 192,43.52 190.5,43.52 190.35,43.67 190.35,45.42 190.92,45.99 193.21,45.99
+3VALW_EC on VCC: 176.17,43.64 175.84,43.98 175.84,46.76 176.09,47.02 190.72,47.02 191.63,46.1 191.63,44.66 190.61,43.64
+3VALWP on TOP (solid shape): 174.1,69.68 174.1,69.42 175.11,68.41 175.11,68.22 175.05,68.15 174.86,68.15 174.29,68.73 173.52,68.73 172.7,69.55 172.19,69.55 172.06,69.68 172.06,70 172.32,70.25 172.7,70.25 173.02,70.57 173.21,70.57
+3VALWP on BOTTOM (solid shape): 176.18,63.14 176.42,63.14 177.83,61.73 177.83,61.36 177.61,61.14 177.61,60.81 177.97,60.46 177.97,59.92 177.56,59.52 177.28,59.52 176.8,60 176.47,60 174.26,57.79 172.2,57.79 170.4,59.59 170.4,59.92 172.6,62.12 172.6,62.71 174.37,64.48 174.83,64.48
+3VALWP on TOP: 173.4,60.72 172.57,60.72 172.25,60.41 172.25,59.26 173.21,58.31 175.17,58.31 175.68,58.82 175.68,59.33 175.49,59.52 174.6,59.52
+3VL on TOP: 194.03,46.56 194.1,46.63 195.18,46.63 195.24,46.56 195.24,44.98 195.11,44.85 194.1,44.85 194.03,44.91
+3VL on TOP: 170.56,71.57 170.92,71.57 172.11,70.38 172.11,70.22 171.5,69.61 171.28,69.61 170.08,70.81 170.08,71.09
+3VL on BOTTOM: 188.6,19.04 188.76,18.88 190.1,18.88 190.16,18.94 190.16,19.2 189.72,19.64 189.21,19.64 189.01,19.44 188.83,19.44 188.54,19.15
+3VL on BOTTOM: 179.87,74.71 180.25,74.33 180.25,73.41 179.92,73.08 178.93,73.08 178.3,72.45 178.3,71.76 177.74,71.2 172.84,71.2 171.77,70.13 170.91,70.13 170.65,70.39 170.65,71.96 171.06,72.37 173.73,72.37 176.06,74.71
+3VL on BOTTOM: 181.65,60.03 183.05,60.03 183.3,59.77 183.3,57.49 182.67,56.85 181.91,56.85 181.4,57.36 181.4,59.77
+3VL on IN1: 195.24,44.86 195.62,45.24 195.62,46.97 195.14,47.45 193.59,47.45 192.45,48.6 185.84,48.6 184.83,49.61 184.83,58.12 184.45,58.5 182.16,58.5 182.03,58.37 182.03,47.33 183.18,46.18 191.3,46.18 191.43,46.31 191.68,46.31 193.13,44.86
+3VLP on TOP: 170.87,69.69 170.92,69.69 171.15,69.46 172.39,69.46 174.22,67.63 174.7,67.63 174.78,67.56 174.78,67.51 173.49,66.21 172.83,66.21 170.84,68.19 169.95,68.19 169.37,68.78 169.37,69.54 170.16,70.33 170.31,70.33 170.49,70.15 170.49,70.07 170.16,69.74 170.16,69.66 170.49,69.33 170.51,69.33
+3VS on TOP (solid shape): 57.87,74.38 57.87,72.71 57.5,72.34 55.6,72.34 54.91,73.03 54.91,73.48 55,73.57 56.62,73.57 56.82,73.77 56.82,74.3 57.02,74.49 57.75,74.49
+3VS on TOP: 40.3,62.13 40.3,61.17 43.12,58.35 47.34,58.35 47.64,58.65 47.64,63.87 47.45,64.06 42.24,64.06
+3VS on TOP: 196.37,32.7 197.99,32.7 198.87,31.81 198.87,30.31 198.78,30.21 197.75,30.21 197.63,30.33 197.63,31.05 197.42,31.26 196.37,31.26 196.33,31.3 196.33,32.66
+3VS on TOP: 125.21,62.35 123.02,62.35 122.86,62.52 121.98,62.52 121.96,62.53 120.85,62.53 120.58,62.8 115.45,62.8 114.95,63.3 114.33,63.3 114.29,63.35 114.29,63.73 114.34,63.78 115.41,63.78 115.48,63.85 122.83,63.85 122.86,63.81 126.55,63.81 126.69,63.67 131.66,63.67 132.84,64.85 137.38,64.85 138.56,63.67 142.34,63.67 142.36,63.66 147.87,63.66 151.1,66.88 152,66.88 152.52,66.36 152.52,64.06 150.26,61.8 141.29,61.8 140.97,61.49 128.06,61.49 128.03,61.52 126.05,61.52
+3VS on BOTTOM: 51.35,99.37 56.06,99.37 56.38,99.05 56.92,99.05 57.14,98.84 57.14,96.65 56.96,96.47 55.29,96.47 54.4,97.36 51.96,97.36 51.3,96.7 50.33,96.7 49.93,97.11 49.93,98.23 50.16,98.46 50.87,98.46 51.04,98.63 51.04,99.07
+3VS on BOTTOM: 145.3,63.68 146.78,63.68 146.96,63.51 146.96,62.31 146.85,62.21 145.63,62.21 145.48,62.36 145.48,63.02 145.15,63.35 145.15,63.53
+3VS on VCC: 191.01,24.1 190.99,24.12 190.99,34.03 190.97,34.04 190.97,43.28 192.14,44.45 192.14,46.31 191.18,47.27 191.62,47.72 191.62,50.03 180.95,60.7 180.95,87.25 172.68,95.52 156.04,95.52 152.48,99.08 63.37,99.08 56.83,92.54 52.24,92.54 52.24,94.27 62.44,104.48 147.95,104.48 149.03,103.4 153.99,103.4 155.05,101.37 157.2,100.57 158.17,100.57 160.44,101.5 161.38,103.77 161.38,109.5 179.82,109.5 181.62,105.66 181.62,99.35 184.6,99.35 187.75,92.65 198.35,50.03 198.4,49.82 201.05,39.14 205.81,31.01 195.77,31.01 195.18,30.41 195.18,24.72 195.17,24.72 195.17,24.24 195.04,24.1
+3VS on IN2: 56.91,98.58 54.63,98.58 54.12,98.07 54.12,96.22 57.41,92.93 57.41,82.39 54.14,79.13 54.14,73.72 54.52,73.34 54.52,72.81 54.91,72.42 57.1,72.42 57.38,72.7 57.38,75.02 59.96,77.6 59.96,94.77 57.34,97.39 57.34,98.15
+3VS on IN3: 61.26,59.21 62.37,60.33 62.37,61.09 62.09,61.37 59.45,61.37 58.21,60.13 57.52,60.13 57.18,60.47 57.18,60.83 60.09,63.73 60.09,69.89 56.46,73.51 54.47,73.51 53.08,72.12 53.08,65.87 52.19,64.98 30.27,64.98 27.19,61.91 20.23,61.91 19.41,61.08 19.41,56.9 20.63,55.68 40.52,55.68 44.05,59.21
+3VS_SSD1 on BOTTOM (solid shape): 31.73,26.23 31.73,22.37 30.78,21.42 29.58,21.42 29.25,21.75 29.25,22.15 29.63,22.54 29.63,23.37 29.76,23.5 29.76,26.04 30.04,26.32 31.64,26.32
+3VS_SSD1 on BOTTOM (solid shape): 33.04,43.22 33.04,38.22 32.74,37.93 32.11,37.93 31.92,38.12 31.92,38.88 31.79,39.01 30.2,39.01 30.08,39.13 30.08,40.66 30.27,40.85 31.79,40.85 32.01,41.07 32.01,42.28 31.81,42.48 30.16,42.48 30.08,42.56 30.08,43.26 30.2,43.39 32.87,43.39
+3VS_SSD1 on BOTTOM (solid shape): outline of 110 points within 28.54,44.88 34.33,51.38
+3VS_SSD1 on TOP: 31.21,38.05 31.03,38.23 31.03,40.16 31.06,40.19 31.06,44.38 30.99,44.44 30.99,45.28 31.69,45.98 32.66,45.98 32.76,45.88 32.76,38.23 32.63,38.11 32.58,38.11 32.53,38.05
+3VS_SSD1 on IN3: 29.81,23.7 29.58,23.47 29.58,21.75 29.96,21.37 30.93,21.37 31.36,21.8 31.36,26.95 32.07,27.67 32.07,29.75 33.52,31.2 33.52,39.63 33.26,39.88 31.82,39.88 31.08,39.15 31.08,31.27 29.81,30
+3VS_SSD2 on TOP (solid shape): 60.13,57.66 60.13,56.65 59.96,56.48 56.85,56.48 56.67,56.66 55.92,56.66 55.82,56.76 55.82,57.56 55.99,57.73 60.06,57.73
+3VS_SSD2 on BOTTOM (solid shape): 46.14,51.84 46.14,47.82 45.96,47.63 44.26,47.63 43.93,47.96 43.93,50.28 43.4,50.81 43.4,51.91 44.1,52.61 45.37,52.61
+3VS_SSD2 on TOP: 73.83,58.7 72.91,58.7 72.79,58.58 72.79,57.49 72.89,57.38 73.8,57.38 73.88,57.46 73.88,58.65
+3VS_SSD2 on BOTTOM: 72.84,55.5 74.06,55.5 74.16,55.61 74.16,57.94 74.06,58.04 72.84,58.04 72.74,57.94 72.74,55.61
+3VS_SSD2 on BOTTOM: 27.6,53.23 30.5,53.23 31.22,52.5 31.22,51.48 31.06,51.32 29.26,51.32 28.29,50.35 28.29,47.29 28.1,47.11 27.35,47.11 26.97,47.49 26.97,52.59
+3VS_SSD2 on IN2: 44.59,52.78 41.39,52.78 37.59,48.98 28.15,48.98 27.14,47.97 27.14,46.68 27.61,46.2 40.21,46.2 43.89,49.88 43.89,50.49 45.29,51.89 45.29,52.09
+3VS_SSD2 on IN3: 69.26,59.9 66.56,59.9 64.82,58.16 56.09,58.16 53.33,55.4 44.3,55.4 43.07,54.17 43.07,51.95 43.8,51.21 55.64,51.21 55.71,51.28 67.75,51.28 73.83,57.36 73.83,57.87 73.75,57.94 71.21,57.94
+3VS_TP on BOTTOM: 121.58,11 125.71,11 125.84,10.88 125.84,10.05 125.58,9.8 124.5,9.8 124.18,9.48 124.18,8.08 123.99,7.89 121.26,7.89 120.95,8.21 120.95,10.37
+3VS_WLAN on TOP: 168.7,29.67 168.51,29.48 168.51,28.47 168.65,28.33 169.79,28.33 170.03,28.09 170.16,28.09 170.6,27.64 171.3,27.64 171.49,27.83 171.81,27.83 171.87,27.89 171.87,28.59 171.49,28.97 171.28,28.97 170.58,29.67
+3VS_WLAN on BOTTOM: 170.08,28.1 170.35,27.83 170.6,27.83 170.79,27.64 172.38,27.64 172.7,27.96 172.7,28.91 172.57,29.04 170.41,29.04 170.41,29.03 169.24,29.03 169.15,28.94 169.15,28.19 169.23,28.1
+3VS_WLAN on BOTTOM: 171.17,46.56 172.57,46.56 172.76,46.37 172.76,45.67 172.63,45.55 171.05,45.55 170.86,45.36 170.67,45.36 170.48,45.55 170.48,45.87
+3VS_WLAN on BOTTOM: 172.05,50.91 172.05,51.78 172,51.83 170.65,51.83 169.33,50.51 169.33,49.23 169.75,48.82 171.33,48.82 171.42,48.9 171.42,50.27
+3VS_WLAN on IN1: 169.76,47.15 169.76,33.42 169.4,33.05 169.4,28.28 169.97,27.7 172.16,27.7 173.52,29.06 173.52,29.74 173.71,29.93 173.71,42.88 173.52,43.07 173.52,49.29 172.83,49.99 169.28,49.99 169.02,49.72 169.02,47.9
+5V_AUDIO on BOTTOM (solid shape): 25.76,8.45 25.76,7.92 25.67,7.83 25.67,7.78 25.44,7.55 25.44,6.56 25.34,6.46 24.88,6.46 24.81,6.53 24.81,8.44 24.91,8.54 24.92,8.54 25.1,8.72 25.49,8.72
+5V_AUDIO on IN1 (solid shape): 25.82,8.82 25.82,7.96 25.62,7.75 25.43,7.75 23.4,9.78 23.4,10.15 23.71,10.47 24.17,10.47
+5V_AUDIO on IN1 (solid shape): 18.03,31.11 18.03,30.08 16.89,28.95 16.78,28.95 15.98,29.75 15.98,30.92 16.3,31.24 17.9,31.24
+5V_AUDIO on TOP: 16.1,32.38 14.2,34.28 14.2,35.59 13.48,36.32 13.48,36.61 13.99,37.11 14.26,37.11 14.77,36.6 14.77,36.59 14.92,36.45 14.94,36.43 15.75,35.77 16.69,35.32 16.7,35.31 18.05,33.96 18.05,30.06 17.68,29.69 16.4,29.69 16.1,29.99
+5V_AUDIO on BOTTOM: 15.35,30.75 15.35,29.74 15.47,29.61 16.68,29.61 16.87,29.42 16.87,28.72 18.33,27.26 19.22,27.26 19.47,27.51 19.47,29.2 17.58,31.09 17.08,31.09 16.87,30.88 15.47,30.88
+5V_DISPLAY on BOTTOM (solid shape): 18.7,75.51 18.7,74.52 18.65,74.47 17.68,74.47 17.58,74.36 17.58,74.11 17.43,73.96 16.84,73.96 16.73,73.84 16.73,73.08 16.31,72.66 14.84,72.66 14.68,72.81 14.68,74.64 15.8,75.76 18.44,75.76
+5V_DISPLAY on IN1 (solid shape): 16.61,75.34 16.61,74.04 16.37,73.81 11.69,73.81 11.43,74.06 11.43,75.38 11.69,75.63 16.32,75.63
+5V_IN_PWR on TOP (solid shape): 35.79,89.49 35.79,89.1 35.67,88.97 35.67,88.22 35.67,88.22 35.67,88.02 36.52,87.18 36.52,86.21 36.45,86.15 35.76,86.15 35.41,86.5 35.41,86.51 35.36,86.63 35.27,86.72 35.27,87.25 35.22,87.3 35.22,87.3 34.73,87.79 34.73,89.43 34.95,89.65 35.64,89.65
+5V_IN_PWR on TOP (solid shape): 41.65,83.2 41.92,83.2 42.22,82.9 42.22,82.63 42.54,82.31 43.85,82.31 44.08,82.09 44.72,82.09 44.74,82.06 44.93,81.88 44.93,81.29 45.3,80.91 45.3,79.04 45.15,78.89 44.39,78.89 44.05,79.24 44.05,81.16 43.84,81.36 43.06,81.36 43,81.31 42.31,81.31 42.22,81.23 42.02,81.23 41.79,81.45 41.79,81.92 41.54,82.17 41.54,82.6 41.54,82.67 41.54,82.78 41.47,82.85 41.37,82.94 40.72,82.94 40.65,83.02 40.65,83.13 40.73,83.21 41.65,83.21
+5V_IN_PWR on IN2 (solid shape): outline of 365 points within 34.52,81.2 42.55,89.55
+5VALW on TOP (solid shape): 119.87,12.64 119.87,11.07 119.65,10.86 119.65,9.91 119.74,9.82 119.74,9.72 119.65,9.63 118.93,9.63 118.82,9.73 118.82,11.13 118.57,11.38 118.57,12.65 118.67,12.74 119.76,12.74
+5VALW on TOP (solid shape): 29.81,14.97 29.81,13.52 29.71,13.42 28.03,13.42 26.7,14.74 25.96,14.74 25.96,15.26 25.93,15.26 25.93,15.27 25.23,15.27 25.23,15.26 25.2,15.26 25.2,14.74 24.76,14.74 24.76,15.26 24.73,15.26 24.73,15.27 24.03,15.27 24.03,15.26 24,15.26 24,14.74 23.43,14.74 23.3,14.88 23.3,16.97 23.39,17.06 27.71,17.06
+5VALW on BOTTOM (solid shape): 50,89.16 50,88.47 49.85,88.33 49.85,87.09 49.8,87.04 49.35,87.04 49.21,86.91 48.53,86.91 47.67,86.05 47.67,84.04 47.53,83.9 44.73,83.9 44.12,84.5 44.12,86.22 44.71,86.81 44.71,88.67 45.3,89.26 49.9,89.26
+5VALW on TOP: 198.29,23.32 197.46,24.15 197.46,26.5 197.08,26.88 196.59,26.88 195.75,26.04 195.75,24.97 195.56,24.78 193.59,24.78 192.83,24.02 191.24,24.02 191.05,24.21 191.05,24.97 191.24,25.16 191.24,25.37 190.88,25.73 190.53,25.73 190.31,25.96 190.31,26.3 190.19,26.43 189.62,26.43 189.55,26.49 189.55,27.23 189.63,27.31 190.34,27.31 190.51,27.13 191.08,27.13 191.19,27.02 191.19,26.57 191.34,26.42 192.01,26.42 192.78,27.18 193.64,27.18 194.11,27.65 194.11,28.44 194.2,28.53 199.91,28.53 200.5,27.94 200.5,26.32 200.09,25.91 199.48,25.91 199.37,25.8 199.37,24.99 199.18,24.8 199.18,23.51 198.99,23.32
+5VALW on TOP: 25.63,66.92 25.38,67.18 25.38,68.73 25.31,68.79 25.31,71.58 25.51,71.77 25.51,72.98 26.14,73.61 26.14,74.31 26.33,74.5 27.98,74.5 28.17,74.31 28.17,73.49 28.62,73.04 30.65,73.04 31.28,72.41 31.79,72.41 31.92,72.28 31.92,71.01 31.6,70.69 28.55,70.69 28.24,71.01 28.24,71.84 28.17,71.9 27.79,71.9 27.41,72.28 27.41,72.92 27.09,73.23 26.71,73.23 26.46,72.98 26.46,71.71 26.15,71.4 26.15,69.2 26.43,68.92 27.03,68.92 27.11,68.99 27.99,68.99 28.37,68.62 28.37,67.4 27.89,66.92
+5VALW on TOP: 142.51,12.5 141.29,12.5 141.24,12.55 141.24,14 141.29,14.05 142.73,14.05 142.92,13.86 142.92,12.91
+5VALW on BOTTOM: 18.31,27.02 18.31,25.91 19.72,24.5 20.13,24.5 20.62,24.02 20.62,23.01 20.43,22.81 17.69,22.81 17.44,22.56 17.44,21.67 17.25,21.48 16.42,21.48 16.36,21.54 16.36,25.48 15.98,26.82 15.7,27.48 15.28,28.08 15.28,29.29 15.47,29.48 16.49,29.48 16.68,29.29 16.68,28.66
+5VALW on BOTTOM: 191.29,28.59 195.62,28.59 196,28.97 197.15,28.97 197.59,28.53 197.59,27.51 196.31,26.24 193.66,26.24 191.89,24.47 188.13,24.47 187.74,24.85 187.74,25.04
+5VALW on VCC: outline of 92 points within 5.13,0.2 212.29,96.7
+5VALW on IN2: 109.11,12.91 112.11,12.91 112.41,12.6 112.41,11.26 112.28,11.13 108.93,11.13 108.6,11.46 108.6,12.4
+5VALW on IN2: 90.56,0.2 90.53,0.23 88.81,0.23 88.37,0.68 88.37,1.87 89.77,3.27 90.64,3.27 92.44,5.07 112.8,5.07 113.17,4.7 132.96,4.7 135.28,7.03 138.89,7.03 139.26,7.4 143.79,7.4 147.79,11.4 151.36,11.4 151.36,8.13 150.61,6.23 148.76,5.35 137.92,4.58 137.92,4.39 137.54,3.47 136.63,3.09 99.91,3.09 98.71,2.59 98.21,1.39 98.21,1 97.98,0.44 97.42,0.2
+5VALW on IN3: 90.56,0.2 90.53,0.23 88.81,0.23 88.37,0.68 88.37,1.87 89.77,3.27 90.64,3.27 92.08,4.7 97.26,4.7 97.26,5.29 97.77,5.8 99.93,5.8 101.02,4.7 132.96,4.7 135.28,7.03 143.42,7.03 147.79,11.4 151.36,11.4 151.36,8.13 150.61,6.23 148.76,5.35 137.92,4.58 137.92,4.39 137.54,3.47 136.63,3.09 99.91,3.09 98.71,2.59 98.21,1.39 98.21,1 97.98,0.44 97.42,0.2
+5VALW_5VS on BOTTOM (solid shape): 49.67,93.17 49.67,92.57 49.75,92.49 49.75,92.47 49.77,92.47 49.97,92.27 49.97,90.59 49.92,90.54 49.39,90.54 49.36,90.51 49.25,90.51 49.25,90.4 48.47,89.62 47.28,89.62 47.05,89.85 47.05,90.99 47.6,90.99 47.6,91.54 47.05,91.54 47.05,91.79 47.6,91.79 47.6,92.34 47.05,92.34 47.05,92.71 47.86,93.52 49.32,93.52
+5VALW_USB1 on TOP: 194.73,16.02 194.1,16.66 192.19,16.66 192,16.85 192,19.51 191.05,20.47 191.05,21.8 191.18,21.93 192.83,21.93 193.34,21.42 193.34,20.59 193.78,20.15 193.78,19.51 193.91,19.39 197.21,19.39 197.53,19.7 197.53,20.08 198.1,20.66 199.56,20.66 199.94,20.27 199.94,18.56 200.83,17.67 200.83,16.72 200.13,16.02
+5VALW_USB1 on BOTTOM: 197.49,20.81 198.29,21.61 198.29,22.63 196.7,24.85 196.45,25.29 196.45,25.42 196.51,25.48 198.29,26.5 198.48,26.5 198.54,26.43 200,24.15 200.51,24.15 201.53,23.13 201.53,19.07 201.21,18.75 197.65,18.75 197.49,18.91
+5VALW_USB1 on IN1: 193.08,21.47 191.94,21.47 191.68,21.22 191.68,19.83 193.27,18.24 199.11,18.24 199.56,18.69 199.56,20.15 198.99,20.72 193.83,20.72
+5VALW_USB2 on TOP: 197.21,22.75 198.35,22.75 198.8,22.31 198.8,21.04 198.61,20.85 197.97,20.85 197.4,20.27 197.4,19.77 197.21,19.58 196.19,19.58 195.37,20.4 195.37,21.35 195.62,21.61 195.62,22.56 195.81,22.75 195.81,23.26 196,23.45 196.89,23.45 197.08,23.26 197.08,22.88
+5VALW_USB2 on BOTTOM: 197.02,24.28 197.01,24.28 196.38,25.16 196.32,25.23 196.07,25.23 195.18,24.67 195.18,24.47 195.69,23.7 196.07,23.32 196.07,22.88 195.88,22.69 195.88,21.74 196,21.61 197.84,21.61 197.97,21.74 197.97,22.93
+5VALWP on TOP (solid shape): 24.63,14.62 25.33,14.62 25.33,15.13 25.83,15.13 25.83,14.62 26.58,14.62 28.44,12.76 28.44,9.92 28.3,9.79 23.63,9.79 23.35,10.07 23.35,13.1 23.09,13.35 23.09,14.34 23.37,14.62 24.13,14.62 24.13,15.13 24.63,15.13
+5VALWP on BOTTOM (solid shape): 27.38,16.35 27.38,15.73 27.38,15.66 27.38,15.6 27.38,13.19 27.61,12.97 27.61,10.02 27.39,9.8 24.11,9.8 23.73,9.42 22.2,9.42 22.08,9.54 22.08,15.98 22.49,16.4 27.34,16.4
+5VDDA_CODEC on BOTTOM (solid shape): 13.71,38.89 13.71,38.56 13.78,38.49 13.78,38.28 13.87,38.19 13.87,37.72 13.78,37.64 13.78,37.44 13.66,37.32 13.42,37.32 12.85,36.75 11.92,36.75 11.84,36.82 11.84,36.9 11.92,36.98 12.69,36.98 13.45,37.74 13.45,38.44 13.25,38.64 13.25,38.92 13.35,39.02 13.58,39.02
+5VDDA_CODEC on TOP: 13.19,38.94 13.33,39.08 13.61,39.08 13.7,39 13.72,38.85 13.74,38.7 13.74,38.47 13.76,38.46 13.76,37.71 13.02,37.19 12.79,37.19 12.6,37.38 12.6,38.84 12.71,38.94
+5VL on TOP (solid shape): 31.66,9.58 31.66,8.23 31.46,8.03 28.52,8.03 28.11,8.44 28.11,9 28.85,9.73 31.51,9.73
+5VL on IN1: 21.58,21.84 21.58,21.81 22.33,21.06 22.33,19.49 22.15,19.31 21.57,19.31 20.84,20.03 20.84,20.24 21,20.39 21,21.27 21.57,21.84
+5VL on IN1: 14.14,31.07 14.33,31.07 14.65,31.39 15.09,31.39 15.35,31.13 15.35,29.93 15.09,29.67 14.33,29.67 14.08,29.93 14.08,31.01
+5VL on IN2: 21.05,20.41 21.35,20.41 21.78,19.98 21.78,18.36 21.72,18.29 21.29,18.29 20.98,18.6 20.64,18.6 20.64,20.01
+5VL on IN2: 28.06,9.14 29.21,9.14 29.47,8.88 29.47,6.86 29.21,6.61 28.27,6.61 27.78,7.1 27.78,8.86
+5VLP on TOP (solid shape): 35.6,10.94 35.6,10.37 34.9,9.67 34.9,8.27 34.65,8.02 32.11,8.02 31.83,8.3 31.83,8.64 32.35,8.64 32.4,8.69 32.4,9.15 31.89,9.15 31.83,9.21 31.83,9.4 33.49,11.07 35.47,11.07
+5VLP on BOTTOM (solid shape): 35.51,12.67 35.51,11.14 35.61,11.04 35.61,10.31 35.51,10.2 35.51,10.2 35.48,10.14 35.18,9.84 34.06,9.84 34.03,9.87 34.03,10.42 34.06,10.46 34.83,10.46 35.14,10.77 35.14,12.68 35.28,12.82 35.36,12.82
+5VS on TOP (solid shape): 180.48,84.97 180.48,80.85 180.25,80.62 176.98,80.62 176.7,80.9 176.7,85.02 176.83,85.15 180.31,85.15
+5VS on TOP (solid shape): 152.35,105.63 152.35,104.41 152,104.06 149.99,104.06 149.81,104.23 148.44,104.23 148.36,104.31 147.4,104.31 147.3,104.41 146.08,104.41 145.98,104.31 145.34,104.31 145.23,104.42 145.23,105.97 145.42,106.16 151.82,106.16
+5VS on BOTTOM (solid shape): 148.31,15.29 148.31,14.4 147.81,13.89 146.22,13.89 145.9,14.21 145.9,15.16 146.35,15.61 148,15.61
+5VS on BOTTOM (solid shape): 185.24,16.55 185.24,15.67 184.76,15.19 184.26,15.19 183.69,15.76 183.69,16.27 184.13,16.71 185.07,16.71
+5VS on BOTTOM (solid shape): 20.96,76.32 21.34,76.32 21.42,76.24 21.42,74.08 21.16,73.83 20.4,73.83 19.85,74.38 19.85,76.35 20.11,76.6 20.68,76.6
+5VS on BOTTOM (solid shape): 47.27,94.18 47.27,93.75 47.25,93.74 47.25,93.21 46.92,92.87 46.92,92.21 47.47,92.21 47.47,91.91 46.92,91.91 46.92,91.41 47.47,91.41 47.47,91.11 46.92,91.11 46.92,89.94 46.75,89.77 44.51,89.77 42.81,91.46 42.81,92.24 44.71,94.15 46.38,94.15 46.54,94.31 47.14,94.31
+5VS on IN2 (solid shape): 20.58,77.84 20.58,75.61 20.43,75.46 19.09,75.46 19.03,75.52 19.03,77.68 19.6,78.25 20.17,78.25
+5VS on IN2 (solid shape): 186.16,16.59 186.16,15.35 185.98,15.17 184.26,15.17 184,15.43 184,16.48 184.26,16.74 186.01,16.74
+5VS on IN2 (solid shape): 48.42,93.62 48.42,91.36 48.3,91.24 47.16,91.24 46.63,91.78 44.03,91.78 43.7,92.11 43.7,93.71 44.11,94.11 47.92,94.11
+5VS on TOP: 182.73,21.74 182.73,16.46 183.18,16.02 185.08,16.02 185.4,16.34 185.4,17.61 184.12,18.88 184.12,20.85 183.37,21.61 183.37,21.74 183.3,21.8 182.79,21.8
+5VS on TOP: 186.6,55.71 186.54,55.64 186.54,53.8 186.6,53.74 191.01,53.74 191.38,54.11 191.38,59.67 191.18,59.87 189.58,59.87 189.4,59.7 189.4,55.81 189.3,55.71
+5VS on VCC: 46.44,87.39 42.02,91.82 42.02,93.34 42.01,93.35 49.48,100.82 49.48,109.5 153.97,109.5 153.97,103.9 149.24,103.9 148.17,104.98 62.23,104.98 51.73,94.48 51.73,88.58 50.55,87.39
+5VS on IN3: 189.6,58.22 190.97,58.22 191.25,58.5 191.25,75.16 183.26,83.15 177,83.15 176.7,82.85 176.7,79.38 184.1,71.98 184.1,63.72
+5VS_FAN on TOP: 188,52.98 186.35,52.98 186.29,52.91 186.29,51.07 186.35,51.01 187.94,51.01 188.07,51.14 188.07,52.91
+5VS_FAN on BOTTOM: 186.48,52.22 186.29,52.02 186.29,51.26 186.54,51.01 186.54,49.1 186.6,49.04 187.56,49.04 187.68,49.17 187.68,51.01 188,51.33 188,52.09 187.87,52.22
+5VS_KB on TOP: 182.92,22.18 183.43,22.18 183.49,22.12 183.49,21.67 183.56,21.61 183.94,21.61 184,21.67 184,23.31 184.01,23.32 184.01,23.73 183.91,23.83 183.51,23.83 183.35,23.68 183.35,23.12 183.05,22.81 182.92,22.81 182.86,22.75 182.86,22.24
+5VS_KB on BOTTOM: 183.94,22.81 184,22.75 184,21.67 183.94,21.61 182.92,21.61 181.27,19.96 180.45,19.96 180.25,20.15 180.25,21.29 181.14,22.18 181.33,22.18 181.97,22.81
+5VS_KBL on BOTTOM: 143.73,16.66 145.14,16.66 145.46,16.34 145.46,15.7 144.25,14.5 144.25,13.35 144.69,12.91 144.69,11.11 144.36,10.77 142.85,10.77 142.35,11.28 142.35,13.44 142.54,13.63 142.54,15.46
+5VS_PVDD on TOP (solid shape): 13.31,36.51 13.31,36.25 13.39,36.16 13.39,36.16 14.05,35.5 14.05,32.61 14.03,32.6 14.03,32.46 13.78,32.21 13.48,32.21 13.11,32.58 13.11,33.57 13.16,33.62 13.16,35.61 12.82,35.95 12.82,36.53 12.96,36.67 13.15,36.67
+5VS_PVDD on BOTTOM: 12.96,33.52 13.08,33.65 13.31,33.65 13.95,33.01 14.57,33.01 14.96,32.62 16.78,32.62 16.87,32.53 16.87,31.7 16.83,31.67 13.99,31.67 13.66,32 13.48,32 12.96,32.52
+12.6V_BATT+ on TOP (solid shape): 76.89,13.02 76.89,5.91 76.71,5.73 75.7,5.73 75.54,5.89 75.54,6.24 75.16,6.62 74.65,6.62 74.53,6.75 74.53,7.28 75.19,7.28 75.54,7.64 75.19,7.99 74.6,7.99 74.53,8.07 74.53,8.15 73.33,9.35 73.33,13.13 73.47,13.28 76.64,13.28
+12.6VB on TOP (solid shape): 183.39,65.93 183.39,65.47 181.31,63.39 180.74,63.39 180.59,63.54 180.59,64.01 180.01,64.58 180.01,64.97 181.94,66.9 182.43,66.9
+12.6VB on TOP (solid shape): 52.12,17.45 67.74,17.45 68.09,17.1 71.67,17.1 71.73,17.04 71.73,13.61 72.18,13.16 72.69,13.16 72.94,12.91 72.94,11 72.81,10.88 71.61,10.88 71.37,10.64 71.3,10.64 70.96,10.31 70.96,9.12 70.92,9 70.91,8.87 70.91,8.85 70.78,8.72 69.64,8.72 69.38,8.46 69.38,7.83 69.32,7.77 68.75,7.77 68.56,7.96 68.56,12.46 68.05,12.97 52.48,12.97 51.82,13.7 51.16,12.97 47.73,12.97 47.54,12.78 47.49,12.74 47.44,12.68 45.25,10.5 44.43,10.5 44.43,10.56 43.03,11.96 43.03,16.97 43.51,17.46 52.11,17.46
+12.6VB on TOP (solid shape): outline of 87 points within 178.76,82.59 187.85,97.05
+12.6VB on BOTTOM (solid shape): 69.94,103.94 57.94,103.94 57.94,107.94 69.94,107.94
+12.6VB on BOTTOM (solid shape): 161.59,44.04 161.59,41.06 161.43,40.91 159.87,40.91 159.81,40.98 159.81,44.15 159.87,44.21 161.41,44.21
+12.6VB on BOTTOM (solid shape): 158.79,97.44 158.79,96.91 156.89,95 156.1,95 154.22,96.88 154.22,98 155.06,98.84 157.39,98.84
+12.6VB on BOTTOM (solid shape): 89.39,108.32 89.39,105.12 89.23,104.97 86.13,104.97 85.4,105.71 71.71,105.71 64.28,98.28 63.38,98.28 63.31,98.21 62.83,98.21 61.98,97.36 60.39,97.36 60.16,97.59 60.16,101.5 57.93,103.74 57.93,107.97 58.46,108.5 89.21,108.5
+12.6VB on BOTTOM (solid shape): 71.5,17.09 71.5,13.38 71.47,13.34 71.47,12.73 71.04,12.3 68.9,12.3 68.59,12.62 68.3,12.91 67.34,12.91 67.34,12.9 63.77,12.9 63.61,12.74 57.1,12.74 56.54,13 55.99,12.74 52.44,12.74 51.99,13.19 48.68,13.19 48.11,13.51 47.55,13.19 44.72,13.19 44.61,13.3 44.61,14.05 44.06,14.05 44.06,14.55 44.61,14.55 44.61,15.25 44.06,15.25 44.06,15.75 44.61,15.75 44.61,16.47 45.25,17.11 71.48,17.11
+12.6VB on TOP: 180.25,76.03 185.21,76.03 186.86,74.38 186.86,58.32 186.3,57.76 186.3,54.11 183.75,51.55 181.32,51.55 180.13,50.36 175.03,50.36 174.41,49.74 174.41,48.06 173.1,46.75 170.95,46.75 169.94,47.76 169.28,47.76 168.44,46.92 166.56,46.92 166.54,46.94 166.34,46.94 165.8,46.41 165.8,42.98 164,41.18 160.34,41.18 160.09,41.43 160.09,45.62 161.15,46.69 161.15,48.34 161.74,48.93 161.74,51.06 162.63,51.95 165.93,51.95 166.67,52.68 166.67,55.57 167.25,56.15 175.52,56.15 177.61,58.25 177.61,60.08 180,62.46 180,64.98 182.1,67.08 182.1,67.64 181.46,68.28 181.46,71.33 180,72.79 180,75.77
+12.6VB on TOP: outline of 92 points within 18.27,8.54 89.35,107.35
+12.6VB on BOTTOM: 171.66,89.83 172.89,91.06 173.45,91.06 176.27,88.24 176.27,87.58 174.92,86.24 174.46,86.24 171.66,89.05
+12.6VB on IN1: 72.05,15.68 72.63,15.09 81.93,15.09 86.73,10.29 100.35,10.29 101.08,9.56 137.63,9.56 138.92,10.84 140.64,10.84 153,23.2 153,35.03 153.29,35.32 153.29,42.97 155.34,45.01 161.79,45.01 162.8,44 162.8,19.77 162.88,19.69 162.88,15.83 161.56,14.51 152.4,14.51 150.55,12.65 150.55,12.36 150.41,12.22 150.41,7.73 148.63,5.95 144.14,5.95 144.01,5.82 137.11,5.34 137.11,4.81 136.26,3.96 98.86,3.96 96,1.1 72.99,1.1 70.81,3.28 70.81,5.8 67.58,9.02 67.58,12.07 66.49,13.16 66.49,15.17 67,15.68
+12.6VB on IN1: 152.52,94.95 152.52,99.45 150.87,101.1 150.87,103.94 149.32,105.49 77.94,105.49 77.59,105.14 77.59,98.15 76.06,96.63 59.1,96.63 58,97.72 58,106.95 59.45,108.4 151.24,108.4 153.16,106.48 153.16,103.77 154.34,100.92 157.2,99.75 158.17,99.75 159.66,100.04 160.94,100.86 161.03,100.86 162.28,102.11 177.04,102.11 182.15,97.01 183.23,97.01 184.67,95.56 184.67,93.48 186.28,91.87 186.28,90.25 187,89.53 188.31,85.2 188.31,65.21 185.82,62.72 182.21,62.72 180.24,64.69 180.24,64.99 181.65,66.4 181.65,68.64 181.63,68.66 181.63,80.83 181.5,80.96 181.5,81.41 165.6,97.31 162.65,97.31 158.61,93.27 154.19,93.27
+12.6VB on IN2: 152.52,94.95 152.52,99.45 150.87,101.1 150.87,103.94 149.32,105.49 125.58,105.49 125.21,105.86 102.06,105.86 101.69,105.49 93.77,105.49 80.69,105.53 80.65,105.49 77.94,105.49 77.59,105.14 77.59,98.15 76.06,96.63 59.1,96.63 58,97.72 58,106.95 59.45,108.4 151.24,108.4 153.16,106.48 153.16,103.77 154.34,100.92 157.2,99.75 158.17,99.75 159.66,100.04 160.94,100.86 161.03,100.86 163.25,103.08 176.08,103.08 182.15,97.01 183.23,97.01 184.67,95.56 184.67,93.73 178.31,87.37 175.54,87.37 165.6,97.31 162.65,97.31 158.61,93.27 154.19,93.27
+12.6VB_1.8V on BOTTOM (solid shape): 171.68,88.24 172.15,88.24 172.33,88.07 172.33,87.89 172.18,87.74 172.13,87.74 172.03,87.64 172.03,87.53 172.94,86.62 173.04,86.62 173.3,86.87 173.47,86.87 173.68,86.67 173.68,85.98 172.91,85.22 172.37,85.22 170.86,83.71 170.84,83.71 170.01,82.87 170.01,81.07 169.78,80.84 169.78,80.51 169.22,79.95 168.96,79.95 168.16,80.76 168.16,81.27 165.97,83.46 165.97,84.51 170.2,88.74 171.19,88.74
+12.6VB_3V on TOP (solid shape): 181.59,68.47 181.59,66.9 181.33,66.64 181.23,66.64 180.93,66.95 180.85,66.95 179.89,65.98 179.89,65.91 180.19,65.6 180.19,65.5 179.54,64.85 178.76,64.85 177.59,66.02 177.05,66.02 176.25,66.82 176.25,66.92 176.89,67.56 177.57,67.56 177.6,67.58 178.54,67.58 179.73,68.78 179.73,68.9 180.38,69.55 180.51,69.55
+12.6VB_3V on BOTTOM (solid shape): 181.28,68.66 181.28,67.47 180.7,66.9 180.18,66.9 179.12,67.95 179.12,68.34 180.33,69.55 180.39,69.55
+12.6VB_5V on TOP (solid shape): 42.42,15.13 42.42,14.27 42.22,14.06 40.16,14.06 39.63,14.6 39.14,14.6 39.04,14.7 39.04,15.21 39.13,15.3 42.26,15.3
+12.6VB_5V on BOTTOM (solid shape): 36.24,17.38 36.3,17.38 36.36,17.38 44.01,17.38 44.48,16.92 44.48,15.85 43.96,15.85 43.96,15.15 44.48,15.15 44.48,14.65 43.96,14.65 43.96,13.95 44.48,13.95 44.48,13.2 44.21,12.93 43.97,12.93 43.96,12.93 43.35,12.93 43.1,13.18 43.1,13.79 42.82,14.08 42.79,14.08 42.74,14.12 42.38,14.12 42.34,14.08 40.22,14.08 39.86,14.45 39.22,14.45 38.51,15.16 37.39,15.16 37.27,15.04 36.14,15.04 36.11,15.07 35.73,15.07 35.64,15.16 35.64,17.16 35.86,17.38
+12.6VB_CPU on TOP (solid shape): 140.06,103.02 142.19,103.02 142.37,102.84 142.37,98.29 142.09,98.01 140.74,98.01 140.62,98.14 140.62,99.36 140.95,99.69 140.95,100.78 140.69,101.03 136.33,101.03 136.15,100.86 136.15,99.92 136.5,99.56 136.5,97.96 136.3,97.76 132.62,97.76 132.12,98.25 132.12,100.18 133.32,101.38 133.32,102.85 134.27,103.8 139.27,103.8
+12.6VB_CPU on BOTTOM (solid shape): outline of 105 points within 82.02,97.4 144.76,108.67
+12.6VB_CPU on TOP: 91.86,99.78 82.46,99.78 81.88,100.36 81.88,102.8 82.41,103.33 85.8,103.33 88.54,106.07 89.35,106.07 90.78,107.5 141.27,107.5 143.32,105.44 143.32,103.28 142,101.96 133.67,101.96 132.79,102.84 117.33,102.84 113.82,99.33 108.33,99.33 105.12,102.55 94.63,102.55
+12.6VB_DDR on TOP (solid shape): 159.55,40.92 159.55,39.9 159.3,39.64 156.76,39.64 156.57,39.83 156.57,40.9 156.72,41.05 159.43,41.05
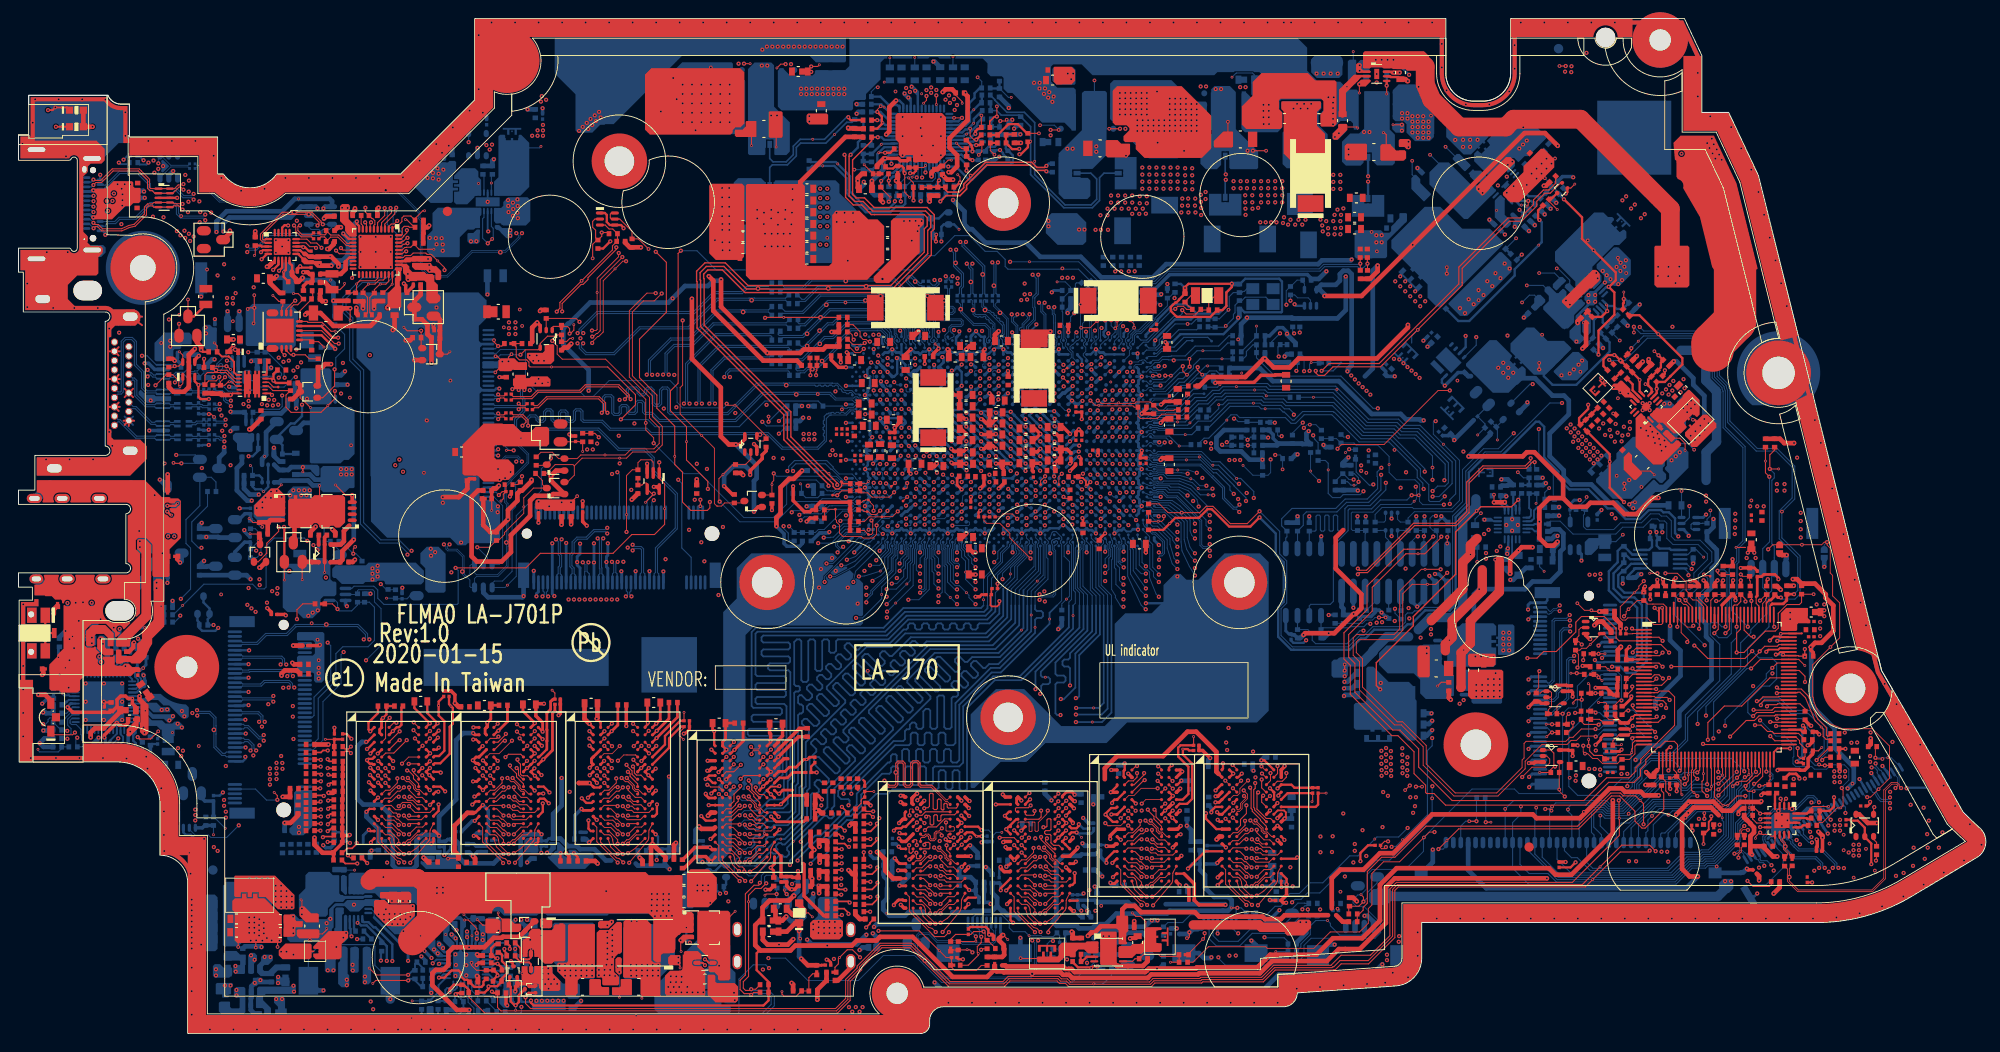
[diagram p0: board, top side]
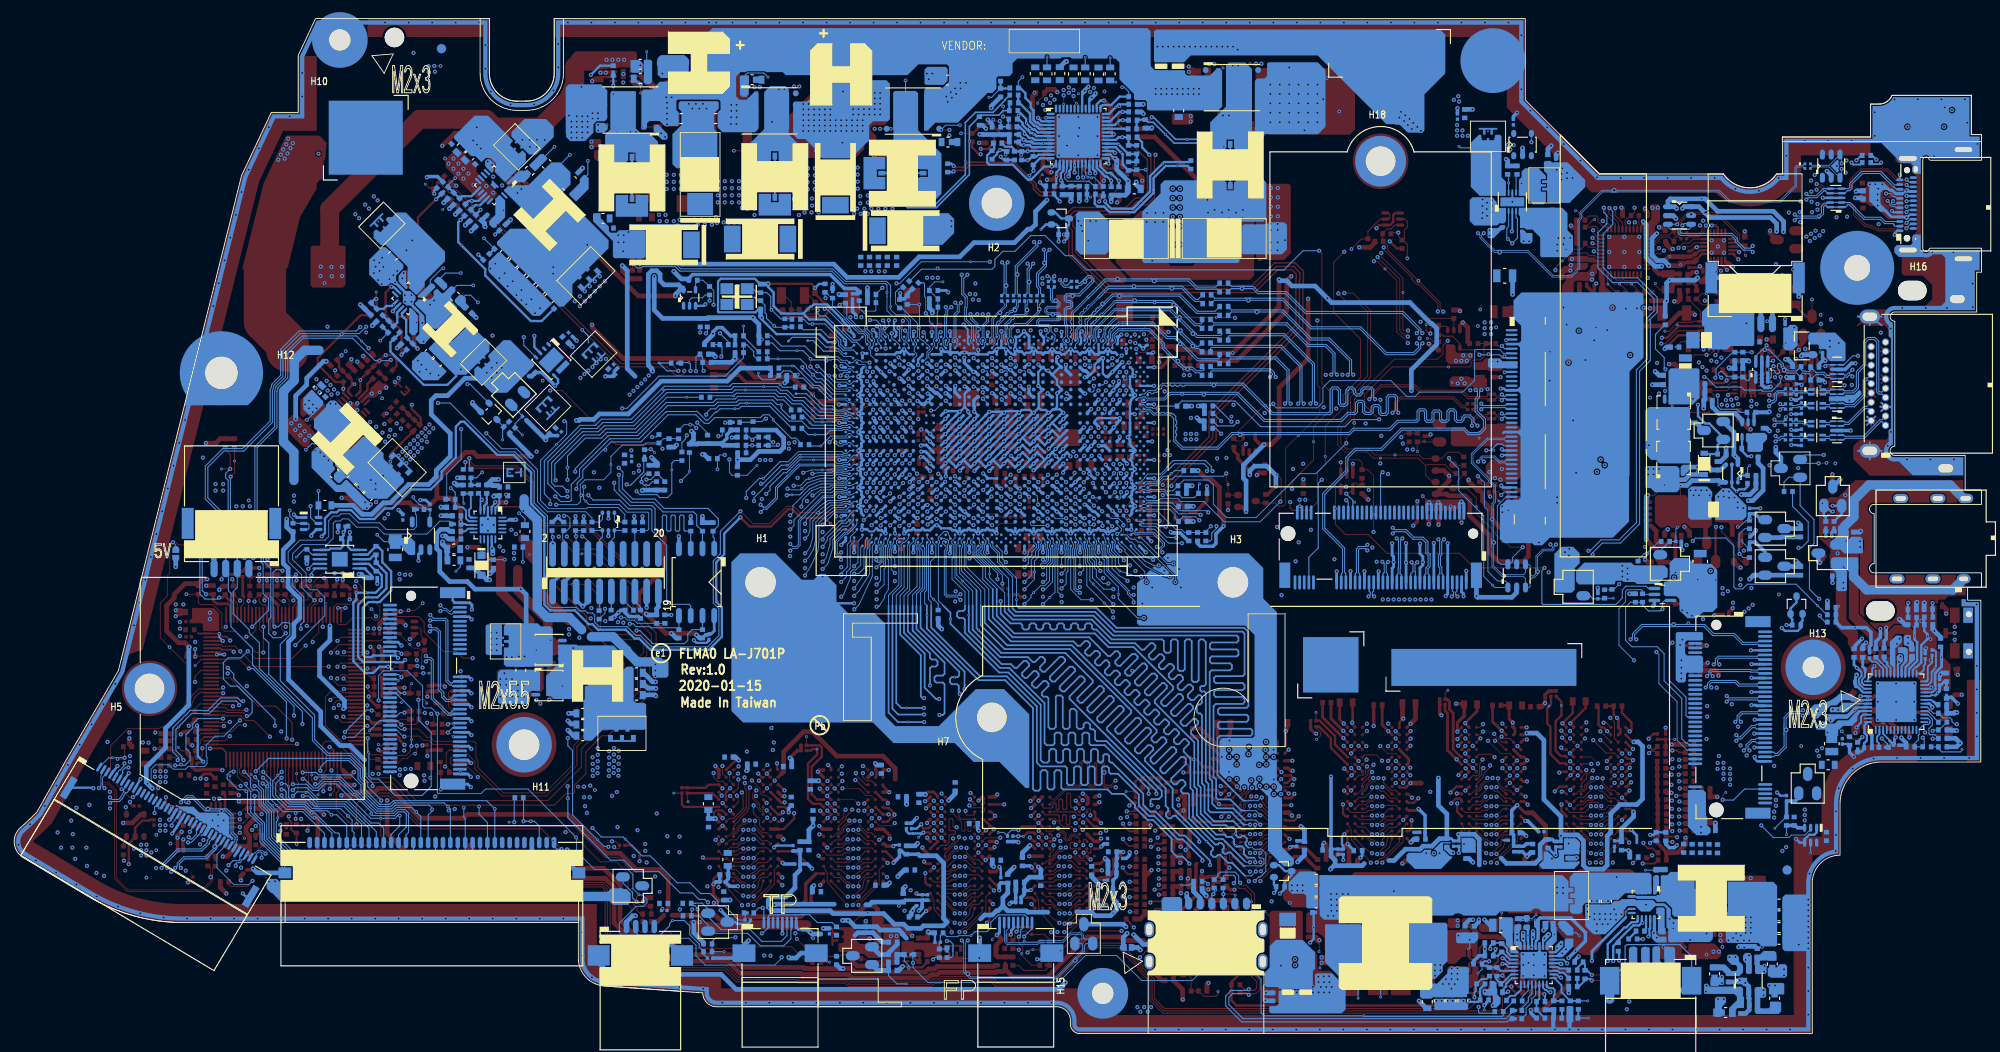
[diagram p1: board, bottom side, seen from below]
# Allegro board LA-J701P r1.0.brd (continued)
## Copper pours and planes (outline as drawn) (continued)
+12.6VB_DDR on BOTTOM (solid shape): 159.62,44.02 159.62,43.02 159.1,43.02 159.1,42.52 159.62,42.52 159.62,42.22 159.1,42.22 159.1,41.72 159.62,41.72 159.62,39.9 159.36,39.64 154.56,39.64 154.32,39.88 154.32,43.74 154.58,44 155.62,44 155.96,44.34 159.3,44.34
+12.6VB_VDDP on BOTTOM (solid shape): 164.99,96.98 164.99,96.73 163.08,94.82 162.68,94.82 162.07,94.21 161.97,94.21 161.55,94.63 161.06,94.63 160.47,94.04 160.47,93.53 160.54,93.45 160.54,93.1 159.55,92.11 159.4,92.11 157.23,94.28 157.23,95.09 157.57,95.43 157.62,95.43 157.97,95.09 158.02,95.09 158.96,96.03 158.96,96.11 158.64,96.42 158.64,96.53 161.31,99.19 162.78,99.19
+12.6VB_VDDP on TOP: 162.33,93.9 162.18,93.9 161.13,94.95 161.13,95.71 162.42,97.01 163.44,97.01 164.05,96.4 164.05,95.61
+19V_ADPIN on BOTTOM: 30.1,72.41 30.1,76.3 30.9,77.1 32.8,77.1 33.05,76.85 33.05,72.59 32.62,72.15 30.36,72.15
+19V_VIN on BOTTOM (solid shape): 33.81,71.65 33.81,68.04 33.76,67.99 31.19,67.99 30.46,68.73 30.46,71.75 30.61,71.9 33.56,71.9
+19V_VIN_P1 on BOTTOM (solid shape): 36.3,67.33 36.3,62.63 35.67,61.99 35.16,61.99 34.78,61.61 31.6,61.61 31.46,61.75 31.46,67.54 31.63,67.71 35.92,67.71
+20V_TBT_VBUS_L on TOP (solid shape): 28.81,58.13 28.81,56.03 28.68,55.9 25.72,55.9 25.46,56.16 25.46,57.1 27.29,58.92 28.02,58.92
+20V_TBT_VBUS_L on BOTTOM (solid shape): 28.78,58.13 28.78,55.57 28.71,55.49 25.76,55.49 25.38,55.87 25.38,57.08 27.22,58.92 27.99,58.92
+VCC_IO2 on TOP: 176.83,47.71 178.1,47.71 178.16,47.64 178.16,47.26 178.41,47.01 178.79,47.01 179.05,46.75 179.05,46.5 178.92,46.37 178.1,46.37 177.97,46.5 176.89,46.5 176.7,46.69 176.7,47.58
GND on TOP (solid shape): 1.57,29.34 0.07,29.34 0.07,38.23 1.57,38.23
GND on TOP (solid shape): 87.46,99.28 87.46,98.37 87.33,98.24 85.4,98.24 85.12,98.52 85.12,99.26 85.3,99.43 87.3,99.43
GND on TOP (solid shape): 114.13,104.11 114.13,102.96 113.73,102.57 112.11,102.57 111.8,102.88 111.8,104.4 111.89,104.49 113.74,104.49
GND on TOP (solid shape): 118.63,10.92 118.63,7.5 118.53,7.39 116.93,7.39 116.83,7.5 116.83,10.92 116.93,11.03 118.53,11.03
GND on TOP (solid shape): 160.38,39.13 160.38,36.34 160.19,36.15 156.89,36.15 156.57,36.47 156.57,39.2 156.7,39.32 160.19,39.32
GND on TOP (solid shape): 89.06,12.11 89.06,10.56 88.66,10.17 85.78,10.17 85.5,10.44 85.5,11.96 85.82,12.27 88.89,12.27
GND on TOP (solid shape): 150.38,96.47 150.38,95.74 150.22,95.57 149.94,95.57 149.7,95.81 149.17,95.81 149.09,95.89 149.09,96.55 149.22,96.68 150.18,96.68
GND on TOP (solid shape): 78.39,91.61 78.39,84.45 78.36,84.42 78.36,83.94 78.03,83.61 75.31,83.61 74.6,84.32 74.6,91.64 74.81,91.84 78.16,91.84
GND on TOP (solid shape): 75.26,6.24 75.26,5.61 75.42,5.45 77.35,5.45 77.73,5.07 77.73,3.59 77.49,3.35 75.31,3.35 74.43,4.23 74.43,6.27 74.5,6.34 75.16,6.34
GND on TOP (solid shape): 181.83,99.55 184.73,99.55 187.95,92.72 192.26,75.38 190.32,74.89 186.05,92.05 183.46,97.55 179.83,97.55 179.83,105.65 181.83,105.65
GND on TOP (solid shape): 75.43,16.85 75.43,14.56 74.5,13.63 72.34,13.63 72.19,13.78 72.19,17.38 72.56,17.75 74.53,17.75
GND on TOP (solid shape): 78.41,103.88 78.41,98.37 77.98,97.94 77.45,97.94 77.14,97.63 77.14,97.38 76.91,97.15 68.2,97.15 67.67,97.68 67.67,103.65 68.35,104.34 77.96,104.34
GND on TOP (solid shape): 140.69,100.68 140.69,100.04 140.26,99.61 140.26,98.11 141.13,97.25 141.13,94.66 140.82,94.35 137.39,94.35 136.66,95.09 136.66,99.64 136.4,99.89 136.4,100.7 136.45,100.75 140.62,100.75
GND on TOP (solid shape): 29.89,12.76 29.89,12.3 30.04,12.15 30.67,12.15 30.7,12.12 30.7,11.56 30.62,11.49 29.96,11.49 29.9,11.42 29.9,10.65 29.71,10.46 28.68,10.46 28.63,10.51 28.63,12.77 28.73,12.87 29.77,12.87
GND on TOP (solid shape): 97.78,87.89 97.78,87.46 97.35,87.03 97.35,84.42 94.03,81.11 92.62,81.11 92.37,81.36 92.37,81.81 94.22,83.66 94.22,87.81 94.53,88.12 97.55,88.12
GND on TOP (solid shape): 100.18,99.05 100.18,95.01 99.23,94.06 98.2,94.06 98.07,94.19 96.69,94.19 96.63,94.25 96.63,94.89 96.56,94.95 95.86,94.95 95.61,94.7 95.36,94.7 95.08,94.98 95.08,96.28 94.72,96.64 94.72,99.26 94.95,99.48 99.75,99.48
GND on TOP (solid shape): 128.83,99.21 128.83,95.65 127.82,94.63 121.62,94.63 120.68,95.57 120.68,96.26 120.6,96.33 119.54,96.33 119.36,96.51 119.36,97 119.99,97.63 119.99,97.86 119.69,98.16 118.47,98.16 118.19,98.44 118.19,101.9 118.69,102.39 125.64,102.39
GND on TOP (solid shape): 165.89,94.51 165.89,93.62 162.11,89.83 161.17,89.83 161.09,89.91 161.04,89.91 160.43,90.52 160.43,90.53 160.34,90.62 160.34,90.89 162.56,93.11 162.56,93.74 164.44,95.62 164.77,95.62
GND on TOP (solid shape): 111.7,76 111.7,75.71 111.57,75.58 111.29,75.58 111.17,75.46 111.17,74.19 111.13,74.15 110.44,74.15 110.15,73.87 110.15,73.49 110.05,73.39 109.68,73.39 109.46,73.6 108.23,73.6 108.16,73.67 108.16,74.04 108.25,74.12 108.25,76.03 108.31,76.09 111.61,76.09
GND on TOP (solid shape): 200.99,40.26 200.98,40.26 199.9,41.02 198.64,41.44 198.63,41.44 191.93,68.41 193.59,69.19 193.77,69.28
GND on TOP (solid shape): 40.06,13.94 42.3,13.94 42.38,14.01 42.67,14.01 42.82,13.86 42.82,12.75 41.65,11.59 40.28,11.59 40.27,11.61 39.81,11.61 38.4,13.02 38.4,14.31 38.52,14.43 39.56,14.43
GND on TOP (solid shape): 65.18,11.93 65.18,8.81 64.99,8.62 64.79,8.62 64.47,8.3 64.47,8.25 64.34,8.12 64.34,6.65 64.88,6.11 64.88,5.35 64.72,5.2 63.17,5.2 63.05,5.33 63.05,5.99 63,6.04 62.46,6.04 62.44,6.06 62.44,10.89 62.74,11.19 63.76,11.19 64.62,12.06 65.05,12.06
GND on TOP (solid shape): 43.45,83.27 44.28,83.27 44.3,83.28 44.36,83.29 44.42,83.28 44.44,83.27 44.56,83.27 44.57,83.23 44.75,82.98 45.06,82.96 45.09,82.97 45.66,82.4 45.66,81.56 45.54,81.43 45.1,81.43 45.05,81.48 45.05,81.93 45.04,81.94 45.04,82.08 44.9,82.22 44.31,82.22 44.02,82.51 43.71,82.51 43.68,82.53 42.82,82.53 42.51,82.85 42.51,83.22 42.57,83.29 43.44,83.29
GND on TOP (solid shape): 174.34,107.7 172.73,107.7 171.43,108.96 170.12,107.7 161.18,107.7 161.18,109.7 174.34,109.7
GND on TOP (solid shape): 154.18,107.7 51.28,107.7 51.28,100.07 42.1,90.9 28.78,90.9 25.01,89.4 21.23,90.9 19.51,90.9 19.51,94.9 11.98,94.9 11.98,96.9 21.51,96.9 21.51,92.9 22.13,92.9 25.01,91.4 27.88,92.9 41.28,92.9 49.28,100.9 49.28,109.7 154.18,109.7
GND on TOP (solid shape): 206.97,29.42 210.05,23.94 210.93,23.07 211.84,22.23 212.49,20.55 211.53,19.02 204.48,14.82 199.55,12.71 194.23,11.99 151.57,11.99 151.57,8.13 150.76,6.09 148.78,5.14 138.13,4.39 137.69,3.33 136.63,2.89 99.92,2.89 98.85,2.45 98.42,1.39 98.42,1 98.12,0.29 97.42,0 18.28,0 18.28,19.27 15.28,19.27 15.28,24.84 13.93,28.05 10.69,29.34 6.98,29.34 6.98,31.34 10.78,31.34 15.37,29.44 17.28,24.84 17.28,21.27 20.28,21.27 20.28,2 93.45,2 93.47,2.02 93.47,2.33 93.26,2.54 93.26,5.02 94.34,6.1 95.92,6.1 97.14,4.89 97.61,4.89 136.13,4.89 136.13,6.25 148.64,7.14 149.3,7.45 149.57,8.13 149.57,13.99 194.23,13.99 199.02,14.64 203.46,16.53 210.5,20.74 209.45,21.72 208.43,22.72 205.23,28.43 201.56,34.71 202.17,35.92 202.39,37.27
GND on TOP (solid shape): outline of 194 points within 0.2,0.2 212.29,109.5
GND on BOTTOM (solid shape): 44.84,2.87 44.84,1.24 44.77,1.17 44.18,1.17 44.08,1.27 44.08,2.87 44.18,2.97 44.74,2.97
GND on BOTTOM (solid shape): 114.18,104.17 114.18,102.66 114.05,102.53 112.12,102.53 111.66,102.99 111.66,104.25 111.89,104.48 113.87,104.48
GND on BOTTOM (solid shape): 143.01,105.4 143.01,103.62 142.65,103.27 140.24,103.27 139.63,103.88 139.63,105.28 140.08,105.73 142.68,105.73
GND on BOTTOM (solid shape): 161.27,83.39 161.27,82.34 156.49,77.56 155.71,77.56 154.46,78.81 154.46,78.94 159.97,84.45 160.21,84.45
GND on BOTTOM (solid shape): 169.54,72.65 169.54,71.79 168.34,70.59 166.72,70.59 165.83,71.48 165.83,71.61 167.88,73.67 168.52,73.67
GND on BOTTOM (solid shape): 115.33,87.67 115.33,85.59 114.98,85.24 112.23,85.24 110.96,86.51 110.96,88.04 111.59,88.66 114.34,88.66
GND on BOTTOM (solid shape): 21.5,14.71 21.5,9.15 21.25,8.9 18.66,8.9 18.56,9 18.56,14.69 18.89,15.02 21.2,15.02
GND on BOTTOM (solid shape): 49.83,86.86 49.83,85.56 49.62,85.36 48.74,85.36 48.49,85.6 48.49,86.43 48.57,86.5 49.1,86.5 49.48,86.89 49.8,86.89
GND on BOTTOM (solid shape): 97.83,88.55 97.83,84.7 97.32,84.19 94.62,84.19 94.28,84.54 94.28,87.81 95.3,88.84 97.54,88.84
GND on BOTTOM (solid shape): 77.18,87.44 79.68,87.44 79.86,87.27 79.86,84.32 79.76,84.22 75.54,84.22 75.02,84.74 75.02,87.38 75.3,87.66 76.97,87.66
GND on BOTTOM (solid shape): 26.46,5.82 27.55,5.82 27.63,5.75 27.63,5.42 27.52,5.31 25.9,5.31 25.7,5.11 25.44,5.11 25.31,5.24 25.31,5.97 25.37,6.03 26.25,6.03
GND on BOTTOM (solid shape): 74.84,16.32 74.84,15.47 74.49,15.12 73.18,15.12 72.94,14.88 72.94,13.65 72.81,13.52 71.77,13.52 71.64,13.65 71.64,17.12 71.63,17.14 71.63,17.18 71.96,17.51 73.66,17.51
GND on BOTTOM (solid shape): 160.25,39.01 160.25,35.77 160.13,35.64 157.12,35.64 156.94,35.82 156.94,36.78 156.68,37.04 155.79,37.04 155.69,37.14 155.69,39.05 155.97,39.32 159.93,39.32
GND on BOTTOM (solid shape): 47.87,9.83 47.87,8.94 48,8.81 49.74,8.81 49.78,8.77 49.78,5.97 49.76,5.95 47,5.95 46.95,6 46.95,8.78 47.01,8.84 47.51,8.84 47.62,8.95 47.62,9.86 47.65,9.89 47.81,9.89
GND on BOTTOM (solid shape): 77.17,104.82 77.17,103.5 77.45,103.22 78.21,103.22 78.49,102.94 78.49,97.45 78.24,97.2 71.66,97.2 70.86,98 70.86,104.13 71.7,104.97 77.02,104.97
GND on BOTTOM (solid shape): 88.56,14.51 88.56,12.63 89.04,12.15 89.04,10.53 88.69,10.18 85.83,10.18 85.58,10.43 85.58,11.94 86.34,12.71 86.34,14.52 86.57,14.75 88.32,14.75
GND on BOTTOM (solid shape): 161.05,53.78 161.05,52.58 161.08,52.56 161.08,51.72 160.98,51.62 160.67,51.62 160.54,51.75 160.54,52.41 160.77,52.63 160.77,53.12 160.82,53.17 160.82,53.8 160.87,53.85 160.98,53.85
GND on BOTTOM (solid shape): 161.46,56.93 161.46,55.91 161.51,55.86 162.14,55.86 162.22,55.78 162.22,54.13 162.14,54.06 160.49,54.06 160.44,54.11 160.44,55.81 160.49,55.86 161.13,55.86 161.23,55.96 161.23,56.93 161.28,56.98 161.41,56.98
GND on BOTTOM (solid shape): 152.94,102.23 152.94,98.8 152.92,98.79 152.92,97.24 152.89,97.2 152.89,96.89 152.44,96.45 150.84,96.45 149.93,97.36 149.93,98.27 149.6,98.6 148.72,98.6 148.44,98.87 148.44,101.95 149.08,102.58 152.58,102.58
GND on BOTTOM (solid shape): 140.74,100.55 140.74,99.97 140.44,99.66 140.44,98.16 141.41,97.2 141.41,93.95 140.97,93.52 136.99,93.52 136.54,93.96 136.54,97.39 136.88,97.73 136.88,99.48 136.4,99.97 136.4,100.63 136.53,100.75 140.54,100.75
GND on BOTTOM (solid shape): 59.11,3.68 59.11,2.56 59.08,2.53 55.59,2.53 55.44,2.67 55.44,3.19 55.49,3.23 55.68,3.41 55.69,3.68 55.76,3.75 59.03,3.75
GND on BOTTOM (solid shape): 126.85,100.73 128.22,100.73 128.36,100.59 128.36,97.16 127.88,96.68 127.07,96.68 125.66,95.27 125.66,95.04 125.2,94.58 122.1,94.58 120.31,96.37 120.31,96.39 120.15,96.55 120.15,98.16 119.71,98.6 118.14,98.6 117.91,98.82 117.91,102.66 118.29,103.04 124.54,103.04
GND on BOTTOM (solid shape): 149.98,88.58 149.98,87.8 147.83,85.65 147.83,83.97 147.66,83.79 144.49,83.79 144.31,83.97 144.31,86.7 144.44,86.82 147.16,86.82 147.43,86.56 148.1,86.56 148.26,86.72 148.26,87.2 148.8,87.74 148.8,87.78 149.15,88.13 149.15,88.6 149.22,88.66 149.89,88.66
GND on BOTTOM (solid shape): 52.25,87.05 53.26,87.05 53.36,86.95 53.36,86.09 53.23,85.96 53.21,85.96 53.11,85.97 53.02,85.96 52.7,85.96 52.07,86.58 52,86.7 51.88,86.78 51.8,86.85 51.63,86.85 51.44,87.05 51.44,87.29 51.51,87.37 51.92,87.37
GND on BOTTOM (solid shape): 53.12,5.66 53.12,4.96 53.29,4.8 53.79,4.8 53.9,4.68 53.9,4.3 53.69,4.09 52.85,4.09 52.77,4.02 52.77,3.39 52.86,3.3 52.86,3.22 52.94,3.22 52.99,3.17 52.99,2.83 52.93,2.77 52.4,2.77 51.96,3.22 51.96,3.88 52.3,4.22 52.3,4.81 52.38,4.89 52.38,5.47 52.6,5.69 53.09,5.69
GND on BOTTOM (solid shape): 180.38,62.84 180.38,61.14 177.77,58.53 176.8,58.53 174.87,56.6 174.26,56.6 173.78,57.08 173.78,57.28 173.93,57.43 174.16,57.43 176.57,59.85 176.7,59.85 177.21,59.34 177.21,59.31 177.64,59.31 178.3,59.97 178.3,60.51 177.87,60.94 177.87,61.17 178.04,61.35 178.04,61.91 177.99,61.96 177.99,62.01 179.37,63.38 179.85,63.38
GND on BOTTOM (solid shape): 135.04,50.95 135.04,34.88 133.77,33.61 119.74,33.61 117.52,31.39 110.9,31.39 108.89,29.38 106.11,29.38 103.26,26.53 102.94,26.53 102.85,26.62 102.85,34.5 105.58,37.23 108.63,37.23 112.63,33.23 117.33,33.23 118.41,34.31 118.41,44.28 119.55,45.42 122.41,45.42 123.68,46.69 123.68,48.47 124.88,49.68 125.52,49.68 126.15,49.04 127.42,49.04 130.28,51.9 134.09,51.9
GND on BOTTOM (solid shape): 174.16,83.62 174.16,82.02 172.93,80.79 172.37,80.79 172.33,80.83 172.18,80.83 171.94,81.07 171.58,81.07 171.43,80.92 171.28,80.92 170.51,80.16 170.51,79.04 170.16,78.68 169.7,78.68 168.75,77.73 168.75,75.6 169.13,75.21 169.13,75.01 168.65,74.53 168.22,74.53 167.53,75.21 167.53,75.95 168.19,76.61 168.19,77.58 169.37,78.76 169.37,79.06 169.14,79.29 169.14,79.67 169.73,80.26 170.18,80.26 171.25,81.32 171.25,81.91 170.46,82.7 170.46,83.1 172.33,84.97 172.81,84.97
GND on BOTTOM (solid shape): 39.12,14.29 39.7,14.29 40.06,13.94 42.38,13.94 42.43,13.99 42.69,13.99 42.82,13.86 42.82,12.66 42.8,12.64 42.8,11.6 41.93,10.72 40.63,10.72 38.66,12.69 38.66,13 38.65,13.01 38.65,13.34 38.21,13.78 37.39,13.78 36.78,13.18 35.82,13.18 35.23,13.76 34.29,13.76 34.04,13.51 34.04,11.47 33.85,11.28 33.85,9.97 33.75,9.87 29.34,9.87 29.02,10.19 29.02,12.53 29.43,12.93 29.76,12.93 30.33,12.36 33.28,12.36 33.56,12.64 33.56,13.43 34.19,14.06 35.13,14.06 35.49,14.42 37.34,14.42 37.44,14.52 38.89,14.52
GND on BOTTOM (solid shape): 88.41,50.53 88.5,50.56 88.58,50.49 88.86,50.28 89.16,50.46 89.43,50.46 89.49,50.39 89.52,50.31 89.47,50.23 88.17,49.54 87.96,49.54 87.89,49.64 87.78,49.7 87.72,49.77 87.74,49.87
GND on BOTTOM (solid shape): 13.73,69.04 14.69,69.04 14.71,69.01 14.79,68.91 14.92,68.87 15.4,68.87 15.47,68.88 15.53,68.9 15.54,68.91 15.66,68.91 15.67,68.9 15.73,68.88 15.8,68.87 16.28,68.87 16.31,68.87 16.35,68.88 16.44,68.87 16.48,68.78 16.48,68.41 16.44,68.33 16.35,68.32 16.31,68.32 16.28,68.33 15.8,68.33 15.73,68.32 15.67,68.29 15.66,68.28 15.54,68.28 15.53,68.29 15.47,68.32 15.4,68.33 14.92,68.33 14.81,68.3 14.72,68.21 14.72,68.21 14.66,68.15 13.88,68.15 12.96,69.07 12.96,69.35 13.18,69.57 13.21,69.57
GND on BOTTOM (solid shape): 76.85,26.57 76.94,26.51 77.24,26.32 77.55,26.48 77.63,26.53 77.71,26.5 77.78,26.44 77.87,26.41 77.9,26.4 77.9,26.31 77.77,26.31 77.07,25.61 77.07,19.77 75.35,18.05 74.53,18.05 74.27,18.31 74.27,18.88 75.54,20.15 75.54,25.42 75.57,25.49 75.65,25.52 75.82,25.57 75.96,25.7 76.04,25.75 76.13,25.7 76.68,25.64 76.62,26.19 76.57,26.28 76.62,26.37 76.7,26.43 76.76,26.51
GND on BOTTOM (solid shape): 7.36,86.12 7.36,85.49 7.64,85.21 8.18,85.21 8.2,85.22 9.13,85.22 9.41,84.94 9.41,84.41 8.93,83.93 6.32,83.93 5.73,83.9 5.23,84.22 4.31,84.22 3.9,83.81 3.9,79.08 4.35,78.64 9.37,78.64 10.47,77.83 10.03,76.53 10.03,75.38 9.78,75.14 9.78,65.42 10.03,65.18 10.03,63.93 10.47,62.63 9.37,61.82 8.92,61.82 7.43,60.33 1.97,60.33 1.97,62.28 9.37,62.28 10.06,62.86 9.6,63.64 9.57,63.65 9.57,76.81 9.6,76.82 10.06,77.6 9.37,78.18 0.72,78.18 0.72,82.48 0.2,82.48 0.2,84.68 5.48,84.68 6.1,84.34 6.55,84.88 6.55,86.34 7.14,86.34
GND on BOTTOM (solid shape): 194.97,24.72 195.02,24.72 195.05,24.68 195.05,24.61 195.02,24.54 194.95,24.51 194.79,24.45 194.7,24.32 194.65,24.25 194.39,24.21 194.22,24 194.15,23.99 193.97,23.96 193.85,23.82 193.84,23.81 193.8,23.77 193.76,23.81 193.5,23.81 193.04,23.55 192.92,23.43 192.92,23.33 192.88,23.25 192.81,23.22 192.65,23.17 192.55,23.03 192.51,22.97 192.43,22.96 192.25,22.94 192.08,22.74 192.01,22.73 191.72,22.62 191.7,22.31 192.11,21.64 192.18,21.56 192.27,21.51 192.29,21.51 192.4,21.33 192.32,21.28 192.3,21.31 192.1,21.39 191.88,21.34 191.8,21.33 191.74,21.39 191.73,21.41 191.32,22.09 191.04,22.22 190.81,22.01 190.77,21.95 190.52,21.9 190.41,21.75 190.36,21.69 190.09,21.65 189.93,21.43 189.66,21.39 189.5,21.18 189.43,21.17 189.24,21.14 189.08,20.94 189,20.93 188.95,20.94 188.89,20.94 188.85,20.93 188.82,21 188.82,21.14 189.27,21.58 189.27,23.44 189.7,23.87 191.61,23.87 191.62,23.85 192.38,23.85 192.39,23.87 192.49,23.87 193.15,24.53 194.67,24.53
GND on BOTTOM (solid shape): outline of 381 points within 36.5,52.76 52.02,80.1
GND on BOTTOM (solid shape): outline of 906 points within 0.2,0.2 212.3,109.5
GND on BOTTOM (solid shape): outline of 1064 points within 75.54,26.02 91.23,51.9
GND on IN1 (solid shape): outline of 1027 points within 0.2,0.2 212.3,109.5
GND on IN2 (solid shape): outline of 1132 points within 0.2,0.2 212.3,109.5
GND on IN3 (solid shape): 11.4,38.05 11.4,33.79 10.46,32.85 6.27,32.85 5.24,33.89 5.24,34.55 5.82,35.13 5.82,35.25 6.96,36.39 6.96,38.04 7.12,38.19 11.26,38.19
GND on IN3 (solid shape): outline of 1002 points within 0.2,60.31 15.14,86.39
GND on IN3 (solid shape): outline of 1160 points within 0.2,0.2 212.3,109.5
GND on TOP: 98.72,72.5 99,72.5 99.58,71.91 100.13,71.91 100.27,71.77 100.27,69.94 100.16,69.83 99.48,69.83 99.24,69.59 99.24,68.62 98.96,68.34 98.57,68.34 97.39,69.53 97.39,71.79 97.44,71.84 98.29,71.84 98.57,72.12 98.57,72.34
GND on TOP: 146.43,104.26 146.99,104.26 147.09,104.16 147.09,102.71 146.94,102.56 146.49,102.56 146.36,102.68 146.36,104.18
GND on TOP: 89.08,65.17 91.48,65.17 91.68,65.37 91.68,71.2 91.47,71.42 90.91,71.42 90.38,70.88 90.38,69.51 88.05,67.19 88.05,65.36 88.24,65.17 89.08,65.17
GND on TOP: outline of 227 points within 0.2,85.27 21.54,101.2
GND on TOP: 172.47,62.45 169.84,65.08 169.92,65.15 169.52,65.55 169.52,65.78 171.1,67.35 171.22,67.35 172.52,66.06 173.51,66.06 173.54,66.08 174.18,66.73 174.19,66.72 174.27,66.79 174.35,66.79 175.01,67.46 175.01,68.01 175.03,68.04 175.05,68.04 175.14,68.1 175.2,68.2 175.2,68.21 175.31,68.32 176.51,68.32 177.32,69.13 177.32,69.44 179.42,71.53 180.08,71.53 180.58,71.02 180.58,70.12 180.19,69.73 180.19,69.61 179.01,68.43 178.15,68.43 177.78,68.8 177.37,68.8 176.67,68.1 176.67,67.61 176.41,67.34 176.41,67.3 176.25,67.15 175.11,67.15 174.45,66.49 174.45,63.65 173.26,62.45
GND on TOP: 172.13,28.4 172.76,28.4 172.83,28.47 172.83,28.91 172.89,28.97 174.03,28.97 174.1,28.91 174.1,27.92 173.89,27.72 172.19,27.72 172.06,27.84 172.06,28.34
GND on TOP: 92.51,73.7 92.32,73.7 92.12,73.91 92.12,74.12 92.42,74.43 92.42,75.16 92.28,75.3 91.21,75.3 91.13,75.39 91.13,75.98 89.96,77.15 89.96,77.74 89.64,78.06 88.94,78.06 88.69,78.31 88.69,79.33 89.26,79.9 93.45,79.9 93.51,79.84 93.51,74.71
GND on TOP: 10.93,78.31 13.26,78.31 13.73,77.84 13.73,63.59 13.5,63.37 10.94,63.37 10.8,63.23 10.14,63.23 9.68,63.68 9.68,76.7 10.07,77.09 10.07,77.46
GND on TOP: 21.38,14.71 23.18,12.91 23.18,9.17 22.85,8.84 19.29,8.84 19.29,8.85 18.73,8.85 18.51,9.07 18.51,14.58 18.63,14.71
GND on TOP: 187.81,56.09 188.89,56.09 188.95,56.15 188.95,57.61 188.7,57.87 187.05,57.87 186.8,57.61 186.8,55.96 186.92,55.83 187.56,55.83
GND on TOP: 193.78,42.75 193.78,43.33 193.72,43.39 193.72,44.28 193.78,44.34 193.78,44.66 193.84,44.72 194.86,44.72 194.92,44.66 194.92,42.82 194.8,42.69 193.84,42.69
GND on TOP: 29.32,74.44 30.59,74.44 30.65,74.38 31.92,74.38 32.24,74.06 32.24,73.36 32.17,73.3 31.28,73.3 30.97,73.61 29.38,73.61 29.25,73.74 29.25,74.38
GND on TOP: 120.18,80.85 122.72,80.85 122.98,80.6 122.98,77.36 122.79,77.17 120.88,77.17 120.63,77.42 120.63,80.16 120.44,80.35 120.18,80.35 120.06,80.47 120.06,80.73
GND on TOP: 192.82,27.77 192.26,27.77 192.13,27.64 192.13,27.39 191.95,27.21 191.36,27.21 191.3,27.16 191.3,26.63 191.37,26.56 191.95,26.56 192.7,27.31 193.58,27.31 193.99,27.72 193.99,28.25 193.94,28.29 193.35,28.29
GND on TOP: 85.55,91.79 87.28,91.79 87.61,91.46 87.61,83.41 87.4,83.2 85.45,83.2 85.37,83.28 85.37,91.61
GND on TOP: 88.61,62.13 88.61,60.29 89.08,59.82 94.53,59.82 94.95,60.24 94.95,62.37 94.62,62.69 91.46,62.69 91.33,62.56 91.33,62.26 91.25,62.18 89.67,62.18 89.61,62.24 88.72,62.24
GND on TOP: 147.56,84.49 147.36,84.28 144.76,84.28 144.48,84.56 144.48,90.92 144.63,91.08 147.11,91.08 147.56,90.62
GND on BOTTOM: 145.46,62.03 146.75,62.03 146.9,61.88 146.9,61.12 146.12,60.33 144.95,60.33 144.69,60.58 144.69,61.27
GND on BOTTOM: 25.76,23.26 25.54,23.04 22.17,23.04 21.95,23.26 21.95,25.35 22.63,26.04 25.01,26.04 25.76,25.29
GND on BOTTOM: 185.72,53.23 185.65,53.17 183.68,53.17 183.62,53.23 183.62,56.98 183.81,57.17 185.59,57.17 185.72,57.04
GND on BOTTOM: outline of 214 points within 184.95,12.34 212.2,31.51 ; 1 cut-out
GND on BOTTOM: 178.9,68.37 178.78,68.37 178.45,68.7 177.84,68.7 175.68,66.54 175.67,66.54 174.41,65.28 174.41,64.98 172.96,63.53 172,63.53 170.02,65.51 170.02,66.86 174.08,70.92 179.2,70.92 179.21,70.92 179.96,70.92 180.38,70.49 180.38,69.86
GND on BOTTOM: 133.96,87.97 136,87.97 136.12,87.84 136.12,87.52 135.87,87.27 135.87,84.41 135.8,84.35 134.03,84.35 133.9,84.47 133.9,87.46 133.77,87.58 133.77,87.78
GND on BOTTOM: 85.32,99.41 87.3,99.41 87.43,99.28 87.43,98.37 87.33,98.27 85.37,98.27 85.2,98.44 85.2,99.28
GND on BOTTOM: 18.61,30.78 18.61,36.49 18.67,36.55 20.34,37.41 21.2,39.09 21.95,39.83 21.95,46.16 21.35,46.75 21.35,47.52 22.22,48.38 25.16,48.38 27.25,46.3 27.25,45.51 27.88,44.87 29.01,44.87 30.06,43.82 30.06,29.29 29.11,28.34 21.05,28.34
GND on BOTTOM: outline of 329 points within 0.2,58.36 29.51,96.67 ; 4 cut-outs
GND on BOTTOM: outline of 134 points within 51.55,46.89 89.94,70.72 ; 4 cut-outs
GND on BOTTOM: 192.32,53.17 192.26,53.23 192.26,56.91 192.45,57.1 194.29,57.1 194.54,56.85 194.54,53.23 194.48,53.17
GND on BOTTOM: 121.38,83.33 116.88,83.33 116.79,83.24 116.79,82.59 117.33,82.06 121.24,82.06 121.38,82.2
GND on BOTTOM: 162.87,92.91 162.11,92.91 161.57,92.37 161.57,92.11 161.74,91.94 161.74,91.47 160.77,90.51 160.49,90.51 160.28,90.72 159.9,90.72 159.3,90.12 159.3,88.02 159.83,87.48 159.83,87.33 159.53,87.03 159.33,87.03 158,88.35 158,89.24 159.72,90.95 159.72,91.23 159.62,91.33 159.62,91.34 159.5,91.46 159.5,91.75 160.58,92.83 160.96,92.83 161.75,93.62 161.75,93.82 161.89,93.96 161.97,93.96 162.67,94.66 163.27,94.66 165.17,96.55 165.78,96.55 166.21,96.12 166.21,94.26 164.1,92.16 163.62,92.16
GND on BOTTOM: 142.1,14.36 140.07,14.36 140.02,14.31 140.02,12.5 140.1,12.43 142.1,12.43 142.18,12.5 142.18,13.72 142.13,13.77 142.13,14.33
GND on GND1, GND2: outline of 121 points within 0.2,0.2 212.29,109.5 ; 1 cut-out
GND on VCC: 1.97,60.31 1.97,62.28 9.37,62.28 10.06,62.88 9.57,63.65 9.57,76.81 10.06,77.58 9.37,78.18 0.72,78.18 0.72,82.48 0.2,82.48 0.2,84.68 5.48,84.68 6.1,84.34 6.55,84.88 6.55,94.38 6.1,94.92 5.48,94.58 0.2,94.58 0.2,96.95 1.3,96.95 1.3,101.2 9.54,101.2 10.17,100.5 11.07,100.25 11.77,100.25 11.77,96.7 15.68,96.7 15.68,96.64 15.7,96.61 15.7,78.02 13.47,75.79 13.48,60.31
GND on VCC: 0.27,29.54 0.27,46.63 1.7,46.63 1.7,46.83 2.01,46.83 2.41,46.42 4.11,46.42 4.36,46.14 4.36,44.28 3.67,43.6 3.67,40.98 2.81,40.12 2.81,39.91 2.82,37.02 3.3,36.54 4.37,36.54 4.66,36.25 4.63,36.22 4.63,29.66 4.6,29.64 4.6,29.54
GND on VCC: 90.43,9.52 84.69,15.26 34.78,15.26 32.69,17.34 32.69,38.91 45.89,52.11 45.89,53.82 48.27,56.2 61.56,56.2 64.58,59.22 64.58,60.82 65.2,61.44 65.21,61.44 65.95,60.7 72.91,60.7 73.6,60.01 85.57,60.01 89.68,55.91 89.68,54.94 91.64,52.98 104.73,52.98 105.05,53.29 105.05,55.45 105.39,55.79 105.39,60.15 109.95,60.15 110.69,60.89 112.03,60.89 112.29,61.14 114.49,61.14 115.36,62.01 115.36,63.81 116.29,64.74 121.19,64.74 121.49,65.04 124.26,65.04 124.74,64.56 124.74,62.22 125.98,60.98 133.54,60.98 138.87,55.64 143.78,55.64 143.78,55.68 144.48,56.38 144.48,58.71 144.88,59.11 145.5,59.11 148.97,55.64 153.37,55.64 153.67,55.34 153.67,25.4 141.17,12.9 135.28,12.9 134.87,12.49 131.19,12.49 128.22,9.52
GND on IN2: 15.13,69.8 15.19,69.71 15.19,61.29 14.21,60.31 5.2,60.31 5.18,60.3 2.57,60.3 2.56,60.31 2.05,60.31 1.97,60.39 1.97,62.28 9.37,62.28 10.06,62.86 9.6,63.64 9.57,63.65 9.57,76.81 9.6,76.82 10.06,77.6 9.37,78.18 0.72,78.18 0.72,82.48 0.2,82.48 0.2,84.68 5.48,84.68 5.92,84.33 6.43,84.54 6.53,84.58 6.61,84.51 6.82,84.22 7.16,84.11 7.23,84.11 8.66,84.11 9.13,84.36 9.18,84.9 9.17,84.93 9.23,84.99 9.32,84.91 9.63,84.91 9.87,84.66 9.87,84.38 11.42,84.38 11.51,84.33 11.5,84.22 11.28,81.61 13.56,80.33 15.22,81.11 15.85,82.84 15.85,82.86 15.71,83.56 15.37,84.2 15.36,84.3 15.45,84.36 16.89,84.36 17.53,83.73 17.53,79.65 15.9,78.02 15.88,78.02 15.63,77.92 15.52,77.67 15.52,77.64 15.16,77.29 15.16,75.86 15.19,75.83 15.19,70.41 15.13,70.31 15.03,70.33 14.44,70.06 15.03,69.78
GNDA on TOP (solid shape): outline of 889 points within 1.7,36.84 17.54,59.8
GNDA on IN1 (solid shape): outline of 327 points within 1.7,36.37 12.33,49.58
GNDA on IN1 (solid shape): outline of 560 points within 1.97,41.58 17.54,59.8
GNDA on IN2 (solid shape): outline of 1104 points within 1.7,37.05 17.24,59.8
GNDA on IN3 (solid shape): outline of 1019 points within 1.7,37.05 17.54,59.8
GNDA on GND1, GND2: 4.91,36.37 4.55,36.72 4.55,36.9 4.4,37.05 3.51,37.05 3.33,37.23 3.32,39.91 4.18,40.77 4.18,43.38 4.87,44.07 4.87,46.33 4.33,46.93 2.67,46.93 2.67,48.62 3.85,48.62 4.66,49.42 5.69,49.42 6.5,48.62 11.6,48.62 13.14,49.65 12.76,51.48 12.76,55.49 13.14,57.32 11.6,58.35 2.93,58.35 2.93,59.81 13.59,59.81 13.63,59.77 13.69,59.77 15.62,57.84 17.27,57.84 17.55,57.56 17.55,53.56 16.32,52.34 16.32,48.19 15.93,47.8 15.93,43.28 14.23,41.58 14.23,38.05 13.8,37.61 13.8,37.43 13.67,37.31 13.41,37.31 12.9,36.8 11.84,36.8 11.79,36.85 11.79,38.17 11.49,38.47 6.94,38.47 6.66,38.2 6.66,36.44 6.58,36.37
GNDA on VCC: 4.91,36.37 4.55,36.72 4.55,36.9 4.4,37.05 3.51,37.05 3.33,37.23 3.32,39.91 4.18,40.77 4.18,43.38 4.87,44.07 4.87,46.33 4.33,46.93 2.62,46.93 2.22,47.34 1.7,47.34 1.7,48.44 1.69,48.44 1.69,49.58 11.6,49.58 12.29,50.18 11.8,50.96 11.8,56.01 12.29,56.79 11.6,57.39 1.97,57.39 1.97,59.81 13.59,59.81 13.63,59.77 13.69,59.77 15.62,57.84 17.27,57.84 17.55,57.56 17.55,53.56 16.32,52.34 16.32,48.19 15.93,47.8 15.93,43.28 14.23,41.58 14.23,38.05 13.8,37.61 13.8,37.43 13.67,37.31 13.41,37.31 12.9,36.8 11.84,36.8 11.79,36.85 11.79,38.17 11.49,38.47 6.94,38.47 6.66,38.2 6.66,36.44 6.58,36.37
PVCC_CPU on BOTTOM: 99.04,99.64 99.04,100.58 99.14,100.68 99.14,100.91 99.52,101.29 99.52,102.25 99.09,102.68 99.09,103.29 99.18,103.38 100,103.38 100.1,103.28 100.1,101.64 99.81,101.35 99.81,101.07 99.32,100.58 99.32,99.61 99.22,99.51 99.17,99.51
VCC_5V on BOTTOM (solid shape): 35.13,13.48 35.13,13 34.95,12.82 34.95,10.86 34.8,10.71 34.19,10.71 34.13,10.77 34.13,11.36 34.22,11.45 34.22,13.45 34.37,13.61 35,13.61
VDD_DDR on BOTTOM: 162.07,53.83 162.2,53.83 162.22,53.8 162.22,53.27 162.5,52.99 163.34,52.99 163.77,53.42 163.77,53.62 163.9,53.75 164.58,53.75 164.76,53.57 164.76,52.05 164.63,51.92 163.92,51.92 163.54,52.3 162.75,52.3 162.04,53.02 162.04,53.8
VDDIO_AUDIO on TOP: 126.5,71.11 126.71,70.9 126.71,69.04 126.56,68.89 124.7,68.89 124.53,68.71 116.96,68.71 116.64,69.03 116.64,71.04 116.72,71.11
VIN_CHG on TOP (solid shape): 59.06,11.75 59.06,7.92 58.93,7.79 57.86,7.79 57.61,7.54 56.82,7.54 56.09,8.27 55.71,8.27 55.71,8.82 55.35,9.18 54.99,8.82 54.99,8.27 54.53,8.27 54.46,8.27 54.44,8.3 54.44,9.41 54.43,9.41 54.43,9.95 55.12,10.64 55.12,10.97 55.48,11.32 56.26,11.32 56.42,11.17 57.59,11.17 57.79,11.37 57.79,11.61 57.98,11.81 59,11.81
VIN_CHG on BOTTOM (solid shape): 56.75,10.81 56.75,9.9 56.59,9.75 54.77,9.75 54.36,10.15 54.36,10.79 54.49,10.91 56.65,10.91
VIN_MUX on TOP (solid shape): 57.69,7.12 57.69,6.51 58.55,5.65 58.55,4.78 58.37,4.6 56.53,4.6 56.21,4.92 56.21,5.17 56.2,5.17 56.2,5.22 56.14,5.38 56.02,5.49 55.94,5.51 55.87,5.52 55.81,5.52 55.77,5.52 55.72,5.51 55.26,5.51 55.08,5.7 54.45,5.7 54.33,5.81 54.33,7.26 54.36,7.28 54.99,7.28 54.99,6.74 55.35,6.38 55.71,6.74 55.71,7.3 57.52,7.3
VIN_MUX on BOTTOM (solid shape): 36.3,61.18 36.3,59.05 36.19,58.94 35.73,58.94 35.28,58.5 32.91,58.5 32.62,58.79 32.62,61.05 32.9,61.33 36.15,61.33
VIN_MUX on BOTTOM (solid shape): 57.69,6.84 57.69,6.51 58.8,5.4 60.51,5.4 60.65,5.26 60.65,3.97 60.44,3.76 59.43,3.76 59.28,3.91 56,3.91 55.74,4.19 55.38,4.3 55.38,7.05 55.5,7.18 57.36,7.18
VIN_MUX on TOP: 36.49,54.62 35.75,54.62 35.54,54.83 35.54,56.85 35.67,56.98 36.49,56.98 36.74,57.23 36.74,58.5 36.55,58.69 35.16,58.69 34.64,59.21 34.64,61.09 34.79,61.24 38.8,61.24 44.75,55.3 44.75,42.6 38.73,36.58 37.94,36.58 34.84,33.48 33.8,33.48 33.26,32.95 33.26,32.64 32.82,32.2 30.79,32.2 30.37,31.78 30.37,27.54 29.76,26.93 28.87,26.93 28.59,26.65 26.61,26.65 25.72,27.54 25.72,33.56 29.94,37.78 32.88,37.78 33.39,38.28 33.39,48.95 34.43,49.99 36.08,49.99 36.8,50.7 36.8,54.31
VIN_MUX on IN1: 52.29,8.36 52.03,8.62 51.38,8.62 51.31,8.66 51.29,8.72 51.29,10.13 50.87,10.54 50.88,10.57 50.68,11.24 50.01,11.44 49.98,11.43 49.94,11.47 49.9,11.47 49.89,11.48 49.5,11.59 49.11,11.48 49.1,11.47 49.02,11.47 49,11.49 48.43,11.75 47.87,11.47 47.48,11.47 47.3,11.52 47.11,11.47 46.94,11.47 46.9,11.43 46.87,11.43 46.26,11.22 46.05,10.61 46.05,10.58 45.79,10.32 45.09,10.37 44.67,9.79 44.37,9.62 44.18,9.34 44.18,9.32 43.55,8.69 43.53,8.69 43.38,8.66 43.26,8.58 43,8.58 39.65,8.58 39.65,8.58 35.25,8.58 34.88,8.95 34.48,8.95 33.82,9.61 33.82,11.31 27.32,17.81 25.44,17.81 24.93,18.32 24.93,21.34 23.71,22.56 23.71,27.72 24.17,28.17 26,28.17 27.3,29.47 29.99,29.47 31.36,28.1 31.36,20.91 34.78,17.48 61.56,17.48 63.19,15.85 63.19,8.46 62.6,7.88 58.53,7.88 57.77,7.12 57.72,6.91 57.72,6.69 57.73,6.67 57.93,6.3 58.31,6.1 58.39,5.89 58.52,5.71 58.52,4.82 58.35,4.65 54.42,4.65 52.29,6.78 ; 1 cut-out
+APU_CORE on IN3 (solid shape): outline of 1303 points within 92.5,61.04 112.1,67.46
+APU_CORE on TOP: outline of 91 points within 90.41,60.48 144.22,94.1
+APU_CORE on BOTTOM: 118.55,95.4 120.45,95.4 122,93.85 127.11,93.85 129.95,91 129.95,89.81 130.72,89.81 130.79,89.87 130.79,92.09 131.78,93.08 144.38,93.08 145.24,92.22 145.24,89.78 145.37,89.65 146.16,89.65 146.38,89.88 146.38,92.3 147.02,92.93 147.73,92.93 148.67,91.99 148.67,87.8 148.06,87.19 148.06,86.8 147.98,86.72 147.54,86.72 147.53,86.73 147.46,86.73 147.23,86.95 144.24,86.95 140.9,83.61 134.27,83.61 134.19,83.53 116.82,83.53 116.28,84.07 116.28,84.09 115.79,84.59 115.79,88.18 116.34,88.73 116.34,88.77 117.5,89.93 117.5,91.79 118.27,92.55 119.28,92.55 119.38,92.65 119.38,93.39 119.33,93.44 118.49,93.44 118.29,93.64 118.29,95.14
+APU_CORE on VCC: 105.39,60.41 105.39,62.48 104.82,63.05 100.73,63.05 100.45,63.33 100.45,64.22 100.09,64.57 93.26,64.57 93.26,64.6 88.32,69.54 88.32,78.02 94.09,83.76 94.16,83.94 94.19,88.41 94.19,88.62 94.19,91.72 95.32,91.72 96.02,92.42 115.62,92.42 115.63,92.41 119.98,92.41 121.33,93.76 126.83,93.76 127.47,93.12 142.91,93.12 143.61,92.42 149.5,92.42 150.73,91.2 150.73,77.67 146.51,73.42 125.16,73.42 124.14,72.41 123.06,72.41 120.52,69.87 115.84,69.87 114.67,68.7 114.67,68.52 114.27,68.12 114.27,67.7 112.2,65.63 112.2,61.41 111.93,61.14 110.58,61.14 109.84,60.41
+APU_CORE on IN2: 94.78,74.76 104.88,74.76 105.52,74.12 105.52,73.04 106.15,72.41 106.15,69.42 107.8,67.77 112.12,67.77 112.32,67.57 112.32,61.37 112.18,61.23 105.52,61.23 105.26,61.49 105.26,63.45 104.94,63.77 94.97,63.77 92.43,66.31 92.43,70.69 93.77,72.03 93.77,73.74
+APU_CORE_SOC on TOP (solid shape): 84.94,91.59 84.94,83.25 85.22,82.97 87.56,82.97 87.89,83.3 87.89,88.46 88.34,88.92 90.85,88.92 91.29,88.47 91.3,88.47 91.78,88 92.78,88 93.51,87.27 93.51,83.3 91.66,81.45 79.02,81.45 78.57,81.91 78.57,91.66 78.72,91.81 84.71,91.81
+APU_CORE_SOC on BOTTOM (solid shape): outline of 520 points within 77.24,83.27 90.66,92.45
+APU_CORE_SOC on IN3 (solid shape): outline of 108 points within 97.4,62.15 101.01,64.58
+APU_CORE_SOC on TOP: 100.3,62.95 100.65,62.59 100.96,62.59 100.97,62.58 102.21,62.58 102.4,62.77 102.71,62.77 102.71,63.21 102.77,63.28 103.46,63.28 103.55,63.19 103.55,63 103.75,62.79 104.89,62.79 105.27,62.41 105.27,61.37 105.58,61.07 105.6,61.07 105.88,60.79 105.88,59.39 105.78,59.29 105.38,59.29 105.07,59.59 105.07,60.56 104.82,60.81 104.36,60.81 104.18,60.64 103.85,60.64 103.62,60.41 103.62,59.92 103.52,59.82 102.18,59.82 102.1,59.9 102.1,60.46 102.12,60.48 102.12,60.56 101.97,60.71 99.79,60.71 99.03,59.95 97.53,59.95 97.22,60.25 97.22,62.82 97.35,62.95 97.36,62.95 97.36,65.35 100.16,65.35 100.3,65.21
+APU_CORE_SOC on BOTTOM: 97.98,63.14 98.17,63.14 98.48,62.83 98.48,62.67 98.63,62.51 98.63,62.26 98.53,62.16 97.69,62.16 97.53,62.32 97.53,62.68
+APU_CORE_SOC on VCC: 91.75,53.23 89.93,55.05 89.93,56.01 85.55,60.39 85.48,60.39 85.35,60.52 73.81,60.52 73.12,61.21 66.16,61.21 65.46,61.91 65.46,63.26 66.07,63.87 66.07,83.1 74.7,91.72 93.68,91.72 93.68,88.51 93.65,84.05 87.96,78.38 87.81,78.23 87.81,78.02 87.81,69.33 92.9,64.24 93.11,64.24 93.19,64.32 99.99,64.32 100.19,64.11 100.19,63.22 100.62,62.79 104.71,62.79 105.13,62.37 105.13,55.9 104.79,55.56 104.79,53.4 104.62,53.23
+APU_CORE_SOC on IN2: 94.84,63.65 104.69,63.65 105.12,63.21 105.12,52.96 104.31,52.15 91.74,52.15 89.25,54.64 89.25,56.54 85.08,60.7 85.08,62.21 84.22,63.07 84.22,67.04 84.6,67.42 91.07,67.42
+LCDVDD on TOP (solid shape): 57.47,70.69 57.47,70.03 57.34,69.91 53.58,69.91 53.55,69.93 53.51,69.95 53.41,70.06 53.41,70.74 53.5,70.83 55.19,70.83 55.38,71.02 57.14,71.02
+LCDVDD on BOTTOM: 50.31,96.5 51.2,96.5 51.38,96.32 51.38,94.98 50.82,94.42 50.23,94.42 50,94.65 50,96.2
+LCDVDD on BOTTOM: 56.07,69.7 55.51,70.27 55.51,71.14 56.4,72.04 56.4,73.39 55.72,74.07 55.72,94.29 57.29,95.86 57.29,99.95 56.81,100.44 56.46,100.44 56.1,100.79 56.1,101.68 56.71,102.29 58.87,102.29 59.71,101.45 59.71,93.4 58.31,92 58.31,74.43 58.89,73.85 58.89,70.07 58.52,69.7
+LCDVDD on IN1: 54.37,101.83 56.53,101.83 57.29,101.07 57.29,99.32 52.72,94.75 50.46,94.75 49.6,95.61 49.6,97.06
+LCDVDD_CONN on TOP (solid shape): 53.99,72.55 54.88,72.55 54.93,72.5 54.93,71.73 53.36,71.73 53.2,71.58 51.98,71.58 51.83,71.73 51.83,72.7 52.11,72.98 53.56,72.98
+LCDVDD_CONN on BOTTOM (solid shape): 53.31,72.85 53.31,72.09 53.1,71.89 50.18,71.89 50.11,71.96 50.11,72.57 50.18,72.65 51.73,72.65 52.04,72.95 53.2,72.95
+LDO_3V3_5457V on TOP (solid shape): 44.05,84.03 44.48,84.03 44.68,83.83 44.68,83.55 44.65,83.52 44.63,83.48 44.54,83.4 44.46,83.4 44.36,83.41 44.26,83.4 43.5,83.4 43.48,83.42 42.4,83.42 42.32,83.34 41.24,83.34 41.24,83.35 40.72,83.35 40.65,83.41 40.65,83.53 40.73,83.6 41.54,83.6 41.83,83.89 42.44,83.89 42.59,84.04 44.04,84.04
+LEDVDD on TOP: 52.25,78.71 54.35,78.71 54.61,78.45 54.61,75.68 54.28,75.35 52.28,75.35 52.21,75.42 52.21,78.67
+LEDVDD on BOTTOM: 51.42,76.25 50.14,76.25 50.09,76.2 50.09,75.46 50.17,75.38 54.3,75.38 54.47,75.55 54.47,77.13 54.44,77.16 54.44,82.54 54.12,82.86 52.09,82.86 51.73,82.5 51.73,76.56
+RTC_APU on IN2: 130.7,59.26 133.54,59.26 134.71,58.1 134.71,57.33 134.48,57.1 134.1,57.1 132.9,58.31 131.91,58.31 131.46,58.76 130.55,58.76 130.55,59.11
+USBC0_VBUS on TOP (solid shape): outline of 243 points within 7.85,87.98 13.19,92.12
+USBC0_VBUS on BOTTOM (solid shape): 31.69,58.79 31.69,55.81 31.42,55.54 29.24,55.54 29.16,55.62 29.16,57.85 29.15,57.87 29.15,57.99 29.07,58.07 29.07,58.55 29.65,59.13 31.35,59.13
+USBC0_VBUS on BOTTOM (solid shape): 12.3,91.89 12.3,91.67 12.11,91.48 12.11,89.9 12.08,89.87 12.01,89.87 10.96,88.82 10.5,88.82 9.8,88.11 9.31,88.11 9.3,88.12 8.67,88.12 8.65,88.1 8.34,88.1 8.2,87.95 7.98,87.95 7.89,88.05 7.88,88.09 7.85,88.15 7.85,88.31 7.96,88.42 9.64,88.42 9.84,88.62 9.91,88.67 9.96,88.74 10.9,89.68 10.9,90.89 10.62,91.17 10.16,91.17 9.98,90.98 9.72,90.98 9.34,90.6 8.45,90.6 8.42,90.63 8.34,90.77 8.21,90.85 8.18,90.87 7.9,90.87 7.87,90.84 7.07,90.84 6.98,90.93 6.98,91.08 7.06,91.16 7.76,91.16 7.77,91.16 7.95,91.34 7.97,91.34 7.98,91.36 8.08,91.36 8.26,91.18 8.26,91.13 8.43,90.96 8.61,90.96 8.64,90.92 9.22,90.92 9.61,91.31 9.88,91.31 10.58,92.02 12.17,92.02
+USBC0_VBUS on TOP: 24.33,67.42 23.98,67.77 23.98,67.83 23.98,68.73 24.31,69.06 24.31,71.33 23.54,72.1 23.54,74.1 23.61,74.17 23.61,75.38 23.27,75.72 22.19,75.72 21.12,74.66 18.08,74.66 17.52,75.21 17.52,85.07 16.53,86.06 16.53,87.38 16.83,87.69 18.88,87.69 19.29,87.28 20.68,87.28 20.93,87.03 20.93,85.68 21.47,85.13 22.13,85.13 23.92,83.34 23.92,82.76 24.3,82.38 26.14,82.38 26.46,82.06 26.46,81.17 27.18,80.45 27.18,79.56 28.11,78.63 28.11,77.62 27.98,77.49 26.58,77.49 26.37,77.27 26.37,75.31 25.92,74.86 25.92,73.52 25.51,73.11 25.51,71.96 25.12,71.58 25.12,68.41 25.23,68.31 25.23,67.65 25,67.42
+USBC0_VBUS on IN1: 11.17,93.37 13.35,93.37 15.89,90.83 15.89,89.27 17.53,87.63 18.63,87.63 19.38,86.87 19.38,85.29 18.73,84.64 11.04,84.64 10.32,85.36 10.32,89.22 10.9,89.81 10.9,91.36 10.45,91.81 10.45,92.65
+USBC0_VBUS on IN1: 23,68.06 23.06,68.32 22.94,68.54 22.9,68.63 22.95,68.71 23.13,68.95 23.08,69.24 23.08,69.3 23.07,69.37 23.07,72.71 22.08,73.7 22.08,79.71 22.84,80.47 24.55,80.47 25.25,79.77 31.16,79.77 32.86,78.07 32.86,59.39 31.11,57.64 29.4,57.64 23.2,63.84 23.2,67.87
ADPIN on BOTTOM (solid shape): 30.2,78 30.2,76.6 29.95,76.35 29.95,74.38 29.51,73.93 27.45,73.93 27.08,74.3 24.68,74.3 24.54,74.44 24.54,78.15 24.79,78.4 24.81,78.4 25.26,78.86 29.34,78.86
BATT+ on TOP (solid shape): 73.77,8.53 73.77,7.99 73.1,7.99 72.75,7.64 73.1,7.28 73.77,7.28 73.83,7.21 73.89,7.13 73.98,7.07 74.17,6.88 74.17,4.13 74.12,4.08 70.06,4.08 69.83,4.31 69.83,6.24 70.37,6.79 71.33,6.79 71.37,6.83 71.66,6.9 71.73,7.18 71.86,7.32 71.86,8.74 71.87,8.79 71.99,8.91 73.38,8.91
BATT+ on BOTTOM (solid shape): 71.99,6.37 71.99,5.02 72.37,4.64 75.85,4.64 75.92,4.56 75.92,3.19 76.15,2.96 76.84,2.96 76.94,2.86 76.94,2.35 76.79,2.2 69.09,2.2 68.69,2.61 68.69,5.05 70.13,6.5 71.86,6.5
BGATE on TOP (solid shape): 72.98,10.58 72.98,10.23 72.93,10.18 72.2,10.18 71.76,9.74 71.53,9.74 71.28,9.99 71.28,10.18 71.79,10.69 72.87,10.69
BST1_CHG on BOTTOM (solid shape): 49.5,11.65 49.5,11.31 49.42,11.23 49.28,11.23 49.14,11.09 49.14,10.9 49.14,10.9 49.14,9.95 49.08,9.89 49.08,9.07 49.03,9.02 48.9,9.02 48.85,9.07 48.85,11.19 48.77,11.27 48.77,11.73 48.81,11.77 49.38,11.77
BST1_CPU on BOTTOM: 96.37,103.52 97.2,103.52 97.32,103.4 97.32,102.81 97.7,102.43 97.7,99.59 97.64,99.52 97.51,99.52 97.45,99.59 97.45,100.42 97.39,100.48 97.39,102.06 96.69,102.76 96.43,102.76 96.31,102.89 96.31,103.46
BST1_CPU_R on BOTTOM: 96.35,104.82 98.53,104.82 98.61,104.74 98.61,104.13 98.53,104.06 96.4,104.06 96.27,104.18 96.27,104.74
BST1_NB on BOTTOM: 93.58,103.52 94.34,103.52 94.47,103.4 94.47,102.63 95.29,101.81 95.29,101.45 96.12,100.63 96.12,99.65 96.05,99.59 95.93,99.59 95.86,99.65 95.86,100.28 95.8,100.35 95.8,100.54 95.23,101.11 94.97,101.11 93.45,102.63 93.45,103.4
BST1_NB1_R on BOTTOM: 93.7,104.74 95.79,104.74 95.89,104.64 95.89,104.16 95.79,104.06 93.73,104.06 93.6,104.18 93.6,104.64
BST2_CHG on BOTTOM (solid shape): 46.56,12.14 46.56,11.09 46.43,10.95 46.43,10.92 46.4,10.89 46.4,10.52 46.43,10.49 46.43,10.47 47.07,9.83 47.07,9.07 47.02,9.02 46.84,9.02 45.88,9.99 45.88,11.45 46.02,11.59 46.02,12.15 46.04,12.17 46.53,12.17
BST2_CHG_R on BOTTOM (solid shape): 45.63,12.15 45.63,11.45 44.78,10.59 44.13,10.59 44.08,10.64 44.08,11.35 44.9,12.17 45.61,12.17
BST2_CPU on BOTTOM: 102.7,103.36 102.7,101.33 102.42,101.05 102.42,100.14 101.15,98.87 100.18,98.87 100.1,98.95 100.1,99.05 100.18,99.13 100.94,99.13 101.73,99.92 101.73,103.26 101.91,103.43 102.62,103.43
BST2_CPU_R on BOTTOM: 100.54,104.82 102.59,104.82 102.72,104.69 102.72,104.18 102.62,104.08 100.56,104.08 100.46,104.18 100.46,104.74
BST3_CPU on TOP (solid shape): 146.04,103.03 146.04,102.88 145.51,102.34 144.77,102.34 144.62,102.49 144.62,102.7 145.02,103.1 145.96,103.1
BST3_CPU_R on BOTTOM (solid shape): 144.48,105.2 144.48,102.76 144.33,102.61 143.84,102.61 143.59,102.86 143.59,105.07 143.77,105.25 144.43,105.25
BST_1.8V on BOTTOM (solid shape): 168.9,79.71 168.9,79.63 168.8,79.53 168.14,79.53 167.33,80.35 167.3,80.35 167,80.65 167,80.7 167.39,81.09 167.52,81.09
BST_1.8V_R on BOTTOM (solid shape): 167.16,81.4 167.16,81.35 166.13,80.32 166.06,80.32 165.73,80.65 165.73,80.99 166.5,81.77 166.79,81.77
BST_3V on TOP: 175.96,66.73 176.11,66.73 176.95,65.89 177.38,65.89 177.7,65.58 177.7,65.47 177.36,65.13 177.28,65.13 175.89,66.53 175.89,66.65
BST_3V_R on TOP (solid shape): 178.96,64.39 178.96,64.32 178.59,63.95 178.49,63.95 177.65,64.78 177.65,64.92 177.97,65.23 178.12,65.23
BST_5V on BOTTOM (solid shape): 35.46,16.97 35.46,15.08 35.39,15 35.26,15 34.83,15.44 34.83,15.49 34.83,17 34.87,17.04 35.4,17.04
BST_DDR on BOTTOM: 156.91,55.4 158.51,55.4 158.75,55.16 159.21,55.16 159.33,55.05 160.16,55.05 160.19,55.02 160.19,54.89 160.16,54.87 159.27,54.87 159.21,54.81 158.58,54.81 158.39,54.62 156.89,54.62 156.81,54.69 156.81,55.3
BST_DDR_R on BOTTOM: 156.89,53.93 157.78,53.93 157.83,53.88 157.83,52.3 157.75,52.23 156.96,52.23 156.81,52.38 156.81,53.85
BST_VDDP on BOTTOM (solid shape): 159.27,91.95 159.27,91.85 159.2,91.78 159.03,91.78 158.82,91.99 157.41,91.99 156.77,92.63 156.77,92.74 157.3,93.26 157.97,93.26
CAPS_LED#_R on TOP: 182.41,22.18 182.48,22.24 182.48,23.39 182.41,23.45 181.21,23.45 181.08,23.32 181.08,22.31 181.21,22.18
CAPS_LED#_R on BOTTOM: 181.78,22.94 182.21,22.94 182.36,23.09 182.36,23.32 182.24,23.45 181.08,23.45 179.43,21.8 179.43,20.21 179.68,19.96 179.87,19.96 180.06,20.15 180.06,21.54 180.83,22.31 181.14,22.31
EXT_MIC_RING2 on TOP (solid shape): 10.29,43.25 10.29,41.9 10.24,41.85 9.68,41.85 9.63,41.9 9.63,42.78 9.22,43.19 8.4,43.19 8.23,43.02 8.23,42.03 8.06,41.85 7.45,41.85 7.29,42 7.29,43.5 7.94,44.15 9.39,44.15
EXT_MIC_RING2 on BOTTOM (solid shape): 8.41,42.92 8.41,42.06 8.26,41.9 8,41.9 7.83,41.72 7.83,41.34 7.75,41.27 7.27,41.27 7.27,42.18 7.62,42.53 7.62,43 7.7,43.07 8.26,43.07
EXT_MIC_RING2 on BOTTOM (solid shape): 9.15,40.8 9.15,38.52 9.07,38.45 9,38.45 8.92,38.52 8.92,39.79 8.49,40.23 8.49,40.81 8.68,41 8.94,41
EXT_MIC_RING2 on IN1 (solid shape): 8.28,42.94 8.28,41.45 8.64,41.09 9.05,41.09 9.27,40.86 9.27,40.02 9.1,39.85 7.75,39.85 7.04,40.56 7.04,42.94 7.29,43.2 8.03,43.2
EXT_MIC_SLEEVE on TOP (solid shape): 9.35,42.65 9.35,41.75 9.5,41.6 10.14,41.6 10.27,41.47 10.27,40.99 10.14,40.86 9.22,40.86 8.49,41.6 8.49,42.64 8.76,42.91 9.09,42.91
EXT_MIC_SLEEVE on BOTTOM (solid shape): 9.9,42.35 9.9,41.85 9.9,39.93 9.53,39.56 9.53,38.5 9.48,38.45 9.38,38.45 9.3,38.52 9.3,41.6 8.61,42.28 8.61,42.89 8.74,43.02 9.22,43.02
HG1_CHG on TOP (solid shape): 57.66,12.35 57.66,11.58 57.46,11.37 56.49,11.37 56.32,11.54 56.32,12.33 56.44,12.45 57.57,12.45
HG1_CHG on BOTTOM (solid shape): 49.75,10.97 49.75,10.1 49.48,9.82 49.48,9.07 49.43,9.02 49.3,9.02 49.25,9.07 49.25,9.88 49.27,9.89 49.27,10.85 49.27,10.85 49.27,10.96 49.39,11.09 49.63,11.09
HG1_CHG on IN3 (solid shape): 56.9,12.31 56.9,11.28 56.75,11.14 55.97,11.14 55.88,11.23 55.88,12.3 56.03,12.45 56.76,12.45
HG1_CHG on IN3 (solid shape): 49.97,11.6 49.97,11.22 49.76,11.01 49.76,10.97 49.75,10.97 49.75,10.1 49.6,9.94 49.21,9.94 48.97,10.18 48.97,11.34 49.35,11.71 49.85,11.71
HG2_CHG on TOP (solid shape): 71.5,8.43 71.5,7.46 71.42,7.37 70.36,7.37 70.18,7.56 70.18,8.23 70.43,8.48 71.45,8.48
HG2_CHG on BOTTOM (solid shape): 46.03,9.46 46.03,9.01 46.14,8.89 46.7,8.89 46.75,8.84 46.75,8.72 46.7,8.67 45.91,8.67 45.17,9.41 45.17,9.98 45.23,10.03 45.46,10.03
HG2_CHG on IN2 (solid shape): 45.93,12.06 45.93,10.1 46.31,9.72 46.31,9.39 45.89,8.97 45.69,8.97 45.11,9.54 45.11,12.06 45.32,12.26 45.72,12.26
HG2_CHG on IN2 (solid shape): 71.63,8.63 71.63,7.54 71.45,7.36 70.17,7.36 69.38,8.15 69.38,8.72 69.51,8.84 71.42,8.84
HGNDA on TOP (solid shape): 14.33,52.82 14.33,44.87 12.12,42.66 12.12,42.41 12.04,42.33 12.04,41.87 11.97,41.8 10.62,41.8 10.54,41.88 10.54,42.64 13.26,45.36 13.26,50.22 13.26,50.28 13.26,50.35 13.26,51.94 12.81,52.39 12.81,53.26 12.98,53.43 13.72,53.43
HGNDA on BOTTOM (solid shape): 15.53,54.82 15.52,54.81 15.52,53.84 16,53.36 16.05,53.36 16.34,53.07 16.34,52.57 16.06,52.3 15.24,52.3 14.82,51.88 12.93,51.88 12.81,52 12.81,53.43 13.06,53.69 14.07,53.69 14.64,53.12 14.73,53.12 14.74,53.13 14.74,53.15 14.33,53.56 14.33,54.35 14.86,54.88 15.47,54.88
HGNDB on TOP (solid shape): 15.74,48.85 15.74,48.8 15.72,48.7 15.74,48.6 15.74,45.29 15.75,45.28 15.75,44.01 14.44,42.7 14.44,42.12 14.05,41.41 13.79,40.65 13.12,39.98 12.21,39.98 12.06,40.14 11.34,40.14 11.19,39.98 10.62,39.98 10.52,40.09 10.52,41.45 10.57,41.5 11.03,41.5 11.13,41.39 11.13,40.87 11.2,40.8 12.21,40.8 12.81,41.39 12.81,42.12 12.81,42.14 12.99,42.32 13.01,42.32 13.16,42.41 13.25,42.57 13.25,42.58 13.34,42.66 13.34,42.87 13.31,42.89 13.31,43.43 14.51,44.62 14.51,44.69 14.58,44.77 14.58,48.86 14.86,49.14 15.45,49.14
HGNDB on BOTTOM (solid shape): 16.28,51.22 16.28,50.39 15.78,49.88 15.68,49.78 15.68,47.98 15.51,47.81 14.65,47.81 14.53,47.92 14.53,49.95 15.01,50.44 15.01,50.49 14.99,50.51 14.91,50.51 14.35,49.95 13.5,49.95 13.3,50.15 13.3,51.39 13.37,51.46 16.05,51.46
LDO_1.8V on BOTTOM (solid shape): 169.84,78.34 169.84,75.77 169.54,75.47 169.26,75.47 168.9,75.82 168.9,77.63 169.71,78.44 169.74,78.44
LDO_VDDP on BOTTOM (solid shape): 160.53,90.21 160.53,88.49 161.19,87.83 161.19,87.44 160.84,87.09 160.68,87.09 160.32,87.46 160.21,87.46 159.46,88.21 159.46,90.01 160.05,90.59 160.15,90.59
LG1_CHG on TOP (solid shape): 64.33,12.2 64.33,11.97 63.72,11.36 62.77,11.36 62.59,11.54 62.59,12 62.77,12.18 63.79,12.18 63.9,12.29 64.23,12.29
LG1_CHG on BOTTOM (solid shape): 48.68,11.12 48.68,9.89 48.68,9.07 48.63,9.02 48.5,9.02 48.45,9.07 48.45,10.08 48.21,10.32 48.21,11.12 48.34,11.25 48.55,11.25
LG1_CHG on IN3 (solid shape): 64.3,12.21 64.3,11.83 64.16,11.68 64.05,11.68 63.8,11.43 62.58,11.43 61.81,12.21 61.81,12.46 61.92,12.57 63.93,12.57
LG1_CHG on IN3 (solid shape): 49.33,12.41 49.33,11.96 48.68,11.3 48.68,11.12 48.68,10.21 48.6,10.13 48.03,10.13 47.8,10.36 47.8,11.57 48.85,12.62 49.13,12.62
LG1_CPU on BOTTOM: 98.66,99.61 98.66,100.68 98.73,100.75 98.73,101.01 98.91,101.19 98.91,102.08 99.06,102.23 99.29,102.23 99.39,102.13 99.39,101.34 99.01,100.96 99.01,100.75 98.91,100.65 98.91,99.61 98.83,99.54 98.73,99.54
LG1_CPU on BOTTOM: 128.5,102.48 128.5,101.47 128.27,101.24 127.38,101.24 127.23,101.39 127.23,102.38 127.46,102.61 128.38,102.61
LG1_CPU on IN3: 126.47,103.5 127.56,103.5 128.5,102.56 128.5,102.23 128.32,102.05 127.38,102.05 126.34,103.09 126.34,103.37
LG1_CPU on IN3: 99.93,102.1 99.7,102.1 99.37,101.77 99.37,101.26 99.27,101.16 99.06,101.16 98.96,101.26 98.96,102.23 99.24,102.51 99.24,102.81 100.07,103.64 100.55,103.64 100.88,103.31 100.88,103.05
LG1_NB on BOTTOM (solid shape): 97.27,101.85 97.27,99.6 97.2,99.52 97.15,99.52 97.03,99.64 97.03,100.37 97.01,100.4 97.01,101.39 96.65,101.75 96.65,101.92 96.45,102.13 96.37,102.13 96.27,102.23 96.27,102.46 96.38,102.57 96.55,102.57
LG1_NB on BOTTOM: 77.65,105.1 78.44,105.1 78.59,104.95 78.59,104.08 78.29,103.78 77.7,103.78 77.5,103.98 77.5,104.95
LG1_NB on IN3: 96.29,103.88 96.6,103.88 97.08,103.4 97.08,101.8 96.93,101.64 96.8,101.64 96.63,101.81 96.63,101.99 96.22,102.41 96.22,103.8
LG1_NB on IN3: 78.62,106.06 79.15,106.06 79.35,105.86 79.35,105.53 78.44,104.62 77.65,104.62 77.58,104.69 77.58,105.02
LG2_CHG on TOP (solid shape): 65.15,8.11 65.15,6.5 65.03,6.37 64.8,6.37 64.47,6.7 64.47,7.99 64.47,8.02 64.7,8.25 65.01,8.25
LG2_CHG on BOTTOM (solid shape): 47.47,10.38 47.47,9.05 47.44,9.02 47.29,9.02 47.26,9.05 47.26,9.83 46.52,10.57 46.52,10.83 46.67,10.98 46.86,10.98
LG2_CHG on IN3 (solid shape): 46.9,11.92 46.9,10.94 47.47,10.38 47.47,10.15 47.12,9.8 46.75,9.8 46.09,10.46 46.09,11.64 46.51,12.06 46.76,12.06
LG2_CHG on IN3 (solid shape): 65.28,8.8 65.36,8.8 65.49,8.67 65.49,6.61 65.26,6.38 64.76,6.38 64.7,6.47 64.63,6.52 64.39,6.76 64.39,7.24 64.44,7.39 64.43,7.54 64.43,8.07 64.49,8.23 64.47,8.4 64.95,8.88 65.2,8.88
LG2_CPU on BOTTOM: 100.03,100.53 99.83,100.53 99.7,100.4 99.7,99.61 99.62,99.54 99.52,99.54 99.44,99.61 99.44,100.55 100.51,101.62 100.69,101.62 100.77,101.54 100.77,101.26
LG2_CPU on BOTTOM: 118.16,98.21 119.59,98.21 119.71,98.09 119.71,97.58 119.43,97.3 118.16,97.3 117.91,97.55 117.91,97.96
LG2_CPU on IN3: 100.21,100.68 100.03,100.68 99.88,100.83 99.88,101.21 100.17,101.5 100.17,101.99 101.01,102.83 101.23,102.83 101.43,102.63 101.43,101.9
LG2_CPU on IN3: 118.82,98.27 119.59,98.27 119.76,98.09 119.76,97.43 119.54,97.2 117.91,97.2 117.61,97.5 117.61,99.26 117.72,99.37 118.53,99.37 118.61,99.29 118.61,98.48
LG3_CPU on BOTTOM (solid shape): 149.71,98.29 149.71,97.52 149.55,97.35 148.77,97.35 148.39,97.73 148.39,98.06 148.76,98.43 149.57,98.43
LG3_CPU on IN3 (solid shape): 149.33,104.21 149.33,102.96 149.27,102.9 148.4,102.9 148.3,103 148.3,104.21 148.43,104.34 149.2,104.34
LG3_CPU on IN3 (solid shape): 149.06,98.84 149.06,98.51 149.13,98.44 149.5,98.44 149.7,98.24 149.7,97.52 149.52,97.34 148.78,97.34 148.3,97.82 148.3,98.66 148.5,98.86 149.04,98.86
LG_DDR on TOP: 159.71,52.94 160.16,52.94 160.47,52.63 160.47,50.73 160.29,50.55 159.63,50.55 159.43,50.75 159.43,52.66
LG_DDR on TOP: 155.59,37.95 156.18,37.95 156.38,37.75 156.38,35.67 156.12,35.41 155.46,35.41 155.24,35.64 155.24,37.6
LG_DDR on BOTTOM: 160.57,53.85 160.62,53.8 160.62,52.71 159.83,51.92 159.55,51.92 159.43,52.05 159.43,52.58 160.11,53.27 160.11,53.65 160.32,53.85
LG_DDR on BOTTOM: 155.54,36.84 156.3,36.84 156.32,36.82 156.52,36.82 156.66,36.68 156.66,35.84 156.25,35.44 155.57,35.44 155.36,35.64 155.36,36.66
LX1_CHG on TOP (solid shape): 62.26,11.78 62.26,6.1 62.16,6 60.67,6 60.4,5.73 60.4,4.36 60.18,4.13 59.1,4.13 59.06,4.18 59.06,5.86 58.19,6.72 58.19,7.56 58.3,7.66 59.21,7.66 59.35,7.8 59.35,11.69 59.48,11.82 62.22,11.82
LX1_CHG on BOTTOM (solid shape): 62.23,11.78 62.23,6.01 62.13,5.91 59.01,5.91 58.2,6.72 58.2,7.29 57.69,7.81 57.69,11.78 57.89,11.98 62.03,11.98
LX1_CHG on BOTTOM (solid shape): 50.48,11.61 50.48,9.67 49.83,9.02 49.7,9.02 49.65,9.07 49.65,9.81 49.88,10.04 49.88,11.02 49.84,11.06 49.84,11.11 49.71,11.24 49.71,11.75 49.77,11.81 50.28,11.81
LX1_CHG on IN3 (solid shape): 59.26,7.62 59.26,7.26 59.19,7.18 58.29,7.18 57.65,7.83 57.65,8.3 57.81,8.46 58.42,8.46
LX1_CHG on IN3 (solid shape): 50.55,10.69 51.49,10.69 51.7,10.48 51.7,9.95 51.65,9.9 50.47,9.9 50.39,9.82 50.02,9.82 49.91,9.94 49.91,10.81 50.05,10.95 50.29,10.95
LX1_CPU on BOTTOM (solid shape): 131.47,101.77 131.47,97.76 133.9,95.33 133.9,93.55 133.76,93.41 130.93,93.41 130.79,93.55 130.79,95.33 130.72,95.4 129.96,95.4 129.9,95.33 129.9,93.87 129.44,93.41 128.25,93.41 127.66,94 127.66,96 128.83,97.17 128.83,102.05 129.19,102.41 130.84,102.41
LX1_CPU on TOP: 132.48,97.47 133.77,97.47 133.82,97.41 133.82,95.26 133.72,95.15 132.48,95.15 132.27,95.36 132.27,97.26
